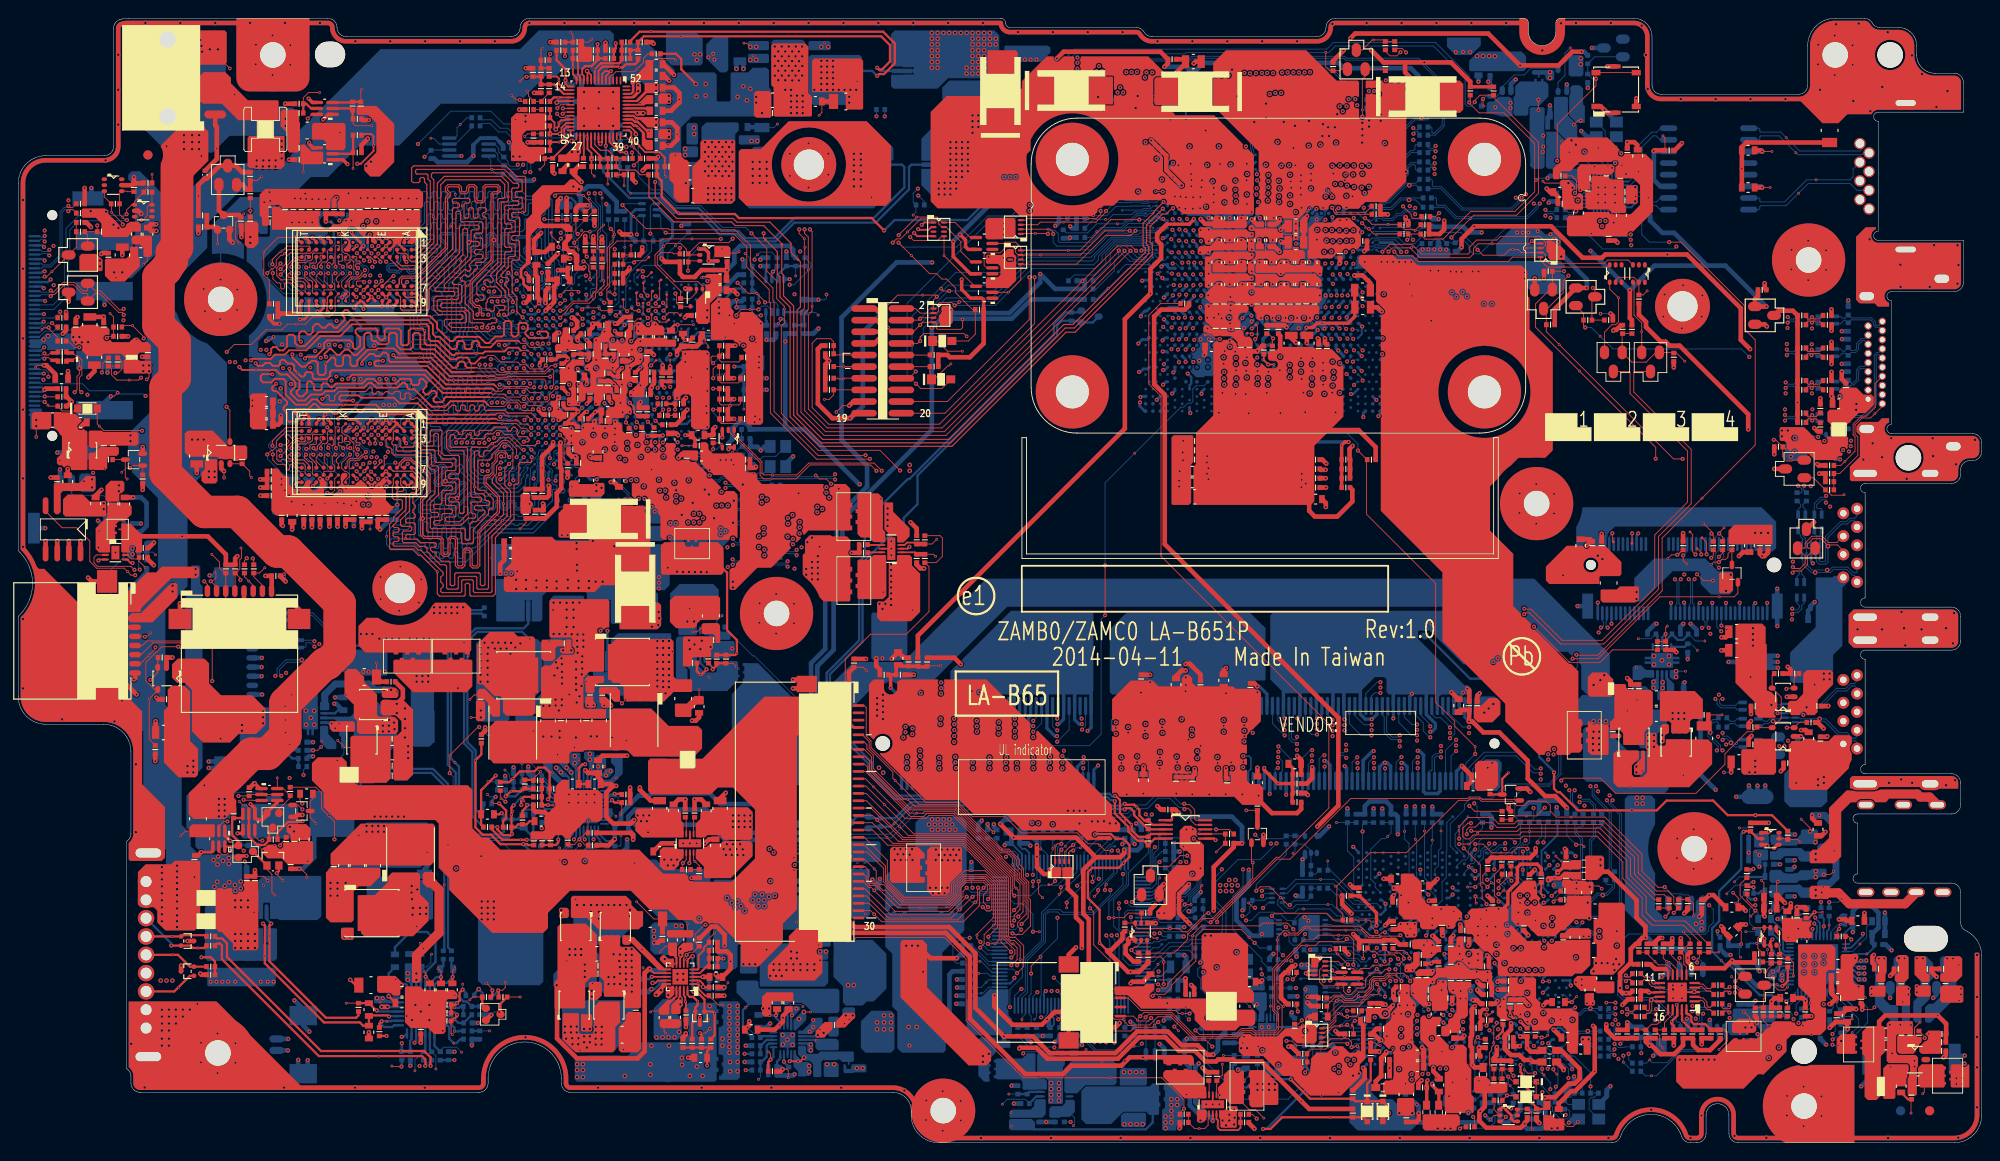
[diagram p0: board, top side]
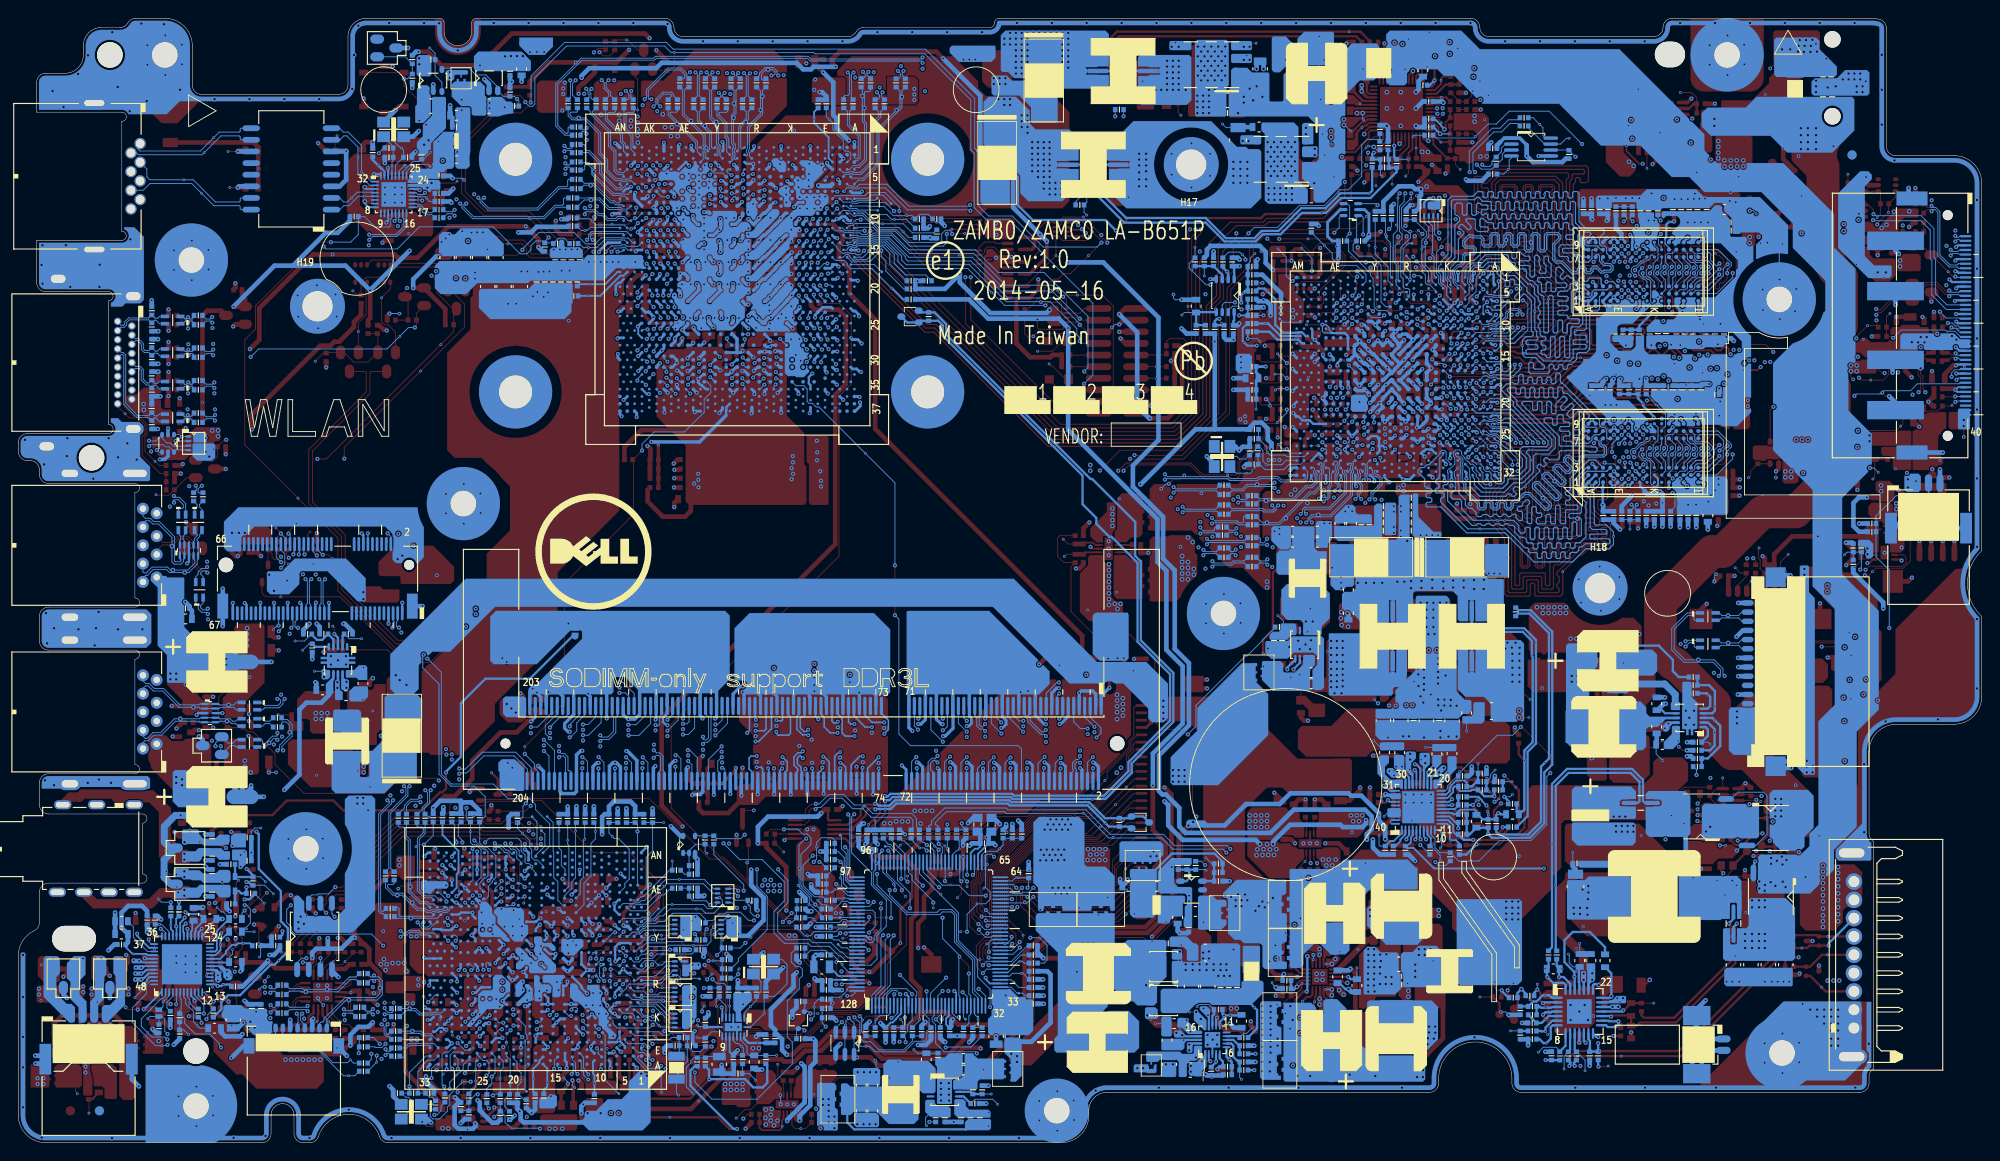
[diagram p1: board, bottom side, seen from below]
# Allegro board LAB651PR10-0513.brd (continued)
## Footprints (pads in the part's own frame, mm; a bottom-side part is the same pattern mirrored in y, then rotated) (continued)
ALLTO_C144LS-109A9-L_9P-T
  round 1.803 hole 1.194: 1(0,0) 2(2,0) 3(4,0) 4(6,0) 5(8,0) 6(10,0) 7(12,0) 8(14,0) 9(16,0)
  oval 1.6x3.404 hole 0.991x2.794: 10(19.125,0.25) 11(-3.125,0.25)
AO4407AL_SO8
  oval 0.635x1.854 smd: 1(0,0) 2(1.27,0) 3(2.54,0) 4(3.81,0) 5(3.81,5.165) 6(2.54,5.165) 7(1.27,5.165) 8(0,5.165)
AOZ1336_DFN8_2X2
  oval 0.254x0.787 smd: 1(0,0) 2(0.5,0) 3(1,0) 4(1.5,0) 5(1.5,2.2) 6(1,2.2) 7(0.5,2.2) 8(0,2.2)
  rect 1.499x0.889 smd: 9(0.75,1.1)
APL3512ABI-TRG_SOT23-5
  oval 0.61x1.041 smd: 1(0,0) 2(0.95,0) 3(1.9,0) 4(1.9,2.7) 5(0,2.7)
AZ5125-02SPR7G_SOT23-3
  oval 1.016x1.524 smd: 1(0,0) 2(0.965,2.083) 3(-0.965,2.083)
BAT54C-7-F_SOT23-3
  oval 1.016x1.524 smd: 1(0,0) 2(0.965,2.083) 3(-0.965,2.083)
BELLW_80001-1021_204P
  round 1.092 hole 1.092 unplated: (-65.05,-4.1)
  round 1.6 hole 1.6 unplated: (1.75,-4.1)
  oval 0.356x2.007 smd: 1(0,0) 2(-0.3,-8.2) 3(-0.6,0) 4(-0.9,-8.2) 5(-1.2,0) 6(-1.5,-8.2) 7(-1.8,0) 8(-2.1,-8.2) 9(-2.4,0) 10(-2.7,-8.2) 11(-3,0) 12(-3.3,-8.2) 13(-3.6,0) 14(-3.9,-8.2) 15(-4.2,0) 16(-4.5,-8.2) 17(-4.8,0) 18(-5.1,-8.2) 19(-5.4,0) 20(-5.7,-8.2) 21(-6,0) 22(-6.3,-8.2) 23(-6.6,0) 24(-6.9,-8.2) 25(-7.2,0) 26(-7.5,-8.2) 27(-7.8,0) 28(-8.1,-8.2) 29(-8.4,0) 30(-8.7,-8.2) 31(-9,0) 32(-9.3,-8.2) 33(-9.6,0) 34(-9.9,-8.2) 35(-10.2,0) 36(-10.5,-8.2) 37(-10.8,0) 38(-11.1,-8.2) 39(-11.4,0) 40(-11.7,-8.2) 41(-12,0) 42(-12.3,-8.2) 43(-12.6,0) 44(-12.9,-8.2) 45(-13.2,0) 46(-13.5,-8.2) 47(-13.8,0) 48(-14.1,-8.2) 49(-14.4,0) 50(-14.7,-8.2) 51(-15,0) 52(-15.3,-8.2) 53(-15.6,0) 54(-15.9,-8.2) 55(-16.2,0) 56(-16.5,-8.2) 57(-16.8,0) 58(-17.1,-8.2) 59(-17.4,0) 60(-17.7,-8.2) 61(-18,0) 62(-18.3,-8.2) 63(-18.6,0) 64(-18.9,-8.2) 65(-19.2,0) 66(-19.5,-8.2) 67(-19.8,0) 68(-20.1,-8.2) 69(-20.4,0) 70(-20.7,-8.2) 71(-21,0) 72(-21.3,-8.2) 73(-24,0) 74(-24.3,-8.2) 75(-24.6,0) 76(-24.9,-8.2) 77(-25.2,0) 78(-25.5,-8.2) 79(-25.8,0) 80(-26.1,-8.2) 81(-26.4,0) 82(-26.7,-8.2) 83(-27,0) 84(-27.3,-8.2) 85(-27.6,0) 86(-27.9,-8.2) 87(-28.2,0) 88(-28.5,-8.2) 89(-28.8,0) 90(-29.1,-8.2) 91(-29.4,0) 92(-29.7,-8.2) 93(-30,0) 94(-30.3,-8.2) 95(-30.6,0) 96(-30.9,-8.2) 97(-31.2,0) 98(-31.5,-8.2) 99(-31.8,0) 100(-32.1,-8.2) 101(-32.4,0) 102(-32.7,-8.2) 103(-33,0) 104(-33.3,-8.2) 105(-33.6,0) 106(-33.9,-8.2) 107(-34.2,0) 108(-34.5,-8.2) 109(-34.8,0) 110(-35.1,-8.2) 111(-35.4,0) 112(-35.7,-8.2) 113(-36,0) 114(-36.3,-8.2) 115(-36.6,0) 116(-36.9,-8.2) 117(-37.2,0) 118(-37.5,-8.2) 119(-37.8,0) 120(-38.1,-8.2) 121(-38.4,0) 122(-38.7,-8.2) 123(-39,0) 124(-39.3,-8.2) 125(-39.6,0) 126(-39.9,-8.2) 127(-40.2,0) 128(-40.5,-8.2) 129(-40.8,0) 130(-41.1,-8.2) 131(-41.4,0) 132(-41.7,-8.2) 133(-42,0) 134(-42.3,-8.2) 135(-42.6,0) 136(-42.9,-8.2) 137(-43.2,0) 138(-43.5,-8.2) 139(-43.8,0) 140(-44.1,-8.2) 141(-44.4,0) 142(-44.7,-8.2) 143(-45,0) 144(-45.3,-8.2) 145(-45.6,0) 146(-45.9,-8.2) 147(-46.2,0) 148(-46.5,-8.2) 149(-46.8,0) 150(-47.1,-8.2) 151(-47.4,0) 152(-47.7,-8.2) 153(-48,0) 154(-48.3,-8.2) 155(-48.6,0) 156(-48.9,-8.2) 157(-49.2,0) 158(-49.5,-8.2) 159(-49.8,0) 160(-50.1,-8.2) 161(-50.4,0) 162(-50.7,-8.2) 163(-51,0) 164(-51.3,-8.2) 165(-51.6,0) 166(-51.9,-8.2) 167(-52.2,0) 168(-52.5,-8.2) 169(-52.8,0) 170(-53.1,-8.2) 171(-53.4,0) 172(-53.7,-8.2) 173(-54,0) 174(-54.3,-8.2) 175(-54.6,0) 176(-54.9,-8.2) 177(-55.2,0) 178(-55.5,-8.2) 179(-55.8,0) 180(-56.1,-8.2) 181(-56.4,0) 182(-56.7,-8.2) 183(-57,0) 184(-57.3,-8.2) 185(-57.6,0) 186(-57.9,-8.2) 187(-58.2,0) 188(-58.5,-8.2) 189(-58.8,0) 190(-59.1,-8.2) 191(-59.4,0) 192(-59.7,-8.2) 193(-60,0) 194(-60.3,-8.2) 195(-60.6,0) 196(-60.9,-8.2) 197(-61.2,0) 198(-61.5,-8.2) 199(-61.8,0) 200(-62.1,-8.2) 201(-62.4,0) 202(-62.7,-8.2) 203(-63,0) 204(-63.3,-8.2)
  rect 3.505x4.597 smd: 205(1.15,7.9) 206(-64.45,7.9)
BQ24745RHDR_QFN28_5X5
  oval 0.254x1.194 smd: 1(0,0) 2(0.5,0) 3(1,0) 4(1.5,0) 5(2.001,0) 6(2.501,0) 7(3.001,0) 15(3.001,4.8) 16(2.501,4.8) 17(2.001,4.8) 18(1.5,4.8) 19(1,4.8) 20(0.5,4.8) 21(0,4.8)
  oval 1.194x0.254 smd: 8(3.9,0.9) 9(3.9,1.4) 10(3.9,1.9) 11(3.9,2.4) 12(3.9,2.9) 13(3.9,3.4) 14(3.9,3.9) 22(-0.9,3.9) 23(-0.9,3.4) 24(-0.9,2.9) 25(-0.9,2.4) 26(-0.9,1.9) 27(-0.9,1.4) 28(-0.9,0.9)
  rect 2.692x2.692 smd: 29(1.5,2.4)
BSH111_SOT23-3
  oval 1.016x1.524 smd: 1(0,0) 2(0.965,2.083) 3(-0.965,2.083)
C_0402
  rect 0.508x0.559 smd: 1(0,0) 2(0.914,0)
C_0603
  rect 0.635x0.889 smd: 1(0,0) 2(1.397,0)
C_0805
  rect 0.813x1.397 smd: 1(0,0) 2(1.702,0)
C_1206
  rect 1.016x1.651 smd: 1(0,0) 2(2.667,0)
C_D2
  rect 2.388x2.794 smd: 1(0,0) 2(6.4,0)
C_D3
  rect 2.388x2.794 smd: 1(0,0) 2(6.4,0)
C_ECST250ADA101MF611
  oval 3.505x1.6 smd: 1(0,0) 2(-5.4,0)
C_MP6VLPS220MC4R2
  oval 3.505x1.6 smd: 1(0,0) 2(-5.6,0)
C_MP6VU330MC6
  oval 3.505x1.6 smd: 1(0,0) 2(5.6,0)
CHENG_MBK1608221YZF_2P
  rect 0.991x0.787 smd: 1(0,0) 2(1.6,0)
CONCR_099ATAC19NBLCNF_19P
  round 0.813 hole 0.559: 1(0,0) 2(0.5,1.55) 3(1,0) 4(1.5,1.55) 5(2,0) 6(2.5,1.55) 7(3,0) 8(3.5,1.55) 9(4,0) 10(4.5,1.55) 11(5,0) 12(5.5,1.55) 13(6,0) 14(6.5,1.55) 15(7,0) 16(7.5,1.55) 17(8,0) 18(8.5,1.55) 19(9,0)
  oval 1.499x2.21 hole 0.889x1.6: 20(-2.75,1.7) 21(-4.65,-6.5) 22(11.75,1.7) 23(13.65,-7.75)
CSD86350Q5D_SON8
  oval 2.032x0.889 smd: 1(0,0)
  oval 0.711x0.889 smd: 2(1.98,0) 3(3.3,0) 4(3.3,5.39) 5(1.98,5.39) 6(0.66,5.39) 7(-0.66,5.39)
  custom 0.883x0.883 smd: 8(1.32,2.695)
CYNTE_PCMB104T-100MS_2P
  rect 4.089x4.089 smd: 1(0,0) 2(9.5,0)
CYNTE_PCMC042T-R47MN_2P
  rect 1.499x2.489 smd: 1(0,0) 2(3.7,0)
DB2J31400L_SOD323-2
  rect 0.991x1.092 smd: 1(0,0)
  rect 0.991x0.889 smd: 2(2.1,0)
DMN66D0LDW-7_SOT363-6
  oval 0.432x0.61 smd: 1(0,0) 2(0.65,0) 3(1.3,0) 4(1.3,1.9) 5(0.65,1.9) 6(0,1.9)
DTA144EUA_SC70-3
  rect 0.813x0.914 smd: 1(0,0) 2(0.65,1.6) 3(-0.65,1.6)
DTC115EUA_SC70-3
  oval 0.813x0.914 smd: 1(0,0) 2(0.65,1.6) 3(-0.65,1.6)
E-T_4260K-F10N-00L_10P
  oval 0.508x0.991 smd: 1(0,0) 2(-0.8,0) 3(-1.6,0) 4(-2.4,0) 5(-3.2,0) 6(-4,0) 7(-4.8,0) 8(-5.6,0) 9(-6.4,0) 10(-7.2,0)
  rect 1.194x1.702 smd: 11(1.3,-1.95) 12(-8.5,-1.95)
EMC1403-2-AIZL-TR_MSOP10
  oval 0.254x1.626 smd: 1(0,0) 2(0.5,0) 3(1,0) 4(1.5,0) 5(2,0) 6(2,4.3) 7(1.5,4.3) 8(1,4.3) 9(0.5,4.3) 10(0,4.3)
F_1206L150PR
  rect 0.991x1.803 smd: 1(0,0) 2(2.8,0)
F_1812L075-24DR
  rect 0.889x3.15 smd: 1(0,0) 2(4.35,0)
FDV301N_NL_SOT23-3
  oval 1.016x1.524 smd: 1(0,0) 2(0.965,2.083) 3(-0.965,2.083)
FIDUCIAL_C40M80
  round 1.016 smd: 1(0,0)
G993P1UF_SOP8
  oval 0.635x1.854 smd: 1(0,0) 2(1.27,0) 3(2.54,0) 4(3.81,0) 5(3.81,5.165) 6(2.54,5.165) 7(1.27,5.165) 8(0,5.165)
H_2P8
  round 3.302 hole 2.794: 1(0,0)
H_2P8N
  round 2.794 hole 2.794 unplated: (0,0)
H_2P8X3P3N
  oval 2.794x3.302 hole 2.794x3.302 unplated: (0,0)
H_2P8X4P8N
  oval 2.794x4.801 hole 2.794x4.801 unplated: (0,0)
H_3P3
  round 3.81 hole 3.302: 1(0,0)
H_3P6
  round 4.115 hole 3.607: 1(0,0)
HB_A823020-SBHR21_30P
  oval 0.305x1.295 smd: 1(0,0) 2(0.8,0) 3(1.6,0) 4(2.4,0) 5(3.2,0) 6(4,0) 7(4.8,0) 8(5.6,0) 9(6.4,0) 10(7.2,0) 11(8,0) 12(8.8,0) 13(9.6,0) 14(10.4,0) 15(11.2,0) 16(12,0) 17(12.8,0) 18(13.6,0) 19(14.4,0) 20(15.2,0) 21(16,0) 22(16.8,0) 23(17.6,0) 24(18.4,0) 25(19.2,0) 26(20,0) 27(20.8,0) 28(21.6,0) 29(22.4,0) 30(23.2,0)
  rect 1.803x2.21 smd: 31(25.55,-5.65) 32(-2.35,-5.65)
IP4292CZ10-TBR_XSON10_2P5X1
  oval 0.254x0.889 smd: 1(0,0)
  oval 0.254x0.838 smd: 2(0.5,-0.025) 3(1,-0.025) 4(1.5,-0.025) 5(2,-0.025) 6(2,1.125) 7(1.5,1.125) 8(1,1.125) 9(0.5,1.125) 10(0,1.125)
ISL62771HRTZ-T_TQFN40_5X5
  oval 0.203x1.016 smd: 1(0,0) 2(0.4,0) 3(0.8,0) 4(1.2,0) 5(1.6,0) 6(2,0) 7(2.4,0) 8(2.8,0) 9(3.2,0) 10(3.6,0) 21(3.6,4.975) 22(3.2,4.975) 23(2.8,4.975) 24(2.4,4.975) 25(2,4.975) 26(1.6,4.975) 27(1.2,4.975) 28(0.8,4.975) 29(0.4,4.975) 30(0,4.975)
  oval 1.016x0.203 smd: 11(4.288,0.688) 12(4.288,1.088) 13(4.288,1.488) 14(4.288,1.888) 15(4.288,2.288) 16(4.288,2.688) 17(4.288,3.088) 18(4.288,3.488) 19(4.288,3.888) 20(4.288,4.288) 31(-0.688,4.288) 32(-0.688,3.888) 33(-0.688,3.488) 34(-0.688,3.088) 35(-0.688,2.688) 36(-0.688,2.288) 37(-0.688,1.888) 38(-0.688,1.488) 39(-0.688,1.088) 40(-0.688,0.688)
  rect 3.505x3.505 smd: 41(1.8,2.488)
J-L_TNBNRAC80015008_8P
  round 1.245 hole 0.94: 1(0,0) 2(1.02,-1) 3(2.04,0) 4(3.06,-1) 5(4.08,0) 6(5.1,-1) 7(6.12,0) 8(7.14,-1)
  oval 1.372x2.972 hole 0.61x2.21: 9(-4.43,-5) 10(11.57,-5)
JUMP_43X39
  custom 0.191x0.191 smd: 1(0,0) 2(0.914,0)
JUMP_43X79
  custom 0.188x0.188 smd: 1(0,0) 2(1.1,0)
JUMP_43X118
  custom 0.187x0.187 smd: 1(0,0) 2(1.1,0)
K4W1G1646E-HC12_FBGA_96P-A39
  round 0.445 smd: A1(0,0) A2(0.8,0) A3(1.6,0) A7(4.801,0) A8(5.601,0) A9(6.401,0) B1(0,-0.8) B2(0.8,-0.8) B3(1.6,-0.8) B7(4.801,-0.8) B8(5.601,-0.8) B9(6.401,-0.8) C1(0,-1.6) C2(0.8,-1.6) C3(1.6,-1.6) C7(4.801,-1.6) C8(5.601,-1.6) C9(6.401,-1.6) D1(0,-2.4) D2(0.8,-2.4) D3(1.6,-2.4) D7(4.801,-2.4) D8(5.601,-2.4) D9(6.401,-2.4) E1(0,-3.2) E2(0.8,-3.2) E3(1.6,-3.2) E7(4.801,-3.2) E8(5.601,-3.2) E9(6.401,-3.2) M1(0,-8.801) M2(0.8,-8.801) M3(1.6,-8.801) M7(4.801,-8.801) M8(5.601,-8.801) M9(6.401,-8.801) N1(0,-9.601) N2(0.8,-9.601) N3(1.6,-9.601) N7(4.801,-9.601) N8(5.601,-9.601) N9(6.401,-9.601) P1(0,-10.401) P2(0.8,-10.401) P3(1.6,-10.401) P7(4.801,-10.401) P8(5.601,-10.401) P9(6.401,-10.401) R1(0,-11.201) R2(0.8,-11.201) R3(1.6,-11.201) R7(4.801,-11.201) R8(5.601,-11.201) R9(6.401,-11.201) T1(0,-12.002) T2(0.8,-12.002) T3(1.6,-12.002) T7(4.801,-12.002) T8(5.601,-12.002) T9(6.401,-12.002)
  round 0.343 smd: F1(0,-4) F2(0.8,-4) F3(1.6,-4) F7(4.801,-4) F8(5.601,-4) F9(6.401,-4) G1(0,-4.801) G2(0.8,-4.801) G3(1.6,-4.801) G7(4.801,-4.801) G8(5.601,-4.801) G9(6.401,-4.801) H1(0,-5.601) H2(0.8,-5.601) H3(1.6,-5.601) H7(4.801,-5.601) H8(5.601,-5.601) H9(6.401,-5.601) J1(0,-6.401) J2(0.8,-6.401) J3(1.6,-6.401) J7(4.801,-6.401) J8(5.601,-6.401) J9(6.401,-6.401) K1(0,-7.201) K2(0.8,-7.201) K3(1.6,-7.201) K7(4.801,-7.201) K8(5.601,-7.201) K9(6.401,-7.201) L1(0,-8.001) L2(0.8,-8.001) L3(1.6,-8.001) L7(4.801,-8.001) L8(5.601,-8.001) L9(6.401,-8.001)
KAVERI-FP3-2P7G_BGA_854P
  round 0.406 smd: A1(0,0) A2(0.8,0) A3(1.6,0) A35(27.2,0) A36(28,0) A37(28.8,0) AA10(7.2,-15.8) AA11(8.4,-15.8) AA13(9.6,-15.8) AA14(10.8,-15.8) AA16(12,-15.8) AA17(13.2,-15.8) AA19(14.4,-15.8) AA21(15.6,-15.8) AA22(16.8,-15.8) AA24(18,-15.8) AA25(19.2,-15.8) AA27(20.4,-15.8) AA28(21.6,-15.8) AB5(3.2,-16.4) AB6(4,-16.4) AB7(4.8,-16.4) AB8(5.6,-16.4) AB9(6.4,-16.4) AB29(22.4,-16.4) AB30(23.2,-16.4) AB31(24,-16.4) AB32(24.8,-16.4) AB33(25.6,-16.4) AC5(3.2,-17.6) AC6(4,-17.6) AC7(4.8,-17.6) AC8(5.6,-17.6) AC9(6.4,-17.6) AC10(7.2,-17) AC11(8.4,-17) AC13(9.6,-17) AC14(10.8,-17) AC16(12,-17) AC17(13.2,-17) AC19(14.4,-17) AC21(15.6,-17) AC22(16.8,-17) AC24(18,-17) AC25(19.2,-17) AC27(20.4,-17) AC28(21.6,-17) AC29(22.4,-17.6) AC30(23.2,-17.6) AC31(24,-17.6) AC32(24.8,-17.6) AC33(25.6,-17.6) AD10(7.2,-18.2) AD11(8.4,-18.2) AD13(9.6,-18.2) AD14(10.8,-18.2) AD16(12,-18.2) AD17(13.2,-18.2) AD19(14.4,-18.2) AD21(15.6,-18.2) AD22(16.8,-18.2) AD24(18,-18.2) AD25(19.2,-18.2) AD27(20.4,-18.2) AD28(21.6,-18.2) AE5(3.2,-18.8) AE6(4,-18.8) AE7(4.8,-18.8) AE8(5.6,-18.8) AE10(7.2,-19.2) AE11(8.4,-19.2) AE13(9.6,-19.2) AE14(10.8,-19.2) AE16(12,-19.2) AE17(13.2,-19.2) AE19(14.4,-19.2) AE21(15.6,-19.2) AE22(16.8,-19.2) AE24(18,-19.2) AE25(19.2,-19.2) AE27(20.4,-19.2) AE28(21.6,-19.2) AE30(23.2,-18.8) AE31(24,-18.8) AE32(24.8,-18.8) AE33(25.6,-18.8) AF5(3.2,-20) AF6(4,-20) AF7(4.8,-20) AF8(6,-20) AF10(7.2,-20) AF11(8.4,-20) AF13(9.6,-20) AF14(10.8,-20) AF16(12,-20) AF17(13.2,-20) AF19(14.4,-20) AF21(15.6,-20) AF22(16.8,-20) AF24(18,-20) AF25(19.2,-20) AF27(20.4,-20) AF28(21.6,-20) AF30(22.8,-20) AF31(24,-20) AF32(24.8,-20) AF33(25.6,-20) AG7(4.8,-20.8) AG8(6,-20.8) AG10(7.2,-20.8) AG11(8.4,-20.8) AG13(9.6,-20.8) AG14(10.8,-20.8) AG16(12,-20.8) AG17(13.2,-20.8) AG19(14.4,-20.8) AG21(15.6,-20.8) AG22(16.8,-20.8) AG24(18,-20.8) AG25(19.2,-20.8) AG27(20.4,-20.8) AG28(21.6,-20.8) AG30(22.8,-20.8) AG31(24,-20.8) AH5(3.2,-21.2) AH7(4.8,-21.6) AH8(6,-21.6) AH10(7.2,-21.6) AH11(8.4,-21.6) AH13(9.6,-21.6) AH14(10.8,-21.6) AH16(12,-21.6) AH17(13.2,-21.6) AH19(14.4,-21.6) AH21(15.6,-21.6) AH22(16.8,-21.6) AH24(18,-21.6) AH25(19.2,-21.6) AH27(20.4,-21.6) AH28(21.6,-21.6) AH30(22.8,-21.6) AH31(24,-21.6) AH33(25.6,-21.2) AJ5(3.6,-22.4) AJ7(4.8,-22.4) AJ8(6,-22.4) AJ10(7.2,-22.4) AJ11(8.4,-22.4) AJ13(9.6,-22.4) AJ14(10.8,-22.4) AJ16(12,-22.4) AJ17(13.2,-22.4) AJ19(14.4,-22.4) AJ21(15.6,-22.4) AJ22(16.8,-22.4) AJ24(18,-22.4) AJ25(19.2,-22.4) AJ27(20.4,-22.4) AJ28(21.6,-22.4) AJ30(22.8,-22.4) AJ31(24,-22.4) AJ33(25.2,-22.4) AL1(0,-24) AL37(28.8,-24) AM1(0,-24.8) AM2(0.8,-24.8) AM36(28,-24.8) AM37(28.8,-24.8) AN1(0,-25.6) AN2(0.8,-25.6) AN3(1.6,-25.6) AN35(27.2,-25.6) AN36(28,-25.6) AN37(28.8,-25.6) B1(0,-0.8) B2(0.8,-0.8) B36(28,-0.8) B37(28.8,-0.8) C1(0,-1.6) C37(28.8,-1.6) E5(3.6,-3.2) E7(4.8,-3.2) E8(6,-3.2) E10(7.2,-3.2) E11(8.4,-3.2) E13(9.6,-3.2) E14(10.8,-3.2) E16(12,-3.2) E17(13.2,-3.2) E19(14.4,-3.2) E21(15.6,-3.2) E22(16.8,-3.2) E24(18,-3.2) E25(19.2,-3.2) E27(20.4,-3.2) E28(21.6,-3.2) E30(22.8,-3.2) E31(24,-3.2) E33(25.2,-3.2) F5(3.2,-4.4) F7(4.8,-4) F8(6,-4) F10(7.2,-4) F11(8.4,-4) F13(9.6,-4) F14(10.8,-4) F16(12,-4) F17(13.2,-4) F19(14.4,-4) F21(15.6,-4) F22(16.8,-4) F24(18,-4) F25(19.2,-4) F27(20.4,-4) F28(21.6,-4) F30(22.8,-4) F31(24,-4) F33(25.6,-4.4) G7(4.8,-4.8) G8(6,-4.8) G10(7.2,-4.8) G11(8.4,-4.8) G13(9.6,-4.8) G14(10.8,-4.8) G16(12,-4.8) G17(13.2,-4.8) G19(14.4,-4.8) G21(15.6,-4.8) G22(16.8,-4.8) G24(18,-4.8) G25(19.2,-4.8) G27(20.4,-4.8) G28(21.6,-4.8) G30(22.8,-4.8) G31(24,-4.8) H5(3.2,-5.6) H6(4,-5.6) H7(4.8,-5.6) H8(6,-5.6) H10(7.2,-5.6) H11(8.4,-5.6) H13(9.6,-5.6) H14(10.8,-5.6) H16(12,-5.6) H17(13.2,-5.6) H19(14.4,-5.6) H21(15.6,-5.6) H22(16.8,-5.6) H24(18,-5.6) H25(19.2,-5.6) H27(20.4,-5.6) H28(21.6,-5.6) H30(22.8,-5.6) H31(24,-5.6) H32(24.8,-5.6) H33(25.6,-5.6) J5(3.2,-6.8) J6(4,-6.8) J7(4.8,-6.8) J8(5.6,-6.8) J10(7.2,-6.4) J11(8.4,-6.4) J13(9.6,-6.4) J14(10.8,-6.4) J16(12,-6.4) J17(13.2,-6.4) J19(14.4,-6.4) J21(15.6,-6.4) J22(16.8,-6.4) J24(18,-6.4) J25(19.2,-6.4) J27(20.4,-6.4) J28(21.6,-6.4) J30(23.2,-6.8) J31(24,-6.8) J32(24.8,-6.8) J33(25.6,-6.8) K10(7.2,-7.4) K11(8.4,-7.4) K13(9.6,-7.4) K14(10.8,-7.4) K16(12,-7.4) K17(13.2,-7.4) K19(14.4,-7.4) K21(15.6,-7.4) K22(16.8,-7.4) K24(18,-7.4) K25(19.2,-7.4) K27(20.4,-7.4) K28(21.6,-7.4) L5(3.2,-8) L6(4,-8) L7(4.8,-8) L8(5.6,-8) L9(6.4,-8) L10(7.2,-8.6) L11(8.4,-8.6) L13(9.6,-8.6) L14(10.8,-8.6) L16(12,-8.6) L17(13.2,-8.6) L19(14.4,-8.6) L21(15.6,-8.6) L22(16.8,-8.6) L24(18,-8.6) L25(19.2,-8.6) L27(20.4,-8.6) L28(21.6,-8.6) L29(22.4,-8) L30(23.2,-8) L31(24,-8) L32(24.8,-8) L33(25.6,-8) M5(3.2,-9.2) M6(4,-9.2) M7(4.8,-9.2) M8(5.6,-9.2) M9(6.4,-9.2) M29(22.4,-9.2) M30(23.2,-9.2) M31(24,-9.2) M32(24.8,-9.2) M33(25.6,-9.2) N10(7.2,-9.8) N11(8.4,-9.8) N13(9.6,-9.8) N14(10.8,-9.8) N16(12,-9.8) N17(13.2,-9.8) N19(14.4,-9.8) N21(15.6,-9.8) N22(16.8,-9.8) N24(18,-9.8) N25(19.2,-9.8) N27(20.4,-9.8) N28(21.6,-9.8) P5(3.2,-10.4) P6(4,-10.4) P7(4.8,-10.4) P8(5.6,-10.4) P9(6.4,-10.4) P10(7.2,-11) P11(8.4,-11) P13(9.6,-11) P14(10.8,-11) P16(12,-11) P17(13.2,-11) P19(14.4,-11) P21(15.6,-11) P22(16.8,-11) P24(18,-11) P25(19.2,-11) P27(20.4,-11) P28(21.6,-11) P29(22.4,-10.4) P30(23.2,-10.4) P31(24,-10.4) P32(24.8,-10.4) P33(25.6,-10.4) R5(3.2,-11.6) R6(4,-11.6) R7(4.8,-11.6) R8(5.6,-11.6) R9(6.4,-11.6) R29(22.4,-11.6) R30(23.2,-11.6) R31(24,-11.6) R32(24.8,-11.6) R33(25.6,-11.6) T10(7.2,-12.2) T11(8.4,-12.2) T13(9.6,-12.2) T14(10.8,-12.2) T16(12,-12.2) T17(13.2,-12.2) T19(14.4,-12.2) T21(15.6,-12.2) T22(16.8,-12.2) T24(18,-12.2) T25(19.2,-12.2) T27(20.4,-12.2) T28(21.6,-12.2) U5(3.2,-12.8) U6(4,-12.8) U7(4.8,-12.8) U8(5.6,-12.8) U9(6.4,-12.8) U29(22.4,-12.8) U30(23.2,-12.8) U31(24,-12.8) U32(24.8,-12.8) U33(25.6,-12.8) V10(7.2,-13.4) V11(8.4,-13.4) V13(9.6,-13.4) V14(10.8,-13.4) V16(12,-13.4) V17(13.2,-13.4) V19(14.4,-13.4) V21(15.6,-13.4) V22(16.8,-13.4) V24(18,-13.4) V25(19.2,-13.4) V27(20.4,-13.4) V28(21.6,-13.4) W5(3.2,-14) W6(4,-14) W7(4.8,-14) W8(5.6,-14) W9(6.4,-14) W29(22.4,-14) W30(23.2,-14) W31(24,-14) W32(24.8,-14) W33(25.6,-14) Y5(3.2,-15.2) Y6(4,-15.2) Y7(4.8,-15.2) Y8(5.6,-15.2) Y9(6.4,-15.2) Y10(7.2,-14.6) Y11(8.4,-14.6) Y13(9.6,-14.6) Y14(10.8,-14.6) Y16(12,-14.6) Y17(13.2,-14.6) Y19(14.4,-14.6) Y21(15.6,-14.6) Y22(16.8,-14.6) Y24(18,-14.6) Y25(19.2,-14.6) Y27(20.4,-14.6) Y28(21.6,-14.6) Y29(22.4,-15.2) Y30(23.2,-15.2) Y31(24,-15.2) Y32(24.8,-15.2) Y33(25.6,-15.2)
  round 0.305 smd: A4(2.4,0) A5(3.2,-0.4) A6(4,0) A7(4.8,-0.4) A8(5.6,0) A9(6.4,-0.4) A10(7.2,0) A11(8,-0.4) A12(8.8,0) A13(9.6,-0.4) A14(10.4,0) A15(11.2,-0.4) A16(12,0) A17(12.8,-0.4) A18(13.6,0) A19(14.4,-0.4) A20(15.2,0) A21(16,-0.4) A22(16.8,0) A23(17.6,-0.4) A24(18.4,0) A25(19.2,-0.4) A26(20,0) A27(20.8,-0.4) A28(21.6,0) A29(22.4,-0.4) A30(23.2,0) A31(24,-0.4) A32(24.8,0) A33(25.6,-0.4) A34(26.4,0) AA1(0.4,-16) AA2(1.2,-16) AA4(2.4,-16) AA34(26.4,-16) AA36(27.6,-16) AA37(28.4,-16) AB1(0,-16.8) AB2(0.8,-16.8) AB3(1.6,-16.8) AB4(2.4,-16.8) AB34(26.4,-16.8) AB35(27.2,-16.8) AB36(28,-16.8) AB37(28.8,-16.8) AC1(0.4,-17.6) AC2(1.2,-17.6) AC4(2.4,-17.6) AC34(26.4,-17.6) AC36(27.6,-17.6) AC37(28.4,-17.6) AD1(0,-18.4) AD2(0.8,-18.4) AD3(1.6,-18.4) AD4(2.4,-18.4) AD34(26.4,-18.4) AD35(27.2,-18.4) AD36(28,-18.4) AD37(28.8,-18.4) AE1(0.4,-19.2) AE2(1.2,-19.2) AE4(2.4,-19.2) AE34(26.4,-19.2) AE36(27.6,-19.2) AE37(28.4,-19.2) AF1(0,-20) AF2(0.8,-20) AF3(1.6,-20) AF4(2.4,-20) AF34(26.4,-20) AF35(27.2,-20) AF36(28,-20) AF37(28.8,-20) AG1(0.4,-20.8) AG2(1.2,-20.8) AG4(2.4,-20.8) AG34(26.4,-20.8) AG36(27.6,-20.8) AG37(28.4,-20.8) AH1(0,-21.6) AH2(0.8,-21.6) AH3(1.6,-21.6) AH4(2.4,-21.6) AH34(26.4,-21.6) AH35(27.2,-21.6) AH36(28,-21.6) AH37(28.8,-21.6) AJ1(0.4,-22.4) AJ2(1.2,-22.4) AJ4(2.4,-22.4) AJ34(26.4,-22.4) AJ36(27.6,-22.4) AJ37(28.4,-22.4) AK1(0,-23.2) AK2(0.8,-23.2) AK3(1.6,-23.2) AK4(2.4,-23.2) AK5(3.2,-23.2) AK6(4,-23.2) AK7(4.8,-23.2) AK8(5.6,-23.2) AK9(6.4,-23.2) AK10(7.2,-23.2) AK11(8,-23.2) AK12(8.8,-23.2) AK13(9.6,-23.2) AK14(10.4,-23.2) AK15(11.2,-23.2) AK16(12,-23.2) AK17(12.8,-23.2) AK18(13.6,-23.2) AK19(14.4,-23.2) AK20(15.2,-23.2) AK21(16,-23.2) AK22(16.8,-23.2) AK23(17.6,-23.2) AK24(18.4,-23.2) AK25(19.2,-23.2) AK26(20,-23.2) AK27(20.8,-23.2) AK28(21.6,-23.2) AK29(22.4,-23.2) AK30(23.2,-23.2) AK31(24,-23.2) AK32(24.8,-23.2) AK33(25.6,-23.2) AK34(26.4,-23.2) AK35(27.2,-23.2) AK36(28,-23.2) AK37(28.8,-23.2) AL2(0.8,-24) AL3(1.6,-24) AL4(2.4,-24) AL6(4,-24) AL8(5.6,-24) AL10(7.2,-24) AL12(8.8,-24) AL14(10.4,-24) AL16(12,-24) AL18(13.6,-24) AL20(15.2,-24) AL22(16.8,-24) AL24(18.4,-24) AL26(20,-24) AL28(21.6,-24) AL30(23.2,-24) AL32(24.8,-24) AL34(26.4,-24) AL35(27.2,-24) AL36(28,-24) AM3(1.6,-24.8) AM4(2.4,-24.8) AM5(3.2,-24.4) AM6(4,-24.8) AM7(4.8,-24.4) AM8(5.6,-24.8) AM9(6.4,-24.4) AM10(7.2,-24.8) AM11(8,-24.4) AM12(8.8,-24.8) AM13(9.6,-24.4) AM14(10.4,-24.8) AM15(11.2,-24.4) AM16(12,-24.8) AM17(12.8,-24.4) AM18(13.6,-24.8) AM19(14.4,-24.4) AM20(15.2,-24.8) AM21(16,-24.4) AM22(16.8,-24.8) AM23(17.6,-24.4) AM24(18.4,-24.8) AM25(19.2,-24.4) AM26(20,-24.8) AM27(20.8,-24.4) AM28(21.6,-24.8) AM29(22.4,-24.4) AM30(23.2,-24.8) AM31(24,-24.4) AM32(24.8,-24.8) AM33(25.6,-24.4) AM34(26.4,-24.8) AM35(27.2,-24.8) AN4(2.4,-25.6) AN5(3.2,-25.2) AN6(4,-25.6) AN7(4.8,-25.2) AN8(5.6,-25.6) AN9(6.4,-25.2) AN10(7.2,-25.6) AN11(8,-25.2) AN12(8.8,-25.6) AN13(9.6,-25.2) AN14(10.4,-25.6) AN15(11.2,-25.2) AN16(12,-25.6) AN17(12.8,-25.2) AN18(13.6,-25.6) AN19(14.4,-25.2) AN20(15.2,-25.6) AN21(16,-25.2) AN22(16.8,-25.6) AN23(17.6,-25.2) AN24(18.4,-25.6) AN25(19.2,-25.2) AN26(20,-25.6) AN27(20.8,-25.2) AN28(21.6,-25.6) AN29(22.4,-25.2) AN30(23.2,-25.6) AN31(24,-25.2) AN32(24.8,-25.6) AN33(25.6,-25.2) AN34(26.4,-25.6) B3(1.6,-0.8) B4(2.4,-0.8) B5(3.2,-1.2) B6(4,-0.8) B7(4.8,-1.2) B8(5.6,-0.8) B9(6.4,-1.2) B10(7.2,-0.8) B11(8,-1.2) B12(8.8,-0.8) B13(9.6,-1.2) B14(10.4,-0.8) B15(11.2,-1.2) B16(12,-0.8) B17(12.8,-1.2) B18(13.6,-0.8) B19(14.4,-1.2) B20(15.2,-0.8) B21(16,-1.2) B22(16.8,-0.8) B23(17.6,-1.2) B24(18.4,-0.8) B25(19.2,-1.2) B26(20,-0.8) B27(20.8,-1.2) B28(21.6,-0.8) B29(22.4,-1.2) B30(23.2,-0.8) B31(24,-1.2) B32(24.8,-0.8) B33(25.6,-1.2) B34(26.4,-0.8) B35(27.2,-0.8) C2(0.8,-1.6) C3(1.6,-1.6) C4(2.4,-1.6) C6(4,-1.6) C8(5.6,-1.6) C10(7.2,-1.6) C12(8.8,-1.6) C14(10.4,-1.6) C16(12,-1.6) C18(13.6,-1.6) C20(15.2,-1.6) C22(16.8,-1.6) C24(18.4,-1.6) C26(20,-1.6) C28(21.6,-1.6) C30(23.2,-1.6) C32(24.8,-1.6) C34(26.4,-1.6) C35(27.2,-1.6) C36(28,-1.6) D1(0,-2.4) D2(0.8,-2.4) D3(1.6,-2.4) D4(2.4,-2.4) D5(3.2,-2.4) D6(4,-2.4) D7(4.8,-2.4) D8(5.6,-2.4) D9(6.4,-2.4) D10(7.2,-2.4) D11(8,-2.4) D12(8.8,-2.4) D13(9.6,-2.4) D14(10.4,-2.4) D15(11.2,-2.4) D16(12,-2.4) D17(12.8,-2.4) D18(13.6,-2.4) D19(14.4,-2.4) D20(15.2,-2.4) D21(16,-2.4) D22(16.8,-2.4) D23(17.6,-2.4) D24(18.4,-2.4) D25(19.2,-2.4) D26(20,-2.4) D27(20.8,-2.4) D28(21.6,-2.4) D29(22.4,-2.4) D30(23.2,-2.4) D31(24,-2.4) D32(24.8,-2.4) D33(25.6,-2.4) D34(26.4,-2.4) D35(27.2,-2.4) D36(28,-2.4) D37(28.8,-2.4) E1(0.4,-3.2) E2(1.2,-3.2) E4(2.4,-3.2) E34(26.4,-3.2) E36(27.6,-3.2) E37(28.4,-3.2) F1(0,-4) F2(0.8,-4) F3(1.6,-4) F4(2.4,-4) F34(26.4,-4) F35(27.2,-4) F36(28,-4) F37(28.8,-4) G1(0.4,-4.8) G2(1.2,-4.8) G4(2.4,-4.8) G34(26.4,-4.8) G36(27.6,-4.8) G37(28.4,-4.8) H1(0,-5.6) H2(0.8,-5.6) H3(1.6,-5.6) H4(2.4,-5.6) H34(26.4,-5.6) H35(27.2,-5.6) H36(28,-5.6) H37(28.8,-5.6) J1(0.4,-6.4) J2(1.2,-6.4) J4(2.4,-6.4) J34(26.4,-6.4) J36(27.6,-6.4) J37(28.4,-6.4) K1(0,-7.2) K2(0.8,-7.2) K3(1.6,-7.2) K4(2.4,-7.2) K34(26.4,-7.2) K35(27.2,-7.2) K36(28,-7.2) K37(28.8,-7.2) L1(0.4,-8) L2(1.2,-8) L4(2.4,-8) L34(26.4,-8) L36(27.6,-8) L37(28.4,-8) M1(0,-8.8) M2(0.8,-8.8) M3(1.6,-8.8) M4(2.4,-8.8) M34(26.4,-8.8) M35(27.2,-8.8) M36(28,-8.8) M37(28.8,-8.8) N1(0.4,-9.6) N2(1.2,-9.6) N4(2.4,-9.6) N34(26.4,-9.6) N36(27.6,-9.6) N37(28.4,-9.6) P1(0,-10.4) P2(0.8,-10.4) P3(1.6,-10.4) P4(2.4,-10.4) P34(26.4,-10.4) P35(27.2,-10.4) P36(28,-10.4) P37(28.8,-10.4) R1(0.4,-11.2) R2(1.2,-11.2) R4(2.4,-11.2) R34(26.4,-11.2) R36(27.6,-11.2) R37(28.4,-11.2) T1(0,-12) T2(0.8,-12) T3(1.6,-12) T4(2.4,-12) T34(26.4,-12) T35(27.2,-12) T36(28,-12) T37(28.8,-12) U1(0.4,-12.8) U2(1.2,-12.8) U4(2.4,-12.8) U34(26.4,-12.8) U36(27.6,-12.8) U37(28.4,-12.8) V1(0,-13.6) V2(0.8,-13.6) V3(1.6,-13.6) V4(2.4,-13.6) V34(26.4,-13.6) V35(27.2,-13.6) V36(28,-13.6) V37(28.8,-13.6) W1(0.4,-14.4) W2(1.2,-14.4) W4(2.4,-14.4) W34(26.4,-14.4) W36(27.6,-14.4) W37(28.4,-14.4) Y1(0,-15.2) Y2(0.8,-15.2) Y3(1.6,-15.2) Y4(2.4,-15.2) Y34(26.4,-15.2) Y35(27.2,-15.2) Y36(28,-15.2) Y37(28.8,-15.2)
KB9012QF-A2_LQFP128_14X14
  oval 0.203x1.753 smd: 1(0,0) 2(0.4,0) 3(0.8,0) 4(1.2,0) 5(1.6,0) 6(2,0) 7(2.4,0) 8(2.8,0) 9(3.2,0) 10(3.6,0) 11(4,0) 12(4.4,0) 13(4.8,0) 14(5.2,0) 15(5.6,0) 16(6,0) 17(6.4,0) 18(6.8,0) 19(7.2,0) 20(7.6,0) 21(8,0) 22(8.4,0) 23(8.8,0) 24(9.2,0) 25(9.6,0) 26(10,0) 27(10.4,0) 28(10.8,0) 29(11.2,0) 30(11.6,0) 31(12,0) 32(12.4,0) 65(12.4,15.654) 66(12,15.654) 67(11.6,15.654) 68(11.2,15.654) 69(10.8,15.654) 70(10.4,15.654) 71(10,15.654) 72(9.6,15.654) 73(9.2,15.654) 74(8.8,15.654) 75(8.4,15.654) 76(8,15.654) 77(7.6,15.654) 78(7.2,15.654) 79(6.8,15.654) 80(6.4,15.654) 81(6,15.654) 82(5.6,15.654) 83(5.2,15.654) 84(4.8,15.654) 85(4.4,15.654) 86(4,15.654) 87(3.6,15.654) 88(3.2,15.654) 89(2.8,15.654) 90(2.4,15.654) 91(2,15.654) 92(1.6,15.654) 93(1.2,15.654) 94(0.8,15.654) 95(0.4,15.654) 96(0,15.654)
  oval 1.753x0.203 smd: 33(14.027,1.627) 34(14.027,2.027) 35(14.027,2.427) 36(14.027,2.827) 37(14.027,3.227) 38(14.027,3.627) 39(14.027,4.027) 40(14.027,4.427) 41(14.027,4.827) 42(14.027,5.227) 43(14.027,5.627) 44(14.027,6.027) 45(14.027,6.427) 46(14.027,6.827) 47(14.027,7.227) 48(14.027,7.627) 49(14.027,8.027) 50(14.027,8.427) 51(14.027,8.827) 52(14.027,9.227) 53(14.027,9.627) 54(14.027,10.027) 55(14.027,10.427) 56(14.027,10.827) 57(14.027,11.227) 58(14.027,11.627) 59(14.027,12.027) 60(14.027,12.427) 61(14.027,12.827) 62(14.027,13.227) 63(14.027,13.627) 64(14.027,14.027) 97(-1.627,14.027) 98(-1.627,13.627) 99(-1.627,13.227) 100(-1.627,12.827) 101(-1.627,12.427) 102(-1.627,12.027) 103(-1.627,11.627) 104(-1.627,11.227) 105(-1.627,10.827) 106(-1.627,10.427) 107(-1.627,10.027) 108(-1.627,9.627) 109(-1.627,9.227) 110(-1.627,8.827) 111(-1.627,8.427) 112(-1.627,8.027) 113(-1.627,7.627) 114(-1.627,7.227) 115(-1.627,6.827) 116(-1.627,6.427) 117(-1.627,6.027) 118(-1.627,5.627) 119(-1.627,5.227) 120(-1.627,4.827) 121(-1.627,4.427) 122(-1.627,4.027) 123(-1.627,3.627) 124(-1.627,3.227) 125(-1.627,2.827) 126(-1.627,2.427) 127(-1.627,2.027) 128(-1.627,1.627)
KC_FBMA-L11-160808-800LMT_2P
  rect 0.889x1.092 smd: 1(0,0) 2(1.5,0)
KC_FBMA-L11-201209-221LMA30_2P
  rect 0.838x1.397 smd: 1(0,0) 2(1.65,0)
KC_WCM-2012HS-900T_4P
  rect 0.889x0.406 smd: 1(0,0) 2(1.7,0) 3(1.7,-0.8) 4(0,-0.8)
L03ESDL5V0CC3-2_SOT23-3
  oval 1.016x1.524 smd: 1(0,0) 2(0.965,2.083) 3(-0.965,2.083)
L30ESDL5V0C3-2_SOT23-3
  oval 1.016x1.524 smd: 1(0,0) 2(0.965,2.083) 3(-0.965,2.083)
L_4X4X2_F_2P
  rect 1.194x3.708 smd: 1(0,0) 2(2.8,0)
L_5X5X3_M_2P
  rect 2.159x2.794 smd: 1(0,0) 2(4.35,0)
L_7X7X3_M_2P
  rect 2.362x3.505 smd: 1(0,0) 2(6.05,0)
L_1812-1806
  oval 1.016x3.708 smd: 1(0,0) 2(4.013,0)
LANKO_LF-H1201P-2_16P
  oval 0.635x1.905 smd: 1(0,0) 2(1.27,0) 3(2.54,0) 4(3.81,0) 5(5.08,0) 6(6.35,0) 7(7.62,0) 8(8.89,0) 9(8.89,8.763) 10(7.62,8.763) 11(6.35,8.763) 12(5.08,8.763) 13(3.81,8.763) 14(2.54,8.763) 15(1.27,8.763) 16(0,8.763)
LOTES_APCI0019-P009A_67P
  round 1.092 hole 1.092 unplated: (-0.75,-5.275)
  round 1.6 hole 1.6 unplated: (19.25,-5.275)
  oval 0.305x1.549 smd: 1(0,0) 2(0.25,-7.55) 3(0.5,0) 4(0.75,-7.55) 5(1,0) 6(1.25,-7.55) 7(1.5,0) 8(1.75,-7.55) 9(2,0) 10(2.25,-7.55) 11(2.5,0) 12(2.75,-7.55) 13(3,0) 14(3.25,-7.55) 15(3.5,0) 16(3.75,-7.55) 17(4,0) 18(4.25,-7.55) 19(4.5,0) 20(4.75,-7.55) 21(5,0) 22(5.25,-7.55) 23(5.5,0) 24(7.75,-7.55) 25(8,0) 26(8.25,-7.55) 27(8.5,0) 28(8.75,-7.55) 29(9,0) 30(9.25,-7.55) 31(9.5,0) 32(9.75,-7.55) 33(10,0) 34(10.25,-7.55) 35(10.5,0) 36(10.75,-7.55) 37(11,0) 38(11.25,-7.55) 39(11.5,0) 40(11.75,-7.55) 41(12,0) 42(12.25,-7.55) 43(12.5,0) 44(12.75,-7.55) 45(13,0) 46(13.25,-7.55) 47(13.5,0) 48(13.75,-7.55) 49(14,0) 50(14.25,-7.55) 51(14.5,0) 52(14.75,-7.55) 53(15,0) 54(15.25,-7.55) 55(15.5,0) 56(15.75,-7.55) 57(16,0) 58(16.25,-7.55) 59(16.5,0) 60(16.75,-7.55) 61(17,0) 62(17.25,-7.55) 63(17.5,0) 64(17.75,-7.55) 65(18,0) 66(18.25,-7.55) 67(18.5,0)
  rect 1.194x2.743 smd: 68(-1.1,-0.775) 69(19.6,-0.775)
MC74VHC1G08DFT2G_SC70-5
  oval 0.381x0.711 smd: 1(0,0) 2(0.65,0) 3(1.3,0) 4(1.3,1.9) 5(0,1.9)
MC74VHC1G09DFT2G_SC70-5
  oval 0.406x0.508 smd: 1(0,0) 2(0.65,0) 3(1.3,0) 4(1.3,1.9) 5(0,1.9)
MDU1516URH_POWERDFN56-8-5
  oval 0.61x1.27 smd: 1(0,0) 2(1.27,0) 3(2.54,0) 4(3.81,0)
  custom 1.105x1.105 smd: 5(1.905,3.715)
MMBT3904_NL_SOT23-3
  oval 1.016x1.524 smd: 1(0,0) 2(0.965,2.083) 3(-0.965,2.083)
MMBT3904_SOT23-3
  oval 1.016x1.524 smd: 1(0,0) 2(0.965,2.083) 3(-0.965,2.083)
MMST3904-7-F_SOT323-3
  oval 0.711x0.889 smd: 1(0,0) 2(0.65,1.9) 3(-0.65,1.9)
MURAT_BLM15AG102SN1D_2P
  rect 0.457x0.508 smd: 1(0,0) 2(0.85,0)
MURAT_BLM15BB221SN1D_2P
  rect 0.508x0.762 smd: 1(0,0) 2(0.75,0)
MURAT_BLM15BD601SN1D_2P
  rect 0.508x0.762 smd: 1(0,0) 2(0.75,0)
MURAT_BLM18AG601SN1D_L0603_2P
  rect 0.66x1.041 smd: 1(0,0) 2(1.2,0)
MURAT_DLW21SN670HQ2L_4P
  rect 0.889x0.406 smd: 1(0,0) 2(1.7,0) 3(1.7,0.8) 4(0,0.8)
MURAT_LQM2MPN2R2NG0L_2P
  rect 0.787x1.803 smd: 1(0,0) 2(1.6,0)
NC7SZ08P5X_NL_SC70-5
  oval 0.457x0.711 smd: 1(-0.65,-0.925) 2(0,-0.925) 3(0.65,-0.925) 4(0.65,0.925) 5(-0.65,0.925)
NCP6151S52MNR2G_QFN52_6X6
  oval 0.203x0.889 smd: 1(0,0) 2(0.4,0) 3(0.8,0) 4(1.2,0) 5(1.6,0) 6(2,0) 7(2.4,0) 8(2.8,0) 9(3.2,0) 10(3.6,0) 11(4,0) 12(4.4,0) 13(4.8,0) 27(4.8,6.102) 28(4.4,6.102) 29(4,6.102) 30(3.6,6.102) 31(3.2,6.102) 32(2.8,6.102) 33(2.4,6.102) 34(2,6.102) 35(1.6,6.102) 36(1.2,6.102) 37(0.8,6.102) 38(0.4,6.102) 39(0,6.102)
  oval 0.889x0.203 smd: 14(5.451,0.651) 15(5.451,1.051) 16(5.451,1.451) 17(5.451,1.851) 18(5.451,2.251) 19(5.451,2.651) 20(5.451,3.051) 21(5.451,3.451) 22(5.451,3.851) 23(5.451,4.251) 24(5.451,4.651) 25(5.451,5.051) 26(5.451,5.451) 40(-0.651,5.451) 41(-0.651,5.051) 42(-0.651,4.651) 43(-0.651,4.251) 44(-0.651,3.851) 45(-0.651,3.451) 46(-0.651,3.051) 47(-0.651,2.651) 48(-0.651,2.251) 49(-0.651,1.851) 50(-0.651,1.451) 51(-0.651,1.051) 52(-0.651,0.651)
  rect 4.699x4.699 smd: 53(2.4,3.051)
PANAS_ETQP4LR15AFM_4P
  custom 0.686x0.686 smd: 1(0,0) 4(8.357,0)
  rect 2.21x0.508 smd: 2(1.448,0) 3(6.909,0)
PESD5V0U2BT_SOT23-3
  oval 1.016x1.524 smd: 1(0,0) 2(0.965,2.083) 3(-0.965,2.083)
PS8520BTQFN20GTR2_TQFN20_4X4
  oval 0.254x1.194 smd: 1(0,0) 2(0.5,0) 3(1,0) 4(1.5,0) 5(2,0) 11(2,3.8) 12(1.5,3.8) 13(1,3.8) 14(0.5,3.8) 15(0,3.8)
  oval 1.194x0.254 smd: 6(2.9,0.9) 7(2.9,1.4) 8(2.9,1.9) 9(2.9,2.4) 10(2.9,2.9) 16(-0.9,2.9) 17(-0.9,2.4) 18(-0.9,1.9) 19(-0.9,1.4) 20(-0.9,0.9)
  rect 2.108x2.108 smd: 21(1,1.9)
R0402_0OHM
  rect 0.508x0.559 smd: 1(0,0) 2(0.914,0)
R0603_0OHM
  rect 0.635x0.889 smd: 1(0,0) 2(1.397,0)
R0805_0OHM
  rect 0.813x1.397 smd: 1(0,0) 2(1.702,0)
R1206_0OHM
  rect 1.016x1.651 smd: 1(0,0) 2(2.667,0)
R_0402
  rect 0.508x0.559 smd: 1(0,0) 2(0.914,0)
R_0603
  rect 0.635x0.889 smd: 1(0,0) 2(1.397,0)
R_0805
  rect 0.813x1.397 smd: 1(0,0) 2(1.702,0)
R_1206
  rect 1.016x1.651 smd: 1(0,0) 2(2.667,0)
R_1206_4P-D
  custom 0.445x0.445 smd: 1(0,0) 4(5.004,0)
  custom 0.114x0.114 smd: 2(1.194,0) 3(3.81,0)
RB751V40_SC76-2
  rect 0.61x0.61 smd: 1(0,0) 2(2.2,0)
RB751V-40_SOD323-2
  rect 0.787x0.889 smd: 1(0,0) 2(2.14,0)
RHU002N06_SOT323-3
  oval 0.813x0.914 smd: 1(0,0) 2(0.65,1.6) 3(-0.65,1.6)
RP_0804_8P4R
  oval 0.66x0.254 smd: 1(0,0) 2(0,-0.5) 3(0,-1) 4(0,-1.5) 5(1.15,-1.5) 6(1.15,-1) 7(1.15,-0.5) 8(1.15,0)
RT8207MZQW_WQFN20_3X3
  oval 0.203x0.889 smd: 1(0,0) 2(0.4,0) 3(0.8,0) 4(1.2,0) 5(1.6,0) 11(1.6,3.1) 12(1.2,3.1) 13(0.8,3.1) 14(0.4,3.1) 15(0,3.1)
  oval 0.889x0.203 smd: 6(2.35,0.75) 7(2.35,1.15) 8(2.35,1.55) 9(2.35,1.95) 10(2.35,2.35) 16(-0.75,2.35) 17(-0.75,1.95) 18(-0.75,1.55) 19(-0.75,1.15) 20(-0.75,0.75)
  rect 1.702x1.702 smd: 21(0.8,1.55)
RTL8106EUS-CG_QFN32_4X4
  oval 0.203x0.889 smd: 1(0,0) 2(0.4,0) 3(0.8,0) 4(1.2,0) 5(1.6,0) 6(2,0) 7(2.4,0) 8(2.8,0) 17(2.8,4.1) 18(2.4,4.1) 19(2,4.1) 20(1.6,4.1) 21(1.2,4.1) 22(0.8,4.1) 23(0.4,4.1) 24(0,4.1)
  oval 0.889x0.203 smd: 9(3.45,0.65) 10(3.45,1.05) 11(3.45,1.45) 12(3.45,1.85) 13(3.45,2.25) 14(3.45,2.65) 15(3.45,3.05) 16(3.45,3.45) 25(-0.65,3.45) 26(-0.65,3.05) 27(-0.65,2.65) 28(-0.65,2.25) 29(-0.65,1.85) 30(-0.65,1.45) 31(-0.65,1.05) 32(-0.65,0.65)
  rect 2.692x2.692 smd: 33(1.4,2.05)
SAMTE_ASP-136446-07-B_20P-T
  oval 0.737x2.794 smd: 1(0,0) 2(0,4.07) 3(1.27,0) 4(1.27,4.07) 5(2.54,0) 6(2.54,4.07) 7(3.81,0) 8(3.81,4.07) 9(5.08,0) 10(5.08,4.07) 11(6.35,0) 12(6.35,4.07) 13(7.62,0) 14(7.62,4.07) 15(8.89,0) 16(8.89,4.07) 17(10.16,0) 18(10.16,4.07) 19(11.43,0) 20(11.43,4.07)
SHORTPADS
  custom 0.19x0.19 smd: 1(-0.483,0) 2(0.483,0)
SI3456BDV-T1-E3_TSOP6
  oval 0.508x1.448 smd: 1(0,0) 2(1,0) 3(2,0) 4(2,2.425) 5(1,2.425) 6(0,2.425)
SI3457CDV-T1-GE3_TSOP6
  oval 0.508x1.422 smd: 1(0,0) 2(0.95,0) 3(1.9,0) 4(1.9,2.44) 5(0.95,2.44) 6(0,2.44)
SI4459ADY-T1-GE3_SO8
  oval 0.635x1.727 smd: 1(0,0) 2(1.27,0) 3(2.54,0) 4(3.81,0) 5(3.81,5.285) 6(2.54,5.285) 7(1.27,5.285) 8(0,5.285)
SINGA_2SJ3080-001111F_6P
  oval 0.991x1.905 hole 0.61x1.499: 1(0,0) 2(-9.55,5.5) 3(0,7.8) 4(-9.55,8.4) 5(-9.55,0) 6(-9.55,2.75) 7(0,4.1)
SIR472DP-T1-GE3_POWERPAK8-5
  oval 0.61x1.27 smd: 1(0,0) 2(1.27,0) 3(2.54,0) 4(3.81,0)
  custom 1.105x1.105 smd: 5(1.905,3.36)
SIS412DN-T1-GE3_POWERPAK8-5
  oval 0.406x0.991 smd: 1(0,0) 2(0.66,0) 3(1.32,0) 4(1.98,0)
  custom 0.559x0.559 smd: 5(0.99,2.247)
SLG3NB274VTR_TQFN16_2X3
  oval 0.203x0.914 smd: 1(0,-0.013) 2(0.4,-0.013) 3(0.8,-0.013) 4(1.2,-0.013) 5(1.6,-0.013) 6(2,-0.013) 7(2.4,-0.013) 9(2.4,2.063) 10(2,2.063) 11(1.6,2.063) 12(1.2,2.063) 13(0.8,2.063) 14(0.4,2.063) 15(0,2.063)
  oval 0.914x0.203 smd: 8(2.738,1.025) 16(-0.338,1.025)
  rect 1.905x0.889 smd: 17(1.2,1.025)
SN74LVC2T45DCTR_SM8
  oval 0.381x0.914 smd: 1(0,0) 2(0.65,0) 3(1.3,0) 4(1.95,0) 5(1.95,3.6) 6(1.3,3.6) 7(0.65,3.6) 8(0,3.6)
SSM3K7002FU_SC70-3
  oval 0.508x0.991 smd: 1(0,0) 2(0.65,1.9) 3(-0.65,1.9)
STARC_107K40-000001-G2_40P
  round 1.092 hole 1.092 unplated: (-2.3,-1.95) (21.8,-1.95)
  oval 0.254x1.295 smd: 1(0,0) 2(0.5,0) 3(1,0) 4(1.5,0) 5(2,0) 6(2.5,0) 7(3,0) 8(3.5,0) 9(4,0) 10(4.5,0) 11(5,0) 12(5.5,0) 13(6,0) 14(6.5,0) 15(7,0) 16(7.5,0) 17(8,0) 18(8.5,0) 19(9,0) 20(9.5,0) 21(10,0) 22(10.5,0) 23(11,0) 24(11.5,0) 25(12,0) 26(12.5,0) 27(13,0) 28(13.5,0) 29(14,0) 30(14.5,0) 31(15,0) 32(15.5,0) 33(16,0) 34(16.5,0) 35(17,0) 36(17.5,0) 37(18,0) 38(18.5,0) 39(19,0) 40(19.5,0)
  rect 1.549x3.404 smd: 41(-4.125,-5.85) 42(23.625,-5.85)
  rect 2.007x6.198 smd: 43(0.5,-7.65) 44(6,-7.65) 45(13.5,-7.65) 46(19,-7.65)
SW_SMT1-05-A_4P
  rect 0.61x0.991 smd: 1(0,0) 2(0,-4.4) 3(3.7,0) 4(3.7,-4.4)
  rect 0.457x0.991 smd: 5(-0.675,-2.2) 6(4.375,-2.2)
SY6288C20AAC_SOT23-5
  oval 0.559x0.787 smd: 1(0,0) 2(0.95,0) 3(1.9,0) 4(1.9,2.4) 5(0,2.4)
SY6288D20AAC_SOT23-5
  oval 0.559x0.787 smd: 1(0,0) 2(0.95,0) 3(1.9,0) 4(1.9,2.4) 5(0,2.4)
SY8032ABC_SOT23-6
  oval 0.61x0.991 smd: 1(0,0) 2(0.95,0) 3(1.9,0) 4(1.9,2.4) 5(0.95,2.4) 6(0,2.4)
SY8036DBC_DFN10_3X3
  oval 0.254x0.889 smd: 1(0,0) 2(0.5,0) 3(1,0) 4(1.5,0) 5(2,0) 6(2,3.1) 7(1.5,3.1) 8(1,3.1) 9(0.5,3.1) 10(0,3.1)
  rect 2.388x1.575 smd: 11(1,1.55)
SY8036LDBC_DFN10_3X3
  oval 0.254x0.889 smd: 1(0,0) 2(0.5,0) 3(1,0) 4(1.5,0) 5(2,0) 6(2,3.1) 7(1.5,3.1) 8(1,3.1) 9(0.5,3.1) 10(0,3.1)
  rect 2.388x1.575 smd: 11(1,1.55)
TAI-T_HCB2012KF-121T50_2P
  rect 0.991x0.991 smd: 1(0,0) 2(2,0)
TAITW_PUBAU6-09FLBS1NN4H0_9P
  round 1.295 hole 0.711: 1(0,0) 2(-2.5,0) 3(-4.5,0) 4(-7,0) 5(-7.5,-1.5) 6(-5.5,-1.5) 7(-3.5,-1.5) 8(-1.5,-1.5) 9(0.5,-1.5)
  oval 1.397x3.2 hole 0.787x2.591: 10(4.35,-2.38) 12(-11.35,-2.38)
  oval 1.397x2.388 hole 0.787x1.803: 11(4.35,-9.48) 13(-11.35,-9.48)
TAIYO_FBMJ4516HS720NT_2P
  rect 1.549x1.854 smd: 1(0,0) 2(3.95,0)
TOKO_1239AS-H-1R0M-P2_2P
  rect 0.787x2.007 smd: 1(0,0) 2(2,0)
TPC12
  round 0.305 smd: 1(0,0)
TPS22966DPUR_SON14_2X3
  oval 0.203x0.762 smd: 1(0,0) 2(0.4,0) 3(0.8,0) 4(1.2,0) 5(1.6,0) 6(2,0) 7(2.4,0) 8(2.4,2.05) 9(2,2.05) 10(1.6,2.05) 11(1.2,2.05) 12(0.8,2.05) 13(0.4,2.05) 14(0,2.05)
  rect 2.489x0.889 smd: 15(1.2,1.025)
TPS51212DSCR_SON10_3X3
  oval 0.279x0.838 smd: 1(0,0) 2(0.5,0) 3(1,0) 4(1.5,0) 5(2,0) 6(2,2.95) 7(1.5,2.95) 8(1,2.95) 9(0.5,2.95) 10(0,2.95)
  custom 0.412x0.412 smd: 11(1,1.475)
TPS51285BRUKR_QFN20_3X3
  oval 0.203x1.016 smd: 1(0,0) 2(0.4,0) 3(0.8,0) 4(1.2,0) 5(1.6,0) 11(1.6,2.975) 12(1.2,2.975) 13(0.8,2.975) 14(0.4,2.975) 15(0,2.975)
  oval 1.016x0.203 smd: 6(2.288,0.688) 7(2.288,1.088) 8(2.288,1.488) 9(2.288,1.888) 10(2.288,2.288) 16(-0.688,2.288) 17(-0.688,1.888) 18(-0.688,1.488) 19(-0.688,1.088) 20(-0.688,0.688)
  rect 1.702x1.702 smd: 21(0.8,1.488)
TVNST52302AB0_SOT523-3
  oval 0.508x0.559 smd: 1(0,0) 2(-0.5,-1.4) 3(0.5,-1.4)
W25Q64FVSSIG_SO8
  oval 0.635x1.676 smd: 1(0,0) 2(1.27,0) 3(2.54,0) 4(3.81,0) 5(3.81,7.25) 6(2.54,7.25) 7(1.27,7.25) 8(0,7.25)
Y_7V27000011_4P
  rect 1.397x1.194 smd: 1(0,0) 2(2.2,0) 3(2.2,1.7) 4(0,1.7)
Y_9H03200019_2P
  rect 0.991x1.803 smd: 1(0,0) 2(2.5,0)
Y_FSX3M-25PM20FDO_4P
  rect 1.397x1.194 smd: 1(0,0) 2(2.2,0) 3(2.2,1.6) 4(0,1.6)

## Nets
1.1VALWP_ON: PR404.1 RE40.1 RE46.1
1.1VS_ON: C987.2 R437.2 U15.5
1.8VGS_ON: C986.2 R436.2 U16.5
1.35V_B+: PC201.1 PC206.1 PC208.1 PC212.1 PC215.1 PL201.2 PQ200.5 PR208.1
1.35V_ON: C1014.2 R435.2 U16.3
3/5V_B+: PC105.1 PC112.1 PC113.1 PC114.1 PC115.1 PC118.1 PC119.1 PL102.2 PQ101.5 PQ103.5 PU100.12
3V_EN: PD101.2 PR100.1 PU100.6
3VGS_ON: C983.2 R438.2 U15.3
5V_EN: PD101.3 PR101.1 PU100.20
+0.675VS: C119.2 C120.1 C121.1 JDIMM1.203 JDIMM1.204 PJP203.1 RZ24.1
+0.675VSP: PC205.1 PC211.1 PJP203.2 PU200.2 PU200.20
+1.1VALW: LH9.1 LH11.1 LH12.2 LH15.2 PJP401.2 RH109.2 U15.6 U15.7
+1.1VALWP: PC402.1 PC403.1 PC405.1 PC406.1 PC407.1 PJP401.1 PL400.2 PR403.1
+1.1VALWP_ON: PC408.1 PR404.2 PU400.5
+1.1VS: J15.2 RH98.2 RH100.2 RH103.2 RH106.2
+1.1VS_CKVDD: CH29.1 CH39.1 CH40.1 CH41.1 CH42.1 RH7.1 RH100.1 U2.H26 U2.J25 U2.K24 U2.L22 U2.M22 U2.N21 U2.N22 U2.P22
+1.1VS_OUT: J15.1 U15.8 U15.9
+1.5V_D: QZ15.1 RZ27.2
+1.5VS: PJP302.2 PR1025.1 R36.1 R37.1 R54.2 R121.2 R122.2 RA8.1 U64.5 U67.5 U68.5
+1.05VS: C57.1 C58.1 C59.1 C60.1 C61.1 C62.1 C63.1 C64.1 C65.1 C66.1 C68.1 C69.1 C70.1 C71.1 C72.1 C73.1 PJP300.2 R1.1 R23.2 UC1.AK16 UC1.AK17 UC1.AL16 UC1.AM16 UC1.AM17 UC1.AN16 UC1.AN17
+1.5VSP: PC311.1 PC312.1 PC313.1 PJP302.1 PL302.2 PR309.1
+1.05VSP: PC300.1 PJP300.1 PL300.2 PR306.2
+1.05VSP_B+: PC301.1 PC302.1 PC303.1 PC304.1 PC316.1 PL301.1 PQ301.5
+1.5VSP_ON: PC314.1 PR311.2 PR312.1 PU301.1
+1.8VGS: C6.1 CV38.1 CV39.1 CV46.1 CV170.2 J13.2 LV2.1 LV3.1 LV6.1 LV7.1 PR1022.1 RV8.1 RV11.1 RV15.1 RV27.1 RV28.1 RV81.2 RV82.2 RV84.2 RV87.2 RV152.2 U1.8 UG1.11 UV1.AM30
+1.8VGS_OUT: J13.1 U16.8 U16.9
+1.8VS: C74.1 C75.1 C76.1 PJP403.2 U16.6 U16.7 UC1.AH11 UC1.AJ11
+1.8VSP: PC412.1 PC413.1 PC414.1 PJP403.1 PL401.2 PR407.1
+1.8VSP_ON: PC415.1 PR408.2 PR409.1 PU401.1
+1.35V: C82.1 C83.1 C84.1 C85.1 C88.1 C89.1 C90.1 C93.1 C94.1 C95.1 C96.1 C99.1 C100.1 C103.1 C104.1 C105.1 C106.1 C107.1 C108.1 C109.2 C110.2 C111.2 C112.1 C113.1 C114.1 C115.1 C116.1 C117.1 C118.1 J16.1 JDIMM1.75 JDIMM1.76 JDIMM1.81 JDIMM1.82 JDIMM1.87 JDIMM1.88 JDIMM1.93 JDIMM1.94 JDIMM1.99 JDIMM1.100 JDIMM1.105 JDIMM1.106 JDIMM1.111 JDIMM1.112 JDIMM1.117 JDIMM1.118 JDIMM1.123 JDIMM1.124 JHDT1.1 JHDT1.19 PC513.2 PJP200.2 PJP201.2 PU500.18 Q3.2 R3.1 R5.2 R6.1 R26.2 R28.2 R29.2 R30.2 R35.1 R38.1 R39.1 R40.1 R55.2 R57.2 R65.1 R120.1 R620.1 R622.2 RP1.5 RP1.6 RP1.7 RP1.8 RP2.1 RP2.2 RP2.3 RP2.4 RZ27.1 UC1.AA34 UC1.AB29 UC1.AB32 UC1.AB37 UC1.AC29 UC1.AC31 UC1.AC34 UC1.AC37 UC1.AE32 UC1.AE34 UC1.AF30 UC1.AF31 UC1.AG34 UC1.AG37 UC1.L29 UC1.L31 UC1.L34 UC1.L37 UC1.M29 UC1.M32 UC1.N27 UC1.N34 UC1.P29 UC1.P31 UC1.R29 UC1.R32 UC1.R34 UC1.R37 UC1.U29 UC1.U31 UC1.U34 UC1.V27 UC1.V34 UC1.W29 UC1.W32 UC1.W37 UC1.Y31
+1.35V_MEM_GFX: CV40.1 CV41.1 CV42.1 CV43.1 CV44.1 CV45.1 CV47.1 CV48.1 CV49.1 CV50.1 CV51.1 CV52.1 CV53.1 CV103.1 CV104.1 CV105.1 CV106.1 CV107.1 CV108.1 CV109.1 CV110.1 CV111.1 CV112.1 CV113.1 CV114.1 CV115.1 CV116.1 CV117.1 CV118.1 CV119.1 CV120.1 CV121.1 CV122.1 CV123.1 CV124.1 CV125.1 CV126.1 CV127.1 CV128.1 CV129.1 CV130.1 CV131.1 CV132.1 CV136.1 CV137.1 CV138.1 CV139.1 CV140.1 CV141.1 CV142.1 CV143.1 CV144.1 CV145.1 CV146.1 CV147.1 CV148.1 CV149.1 CV150.1 CV151.1 CV152.1 CV153.1 CV154.1 CV155.1 CV156.1 CV157.1 CV158.1 CV159.1 CV160.1 CV161.1 CV162.1 CV163.1 CV164.1 CV165.1 CV171.1 CV172.1 CV173.1 CV174.1 CV175.1 CV176.1 CV177.1 CV178.1 CV179.1 CV180.1 CV181.1 CV182.1 CV183.1 J14.2 PJP1100.2 PJP1101.2 RV32.1 RV33.1 RV42.1 RV43.1 RV50.1 RV51.1 UV1.H13 UV1.H16 UV1.H19 UV1.J9 UV1.J10 UV1.J23 UV1.J24 UV1.K9 UV1.K10 UV1.K23 UV1.K24 UV1.L11 UV1.L12 UV1.L13 UV1.L20 UV1.L21 UV1.L22 UV5.A1 UV5.A8 UV5.B2 UV5.C1 UV5.C9 UV5.D2 UV5.D9 UV5.E9 UV5.F1 UV5.G7 UV5.H2 UV5.H9 UV5.K2 UV5.K8 UV5.N1 UV5.N9 UV5.R1 UV5.R9 UV6.A1 UV6.A8 UV6.B2 UV6.C1 UV6.C9 UV6.D2 UV6.D9 UV6.E9 UV6.F1 UV6.G7 UV6.H2 UV6.H9 UV6.K2 UV6.K8 UV6.N1 UV6.N9 UV6.R1 UV6.R9 UV7.A1 UV7.A8 UV7.B2 UV7.C1 UV7.C9 UV7.D2 UV7.D9 UV7.E9 UV7.F1 UV7.G7 UV7.H2 UV7.H9 UV7.K2 UV7.K8 UV7.N1 UV7.N9 UV7.R1 UV7.R9 UV8.A1 UV8.A8 UV8.B2 UV8.C1 UV8.C9 UV8.D2 UV8.D9 UV8.E9 UV8.F1 UV8.G7 UV8.H2 UV8.H9 UV8.K2 UV8.K8 UV8.N1 UV8.N9 UV8.R1 UV8.R9
+1.35VGPUP: PC1108.1 PJP1100.1 PJP1101.1 PL1101.2 PR1107.2
+1.35VGPUP_B+: PC1100.1 PC1101.1 PC1102.1 PC1109.1 PL1100.1 PQ1100.5
+1.35VP: PC213.1 PC214.2 PJP200.1 PJP201.1 PL200.1 PR207.2 PU200.5 PU200.19
+1.35VS_MEM_GFX_OUT: J14.1 U16.13 U16.14
+3VALW: C7.1 C9.1 CE61.2 CH14.1 CH466.1 CL38.1 CL39.1 CZ1.1 JP3.2 LH5.1 LH6.1 LH7.2 PJP100.2 PJP102.2 PJP301.1 PJP400.1 PJP402.1 PJP1301.2 PR3.2 PR25.2 PR28.1 PR115.1 R791.1 RA10.1 RE1.1 RE3.2 RE8.2 RE16.1 RE21.1 RE62.1 RE63.1 RE70.1 RE71.1 RE330.1 RE332.2 RH53.1 RH57.1 RH60.1 RH61.1 RH73.1 RH81.1 RH85.1 RH86.1 RH88.1 RH89.1 RH107.2 RH110.2 RH117.1 RH118.1 RH119.1 RH120.1 RL40.1 RPE1.1 RPE1.2 RPH1.8 RPH4.1 RPH4.2 RPH4.3 RPH4.4 RPH5.1 RPH5.2 RPH6.1 RPH6.2 RPH6.3 RPH6.4 RV94.1 U6.1 U6.2 UG1.2 UG1.3 UH1.5 UL2.4 UL2.5 UL3.5 USPI1.8
+3VALW_15: R791.2 R793.2 UG1.15
+3VALW_EC: CE1.1 CE2.1 CE3.1 CE4.1 CE5.2 CE6.2 JLED.3 LE1.1 PR16.2 RE1.2 RE2.2 UE1.9 UE1.22 UE1.33 UE1.96 UE1.125
+3VALWP: PC101.1 PC102.1 PJP100.1 PJP102.1 PL100.2 PR109.1
+3VGS: CV10.1 CV166.2 J11.2 LV4.1 QV1.2 QV1.5 RP34.1 RP34.2 RP34.3 RV5.1 RV6.1 RV58.2 RV71.2 RV72.2 RV79.2 RV91.2 RV93.1 RV146.1 RV147.1 RV148.1 RV154.1 RV162.1 U1.1 UV2.5 UV3.1
+3VGS_OUT: J11.1 U15.13 U15.14
+3VLP: DH2.2 PC109.1 PU100.3 R32.2 R793.1 RE2.1 RE4.2 RE30.1 RE49.2 RE333.2
+3VS: C128.1 C129.1 C2498.1 CA57.1 CA58.1 CA59.1 CA60.1 CS27.1 CS42.1 CX1.1 CX7.1 CZ3.1 CZ4.1 JDIMM1.199 JEDP.34 JEDP.35 JIO.6 LH1.1 LH13.1 LH14.1 PR541.1 PR1020.1 PR1030.1 PR1110.1 QH31.2 QH31.5 QM1.2 QX3.2 QX4.2 QX4.5 QX5.1 R384.1 R537.1 R617.1 R2448.1 RA1.1 RA2.1 RA7.1 RA9.1 RA155.2 RC13.1 RE12.1 RE32.1 RE34.1 RE38.1 RE50.1 RE68.2 RE331.1 RH39.1 RH41.1 RH78.1 RH79.1 RH80.1 RH82.1 RH83.1 RH84.1 RH87.1 RH96.1 RH112.2 RH114.1 RH115.1 RH116.1 RH133.1 RH134.1 RH135.1 RL33.1 RL37.2 RM7.1 RP16.1 RP16.2 RP16.4 RP60.7 RP60.8 RPE1.3 RPE1.4 RPH5.3 RPH5.4 RS19.1 RS20.1 RS25.1 RS26.1 RS27.1 RS28.1 RS29.1 RS30.1 RS33.2 RS34.2 RS38.2 RX10.1 RX12.1 RX13.1 RX27.1 RX30.1 U6.13 U6.14 U15.1 U15.2 U2407.1 UA1.1 UA1.9 UA1.36 UX4.5
+3VS_CAM: JEDP.29 RX27.2
+3VS_TOUCH: CE58.1 CE59.1 J519.2 JTP.8 RC78.2 RE329.1 UE4.7 UE4.8
+3VS_WLAN_NGFF: CM4.1 CM5.1 CM6.1 CM7.1 CM9.1 CM10.1 JNGFF.2 JNGFF.4 JNGFF.64 JNGFF.66 RM7.2 RM8.1
+5V_HDD: CS5.1 CS6.1 CS7.1 JHDD.9 JHDD.10 JP13.1
+5V_PVDD: CA53.1 CA54.1 CA55.1 CA56.1 RA1110.2 UA1.41 UA1.46
+5V_USB_PWR1: CI1.1 CI2.1 CI5.1 CI40.1 JUSB1.1 UI5.1
+5V_USB_PWR2: CI8.1 CI9.1 CI16.1 CI43.1 JUSB2.1 UI6.1
+5V_USB_PWR3: JIO.1 JIO.2 JIO.3 JIO.4 UI7.1
+5VA: CA51.1 CA71.1 RA1111.2 UA1.26
+5VALW: CI6.1 CI7.1 CI12.1 CI14.1 CI18.1 CI44.1 CI45.1 CZ2.1 JLED.1 PC307.1 PC715.1 PC1021.1 PC1105.1 PJP101.2 PJP103.2 PR8.1 PR206.1 PR210.2 PR1024.2 PU300.7 PU700.11 PU1000.26 PU1000.31 PU1100.7 RE504.2 RZ10.2 RZ19.2 U6.4 U6.6 U6.7 U15.4 U16.4 UI5.5 UI6.5 UI7.5
+5VALWP: PC107.1 PC108.2 PJP101.1 PJP103.1 PL101.2 PR104.2 PU100.14
+5VS: CE25.1 CE56.1 CZ13.1 CZ14.1 FE1.2 FX1.2 JLED.2 JP13.2 PR520.2 PR521.2 PU500.41 Q20.2 R18.1 RA1110.1 RA1111.1 RE13.1 RE59.1 RE60.1 RX29.1 U6.8 U6.9 UE3.1 UE3.2
+5VS_KBL: CE57.1 FE1.1 JKBBL.1 RE59.2
+AVDD_SATA: CH50.1 CH51.1 CH52.1 CH53.1 RH38.2 RH106.1 U2.AA18 U2.AA20 U2.AA21 U2.AB20 U2.AB21 U2.AB22 U2.AC19 U2.AC21 U2.AC22 U2.Y20
+V18R: CE16.1 UE1.124
+VCC_VDDCR_11: CH26.1 CH32.1 CH33.1 CH34.1 CH35.1 RH98.1 U2.T14 U2.T17 U2.T20 U2.U16 U2.U18 U2.V14 U2.V17 U2.V20 U2.Y17
+VCCP_D: QZ13.1 RZ24.2
+VDD_CT: CV61.1 CV62.1 CV63.1 LV3.2 UV1.AA20 UV1.AA21 UV1.AB20 UV1.AB21
+VDD_TOUCH: CX49.1 CX50.1 JEDP.11 JEDP.26 QX6.5 QX7.2 RX28.2 RX35.1 RX39.1 RX40.1
+VDDAN_11_PCIE: CH44.1 CH45.1 CH46.1 RH2.1 RH103.1 U2.AA22 U2.AB23 U2.AB24 U2.AD24 U2.AE25 U2.AF26 U2.AG27 U2.Y21
+VDDAN_11_SSUSB: CH80.1 CH81.1 CH82.1 RH111.2 U2.M14 U2.N14 U2.P13 U2.P14 U2.P16
+VDDAN_11_USB_S: CH67.1 CH68.1 CH69.1 LH9.2 U2.U12 U2.U13
+VDDAN_33_HWM: CH83.1 CH84.1 RH110.1 U2.M8
+VDDAN_33_USB: CH59.1 CH60.1 CH61.1 CH62.1 CH63.1 LH5.2 LH10.1 U2.G7 U2.H8 U2.J8 U2.K8 U2.K9 U2.M9 U2.M10 U2.M11 U2.M12 U2.N9 U2.N10 U2.N12
+VDDBT_RTC: CH13.1 RH22.1 U2.E6
+VDDCI: CV87.1 CV88.1 CV89.1 CV90.1 LV25.1 LV26.1 UV1.M13 UV1.M15 UV1.M16 UV1.M17 UV1.M18 UV1.M20 UV1.M21 UV1.N20
+VDDCR_1.1V: CH70.1 CH71.1 RH109.1 U2.M20 U2.N20
+VDDCR_11_SSUSB: CH87.1 CH88.1 CH89.1 CH90.1 RH113.2 U2.M17 U2.N16 U2.N17 U2.P17
+VDDCR_11_USB: CH74.1 CH75.1 CH76.1 LH11.2 U2.T12 U2.T13
+VDDIO_33_PCIGP: CH27.1 CH30.1 CH36.1 CH37.1 RH96.2 U2.AB12 U2.AB13 U2.AB14 U2.AB16 U2.AB17 U2.AB18 U2.AC13 U2.AD10 U2.AE9 U2.AG7
+VDDIO_33_S: CH56.1 CH57.1 CH58.1 RH107.1 U2.L19 U2.M18 U2.N18 U2.V12 U2.V13 U2.W11 U2.Y12 U2.Y13
+VDDIO_AZ: CH85.1 RH112.1 U2.AA4
+VDDPL_11_SYS_S: CH77.1 CH78.1 LH12.1 U2.J24
+VDDPL_33_PCIE: CH79.1 LH13.2 U2.AH29
+VDDPL_33_SATA: CH86.1 LH14.2 U2.AG28
+VDDPL_33_SSUSB_S: CH64.1 CH65.1 LH6.2 RH97.1 U2.L18
+VDDPL_33_SYS: CH25.1 CH31.1 LH1.2 U2.H24
+VDDPL_33_USB_S: CH72.1 CH73.1 LH10.2 U2.D7
+VDDR3: CV64.1 CV65.1 CV66.1 LV4.2 UV1.AA17 UV1.AA18 UV1.AB17 UV1.AB18
+VDDXL_3.3V: CH66.1 LH7.1 U2.G24
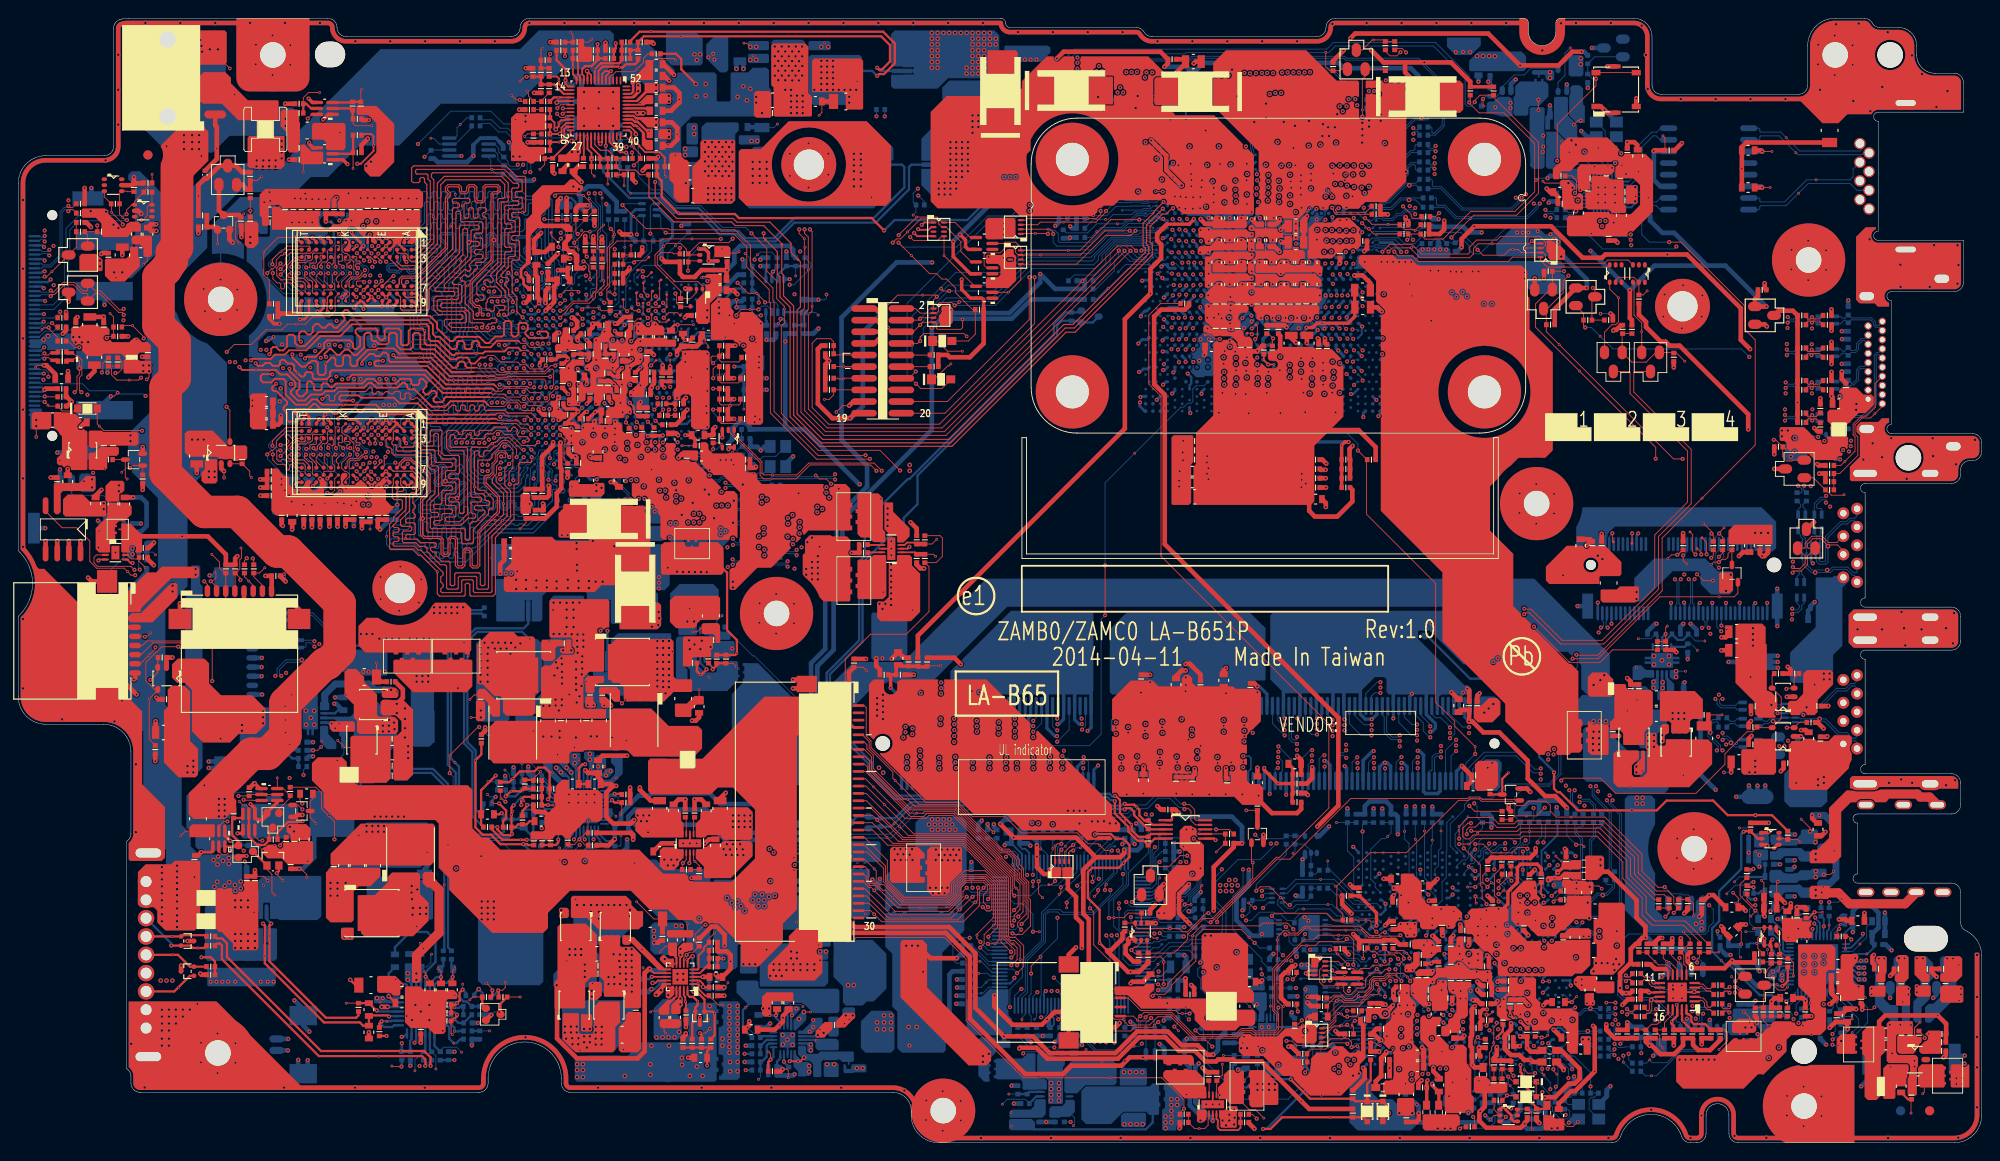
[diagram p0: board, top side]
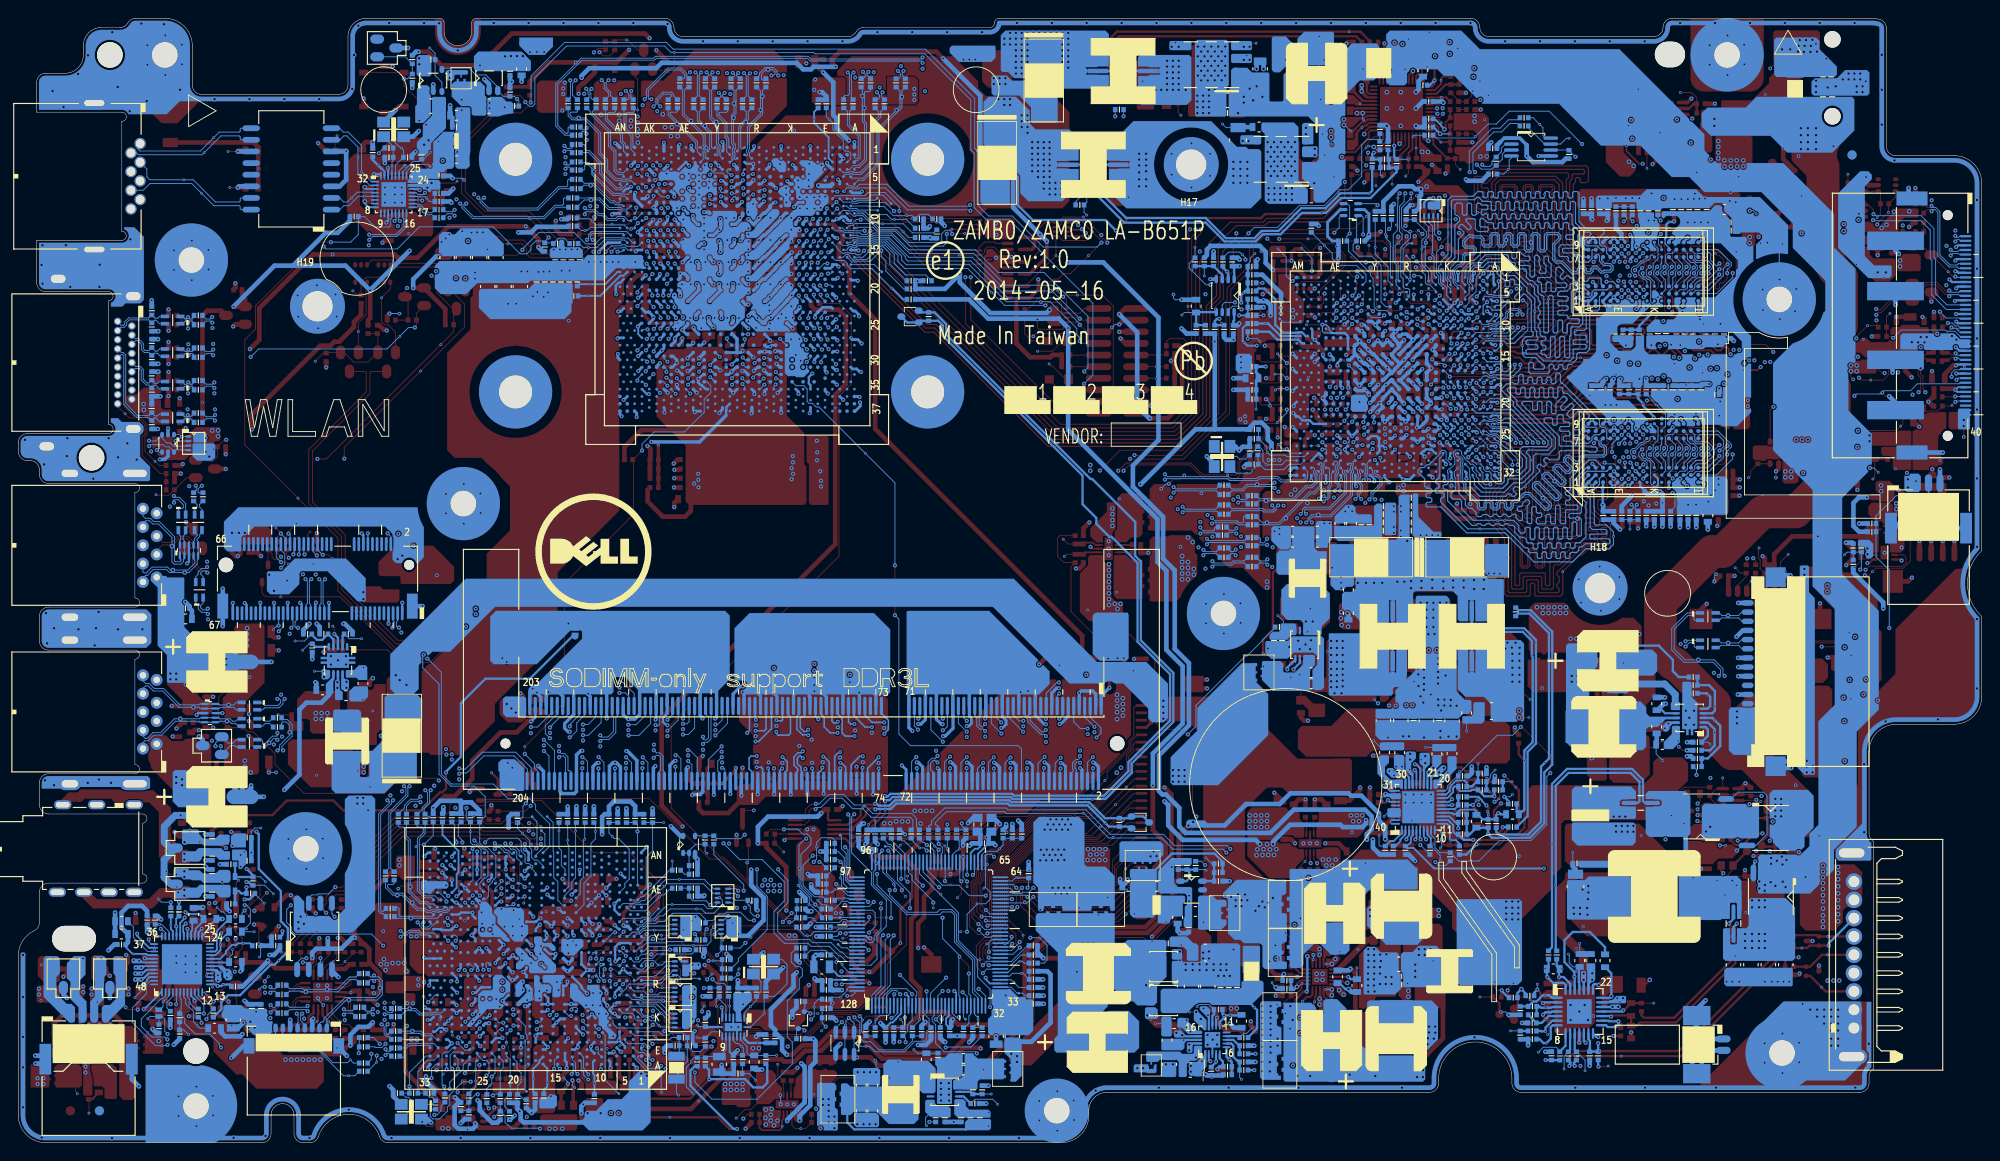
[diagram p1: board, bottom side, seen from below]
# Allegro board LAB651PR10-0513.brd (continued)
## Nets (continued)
GND: C5.1 C6.2 C7.2 C8.2 C9.2 C10.2 C11.2 C12.2 C14.2 C15.2 C29.2 C30.1 C53.2 C54.2 C55.2 C57.2 C58.2 C59.2 C60.2 C61.2 C62.2 C63.2 C64.2 C65.2 C66.2 C68.2 C69.2 C70.2 C71.2 C72.2 C73.2 C74.2 C75.2 C76.2 C77.2 C78.2 C79.2 C80.2 C81.2 C82.2 C83.2 C84.2 C85.2 C88.2 C89.2 C90.2 C93.2 C94.2 C95.2 C96.2 C99.2 C100.2 C103.2 C104.2 C105.2 C106.2 C107.2 C108.2 C109.1 C110.1 C111.1 C112.2 C113.2 C114.2 C115.2 C116.2 C117.2 C118.2 C119.1 C120.2 C121.2 C122.2 C123.2 C124.2 C125.2 C126.2 C127.2 C128.2 C129.2 C343.1 C344.1 C348.1 C349.1 C935.2 C936.2 C983.1 C986.1 C987.1 C1014.1 C2498.2 CA21.2 CA22.2 CA25.1 CA29.2 CA30.2 CA31.2 CA32.2 CA53.2 CA54.2 CA55.2 CA56.2 CA57.2 CA58.2 CA59.2 CA60.2 CA64.1 CA69.2 CE1.2 CE2.2 CE3.2 CE4.2 CE5.1 CE6.1 CE8.2 CE10.2 CE11.2 CE14.2 CE15.2 CE16.2 CE17.1 CE18.1 CE20.2 CE22.2 CE23.2 CE24.2 CE25.2 CE26.2 CE27.2 CE29.2 CE56.2 CE57.2 CE58.2 CE59.2 CE60.2 CE61.1 CH6.1 CH10.1 CH11.1 CH12.1 CH13.2 CH14.2 CH15.1 CH16.2 CH17.2 CH20.1 CH23.2 CH25.2 CH26.2 CH27.2 CH29.2 CH30.2 CH31.2 CH32.2 CH33.2 CH34.2 CH35.2 CH36.2 CH37.2 CH39.2 CH40.2 CH41.2 CH42.2 CH43.1 CH44.2 CH45.2 CH46.2 CH50.2 CH51.2 CH52.2 CH53.2 CH56.2 CH57.2 CH58.2 CH59.2 CH60.2 CH61.2 CH62.2 CH63.2 CH64.2 CH65.2 CH66.2 CH67.2 CH68.2 CH69.2 CH70.2 CH71.2 CH72.2 CH73.2 CH74.2 CH75.2 CH76.2 CH77.2 CH78.2 CH79.2 CH80.2 CH81.2 CH82.2 CH83.2 CH84.2 CH85.2 CH86.2 CH87.2 CH88.2 CH89.2 CH90.2 CH91.2 CH92.2 CH466.2 CI1.2 CI2.2 CI5.2 CI6.2 CI7.2 CI8.2 CI9.2 CI12.2 CI13.2 CI14.2 CI15.2 CI16.2 CI17.2 CI18.2 CI26.2 CI40.2 CI43.2 CI44.2 CI45.2 CI46.2 CI47.2 CL3.2 CL4.2 CL5.2 CL6.2 CL7.2 CL8.2 CL9.2 CL10.2 CL12.2 CL13.2 CL14.2 CL15.2 CL16.1 CL17.2 CL19.2 CL33.2 CL36.1 CL37.1 CL38.2 CL39.2 CL41.1 CLRP1.2 CM4.2 CM5.2 CM6.2 CM7.2 CM9.2 CM10.2 CS5.2 CS6.2 CS7.2 CS27.2 CS42.2 CV10.2 CV11.2 CV15.2 CV17.2 CV18.2 CV19.2 CV20.2 CV21.2 CV22.2 CV26.2 CV27.2 CV28.2 CV29.2 CV33.2 CV34.2 CV38.2 CV39.2 CV40.2 CV41.2 CV42.2 CV43.2 CV44.2 CV45.2 CV46.2 CV47.2 CV48.2 CV49.2 CV50.2 CV51.2 CV52.2 CV53.2 CV54.2 CV55.2 CV56.2 CV57.2 CV58.2 CV59.2 CV60.2 CV61.2 CV62.2 CV63.2 CV64.2 CV65.2 CV66.2 CV67.2 CV68.2 CV69.2 CV70.2 CV71.2 CV72.2 CV73.2 CV74.2 CV75.2 CV76.2 CV77.2 CV78.2 CV79.2 CV80.2 CV81.2 CV82.2 CV83.2 CV84.2 CV85.2 CV86.2 CV87.2 CV88.2 CV89.2 CV90.2 CV91.2 CV92.2 CV93.2 CV94.2 CV95.2 CV96.2 CV97.2 CV100.2 CV101.2 CV102.2 CV103.2 CV104.2 CV105.2 CV106.2 CV107.2 CV108.2 CV109.2 CV110.2 CV111.2 CV112.2 CV113.2 CV114.2 CV115.2 CV116.2 CV117.2 CV118.2 CV119.2 CV120.2 CV121.2 CV122.2 CV123.2 CV124.2 CV125.2 CV126.2 CV127.2 CV128.2 CV129.2 CV130.2 CV131.2 CV132.2 CV133.2 CV134.2 CV135.2 CV136.2 CV137.2 CV138.2 CV139.2 CV140.2 CV141.2 CV142.2 CV143.2 CV144.2 CV145.2 CV146.2 CV147.2 CV148.2 CV149.2 CV150.2 CV151.2 CV152.2 CV153.2 CV154.2 CV155.2 CV156.2 CV157.2 CV158.2 CV159.2 CV160.2 CV161.2 CV162.2 CV163.2 CV164.2 CV165.2 CV166.1 CV167.1 CV168.2 CV169.1 CV170.1 CV171.2 CV172.2 CV173.2 CV174.2 CV175.2 CV176.2 CV177.2 CV178.2 CV179.2 CV180.2 CV181.2 CV182.2 CV183.2 CV357.2 CV358.2 CV359.2 CV360.2 CV361.2 CV362.2 CV363.2 CV364.2 CVT90.1 CX1.2 CX2.2 CX3.2 CX5.2 CX7.2 CX8.2 CX11.2 CX20.2 CX21.2 CX22.2 CX23.2 CX24.2 CX25.2 CX26.2 CX27.2 CX28.2 CX29.2 CX30.2 CX31.2 CX49.2 CX50.2 CZ1.2 CZ2.2 CZ3.2 CZ4.2 CZ5.2 CZ9.2 CZ13.2 CZ14.2 CZ15.2 DA10.1 DA12.1 DA13.1 DA14.1 DE2.1 DI1.3 DI1.8 DI2.1 DI4.3 DI4.8 DI5.1 DX2.1 H2.1(TP-1) H3.1(TP-1) H4.1(TP-1) H5.1(TP-1) H6.1(TP-1) H7.1(TP-1) H8.1(TP-1) H9.1(TP-1) H11.1(TP-1) H12.1(TP-1) H13.1(TP-1) H14.1(TP-1) H15.1(TP-1) H16.1(TP-1) H17.1(TP-1) H18.1(TP-1) H19.1(TP-1) HE1.2 JDIMM1.2 JDIMM1.3 JDIMM1.8 JDIMM1.9 JDIMM1.13 JDIMM1.14 JDIMM1.19 JDIMM1.20 JDIMM1.25 JDIMM1.26 JDIMM1.31 JDIMM1.32 JDIMM1.37 JDIMM1.38 JDIMM1.43 JDIMM1.44 JDIMM1.48 JDIMM1.49 JDIMM1.54 JDIMM1.55 JDIMM1.60 JDIMM1.61 JDIMM1.65 JDIMM1.66 JDIMM1.71 JDIMM1.72 JDIMM1.127 JDIMM1.128 JDIMM1.133 JDIMM1.134 JDIMM1.138 JDIMM1.139 JDIMM1.144 JDIMM1.145 JDIMM1.150 JDIMM1.151 JDIMM1.155 JDIMM1.156 JDIMM1.161 JDIMM1.162 JDIMM1.167 JDIMM1.168 JDIMM1.172 JDIMM1.173 JDIMM1.178 JDIMM1.179 JDIMM1.184 JDIMM1.185 JDIMM1.189 JDIMM1.190 JDIMM1.195 JDIMM1.196 JDIMM1.197 JDIMM1.201 JDIMM1.205 JDIMM1.206 JEDP.3 JEDP.6 JEDP.9 JEDP.12 JEDP.15 JEDP.18 JEDP.20 JEDP.31 JEDP.41 JEDP.42 JEDP.43 JEDP.44 JEDP.45 JEDP.46 JFAN.3 JFAN.4 JFAN.5 JHDD.3 JHDD.6 JHDD.11 JHDD.12 JHDMI.2 JHDMI.5 JHDMI.8 JHDMI.11 JHDMI.17 JHDMI.20 JHDMI.21 JHDMI.22 JHDMI.23 JHDT1.3 JHDT1.5 JHDT1.7 JHDT1.17 JIO.8 JIO.9 JIO.10 JIO.13 JIO.16 JIO.17 JIO.18 JKB.31 JKB.32 JKBBL.5 JKBBL.6 JLAN.9 JLAN.10 JLED.8 JLED.9 JLED.10 JNGFF.1 JNGFF.7 JNGFF.18 JNGFF.25 JNGFF.31 JNGFF.37 JNGFF.43 JNGFF.49 JNGFF.55 JNGFF.61 JNGFF.67 JNGFF.68 JNGFF.69 JRTC.2 JRTC.3 JRTC.4 JSPK.5 JSPK.6 JTP.5 JTP.9 JTP.10 JUSB1.4 JUSB1.7 JUSB1.10 JUSB1.11 JUSB1.12 JUSB1.13 JUSB2.4 JUSB2.7 JUSB2.10 JUSB2.11 JUSB2.12 JUSB2.13 LE2.1 PBATT.1 PBATT.2 PBATT.4 PBATT.10 PBATT.11 PC1.2 PC2.2 PC3.2 PC4.2 PC5.2 PC7.2 PC8.2 PC9.2 PC13.1 PC100.2 PC101.2 PC103.2 PC105.2 PC106.2 PC107.2 PC109.2 PC111.2 PC112.2 PC113.2 PC114.2 PC115.2 PC118.2 PC119.2 PC201.2 PC202.2 PC203.2 PC204.1 PC205.2 PC206.2 PC208.2 PC209.2 PC210.2 PC211.2 PC212.2 PC213.2 PC215.2 PC300.2 PC301.2 PC302.2 PC303.2 PC304.2 PC306.2 PC307.2 PC309.2 PC310.1 PC312.2 PC313.2 PC314.2 PC315.2 PC316.2 PC400.2 PC401.2 PC403.2 PC404.2 PC405.2 PC406.2 PC407.2 PC408.2 PC409.2 PC410.2 PC411.1 PC413.2 PC414.2 PC415.2 PC416.2 PC500.1 PC501.1 PC502.2 PC503.2 PC504.2 PC505.2 PC511.2 PC512.2 PC513.1 PC514.2 PC515.2 PC518.2 PC519.2 PC520.2 PC521.2 PC522.2 PC523.2 PC526.2 PC527.2 PC528.2 PC532.2 PC533.1 PC534.1 PC535.2 PC702.2 PC703.2 PC704.2 PC705.2 PC706.2 PC707.2 PC708.2 PC710.2 PC711.2 PC712.1 PC714.2 PC715.2 PC716.2 PC717.2 PC718.2 PC719.2 PC720.2 PC721.2 PC723.2 PC725.1 PC726.2 PC727.2 PC836.2 PC837.2 PC838.2 PC839.2 PC840.2 PC841.2 PC842.2 PC843.2 PC844.2 PC845.2 PC846.2 PC847.2 PC848.2 PC849.2 PC850.2 PC851.2 PC852.2 PC853.2 PC854.2 PC855.2 PC856.2 PC857.2 PC858.2 PC859.2 PC860.2 PC869.2 PC871.2 PC872.2 PC901.2 PC902.2 PC903.2 PC904.2 PC905.2 PC906.2 PC907.2 PC908.2 PC909.2 PC910.2 PC911.2 PC912.2 PC913.2 PC914.2 PC915.2 PC916.2 PC917.2 PC918.2 PC919.2 PC920.2 PC921.2 PC922.2 PC923.2 PC924.2 PC931.2 PC932.2 PC933.2 PC934.2 PC935.2 PC936.2 PC937.2 PC938.2 PC939.2 PC940.2 PC941.2 PC942.2 PC943.2 PC944.2 PC945.2 PC946.2 PC947.2 PC948.2 PC949.2 PC950.2 PC951.2 PC952.2 PC1019.2 PC1020.2 PC1021.2 PC1022.1 PC1023.2 PC1024.2 PC1025.2 PC1029.2 PC1030.2 PC1034.2 PC1035.2 PC1040.2 PC1041.2 PC1042.2 PC1044.2 PC1045.2 PC1046.2 PC1047.2 PC1048.2 PC1049.2 PC1052.2 PC1100.2 PC1101.2 PC1102.2 PC1104.2 PC1105.2 PC1106.2 PC1108.2 PC1109.2 PC1300.2 PC1301.2 PC1302.2 PC1303.2 PC1304.2 PC1305.2 PC1307.2 PC1308.2 PC1309.2 PD1.1 PD2.1 PD101.1 PH1002.1 PL4.2 PQ1.1 PQ1.4 PQ2.1 PQ2.4 PQ5.3 PQ102.1 PQ102.2 PQ102.3 PQ104.1 PQ104.2 PQ104.3 PQ201.1 PQ201.2 PQ201.3 PQ303.1 PQ303.2 PQ303.3 PQ500.8 PQ501.8 PQ703.1 PQ703.2 PQ703.3 PQ708.3 PQ709.1 PQ709.4 PQ710.1 PQ710.4 PQ711.3 PQ712.3 PQ713.1 PQ713.4 PQ714.3 PQ1004.1 PQ1004.2 PQ1004.3 PQ1006.1 PQ1006.2 PQ1006.3 PQ1101.1 PQ1101.2 PQ1101.3 PR9.1 PR10.1 PR26.1 PR29.2 PR33.1 PR105.2 PR106.2 PR107.1 PR108.2 PR110.2 PR114.2 PR203.2 PR204.2 PR301.1 PR304.2 PR307.2 PR312.2 PR313.2 PR405.2 PR409.2 PR410.2 PR500.1 PR528.1 PR529.1 PR540.1 PR553.1 PR559.1 PR567.1 PR571.1 PR715.1 PR716.2 PR728.1 PR729.1 PR1029.1 PR1031.1 PR1032.1 PR1033.1 PR1035.1 PR1038.2 PR1056.1 PR1102.1 PR1105.2 PR1108.2 PR1301.2 PR1304.2 PU100.21 PU200.1 PU200.3 PU200.14 PU200.21 PU300.11 PU301.2 PU400.11 PU401.2 PU500.53 PU700.12 PU700.14 PU700.19 PU700.29 PU1000.41 PU1100.11 PU1300.11 Q52.1 Q52.4 QC1.3 QE4.3 QE5.4 QE30.3 QH2.1 QH2.4 QV7.3 QV8.1 QV8.4 QX3.3 QZ13.3 QZ15.3 R8.1 R13.2 R14.2 R15.2 R16.2 R17.2 R22.2 R25.2 R27.2 R31.2 R34.2 R47.1 R48.1 R50.1 R56.1 R59.1 R365.2 R538.2 R616.2 RA19.2 RA29.2 RA30.2 RA31.2 RA32.2 RA81.1 RA1113.1 RC8.1 RC9.1 RE5.1 RE45.2 RE46.2 RE47.2 RE58.2 RH1.2 RH5.1 RH24.2 RH26.1 RH37.2 RH40.1 RH54.2 RH58.2 RH72.2 RH75.2 RH90.1 RH91.1 RH92.2 RH93.2 RH94.1 RH95.1 RH97.2 RH108.1 RH121.2 RH122.2 RH123.2 RH124.2 RH125.2 RH126.2 RH127.2 RH128.2 RH129.2 RH130.2 RH131.2 RH132.2 RL27.1 RL31.1 RL35.1 RM11.2 RP15.1 RP15.2 RP15.4 RP34.4 RPC1.5 RPC1.6 RPC1.7 RPC1.8 RPH1.5 RPH1.6 RPH1.7 RPH2.5 RPH2.6 RPH2.7 RPH2.8 RPH3.5 RPH3.6 RPH3.7 RPH3.8 RPH7.1 RPH7.2 RPH7.3 RPH7.4 RS18.2 RS21.2 RS22.1 RS23.2 RS24.2 RS31.2 RS35.2 RS36.2 RS37.2 RV2.1 RV4.2 RV9.2 RV12.2 RV13.2 RV16.2 RV17.1 RV21.1 RV29.1 RV34.2 RV35.2 RV38.2 RV39.1 RV40.1 RV41.1 RV44.2 RV45.2 RV46.2 RV47.2 RV52.2 RV53.2 RV56.2 RV57.2 RV59.1 RV73.1 RV74.1 RV83.2 RV88.1 RV89.1 RV151.1 RV160.2 RV163.2 RX4.2 RX9.2 RX13.2 RX14.2 RX24.1 RX26.2 RX34.2 RX36.2 RZ21.2 RZ591.2 SW1.1 SW1.2 SW1.5 SW1.6 U1.4 U2.A3 U2.A33 U2.AA6 U2.AA12 U2.AA13 U2.AA14 U2.AA16 U2.AA17 U2.AA25 U2.AA28 U2.AA30 U2.AA32 U2.AB25 U2.AC6 U2.AC18 U2.AC28 U2.AD27 U2.AE6 U2.AE15 U2.AE21 U2.AE28 U2.AF8 U2.AF12 U2.AF16 U2.AF33 U2.AG30 U2.AG32 U2.AH5 U2.AH11 U2.AH18 U2.AH19 U2.AH21 U2.AH23 U2.AH25 U2.AH27 U2.AJ18 U2.AJ28 U2.AJ29 U2.AK21 U2.AK25 U2.AL18 U2.AM21 U2.AM25 U2.AN1 U2.AN18 U2.AN28 U2.AN33 U2.B7 U2.B13 U2.D9 U2.D13 U2.E5 U2.E12 U2.E16 U2.E29 U2.F7 U2.F9 U2.F11 U2.F13 U2.F16 U2.F17 U2.F19 U2.F23 U2.F25 U2.F29 U2.G6 U2.G16 U2.G32 U2.H12 U2.H15 U2.H25 U2.H29 U2.J6 U2.J9 U2.J10 U2.J13 U2.J28 U2.J32 U2.K7 U2.K16 U2.K25 U2.K27 U2.K28 U2.K33 U2.L6 U2.L12 U2.L13 U2.L15 U2.L16 U2.L21 U2.L28 U2.M13 U2.M16 U2.M21 U2.M25 U2.N6 U2.N8 U2.N11 U2.N13 U2.N23 U2.N24 U2.N28 U2.P12 U2.P18 U2.P20 U2.P21 U2.P31 U2.P33 U2.R4 U2.R6 U2.R11 U2.R25 U2.R28 U2.T11 U2.T16 U2.T18 U2.T21 U2.T22 U2.T25 U2.T27 U2.U6 U2.U14 U2.U17 U2.U20 U2.U21 U2.U22 U2.U30 U2.U32 U2.V11 U2.V16 U2.V18 U2.V21 U2.V22 U2.V23 U2.V24 U2.V25 U2.W4 U2.W6 U2.W25 U2.W28 U2.Y14 U2.Y16 U2.Y18 U2.Y22 U6.11 U6.15 U15.11 U15.15 U16.11 U16.15 U64.3 U67.3 U68.3 U2407.6 UA1.49 UC1.A1 UC1.A7 UC1.A11 UC1.A15 UC1.A19 UC1.A23 UC1.A27 UC1.A31 UC1.A35 UC1.A37 UC1.AA10 UC1.AA13 UC1.AA16 UC1.AA19 UC1.AA22 UC1.AA25 UC1.AC1 UC1.AC7 UC1.AC14 UC1.AC17 UC1.AC21 UC1.AC24 UC1.AC28 UC1.AD3 UC1.AD10 UC1.AD13 UC1.AD16 UC1.AD19 UC1.AD22 UC1.AD25 UC1.AD27 UC1.AD28 UC1.AE1 UC1.AE4 UC1.AE11 UC1.AE14 UC1.AE19 UC1.AE21 UC1.AE27 UC1.AE28 UC1.AF7 UC1.AF24 UC1.AF28 UC1.AG1 UC1.AG4 UC1.AG14 UC1.AG17 UC1.AG21 UC1.AG25 UC1.AG27 UC1.AG28 UC1.AH13 UC1.AH16 UC1.AH19 UC1.AH22 UC1.AH30 UC1.AH31 UC1.AJ4 UC1.AJ24 UC1.AJ25 UC1.AK9 UC1.AK12 UC1.AK13 UC1.AK15 UC1.AK19 UC1.AK21 UC1.AK23 UC1.AK25 UC1.AK27 UC1.AK29 UC1.AK31 UC1.AK34 UC1.AL3 UC1.AL8 UC1.AL37 UC1.AM35 UC1.AN1 UC1.AN7 UC1.AN10 UC1.AN14 UC1.AN19 UC1.AN23 UC1.AN27 UC1.AN30 UC1.AN37 UC1.C2 UC1.C3 UC1.C6 UC1.C35 UC1.D4 UC1.D11 UC1.D13 UC1.D15 UC1.D17 UC1.D19 UC1.D21 UC1.D23 UC1.D25 UC1.D27 UC1.D29 UC1.D31 UC1.D33 UC1.E17 UC1.E31 UC1.E34 UC1.F11 UC1.F21 UC1.F24 UC1.F27 UC1.F30 UC1.G1 UC1.G13 UC1.G16 UC1.G19 UC1.G22 UC1.G25 UC1.G28 UC1.G34 UC1.G37 UC1.H8 UC1.H14 UC1.H17 UC1.H30 UC1.H32 UC1.J4 UC1.J6 UC1.J11 UC1.J16 UC1.J21 UC1.J24 UC1.J27 UC1.J28 UC1.J32 UC1.J34 UC1.K10 UC1.K13 UC1.K16 UC1.K19 UC1.K22 UC1.K25 UC1.K27 UC1.L1 UC1.L11 UC1.L14 UC1.L17 UC1.L21 UC1.L24 UC1.L28 UC1.M6 UC1.M9 UC1.N4 UC1.N10 UC1.N13 UC1.N16 UC1.N19 UC1.N22 UC1.N25 UC1.N28 UC1.P6 UC1.P9 UC1.P11 UC1.P14 UC1.P17 UC1.P21 UC1.P24 UC1.R1 UC1.T10 UC1.T13 UC1.T16 UC1.T19 UC1.T22 UC1.T25 UC1.U4 UC1.U6 UC1.U9 UC1.V11 UC1.V14 UC1.V17 UC1.V21 UC1.V25 UC1.W1 UC1.W4 UC1.W6 UC1.W9 UC1.Y3 UC1.Y11 UC1.Y14 UC1.Y17 UC1.Y21 UC1.Y24 UE1.11 UE1.24 UE1.35 UE1.94 UE1.113 UE3.5 UE3.6 UE3.7 UE3.8 UE4.5 UE4.9 UG1.4 UG1.7 UG1.13 UG1.17 UH1.3 UI5.2 UI6.2 UI7.2 UL1.33 UL2.2 UL3.2 US2.3 US2.21 USPI1.4 UV1.A3 UV1.A30 UV1.AA11 UV1.AA13 UV1.AA16 UV1.AA27 UV1.AB6 UV1.AB10 UV1.AB15 UV1.AB24 UV1.AB32 UV1.AC9 UV1.AC17 UV1.AC24 UV1.AC26 UV1.AC27 UV1.AD6 UV1.AD8 UV1.AD25 UV1.AD32 UV1.AE7 UV1.AE14 UV1.AE27 UV1.AF32 UV1.AG12 UV1.AG27 UV1.AH10 UV1.AH28 UV1.AH32 UV1.B6 UV1.B8 UV1.B10 UV1.B12 UV1.B14 UV1.B16 UV1.B18 UV1.B20 UV1.B22 UV1.B24 UV1.B26 UV1.C1 UV1.C32 UV1.E28 UV1.F2 UV1.F6 UV1.F8 UV1.F10 UV1.F12 UV1.F14 UV1.F16 UV1.F18 UV1.F20 UV1.F22 UV1.F24 UV1.F26 UV1.G8 UV1.G10 UV1.G27 UV1.G31 UV1.H2 UV1.H6 UV1.H14 UV1.H17 UV1.H20 UV1.J7 UV1.J27 UV1.J31 UV1.K2 UV1.K6 UV1.K11 UV1.K22 UV1.K28 UV1.K32 UV1.L27 UV1.M6 UV1.M12 UV1.M32 UV1.N11 UV1.N13 UV1.N16 UV1.N18 UV1.N21 UV1.N25 UV1.N27 UV1.P6 UV1.P9 UV1.P25 UV1.P32 UV1.R11 UV1.R12 UV1.R15 UV1.R17 UV1.R20 UV1.R27 UV1.T6 UV1.T11 UV1.T13 UV1.T16 UV1.T18 UV1.T21 UV1.T25 UV1.T32 UV1.U9 UV1.U15 UV1.U17 UV1.U20 UV1.U25 UV1.U27 UV1.V11 UV1.V13 UV1.V16 UV1.V18 UV1.V32 UV1.W25 UV1.W26 UV1.W27 UV1.Y10 UV1.Y15 UV1.Y17 UV1.Y20 UV1.Y25 UV1.Y32 UV2.3 UV3.5 UV4.3 UV5.A9 UV5.B1 UV5.B3 UV5.B9 UV5.D1 UV5.D8 UV5.E1 UV5.E2 UV5.E8 UV5.F9 UV5.G1 UV5.G8 UV5.G9 UV5.J2 UV5.J8 UV5.M1 UV5.M9 UV5.P1 UV5.P9 UV5.T1 UV5.T9 UV6.A9 UV6.B1 UV6.B3 UV6.B9 UV6.D1 UV6.D8 UV6.E1 UV6.E2 UV6.E8 UV6.F9 UV6.G1 UV6.G8 UV6.G9 UV6.J2 UV6.J8 UV6.M1 UV6.M9 UV6.P1 UV6.P9 UV6.T1 UV6.T9 UV7.A9 UV7.B1 UV7.B3 UV7.B9 UV7.D1 UV7.D8 UV7.E1 UV7.E2 UV7.E8 UV7.F9 UV7.G1 UV7.G8 UV7.G9 UV7.J2 UV7.J8 UV7.M1 UV7.M9 UV7.P1 UV7.P9 UV7.T1 UV7.T9 UV8.A9 UV8.B1 UV8.B3 UV8.B9 UV8.D1 UV8.D8 UV8.E1 UV8.E2 UV8.E8 UV8.F9 UV8.G1 UV8.G8 UV8.G9 UV8.J2 UV8.J8 UV8.M1 UV8.M9 UV8.P1 UV8.P9 UV8.T1 UV8.T9 UX4.2 X1.2 X1.4 Y1.2 Y1.4 YL2.2 YL2.4 YV1.2 YV1.4
GNDA: CA1.2 CA2.2 CA23.1 CA33.2 CA38.2 CA39.2 CA40.2 CA51.2 CA61.2 CA62.1 CA63.1 CA71.2 CA74.2 JHP.6 JHP.7 QA5.1 QA5.4 QA6.1 QA6.4 RA12.1 RA29.1 RA30.1 RA31.1 RA32.1 RA83.2 RA84.2 UA1.25 UA1.38
PVCC: PC515.1 PR520.1 PU500.50
V1: PQ708.2 PQ709.6 PQ713.6 PR702.2 PR714.2
VCC: PC514.1 PR521.1 PR555.2 PR561.2 PR569.2 PR573.2 PU500.5 PU500.6 PU500.9 PU500.10 PU500.28 PU500.33 PU500.34
VCCSENSE_VGA: PR1049.2 RV159.2 RV161.1
VDD_1.35V: PC209.1 PR205.1 PR206.2 PU200.11
VDDIO: PC1019.1 PR1022.2 PR1025.2 PU1000.6
VDDP_CAP: C79.1 C80.1 UC1.AC11
VDDP_LDO: PC714.1 PR709.1 PR710.1 PU700.21
VDDR4: UV1.U12 UV1.V12 UV1.Y12
VDDR_CAP: C77.1 C78.1 UC1.AC27
VIN: PC3.1 PC4.1 PL1.2 PQ704.5 PQ704.6 PQ704.7 PQ704.8 PR5.1 PR7.2 PR31.2 PR702.1 PR706.2 PR707.1 PR711.2 PR730.1
VSS_MECH: UV1.A32 UV1.AM1 UV1.AM32
VSSSENSE_VGA: PR1050.2 RV158.2 RV160.1
25M_X1: CH12.2 RH21.2 RH23.1 U2.C31 X1.1
25M_X2: CH15.2 RH23.2 U2.C33 X1.3
32K_X1: CH10.2 RH4.1 RH6.2 U2.G2 Y2.1
32K_X2: CH11.2 RH4.2 U2.G4 Y2.2
65W#/90W: T110.1(TP-1) UE1.117
#ECAD5: T104.1(TP-1) UE1.76
+A_VCC: RA10.2 RA11.2 RA28.2
+A_VCC_R: RA28.1 UA1.20
+APU_CORE: PC500.2 PC901.1 PC902.1 PC903.1 PC904.1 PC905.1 PC906.1 PC907.1 PC908.1 PC909.1 PC910.1 PC911.1 PC912.1 PC913.1 PC914.1 PC915.1 PC916.1 PC917.1 PC918.1 PC919.1 PC920.1 PC921.1 PC922.1 PC923.1 PC924.1 PL501.1 PR502.2 UC1.AA4 UC1.AA11 UC1.AA14 UC1.AA17 UC1.AA21 UC1.AA24 UC1.AB7 UC1.AC4 UC1.AC10 UC1.AC13 UC1.AC16 UC1.AC19 UC1.AC22 UC1.AC25 UC1.AD4 UC1.AD11 UC1.AD14 UC1.AD17 UC1.AD21 UC1.AD24 UC1.AE6 UC1.AE22 UC1.AE25 UC1.AF5 UC1.AF8 UC1.AG11 UC1.AH5 UC1.AH8 UC1.AH10 UC1.AK8 UC1.T11 UC1.T14 UC1.T17 UC1.T21 UC1.T24 UC1.V10 UC1.V13 UC1.V16 UC1.V19 UC1.V22 UC1.V24 UC1.Y7 UC1.Y10 UC1.Y13 UC1.Y16 UC1.Y19 UC1.Y22 UC1.Y25
+APU_CORE_NB: PC534.2 PC931.1 PC932.1 PC933.1 PC934.1 PC935.1 PC936.1 PC937.1 PC938.1 PC939.1 PC940.1 PC941.1 PC942.1 PC943.1 PC944.1 PC945.1 PC946.1 PC947.1 PC948.1 PC949.1 PC950.1 PC951.1 PC952.1 PL500.1 PR565.2 UC1.E8 UC1.F4 UC1.F5 UC1.G4 UC1.G8 UC1.G10 UC1.H3 UC1.H6 UC1.H10 UC1.J10 UC1.J13 UC1.J22 UC1.J25 UC1.K11 UC1.K14 UC1.K17 UC1.K21 UC1.K24 UC1.L4 UC1.L7 UC1.L10 UC1.L13 UC1.L16 UC1.L19 UC1.L22 UC1.L25 UC1.M3 UC1.N11 UC1.N14 UC1.N17 UC1.N21 UC1.N24 UC1.P10 UC1.P13 UC1.P16 UC1.P19 UC1.P22 UC1.P25 UC1.R4 UC1.R6 UC1.R9 UC1.T3
+BIF_VDDC: CV168.1 RV31.1 UV1.R21 UV1.U21
+CODEC_AVDD2: CA61.1 RA8.2 RA9.2 UA1.40
+DP_VDDC: CV33.1 CV34.1 RV30.2 UV1.AD14
+DP_VDDR: CV26.1 CV27.1 RV27.2 UV1.AF14
+EC_VCCA: CE7.1 LE1.2 PR24.2 UE1.67
+FAN_POWER: CE22.1 CE23.1 JFAN.1 UE3.3
+FBA_VREF0: CV100.1 RV42.2 RV44.1 UV5.H1 UV5.M8
+FBA_VREF1: CV101.1 RV43.2 RV45.1 UV6.H1 UV6.M8
+FBA_VREF2: CV133.1 RV50.2 RV52.1 UV7.H1 UV7.M8
+FBA_VREF3: CV134.1 RV51.2 RV53.1 UV8.H1 UV8.M8
+FCH_VDD_11_SSUSB_S: LH15.1 RH59.2 RH111.1 RH113.1
+INV_PWR_SRC: JEDP.39 JEDP.40 RX5.2
+INV_PWR_SRC_R: CX5.1 QX2.1 QX2.2 QX2.5 QX2.6 RX5.1
+LAN_IO: C8.1 UG1.8
+LAN_REGOUT: CL3.1 LL1.1 RL1.2 UL1.24
+LAN_VDD10: CL4.1 CL5.1 CL6.1 CL7.1 CL8.1 CL9.1 CL10.1 LL1.2 RL1.1 UL1.3 UL1.8 UL1.22 UL1.30
+LAN_VDD33: CL12.1 CL13.1 CL14.1 CL15.1 CL19.1 RL2.1 RL3.1 RL6.1 RL34.1 RL38.2 RL39.1 UL1.11 UL1.32
+LAN_VDD33_UL2: JP3.1 RL2.2 UL2.1
+LAN_VDD33_UL3: RL3.2 UL3.1
+LAN_VDDREG: CL16.2 CL17.1 RL6.2 UL1.23
+LCDVDD: LX1.1 UX4.1
+LCDVDD_CONN: CX2.1 CX3.1 CX8.1 CX11.1 CX31.1 JEDP.24 JEDP.25 LX1.2
+MA_VREF_DQ: C125.1 C126.1 C127.1 JDIMM1.1 R57.1 R58.1 R59.2
+MA_VREFDQ: R58.2 UC1.H11
+MEM_VREF: C29.1 C30.2 R5.1 R8.2 UC1.V36
+MIC2-VREFO: RA53.2 RA1109.2 UA1.29
+MPLL_PVDD: CV81.1 CV82.1 CV83.1 LV6.2 UV1.L8
+MVREFDA: CV94.1 RV33.2 RV34.1 UV1.K26
+MVREFSA: CV95.1 RV32.2 RV35.1 UV1.J26
+RTCBATT: JRTC.1 RH19.1
+SPLL_PVDD: CV84.1 CV85.1 CV86.1 LV7.2 UV1.H7
+SPLL_VDDC: CV91.1 CV92.1 CV93.1 LV8.2 UV1.H8
+TSVDD: CV19.1 CV20.1 CV21.1 LV2.2 UV1.AD17
+V_EC: RE9.1 RE10.1 RE12.2 RE13.2
+V_TP: J519.1 RE330.2 RE331.2 UE4.1 UE4.2 UE4.4
+V_UV4: CV22.1 RV93.2 RV94.2 UV4.5
+VCOIN: DH1.2 R796.1 RH19.2
+VCOIN_RTC: CLRP1.1 DH1.1 DH2.1 R787.1 R790.1 RA5.1 RA11.1 RH22.2 RH24.1
+VDISPLAY_VCC: CX21.1 CX22.1 FX1.1 JHDMI.18 RP60.5 RP60.6
+VGA_CORE: CV67.1 CV68.1 CV69.1 CV70.1 CV71.1 CV72.1 CV73.1 CV74.1 CV75.1 CV76.1 CV77.1 CV78.1 CV79.1 CV80.1 LV25.2 LV26.2 PC836.1 PC837.1 PC838.1 PC839.1 PC840.1 PC841.1 PC842.1 PC843.1 PC844.1 PC845.1 PC846.1 PC847.1 PC848.1 PC849.1 PC850.1 PC851.1 PC852.1 PC853.1 PC854.1 PC855.1 PC856.1 PC857.1 PC858.1 PC859.1 PC860.1 PC869.1 PC871.1 PC872.1 PL1002.4 PL1003.4 RV60.2 RV161.2 UV1.AA12 UV1.AA15 UV1.AB11 UV1.AB12 UV1.AB13 UV1.AC14 UV1.M11 UV1.N12 UV1.N15 UV1.N17 UV1.R13 UV1.R16 UV1.R18 UV1.T10 UV1.T12 UV1.T15 UV1.T17 UV1.T20 UV1.U10 UV1.U11 UV1.U13 UV1.U16 UV1.U18 UV1.V15 UV1.V17 UV1.V20 UV1.V21 UV1.W9 UV1.W10 UV1.Y9 UV1.Y13 UV1.Y16 UV1.Y18 UV1.Y21
+VGA_PCIE: CV54.1 CV55.1 CV56.1 CV57.1 CV58.1 CV59.1 CV60.1 LV8.1 PJP1300.1 RV1.2 RV3.2 RV30.1 RV31.2 UV1.L23 UV1.L24 UV1.L25 UV1.L26 UV1.M22 UV1.N22 UV1.N23 UV1.N24 UV1.R22 UV1.T22 UV1.U22 UV1.V22
+VGA_PCIEP: PC1300.1 PC1303.1 PC1305.1 PC1306.1 PC1308.1 PJP1300.2 PL1300.2 PR1302.1
+VREF_CA: C122.1 C123.1 C124.1 JDIMM1.126 R55.1 R56.2
A_RST#: RH3.2 U2.AD5
ACIN: CE18.2 PR1.1 PR710.2 PR712.1 PR716.1 PU700.13 RV149.1 UE1.110 UV4.1
ACIN_65W: QV8.2 RE80.2 RV92.2 RV149.2 UV4.2
ACOFF: PQ713.5 PR718.1 UE1.27
ACSETIN: PC712.2 PR711.1 PR715.2 PU700.2
AD_BID0: CE8.1 RE3.1 RE5.2 UE1.66
ADP_I: PC725.2 PR23.2 PR722.1 UE1.65
ADPIN: PC1.1 PC2.1 PJPDC.4 PJPDC.5 PL1.1
ALLOW_STOP: Q3.3 R24.2 U2.G25
APU_ALERT#: RP2.6 T126.1(TP-1) UC1.AN15
APU_ALERT#_EC: T128.1(TP-1) UE1.99
APU_ALERT#_FCH: RPH1.4 T127.1(TP-1) U2.M6
APU_ALLOW_STOP: C53.1 Q3.1 R24.1 RP2.5 UC1.AM15
APU_COREYYPE: R32.1 UC1.D16
APU_DBRDY: JHDT1.14 UC1.A13
APU_DBREQ#: JHDT1.16 RP1.1 UC1.B13
APU_DP2_N0: CV185.2 CX18.1
APU_DP2_N1: CV187.2 CX16.1
APU_DP2_N2: CV189.2 CX14.1
APU_DP2_N3: CV191.2 CX12.1
APU_DP2_P0: CV184.2 CX19.1
APU_DP2_P1: CV186.2 CX17.1
APU_DP2_P2: CV188.2 CX15.1
APU_DP2_P3: CV190.2 CX13.1
APU_EDP0_AUXN: C4322.2 RC9.2 UC1.AG10
APU_EDP0_AUXP: C4321.2 RC8.2 UC1.AG8
APU_EDP0_TXN0: C4311.1 UC1.AM5
APU_EDP0_TXN1: C4313.1 UC1.AM4
APU_EDP0_TXP0: C4312.1 UC1.AL6
APU_EDP0_TXP1: C4314.1 UC1.AN5
APU_ENVDD: RP16.8 RX7.2 U67.4
APU_HDMI_CLK: QX4.1 RP60.1 UC1.B6
APU_HDMI_DATA: QX4.4 RP60.2 UC1.B7
APU_INVT_PWM: JEDP.36 RP16.5 RX26.1 U68.4
APU_PCIE_RST#: RH27.1 RH28.2 UH1.4 UV2.1
APU_PCIE_RST#_C: RH25.1 U2.AE2
APU_PROCHOT#: PC728.1 PQ2.6 PR539.1 QC1.1 R29.1 R33.1 RH18.2 UC1.AL10
APU_PROCHOT#_R: RH18.1 U2.E28
APU_PWRGD: C54.1 D29.2 PU500.19 R37.2 R40.2 R446.1 U2.E26
APU_PWRGD_BUF: D29.1 JHDT1.10 R121.1
APU_PWRGD_R: R446.2 UC1.AL12
APU_RST#: C55.1 D30.2 R36.2 R39.2 R445.1 U2.F26
APU_RST#_BUF: D30.1 JHDT1.12 R122.1
APU_RST#_R: R445.2 UC1.AM14
APU_RSVD_1: T12.1(TP-1) UC1.A17
APU_RSVD_2: T13.1(TP-1) UC1.K28
APU_RSVD_15: R27.1 R28.1 UC1.AK10
APU_SIC: Q78.3 RP2.7 UC1.AL14
APU_SIC_R: Q10.3 Q78.4
APU_SID: Q2507.6 RP2.8 UC1.AK14
APU_SID_R: Q9.3 Q2507.1
APU_SVC: PU500.20 R65.2 UC1.B16
APU_SVD: PU500.21 R120.2 UC1.C16
APU_SVT: PU500.22 R35.2 UC1.A16
APU_TCK: JHDT1.2 RP1.2 UC1.B15
APU_TDI: JHDT1.6 RP1.4 UC1.A14
APU_TDO: JHDT1.8 UC1.C14
APU_TEST4: T10.1(TP-1) UC1.T27
APU_TEST5: T11.1(TP-1) UC1.T28
APU_TEST14: R15.1 UC1.C10
APU_TEST15: T3.1(TP-1) UC1.B9
APU_TEST16: R16.1 UC1.A10
APU_TEST17: R17.1 UC1.B10
APU_TEST18: JHDT1.20 RPC1.2 UC1.A12
APU_TEST19: JHDT1.18 RPC1.1 UC1.B12
APU_TEST20: RPC1.3 UC1.C8
APU_TEST24: RPC1.4 UC1.D8
APU_TEST25_H: R22.1 UC1.AM12
APU_TEST25_L: R23.1 UC1.AN12
APU_TEST28_H: T4.1(TP-1) UC1.A8
APU_TEST28_L: T5.1(TP-1) UC1.B8
APU_TEST31: R25.1 R26.1 UC1.V28
APU_THERMTRIP#: Q12.3 R622.1 UC1.AK11
APU_TMS: JHDT1.4 RP1.3 UC1.B14
APU_TRST#: C936.1 JHDT1.9 R38.2 UC1.D14
APU_VDD_SEN_H: PC506.2 PC509.1 PR502.1 PR511.1 PU500.11 T131.1(TP-1) UC1.D9
APU_VDD_SEN_L: PC506.1 PC531.1 PR500.2 PU500.14 T130.1(TP-1) UC1.E10
APU_VDDNB_SEN_H: PC530.1 PC531.2 PR552.1 PR565.1 PU500.32 T132.1(TP-1) UC1.D10
AUD_HP_OUT_L_CN: CA39.1 DA10.3 JHP.1 LA8.1
AUD_HP_OUT_R_CN: CA33.1 DA10.2 JHP.2 LA9.1
B+: CX4.1 PC502.1 PL102.1 PL201.1 PL301.2 PL502.2 PL701.1 PL1000.2 PL1100.2 PQ706.1 PQ706.2 PQ706.3 PR700.4 QX2.4 RX2.1
BAT_ALERT: PBATT.3 PD1.2
BATT+: PC7.1 PC9.1 PC717.1 PC718.1 PC719.1 PC720.1 PL3.1 PL5.1 PQ706.5 PQ706.6 PQ706.7 PQ706.8 PR720.4 PR726.2
BATT++: PBATT.8 PBATT.9 PC8.1 PL3.2 PL5.2
BATT_CHG_LED#: JLED.6 UE1.92
BATT_LOW_LED#: JLED.5 UE1.93
BATT_PRS: PBATT.5 PD1.3 PR15.1
BATT_TEMP: CE9.2 PC708.1 PQ710.2 PQ710.5 PQ713.2 PQ714.2 PR15.2 PR16.1 UE1.63
BEEP#: DA8.2 UE1.23
BKOFF#: DX1.2 UE1.105
BOOT1: PR1034.1 PU1000.21
BOOT2: PR1055.1 PU1000.30
BOOT_1.35V: PR200.2 PU200.18
BOOT_APU1: PR542.1 PU500.46
BOOT_APU1-1: PC524.1 PR542.2
BOOT_NB1: PR510.1 PU500.42
BOOT_NB1-1: PC507.1 PR510.2
BP_0: RV82.1 UV1.U1
BP_1: RV81.1 UV1.U3
BST: PR713.2 PU700.25
BST_1.35V: PC200.1 PR200.1
BST_3V: PR103.2 PU100.9
BST_5V: PR111.1 PU100.17
BST_+1.05VSP: PR302.1 PU300.10
BST_+1.35VGPUP: PR1101.1 PU1100.10
BST_CHGA: PC713.1 PR713.1
BT_LED_EC: RE38.2 T112.1(TP-1) UE1.36
BT_ON#: JNGFF.46 RH41.2 U2.AJ16
CAPS_LED: JKB.1 UE1.91
CHG: PL700.2 PR720.1
CHG_B+: PC702.1 PC703.1 PC704.1 PC705.1 PL701.2 PQ701.5
CLK_APU: U2.T24 UC1.AM13
CLK_APU#: U2.T23 UC1.AN13
CLK_APU_DISP: U2.R26 UC1.AM11
CLK_APU_DISP#: U2.T26 UC1.AN11
CLK_CALRN: RH7.2 U2.F27
CLK_EC33M: RH14.1 U2.B25
CLK_LAN_25M: RH17.2 RH20.1 RL21.2
CLK_LAN_25M_R: RH20.2 U2.J26
CLK_PCI_EC: RE6.1 RH14.2 RH117.2 RH129.1 UE1.12
CLK_PCIE_LAN: RH15.1 UL1.15
CLK_PCIE_LAN#: RH16.1 UL1.16
CLK_PCIE_LAN#_R: RH16.2 U2.E31
CLK_PCIE_LAN_R: RH15.2 U2.E33
CLK_PCIE_MINI1: JNGFF.39 RH12.1
CLK_PCIE_MINI1#: JNGFF.41 RH13.1
CLK_PCIE_MINI1#_R: RH13.2 U2.F31
CLK_PCIE_MINI1_R: RH12.2 U2.F33
CLK_PCIE_VGA#_R: RH11.2 U2.K29
CLK_PCIE_VGA_R: RH10.2 U2.J30
CLK_PEG_VGA: RH10.1 UV1.AK30
CLK_PEG_VGA#: RH11.1 UV1.AK32
CLK_SMB: PBATT.7 PD2.3 PR18.1
CLK_USB30_48M: T98.1(TP-1) U2.G8
CLK_X1: C11.1 UG1.1 Y1.1
CLK_X2: C12.1 UG1.16 Y1.3
COMP: PC510.2 PR513.2 PU500.13
COMPA: PC529.2 PR550.2 PU500.30
CPU_B+: PC503.1 PC504.1 PC505.1 PC518.1 PC519.1 PC520.1 PC521.1 PC522.1 PC523.1 PL502.1 PQ500.1 PQ501.1 PR514.2 PR530.2
CPU_DPB_CTRLCLK_R: JHDMI.15 QX4.6 RP60.4
CPU_DPB_CTRLDAT_R: JHDMI.16 QX4.3 RP60.3
CS1: PR105.1 PU100.1
CS2: PR108.1 PU100.5
CS_1.35V: PR205.2 PU200.13
CSIN: PR700.3 PR705.1
CSIP: PR700.2 PR704.1
DAT_SMB: PBATT.6 PD2.2 PR20.1
DBC_EN: RX23.1 UE1.25
DBC_EN_R: JEDP.23 RX23.2 RX36.1
DCIN: PC711.1 PR707.2 PU700.22
DDRA_CKE0: JDIMM1.73 UC1.L33
DDRA_CKE1: JDIMM1.74 UC1.L30
DDRA_CLK0: JDIMM1.101 UC1.Y30
DDRA_CLK0#: JDIMM1.103 UC1.Y29
DDRA_CLK1: JDIMM1.102 UC1.Y32
DDRA_CLK1#: JDIMM1.104 UC1.Y33
DDRA_ODT0: JDIMM1.116 UC1.AH34
DDRA_ODT1: JDIMM1.120 UC1.AH33
DDRA_SBS0#: JDIMM1.109 UC1.AC33
DDRA_SBS1#: JDIMM1.108 UC1.AB30
DDRA_SBS2#: JDIMM1.79 UC1.M34
DDRA_SCAS#: JDIMM1.115 UC1.AF34
DDRA_SCS0#: JDIMM1.114 UC1.AE31
DDRA_SCS1#: JDIMM1.121 UC1.AG31
DDRA_SDM0: JDIMM1.11 UC1.E13
DDRA_SDM1: JDIMM1.28 UC1.D18
DDRA_SDM2: JDIMM1.46 UC1.H22
DDRA_SDM3: JDIMM1.63 UC1.H27
DDRA_SDM4: JDIMM1.136 UC1.AG30
DDRA_SDM5: JDIMM1.153 UC1.AK26
DDRA_SDM6: JDIMM1.170 UC1.AK20
DDRA_SDM7: JDIMM1.187 UC1.AF14
DDRA_SDQ0: JDIMM1.5 UC1.H13
DDRA_SDQ1: JDIMM1.7 UC1.F13
DDRA_SDQ2: JDIMM1.15 UC1.H16
DDRA_SDQ3: JDIMM1.17 UC1.F16
DDRA_SDQ4: JDIMM1.4 UC1.G11
DDRA_SDQ5: JDIMM1.6 UC1.E11
DDRA_SDQ6: JDIMM1.16 UC1.E14
DDRA_SDQ7: JDIMM1.18 UC1.J14
DDRA_SDQ8: JDIMM1.21 UC1.J17
DDRA_SDQ9: JDIMM1.23 UC1.F17
DDRA_SDQ10: JDIMM1.33 UC1.H21
DDRA_SDQ11: JDIMM1.35 UC1.E21
DDRA_SDQ12: JDIMM1.22 UC1.E16
DDRA_SDQ13: JDIMM1.24 UC1.G17
DDRA_SDQ14: JDIMM1.34 UC1.F19
DDRA_SDQ15: JDIMM1.36 UC1.D20
DDRA_SDQ16: JDIMM1.39 UC1.D22
DDRA_SDQ17: JDIMM1.41 UC1.E22
DDRA_SDQ18: JDIMM1.51 UC1.D26
DDRA_SDQ19: JDIMM1.53 UC1.E25
DDRA_SDQ20: JDIMM1.40 UC1.G21
DDRA_SDQ21: JDIMM1.42 UC1.F22
DDRA_SDQ22: JDIMM1.50 UC1.G24
DDRA_SDQ23: JDIMM1.52 UC1.H24
DDRA_SDQ24: JDIMM1.57 UC1.E27
DDRA_SDQ25: JDIMM1.59 UC1.G27
DDRA_SDQ26: JDIMM1.67 UC1.E30
DDRA_SDQ27: JDIMM1.69 UC1.G30
DDRA_SDQ28: JDIMM1.56 UC1.F25
DDRA_SDQ29: JDIMM1.58 UC1.H25
DDRA_SDQ30: JDIMM1.68 UC1.D30
DDRA_SDQ31: JDIMM1.70 UC1.H28
DDRA_SDQ32: JDIMM1.129 UC1.AJ31
DDRA_SDQ33: JDIMM1.131 UC1.AK32
DDRA_SDQ34: JDIMM1.141 UC1.AK28
DDRA_SDQ35: JDIMM1.143 UC1.AF27
DDRA_SDQ36: JDIMM1.130 UC1.AJ33
DDRA_SDQ37: JDIMM1.132 UC1.AK33
DDRA_SDQ38: JDIMM1.140 UC1.AH28
DDRA_SDQ39: JDIMM1.142 UC1.AJ28
DDRA_SDQ40: JDIMM1.147 UC1.AF25
DDRA_SDQ41: JDIMM1.149 UC1.AH25
DDRA_SDQ42: JDIMM1.157 UC1.AG22
DDRA_SDQ43: JDIMM1.159 UC1.AJ22
DDRA_SDQ44: JDIMM1.146 UC1.AH27
DDRA_SDQ45: JDIMM1.148 UC1.AJ27
DDRA_SDQ46: JDIMM1.158 UC1.AE24
DDRA_SDQ47: JDIMM1.160 UC1.AF22
DDRA_SDQ48: JDIMM1.163 UC1.AH21
DDRA_SDQ49: JDIMM1.165 UC1.AJ21
DDRA_SDQ50: JDIMM1.175 UC1.AF17
DDRA_SDQ51: JDIMM1.177 UC1.AJ17
DDRA_SDQ52: JDIMM1.164 UC1.AK22
DDRA_SDQ53: JDIMM1.166 UC1.AF21
DDRA_SDQ54: JDIMM1.174 UC1.AJ19
DDRA_SDQ55: JDIMM1.176 UC1.AE17
DDRA_SDQ56: JDIMM1.181 UC1.AF16
DDRA_SDQ57: JDIMM1.183 UC1.AJ16
DDRA_SDQ58: JDIMM1.191 UC1.AF13
DDRA_SDQ59: JDIMM1.193 UC1.AE13
DDRA_SDQ60: JDIMM1.180 UC1.AH17
DDRA_SDQ61: JDIMM1.182 UC1.AE16
DDRA_SDQ62: JDIMM1.192 UC1.AJ13
DDRA_SDQ63: JDIMM1.194 UC1.AG13
DDRA_SDQS0: JDIMM1.12 UC1.F14
DDRA_SDQS0#: JDIMM1.10 UC1.G14
DDRA_SDQS1: JDIMM1.29 UC1.H19
DDRA_SDQS1#: JDIMM1.27 UC1.J19
DDRA_SDQS2: JDIMM1.47 UC1.D24
DDRA_SDQS2#: JDIMM1.45 UC1.E24
DDRA_SDQS3: JDIMM1.64 UC1.F28
DDRA_SDQS3#: JDIMM1.62 UC1.E28
DDRA_SDQS4: JDIMM1.137 UC1.AJ30
DDRA_SDQS4#: JDIMM1.135 UC1.AK30
DDRA_SDQS5: JDIMM1.154 UC1.AH24
DDRA_SDQS5#: JDIMM1.152 UC1.AG24
DDRA_SDQS6: JDIMM1.171 UC1.AG19
DDRA_SDQS6#: JDIMM1.169 UC1.AF19
DDRA_SDQS7: JDIMM1.188 UC1.AH14
DDRA_SDQS7#: JDIMM1.186 UC1.AJ14
DDRA_SMA0: JDIMM1.98 UC1.AB31
DDRA_SMA1: JDIMM1.97 UC1.U33
DDRA_SMA2: JDIMM1.96 UC1.U32
DDRA_SMA3: JDIMM1.95 UC1.R30
DDRA_SMA4: JDIMM1.92 UC1.T34
DDRA_SMA5: JDIMM1.91 UC1.R31
DDRA_SMA6: JDIMM1.90 UC1.R33
DDRA_SMA7: JDIMM1.86 UC1.P33
DDRA_SMA8: JDIMM1.89 UC1.P32
DDRA_SMA9: JDIMM1.85 UC1.P30
DDRA_SMA10: JDIMM1.107 UC1.AD34
DDRA_SMA11: JDIMM1.84 UC1.P34
DDRA_SMA12: JDIMM1.83 UC1.M30
DDRA_SMA13: JDIMM1.119 UC1.AF33
DDRA_SMA14: JDIMM1.80 UC1.M31
DDRA_SMA15: JDIMM1.78 UC1.L32
DDRA_SRAS#: JDIMM1.110 UC1.AC32
DDRA_SWE#: JDIMM1.113 UC1.AE33
DEVSLP0: RH135.2 RS8.1 U2.AE26
DEW1: RS34.1 RS36.1 US2.16
DEW2: RS33.1 RS35.1 US2.6
DH_1.35V: PR209.2 PU200.17
DH_CHG: PQ701.4 PU700.24
DIR: CV167.2 CV169.2 RV79.1 U1.5
DISPOFF#: DX1.1 JEDP.37 RX9.1
DL_1.35V: PQ201.4 PU200.15
DL_CHG: PQ703.4 PU700.20
DP0_HPD: Q20.3 R384.2 R407.1 UC1.AH7
DP1_HPD: R14.1 UC1.B3
DP2_HPD: QX5.3 RX14.1 UC1.D7
DP2_TXN0_R: CV185.1 UC1.A3
DP2_TXN1_R: CV187.1 UC1.A4
DP2_TXN2_R: CV189.1 UC1.B5
DP2_TXN3_R: CV191.1 UC1.A6
DP2_TXP0_R: CV184.1 UC1.A2
DP2_TXP1_R: CV186.1 UC1.B4
DP2_TXP2_R: CV188.1 UC1.C4
DP2_TXP3_R: CV190.1 UC1.A5
DP_AUX_ZVSS: R13.1 UC1.D3
DP_ENBKL: RP15.7 U64.2 UC1.D12
DP_ENVDD: RP15.8 U67.2 UC1.B11
DP_INT_PWM: RP15.5 U68.2 UC1.C12
DP_STEREOSYNC: R30.1 R31.1 UC1.A9
DP_VSSR: UV1.AF19 UV1.AF20 UV1.AF23 UV1.AG14 UV1.AG23 UV1.AH14 UV1.AM14 UV1.AM16 UV1.AM18 UV1.AM20 UV1.AM22 UV1.AM24
DRAM_RST: CV97.1 RV37.1 RV38.1 UV1.L10
DRAM_RST#: RV36.1 UV5.T2 UV6.T2 UV7.T2 UV8.T2
EC_CRY2: CE17.2 RE43.2 RE45.1 UE1.123
EC_ENVDD: RX8.2 UE1.71
EC_LID_OUT#: CE27.1 RH73.2 U2.R2 UE1.101
EC_MUTE#: UA1.47 UE1.83
EC_ON: PR102.1 UE1.112
EC_PME#: RE21.2 RE61.2 UE1.29
EC_PWM2: RH119.2 RH131.1 U2.J22
EC_RSMRST#: CE26.1 RE47.1 RH90.2 U2.U2 UE1.100
EC_RST#: CE11.1 RE8.1 UE1.37
EC_RX: JNGFF.32 UE1.31
EC_SCI#: CH91.1 CH92.1 RE32.2 U2.R9 UE1.20
EC_SMB_CK1: PR18.2 PR717.1 RE26.1
EC_SMB_CK1_R: RE26.2 RPE1.8 UE1.77
EC_SMB_CK2: Q10.1 QV1.6 RE28.1 U2407.10
EC_SMB_CK2_R: RE28.2 RPE1.6 UE1.79
EC_SMB_DA1: PR20.2 PR719.1 RE27.1
EC_SMB_DA1_R: RE27.2 RPE1.7 UE1.78
EC_SMB_DA2: Q9.1 QV1.3 RE29.1 U2407.9
EC_SMB_DA2_R: RE29.2 RPE1.5 UE1.80
EC_SMI#: RE16.2 U2.C26 UE1.15
EC_SPI_CLK: RH70.1 UE1.126
EC_SPI_CS1#: RH65.1 UE1.128
EC_SPI_MISO: RH67.1 UE1.119
EC_SPI_MOSI: RH69.1 UE1.120
EC_TX: JNGFF.30 RM11.1 UE1.30
ECAGND: CE7.2 CE9.1 LE2.2 PH1.2 UE1.69
ECPWM1: T103.1(TP-1) UE1.26
EDP0_AUXN_C: C4322.1 JEDP.8 R617.2
EDP0_AUXP_C: C4321.1 JEDP.7 R616.1
EDP0_TXN0_C: C4311.2 JEDP.2
EDP0_TXN1_C: C4313.2 JEDP.5
EDP0_TXP0_C: C4312.2 JEDP.1
EDP0_TXP1_C: C4314.2 JEDP.4
EDP_HPD: JEDP.10 Q20.1 R365.1 R407.2
EN_0.675VSP: PC203.1 PR202.2 PU200.7
EN_1.35V: PC202.1 PR201.2 PU200.8
EN_+1.05VSP: PC306.1 PR303.2 PU300.3
EN_+1.35VGPUP: PC1104.1 PR1103.2 PU1100.3
EN_DFAN1: UE1.70 UE3.4
EN_INVPWR: QV7.2 RX4.1 UE1.68
EN_PCIE: PC1307.1 PR1300.2 PR1304.1 PU1300.5
ENABLE: PR1027.2 PU1000.8
ENBKL: RP16.7 U64.4 UE1.97
ENVDD_R: RX7.1 RX8.1 UX4.4
F_192-: QH2.5 QH2.6 RH81.2
FAN_SPEED1: CE24.1 CE29.1 JFAN.2 RE50.2 UE1.28
FB: PC509.2 PC510.1 PR508.2 PR511.2 PR513.1 PU500.12
FB_1.1V: PC402.2 PR403.2 PR405.1 PU400.6
FB_1.5V: PC311.2 PR309.2 PR313.1 PU301.6
FB_1.8V: PC412.2 PR407.2 PR410.1 PU401.6
FB_1.35V: PC214.1 PR204.1 PR207.1 PU200.6
FB_3V: PC102.2 PR107.2 PR109.2 PU100.4
FB_5V: PC108.1 PR104.1 PR106.1 PU100.2
FB_+1.05VSP: PR306.1 PR307.1 PU300.4
FB_+1.35VGPUP: PR1107.1 PR1108.1 PU1100.4
FB_GND: RV158.1 UV1.AD20
FB_PCIE: PC1306.2 PR1301.1 PR1302.2 PU1300.6
FB_VDDC: RV159.1 UV1.AC20
FB_VDDCI: T222.1(TP-1) UV1.W1
FBA: PC529.1 PC530.2 PR550.1 PR552.2 PR557.2 PU500.31
FCH_GPIO191: D7.2 RH74.1 U2.D23
FCH_GPIO192: D6.2 RH76.1 RH77.2 U2.C22
FCH_GPIO192_R: QH2.2 RH77.1
FCH_PCIE_WAKE#: RE61.1 RH66.2 RH88.2 RL34.2 UL1.21
FCH_PCIE_WAKE#_R: RH66.1 U2.K1
FCH_POK: RH52.1 UE1.32
FCH_PWRGD: CH23.1 RH51.2 RH52.2 U2.N7
FCH_RTCX1: RH6.1 UG1.9
FCH_SCLK0: JDIMM1.202 RH79.2 U2.AD26
FCH_SCLK1: QH31.6 RPH5.8 U2.T7
FCH_SCLK1_TP: QH31.1 RE337.1 RPH5.6
FCH_SCLK1_TP_R: JTP.6 RE337.2
FCH_SCLK4: QX6.3 RX38.1 U2.G22
FCH_SCLK4_R: JEDP.17 QX6.4 RX38.2 RX39.2
FCH_SDATA0: JDIMM1.200 RH80.2 U2.AD25
FCH_SDATA1: QH31.3 RPH5.7 U2.R7
FCH_SDATA1_TP: QH31.4 RE336.1 RPH5.5
FCH_SDATA1_TP_R: JTP.7 RE336.2
FCH_SDATA4: QX7.6 RX37.1 U2.G21
FCH_SDATA4_R: JEDP.16 QX7.1 RX37.2 RX40.2
FCH_SPI_CLK: RH29.1 RH70.2 U2.V3 USPI1.6
FCH_SPI_CS1#: RH65.2 RPH6.8 U2.T6 USPI1.1
FCH_SPI_HOLD#: RH64.2 RPH6.5 USPI1.7
FCH_SPI_HOLD#_R: RH64.1 U2.Y6
FCH_SPI_MISO: RH34.2 RH67.2 USPI1.2
FCH_SPI_MISO_R: RH34.1 U2.V6
FCH_SPI_MOSI: RH35.1 RH69.2 USPI1.5
FCH_SPI_MOSI_R: RH35.2 U2.V5
FCH_SPI_WP#: RPH6.6 U2.V1 USPI1.3
FCH_SPKR: DA8.3 U2.AF24
GATEA20: U2.AE22 UE1.1
GBE_PHY_INTR: RPH6.7 U2.W9
GPIO19_CTF: RV151.2 RV152.1 UV1.M2
GPIO28: RV21.2 UV1.R5
GPIO168: RPH7.6 U2.Y5
GPIO169: RPH7.7 U2.Y3
GPIO170: RPH7.8 U2.Y1
GPIO172: RPH3.3 U2.K5
GPIO173: RPH3.4 U2.K3
GPIO175: RPH2.1 U2.N2
GPIO176: RPH2.4 U2.M3
GPIO177: RPH3.2 U2.L2
GPIO178: RPH2.2 U2.N4
GPIO179: RPH1.3 U2.P1
GPIO180: RPH1.2 U2.P3
GPIO181: RPH2.3 U2.M1
GPIO182: RPH3.1 U2.M5
GPIO189: RH86.2 RH93.1 U2.D21
GPIO190: RH85.2 RH92.1 U2.C20
GPU_AC_LIGHT: RE80.1 T106.1(TP-1) UE1.108
GPU_B+: PC1023.1 PC1024.1 PC1025.1 PC1041.1 PC1042.1 PC1045.1 PC1046.1 PC1047.1 PC1048.1 PC1049.1 PC1052.1 PL1000.1 PQ1003.5 PQ1005.5
GPU_VID1: RV76.1 UV1.P8
GPU_VID1_GPIO_20: RV72.1 RV74.2 RV76.2 U1.3
GPU_VID3: RV75.1 UV1.N1
GPU_VID3_GPIO_15: RV71.1 RV73.2 RV75.2 U1.2
H_PROCHOT#_EC: QC1.2 QE30.1 R33.2 RC13.2 RE44.2
H_THERMTRIP#: R623.2 RH89.2 U2.R10
HDA_BITCLK: RPH10.7 U2.AB3
HDA_BITCLK_AUDIO: RA1112.1 RH91.2 RPH10.2 UA1.6
HDA_RST#: RPH10.5 U2.AE4
HDA_RST_AUDIO#: RA6.1 RPH10.4 UA1.11
HDA_SDIN0: RA130.1 RH94.2 U2.AA2
HDA_SDOUT: RPH10.8 U2.AB1
HDA_SDOUT_AUDIO: RPH10.1 UA1.5
HDA_SYNC: RPH10.6 U2.AD6
HDA_SYNC_AUDIO: RPH10.3 UA1.10
HDD_A0_PRE0: RS24.1 RS27.2 US2.9
HDD_A0_PRE1: RS23.1 RS30.2 US2.19
HDD_B0_EQ: RS37.1 RS38.1 US2.13
HDD_B0_PRE0: RS21.1 RS28.2 US2.8
HDD_B0_PRE1: RS18.1 RS29.2 US2.17
HDD_DET#: RS9.1 U2.AH17
HDD_DET#_R: JHDD.8 RS9.2
HDD_LED#: JLED.7 RH39.2 U2.AD22
HDD_REXT_SATA0: RS26.2 RS31.1 US2.20
HDMI_HPLUG: CX20.1 JHDMI.19 RX15.2 RX34.1
HPOUT-L: RA55.1 UA1.32
HPOUT-R: RA56.1 UA1.33
IBIAS: PR540.2 PU500.29
IMON: PR526.1 PU500.15
IMON_GPU: PC1022.2 PR1029.2 PU1000.10
IMONA: PR527.1 PU500.17
INT-SPK-L+: LA6.1 UA1.42
INT-SPK-L-: LA5.1 UA1.43
INT-SPK-R+: LA4.1 UA1.45
INT-SPK-R-: LA3.1 UA1.44
ISEN1: PC1051.2 PR1058.1 PU1000.13
ISEN1N: PR558.1 PU500.7
ISEN1N-1: PC525.1 PC532.1 PL501.2 PR549.2 PR558.2
ISEN1P: PC525.2 PR545.2 PR549.1 PU500.8
ISEN2: PC1050.2 PR1059.1 PU1000.12
ISENA1N: PR519.1 PU500.35
ISENA1N-1: PC508.1 PC512.1 PL500.2 PR518.2 PR519.2
ISENA1P: PC508.2 PR515.2 PR518.1 PU500.36
ISL88731_ICREF: PR727.1 PR729.2 PU700.1
ISL88731_VREF: PR725.2 PR727.2 PU700.3
ISOLATEB: RL33.2 RL35.2 UL1.20
JACK_PLUG#: JHP.5 RA1.2 RA3.1 RA4.1
JACK_SENSE#: QA5.3 RA4.2 RA34.2
JHDD_P10: JHDD.7 RS8.2
JTAG_TCK: RP34.5 UV1.L3
JTAG_TDI: RP34.7 UV1.L5
JTAG_TDO: T86.1(TP-1) UV1.K4
JTAG_TMS: RP34.6 UV1.L1
JTAG_TRSTB: RP34.8 UV1.L6
KB_BL_PWM: JKBBL.4 QE5.1 QE5.2 QE5.5 QE5.6
KB_CAPS_PWR: JKB.4 RE60.2
KB_DET#: QE4.1 RE68.1 U2.W8
KB_LED_PWM: QE5.3 UE1.21
KB_RST#: U2.AG19 UE1.2
KSI0: JKB.22 UE1.55
KSI1: JKB.24 UE1.56
KSI2: JKB.26 UE1.57
KSI3: JKB.23 UE1.58
KSI4: JKB.27 UE1.59
KSI5: JKB.25 UE1.60
KSI6: JKB.28 UE1.61
KSI7: JKB.29 UE1.62
KSO0: JKB.13 UE1.39
KSO1: JKB.15 RE62.2 UE1.40
KSO2: JKB.14 RE63.2 UE1.41
KSO3: JKB.16 UE1.42
KSO4: JKB.20 UE1.43
KSO5: JKB.21 UE1.44
KSO6: JKB.18 UE1.45
KSO7: JKB.19 UE1.46
KSO8: JKB.17 UE1.47
KSO9: JKB.7 UE1.48
KSO10: JKB.5 UE1.49
KSO11: JKB.6 UE1.50
KSO12: JKB.12 UE1.51
KSO13: JKB.9 UE1.52
KSO14: JKB.8 UE1.53
KSO15: JKB.10 UE1.54
KSO16: JKB.11 UE1.81
LAN_CLKREQ#: RH87.2 RL37.1 U2.AE24 UL1.12
LAN_X1: C14.1 R782.2 RH17.1
LAN_X1_R: R782.1 UG1.6
LCD_TEST: JEDP.33 UE1.72
LG_3V: PQ102.4 PU100.11
LG_5V: PQ104.4 PU100.15
LG_+1.05VSP: PQ303.4 PU300.6
LG_+1.35VGPUP: PQ1101.4 PU1100.6
LGATE1: PR1061.1 PU1000.24
LGATE2: PR1063.1 PU1000.27
LGATE_APU1: PQ501.4 PU500.49
LGATE_NB1: PQ500.4 PU500.45
LID_SW#: JLED.4 RE71.2 UE1.115
LINE1-L: CA67.1 UA1.22
LINE1-R: CA68.1 UA1.21
LINE1-VREFO-L: RA165.1 UA1.31
LINE1-VREFO-R: RA166.1 UA1.30
LINE-IN-L: LA8.2 RA55.2 RA80.2 RA83.1 RA165.2
LINE-IN-R: LA9.2 RA56.2 RA82.2 RA84.1 RA166.2
LPC_AD0: U2.D27 UE1.10
LPC_AD1: U2.C28 UE1.8
LPC_AD2: U2.A26 UE1.7
LPC_AD3: U2.A29 UE1.5
LPC_CLK1: CH17.1 RH118.2 RH130.1 U2.D25
LPC_FRAME#: U2.A31 UE1.4
LX_1.1V: PL400.1 PR402.1 PU400.1 PU400.2 PU400.3
LX_1.5V: PL302.1 PR310.1 PU301.3
LX_1.8V: PL401.1 PR406.1 PU401.3
LX_3V: PC104.1 PL100.1 PQ101.1 PQ101.2 PQ101.3 PQ102.5 PR113.1 PU100.8
LX_5V: PC110.2 PL101.1 PQ103.1 PQ103.2 PQ103.3 PQ104.5 PR112.1 PU100.18
LX_CHG: PC713.2 PL700.1 PQ701.1 PQ701.2 PQ701.3 PQ703.5 PR721.1 PU700.23
LX_PCIE: PL1300.1 PR1303.1 PU1300.1 PU1300.2 PU1300.3
M_BA0: UV1.J16 UV5.M2 UV6.M2 UV7.M2 UV8.M2
M_BA1: UV1.L15 UV5.N8 UV6.N8 UV7.N8 UV8.N8
M_BA2: UV1.G11 UV5.M3 UV6.M3 UV7.M3 UV8.M3
M_CAS#0: UV1.G19 UV5.K3 UV6.K3
M_CAS#1: UV1.G16 UV7.K3 UV8.K3
M_CKE0: UV1.K20 UV5.K9 UV6.K9
M_CKE1: UV1.J17 UV7.K9 UV8.K9
M_CLK0: RV48.1 UV1.H26 UV5.J7 UV6.J7
M_CLK1: RV54.1 UV1.G9 UV7.J7 UV8.J7
M_CLK#0: RV49.1 UV1.H25 UV5.K7 UV6.K7
M_CLK#1: RV55.1 UV1.H9 UV7.K7 UV8.K7
M_CS#0: UV1.H22 UV5.L2 UV6.L2
M_CS#1: UV1.G13 UV7.L2 UV8.L2
M_DA0: UV1.K27 UV5.A2
M_DA1: UV1.J29 UV5.C2
M_DA2: UV1.H30 UV5.A3
M_DA3: UV1.H32 UV5.C3
M_DA4: UV1.G29 UV5.C8
M_DA5: UV1.F28 UV5.D7
M_DA6: UV1.F32 UV5.A7
M_DA7: UV1.F30 UV5.B8
M_DA8: UV1.C30 UV6.D7
M_DA9: UV1.F27 UV6.C8
M_DA10: UV1.A28 UV6.A7
M_DA11: UV1.C28 UV6.B8
M_DA12: UV1.E27 UV6.C2
M_DA13: UV1.G26 UV6.A3
M_DA14: UV1.D26 UV6.C3
M_DA15: UV1.F25 UV6.A2
M_DA16: UV1.A25 UV5.G2
M_DA17: UV1.C25 UV5.E3
M_DA18: UV1.E25 UV5.H3
M_DA19: UV1.D24 UV5.H8
M_DA20: UV1.E23 UV5.H7
M_DA21: UV1.F23 UV5.F2
M_DA22: UV1.D22 UV5.F8
M_DA23: UV1.F21 UV5.F7
M_DA24: UV1.E21 UV6.F8
M_DA25: UV1.D20 UV6.H7
M_DA26: UV1.F19 UV6.H8
M_DA27: UV1.A19 UV6.F7
M_DA28: UV1.D18 UV6.G2
M_DA29: UV1.F17 UV6.H3
M_DA30: UV1.A17 UV6.E3
M_DA31: UV1.C17 UV6.F2
M_DA32: UV1.E17 UV7.H8
M_DA33: UV1.D16 UV7.H7
M_DA34: UV1.F15 UV7.G2
M_DA35: UV1.A15 UV7.F8
M_DA36: UV1.D14 UV7.F7
M_DA37: UV1.F13 UV7.F2
M_DA38: UV1.A13 UV7.E3
M_DA39: UV1.C13 UV7.H3
M_DA40: UV1.E11 UV7.B8
M_DA41: UV1.A11 UV7.D7
M_DA42: UV1.C11 UV7.A7
M_DA43: UV1.F11 UV7.C8
M_DA44: UV1.A9 UV7.C3
M_DA45: UV1.C9 UV7.C2
M_DA46: UV1.F9 UV7.A2
M_DA47: UV1.D8 UV7.A3
M_DA48: UV1.E7 UV8.G2
M_DA49: UV1.A7 UV8.E3
M_DA50: UV1.C7 UV8.H3
M_DA51: UV1.F7 UV8.F2
M_DA52: UV1.A5 UV8.H7
M_DA53: UV1.E5 UV8.F7
M_DA54: UV1.C3 UV8.F8
M_DA55: UV1.E1 UV8.H8
M_DA56: UV1.G7 UV8.C2
M_DA57: UV1.G6 UV8.A2
M_DA58: UV1.G1 UV8.A3
M_DA59: UV1.G3 UV8.C3
M_DA60: UV1.J6 UV8.D7
M_DA61: UV1.J1 UV8.B8
M_DA62: UV1.J3 UV8.A7
M_DA63: UV1.J5 UV8.C8
M_DQM0: UV1.E32 UV5.D3
M_DQM1: UV1.E30 UV6.D3
M_DQM2: UV1.A21 UV5.E7
M_DQM3: UV1.C21 UV6.E7
M_DQM4: UV1.E13 UV7.E7
M_DQM5: UV1.D12 UV7.D3
M_DQM6: UV1.E3 UV8.E7
M_DQM7: UV1.F4 UV8.D3
M_DQS0: UV1.H28 UV5.C7
M_DQS1: UV1.C27 UV6.C7
M_DQS2: UV1.A23 UV5.F3
M_DQS3: UV1.E19 UV6.F3
M_DQS4: UV1.E15 UV7.F3
M_DQS5: UV1.D10 UV7.C7
M_DQS6: UV1.D6 UV8.F3
M_DQS7: UV1.G5 UV8.C7
M_DQS#0: UV1.H27 UV5.B7
M_DQS#1: UV1.A27 UV6.B7
M_DQS#2: UV1.C23 UV5.G3
M_DQS#3: UV1.C19 UV6.G3
M_DQS#4: UV1.C15 UV7.G3
M_DQS#5: UV1.E9 UV7.B7
M_DQS#6: UV1.C5 UV8.G3
M_DQS#7: UV1.H4 UV8.B7
M_MA0: UV1.K17 UV5.N3 UV6.N3 UV7.N3 UV8.N3
M_MA1: UV1.J20 UV5.P7 UV6.P7 UV7.P7 UV8.P7
M_MA2: UV1.H23 UV5.P3 UV6.P3 UV7.P3 UV8.P3
M_MA3: UV1.G23 UV5.N2 UV6.N2 UV7.N2 UV8.N2
M_MA4: UV1.G24 UV5.P8 UV6.P8 UV7.P8 UV8.P8
M_MA5: UV1.H24 UV5.P2 UV6.P2 UV7.P2 UV8.P2
M_MA6: UV1.J19 UV5.R8 UV6.R8 UV7.R8 UV8.R8
M_MA7: UV1.K19 UV5.R2 UV6.R2 UV7.R2 UV8.R2
M_MA8: UV1.J14 UV5.T8 UV6.T8 UV7.T8 UV8.T8
M_MA9: UV1.K14 UV5.R3 UV6.R3 UV7.R3 UV8.R3
M_MA10: UV1.J11 UV5.L7 UV6.L7 UV7.L7 UV8.L7
M_MA11: UV1.J13 UV5.R7 UV6.R7 UV7.R7 UV8.R7
M_MA12: UV1.H11 UV5.N7 UV6.N7 UV7.N7 UV8.N7
M_MA13: UV1.G20 UV5.T3 UV6.T3 UV7.T3 UV8.T3
M_MA14: UV1.G14 UV5.T7 UV6.T7 UV7.T7 UV8.T7
M_MA15: UV1.L17 UV5.M7 UV6.M7 UV7.M7 UV8.M7
M_RAS#0: UV1.G22 UV5.J3 UV6.J3
M_RAS#1: UV1.G17 UV7.J3 UV8.J3
M_WE#0: UV1.G25 UV5.L3 UV6.L3
M_WE#1: UV1.H10 UV7.L3 UV8.L3
MA_ZVDDIO: R3.2 UC1.U30
MCT0: RL19.1 TL2.14
MCT1: RL20.1 TL2.11
MDI0+: TL2.8 UL1.1
MDI0-: TL2.7 UL1.2
MDI1+: TL2.2 UL1.4
MDI1-: TL2.1 UL1.5
MDO0+: JLAN.1 TL2.9
MDO0-: JLAN.2 TL2.10
MDO1+: JLAN.3 TL2.15
MDO1-: JLAN.6 TL2.16
MEM_MA_EVENT#: JDIMM1.198 R6.2 UC1.AB33
MEM_MA_RST#: JDIMM1.30 UC1.J33
MIC1-L: CA74.1 UA1.19
MIC_CLK: CA22.1 JEDP.30 LA1.2
MIC_CLK_C: LA1.1 UA1.3
MIC_DATA: JEDP.32 UA1.2
MIC_IN: LA7.2 QA6.3 RA53.1 UA1.18
MIC_IN_R: CA38.1 DA12.3 JHP.4 LA7.1
OCP_L: PR1020.2 PU1000.4 RV90.2
ODD_EN: RH40.2 T129.1(TP-1) U2.K6
OFS: PR528.2 PR554.2 PR555.1 PU500.23
OFSA: PR529.2 PR560.2 PR561.1 PU500.24
ON/OFF: CE20.1 DE2.3 RE49.1 SW1.3 SW1.4 UE1.114
P2: PC700.1 PQ704.1 PQ704.2 PQ704.3 PQ705.1 PQ705.2 PQ705.3 PQ707.3 PR701.1
P3: PC701.2 PQ705.5 PQ705.6 PQ705.7 PQ705.8 PR700.1
P_ZVDDP: R1.2 UC1.AN18
P_ZVSS: R34.1 UC1.AM18
PACIN#: QV8.5 QV8.6 RV147.2
PBTN_OUT#: U2.J4 UE1.106
PC_BEEP: DA8.1 RA19.1 RA79.2
PCC_GPIO_6: CVT90.2 RV90.1 RV91.1 UV1.T8
PCH_X1: R783.2 RH21.1
PCH_X1_R: R783.1 UG1.5
PCI_AD23: RH125.1 U2.AE12
PCI_AD24: RH124.1 U2.AC12
PCI_AD25: RH123.1 U2.AE13
PCI_AD26: RH122.1 U2.AF13
PCI_AD27: RH121.1 U2.AH13
PCI_CLK1: RH114.2 RH126.1 U2.AF1
PCI_CLK3: RH115.2 RH127.1 U2.AG2
PCI_CLK4: RH116.2 RH128.1 U2.AF6
PCIE_B+: PC1301.1 PC1309.1 PJP1301.1 PU1300.8 PU1300.9 PU1300.10
PCIE_CALRN: RH2.2 U2.AF31
PCIE_CALRP: RH5.2 U2.AF29
PCIE_PRX_DTX_N0: CL31.1 UC1.AH3
PCIE_PRX_DTX_N0_C: CL31.2 UL1.18
PCIE_PRX_DTX_N1: JNGFF.35 UC1.AF6
PCIE_PRX_DTX_P0: CL30.1 UC1.AH4
PCIE_PRX_DTX_P0_C: CL30.2 UL1.17
PCIE_PRX_DTX_P1: JNGFF.33 UC1.AG7
PCIE_PTX_C_DRX_N0: C18.2 UL1.14
PCIE_PTX_C_DRX_N1: C20.2 JNGFF.29
PCIE_PTX_C_DRX_P0: C17.2 UL1.13
PCIE_PTX_C_DRX_P1: C19.2 JNGFF.27
PCIE_PTX_DRX_N0: C18.1 UC1.AM1
PCIE_PTX_DRX_N1: C20.1 UC1.AL1
PCIE_PTX_DRX_P0: C17.1 UC1.AM2
PCIE_PTX_DRX_P1: C19.1 UC1.AL2
PECI_KB930: RE69.1 UE1.74
PEG_CLKREQ#: RH56.2 RV153.1
PEG_CLKREQ#_G: RV153.2 UV1.N7
PEG_CLKREQ#_R: RH56.1 RH95.2 U2.AF25
PEG_GTX_C_HRX_N0: CV2.1 UC1.Y9
PEG_GTX_C_HRX_N1: CV4.1 UC1.W5
PEG_GTX_C_HRX_N2: CV6.1 UC1.W8
PEG_GTX_C_HRX_N3: CV8.1 UC1.V4
PEG_GTX_C_HRX_N4: CV16.1 UC1.U8
PEG_GTX_C_HRX_N5: CV30.1 UC1.R5
PEG_GTX_C_HRX_N6: CV14.1 UC1.R8
PEG_GTX_C_HRX_N7: CV32.1 UC1.P7
PEG_GTX_C_HRX_P0: CV1.1 UC1.Y8
PEG_GTX_C_HRX_P1: CV3.1 UC1.Y4
PEG_GTX_C_HRX_P2: CV5.1 UC1.W7
PEG_GTX_C_HRX_P3: CV7.1 UC1.U5
PEG_GTX_C_HRX_P4: CV13.1 UC1.U7
PEG_GTX_C_HRX_P5: CV35.1 UC1.T4
PEG_GTX_C_HRX_P6: CV12.1 UC1.R7
PEG_GTX_C_HRX_P7: CV31.1 UC1.P8
PEG_GTX_HRX_N0: CV2.2 UV1.AG31
PEG_GTX_HRX_N1: CV4.2 UV1.AF28
PEG_GTX_HRX_N2: CV6.2 UV1.AF26
PEG_GTX_HRX_N3: CV8.2 UV1.AD26
PEG_GTX_HRX_N4: CV16.2 UV1.AB25
PEG_GTX_HRX_N5: CV30.2 UV1.Y24
PEG_GTX_HRX_N6: CV14.2 UV1.AB26
PEG_GTX_HRX_N7: CV32.2 UV1.Y26
PEG_GTX_HRX_P0: CV1.2 UV1.AH30
PEG_GTX_HRX_P1: CV3.2 UV1.AG29
PEG_GTX_HRX_P2: CV5.2 UV1.AF27
PEG_GTX_HRX_P3: CV7.2 UV1.AD27
PEG_GTX_HRX_P4: CV13.2 UV1.AC25
PEG_GTX_HRX_P5: CV35.2 UV1.Y23
PEG_GTX_HRX_P6: CV12.2 UV1.AB27
PEG_GTX_HRX_P7: CV31.2 UV1.Y27
PEG_HTX_C_GRX_N0: C164.2 UV1.AE31
PEG_HTX_C_GRX_N1: C151.2 UV1.AD28
PEG_HTX_C_GRX_N2: C152.2 UV1.AC31
PEG_HTX_C_GRX_N3: C156.2 UV1.AB28
PEG_HTX_C_GRX_N4: C165.2 UV1.AA31
PEG_HTX_C_GRX_N5: C160.2 UV1.Y28
PEG_HTX_C_GRX_N6: C159.2 UV1.W31
PEG_HTX_C_GRX_N7: C158.2 UV1.V28
PEG_HTX_C_GRX_P0: C153.2 UV1.AF30
PEG_HTX_C_GRX_P1: C154.2 UV1.AE29
PEG_HTX_C_GRX_P2: C155.2 UV1.AD30
PEG_HTX_C_GRX_P3: C157.2 UV1.AC29
PEG_HTX_C_GRX_P4: C161.2 UV1.AB30
PEG_HTX_C_GRX_P5: C163.2 UV1.AA29
PEG_HTX_C_GRX_P6: C166.2 UV1.Y30
PEG_HTX_C_GRX_P7: C162.2 UV1.W29
PEG_HTX_GRX_N0: C164.1 UC1.AB1
PEG_HTX_GRX_N1: C151.1 UC1.AA2
PEG_HTX_GRX_N2: C152.1 UC1.Y1
PEG_HTX_GRX_N3: C156.1 UC1.W2
PEG_HTX_GRX_N4: C165.1 UC1.V1
PEG_HTX_GRX_N5: C160.1 UC1.U2
PEG_HTX_GRX_N6: C159.1 UC1.T1
PEG_HTX_GRX_N7: C158.1 UC1.R2
PEG_HTX_GRX_P0: C153.1 UC1.AB2
PEG_HTX_GRX_P1: C154.1 UC1.AB3
PEG_HTX_GRX_P2: C155.1 UC1.AA1
PEG_HTX_GRX_P3: C157.1 UC1.Y2
PEG_HTX_GRX_P4: C161.1 UC1.V2
PEG_HTX_GRX_P5: C163.1 UC1.V3
PEG_HTX_GRX_P6: C166.1 UC1.U1
PEG_HTX_GRX_P7: C162.1 UC1.T2
PHASE1: PC1026.2 PL1002.1 PQ1003.1 PQ1003.2 PQ1003.3 PQ1004.5 PR1036.1 PU1000.23
PHASE2: PC1043.2 PL1003.1 PQ1005.1 PQ1005.2 PQ1005.3 PQ1006.5 PR1054.1 PU1000.28
PHASE_APU1: PC524.2 PQ501.3 PU500.48
PHASE_NB1: PC507.2 PQ500.3 PU500.44
PLL_ANALOG_IN: T221.1(TP-1) UV1.AA1
PLL_ANALOG_OUT: RV83.1 UV1.AA3
PLT_RST#: CH6.2 RH1.1 RH3.1 RH27.2 RM6.2 UE1.13 UL1.19
PLT_RST#_R: JNGFF.44 RM6.1
PLT_RST_VGA#: RV4.1 UV1.AL27 UV2.4
PM_SLP_S3#: CE15.1 RE31.1 U2.T3
PM_SLP_S3#_R: RE31.2 UE1.6
PM_SLP_S5#: CE14.1 RE33.1 U2.W2
PM_SLP_S5#_R: RE33.2 UE1.14
POK: PR115.2 PU100.7 UE1.18
PS_0: CV29.1 RV8.2 RV9.1 UV1.AC19
PS_1: CV28.1 RV11.2 RV12.1 UV1.AD19
PS_2: CV11.1 RV13.1 RV28.2 UV1.AE17
PS_3: CV15.1 RV15.2 RV16.1 UV1.AE20
PS_ID: PR3.1 PR4.2 UE1.16
PSID: PJPDC.1 PL2.2
PSID-1: PQ5.2 PR6.1 PR9.2
PSID-2: PQ5.1 PQ6.2 PR8.2
PSID-3: PQ6.3 PR4.1 PR11.2
PWR_PWM_LED#: T120.1(TP-1) UE1.90
PWR_SRC_ON: CX4.2 QX2.3 RX2.2 RX3.1
PX_EN: T218.1(TP-1) UV1.AB16
PXS_PWREN: PR1027.1 PR1103.1 PR1300.1 QH2.3 R435.1 R436.1 R438.1 RH76.2 RH78.2 RH99.1
PXS_PWREN_EC: RH99.2 UE1.89
PXS_RST#: RH74.2 UV2.2
REMOTE1+: C2500.1 C2502.1 Q2407.1 Q2407.2 U2407.2
REMOTE1-: C2500.2 C2502.2 Q2407.3 U2407.3
REMOTE2+: C2504.1 C2505.1 Q2408.1 Q2408.2 U2407.4
REMOTE2-: C2504.2 C2505.2 Q2408.3 U2407.5
RF_+1.05VSP: PR304.1 PU300.5
RF_+1.35VGPUP: PR1105.1 PU1100.5
RING2: LA10.2 RA1109.1 UA1.17
RING2_R: CA40.1 DA12.2 JHP.3 LA10.1
RTC_CLK: RE43.1 RH120.2 RH132.1 U2.F1
SATA_CALRN: RH38.1 U2.AF27
SATA_CALRP: RH37.1 U2.AF28
SATA_PRX_DTX_N0: CS31.2 CS41.2 JHDD.2
SATA_PRX_DTX_N0_C: CS33.1 RS44.1 U2.AL20
SATA_PRX_DTX_N0_R: CS31.1 US2.12
SATA_PRX_DTX_N0_RC: CS33.2 US2.4
SATA_PRX_DTX_P0: CS34.2 CS40.2 JHDD.1
SATA_PRX_DTX_P0_C: CS35.1 RS42.1 U2.AN20
SATA_PRX_DTX_P0_R: CS34.1 US2.11
SATA_PRX_DTX_P0_RC: CS35.2 US2.5
SATA_PTX_DRX_N0: CS32.2 CS39.2 JHDD.4
SATA_PTX_DRX_N0_C: CS36.1 RS41.1 U2.AM19
SATA_PTX_DRX_N0_R: CS36.2 US2.2
SATA_PTX_DRX_N0_RC: CS32.1 US2.14
SATA_PTX_DRX_P0: CS30.2 CS38.2 JHDD.5
SATA_PTX_DRX_P0_C: CS37.1 RS43.1 U2.AK19
SATA_PTX_DRX_P0_R: CS37.2 US2.1
SATA_PTX_DRX_P0_RC: CS30.1 US2.15
SATA_RX_N0: CS41.1 RS44.2
SATA_RX_P0: CS40.1 RS42.2
SATA_TX_N0: CS39.1 RS41.2
SATA_TX_P0: CS38.1 RS43.2
SERIRQ: U2.AE19 UE1.3
SET1: PR567.2 PR569.1 PU500.25
SET2: PR571.2 PR573.1 PU500.26
SID_G: Q78.5 Q2507.2 R18.2
SNB_APU: PC528.1 PR546.2
SNB_APU_NB: PC511.1 PR516.2
SNB_CHG: PC716.1 PR721.2
SNUB_PCIE: PC1304.1 PR1303.2
SPK_L1-_CONN: CA30.1 DA13.3 JSPK.3 LA5.2
SPK_L2+_CONN: CA29.1 DA13.2 JSPK.4 LA6.2
SPK_R1-_CONN: CA32.1 DA14.3 JSPK.1 LA3.2
SPK_R2+_CONN: CA31.1 DA14.2 JSPK.2 LA4.2
SUSCLK: RM5.2 UE1.86
SUSCLK_R: JNGFF.42 RM5.1
SUSP: Q52.6 QZ13.2 RZ10.1
SUSP#: PR202.1 PR311.1 PR408.1 Q52.2 R437.1 RZ25.1 RZ591.1 U6.3 UE1.116
SUSP#_C: CZ5.1 RZ25.2 U6.5
SVI2_SVC: PU1000.3 RV78.2 RV84.1 RV89.2 RV157.2
SVI2_SVD: PU1000.5 RV77.2 RV87.1 RV88.2 RV155.2
SVI2_SVT: PU1000.7 RV156.2
SW_1.35V: PC200.2 PC207.1 PL200.2 PQ200.1 PQ200.2 PQ200.3 PQ201.5 PU200.16
SW_+1.05VSP: PC305.2 PL300.1 PQ301.1 PQ301.2 PQ301.3 PQ303.5 PR305.1 PU300.8
SW_+1.35VGPUP: PC1103.2 PL1101.1 PQ1100.1 PQ1100.2 PQ1100.3 PQ1101.5 PR1104.1 PU1100.8
SYS_RESET#: RH53.2 U2.U4
SYSON: PR201.1 Q52.5 RZ21.1 UE1.95
SYSON#: Q52.3 QZ15.2 RZ19.1
TEST0: RH57.2 U2.T9
TEST1: RH60.2 U2.T10
TEST2: RH61.2 U2.V9
TESTEN: RV17.2 RV154.2 UV1.K7
THM_ALERT#: RV146.2 UV1.R6 UV3.6
TMDS_L_TX0N: CX25.1 JHDMI.9 LX3.2
TMDS_L_TX0P: CX26.1 JHDMI.7 LX3.3
TMDS_L_TX1N: CX27.1 JHDMI.6 LX4.2
TMDS_L_TX1P: CX28.1 JHDMI.4 LX4.3
TMDS_L_TX2N: CX29.1 JHDMI.3 LX5.2
TMDS_L_TX2P: CX30.1 JHDMI.1 LX5.3
TMDS_L_TXCN: CX23.1 JHDMI.12 LX2.2
TMDS_L_TXCP: CX24.1 JHDMI.10 LX2.3
TMDS_TX0N: CV362.1 CX14.2 LX3.1 RX181.1
TMDS_TX0P: CV363.1 CX15.2 LX3.4 RX182.1
TMDS_TX1N: CV359.1 CX16.2 LX4.1 RX183.1
TMDS_TX1P: CV357.1 CX17.2 LX4.4 RX184.1
TMDS_TX2N: CV361.1 CX18.2 LX5.1 RX185.1
TMDS_TX2P: CV364.1 CX19.2 LX5.4 RX186.1
TMDS_TXCN: CV358.1 CX12.2 LX2.1 RX179.1
TMDS_TXCP: CV360.1 CX13.2 LX2.4 RX180.1
TON_1.35V: PR208.2 PU200.9
TONSET: PR514.1 PU500.4
TP_CLK: JTP.1 RE9.2 UE1.87
TP_DATA: JTP.2 RE10.2 UE1.88
TP_EN: UE1.82 UE4.3
TP_INT#: JTP.4 RE329.2 RH68.2 RH133.2
TP_INT#_R: RH68.1 U2.AF22
TP_WAKE: JTP.3 RC78.1 RE11.2
TP_WAKE_R: RE11.1 UE1.38
TRIP_+1.05VSP: PR301.2 PU300.2
TRIP_+1.35VGPUP: PR1102.2 PU1100.2
TS_EN: RX25.1 UE1.19
TS_EN_R: JEDP.22 RX25.2
TS_INT#: JEDP.21 RH83.2 RX35.2 U2.P6
TS_RST#: JEDP.19 RH134.2 RX24.2 U2.R8
UG_3V: PQ101.4 PU100.10
UG_5V: PQ103.4 PU100.16
UG_+1.05VSP: PQ301.4 PU300.9
UG_+1.35VGPUP: PQ1100.4 PU1100.9
UGATE1: PR1060.1 PU1000.22
UGATE2: PR1062.1 PU1000.29
UGATE_APU1: PR531.1 PU500.47
UGATE_NB1: PR507.1 PU500.43
UMI_ATX_C_FRX_N0: CC85.2 U2.AB31
UMI_ATX_C_FRX_N1: CC87.2 U2.AB29
UMI_ATX_C_FRX_N2: CC89.2 U2.Y31
UMI_ATX_C_FRX_N3: CC91.2 U2.Y29
UMI_ATX_C_FRX_P0: CC84.2 U2.AB33
UMI_ATX_C_FRX_P1: CC86.2 U2.AB28
UMI_ATX_C_FRX_P2: CC88.2 U2.Y33
UMI_ATX_C_FRX_P3: CC90.2 U2.Y28
UMI_ATX_FRX_N0: CC85.1 UC1.AM10
UMI_ATX_FRX_N1: CC87.1 UC1.AN9
UMI_ATX_FRX_N2: CC89.1 UC1.AM8
UMI_ATX_FRX_N3: CC91.1 UC1.AM6
UMI_ATX_FRX_P0: CC84.1 UC1.AM9
UMI_ATX_FRX_P1: CC86.1 UC1.AN8
UMI_ATX_FRX_P2: CC88.1 UC1.AM7
UMI_ATX_FRX_P3: CC90.1 UC1.AN6
UMI_FTX_ARX_N0: CH1.2 U2.AE32
UMI_FTX_ARX_N1: CH2.2 U2.AD31
UMI_FTX_ARX_N2: CH3.2 U2.AD29
UMI_FTX_ARX_N3: CH5.2 U2.AC32
UMI_FTX_ARX_P0: CH7.2 U2.AE30
UMI_FTX_ARX_P1: CH8.2 U2.AD33
UMI_FTX_ARX_P2: CH9.2 U2.AD28
UMI_FTX_ARX_P3: CH4.2 U2.AC30
UMI_FTX_C_ARX_N0: CH1.1 UC1.AJ8
UMI_FTX_C_ARX_N1: CH2.1 UC1.AK7
UMI_FTX_C_ARX_N2: CH3.1 UC1.AJ5
UMI_FTX_C_ARX_N3: CH5.1 UC1.AK4
UMI_FTX_C_ARX_P0: CH7.1 UC1.AJ7
UMI_FTX_C_ARX_P1: CH8.1 UC1.AK6
UMI_FTX_C_ARX_P2: CH9.1 UC1.AK5
UMI_FTX_C_ARX_P3: CH4.1 UC1.AL4
USB2P0_N3: LI7.1 U2.E3
USB2P0_P3: LI7.4 U2.E1
USB2P10_N2: LI5.1 U2.K13
USB2P10_N2_R: DI5.2 JUSB2.2 LI5.2
USB2P10_P2: LI5.4 U2.K12
USB2P10_P2_R: DI5.3 JUSB2.3 LI5.3
USB2P13_N1: LI2.4 U2.G10
USB2P13_N1_R: DI2.3 JUSB1.2 LI2.3
USB2P13_P1: LI2.1 U2.H10
USB2P13_P1_R: DI2.2 JUSB1.3 LI2.2
USB3P0RN2: LI4.1 U2.K15
USB3P0RN2_R: DI4.1 DI4.10 JUSB2.5 LI4.2
USB3P0RP2: LI4.4 U2.J15
USB3P0RP2_R: DI4.2 DI4.9 JUSB2.6 LI4.3
USB3P0TN2: CI10.2 U2.H16
USB3P0TN2_C: CI10.1 LI6.1
USB3P0TN2_R: DI4.4 DI4.7 JUSB2.8 LI6.2
USB3P0TP2: CI11.2 U2.J16
USB3P0TP2_C: CI11.1 LI6.4
USB3P0TP2_R: DI4.5 DI4.6 JUSB2.9 LI6.3
USB3P3RN1: LI1.1 U2.A12
USB3P3RN1_R: DI1.1 DI1.10 JUSB1.5 LI1.2
USB3P3RP1: LI1.4 U2.C12
USB3P3RP1_R: DI1.2 DI1.9 JUSB1.6 LI1.3
USB3P3TN1: CI3.2 U2.C14
USB3P3TN1_C: CI3.1 LI3.1
USB3P3TN1_R: DI1.4 DI1.7 JUSB1.8 LI3.2
USB3P3TP1: CI4.2 U2.A14
USB3P3TP1_C: CI4.1 LI3.4
USB3P3TP1_R: DI1.5 DI1.6 JUSB1.9 LI3.3
USB20_CAM_N7_R: JEDP.28 LX6.2 RX21.2
USB20_CAM_P7_R: JEDP.27 LX6.3 RX22.2
USB20_CR_N6_R: JIO.12 LI8.2
USB20_CR_P6_R: JIO.11 LI8.3
USB20_JUSB3_N2_R: JIO.15 LI7.2
USB20_JUSB3_P2_R: JIO.14 LI7.3
USB20_MINI_N1: JNGFF.5 U2.C3
USB20_MINI_P1: JNGFF.3 U2.C1
USB20_N6: LI8.1 U2.G9
USB20_N9: LX6.1 RX21.1 U2.D11
USB20_P6: LI8.4 U2.H9
USB20_P9: LX6.4 RX22.1 U2.B11
USB20_TOUCH_N5: DX2.3 JEDP.13 U2.C8
USB20_TOUCH_P5: DX2.2 JEDP.14 U2.A8
USB_EN#: CI13.1 CI26.1 CI46.1 RE504.1 UE1.84 UI5.4 UI6.4 UI7.4
USB_OC0#: CI15.1 RPH4.8 U2.T8 UI5.3
USB_OC1#: RPH4.6 T118.1(TP-1) U2.J7
USB_OC2#: CI17.1 RPH4.7 U2.P5 UI6.3
USB_OC3#: CI47.1 RPH4.5 U2.F5 UI7.3
USB_OC5#: RPH1.1 U2.T1
USB_RCOMP: RH54.1 U2.B9
USBSS_CALRN: RH59.1 U2.A16
USBSS_CALRP: RH58.1 U2.C16
VCIN0_PH: PH1.1 PR24.1 PR25.1 RE15.2
VCIN0_PH2: HE1.1 RE7.1 RE332.1 RE333.1
VCIN1_PH: PC13.2 PR23.1 PR26.2 RE30.2 UE1.102
VCOUT0: RE37.2 UE1.104
VCOUT0_PH#: PC100.1 PR100.2 PR101.2 PR102.2 PR110.1 R621.2 R2450.2 RE37.1
VCOUT1_PH: QE30.2 RE44.1 UE1.103
VFB: PR726.1 PU700.15 PU700.16
VGA_AC__BATT: QV8.3 RV92.1 RV148.2 UV1.T9 UV4.4
VGA_DMINUS: CV9.2 UV1.T2 UV3.3
VGA_DPLUS: CV9.1 UV1.T4 UV3.2
VGA_ON: RE39.2 RE40.2 UE1.127
VGA_ON_FCH: D6.1 D7.1 RE39.1
VGA_PWRGD: PR1030.2 PR1064.1 PU1000.9 PU1000.20 U2.AG26
VGA_PWRGD_EC: PR1064.2 UE1.17
VGA_SMB_CK3: QV1.1 RV6.2 RV164.2 UV1.U7
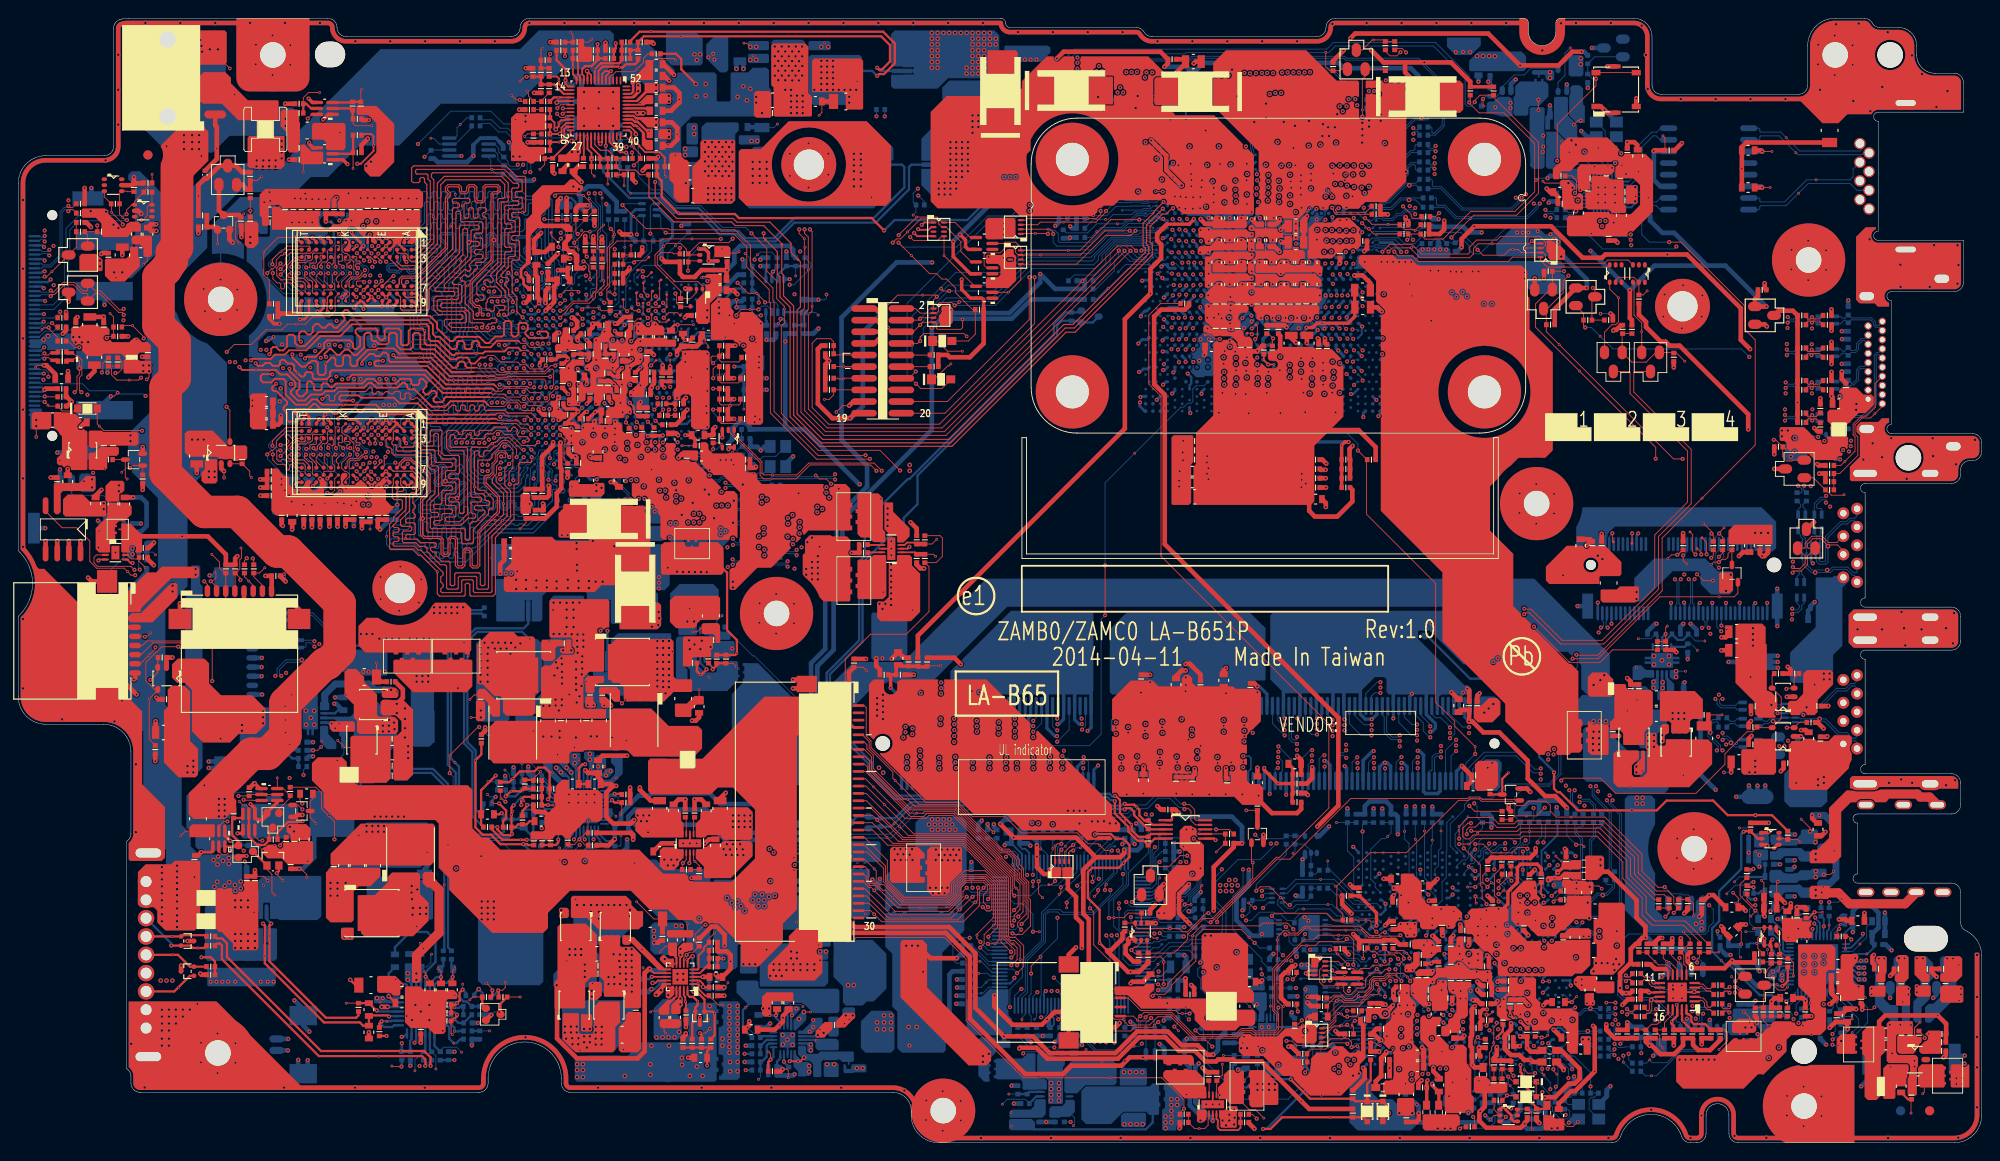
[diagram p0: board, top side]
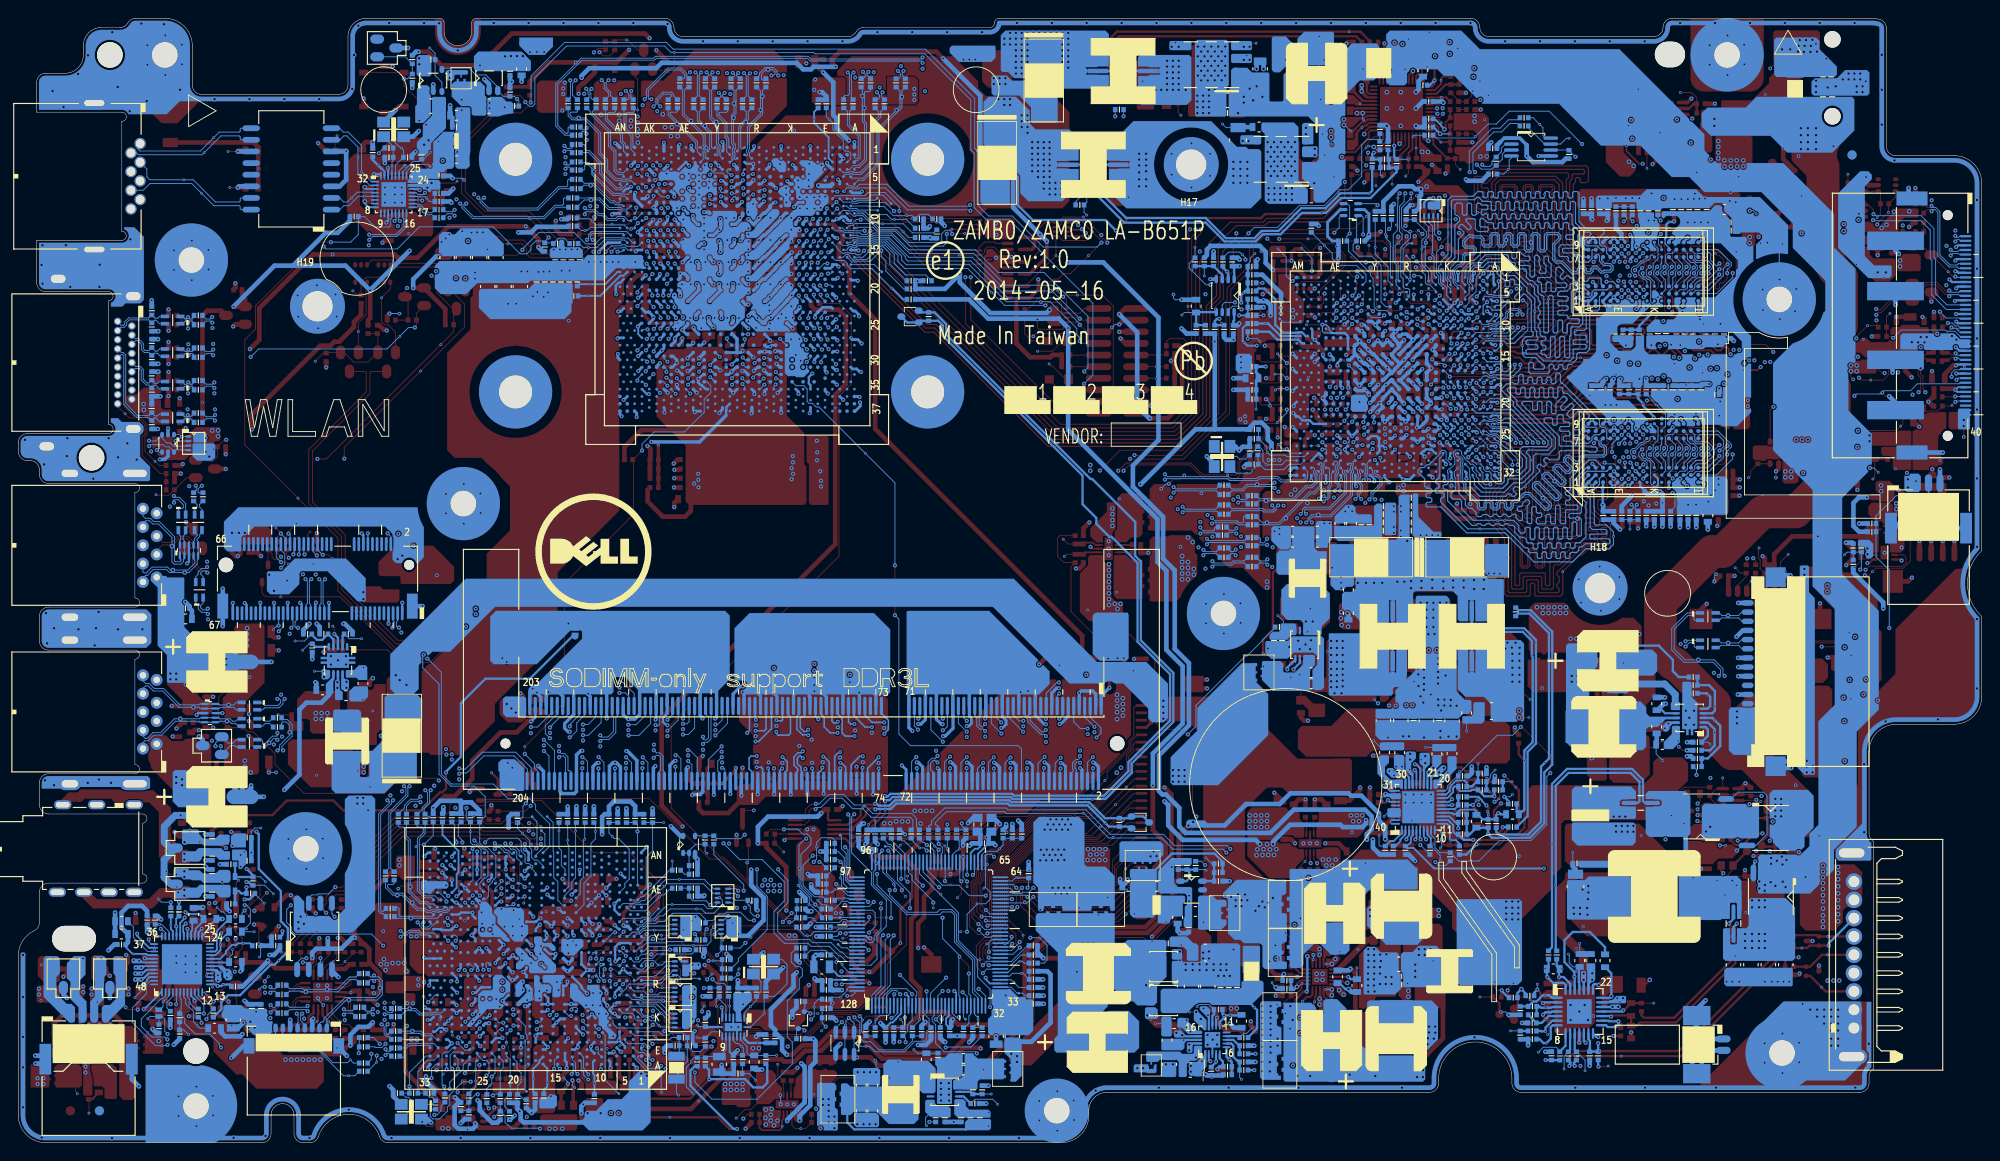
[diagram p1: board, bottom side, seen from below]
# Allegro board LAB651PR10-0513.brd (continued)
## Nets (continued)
VGA_SMB_CK3_R: RV164.1 UV3.8
VGA_SMB_DA3: QV1.4 RV5.2 RV165.2 UV1.U8
VGA_SMB_DA3_R: RV165.1 UV3.7
VGA_X1: C15.1 R785.2
VGA_X1_R: R785.1 UG1.12
VGATE: PR541.2 PU500.39 RH51.1
VL: PC106.1 PU100.13
VR_HOT: PR539.2 PU500.27
VR_ON: PC535.1 PR303.1 PR547.2 UE1.121
VRAM_ODT0: UV1.L18 UV5.K1 UV6.K1
VRAM_ODT1: UV1.K16 UV7.K1 UV8.K1
VREF: PC526.1 PC527.1 PH500.2 PH501.2 PR537.1 PR538.1 PU500.16
VSUM+: PC1031.1 PC1032.1 PR1039.1 PR1042.1 PR1044.1 PR1057.1 PU1000.14
VSUM-: PC1031.2 PC1032.2 PC1035.1 PC1050.1 PC1051.1 PH1003.2 PR1043.1 PR1044.2 PR1046.1 PR1048.1 PR1053.1
VTTREF_1.35V: PC210.1 PU200.4
WAKEB: RV162.2 RV163.1 UV1.AJ27
WD_PWRGD: RH82.2 U2.AF19
WL_OFF#: QM1.3 U2.AN16
WL_OFF#_R: JNGFF.48 QM1.1 RM8.2
WLAN_CLKREQ#: JNGFF.45 RH84.2 U2.AG25
WLAN_LED_EC: RE34.2 T111.1(TP-1) UE1.34
WLAN_WAKE#: JNGFF.47 RE69.2 RE70.2
WOL_EN: RL27.2 RL38.1 UE1.98 UL2.3 UL3.4
XTALIN: CV17.1 RV20.1 UV1.AM28 YV1.1
XTALOUT: CV18.1 RV20.2 UV1.AK28 YV1.3
XTLI: CL36.2 RL21.1 UL1.29 YL2.1
XTLO: CL37.2 UL1.28 YL2.3
N71037: RA130.2 UA1.8
N71249: CA62.2 RA12.2 UA1.27
N71261: CA63.2 UA1.39
N71273: CA64.2 UA1.7
N71383: CA24.1 UA1.37
N71395: CA24.2 UA1.35
N71399: CA25.2 UA1.34
N71447: CA23.2 UA1.28
N71539: CA65.2 CA69.1 RA79.1 RA81.2
N71593: CA65.1 UA1.12
N76526: RA1113.2 UA1.4
N3691692: PC305.1 PR302.2
N3691782: PC309.1 PR305.2
N14128350: PR1110.2 PU1100.1
N16741477: T212.1(TP-1) UV1.AB8
N16741481: T209.1(TP-1) UV1.AC8
N16741485: T205.1(TP-1) UV1.AE8
N16741489: T208.1(TP-1) UV1.AD7
N16741493: T203.1(TP-1) UV1.AE9
N16741497: T201.1(TP-1) UV1.N9
N16741501: T215.1(TP-1) UV1.AB2
N16741505: T214.1(TP-1) UV1.AB4
N16741509: T211.1(TP-1) UV1.AB9
N16741513: T207.1(TP-1) UV1.AC10
N16741517: T206.1(TP-1) UV1.AD9
N16741521: T202.1(TP-1) UV1.L9
N16741525: T216.1(TP-1) UV1.Y8
N16741529: T213.1(TP-1) UV1.AB7
N16741533: T210.1(TP-1) UV1.AC7
N16741553: T204.1(TP-1) UV1.Y11
N16741557: T217.1(TP-1) UV1.Y7
N16741803: RV29.2 UV1.AC22
N16741825: RV59.2 UV1.AB22
N16783218: JHDT1.13 R48.2
N16783220: JHDT1.15 R50.2
N16783234: JHDT1.11 R47.2
N16784339: RV77.1 U1.7
N16784342: RV78.1 U1.6
N16787636: JKBBL.2 QE4.2 RE58.1
N16803422: RV157.1 UV1.AJ11
N16803439: RV155.1 UV1.AK12
N16803454: RV156.1 UV1.AL11
N16814221: RV60.1 UV1.AC11 UV1.AC13
N16828992: C81.1 R54.1 UC1.D6
N16924370: CL41.2 TL2.3 TL2.6
N16924426: RL31.2 UL1.31
N16924463: T94.1(TP-1) UL1.25
N16924465: T95.1(TP-1) UL1.27
N16924703: CL33.1 RL19.2 RL20.2
N16948644: PC1036.2 PR1046.2 PU1000.15
N16948660: PC1036.1 PR1048.2
N16948668: PC1020.1 PR1024.1 PU1000.25
N16955053: PL1002.2 PR1039.2 PR1058.2
N16955054: PL1002.3 PR1043.2
N16955057: PR1052.2 PU1000.11
N16955058: PC1027.1 PC1030.1 PR1040.1 PR1049.1 PU1000.16
N16955061: PC1040.1 PR1050.1 PU1000.17
N16955074: PQ1004.4 PR1061.2
N16955100: PC1029.1 PR1036.2
N16955117: PC1026.1 PR1034.2
N16955158: PH1002.2 PR1031.2 PR1052.1
N16955166: PC1028.1 PR1037.2 PR1040.2 PR1041.1 PR1045.1 PU1000.18
N16955169: PC1027.2 PR1037.1
N16955171: PC1034.1 PR1045.2
N16955173: PC1028.2 PC1033.2 PR1038.1 PU1000.19
N16955176: PC1033.1 PR1041.2
N16955207: PQ1003.4 PR1060.2
N17016554: RV56.1 UV7.L8
N17017096: RV57.1 UV8.L8
N17087794: PU1000.39 PU1000.40
N17087943: PU1000.36 PU1000.37 PU1000.38
N17088417: PR1033.2 PU1000.2
N17089228: PR1035.2 PU1000.34
N17089248: PR1056.2 PU1000.32 PU1000.33
N17112777: PL1003.2 PR1057.2 PR1059.2
N17143063: CE60.1 UE4.6
N17212768: RS19.2 US2.7
N17212771: RS20.2 RS22.2 US2.18
N17212791: RS25.2 US2.10
N17242539: RV58.1 UV3.4
N17283470: PQ200.4 PR209.1
N17283477: PC204.2 PR210.1 PU200.12
N17371703: PR717.2 PU700.10
N17371738: PR719.2 PU700.9
N17438484: CA21.1 RA1112.2
N17493058: JNGFF.36 T4927.1(TP-1)
N17493084: JNGFF.40 T4929.1(TP-1)
N17493086: JNGFF.38 T4928.1(TP-1)
N17493091: JNGFF.6 T3861.1(TP-1)
N17493111: JNGFF.16 T3862.1(TP-1)
N17494823: CA1.1 CA2.1 QA5.2 RA3.2
N17540887: PR1032.2 PU1000.1
N17607025: CH20.2 RH29.2
N17706108: PQ500.2 PR507.2
N17706210: PL500.4 PQ500.5 PQ500.6 PQ500.7 PR516.1
N17706708: PL501.4 PQ501.5 PQ501.6 PQ501.7 PR546.1
N17754863: RL39.2 UL1.26
N17838023: QX3.1 RX179.2 RX180.2 RX181.2 RX182.2 RX183.2 RX184.2 RX185.2 RX186.2
N17847259: T4930.1(TP-1) UV1.AL9
N17874049: Q12.2 R620.2
N17874051: Q12.1 R621.1 R623.1
N17876072: R2448.2 R2450.1 U2407.7
N17877344: T223.1(TP-1) UV1.R1
N17877347: T224.1(TP-1) UV1.R3
N17882994: PH1003.1 PR1042.2
N17883462: RE7.2 UE1.75
N17933206: PL1003.3 PR1053.2
N17933209: PQ1006.4 PR1063.2
N17933219: PC1044.1 PR1054.2
N17933234: PC1043.1 PR1055.2
N17933249: PQ1005.4 PR1062.2
N17933268: PC1302.1 PU1300.7
N17933717: RL40.2 UL3.3
N17965231: T101.1(TP-1) U2.K19
N17983950: C935.1 Q9.2 Q10.2 R537.2 R538.1
N18017446: QX5.2 RX15.1
N18053952: C343.2 U15.12
N18092302: C349.2 U15.10
N18116076: RA34.1 RA155.1 UA1.13
N18296224: PJPDC.2 PJPDC.3 PL4.1
N18386729: PC411.2 PJP402.2 PU401.4
N18386774: PC416.1 PR406.2
N18405073: PC728.2 PQ714.1
N18406275: PC400.1 PC401.1 PJP400.2 PR401.1 PU400.9 PU400.10
N18406334: PC409.1 PR402.2
N18406395: PC410.1 PU400.7
N18406660: PC404.1 PR401.2 PU400.8
N18414408: PC310.2 PJP301.2 PU301.4
N18414459: PC315.1 PR310.2
N18423379: PQ501.2 PR531.2
N18424405: PR526.2 PR535.1 PR537.2
N18424435: PR527.2 PR536.2 PR538.2
N18432502: J16.2 U16.1 U16.2
N18432559: C344.2 U16.12
N18432569: C348.2 U16.10
N18943829: PR720.2 PR724.1
N18944147: PC722.2 PC726.1 PR720.3 PU700.17
N18956218: PC722.1 PR724.2 PU700.18
N18967347: PC727.1 PR723.2
N18967375: PC721.1 PU700.4
N18967379: PR723.1 PU700.6
N18967435: PC723.1 PU700.7
N18967441: PR725.1 PR728.2 PU700.5
N18999155: PC706.1 PC709.1 PR704.2 PU700.28
N19000258: PC707.1 PC709.2 PR705.2 PU700.27
N19021042: PC710.1 PR709.2 PU700.26
N19095003: PR722.2 PU700.8
N19142937: PC700.2 PC701.1 PQ704.4 PQ705.4 PQ707.1 PR701.2 PR703.1
N19197525: RX10.2 UX4.3
N19200597: QV7.1 RX3.2
N19245880: CZ15.1 U6.10
N19245882: CZ9.1 U6.12
N19565438: PQ707.2 PQ708.1
N19565442: PQ709.3 PQ710.3 PR703.2
N19565444: PQ709.2 PQ709.5 PQ712.1 PR712.2
N19565472: PQ711.1 PR708.1
N19605393: RH108.2 U2.AA9 U2.AA10 U2.AA11 U2.AB10 U2.AB11
N19634132: RX28.1 RX29.2 RX30.2
N19636367: QA6.2 RA6.2 RA7.2
N19792312: QA5.5 QA5.6 RA2.2
N19794620: QA6.5 QA6.6 RA5.2
N21178712: PQ1.3 PR5.2
N22376776: PC5.1 PQ1.2 PR1.2
N23700314: PL2.1 PQ6.1 PR6.2 PR11.1
N26541745: CH16.1 RH25.2 RH26.2 RH28.1 UH1.1 UH1.2
N29435472: PR530.1 PU500.40
N29440660: PL501.3 PR545.1
N29446286: PL500.3 PR515.1
N29452663: PR547.1 PU500.37
N29508268: PC501.2 PR508.1
N29585076: PH501.1 PR536.1
N29604543: PH500.1 PR535.2
N29680084: PC533.2 PR557.1
N29794252: PR553.2 PR554.1
N29794938: PR559.2 PR560.1
N29841026: PQ713.3 PR730.2
N29896706: C5.2 R787.2 R796.2 UG1.10
N29896995: C10.1 R790.2 UG1.14
N35316585: CE10.1 RE6.2
N37640332: RV2.2 UV1.N10
N37640410: RV3.1 UV1.AA22
N37817724: RV1.1 UV1.Y22
N38023415: CV96.1 RV36.2 RV37.2
N38028869: CV98.2 UV1.K8
N38028873: CV99.2 UV1.L7
N38028878: CV98.1 RV40.2
N38028880: CV99.1 RV41.2
N38039273: RV46.1 UV5.L8
N38046520: CV102.1 RV48.2 RV49.2
N38049955: RV47.1 UV6.L8
N38097860: CV135.1 RV54.2 RV55.2
N38342282: RV39.2 UV1.K25
N39970373: PQ710.6 PQ712.2 PR718.2
N40470227: T107.1(TP-1) U2.AD13
N40473308: T108.1(TP-1) U2.AD21
N47007806: PC16.1 PQ2.3 PR28.2
N47007810: PC16.2 PQ2.2 PR29.1
N47007850: PQ2.5 PR31.1 PR33.2
N47008006: PQ1.5 PQ1.6 PR7.1 PR10.2
N47415217: PC104.2 PR103.1
N47415258: PC103.1 PR113.2
N47415272: PC111.1 PR112.2
N47415370: PC110.1 PR111.2
N47420895: PC207.2 PR203.1
N47445410: PR114.1 PU100.19
N52907207: PQ706.4 PR706.1 PR708.2
N52907447: PQ711.2 PR714.1
N55201771: JHDMI.13 RX12.2
N59110921: RE4.1 UE1.111
N59110936: RE15.1 UE1.109
N63469524: CA68.2 RA82.1
N63469526: CA67.2 RA80.1
N64564173: PC1103.1 PR1101.2
N64564191: PC1106.1 PR1104.2
N80846772: T99.1(TP-1) U2.AM17
N80928600: T102.1(TP-1) U2.J19
N80957082: RH72.1 U2.H19
N80957084: RH75.1 U2.G19
N81028957: CH43.2 U2.M31
N84425324: T97.1(TP-1) U2.AB6

Pads without a net: DE2 2; FD1 1; FD2 1; FD3 1; FD4 1; JDIMM1 77 122 125; JEDP 38; JHDMI 14; JIO 5 7; JKB 2 3 30; JKBBL 3; JLAN 4 5 7 8; JNGFF 8 9 10 11 12 13 14 15 17 19 20 21 22 23 24 26 28 34 50 51 52 53 54 56 57 58 59 60 62 63 65; PU200 10; PU300 1; PU301 5; PU400 4; PU401 5; PU500 1 2 3 38 51 52; PU1000 35; PU1300 4; Q78 1 2 6; Q2507 3 4 5; QX6 1 2 6; QX7 3 4 5; RP15 3 6; RP16 3 6; RPH7 5; TL2 4 5 12 13; U2 A5 A6 A10 A18 A20 A22 A24 A28 AA7 AA8 AA23 AA24 AA26 AA27 AB5 AB7 AB8 AB9 AB26 AB27 AC2 AC4 AC15 AC16 AD1 AD3 AD7 AD8 AD9 AD12 AD15 AD16 AD18 AD19 AE7 AE8 AE10 AE16 AE18 AE27 AF3 AF5 AF7 AF9 AF10 AF15 AF18 AF21 AG4 AG6 AG8 AG9 AG10 AG12 AG13 AG15 AG16 AG18 AG21 AG22 AG24 AH1 AH3 AH7 AH8 AH9 AH10 AH12 AH14 AH15 AH16 AH20 AH22 AH24 AH26 AH31 AH33 AJ1 AJ3 AJ5 AJ6 AJ8 AJ10 AJ12 AJ14 AJ20 AJ22 AJ24 AJ26 AJ31 AJ33 AK7 AK9 AK11 AK13 AK15 AK17 AK23 AK27 AL1 AL3 AL5 AL6 AL8 AL10 AL12 AL14 AL16 AL22 AL24 AL26 AL28 AL29 AL31 AL33 AM7 AM9 AM11 AM13 AM15 AM23 AM27 AN3 AN5 AN6 AN8 AN10 AN12 AN14 AN22 AN24 AN26 AN29 AN31 B15 B17 B19 B21 B23 B27 C5 C6 C10 C18 C24 C29 D15 D17 D19 E8 E10 E14 E18 E20 E22 E24 F3 F8 F10 F12 F14 F15 F18 F20 F21 F22 F24 G12 G13 G15 G18 G26 G27 G28 G30 H1 H3 H5 H6 H7 H13 H18 H21 H22 H27 H28 H31 H33 J2 J12 J18 J21 J27 K10 K18 K21 K22 K26 K31 L4 L30 L32 M7 M23 M24 M26 M27 M28 M29 M33 N25 N26 N27 N30 N32 P28 P29 R23 R24 R27 R30 R32 T5 T28 T29 T31 T33 U28 V7 V8 V10 V26 V27 V28 V29 V31 V33 W7 W10 W23 W24 W26 W27 W30 W32; U64 1; U67 1; U68 1; U2407 8; UA1 14 15 16 23 24 48; UC1 A18 A20 A21 A22 A24 A25 A26 A28 A29 A30 A32 A33 A34 A36 AA27 AA28 AA36 AA37 AB4 AB5 AB6 AB8 AB9 AB34 AB35 AB36 AC2 AC5 AC6 AC8 AC9 AC30 AC36 AD1 AD2 AD35 AD36 AD37 AE2 AE5 AE7 AE8 AE10 AE30 AE36 AE37 AF1 AF2 AF3 AF4 AF10 AF11 AF32 AF35 AF36 AF37 AG2 AG16 AG36 AH1 AH2 AH35 AH36 AH37 AJ1 AJ2 AJ10 AJ34 AJ36 AJ37 AK1 AK2 AK3 AK18 AK24 AK35 AK36 AK37 AL18 AL20 AL22 AL24 AL26 AL28 AL30 AL32 AL34 AL35 AL36 AM3 AM19 AM20 AM21 AM22 AM23 AM24 AM25 AM26 AM27 AM28 AM29 AM30 AM31 AM32 AM33 AM34 AM36 AM37 AN2 AN3 AN4 AN20 AN21 AN22 AN24 AN25 AN26 AN28 AN29 AN31 AN32 AN33 AN34 AN35 AN36 B1 B2 B17 B18 B19 B20 B21 B22 B23 B24 B25 B26 B27 B28 B29 B30 B31 B32 B33 B34 B35 B36 B37 C1 C18 C20 C22 C24 C26 C28 C30 C32 C34 C36 C37 D1 D2 D5 D28 D32 D34 D35 D36 D37 E1 E2 E4 E5 E7 E19 E33 E36 E37 F1 F2 F3 F7 F8 F10 F31 F33 F34 F35 F36 F37 G2 G7 G31 G36 H1 H2 H4 H5 H7 H31 H33 H34 H35 H36 H37 J1 J2 J5 J7 J8 J30 J31 J36 J37 K1 K2 K3 K4 K34 K35 K36 K37 L2 L5 L6 L8 L9 L27 L36 M1 M2 M4 M5 M7 M8 M33 M35 M36 M37 N1 N2 N36 N37 P1 P2 P3 P4 P5 P27 P28 P35 P36 P37 R36 T35 T36 T37 U36 U37 V35 V37 W30 W31 W33 W34 W36 Y5 Y6 Y27 Y28 Y34 Y35 Y36 Y37; UE1 64 73 85 107 118 122; UL1 6 7 9 10; UV1 AA5 AA6 AB23 AC1 AC3 AC5 AC6 AC16 AC23 AD2 AD4 AD10 AD11 AD13 AD16 AD22 AD23 AD24 AE1 AE3 AE5 AE6 AE10 AE11 AE13 AE16 AE19 AE22 AE23 AE24 AE25 AE26 AF2 AF4 AF6 AF7 AF8 AF9 AF10 AF11 AF13 AF16 AF17 AF22 AF24 AF25 AG1 AG3 AG5 AG6 AG7 AG8 AG9 AG10 AG11 AG13 AG15 AG16 AG17 AG18 AG19 AG20 AG21 AG22 AG24 AG25 AG26 AH1 AH3 AH5 AH6 AH8 AH12 AH16 AH18 AH20 AH22 AH24 AH26 AJ7 AJ9 AJ13 AJ15 AJ17 AJ19 AJ21 AJ23 AJ25 AK1 AK3 AK5 AK6 AK8 AK10 AK14 AK16 AK18 AK20 AK22 AK24 AK26 AL7 AL13 AL15 AL17 AL19 AL21 AL23 AL25 AM3 AM5 AM6 AM8 AM10 AM12 AM26 J8 J22 J25 K13 K30 L16 L29 L31 M4 M27 M28 M30 N3 N5 N6 N8 N26 N29 N31 P2 P4 P7 P10 P23 P24 P26 P27 P28 P30 R29 R31 T7 T23 T24 T26 T27 T28 T30 U5 U6 U23 U24 U26 U29 U31 V2 V4 V6 V27 V30 W3 W5 W6 W7 W8 W23 W24 Y2 Y4 Y6; UV5 J1 J9 L1 L9; UV6 J1 J9 L1 L9; UV7 J1 J9 L1 L9; UV8 J1 J9 L1 L9

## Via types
v1: diameter 0.305, hole 0.152, TOP to BOTTOM, 761 vias
v2: diameter 0.508, hole 0.254, TOP to BOTTOM, 1603 vias
v3: diameter 0.457, hole 0.203, TOP to BOTTOM, 3414 vias
v4: diameter 0.406, hole 0.203, TOP to BOTTOM, 118 vias

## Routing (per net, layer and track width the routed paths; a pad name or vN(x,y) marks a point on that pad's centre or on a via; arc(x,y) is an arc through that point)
1.1VALWP_ON: length 21.7
  TOP w0.102: v1(126.69,12.22) v3(126.23,12.68)
  IN1 w0.114: v3(126.23,12.68) 125.88,12.68 124.89,11.69 121.49,11.69 118.6,8.79 116.97,8.79 114.92,6.74 v3(114.92,2.26)
  BOTTOM w0.102: RE40.1 RE46.1 126.63,13.07 v3(126.23,12.68) ; PR404.1 v3(114.92,2.26)
1.1VS_ON: length 5.8
  TOP w0.203: U15.5 130.84,2.6 130.99,2.44 v1(130.99,1.8) 130.99,1.6 131.22,1.38 133.2,1.38 133.46,1.63 C987.2 R437.2
1.8VGS_ON: length 4.3
  TOP w0.102: R436.2 99.78,65.38 v1(100.3,65.9)
  TOP w0.203: U16.5 96.77,65.28 97.03,65.54 97.95,65.54 C986.2
  TOP w0.508: R436.2 C986.2
1.35V_B+: length 4.6
  BOTTOM w0.254: 79.94,15.3 v1(79.43,14.79) 79.13,14.48 79.13,12.48 PR208.1
1.35V_ON: length 4
  TOP w0.102: v1(100.17,64.04) 99.94,64.27 R435.2
  TOP w0.203: U16.3 97.89,64.48 C1014.2
  TOP w0.508: R435.2 C1014.2
3/5V_B+: length 27.4
  TOP w0.203: PU100.12 69.41,18.51 v3(68.94,18.99)
  TOP w0.508: 59.18,15.04 58.83,14.7 58.83,11.38 61.02,9.2 67.62,9.2 68.4,9.97 68.4,18.52 68.87,18.99 v3(68.94,18.99)
  BOTTOM w0.508: v3(68.94,18.99) 69.1,18.83 PC105.1
  vias: v1(59.9,19.84) v2(58.79,17.2) v2(60.19,21.14) v2(60.19,20.5) v2(60.83,21.14) v2(60.83,20.5) v2(61.46,21.14) v2(61.46,20.5) v2(61.86,19.45) v2(61.86,18.75) v2(61.86,18.11)
3V_EN: length 12
  TOP w0.203: PU100.6 73.07,19.95 73.49,20.36 v2(73.64,20.36)
  TOP w0.254: v3(73.72,16.49) 74.07,16.49 74.93,15.63 PD101.2 75.81,14.32 v1(76.03,14.1) 76.03,11.71 PR100.1
  BOTTOM w0.254: v2(73.64,20.36) 73.64,16.57 v3(73.72,16.49)
3VGS_ON: length 4.8
  TOP w0.102: R438.2 C983.2 128.44,1.54 v1(128.96,1.54) 129.56,1.54 129.93,1.91 129.93,2.57 130.04,2.68 U15.3
5V_EN: length 6.2
  TOP w0.203: PU100.20 73.07,16.17 73.31,15.93
  TOP w0.254: 73.31,15.93 73.69,15.93 v1(74.17,15.45) 74.17,15.02 73.93,14.77 PD101.3 73.93,13.4 73.59,13.06 PR101.1
+0.675VS: length 75
  IN1 w1.016: 125.56,24.64 125.56,22.52 123.12,20.08 117.37,20.08 114.36,17.07 114.36,16.21 113.18,15.03 110.98,15.03 109.08,13.14 103.13,13.14 98.03,8.03 93.2,8.03
  IN2 w1.016: 159.14,40.95 158.07,39.88 132.06,39.88 130.92,38.74 130.92,36.33 129.17,34.57
  vias: v2(91.57,8.13) v2(92.21,8.13) v2(160.08,46.97) v2(160.56,47.43) v2(161.07,47.91) v3(124.54,25.07) v3(125.13,25.07) v3(127.56,34.22) v3(128.25,34.22) v3(160.46,40.95) v3(160.94,41.48) v4(129.09,29.96)
+0.675VSP: length 2.6
  TOP w0.203: v2(85.81,9.3) 85.4,8.89 v4(85.15,8.89) v3(84.23,8.89)
  BOTTOM w0.203: v3(84.23,8.89) 84.4,9.07 PU200.2
+1.1VALW: length 2.5
  TOP w0.102: v4(170.3,2.28) 169.79,1.77 169.13,1.77 168.66,2.24 168.66,2.28 RH109.2
  vias: v2(125.28,2.85) v2(125.28,2.21) v2(125.28,1.58) v2(125.91,4.75) v2(125.91,4.12) v2(125.91,3.48) v2(125.91,2.85) v2(125.91,2.21) v2(126.55,4.75) v2(126.55,4.12) v2(131.5,2.42) v2(131.88,1.88) v2(132.14,3.69) v2(132.24,3.05) v2(132.24,2.42) v2(132.77,3.61) v2(132.82,2.72) v2(132.77,1.99) v2(155,1.53) v2(155.77,1.53) v2(156.4,1.53) v2(167.44,1.55) v2(168.08,1.58)
+1.1VALWP: length 14.7
  BOTTOM w0.254: 110.78,1.6 110.93,1.45 123.12,1.45 123.88,2.21 123.88,3.41
  vias: v1(108.44,1.81)
+1.1VALWP_ON: length 1.5
  BOTTOM w0.102: 114.92,3.14 115.32,2.73 115.32,1.96 v1(115.22,1.86)
+1.1VS:
  vias: v2(135.31,6.41) v2(135.31,5.77) v2(135.95,6.41) v2(135.95,5.77) v2(136.58,6.41) v2(136.58,5.77) v2(137.22,6.41) v2(137.22,5.77) v2(170.85,11.28) v2(171.48,11.28) v2(172.01,18.72) v2(172.27,19.61) v2(172.9,19.61) v2(173.54,19.61) v2(174.17,19.49) v2(174.3,18.85) v2(174.48,20.04) v2(174.81,19.49) v4(174.55,23.11)
+1.1VS_CKVDD:
  vias: v1(168.4,13.45) v3(161.83,14.86) v3(162.21,15.68) v3(164.03,14.02) v3(164.8,13.2)
+1.1VS_OUT: length 4.9
  TOP w0.102: v1(136.01,2.68) 135.1,3.6 134.42,3.6 133.62,4.4 J15.1
+1.5V_D: length 2.9
  TOP w0.102: v4(134.09,36.3) RZ27.2
  TOP w0.508: RZ27.2 QZ15.1
+1.5VS: length 377.4
  TOP w0.381: R37.1 105.42,92.02 105.21,92.23 U68.5 103.97,92.23 103.01,93.19 v3(103.01,94.27) ; U67.5 103.73,97.56 103.44,97.85 103.44,98.58 v3(102.83,99.19) ; U64.5 103.97,94.89 102.09,96.78 v3(102.09,98.43)
  TOP w0.508: PR1025.1 66.89,33.84 67.14,33.58 v3(67.14,33.1) ; v3(113.42,118.42) 114.15,119.16 124.71,119.16 R54.2 125.53,117.89 v3(125.15,117.5) ; R122.2 R121.2 101.47,86.03 101.72,85.78 103.9,85.78 105.42,87.29 R37.1 ; v3(189.11,86.67) 188.09,87.69 188.09,91.13 182.22,97.01 v4(180.08,97.01) 173.3,97.01 172.95,96.65 170.82,96.65 167.39,100.08 v3(158.98,100.08) 157.6,98.69 v3(157.6,97.79)
  IN1 w0.508: v2(199.07,11.1) 200.59,11.1 205.37,15.88 205.37,18.5 204.55,19.31 v3(204.55,21.01) ; v3(102.09,98.43) 99.8,96.14 v3(99.8,96.14)
  IN2 w0.508: v3(158.98,100.08) 158.98,100.33 153.7,105.61 153.7,113.61 153.88,113.79 153.88,114.81 152.89,115.8 v3(152.89,116.31) ; v2(199.07,11.1) 199.07,13.11 198.38,13.8 198.38,15.45 197.36,16.46 195.03,16.46 194.62,16.06 191.06,16.06 187.86,19.26 187.86,21.59 186.61,22.85 186.61,29.13 187.51,30.03 187.51,33.99 188.45,34.93 189.87,34.93 190.56,35.62 191.5,35.62 196.53,40.64 196.53,51.69 197.54,52.71 197.54,68.89 196.65,69.78 196.65,71.81 197.99,73.14 197.99,77.02 197.39,77.61 197.39,82.88 195.22,85.06 190.72,85.06 v3(189.11,86.67)
  IN3 w0.508: v3(103.01,94.27) 103.01,97.5 v3(102.09,98.43)
  BOTTOM w0.508: v3(67.14,33.1) 67.14,33.71 66.6,34.24 66.6,35.64 67.34,36.38 75.11,36.38 77.65,33.84 86.92,33.84 87.62,34.54 87.62,36.57 89.08,38.03 89.46,38.03 89.85,38.41 89.85,42.3 86.57,45.58 86.57,52.38 88.12,53.93 88.12,62.51 89.39,63.78 89.39,68.35 92.69,71.66 92.69,73.94 89.9,76.74 89.9,90.12 95.92,96.14 v3(99.8,96.14) ; R36.1 157.17,97.36 v3(157.6,97.79) ; v3(152.89,116.31) 152.89,116.52 152.06,117.35 144.74,117.35 144.15,117.94 129.41,117.94 128.7,117.23 127.83,117.23 127.55,117.5 v3(125.15,117.5) ; v3(102.09,98.43) 102.09,98.45 v3(102.83,99.19) 105.76,102.13 105.76,105.26 106.66,106.16 108.12,106.16 108.95,106.99 108.95,108.45 109.35,108.86 109.35,114.36 v3(113.42,118.42) ; v3(204.55,21.01) 203.92,21.65 RA8.1
+1.05VS: length 12.3
  IN3 w0.508: v3(159.8,99.42) 160.15,99.42 v3(164.53,95.04)
  BOTTOM w0.508: v3(159.8,99.42) 158.4,99.42 157.79,100.03 154.4,100.03 R23.2
  vias: v3(147.03,96.19) v3(148.86,96.19) v3(149.5,96.19) v3(150.13,96.19) v3(150.79,96.19) v3(151.45,96.19) v3(152.11,96.19) v3(154.21,95.25) v3(155.07,95.23) v3(156.4,95.15) v3(157.03,95.13) v3(157.61,95.1) v3(158.81,95.15) v3(159.45,95.15) v3(164.52,94.37) v4(154.3,89.78)
+1.5VSP: length 11.3
  TOP w0.508: PC311.1 210.48,11.85 PR309.1 210.52,12.99 v1(209.61,13.9) 203.87,13.9 203.21,13.24 203.21,12.01 PC313.1
+1.05VSP: length 21.1
  IN2 w0.508: v2(172.62,42.88) 173.03,42.88 173.77,43.62 173.77,44.43 174.68,45.34 174.68,51.34 177.6,54.26 180.3,54.26 182.61,56.57 v3(182.61,56.67)
  BOTTOM w0.508: PR306.2 183.27,56.01 v3(182.61,56.67)
  vias: v1(176,38.85) v2(172.01,44.89) v2(171.95,44.19) v2(171.95,43.55) v2(171.95,42.85) v2(172.65,44.89) v2(172.62,44.17) v2(172.62,43.51)
+1.05VSP_B+:
  vias: v1(175.7,47.16)
+1.5VSP_ON: length 1.7
  TOP w0.127: v1(207.69,13.17) 207.07,12.55 207.07,11.73
+1.8VGS: length 158.3
  TOP w0.305: LV7.1 55.68,93.27 55.17,93.78 55.17,94.29 54.91,94.56 54.91,95.37 55.68,96.14
  TOP w0.508: v3(90.61,22.51) 88.37,24.75 88.37,28.17 87.69,28.86 87.69,33.56 v2(86.62,34.62) ; PR1022.1 64.47,32.49 v2(65.13,33.15) ; 56.42,100.13 55.68,99.39 55.68,96.14
  IN2 w0.508: v3(90.61,22.51) 101.03,22.51 107.21,16.32 108.4,16.32 110.08,14.65 112.08,14.65 112.96,13.77 112.96,11.82 112.37,11.23 112.37,10.14 112.78,9.73 113.95,9.73 116.44,12.22 124.83,12.22 125.89,13.28 125.89,13.77 127.29,15.17 131.5,15.17 135.85,10.82 v3(135.85,10.09)
  IN3 w1.27: 78.67,59.75 78.67,55.27 79.94,54 79.94,39.86 85.07,34.73
  BOTTOM w0.203: C6.1 136.73,9.93 UG1.11
  BOTTOM w0.254: CV170.2 81.72,89.72 81.63,89.8 U1.8
  BOTTOM w0.305: v3(75.49,73.46) 75.26,73.7 UV1.AM30
  BOTTOM w0.508: 85.45,34.65 82.66,34.65 80.32,36.99 76.66,36.99 75.49,38.16 69.14,38.16 68.89,37.9 67.75,37.9 65.82,35.97 65.82,35.2 65.13,34.51 v2(65.13,33.15) ; RV87.2 79,91.9 78.1,91.9 77.65,91.46 v3(77.65,90.35) ; v3(76.51,91.84) 76.51,92.75 78.56,94.8 RV84.2 ; C6.1 136.33,9.61 v3(135.85,10.09) ; RV81.2 RV82.2 65.33,102.77 63.66,104.45 62.16,104.45 61.86,104.14 v2(61.23,104.14) 61.23,103.47 61.4,103.31 61.4,102.14 61.8,101.73 RV152.2 ; CV170.2 81.26,89.29 v3(81.08,89.46)
  vias: v2(60.61,104.42) v2(76.52,91.2) v2(76.52,90.57) v2(78.03,61.27) v2(78.03,60.63) v2(86.11,35.03) v3(76.68,74.55) v3(77.27,74.57) v3(77.86,74.56) v3(80.4,78.69) v3(80.45,79.33) v3(80.89,85.83) v3(80.88,85.24) v3(80.88,84.64) v3(80.96,79) v4(85.21,70.92)
+1.8VGS_OUT:
  vias: v1(94.18,70.32)
+1.8VS: length 43.3
  IN3 w2.032: 93.4,68 92.13,68 89.59,65.46 89.59,58.86 82.23,51.49 82.23,41.33 82.47,41.08 82.47,40.88 88.19,35.15 88.19,33.79
  BOTTOM w0.305: UC1.AH11 144.7,100.38 v3(144.33,100.74) ; v3(145.07,100.81) 145.07,100.73 UC1.AJ11
  vias: v2(89.72,31.81) v2(90.1,31.3) v2(90.43,31.86) v2(90.76,31.27) v2(94.93,69.27) v2(94.93,68.64) v2(94.93,68) v2(94.93,67.37) v2(97.34,74.02) v2(97.34,73.38) v4(141.8,98.62)
+1.8VSP: length 11.6
  BOTTOM w0.254: PC414.1 90.23,28.57 90.23,29.77 88.42,31.58 83.78,31.58 82.9,30.7 PR407.1 PC412.1
  vias: v1(92.5,24.99)
+1.8VSP_ON: length 5.2
  BOTTOM w0.102: PR408.2 84.78,29.82 v1(84.7,29.75)
  BOTTOM w0.254: PU401.1 86.85,28.57 86.53,28.88 86.53,29.57 PR409.1 ; PR409.1 PR408.2 ; PR409.1 PC415.1
+1.35V: length 369.7
  TOP w0.203: PU500.18 58.95,113.76 v2(58.79,113.6)
  TOP w0.381: R40.1 R39.1
  TOP w0.508: C116.1 131.63,49.33 v3(131.88,49.08) ; R5.2 145.68,71.3 145.68,70.03 144.02,68.38 141.59,68.38 140.96,69 C82.1 ; v3(127.46,49.31) 127.45,49.31 C118.1 ; C115.1 122.87,38.15 v3(122.85,38.13) ; v3(144.74,119.31) 143.57,118.14 R620.1 ; R28.2 151.8,100.28 151.8,100.56 151.49,100.87 v3(151.49,101.1) ; C114.1 126.42,38.16 v3(126.45,38.13) ; 151.44,117.99 R622.2 149.08,117.99 v3(147.71,119.36) ; 151.44,117.99 v4(153.54,117.99) 156.44,117.99 158.55,115.88 R40.1 ; 151.44,117.99 151.44,116.9 152.64,115.7 152.76,115.7 153.22,115.24 v3(153.22,114.56) ; v3(102.93,52.25) 102.22,52.96 R57.2 ; v3(131.85,38.06) 132.01,38.22 C111.2 ; R3.1 135.83,87.02 v3(135.3,86.49) 135.22,86.41 C105.1 ; R38.1 87.69,87.05 87.31,86.67 87.31,80.71 88.89,79.13 v3(90.81,79.13) 91.36,79.67 JHDT1.19 ; C117.1 135.31,38.03 v3(135.44,37.9) 135.31,37.77 RZ27.1 135.67,37.22 136.89,36 139.64,36 140.09,36.44 R55.2 ; C112.1 128.25,49.56 127.82,49.99 v3(127.49,49.99) ; JHDT1.1 93.56,91.1 v3(94.19,90.48) ; R29.2 167.77,91.04 Q3.2 v3(171.28,93.35) ; v3(122.59,49.16) 122.59,49.13 122.61,49.16 C109.2 ; 137.8,86.57 137.8,88.12 137.6,88.32 C106.1 ; C113.1 v3(128.2,38.03) ; C110.2 134.6,49.2 v3(135.31,49.2) ; 142.83,77.83 146.36,77.83 148.22,75.98 R6.1
  IN2 w0.508: v2(58.79,113.6) 59.91,113.6 61.74,111.76 67.52,111.76 68.38,110.9 68.38,107.18 73.37,102.19 77.18,102.19 78.49,100.88 98.89,100.88 99.27,100.5 99.27,98.26 99,98 99,92.78 100.16,91.62 101.12,91.62 v2(101.78,90.96) 101.78,89.48 105.71,85.55 122.59,85.55 124.49,83.65 125.56,83.65 125.91,83.29 130.09,83.29 v3(131.49,81.89) ; v3(153.22,114.56) 153.22,114.02 153.07,113.87 153.07,103.89 153.37,103.59 153.37,101.38 152.66,100.67 ; v3(142.48,85.17) 142.48,85.82 143.82,87.15 147.66,87.15 148.02,86.79 159.85,86.79 161.73,88.67 ; 161.73,88.67 161.73,94.8 160.58,95.94 157.92,95.94 156.9,96.96 156.9,97.59 155.5,98.99 154.34,98.99 152.66,100.67 ; 161.73,88.67 166.6,88.67 v3(171.28,93.35) ; v3(151.49,101.1) 151.92,100.67 152.66,100.67
  IN3 w0.508: v3(113.24,100.13) 113.7,99.67 113.7,96.98 v3(111.59,94.87) ; v2(101.78,90.96) 94.67,90.96 v3(94.19,90.48) ; v3(144.74,119.31) 147.66,119.31 v3(147.71,119.36)
  BOTTOM w0.254: UC1.AE32 142.33,84.33 v3(142.46,84.33) ; v3(140.15,83.42) 140.11,83.42 139.63,83.9 UC1.AB32 ; v3(137.76,84.36) 138.1,84.7 UC1.Y31 ; v3(141.29,84.28) 141.12,84.28 UC1.AC31 ; v3(143.85,79.76) 143.78,79.76 143.85,79.82 143.85,80.25 UC1.AG37 ; UC1.AC37 140.7,80.02 140.52,79.84 v3(140.52,79.79)
  BOTTOM w0.279: v3(140.15,83.42) 140.16,83.4 140.16,83.04 139.86,82.73 139.76,82.73 139.32,82.3 UC1.AA34
  BOTTOM w0.305: v3(143.48,81.92) 143.76,82.2 143.8,82.2 UC1.AG34 ; UC1.L34 131.1,82.28 v3(131.49,81.89) ; JDIMM1.94 v3(126.45,38.13) ; v3(140.52,79.79) 140.4,79.9 UC1.AB37 ; v3(135.31,49.2) 135.29,49.23 133.81,49.23 133.35,48.77 JDIMM1.117 ; UC1.R29 134.67,86.3 v3(134.15,85.78) ; UC1.AC29 141.32,85.68 v3(141.32,85.68) ; v3(132.99,84.36) 132.53,83.9 UC1.M32 ; UC1.AF30 142.91,85.9 142.48,85.48 v3(142.48,85.17) 142.95,84.7 UC1.AF31 ; UC1.AC34 140.7,82.29 v3(140.33,81.92) ; UC1.AE34 142.48,82.48 v3(142.48,82.78) ; v3(132.92,81.78) 132.92,82.08 UC1.N34 ; v3(135.3,86.49) 135.49,86.3 UC1.U29 UC1.W29 ; UC1.U31 136.02,84.7 v3(136.52,84.2) 136.82,83.9 UC1.W32 ; UC1.R34 134.03,82.03 v3(134.03,81.77) ; v3(131.1,79.73) UC1.L37 ; JDIMM1.76 v3(121.05,38.03) ; v3(137.83,79.68) 137.83,79.79 137.5,80.11 UC1.W37 ; v3(132.29,87.56) 132.29,87.69 UC1.N27 ; JDIMM1.82 v3(122.85,38.13) ; UC1.V34 136.7,82.25 v3(136.34,81.89) 136.31,81.89 UC1.U34 ; v3(135.32,84.28) 135.08,84.28 UC1.R32 ; v3(131.61,85.07) 131.25,84.7 UC1.L31 ; UC1.P31 133.68,84.7 v3(134.08,84.31) ; JDIMM1.111 131.55,48.74 v3(131.88,49.08) ; UC1.L29 131.25,86.45 v3(131.74,86.45) ; UC1.P29 133.41,86.39 v3(132.88,86.39) 132.39,86.39 UC1.M29
  BOTTOM w0.356: v3(127.49,49.99) 127.62,49.99 128.02,49.59 128.02,48.74 127.95,48.67 JDIMM1.99 ; v3(135.31,49.2) 135.15,49.04 JDIMM1.123 ; JDIMM1.81 122.55,48.96 122.59,49 v3(122.59,49.16) ; JDIMM1.75 120.75,48.87 122.21,50.32 123.58,50.32 v3(123.6,50.3) 124.35,49.55 JDIMM1.87 ; JDIMM1.105 129.75,48.9 127.82,50.83 v3(127.49,50.83) ; JDIMM1.93 126.16,47.69 126.16,48.69 126.85,49.38 127.44,49.38 127.46,49.36 v3(127.46,49.31) ; v3(124.65,40.87) JDIMM1.88
  BOTTOM w0.381: JDIMM1.118 v3(133.65,38.04) ; UC1.R37 134.3,79.71 v3(134.35,79.66) ; JDIMM1.112 v3(131.85,38.06) ; UC1.V27 136.43,88.3 135.92,87.79 135.92,86.32 UC1.U29 ; UC1.AB29 139.5,86.25 v3(140.07,85.68) ; v3(128.2,38.03) 128.25,38.08 JDIMM1.100 ; JDIMM1.106 v3(130.05,38.03) ; JDIMM1.124 135.45,37.91 v3(135.44,37.9)
  BOTTOM w0.508: v3(171.28,93.35) 171.28,94.29 168.79,96.78 v2(168.48,96.78) ; v3(94.19,90.48) 92.22,88.51 92.22,80.43 90.91,79.13 v3(90.81,79.13) ; PC513.2 58.92,113.72 v2(58.79,113.6) ; v3(113.24,100.13) 113.65,100.54 R30.2 ; v2(101.78,90.96) 102.14,90.61 108.24,90.61 111.59,93.96 v3(111.59,94.87) 113.21,93.25 R65.1 R120.1 R35.1
  vias: v2(99.45,34.76) v2(99.56,27.84) v2(99.78,35.31) v2(99.77,34.19) v2(99.88,27.23) v2(100.08,34.74) v2(100.2,32.01) v2(100.18,30.89) v2(100.2,27.84) v2(100.41,35.31) v2(100.41,34.19) v2(100.51,31.42) v2(100.51,27.23) v2(100.72,34.75) v2(100.83,32.01) v2(100.83,27.84) v2(100.86,30.86) v2(101.05,35.31) v2(101.05,34.19) v2(101.15,31.42) v2(101.15,27.23) v2(101.35,34.75) v2(101.47,32.01) v2(101.53,30.84) v2(101.47,27.84) v2(101.68,35.31) v2(101.69,34.19) v2(101.78,31.42) v2(101.99,34.75) v2(102.1,32.01) v2(102.16,30.83) v2(102.33,34.19) v2(102.42,31.42) v2(102.74,32) v2(102.8,30.83) v3(119.84,45.29) v3(120.45,41.46) v3(121.19,44.78) v3(122.18,41.56) v3(123.02,45.01) v3(124.67,42.07) v3(124.9,45.37) v3(126.55,41.56) v3(127.72,41.48) v3(127.77,44.02) v3(129.11,43.34) v3(129.83,74.99) v3(129.8,74.3) v3(129.8,73.05) v3(129.95,73.66) v3(129.95,72.47) v3(130.97,41.46) v3(131.63,45.52) v3(132.44,41.53) v3(133.76,41.58) v3(133.86,45.6) v3(133.89,44.4) v3(140.14,72.39) v3(140.11,71.58) v3(140.16,73.05) v3(140.6,71.99)
+1.35V_MEM_GFX: length 87.5
  TOP w0.254: v3(36.17,78.1) 35.79,77.72 UV6.K2 ; UV7.N9 33.35,91.16 32.95,90.76 v3(32.67,90.76) ; v3(30.77,89.92) 31.24,89.92 31.75,90.43 UV7.R9 ; UV6.C1 41.38,78.52 42.15,77.75 UV6.B2 ; UV6.C1 UV6.D2 ; UV6.C1 41.34,78.52 v3(40.95,78.91) ; UV6.R9 31.72,72.12 v3(30.64,71.04) ; v3(37.73,93.12) 38.14,93.53 UV7.G7 ; UV7.B2 UV7.C1 UV7.D2 ; v3(35.37,92.34) 35.75,92.72 UV7.K8 ; v3(43.62,98.86) 43.09,98.33 UV7.A1 ; UV6.N1 33.35,79.35 v3(33.53,79.53) ; UV6.H2 37.36,77.72 37.75,78.11 v3(37.75,78.08) ; v3(39.36,78.94) 38.95,78.53 UV6.F1 ; v3(36.66,91.22) 36.66,91.24 37.35,91.93 UV7.H9 37.48,91.93 38.07,91.34 v3(39.71,91.34) 39.75,91.38 UV7.E9 ; UV6.A1 42.95,78.49 v3(43.51,77.92) ; UV6.C9 41.35,71.57 v3(41.39,71.53) ; v3(40.32,91.34) 40.32,91.7 UV7.D9 ; v3(43.16,71.51) 43.41,71.76 43.41,72.46 UV6.A8 ; v3(43.99,92.31) 43.99,92.31 43.99,92.31 44,92.31 43.57,92.73 UV7.A8 ; UV6.N9 33.33,72.12 v3(32.94,72.51) ; v3(32.97,98.85) 33.35,98.47 UV7.N1 ; v3(31.36,98.85) 31.75,98.46 UV7.R1 ; UV6.G7 v3(37.78,73.35)
  TOP w0.305: v3(31.2,79.67) 31.37,79.67 31.75,79.29 UV6.R1 ; v3(37.67,97.94) 37.35,97.62 UV7.H2 ; UV7.C9 41.35,91.74 v3(40.93,91.32) ; UV6.D9 v3(40.16,72.51)
  TOP w0.381: CV160.1 27.39,90.2 27.39,90 27.95,89.44 v3(28.53,89.44) ; v3(56.93,84.91) 56.93,85.2 CV42.1
  TOP w0.508: v3(34.73,103.18) 34.47,102.93 RV51.1 ; v3(28.66,79.41) 28.66,78.7 28.38,78.41 CV43.1 CV44.1 CV45.1
  IN2 w0.508: v3(41.39,71.53) 42.22,72.37 43.01,72.37 43.16,72.22 v3(43.16,71.51)
  IN3 w0.508: v3(35.77,100.72) 35.69,100.79 35.69,101.55 34.73,102.52 v3(34.73,103.18)
  BOTTOM w0.203: UV6.K8 35.35,72.52 35.35,71.84 35.68,71.51 v3(35.8,71.51)
  BOTTOM w0.254: UV1.J9 58,89.7 57.65,90.05 v3(57.6,90.05) ; UV7.N1 33.35,98.47 v3(32.97,98.85) ; v3(43.16,71.51) 43.19,71.53 43.19,71.88 UV5.A1 UV5.B2 ; v3(41.39,69.68) v3(41.39,71.53) 41.35,71.57 UV6.C9 ; UV8.D9 40.55,98.43 v3(40.16,98.81) 40.14,98.81 39.75,98.42 UV8.E9 ; UV7.R1 31.75,98.46 v3(31.36,98.85) ; UV1.K10 58.75,88.9 v3(58.4,89.25) ; UV1.J24 58,77.77 v3(57.64,78.13) 58,78.5 UV1.J23 ; v3(57.6,89.25) 57.65,89.25 58,88.9 UV1.J10 ; v3(58.39,78.1) 58.79,78.5 UV1.K23 ; UV5.G7 38.18,76.92 v3(38.57,77.32) ; UV7.C9 41.35,91.74 v3(40.93,91.32) ; UV1.K9 58.75,89.7 v3(58.4,90.05) ; UV5.D2 40.55,72.91 v3(40.16,72.51) ; UV8.A1 42.79,91.93 42.15,92.57 UV8.B2 ; UV8.A1 43.61,91.93 v3(43.99,92.31) ; UV8.A1 42.95,91.41 42.93,91.4 v3(42.93,91.37) ; UV6.N9 33.33,72.12 v3(32.94,72.51) ; v3(38.36,96.27) 38.36,96.52 UV8.G7 ; UV5.H2 v3(37.78,73.35) ; UV8.H9 37.35,98.26 v3(37.67,97.94) ; UV8.H2 37.37,92.73 37.73,93.09 v3(37.73,93.12) ; v3(30.64,71.04) 31.72,72.12 UV6.R9 ; v3(43.62,98.86) 43.67,98.81 43.67,98.78 43.74,98.71 43.74,97.99 43.28,97.53 42.95,97.53 UV8.A8 ; UV1.H13 56.67,87.23 56.67,87.28 v3(56.7,87.3) ; UV1.K24 v3(58.4,77.3) ; v3(43.51,77.92) 43.31,77.72 UV5.A8 ; v3(39.37,71.64) 39.37,71.7 UV5.F1
  BOTTOM w0.305: UV1.L22 59.6,79.3 59.25,78.95 v3(59,78.95) ; v3(56.8,81.3) 57.2,81.7 UV1.H19 ; UV8.D2 UV7.C9 ; UV6.C1 41.34,78.52 v3(40.95,78.91) 40.56,78.52 UV5.D9 ; UV1.L21 59.6,80.3 59.39,80.09 v3(58.97,80.09) ; v3(56.93,84.91) 56.93,84.61 57.2,84.34 UV1.H16 ; v3(40.93,98.81) 41.35,98.39 UV7.C1
  BOTTOM w0.381: UV1.L20 59.07,81.3 v3(58.98,81.39) ; UV1.L11 60.13,87.57 v3(60.13,87.56) ; UV1.L13 59.6,86.24 v3(59.98,86.62) 59.6,86.99 UV1.L12
  BOTTOM w0.508: v3(37.37,83.42) 37.52,83.27 RV43.1 ; CV122.1 CV107.1 41.33,69.62 v3(41.39,69.68) ; RV42.1 v3(36.63,67.33) ; v3(40.95,100.69) 40.82,100.81 CV162.1 CV161.1 ; v3(36.38,100.72) CV140.1 CV139.1 ; CV180.1 CV158.1 42.6,100.89 v3(42.54,100.83)
  vias: v2(37.39,55.55) v2(38.03,55.55) v2(38.66,55.55) v2(39.43,55.05) v2(40.19,55.05) v2(40.82,55.05) v2(41.59,55.05) v2(42.73,55.05) v2(43.49,55.05) v2(44.25,55.05) v2(44.89,55.05) v2(45.4,58.48) v2(45.4,57.84) v2(46.03,58.48) v2(46.03,57.84) v2(46.67,58.48) v2(46.67,57.84) v2(47.3,58.48) v2(47.3,57.84) v2(47.94,58.48) v2(47.94,57.84) v2(48.57,58.48) v2(86.04,62.67) v2(86.04,62.03) v2(86.16,65.59) v2(86.67,66.1) v2(86.67,63.43) v2(86.67,62.79) v2(86.67,62.16) v2(86.67,61.52) v2(87.31,64.06) v2(87.31,63.43) v2(87.31,62.79) v2(87.31,62.16) v2(87.31,61.52) v3(28.56,80.95) v3(28.74,72.5) v3(28.73,71.86) v3(29.11,71.25) v3(29.57,70.72) v3(29.87,100.5) v3(29.85,70.03) v3(30.66,100.52) v3(31.19,69.69) v3(31.35,100.51) v3(32.09,100.51) v3(32.06,69.67) v3(35.55,69.8) v3(36.38,69.6) v3(36.9,70.05) v3(39.88,80.57) v3(40.49,80.57) v3(41.1,80.57) v3(55.83,69.76) v4(87.5,65.08)
+1.35VGPUP: length 12.9
  BOTTOM w0.254: 42.6,54.03 42.35,54.28 35.26,54.28 33.72,52.75 33.72,51.5 33.08,50.86 PR1107.2
  vias: v2(43.49,50.98) v2(43.49,50.35) v2(44.13,50.98) v2(44.13,50.35) v2(44.76,50.98) v2(44.76,50.35) v4(48,49.65)
+1.35VGPUP_B+: length 3
  TOP w0.102: PQ1100.5 35.65,43.16 v1(34.88,43.93)
+1.35VP: length 32.1
  TOP w0.102: v3(83.47,8.03) 83.93,8.03 84.08,7.88 v1(84.08,7.1)
  TOP w0.508: v3(83.47,8.03) 83.24,7.8 PC214.2
  IN2 w0.254: v3(97.31,10.62) 96.02,9.33 86.57,9.33 85.63,8.39 84.08,8.39 83.72,8.03 v3(83.47,8.03)
  IN2 w1.016: v2(98.1,12.63) v2(97.21,12.63) 94.93,10.34 86.92,10.34 v2(86.54,10.72)
  BOTTOM w0.254: PR207.2 82.86,8.36 82.86,8.87 83.2,9.21 PU200.5
  BOTTOM w0.381: PR207.2 83.19,8.31 v3(83.47,8.03)
  vias: v2(86.54,10.09)
+1.35VS_MEM_GFX_OUT:
  vias: v1(94.46,60.13)
+3VALW: length 314.2
  TOP w0.127: v3(105.85,34.8) 105.85,34.54 v4(106.48,33.9)
  TOP w0.508: 146.57,9.05 146.87,9.35 146.87,12.79 146.57,13.09 RH110.2 ; RH73.1 144.81,21.03 v3(145.28,20.56) ; PR115.1 74.45,22.36 75.7,23.6 76.26,23.6 77.12,22.74 v3(77.12,21.54) ; v2(183.57,24.69) 183.83,24.95 CH466.1 ; 146.54,22.03 146.41,21.9 RH57.1 ; 146.54,22.03 149.05,22.03 149.15,22.13 RH61.1 RH60.1 150.35,22.13 150.83,21.64 RH107.2 ; 146.54,22.03 v3(145.78,22.79) ; v3(111.23,32.47) v4(111.23,31.23) 111.23,30.1 111.99,29.34 v3(112.6,29.34) ; v3(102.47,20.15) 99.6,20.15 v2(98.23,21.52) ; v3(78.52,92.66) 78.07,93.11 RV94.1 ; RH81.1 164.78,2.44 164.5,2.16 v3(164.5,2.06) 164.06,1.63 160.31,1.63 159.54,2.39 159.54,3.33 v3(159.65,3.43) 160.14,3.93 160.14,5.58 ; v3(128.07,17.23) 128.4,16.9 CE61.2 ; v3(166.71,4.96) 167.81,4.96 169.31,6.46 169.96,6.46 170.49,6.99 170.49,8.08 168.48,10.09 LH7.2 ; v3(140.8,15.93) 141.84,15.93 RH89.1
  IN1 w0.508: v2(105.97,9.71) 107.24,10.98 v3(110.57,10.98) 111.84,9.71 113.7,9.71 114.66,10.67 v3(116.16,10.67) ; v3(142.13,20.18) 142.01,20.3 v3(139.58,20.3)
  IN1 w1.016: 11,72.8 10.22,73.59 10.22,80.04 11.61,81.44 11.61,85.91 10.6,86.92 10.6,91.39 12.1,92.89 15.6,92.89 19.95,97.24 24.58,97.24 25.33,97.98 ; 37.52,105.59 37.47,105.54 37.47,104.99 36.14,103.66 36.14,103.05 35.26,102.17 29.52,102.17 26.34,98.99
  IN2 w0.508: v3(111.23,32.47) 111.23,32.77 110.04,33.96 106.43,33.96 105.85,34.55 v3(105.85,34.8) ; v3(142.13,20.18) 144.9,20.18 v3(145.28,20.56) ; v3(135.25,15.11) 135.18,15.11 135.18,15.17 135.39,15.37 139.93,15.37 140.49,15.93 v3(140.8,15.93)
  IN2 w1.016: 39.12,106.3 39.38,106.05 44.02,106.05 46.25,103.83 57.2,103.83 57.98,104.61 59.53,104.61 60.75,105.83 62.81,105.83 64.75,103.89 66.6,103.89 69.49,101.01 70.3,101.01 71.53,99.78 71.53,99.77 72.04,99.27 72.04,99.27 73.01,98.3 75.75,98.3 76.49,97.57 82.3,97.57 85.5,94.37 85.5,93.32 ; 92.51,42.37 92.51,51.16 91.67,52 91.67,54.28 92.14,54.74 92.14,70.95 92.74,71.55 92.74,73.61 85.26,81.09 85.26,91.71 85.25,91.72
  IN3 w0.508: v3(139.58,20.3) 138.74,21.14 137.45,21.14 v3(135.79,22.79) ; v3(78.52,92.66) v3(84.77,92.66) ; v3(135.25,15.11) 135.18,15.11 135.18,15.17 133.86,16.49 128.81,16.49 v3(128.07,17.23) ; v3(145.78,22.79) 145.73,22.74 145.73,21.54 145.28,21.09 v3(145.28,20.56)
  BOTTOM w0.254: RPH5.1 141.97,19.8 142.13,19.95 v3(142.13,20.18)
  BOTTOM w0.508: v3(134.37,29.81) 134.37,28.1 133.03,26.75 133.03,24.29 134.72,22.59 135.6,22.59 v3(135.79,22.79) ; RH86.1 RH85.1 159.89,4.33 159.89,3.68 v3(159.65,3.43) 159.54,3.33 159.54,2.54 159.21,2.21 152.63,2.21 ; PR25.2 128.2,25.28 v2(127.82,25.28) ; RE3.2 v3(105.85,34.8) ; RE1.1 105.58,11.03 103.77,11.03 101.68,13.11 101.68,18.37 102.03,18.72 RE8.2 ; v3(164.5,2.06) 164.47,2.04 164.47,1.81 164.75,1.53 166.35,1.53 166.76,1.93 166.76,3.92 166.27,4.4 166.15,4.4 ; RE16.1 114.74,11.24 115.31,10.67 v3(116.16,10.67) ; RE71.1 v3(127.26,22.53) ; 166.15,4.4 v3(166.71,4.96) ; 166.15,4.4 RH117.1 ; R791.1 133.61,11.82 v3(133.84,11.59) ; RE70.1 111.23,32.95 v3(111.23,32.47) ; v3(143.14,34.55) 142.08,33.49 UH1.5 ; RE63.1 RE62.1 102.83,20.5 v3(102.47,20.15) ; v3(186.98,20.5) 186.49,20.5 185.83,21.16 RA10.1 ; RE21.1 110.17,11.38 v3(110.57,10.98) ; RH53.1 139.48,20.8 139.58,20.71 v3(139.58,20.3)
  vias: v2(11,71.78) v2(10.98,71.15) v2(12.48,64.9) v2(12.48,64.27) v2(25.33,98.91) v2(25.33,98.28) v2(38,106.68) v2(38.51,107.14) v2(70.54,30.92) v2(70.92,30.28) v2(71.3,30.92) v2(71.56,30.28) v2(71.94,30.92) v2(77.4,26.73) v2(77.91,26.22) v2(78.29,25.71) v2(78.54,26.34) v2(78.92,25.84) v2(79.3,25.33) v2(80.19,26.47) v2(80.45,27.11) v2(80.83,26.47) v2(80.83,25.84) v2(81.21,27.11) v2(81.46,26.47) v2(81.46,25.84) v2(81.97,26.85) v2(82.61,26.98) v2(87.05,40.7) v2(87.05,40.06) v2(87.05,39.43) v2(87.69,40.7) v2(87.69,40.06) v2(87.69,39.43) v2(88.32,40.7) v2(88.32,40.06) v2(88.32,39.43) v2(93.99,40.95) v2(94.44,40.42) v2(96.96,21.52) v2(97.59,21.52) v2(105.34,9.45) v2(105.34,8.82) v2(133.53,10.32) v2(134.19,10.32) v2(145.75,7.32) v2(146.39,7.55) v2(150.81,3.22) v2(152.23,3.22) v2(159.29,118.67) v2(159.95,118.67) v2(160.61,118.67) v2(161.25,118.65) v2(167.27,116.92) v2(167.27,116.29) v2(170.63,118.44) v2(170.62,117.78) v2(176.74,37.67) v2(176.74,37.04) v2(177.37,37.67) v2(177.37,37.04) v2(183.22,23.91) v2(183.83,24.08) v2(183.8,23.37) v3(167.06,42.42) v3(167.06,41.84) v3(167.65,42.4) v3(167.7,42.98) v3(211.64,7.04) v3(211.64,6.41) v3(212.3,7.04) v3(212.3,6.41) v4(98.8,18.66)
+3VALW_15: length 3.8
  BOTTOM w0.254: R791.2 v1(133.7,10.9) 134.68,10.9 135.13,11.35 UG1.15
  BOTTOM w0.508: R791.2 R793.2
+3VALW_EC: length 234.8
  TOP w0.508: v3(106.58,16.08) 106.58,14.86 108.57,12.88 111.77,12.88 v3(112.35,13.47) 113.16,14.28 115.74,14.28 115.91,14.11 ; v3(107.22,34.8) v4(108.69,33.33) 115.5,33.33 117.66,31.17 ; 115.91,14.11 115.91,16.85 116.9,17.84 116.9,24.4 116.3,25 116.3,29.81 117.66,31.17 ; 115.91,14.11 117.42,12.6 119.78,12.6 v3(120.25,13.07) ; v3(19.87,18.47) 20,18.34 PR16.2 ; 117.66,31.17 120.33,31.17 120.76,31.6 v3(120.76,31.98) ; v3(12.91,48.95) 11.18,50.68 11.18,55.68 11.8,56.3 JLED.3
  IN1 w0.508: v3(106.58,16.08) 106.58,17.15 97.33,26.4 89.91,26.4 82.99,33.33 76.18,33.33 75.83,33.68 70.47,33.68 66.33,29.54 56.01,29.54 53.08,26.61 53.08,16.27 52.36,15.55 50.5,15.55 48.24,13.29 46.16,13.29 45.12,12.25 41.59,12.25 41.08,11.74 41.08,10.72 40.7,10.34 36.57,10.34 28.47,18.44 19.89,18.44 v3(19.87,18.47) ; v3(124.47,16.67) 123.07,16.67 120.25,13.85 v3(120.25,13.07)
  IN3 w0.508: v3(12.91,48.95) 14.93,46.93 16.1,46.93 19.87,43.16 19.87,39.86 19.26,39.25 19.26,19.87 19.87,19.26 v3(19.87,18.47)
  BOTTOM w0.203: UE1.96 121.19,31.51 120.72,31.98 v3(120.76,31.98) ; CE1.1 112.76,12.58 113.09,12.91 113.09,13.57 112.79,13.86 UE1.22 ; CE4.1 119.13,13.14 118.9,13.14 118.55,13.49 118.55,13.56 117.99,14.11 UE1.9 ; UE1.125 125.63,17.79 CE2.1
  BOTTOM w0.508: v3(120.25,13.07) 119.75,12.58 CE4.1 ; CE2.1 CE3.1 125.41,16.69 125.38,16.67 v3(124.47,16.67) ; CE1.1 112.68,12.58 112.53,12.73 112.53,13.29 v3(112.35,13.47) ; LE1.1 107.89,35.48 v3(107.22,34.8) ; CE5.2 122.64,32.36 122.22,31.94 121.48,31.94 121.37,32.06 120.83,32.06 v3(120.76,31.98)
+3VALWP: length 7.3
  TOP w0.254: PR109.1 PC102.1 v3(77.02,20.11)
  IN1 w0.508: v3(74.38,24.49) 74.38,23.14 75.44,22.08 75.44,21.29 76.62,20.11 v3(77.02,20.11)
  vias: v1(67.3,30.54)
+3VGS: length 203.4
  TOP w0.381: UV2.5 77.75,75.94 v3(77.55,75.75)
  TOP w0.508: v3(77.4,95.31) 74.59,95.31 73.83,94.54 72.62,94.54 72.24,94.92 RV148.1 70.62,96.19 v3(70.24,96.58) ; v3(77.4,95.31) RV147.1 ; v3(77.4,95.31) 77.34,95.24 RV93.1 ; LV4.1 69.02,86.42 v3(69.4,86.03) ; v3(59.24,103.15) 58.91,102.82 58.91,102.42 58.86,102.37 RV154.1 ; RV91.2 v3(62.92,100.13) ; 125.71,9.33 v4(122.8,9.33) 121.37,9.33 120.45,8.41 114.99,8.41 114.08,7.5 109.96,7.5 103.9,13.56 103.9,20.29 101.28,22.92 91.09,22.92 89.74,24.26 89.74,29.72 88.47,30.99 88.47,38.03 v3(89.24,38.79) ; v3(65.64,99.5) 65.94,99.19 v3(66.91,99.19)
  IN1 w0.508: v3(77.4,95.31) 77.83,95.74 v3(81.03,95.74) 81.03,93.86 82.58,92.31 82.58,88.68 v3(83.75,87.51) ; v3(91.88,71.91) 91.88,67.49 90.02,65.64 90.02,62.31 90.63,61.7 90.63,42.65 89.24,41.25 v3(89.24,38.79)
  IN2 w0.508: v3(56.32,105.21) 56.29,105.19 53.93,105.19 53.27,105.85 51.62,105.85 v3(49.69,107.78)
  BOTTOM w0.254: CV166.2 81.63,95.52 U1.1
  BOTTOM w0.305: v3(66.91,99.19) 66.91,101.43 67.39,101.91 QV1.2 ; QV1.5 70.03,101.91 71.43,100.51 71.43,98.99 70.92,98.48 RV5.1
  BOTTOM w0.381: 49.69,108.97 50.44,109.72 UV3.1 52.14,109.72 52.58,109.28
  BOTTOM w0.508: v3(77.4,95.31) 78.19,96.09 78.19,97.3 78.83,97.95 84.21,97.95 84.61,97.54 84.61,96.93 RV72.2 ; v3(56.32,105.21) 56.17,105.06 54.57,105.06 53.85,105.77 RV58.2 ; 83.75,77.92 85.82,77.92 91.83,71.91 v3(91.88,71.91) ; 83.75,77.92 v3(83.75,87.51) RV71.2 RV79.2 ; 83.75,77.92 80.28,77.92 80.27,77.91 RV162.1 79.89,78.13 79.38,78.64 78.62,78.64 77.96,77.98 77.96,76.79 77.55,76.38 v3(77.55,75.75) ; RV6.1 66.91,98.94 v3(66.91,99.19) ; CV166.2 v3(81.03,95.74) ; 52.58,109.28 52.94,108.92 CV10.1 ; RV5.1 v3(70.24,96.58) ; 49.69,108.97 v3(49.69,107.78) 49,107.09 45.8,107.09 45.42,107.47 RV146.1
+3VGS_OUT:
  vias: v1(127.54,5.27)
+3VLP: length 435.5
  TOP w0.203: v3(74.73,18.11) PU100.3
  TOP w0.508: PC109.1 74.87,18.1 74.86,18.11 v3(74.73,18.11) ; v3(90.51,39.02) 90.51,34.14 89.08,32.72 89.08,31.3 90.35,30.03 90.35,24.52 91.32,23.55 101.66,23.55 104.51,20.69 104.51,14.72 v3(107.63,11.61) 110.8,11.61 112.63,9.78 119.82,9.78 122.18,12.15 125.53,12.15 127.03,10.65 128.8,10.65 129.84,9.61 v3(130.49,9.61) ; v3(170.7,119.15) 169.69,119.15 168.2,117.66 v4(163.99,117.66) 160.51,121.14 145.98,121.14 v3(145.47,120.63) ; v3(148.85,3.24) 149.01,3.08 DH2.2 ; v3(127.82,28.22) 126.75,27.16 126.75,25.07 v3(127.9,23.93)
  IN1 w0.508: v3(145.47,120.63) 144.86,120.63 143.49,119.26 118.42,119.26 116.95,117.78 116.95,117.56 115.4,116.01 v3(115.4,114.84)
  IN2 w0.508: v3(127.9,23.93) 128.25,23.58 128.25,19.18 128.81,18.62 v3(129.39,18.62) ; v3(148.85,3.24) 136.49,3.24 135.91,3.81 134.47,3.81 130.49,7.8 v3(130.49,9.61) ; v3(74.73,18.11) 74.35,18.5 74.35,21.7 73.62,22.43 71.79,22.43 70.26,23.96 69.32,23.96 66.17,27.11 45.12,27.11 41.45,30.78 31.97,30.78 26.09,36.66 26.09,38.05 25.15,38.99 25.15,40.7 10.75,55.1 v3(10.75,58.35)
  IN3 w0.508: v3(107.63,11.61) 107.63,9.83 105.9,8.11 94.19,8.11 86.62,15.68 81.77,15.68 81.11,16.34 78.7,16.34 77.37,17.66 75.55,17.66 75.09,18.11 v3(74.73,18.11) ; v3(99.75,88.98) 99.24,88.47 97.34,88.47 95.84,86.97 93.68,86.97 92.77,87.89 92.77,91.47 94.82,93.53 100.45,93.53 100.89,93.97 102.04,93.97 102.48,93.53 104.02,93.53 104.83,94.34 104.83,100.09 109.56,104.81 109.56,107.94 115.45,113.83 115.45,114.79 v3(115.4,114.84)
  BOTTOM w0.508: v3(127.9,23.93) 128.28,23.55 RE4.2 ; RE49.2 170.98,119.15 v3(170.7,119.15) ; R32.2 110.6,92.1 108.49,90 100.77,90 v3(99.75,88.98) 99.75,77.86 90,68.1 90,63.43 89.03,62.46 89.03,53.83 87.26,52.05 87.26,45.76 90.51,42.51 v3(90.51,39.02) ; v3(130.49,9.61) 130.99,10.11 130.99,11.28 131.53,11.82 R793.1 131.76,12.32 132.21,12.78 132.21,14.56 129.75,17.02 129.75,18.27 v3(129.39,18.62) ; RE333.2 14.03,62.29 10.75,59.01 v3(10.75,58.35) ; RE30.1 127.36,27.36 127.82,27.82 v3(127.82,28.22) ; RE2.1 v3(107.63,11.61)
+3VS: length 381.8
  TOP w0.203: v3(98.66,100.23) 98.93,100.5 RP16.1 ; v3(98.25,99.78) 98.33,99.7 99.4,99.7 99.7,100 RP16.2 ; v3(97.82,99.34) 98.16,99 RP16.4
  TOP w0.254: U2407.1 125.82,35.22 125.99,35.39 C2498.1 ; RPH5.3 140.89,18.8 v3(140.59,18.51) 140.79,18.3 RPH5.4
  TOP w0.381: QH31.5 QH31.2 143.49,17.96 v3(143.24,17.72)
  TOP w0.508: LH1.1 168.74,8.07 v3(168.74,7.93) ; RH83.1 138.57,15.14 137.9,15.8 137.9,18.17 138.33,18.6 RH134.1 138.66,18.85 139.07,19.26 139.3,19.26 v3(139.45,19.41) ; RH82.1 160.84,31.12 RH39.1 RH133.1 165.11,31.12 165.69,31.7 v3(165.69,32.16) ; CA58.1 199.21,14.1 CA57.1 199.73,14.62 200.65,14.62 v3(200.69,14.58) ; v3(196.45,74.12) 196.6,73.97 RX12.1 ; RE331.1 v3(12.54,70.48) ; CA60.1 195.14,14.75 195.14,15.49 v3(195.15,15.5) 194.85,15.8 CA59.1 ; v3(145.42,28.2) 145.78,27.84 RH112.2 ; RC13.1 v3(166.6,94.42) ; RS28.1 RS19.1 180.6,21.8 v3(180.6,22.33) ; 172.88,29.6 173.62,29.6 176.71,26.5 176.71,24.59 177.68,23.63 v3(177.68,22.38) 177.35,22.38 176.97,22 RS27.1 176.64,21.72 176.08,21.16 176.08,19.69 ; v2(176.71,60.13) 173.98,60.13 RM7.1 174.11,59.36 v2(176.71,59.36) ; RA2.1 RA1.1 189.54,19.69 187.36,19.69 v3(187.15,19.89) 186.32,19.05 183.01,19.05 182.3,19.77 v3(182.3,20.17) 182.3,20.53 182.56,20.78 RS33.2 ; RS26.1 185.86,11.23 184.74,10.11 183.44,10.11 182.89,10.67 182.89,11.33 RS30.1 RS20.1 181.79,10.65 180.82,9.67 179.32,9.67 178.36,10.62 v3(178.14,10.62) 177.73,11.03 RS34.2 RS29.1 ; v3(116.13,21.26) 116.13,23.97 115.5,24.6 115.5,26.85 114.61,27.74 114.61,28.76 ; 176.08,19.69 176.08,19.66 174.91,18.5 174.91,16.62 175.19,16.34 v3(175.57,16.34) 176.03,16.34 RS38.2 ; 176.08,19.69 176.28,19.49 RS25.1 ; C128.1 157.53,47.27 C129.1 158.43,46.03 v3(158.4,46) 158.78,46 159.98,44.81 161.73,44.81 164.83,41.71 164.83,39.76 166.73,37.85 167.82,37.85 v3(169.09,36.58) ; v3(175.98,93.1) 175.98,90.07 176.21,89.84 R537.1 ; RH96.1 v3(149.09,28.82) ; v3(175.7,13.14) CS27.1 CS42.1 ; RA7.1 v3(191.14,34.93) ; RX13.1 189.97,92.46 189.64,92.13 QX3.2 v3(190.89,91.32) ; QX5.1 v3(191.75,73.59) ; QM1.2 v2(186.48,60.27) ; RX27.1 v3(5.43,84.27) ; v3(126.73,36) 126.35,36.38 C2498.1 ; v3(69.87,107.67) 69.69,107.5 PR541.1 ; v3(133.64,32.69) R2448.1 132.72,32.29 130.54,30.1 v3(130.54,25.35) ; v3(2.88,82.22) 3,82.35 CX1.1
  IN1 w0.508: v3(166.6,94.42) 166.96,94.06 169.58,94.06 171.68,96.17 v3(171.68,97.41) 171.68,98.48 167.49,102.67 v3(167.11,102.67) ; v3(191.14,34.93) 188.35,34.93 187.34,33.93 187.34,29.84 186.59,29.09 186.59,22.86 187.76,21.7 187.76,20.2 187.46,19.89 v3(187.15,19.89) ; v3(178.14,10.62) 177.88,10.37 177.88,9.55 176.37,8.05 171.92,8.05 171.25,8.72 169.33,8.72 168.74,8.12 v3(168.74,7.93) 168.74,7.44 168.16,6.86 166.87,6.86 164.68,4.68 164.29,4.68 v3(164.24,4.63) ; v3(195.15,15.5) 196.45,16.79 198.38,16.79 198.43,16.84 ; v3(85.38,97.34) 96.89,97.34 98.43,98.88 98.43,99.6 v3(98.25,99.78) ; 198.43,16.84 v3(200.69,14.58) ; 198.43,16.84 198.43,21.59 199.83,22.99 v3(200.34,22.99) ; v3(127.59,11.35) 127.12,11.82 127.12,13.17 125.69,14.61 125.69,17.55 125.66,17.58 124.54,18.7 v3(124.52,18.7)
  IN2 w0.508: v3(195.15,15.5) 194.39,14.74 191.14,14.74 190.68,15.19 190.68,15.54 187.15,19.07 v3(187.15,19.89) ; v3(121.9,32.62) 123.01,32.62 126.38,36 v3(126.73,36)
  IN3 w0.508: v3(12.54,70.48) 12.54,72.18 11.56,73.16 v3(8.16,73.16) ; v3(113.19,11) 112.96,11.23 112.96,15.57 112.83,15.7 v3(112.83,16.57) ; v3(175.7,13.14) 176.31,13.75 176.31,15.6 v3(175.57,16.34)
  BOTTOM w0.203: JEDP.34 2.6,82.5 v3(2.88,82.22) 2.65,82 JEDP.35 ; UA1.1 198.79,16.44 200.64,14.58 v3(200.69,14.58) ; UA1.36 199.09,22.54 200.34,23.78 ; UA1.9 195.53,16.02 195.15,15.65 v3(195.15,15.5)
  BOTTOM w0.305: JDIMM1.199 157.95,46.46 v3(158.4,46)
  BOTTOM w0.381: v3(198.94,74.63) 198.41,74.63 198.05,74.99 QX4.5 ; QX4.2 v3(198.05,78.01)
  BOTTOM w0.508: v3(61.86,30.76) 62.58,31.47 PR1020.1 ; v3(180.6,22.33) 180.6,21.31 180.47,21.19 ; RE34.1 v3(102.44,16.06) ; v3(150.65,33.68) 150.65,35.6 150.36,35.88 RH116.1 149.9,36.73 149.36,37.27 147.55,37.27 147.04,36.75 RH115.1 RH114.1 ; RH78.1 162.1,2.19 162.67,2.19 164.01,3.54 164.01,4.4 v3(164.24,4.63) ; v3(55.68,41.08) 55.68,40.36 55.99,40.06 PR1030.1 ; 184.41,95.79 180.83,99.37 179.53,99.37 178.19,100.72 RL37.2 ; 184.41,95.79 186.42,95.79 v3(190.89,91.32) ; 184.41,95.79 178.67,95.79 v3(175.98,93.1) 175.98,93.12 v3(171.68,97.41) ; v3(175.7,13.14) 176.18,12.65 177.25,12.65 178.14,11.76 v3(178.14,10.62) ; JIO.6 v3(26.63,48.95) ; RE38.1 v3(102.5,16.95) ; v3(113.19,11) 113.29,11 113.72,11.43 RE32.1 ; 180.47,21.19 179.13,21.19 177.93,22.38 v3(177.68,22.38) ; 180.47,21.19 181.87,21.19 182.3,20.76 v3(182.3,20.17) ; RH84.1 RH87.1 164.01,36.25 164.93,37.16 165.89,37.16 ; v3(121.9,32.62) 121.72,32.8 RE12.1 ; v3(133.64,32.69) 133.64,34.5 132.52,35.62 127.11,35.62 v3(126.73,36) ; RA155.2 189.89,17.07 187.15,19.81 v3(187.15,19.89) ; RH79.1 RH80.1 166.07,35.97 166.07,36.99 165.89,37.16 ; v3(200.34,22.99) RA9.1 ; RE68.2 128.49,11.35 v3(127.59,11.35) 127.36,11.12 127.36,8.82 127.92,8.26 127.92,4.09 129.09,2.93 v2(129.09,2.42) ; v3(167.11,102.67) 167.24,102.8 RL33.1 ; RH135.1 v3(169.09,36.58) 168.33,37.34 166.07,37.34 165.89,37.16 ; v3(12.54,70.48) 13.4,70.48 14,69.88 14,67.34 13.39,66.73 RE50.1 ; RH41.1 160.56,35.88 160.86,35.58 v3(160.86,34.42) ; v3(32.19,43.74) PR1110.1
  vias: v2(7.91,101.73) v2(9.58,101.68) v2(10.39,100.26) v2(10.93,99.9) v2(18.98,76.79) v2(19.61,76.79) v2(20.25,76.79) v2(67.62,35.74) v2(68,35.11) v2(68.26,35.74) v2(68.64,35.11) v2(68.89,35.74) v2(172.78,30.92) v2(172.78,30.28) v2(187,62.03) v2(193.99,76.97) v4(68.76,33.9)
+3VS_CAM: length 4.2
  TOP w0.102: v1(1.9,84.69) 2.11,84.9 v3(2.8,84.9)
  TOP w0.508: v3(2.8,84.9) 3.08,84.9 4.03,83.95 RX27.2
  BOTTOM w0.254: JEDP.29 2.7,85 v3(2.8,84.9)
+3VS_TOUCH: length 20
  TOP w0.508: v3(26.98,61.9) CE58.1 27.67,60.27 JTP.8 ; 13.14,66.37 13.29,66.22 v4(17.89,66.22) 20.69,66.22 22.66,64.25 RC78.2 RE329.1 23.68,63.82 v3(23.92,64.06)
  IN2 w0.508: v3(23.92,64.06) 23.92,63.86 25.87,61.9 v3(26.98,61.9)
+3VS_WLAN_NGFF:
  vias: v2(172.47,64.11) v2(172.98,63.73) v2(189.67,66.6) v2(190.3,66.6) v2(191.06,66.6) v4(168.69,61.97)
+5V_HDD: length 1.4
  TOP w0.102: v4(188.44,14.31) 189.06,13.69 v2(189.06,13.21)
  vias: v2(188.6,12.58) v2(189.26,12.58)
+5V_PVDD: length 4.4
  BOTTOM w0.102: v3(200.97,17.05) 200.97,16.87 201.01,16.83 201.01,16.53 v1(201.68,15.85)
  BOTTOM w0.203: v3(200.59,20.15) 200.53,20.09 UA1.41 ; UA1.46 200.08,18.09 200.34,17.84 200.34,17.71 200.97,17.07 v3(200.97,17.05)
+5V_USB_PWR1:
  vias: v2(197.16,51.24) v2(197.16,50.6) v2(197.8,51.24) v2(197.8,50.6) v4(196.14,50.03)
+5V_USB_PWR2:
  vias: v2(196.53,39.68) v2(196.53,39.04) v2(197.16,39.93) v2(197.16,39.3) v4(194.14,39.29)
+5V_USB_PWR3:
  vias: v2(24.42,45.62) v2(24.42,44.99) v2(26.73,47.1) v2(26.73,46.46) v2(26.73,45.8) v4(22.09,44.12)
+5VA: length 1
  BOTTOM w0.203: v3(194.37,23.37) 194.37,23.32 194.73,22.96 UA1.26
  vias: v1(193.25,22.41)
+5VALW: length 224.1
  TOP w0.203: U6.4 73.34,30.6 v3(73.27,30.54) ; U15.4 v3(130.44,2.37) ; U16.4 97.11,64.88 v3(97.31,65.08)
  TOP w0.254: 118.9,20.98 v4(118.08,21.81) 118.08,25.44 116.8,26.73 116.8,29.54 117.28,30.03 120.17,30.03 v4(120.69,30.55) 121.34,31.2 121.34,32.52 120.66,33.2 119.82,33.2 119.31,33.71 117.61,33.71 v3(117.56,33.66)
  TOP w0.508: 64.93,38.97 64.22,38.26 64.22,35.59 64.95,34.85 66.86,34.85 v3(67.24,35.23) ; 64.93,38.97 64.73,39.17 PR1024.2 63.62,39.62 63.3,39.93 PC1021.1 62.22,40.38 v3(61.91,40.7) ; 64.93,38.97 v3(65.28,38.97) ; PR8.1 24.36,100.13 v3(24.36,98.91) ; v3(43.94,10.93) 43.95,10.94 PC715.1 ; PR210.2 79.81,12.82 v3(79.81,13.26) ; RZ10.2 120.58,22.84 120.58,22.28 119.28,20.98 118.9,20.98 118.9,20.93 121.19,18.65 v3(121.47,18.65) 122.38,18.65 123.37,19.64 RZ19.2
  IN1 w0.508: v3(118.17,11.03) 118.17,11.84 118.4,12.07 118.4,14.52 120.73,16.85 120.73,17.76 121.47,18.5 v3(121.47,18.65) ; v3(61.91,40.7) 63.63,38.97 v3(65.28,38.97)
  IN2 w0.508: v3(24.36,98.91) 24.36,98.35 23.4,97.39 22.46,97.39 19.11,94.04 19.11,82.71 17.96,81.57 17.96,64.06 v2(19.36,62.67) 24.06,62.67 25.2,61.52 25.2,51.41 26.4,50.22 26.85,50.22 29.14,47.93 v3(34.5,47.93)
  IN3 w0.508: v3(97.31,65.08) 97.31,65.1 96.07,66.34 94.37,66.34 91.5,63.47 91.5,58.48 83.88,50.86 83.88,41.58 88.18,37.28 v3(89.24,37.28)
  BOTTOM w0.203: v3(61.91,40.7) 61.73,40.51 PU1000.26 ; v3(65.28,38.97) 65.16,38.97 64.62,38.43 PU1000.31
  BOTTOM w0.254: v3(117.56,33.66) 118.07,34.17 RE504.2 ; 35.41,47.24 34.92,47.24 34.58,46.89 PU1100.7 ; PU700.11 v3(43.94,10.93)
  BOTTOM w0.508: PC1105.1 35.41,47.24 34.72,47.93 v3(34.5,47.93) ; v3(128.91,8.67) 128.53,8.28 128.53,4.4 130.44,2.49 v3(130.44,2.37) ; PC307.1 180.46,48.91 181.31,48.06 182.94,48.06 183.7,47.3 183.7,40.19 v3(185.35,38.54) ; v2(78.81,32.6) 79.29,33.08 87.26,33.08 88.83,34.65 88.83,36.87 v3(89.24,37.28) ; v3(82.1,13.01) 81.65,12.56 PR206.1 ; v2(77.37,32.6) 77.37,32.87 75.52,34.73 70.03,34.73 69.78,34.47 67.62,34.47 67.24,34.85 v3(67.24,35.23)
  vias: v2(15.55,17.71) v2(16.19,17.71) v2(16.82,17.71) v2(18.47,41.13) v2(18.47,40.44) v2(19.11,41.71) v2(19.11,41.08) v2(19.11,40.44) v2(19.36,62.03) v2(76.89,11.36) v2(76.89,10.6) v2(77.02,32.06) v2(77.27,31.42) v2(77.72,32.03) v2(77.65,14.91) v2(77.65,14.28) v2(77.65,13.64) v2(77.65,13.01) v2(77.65,12.37) v2(77.65,11.74) v2(77.65,11.1) v2(77.65,10.47) v2(77.65,9.83) v2(77.73,8.81) v2(77.73,7.79) v2(77.91,31.42) v2(78.03,32.59) v2(78.42,32.06) v2(78.54,31.42) v2(78.54,14.91) v2(78.54,14.28) v2(78.54,13.64) v2(78.54,13.01) v2(78.54,12.37) v2(78.54,11.74) v2(78.54,11.1) v2(78.54,10.47) v2(78.54,9.83) v2(78.54,8.82) v2(78.54,7.8) v2(79.1,32.03) v2(79.18,31.4) v2(189.03,40.44) v2(189.41,56.19) v2(189.41,55.55) v2(189.41,54.92) v2(189.41,54.28) v2(189.67,41.71) v2(189.67,41.08) v2(189.67,40.44) v4(189.16,50.86)
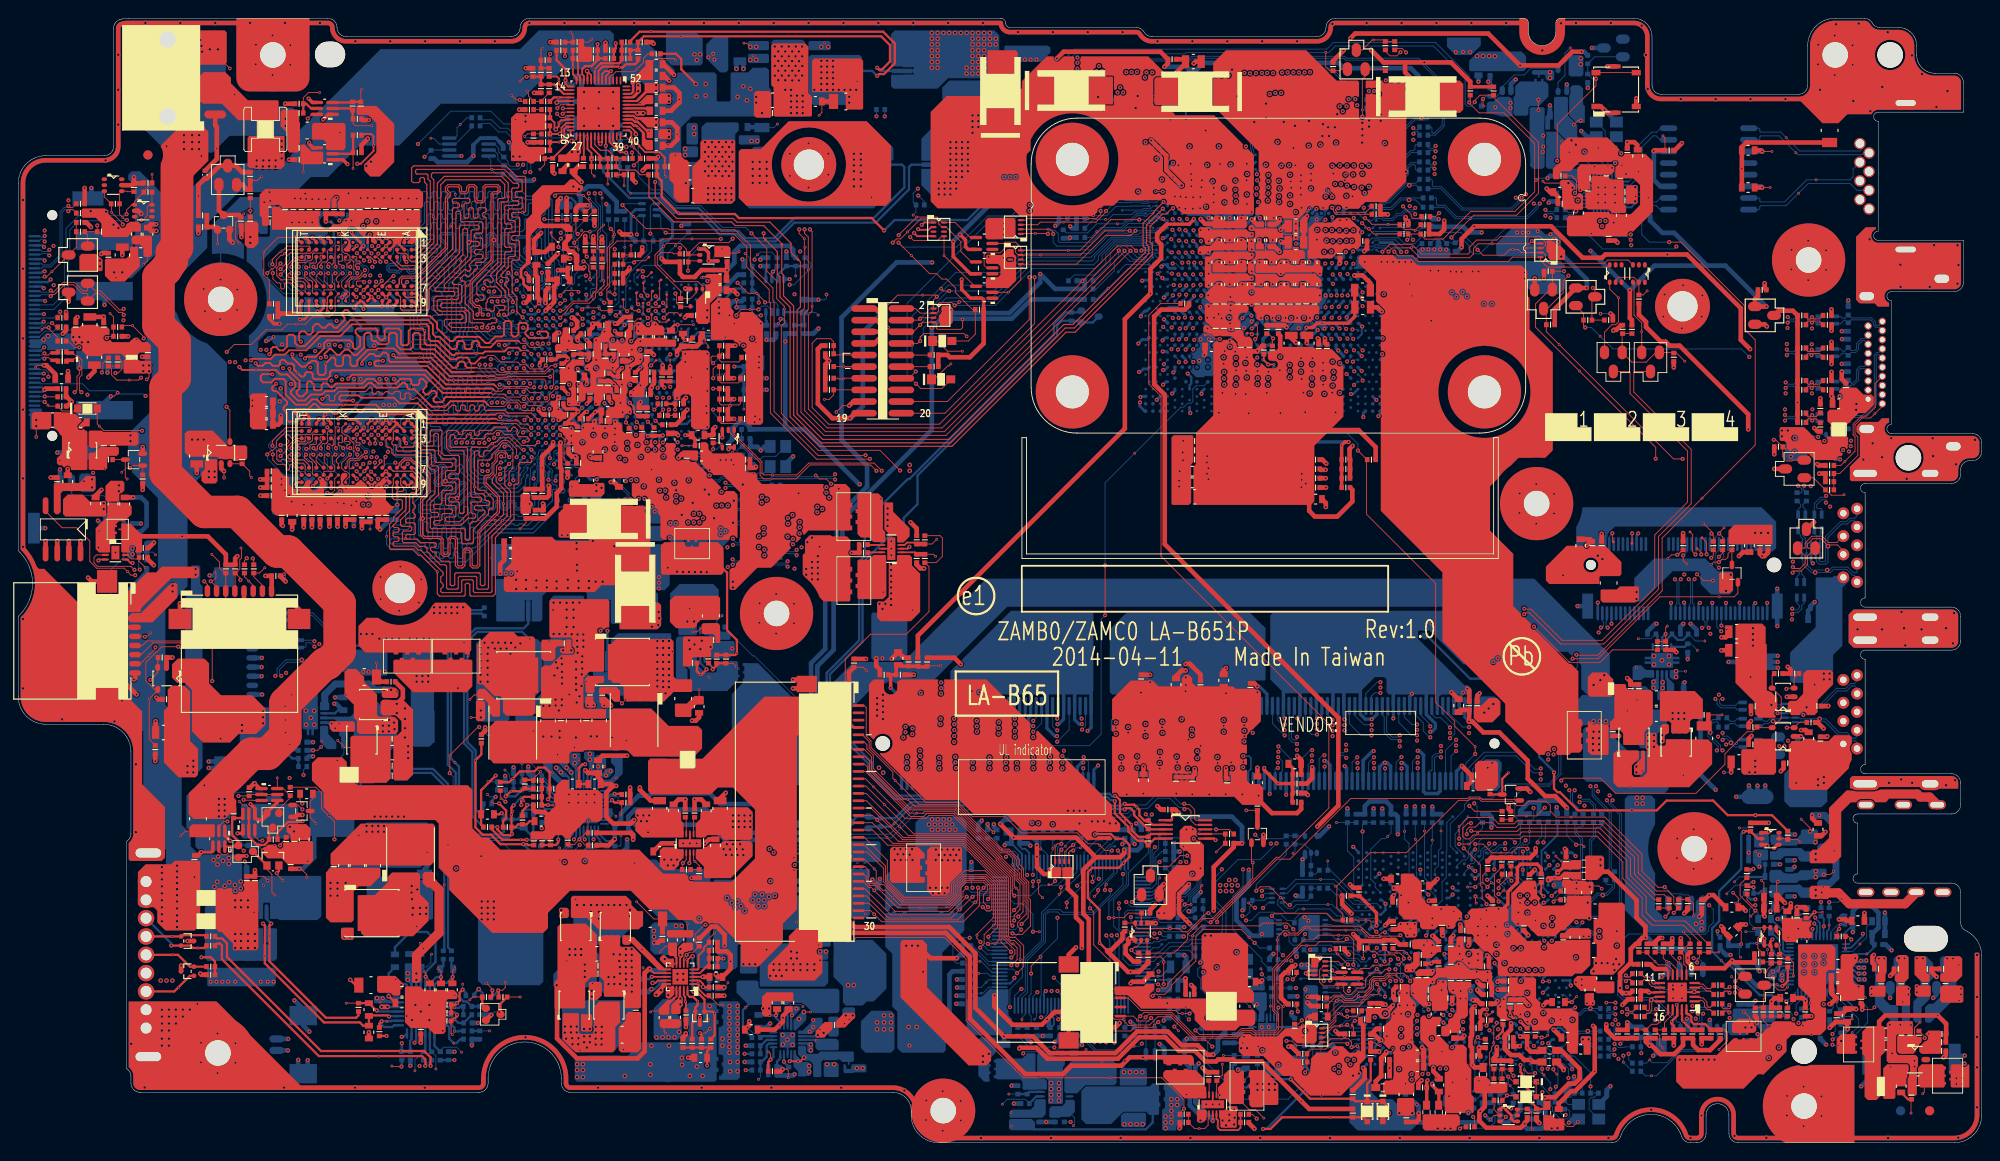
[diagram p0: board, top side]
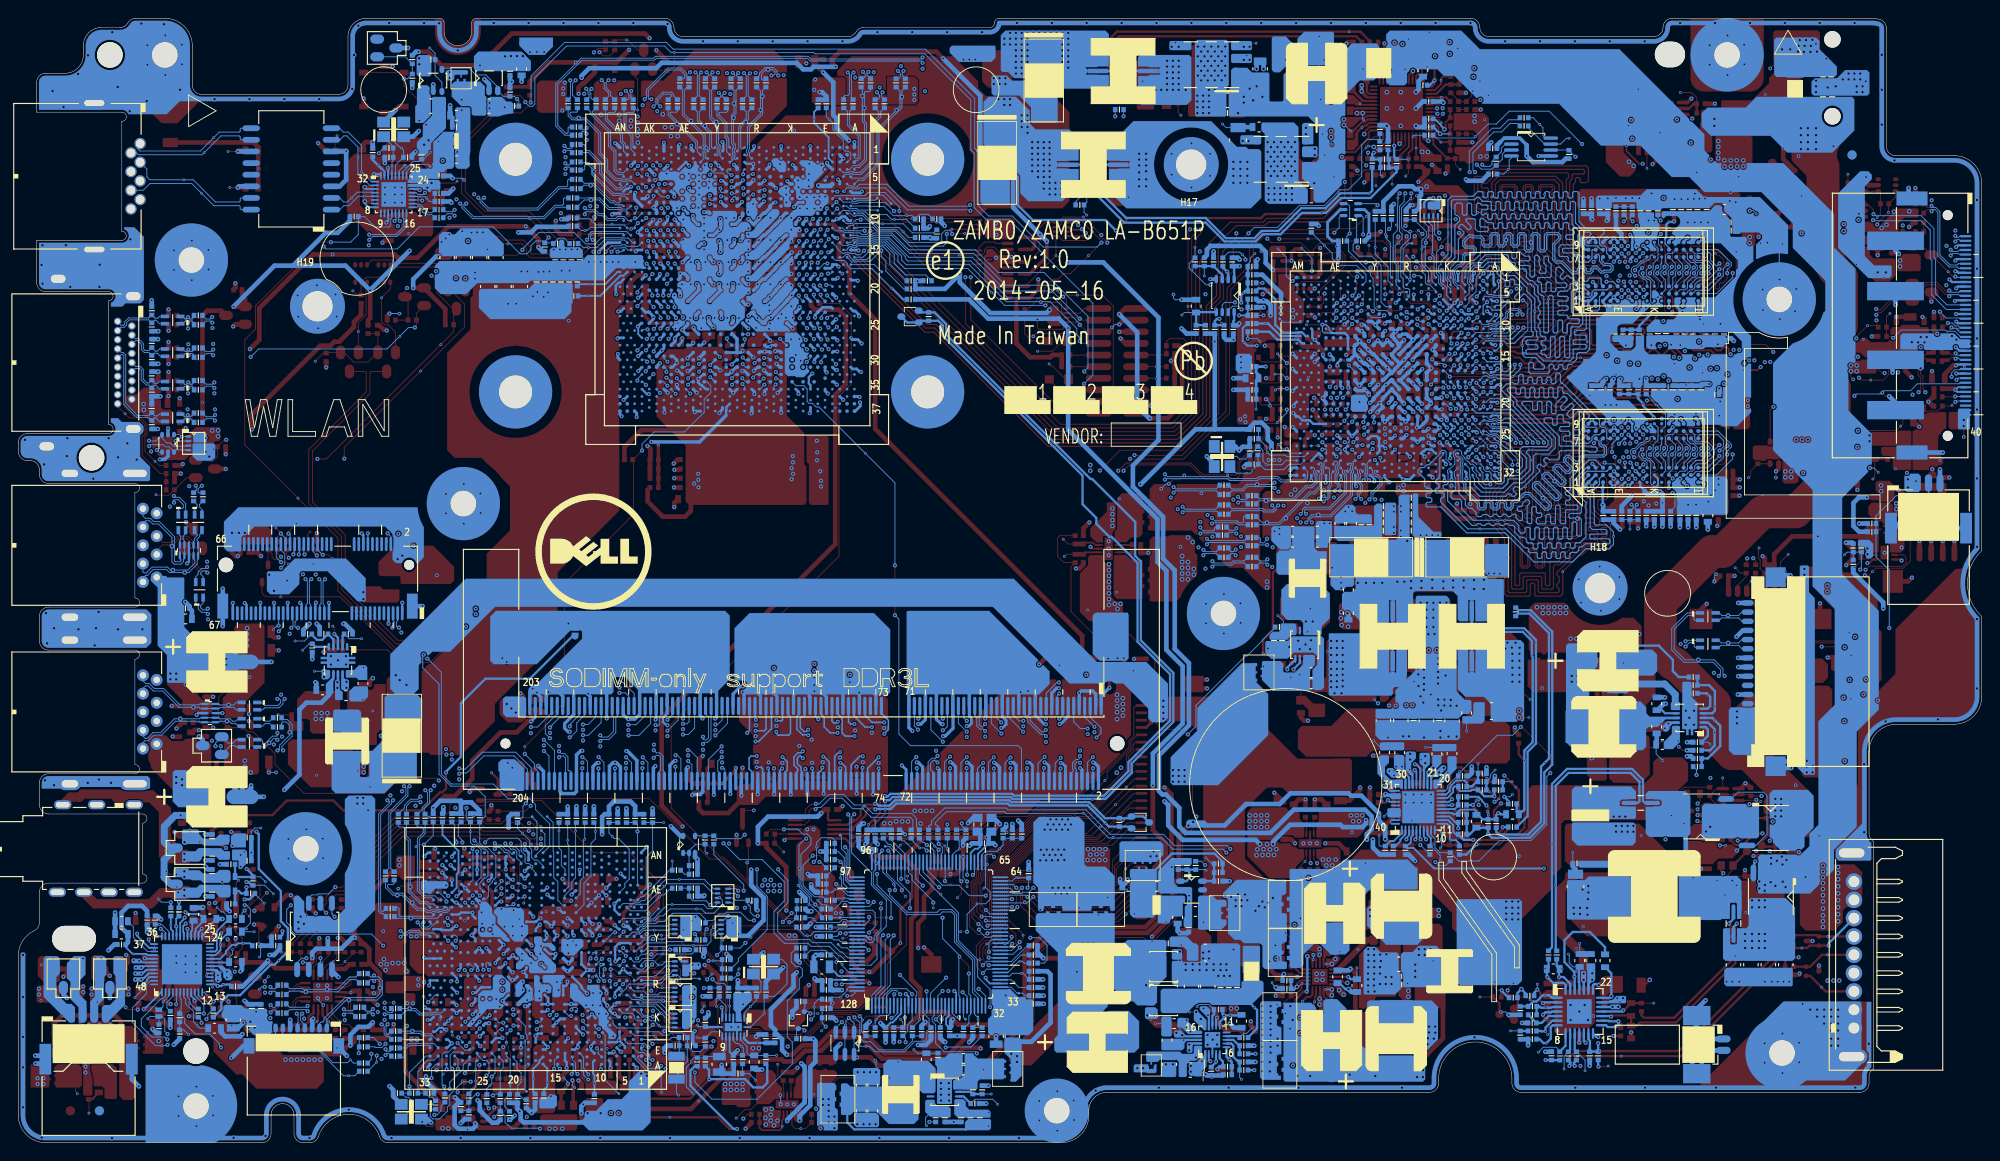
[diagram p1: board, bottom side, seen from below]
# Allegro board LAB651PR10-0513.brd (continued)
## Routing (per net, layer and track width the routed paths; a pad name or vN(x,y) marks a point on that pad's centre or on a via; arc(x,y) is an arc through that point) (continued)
+5VALWP: length 27.5
  TOP w0.203: PU100.14 69.85,17.71 69.59,17.45 v2(69.27,17.45)
  TOP w0.508: PR104.2 77.04,17 v2(77.08,16.96)
  IN1 w0.254: v2(77.08,16.96) 76.43,16.31 74.48,16.31 73.62,15.45 73.62,9.09 73.04,8.51 v2(72.47,8.51)
  IN3 w0.508: v2(72.45,9.28) 72.45,10.22 73.62,11.39 73.62,15.41 72.56,16.46 72.15,16.46 71.23,17.38 69.35,17.38 v2(69.27,17.45)
  BOTTOM w0.102: v2(77.08,16.96) 77.49,17.37 v1(77.49,17.48)
  BOTTOM w0.508: PC108.2 76.94,16.82 v2(77.08,16.96)
  vias: v2(61.02,8.56) v2(61.02,7.93) v2(61.02,7.17) v2(61.65,8.56) v2(61.65,7.93) v2(61.65,7.17) v2(66.22,7.29) v2(69.02,8.56) v2(69.02,7.42) v2(69.14,10.6) v2(71.05,10.6) v2(73.34,7.29) v2(74.1,8.31) v2(74.73,7.29) v2(75.24,13.39) v2(75.49,14.91)
+5VS: length 28.2
  TOP w0.203: PU500.41 66.83,110.96 67.43,110.35 v2(67.43,110.14)
  TOP w0.508: v3(15.07,100.31) 14.48,100.31 14.15,99.98 RX29.1 14.52,99.57 v2(15.07,99.57) ; v3(188.91,77.91) 188.91,79.56 181.41,87.05 180.32,87.05 179.89,87.48 179.36,87.48 177.74,89.09 177.74,89.65 176.97,90.43 R18.1 ; PR521.2 59.4,106.07 59.4,106.21 59.98,106.79 v3(60.03,106.79) ; v3(71.61,116.62) 70.44,117.78 PR520.2 ; RE60.1 v3(92.56,52.84)
  BOTTOM w0.508: v3(120.55,32.61) 120.83,32.88 RE13.1
  vias: v2(8.92,96.35) v2(8.92,95.71) v2(9.33,69.83) v2(9.33,69.19) v2(16.85,60.84) v2(16.85,60.2) v2(78.03,35.74) v2(78.03,35.11) v2(78.03,34.47) v2(78.67,35.74) v2(78.67,35.11) v2(78.67,34.47) v2(79.3,35.74) v2(79.3,35.11) v2(79.3,34.47) v2(79.94,35.74) v2(79.94,35.11) v2(79.94,34.47) v2(93.78,48.54) v2(93.78,47.91) v2(93.78,47.27) v2(93.78,46.64) v2(94.42,48.92) v2(94.42,48.29) v2(94.42,47.65) v2(94.42,47.02) v2(94.42,46.26) v2(114.61,36.25) v2(115.25,36.25) v2(115.88,36.25) v2(115.88,34.85) v2(116.52,36.25) v2(117.25,35.08) v2(117.89,35.08) v2(118.55,35.11) v2(119.18,34.88) v2(119.84,34.88) v2(129.6,22.61) v2(130.23,22.61) v2(131.25,28.12) v2(131.25,27.49) v2(131.88,28.12) v2(131.88,27.49) v2(132.23,28.69) v2(132.52,28.12) v2(132.52,27.49) v2(132.9,28.69) v2(133.15,28.1) v2(181.41,9.07) v2(182.05,9.07) v2(182.68,9.07) v2(183.32,9.07) v2(183.95,9.07) v2(184.59,9.07) v2(185.22,9.07) v2(192.59,77.78) v2(192.59,77.14) v2(193.22,77.78) v4(104.13,49.33)
+5VS_KBL:
  vias: v4(125.47,15.23)
+AVDD_SATA: length 9.2
  TOP w0.381: v3(161.65,25.53) 162.13,25.53 162.66,26.07 162.66,27.41 163.69,28.43 163.69,30.05 164.06,30.42 165.85,30.42 166.3,29.97 RH38.2
  vias: v1(159.7,24.41) v3(159.4,23.62) v3(159.4,22.62) v3(160.31,25.39) v3(160.4,23.62) v3(160.4,22.62) v3(161.31,23.58)
+V18R: length 3.4
  BOTTOM w0.203: CE16.1 124.81,18.19 v1(124.47,18.19) UE1.124
+VCC_VDDCR_11:
  vias: v1(157.71,20.03) v3(157.32,21.48) v3(157.4,20.62) v3(158.4,19.62) v3(159.4,20.62) v3(159.39,19.93) v3(170.09,17.52) v3(170.73,17.83) v3(170.73,17.2)
+VCCP_D: length 4
  TOP w0.254: RZ24.2 160.76,38.03 QZ13.1 162.05,39.73 v1(162.72,40.4)
+VDD_CT: length 11.4
  TOP w0.102: v1(72.5,76.13) LV3.2
  TOP w0.381: v3(72.83,77.27) CV61.1 73.53,77.25 73.89,76.88 LV3.2
  TOP w0.508: v3(67.94,80.9) 67.79,80.74 CV62.1 CV63.1
  IN2 w0.381: v3(72.83,77.27) 72.83,77.3 71.3,78.82 70.49,78.82 69.81,79.51 69.2,79.51 68.6,80.1 68.6,80.24 v3(67.94,80.9)
+VDD_TOUCH: length 8
  TOP w0.508: QX7.2 13.09,101.78 v3(13.42,101.45) ; QX6.5 12.43,104.58 RX39.1 ; RX35.1 5.21,88.7 v3(4.86,88.35) ; RX39.1 13.65,104.78 RX40.1 ; RX39.1 v3(12.63,105.47)
  BOTTOM w0.254: JEDP.11 3.25,94 v3(3.52,94.28) ; v3(2.83,86.87) 2.45,86.5 JEDP.26
  vias: v1(10.67,94.48) v2(10.47,95.05) v2(11.36,95.05)
+VDDAN_11_PCIE: length 1.1
  BOTTOM w0.254: U2.AG27 v3(165.6,27.82)
  BOTTOM w0.305: U2.AF26 v3(165.6,27.82)
  vias: v1(165.68,24.27) v3(162.57,23.8) v3(162.62,22.79) v3(163.81,25.15) v3(163.76,23.91) v3(163.99,26.19)
+VDDAN_11_SSUSB: length 3.1
  TOP w0.508: CH82.1 CH80.1 CH81.1 155.66,16.37 155.41,16.62 v3(155.41,16.66)
  vias: v1(155.07,17.59) v3(155.58,17.56)
+VDDAN_11_USB_S: length 23.6
  TOP w0.381: LH9.2 153.8,4.12 CH67.1 153.8,6.72 v3(153.89,6.81) ; CH68.1 154.49,19.75 v3(154.32,19.58) 154.29,19.55 CH69.1
  IN1 w0.254: v3(154.32,19.58) 153.57,18.84 153.57,16.93 154.61,15.89 154.61,12.54 155.53,11.62 155.53,10.22 156.83,8.92 156.83,7.64 156.37,7.19 154.4,7.19 154.02,6.81 v3(153.89,6.81)
  BOTTOM w0.102: v1(153.64,5.99) 153.89,6.24 v3(153.89,6.81)
  BOTTOM w0.381: U2.U12 153.9,20.01 v3(154.32,19.58) 154.86,20.12 U2.U13
+VDDAN_33_HWM: length 0.9
  BOTTOM w0.254: U2.M8 150.5,15.46 150.1,15.07 v3(150.1,14.99)
  vias: v1(149.62,14.61)
+VDDAN_33_USB:
  vias: v1(152.1,11.23) v3(149.44,11.63) v3(150.2,14.07) v3(150.85,16.34) v3(150.85,14.98) v3(151,14.08) v3(151.64,16.34) v3(151.68,15.02) v3(152.39,15.01)
+VDDBT_RTC: length 3.7
  TOP w0.102: v1(148.72,10.61) 148.46,10.61 148.17,10.9 CH13.1
  TOP w0.508: CH13.1 RH22.1 148.55,9.97 v3(148.6,9.92)
  BOTTOM w0.254: U2.E6 v3(148.6,9.92)
+VDDCI: length 7.1
  TOP w0.102: v3(61.12,80.69) 61.55,80.26 v4(61.55,80.23)
  BOTTOM w0.381: UV1.M21 60.56,80.3 v3(60.14,80.72) 60.14,80.9 60.54,81.3 UV1.M20 UV1.M18 ; UV1.M13 UV1.M15 60.6,85.09 v3(60.1,84.59) 60.59,84.1 UV1.M16 UV1.M17 ; UV1.N20 61.6,81.16 v3(61.12,80.69)
+VDDCR_1.1V: length 28.6
  TOP w0.508: CH71.1 159.82,16.18 159.44,16.57 159.43,16.57 v3(159.31,16.68) ; RH109.1 168.2,4.26 169.59,5.64 170.01,5.64 v1(172.14,7.78) 172.14,12.58 v3(171.96,12.76) ; CH70.1 159.76,17.13 v3(159.31,17.58)
  IN3 w0.508: v3(159.31,16.68) 160.79,15.21 160.79,15.04 161.57,14.25 162.08,14.25 162.44,14.61 163.51,15.68 166.83,15.68 168.46,14.05 170.01,14.05 170.57,13.49 171.68,13.49 171.96,13.21 v3(171.96,12.76)
+VDDCR_11_SSUSB: length 2.4
  TOP w0.508: CH88.1 156.44,16.88 v3(156.68,16.64) ; v3(157.5,16.56) 157.39,16.67 CH90.1 CH89.1
  vias: v1(158.07,15.74) v3(157.48,15.74)
+VDDCR_11_USB: length 20.9
  TOP w0.381: v3(154.39,6.44) 154.39,6.27 155.07,5.58 CH74.1 155.12,4.11 LH11.2
  IN1 w0.254: v3(154.44,18.76) 153.94,18.26 153.94,17.08 154.98,16.04 154.98,12.69 155.9,11.78 155.9,10.37 157.19,9.07 157.19,7.8 157.19,7.49 156.53,6.82 154.77,6.82 v3(154.39,6.44)
  BOTTOM w0.102: v1(154.83,7.08) 154.45,6.7 154.45,6.51 v3(154.39,6.44)
  BOTTOM w0.381: U2.T12 154.26,18.76 v3(154.44,18.76) 154.54,18.76 U2.T13
+VDDIO_33_PCIGP: length 7
  BOTTOM w0.254: v3(154.41,24.5) 154.28,24.5 U2.AB12 ; U2.AB13 154.52,23.74 v3(154.41,23.74) ; U2.AB14 155.9,23.92 v3(156.18,23.63) 156.67,24.12 U2.AB16 ; v3(155.37,25.52) 154.97,25.12 U2.AC13 ; v3(157.39,24.5) 157.48,24.5 157.86,24.12 U2.AB17 U2.AB18 ; U2.AD10 v3(151.8,26.22) ; U2.AG7 v3(150.2,27.82) ; U2.AE9 v3(151,27.02)
  vias: v1(156.76,25.24)
+VDDIO_33_S: length 1.2
  TOP w0.508: v3(158.83,15.57) 159.26,15.57 159.67,15.17 CH56.1
  vias: v1(153.84,22.02) v3(153.49,21.58) v3(154.32,20.7) v3(154.42,21.58) v3(158.61,16.59)
+VDDIO_AZ: length 5.9
  TOP w0.381: CH85.1 146.38,26.96 RH112.1 146.48,26.93 v1(147.53,25.87) 148.32,25.09 v3(148.32,23.73)
  BOTTOM w0.381: v3(148.32,23.73) 148.22,23.63 147.86,23.63 U2.AA4
+VDDPL_11_SYS_S: length 15.4
  TOP w0.254: v1(163.51,13.63) 163.21,13.63 v3(162.92,13.92) 162.92,13.93 CH78.1 ; v3(164.04,8.49) 164.04,7.7 164.19,7.55 164.19,6.51 165.06,5.64 165.06,4.58 165.79,3.84 CH77.1 166.54,3.69 LH12.1
  IN1 w0.254: v3(162.92,13.92) 162.92,13.82 162.52,13.42 162.52,10.73 164.04,9.21 v3(164.04,8.49)
  BOTTOM w0.254: U2.J24 163.22,13.62 v3(162.92,13.92)
+VDDPL_33_PCIE: length 2.3
  TOP w0.102: v1(167.9,31.3) 168.93,30.27 CH79.1
  BOTTOM w0.254: v3(168.12,29.49) 167.65,29.02 U2.AH29
+VDDPL_33_SATA: length 0.6
  BOTTOM w0.254: v3(167.05,28.69) U2.AG28
  vias: v1(167.79,28.88)
+VDDPL_33_SSUSB_S: length 8.6
  TOP w0.508: LH6.2 159.02,8.22 v1(158.78,8.46) 158.73,8.51 RH97.1 158.73,10.39 158.58,10.55 158.58,11.51 158.73,11.66 CH64.1 CH65.1 158.73,14.58 v3(159.06,14.91)
  BOTTOM w0.305: v3(159.06,14.91) 158.75,14.91 U2.L18
+VDDPL_33_SYS: length 8.5
  TOP w0.508: LH1.2 165.37,8.82 v1(165.16,9.03) 164.46,9.03 163.91,9.58 162.98,9.58 162.33,10.23 CH25.1 CH31.1 162.33,11.71 163,12.38 v3(163,13.06)
  BOTTOM w0.33: v3(163,13.06) 163,13.05 163.39,13.05 163.6,12.83 U2.H24
+VDDPL_33_USB_S: length 6
  TOP w0.102: v3(149.38,9.93) 149.93,9.93 150.09,10.1 v1(150.09,10.3)
  TOP w0.508: LH10.2 148.23,6.7 CH72.1 CH73.1 148.82,9.25 149.38,9.8 v3(149.38,9.93)
  BOTTOM w0.254: v3(149.38,9.93) 149.54,9.77 U2.D7
+VDDR3: length 3.6
  BOTTOM w0.381: v3(66.9,81.67) 66.9,81.8 UV1.AA18 67.56,82.14 68.24,82.14 UV1.AB18 ; UV1.AB17 68.4,83.17 v3(67.94,82.71) 67.41,83.24 67.41,83.29 UV1.AA17
  vias: v1(67.16,82.16)
+VDDXL_3.3V: length 4.5
  TOP w0.508: LH7.1 166.24,9.94 165.16,9.94 v1(164.76,10.34) CH66.1 164.02,11.6 v3(164,11.62)
  BOTTOM w0.254: v3(164,11.62) 163.6,12.01 U2.G24
GND: length 2673.3
  TOP w0.102: v3(78.42,91.24) v4(78.42,92.07) ; v3(159.09,29.67) 158.85,29.67 v4(158.36,30.15) ; v4(27.23,28.63) 26.78,29.09 PC9.2 ; v3(32.19,42.85) 32.7,42.85 v4(33.08,43.24) ; v4(173.41,15.3) v3(174.4,15.3) ; v3(166.49,17.61) v4(167.18,17.61) ; v3(10.1,81.53) 10.47,81.53 v4(10.85,81.91) ; v4(27.87,88) 27.43,87.56 v3(27.06,87.56) ; v3(201.35,14.53) 202.43,14.53 v4(202.69,14.79) ; v3(183.32,62.08) 184.02,61.38 v4(185.05,61.38) ; v4(22.47,72.64) 22.46,72.65 v3(22.46,73.33) ; v4(172.9,27.74) 172.6,28.04 CH46.2 ; v3(88.75,71.96) 88.23,72.48 87.47,72.48 v4(87.08,72.88) ; v3(124.93,94.44) 124.89,94.44 v4(124.4,94.92) ; v4(89.33,79.8) 90.02,80.5 v3(90.73,80.5)
  TOP w0.203: UE4.5 11.88,63.69 12.26,63.31 v3(12.48,63.31) ; U16.11 v3(95.33,64.88) ; v3(66.78,80.8) 67.23,80.35 67.23,79.75 67.62,79.37 CV62.2 ; 181.16,16.44 US2.3 ; U15.11 v3(130.44,4.2) ; U6.11 v3(73.34,32.69)
  TOP w0.254: v3(36.91,92.36) 36.86,92.36 36.55,92.67 UV7.J8 ; UV7.E8 39.76,92.73 v3(40.16,92.33) 40.55,92.72 UV7.D8 ; v3(42.37,96.19) 42.15,96.42 UV7.B3 ; v3(36.96,97.95) 36.55,97.53 UV7.J2 ; UV6.G9 38.2,72.12 v3(38.57,71.75) UV6.F9 ; v3(42.15,91.37) 42.22,91.44 42.22,91.86 UV7.B9 ; UV7.P1 32.55,98.4 v3(32.11,98.84) ; UV7.F9 38.95,91.97 v3(38.56,92.36) ; v3(38.56,92.36) 38.15,91.94 UV7.G9 ; v3(38.56,92.36) 38.19,92.73 UV7.G8 ; UV7.T9 30.79,91.78 v3(30.79,90.56) ; UV6.M9 34.17,72.1 v3(34.17,71.52) ; v3(42.35,76.4) 42.15,76.6 UV6.B3 ; U2407.6 130.57,33.22 v3(130.74,33.05) ; UV7.B1 42.15,98.56 v3(42.42,98.84) ; v3(39.35,98.81) 39.75,98.41 UV7.E1 ; v3(32.67,91.39) 32.55,91.51 UV7.P9 ; v3(36.96,78.11) 36.92,78.07 36.92,78.06 36.59,77.72 UV6.J2 ; UV7.M9 v3(34.15,91.24) ; UV6.G8 38.16,72.92 38.51,72.57 38.51,72.52 v3(38.56,72.47) ; UV6.P9 32.55,72.09 v3(32.17,71.72) ; UV6.A9 42.95,72.11 42.54,71.7 ; UV6.B1 42.15,78.53 v3(42.56,78.94) ; UV7.E2 v3(40.14,97.93) UV7.D1 ; UV6.J8 36.55,72.92 v3(36.96,72.52) ; UV6.B9 42.54,71.73 42.54,71.7 ; v3(38.39,99.17) 38.15,98.93 UV7.G1 ; UV6.P1 32.55,78.62 32.85,78.92 v3(32.85,79.02) ; v3(40.15,78.12) 39.75,77.72 UV6.E2 ; UV6.D8 40.55,72.93 v3(40.15,73.33) 39.75,72.93 UV6.E8 ; v3(161.53,11.43) 161.53,11.59 162.11,12.17 CH29.2 ; 42.54,71.7 v3(42.54,71.7) ; v3(43.57,91.37) 43.57,91.41 43.05,91.93 UV7.A9 ; UV7.T1 30.86,98.33 v3(30.51,98.68) ; UV6.T9 30.53,72.12 v3(30.32,71.91) ; UV6.D1 40.55,78.57 v3(40.17,78.94) 39.75,78.52 UV6.E1 ; v3(31.21,79.08) 30.95,78.82 UV6.T1 ; v3(33.81,98.84) 34.15,98.5 UV7.M1 ; UV6.G1 v3(38.57,78.94)
  TOP w0.305: QH2.1 162.02,3.85 v3(162.42,3.85) 162.42,3.6 163.02,3 163.02,2.62 163.32,2.33 QH2.4 ; CH66.2 164.74,12.51 v3(164.03,13.23) ; v3(33.82,78.99) 33.83,78.99 33.83,78.97 33.8,78.97 34.15,78.63 UV6.M1 ; v3(19.97,31.73) 21.09,31.73 21.25,31.89 PQ713.4
  TOP w0.381: CV74.2 CV87.2 60.69,86.14 CV51.2 ; PC851.2 67.39,84.13 v3(67.91,84.65) ; v3(60.04,81.77) 59.44,82.36 CV89.2 ; v3(33.28,111.74) 33.85,112.31 PQ2.1 ; v3(65.14,88.65) 65.5,88.29 PC871.2 ; CV27.2 72.57,87.91 v3(72.82,87.66) 73.39,87.66 CV26.2 ; v3(23.93,33.79) 24.38,33.79 24.53,33.94 PQ709.1 ; v3(70.38,77.25) 70.35,77.22 69.45,77.22 RV59.1 68.79,77.19 v3(68.75,77.16) ; PQ2.4 32.12,113.61 v3(31.69,114.04) ; CV67.2 66.77,85.39 v3(66.96,85.58) ; CV72.2 64.67,84.03 65,83.7 CV78.2 65.51,84.21 v3(65.93,84.63) ; 26.55,35.23 26.14,35.23 25.83,35.55 PQ709.4 25.83,36.5 v3(25.36,36.97) ; v3(160.38,14.56) 159.92,14.56 CH65.2 159.65,13.62 RH72.2 ; CV76.2 65.33,82.51 v3(65.05,82.8) 64.67,83.18 CV75.2 ; CV79.2 64.56,81.31 64.56,80.99 v3(64.76,80.79) ; v3(25.81,39.25) 26.38,38.68 PQ710.1 ; QV8.1 74.97,97.61 75.37,97.21 v3(75.37,96.32) 75.38,96.31 QV8.4 ; PQ712.3 27.15,36.04 28.28,37.17 PQ710.4 ; v3(62.08,82.87) 62.08,83.41 CV88.2 ; CV33.2 CV34.2 70.29,82.73 v3(70.54,82.48) ; CV90.2 59.57,85.09 v3(60.02,85.54) 60.02,85.69 59.8,85.91 CV40.2 58.63,85.53 CV42.2 ; CV41.2 59.52,80.45 59.82,80.14 60.88,80.14 61.11,79.92 v3(61.11,79.81) 61.07,79.81 60.77,79.51 CV47.2 60.46,79.23 CV60.2 60.69,78.54 CV57.2 ; v3(31.77,109.22) 31.77,109.08 32.2,108.66 PQ1.4 ; PQ708.3 24.02,31.16 24.19,31.32 v3(24.92,31.32) ; UV2.3 v3(76.88,77.03) ; v3(35.95,106.86) 35.45,107.36 PQ1.1 ; PQ713.1 22.55,33.57 v3(23.15,32.97) ; v3(55.43,94.96) 55.43,94.92 55.78,94.57 CV85.2 ; CV53.2 57.23,79.53 56.8,79.96 v3(56.8,80.1) ; CV80.2 63.63,79.82 CV70.2 63.65,79.88 63.08,79.88 v3(62.98,79.78) 62.58,79.38 62.56,79.38 CV168.2 ; CV71.2 64.09,86.97 CV77.2 PC840.2 65.03,86.09 65.03,85.66 v3(64.87,85.5) ; v3(62.07,80.7) 62.41,81.05 CV73.2
  TOP w0.406: PD101.1 v3(74.43,13.67)
  TOP w0.457: CV66.2 CV64.2 69.42,82.88 69.17,82.63 v3(69.17,82.46) ; v3(62.08,87.65) 62.39,87.34 CV52.2 ; CV74.2 62.3,86.13 62.3,85.66 v3(62.12,85.48)
  TOP w0.508: v3(98.91,62.72) 98.53,62.72 98.48,62.77 98.46,62.77 98.1,63.12 C1014.1 ; v3(137.86,99.72) 138.24,100.1 C80.2 ; CV62.2 CV63.2 ; C82.2 142.78,69.87 v3(142.78,69.42) ; PC872.2 66.15,90.17 65.44,89.46 v3(65.16,89.46) ; PC1044.2 74.34,46.45 73.98,46.09 v3(73.56,46.09) ; v3(73.51,28.91) 73.54,28.93 CZ5.2 ; v3(166.1,2.14) 165.79,2.44 CH77.2 ; UE3.8 v3(6.79,65.71) ; CH40.2 162.24,16.72 v3(161.55,16.72) ; PC526.2 v3(55.4,117.35) ; RV9.2 CV29.2 v3(78.16,83.49) ; CV120.2 v3(31.17,67.21) ; CH52.2 157.51,23.76 v3(157.44,23.83) ; v3(193.22,51.97) 193.53,51.67 CI15.2 CI13.2 ; PC841.2 62.36,88.7 62.71,89.05 v3(62.71,89.43) 63.31,89.43 PC842.2 ; RC9.1 RC8.1 149.52,101.4 v3(149.55,101.37) ; JHDT1.17 91.18,80.94 v3(90.73,80.5) ; v3(26.41,72.45) CV123.2 ; CV123.2 CV119.2 v3(26.42,71.56) ; CV123.2 CV179.2 ; v2(175.7,50.73) 176.08,50.35 PC302.2 PC301.2 ; CH45.2 165.07,29.28 v3(165.6,29.81) ; CH60.2 CH59.2 153.45,10.21 153.3,10.37 v3(153.3,10.42) ; RA81.1 CA69.2 v3(191.45,15.42) 191.83,15.8 CA59.2 ; v3(115.5,21.33) 114.7,20.53 JKBBL.5 ; v3(209.48,18.11) 209.45,18.11 208.92,18.65 CA31.2 CA32.2 ; v3(197.14,45.24) 196.48,45.9 CI17.2 ; JHDT1.5 v3(94.18,88.56) ; v3(157.64,41.15) C120.2 158.68,39.47 C121.2 ; PR10.1 v3(29.57,107.37) ; v3(160.44,17.76) 160.9,17.3 CH70.2 CH71.2 ; v3(171.25,65.21) 171.71,65.66 CM9.2 171.65,65.9 CM4.2 ; RZ21.2 123.58,25.4 v3(124.14,25.96) ; C118.2 126.42,50.96 127.03,51.57 v3(127.49,51.57) ; CV59.2 60.94,74.83 v3(60.84,74.94) 60.43,74.94 60.1,75.26 CV58.2 ; v3(16.82,52.99) CI47.2 16.17,52.42 16.2,52.39 UI7.2 ; 26.55,35.23 27.15,35.83 PQ712.3 ; v3(55.62,109.26) PR559.1 57.12,109.26 PR567.1 ; v3(31.02,35.79) 30.49,35.79 30.27,35.58 PQ714.3 ; Q52.1 121.72,22.33 v3(121.37,22.33) 121.21,22.18 121.21,21.77 120.91,21.47 120.91,20.65 121.77,19.79 RZ591.2 ; v2(41.33,47.93) 41.99,48.59 41.99,49.51 PC1106.2 ; JHDT1.3 93.72,89.83 v3(94.17,89.38) ; PC501.1 v3(58.1,120.2) ; RV57.2 CV160.2 28.66,90.56 v3(30.79,90.56) ; v3(156.7,22.61) 156.44,22.35 CH26.2 ; RS18.2 RS22.1 v3(180.78,10.62) ; CH31.2 CH25.2 163.32,10.54 v3(163.97,10.54) ; CH42.2 168.5,11.5 v3(167.65,12.35) ; C127.2 94.09,51.67 93.68,52.07 v3(93.68,52.91) ; PR553.1 v3(54.69,112.83) ; v3(196.09,67.77) 195.33,67.01 DI2.1 ; v3(131.88,40.9) 131.88,39.89 C111.1 ; CV157.2 v3(39.93,103.18) ; CZ15.2 v3(73.84,37.48) 73.84,37.49 74.57,37.49 CZ14.2 ; CZ1.2 70.22,32.69 v3(71.68,32.69) ; CVT90.1 60.89,102.04 61.25,102.39 v3(62.16,102.39) ; CX5.2 7.3,78.67 v3(6.81,78.19) ; RA30.2 185.1,27.04 v3(184.65,27.04) 184.16,26.55 CH466.2 ; v3(18.47,22.03) PD2.1 ; v3(199.75,12.4) 199.7,12.45 CA57.2 199.69,13.19 CA58.2 198.43,13.19 v3(197.8,12.55) ; CV131.2 v3(34.85,67.29) ; JTP.9 30.65,58.24 v3(30.03,58.86) ; v3(196.65,73.08) CX20.2 RX34.2 ; v2(76.19,18.42) 76.19,18.33 76.42,18.1 PC109.2 77.78,19 v4(77.78,19.8) 77.78,20.5 77.39,20.9 76.45,20.9 PR107.1 PR108.2 ; v3(157.9,11.67) 157.65,11.42 CH87.2 ; v3(68.18,106.18) 68.61,106.61 PC534.1 ; v3(77.1,16.06) PR105.2 ; v3(196.12,78.06) 196.48,77.7 CV362.2 ; v3(66.73,95.56) 66.73,95.41 66.25,94.92 RV38.2 CV97.2 ; v3(131.88,51.85) 131.63,51.59 C116.2 ; v3(148.89,90.78) 148.43,91.24 C77.2 ; v3(195.89,35.74) 195.89,35.41 196.39,34.92 RA29.2 ; CZ9.2 v3(72.83,37.48) 72.83,37.49 72.1,37.49 CZ4.2 ; CL15.2 174.4,98.53 v3(174.63,98.3) ; CV46.2 CV39.2 80.45,73.72 v3(80.55,73.82) ; CI12.2 186.78,55.54 186.44,55.2 v3(185.98,55.2) ; CE59.2 14.23,64.95 v3(14.81,65.54) ; CH44.2 164.39,23.15 v3(164.88,22.66) ; CV180.2 v3(43.49,103.1) ; v3(198.81,24.39) 199.52,24.39 199.68,24.24 RA31.2 ; v3(129.5,86.03) 129.59,86.13 C83.2 ; CH27.2 v3(154.03,26.42) ; PC726.2 v3(38.28,12.07) ; v3(115.35,13.19) 114.7,12.54 JKBBL.6 ; CV93.2 57.59,93.07 CV92.2 57.59,91.75 v3(57.55,91.71) ; CA60.2 v3(195.79,13.82) ; CH41.2 161.6,17.66 v3(161.52,17.58) ; CA29.2 202.67,19.44 202.47,19.64 202.47,20.35 v3(202.62,20.5) ; CV82.2 59.98,95.43 ; 59.98,95.43 59.98,94.49 60.22,94.25 CV91.2 ; 59.98,95.43 59.84,95.3 v3(58.93,95.3) ; v3(185.96,23.63) 186.2,23.39 186.2,23.11 RA32.2 ; C123.2 140.08,40.25 C122.2 140.08,41.82 v3(139.66,42.24) ; SW1.1 172.82,113.17 v3(173.21,112.78) 173.52,112.47 174.45,112.47 SW1.5 ; v3(189.21,46.05) 188.96,45.8 CI26.2 ; UE3.7 v3(5.52,65.71) ; CV86.2 55.78,92.1 55.41,91.73 v3(55.17,91.73) ; 9.58,48.29 v3(11.32,48.29) ; CV11.2 RV13.2 v3(78.29,87.05) ; v3(66.81,38.79) PR1056.1 PR1035.1 ; C79.2 137.99,98.33 v3(137.86,98.45) ; RM11.2 v3(181.79,66.58) ; CH58.2 154.51,22.57 v3(154.41,22.57) ; PC712.1 46.36,15.05 PR715.1 46.36,13.31 PC721.2 v3(46.35,12.22) ; v3(142.83,74.17) 142.4,74.6 C95.2 ; v3(63.71,98.94) 63.73,98.91 RV40.1 ; v3(152.92,3.22) 152.92,2.5 152.69,2.26 CH14.2 ; CI9.2 197.49,44.33 v3(197.54,44.38) ; v3(197.77,15.14) 197.9,15.14 CA56.2 197.99,16.32 CA55.2 CA53.2 ; RX4.2 v3(13.58,71.3) ; CI14.2 v3(189.21,46.82) ; v3(61.5,104.93) 60.64,105.8 PC514.2 61.13,106.6 PR540.1 ; v3(141.9,87.84) 142,87.74 C107.2 ; v3(38.16,109.66) 38.16,109.63 37.47,108.94 PC5.2 ; CV358.2 v3(198,81.54) 198.11,81.42 CX22.2 ; v3(64.7,72.15) 65.06,72.15 CV54.2 ; v3(57.9,71.77) 57.97,71.7 57.97,70.69 57.74,70.46 CV95.2 RV35.2 ; v3(158.35,21.55) 158.42,21.62 CH33.2 ; CH78.2 CH39.2 164.32,15.62 v3(164.9,15.04) ; v3(173.41,12.93) 173.41,12.32 174.33,11.41 CS42.2 CS27.2 RS36.2 ; v3(210.24,9.33) 210.48,9.57 PR313.2 ; CH81.2 v3(156.58,15.14) ; CV96.2 68.13,97.26 v3(68.13,97.79) ; v3(161.45,10.44) 161.45,9.55 161.14,9.24 RH131.2 RH130.2 162.94,8.96 CH17.2 ; v3(121.47,17.4) 121.65,17.58 122.8,17.58 CE57.2 ; CX31.2 v3(13.52,85.83) ; v3(22.46,73.33) 22.15,73.64 UX4.2 ; CV55.2 62.58,74.79 v3(62.44,74.94) ; QZ15.3 v3(135.96,33.62) ; CI18.2 v3(185.96,53.78) ; CE58.2 v3(29.18,61.3) ; v3(7.61,61.71) 8.03,61.3 JLED.10 ; CI5.2 197.63,47.68 v3(197.65,47.7) ; C935.2 v3(180.78,84.66) ; CA30.2 204.83,18.65 v3(204.4,18.22) ; RS37.2 175.8,15.68 v3(175.16,15.04) ; v3(155.56,22.61) 155.49,22.68 CH36.2 ; R8.1 C29.2 C30.1 145.37,74.65 145.37,75.77 v3(145.7,76.1) ; PC7.2 PC9.2 v3(25.84,29.77) ; QC1.3 v3(165.59,94.39) ; v3(77.25,38.22) 76.64,37.61 CZ13.2 ; RA19.2 189.85,13.64 v3(189.85,13.09) ; v3(158.22,49.59) 158.43,49.38 C129.2 ; v3(72.8,90.12) 73.03,90.35 CV22.2 ; v3(9.05,97.06) 9.15,97.16 CX50.2 ; CE61.1 127.46,16.21 127.46,17.91 v3(127.44,17.94) ; RV17.1 v3(59.87,103.18) ; R56.1 140.58,38.2 v3(140.81,37.97) ; PQ711.3 51.07,13.37 v3(51.64,13.95) ; C90.2 v3(140.71,87.33) ; v3(84.59,49.61) 85.62,49.61 JKB.32 86.1,50.11 85.63,50.58 v3(84.59,50.58) ; v3(52.62,62.15) 52.62,63.17 53.07,63.62 PC854.2 53.07,65.55 PC857.2 ; CH79.2 169.01,31.97 v3(168.89,32.1) ; C110.1 134.96,50.17 v3(135.29,49.84) ; v3(23.4,98.3) 23.06,98.64 PQ5.3 ; v3(187.89,64.06) 188.33,64.51 CM6.2 ; v3(149.26,23.74) 149.72,24.2 RH108.1 ; JTP.5 24.65,58.72 v3(24.28,58.35) ; PC532.2 69.21,120.2 v3(69.37,120.03) ; v2(69.44,21.85) 69.86,21.85 70.08,22.08 PC103.2 ; CV129.2 v3(32.06,67.21) ; C117.2 v3(135.31,40.95) ; C78.2 147.64,93.89 146.8,94.72 v3(145.89,94.72) ; v3(19.97,31.73) 19.61,31.37 PC8.2 ; CE56.2 135.67,17.58 v3(135.82,17.73) ; CM7.2 190.18,64.32 v3(190.43,64.06) 190.68,64.06 191.06,64.44 CM10.2 ; v3(60.43,90.1) 60.59,90.1 61.02,89.67 61.02,89.09 CV50.2 ; v3(12.63,50.6) 12.75,50.72 JLED.8 ; RV2.1 v3(61.91,99.01) ; RH75.2 159.52,10.39 v3(159.5,10.37) 159.5,9.6 RH97.2 ; v3(7.93,100) 7.42,100.51 R365.2 ; QV7.3 v3(13.58,75.99) ; CH83.2 CH84.2 148.83,15.23 148.97,15.09 v3(149.28,15.09) ; v3(139.51,87.38) 139,87.89 C89.2 ; v3(129.12,100.89) 129.12,100.84 129.61,100.36 130.76,100.36 ; CE23.2 v3(3.54,72.65) ; v3(6.46,90.17) 6.28,90 CX2.2 ; C119.1 159.32,48.83 v3(159.57,49.08) ; v3(57.07,99.35) 57.06,99.35 56.32,98.61 56.32,97.53 CV84.2 57.52,97.27 58.1,97.85 CV81.2 ; CZ2.2 75.43,33.14 v3(74.99,32.69) ; C987.1 134.37,2.14 v3(134.98,1.53) ; v3(7.65,83.6) 8.31,84.26 CX8.2 ; v3(161.53,15.48) 161.21,15.17 CH56.2 ; CL19.2 v3(175.7,109.28) 176.46,109.28 176.78,108.96 176.78,108.51 CL14.2 ; PR33.1 v3(29.14,113.47) ; R538.2 175.01,89.29 174.5,88.78 174.25,88.78 v3(174.17,88.7) ; v3(91,64.43) C344.1 C348.1 ; v3(127.46,52.28) 127.49,52.3 127.92,52.3 129.09,51.13 C112.2 ; CV127.2 v3(32.95,67.21) ; v3(183.83,10.75) RS23.2 RS31.2 ; v3(57.28,69.8) 57.33,69.75 RV34.2 CV94.2 ; v3(38.28,111.69) 37.62,111.69 37.5,111.82 PR29.2 ; v3(166.91,104.2) 167.29,103.81 CL17.2 168.13,103.32 CL16.1 ; PC527.2 v3(56.32,114.66) ; v3(135.53,98.58) 135.53,97.93 PC905.2 ; v3(28.89,67.37) 28.76,67.49 CV130.2 ; v3(160.39,20.47) 160.58,20.28 CH34.2 ; CH92.2 141.15,14.91 v3(140.77,15.3) ; CE60.2 14.1,63.76 v3(14.79,63.07) ; v3(124.21,23.96) 124.18,23.99 Q52.4 ; 47.4,16.01 PC706.2 PC707.2 PC710.2 ; v3(97.44,67.75) 98.1,67.09 C986.1 ; CH74.2 155.09,7.23 154.52,7.79 v3(154.52,8.18) ; v3(137.73,100.87) 137.73,100.71 137.32,100.3 PC906.2 ; CI46.2 v3(14.95,41.67) ; CV173.2 v3(33.97,67.29) ; CV49.2 58.53,88.19 58.78,88.45 v3(59.06,88.45) ; CV75.2 PC852.2 ; RX24.1 v3(5.21,90.73) ; v3(134.69,100.87) 135.26,100.3 PC907.2 ; RH24.2 147.02,7.01 147.02,8 v3(146.85,8.17) ; v3(124.39,36.76) 124.77,36.38 C2498.2 ; v3(37.39,103.15) 37.27,103.03 CV155.2 ; v3(144.26,96.02) 144.33,96.08 C76.2 ; UV4.3 72.88,93.24 v3(72.83,93.3) ; C114.2 C113.2 128.45,40.26 v3(128.45,40.82) ; CL41.1 180.88,108.39 v3(181.67,109.17) ; RH40.1 144.18,11.87 v3(143.84,12.21) ; v3(166.54,15.01) 166.88,15.36 CH43.1 ; CM5.2 v3(172.9,66.5) ; v3(140.78,13.52) 141.04,13.77 CH91.2 ; v3(142.69,87.84) 142.69,87.37 142.86,87.2 C108.2 ; C126.2 v3(97.78,51.11) ; PC500.1 v3(64.12,120.13) ; v3(67.87,38.79) 67.87,38.54 69.06,37.36 CZ3.2 ; v3(148.83,11.2) 148.68,11.2 148.07,11.81 CH13.2 148.3,12.44 CH61.2 ; C109.1 v3(123.6,51.11) ; PR571.1 58.35,106.05 v3(58.55,105.85) ; v3(160.44,26.98) 160.99,26.43 CH51.2 ; v3(145.58,25.02) 144.56,26.04 CH85.2 ; v3(59.95,72.65) 60,72.7 RV39.1 ; C128.2 157.27,48.43 v3(156.5,49.2) ; CI43.2 195.42,44.82 195.18,45.06 v3(194.67,45.06) ; v3(73.06,80.07) 72.65,79.66 RV160.2 72.65,79.25 71.81,78.41 RV29.1 ; JHDT1.7 93.49,87.29 v3(94.04,87.84) ; CX11.2 v3(9.33,90.2) 9.32,90.19 CX3.2 ; v3(128.35,117.89) 128.36,117.89 128.56,118.08 C81.2 ; RH132.2 139.02,10.49 v3(138.69,10.49) ; CV61.2 75.8,77.27 RV4.2 75.88,77.93 v3(76.1,78.16) ; PC1021.2 63.8,42.27 v3(66.48,42.27) ; CV126.2 v3(26.45,70.67) ; CV159.2 CV165.2 ; PR110.2 72.57,11.5 72.88,11.8 v3(72.88,11.94) ; CH67.2 152.89,6.47 153.22,6.8 v3(153.22,6.81) ; v3(181.06,53.57) 180.8,53.83 PC306.2 ; v3(146.98,97.36) 147.28,97.66 C75.2 ; v3(35.74,67.29) CV121.2 CV125.2 ; CX49.2 v3(11.36,96.93) ; CH37.2 150.08,26.9 v3(150.2,27.02) ; CE25.2 8.44,70.67 v3(9.07,71.3) ; R50.1 R48.1 R47.1 88.12,84.99 v3(88.53,85.4) 88.12,85.81 C936.2 ; CH73.2 v3(149.74,8.16) CH72.2 ; RS35.2 v3(181.54,22.33) ; SW1.6 v3(173.52,117.55) ; v3(198,84.18) CV360.2 ; C124.2 140.7,39.22 141.28,39.8 v3(141.28,41.02) ; QZ13.3 164.74,38.68 v3(165.11,38.31) ; v3(173.87,90.56) 174.12,90.3 C53.2 ; v3(78.16,81.21) RV12.2 CV28.2 ; CX21.2 199.57,82.99 199.12,83.44 v3(199.12,84.21) ; CX1.2 RX26.2 5.29,81.46 v3(5.82,80.93) 5.34,80.45 RX9.2 ; CI7.2 188.96,44.12 v3(189.26,44.43) ; RX14.2 v3(191.75,75.19) ; PC100.2 v3(73.13,9.29) ; v3(154.96,28.81) 154.21,28.06 CH30.2 ; C349.1 C343.1 129.8,7.7 v3(129.32,8.18) ; R59.1 96.69,52.96 C125.2 96.07,53.55 v3(95.38,52.86) ; v3(155.71,100.69) 155.71,99.75 155.2,99.24 C54.2 R27.2 ; v3(201.35,14.53) 201.35,15.09 CA54.2 ; v2(40.32,14.83) v2(39.68,14.83) ; v3(15.08,48.61) 15.26,48.43 CI45.2 ; v3(71.08,115.98) 70.54,116.51 PC515.2 ; v3(72.9,12.63) PR114.2 ; CV161.2 v3(41.71,103.1) ; SW1.2 v3(176.68,114.05) ; RX13.2 190.7,93.33 v3(190.7,93.86) ; CH64.2 159.65,13.16 RH72.2 ; CV118.2 v3(29.9,66.97) ; CH63.2 150.17,16.72 v3(150.17,16.33) 150.17,15.83 CH62.2 ; CV56.2 72.47,75.21 v3(72.09,74.83) ; PC533.1 67.06,105.24 v3(67.42,104.88) ; CV357.2 v3(198,87.46) ; C115.2 v3(122.87,41.08) ; CE22.2 v3(5.39,73.59) ; v3(190.94,89.15) 190.7,89.39 QX3.3 ; DX2.1 v3(5.49,91.85) ; v3(125.1,28.25) 124.59,27.74 QE30.3 ; RS24.2 RS21.2 178.75,21.92 179.18,22.36 v3(179.51,22.36) ; CI44.2 v3(14.99,46.04) ; CV363.2 v3(196.78,81.31) ; RX36.2 v3(11.99,88.07) ; CI16.2 192.77,40.87 v3(192.46,40.57) ; C94.2 v3(142.8,71.56) ; C93.2 142.22,73.49 v3(142.75,73.49) ; PD1.1 v3(17.77,19.33) ; CV162.2 v3(40.82,103.13) ; v3(25.81,39.25) 25.76,39.25 25.3,38.78 PC708.2 ; v3(78.16,79.05) RV16.2 CV15.2 ; CV65.2 69.04,82.34 v3(69.17,82.46) ; CV158.2 v3(42.6,103.13) ; RV41.1 v3(62.79,98.99) ; R25.2 C106.2 138.26,89.29 v3(138.5,89.05) ; v3(181.92,25.05) 182.3,25.43 CH20.1 ; CV83.2 59.59,96.58 v3(60.25,96.58) ; v3(50.98,45.35) 50.98,44.97 PH1002.1 ; CV153.2 v3(38.16,103.18) ; R616.2 v3(7.25,104.27) ; CI6.2 v3(187.04,40.44) ; UI5.2 v3(193.12,48.7) ; v3(162.75,36.86) 162.75,36.43 RH95.1 ; v3(126.8,1.58) 126.85,1.63 C983.1 ; UI6.2 v3(194.67,44.38) ; CV122.2 CV128.2 39.25,68 39.25,67.24 v3(39.5,66.98) ; PC904.2 137.16,97.88 v3(137.73,97.31) ; v3(38.87,103.15) 39.05,102.98 CV154.2 ; v3(37.52,67.1) CV132.2 CV124.2 ; PC1035.2 57.78,35.81 57.46,36.12 56.47,36.12 56.24,36.35 PC1030.2 ; JTP.10 v3(17.65,58.91) ; UE3.5 v3(2.98,65.71) ; PR9.1 v3(19.67,99.32) ; CV364.2 v3(198,91.01) ; CV359.2 v3(198,85.04) ; UE3.6 v3(4.25,65.71) ; C99.2 v3(142.78,72.57) ; CX7.2 v3(19.49,73.13) ; CV361.2 v3(198,88.68) ; PC316.2 v3(174.81,44.43)
  GND1 w0.203: 193.17,4 H5.1 ; H5.1 196.34,2.66 ; H5.1 193.66,2.66 ; H5.1 196.83,4 ; H5.1 196.34,5.34 ; H5.1 195,2.17 ; H5.1 193.66,5.34 ; H5.1 195,5.83 ; H8.1 84.14,59.14 ; H8.1 84.63,57.8 ; H8.1 82.8,59.63 ; H8.1 82.8,55.97 ; H8.1 81.46,59.14 ; H8.1 80.97,57.8 ; H8.1 81.46,56.46 ; H8.1 84.14,56.46 ; 181.66,30.76 H4.1 ; H4.1 184.34,30.76 ; H4.1 184.34,33.44 ; H4.1 183,33.93 ; H4.1 183,30.27 ; H4.1 184.83,32.1 ; H4.1 181.66,33.44 ; H4.1 181.17,32.1 ; 207.4,55.77 JUSB2.13 ; JUSB2.13 207.4,54.9 ; JUSB2.13 208.77,55.77 ; JUSB2.13 210.14,55.77 ; JUSB2.13 210.14,54.9 ; 202.97,84.7 JHDMI.11 ; JHDMI.11 204.01,85.16 ; JHDMI.11 203.09,85.16 ; JHDMI.11 203.09,84.24 ; JHDMI.11 204.01,84.24 ; JHDMI.11 204.13,84.7 ; H6.1 102.34,2.16 ; H6.1 99.66,2.16 ; H6.1 101,1.67 ; H6.1 99.66,4.84 ; H6.1 101,5.33 ; H6.1 99.17,3.5 ; H6.1 102.34,4.84 ; H6.1 102.83,3.5 ; H3.1 195.5,98.23 ; H3.1 194.16,95.06 ; H3.1 196.84,97.74 ; H3.1 195.5,94.57 ; H3.1 193.67,96.4 ; H3.1 197.33,96.4 ; H3.1 194.16,97.74 ; H3.1 196.84,95.06 ; H2.1 199.74,120.14 ; H2.1 198.4,120.63 ; H2.1 199.74,117.46 ; H2.1 196.57,118.8 ; H2.1 197.06,120.14 ; H2.1 200.23,118.8 ; H2.1 198.4,116.97 ; H2.1 197.06,117.46 ; JHDMI.20 203.13,92.45 ; JHDMI.20 201.85,91.52 ; JHDMI.20 203.13,91.52 ; JHDMI.20 200.57,91.52 ; JHDMI.20 200.57,92.45 ; JHDMI.20 200.57,93.38 ; JHDMI.20 201.85,93.38 ; JHDMI.20 203.13,93.38 ; JUSB2.4 199.29,51.37 ; JUSB2.4 199.92,49.91 ; JUSB2.4 198.46,50.55 ; JUSB2.4 198.65,51.18 ; JUSB2.4 198.65,49.91 ; JUSB2.4 199.29,49.72 ; 21.8,7.97 H7.1 ; H7.1 23.63,9.8 ; H7.1 20.46,11.14 ; H7.1 23.14,11.14 ; H7.1 23.14,8.46 ; H7.1 19.97,9.8 ; H7.1 20.46,8.46 ; H7.1 21.8,11.63 ; 84.81,105.31 H17.1 ; H17.1 86.33,108.91 ; H17.1 87.85,105.31 ; H17.1 88.41,106.83 ; H17.1 84.25,106.83 ; H17.1 87.85,108.35 ; H17.1 84.81,108.35 ; H17.1 86.33,104.75 ; 203.09,82.16 JHDMI.17 ; JHDMI.17 204.01,81.24 ; JHDMI.17 202.97,81.7 ; JHDMI.17 204.13,81.7 ; JHDMI.17 204.01,82.16 ; JHDMI.17 203.09,81.24 ; 207.4,57.4 JUSB1.11 ; JUSB1.11 210.14,56.52 ; JUSB1.11 207.4,56.52 ; JUSB1.11 208.77,56.52 ; JUSB1.11 210.14,57.4 ; H19.1 183.81,91.35 ; H19.1 181.73,93.43 ; H19.1 183.25,89.83 ; H19.1 181.73,89.27 ; H19.1 180.21,89.83 ; H19.1 179.65,91.35 ; H19.1 183.25,92.87 ; H19.1 180.21,92.87 ; 210.02,75.12 JHDMI.23 ; JHDMI.23 211.3,76.98 ; JHDMI.23 212.58,76.05 ; JHDMI.23 210.02,76.05 ; JHDMI.23 212.58,76.98 ; JHDMI.23 212.58,75.12 ; JHDMI.23 210.02,76.98 ; JHDMI.23 211.3,75.12 ; 26.46,117.46 H9.1 ; H9.1 25.97,118.8 ; H9.1 27.8,120.63 ; H9.1 29.63,118.8 ; H9.1 29.14,117.46 ; H9.1 27.8,116.97 ; H9.1 26.46,120.14 ; H9.1 29.14,120.14 ; H18.1 43.75,60.57 ; H18.1 40.15,59.05 ; H18.1 41.67,58.49 ; H18.1 43.19,59.05 ; H18.1 40.15,62.09 ; H18.1 39.59,60.57 ; H18.1 41.67,62.65 ; H18.1 43.19,62.09 ; 12.87,14.52 PBATT.2 ; PBATT.2 13.14,15.33 ; PBATT.2 14.76,13.71 ; PBATT.2 13.14,13.71 ; PBATT.2 15.03,14.52 ; PBATT.2 14.76,15.33 ; 158.47,80.37 H13.1 ; H13.1 160.1,84.24 ; H13.1 162.34,82 ; H13.1 160.1,79.76 ; H13.1 157.86,82 ; H13.1 161.73,80.37 ; H13.1 161.73,83.63 ; H13.1 158.47,83.63 ; 201.85,77.02 JHDMI.22 ; JHDMI.22 203.13,77.02 ; JHDMI.22 201.85,78.88 ; JHDMI.22 200.57,77.02 ; JHDMI.22 203.13,78.88 ; JHDMI.22 200.57,78.88 ; JHDMI.22 203.13,77.95 ; JHDMI.22 200.57,77.95 ; 20.76,93.44 H11.1 ; H11.1 23.93,92.1 ; H11.1 22.1,93.93 ; H11.1 23.44,93.44 ; H11.1 20.27,92.1 ; H11.1 22.1,90.27 ; H11.1 20.76,90.76 ; H11.1 23.44,90.76 ; PBATT.4 14.76,17.71 ; PBATT.4 12.87,18.52 ; PBATT.4 13.14,17.71 ; PBATT.4 15.03,18.52 ; PBATT.4 13.14,19.33 ; PBATT.4 14.76,19.33 ; 14.2,8.42 PBATT.11 ; PBATT.11 16.08,9.4 ; PBATT.11 14.2,10.37 ; PBATT.11 16.08,8.42 ; PBATT.11 12.32,9.4 ; PBATT.11 12.32,8.42 ; PBATT.11 16.08,10.37 ; PBATT.11 12.32,10.37 ; 113.47,109.03 H14.1 ; H14.1 115.1,105.16 ; H14.1 116.73,105.77 ; H14.1 113.47,105.77 ; H14.1 116.73,109.03 ; H14.1 117.34,107.4 ; H14.1 112.86,107.4 ; H14.1 115.1,109.64 ; 198.65,69.38 JUSB1.4 ; JUSB1.4 199.29,69.57 ; JUSB1.4 198.46,68.75 ; JUSB1.4 198.65,68.11 ; JUSB1.4 199.29,67.92 ; JUSB1.4 199.92,68.11 ; JHDMI.2 202.46,88.74 ; JHDMI.2 201.54,89.66 ; JHDMI.2 201.54,88.74 ; JHDMI.2 202.58,89.2 ; JHDMI.2 202,89.78 ; JHDMI.2 201.42,89.2 ; JHDMI.2 202.46,89.66 ; JUSB1.12 203.45,73.1 ; JUSB1.12 201.67,73.97 ; JUSB1.12 199.89,73.1 ; JUSB1.12 203.45,73.97 ; JUSB1.12 199.89,72.22 ; JUSB1.12 199.89,73.97 ; JHDMI.21 211.33,94.35 ; JHDMI.21 208.77,93.42 ; JHDMI.21 210.05,93.42 ; JHDMI.21 208.77,95.28 ; JHDMI.21 210.05,95.28 ; JHDMI.21 211.33,93.42 ; JHDMI.21 208.77,94.35 ; JHDMI.21 211.33,95.28 ; PBATT.10 14.2,32.62 ; PBATT.10 12.32,31.65 ; PBATT.10 16.08,30.67 ; PBATT.10 16.08,32.62 ; PBATT.10 14.2,30.67 ; PBATT.10 16.08,31.65 ; PBATT.10 12.32,30.67 ; PBATT.10 12.32,32.62 ; 158.47,105.77 H16.1 ; H16.1 158.47,109.03 ; H16.1 160.1,105.16 ; H16.1 161.73,105.77 ; H16.1 157.86,107.4 ; H16.1 161.73,109.03 ; H16.1 162.34,107.4 ; H16.1 160.1,109.64 ; JUSB1.13 208.77,73.97 ; JUSB1.13 207.4,73.1 ; JUSB1.13 210.14,73.1 ; JUSB1.13 210.14,73.97 ; 199.89,39.2 JUSB2.10 ; JUSB2.10 203.45,39.2 ; JUSB2.10 199.89,40.07 ; 113.47,80.37 H15.1 ; H15.1 113.47,83.63 ; H15.1 115.1,79.76 ; H15.1 117.34,82 ; H15.1 112.86,82 ; H15.1 116.73,83.63 ; H15.1 116.73,80.37 ; H15.1 115.1,84.24 ; JUSB2.12 203.45,55.77 ; JUSB2.12 199.89,55.77 ; JUSB2.12 199.89,54.9 ; JUSB2.12 201.67,55.77 ; JUSB2.12 199.89,54.02 ; JUSB2.12 203.45,54.9 ; 164.46,71.14 H12.1 ; H12.1 163.97,69.8 ; H12.1 165.8,67.97 ; H12.1 165.8,71.63 ; H12.1 164.46,68.46 ; H12.1 167.14,71.14 ; H12.1 167.63,69.8 ; H12.1 167.14,68.46 ; 13.14,13.33 PBATT.1 ; PBATT.1 15.03,12.52 ; PBATT.1 12.87,12.52 ; PBATT.1 13.95,11.44 ; PBATT.1 13.14,11.71 ; PBATT.1 14.76,11.71 ; PBATT.1 14.76,13.33 ; JHDMI.5 204.01,87.24 ; JHDMI.5 204.13,87.7 ; JHDMI.5 202.97,87.7 ; JHDMI.5 203.09,88.16 ; JHDMI.5 203.09,87.24 ; JHDMI.5 204.01,88.16 ; JLAN.9 206.1,114.41 ; JLAN.9 204.44,114.41 ; JLAN.9 204.44,113.55 ; JLAN.9 207.76,114.41 ; JLAN.9 207.76,113.55 ; JUSB2.11 210.14,39.2 ; JUSB2.11 207.4,38.76 ; JUSB2.11 207.4,39.2 ; JLAN.10 207.76,96.69 ; JLAN.10 204.44,96.69 ; JLAN.10 204.44,97.55 ; JLAN.10 207.76,97.55 ; JLAN.10 206.1,96.69 ; 199.96,65.25 JUSB1.7 ; JUSB1.7 200.79,66.07 ; JUSB1.7 200.79,64.42 ; JUSB1.7 200.16,64.61 ; JUSB1.7 200.16,65.88 ; 200.79,46.22 JUSB2.7 ; JUSB2.7 200.79,47.87 ; JUSB2.7 199.96,47.05 ; JUSB2.7 200.16,47.68 ; JUSB2.7 200.16,46.41 ; 201.67,56.52 JUSB1.10 ; JUSB1.10 203.45,57.4 ; JUSB1.10 203.45,56.52 ; JUSB1.10 199.89,58.27 ; JUSB1.10 199.89,57.4 ; JUSB1.10 199.89,56.52 ; 201.42,86.2 JHDMI.8 ; JHDMI.8 202.46,86.66 ; JHDMI.8 202.46,85.74 ; JHDMI.8 202.58,86.2 ; JHDMI.8 201.54,85.74 ; JHDMI.8 201.54,86.66
  VCC w0.203: 204.44,96.69 JLAN.10 ; JLAN.10 204.44,97.55 ; JLAN.10 207.76,97.55 ; JLAN.10 207.76,96.69 ; JLAN.10 206.1,96.69 ; JUSB2.13 210.14,55.77 ; JUSB2.13 207.4,55.77 ; JUSB2.13 207.4,54.9 ; JUSB2.13 210.14,54.9 ; JUSB2.13 208.77,55.77 ; 115.1,79.76 H15.1 ; H15.1 115.1,84.24 ; H15.1 112.86,82 ; H15.1 117.34,82 ; H15.1 113.47,80.37 ; H15.1 116.73,80.37 ; H15.1 113.47,83.63 ; H15.1 116.73,83.63 ; 199.89,55.77 JUSB2.12 ; JUSB2.12 199.89,54.02 ; JUSB2.12 203.45,54.9 ; JUSB2.12 201.67,55.77 ; JUSB2.12 203.45,55.77 ; JUSB2.12 199.89,54.9 ; JLAN.9 207.76,113.55 ; JLAN.9 206.1,114.41 ; JLAN.9 204.44,113.55 ; JLAN.9 207.76,114.41 ; JLAN.9 204.44,114.41 ; 163.97,69.8 H12.1 ; H12.1 164.46,71.14 ; H12.1 167.14,71.14 ; H12.1 165.8,67.97 ; H12.1 164.46,68.46 ; H12.1 167.63,69.8 ; H12.1 165.8,71.63 ; H12.1 167.14,68.46 ; JHDMI.20 203.13,92.45 ; JHDMI.20 200.57,91.52 ; JHDMI.20 200.57,93.38 ; JHDMI.20 203.13,93.38 ; JHDMI.20 201.85,93.38 ; JHDMI.20 201.85,91.52 ; JHDMI.20 200.57,92.45 ; JHDMI.20 203.13,91.52 ; 197.06,120.14 H2.1 ; H2.1 196.57,118.8 ; H2.1 198.4,120.63 ; H2.1 200.23,118.8 ; H2.1 199.74,117.46 ; H2.1 197.06,117.46 ; H2.1 199.74,120.14 ; H2.1 198.4,116.97 ; JHDMI.23 212.58,76.98 ; JHDMI.23 210.02,75.12 ; JHDMI.23 212.58,76.05 ; JHDMI.23 211.3,76.98 ; JHDMI.23 212.58,75.12 ; JHDMI.23 210.02,76.05 ; JHDMI.23 210.02,76.98 ; JHDMI.23 211.3,75.12 ; 198.65,69.38 JUSB1.4 ; JUSB1.4 198.46,68.75 ; JUSB1.4 199.29,69.57 ; JUSB1.4 198.65,68.11 ; JUSB1.4 199.92,68.11 ; JUSB1.4 199.29,67.92 ; JHDMI.8 202.46,86.66 ; JHDMI.8 201.54,85.74 ; JHDMI.8 201.42,86.2 ; JHDMI.8 201.54,86.66 ; JHDMI.8 202.58,86.2 ; JHDMI.8 202.46,85.74 ; JUSB1.13 210.14,73.97 ; JUSB1.13 208.77,73.97 ; JUSB1.13 210.14,73.1 ; JUSB1.13 207.4,73.1 ; JUSB2.4 199.29,51.37 ; JUSB2.4 198.46,50.55 ; JUSB2.4 198.65,49.91 ; JUSB2.4 198.65,51.18 ; JUSB2.4 199.29,49.72 ; JUSB2.4 199.92,49.91 ; 199.96,65.25 JUSB1.7 ; JUSB1.7 200.79,64.42 ; JUSB1.7 200.79,66.07 ; JUSB1.7 200.16,65.88 ; JUSB1.7 200.16,64.61 ; 200.57,77.95 JHDMI.22 ; JHDMI.22 201.85,77.02 ; JHDMI.22 200.57,78.88 ; JHDMI.22 201.85,78.88 ; JHDMI.22 203.13,77.02 ; JHDMI.22 203.13,77.95 ; JHDMI.22 200.57,77.02 ; JHDMI.22 203.13,78.88 ; 199.89,39.2 JUSB2.10 ; JUSB2.10 199.89,40.07 ; JUSB2.10 203.45,39.2 ; 200.79,46.22 JUSB2.7 ; JUSB2.7 199.96,47.05 ; JUSB2.7 200.16,47.68 ; JUSB2.7 200.79,47.87 ; JUSB2.7 200.16,46.41 ; 199.89,73.1 JUSB1.12 ; JUSB1.12 203.45,73.1 ; JUSB1.12 203.45,73.97 ; JUSB1.12 201.67,73.97 ; JUSB1.12 199.89,72.22 ; JUSB1.12 199.89,73.97 ; 208.77,94.35 JHDMI.21 ; JHDMI.21 208.77,95.28 ; JHDMI.21 210.05,95.28 ; JHDMI.21 208.77,93.42 ; JHDMI.21 210.05,93.42 ; JHDMI.21 211.33,94.35 ; JHDMI.21 211.33,93.42 ; JHDMI.21 211.33,95.28 ; JHDMI.17 204.01,81.24 ; JHDMI.17 204.13,81.7 ; JHDMI.17 203.09,81.24 ; JHDMI.17 204.01,82.16 ; JHDMI.17 202.97,81.7 ; JHDMI.17 203.09,82.16 ; 158.47,80.37 H13.1 ; H13.1 160.1,84.24 ; H13.1 162.34,82 ; H13.1 158.47,83.63 ; H13.1 157.86,82 ; H13.1 160.1,79.76 ; H13.1 161.73,83.63 ; H13.1 161.73,80.37 ; 199.89,58.27 JUSB1.10 ; JUSB1.10 199.89,57.4 ; JUSB1.10 203.45,56.52 ; JUSB1.10 201.67,56.52 ; JUSB1.10 203.45,57.4 ; JUSB1.10 199.89,56.52 ; JHDMI.11 204.01,85.16 ; JHDMI.11 204.01,84.24 ; JHDMI.11 204.13,84.7 ; JHDMI.11 203.09,84.24 ; JHDMI.11 203.09,85.16 ; JHDMI.11 202.97,84.7 ; 194.16,97.74 H3.1 ; H3.1 193.67,96.4 ; H3.1 195.5,94.57 ; H3.1 197.33,96.4 ; H3.1 194.16,95.06 ; H3.1 196.84,97.74 ; H3.1 195.5,98.23 ; H3.1 196.84,95.06 ; 202.97,87.7 JHDMI.5 ; JHDMI.5 203.09,87.24 ; JHDMI.5 204.13,87.7 ; JHDMI.5 204.01,87.24 ; JHDMI.5 203.09,88.16 ; JHDMI.5 204.01,88.16 ; 201.42,89.2 JHDMI.2 ; JHDMI.2 201.54,88.74 ; JHDMI.2 201.54,89.66 ; JHDMI.2 202.46,88.74 ; JHDMI.2 202.46,89.66 ; JHDMI.2 202,89.78 ; JHDMI.2 202.58,89.2 ; v2(210.5,39.04) 210.34,39.2 JUSB2.11 207.25,39.2 207.22,39.22 ; 208.77,56.52 JUSB1.11 ; JUSB1.11 210.14,57.4 ; JUSB1.11 207.4,57.4 ; JUSB1.11 210.14,56.52 ; JUSB1.11 207.4,56.52
  IN3 w0.508: PBATT.2 v2(15.68,14.52)
  GND2 w0.203: H16.1 162.34,107.4 ; H16.1 158.47,109.03 ; H16.1 160.1,105.16 ; H16.1 161.73,109.03 ; H16.1 157.86,107.4 ; H16.1 158.47,105.77 ; H16.1 160.1,109.64 ; H16.1 161.73,105.77 ; 198.65,49.91 JUSB2.4 ; JUSB2.4 199.29,49.72 ; JUSB2.4 199.92,49.91 ; JUSB2.4 199.29,51.37 ; JUSB2.4 198.65,51.18 ; JUSB2.4 198.46,50.55 ; 19.97,9.8 H7.1 ; H7.1 23.14,11.14 ; H7.1 20.46,8.46 ; H7.1 23.63,9.8 ; H7.1 21.8,11.63 ; H7.1 23.14,8.46 ; H7.1 21.8,7.97 ; H7.1 20.46,11.14 ; JLAN.9 206.1,114.41 ; JLAN.9 207.76,113.55 ; JLAN.9 204.44,114.41 ; JLAN.9 204.44,113.55 ; JLAN.9 207.76,114.41 ; 99.66,4.84 H6.1 ; H6.1 101,1.67 ; H6.1 102.83,3.5 ; H6.1 102.34,4.84 ; H6.1 102.34,2.16 ; H6.1 99.66,2.16 ; H6.1 101,5.33 ; H6.1 99.17,3.5 ; 199.89,55.77 JUSB2.12 ; JUSB2.12 203.45,54.9 ; JUSB2.12 203.45,55.77 ; JUSB2.12 199.89,54.02 ; JUSB2.12 201.67,55.77 ; JUSB2.12 199.89,54.9 ; 84.81,105.31 H17.1 ; H17.1 87.85,105.31 ; H17.1 86.33,104.75 ; H17.1 88.41,106.83 ; H17.1 87.85,108.35 ; H17.1 84.81,108.35 ; H17.1 84.25,106.83 ; H17.1 86.33,108.91 ; H15.1 115.1,84.24 ; H15.1 117.34,82 ; H15.1 116.73,80.37 ; H15.1 112.86,82 ; H15.1 113.47,80.37 ; H15.1 115.1,79.76 ; H15.1 116.73,83.63 ; H15.1 113.47,83.63 ; H12.1 167.14,71.14 ; H12.1 163.97,69.8 ; H12.1 167.14,68.46 ; H12.1 165.8,67.97 ; H12.1 164.46,71.14 ; H12.1 165.8,71.63 ; H12.1 167.63,69.8 ; H12.1 164.46,68.46 ; 112.86,107.4 H14.1 ; H14.1 116.73,109.03 ; H14.1 116.73,105.77 ; H14.1 117.34,107.4 ; H14.1 115.1,109.64 ; H14.1 113.47,109.03 ; H14.1 115.1,105.16 ; H14.1 113.47,105.77 ; 13.95,11.44 PBATT.1 ; PBATT.1 13.14,13.33 ; PBATT.1 14.76,13.33 ; PBATT.1 15.03,12.52 ; PBATT.1 12.87,12.52 ; PBATT.1 13.14,11.71 ; PBATT.1 14.76,11.71 ; JHDMI.2 202,89.78 ; JHDMI.2 201.54,88.74 ; JHDMI.2 202.46,88.74 ; JHDMI.2 202.46,89.66 ; JHDMI.2 201.54,89.66 ; JHDMI.2 202.58,89.2 ; JHDMI.2 201.42,89.2 ; H4.1 184.83,32.1 ; H4.1 183,30.27 ; H4.1 184.34,30.76 ; H4.1 183,33.93 ; H4.1 181.66,30.76 ; H4.1 181.17,32.1 ; H4.1 184.34,33.44 ; H4.1 181.66,33.44 ; 193.17,4 H5.1 ; H5.1 193.66,2.66 ; H5.1 193.66,5.34 ; H5.1 195,5.83 ; H5.1 196.34,2.66 ; H5.1 196.83,4 ; H5.1 196.34,5.34 ; H5.1 195,2.17 ; JLAN.10 207.76,96.69 ; JLAN.10 207.76,97.55 ; JLAN.10 204.44,96.69 ; JLAN.10 206.1,96.69 ; JLAN.10 204.44,97.55 ; 202.97,87.7 JHDMI.5 ; JHDMI.5 203.09,87.24 ; JHDMI.5 204.01,87.24 ; JHDMI.5 204.01,88.16 ; JHDMI.5 203.09,88.16 ; JHDMI.5 204.13,87.7 ; JUSB2.13 208.77,55.77 ; JUSB2.13 210.14,54.9 ; JUSB2.13 210.14,55.77 ; JUSB2.13 207.4,54.9 ; JUSB2.13 207.4,55.77 ; 200.16,64.61 JUSB1.7 ; JUSB1.7 200.79,66.07 ; JUSB1.7 200.16,65.88 ; JUSB1.7 199.96,65.25 ; JUSB1.7 200.79,64.42 ; H9.1 27.8,120.63 ; H9.1 26.46,117.46 ; H9.1 29.14,117.46 ; H9.1 27.8,116.97 ; H9.1 29.63,118.8 ; H9.1 29.14,120.14 ; H9.1 26.46,120.14 ; H9.1 25.97,118.8 ; 199.29,67.92 JUSB1.4 ; JUSB1.4 198.65,68.11 ; JUSB1.4 198.65,69.38 ; JUSB1.4 199.92,68.11 ; JUSB1.4 199.29,69.57 ; JUSB1.4 198.46,68.75 ; 201.85,91.52 JHDMI.20 ; JHDMI.20 203.13,91.52 ; JHDMI.20 203.13,93.38 ; JHDMI.20 200.57,93.38 ; JHDMI.20 201.85,93.38 ; JHDMI.20 200.57,92.45 ; JHDMI.20 203.13,92.45 ; JHDMI.20 200.57,91.52 ; PBATT.4 15.03,18.52 ; PBATT.4 14.76,19.33 ; PBATT.4 12.87,18.52 ; PBATT.4 13.14,19.33 ; PBATT.4 13.14,17.71 ; PBATT.4 14.76,17.71 ; JUSB1.10 203.45,57.4 ; JUSB1.10 203.45,56.52 ; JUSB1.10 199.89,56.52 ; JUSB1.10 199.89,57.4 ; JUSB1.10 199.89,58.27 ; JUSB1.10 201.67,56.52 ; H8.1 84.63,57.8 ; H8.1 82.8,59.63 ; H8.1 80.97,57.8 ; H8.1 81.46,56.46 ; H8.1 84.14,56.46 ; H8.1 84.14,59.14 ; H8.1 82.8,55.97 ; H8.1 81.46,59.14 ; PBATT.2 14.76,13.71 ; PBATT.2 13.14,13.71 ; PBATT.2 13.14,15.33 ; PBATT.2 14.76,15.33 ; PBATT.2 15.03,14.52 ; PBATT.2 12.87,14.52 ; JHDMI.23 212.58,76.98 ; JHDMI.23 210.02,75.12 ; JHDMI.23 212.58,75.12 ; JHDMI.23 212.58,76.05 ; JHDMI.23 211.3,76.98 ; JHDMI.23 210.02,76.05 ; JHDMI.23 210.02,76.98 ; JHDMI.23 211.3,75.12 ; H19.1 183.25,92.87 ; H19.1 183.25,89.83 ; H19.1 180.21,89.83 ; H19.1 183.81,91.35 ; H19.1 179.65,91.35 ; H19.1 181.73,93.43 ; H19.1 180.21,92.87 ; H19.1 181.73,89.27 ; H3.1 196.84,95.06 ; H3.1 193.67,96.4 ; H3.1 196.84,97.74 ; H3.1 197.33,96.4 ; H3.1 195.5,98.23 ; H3.1 194.16,97.74 ; H3.1 194.16,95.06 ; H3.1 195.5,94.57 ; JUSB1.13 210.14,73.97 ; JUSB1.13 208.77,73.97 ; JUSB1.13 210.14,73.1 ; JUSB1.13 207.4,73.1 ; 199.96,47.05 JUSB2.7 ; JUSB2.7 200.16,46.41 ; JUSB2.7 200.79,46.22 ; JUSB2.7 200.16,47.68 ; JUSB2.7 200.79,47.87 ; JHDMI.8 202.46,85.74 ; JHDMI.8 201.54,85.74 ; JHDMI.8 202.46,86.66 ; JHDMI.8 201.54,86.66 ; JHDMI.8 201.42,86.2 ; JHDMI.8 202.58,86.2 ; H2.1 199.74,120.14 ; H2.1 199.74,117.46 ; H2.1 196.57,118.8 ; H2.1 197.06,117.46 ; H2.1 198.4,116.97 ; H2.1 197.06,120.14 ; H2.1 198.4,120.63 ; H2.1 200.23,118.8 ; JHDMI.22 203.13,78.88 ; JHDMI.22 201.85,77.02 ; JHDMI.22 200.57,77.95 ; JHDMI.22 200.57,77.02 ; JHDMI.22 203.13,77.95 ; JHDMI.22 200.57,78.88 ; JHDMI.22 201.85,78.88 ; JHDMI.22 203.13,77.02 ; JHDMI.17 204.13,81.7 ; JHDMI.17 203.09,82.16 ; JHDMI.17 202.97,81.7 ; JHDMI.17 204.01,81.24 ; JHDMI.17 204.01,82.16 ; JHDMI.17 203.09,81.24 ; 39.59,60.57 H18.1 ; H18.1 43.19,62.09 ; H18.1 40.15,62.09 ; H18.1 41.67,58.49 ; H18.1 43.19,59.05 ; H18.1 43.75,60.57 ; H18.1 41.67,62.65 ; H18.1 40.15,59.05 ; JUSB2.11 210.14,39.2 ; JUSB2.11 207.4,39.2 ; JUSB2.11 207.4,38.76 ; 12.32,31.65 PBATT.10 ; PBATT.10 12.32,32.62 ; PBATT.10 16.08,32.62 ; PBATT.10 16.08,30.67 ; PBATT.10 12.32,30.67 ; PBATT.10 16.08,31.65 ; PBATT.10 14.2,32.62 ; PBATT.10 14.2,30.67 ; JUSB1.12 203.45,73.97 ; JUSB1.12 201.67,73.97 ; JUSB1.12 203.45,73.1 ; JUSB1.12 199.89,73.97 ; JUSB1.12 199.89,73.1 ; JUSB1.12 199.89,72.22 ; 158.47,83.63 H13.1 ; H13.1 160.1,79.76 ; H13.1 161.73,80.37 ; H13.1 157.86,82 ; H13.1 162.34,82 ; H13.1 160.1,84.24 ; H13.1 161.73,83.63 ; H13.1 158.47,80.37 ; 202.97,84.7 JHDMI.11 ; JHDMI.11 203.09,84.24 ; JHDMI.11 204.01,85.16 ; JHDMI.11 203.09,85.16 ; JHDMI.11 204.01,84.24 ; JHDMI.11 204.13,84.7 ; 210.05,93.42 JHDMI.21 ; JHDMI.21 208.77,93.42 ; JHDMI.21 211.33,94.35 ; JHDMI.21 208.77,95.28 ; JHDMI.21 210.05,95.28 ; JHDMI.21 211.33,95.28 ; JHDMI.21 211.33,93.42 ; JHDMI.21 208.77,94.35 ; 20.27,92.1 H11.1 ; H11.1 23.93,92.1 ; H11.1 23.44,93.44 ; H11.1 20.76,90.76 ; H11.1 22.1,93.93 ; H11.1 23.44,90.76 ; H11.1 20.76,93.44 ; H11.1 22.1,90.27 ; JUSB2.10 203.45,39.2 ; JUSB2.10 199.89,40.07 ; JUSB2.10 199.89,39.2 ; 207.4,56.52 JUSB1.11 ; JUSB1.11 210.14,56.52 ; JUSB1.11 210.14,57.4 ; JUSB1.11 208.77,56.52 ; JUSB1.11 207.4,57.4 ; PBATT.11 16.08,10.37 ; PBATT.11 14.2,10.37 ; PBATT.11 12.32,8.42 ; PBATT.11 12.32,10.37 ; PBATT.11 16.08,9.4 ; PBATT.11 16.08,8.42 ; PBATT.11 12.32,9.4 ; PBATT.11 14.2,8.42
  BOTTOM w0.102: v3(187.04,40.44) v4(186.25,40.44) ; v4(94.99,89.02) 94.63,89.38 v3(94.17,89.38) ; v2(120.73,7.7) 120.73,8.84 v4(120.83,8.95) ; v3(78.16,81.21) 77.72,80.76 v4(77.72,80.5) ; v3(131.15,4.2) 131.15,5.16 v4(131.18,5.2) ; v3(181.67,15.78) 181.67,15.61 v4(181.1,15.04) ; PU200.21 83.98,11.28 v2(83.98,11.26) ; v4(52.51,14.28) 51.97,14.28 v3(51.64,13.95) ; v4(89.59,71.43) 89.08,71.94 88.78,71.94 v3(88.75,71.96) ; v4(88.26,92.64) 88.26,92.26 88.07,92.07 v3(87.37,92.07) ; v3(173.87,90.56) 172.79,90.56 v4(172.78,90.54) ; v4(165.73,105.15) 165.92,105.34 v3(166.99,105.34) ; v3(29.18,61.3) 29.18,61.92 v4(29.01,62.09)
  BOTTOM w0.203: UV1.K2 58.78,94.12 58.78,95.15 v3(58.93,95.3) ; UV6.G1 38.18,78.49 38.18,77.76 UV5.G8 ; UC1.AK27 146.7,88.3 146.7,89.06 146.75,89.11 v3(146.75,89.13) ; UE1.94 120.39,31.49 120.07,31.81 v3(120.07,31.91) ; v3(52.48,89.05) 52.63,88.9 UV1.B10 ; v3(121.37,22.33) 121.57,22.33 121.83,22.59 UE1.113 ; v3(112.2,16.57) 111.99,16.36 UE1.24 ; v3(136.54,12.63) 136.33,12.84 UG1.4 ; UV1.B24 52.69,77.7 v3(52.38,77.39) ; UE1.11 117.19,15.95 v3(117.48,16.23) ; v3(137.6,14.76) 137.53,14.69 UG1.7 ; UV1.B20 53,80.9 52.89,80.79 v3(52.89,80.83) ; v3(52.63,79.28) 52.63,79.19 52.87,79.43 53.47,79.43 UV1.B22 ; UE1.35 108.3,17.39 108.77,17.86 v3(108.77,18.01) ; UV1.B16 53.55,84.15 53.25,84.15 52.87,84.53 v3(52.87,84.52) ; PU200.21 PU200.3 ; UG1.13 135.93,12.48 v3(135.78,12.63)
  BOTTOM w0.254: JEDP.15 2.85,92 v3(2.93,91.93) ; v3(69.6,92.45) 69.95,92.1 UV1.AD6 ; PC105.2 70.14,17.43 69.48,16.77 v2(69.14,16.77) ; v3(164.24,18.85) 164.24,19.21 U2.T25 ; U2.F23 162.24,11.43 v3(161.53,11.43) ; U2.AE15 156.24,26.72 v3(156.63,27.1) ; UC1.AK34 145.77,81.77 v3(145.53,81.77) ; v3(161.2,19.61) 161.2,19.56 161.65,19.12 U2.T22 ; UV1.G10 UV1.F10 55.23,88.9 v3(55.12,89.01) ; UV1.H6 57.2,92.06 v3(57.55,91.71) 57.96,91.3 UV1.J7 ; U2.L16 156.6,15.12 v3(156.58,15.14) ; UV7.J2 36.96,97.95 v3(36.96,97.95) ; UV1.AE27 70.8,75.27 v3(70.45,74.93) ; U2.W28 166.6,21.27 v3(166.6,21.34) ; U2.AH21 161.1,29.19 160.63,28.71 v3(160.4,28.71) ; UC1.Y3 138.3,107.07 v3(137.94,106.71) 137.53,106.3 UC1.W4 ; JNGFF.37 183.48,58.84 183.6,58.96 v3(183.62,58.96) ; v3(58.04,74.76) 58.04,74.76 58.04,75.26 UV1.J27 ; v3(169.53,17.17) 169.45,17.26 U2.P33 U2.P31 ; v3(55.24,87.7) 55.6,87.34 UV1.F12 ; UV1.F18 55.6,82.45 v3(55.17,82.02) ; v3(38.39,99.17) 38.15,98.93 UV7.G1 38.18,98.3 38.18,98.14 38.17,98.13 38.17,97.77 38.17,97.76 38.17,97.74 38.18,97.73 38.18,97.57 UV8.G8 ; U2.N23 U2.N24 163.86,16.97 164.47,16.36 v3(164.75,16.36) ; U2.J32 169.36,13.41 v3(169.71,13.41) ; UV1.B12 53.45,87.15 53.16,87.15 v3(53.12,87.1) ; U2.AF8 v3(150.2,27.02) ; v3(164.07,17.68) 164.07,17.79 164.27,17.99 164.28,17.99 164.5,18.21 U2.R25 ; U2.AH25 v3(164.3,29.8) U2.AK25 U2.AM25 v3(164.3,31.8) ; UV6.G1 v3(38.57,78.94) 38.95,78.57 UV5.F9 ; UV1.G27 56.4,75.32 56.02,75.69 ; v3(156.58,15.14) 156.57,15.14 156.54,15.17 156.54,15.76 U2.M16 ; v3(156.58,15.14) 156.57,15.15 156.03,15.15 156,15.13 U2.L15 ; UV1.F14 55.6,85.76 55.24,86.13 55.23,86.13 v3(55.23,86.12) ; v3(55.22,84.59) 55.6,84.2 UV1.F16 ; U2.F29 167.49,11.27 v3(167.07,10.85) 167.55,10.37 U2.E29 ; U2.T16 156.91,19.12 v3(157.3,19.51) ; v3(150.17,16.33) 150.17,16.63 U2.N8 ; UV1.C32 54,72.41 v3(54.06,72.35) ; UV7.B9 v3(42.15,91.37) ; UC1.AK21 146.3,92.65 146.67,92.28 v3(146.72,92.28) ; U2.AN28 166.75,31.63 167.05,31.33 v3(167.05,31.23) ; U2.P18 158.9,18.3 v3(159.25,18.66) 158.9,19.01 U2.T18 ; U2.F16 157.09,10.97 v3(156.55,10.44) 156.82,10.17 U2.E16 ; v3(166.55,23.68) 166.69,23.68 U2.AA28 167.15,23.22 168.15,23.22 U2.AA30 U2.AA32 ; 166.57,26.18 166.71,26.18 U2.AE28 ; 166.57,26.18 v3(166.57,26.21) ; 166.57,26.18 166.46,26.18 166.1,25.82 U2.AD27 ; v3(62.02,92.61) 62.04,92.59 62.04,92.14 UV1.P6 ; UV8.D8 40.54,97.53 v3(40.14,97.93) UV7.E2 ; UV1.W26 65.77,76.07 65.77,75.52 65.99,75.3 UV1.W27 ; UV1.W26 UV1.W25 66.07,77.17 66.67,77.17 66.94,76.9 UV1.Y25 ; UV1.W26 65.38,76.1 v3(65.11,75.84) ; v3(143.52,45.6) 143.64,45.6 144,45.95 144,46.41 143.55,46.86 JDIMM1.151 ; UV1.AB6 v3(68,92.5) ; RP34.4 60.88,102.68 60.38,103.18 v3(59.87,103.18) ; UV1.G31 56.27,73.17 v3(56.27,72.52) ; U2.J9 151.4,13.67 v3(151.76,14.03) 152.16,13.62 U2.J10 ; U2.R28 166.49,17.95 v3(166.49,17.61) ; v3(55.19,74.87) 54.81,74.5 UV1.E28 ; v3(73.21,72.34) 73.21,72.44 73.2,72.45 UV1.AH32 ; v3(39.35,98.81) 38.95,98.41 UV8.F9 ; U2.M21 160.9,16.11 v3(161.53,15.48) 161.16,15.12 U2.L21 ; U2.L13 154.74,15.11 154.12,15.11 154.01,15.22 154.01,15.19 v3(154.03,15.17) 154.01,15.17 153.94,15.11 153.51,15.11 U2.L12 ; UV1.B6 53.41,91.91 52.92,91.91 52.9,91.89 52.87,91.89 52.85,91.91 v3(52.94,91.91) ; v3(158.17,24.69) 158.17,24.74 U2.AC18 ; U2.J28 167.45,13.32 v3(167.45,13.31) 167.45,13.31 167.84,12.92 U2.H29 ; U2.H12 153.5,12.58 v3(152.74,11.82) ; UV1.B14 v3(52.99,85.7) ; DI1.8 DI1.3 195.76,63.48 v3(195.97,63.28) ; U2.L28 166.84,15.32 v3(166.54,15.01) ; JEDP.6 2.72,96.5 v3(2.88,96.35) ; U2.Y14 155.9,22.27 v3(155.56,22.61) 155.9,22.95 U2.AA14 ; 56.02,75.69 55.62,76.1 UV1.F26 ; 56.02,75.69 v3(56.02,75.69) ; v3(32.11,98.84) 32.55,98.4 UV7.P1 ; UV8.B3 42.15,93.7 v3(42.45,94) ; U2.D13 U2.B13 154.52,8.79 v3(154.52,8.18) ; v3(167.65,12.35) 167.87,12.35 168.08,12.55 168.43,12.55 168.87,12.12 U2.G32 ; U2.V21 161.4,20.62 v3(161.4,20.62) ; U2.F25 164.3,10.95 163.97,10.62 v3(163.97,10.54) ; v2(40.32,14.83) 40.32,14.85 40.34,14.83 PU700.19 ; UC1.D11 125.22,100.7 v3(125.02,100.89) ; U2.H25 164.4,12.82 164,13.22 164.03,13.22 v3(164.03,13.23) ; v3(136.52,104.35) 136.25,104.35 UC1.U6 135.68,104.7 v3(135.27,105.11) ; v3(68.3,71.68) 68.39,71.77 68.39,72.89 UV1.AB32 ; v3(36.91,92.36) 36.89,92.36 36.55,92.7 UV7.J8 ; UV1.J31 57.89,73.19 v3(57.89,72.4) ; U2.W25 164.5,22.27 v3(164.88,22.66) 164.5,23.04 U2.AA25 ; v3(189.67,58.93) 189.48,58.74 JNGFF.61 ; v3(132.3,86.92) 132.12,87.1 UC1.L28 ; U2.AE6 148.87,26.52 v3(149.3,26.09) 149.3,25.41 148.8,24.92 U2.AC6 ; v3(71.65,72.07) 71.64,72.07 71.6,72.11 UV1.AF32 ; v3(149.74,8.16) 149.76,8.18 149.76,8.83 U2.B7 ; v3(148.83,11.2) 148.83,11.2 149.06,10.97 U2.F7 ; v3(148.83,11.2) 148.15,10.52 U2.E5 ; v3(148.83,11.2) 148.75,11.29 U2.G6 ; U2.Y18 158.9,22.1 v3(158.35,21.55) ; U2.AH19 159.5,29.26 v3(159.09,28.86) 158.7,29.25 U2.AH18 ; JNGFF.49 v3(186.48,58.96) ; v3(34.17,71.52) 34.17,72.1 UV6.M9 ; UV5.E1 39.75,72.1 v3(40.19,71.66) 40.55,72.02 UV5.D1 ; UV1.F6 55.58,92.1 55.21,91.73 v3(55.17,91.73) ; JNGFF.67 v3(190.98,58.96) ; U2.V16 156.4,20.62 v3(155.72,20.62) 155.74,20.6 155.74,20.35 155.9,20.19 U2.U14 ; UV5.A9 42.95,78.55 v3(42.56,78.94) 42.15,78.53 UV6.B1 ; v3(170.05,31.3) 169.68,31.67 U2.AN33 ; v3(161.18,29.85) 161.18,30.39 U2.AK21 161.2,30.57 161.2,31.16 U2.AM21 ; UV8.D1 40.55,91.95 v3(40.16,92.33) ; U2.F9 151.87,10.6 v3(151.87,10.49) 151.87,10.14 151.5,9.77 U2.D9 ; v3(64.06,75.7) 64.4,75.37 UV1.U27 ; v3(141.9,87.84) 141.9,87.5 UC1.AE28 ; UC1.W6 137.46,105.06 v3(137.66,105.06) ; v3(36.96,78.11) 36.58,77.72 UV6.J2 ; U2.K28 166.9,14.52 v3(166.54,14.15) 166.27,14.42 U2.K27 ; v3(64.7,72.15) 65.2,72.65 UV1.V32 ; v3(69.96,72.4) 69.96,72.89 69.97,72.9 UV1.AD32 ; UV1.AH10 73.1,88.8 73.1,87.95 v3(72.82,87.66) 72.46,87.3 UV1.AG12 ; UV1.F24 55.25,77.7 v3(55.12,77.57) ; UV1.J7 58.06,91.24 58.43,90.87 v3(58.43,90.86) ; UV1.J7 UV1.K6 ; UV7.T9 30.95,90.86 30.79,90.71 v3(30.79,90.56) ; U2.N28 166.52,16.39 v3(166.49,16.39) ; v3(147.49,104.4) 147.59,104.4 147.82,104.17 148.03,104.17 UC1.AN7 ; UV7.G9 38.15,91.94 v3(38.56,92.36) ; v3(43.26,10.93) 43.44,11.11 PU700.12 ; UV1.AC26 69.23,76.1 69.54,75.79 v3(69.54,75.71) 69.54,75.59 69.25,75.3 UV1.AC27 ; v3(69.59,89.38) 69.56,89.38 69.23,89.7 UV1.AC9 ; U2.M25 164.5,15.44 v3(164.9,15.04) ; v3(32.85,79.02) 32.85,78.97 32.55,78.67 UV6.P1 ; U2.V18 v3(158.4,20.62) U2.U17 ; v3(59.95,72.65) 60.2,72.9 UV1.M32 ; v3(40.16,92.33) 39.76,91.93 UV8.E1 ; v3(40.16,92.33) 39.76,92.73 UV7.E8 ; U2.AC28 166.28,24.92 166.06,25.14 v3(164.8,25.14) 164.8,24.82 U2.AB25 ; U2.P21 160.9,18.09 160.57,17.76 v3(160.44,17.76) 160.26,17.76 U2.P20 ; U2.AH5 148.21,28.97 v3(148.63,29.39) ; UV1.H2 57.17,94.13 v3(57.17,95.03) ; UV5.D8 40.54,77.72 v3(40.15,78.12) 39.75,77.72 UV6.E2 ; v3(165.6,29.81) 165.9,29.51 U2.AH27 ; U2.K16 156.77,14.32 v3(156.58,14.51) ; U2.U6 148.78,20.12 149.09,19.8 v3(149.19,19.8) 149.23,19.84 149.23,21.37 148.88,21.72 U2.W6 148.67,21.8 147.63,21.8 U2.W4 ; UC1.G34 127.9,82.74 128.08,82.92 128.08,83.61 v3(127.69,84) ; JEDP.20 2.61,89.5 v3(2.77,89.67) ; U2.Y16 156.7,22.32 v3(156.7,22.61) 156.7,22.92 U2.AA16 ; UV1.L27 59.66,75.3 60.07,75.72 60.7,75.72 60.9,75.52 60.98,75.52 UV1.N27 v3(60.84,74.94) ; U2.J6 148.9,13.72 v3(149.27,14.09) 149.47,14.09 U2.K7 149.8,14.57 v3(149.28,15.09) 149.05,15.32 U2.L6 ; U2.E12 153.63,10.17 153.45,10.34 153.37,10.34 v3(153.3,10.42) 153.32,10.44 153.32,10.75 U2.F11 ; UV1.Y32 66.78,72.88 66.73,72.88 66.33,72.48 v3(66.33,72.25) ; v3(2.88,95.18) 2.7,95.18 2.52,95 JEDP.9 ; UV1.AA27 67.6,75.27 v3(67.99,74.89) ; UV1.F20 55.6,80.83 55.21,80.44 v3(55.21,80.41) ; U2.U30 U2.U32 169.96,20.12 v3(170.09,20.25) ; U2.A3 v3(146.85,8.17) ; v3(137.51,109.3) 137.42,109.21 137.42,108.38 UC1.W1 ; U2.AJ29 v3(168.1,30.32) ; U2.R4 147.88,18.52 148.33,18.97 v3(148.35,18.97) 148.75,18.57 U2.R6 ; v3(55.27,78.92) 55.6,79.25 UV1.F22 ; v3(152.3,16.32) 152.9,16.92 U2.N11 152.9,17.12 U2.P12 ; PU700.14 42.05,11.54 41.89,11.54 v3(41.87,11.56) ; v3(2.8,97.82) 2.62,98 JEDP.3 ; v3(132.9,105.08) 133.28,104.7 UC1.P6 ; U2.V11 U2.T11 152.86,19.47 v3(152.26,18.87) 152.9,18.23 U2.R11 ; v3(56.81,90.85) 56.46,90.5 UV1.G8 56.37,90.47 55.63,90.47 UV1.F8 ; v3(160.44,26.98) 160.7,26.72 U2.AE21 ; UV1.B18 53.58,82.48 53.22,82.48 52.91,82.79 v3(52.57,82.79) ; U2.T27 166.1,19.08 v3(166.33,18.85) ; U2.T21 160.9,19.08 v3(160.44,18.62) ; v3(163.05,28.62) 162.7,28.97 U2.AH23 ; U2.U20 160.03,20.12 v3(160.39,20.47) 160.74,20.12 U2.U21 ; DI4.8 v3(192.11,46.92) ; UV1.AH28 UV1.AG27 ; v3(55.43,94.96) 55.56,94.83 55.56,94.14 UV1.F2 ; v3(69.6,90.82) 69.92,90.5 UV1.AD8 ; JEDP.18 v3(2.8,90.5) ; v3(70.41,91.72) 70.41,91.72 70.8,91.33 UV1.AE7 ; JNGFF.25 v3(180.48,58.96) ; U2.AA12 153.9,22.79 v3(153.73,22.62) ; UV1.A3 53.3,93.8 53.3,94.8 v3(53.5,95) UV1.C1 ; v3(36.96,72.52) 36.55,72.92 UV6.J8 ; U2.AN1 146.35,31.73 v3(145.77,32.31) ; v3(154.41,22.57) 154.9,23.06 U2.AA13 ; UV1.B8 53.67,90.5 54.01,90.83 v3(54.01,90.81) ; v3(32.67,91.39) 32.59,91.47 32.59,91.89 UV7.P9 ; v3(149.26,23.74) 148.84,23.32 U2.AA6 ; U2.AA17 157.9,23.36 v3(157.44,23.83) ; JEDP.12 2.6,93.5 v3(2.77,93.32) ; v3(63.99,91.73) 63.97,91.73 UV1.T6 ; JNGFF.1 v3(172.48,58.98) ; U2.U22 162.31,19.71 v3(162.31,19.61) ; U2.M13 U2.N13 154.65,17.12 154.44,17.32 v3(154.44,17.58) ; U2.AJ18 158.7,30.06 v3(159.09,29.67) ; v3(53.09,76.03) 53.17,76.1 UV1.B26 ; v3(170,14.76) 169.86,14.62 169.55,14.62 U2.K33 ; v3(176.89,66.55) 176.73,66.39 JNGFF.18 ; U2.AF12 153.56,27.52 v3(153.99,27.09) ; UV1.H17 57.2,82.72 v3(56.99,82.51) ; v3(134.05,108.82) 134.05,108.55 UC1.R1 ; U2.K25 164.4,14.39 v3(164.77,14.02) ; v3(58.5,74.1) 58.5,74.12 58.53,74.15 58.53,74.22 58.8,74.5 UV1.K28 ; JNGFF.31 181.98,58.9 v3(181.9,58.98) ; v3(40.15,73.33) 39.75,72.93 UV6.E8 ; UC1.AN19 148.69,93.91 148.87,93.91 149.15,93.62 149.15,92.71 v3(149.1,92.66) ; U2.F19 v3(159.5,10.37) ; UV6.B9 42.15,72.09 v3(42.54,71.7) ; UV1.K32 58.66,72.76 v3(58.66,72.29) ; UV7.T1 30.86,98.33 v3(30.51,98.68) ; UV6.T1 30.95,78.82 v3(31.21,79.08) ; v3(60.42,92.67) 60.4,92.65 UV1.M6 ; v3(42.53,74.14) 42.53,74.14 42.15,73.76 UV5.B3 ; v3(63.18,72.45) 63.6,72.87 UV1.T32 ; JNGFF.55 v3(187.98,58.97) ; v3(161.4,21.62) 161.9,21.12 U2.V22 ; JNGFF.43 v3(184.98,58.96) ; v3(156.63,27.87) 156.98,27.52 U2.AF16 ; UV1.R27 v3(62.44,74.94) ; U2.F13 154.7,11.06 v3(154.36,11.4) ; v3(38.57,71.75) 38.47,71.75 38.15,72.07 UV6.G9 ; v3(141.14,106.71) 141.5,107.07 UC1.AD3 UC1.AE4 ; UV8.A9 42.45,98.84 v3(42.42,98.84) 42.15,98.56 UV7.B1 ; U2.AL18 158.68,30.89 158.68,31.65 U2.AN18 158.7,31.69 158.95,31.94 159,31.94 v3(159.09,32.03) ; U2.N6 148.75,16.92 149.25,16.41 v3(149.25,15.95) ; UV1.A30 52.68,73.7 v3(52.61,73.63) ; v3(194.93,46.71) 194.93,46.76 194.77,46.92 DI4.3 ; UV6.T9 30.53,72.12 v3(30.32,71.91) ; UV7.M1 34.15,98.5 v3(33.81,98.84) ; v3(32.17,71.72) 32.55,72.09 UV6.P9 ; U2.G16 157.66,11.92 v3(157.9,11.67) 157.9,10.97 U2.F17 ; UV7.M9 v3(34.15,91.24) ; U2.AJ28 v3(167.2,30.32) ; JEDP.31 v3(2.77,84) ; v3(153.1,29.82) U2.AH11 ; JNGFF.7 v3(173.98,56.67)
  BOTTOM w0.3: v3(100.56,41.46) 100.41,41.46 100.05,41.09 JDIMM1.14 ; v3(104.22,41.53) 103.97,41.53 103.65,41.22 JDIMM1.26 ; v3(102.19,45.7) 102.36,45.7 103.35,46.68 JDIMM1.25 ; JDIMM1.20 101.85,41.14 102.27,41.56 102.32,41.56 v3(102.34,41.53)
  BOTTOM w0.305: UC1.AK12 146.3,99.9 v3(146.75,99.44) 146.41,99.1 UC1.AK13 ; v3(141.9,88.75) 141.45,88.3 UC1.AD27 ; v3(139.51,87.38) 139.79,87.1 UC1.AC28 ; v3(122.38,84.18) 122.44,84.24 122.58,84.24 122.85,84.51 123.31,84.51 UC1.A31 ; v3(107.07,45.29) 106.94,45.29 106.53,45.7 106.53,46.12 106.95,46.54 JDIMM1.37 ; v3(127.55,93.63) 127.55,93.51 127.14,93.1 UC1.F21 ; v3(148.98,87.84) 148.92,87.9 UC1.AN27 ; v3(146.87,79.25) 146.87,79.67 UC1.AL37 ; v3(144.19,91.29) 144.19,91.39 UC1.AH22 ; UC1.A15 123.47,97.52 123.44,97.49 122.7,97.49 v3(122.65,97.44) ; UC1.AK29 146.69,85.91 v3(146.7,85.91) ; v3(127.47,97.21) 127.9,96.78 UC1.G16 ; v3(127.47,85.27) 127.47,85.53 UC1.F30 ; UC1.J27 129.5,88.16 v3(129.1,87.76) ; v3(124.97,98.78) 125.02,98.84 125.24,98.84 UC1.D13 ; UC1.N28 132.72,86.92 v3(132.3,86.92) ; v3(144.81,46.21) 144.81,46.23 144.75,46.29 JDIMM1.155 ; UC1.F11 127.1,100.61 v3(126.81,100.89) ; v3(124.83,95.69) 125.05,95.9 UC1.D17 125.5,95.7 125.7,95.5 UC1.E17 ; v3(141.75,101.98) 141.3,101.54 UC1.AD10 ; UC1.AG27 143.9,88.2 v3(144.31,87.79) ; UC1.D27 125.23,87.9 v3(124.96,87.63) ; UV1.AC17 69.17,83.07 v3(69.17,82.46) ; v3(125.95,97.23) 125.77,97.23 UC1.D15 ; v3(169.68,8.03) 169.68,8.28 169.45,8.51 U2.A33 ; v3(127.42,94.85) 127.9,94.37 UC1.G19 ; UC1.G22 128.39,92.39 v3(128.39,92.48) ; UC1.AJ25 145.05,89.95 v3(145.05,90.15) 145.05,90.25 UC1.AJ24 145.9,90.7 UC1.AK23 ; v3(64.06,77.23) 64.39,76.9 UV1.U25 ; UC1.J16 129.5,96.78 v3(129.05,97.23) ; UC1.AK19 145.89,94.71 v3(145.89,94.72) ; UV1.H20 56.8,80.3 v3(56.8,80.1) ; UV1.H14 57.2,85.51 56.8,85.91 56.8,86.1 v3(56.8,86.1) ; UC1.AD28 140.94,87.1 v3(140.71,87.33) ; UC1.AG17 143.9,95.65 v3(144.26,96.02) ; UC1.A11 123.72,100.7 123.87,100.84 123.87,100.88 124.12,101.13 124.48,101.13 124.54,101.07 124.56,101.07 124.73,100.89 v3(125.02,100.89) ; UC1.D29 125.38,86.42 v3(124.97,86.42) ; v3(141.85,99.7) 141.3,99.15 UC1.AD13 ; v3(100.69,45.72) 100.56,45.72 99.75,46.54 JDIMM1.13 ; UC1.D31 125.18,84.38 v3(125.01,84.38) ; v3(122.48,80.85) 122.46,80.83 122.46,80.45 123.01,79.9 UC1.A37 ; UC1.G13 127.9,99.2 v3(127.45,99.65) ; v3(126.74,87.74) 127.1,88.1 UC1.F27 ; UC1.AE27 142.69,87.91 v3(142.69,87.84) 142.69,87.51 UC1.AF28 ; UC1.AF24 142.59,90.19 v3(142.59,90.07) ; v3(148.29,81.12) 148.28,81.12 UC1.AM35 ; v3(71.2,86.1) 70.8,85.7 UV1.AE14 ; v3(129.2,81.79) 129.2,82 UC1.J34 ; UC1.AG25 143.9,89.32 v3(144.29,88.93) ; v3(129.5,86.03) UC1.J28 ; UC1.C35 124.69,81.5 v3(124.32,81.13) ; v3(126.13,84.13) 126.3,84.3 UC1.E31 ; UC1.AN14 150.05,98.3 150.99,97.35 v3(150.99,97.29) ; JDIMM1.49 110.55,46.59 110.32,46.36 110.32,45.8 110.62,45.5 v3(110.83,45.5) ; UC1.K27 130.5,88.25 v3(130.01,87.76) ; UC1.P9 133.46,102.3 v3(132.96,102.8) ; JDIMM1.72 117.45,40.74 v3(117.91,41.2) ; UC1.AH16 144.7,97.01 v3(144.97,97.29) ; v3(148.93,86.14) 148.93,85.73 UC1.AN30 ; v3(141.81,46.33) 141.81,46.28 141.75,46.35 JDIMM1.145 ; UC1.M9 131.9,102.7 v3(131.72,102.7) ; v3(124.88,105.18) 124.7,105 UC1.C6 ; v3(128.96,85.4) 128.73,85.63 128.73,85.87 UC1.H30 128.7,85.76 ; v3(72.09,74.83) 72.09,75.01 72.38,75.3 UV1.AG27 ; v3(127.4,90.12) 127.4,90.4 UC1.F24 126.56,91.24 125.64,91.24 UC1.D23 ; UC1.AG21 143.97,93.03 v3(143.97,92.54) ; v3(124.3,107.47) 124.67,107.1 UC1.C3 ; UV1.AC24 69.2,77.61 v3(68.75,77.16) 68.21,77.7 UV1.AB24 ; UC1.A7 123.5,103.9 123.33,103.74 122.43,103.74 v3(122.28,103.89) ; v3(129.71,102.21) 129.22,102.7 UC1.H8 ; U2.V24 163.7,20.86 v3(164.08,21.24) 164.5,20.82 U2.V25 ; UC1.G1 127.91,108.31 v3(127.91,108.82) ; UV1.P32 62.45,72.45 v3(63.18,72.45) ; v3(146.75,89.13) 146.38,89.5 UC1.AK25 ; UC1.W9 137.24,102.3 v3(137.68,102.75) ; v3(122.31,87.28) 122.31,87.3 122.72,87.71 123.31,87.71 UC1.A27 ; UC1.AN10 149.42,101.5 v3(149.55,101.37) ; UV1.AD25 70.03,76.9 v3(70.38,77.25) ; U2.J13 155.23,13.52 v3(155.63,13.12) 156,12.75 U2.H15 ; v3(145,99.6) 144.7,99.3 UC1.AH13 ; v3(127.47,86.62) 127.47,86.67 127.9,87.1 UC1.G28 ; UV1.U9 64.92,89.7 v3(65.16,89.46) ; v3(128.29,98.48) 128.7,98.07 UC1.H14 ; UC1.D19 125.07,94.3 v3(124.93,94.44) ; v3(127.47,88.95) 127.9,89.38 UC1.G25 ; v3(131.1,108.82) UC1.L1 ; v3(129.12,100.89) 129.5,100.52 UC1.J11 ; UV1.Y10 67.44,89.34 v3(67.72,89.34) ; UV1.P9 62.26,89.7 62.52,89.43 v3(62.71,89.43) ; v3(148.52,79.35) 148.7,79.53 UC1.AN37 ; v3(122.54,81.44) 122.6,81.5 UC1.A35 ; UC1.AG28 143.9,86.75 v3(144.14,86.52) ; v3(127.98,79.68) 127.9,79.76 UC1.G37 ; v3(122.72,94.14) 122.79,94.2 123.4,94.2 UC1.A19 ; UC1.A23 123.23,90.83 123.02,90.83 122.59,90.4 122.59,90.33 122.61,90.3 122.61,90.28 v3(122.59,90.25) ; U2.Y22 v3(161.4,21.62) ; UC1.AG14 143.9,98.05 v3(144.3,98.45) ; v3(125.01,82.78) 125.33,83.1 UC1.D33 ; v3(146.7,84.28) 146.3,84.68 UC1.AK31 ; v3(126,81.82) 126.3,82.12 UC1.E34 ; U2.V23 162.9,20.86 v3(163.28,21.24) ; UC1.AN23 148.62,90.78 v3(148.89,90.78) ; v3(142.74,100.82) 142.3,100.38 UC1.AE11 ; v3(146.98,97.36) 146.84,97.5 UC1.AK15 ; v3(144.34,94.87) 144.34,94.66 UC1.AH19 ; UV6.M1 34.15,78.63 33.8,78.97 33.83,78.97 33.83,78.99 v3(33.82,78.99) ; UC1.H17 128.41,95.79 v3(128.41,96.12) ; UC1.U9 135.82,102.3 v3(135.37,102.75) ; JDIMM1.173 v3(150.15,46.33)
  BOTTOM w0.35: JDIMM1.48 110.25,41.08 110.7,41.53 110.8,41.53 v3(110.83,41.51)
  BOTTOM w0.356: UC1.AH30 144.7,85.95 v3(144.14,86.52) ; v3(143.5,106.71) 143.53,106.68 143.53,106.67 UC1.AG4 ; v3(124.3,107.47) 124.53,107.7 124.53,107.7 124.7,107.88 UC1.C2 ; v3(97.03,41.53) 96.92,41.53 96.45,41.06 JDIMM1.2 ; UC1.AH31 144.7,84.77 v3(144.33,85.15) ; JDIMM1.179 151.95,48.72 152.18,48.95 v3(152.18,49.03) ; v3(112.63,41.56) 112.63,41.53 112.6,41.56 112.53,41.56 112.05,41.08 JDIMM1.54 ; v3(147.49,106.71) 147.1,107.1 UC1.AL3 ; JDIMM1.185 153.75,46.77 154.74,45.78 154.74,45.27 154.36,44.89 v3(154.18,44.89) ; JDIMM1.31 105.15,48.99 v3(104.94,49.2) ; v3(147.01,103.75) 147.1,103.66 UC1.AL8 UC1.AK9 ; JDIMM1.150 143.25,41.23 142.77,41.71 v3(142.63,41.71) ; JDIMM1.197 157.35,48.69 157.77,49.1 v3(157.77,49.15) ; JDIMM1.167 148.35,46.77 147.83,46.25 v3(147.78,46.25) 147.09,46.25 146.56,46.78 146.56,47.44 146.55,47.45 JDIMM1.161 ; JDIMM1.66 115.65,41.05 116.13,41.53 v3(116.29,41.53) ; v3(129.84,106.79) 129.5,106.45 UC1.J4 ; v3(142.76,103.33) 142.76,103.61 143.05,103.9 UC1.AF7 ; JDIMM1.60 113.85,40.73 v3(114.02,40.89) ; UC1.D4 126.08,106.88 v3(126.08,107.01) ; v3(123.09,109.28) 123.1,109.27 UC1.A1 ; v3(140.91,108.89) 140.91,108.51 UC1.AC1 ; v3(135.29,49.84) 135.52,49.84 136.35,49 JDIMM1.127 ; v3(158.22,49.59) 158.55,49.26 JDIMM1.201 ; v3(116.14,45.72) 115.83,45.72 115.35,46.2 JDIMM1.65 ; UC1.AC7 140.92,103.9 141.16,104.14 v3(141.16,104.22) ; v3(113.42,44.4) 113.19,44.4 112.33,45.26 112.33,46.64 112.35,46.66 112.35,46.66 JDIMM1.55 ; v3(108.82,46.33) 108.75,46.4 JDIMM1.43 ; v3(113.47,45.7) 113.59,45.7 114.15,46.25 JDIMM1.61 ; v3(131.66,104.25) 132.12,104.7 UC1.M6 ; UC1.N4 132.38,106.62 v3(132.38,106.84) ; v3(144.92,105.72) 145.5,106.3 UC1.AJ4 ; v3(98.46,40.9) 98.43,40.9 98.25,40.72 JDIMM1.8 ; v3(143.9,109.22) UC1.AG1 ; UC1.AE1 142.3,108.9 v3(142.18,109.02) ; JDIMM1.19 101.55,49.11 101.02,49.64 v3(100.77,49.64) ; v3(107.85,41.51) 107.75,41.51 107.25,41 JDIMM1.38 ; v3(156.5,49.2) 156.46,49.17 155.37,49.17 154.95,48.74 JDIMM1.189 ; v3(98.55,49.13) JDIMM1.9 ; JDIMM1.178 151.65,41.07 151.24,41.48 v3(151.03,41.48) ; v3(125.1,89.93) 125.5,89.53 UC1.D25 ; JDIMM1.139 139.95,46.68 139.71,46.44 139.71,46.36 v3(139.68,46.33) ; v3(116.77,44.96) 117.15,45.34 JDIMM1.71 ; JDIMM1.32 105.45,41.24 105.75,41.53 106,41.53 v3(106.05,41.48) ; UC1.J6 130.11,104.7 v3(130.42,105.01) ; v3(138.3,46.32) 138.15,46.47 JDIMM1.133 ; v3(109.05,40.87) JDIMM1.44
  BOTTOM w0.381: v3(64.76,80.79) 64.77,80.79 64.4,81.16 UV1.U20 ; 103.31,49.33 103.35,49.29 JDIMM1.25 ; JDIMM1.65 115.35,49.69 115.37,49.71 ; v3(58.4,78.9) 58.4,79.1 UV1.K22 ; UC1.N22 132.81,91.9 v3(132.35,92.36) 131.7,93.01 UC1.L21 131.13,93.67 v3(131.13,93.76) 130.59,94.3 UC1.K19 ; UC1.AN1 149.17,109.17 v3(149.23,109.17) ; UC1.K13 130.61,99.1 v3(131.13,98.58) 131.7,98.01 UC1.L14 UC1.N16 133.01,96.7 v3(133.54,96.17) 133.54,96.12 133.92,95.74 133.92,95.67 UC1.P17 ; UV3.5 v3(48.39,107.77) ; UV1.AA13 67.42,86.1 v3(67.93,86.61) ; UV1.R20 62.6,81.23 v3(62.07,80.7) ; JDIMM1.43 108.75,49.44 108.77,49.46 ; v3(140.53,12.19) 140.76,11.96 140.76,10.91 CH10.1 ; v3(134.69,88.93) 134.73,88.93 UC1.T25 ; UC1.AE21 142.13,92.93 v3(142.13,92.54) ; v3(141.85,96.17) 141.32,96.7 UC1.AD16 ; UV1.V16 65.4,84.1 v3(65.93,84.63) ; v3(62.08,87.65) 62.54,88.1 UV1.R11 62.81,88.31 63.27,88.31 63.48,88.1 UV1.T11 ; v3(62.08,87.65) 61.63,88.1 UV1.N11 ; v3(62.08,87.65) 62.6,87.13 UV1.R12 UV1.T13 ; v3(136.34,90.07) 136.34,89.66 UC1.V25 ; JDIMM1.144 141.45,40.85 v3(141.28,41.02) ; v3(129.94,97.23) 129.97,97.23 UC1.K16 131.03,96.17 v3(131.13,96.17) 131.7,95.6 UC1.L17 UC1.N19 133.13,94.3 v3(133.67,93.75) 133.67,93.53 UC1.P21 ; v3(65.14,88.65) 65.4,88.4 UV1.V11 ; UC1.V17 136.21,95.79 v3(136.21,96.17) ; v3(134.69,100.87) 134.12,100.3 UC1.P11 133.54,100.86 v3(133.54,100.99) 133.04,101.5 UC1.N10 132.3,102.1 UC1.M9 ; UC1.J24 129.07,91.13 v3(129.07,91.27) ; v3(152.26,18.87) 151.63,18.87 v3(151.61,18.85) ; JDIMM1.185 153.75,49.69 153.73,49.71 ; v3(135.53,96.17) 135.3,96.39 UC1.T16 ; UC1.T19 135.3,94.16 134.89,93.75 v3(134.69,93.75) ; v3(136.21,98.58) 136.21,98.19 UC1.V14 ; UC1.Y24 137.61,90.61 v3(137.61,90.07) ; v3(139.51,101.63) 139.03,101.63 UC1.AA10 ; JDIMM1.145 141.75,49.67 141.79,49.71 ; UV1.N18 61.6,82.39 v3(62.08,82.87) 62.32,83.11 62.32,83.11 62.52,83.3 UV1.R17 ; v3(125.09,92.31) 125.48,92.7 UC1.D21 ; 146.49,49.84 146.55,49.78 JDIMM1.161 ; v3(157.64,41.15) 157.05,40.56 JDIMM1.196 ; UC1.K10 130.62,101.5 v3(131.13,100.99) 131.13,100.87 UC1.L11 UC1.N13 133.02,99.1 v3(133.54,98.58) 133.54,98.46 UC1.P14 ; JDIMM1.61 114.15,49.16 113.98,49.33 ; v3(137.73,100.87) 137.7,100.83 UC1.Y11 137.7,99.89 v3(137.86,99.72) 138.49,99.1 UC1.AA13 ; UC1.AA16 138.9,96.57 v3(138.5,96.17) ; UC1.AE14 142.3,97.96 v3(142.87,98.53) ; v3(140.81,37.97) 140.75,38.03 139.93,38.03 139.65,38.31 JDIMM1.138 ; UV1.AA16 67.4,84.14 v3(67.91,84.65) 68.36,85.1 UV1.AB15 ; v3(135.53,98.58) 135.3,98.81 UC1.T13 ; JDIMM1.168 148.65,41.05 149.1,41.51 v3(149.23,41.51) 149.46,41.51 149.85,41.12 JDIMM1.172 ; JDIMM1.133 138.15,49.5 138.49,49.84 ; UV1.R15 62.6,85.1 v3(63.09,84.6) 63.59,84.1 UV1.T16 ; 112.32,49.46 112.35,49.43 JDIMM1.55 ; 144.96,49.97 144.75,49.75 JDIMM1.155 ; v3(156.5,49.2) 156.75,48.95 JDIMM1.195 ; v3(66.81,82.76) 66.4,83.17 UV1.Y17 ; UV1.U15 64.47,85.1 v3(64.87,85.5) 65.4,86.03 UV1.V13 ; v3(137.86,93.75) 137.86,93.26 UC1.Y21 UC1.AA22 ; v3(152.81,42.8) 152.99,42.8 153.45,42.34 JDIMM1.184 153.45,38.36 153.68,38.13 155,38.13 155.25,38.38 JDIMM1.190 ; UV1.N25 61.2,76.9 v3(61.6,76.5) 62,76.9 UV1.P25 ; 150.04,49.84 150.15,49.73 JDIMM1.173 ; UC1.T10 135.3,101.27 v3(135.58,100.99) 135.58,100.82 136.09,100.3 UC1.V11 ; UV1.Y15 66.48,85.1 v3(66.96,85.58) ; JDIMM1.71 117.15,49.58 117.15,49.59 ; UV1.T18 63.6,82.39 64.4,83.19 UV1.U17 64.46,83.3 64.96,82.8 v3(65.05,82.8) 65.4,82.45 UV1.V18 65.93,81.77 UV1.Y20 66.4,81.17 66.77,80.8 66.77,80.8 v3(66.78,80.8) ; 106.99,49.59 106.95,49.54 JDIMM1.37 ; v3(139,90.07) 139,89.6 UC1.AA25 138.9,89.45 v3(138.5,89.05) ; UC1.AE19 142.13,94.47 v3(142.13,94.92) 141.65,94.92 141.3,94.58 UC1.AD19 ; UC1.U4 135.9,106.47 v3(136.24,106.81) ; UV1.T25 63.2,76.9 v3(62.8,77.3) ; UC1.T22 135.3,91.85 134.99,91.55 v3(134.69,91.55) ; JDIMM1.156 145.05,40.91 v3(144.84,41.13) ; 143.57,49.59 143.55,49.57 JDIMM1.151 ; UC1.AD22 UC1.AC21 140.1,93.58 v3(140.27,93.75) ; v3(141.9,88.75) 141.3,89.35 UC1.AD25 ; v3(136.34,93.75) 136.34,93.26 UC1.V21 ; v3(98.55,49.13) 98.35,49.33 97.08,49.33 96.75,49 JDIMM1.3 ; 139.88,49.71 139.95,49.65 JDIMM1.139 ; UC1.J21 129.94,92.66 v3(129.94,92.54) 130.5,91.97 UC1.K22 UC1.L24 131.7,90.65 v3(132.22,90.12) 132.47,90.12 132.9,89.69 UC1.N25 133.1,89.5 v3(133.67,90.07) 134.1,90.5 UC1.P24 134.29,90.7 v3(134.66,90.33) ; UV1.N21 v3(61.11,79.81) ; v3(160.18,2.98) 160.64,2.52 RH93.2 ; v3(129.86,88.93) 130.43,89.5 UC1.K25 ; UC1.AC17 140.1,95.99 v3(140.27,96.17) ; v3(140.4,90.07) 140.4,90.4 UC1.AC24 ; UV1.T21 63.58,80.3 63.06,79.78 v3(62.98,79.78) ; v3(138.5,93.75) 138.9,94.16 UC1.AA19 ; v3(59.06,88.45) 58.8,88.19 UV1.K11 ; 110.55,49.46 110.55,49.46 JDIMM1.49 ; v2(76.19,18.42) 76.33,18.28 PR106.2 ; v3(148.01,42.78) 147.88,42.78 146.85,41.74 JDIMM1.162 ; UV1.N16 61.49,84.1 v3(61.09,84.5) ; UV1.M12 UV1.N13 61.6,86.09 62.12,85.57 v3(62.12,85.48) ; UC1.AC14 139.8,98.2 v3(139.51,98.2) ; U1.4 v3(84.23,94.31) ; v3(137.73,97.31) 137.7,97.35 UC1.Y14 137.7,98.29 v3(137.86,98.45) ; JDIMM1.134 v3(138.45,37.99) ; v3(137.86,96.04) 137.7,95.88 UC1.Y17 137.7,95.06 v3(137.86,94.9) ; JDIMM1.128 v3(136.65,38.09) ; UV1.AA11 67.4,88.36 v3(67.69,88.65) 67.9,88.65 68.16,88.9 UV1.AB10
  BOTTOM w0.457: v3(62.16,102.39) 62.41,102.39 62.79,102.01 62.79,101.99 62.85,101.93 RV151.1
  BOTTOM w0.508: v3(49.53,10.63) PC723.2 49.54,11.3 PC727.2 ; v3(81.03,96.45) 81.24,96.65 CV166.1 ; CV10.2 53.85,108.97 v3(53.56,109.26) ; v3(94.09,28.81) 94.09,28.45 93.85,28.21 93.85,28.02 ; PC535.2 65.03,111.13 v2(64.95,111.05) 64.83,110.93 PC512.2 ; PC106.2 68.81,16.46 69.12,16.77 v2(69.14,16.77) ; CH16.2 RH26.1 v3(140.23,30.94) 140.5,31.21 UH1.3 ; v3(189.85,13.09) 190.39,12.54 CS7.2 ; v3(30.16,15.55) 31.11,14.59 JRTC.4 31.11,12.79 v3(31.78,12.12) ; v3(84.77,7.47) 84.74,7.47 84.61,7.34 PC210.2 82.89,7.34 PR204.2 ; JFAN.4 9.51,67.12 v3(8.69,67.94) ; RH54.2 152.54,4.36 v4(152.71,4.18) 152.92,3.97 v3(152.92,3.22) ; CI1.2 190.55,51.87 v3(192.16,51.87) ; CI1.2 v3(186.75,52.51) ; CI1.2 190.58,53.17 v3(192.13,53.17) ; CI1.2 v3(192.13,52.51) ; v3(133.18,7.98) 133.9,7.98 C10.2 ; PR1038.2 v3(54.08,41) ; v3(169.32,2.19) 169.72,2.58 X1.4 ; JHDD.6 v3(184.71,13.42) ; CV129.2 v3(32.06,67.21) ; v3(137.6,8.51) 137.6,7.97 C5.1 137.69,7.55 C15.2 136.28,8.56 C6.2 ; v3(115.35,13.19) 115.75,12.78 CE14.2 ; v3(36.67,83.42) 36.63,83.39 RV46.2 CV117.2 CV116.2 ; v3(32.19,42.85) PR1102.1 ; RV88.1 v3(78.42,91.24) ; v3(173.87,6.18) 173.46,5.77 CH15.1 173.46,5.06 X1.2 ; v3(181.82,56.67) 181.49,56.34 PR307.2 ; v3(64.19,102.52) 64.45,102.26 RV21.1 ; UL2.2 163,115.63 v3(163.51,116.13) ; JIO.8 v3(26.57,50.95) ; RA1113.1 v3(197.8,12.55) ; CV173.2 v3(33.97,67.29) ; v3(166.99,105.34) 167.24,105.59 CL3.2 ; JEDP.41 7.62,103.13 7.98,103.49 v3(7.98,104.27) ; v3(182.2,13.55) 182.31,13.44 JHDD.3 ; RH121.2 RH122.2 v3(154.41,36.71) ; CV161.2 v3(41.71,103.1) ; v3(72.4,100.13) 72.6,100.33 RV83.2 ; JSPK.6 202,6.93 v3(201.22,6.15) ; HE1.2 14.15,65.54 v3(14.81,65.54) ; PR729.1 51.62,13.97 v3(51.64,13.95) ; PC410.2 v3(108.71,4.28) ; v3(139.68,15.98) C14.2 ; v3(171.02,108.23) 171.43,107.83 CL37.1 ; v3(179.46,18.09) 180.14,18.77 USPI1.4 ; UL3.2 v3(169.09,115.57) ; RV89.1 79.23,96.32 v3(79.08,96.47) ; v3(139.05,14.23) 139.05,13.92 C8.2 ; v3(41.03,83.42) 41.41,83.04 41.41,82.86 CV112.2 CV113.2 ; v3(47.64,9.94) 46.98,9.94 PC725.1 ; CE16.2 127.53,20.29 v3(127.34,20.48) 127.31,20.5 CE17.1 ; v3(66.48,33.13) 66.48,32.24 65.72,31.47 PR1032.1 PR1033.1 ; v3(121.44,13.21) 121.85,12.81 CE15.2 ; RE5.1 104.83,34.8 v3(105.21,35.18) ; v3(93.26,28.74) 93.26,28.6 93.85,28.02 ; PC13.1 PR26.1 127.97,29.14 v3(128.2,29.37) ; PR728.1 v3(50.2,13.08) ; 22.49,41.12 22.29,40.92 v3(20.78,40.92) ; 22.49,41.12 JIO.17 ; 22.49,41.12 21.98,41.63 v3(20.78,41.63) ; v3(39.35,98.81) 39.35,99.27 39.93,99.85 CV135.2 ; v3(198.81,24.39) 199.19,24.77 CA25.1 ; v3(178.9,56.67) 178.75,56.67 177.91,55.83 PR301.1 ; R17.2 114.81,98.86 v3(114.84,98.84) 114.79,98.78 R16.2 ; CH23.2 136.63,20.2 v3(137.06,20.63) ; CL36.1 v3(174.38,106.99) ; R13.2 R14.2 126.17,114.28 126.63,114.74 v3(126.89,114.74) ; v3(110.7,34.9) 110.13,35.48 LE2.1 ; CX28.2 v3(199.14,87.76) ; v3(178.52,9.48) 179.41,10.37 179.41,10.58 JHDD.11 ; v3(189.92,11.87) 190.18,11.61 191.83,11.61 192.27,12.06 CA64.1 ; CV101.2 RV45.2 39.55,83.31 v3(39.44,83.42) ; v3(189.69,15.5) 189.31,15.12 CS5.2 CS6.2 ; CE1.2 v3(111.87,11.66) CE29.2 ; CL38.2 v3(159.44,115.88) ; RH128.2 v3(148.95,36.5) ; v2(61.78,112.96) 61.02,113.72 PC513.1 ; PC858.2 69.16,57.74 v2(69.25,57.83) ; v3(26.59,58.95) JIO.16 ; CE27.2 CE26.2 ; CE26.2 v3(126.83,31.81) ; CE26.2 RE47.2 ; CX30.2 v3(199.83,92) ; RH58.2 157.96,3.63 v3(158.35,3.24) 158.9,3.79 RH92.2 ; RH127.2 v3(147.99,36.51) ; CV19.2 v3(81.72,83.49) ; CI8.2 v3(189.92,38.99) ; CI8.2 188.98,38.71 v3(188.98,39.02) ; CI8.2 190.76,38.62 v3(190.76,39.02) ; CI8.2 v3(187.59,37.77) ; v3(169.88,7.24) 169.88,6.68 169.02,5.82 CH12.1 ; v3(209.1,15.8) 209.48,16.18 DA14.1 ; CV162.2 v3(40.82,103.13) ; JEDP.43 9.41,97.42 v3(9.05,97.06) ; v3(133.69,25.38) 133.81,25.51 133.81,26.45 RH91.1 ; RH90.1 v3(141.06,21.07) ; PR716.2 v3(42.81,8.39) ; CV121.2 v3(35.74,67.29) ; v3(114.86,100.08) 115.07,99.88 R15.2 R31.2 ; v3(80.55,73.82) 80.27,74.1 CV18.2 ; CV120.2 v3(31.17,67.21) ; RV74.1 v3(83.88,97.34) ; PC1104.2 31.73,42.19 v3(32.19,42.19) ; JEDP.46 9.41,80.83 v3(10.1,81.53) ; CV167.1 86.82,88.37 v3(87.38,88.93) ; RL35.1 167.42,103.69 v3(166.91,104.2) ; CE6.1 v3(102.42,15.17) ; RV73.1 82.73,87.94 82.48,87.69 v3(81.69,87.69) 81.72,87.71 CV170.1 ; v3(31.6,9.02) 31.6,8.03 31.11,7.54 JRTC.3 30.56,8.08 v3(30.56,9.05) ; v3(135.82,17.73) C7.2 C9.2 C11.2 ; v2(61.78,111.05) 61.65,110.93 PR529.1 PR528.1 ; CE20.2 v3(171.38,115.19) ; RE46.2 125.38,13.64 v3(125.08,13.34) ; CA21.2 196.78,11.33 v3(197.41,10.7) ; v3(106.53,34.78) 106.53,34.5 CE8.2 ; QE5.4 125.14,10.28 v3(124.63,10.79) ; v3(34.58,48.63) PC1105.2 ; v3(196.17,59.06) 195.69,58.58 CI2.2 195.45,58.11 CI40.2 ; v3(143.82,9.83) 143.82,10.34 143.57,10.6 CH11.1 ; CV127.2 v3(32.95,67.21) ; v3(40.19,83.42) 40.34,83.27 40.34,82.91 CV115.2 ; CV118.2 v3(29.9,66.97) ; CE11.2 v3(102.5,17.84) ; v3(192.08,56.42) JNGFF.69 v3(192.08,60.51) ; YL2.4 174.51,111.48 v3(173.21,112.78) ; v3(122.07,34.87) 122.26,34.87 122.64,34.48 CE5.1 ; CX29.2 v3(199.12,88.62) ; CV114.2 CV111.2 CV110.2 CV109.2 30.49,82.86 v3(29.75,82.86) ; PC408.2 v3(112.25,2.26) PR405.2 ; PR410.2 v3(82.12,28.57) ; v3(81.72,82.22) CV21.2 CV20.2 ; DI5.1 194.27,43.97 v3(194.67,44.38) ; CL5.2 167.01,111.95 CL4.2 v3(167.25,113.3) ; JFAN.3 v3(4.55,73.54) ; CV102.2 39.3,69.54 v3(38.22,70.62) ; CE18.1 v3(127.31,23.55) ; CX27.2 v3(199.12,85.07) ; CX26.2 CX23.2 v3(198.89,81.51) ; RH126.2 v3(145.14,36.51) ; v3(26.78,55.25) 26.08,55.95 JIO.13 ; v3(139.48,27) 139.56,26.93 RH1.2 CH6.1 ; CE4.2 v3(119.69,10.95) ; CV176.2 27.36,87.86 v3(27.06,87.56) ; C12.2 132.77,17.59 Y1.2 131.59,18.43 v3(130.87,19.16) ; JRTC.2 v3(29.44,10.08) ; v2(61.78,114.74) 61.47,115.04 PR500.1 61.47,115.93 PC502.2 ; YV1.4 81.51,76.04 v3(81.08,75.62) 80.7,76 CV17.2 79.94,76.84 RV163.2 ; CV180.2 v3(43.49,103.1) ; RE58.2 129.42,14.76 QE4.3 v3(129.87,13.64) ; RH37.2 167.98,36.04 v3(167.98,36.66) ; v2(79.18,117.28) 79.18,117.75 PC519.2 78.42,117.75 v2(78.42,117.28) ; CV158.2 v3(42.6,103.13) ; Y1.4 133.8,20.03 v3(133.03,20.81) ; 93.85,28.02 PC413.2 ; JIO.18 22.32,61.95 v3(20.88,61.95) ; PC307.2 181.86,50.18 v3(181.96,50.28) ; CE10.2 v3(118.8,10.98) ; v3(212.53,8.64) 211.94,8.64 JSPK.5 211.45,9.14 211.82,9.5 v3(212.55,9.5) ; RH123.2 v3(153.45,36.74) ; CX25.2 v3(199.17,77.96) ; v3(39.5,66.98) 40.19,67.67 CV122.2 CV107.2 ; v3(191.14,9.25) 189.82,10.57 JHDD.12 ; v3(4.25,75.38) JEDP.42 ; CL19.2 v3(175.7,109.28) ; CX24.2 v3(199.12,84.21) ; R22.2 154.45,100.87 v3(155.11,100.87) ; JNGFF.68 v3(170.26,58.6) ; 159.44,120.2 158.86,120.2 ; v3(9.73,84.1) 9.73,85.17 9.41,85.5 JEDP.45 ; RH129.2 165.65,2.58 v3(166.1,2.14) ; PC404.2 v3(108.46,6.23) ; DE2.1 v3(171.84,119.56) ; CL39.2 160.71,116.08 v3(160.51,115.88) 160.71,115.68 RL27.1 ; PC202.2 v3(79.43,10.6) ; JIO.9 v3(26.57,51.95) ; CA22.2 199.35,11.99 v3(199.75,12.4) ; DA13.1 v3(204.4,15.8) ; RE45.2 129.42,20.02 v3(129.06,19.66) ; PC203.2 v3(79.3,8.82) ; CE3.2 CE2.2 127.21,17.71 v3(127.44,17.94) ; JIO.10 v3(26.6,52.95) ; PR304.2 v3(182.3,52.81) ; v3(53.17,40.06) 53.17,39.5 53.23,39.44 PC1034.2 ; JEDP.44 v3(9.41,91.49) ; YV1.2 83.8,74.14 v3(84.61,74.96) ; JFAN.5 v3(2.95,67.12) ; RH124.2 v3(151.55,36.74) ; CV169.1 v3(87.37,92.07) ; RH125.2 v3(152.5,36.73) ; CE24.2 v3(13.39,67.62) ; CV108.2 28.68,81.92 28.63,81.97 28.63,82.35 v3(28.66,82.38) ; CV131.2 v3(34.85,67.29) ; v3(170.67,110.49) 171.29,109.87 YL2.2
  BOTTOM w0.762: DA10.1 197.75,28.25 198.48,28.99 198.48,30.89 DA12.1 197.82,32.19 198.46,32.82 198.46,34.55 197.26,35.74 v3(196.68,35.74)
  vias: v2(0.51,102.96) v2(0.51,95.45) v2(0.51,87.84) v2(0.51,80.06) v2(0.51,72.55) v2(0.51,65.08) v2(0.51,57.2) v2(0.51,49.61) v2(4.78,46.23) v2(9.52,107.28) v2(10.5,46) v2(10.91,118.81) v2(10.91,115) v2(10.91,111.19) v2(12.33,10.8) v2(12.83,41.33) v2(12.83,33.91) v2(13.01,115.37) v2(13.01,114.74) v2(13.26,116.77) v2(13.26,116.13) v2(13.65,115.37) v2(13.65,114.74) v2(13.8,6.02) v2(13.88,122.29) v2(13.9,116.77) v2(13.9,116.13) v2(14.53,116.77) v2(14.53,116.13) v2(15.17,116.13) v2(15.68,13.77) v2(15.68,13.01) v2(15.68,12.25) v2(15.68,11.36) v2(15.68,10.6) v2(15.93,115.37) v2(16.44,14.53) v2(16.44,13.77) v2(16.44,13.01) v2(16.44,12.25) v2(16.44,11.36) v2(16.44,10.6) v2(16.82,115.24) v2(17.2,14.53) v2(17.2,13.77) v2(17.2,13.01) v2(17.69,122.29) v2(17.96,14.53) v2(17.96,13.77) v2(18.09,116.01) v2(18.09,115.37) v2(18.09,114.74) v2(18.73,14.53) v2(21.5,122.29) v2(25.31,122.29) v2(26.03,107.28) v2(26.02,106.63) v2(26.7,106.62) v2(26.75,107.28) v2(27.4,107.28) v2(27.39,106.63) v2(28.1,107.28) v2(28.09,106.61) v2(28.76,109.4) v2(28.76,108.77) v2(28.76,108.13) v2(28.76,107.5) v2(29.01,6.01) v2(29.12,122.29) v2(31.4,47.17) v2(31.43,45.65) v2(31.93,46.41) v2(32.31,47.17) v2(32.31,45.65) v2(32.93,122.29) v2(34.09,28.38) v2(34.09,27.74) v2(34.09,26.98) v2(34.85,28.38) v2(34.85,27.74) v2(34.85,26.98) v2(35.74,28.38) v2(35.74,27.74) v2(36.8,120.29) v2(36.76,6.01) v2(40.61,120.29) v2(41.33,46.92) v2(42.22,47.43) v2(42.22,46.28) v2(42.22,45.27) v2(42.22,44.25) v2(42.58,43.3) v2(42.56,42.64) v2(42.58,42) v2(42.98,13.39) v2(43.36,15.04) v2(43.94,14.33) v2(44.42,120.29) v2(44.38,6.01) v2(44.89,15.04) v2(44.89,13.39) v2(48.23,120.29) v2(52.04,120.29) v2(55.38,11.51) v2(55.82,122.29) v2(57.33,47.72) v2(57.98,48.37) v2(58.01,47.72) v2(58.45,58.98) v2(58.45,55.55) v2(58.54,51.02) v2(58.71,52.47) v2(58.67,48.39) v2(58.68,47.74) v2(58.87,51.83) v2(59.02,47.2) v2(59.09,55.55) v2(59.16,58.98) v2(59.32,52.9) v2(59.34,47.77) v2(59.35,52.26) v2(59.37,51.43) v2(59.37,50.79) v2(59.37,50.14) v2(59.35,48.4) v2(59.63,122.29) v2(59.75,55.55) v2(59.87,58.96) v2(59.87,58.22) v2(59.87,57.33) v2(59.87,56.32) v2(60.43,55.53) v2(60.56,58.98) v2(60.64,58.22) v2(60.64,57.33) v2(60.64,56.32) v2(60.89,52.54) v2(60.92,51.69) v2(60.89,50.78) v2(60.9,50.11) v2(60.92,49.46) v2(61.02,54.82) v2(61.04,54.16) v2(60.98,48.07) v2(61.07,55.5) v2(61.08,53.51) v2(61.27,58.98) v2(61.28,48.75) v2(61.52,51.15) v2(61.5,49.88) v2(61.59,53.12) v2(61.55,52.48) v2(61.59,51.78) v2(61.7,55.5) v2(61.7,54.84) v2(61.7,54.17) v2(63.31,6.01) v2(63.44,122.29) v2(63.43,114.74) v2(63.35,112.96) v2(63.43,111.05) v2(64.45,18.09) v2(64.45,17.33) v2(64.95,114.74) v2(64.95,112.96) v2(65,20.58) v2(65.08,18.09) v2(65.08,17.33) v2(65.61,19.84) v2(65.69,20.55) v2(65.7,19.17) v2(65.7,18.47) v2(65.72,17.33) v2(66.33,19.84) v2(66.34,19.17) v2(66.34,18.47) v2(66.3,16.51) v2(66.35,21.14) v2(66.35,20.5) v2(66.36,17.84) v2(66.36,17.17) v2(66.99,21.14) v2(66.99,20.5) v2(66.96,19.87) v2(66.99,19.16) v2(67.01,18.47) v2(67.01,17.84) v2(67,17.17) v2(66.99,16.49) v2(67.25,122.29) v2(69.18,56.35) v2(69.4,23.14) v2(69.42,22.48) v2(69.68,11.49) v2(69.93,57.95) v2(69.88,56.53) v2(69.98,57.28) v2(70.36,11.51) v2(71,11.51) v2(71.06,122.29) v2(71.66,11.51) v2(71.81,23.68) v2(71.98,18.44) v2(71.98,17.8) v2(72.17,12.09) v2(72.45,23.68) v2(72.61,18.44) v2(72.61,17.8) v2(73.23,54.87) v2(73.34,53.9) v2(73.83,118.86) v2(73.84,54.41) v2(74.1,118.24) v2(74.47,118.86) v2(74.48,53.9) v2(74.63,54.82) v2(74.62,6.01) v2(74.87,122.29) v2(74.99,109.28) v2(74.99,108.21) v2(74.99,107.17) v2(74.99,106.1) v2(75.33,104.25) v2(75.33,103.61) v2(75.33,102.98) v2(75.37,108.74) v2(75.37,107.7) v2(75.37,106.64) v2(75.37,105.6) v2(75.6,54.13) v2(75.75,109.28) v2(75.75,108.21) v2(75.75,107.17) v2(75.75,106.1) v2(75.96,104.25) v2(75.96,103.61) v2(75.96,102.98) v2(76.13,108.74) v2(76.13,107.7) v2(76.13,106.64) v2(76.13,105.6) v2(76.51,109.28) v2(76.51,108.21) v2(76.51,107.17) v2(76.51,106.1) v2(76.6,104.25) v2(76.6,103.61) v2(76.6,102.98) v2(76.89,108.74) v2(76.88,107.69) v2(76.89,106.64) v2(76.89,105.57) v2(77.25,108.21) v2(77.23,104.25) v2(77.23,103.61) v2(77.23,102.98) v2(77.27,109.28) v2(77.25,107.16) v2(77.25,106.1) v2(77.61,108.74) v2(77.63,107.67) v2(77.61,106.63) v2(77.61,105.58) v2(77.87,104.25) v2(77.87,103.61) v2(77.87,102.98) v2(77.97,109.28) v2(77.98,108.21) v2(77.99,107.15) v2(77.97,106.1) v2(78.68,122.29) v2(81.34,14.66) v2(81.97,14.66) v2(82.1,18.22) v2(82.24,6.01) v2(82.49,122.29) v2(82.48,19.49) v2(82.48,18.85) v2(82.61,119.71) v2(82.61,118.65) v2(82.61,117.61) v2(82.61,116.54) v2(82.73,18.22) v2(82.99,119.18) v2(82.99,118.14) v2(82.99,117.08) v2(82.99,116.04) v2(83.11,19.49) v2(83.11,18.85) v2(83.37,119.71) v2(83.37,118.65) v2(83.37,117.61) v2(83.37,116.54) v2(83.37,18.22) v2(83.47,11.76) v2(83.5,10.72) v2(83.75,119.18) v2(83.75,118.14) v2(83.75,114.99) v2(83.75,117.08) v2(83.75,116.04) v2(83.88,19.49) v2(83.88,18.85) v2(84.13,119.71) v2(84.13,118.65) v2(84.13,117.61) v2(84.13,116.54) v2(84.38,114.99) v2(84.38,114.36) v2(84.38,113.72) v2(84.38,113.09) v2(84.38,112.45) v2(84.38,20.88) v2(84.38,20.12) v2(84.51,119.18) v2(84.5,118.13) v2(84.51,117.08) v2(84.51,116.01) v2(84.54,11.76) v2(84.54,10.7) v2(84.64,19.49) v2(84.64,18.85) v2(84.89,119.71) v2(84.87,118.65) v2(84.87,117.6) v2(84.87,116.54) v2(85.02,114.36) v2(85.02,113.72) v2(85.02,113.09) v2(85.02,112.45) v2(85.02,20.76) v2(85.02,20.12) v2(85.23,119.18) v2(85.23,117.07) v2(85.23,116.02) v2(85.25,118.11) v2(85.4,19.49) v2(85.4,18.85) v2(85.59,119.71) v2(85.6,118.65) v2(85.61,117.59) v2(85.59,116.54) v2(85.65,114.36) v2(85.65,113.72) v2(85.65,113.09) v2(85.65,112.45) v2(86.16,19.49) v2(86.16,18.85) v2(86.3,122.29) v2(86.37,8.39) v2(86.37,7.75) v2(86.92,19.49) v2(86.92,18.85) v2(88.32,8.56) v2(89.08,8.56) v2(89.86,6.01) v2(90.11,122.29) v2(93.78,13.14) v2(93.78,12.37) v2(93.92,122.29) v2(94.54,13.9) v2(94.54,13.14) v2(94.54,12.37) v2(95.31,13.9) v2(95.31,13.14) v2(95.31,12.37) v2(96.75,5.69) v2(97.73,122.29) v2(101.54,122.29) v2(105.14,0.51) v2(105.35,122.29) v2(106.61,116.26) v2(106.61,115.63) v2(107.24,116.26) v2(107.24,115.63) v2(107.88,116.26) v2(107.88,115.63) v2(109.16,121.29) v2(112.78,6.51) v2(112.78,5.87) v2(112.78,5.24) v2(112.76,4.6) v2(112.76,0.51) v2(112.97,121.29) v2(113.65,6.51) v2(113.65,5.87) v2(113.65,5.24) v2(113.65,4.6) v2(116.78,121.29) v2(120.38,0.51) v2(120.59,121.29) v2(120.78,2.01) v2(121.39,7.7) v2(121.44,2.01) v2(122.05,7.7) v2(122.1,2.01) v2(122.74,7.7) v2(122.79,2.01) v2(124.4,120.29) v2(128,0.51) v2(128.21,120.29) v2(132.02,120.29) v2(135.62,0.51) v2(135.83,120.29) v2(139.64,120.29) v2(143.24,0.51) v2(143.5,122.19) v2(147.24,122.29) v2(150.86,0.51) v2(151.05,122.29) v2(154.86,122.29) v2(158.48,0.51) v2(158.67,122.29) v2(162.48,122.29) v2(166.1,0.51) v2(166.42,119.29) v2(168.46,122.25) v2(170.09,122.29) v2(172.01,46.03) v2(172.7,46.03) v2(173.36,46.03) v2(173.64,0.51) v2(173.9,122.29) v2(177.27,122) v2(177.73,118.8) v2(177.93,115.09) v2(178.31,3.61) v2(178.62,53.14) v2(178.62,52.23) v2(179.49,52.68) v2(180.27,53.14) v2(180.27,52.23) v2(180.65,46.92) v2(180.65,46.28) v2(181.29,46.92) v2(181.29,46.28) v2(181.54,113.97) v2(181.92,46.92) v2(181.92,46.28) v2(182.61,0.51) v2(185.35,113.97) v2(187.41,0.74) v2(189.16,113.97) v2(190.89,0.54) v2(192.97,113.97) v2(196.75,115) v2(198.51,122.15) v2(200.38,113.77) v2(200.84,56.06) v2(200.97,122.23) v2(201.48,74.6) v2(202.24,112.65) v2(202.17,98.66) v2(202.49,76.38) v2(203.54,115.3) v2(203.51,74.86) v2(203.51,56.06) v2(204.15,121.29) v2(204.18,0.51) v2(204.27,39.3) v2(204.53,76.94) v2(205.52,95.89) v2(205.55,93.47) v2(205.64,57.97) v2(205.61,39.67) v2(205.92,56.19) v2(206.06,54.31) v2(206.21,72.51) v2(206.79,118.75) v2(206.81,39.3) v2(207.83,56.06) v2(207.88,116.72) v2(208.72,93.46) v2(209.04,76.93) v2(209.1,74.99) v2(209.21,98.03) v2(209.45,113.11) v2(210.5,56.19) v2(210.66,114.86) v2(211.26,54.54) v2(211.38,57.84) v2(211.5,39.58) v2(211.59,74.09) v2(211.75,98.01) v2(211.75,93.82) v2(211.84,0.55) v2(211.87,95.86) v2(213.67,76.76) v2(213.89,20.5) v2(213.89,15.91) v2(213.89,11.56) v2(213.89,8.23) v2(213.89,3.86) v3(2.88,99.62) v3(3.84,97.95) v3(3.87,93.65) v3(5.47,102.93) v3(7.55,81.69) v3(10.6,64.44) v3(11.49,89.82) v3(19.95,10.91) v3(19.92,8.78) v3(20.25,93.25) v3(20.38,90.81) v3(21.01,17.58) v3(21.65,17.58) v3(21.75,11.93) v3(21.75,7.61) v3(22.03,89.95) v3(22.08,94.26) v3(22.28,17.58) v3(22.92,17.58) v3(23.68,17.58) v3(23.71,10.86) v3(23.71,8.73) v3(23.91,93.17) v3(23.88,90.94) v3(25.56,81.08) v3(25.56,80.45) v3(25.95,119.91) v3(25.92,117.78) v3(26.47,17.58) v3(26.85,102.72) v3(27.08,86.59) v3(27.23,17.58) v3(27.51,102.85) v3(27.75,120.93) v3(27.75,116.61) v3(27.87,17.58) v3(28.81,87.2) v3(29.24,51.31) v3(29.71,119.86) v3(29.71,117.73) v3(30.21,103.13) v3(30.82,103.1) v3(30.84,86.06) v3(31.43,103.08) v3(32.09,103.05) v3(32.8,103.05) v3(32.9,87.1) v3(32.87,54.46) v3(33.02,85.72) v3(33.53,103.05) v3(33.92,87.15) v3(34.19,83.24) v3(36.07,87.11) v3(37.65,51.41) v3(37.67,100.13) v3(38.23,51.41) v3(38.44,94.72) v3(38.56,74.88) v3(38.66,95.66) v3(38.84,87.08) v3(38.77,75.49) v3(39.15,74.86) v3(39.5,94.7) v3(39.55,61.78) v3(39.55,59.36) v3(40.01,51.44) v3(41.59,58.09) v3(41.71,62.92) v3(43.74,58.98) v3(43.82,8.39) v3(44,61.52) v3(50.78,93.27) v3(51.31,90.43) v3(51.39,76.79) v3(53.23,62.17) v3(53.83,62.17) v3(59.37,66.35) v3(60,66.35) v3(60.13,38.03) v3(60.13,37.14) v3(60.64,66.35) v3(61.14,38.03) v3(61.14,37.14) v3(61.27,66.35) v3(62.03,38.03) v3(62.03,37.14) v3(62.92,38.03) v3(62.92,37.14) v3(64.19,69.52) v3(64.19,68.91) v3(64.19,67.24) v3(64.19,66.6) v3(65.54,70.21) v3(67.31,69.88) v3(68.75,68.98) v3(69.13,69.44) v3(69.5,68.94) v3(69.94,60.55) v3(69.97,61.78) v3(69.96,61.15) v3(70.74,70.47) v3(71.14,66.06) v3(71.2,67.64) v3(71.79,67.64) v3(72.38,70.35) v3(72.6,32.69) v3(74.07,32.69) v3(74.38,67.75) v3(74.76,68.2) v3(75.37,118.55) v3(75.88,118.93) v3(76,118.29) v3(76.23,69.57) v3(76.69,67.06) v3(76.69,66.45) v3(76.79,71.1) v3(77.22,66.78) v3(77.43,65.03) v3(77.48,62.87) v3(77.96,53.98) v3(80.88,66.22) v3(80.88,65.05) v3(80.95,58.91) v3(80.92,56.78) v3(81.72,70.24) v3(82.75,59.93) v3(82.75,55.61) v3(84,66.2) v3(84.26,108.01) v3(84.26,105.59) v3(84.54,68.56) v3(84.49,13.92) v3(84.71,58.86) v3(84.71,56.73) v3(84.77,62.69) v3(84.97,14.66) v3(85.32,67.8) v3(85.53,65.03) v3(86.29,109.15) v3(86.29,104.32) v3(86.54,26.98) v3(86.54,26.37) v3(87.79,69.19) v3(88.45,108.01) v3(88.45,105.72) v3(88.45,30.1) v3(88.55,70.46) v3(94.37,52.91) v3(95.33,65.69) v3(95.33,64.16) v3(96.88,44.84) v3(97.62,44.63) v3(98.46,42.83) v3(99.15,4.61) v3(99.12,2.48) v3(100.95,5.63) v3(100.95,1.31) v3(102.19,43.77) v3(102.91,4.56) v3(102.91,2.43) v3(104.65,45.47) v3(105.95,96.75) v3(107.63,99.78) v3(107.6,99.17) v3(107.63,96.65) v3(107.65,105.45) v3(107.65,100.39) v3(108.29,105.45) v3(108.82,44.35) v3(108.92,105.47) v3(109.91,118.29) v3(110.55,118.29) v3(110.83,44.3) v3(111.18,118.29) v3(114.18,42.8) v3(115.65,117.3) v3(116.57,115.09) v3(116.57,114.48) v3(116.57,113.9) v3(118.01,117.58) v3(120.33,115.24) v3(120.99,116.92) v3(123.02,116.34) v3(126.83,73.33) v3(126.75,72.29) v3(126.75,71.66) v3(127.21,76.66) v3(127.16,75.39) v3(127.18,74.53) v3(127.39,116.12) v3(127.49,114.99) v3(129.72,4.2) v3(130.82,116.59) v3(133.89,116.84) v3(135.22,104.25) v3(136.66,114.53) v3(137.01,116.82) v3(137.55,41.53) v3(137.6,42.7) v3(138,116.87) v3(138.28,45.06) v3(139.63,42.9) v3(140.12,19.43) v3(140.44,24.64) v3(140.54,16.74) v3(140.75,19.43) v3(140.87,24.24) v3(141.05,116.92) v3(141.26,42.3) v3(141.81,45.17) v3(143.52,44.4) v3(143.72,8.06) v3(144.63,112.65) v3(144.81,45.04) v3(144.99,43.46) v3(145.47,8.56) v3(146.21,113.31) v3(146.23,41.48) v3(147.78,45.06) v3(148.04,41.48) v3(148.6,114.53) v3(148.75,49.71) v3(149.33,116.03) v3(150.86,43.29) v3(151.59,97.31) v3(151.95,102.29) v3(152.33,109.53) v3(152.61,114.56) v3(152.74,45.09) v3(152.74,43.92) v3(152.81,41.51) v3(152.79,13.95) v3(153.36,97.56) v3(153.99,97.56) v3(154.34,56.7) v3(154.64,107.62) v3(154.63,97.56) v3(154.72,115.78) v3(154.67,105.8) v3(154.9,115.14) v3(154.9,114.53) v3(155,112.73) v3(155.26,97.56) v3(155.35,43.34) v3(155.94,97.54) v3(156.34,44.76) v3(156.55,92.87) v3(156.98,119.1) v3(157.03,92.38) v3(157,43.39) v3(157.71,92.92) v3(157.77,119.13) v3(158.2,92.43) v3(158.43,44.73) v3(158.53,119.1) v3(160.03,91.62) v3(160.9,91.62) v3(161.07,52.51) v3(161.55,52.91) v3(163.67,99.42) v3(163.95,70.91) v3(163.92,68.78) v3(164.3,99.42) v3(164.62,103.59) v3(164.9,99.39) v3(165.75,71.93) v3(165.75,67.61) v3(166.25,39.68) v3(166.55,103.03) v3(167.32,101.02) v3(167.33,99.22) v3(167.74,98.76) v3(167.71,70.86) v3(167.71,68.73) v3(167.68,28.12) v3(168.18,98.38) v3(168.99,38.99) v3(170.14,27.75) v3(170.17,28.37) v3(170.92,22.53) v3(171.02,36.81) v3(171.3,15.23) v3(171.51,22.53) v3(171.93,15.23) v3(172.52,104.32) v3(172.52,103.56) v3(172.52,102.67) v3(172.5,38.38) v3(172.57,55.73) v3(172.95,100.11) v3(173.28,104.32) v3(173.28,103.56) v3(173.28,102.67) v3(173.77,37.93) v3(174.36,104.32) v3(174.36,103.56) v3(174.36,102.67) v3(174.4,13.42) v3(174.73,9.15) v3(175.14,14.28) v3(175.67,17) v3(176.13,98.02) v3(178.75,13.39) v3(179.63,90.23) v3(179.76,92.64) v3(180.68,17.19) v3(180.7,15.78) v3(181.15,33.21) v3(181.12,31.08) v3(181.64,17.17) v3(181.67,88.96) v3(181.79,93.65) v3(181.92,62.06) v3(182.95,34.23) v3(182.95,29.91) v3(183.18,13.54) v3(183.83,90.23) v3(183.81,2.97) v3(183.9,92.54) v3(184.77,55.58) v3(184.91,33.16) v3(184.91,31.03) v3(185.6,44.35) v3(185.71,48.92) v3(186.49,43.49) v3(186.87,13.62) v3(187.46,16.39) v3(192.92,80.09) v3(193,81.84) v3(193.12,87.23) v3(193.15,5.11) v3(193.12,2.98) v3(193.2,88.98) v3(193.25,43.9) v3(193.65,97.51) v3(193.62,95.38) v3(193.68,57.15) v3(193.78,63.45) v3(195,20.38) v3(195,19.49) v3(195,18.6) v3(194.95,6.13) v3(194.95,1.81) v3(195.45,98.53) v3(195.45,94.21) v3(195.74,71.71) v3(195.84,87.2) v3(195.87,88.93) v3(195.87,81.84) v3(195.92,80.09) v3(196.14,20.38) v3(196.14,19.49) v3(196.14,18.6) v3(196.55,119.91) v3(196.52,117.78) v3(196.91,5.06) v3(196.91,2.93) v3(197.14,19.64) v3(197.16,20.38) v3(197.41,97.46) v3(197.41,95.33) v3(197.85,69.47) v3(198.35,120.93) v3(198.35,116.61) v3(199.9,75.49) v3(200.31,119.86) v3(200.31,117.73) v3(204.37,12.88) v3(204.63,9.76) v3(205.52,12.88) v3(206.69,12.86) v3(207.07,8.95) v3(207.07,8.31) v3(207.07,7.68) v4(12.66,115.93) v4(19.55,15.17) v4(27.43,103.81) v4(31.32,103.66) v4(36.05,103.69) v4(42.41,13.83) v4(58.4,58.18) v4(60.15,48.95) v4(81.71,21.09) v4(87.56,19.93) v4(165.92,99.56)
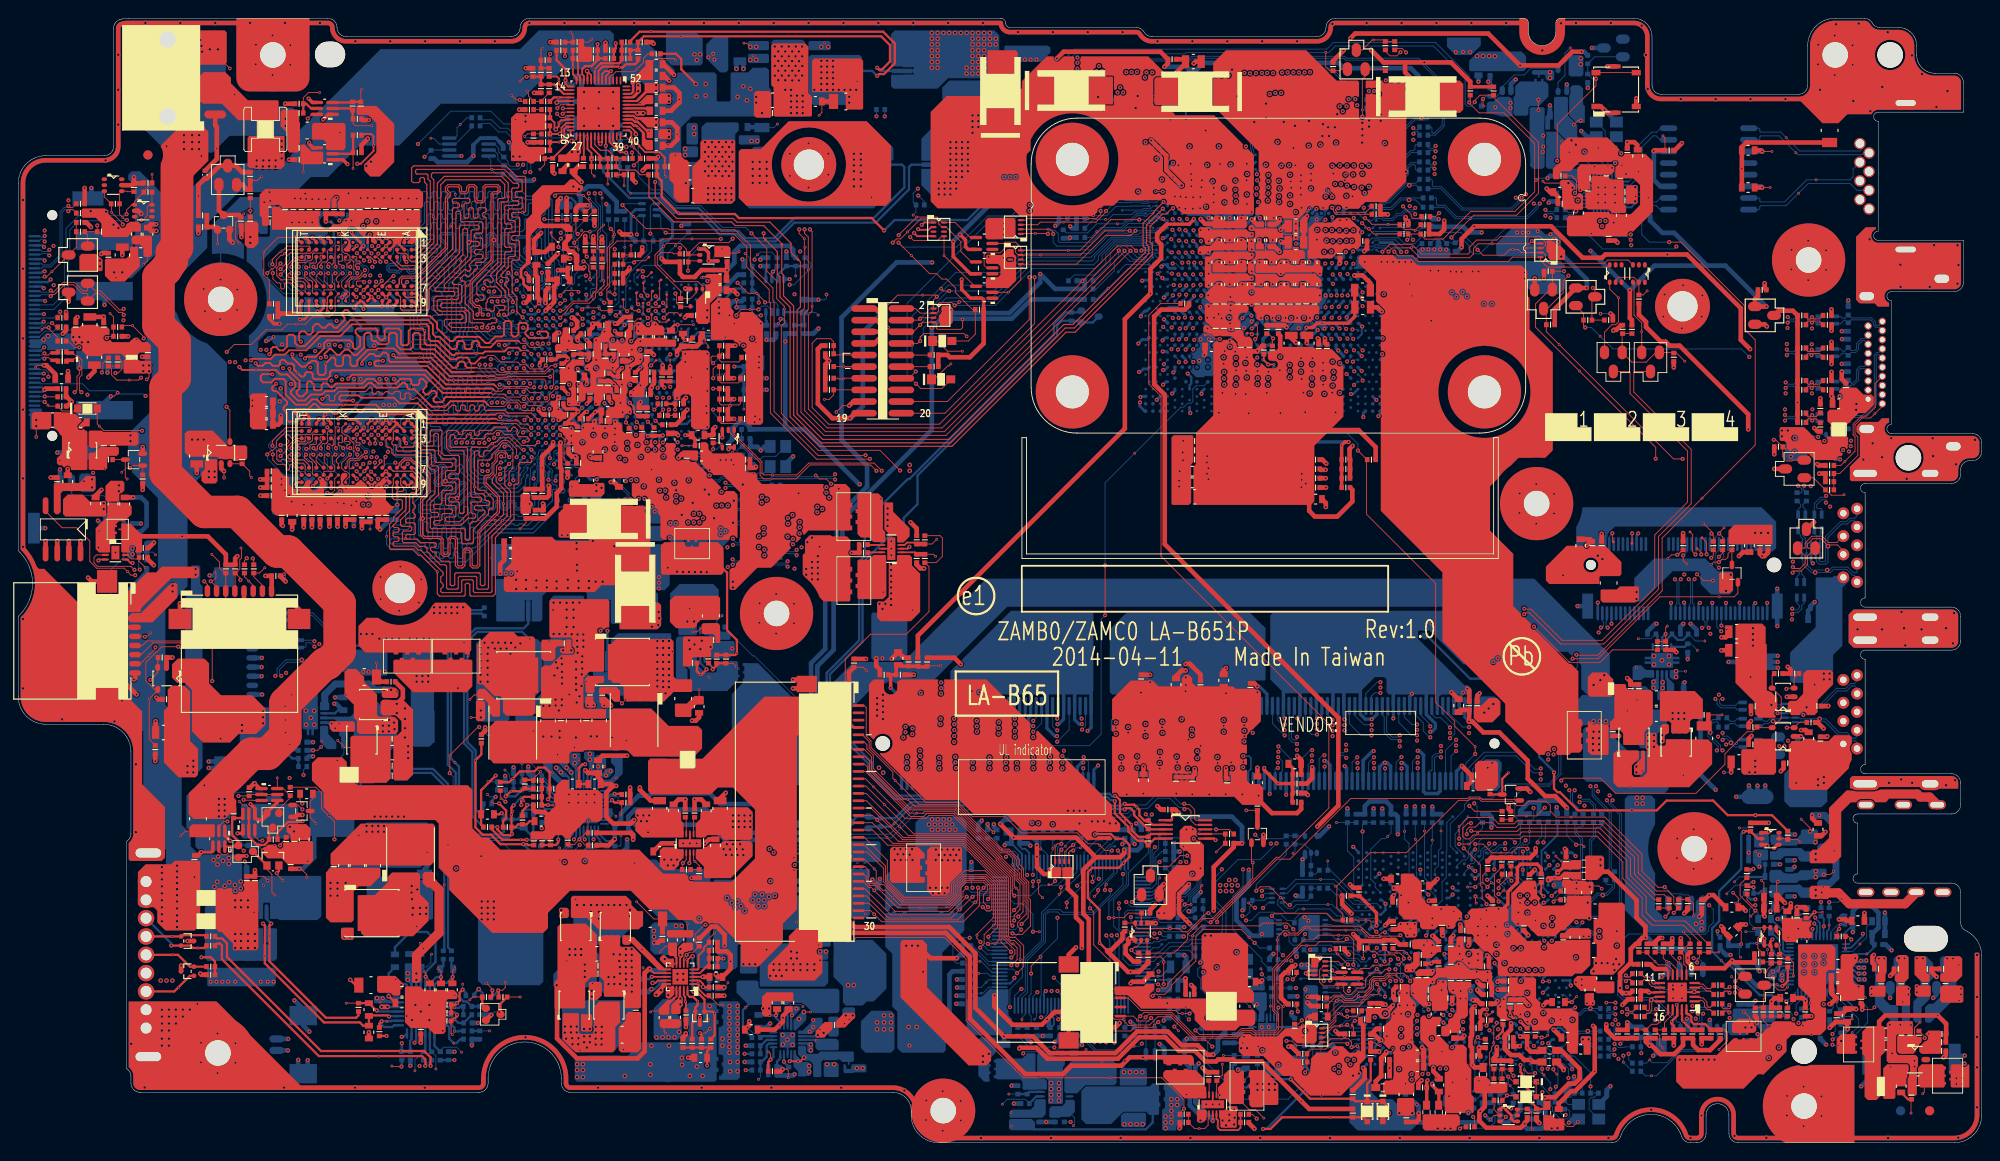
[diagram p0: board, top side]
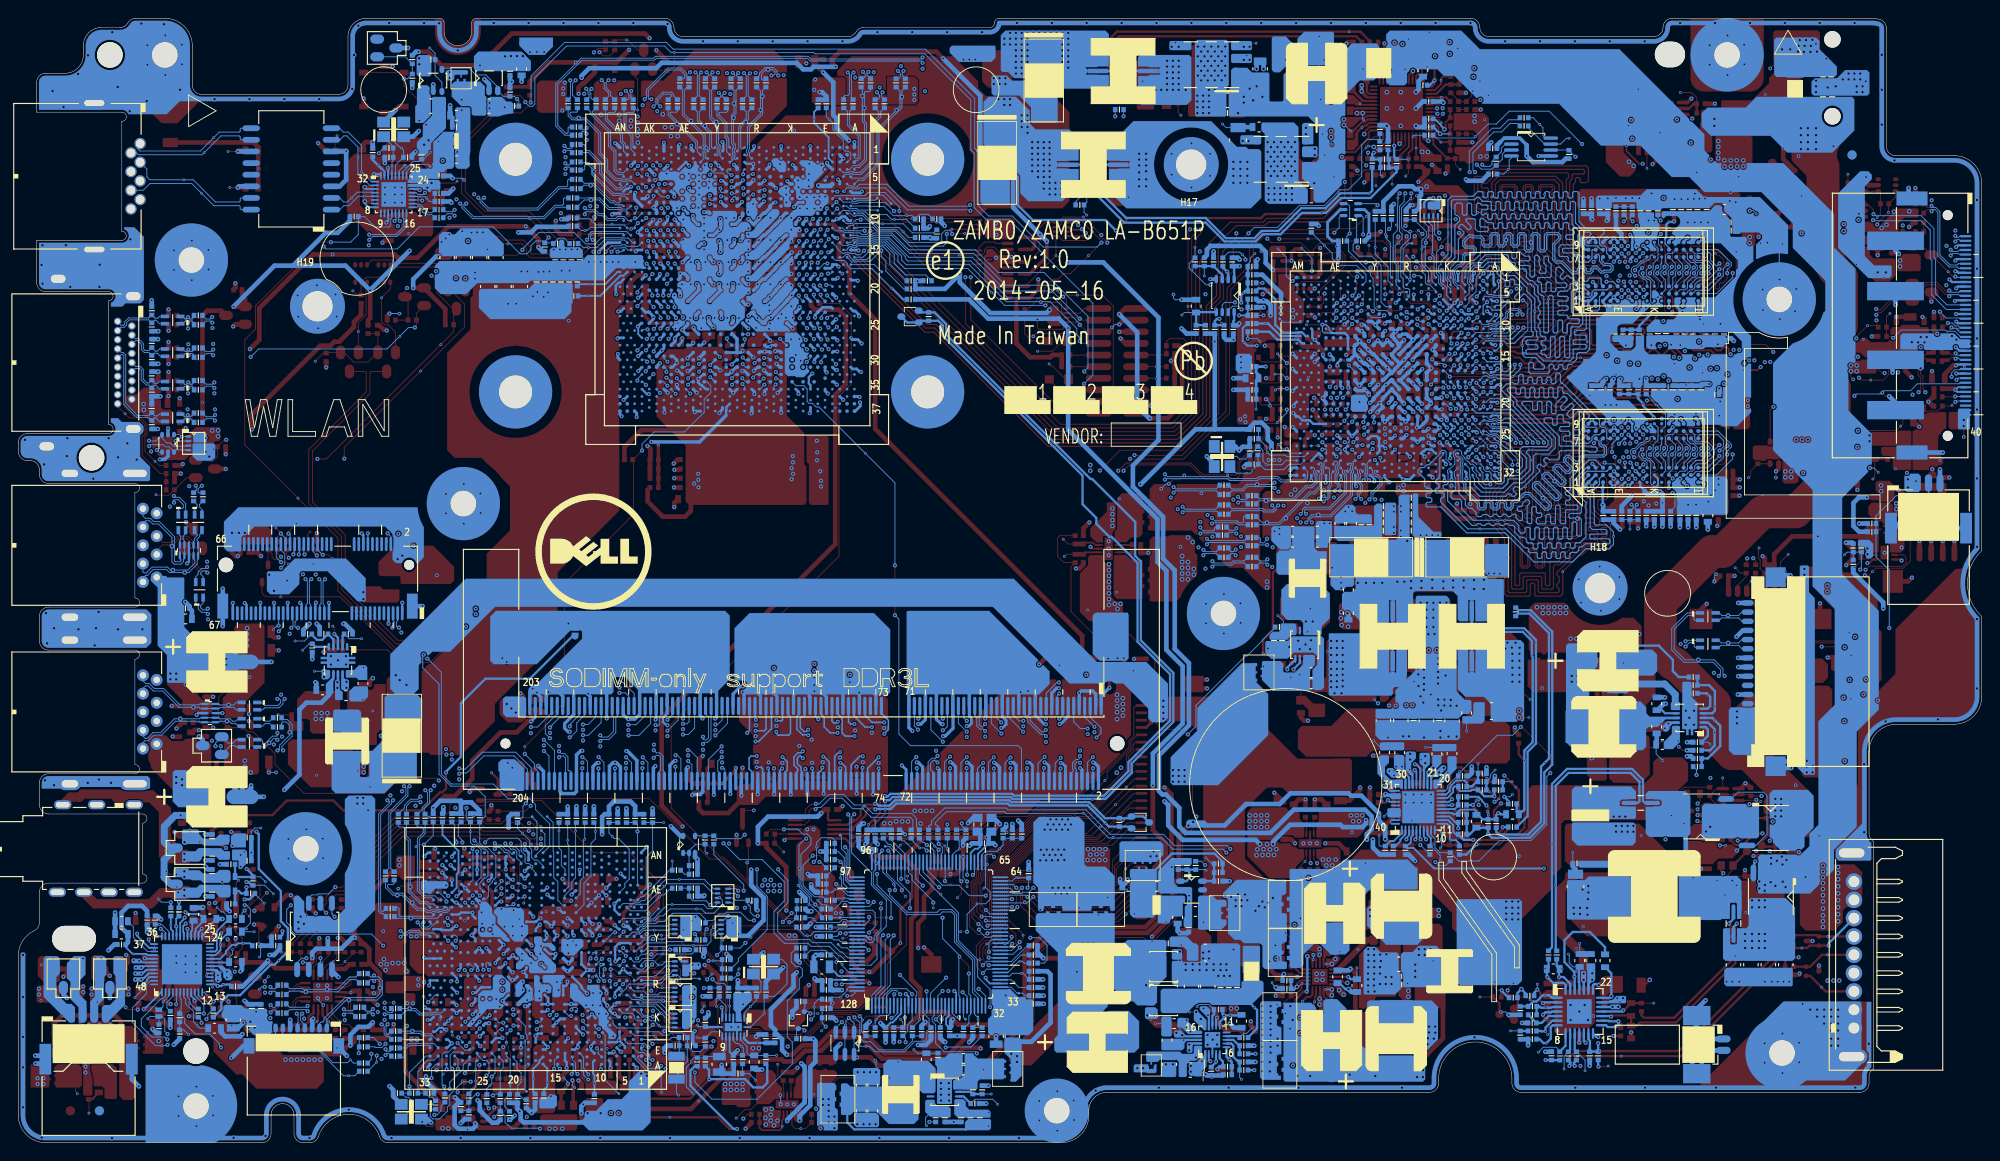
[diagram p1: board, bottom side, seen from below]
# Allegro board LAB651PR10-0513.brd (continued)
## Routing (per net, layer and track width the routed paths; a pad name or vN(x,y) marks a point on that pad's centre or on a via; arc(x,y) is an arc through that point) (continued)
GNDA: length 61.8
  TOP w0.102: RA32.1 188.14,23.14 v4(188.14,21.7) ; v4(192.14,28.5) 192.02,28.38 CA1.2 ; RA30.1 187.83,26.73 v4(187.25,27.3)
  TOP w0.381: v3(192.26,22.86) 191.97,23.15 QA5.4 ; v3(191.73,32.19) 192.09,32.55 QA6.4 ; QA6.1 191.05,33.85 v3(191.16,33.95) ; QA5.1 v3(190.67,22.28)
  TOP w0.508: CA71.2 193.17,25.28 193.55,25.66 v3(193.55,26.14) ; RA32.1 188.04,23.83 v3(188.65,23.83) ; RA31.1 v3(201.59,25.09) ; RA30.1 188.25,25.71 v3(188.63,25.33) ; RA29.1 196.92,33.52 v3(197.34,33.94) ; RA12.1 195.23,25.59 195.09,25.73 v3(194.22,25.73) CA51.2 ; CA2.2 CA1.2 192.26,26.85 v3(192.92,26.19)
  GND1 w0.203: 204.49,26.69 JHP.6 ; JHP.6 203.36,26.69 ; JHP.6 205.63,27.36 ; JHP.6 203.36,27.36 ; JHP.6 205.63,26.69 ; 204.71,37.58 JHP.7 ; JHP.7 206.98,37.58 ; JHP.7 206.98,36.91 ; JHP.7 205.84,37.58 ; JHP.7 204.71,36.91
  VCC w0.203: 204.71,37.58 JHP.7 ; JHP.7 206.98,37.58 ; JHP.7 205.84,37.58 ; JHP.6 205.63,26.69 ; JHP.6 204.49,26.69 ; JHP.6 203.36,26.69
  GND2 w0.203: JHP.7 205.84,37.58 ; JHP.7 206.98,37.58 ; JHP.7 204.71,37.58 ; JHP.7 206.98,36.91 ; JHP.7 204.71,36.91 ; 203.36,27.36 JHP.6 ; JHP.6 204.49,26.69 ; JHP.6 205.63,27.36 ; JHP.6 203.36,26.69 ; JHP.6 205.63,26.69
  BOTTOM w0.203: UA1.38 200.12,21.29 201.43,22.6 v3(201.43,22.81) ; CA62.1 193.35,23.87 193.35,23.51 UA1.25
  BOTTOM w0.508: RA83.2 v3(192.39,30.41) ; v3(190.15,18.72) 189.99,18.89 CA74.2 ; CA33.2 v3(193.99,26.9) ; RA84.2 191.65,25.61 v3(191.32,25.28) ; CA39.2 193.68,29.85 v3(193.96,30.13) ; v3(194.22,25.73) 194.3,25.65 CA23.1 ; CA62.1 v3(192.11,24.44) ; CA40.2 v3(193.99,30.84) ; v3(203.83,25.14) CA63.1 CA61.2 ; CA38.2 v3(194.01,33.66)
PVCC: length 3.1
  TOP w0.102: v1(71.79,118.24) 71.62,118.41 69.55,118.41 68.95,117.81
V1: length 45.9
  TOP w0.102: PQ708.2 24.04,32.46 v3(24.62,31.88) ; v1(51.14,17.4) 51.77,16.77 v3(51.77,16.64)
  TOP w0.254: v3(51.77,16.64) 51.77,16.11 PR714.2 ; PQ709.6 24.53,35.67 24.31,35.46 PR702.2 23.35,35.29 23.35,33.57 24.02,32.9 PQ708.2 23.91,32.34 PQ713.6
  IN1 w0.114: v3(24.62,31.88) 25.08,32.34 27.9,32.34 28.3,31.93 41.97,31.93 51.77,22.13 v3(51.77,16.64)
VCC: length 7.1
  TOP w0.203: PU500.9 62.55,116.6 62.15,117 ; PU500.33 63.35,109.3 v2(63.56,109.1) 63.75,109.29 PU500.34 ; v2(62.11,117.05) 62.15,117 ; 62.15,117 PU500.10 ; PU500.6 63.75,116.7 64.08,117.03 v3(64.71,117.03) 64.15,116.48 PU500.5
  vias: v1(54.27,111.73) v2(54.04,107.71) v2(54.74,107.7) v2(55.38,112.16) v2(55.38,111.52) v2(60.46,108.2) v2(61.09,108.21)
VCCSENSE_VGA: length 85.3
  TOP w0.254: v3(54.92,36.89) v1(54.92,37.47) 55.23,37.77 PR1049.2 ; RV159.2 RV161.1 71.74,80.09 v3(71.71,80.07)
  IN2 w0.127: v3(71.71,80.07) 72.78,79 76.97,79 79.23,76.74 79.23,72.76 80.06,71.94 83.14,71.94 88.04,67.03 88.04,51.49 74.3,37.75 74.3,37.26 74.1,37.06 70.93,37.06 70.34,36.47 64.43,36.47 62.05,34.09 58.73,34.09 57.59,35.23 56.06,35.23 55.05,36.25 55.05,36.76 v3(54.92,36.89)
VDD_1.35V: length 4.7
  TOP w0.254: PC209.1 82.73,14.47 v3(82.73,13.9)
  BOTTOM w0.254: PR205.1 82.91,14.08 v3(82.73,13.9) ; v3(82.73,13.9) 82.73,13.64 83.2,13.17 PU200.11 ; v3(82.73,13.9) v1(82.05,13.9) 80.89,13.9 PR206.2
VDDIO: length 6.3
  TOP w0.102: v1(62.25,35.15) 62.21,35.11 PR1025.2 61.98,33.84 v3(61.27,33.13) ; PC1019.1 60.72,32.58 v3(61.27,33.13) ; PR1022.2 61.91,32.49 v3(61.27,33.13)
  BOTTOM w0.203: v3(61.27,33.13) 61.27,33.14 61.32,33.19 PU1000.6
VDDP_CAP: length 5.2
  TOP w0.102: v1(141.01,102.01) 140.73,101.73 v3(140.73,101.2)
  TOP w0.508: v3(140.73,101.2) 140.36,100.83 C80.1 C79.1
  BOTTOM w0.305: UC1.AC11 140.24,100.3 140.73,100.79 v3(140.73,101.2)
VDDP_LDO: length 15.7
  TOP w0.102: v3(41.84,8.31) 40.85,8.31 v1(40.79,8.37)
  TOP w0.254: PC714.1 41.17,15.27 v2(40.44,15.99)
  IN2 w0.254: v3(41.84,8.31) 41.2,8.95 41.2,15.23 v2(40.44,15.99)
  BOTTOM w0.254: PR710.1 41.88,8.35 v3(41.84,8.31) ; PU700.21 40.61,15.83 v2(40.44,15.99) 40.44,18.49 PR709.1
VDDR4: length 3.1
  BOTTOM w0.381: UV1.U12 64.4,87.15 v3(64.92,87.67) 64.92,87.54 65.37,87.1 UV1.V12 65.4,87.1 v3(65.94,87.64) 66.4,87.18 UV1.Y12
VDDR_CAP: length 9.6
  TOP w0.381: C78.1 145.93,91.26 C77.1 145.95,90.24 145.21,89.5 v1(142.37,89.5) 141.81,89.5 141.34,89.03 v3(140.66,89.03)
  BOTTOM w0.305: UC1.AC27 140.66,88.86 v3(140.66,89.03)
VIN: length 128.7
  TOP w0.254: v2(36.25,17.78) 36.83,17.21 PR707.1
  TOP w3.556: 17.33,106.43 17.33,97.78 16.77,97.22 16.77,96.36 16.12,95.36 15.31,94.55 15.31,89.28 16.87,87.71 16.88,87.7 16.99,87.59 17.07,87.51 17.07,83.49 16.08,82.5 16.08,73.13 20.33,68.89 23.93,68.89 28.25,64.57 29.44,64.57 35.08,58.93 35.08,53.65 33.76,52.33 33.5,52.33 33.22,52.05 33.2,52.05 29.17,48.01 29.17,44.4 27.23,42.47 25.46,42.47 22.92,39.93
  IN3 w0.254: v2(22.54,35.64) 22.54,35.54 22.33,35.34 22.33,34.52 24.14,32.72 24.14,30.56 24.92,29.77 24.92,27.36 34.5,17.78 v2(36.25,17.78) 37.52,19.05 47.99,19.05 v2(50.27,16.77)
  BOTTOM w0.254: PR711.2 49.79,16.29 v2(50.27,16.77) 50.7,16.34 PR706.2
  vias: v2(18.09,110.8) v2(18.09,110.04) v2(18.09,109.28) v2(18.09,108.51) v2(18.98,110.8) v2(18.98,110.04) v2(18.98,109.28) v2(18.98,108.51) v2(19.74,110.8) v2(19.74,110.04) v2(19.74,109.28) v2(19.74,108.51) v2(21.9,37.55) v2(21.9,36.91) v2(21.9,36.28) v2(21.9,35.64) v2(22.54,37.55) v2(22.54,36.91) v2(22.54,36.28) v2(29.19,111.82) v2(29.19,111.05) v4(16.19,108.83) v4(20,107.75) v4(20.31,39.04)
VSS_MECH: length 68.6
  IN2 w0.127: v3(75.25,94.1) 75.25,93.79 75.93,93.12 75.93,87.86 73.79,85.73 73.79,84.15 71.51,81.88 71.51,81.22 71.09,80.79 70.48,80.79 69.93,80.25 69.93,79.94 70.62,79.25 71.58,79.25 76.03,74.81 76.03,73.31 75.6,72.88 v3(75.49,72.88) 75.47,72.88 74.81,73.54 74.81,74.22 73.77,75.26 71.81,75.26 71.53,75.54 71.53,77.13 70.99,77.66 70.05,77.66 69.97,77.58 68.39,77.58 67.67,76.86 67.27,76.86 67,77.13 67,78.68 66.43,79.25 60.51,79.25 59.86,78.6 59.86,76.08 60.25,75.68 60.25,73.87 59.62,73.23 53.42,73.23 52.64,72.45 v3(52.63,72.45)
  BOTTOM w0.102: v1(76.84,97.62) 75.95,96.73 75.95,94.68 75.37,94.1 v3(75.25,94.1) 74.85,94.5 UV1.AM1
  BOTTOM w0.254: UV1.AM32 75.47,72.9 v3(75.49,72.88) ; v3(52.63,72.45) 52.76,72.45 53.2,72.89 UV1.A32
VSSSENSE_VGA: length 86.5
  TOP w0.102: RV160.1 RV158.2 70.92,79.94 v3(71.05,80.07) ; PR1050.2 52.63,37.8 v3(53.19,37.24)
  IN2 w0.127: v3(71.05,80.07) 71.53,79.58 71.81,79.58 72.65,78.74 76.86,78.74 78.97,76.63 78.97,72.66 79.95,71.68 83.03,71.68 87.79,66.93 87.79,51.59 74.1,37.9 71.41,37.9 70.24,36.73 64.33,36.73 61.95,34.35 58.84,34.35 56.7,36.48 56.7,36.68 56.06,37.32 53.27,37.32 v3(53.19,37.24)
  BOTTOM w0.102: v3(53.19,37.24) 53.04,37.24 v1(52.71,37.57)
25M_X1: length 9.4
  BOTTOM w0.102: U2.C31 169.01,9.01 169.71,9.01 170.29,8.43 170.29,8.23 170.77,7.75 RH23.1 CH12.2 169.47,4.96 169.22,4.96 RH21.2 169.23,4.18 X1.1
25M_X2: length 10
  BOTTOM w0.102: X1.3 171.53,3.63 171.53,4.7 171.79,4.96 172.09,4.96 CH15.2 RH23.2 v3(171.68,6.15) 171.68,7.67 169.88,9.47 U2.C33
32K_X1: length 15.3
  BOTTOM w0.102: CH10.2 140.72,9.96 139.88,9.96 139.38,10.47 RH6.2 ; CH10.2 141.33,10.62 RH4.1 141.84,11.99 143.19,11.99 143.44,11.74 144.07,11.74 144.45,12.12 U2.G2 ; CH10.2 141.36,8.89 142.37,7.88 142.37,7.11 Y2.1 142.53,5.41 v1(142.31,5.19)
32K_X2: length 8
  BOTTOM w0.102: Y2.2 142.22,9.76 CH11.2 142.25,10.62 RH4.2 143.06,11.49 143.31,11.23 144.51,11.23 v1(144.84,11.57) 144.96,11.69 147.12,11.69 U2.G4
65W#/90W: length 2.3
  BOTTOM w0.102: T110.1 124.5,21.28 123.9,21.28 123.61,20.99 UE1.117
#ECAD5: length 2.9
  TOP w0.102: T104.1 112.82,28.19 v3(113.21,28.58)
  BOTTOM w0.102: UE1.76 113.19,28.6 v3(113.21,28.58)
+A_VCC: length 3.4
  BOTTOM w0.102: v1(188.07,20.26) 187.94,20.39 RA28.2
  BOTTOM w0.508: RA11.2 RA10.2 RA28.2
+A_VCC_R: length 5.6
  BOTTOM w0.203: UA1.20 192.34,20.09 191.74,20.69 191.74,20.91 191.05,21.61 190.57,21.61 190.4,21.77 v1(189.83,21.77) 189.11,21.77 RA28.1
+APU_CORE: length 73.1
  TOP w0.254: PR502.2 PC500.2 65.23,119.51 v3(65.23,120.07)
  IN1 w0.254: v3(65.23,120.07) 66.39,118.91 66.39,111.8 67.14,111.05 67.82,111.05 71.7,107.18 71.7,103.85 74.07,101.48 100.71,101.48 105.47,106.24 v2(105.47,116.77)
  BOTTOM w0.254: UC1.AE25 142.3,89.24 v3(142.64,88.9)
  BOTTOM w0.305: UC1.AG11 143.5,100.7 v3(143.5,101.1)
  BOTTOM w0.356: UC1.AK8 145.94,103.1 v3(145.69,103.36) ; v3(145.04,102.14) 144.7,102.47 UC1.AH8 ; v3(142.48,102.09) 143.1,102.7 UC1.AF8
  BOTTOM w0.381: UC1.AH10 144.7,101.8 v3(145.04,102.14)
  vias: v2(99.75,121.21) v2(99.75,120.58) v2(99.75,119.94) v2(99.75,119.31) v2(99.75,118.67) v2(99.75,118.04) v2(99.75,117.4) v2(100.39,121.21) v2(100.39,120.58) v2(100.39,119.94) v2(100.39,119.31) v2(100.39,118.67) v2(100.39,118.04) v2(100.39,117.4) v2(101.02,121.21) v2(101.66,121.21) v2(102.29,121.21) v2(102.93,121.21) v2(103.55,117.4) v2(103.54,116.77) v2(103.56,121.21) v2(104.2,121.21) v2(104.2,120.58) v2(104.2,119.94) v2(104.2,119.31) v2(104.2,118.67) v2(104.2,118.04) v2(104.2,117.4) v2(104.2,116.77) v2(104.83,121.21) v2(104.83,120.58) v2(104.83,119.94) v2(104.83,119.31) v2(104.83,118.67) v2(104.83,118.04) v2(104.83,117.4) v2(104.83,116.77) v2(105.47,121.21) v2(105.47,120.58) v2(105.47,119.94) v2(105.47,119.31) v2(105.47,118.67) v2(105.47,118.04) v2(105.47,117.4) v2(106.1,121.21) v2(106.1,120.58) v2(106.1,119.94) v2(106.74,120.58) v2(106.74,119.94) v2(142.4,109.94) v2(143.03,110.9) v2(143.14,109.94) v2(143.77,110.9) v2(144.02,112.32) v2(146.74,109.22) v2(146.77,111.38) v2(146.77,110.7) v2(146.77,110.01) v2(147.5,111.64) v2(147.5,110.98) v2(148.77,112.27) v2(148.77,111.61) v2(150.76,112.27) v3(134.64,98.45) v3(134.69,99.85) v3(134.69,97.56) v3(134.69,95.15) v3(134.69,92.87) v3(134.76,96.12) v3(135.7,93.75) v3(135.7,90.07) v3(136.21,100.99) v3(136.85,96.17) v3(136.97,98.58) v3(136.97,93.75) v3(136.97,90.07) v3(137.1,100.99) v3(138.37,90.07) v3(138.95,104.98) v3(139,104.3) v3(139.39,96.17) v3(139.46,106.73) v3(139.51,100.99) v3(139.51,100.36) v3(139.51,99.6) v3(139.51,98.83) v3(139.51,97.56) v3(139.51,93.75) v3(139.64,90.07) v3(139.82,88.95) v3(140.02,104.27) v3(140.07,105.67) v3(140.06,105.01) v3(140.06,103.53) v3(140.12,102.11) v3(140.96,96.17) v3(140.96,93.75) v3(141.04,90.07) v3(141.16,105.82) v3(141.16,105.11) v3(141.77,100.84) v3(141.93,93.75) v3(142.75,92.54) v3(143.6,105.85) v3(144.86,105.13) v4(139.25,108.64)
+APU_CORE_NB: length 55.2
  TOP w0.254: PC534.2 PR565.2 69.73,105.58 70.26,105.05 70.26,103.28 72.12,101.43 78.25,101.43 78.7,100.98 93.19,100.98 v3(94.54,99.62)
  BOTTOM w0.254: UC1.T3 134.91,106.91 v3(134.15,106.91) 134.15,106.45 UC1.R4 ; 107.58,109.99 107.58,107.79 105.25,105.47 105.25,102.39 103.63,100.77 95.69,100.77 v3(94.54,99.62)
  BOTTOM w0.381: UC1.R6 134.53,104.7 v3(134.12,105.11) ; UC1.G10 127.9,101.65 v3(128.26,102.01) ; UC1.N14 UC1.P16 134.46,96.7 v3(134.69,96.93)
  vias: v2(100.51,104.83) v2(100.51,104.2) v2(100.51,103.56) v2(101.15,104.83) v2(101.15,104.2) v2(101.15,103.56) v2(101.78,109.28) v2(101.78,108.64) v2(101.78,108.01) v2(101.78,107.37) v2(101.78,106.74) v2(101.78,106.1) v2(101.78,105.47) v2(101.78,104.83) v2(101.78,104.2) v2(101.78,103.56) v2(102.42,109.28) v2(102.42,108.64) v2(102.42,108.01) v2(102.42,107.37) v2(102.42,106.74) v2(102.42,106.1) v2(102.42,105.47) v2(102.42,104.83) v2(102.42,104.2) v2(103.05,109.28) v2(103.05,108.64) v2(103.05,108.01) v2(103.05,107.37) v2(103.05,106.74) v2(103.05,106.1) v2(103.05,105.47) v2(103.69,109.28) v2(103.69,108.64) v2(103.69,108.01) v2(103.69,107.37) v2(103.69,106.74) v2(103.69,106.1) v2(104.2,112.2) v2(104.2,111.56) v2(104.2,110.93) v2(104.2,110.29) v2(104.83,112.2) v2(104.83,111.56) v2(104.83,110.93) v2(106.1,113.97) v2(106.1,113.34) v2(106.74,113.97) v2(106.74,113.34) v2(107.37,113.97) v3(126.29,103.33) v3(126.69,106.76) v3(126.79,102.11) v3(126.9,103.33) v3(127.45,102.01) v3(127.5,103.25) v3(128.03,106.91) v3(128.06,105.79) v3(128.11,105.13) v3(128.08,104.45) v3(128.29,103.25) v3(129.05,102.06) v3(129.07,103.28) v3(129.1,99.67) v3(129.2,104.35) v3(129.25,105.11) v3(129.84,90.1) v3(129.99,100.99) v3(129.99,99.72) v3(129.99,98.45) v3(129.99,96.04) v3(129.99,94.9) v3(129.99,93.63) v3(129.99,91.34) v3(130.55,104.27) v3(130.55,103.56) v3(130.52,102.7) v3(130.57,90.1) v3(131.07,90.5) v3(131.23,106.89) v3(131.4,90.02) v3(132.27,100.99) v3(132.27,98.58) v3(132.27,96.17) v3(132.27,93.75) v3(132.31,89.49) v3(132.4,91.47) v3(132.37,90.89) v3(132.42,88.88) v3(133.84,88.98) v3(134.16,102.53) v3(134.69,101.63) v3(134.69,99.22) v3(134.69,94.39) v3(134.69,89.69) v4(129.66,110.55)
+BIF_VDDC: length 2.6
  TOP w0.381: CV168.1 61.32,79.23 61.91,79.81 v3(62.08,79.81)
  BOTTOM w0.381: UV1.U21 64.4,80.34 64.03,80.71 64.03,80.74 v3(64.01,80.77) ; UV1.R21 62.47,80.3 62.08,79.91 v3(62.08,79.81)
  vias: v1(60.45,71.65) v2(63.13,71.82) v2(63.13,71.18) v2(63.68,71.52)
+CODEC_AVDD2: length 11.5
  BOTTOM w0.203: UA1.40 200.27,20.49 200.4,20.62 v1(201.86,20.62) 201.92,20.62 202.67,21.37 RA8.2
  BOTTOM w0.508: RA8.2 202.43,21.89 CA61.1 203.13,23.49 203.13,25.12 202.39,25.86 200.89,25.86 200.34,25.3 RA9.2
+DP_VDDC: length 16.8
  TOP w0.102: v3(71.18,84.76) v1(71.18,85.49)
  TOP w0.508: v3(71.18,84.76) CV33.1 CV34.1 70.36,84.15 v3(70.36,84.89) ; v3(72.04,77.27) 71.85,77.46 RV30.2
  IN2 w0.508: 67.39,80.09 68.14,79.35 68.14,78.36 68.47,78.02 69.78,78.02 69.87,78.11 71.18,78.11 72.02,77.27 v3(72.04,77.27) ; 67.39,81.31 68.18,82.1 68.2,82.1 68.55,82.46 68.55,82.9 69.72,84.07 70.48,84.07 v3(71.18,84.76)
  BOTTOM w0.254: v3(70.36,84.89) 70.36,85.14 70,85.5 UV1.AD14
+DP_VDDR: length 6.5
  TOP w0.102: RV27.2 75.01,87.85 75.01,87.41 75.33,87.09 v1(75.33,86.87)
  TOP w0.508: RV27.2 74.48,88 74.48,87.37 74.09,86.97 CV26.1 CV27.1 72.45,86.97 71.94,86.46 v3(71.94,86.05)
  BOTTOM w0.254: UV1.AF14 71.94,85.84 v3(71.94,86.05)
+EC_VCCA: length 32.3
  TOP w0.102: v1(129.24,28.1) 129.13,27.98 v3(129.13,27.37)
  IN2 w0.508: v3(107.7,32.49) 108.57,32.49 109.89,31.17 113.21,31.17 114.8,29.58 114.8,27.87 116.45,26.22 119.93,26.22 121.18,27.46 129.04,27.46 v3(129.13,27.37)
  BOTTOM w0.203: UE1.67 109.59,31.54 CE7.1
  BOTTOM w0.508: v3(107.7,32.49) 107.91,32.69 CE7.1 108.44,33.67 LE1.2 ; v3(129.13,27.37) 128.45,26.7 PR24.2
+FAN_POWER: length 7
  TOP w0.635: UE3.3 CE23.1 5.15,71.73 CE22.1 7.99,71.49 v2(8.06,71.56) v2(8.06,72.45)
  vias: v4(7.17,72.25)
+FBA_VREF0: length 29.2
  IN1 w0.381: v3(35.14,71.13) 35.14,71.17 34.92,71.4 34.92,72.94 33.46,74.4 26.78,74.4 26.17,75.01 26.17,76.43 26.96,77.22 33.2,77.22 33.74,77.76 v3(33.74,78.13)
  BOTTOM w0.254: UV5.M8 34.15,77.72 v3(33.74,78.13) ; 36.8,71.19 37.27,71.66 37.27,72.04 UV5.H1
  BOTTOM w0.508: RV42.2 RV44.1 CV100.1 34.85,68.97 v1(34.85,69.89) 34.85,70.84 v3(35.14,71.13) 35.41,70.87 36.54,70.87 36.8,71.12 36.8,71.19
+FBA_VREF1: length 32.9
  TOP w0.254: v3(35.82,79.18) 36.06,78.94 36.9,78.94 37.32,78.52 UV6.H1 ; UV6.M8 34.13,72.92 v3(33.75,72.54)
  IN1 w0.381: v3(33.75,72.54) 32.8,73.49 26.4,73.49 25.25,74.63 25.25,76.81 26.58,78.13 31.73,78.13 32.14,78.54 32.14,79.2 33.03,80.09 33.86,80.09 34.4,79.56 34.4,78.8 34.67,78.52 34.67,78.52 34.67,78.52 35.11,78.52 35.78,79.18 v3(35.82,79.18)
  BOTTOM w0.254: RV45.1 CV101.1 RV43.2 37.52,81.28 v1(36.98,80.74) 36.98,80.48 35.82,79.33 v3(35.82,79.18)
+FBA_VREF2: length 34
  TOP w0.152: v3(33.79,90.71) 33.71,90.78 33.71,91.73 33.75,91.77 33.75,92.33 UV7.M8
  TOP w0.254: UV7.H1 36.4,99.28 v3(36.4,99.45)
  IN1 w0.381: v3(33.79,90.71) 33.33,91.16 33.33,91.6 32.77,92.16 29.98,92.16 29.37,91.55 27.39,91.55 25.94,92.99 25.94,94.92 27.59,96.58 33.28,96.58 36.15,99.45 v3(36.4,99.45)
  BOTTOM w0.254: CV133.1 RV52.1 RV50.2 37.39,89.21 v1(36.76,89.84) 36.02,90.58 33.92,90.58 v3(33.79,90.71)
+FBA_VREF3: length 35.8
  TOP w0.508: RV53.1 RV51.2 CV134.1 v3(33.58,100.61)
  IN1 w0.381: v3(37.7,91.06) 37.29,90.66 34.55,90.66 33.99,90.1 32.54,90.1 31.48,91.16 30.28,91.16 29.75,90.63 27.01,90.63 25.03,92.61 25.03,95.3 29.57,99.85 33.05,99.85 33.58,100.39 v3(33.58,100.61)
  BOTTOM w0.152: UV8.M8 34.15,97.75 34.58,98.18 34.58,98.73
  BOTTOM w0.254: v3(37.7,91.06) 37.62,91.06 37.35,91.34 UV8.H1 ; v3(33.58,100.61) 33.64,100.56 v1(34.16,100.56) 34.45,100.27 34.45,98.86 34.58,98.73
+FCH_VDD_11_SSUSB_S:
  vias: v1(155.45,9.96) v3(156.24,5.08)
+INV_PWR_SRC: length 1.2
  TOP w0.102: v2(1.96,78.26) v4(1.96,77.08)
  vias: v2(1.96,78.92)
+INV_PWR_SRC_R:
  vias: v1(4.55,74.5)
+LAN_IO: length 2.5
  BOTTOM w0.127: C8.1 140.09,12.68 v1(140.26,12.86)
  BOTTOM w0.254: C8.1 139.33,12.63 UG1.8
+LAN_REGOUT:
  vias: v1(168.54,109.36)
+LAN_VDD10: length 4.4
  BOTTOM w0.203: UL1.30 174.01,106.42 v3(174.05,106.46) ; UL1.22 170.68,104.16 v3(170.57,104.04) ; UL1.3 176.37,104.16 v2(176.57,104.36) ; v2(176.56,102.81) 176.56,102.58 176.14,102.16 UL1.8
  vias: v1(172.13,106.63) v3(166.53,109.99) v3(166.53,108.79) v3(166.48,108.21)
+LAN_VDD33: length 2.6
  TOP w0.508: CL12.1 v3(175.57,105.8)
  BOTTOM w0.203: v3(174.22,100.49) 174.01,100.7 UL1.11 ; v3(175.57,105.8) 175,105.8 UL1.32
  vias: v1(171.76,99.29) v2(169.6,109.48) v2(170.08,109) v3(161.3,113.09) v3(162.95,113.57) v3(162.95,112.98)
+LAN_VDD33_UL2: length 1.1
  TOP w0.102: v3(165.98,113.91) v4(165.98,112.77)
+LAN_VDD33_UL3: length 0.9
  TOP w0.102: v3(170.62,111.62) 170.3,111.62 v4(169.86,111.18)
+LAN_VDDREG: length 2.9
  TOP w0.102: v1(166.49,105.01) 166.69,104.8 v2(169.27,104.8)
  vias: v2(169.73,104.3)
+LCDVDD: length 1
  TOP w0.102: v2(14.28,84.26) 14.28,83.62 v4(14.03,83.37)
  vias: v2(13.65,84.89) v2(13.65,84.26) v2(14.28,84.89) v2(20.81,73.31) v2(20.81,72.67) v2(21.44,73.31) v2(21.44,72.67)
+LCDVDD_CONN:
  vias: v1(12.95,87.74) v2(2.76,87.7) v2(3.25,88.11) v2(6,87.99) v2(6.25,87.41) v2(6.66,87.99) v2(6.94,87.41) v2(7.63,87.43)
+MA_VREF_DQ: length 10.7
  TOP w0.102: v1(100.72,52.13) 100.67,52.07 99.27,52.07 R57.1
  TOP w0.381: v3(95.26,49.69) 95.26,50.86 C127.1 C126.1 95.87,51.99 C125.1 96.42,52.19 96.56,52.05 R59.2 R58.1 98.3,51.97 99.17,51.97 R57.1
  BOTTOM w0.356: JDIMM1.1 96.15,48.79 v3(95.26,49.69)
+MA_VREFDQ: length 62.9
  TOP w0.381: 125.42,100.3 125.44,100.32 127.86,100.32 128.36,100.82 v3(128.36,100.89)
  TOP w0.508: R58.2 98.23,55.38 120.83,77.98 120.83,89.95 v1(123.63,92.74) 123.63,95.43 124.8,96.6 124.8,98.1 124.36,98.53 124.36,99.24 125.42,100.3
  BOTTOM w0.381: UC1.H11 128.7,100.44 128.36,100.77 v3(128.36,100.89)
+MEM_VREF: length 16.3
  TOP w0.381: R5.1 R8.2 C29.1 C30.2 v1(144.51,76.18) 144.86,76.53 v3(145.27,76.53)
  BOTTOM w0.254: 137.12,79.43 137.12,79.91 137.09,79.94 137.09,80.32 136.71,80.7 UC1.V36
  BOTTOM w0.381: 137.12,79.43 140.01,76.53 v3(145.27,76.53)
+MIC2-VREFO: length 21.6
  IN3 w0.508: v3(195.93,23.35) 195.71,23.35 195.03,24.03 192.97,24.03 192.46,23.52 190.56,23.52 189.59,24.49 188.47,24.49 187.74,25.23 187.74,28.33 188.96,29.54 188.96,29.58 188.88,29.66 188.88,30.14 188.96,30.22 v3(188.96,31.68)
  BOTTOM w0.102: v1(187.93,34.37) 188.59,34.37 188.96,34 RA53.2
  BOTTOM w0.203: UA1.29 v3(195.93,23.35)
  BOTTOM w0.508: RA53.2 v3(188.96,31.68) RA1109.2
+MPLL_PVDD: length 12.8
  TOP w0.102: CV81.1 v1(60.97,97.85)
  TOP w0.508: v3(61.8,95.61) 61.69,95.51 CV82.1 CV83.1 60.97,96.88 60.51,97.34 60.19,97.34 CV81.1 59.68,98.29 60.13,98.73 LV6.2
  IN3 w0.508: v3(61.8,95.61) 61.53,95.61 61.07,95.15 61.07,92.24 60.45,91.62 v3(60.45,90.9)
  BOTTOM w0.254: UV1.L8 60.05,90.5 v3(60.45,90.9)
+MVREFDA: length 13.1
  TOP w0.102: v1(54.78,67.03) 55.43,67.68 RV33.2
  TOP w0.508: RV33.2 CV94.1 RV34.1 57.51,68.18 58.79,69.46 58.79,70.96 59.29,71.45 59.29,73.61 59.19,73.71 59.19,76.45 v3(59.2,76.46)
  BOTTOM w0.254: UV1.K26 59.16,76.46 v3(59.2,76.46)
+MVREFSA: length 8
  TOP w0.508: RV32.2 RV35.1 CV95.1 v1(57.21,73.7) 57.21,74.93 58.4,76.13 v3(58.4,76.5)
  BOTTOM w0.254: v3(58.4,76.5) 58.39,76.5 58,76.11 UV1.J26
+RTCBATT: length 144.9
  TOP w0.508: RH19.1 140.96,3.69 v1(140.11,4.54) 135.78,8.87 132.91,8.87 132.68,9.1 131.02,9.1 130.79,8.87 129.66,8.87 128.49,10.04 126.74,10.04 125.27,11.51 122.41,11.51 120.07,9.17 112.38,9.17 111.18,10.37 109.38,10.37 v3(109.3,10.29)
  IN3 w0.508: v3(29.47,11.33) 36.1,11.33 37.22,10.22 46.56,10.22 48.39,12.04 50.65,12.04 54.27,15.66 54.27,25.25 55.76,26.73 66.62,26.73 68.61,24.74 73.2,24.74 76,21.94 76,20.15 79.18,16.98 81.37,16.98 82.03,16.32 86.92,16.32 91.62,11.61 106.1,11.61 106.99,12.5 108.77,12.5 109.28,11.99 109.28,10.32 v3(109.3,10.29)
  BOTTOM w0.508: JRTC.1 v3(29.47,11.33)
+SPLL_PVDD: length 5.5
  TOP w0.127: v1(56.44,91.27) 56.86,91.69 v3(56.86,91.69)
  TOP w0.508: v3(56.86,91.69) 56.86,92.17 56.7,92.33 CV86.1 56.7,93.25 LV7.2 56.72,94.14 CV85.1 56.7,94.54 56.47,94.77 56.47,95.78 CV84.1
  BOTTOM w0.254: UV1.H7 57.2,91.35 v3(56.86,91.69)
+SPLL_VDDC: length 6.3
  TOP w0.508: 57.87,94.26 58.74,94.26 CV91.1 58.82,93.82 58.5,93.5 CV92.1 58.5,91.81 v1(58.12,91.43) 57.6,90.9 v3(57.6,90.85) ; 57.87,94.26 57.87,95.08 LV8.2 ; 57.87,94.26 CV93.1
  BOTTOM w0.254: v3(57.6,90.85) 57.25,90.5 UV1.H8
+TSVDD: length 16.8
  IN1 w0.254: v3(78.19,84.76) 77.3,85.65 75.32,85.65 73.87,84.21 71.37,84.21 69.82,82.65 v3(69.82,82.43)
  BOTTOM w0.102: CV20.1 v1(79.23,80.12)
  BOTTOM w0.305: v3(78.19,84.76) LV2.2 79.23,84.13 78.99,83.89 CV19.1 79.23,83.25 CV21.1 CV20.1 ; UV1.AD17 70,82.61 v3(69.82,82.43)
+V_EC: length 3.7
  BOTTOM w0.102: RE13.2 v1(120.83,35.17)
  BOTTOM w0.508: RE12.2 RE13.2 RE10.1 RE9.1
+V_TP: length 2.2
  TOP w0.203: UE4.4 8.86,63.69 v3(8.74,63.58)
  IN3 w0.508: v3(8.74,63.58) v3(8.74,65)
  vias: v1(8.83,66.81)
+V_UV4: length 0.6
  TOP w0.102: 75.13,94.61 74.75,94.61 v1(74.62,94.48)
  vias: v2(75.24,90.91) v2(75.22,90.12)
+VCOIN: length 21.7
  TOP w0.254: DH1.2 146.84,2.77 RH19.2 v1(143.26,2.77) 138,2.77 136.73,1.5 v3(135.92,1.5)
  BOTTOM w0.254: R796.1 140.52,8.36 141,7.88 141,6.21 136.29,1.5 v3(135.92,1.5)
+VCOIN_RTC: length 155.5
  TOP w0.254: DH1.1 DH2.1 149.43,4.09 149.43,3.48 v3(149.69,3.23) ; DH1.1 146.01,4.52 RH24.1 141.05,4.8 v3(138.94,6.91) ; DH1.1 147.3,6.43 147.68,6.81 RH22.2 ; RA5.1 191.5,35.77 v3(189.69,35.77) 186.67,35.77 185.07,37.37 179.99,37.37 178.92,36.3 v4(176.21,36.3) 170.32,36.3 168.33,38.28 168.08,38.28 167.7,38.66 v3(167.7,40.44)
  IN2 w0.254: v3(189.69,35.77) 188.57,35.77 187,34.2 187,30.24 186.1,29.34 186.1,24.58 185.43,23.91 185.43,23.22 v3(185.55,23.09) 185.48,23.02 185.48,21.46 186.07,20.86 186.07,16.18 186.56,15.7 187.01,15.7 187.67,15.04 187.67,7.98 187.02,7.33 171.75,7.33 170.74,6.33 169.94,6.33 166.43,2.82 164.23,2.82 163.35,1.95 158.5,1.95 157.49,2.96 153.44,2.96 153.03,2.56 150.31,2.56 149.69,3.18 v3(149.69,3.23)
  BOTTOM w0.254: RA11.1 185.55,22.74 v3(185.55,23.09) ; R787.1 138.97,7.95 138.97,6.94 v3(138.94,6.91) 138.92,6.94 135.03,6.94 134.13,6.04 133.11,6.04 132.62,6.53 132.62,8.46 R790.1 ; CLRP1.1 153.88,55.33 158.53,50.68 163.38,50.68 166.07,47.98 166.07,42.14 167.7,40.52 v3(167.7,40.44)
+VDISPLAY_VCC:
  vias: v1(193.05,75.73) v2(193.55,74.93) v2(193.96,75.44) v2(200.72,80.67) v2(200.69,80.04)
+VGA_CORE: length 41.8
  TOP w0.508: PC841.1 61.44,88.35 61.07,87.98 v3(61.07,87.64) ; RV161.2 72.65,81.11 v3(72.9,81.36)
  BOTTOM w0.254: v3(65.75,80.8) 65.4,81.15 UV1.V20 ; v3(65.75,80.8) 66.25,80.3 UV1.Y21 ; v3(65.75,80.8) 65.4,80.45 UV1.V21
  BOTTOM w0.381: UV1.V20 UV1.U18 64.4,82.24 63.6,81.44 UV1.T20 63.6,81.26 63.07,80.73 v3(63.07,80.72) ; UV1.T12 63.79,87.29 63.79,87.39 64.12,87.72 64.12,87.82 UV1.U11 64.4,88.19 v3(64.01,88.57) ; UV1.T12 63.6,87.14 v3(63.09,87.65) ; UV1.T12 63.6,86.95 64.4,86.15 UV1.U13 64.4,85.95 63.6,85.15 UV1.T15 ; UV1.Y9 66.59,89.7 66.2,89.3 v3(66.2,89.3) ; UV1.N17 61.6,83.24 v3(61.2,82.83) ; UV1.V17 65.31,83.3 64.51,84.1 UV1.U16 ; UV1.U16 64.4,84.12 v3(64.91,84.63) 65.38,85.1 UV1.V15 UV1.Y13 66.49,86.1 v3(67,86.61) 67,86.63 67.4,87.02 UV1.AA12 67.49,87.1 v3(67.93,87.54) ; UV1.U16 64.1,84.4 64.1,84.48 63.6,84.98 UV1.T15 ; UV1.Y18 v3(65.9,82.8) ; UV1.Y21 66.4,80.19 66.77,79.83 v3(66.77,79.81) ; UV1.W9 65.86,89.7 66.17,89.39 66.17,89.32 v3(66.2,89.3) ; v3(64.01,88.57) 63.69,88.9 UV1.T10 ; v3(64.01,88.57) 64.34,88.9 UV1.U10 ; UV1.W10 65.81,88.9 66.2,89.29 v3(66.2,89.3) ; UV1.AB11 68.4,88.01 v3(67.93,87.54) ; v3(67.93,87.54) 68.36,87.1 UV1.AB12 68.51,86.99 68.51,86.21 UV1.AB13 ; UV1.AC14 69,85.5 UV1.AB13 ; UV1.M11 60.61,88.1 v3(61.07,87.64) 61.6,87.11 UV1.N12 UV1.R13 62.6,85.98 v3(63.1,85.49) 63.48,85.1 UV1.T15 ; UV1.AB13 67.93,85.63 v3(67.93,85.55) 67.47,85.1 UV1.AA15 67.26,85.1 v3(66.79,84.63) 66.4,84.24 UV1.Y16 ; UV1.N15 v3(62.13,84.57) UV1.R16 62.65,84.1 63.45,83.3 63.57,83.3 ; UV1.R18 62.6,82.33 63.57,83.3 ; 63.57,83.3 UV1.T17 ; v3(66,79.76) 65.46,80.3 UV1.V21
  vias: v2(54.35,61.49) v2(54.37,60.47) v2(55.44,61.45) v2(55.43,60.47) v2(56.57,61.4) v2(56.57,60.63) v2(57.71,61.4) v2(57.71,60.63) v2(58.78,61.31) v2(58.78,60.55) v2(60,61.49) v2(60,60.57) v2(60.97,65.49) v2(60.97,64.84) v2(61,63.12) v2(61,62.49) v2(61.18,61.36) v2(61.18,60.6) v2(62.31,61.33) v2(62.31,60.57) v2(62.73,65.73) v2(63.05,61.27) v2(63.81,61.27) v2(65.08,65.14) v2(65.46,61.14) v2(66.35,61.9) v2(66.35,61.14) v2(67.24,61.9) v2(67.24,61.14) v2(68.13,61.9) v2(68.13,61.14) v3(63.43,69.52) v3(63.43,68.91) v3(63.43,66.86) v3(63.43,66.17) v4(54.48,62.41)
+VGA_PCIE: length 49.6
  TOP w0.508: v3(58.86,97.08) 58.86,97.03 LV8.1
  IN3 w0.203: 61.75,83.37 61.58,83.54 61.58,84.74 61.19,85.12 61.19,86.54 60.64,87.1 59.34,87.1 59.21,86.97 ; 61.08,82.22 60.61,82.7 60.61,85.68 60.18,86.11 59.72,86.11
  IN3 w0.254: 61.75,83.37 63.68,83.37 65.49,81.56 65.74,81.56 66.24,81.06 66.24,80.61 66.23,80.6 66.23,80.6 65.95,80.32 65.94,80.32 65.92,80.29 65.81,80.29 65.33,79.81 65.33,78.89 v3(65.18,78.73) ; 61.08,82.22 61.6,82.22 61.98,81.84 64.45,81.84 65.24,81.05 65.24,81 65.25,80.99 65.25,80.49 64.7,79.94 64.7,78.97 ; 59.26,86.44 59.39,86.44 59.72,86.11
  IN3 w0.508: 59.26,86.44 59.21,86.49 59.21,87.69 59.8,88.27 59.8,93.22 58.21,94.81 58.21,96.44 v3(58.86,97.08)
  BOTTOM w0.254: v3(60.4,76.42) 60.08,76.1 UV1.L26
  BOTTOM w0.305: UV1.N23 61.4,78.1 v3(61.68,78.1) 61.6,78.18 UV1.N22 ; v3(60.39,77.2) 60.09,76.9 UV1.L25 ; v3(60.4,77.99) 60.69,77.7 UV1.N24 ; UV1.L23 59.59,78.5 v3(59.19,78.1) 59.59,77.7 UV1.L24
  BOTTOM w0.381: UV1.R22 62.6,79.02 62.86,78.76 v3(62.89,78.76) 63.2,79.07 63.37,79.07 UV1.T22 ; UV1.V22 65.4,78.95 v3(65.18,78.73) 65.15,78.73 64.58,79.3 UV1.U22 ; UV1.N23 60.6,78.9 UV1.M22
  vias: v1(69.14,73.51) v2(71.84,71.25) v2(73.64,69.88) v2(74.96,71.33) v2(75.42,70.79) v3(62.79,78.03) v3(64.06,78.03) v3(65.14,77.35) v3(65.14,76.53) v3(65.17,78.01)
+VGA_PCIEP: length 12.7
  TOP w0.254: 76.8,63.14 76.8,62.86 77.4,62.26 77.4,55.96 78.47,54.89 v1(78.47,53.45) 78.29,53.27 PC1306.1 PR1302.1
  vias: v2(71.93,62.36) v2(72.59,62.33) v2(73.25,62.34) v2(73.88,62.32) v2(74.54,62.33) v2(75.18,62.31) v4(70.92,62.79)
+VREF_CA: length 9.8
  TOP w0.381: C122.1 139.18,40.88 C123.1 C124.1 ; v3(136.05,40.93) 136.05,40.72 v1(137.55,39.22) C124.1 ; C124.1 R56.2 139.1,38.12 139.1,37.27 R55.1
  BOTTOM w0.254: JDIMM1.126 v3(136.05,40.93)
A_RST#: length 6.1
  BOTTOM w0.102: RH3.2 143.16,27.79 143.88,27.07 144.16,27.07 v1(144.39,26.84) 145.9,25.33 147.56,25.33 U2.AD5
ACIN: length 324
  TOP w0.102: v3(72.24,97.72) RV149.1 71.56,97.08 71.43,97.21 70.16,97.21 69.78,96.83 69.78,95.94 71.68,94.04 74.22,94.04 74.7,93.56 UV4.1
  TOP w0.203: PR1.1 37.6,110.16 38.54,110.16 38.79,109.91 v1(38.79,108.91) 38.79,108.31 37.39,106.91 v3(37.01,106.91)
  TOP w0.254: PR712.1 28.3,33.88 29.44,35.03 30.94,35.03 v3(31.04,35.13)
  IN1 w0.254: v3(41.88,10.86) 41.88,10.38 41.08,9.58 35.11,9.58 29.14,15.55 21.34,15.55 19.17,17.72 19.17,20.95 19.87,21.65 19.87,30.92 23.6,34.65 28.89,34.65 29.37,35.13 v3(31.04,35.13)
  IN2 w0.127: v3(121.49,24.64) 120.4,23.55 111.39,23.55 109.07,25.86 107.93,25.86 106.94,24.87 100,24.87 87.13,37.74 77.13,37.74 74.94,35.54 71.57,35.54 67.6,31.58 59.09,31.58 56.49,28.97 45.83,28.97 42.06,32.74 36.28,32.74 33.89,35.13 v3(31.04,35.13) 30.05,36.12 30.05,40.65 23.2,47.51 23.2,49.05 18.79,53.46 17.09,53.46 16.86,53.69 14.29,53.69 12.55,55.43 12.55,59.24 11.77,60.03 11.77,72.21 11.28,72.7 11.28,88.49 12.73,89.94 12.73,90.86 23.22,101.35 26.98,101.35 31.83,106.2 36.3,106.2 v3(37.01,106.91) 37.01,106.51 38.26,105.26 39.75,105.26 40.49,104.53 44.16,104.53 46.04,102.65 57.11,102.65 58.32,103.86 58.96,103.86 59.11,103.71 60.2,103.71 60.86,103.05 66.4,103.05 71.74,97.72 v3(72.24,97.72)
  BOTTOM w0.102: CE18.2 123.96,23.55 123.72,23.79 UE1.110 121.97,23.79 121.49,24.26 v3(121.49,24.64)
  BOTTOM w0.254: PU700.13 42.94,11.29 42.78,11.13 42.78,10.37 42.81,10.34 PR716.1 PR710.2 v3(41.88,10.86)
ACIN_65W: length 137.5
  TOP w0.102: RV149.2 73.29,96.96 QV8.2 ; RV149.2 72.95,97.29 72.95,97.59 72.32,98.23 70.8,98.23 v1(70.45,97.88) 69.53,96.96 69.53,95.81 72.32,93.02 RV92.2 73.41,92.21 74.05,92.84 UV4.2 ; RV149.2 74.38,98.3 77.58,98.3 v3(78.01,98.73)
  IN2 w0.127: v3(128.35,33.2) 128.25,33.3 124.45,33.3 123.28,32.14 121.66,32.14 120.66,33.14 116.45,33.14 112.01,37.58 112.01,37.67 98.3,37.67 95.97,40.01 95.97,44.92 96.07,45.02 96.07,53.24 93.09,56.22 93.09,70.26 95,72.17 95,73.78 86.85,81.94 86.85,94.37 84.72,96.5 84.72,97.52 83.42,98.81 78.09,98.81 v3(78.01,98.73)
  BOTTOM w0.102: RE80.2 126.63,24.73 127.35,25.46 127.39,25.46 127.64,25.71 127.64,25.71 128.02,26.09 128.02,26.84 129.14,27.96 129.14,32.52 128.35,33.3 v3(128.35,33.2)
ACOFF: length 115.8
  TOP w0.102: PQ713.5 21.9,31.81 22.26,31.45 22.74,31.45 v3(23.15,31.86) ; PR718.1 32.49,38.82 33.1,38.21 33.1,36.5 v1(33.88,35.72) 34.52,35.08 v3(34.52,33.13)
  IN1 w0.114: v3(34.52,33.13) 27.64,33.13 27.08,32.57 23.86,32.57 v3(23.15,31.86)
  IN2 w0.127: v3(111.28,16.44) 110.52,16.44 109.68,17.28 107.68,17.28 101.15,23.8 96.1,23.8 85.93,33.97 85.27,33.97 82.54,36.71 77.56,36.71 75.35,34.5 71.99,34.5 65.57,28.08 45.5,28.08 41.6,31.98 35.67,31.98 v3(34.52,33.13)
  BOTTOM w0.102: v3(111.28,16.44) 110.79,15.95 UE1.27
ACSETIN: length 6.3
  TOP w0.254: v3(48.52,16.72) 48.19,16.39 48.19,15.52 v3(47.91,15.24) 47.72,15.06 PC712.2 47.27,15.05 PR715.2
  BOTTOM w0.102: v3(48.52,16.72) v1(48.52,17.31)
  BOTTOM w0.254: v3(48.52,16.72) 48.88,16.36 PR711.1 ; PU700.2 47.83,15.33 v3(47.91,15.24)
AD_BID0: length 6.4
  BOTTOM w0.102: UE1.66 109.19,31.43 108.79,31.83 107.52,31.83 v1(107.26,32.09) 106.86,32.49 CE8.1 RE3.1 RE5.2
ADP_I: length 129.5
  TOP w0.102: v3(110.8,23.04) v1(111.5,23.04)
  IN1 w0.114: v3(47.62,9.03) 47.62,9.3 53.5,15.19 53.5,26.28 55.42,28.2 65.61,28.2 70.67,33.25 75.22,33.25 75.6,32.87 75.6,32.17 76.82,30.94 79.83,30.94 81.73,32.84 82.88,32.84 89.74,25.98 96.06,25.98 106.38,15.65 107.6,15.65 109.28,17.33 110.06,17.33 111.05,18.32 111.05,22.79 v3(110.8,23.04)
  IN3 w0.135: v3(107.86,31.22) 107.88,31.2 107.88,31.2 108.29,30.79 121.3,30.79 121.68,31.17 125.81,31.17 126.32,30.66 v3(126.93,30.66)
  BOTTOM w0.102: v3(126.93,30.66) 126.8,30.66 PR23.2 ; v3(110.8,23.04) 110.8,24.95 109.66,26.09 108.77,26.09 108.26,26.6 108.26,27.36 108.79,27.89 UE1.65 108.79,31.39 108.66,31.51 108.15,31.51 v3(107.86,31.22)
  BOTTOM w0.254: PR722.1 46.91,9.02 PC725.2 v3(47.62,9.03)
ADPIN: length 0.8
  TOP w0.102: 22.6,117.87 22.6,117.82 v4(23.09,117.33)
  vias: v2(17.99,119.16) v2(18.5,120.45) v2(18.65,119.79) v2(18.7,119.13) v2(19.18,120.43) v2(19.34,119.79) v2(19.41,119.13) v2(19.87,120.43) v2(20,119.79) v2(20.07,119.16) v2(20.91,119.41) v2(21.8,119.41) v4(16.95,118.41) v4(18.1,120.02)
ALLOW_STOP: length 153.5
  TOP w0.102: v3(171.1,89.03) 170.92,89.21 R24.2 170.92,90.58 Q3.3
  IN2 w0.127: v3(164,12.47) 165.51,12.47 166.05,13.01 166.05,16.82 166.3,17.07 166.68,17.07 167.24,17.63 167.24,18.06 169.86,20.68 171.23,20.68 171.38,20.53 175.21,20.53 176.33,19.4 176.33,9.06 177.52,7.88 186.67,7.88 187.13,8.34 187.13,12.7 185.58,14.25 185.58,20.53 184.82,21.29 184.82,24 185.6,24.78 185.6,29.71 186.37,30.47 186.37,34.27 188.73,36.63 191.51,36.63 195.89,41.01 195.89,52.19 196.72,53.02 196.72,68.79 193.93,71.57 193.93,73.16 195.13,74.35 195.13,77.92 194.95,78.1 194.95,81.72 192.26,84.41 190.43,84.41 v3(189.02,85.82)
  BOTTOM w0.102: v3(189.02,85.82) 188.15,86.69 174.12,86.69 v1(172.74,88.08) 171.79,89.03 v3(171.1,89.03) ; U2.G25 164.4,12.08 v3(164,12.47)
APU_ALERT#: length 23.3
  TOP w0.102: T126.1 164.67,97.72 166.23,97.72 RP2.6 166.45,97.71 166.76,98.02 166.76,98.38 166.15,98.99 161.85,98.99 161.45,98.58 159.25,98.58 158.5,97.83 158.5,97.25 158.31,97.06 153.23,97.06 152.16,98.12 149.78,98.12 v3(148.96,97.31)
  BOTTOM w0.102: v3(148.96,97.31) 148.49,97.31 UC1.AN15
APU_ALERT#_EC: length 6.7
  BOTTOM w0.102: T128.1 124.52,33.46 124.52,32.11 124.01,31.6 124.01,29.43 124.09,29.35 124.09,28.68 123.59,28.19 UE1.99
APU_ALERT#_FCH: length 9.9
  BOTTOM w0.102: T127.1 140.08,17.95 142.04,17.95 142.39,18.3 RPH1.4 142.88,18.14 143.5,18.14 144.21,17.43 146.07,17.43 146.18,17.33 147.67,17.33 147.96,17.04 147.96,16.91 U2.M6
APU_ALLOW_STOP: length 34.8
  TOP w0.102: C53.1 R24.1 171.84,92.05 Q3.1 172.17,93.12 v3(171.94,93.35) ; RP2.5 165.55,98.21 v3(165.28,98.48) 164.98,98.17 v1(160.94,98.17) 159.42,98.17 158.91,97.67 158.91,97.08 158.48,96.65 153.06,96.65 151.99,97.72 150.03,97.72 v3(149.62,97.31)
  IN3 w0.102: v3(171.94,93.35) 169.53,95.76 168,95.76 v3(165.28,98.48)
  BOTTOM w0.102: UC1.AM15 147.87,97.5 148.17,97.8 148.43,97.8 148.51,97.72 149.22,97.72 v3(149.62,97.31)
APU_COREYYPE: length 10.2
  BOTTOM w0.102: UC1.D16 125.15,96.35 124.17,96.35 123.89,96.06 123.89,95.84 123.51,95.46 121.16,95.46 v1(119.03,93.32)
  BOTTOM w0.203: v1(119.03,93.32) 118.98,93.32 117.76,92.1 R32.1
APU_DBRDY: length 37.9
  TOP w0.102: v3(98,84.23) 97.25,83.48 JHDT1.14
  BOTTOM w0.102: v3(98,84.23) 97.59,84.64 v1(97.59,87.09) 97.59,90.26 102.39,95.05 107.42,95.05 109.88,97.51 117.17,97.51 119,99.34 121.04,99.34 121.19,99.19 121.42,99.19 121.62,98.99 122.62,98.99 122.73,99.1 UC1.A13
APU_DBREQ#: length 45.2
  TOP w0.102: RP1.1 99.94,92.03 v3(100.3,92.39) 100.12,92.57 v1(98.76,92.57) 96.03,92.57 94.82,91.37 94.82,82.53 95.14,82.21 JHDT1.16
  BOTTOM w0.102: UC1.B13 124,98.8 123.37,98.8 123.31,98.86 122.78,98.86 122.71,98.78 121.54,98.78 121.33,98.99 121.11,98.99 120.98,99.11 119.06,99.11 117.06,97.11 110.05,97.11 106.6,93.65 101.56,93.65 v3(100.3,92.39)
APU_DP2_N0: length 111.4
  IN1 w0.114: v3(193.22,89.56) 193.02,89.77 189.87,89.77 179.15,100.49 179.15,111.79 177.22,113.72 177.22,114.1 174.81,116.51 173.41,116.51 172.8,117.12 168.17,117.12 167.87,117.43 165.86,117.43 162.1,121.19 147.72,121.19 144.82,118.29 144.29,118.29 144.17,118.18 144.17,117.59 143.92,117.34 143.54,117.34 143.31,117.58 143.31,118.18 143.2,118.29 142.97,118.29 142.85,118.18 142.85,117.58 142.62,117.34 142.22,117.34 141.99,117.58 141.99,118.18 141.87,118.29 141.65,118.29 141.53,118.18 141.53,117.58 141.3,117.34 140.9,117.34 140.67,117.58 140.67,118.18 140.55,118.29 140.33,118.29 140.21,118.18 140.21,117.58 139.98,117.34 139.58,117.34 139.35,117.58 139.35,118.18 139.23,118.29 139,118.29 138.89,118.18 138.89,117.58 138.66,117.34 138.26,117.34 138.03,117.58 138.03,118.18 137.91,118.29 137.68,118.29 137.57,118.18 137.57,117.58 137.34,117.34 136.94,117.34 136.71,117.58 136.71,118.18 136.59,118.29 136.36,118.29 136.25,118.18 136.25,117.58 136.02,117.34 135.62,117.34 135.39,117.58 135.39,118.18 135.27,118.29 135.04,118.29 134.93,118.18 134.93,117.58 134.69,117.34 134.3,117.34 134.06,117.58 134.06,118.18 133.95,118.29 133.72,118.29 133.61,118.18 133.61,117.15 133.36,116.9 132.96,116.9 132.74,117.12 132.74,118.18 132.63,118.29 132.14,118.29 132.03,118.18 132.03,117.78 131.74,117.49 129.5,117.49 129.12,117.11 127.76,117.11 126.86,116.21 123.7,116.21 123.42,116.49 123.42,116.67 v3(123.2,116.9)
  BOTTOM w0.102: v3(123.2,116.9) 123.42,116.67 123.42,114.1 CV185.2 ; v3(193.22,89.56) 193.4,89.74 193.89,89.74 CX18.1
APU_DP2_N1: length 110
  IN1 w0.114: v3(121.57,116.95) 121.72,116.79 121.72,116.12 122.43,115.42 127.76,115.42 128.35,114.83 134,114.83 135.18,116.01 141.42,116.01 142.03,116.62 144.24,116.62 148.02,120.4 161.82,120.4 166.59,115.64 167.87,115.64 168.24,116.01 171.47,116.01 172.06,115.42 174.42,115.42 177.88,111.96 177.88,107.78 178.42,107.24 178.42,99.21 179.48,98.14 179.48,97.98 178.3,96.81 178.3,96.48 178.59,96.2 178.92,96.2 180.09,97.37 180.25,97.37 180.41,97.21 180.41,97.05 179.24,95.87 179.24,95.54 179.52,95.26 179.85,95.26 181.03,96.44 181.19,96.44 181.35,96.28 181.35,96.11 180.17,94.94 180.17,94.61 180.46,94.33 180.79,94.33 181.96,95.5 182.12,95.5 191.41,86.21 192.92,86.21 v3(193.12,86.01)
  BOTTOM w0.102: CX16.1 193.89,86.18 193.29,86.18 v3(193.12,86.01) ; v3(121.57,116.95) 121.71,116.81 121.71,116.58 CV187.2
APU_DP2_N2: length 108.1
  IN1 w0.114: v3(120.03,114.71) 120.2,114.55 120.2,114.12 121.14,113.17 143.45,113.17 148.72,118.44 158.39,118.44 158.85,117.99 160.31,117.99 165.66,112.63 168.23,112.63 168.84,113.24 174.53,113.24 176.26,111.51 176.26,105.42 175.88,105.04 175.88,102.42 176.59,101.71 176.59,90.12 187.61,79.1 192.69,79.1 v3(192.92,78.87)
  BOTTOM w0.102: CV189.2 120.15,114.25 120.15,114.6 v3(120.03,114.71) ; v3(192.92,78.87) 193.12,79.07 193.89,79.07 CX14.1
APU_DP2_N3: length 109.7
  IN1 w0.114: v3(117.74,117.05) 117.89,116.9 117.89,116.46 118.36,115.98 120.39,115.98 122.35,114.02 134.51,114.02 135.7,115.22 141.69,115.22 142.14,114.76 144,114.76 148.8,119.56 161.41,119.56 166.49,114.48 174.32,114.48 177.15,111.65 177.15,107.41 177.53,107.03 177.53,96.28 177.32,96.08 177.32,90.81 185.5,82.63 192.79,82.63 v3(193,82.43)
  BOTTOM w0.102: CV191.2 117.86,116.54 117.86,116.92 v3(117.74,117.05) ; CX12.1 193.89,82.62 193.19,82.62 v3(193,82.43)
APU_DP2_P0: length 111.4
  IN1 w0.114: v3(193.22,90.17) 193.02,89.97 189.96,89.97 179.36,100.57 179.36,111.87 177.43,113.8 177.43,114.19 174.89,116.72 173.5,116.72 172.89,117.33 168.26,117.33 167.95,117.63 165.94,117.63 162.19,121.39 147.63,121.39 144.74,118.5 144.2,118.5 143.97,118.26 143.97,117.68 143.84,117.55 143.63,117.55 143.51,117.66 143.51,118.26 143.28,118.5 142.88,118.5 142.65,118.26 142.65,117.66 142.54,117.55 142.31,117.55 142.19,117.66 142.19,118.26 141.96,118.5 141.56,118.5 141.33,118.26 141.33,117.66 141.21,117.55 140.99,117.55 140.87,117.66 140.87,118.26 140.64,118.5 140.24,118.5 140.01,118.26 140.01,117.66 139.89,117.55 139.66,117.55 139.55,117.66 139.55,118.26 139.32,118.5 138.92,118.5 138.69,118.26 138.69,117.66 138.57,117.55 138.34,117.55 138.23,117.66 138.23,118.26 138,118.5 137.6,118.5 137.37,118.26 137.37,117.66 137.25,117.55 137.02,117.55 136.91,117.66 136.91,118.26 136.68,118.5 136.28,118.5 136.05,118.26 136.05,117.66 135.93,117.55 135.7,117.55 135.59,117.66 135.59,118.26 135.36,118.5 134.96,118.5 134.72,118.26 134.72,117.66 134.61,117.55 134.38,117.55 134.27,117.66 134.27,118.26 134.03,118.5 133.64,118.5 133.4,118.26 133.4,117.23 133.27,117.1 133.05,117.1 132.95,117.2 132.95,118.26 132.71,118.5 132.05,118.5 131.83,118.27 131.83,117.86 131.66,117.7 129.42,117.7 129.04,117.31 127.68,117.31 126.78,116.41 123.79,116.41 123.63,116.57 123.63,116.69 v3(123.83,116.9)
  BOTTOM w0.102: v3(123.83,116.9) 123.64,116.7 123.64,114.55 123.81,114.38 124.11,114.38 124.26,114.23 CV184.2 ; CX19.1 193.89,89.95 193.45,89.95 v3(193.22,90.17)
APU_DP2_P1: length 110
  IN1 w0.114: v3(193.12,86.62) 192.92,86.42 191.5,86.42 182.21,95.71 181.88,95.71 180.7,94.53 180.54,94.53 180.38,94.69 180.38,94.85 181.55,96.03 181.55,96.36 181.27,96.64 180.94,96.64 179.77,95.47 179.6,95.47 179.44,95.63 179.44,95.79 180.62,96.96 180.62,97.29 180.34,97.58 180.01,97.58 178.83,96.4 178.67,96.4 178.51,96.56 178.51,96.72 179.68,97.9 179.68,98.23 178.62,99.29 178.62,107.33 178.09,107.86 178.09,112.04 174.5,115.63 172.14,115.63 171.55,116.21 168.16,116.21 167.78,115.84 166.67,115.84 161.91,120.6 147.94,120.6 144.15,116.82 141.94,116.82 141.33,116.21 135.1,116.21 133.92,115.03 128.44,115.03 127.84,115.63 122.51,115.63 121.93,116.21 121.93,116.72 v3(122.17,116.96)
  BOTTOM w0.102: CX17.1 193.89,86.4 193.34,86.4 v3(193.12,86.62) ; CV186.2 122.13,116.21 121.93,116.41 121.93,116.74 122.14,116.96 v3(122.17,116.96)
APU_DP2_P2: length 108.1
  IN1 w0.114: v3(120.65,114.71) 120.61,114.71 120.4,114.51 120.4,114.2 121.23,113.38 143.37,113.38 148.64,118.65 158.48,118.65 158.93,118.19 160.39,118.19 165.75,112.83 168.15,112.83 168.76,113.44 174.61,113.44 176.46,111.59 176.46,105.34 176.08,104.96 176.08,102.5 176.79,101.79 176.79,90.21 187.69,79.3 192.74,79.3 v3(192.92,79.48)
  BOTTOM w0.102: CX15.1 193.89,79.28 193.12,79.28 v3(192.92,79.48) ; CV188.2 120.55,113.92 120.35,114.13 120.35,114.42 v3(120.65,114.71)
APU_DP2_P3: length 109.7
  IN1 w0.114: v3(193,83.04) 192.79,82.83 185.59,82.83 177.53,90.89 177.53,95.99 177.73,96.19 177.73,107.12 177.35,107.5 177.35,111.74 174.4,114.69 166.58,114.69 161.5,119.77 148.71,119.77 143.91,114.96 142.23,114.96 141.77,115.42 135.62,115.42 134.42,114.23 122.43,114.23 120.48,116.18 118.45,116.18 118.09,116.54 118.09,116.82 118.32,117.05 v3(118.35,117.05)
  BOTTOM w0.102: CV190.2 118.29,116.21 118.08,116.43 118.08,116.81 118.32,117.05 v3(118.35,117.05) ; v3(193,83.04) 193.19,82.84 193.89,82.84 CX13.1
APU_EDP0_AUXN: length 26.6
  TOP w0.102: RC9.2 147.14,101.62 144.01,101.62 143.83,101.79 143.83,101.92 143.97,102.06 v3(144.18,102.06)
  IN3 w0.135: v3(152.33,110.82) 152.49,110.66 152.86,110.66 153.18,110.34 153.18,109.07 152.32,108.21 144.2,108.21 142.21,106.22 142.21,103.2 142.54,102.87 143.63,102.87 143.99,102.52 143.99,102.25 v3(144.18,102.06)
  BOTTOM w0.102: v3(152.33,110.82) 152.53,110.62 152.79,110.62 153.02,110.85 C4322.2 ; UC1.AG10 143.9,101.78 v3(144.18,102.06)
APU_EDP0_AUXP: length 26.5
  TOP w0.102: v3(143.47,102.11) 143.62,101.96 143.62,101.71 143.92,101.4 RC8.2
  IN3 w0.135: v3(143.47,102.11) 143.62,102.11 143.74,102.24 143.74,102.42 143.53,102.63 142.44,102.63 141.97,103.1 141.97,106.32 144.1,108.45 152.22,108.45 152.94,109.17 152.94,110.24 152.76,110.42 152.48,110.42 152.36,110.29 v3(152.36,110.2)
  BOTTOM w0.102: C4321.2 153.02,110.24 152.84,110.42 152.51,110.42 152.36,110.27 v3(152.36,110.2) ; UC1.AG8 143.9,102.37 143.64,102.11 v3(143.47,102.11)
APU_EDP0_TXN0: length 13.2
  BOTTOM w0.102: C4311.1 153.35,112.63 153.42,112.55 154.03,112.55 154.15,112.44 154.15,112.23 153.83,111.92 v2(153.21,111.92) 152.43,111.92 150.81,110.29 150.81,108.11 150.04,107.34 150.04,106.2 149.13,105.29 148.54,105.29 148.43,105.17 148.18,105.17 148.1,105.25 147.59,105.25 147.5,105.34 UC1.AM5
APU_EDP0_TXN1: length 9.5
  BOTTOM w0.102: C4313.1 151.72,112.6 151.72,112.48 149.74,110.49 149.74,108.92 149.14,108.32 149.14,106.24 148.85,105.95 148.29,105.95 147.94,106.3 UC1.AM4
APU_EDP0_TXP0: length 13.2
  BOTTOM w0.102: C4312.1 154.36,112.14 153.93,111.71 153.53,111.71 153.5,111.69 152.91,111.69 152.88,111.71 152.53,111.71 151.02,110.2 151.02,108.02 150.26,107.26 150.26,106.11 149.22,105.07 148.63,105.07 148.52,104.96 148.09,104.96 148.01,105.03 147.43,105.03 UC1.AL6
APU_EDP0_TXP1: length 9.5
  BOTTOM w0.102: C4314.1 151.94,112.62 151.94,112.39 149.95,110.4 149.95,108.83 149.36,108.23 149.36,106.15 148.94,105.73 148.36,105.73 148.3,105.67 UC1.AN5
APU_ENVDD: length 117
  TOP w0.102: v3(10.6,84.05) 10.88,84.05 11.31,84.48 11.31,85.35 10.93,85.73 RX7.2 ; v3(96.14,99.12) 96.14,99.14 v1(98.1,101.1) 100.31,101.1 100.91,100.5 RP16.8 102.3,100.5 103.94,98.86 U67.4
  IN2 w0.127: v3(96.14,99.12) 95.08,100.18 78.2,100.18 76.89,101.49 72.71,101.49 72.04,102.16 69.53,102.16 66.76,104.93 66.2,104.93 64.6,106.53 60.46,106.53 59.28,105.35 57.21,105.35 56.6,104.74 53.75,104.74 53.09,105.4 51.43,105.4 50.71,106.13 45.04,106.13 43.31,107.85 37.8,107.85 37.37,107.42 31.38,107.42 27.41,103.46 24.57,103.46 15.02,93.91 13.74,93.91 10.6,90.77 v3(10.6,84.05)
APU_HDMI_CLK: length 145.7
  IN3 w0.135: v3(196.54,77.09) 196.5,77.05 195.4,77.05 194.98,77.47 194.98,90.15 192.54,92.59 190.3,92.59 182.6,100.29 179.94,100.29 178.39,101.84 178.39,106.98 177.64,107.73 177.64,112.44 172.95,117.12 168.56,117.12 167.82,117.86 159.96,117.86 156.18,114.08 147.31,114.08 145.98,115.4 145.31,115.4 142.89,117.82 129.32,117.82 128.91,117.42 127.87,117.42 127.48,117.81 126.12,117.81 125.34,117.03 124.85,117.03 121.03,113.22 115.77,113.22 110.74,108.19 110.74,102.7 v3(110.46,102.42)
  BOTTOM w0.102: RP60.1 196.36,77.13 196.41,77.09 v3(196.54,77.09) 196.78,77.33 QX4.1 ; v3(110.46,102.42) 110.58,102.29 117.16,102.29 119.54,104.68 122.51,104.68 122.82,104.37 123.22,104.37 123.35,104.5 123.7,104.5 UC1.B6
APU_HDMI_DATA: length 149.8
  IN3 w0.135: v3(199.27,75.65) 199.17,75.75 198.17,75.75 197.26,76.65 v3(197.22,76.65) 197.26,76.61 195.22,76.61 194.54,77.29 194.54,89.97 192.36,92.15 190.12,92.15 182.42,99.85 179.76,99.85 177.95,101.66 177.95,106.79 177.2,107.55 177.2,112.26 172.77,116.68 168.38,116.68 167.64,117.42 160.15,117.42 156.36,113.64 147.13,113.64 145.8,114.96 145.13,114.96 142.71,117.38 129.5,117.38 129.09,116.98 127.69,116.98 127.29,117.37 126.3,117.37 125.52,116.6 125.03,116.6 121.21,112.78 115.96,112.78 111.18,108.01 111.18,102.52 110.44,101.78 v3(110.43,101.78)
  BOTTOM w0.102: v3(199.27,75.65) 199.06,75.43 QX4.4 ; v3(197.22,76.65) 197.24,76.63 RP60.2 ; UC1.B7 123.9,104.3 123.45,104.3 123.32,104.17 122.61,104.17 122.51,104.27 119.69,104.27 117.3,101.88 110.53,101.88 v3(110.43,101.78)
APU_INVT_PWM: length 136.3
  TOP w0.102: U68.4 104.45,93.53 v1(101.09,96.89) RP16.5 100.83,99 100.36,98.53 97.77,98.53 v3(97.39,98.91) ; RX26.1 2.93,81.46 v3(2.89,81.5)
  IN2 w0.127: v3(2.89,81.5) 2.53,81.5 1.99,82.05 1.99,95.46 2.37,95.84 6.46,95.84 8.34,97.72 17.28,97.72 23.6,104.04 27.26,104.04 31.18,107.95 37.17,107.95 39.12,109.91 57.18,109.91 57.74,109.35 59.3,109.35 59.86,109.91 66.57,109.91 67.68,108.79 67.68,105.76 71.03,102.42 72.15,102.42 72.82,101.74 77,101.74 78.31,100.44 95.87,100.44 v3(97.39,98.91)
  BOTTOM w0.102: JEDP.36 v3(2.89,81.5)
APU_PCIE_RST#: length 103.4
  TOP w0.102: UV2.1 78.18,77.39 81.21,74.36 81.21,73.12 81.39,72.94 v1(82.34,72.94) 85.03,72.94 86.32,74.22 93.45,74.22 v3(94.29,73.38)
  IN1 w0.102: v3(135.08,33.63) 135.08,35.21 132.85,37.44 128.05,37.44 126.63,38.87 124.91,38.87 123.96,39.81 96.08,39.81 93.25,42.64 93.25,66.2 93.94,66.88 93.94,73 94.32,73.38 v3(94.29,73.38)
  BOTTOM w0.102: UH1.4 140.48,33.52 RH28.2 RH27.1 138.14,33.2 135.52,33.2 v3(135.08,33.63)
APU_PCIE_RST#_C: length 6.1
  BOTTOM w0.102: U2.AE2 146.37,26.9 146.13,26.9 143.28,29.76 RH25.1 v1(142.99,30.76)
APU_PROCHOT#: length 488.1
  TOP w0.102: v3(31.02,37.04) 30.77,37.29 PC728.1 ; v3(169.27,94.7) 168.69,94.11 168.69,92.81 166.96,91.09 QC1.1 166.86,90.78 R29.1 166.86,88.57 v1(168.27,87.16) 180.75,74.68 v3(181.74,74.68) ; v3(151.21,102.26) 152.1,101.38 152.1,101.17 152.32,100.95 153.04,100.95 R33.1 ; PQ2.6 32.06,112.31 v3(31.6,111.85)
  IN1 w0.102: v3(31.02,37.04) 29.95,38.1 27.62,38.1 9.56,56.16 9.56,57.94 11.23,59.61 11.23,69.07 9.58,70.72 9.58,71.71 9.12,72.17 9.12,80.37 8.71,80.78 8.71,91.39 11.13,93.81 13.49,93.81 20.07,100.39 22.48,100.39 25.79,103.69 33.43,103.69 36.46,106.71 36.46,107.22 37.99,108.75 43.32,108.75 v3(43.64,109.07) ; v3(168.97,3.04) 168.97,4.47 169.6,5.1 176.95,5.1 178.71,6.87 187.45,6.87 192.8,12.22 195.46,12.22 198.18,14.94 198.18,15.35 197.9,15.63 197.08,15.63 196.23,14.77 194.77,14.77 194.59,14.95 194.41,14.95 193.4,15.96 191.05,15.96 188.1,18.91 187.2,18.91 186.52,19.59 186.52,21.14 184.99,22.67 184.99,24.57 185.98,25.56 185.98,29.95 186.54,30.51 186.54,35.67 188.04,37.16 188.04,41.28 190.68,43.92 190.68,48.06 196.81,54.18 196.81,65.59 198.25,67.03 198.25,72.19 196.78,73.66 193.54,73.66 193.08,74.12 182.3,74.12 v3(181.74,74.68) ; v3(169.27,94.7) 169.27,95.33 167.35,97.25 163.85,97.25 158.41,102.7 151.64,102.7 v3(151.21,102.26) 147.07,102.26 v3(146.92,102.11)
  IN3 w0.102: v3(31.02,37.04) 32.35,38.37 45.48,38.37 45.59,38.26 45.59,34.18 52.42,27.34 66.88,27.34 68.85,25.38 74.49,25.38 77.36,22.51 88.48,22.51 88.89,22.92 96.39,22.92 96.84,22.47 100.38,22.47 101.83,21.01 101.83,20.17 108.02,13.99 109.18,13.99 111.03,12.14 111.03,10.58 112.92,8.69 120.01,8.69 120.31,8.4 124.63,8.4 125.72,7.31 126.96,7.31 128.22,6.05 129.38,6.05 130.76,4.67 132.46,4.67 134.1,3.04 136.66,3.04 137.03,2.67 145.39,2.67 145.97,3.26 147.96,3.26 148.43,2.79 153.12,2.79 153.56,3.23 156.82,3.23 157.54,3.95 161.69,3.95 162.34,3.3 164.2,3.3 164.24,3.34 168.67,3.34 v3(168.97,3.04) ; v3(43.64,109.07) 41.74,109.07 40.54,110.27 33.98,110.27 32.39,111.85 v3(31.6,111.85)
  BOTTOM w0.102: UC1.AL10 146.92,101.68 v3(146.92,102.11) ; v3(168.97,3.04) 168.67,3.04 168.23,3.48 168.23,4.02 RH18.2 ; v3(43.64,109.07) 47.22,112.65 51.59,112.65 52.99,111.26 53.9,111.26 55.43,109.73 59.62,109.73 PR539.1
APU_PROCHOT#_R: length 6.1
  BOTTOM w0.102: U2.E28 166.95,10.37 167.42,9.9 167.81,9.9 168.12,9.58 168.12,6.34 v3(167.9,6.11) 167.82,6.04 RH18.1
APU_PWRGD: length 320.7
  TOP w0.102: R446.1 C54.1 153.14,99.17 153.63,98.68 155.58,98.68 158.6,101.71 163.43,101.71 165.59,103.86 165.59,109.11 162.22,112.48 159.52,112.48 158.44,113.56 v3(158.44,113.61) 158.55,113.72 R40.2 ; v3(96.12,98.3) v1(97.54,96.89) 99.51,94.91 100.27,94.91 100.86,94.32 101.37,94.32 102.36,93.34 102.36,92.83 104.2,90.99 R37.2 104.5,88.31 103.75,87.56 D29.2 ; PU500.19 59.54,113.36 59.53,113.36 59.24,113.36 v3(58.86,112.98)
  IN1 w0.102: v3(96.12,98.3) 95.69,98.73 91.57,98.73 89.31,100.99 73.87,100.99 71.21,103.65 71.21,106.98 67.62,110.57 66.94,110.57 65.87,111.64 62.48,111.64 60.62,113.49 59.37,113.49 v3(58.86,112.98)
  IN3 w0.102: v3(166.43,10.88) 166.43,10.72 166.99,10.16 170.48,10.16 171.93,8.72 175.62,8.72 176.36,9.45 176.36,10.12 179.58,13.34 179.58,14.79 179.03,15.34 179.03,22.78 179.36,23.11 179.36,34.39 186.05,41.08 186.62,41.08 187.89,42.35 187.89,52.38 187.38,52.89 187.38,58.2 187,58.58 187,61.22 186.42,61.8 186.42,65.24 187.15,65.98 187.15,91.17 181.09,97.24 180.17,97.24 176.08,101.32 176.08,106.1 174.55,107.62 169.78,107.62 169.17,108.23 167.67,108.23 163.71,112.2 159.85,112.2 v3(158.44,113.61)
  BOTTOM w0.102: v3(166.43,10.88) 166.4,10.88 165.64,10.11 165.16,10.11 U2.E26 ; v3(96.12,98.3) 96.6,97.82 102.47,97.82 105.86,101.21 108.44,101.21 109.57,102.34 109.57,108.21 109.96,108.6 109.96,114.05 115.35,119.44 142.88,119.44 143.62,120.17 154.74,120.17 158.41,116.5 158.41,113.63 v3(158.44,113.61)
APU_PWRGD_BUF: length 8.5
  TOP w0.102: JHDT1.10 99.54,86.02 R121.1 99.84,86.33 D29.1 100.35,87.56 101.47,86.44 v1(103.09,86.44)
APU_PWRGD_R: length 5.3
  TOP w0.102: v3(146.74,100.44) 147.33,99.85 147.43,99.85 v4(147.48,99.8) 148.04,99.24 R446.2
  BOTTOM w0.102: UC1.AL12 147.1,100.06 146.74,100.42 v3(146.74,100.44)
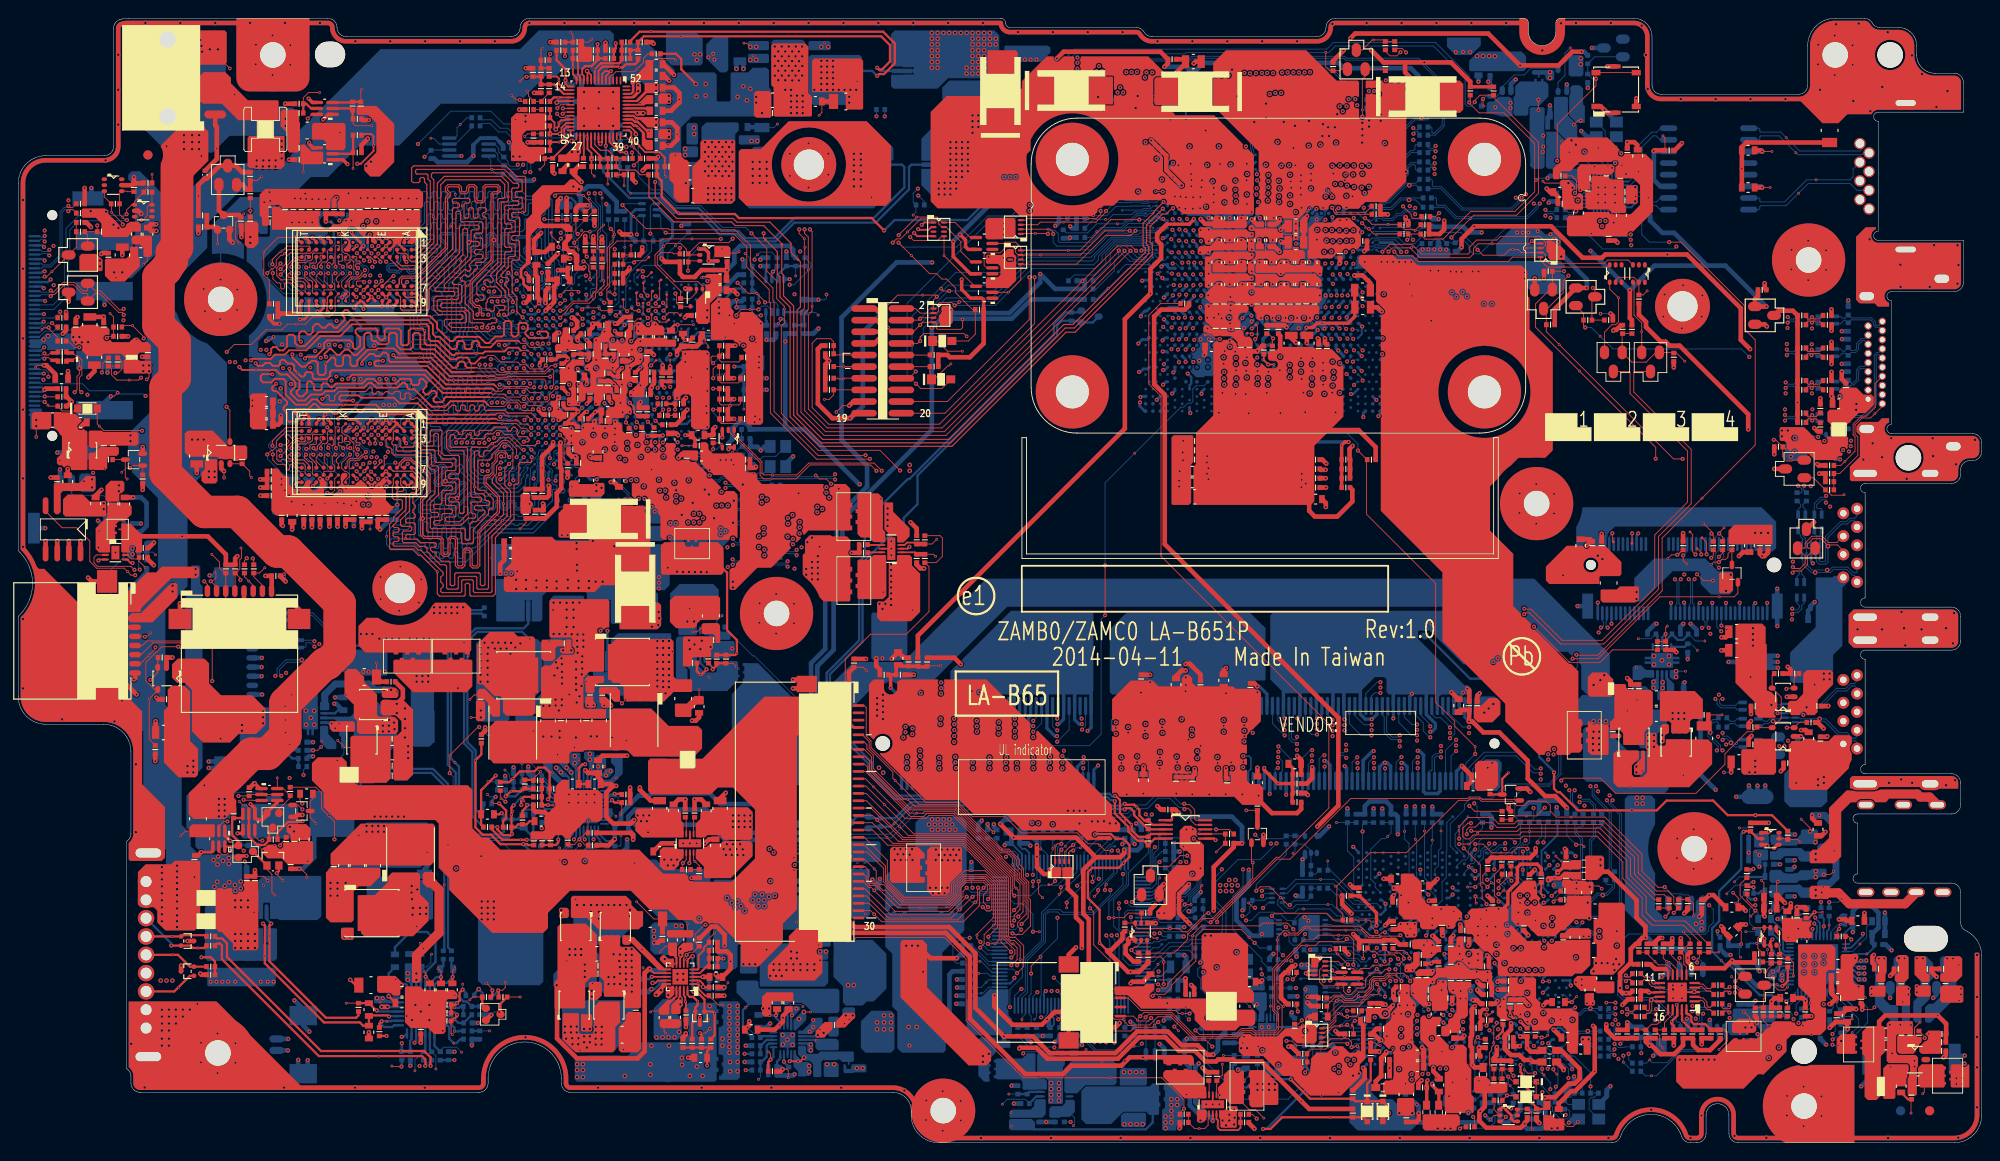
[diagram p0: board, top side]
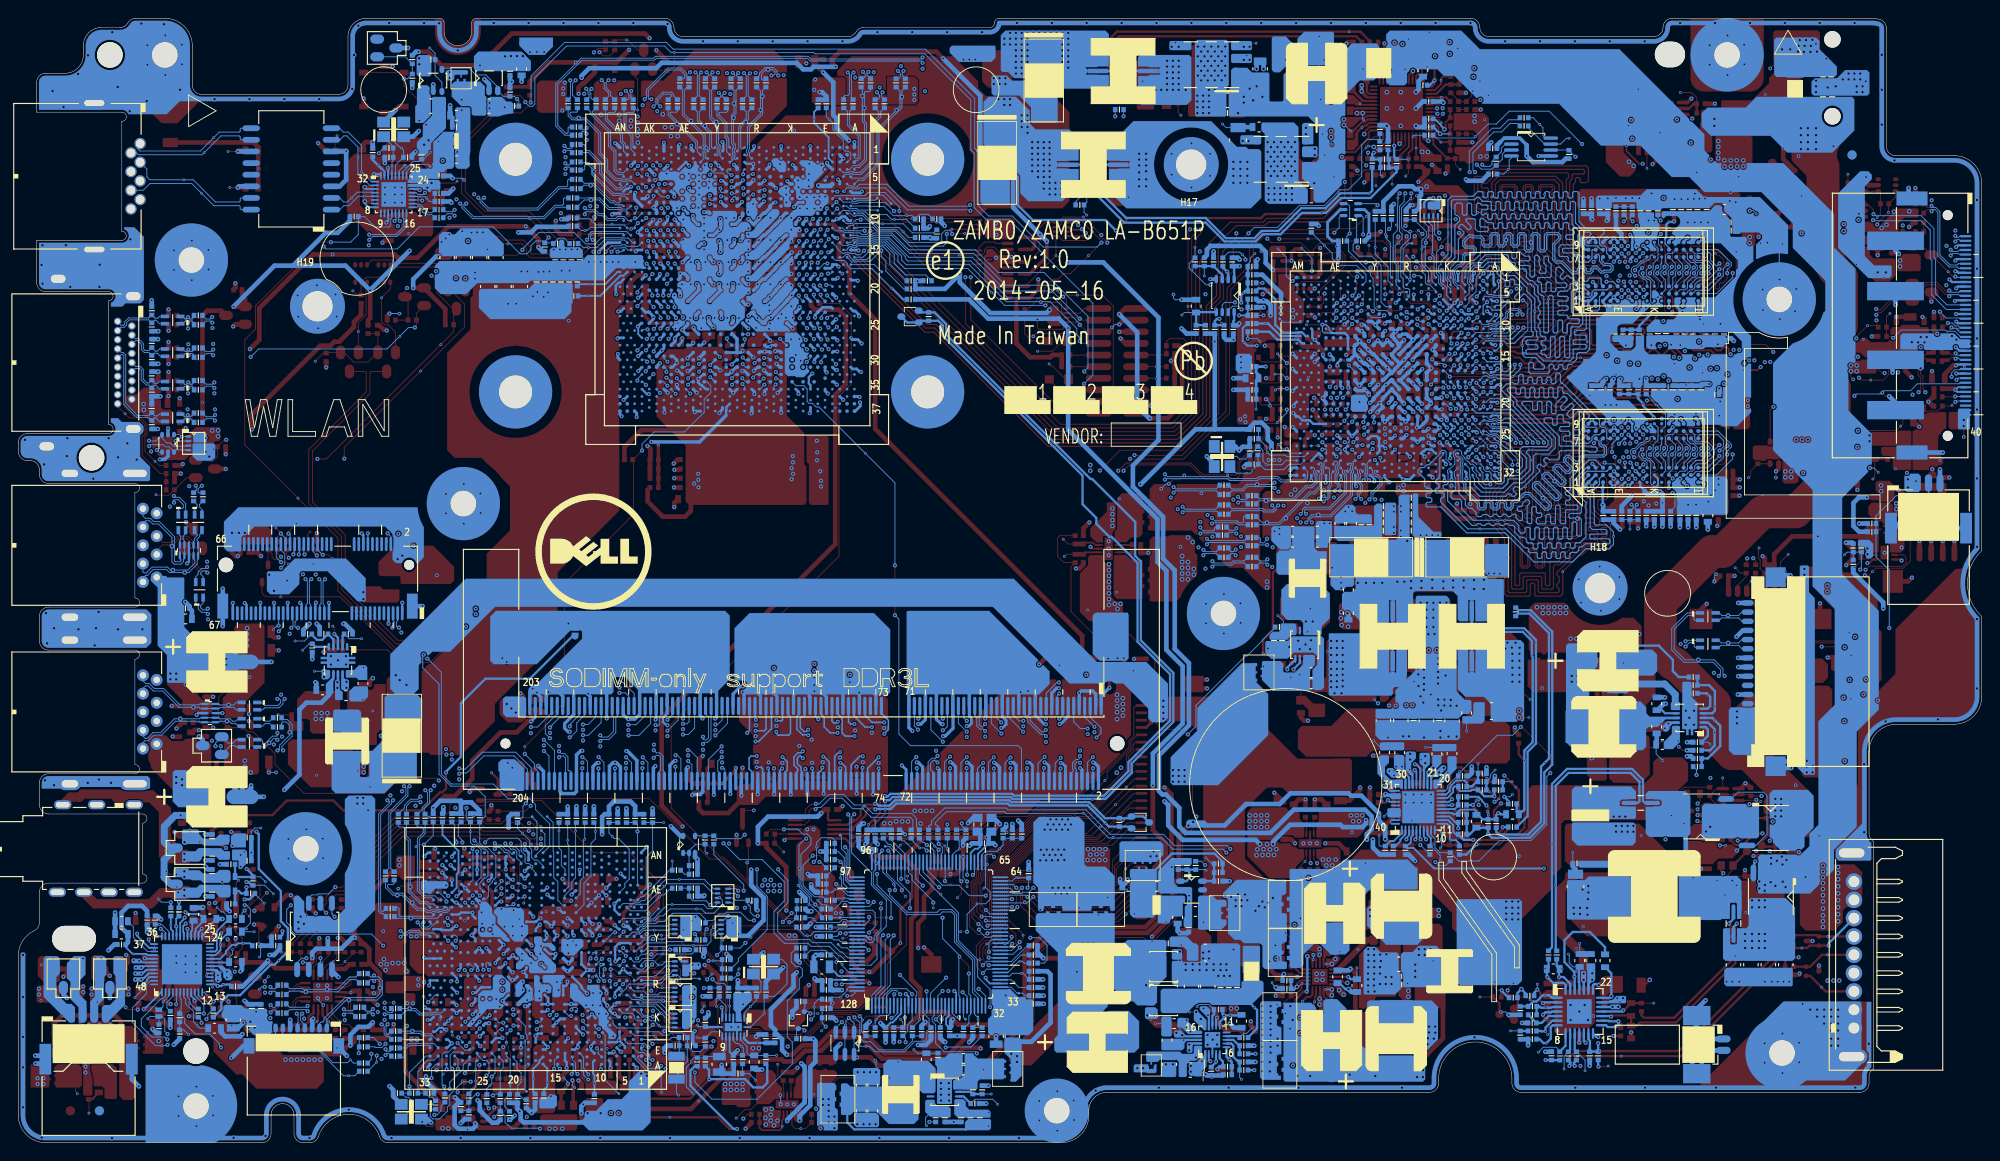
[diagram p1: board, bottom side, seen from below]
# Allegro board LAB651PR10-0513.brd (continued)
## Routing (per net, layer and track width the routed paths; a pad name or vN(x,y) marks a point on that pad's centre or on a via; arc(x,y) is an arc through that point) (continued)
APU_RST#: length 268.2
  TOP w0.102: D30.2 101.82,83.32 100.87,82.38 98.53,82.38 v3(98.02,82.88) ; v3(156.5,98.86) v1(158.55,100.91) 158.93,101.3 163.61,101.3 166,103.69 166,109.28 161.09,114.18 R39.2 159.62,114.41 159.04,113.82 v3(159.04,113.64)
  IN3 w0.102: v3(181.06,97.87) 181.06,97.85 187.56,91.34 187.56,65.81 187.13,65.38 187.13,63.3 187.51,62.92 187.51,58.64 187.79,58.36 187.79,53.06 188.3,52.55 188.3,41.07 187.07,39.85 185.44,39.85 179.79,34.19 179.79,28.58 180.35,28.02 180.35,23.37 179.99,23.02 179.99,17.96 179.65,17.62 179.65,15.39 179.99,15.04 179.99,13.17 176.79,9.97 176.79,9.3 175.8,8.31 171.76,8.31 170.31,9.76 166.3,9.76 v3(165.5,10.56)
  BOTTOM w0.102: v3(181.06,97.87) 180.8,97.62 173.01,97.62 170.59,100.03 162.55,100.03 159.6,97.08 158.87,97.08 158.41,97.54 158.41,97.96 157.89,98.48 157.12,98.48 R36.2 ; R445.1 154.78,98.78 155.4,98.78 155.97,98.22 C55.1 156.05,98.28 R36.2 ; v3(156.5,98.86) 156.91,98.44 R36.2 ; U2.F26 165.5,10.57 v3(165.5,10.56) ; v3(98.02,82.88) 97.06,83.85 97.06,91.67 106.19,100.8 108.69,100.8 110.03,102.14 110.03,108.07 110.38,108.42 110.38,113.89 115.41,118.93 127.41,118.93 127.54,119.05 143.11,119.05 143.82,119.77 154.54,119.77 157.99,116.31 157.99,113.44 158.25,113.19 158.6,113.19 159.04,113.62 v3(159.04,113.64)
APU_RST#_BUF: length 7.4
  TOP w0.102: JHDT1.12 99.54,84.75 R122.1 99.55,83.54 D30.1 100.02,83.37 101.49,84.84 101.62,84.84 v1(101.83,85.06)
APU_RST#_R: length 6
  BOTTOM w0.102: R445.2 153.14,98.2 152.71,97.77 v1(152.15,97.77) 151.22,97.77 150.39,98.6 148.57,98.6 148.55,98.58 148.18,98.58 UC1.AM14
APU_RSVD_1: length 3.7
  BOTTOM w0.102: UC1.A17 120.91,95.9 T12.1
APU_RSVD_2: length 2.8
  TOP w0.102: v3(131.21,87.79) 130.62,87.79 130.19,88.22 T13.1
  BOTTOM w0.102: UC1.K28 130.55,87.1 131.21,87.76 v3(131.21,87.79)
APU_RSVD_15: length 7.8
  TOP w0.102: R27.1 152.61,99.72 151.39,99.72 R28.1 150.81,100.31 v1(149.57,100.31) 147.81,100.31 147.15,100.97 v3(147.06,100.97)
  BOTTOM w0.102: UC1.AK10 146.83,100.97 v3(147.06,100.97)
APU_SIC: length 32.9
  TOP w0.102: v3(159.35,97.51) 159.93,96.93 162.25,96.93 162.88,97.56 v1(163.18,97.56) 163.78,97.56 164.12,97.21 RP2.7 166.5,97.21 166.76,96.96 166.76,96.42 167.14,96.04 173.2,96.04 173.55,96.4 175.79,96.4 Q78.3
  BOTTOM w0.102: UC1.AL14 147.33,98.3 147.82,98.8 148.43,98.8 148.47,98.83 150.73,98.83 151.39,98.18 152.46,98.18 153.7,99.42 157.54,99.42 159.35,97.61 v3(159.35,97.51)
APU_SIC_R: length 8.1
  TOP w0.102: Q78.4 176.43,93.86 176.43,90.38 177.27,89.54 v1(177.27,88.59) Q10.3
APU_SID: length 29.4
  TOP w0.102: Q2507.6 173.54,95.64 166.96,95.64 166.23,96.36 RP2.8 163.17,96.71 162.7,96.24 152.89,96.24 v1(152.64,96.49) 152.28,96.85 150.71,96.85 v3(150.26,97.31)
  BOTTOM w0.102: v3(150.26,97.31) 149.62,97.95 148.62,97.95 148.5,98.07 148.15,98.07 147.97,97.89 146.71,97.89 UC1.AK14
APU_SID_R: length 8.9
  TOP w0.102: Q2507.1 173.78,93.24 v1(174.73,92.28) 174.73,89.64 174.43,89.34 174.02,89.34 173.21,88.52 Q9.3
APU_SVC: length 107.8
  TOP w0.102: v3(86.44,99.75) 86.68,99.51 v1(86.68,91.34) 86.68,90.81 86.28,90.41 86.28,80.12 88.33,78.07 100.88,78.07 120.17,97.36 v3(120.17,97.44) ; PU500.20 v3(59.47,112.96)
  IN1 w0.102: v3(86.44,99.75) 86.44,99.87 85.72,100.59 73.7,100.59 70.8,103.49 70.8,106.11 66.44,110.47 61.7,110.47 59.91,112.26 59.91,112.51 v3(59.47,112.96)
  BOTTOM w0.102: UC1.B16 123.39,96.19 122.89,96.19 122.81,96.27 121.34,96.27 v3(120.17,97.44) 120.17,96.83 119.67,96.32 119.67,95.2 117.71,93.25 R65.2
APU_SVD: length 109.2
  TOP w0.102: v3(59.44,112.37) 59.63,112.56 PU500.21 ; v3(120.79,97.41) 120.79,97.32 101.12,77.65 88.16,77.65 85.87,79.94 85.87,90.58 86.26,90.98 v1(86.26,95.32) 86.26,98.91 85.86,99.32 v3(85.86,99.75)
  IN1 w0.102: v3(85.86,99.75) 85.86,99.88 85.55,100.18 73.53,100.18 70.38,103.34 70.38,105.95 66.27,110.06 61.52,110.06 59.44,112.15 v3(59.44,112.37)
  BOTTOM w0.102: UC1.C16 124.33,96.7 124.03,97 123.77,97 123.6,96.83 123.6,96.76 123.24,96.41 123.24,96.41 123.23,96.4 122.97,96.4 122.9,96.47 121.73,96.47 v3(120.79,97.41) 120.36,97.85 119.93,97.85 119.23,97.15 119.23,95.97 117.4,94.14 R120.2
APU_SVT: length 112
  TOP w0.102: v3(58.83,112.37) 58.83,112.32 59.19,111.97 59.62,111.97 59.81,112.16 PU500.22 ; v3(121.45,97.41) 121.45,97.4 101.29,77.25 87.99,77.25 85.46,79.77 85.46,90.75 85.83,91.12 v1(85.83,98.73) 85.27,99.29 v3(85.27,99.75)
  IN1 w0.102: v3(85.27,99.75) 85.25,99.78 73.36,99.78 69.97,103.17 69.97,105.78 66.1,109.66 61.33,109.66 58.83,112.16 v3(58.83,112.37)
  BOTTOM w0.102: R35.2 115.31,94.77 117.47,94.77 118.75,96.06 118.75,97.03 119.77,98.05 120.61,98.05 120.68,97.97 120.89,97.97 v3(121.45,97.41) 122.16,96.7 UC1.A16
APU_TCK: length 33.4
  TOP w0.102: JHDT1.2 97.98,91.1 98.49,90.6 RP1.2 100.26,90.6 100.49,90.83 100.49,91.65 100.61,91.77 101.91,91.77 v3(102.24,91.44) 102.37,91.44 v4(102.74,91.81)
  BOTTOM w0.102: v3(102.24,91.44) 106.69,91.44 110.72,95.48 117.6,95.48 118.34,96.23 118.34,96.93 119.69,98.28 120.67,98.28 120.77,98.18 121,98.18 121.2,97.97 122.71,97.97 122.89,97.79 123.31,97.79 123.36,97.84 123.64,97.84 123.98,97.5 UC1.B15
APU_TDI: length 37.5
  TOP w0.102: JHDT1.6 97.74,88.56 v3(98.48,89.31) 98.77,89.6 RP1.4 100.12,89.6 100.26,89.46 100.26,88.96 100.39,88.83 102.93,88.83 103.12,89.02 v4(103.12,89.91)
  BOTTOM w0.102: UC1.A14 123.02,98.38 121.37,98.38 121.16,98.58 120.94,98.58 120.84,98.68 119.44,98.68 117.53,96.78 117.53,96.56 117.26,96.3 110.39,96.3 106.35,92.26 101.33,92.26 98.48,89.41 v3(98.48,89.31)
APU_TDO: length 40
  TOP w0.102: JHDT1.8 98.22,87.29 v3(98.48,87.56) 98.48,88 98.86,88.38 103.24,88.38 v4(103.56,88.07)
  BOTTOM w0.102: UC1.C14 124.4,98 123.77,98 123.67,98.1 123.45,98.1 123.45,98.1 123.33,98.1 123.23,98 122.97,98 122.79,98.17 121.28,98.17 121.08,98.38 120.85,98.38 120.75,98.48 119.59,98.48 117.94,96.83 117.94,96.39 117.43,95.89 110.56,95.89 106.52,91.85 101.73,91.85 98.81,88.93 98.81,88.22 98.48,87.89 v3(98.48,87.56)
APU_TEST4: length 1.1
  TOP w0.102: v3(134.71,88.29) 134.58,88.42 T10.1
  BOTTOM w0.102: v3(134.71,88.29) 134.72,88.3 UC1.T27
APU_TEST5: length 2.5
  TOP w0.102: T11.1 135.31,89.16 135.31,88 v3(135.07,87.76)
  BOTTOM w0.102: v3(135.07,87.76) 135.07,87.33 UC1.T28
APU_TEST14: length 9.2
  BOTTOM w0.102: UC1.C10 124.4,101.8 123.77,101.8 123.72,101.76 123.28,101.76 123.23,101.8 122.92,101.8 122.77,101.66 121.88,101.66 121.58,101.36 119.55,101.36 119.03,100.84 v1(118.73,100.84) 117.43,100.84 R15.1
APU_TEST15: length 4
  BOTTOM w0.102: UC1.B9 123.93,102.3 123.63,102 123.37,102 123.33,102.04 122.86,102.04 122.68,101.86 120.58,101.86 T3.1
APU_TEST16: length 10
  BOTTOM w0.102: R16.1 114.43,99.37 116.77,99.37 117.76,100.36 v1(120.02,100.36) 120.58,100.36 121.08,100.86 121.5,100.86 122.1,101.45 123.05,101.45 UC1.A10
APU_TEST17: length 8.6
  BOTTOM w0.102: R17.1 117.14,98.86 v1(117.77,99.49) 118.23,99.95 120.46,99.95 121.16,100.65 121.58,100.65 122.18,101.25 122.92,101.25 122.97,101.2 123.23,101.2 123.53,101.5 UC1.B10
APU_TEST18: length 45.2
  TOP w0.102: v3(113.01,99.24) 113.01,99.45 112.69,99.77 v1(112.45,99.77) 109.48,99.77 RPC1.2 ; v3(110.98,94.52) 110.98,89.45 101.2,79.67 JHDT1.20
  IN3 w0.102: v3(113.01,99.24) 113.01,97.41 110.98,95.38 v3(110.98,94.52)
  BOTTOM w0.102: v3(113.01,99.24) 113.01,98.3 113.39,97.92 117.02,97.92 118.65,99.55 120.63,99.55 121.06,99.98 122.69,99.98 122.76,99.9 UC1.A12
APU_TEST19: length 44.6
  TOP w0.102: v3(110.39,94.52) 110.39,89.89 101.44,80.94 JHDT1.18 ; RPC1.1 109.52,99.31 v1(111.07,99.31) 112.38,99.31 v3(112.43,99.26)
  IN3 w0.102: v3(110.39,94.52) 110.39,95.58 112.43,97.62 v3(112.43,99.26)
  BOTTOM w0.102: v3(112.43,99.26) 112.43,99.37 112.71,99.65 113.18,99.65 113.57,99.26 113.57,98.51 113.75,98.33 117.14,98.33 118.57,99.75 120.55,99.75 121.18,100.39 123.05,100.39 123.24,100.19 123.61,100.19 UC1.B12
APU_TEST20: length 16.6
  TOP w0.102: v3(118.78,101.76) 118.78,101.66 117.66,100.54 v1(114.13,100.54) 111.6,100.54 111.31,100.25 RPC1.3
  BOTTOM w0.102: UC1.C8 124.32,102.72 123.44,102.72 123.31,102.59 122.77,102.59 122.64,102.72 121.45,102.72 121.4,102.67 119.69,102.67 v3(118.78,101.76)
APU_TEST24: length 18
  TOP w0.102: v3(118.19,101.76) 118.19,101.4 117.72,100.93 v1(116.78,100.93) 110.14,100.93 109.96,100.75 RPC1.4
  BOTTOM w0.102: v3(118.19,101.76) 118.19,102.2 119.77,103.78 121.61,103.78 121.95,103.43 125.17,103.43 UC1.D8
APU_TEST25_H: length 6
  BOTTOM w0.102: UC1.AM12 148.23,100.23 151.3,100.23 v1(151.68,100.61) 151.96,100.89 153.31,100.89 R22.1
APU_TEST25_L: length 5.2
  BOTTOM w0.102: R23.1 152.92,99.62 v1(152.53,99.62) 152.29,99.62 151.96,99.95 148.65,99.95 UC1.AN12
APU_TEST28_H: length 4.6
  BOTTOM w0.102: UC1.A8 123.07,103.13 121.63,103.13 121.27,103.5 120,103.5 T4.1
APU_TEST28_L: length 3.6
  BOTTOM w0.102: T5.1 120.83,102.93 122.79,102.93 122.92,102.8 123.23,102.8 123.53,103.1 UC1.B8
APU_TEST31: length 2.7
  TOP w0.102: R25.1 136.49,88.37 v3(137.02,87.84) 136.95,87.76 R26.1
  BOTTOM w0.102: v3(137.02,87.84) 137.02,87.62 UC1.V28
APU_THERMTRIP#: length 26.7
  TOP w0.102: R622.1 149.1,117.25 Q12.3 147.07,116.46 146.77,116.16 v1(146.77,112.79) v3(146.77,112.07)
  IN3 w0.102: v3(146.77,112.07) 144.51,109.81 143.66,109.81 140.52,106.66 140.52,103.64 140.95,103.2 140.95,102.16 141.56,101.55 145.27,101.55 v3(145.83,100.99)
  BOTTOM w0.102: v3(145.83,100.99) 146.12,100.7 UC1.AK11
APU_TMS: length 34
  TOP w0.102: v4(100.77,93.27) 101.02,93.02 v3(101.66,93.02) ; JHDT1.4 98.32,89.83 v3(98.48,90) 98.59,90.1 RP1.3
  BOTTOM w0.102: UC1.B14 123.53,98.3 123.23,98.6 122.95,98.6 122.93,98.58 121.45,98.58 121.25,98.78 121.02,98.78 120.92,98.89 119.33,98.89 117.15,96.7 110.22,96.7 106.54,93.02 v3(101.66,93.02) 101.5,93.02 v3(98.48,90)
APU_TRST#: length 63.2
  TOP w0.102: JHDT1.9 92.35,86.03 89.03,86.03 C936.1 R38.2 89.03,87.48 88.7,87.81 87.18,87.81 86.68,87.32 86.68,80.29 88.5,78.47 100.57,78.47 v4(116.2,94.1) 120.04,97.94 121.53,97.94 v3(122.05,97.41)
  BOTTOM w0.102: v3(122.05,97.41) 122.49,96.98 122.9,96.98 123.04,97.12 123.6,97.12 123.69,97.21 124.11,97.21 124.19,97.13 124.43,97.13 125.03,97.74 125.03,97.83 UC1.D14
APU_VDD_SEN_H: length 121.5
  TOP w0.127: v3(125.06,102.74) 124.01,101.69 124.01,101.57 123.25,100.81 123.22,100.81 122.83,100.42 122.83,97.93 123.07,97.69 123.07,97.26 115.17,89.36 114.17,89.36 101.63,76.81 87.83,76.81 85.05,79.6 85.05,90.93 85.4,91.28 85.4,96.19 T131.1 84.38,97.21 84.38,98.23 82.07,100.54 78.47,100.54 78.06,100.94 71.89,100.94 69.54,103.29 v3(69.54,104.93)
  TOP w0.203: 61.65,117.33 61.58,117.25 61.58,116.67 61.75,116.49 PU500.11
  TOP w0.254: PC509.1 PR502.1 ; PC509.1 PR511.1 v3(63.25,119.99) ; PC509.1 63.25,118.24 62.59,117.58 61.91,117.58 61.65,117.33 ; PC506.2 v3(59.7,118.67)
  IN1 w0.127: v3(59.7,118.67) 61.93,118.67 v3(63.25,119.99)
  IN3 w0.127: v3(69.54,104.93) 69.54,106.68 66.57,109.66 65.72,109.66 64.42,110.96 64.42,114.43 63.25,115.6 v3(63.25,119.99)
  BOTTOM w0.127: UC1.D9 125.5,102.31 v3(125.06,102.74)
APU_VDD_SEN_L: length 117.9
  TOP w0.127: v3(81.39,99.32) 81.39,98.81 T130.1 82.89,97.31 82.89,94.85 83.18,94.56 83.18,92.34 84.28,91.24 84.28,79.28 87.52,76.05 101.94,76.05 114.41,88.52 115.41,88.52 123.83,96.95 123.83,98.1 123.59,98.34 123.59,100.08 124.01,100.5 124.94,101.43 125.36,101.43 125.99,102.06 v3(126.1,102.06) ; PC531.1 67.06,108.08 v3(67.01,108.13)
  TOP w0.203: PU500.14 60.05,115.36 59.75,115.66
  TOP w0.254: PC506.1 58.78,118.23 59.75,117.26 v3(59.75,116.03) 59.75,115.66
  IN1 w0.127: v3(81.39,99.32) 80.91,98.84 79.23,98.84 78.75,99.32 72.57,99.32 71.9,99.99 71.9,100.63 69.11,103.42 69.11,106.04 v3(67.01,108.13)
  IN3 w0.127: v3(67.01,108.13) 66.45,107.57 64.42,107.57 60.84,111.15 60.84,114.94 v3(59.75,116.03)
  BOTTOM w0.127: v3(126.1,102.06) 126.1,101.82 126.3,101.62 UC1.E10
  BOTTOM w0.254: v3(59.75,116.03) 60.28,115.5 PR500.2
APU_VDDNB_SEN_H: length 102.9
  TOP w0.127: PC531.2 PC530.1 ; PC530.1 PR552.1 65.67,106.23 67.39,106.23 67.9,105.72 PR565.1 68.87,105.67 68.87,103.31 71.61,100.56 77.88,100.56 78.29,100.16 81.4,100.16 83.37,98.19 T132.1 83.37,94.95 83.56,94.76 83.56,92.5 84.66,91.39 84.66,79.44 87.67,76.43 101.78,76.43 114.33,88.98 115.33,88.98 123.45,97.1 123.45,97.85 123.21,98.09 123.21,100.24 123.63,100.65 v3(124.98,102.01) ; PC530.1 64.4,108.39 63.56,108.39 62.95,108.99 PU500.32
  BOTTOM w0.102: v3(124.98,102.01) 125.49,101.5 UC1.D10
AUD_HP_OUT_L_CN: length 12.9
  TOP w0.102: v3(197.16,29.29) 197.88,29.29 v1(198.23,29.63)
  IN3 w1.016: JHP.1 201.17,36.91 200.54,37.55 199.52,37.55 198.43,36.45 198.43,33.38 197.16,32.11 v3(197.16,29.29)
  vias: v2(196.27,29.65) v2(196.27,29.01)
AUD_HP_OUT_R_CN: length 10.5
  TOP w1.016: 197.8,27.28 198.76,27.28 199.95,26.09 206.03,26.09 207.24,27.31 JHP.2
  vias: v1(197.1,27.93) v2(196.27,27.61) v2(196.27,26.98) v3(196.93,27.33)
B+:
  vias: v2(12.25,77.25) v2(12.25,76.61) v2(21.32,30.87) v2(21.42,27.92) v2(21.75,30.38) v2(21.72,28.5) v2(21.82,31.25) v2(22.36,30.79) v2(22.54,28.05) v2(22.99,31.09) v2(22.99,30.46) v2(23.04,28.45) v2(23.65,28.15) v2(23.7,27.51) v2(24.29,28.53) v2(24.29,27.77) v2(38.92,35.62) v2(39.55,35.62) v2(40.19,35.62) v2(40.82,35.62) v2(41.48,35.62) v2(42.12,35.62) v2(50.6,26.34) v2(50.6,25.66) v2(50.6,25.02) v2(50.6,24.39) v2(51.26,26.34) v2(51.26,25.66) v2(51.26,25.02) v2(51.26,24.39) v2(51.92,26.34) v2(51.92,25.66) v2(51.92,25.02) v2(51.92,24.39) v2(79.18,19.49) v2(79.84,19.49) v2(80.47,19.49) v2(89.36,48.26) v2(89.37,47.6) v2(89.36,46.94) v2(89.36,46.31) v2(172.01,49.99) v2(172.75,50.52) v2(173.18,51.06) v4(50.54,31.3)
BAT_ALERT: length 5.9
  TOP w0.254: PD1.2 18.73,18.22 v1(17.48,16.97) 17.03,16.52 PBATT.3
BATT+: length 19.2
  TOP w0.254: PR726.2 v3(40.21,11.66)
  IN1 w0.254: v3(40.21,11.66) 40.14,11.59 36.91,11.59 27.23,21.26 v2(25.84,21.26)
  vias: v1(25.76,25.16) v2(23.68,26.47) v2(23.68,25.71) v2(23.68,22.79) v2(23.68,22.03) v2(23.68,21.26) v2(24.31,26.47) v2(24.31,25.71) v2(24.31,22.79) v2(24.31,22.03) v2(24.31,21.26) v2(25.08,26.47) v2(25.08,25.71) v2(25.08,22.79) v2(25.08,22.03) v2(25.08,21.26) v2(25.84,22.79) v2(25.84,22.03)
BATT++:
  vias: v2(15.68,30.1) v2(15.68,29.47) v2(15.68,28.76) v2(15.68,28) v2(15.68,27.23) v2(15.68,26.47) v2(15.68,25.71) v2(15.68,24.95) v2(15.68,24.19) v2(17.33,30.26) v2(17.33,29.62) v2(17.33,28.99) v2(17.33,28.35) v2(17.33,27.69) v2(17.33,27.03) v2(17.33,26.34) v2(17.33,25.58) v2(17.33,24.82) v2(17.33,24.19) v2(17.33,23.55) v4(19.23,29.01)
BATT_CHG_LED#: length 133.2
  TOP w0.102: JLED.6 13.4,53.3 14.69,54.59 19.93,54.59 v3(21.01,55.67) ; v1(117.51,26.9) 117.91,27.31 v3(117.91,27.59)
  IN1 w0.114: v3(21.01,55.67) 32.88,55.67 35,53.55 44.15,53.55 47.43,50.27 47.43,44.96 50.79,41.6 50.79,35.38 52.13,34.04 52.86,34.04 53.5,34.68 55.11,34.68 55.34,34.9 58.81,34.9 59.32,34.4 62.99,34.4 64.29,35.69 65.53,35.69 66.65,36.81 71.28,36.81 71.91,36.18 74.74,36.18 76.36,37.8 85.73,37.8 88.01,35.52 96.25,35.52 98.46,33.3 99.41,33.3 103.61,33.3 106.86,30.05 112.81,30.05 114.1,28.76 116.13,28.76 117.3,27.59 v3(117.91,27.59)
  BOTTOM w0.102: UE1.92 119.59,29.45 117.91,27.77 v3(117.91,27.59)
BATT_LOW_LED#: length 133.9
  TOP w0.102: JLED.5 13.56,54.3 14.05,54.79 19.55,54.79 v3(21.01,56.25) ; v3(118.66,27.59) 118.66,28.06 v1(118.81,28.21)
  IN1 w0.114: v3(118.66,27.59) 118.67,27.59 118.67,27.49 118.17,28 118.09,28 118.08,28 117.74,28 117.74,28 117.22,28 116.23,28.99 114.2,28.99 112.9,30.28 106.96,30.28 103.71,33.53 100.05,33.53 100.04,33.53 99.5,33.53 98.56,33.53 96.34,35.75 88.1,35.75 84.93,38.92 77.16,38.92 74.65,36.41 72,36.41 71.37,37.04 66.56,37.04 65.44,35.92 64.19,35.92 62.9,34.62 59.42,34.62 58.91,35.13 55.24,35.13 55.01,34.9 51.94,34.9 51.02,35.83 51.02,41.7 47.71,45 47.71,50.37 44.3,53.78 35.1,53.78 32.97,55.9 21.43,55.9 21.08,56.25 v3(21.01,56.25)
  BOTTOM w0.102: UE1.93 119.99,29.57 118.67,28.25 118.67,27.6 v3(118.66,27.59)
BATT_PRS: length 7.1
  TOP w0.254: PBATT.5 v1(16.85,20.52) 17.44,20.52 18.73,19.22 PD1.3 20.55,19.22 PR15.1
BATT_TEMP: length 127.7
  TOP w0.102: v3(24.04,37.87) PC708.1 25.36,38.03 PQ710.2 PQ710.5 ; v3(22.84,35.08) 22.43,35.08 21.9,34.55 PQ713.2 ; v3(31.02,36.4) 30.54,36.88 PQ714.2
  TOP w0.254: PR16.1 PR15.2 21.47,19.79 21.01,20.25 v3(20,20.25)
  IN1 w0.114: v3(24.04,37.87) 25.55,37.87 25.98,37.44 29.98,37.44 v3(31.02,36.4)
  IN2 w0.127: v3(22.84,35.08) 22.99,35.08 23.65,35.74 23.65,37.48 v3(24.04,37.87) ; v3(31.02,36.4) 32.98,36.4 36.39,33 42.17,33 45.94,29.23 56.39,29.23 58.99,31.83 67.5,31.83 71.46,35.79 74.82,35.79 75.67,36.64 75.67,37.24 77.08,38.65 77.45,38.65 78.11,37.99 87.24,37.99 98.5,26.73 101.66,26.73 102.34,27.41 103.77,27.41 v3(104.2,27.84)
  IN2 w0.254: v3(22.84,35.08) 22.92,35.01 22.92,33.94 19.74,30.76 19.74,20.5 v3(20,20.25)
  BOTTOM w0.102: v3(104.2,27.84) 104.07,27.97 CE9.2 v1(105.23,28.93) 105.5,28.93 105.85,28.59 UE1.63
BEEP#: length 101
  TOP w0.102: v3(187.48,17.61) 188.04,18.17 DA8.2
  IN2 w0.127: v3(187.48,17.61) 187.56,17.61 187.99,17.17 187.99,7.85 187.15,7.01 178.13,7.01 176.61,5.49 169.55,5.49 167.6,3.54 167.6,2.98 166.25,1.63 158.33,1.63 157.31,2.65 153.57,2.65 153.16,2.24 148.07,2.24 147.54,2.77 136.19,2.77 135.63,3.33 134.29,3.33 131.94,5.68 130.93,5.68 126.8,9.81 115.17,9.81 114.61,9.25 112.63,9.25 111.41,10.47 111.41,12.55 111.69,12.83 v3(111.69,13.69)
  BOTTOM w0.102: v3(111.69,13.69) 111.97,13.69 112.39,14.12 UE1.23 ; v1(187.08,18.14) 187.48,17.73 v3(187.48,17.61)
BKOFF#: length 198.8
  TOP w0.102: v3(13.52,77.75) 13.49,77.78 9.33,77.78 v1(8.85,78.26) 8.62,78.49 DX1.2
  IN2 w0.127: v3(13.52,77.75) 12.43,78.85 12.43,88.92 13.24,89.73 13.24,90.63 16.51,93.89 16.52,93.89 23.46,100.84 27.23,100.84 30.15,103.76 43.85,103.76 45.73,101.88 61.22,101.88 61.39,101.71 67.03,101.71 68.5,100.24 68.5,99.2 69.35,98.35 69.83,98.35 71.4,96.78 75.65,96.78 76.43,95.99 77.38,95.99 79.66,93.7 82.1,93.7 83.93,91.87 83.93,88.6 83.32,87.99 83.32,86.69 83.83,86.18 83.83,80.78 90.91,73.7 90.91,71.43 90.33,70.85 90.33,51.52 91.61,50.24 91.61,41.47 98.31,34.77 98.31,34.77 99.37,33.71 99.37,33.5 99.37,30.66 100.06,29.98 113.77,29.98 114.36,29.39 114.36,27.36 116.6,25.11 120.41,25.11 120.99,25.69 v3(120.99,26.29)
  BOTTOM w0.102: v3(120.99,26.29) 121.49,25.79 UE1.105
BOOT1:
  vias: v1(58.3,40.42)
BOOT2:
  vias: v1(65.33,39.83)
BOOT_1.35V:
  vias: v1(87.14,11.19)
BOOT_APU1: length 2.7
  TOP w0.203: PR542.1 68.7,112.96 PU500.46
BOOT_APU1-1: length 5.3
  TOP w0.508: PC524.1 71.58,115.24 72.19,114.63 v1(72.19,113.94) 72.19,113.62 71.28,112.7 PR542.2
BOOT_NB1: length 4
  TOP w0.203: PU500.42 66.93,111.36 67.21,111.08 67.47,111.08 v1(67.68,110.87) 68.21,110.34 68.21,109.64 PR510.1
BOOT_NB1-1: length 5
  TOP w0.508: PC507.1 71.35,111.43 71.96,110.82 v1(71.96,110.14) 71.96,109.57 71.29,108.89 PR510.2
BP_0: length 6.7
  BOTTOM w0.102: RV82.1 65.11,100.59 v1(65.11,99.19) 65.11,98.84 64.57,98.3 64.57,94.67 UV1.U1
BP_1: length 7.9
  BOTTOM w0.102: UV1.U3 64.83,94.13 64.83,95.66 66.22,97.06 v1(66.22,97.79) RV81.1
BST: length 4.9
  BOTTOM w0.102: v1(45.13,20.59) 45.04,20.5 45.04,19.64 44.61,19.2 PR713.2
  BOTTOM w0.254: PR713.2 44,19.1 44,17.53 43.94,17.47 PU700.25
BST_1.35V: length 1.3
  BOTTOM w0.102: PC200.1 v1(90.23,13.01)
BST_3V: length 3.6
  TOP w0.102: PR103.2 70.68,21.45 v1(70.07,20.85)
  TOP w0.203: PU100.9 71.88,19.6 71.88,20.18
  TOP w0.254: PR103.2 71.73,21.15 71.73,20.33 71.88,20.18
BST_5V: length 2.6
  TOP w0.102: v1(69.06,14.28) 69.16,14.38 PR111.1
  TOP w0.203: PU100.17 71.87,15.99 71.56,15.68
BST_+1.05VSP:
  vias: v1(176.69,51.9)
BST_+1.35VGPUP:
  vias: v1(33.13,43.87)
BST_CHGA: length 2.4
  BOTTOM w0.102: v1(43.9,21.77) PR713.1
  BOTTOM w0.635: PR713.1 PC713.1
BT_LED_EC: length 3.5
  BOTTOM w0.102: RE38.2 105.12,16.95 T112.1 105.97,17.79 UE1.36
BT_ON#: length 50.5
  IN2 w0.127: v3(185.71,62.79) 185.6,62.79 184.89,62.08 184.89,61.98 183.39,60.48 180.93,60.48 169.45,49 169.45,46.51 160.49,37.55 159.47,37.55 v3(158.98,37.06)
  BOTTOM w0.102: U2.AJ16 157.1,30.25 157.71,30.87 158.04,30.87 158.35,31.17 158.35,32.03 158.55,32.24 158.55,33 v1(159.36,33.81) 159.89,34.33 RH41.2 159.29,35.56 159.29,36.76 v3(158.98,37.06) ; v3(185.71,62.79) 185.3,63.2 185.3,64.32 185.73,64.74 JNGFF.46
CAPS_LED: length 37.9
  TOP w0.102: v3(119.41,31.9) 119.4,31.91 118.67,31.91 v1(118.09,32.49) 117.94,32.64 116.82,32.64 115.63,33.84 109.53,33.84 107.75,35.62 104.18,35.62 102.63,37.16 99.11,37.16 93.11,43.16 93.11,43.89 92.59,44.41 92.59,47.53 92.37,47.75 JKB.1
  BOTTOM w0.102: UE1.91 119.19,31.69 119.39,31.9 v3(119.41,31.9)
CHG:
  vias: v1(26.78,28.1)
CHG_B+:
  vias: v1(37.18,33.55) v2(38.03,34.6) v2(38.03,33.96) v2(38.66,34.6) v2(38.66,33.96) v2(39.3,34.6) v2(39.3,33.96) v2(39.93,34.6) v2(39.93,33.96)
CLK_APU: length 94.4
  IN3 w0.135: v3(152.3,98.61) 152.14,98.44 152.14,98.05 153.37,96.82 153.37,93.53 156.42,90.48 156.42,80.19 161.02,75.59 161.02,65.84 166.45,60.41 166.45,56.12 165.49,55.16 165.49,41.77 164.64,40.92 164.64,34.96 164.17,34.48 164.17,32.48 163.76,32.07 163.76,28.25 163.32,27.81 163.32,23.3 164.88,21.74 164.88,20.87 163.6,19.59 v3(163.6,18.87)
  BOTTOM w0.102: v3(152.3,98.61) 152.13,98.78 152.13,99.17 151.78,99.52 147.97,99.52 147.55,99.1 UC1.AM13 ; v3(163.6,18.87) 163.7,18.97 U2.T24
CLK_APU#: length 94.4
  IN3 w0.135: v3(162.99,18.87) 163.36,19.24 163.36,19.69 164.63,20.97 164.63,21.63 163.07,23.19 163.07,27.91 163.52,28.35 163.52,32.17 163.92,32.58 163.92,34.58 164.39,35.06 164.39,41.03 165.24,41.87 165.24,55.26 166.21,56.22 166.21,60.3 160.77,65.74 160.77,75.49 156.18,80.09 156.18,90.38 153.13,93.43 153.13,96.72 151.9,97.95 151.9,98.46 151.76,98.61 v3(151.67,98.61)
  BOTTOM w0.102: U2.T23 162.9,19.57 163.02,19.69 163.2,19.69 163.33,19.56 163.33,19.18 163.02,18.87 v3(162.99,18.87) ; v3(151.67,98.61) 151.77,98.61 151.92,98.76 151.92,99.09 151.71,99.3 148.38,99.3 148.3,99.23 UC1.AN13
CLK_APU_DISP: length 101.8
  IN3 w0.135: v3(152.53,102.09) 152.7,101.92 153.18,101.92 155.18,99.92 156.81,99.92 158.39,98.34 158.39,97.7 169.02,87.08 169.02,60.77 167.41,59.16 167.41,55.68 166.27,54.55 166.27,41.98 167.23,41.02 167.23,39.3 168.65,37.88 168.65,33.33 168.35,33.02 168.35,31.58 168.83,31.09 168.83,26.54 167.81,25.52 167.58,25.52 166.02,23.96 166.02,20.12 165.65,19.75 v3(165.65,18.85)
  BOTTOM w0.102: UC1.AM11 147.79,100.7 148.25,101.16 148.95,101.16 149.16,100.94 150,100.94 150.52,101.46 150.97,101.46 151.39,101.88 152.33,101.88 v3(152.53,102.09) ; U2.R26 165.3,18.5 v3(165.65,18.85)
CLK_APU_DISP#: length 101.7
  IN3 w0.135: v3(152.53,101.4) 152.53,101.55 152.66,101.68 153.08,101.68 155.08,99.67 156.71,99.67 158.15,98.24 158.15,97.6 168.77,86.97 168.77,60.87 167.16,59.26 167.16,55.78 166.03,54.65 166.03,41.88 166.99,40.92 166.99,39.2 168.41,37.77 168.41,33.43 168.1,33.13 168.1,31.47 168.59,30.99 168.59,26.64 167.71,25.76 167.48,25.76 165.78,24.06 165.78,20.22 165.4,19.85 165.4,19.22 165.03,18.85 v3(164.95,18.85)
  BOTTOM w0.102: v3(152.53,101.4) 152.53,101.59 152.46,101.67 151.48,101.67 151.06,101.25 150.61,101.25 150.09,100.73 149.08,100.73 148.86,100.94 148.32,100.94 148.24,100.86 148.24,100.76 UC1.AN11 ; v3(164.95,18.85) 164.78,18.85 164.67,18.95 164.67,19.13 165.11,19.56 165.21,19.56 U2.T26
CLK_CALRN: length 2.2
  TOP w0.102: v1(167.01,11.75) 166.76,11.5 v3(166.35,11.5) 166.25,11.6 RH7.2
  BOTTOM w0.102: U2.F27 165.9,11.05 v3(166.35,11.5)
CLK_EC33M: length 4
  BOTTOM w0.102: RH14.1 164.45,6.09 v1(164.45,6.74) 164.45,8.82 U2.B25
CLK_LAN_25M: length 115.2
  IN3 w0.135: v3(175.04,108.06) 177.04,106.05 177.04,101.1 179.36,98.78 180.75,98.78 187.99,91.55 187.99,71.61 188.77,70.83 188.77,40.95 187.24,39.42 185.62,39.42 180.21,34.02 180.21,29.02 181.46,27.77 181.46,25 181.06,24.59 181.06,22.03 180.41,21.38 180.41,17.79 180.07,17.44 180.07,15.57 180.52,15.12 180.52,12.06 178.45,9.99 177.43,9.99 v3(177.22,9.78)
  BOTTOM w0.102: RH20.1 RH17.2 177.22,10.42 v3(177.22,9.78) ; v3(175.04,108.06) 174.45,108.64 RL21.2
CLK_LAN_25M_R: length 12.5
  IN3 w0.135: v3(174.94,10.8) 174.45,11.28 172.19,11.28 171.61,11.87 166.93,11.87 v3(165.59,13.21)
  BOTTOM w0.102: RH20.2 175.62,11.49 v3(174.94,10.8) ; U2.J26 165.2,13.6 v3(165.59,13.21)
CLK_PCI_EC: length 58.3
  IN3 w0.135: v3(117.51,10.98) 118.07,10.42 120.47,10.42 121.25,9.63 125.14,9.63 126,8.77 127.25,8.77 128.73,7.29 129.89,7.29 131.27,5.91 132.98,5.91 134.61,4.28 137.17,4.28 137.54,3.91 144.84,3.91 145.43,4.49 156.33,4.49 157.55,5.71 162.91,5.71 163.35,5.26 164.21,5.26 v3(164.24,5.29)
  BOTTOM w0.102: v3(117.51,10.98) 117.51,11.36 RE6.1 117.29,12.18 117.29,12.84 116.79,13.34 UE1.12 ; RH117.2 166.06,3.49 RH129.1 RH14.2 165.2,4.53 164.45,5.29 v3(164.24,5.29)
CLK_PCIE_LAN: length 107.3
  IN3 w0.135: v3(174.3,9.57) 174.47,9.74 174.87,9.74 175.06,9.94 175.29,9.94 178.3,12.95 178.3,21.67 178.39,21.76 178.39,23.03 178.74,23.37 178.74,34.65 186,41.91 186.49,41.91 187.25,42.68 187.25,51.24 185.49,53 185.49,58.07 185.67,58.25 185.67,61.09 182.52,64.24 182.52,66.88 178.09,71.32 178.09,97.81 176.83,99.06 176.21,99.06 v3(176.08,99.19)
  BOTTOM w0.102: v3(174.3,9.57) 174.11,9.75 173.96,9.75 RH15.1 ; v3(176.08,99.19) 173.16,99.19 172.31,100.04 172.31,100.94 172.41,101.05 UL1.15
CLK_PCIE_LAN#: length 107.3
  IN3 w0.135: v3(176.08,98.61) 176.29,98.82 176.73,98.82 177.84,97.71 177.84,71.22 182.28,66.78 182.28,64.14 185.43,60.99 185.43,58.35 185.25,58.17 185.25,52.9 187.01,51.14 187.01,42.78 186.39,42.16 185.9,42.16 178.49,34.75 178.49,23.47 178.15,23.13 178.15,21.86 178.06,21.77 178.06,13.05 175.19,10.18 174.96,10.18 174.77,9.99 174.45,9.99 174.3,10.14 v3(174.3,10.2)
  BOTTOM w0.102: RH16.1 173.66,10.12 173.79,9.99 174.17,9.99 174.3,10.11 v3(174.3,10.2) ; UL1.16 172.01,101.05 172.09,100.97 172.09,99.95 173.07,98.98 175.71,98.98 v3(176.08,98.61)
CLK_PCIE_LAN#_R: length 4.6
  BOTTOM w0.102: RH16.2 172.74,10.34 172.25,10.34 171.77,10.82 169.01,10.82 U2.E31
CLK_PCIE_LAN_R: length 4.6
  BOTTOM w0.102: U2.E33 169.37,10.45 169.37,10.52 169.47,10.62 171.68,10.62 172.27,10.04 172.27,9.4 172.37,9.3 172.6,9.3 RH15.2
CLK_PCIE_MINI1: length 54.6
  IN3 w0.135: v3(183.85,56.23) 183.96,56.23 184.08,56.11 184.08,52.52 184.65,51.95 184.65,42.18 177.6,35.13 177.6,23.96 176.99,23.35 176.99,21.78 177.15,21.63 177.15,13.39 175.93,12.17 174.75,12.17 174.48,12.44 174.48,12.81 174.61,12.93 v3(174.73,12.93)
  BOTTOM w0.102: v3(174.73,12.93) 174.66,12.93 174.45,12.73 174.45,11.87 174.2,11.61 173.98,11.61 RH12.1 ; JNGFF.39 183.98,57.11 184.18,56.9 184.18,56.34 184.07,56.23 v3(183.85,56.23)
CLK_PCIE_MINI1#: length 54.6
  IN3 w0.135: v3(184.6,56.23) 184.32,55.96 184.32,52.62 184.89,52.05 184.89,42.08 177.85,35.03 177.85,23.86 177.24,23.25 177.24,21.88 177.39,21.73 177.39,13.29 176.03,11.93 174.65,11.93 174.23,12.34 174.23,12.77 v3(174.07,12.93)
  BOTTOM w0.102: v3(174.07,12.93) 174.25,12.76 174.25,11.95 174.11,11.82 174.03,11.82 RH13.1 ; v3(184.6,56.23) 184.4,56.43 184.4,56.96 184.48,57.04 JNGFF.41
CLK_PCIE_MINI1#_R: length 4.6
  BOTTOM w0.102: U2.F31 168.73,11.27 169.35,11.89 170.14,11.89 170.43,12.18 v2(171.38,12.18) RH13.2
CLK_PCIE_MINI1_R: length 4.6
  BOTTOM w0.102: U2.F33 169.31,11.27 169.25,11.33 169.25,11.48 169.44,11.68 170.22,11.68 170.49,11.94 172.09,11.94 172.22,11.82 172.22,11.43 172.36,11.29 RH12.2
CLK_PCIE_VGA#_R: length 5.3
  BOTTOM w0.102: RH11.2 v2(171.67,14.66) 171.01,14.66 170.52,14.16 169.35,14.16 169.27,14.25 168.83,14.25 168.83,14.25 168.77,14.19 168.18,14.19 U2.K29
CLK_PCIE_VGA_R: length 5.2
  BOTTOM w0.102: U2.J30 168.25,13.88 168.35,13.98 168.86,13.98 168.92,14.04 169.18,14.04 169.28,13.95 170.61,13.95 171.08,14.42 172.1,14.42 RH10.2
CLK_PEG_VGA: length 167.1
  IN3 w0.135: v3(89.19,72.42) 89.31,72.55 95.5,72.55 103.19,64.85 103.19,55.91 95.83,48.54 95.83,41.07 97.98,38.91 97.98,34.12 99.29,32.81 107.36,32.81 108.5,33.96 116.06,33.96 116.2,34.1 123.31,34.1 123.91,34.7 133.26,34.7 134.16,35.6 150.51,35.6 150.92,36.01 159.98,36.01 161.65,34.33 161.65,31.45 162.17,30.94 162.17,24.9 161.84,24.57 161.84,20.32 161.64,20.11 161.64,18.9 163.62,16.92 166.78,16.92 167.67,16.03 169.61,16.03 170.25,15.4 170.25,15.28 171,14.53 172.93,14.53 173.3,14.16 174.25,14.16 v3(174.39,14.02)
  BOTTOM w0.102: v3(89.19,72.42) 89.08,72.52 82.35,72.52 82.15,72.32 79.08,72.32 78.87,72.52 76.89,72.52 76.54,72.17 73.97,72.17 73.62,72.52 73.62,73.32 UV1.AK30 ; v3(174.39,14.02) 173.91,14.02 RH10.1
CLK_PEG_VGA#: length 167.1
  IN3 w0.135: v3(89.19,73) 89.4,72.79 95.6,72.79 103.43,64.95 103.43,55.81 96.07,48.44 96.07,41.17 98.23,39.01 98.23,34.22 99.39,33.06 107.25,33.06 108.4,34.21 115.96,34.21 116.09,34.35 123.21,34.35 123.81,34.94 133.16,34.94 134.06,35.84 150.41,35.84 150.82,36.25 160.08,36.25 161.9,34.43 161.9,31.55 162.41,31.04 162.41,24.79 162.08,24.46 162.08,20.22 161.88,20.01 161.88,19 163.72,17.16 166.88,17.16 167.77,16.28 169.71,16.28 170.49,15.5 170.49,15.39 171.1,14.78 173.03,14.78 173.4,14.41 174.2,14.41 174.39,14.6 v3(174.39,14.71)
  BOTTOM w0.102: v3(89.19,73) 88.92,72.74 82.26,72.74 82.06,72.53 79.17,72.53 78.96,72.74 76.8,72.74 76.45,72.38 74.04,72.38 73.82,72.61 73.82,72.85 73.87,72.9 UV1.AK32 ; v3(174.39,14.71) 174.39,14.6 174.02,14.23 173.57,14.23 173.44,14.36 173.44,14.53 173.56,14.66 RH11.1
CLK_SMB: length 8.2
  TOP w0.254: v3(16.69,21.53) PD2.3 18.79,21.53 19.06,21.26 v1(19.64,21.26) 20.3,21.26 PR18.1
  BOTTOM w0.254: PBATT.7 16.69,21.78 v3(16.69,21.53)
CLK_USB30_48M: length 7.4
  BOTTOM w0.102: T98.1 150.32,6.85 150.32,11.74 U2.G8
CLK_X1: length 5.9
  BOTTOM w0.102: 134.45,14.88 135.13,14.21 UG1.1 ; 134.45,14.88 v1(134.45,14.88) ; 134.45,14.88 133.79,15.55 C11.1 133.31,16.46 133.31,17.61 Y1.1
CLK_X2: length 11.1
  BOTTOM w0.102: Y1.3 131.02,20.03 130.46,19.47 130.46,17.34 131.82,15.98 C12.1 132.95,15.8 v1(132.95,14.12) 134.44,12.63 UG1.16
COMP: length 3.5
  TOP w0.203: PU500.13 60.95,116.3 60.56,116.69 v1(60.56,117.47) PC510.2 PR513.2
COMPA: length 4.6
  TOP w0.102: v1(62.9,105.57) 62.59,105.87 PR550.2
  TOP w0.203: PU500.30 62.15,108.52 62.59,108.08 PC529.2 PR550.2
CPU_B+: length 5.9
  TOP w0.254: v2(73.98,115.64) 72.4,117.23 72.4,118.36 71.82,118.93 PR514.2
  vias: v1(71.75,107.85) v2(72.89,104.79) v2(74.05,114.27) v2(75.06,115.64) v2(75.05,114.37) v2(78.54,114.23) v2(79.18,115.37) v2(79.56,113.85) v2(79.94,115.12) v2(80.57,114.23) v2(80.57,113.59) v2(81.21,112.45)
CPU_DPB_CTRLCLK_R: length 13.6
  IN3 w0.135: JHDMI.15 202.85,82 202.85,80.65 200.51,78.3 200.51,77.58 201.02,77.07 201.02,76.48 200.66,76.12 200.15,76.12 v3(200.11,76.08)
  BOTTOM w0.102: RP60.4 196.18,75.63 196.22,75.67 197.16,75.67 QX4.6 197.4,75.46 197.94,76 198.33,76 198.56,76.23 199.95,76.23 v3(200.11,76.08)
CPU_DPB_CTRLDAT_R: length 12.5
  IN3 w0.135: v3(200.13,76.66) 200.23,76.56 200.48,76.56 200.58,76.67 200.58,76.89 200.07,77.4 200.07,78.49 201.33,79.74 201.33,81.53 JHDMI.16
  BOTTOM w0.102: v3(200.13,76.66) 200.11,76.64 199.4,76.64 QX4.3 198.7,76.95 198.16,76.41 197.78,76.41 197.45,76.08 196.22,76.08 196.17,76.13 RP60.3
CS1: length 4.4
  TOP w0.102: v1(76.94,15.07) 76.41,15.07 PR105.1
  TOP w0.203: PR105.1 75.01,16.06 74.3,16.77 74.3,17.21 74.2,17.31 PU100.1
CS2: length 5.2
  TOP w0.102: PR108.1 75.43,22.31 v1(76.03,22.9)
  TOP w0.203: PU100.5 74.2,18.91 74.27,18.99 74.27,20.45 74.86,21.04 74.86,21.31 PR108.1
CS_1.35V: length 4
  BOTTOM w0.102: PR205.2 84.38,15.09 85.45,15.09 v1(85.68,14.86)
  BOTTOM w0.254: PU200.13 84,13.85 83.83,14.03 PR205.2
CSIN: length 31.6
  BOTTOM w0.254: PR700.3 37.55,37.11 37.37,37.29 37.37,39.42 38.34,40.39 45.12,40.39 46.51,38.99 v1(46.51,28.17) 46.51,21.06 PR705.1
CSIP: length 33
  BOTTOM w0.254: PR700.2 36.78,37.11 36.99,37.32 36.99,39.63 38.18,40.82 45.28,40.82 46.92,39.18 v1(46.92,32.53) 46.92,21.34 PR704.1
DAT_SMB: length 6.7
  TOP w0.254: PBATT.6 13.96,22.53 v1(16.8,22.53) PD2.2 17.91,22.66 20.43,22.66 PR20.1
DBC_EN: length 180.1
  TOP w0.102: RX23.1 11.47,89.25 v1(12.46,89.25) 13.7,88.02 v3(13.7,87.84)
  IN2 w0.127: v3(13.7,87.84) 13.7,89.11 14,89.41 14,89.94 23.89,99.83 27.65,99.83 29.43,101.6 43.85,101.6 45.27,100.18 59.52,100.18 59.7,100 62.5,100 62.5,99.96 62.75,99.71 63.1,99.71 63.34,99.96 63.34,100 63.69,100 64.91,98.78 65.72,98.78 68.79,95.71 73.51,95.71 74.24,94.97 75.67,94.97 76.21,94.44 76.21,93.86 77.91,92.16 80.02,92.16 80.41,92.55 81.78,92.55 82.25,92.08 82.25,86.31 82.71,85.85 82.71,80.43 89.46,73.68 89.46,73.68 89.86,73.28 89.86,73.28 89.89,73.25 89.89,71.85 89.31,71.27 89.31,51.4 90.8,49.92 90.8,41.04 98.35,33.49 98.35,30.43 99.83,28.96 108.42,28.96 112.81,24.57 v3(113.47,24.57)
  BOTTOM w0.102: v3(113.47,24.57) 113.47,22.31 111.69,20.53 111.69,16.06 111.59,15.96 UE1.25
DBC_EN_R: length 12
  TOP w0.102: v3(9.66,87.89) 9.84,88.07 RX36.1 RX23.2 10.39,90.19 v1(10.01,90.57)
  BOTTOM w0.102: JEDP.23 2.29,88 2.92,88.62 3.84,88.62 3.97,88.75 8.79,88.75 v3(9.66,87.89)
DCIN: length 1.2
  BOTTOM w0.254: PU700.22 42.44,17.19 42.3,17.33 41.94,17.33 v2(41.82,17.2)
  vias: v1(41.22,17.85)
DDRA_CKE0: length 54.1
  IN1 w0.183: v3(131.66,83.47) 131.25,83.47 129.67,81.89 129.67,81.48 128.65,80.46 128.65,79.66 128.17,79.18 127.7,79.18 127.19,78.67 127.19,77.39 127.69,76.89 127.69,74.21 127.35,73.87 127.35,73.17 127.06,72.88 126.04,72.88 124.06,70.89 124.06,69.57 120.11,65.62 120.11,47.86 119.19,46.94 119.19,43.88 119.68,43.39 120.53,43.39 120.68,43.54 120.68,43.87 120.53,44.02 120.02,44.02 119.87,44.17 119.87,44.63 v3(119.84,44.66)
  BOTTOM w0.102: UC1.L33 131.47,83.47 v3(131.66,83.47)
  BOTTOM w0.17: JDIMM1.73 120.15,46.89 119.39,46.13 119.39,45.11 v3(119.84,44.66)
DDRA_CKE1: length 54
  IN1 w0.183: v3(131.61,85.78) 130.69,85.78 128.05,83.14 128.05,81.26 126.96,80.17 126.96,79.84 126.21,79.09 126.21,74.43 123.08,71.3 123.08,69.97 119.14,66.03 119.14,48.27 118.21,47.34 118.21,43.48 119.89,41.8 119.89,41.28 120.3,40.87 v3(120.45,40.87)
  BOTTOM w0.102: v3(131.61,85.78) 131.38,85.78 UC1.L30
  BOTTOM w0.17: JDIMM1.74 120.45,40.87 v3(120.45,40.87)
DDRA_CLK0: length 57.4
  IN1 w0.17: v3(138.84,84.94) 138.84,85.2 138.72,85.32 137.95,85.32 137.24,84.61 137.24,81.79 136.58,81.13 136.58,79.55 136.38,79.35 136.38,68.81 134.39,66.83 133.86,66.83 133.51,66.48 133.51,65.95 133,65.44 132.47,65.44 131.18,64.15 131.18,63.91 131.58,63.5 131.58,62.71 131.29,62.41 130.89,62.41 130.29,63.01 130.04,63.01 129.79,62.76 129.79,62.51 130.89,61.41 130.89,60.93 130.48,60.52 130,60.52 128.89,61.62 128.65,61.62 128.23,61.19 128.23,60.96 128.45,60.74 128.45,60.26 128.23,60.04 128.23,46.05 127.54,45.37 127.54,45.11 127.74,44.91 127.97,44.91 128.15,45.09 v3(128.15,45.11)
  BOTTOM w0.165: UC1.Y30 138.84,84.96 v3(138.84,84.94) ; v3(128.15,45.11) 128.35,44.91 128.61,44.91 129.01,45.32 129.01,46.41 128.9,46.52 128.67,46.52 128.55,46.64 JDIMM1.101
DDRA_CLK0#: length 57.4
  IN1 w0.17: v3(137.8,85.83) 137.82,85.81 137.82,85.58 136.96,84.73 136.96,81.91 136.3,81.25 136.3,79.67 136.1,79.46 136.1,68.93 134.28,67.11 133.74,67.11 133.23,66.6 133.23,66.06 132.89,65.72 132.35,65.72 130.9,64.26 130.9,63.79 131.31,63.38 131.31,62.82 131.17,62.69 131,62.69 130.4,63.29 129.93,63.29 129.51,62.87 129.51,62.4 130.61,61.29 130.61,61.04 130.37,60.8 130.12,60.8 129.01,61.9 128.54,61.9 127.95,61.31 127.95,60.85 128.17,60.62 128.17,60.38 127.95,60.15 127.95,46.17 127.26,45.48 127.26,45 127.63,44.63 128.02,44.63 v3(128.15,44.51)
  BOTTOM w0.165: v3(137.8,85.83) 138.27,86.3 UC1.Y29 ; JDIMM1.103 129.15,46.79 129.38,46.56 129.38,45.17 128.76,44.54 128.19,44.54 v3(128.15,44.51)
DDRA_CLK1: length 55.9
  IN1 w0.17: v3(128.73,41.99) 128.58,42.14 128.1,42.14 127.68,42.56 127.68,43.11 128.91,44.34 128.91,59.59 129.19,59.87 129.75,59.87 130.14,59.49 130.46,59.49 132.42,61.45 132.42,61.61 132.13,61.9 132.13,62.3 132.57,62.74 132.92,62.74 133.1,62.92 133.1,63.33 132.92,63.5 132.73,63.5 132.34,63.9 132.34,64.33 132.73,64.72 133.27,64.72 133.6,65.06 134.07,65.06 134.31,64.82 134.55,64.82 134.79,65.06 134.79,65.3 134.55,65.54 134.55,66.01 137.09,68.55 137.09,80.94 137.85,81.7 137.85,83.66 138.29,84.1 138.64,84.1 v3(138.84,84.31)
  BOTTOM w0.165: UC1.Y32 138.71,84.31 v3(138.84,84.31) ; v3(128.73,41.99) 128.96,42.22 129.1,42.22 129.33,41.99 129.33,41.39 128.91,40.97 128.91,40.64 128.85,40.58 JDIMM1.102
DDRA_CLK1#: length 55.8
  IN1 w0.17: v3(128.73,42.75) 128.73,42.57 128.58,42.42 128.21,42.42 127.96,42.68 127.96,42.99 129.19,44.23 129.19,59.48 129.31,59.59 129.63,59.59 130.02,59.21 130.57,59.21 132.7,61.33 132.7,61.73 132.41,62.01 132.41,62.19 132.68,62.46 133.04,62.46 133.38,62.8 133.38,63.44 133.04,63.78 132.85,63.78 132.62,64.01 132.62,64.22 132.85,64.44 133.38,64.44 133.71,64.78 133.95,64.78 134.19,64.54 134.67,64.54 135.07,64.94 135.07,65.41 134.83,65.65 134.83,65.89 137.37,68.43 137.37,80.83 138.13,81.59 138.13,83.54 138.41,83.82 138.61,83.82 v3(138.84,83.6)
  BOTTOM w0.165: JDIMM1.104 129.45,40.44 129.3,40.59 129.3,40.84 129.7,41.24 129.7,42.14 129.25,42.59 128.9,42.59 v3(128.73,42.75) ; UC1.Y33 138.8,83.6 v3(138.84,83.6)
DDRA_ODT0: length 53.2
  IN1 w0.183: v3(133.76,41) 133.43,41 133.23,40.8 133.23,39.96 133.43,39.76 134.58,39.76 134.78,39.96 134.78,41.05 135.16,41.43 135.64,41.43 135.79,41.58 135.79,48.06 136.41,48.67 136.41,56.45 145.72,65.76 145.72,74.73 144.31,76.13 v3(144.31,81.89)
  BOTTOM w0.102: v3(144.31,81.89) 144.7,82.28 UC1.AH34
  BOTTOM w0.17: v3(133.76,41) 133.27,41 133.13,40.86 133.13,40.49 133.05,40.41 JDIMM1.116
DDRA_ODT1: length 52.9
  IN1 w0.102: v3(143.53,82.68) 143.91,82.3 143.91,81.74 143.8,81.63
  IN1 w0.183: v3(133.76,42.22) 134.07,42.22 134.27,42.02 134.27,41.63 134.38,41.52 134.56,41.52 134.96,41.92 135.13,41.92 135.31,42.09 135.31,42.27 135.01,42.57 135.01,42.85 135.31,43.15 135.31,48.26 135.92,48.88 135.92,56.65 145.23,65.96 145.23,74.53 143.83,75.93 143.83,79.02 143.39,79.46 143.39,80.09 143.72,80.42 143.72,81.55 143.8,81.63
  BOTTOM w0.102: UC1.AH33 143.95,83.1 v3(143.53,82.68)
  BOTTOM w0.17: JDIMM1.120 134.25,40.47 134.6,40.82 134.6,42.02 134.4,42.22 v3(133.76,42.22)
DDRA_SBS0#: length 54.2
  IN1 w0.102: v3(141.27,82.78) 140.81,82.32 140.16,82.32 139.88,82.04 139.88,81.3
  IN1 w0.183: v3(131.63,46.16) 131.38,46.41 131.38,54.27 131.55,54.44 132.33,54.44 132.49,54.6 132.49,54.84 132.33,55 131.55,55 131.38,55.17 131.38,55.4 131.55,55.57 132.33,55.57 132.49,55.73 132.49,55.97 132.33,56.13 131.55,56.13 131.38,56.3 131.38,56.95 135.53,61.1 135.53,62.36 137.22,64.05 137.22,65.24 137.44,65.46 137.67,65.46 138.03,65.11 138.26,65.11 138.42,65.27 138.42,65.5 138.07,65.86 138.07,66.09 138.23,66.26 138.47,66.26 138.82,65.9 139.06,65.9 139.22,66.07 139.22,66.3 138.87,66.66 138.87,66.89 139.61,67.63 139.61,69.17 139.77,69.33 140.58,69.33 140.75,69.5 140.75,69.73 140.58,69.9 139.77,69.9 139.61,70.06 139.61,70.29 139.77,70.46 140.58,70.46 140.75,70.62 140.75,70.86 140.58,71.02 139.77,71.02 139.61,71.19 139.61,80.88 139.88,81.15 139.88,81.3
  BOTTOM w0.102: v3(141.27,82.78) 140.95,83.1 UC1.AC33
  BOTTOM w0.17: v3(131.63,46.16) 131.55,46.08 131.04,46.08 130.95,46.17 JDIMM1.109
DDRA_SBS1#: length 53.2
  IN1 w0.102: 138.63,79.49 138.63,80.99 139.22,81.58 139.22,82.63 139.57,82.98 140.28,82.98 140.55,83.25 140.55,84.56 v3(140.07,85.04)
  IN1 w0.183: 138.63,79.49 138.63,68.04 136.24,65.65 136.24,64.45 134.56,62.76 134.56,61.5 130.38,57.33 130.38,42.93 129.93,42.47 129.93,41.81 130.1,41.63 130.46,41.63 v3(130.94,42.12)
  BOTTOM w0.102: UC1.AB30 139.96,85.04 v3(140.07,85.04)
  BOTTOM w0.17: JDIMM1.108 130.65,40.48 130.44,40.7 130.44,41.61 v3(130.94,42.12)
DDRA_SBS2#: length 53.8
  IN1 w0.183: v3(131.69,82.81) 131.25,82.81 130.23,81.79 130.23,81.35 129.14,80.26 129.14,78.8 128.99,78.64 127.87,78.64 127.72,78.49 127.72,78.24 127.87,78.08 128.99,78.08 129.14,77.93 129.14,77.7 128.99,77.55 128.33,77.55 128.18,77.4 128.18,74.01 127.84,73.67 127.84,72.97 127.31,72.44 127.31,71.44 127.07,71.2 126.5,71.2 126.24,71.45 126.24,71.86 126.09,72.02 125.88,72.02 125.47,71.61 125.47,71.38 125.89,70.96 125.89,70.72 125.73,70.56 125.5,70.56 125.08,70.97 124.83,70.97 124.67,70.81 124.67,70.57 125.1,70.13 125.1,69.92 120.6,65.42 120.6,47.66 120.41,47.47 120.41,47.22 120.6,47.02 120.6,46.66 120.46,46.52 120.22,46.52 120.07,46.66 119.83,46.66 119.68,46.51 119.68,46.07 v3(119.84,45.9)
  BOTTOM w0.102: v3(131.69,82.81) 131.9,82.6 UC1.M34
  BOTTOM w0.17: JDIMM1.79 121.95,46.69 121.16,45.9 v3(119.84,45.9)
DDRA_SCAS#: length 53.7
  IN1 w0.183: v3(142.62,81.78) 142.62,81.04 142.41,80.83 142.41,75.97 142.05,75.6 142.05,75.36 142.28,75.13 143.25,75.13 144.25,74.13 144.25,67.59 144.07,67.41 143.16,67.41 143.01,67.26 143.01,67.03 143.44,66.6 143.67,66.6 143.85,66.78 144.05,66.78 144.23,66.6 144.23,66.34 142.96,65.08 142.75,65.08 142.11,65.71 141.84,65.71 141.66,65.54 141.66,65.21 142.22,64.65 142.22,64.34 141.91,64.03 141.6,64.03 141.29,64.33 141.06,64.33 140.89,64.17 140.89,63.93 141.2,63.63 141.2,63.4 141.03,63.23 140.8,63.23 140.49,63.54 140.26,63.54 137.97,61.25 137.97,60.09 134.94,57.06 134.94,50.85 134.32,50.23 134.32,45.11 134.19,44.99 v3(133.89,44.99)
  BOTTOM w0.102: v3(142.62,81.78) 143.1,82.25 UC1.AF34
  BOTTOM w0.17: JDIMM1.115 132.75,45.17 132.75,45.17 132.93,44.99 v3(133.89,44.99)
DDRA_SCS0#: length 53.5
  IN1 w0.102: v3(141.28,85.01) 141.7,84.59 141.7,82.57 141.44,82.32 141.44,81.61 141.31,81.48 141.31,81.23 140.95,80.88 140.95,80.78
  IN1 w0.183: 140.95,80.78 140.95,79.14 140.58,78.77 140.58,74.45 141.79,73.25 141.79,68.79 140.6,67.6 140.6,67.25 140.2,66.84 140.2,65.54 136.51,61.85 136.51,60.69 133.48,57.67 133.48,53.7 133.15,53.36 132.53,53.36 132.37,53.19 132.37,52.95 132.53,52.79 133.28,52.79 133.48,52.58 133.48,51.46 132.85,50.83 132.85,44.99 132.28,44.42 132.28,42.38 132.92,41.74 132.92,41.28 v3(132.54,40.9)
  BOTTOM w0.102: v3(141.28,85.01) 141.59,84.7 UC1.AE31
  BOTTOM w0.17: v3(132.54,40.9) 132.54,40.91 132.45,40.81 JDIMM1.114
DDRA_SCS1#: length 53.7
  IN1 w0.102: v3(143.63,84.18) 144.05,83.76 144.05,83.37 143.79,83.11 143.41,83.11 143.09,82.79 143.09,82.35 143.04,82.3 143.04,81.66
  IN1 w0.183: v3(134.8,44.76) 134.8,50.02 135.43,50.65 135.43,56.86 138.77,60.2 138.77,60.43 138.46,60.75 138.46,60.99 138.62,61.15 138.86,61.15 139.17,60.83 139.41,60.83 139.57,61 139.57,61.23 139.25,61.55 139.25,61.78 139.42,61.95 139.65,61.95 139.97,61.63 140.2,61.63 140.37,61.8 140.37,62.03 140.05,62.35 140.05,62.58 140.22,62.75 140.45,62.75 140.77,62.43 141,62.43 144.74,66.17 144.74,66.83 144.55,67.02 144.55,67.2 144.74,67.39 144.74,74.33 143.45,75.62 143.11,75.62 142.9,75.83 142.9,76.22 143.07,76.38 143.15,76.38 143.31,76.55 143.31,76.78 143.15,76.95 143.07,76.95 142.9,77.11 142.9,77.35 143.07,77.51 143.15,77.51 143.31,77.68 143.31,77.91 143.15,78.08 143.07,78.08 142.9,78.24 142.9,80.34 143.21,80.65 143.21,81.49 143.04,81.66
  BOTTOM w0.102: v3(143.63,84.18) 143.63,84.43 UC1.AG31
  BOTTOM w0.17: v3(134.8,44.76) 134.55,45.01 JDIMM1.121
DDRA_SDM0: length 87.3
  IN1 w0.102: v3(126.03,99.7) 125.72,100 123.88,100
  IN1 w0.114: v3(97.64,45.24) 97.52,45.24 97.37,45.39 97.37,50.02 97.67,50.32 97.67,50.52 97.37,50.82 97.37,51.76 97.67,52.07 97.67,64.25 98.32,64.9 98.88,64.9 98.99,65.01 98.99,65.28 98.88,65.39 98.22,65.39 98.11,65.51 98.11,65.75 98.25,65.89 98.88,65.89 98.99,66 98.99,66.27 98.88,66.38 97.79,66.38 97.67,66.5 97.67,66.78 97.8,66.91 99.93,66.91 100.14,67.12 100.14,67.36 99.9,67.59 99.9,67.92 100.14,68.15 100.14,80.39 100.25,80.5 100.64,80.5 100.77,80.63 100.77,80.8 100.64,80.93 100.25,80.93 100.14,81.04 100.14,81.24 100.25,81.35 101.07,81.35 101.2,81.48 101.2,81.72 101.09,81.84 100.33,81.84 100.21,81.96 100.21,82.14 100.33,82.26 101.09,82.26 101.2,82.38 101.2,87.16 110.23,96.19 110.61,96.19 110.77,96.35 111.07,96.35 111.23,96.19 111.53,96.19 111.68,96.35 111.99,96.35 112.14,96.19 112.44,96.19 112.6,96.35 112.9,96.35 113.06,96.19 113.36,96.19 113.51,96.35 113.81,96.35 113.97,96.19 114.27,96.19 114.43,96.35 114.73,96.35 114.88,96.19 115.24,96.19 118.69,99.64 120.82,99.64 121.21,100.03 121.97,100.03 121.99,100 123.88,100
  BOTTOM w0.102: UC1.E13 126.3,99.42 v3(126.03,99.7) ; v3(97.64,45.24) 98.43,45.24 99.15,45.96 JDIMM1.11
DDRA_SDM1: length 76.6
  IN1 w0.102: v3(125.98,94.92) 125.9,94.85 124.44,94.85 123.73,94.14 123.45,94.14 123.04,93.73
  IN1 w0.114: 123.04,93.73 122.28,93.73 122.19,93.63 121.22,93.63 120.03,92.43 119.31,92.43 116.72,89.84 111.82,89.84 106.94,84.97 106.94,64.41 106.81,64.28 106.22,64.28 106.02,64.09 106.02,52.97 103.59,50.53 103.59,44.1 103.46,43.97 102.75,43.97 102.62,43.85 102.62,43.67 102.75,43.55 103.9,43.55 104.02,43.44 104.02,43.21 103.89,43.08 103.23,43.08 103.1,42.96 103.1,42.77 103.22,42.66 103.89,42.66 104.02,42.53 104.02,42.36 103.89,42.23 103.41,42.23 103.28,42.1 103.28,41.93 103.41,41.8 103.61,41.8 103.74,41.67 103.74,41.48 103.61,41.36 103.43,41.36 103.31,41.23 103.31,41.05 103.43,40.92 104.23,40.92 v3(104.25,40.9)
  BOTTOM w0.102: v3(125.98,94.92) 125.97,94.92 125.68,94.92 UC1.D18 ; v3(104.25,40.9) JDIMM1.28
DDRA_SDM2: length 68.3
  IN1 w0.102: v3(129.18,92.51) 127.88,91.22 124.77,91.22 123.83,90.28
  IN1 w0.114: 123.83,90.28 122.95,89.4 122.33,89.4 121.42,88.5 121.16,88.5 118.57,85.91 113.44,85.91 110.91,83.37 110.91,52.18 109.02,50.3 109.02,47.2 108.36,46.54 108.36,43.07 108.76,42.67 108.76,41.76 v3(109.04,41.48)
  BOTTOM w0.102: UC1.H22 129.18,92.37 v3(129.18,92.51) ; JDIMM1.46 109.65,40.87 v3(109.04,41.48)
DDRA_SDM3: length 60.2
  IN1 w0.102: 123.75,83.58 123.75,85.15 124.58,85.97 124.58,86.63 124.77,86.82 125.46,86.82 125.71,87.07 127.8,87.07 v3(128.41,87.68)
  IN1 w0.114: 123.75,83.58 122.79,82.61 122.79,82.05 122.64,81.89 122.31,81.89 122.05,81.64 122.05,80.55 122.18,80.42 122.62,80.42 122.75,80.29 122.75,80.08 122.64,79.97 122.17,79.97 122.05,79.85 122.05,79.65 122.17,79.54 122.64,79.54 122.75,79.42 122.75,79.23 122.64,79.11 122.17,79.11 122.05,79 122.05,78.8 122.17,78.69 122.64,78.69 122.75,78.57 122.75,77.5 119.64,74.38 119.64,73.34 115.66,69.36 115.66,49.82 113.93,48.09 113.93,44.28 v3(113.44,43.79)
  BOTTOM w0.102: UC1.H27 128.7,87.97 v3(128.41,87.68) ; v3(113.44,43.79) 114.75,45.1 JDIMM1.63
DDRA_SDM4: length 55.7
  IN1 w0.102: 146.26,81.31 146.26,82.99 145.64,83.61 145.64,83.91 144.91,84.64 144.18,84.64 v3(143.52,85.3)
  IN1 w0.114: v3(137.6,43.29) 137.57,43.31 137.57,47.26 138.21,47.89 138.21,55.76 140.88,58.43 141.04,58.43 141.48,57.99 141.64,57.99 141.83,58.18 141.83,58.34 141.39,58.78 141.39,58.94 141.53,59.08 142.74,59.08 147.55,63.9 147.55,76.2 146.06,77.69 146.06,81.11 146.26,81.31
  BOTTOM w0.102: UC1.AG30 143.9,85.68 v3(143.52,85.3) ; v3(137.6,43.29) 139.05,41.83 JDIMM1.136
DDRA_SDM5: length 65.6
  IN1 w0.102: 148.8,86.75 148.59,86.75 147.29,88.04 146.47,88.04 v3(145.69,88.83)
  IN1 w0.114: v3(144.81,45.62) 145.14,45.62 145.24,45.72 145.24,46.49 145.12,46.61 144.91,46.61 144.79,46.74 144.79,46.98 144.9,47.09 145.13,47.09 145.24,47.21 145.24,47.4 145.13,47.52 144.9,47.52 144.79,47.63 144.79,47.83 144.9,47.95 145.13,47.95 145.24,48.06 145.24,48.26 145.13,48.37 144.9,48.37 144.79,48.49 144.79,48.68 144.9,48.8 145.13,48.8 145.24,48.91 145.24,49.11 145.13,49.23 144.9,49.23 144.79,49.34 144.79,49.54 144.9,49.65 145.13,49.65 145.24,49.77 145.24,49.97 145.13,50.08 144.9,50.08 144.79,50.19 144.79,50.39 144.9,50.51 145.13,50.51 145.24,50.62 145.24,50.82 145.13,50.93 144.9,50.93 144.79,51.05 144.79,51.25 144.9,51.36 145.19,51.36 145.32,51.48 145.32,51.66 145.19,51.79 144.9,51.79 144.79,51.9 144.79,52.05 145,52.26 145,52.49 144.79,52.71 144.79,52.91 144.91,53.04 145.09,53.04 145.88,52.25 146.06,52.25 146.18,52.38 146.18,52.56 145.35,53.39 145.35,53.56 145.48,53.68 145.65,53.68 146.49,52.84 146.64,52.84 147.2,53.4 147.2,53.56 147.16,53.6 147.16,53.77 147.3,53.91 147.46,53.91 147.5,53.86 147.67,53.86 147.81,54 147.81,54.16 147.76,54.21 147.76,54.37 147.9,54.51 148.06,54.51 148.11,54.47 148.27,54.47 148.41,54.61 148.41,54.77 148.37,54.81 148.37,54.97 148.51,55.11 148.67,55.11 148.71,55.07 148.87,55.07 149.01,55.21 149.01,55.37 148.97,55.41 148.97,55.58 149.11,55.72 149.27,55.72 149.32,55.67 149.48,55.67 149.62,55.81 149.62,55.97 149.57,56.02 149.57,56.18 149.71,56.32 149.88,56.32 149.92,56.28 150.08,56.28 150.22,56.42 150.22,56.58 150.18,56.62 150.18,56.78 150.32,56.92 150.48,56.92 150.52,56.88 150.68,56.88 150.82,57.02 150.82,57.18 150.78,57.23 150.78,57.39 153.23,59.84 153.23,67.12 153.9,67.79 153.9,77.96 152.81,79.05 152.81,82.66 149.33,86.14 149.33,86.47 149.05,86.75 148.8,86.75
  BOTTOM w0.102: v3(144.81,45.62) 144.71,45.52 144.53,45.52 144.41,45.65 144.41,46.54 144.15,46.79 JDIMM1.153 ; UC1.AK26 146.17,88.83 v3(145.69,88.83)
DDRA_SDM6: length 78.3
  IN1 w0.114: v3(149.25,40.87) 149.69,41.31 149.69,41.81 149.54,41.97 149.54,47.92 150.42,48.81 150.42,49.72 156.58,55.88 156.58,56.61 157.91,57.94 157.91,61.62 158.37,62.09 159.21,62.09 159.34,62.21 159.34,62.45 159.21,62.58 159,62.58 158.88,62.7 158.88,62.96 159,63.08 159.54,63.08 159.65,63.19 159.65,63.46 159.54,63.57 159,63.57 158.88,63.69 158.88,63.95 159,64.07 159.54,64.07 159.65,64.18 159.65,64.45 159.54,64.56 159,64.56 158.88,64.68 158.88,64.94 159,65.06 159.54,65.06 159.65,65.17 159.65,65.44 159.54,65.55 159,65.55 158.88,65.67 158.88,65.93 159,66.05 159.54,66.05 159.65,66.16 159.65,66.43 159.54,66.54 159,66.54 158.88,66.66 158.88,66.92 159,67.04 159.54,67.04 159.65,67.15 159.65,72.45 163.72,76.52 163.72,83.41 161.55,85.59 158.89,85.59 158.61,85.31 158.03,85.31 151.9,91.44 149.61,91.44 149.49,91.57 148.29,91.57 147.66,92.21 147.45,92.21 v3(146.79,92.87)
  BOTTOM w0.102: v3(146.79,92.87) 146.72,92.94 146.72,93.08 UC1.AK20 ; JDIMM1.170 v3(149.25,40.87)
DDRA_SDM7: length 87.8
  IN1 w0.102: v3(143.53,98.45) 143.98,98.91 145.84,98.91 146.4,98.35 147.61,98.35
  IN1 w0.114: v3(156.34,45.34) 156.59,45.59 156.59,47.37 158.78,49.56 158.78,49.72 158.61,49.89 158.61,50.05 158.75,50.19 158.91,50.19 159.08,50.02 159.24,50.02 159.38,50.16 159.38,50.32 159.21,50.49 159.21,50.65 159.35,50.79 159.52,50.79 159.68,50.62 159.85,50.62 159.99,50.76 159.99,50.93 159.82,51.09 159.82,51.26 159.96,51.4 160.12,51.4 160.29,51.23 160.45,51.23 160.59,51.37 160.59,51.53 160.42,51.7 160.42,51.86 160.56,52 160.72,52 160.89,51.83 161.05,51.83 162.17,52.95 162.17,53.11 162.02,53.27 162.02,53.48 162.21,53.67 162.37,53.67 162.54,53.51 162.7,53.51 162.84,53.65 162.84,53.81 162.68,53.97 162.68,54.14 162.82,54.28 162.98,54.28 163.14,54.11 163.31,54.11 163.45,54.25 163.45,54.41 163.28,54.58 163.28,54.74 163.42,54.88 163.58,54.88 163.75,54.71 163.91,54.71 164.05,54.85 164.05,55.01 163.88,55.18 163.88,55.34 164.02,55.48 164.18,55.48 164.35,55.32 164.51,55.32 164.65,55.46 164.65,55.62 164.49,55.78 164.49,55.95 166.13,57.59 166.13,63.87 170.35,68.09 170.35,84.86 162.37,92.84 160.54,92.84 157.71,95.66 156.34,95.66 154.96,97.05 153.01,97.05 152.31,97.74 148.54,97.74 148.09,98.2 147.76,98.2 147.61,98.35
  BOTTOM w0.102: UC1.AF14 143.1,98.03 v3(143.53,98.45) ; JDIMM1.187 154.35,46.8 154.74,46.41 155.33,46.41 156.13,45.61 156.13,45.56 v3(156.34,45.34)
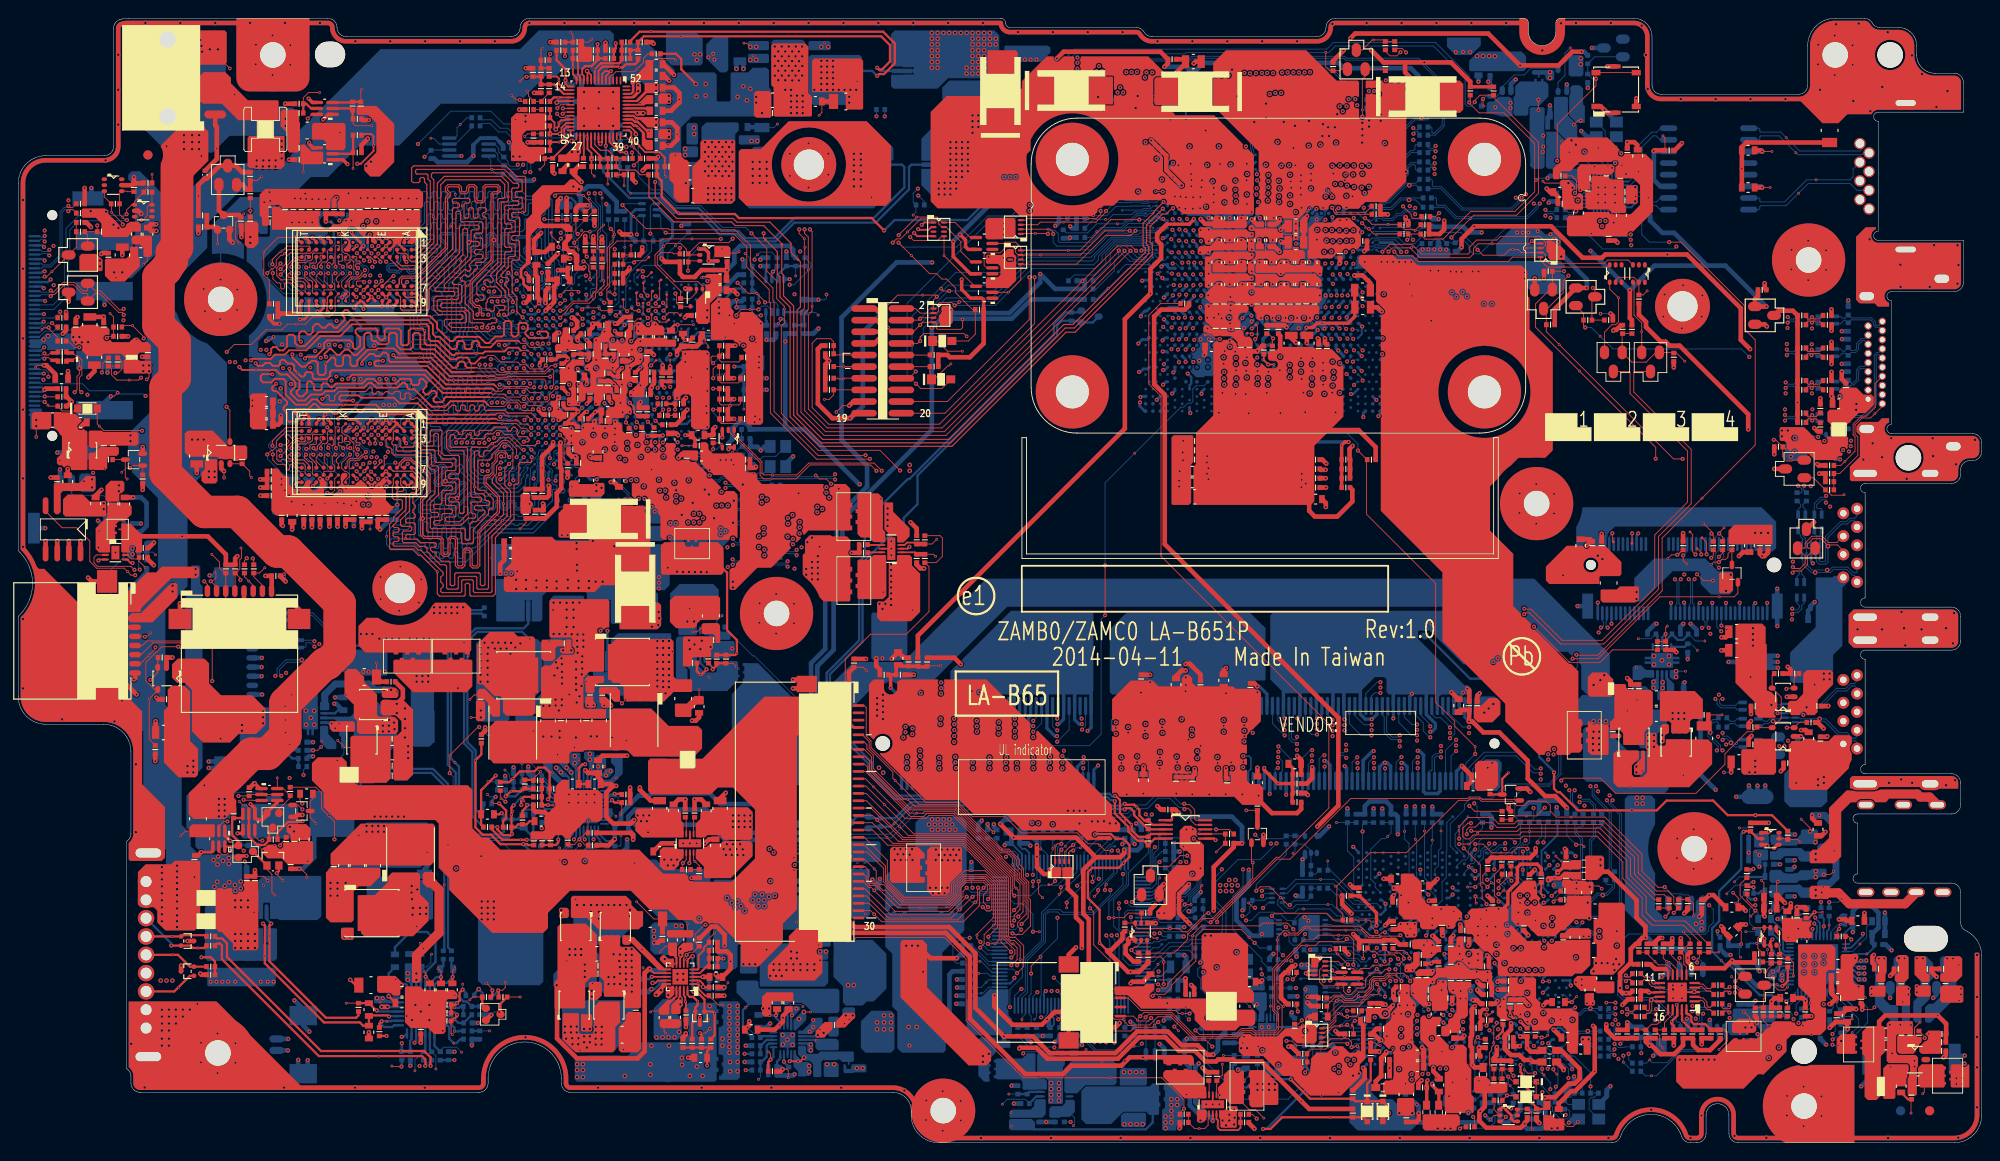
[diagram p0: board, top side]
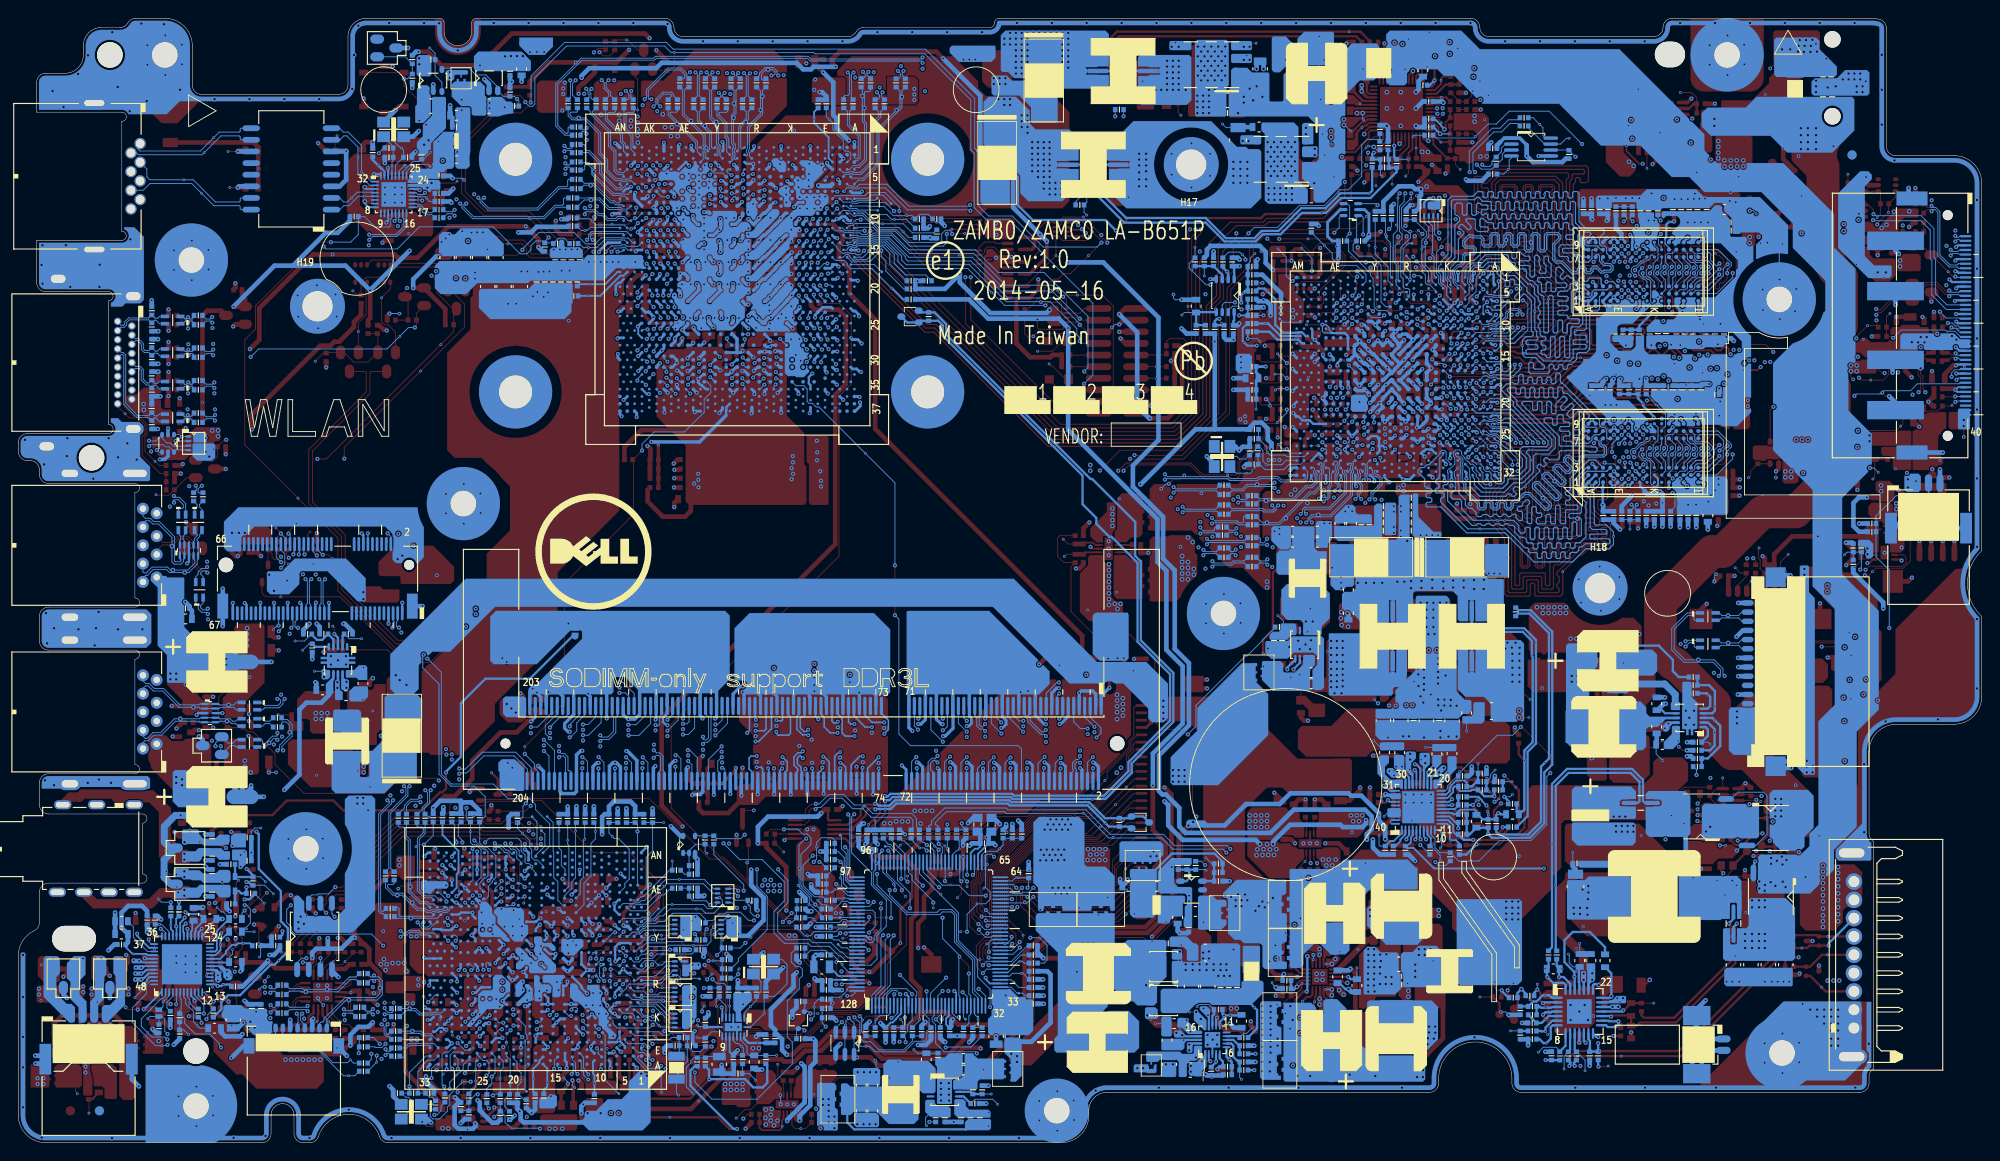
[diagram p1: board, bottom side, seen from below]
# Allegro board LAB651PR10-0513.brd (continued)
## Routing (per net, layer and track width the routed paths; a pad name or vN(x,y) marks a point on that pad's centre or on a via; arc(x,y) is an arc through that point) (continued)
DDRA_SDQ0: length 87.4
  IN1 w0.102: v3(128.34,99.65) 127.52,100.46 124.29,100.46
  IN1 w0.114: v3(96.65,44.25) 96.2,44.71 96.2,45.6 96.53,45.93 96.53,52.11 96.84,52.41 96.84,67.8 99.3,70.26 99.3,84.79 99.41,84.9 100.2,84.9 100.31,85.01 100.31,85.21 100.2,85.33 99.41,85.33 99.3,85.44 99.3,85.64 99.41,85.75 100.19,85.75 100.31,85.88 100.31,86.05 100.19,86.18 99.76,86.18 99.6,86.34 99.6,86.77 110.04,97.21 115.08,97.21 118.34,100.47 120.47,100.47 120.93,100.93 121.49,100.93 121.79,101.22 123.53,101.22 124.29,100.46
  BOTTOM w0.102: v3(128.34,99.65) 128.34,99.46 UC1.H13 ; JDIMM1.5 97.35,46.47 96.17,45.29 96.17,44.73 v3(96.65,44.25)
DDRA_SDQ1: length 87.3
  IN1 w0.102: v3(126.79,99.75) 126.3,100.23 124.08,100.23
  IN1 w0.114: v3(96.88,45.42) 96.95,45.49 96.95,51.93 97.26,52.24 97.26,64.42 97.75,64.91 97.75,65.28 97.26,65.77 97.26,67.15 97.43,67.33 99.35,67.33 99.47,67.45 99.47,67.68 99.35,67.8 98.02,67.8 97.9,67.93 97.9,68.17 98.02,68.3 99.39,68.3 99.72,68.63 99.72,82.59 99.83,82.71 100.63,82.71 100.74,82.82 100.74,83.02 100.63,83.14 99.83,83.14 99.72,83.25 99.72,83.45 99.83,83.56 100.63,83.56 100.74,83.68 100.74,83.87 100.63,83.99 99.83,83.99 99.72,84.1 99.72,84.3 99.83,84.42 100.63,84.42 100.74,84.53 100.74,87.3 110.22,96.78 115.24,96.78 118.51,100.05 120.65,100.05 121.1,100.51 122.08,100.51 122.21,100.39 123.93,100.39 124.08,100.23
  BOTTOM w0.102: JDIMM1.7 97.95,46.49 v3(96.88,45.42) ; v3(126.79,99.75) 127.1,99.44 UC1.F13
DDRA_SDQ2: length 87.2
  IN1 w0.102: 123.8,97.64 125.32,97.64 125.65,97.97 126.27,97.97 126.59,97.64 127.83,97.64 v3(128.21,97.26)
  IN1 w0.114: 123.8,97.64 123.39,97.64 122.76,97.01 119.74,97.01 118.78,96.04 118.15,96.04 115.36,93.26 110.35,93.26 103.41,86.31 103.41,79.23 103.3,79.12 102.47,79.12 102.36,79.01 102.36,78.81 102.47,78.69 103.3,78.69 103.41,78.58 103.41,78.38 103.3,78.27 102.47,78.27 102.36,78.15 102.36,61.65 102.24,61.53 100.84,61.53 100.72,61.4 100.72,61.16 100.84,61.04 102.24,61.04 102.36,60.92 102.36,60.66 102.24,60.54 99.98,60.54 99.85,60.41 99.85,60.17 99.98,60.05 102.24,60.05 102.36,59.93 102.36,59.57 102.24,59.46 100.84,59.46 100.72,59.33 100.72,59.02 100.6,58.91 100.4,58.91 100.29,59.02 100.29,59.33 100.16,59.46 99.97,59.46 99.83,59.31 99.83,48.57 99.94,48.46 100.32,48.46 100.44,48.35 100.44,48.08 100.32,47.96 99.94,47.96 99.83,47.85 99.83,47.38 100.72,46.49 v3(100.72,46.31)
  BOTTOM w0.102: UC1.H16 128.7,96.77 v3(128.21,97.26) ; v3(100.72,46.31) 100.35,46.68 JDIMM1.15
DDRA_SDQ3: length 87
  IN1 w0.102: v3(126.71,97.23) 126.58,97.23 126.2,97.62 125.75,97.62 125.44,97.31 124.1,97.31
  IN1 w0.114: 124.1,97.31 123.47,97.31 122.75,96.59 119.92,96.59 118.94,95.61 118.31,95.61 115.53,92.84 110.54,92.84 103.89,86.19 103.89,77.86 103.78,77.74 102.89,77.74 102.77,77.63 102.77,77.43 102.89,77.32 103.78,77.32 103.89,77.2 103.89,77 103.78,76.89 102.89,76.89 102.77,76.78 102.77,59.15 102.66,59.04 101.25,59.04 101.12,58.91 101.12,58.67 101.25,58.54 102.9,58.54 103.03,58.42 103.03,58.18 102.9,58.05 100.37,58.05 100.26,57.94 100.26,57.67 100.37,57.55 102.66,57.55 102.77,57.44 102.77,57.21 102.65,57.08 100.39,57.08 100.26,56.95 100.26,56.66 100.37,56.54 102.62,56.54 102.75,56.42 102.75,56.18 102.62,56.05 100.37,56.05 100.26,55.94 100.26,55.58 100.37,55.46 101.01,55.46 101.12,55.35 101.12,55.08 101.01,54.97 100.37,54.97 100.26,54.86 100.26,49.53 v3(100.74,49.05)
  BOTTOM w0.102: v3(100.74,49.05) 100.74,49.08 100.95,48.87 JDIMM1.17 ; v3(126.71,97.23) 127.1,96.85 UC1.F16
DDRA_SDQ4: length 86
  IN1 w0.114: v3(127.63,100.89) 126.94,101.58 124.64,101.58 124.16,102.06 121.44,102.06 121.15,101.77 120.58,101.77 120.14,101.32 118.01,101.32 114.79,98.11 109.74,98.11 98.46,86.84 98.46,70.61 96,68.15 96,52.76 95.69,52.46 95.69,46.28 95.36,45.94 95.36,44.3 95.54,44.12 95.54,42.37 96.98,40.92 97.02,40.92 v3(97.05,40.9)
  BOTTOM w0.102: v3(127.63,100.89) 127.9,100.62 UC1.G11 ; v3(97.05,40.9) JDIMM1.4
DDRA_SDQ5: length 85.8
  IN1 w0.114: v3(126.05,100.87) 125.62,101.3 123.98,101.3 123.64,101.64 121.61,101.64 121.32,101.35 120.76,101.35 120.3,100.89 118.17,100.89 114.97,97.69 109.91,97.69 98.88,86.66 98.88,70.44 96.42,67.97 96.42,52.59 96.11,52.28 96.11,46.11 95.78,45.77 95.78,44.52 95.99,44.3 95.99,43.72 96.11,43.61 96.92,43.61 97.03,43.49 97.03,43.23 96.92,43.11 96.11,43.11 95.99,43 95.99,42.55 96.42,42.12 v3(97.06,42.12)
  BOTTOM w0.102: JDIMM1.6 97.65,41.53 v3(97.06,42.12) ; UC1.E11 126.3,100.62 v3(126.05,100.87)
DDRA_SDQ6: length 85.6
  IN1 w0.114: v3(125.9,98.68) 125.46,98.68 125.16,98.38 122.92,98.38 122.84,98.3 119.18,98.3 114.97,94.09 109.97,94.09 102.57,86.69 102.57,80.51 101.52,79.45 101.52,63.62 101.4,63.51 99.19,63.51 99.09,63.4 99.09,63.16 99.24,63.01 101.38,63.01 101.5,62.88 101.5,62.64 101.38,62.51 99.29,62.51 98.99,62.21 98.99,46.11 99.14,45.95 99.14,42.1 99.26,41.98 99.41,41.98 99.52,41.87 99.52,41.64 99.41,41.53 99.26,41.53 99.14,41.41 99.14,41.1 99.37,40.87 v3(100.59,40.87)
  BOTTOM w0.102: v3(100.59,40.87) 100.65,40.81 JDIMM1.16 ; v3(125.9,98.68) 125.9,98.66 126.3,98.26 UC1.E14
DDRA_SDQ7: length 85.5
  IN1 w0.102: 125.28,98.05 125.48,98.25 126.45,98.25 126.65,98.05 128.67,98.05 129.1,98.48 v3(129.15,98.48)
  IN1 w0.114: v3(100.56,42.04) 100.29,42.04 99.68,42.65 99.68,44.44 99.79,44.55 100.56,44.55 100.69,44.68 100.69,44.92 100.56,45.05 99.79,45.05 99.68,45.16 99.68,46.05 99.41,46.32 99.41,60.87 99.52,60.99 99.9,60.99 100.03,61.11 100.03,61.37 99.9,61.5 99.54,61.5 99.41,61.62 99.41,61.93 99.54,62.06 101.81,62.06 101.94,62.18 101.94,79.28 102.99,80.33 102.99,86.5 110.16,93.67 115.16,93.67 119.36,97.87 123.04,97.87 123.14,97.96 125.2,97.96 125.28,98.05
  BOTTOM w0.102: v3(100.56,42.04) 101.17,41.43 101.17,40.62 101.25,40.54 JDIMM1.18 ; UC1.J14 129.15,98.25 v3(129.15,98.48)
DDRA_SDQ8: length 78.1
  IN1 w0.102: v3(129.12,96.09) 128.43,96.78 127.33,96.78 127.28,96.83 125.56,96.83 125.41,96.98 123.5,96.98 122.73,96.21 121.44,96.21
  IN1 w0.114: v3(100.77,50.27) 100.77,52.76 101.25,53.25 101.25,53.41 100.82,53.84 100.82,54 101.01,54.19 101.17,54.19 101.6,53.76 101.77,53.76 101.95,53.95 101.95,54.11 101.52,54.54 101.52,54.71 101.71,54.89 101.87,54.89 102.3,54.46 102.47,54.46 102.66,54.65 102.66,54.81 102.22,55.24 102.22,55.41 102.41,55.59 102.57,55.59 103.01,55.16 103.17,55.16 103.48,55.47 103.48,73.85 104.37,74.74 104.37,74.94 104.25,75.05 103.63,75.05 103.51,75.17 103.51,75.36 103.63,75.48 104.25,75.48 104.37,75.59 104.37,75.79 104.25,75.9 103.63,75.9 103.51,76.02 103.51,76.22 103.63,76.33 104.25,76.33 104.37,76.45 104.37,86.05 110.74,92.42 115.71,92.42 118.37,95.08 119,95.08 120.09,96.17 121.15,96.17 121.19,96.21 121.44,96.21
  BOTTOM w0.102: UC1.J17 129.12,95.88 v3(129.12,96.09) ; JDIMM1.21 102.15,49.09 100.97,50.27 v3(100.77,50.27)
DDRA_SDQ9: length 78.1
  IN1 w0.102: 122.08,95.19 122.7,95.19 123.61,96.09 125.97,96.09 v3(126.05,96.02)
  IN1 w0.114: 122.08,95.19 121.81,95.19 121.53,94.91 120.61,94.91 119.48,93.78 118.85,93.78 116.23,91.16 111.31,91.16 105.62,85.47 105.62,73.54 105.51,73.43 104.87,73.43 104.76,73.31 104.76,73.12 104.87,73 105.51,73 105.62,72.89 105.62,72.69 105.51,72.58 104.87,72.58 104.76,72.46 104.76,72.26 104.87,72.15 105.51,72.15 105.62,72.03 105.62,71.84 105.51,71.72 104.87,71.72 104.76,71.61 104.76,71.41 104.87,71.3 105.51,71.3 105.62,71.18 105.62,70.98 105.51,70.87 104.87,70.87 104.76,70.75 104.76,70.56 104.87,70.44 105.51,70.44 105.62,70.33 105.62,70.09 105.52,69.99 104.89,69.99 104.74,69.83 104.74,53.51 104.33,53.1 104.17,53.1 103.63,53.64 103.47,53.64 103.33,53.49 103.33,53.33 103.87,52.8 103.87,52.64 103.69,52.46 103.53,52.46 103,52.99 102.77,52.99 102.29,52.51 102.29,52.25 102.67,51.87 102.67,51.52 102.29,51.13 102.29,46.38 v3(102.19,46.28)
  BOTTOM w0.102: v3(126.05,96.02) 126.42,96.02 126.93,95.5 UC1.F17 ; JDIMM1.23 102.75,46.74 102.19,46.18 v3(102.19,46.28)
DDRA_SDQ10: length 77.9
  IN1 w0.102: v3(129.1,93.7) 128.57,94.24 126.54,94.24 126.49,94.29 125.79,94.29 125.25,93.76 124.1,93.76 123.57,93.23
  IN1 w0.114: 123.57,93.23 123.29,92.94 122.68,92.94 122.53,92.8 121.57,92.8 120.35,91.57 119.67,91.57 117.07,88.98 112.22,88.98 107.78,84.54 107.78,63.57 107.65,63.45 107.01,63.45 106.89,63.32 106.89,63.14 107.01,63.02 107.65,63.02 107.78,62.89 107.78,62.73 107.65,62.6 106.98,62.6 106.86,62.49 106.86,62.29 106.98,62.18 107.65,62.18 107.78,62.05 107.78,61.88 107.65,61.75 106.98,61.75 106.86,61.63 106.86,61.44 106.98,61.32 107.65,61.32 107.78,61.19 107.78,61.02 107.65,60.9 106.98,60.9 106.86,60.78 106.86,60.58 106.98,60.47 107.65,60.47 107.78,60.34 107.78,60.17 107.65,60.04 106.98,60.04 106.86,59.93 106.86,59.73 106.98,59.62 107.65,59.62 107.78,59.49 107.78,59.29 107.7,59.21 106.96,59.21 106.86,59.11 106.86,52.6 104.93,50.68 104.93,49.73 104.82,49.61 104.58,49.61 104.45,49.48 104.45,48.86 104.58,48.73 104.82,48.73 104.93,48.61 104.93,48.42 104.82,48.3 104.58,48.3 104.45,48.17 104.45,48 104.58,47.88 104.82,47.88 104.93,47.76 104.93,46.35 v3(104.66,46.08)
  BOTTOM w0.102: v3(104.66,46.08) 105.11,46.08 105.75,46.72 JDIMM1.33 ; v3(129.1,93.7) 129.1,93.5 UC1.H21
DDRA_SDQ11: length 77.9
  IN1 w0.102: v3(126.86,93.63) 126.41,94.09 126.01,94.09 125.45,93.53 124.26,93.53 123.32,92.59
  IN1 w0.114: 123.32,92.59 123.11,92.38 121.75,92.38 120.48,91.11 119.82,91.11 117.25,88.55 112.4,88.55 108.21,84.36 108.21,58.92 108.08,58.79 107.42,58.79 107.3,58.66 107.3,58.49 107.42,58.36 108.08,58.36 108.21,58.23 108.21,58.06 108.08,57.93 107.42,57.93 107.3,57.81 107.3,57.63 107.42,57.51 108.08,57.51 108.21,57.38 108.21,57.21 108.08,57.08 107.42,57.08 107.3,56.95 107.3,56.78 107.42,56.65 108.08,56.65 108.21,56.53 108.21,56.34 108.08,56.21 107.4,56.21 107.28,56.09 107.28,52.43 105.37,50.52 105.37,42.65 105.24,42.52 105.01,42.52 104.88,42.65 104.88,44.68 v3(104.68,44.89)
  BOTTOM w0.102: UC1.E21 126.34,93.1 v3(126.86,93.63) ; JDIMM1.35 106.35,46.56 v3(104.68,44.89)
DDRA_SDQ12: length 76.6
  IN1 w0.102: v3(127.1,96.1) 127.1,96.14 126.81,96.42 125.62,96.42 123.61,96.42 122.75,95.56 121.59,95.56
  IN1 w0.114: 121.59,95.56 121.36,95.33 120.44,95.33 119.32,94.21 118.69,94.21 116.05,91.58 111.12,91.58 105.21,85.66 105.21,74.39 104.32,73.5 104.32,54.58 103.92,54.18 103.38,54.18 101.87,52.68 101.87,46.69 101.63,46.45 101.63,43.4 101.78,43.25 102.4,43.25 102.63,43.02 102.63,42.59 102.85,42.37 102.85,41.38 v3(102.39,40.92)
  BOTTOM w0.102: v3(102.39,40.92) 102.45,40.87 JDIMM1.22 ; UC1.E16 126.5,96.7 v3(127.1,96.1)
DDRA_SDQ13: length 77
  IN1 w0.102: 121.77,95.92 122.78,95.92 123.56,96.7 125.23,96.7 125.31,96.63 127.19,96.63 127.24,96.58 127.33,96.58 v3(127.78,96.14)
  IN1 w0.114: v3(102.32,42.14) 102.29,42.14 101.2,43.24 101.2,47.25 101.36,47.41 101.36,52.76 103.9,55.3 103.9,73.68 104.79,74.57 104.79,85.85 110.93,92 115.88,92 118.53,94.64 119.16,94.64 120.26,95.75 121.2,95.75 121.37,95.92 121.77,95.92
  BOTTOM w0.102: UC1.G17 127.9,96.01 v3(127.78,96.14) ; JDIMM1.24 103.05,41.41 v3(102.32,42.14)
DDRA_SDQ14: length 76.6
  IN1 w0.102: 123.28,93.46 123.66,93.84 123.79,93.84 123.98,94.03 125.18,94.03 125.63,94.49 126.36,94.49 v3(126.69,94.82)
  IN1 w0.114: 123.28,93.46 123.13,93.31 122.46,93.31 122.36,93.21 121.4,93.21 120.19,92 119.49,92 116.9,89.41 112.05,89.41 107.36,84.73 107.36,64 107.23,63.87 106.55,63.87 106.44,63.76 106.44,52.79 104.03,50.39 104.03,47.58 104.16,47.45 104.39,47.45 104.5,47.34 104.5,47.14 104.39,47.02 104.16,47.02 104.03,46.9 104.03,44.11 104.44,43.71 104.44,42 104.68,41.76 104.68,40.75 104.81,40.62 105.04,40.62 105.16,40.75 105.16,41.97 105.29,42.09 105.47,42.09 105.59,41.97 105.59,40.75 105.72,40.62 105.92,40.62 106.05,40.75 v3(106.05,40.9)
  BOTTOM w0.102: JDIMM1.34 v3(106.05,40.9) ; UC1.F19 127.1,94.41 v3(126.69,94.82)
DDRA_SDQ15: length 76.8
  IN1 w0.102: 123.16,92.09 123.26,92.09 124.47,93.3 125.72,93.3 126.05,93.63 126.13,93.63 v3(126.18,93.68)
  IN1 w0.114: v3(106.05,42.07) 106.05,42.22 106.18,42.35 106.7,42.35 106.83,42.47 106.83,42.73 106.71,42.84 105.95,42.84 105.8,42.99 105.8,50.36 106.69,51.25 107.01,51.25 108.26,52.5 108.26,52.73 108.16,52.84 107.83,52.84 107.7,52.97 107.7,53.12 107.82,53.24 108.67,53.24 108.79,53.36 108.79,53.54 108.67,53.66 107.82,53.66 107.7,53.77 107.7,53.97 107.82,54.08 108.67,54.08 108.79,54.21 108.79,54.39 108.67,54.51 107.82,54.51 107.7,54.63 107.7,54.82 107.82,54.94 108.64,54.94 108.77,55.06 108.77,55.24 108.64,55.36 107.82,55.36 107.7,55.48 107.7,55.68 107.82,55.79 108.53,55.79 108.64,55.91 108.64,84.18 112.58,88.12 117.48,88.12 120.05,90.68 120.64,90.68 121.92,91.96 123.02,91.96 123.16,92.09
  BOTTOM w0.102: v3(126.18,93.68) 125.68,93.68 UC1.D20 ; v3(106.05,42.07) 106.65,41.47 JDIMM1.36
DDRA_SDQ16: length 69.7
  IN1 w0.102: 123.6,91.6 124.72,92.71 125.9,92.71 v3(126.08,92.54)
  IN1 w0.114: v3(107.07,45.9) 106.76,45.9 106.64,46.03 106.64,46.42 106.76,46.55 106.94,46.55 107.07,46.67 107.07,46.85 106.94,46.97 106.75,46.97 106.64,47.09 106.64,47.29 106.75,47.4 107.4,47.4 107.52,47.52 107.52,47.7 107.4,47.83 106.75,47.83 106.64,47.94 106.64,48.14 106.75,48.25 107.63,48.25 107.75,48.38 107.75,48.56 107.63,48.68 106.75,48.68 106.64,48.79 106.64,48.99 106.75,49.11 107.63,49.11 107.75,49.23 107.75,49.41 107.63,49.53 106.75,49.53 106.64,49.65 106.64,50.01 106.97,50.34 107.19,50.34 107.32,50.22 107.32,50.07 107.45,49.94 107.63,49.94 107.75,50.06 107.75,50.8 109.65,52.7 109.65,83.97 112.93,87.25 117.86,87.25 120.43,89.82 120.97,89.82 122.27,91.12 123.12,91.12 123.6,91.6
  BOTTOM w0.102: JDIMM1.39 107.55,46.38 107.07,45.91 v3(107.07,45.9) ; v3(126.08,92.54) 125.5,91.96 UC1.D22
DDRA_SDQ17: length 70.1
  IN1 w0.102: 123.4,91.88 124.52,92.99 126.41,92.99 v3(126.79,92.61)
  IN1 w0.114: 123.4,91.88 123.06,91.54 122.09,91.54 120.8,90.25 120.25,90.25 117.68,87.69 112.76,87.69 109.94,84.87 109.94,84.85 109.23,84.14 109.23,52.88 107.19,50.83 106.86,50.83 106.22,50.18 106.22,43.39 106.34,43.26 106.58,43.26 106.71,43.39 106.71,44.56 106.84,44.68 v3(107.04,44.68)
  BOTTOM w0.102: v3(107.04,44.68) 108.15,45.79 JDIMM1.41 ; v3(126.79,92.61) 126.79,92.39 UC1.E22
DDRA_SDQ18: length 69.7
  IN1 w0.102: 125,89.08 124.52,89.08 123.02,87.58 123.02,87 122.73,86.71
  IN1 w0.114: 125,89.08 125,89.09 v3(125.02,89.09) ; 122.73,86.71 122.45,86.43 121.57,86.43 118.67,83.53 118.67,83.04 118.79,82.92 118.97,82.92 119.08,82.81 119.08,82.54 118.97,82.43 118.79,82.43 118.67,82.31 118.67,82.05 118.79,81.93 118.97,81.93 119.08,81.82 119.08,81.55 118.97,81.44 118.79,81.44 118.67,81.32 118.67,81.11 118.8,80.98 118.99,80.98 119.12,80.85 119.12,80.4 118.96,80.24 118.8,80.24 118.7,80.34 118.54,80.34 118.4,80.2 118.4,80.04 118.5,79.94 118.5,79.78 117.94,79.22 117.48,79.22 114.43,76.17 114.43,75.96 115.63,74.76 115.63,74.58 115.51,74.46 115.33,74.46 114.08,75.7 113.91,75.7 113.78,75.58 113.78,75.4 115.03,74.16 115.03,73.98 114.9,73.85 114.73,73.85 113.48,75.1 113.3,75.1 113.18,74.98 113.18,74.8 114.42,73.55 114.42,73.38 114.3,73.25 114.12,73.25 113.02,74.36 112.86,74.36 112.72,74.22 112.72,74.03 113.8,72.95 113.8,72.78 113.67,72.65 113.49,72.65 112.91,73.24 112.73,73.24 112.61,73.11 112.61,72.94 113.22,72.34 113.22,72.16 113.09,72.03 112.92,72.03 112.87,72.08 112.69,72.08 112.6,71.99 112.6,71.78 112.72,71.66 112.72,51.04 112.55,50.86 112.38,50.86 112.3,50.95 112.12,50.95 112,50.82 112,50.64 112.08,50.56 112.08,50.4 111.94,50.26 111.78,50.26 111.68,50.36 111.51,50.36 111.38,50.23 111.38,50.05 111.48,49.96 111.48,49.79 111.34,49.65 111.18,49.65 111.11,49.73 110.94,49.73 110.84,49.62 110.84,46.09 v3(110.83,46.08)
  BOTTOM w0.102: v3(125.02,89.09) 125,89.09 125,89.07 125.08,89.07 125.12,89.03 125.45,88.7 UC1.D26 ; JDIMM1.51 111.15,46.4 v3(110.83,46.08)
DDRA_SDQ19: length 70
  IN1 w0.102: v3(125.94,89.03) 125.59,88.68 124.47,88.68 123.3,87.51 123.3,86.82 123.17,86.69
  IN1 w0.114: v3(110.83,44.89) 111.26,45.32 111.26,48.98 113.14,50.87 113.14,71.48 116.25,74.59 116.25,74.75 115.01,75.99 115.01,76.15 115.15,76.29 115.31,76.29 116.55,75.05 116.71,75.05 116.85,75.19 116.85,75.36 115.62,76.59 115.62,76.75 115.76,76.89 115.92,76.89 117.15,75.66 117.32,75.66 117.46,75.8 117.46,75.96 116.22,77.19 116.22,77.36 116.36,77.5 116.52,77.5 117.75,76.27 117.93,76.27 118.05,76.39 118.05,76.57 116.83,77.79 116.83,77.97 116.98,78.12 117.16,78.12 117.82,77.46 118,77.46 118.13,77.59 118.13,77.77 117.49,78.4 117.49,78.65 117.65,78.8 118.12,78.8 119.54,80.23 119.54,82.94 119.21,83.27 119.21,83.47 121.74,86.01 122.48,86.01 123.17,86.69
  BOTTOM w0.102: v3(110.83,44.89) 111.75,45.81 JDIMM1.53 ; v3(125.94,89.03) 126.3,89.39 UC1.E25
DDRA_SDQ20: length 68.7
  IN1 w0.102: 123.45,90.43 124.59,91.57 127.06,91.57 127.98,92.49 127.98,93.32 v3(128.31,93.65)
  IN1 w0.114: 123.45,90.43 122.84,89.82 122.15,89.82 121.26,88.93 120.94,88.93 118.4,86.39 113.32,86.39 110.49,83.56 110.49,52.35 108.6,50.47 108.6,47.37 107.93,46.7 107.93,42.9 108.34,42.5 108.34,41.33 v3(107.88,40.87)
  BOTTOM w0.102: v3(128.31,93.65) 128.31,93.51 UC1.G21 ; JDIMM1.40 107.85,40.84 v3(107.88,40.87)
DDRA_SDQ21: length 68.2
  IN1 w0.102: 123.55,91.06 124.34,91.85 126.76,91.85 v3(127.52,92.61)
  IN1 w0.114: 123.55,91.06 123.17,90.68 122.42,90.68 121.1,89.36 120.58,89.36 118.04,86.82 113.11,86.82 110.07,83.78 110.07,52.53 108.18,50.64 108.18,47.54 107.5,46.86 107.5,42.98 107.24,42.73 107.24,42.22 107.37,42.09 v3(107.88,42.09)
  BOTTOM w0.102: v3(127.52,92.61) 127.52,92.32 UC1.F22 ; v3(107.88,42.09) 108.45,41.52 JDIMM1.42
DDRA_SDQ22: length 68.4
  IN1 w0.102: v3(128.13,90.07) 127.92,90.07 127.44,89.59 125.84,89.59 125.77,89.53 124.63,89.53 122.69,87.58 122.69,87.1 122.43,86.85 122.13,86.85
  IN1 w0.114: 122.13,86.85 121.4,86.85 118.24,83.69 118.24,80.65 112.19,74.59 112.19,51.63 110.37,49.81 110.37,44.45 110.24,44.32 109.43,44.32 109.3,44.19 109.3,44 109.43,43.87 110.95,43.87 111.08,43.74 111.08,43.57 110.95,43.44 109.3,43.44 109.18,43.31 109.18,42.24 109.3,42.12 110.24,42.12 110.37,41.99 110.37,41.71 110.24,41.58 109.71,41.58 109.58,41.46 109.58,40.87 109.71,40.75 110.72,40.75 110.85,40.87 v3(110.85,40.9)
  BOTTOM w0.102: JDIMM1.50 v3(110.85,40.9) ; UC1.G24 128.13,90.47 v3(128.13,90.07)
DDRA_SDQ23: length 68.3
  IN1 w0.102: v3(129.07,90.05) 128.87,90.05 128.21,89.39 126.7,89.39 126.42,89.11 126.42,88.8 126.27,88.65 125.87,88.65 125.7,88.48 124.65,88.48 123.53,87.35 123.53,86.54
  IN1 w0.114: 123.53,86.54 122.56,85.58 121.91,85.58 119.96,83.63 119.96,80.05 118.56,78.65 118.56,76.28 113.56,71.29 113.56,50.69 111.68,48.81 111.68,44.99 111.56,44.87 111.42,44.87 111.31,44.76 111.31,44.56 111.42,44.45 111.56,44.45 111.68,44.33 111.68,43.12 111.56,43 109.73,43 109.61,42.88 109.61,42.7 109.73,42.57 111.56,42.57 111.68,42.46 111.68,41.07 111.55,40.95 111.39,40.95 111.26,41.08 111.26,41.99 111.13,42.11 v3(110.83,42.11)
  BOTTOM w0.102: v3(129.07,90.05) 129.07,90.33 UC1.H24 ; JDIMM1.52 111.45,41.49 v3(110.83,42.11)
DDRA_SDQ24: length 60
  IN1 w0.102: v3(126.03,87.71) 125.71,87.71 125.23,87.23 124.54,87.23 124.16,86.85 124.16,86.16 123.32,85.32 123.32,84.69 122.87,84.23 122.87,83.88
  IN1 w0.114: v3(113.45,45.04) 113.24,44.84 113.06,44.84 112.93,44.96 112.93,48.29 114.82,50.17 114.82,70.75 121.25,77.18 121.25,77.34 121.13,77.46 120.97,77.46 120.12,76.61 119.94,76.61 119.82,76.74 119.82,76.92 121.19,78.29 121.19,78.47 121.06,78.59 120.88,78.59 120.15,77.86 119.97,77.86 119.84,77.98 119.84,78.16 121.21,79.53 121.21,82.24 121.33,82.35 121.56,82.35 121.67,82.47 121.67,82.66 121.56,82.78 121.33,82.78 121.21,82.89 121.21,83 121.45,83.24 121.87,83.24 122.18,83.56 122.55,83.56 122.87,83.88
  BOTTOM w0.102: v3(113.45,45.04) 113.37,45.04 112.95,45.45 JDIMM1.57 ; v3(126.03,87.71) 126.3,87.98 UC1.E27
DDRA_SDQ25: length 59.8
  IN1 w0.102: 123.4,83.82 123.4,84.23 123.53,84.36 123.53,85.22 124.36,86.06 124.36,86.76 124.63,87.02 125.37,87.02 125.63,87.28 126.99,87.28 127.47,87.76 v3(127.52,87.76)
  IN1 w0.114: v3(113.45,46.31) 113.35,46.4 113.35,46.74 113.51,46.89 113.51,47.11 113.35,47.26 113.35,47.43 113.51,47.58 113.51,47.77 113.35,47.92 113.35,48.11 115.24,50 115.24,69.53 115.54,69.83 115.54,69.99 115.26,70.27 115.26,70.43 115.4,70.57 115.56,70.57 115.84,70.29 116,70.29 116.14,70.43 116.14,70.59 115.81,70.92 115.81,71.1 115.93,71.23 116.11,71.23 116.44,70.89 116.6,70.89 116.74,71.03 116.74,71.2 116.4,71.54 116.4,71.72 116.52,71.84 116.7,71.84 117.04,71.5 117.21,71.5 117.35,71.64 117.35,71.8 117,72.14 117,72.32 117.13,72.45 117.3,72.45 117.65,72.1 117.81,72.1 117.95,72.24 117.95,72.4 117.6,72.75 117.6,72.92 117.73,73.05 117.91,73.05 118.25,72.7 118.41,72.7 118.55,72.84 118.55,73.01 118.21,73.35 118.21,73.53 118.33,73.65 118.51,73.65 118.86,73.31 119.02,73.31 119.21,73.5 119.21,73.67 118.91,73.97 118.91,74.25 121.82,77.15 121.82,77.33 121.63,77.51 121.63,77.7 121.76,77.82 122.22,77.82 122.33,77.94 122.33,78.14 122.22,78.25 121.76,78.25 121.63,78.38 121.63,81.81 122.13,82.31 122.26,82.31 122.37,82.43 122.37,82.64 122.21,82.81 122.21,82.99 122.36,83.14 122.72,83.14 123.4,83.82
  BOTTOM w0.102: v3(127.52,87.76) 127.9,88.14 UC1.G27 ; JDIMM1.59 113.55,46.41 v3(113.45,46.31)
DDRA_SDQ26: length 59.9
  IN1 w0.114: v3(116.11,46.31) 116.13,46.31 116.59,45.85 116.77,45.85 116.88,45.96 116.88,46.72 116.77,46.84 116.24,46.84 116.11,46.96 116.11,47.2 116.24,47.33 116.77,47.33 116.88,47.45 116.88,47.89 117.81,48.82 117.81,66.64 121.75,70.58 121.75,71 121.62,71.12 120.83,71.12 120.73,71.23 120.73,71.42 121.16,71.86 121.34,71.86 121.47,71.73 121.63,71.73 121.77,71.87 121.77,72.03 121.67,72.14 121.67,72.31 121.79,72.44 121.97,72.44 122.08,72.33 122.24,72.33 122.41,72.51 122.41,72.67 122.18,72.9 121.9,72.9 121.77,73.03 121.77,73.46 121.91,73.61 122.08,73.61 122.72,72.97 122.88,72.97 123.02,73.11 123.02,73.27 122.38,73.91 122.38,74.07 122.52,74.21 122.68,74.21 123.32,73.57 123.48,73.57 123.62,73.71 123.62,73.87 122.98,74.51 122.98,74.67 123.12,74.81 123.29,74.81 123.92,74.18 124.08,74.18 124.22,74.32 124.22,74.48 123.59,75.11 123.59,75.28 123.73,75.42 123.89,75.42 124.53,74.78 124.69,74.78 124.82,74.91 124.82,75.09 124.19,75.72 124.19,75.88 124.31,76 124.52,76 124.64,75.87 124.81,75.87 124.88,75.95 124.88,79.77 125.61,80.5 125.61,80.8 126.68,81.87 126.68,84.23 126.5,84.41 126.5,84.54 126.63,84.66 126.88,84.66 127.01,84.79 127.01,84.98 v3(126.74,85.25)
  BOTTOM w0.102: JDIMM1.67 115.95,46.44 116.11,46.28 v3(116.11,46.31) ; v3(126.74,85.25) 126.74,85.46 UC1.E30
DDRA_SDQ27: length 59.7
  IN1 w0.114: v3(128.31,85.27) 127.11,84.07 127.11,81.71 126.03,80.63 126.03,80.32 125.3,79.6 125.3,74.8 122.17,71.67 122.17,70.41 118.23,66.47 118.23,48.65 117.3,47.72 117.3,43.1 118.9,41.5 118.9,40.92 118.7,40.72 117.51,40.72 117.4,40.82 117.4,42.27 116.8,42.88 116.8,44.4 116.67,44.53 116.34,44.53 116.16,44.71 v3(116.16,45.11)
  BOTTOM w0.102: UC1.G30 127.9,85.68 v3(128.31,85.27) ; v3(116.16,45.11) 116.55,45.5 JDIMM1.69
DDRA_SDQ28: length 58.2
  IN1 w0.102: 122.87,85.3 122.87,85.53 123.75,86.42 123.75,87.29 124.73,88.27 125.78,88.27 125.96,88.45 126.38,88.45 v3(126.84,88.9)
  IN1 w0.114: v3(112.65,40.89) 112.65,40.87 112.52,40.75 112.22,40.75 112.1,40.87 112.1,48.63 113.98,50.52 113.98,71.11 118.98,76.11 118.98,78.48 120.38,79.88 120.38,83.46 122.08,85.16 122.73,85.16 122.87,85.3
  BOTTOM w0.102: v3(112.65,40.89) JDIMM1.56 ; UC1.F25 127.1,89.17 v3(126.84,88.9)
DDRA_SDQ29: length 58.8
  IN1 w0.102: v3(128.26,88.95) 127.55,88.24 126.04,88.24 125.87,88.07 124.82,88.07 123.96,87.21 123.96,86.26 123.09,85.4 123.09,85.04
  IN1 w0.114: v3(112.66,42.17) 112.52,42.31 112.52,48.46 114.4,50.34 114.4,70.94 119.39,75.93 119.39,78.3 120.8,79.71 120.8,83.18 122.36,84.74 122.79,84.74 123.09,85.04
  BOTTOM w0.102: JDIMM1.58 113.25,41.57 v3(112.66,42.17) ; UC1.H25 128.7,89.39 v3(128.26,88.95)
DDRA_SDQ30: length 58.3
  IN1 w0.102: v3(125.1,85.02) 125.46,84.66 125.46,84.15
  IN1 w0.114: v3(116.29,40.9) 114.66,40.9 114.53,41.03 114.53,41.39 114.66,41.52 115.64,41.52 115.75,41.63 115.75,41.9 115.64,42.02 114.69,42.02 114.56,42.14 114.56,42.42 114.69,42.55 115.09,42.55 115.26,42.71 115.26,47.62 116.97,49.33 116.97,67.65 117.22,67.9 117.42,67.9 117.56,67.76 117.72,67.76 117.86,67.9 117.86,68.06 117.81,68.11 117.81,68.27 117.95,68.41 118.11,68.41 118.16,68.36 118.32,68.36 118.46,68.5 118.46,68.66 118.41,68.71 118.41,68.88 118.55,69.02 118.71,69.02 118.77,68.96 118.93,68.96 119.07,69.1 119.07,69.27 118.97,69.36 118.97,69.54 119.1,69.66 119.28,69.66 119.37,69.57 119.53,69.57 119.67,69.71 119.67,69.87 119.62,69.92 119.62,70.08 119.89,70.35 119.89,71.13 119.63,71.39 119.63,71.52 120.93,72.82 120.93,73.81 124.05,76.92 124.05,80.25 124.75,80.95 124.75,81.13 125.02,81.41 125.02,81.67 124.92,81.77 124.52,81.77 124.39,81.89 124.39,82.07 124.52,82.2 125.02,82.2 125.74,82.91 125.74,83.09 125.61,83.21 125.43,83.21 125.3,83.34 125.3,84 125.46,84.15
  BOTTOM w0.102: v3(125.1,85.02) 125.1,85.02 125.1,85.02 125.1,85.02 125.1,85.02 125.1,85.05 125.5,85.45 UC1.D30 ; JDIMM1.68 116.25,40.86 v3(116.29,40.9)
DDRA_SDQ31: length 58.2
  IN1 w0.102: 125.74,83.77 125.74,84.87 126.52,85.65 127.25,85.65 128.24,86.64 v3(128.29,86.64)
  IN1 w0.114: 125.74,83.77 125.94,83.57 126.12,83.57 126.24,83.44 126.24,82.79 125.55,82.1 125.55,81.34 125.18,80.96 125.18,80.75 124.46,80.04 124.46,76.75 121.35,73.63 121.35,72.65 120.31,71.6 120.31,70.79 120.39,70.71 120.79,70.71 120.91,70.58 120.91,70.41 120.79,70.29 120.44,70.29 120.32,70.17 120.32,69.75 117.39,66.81 117.39,49.15 116.46,48.23 116.46,47.88 116.33,47.75 115.99,47.75 115.68,47.44 115.68,44.23 115.8,44.1 116.24,44.1 116.36,43.97 116.36,43.79 116.24,43.67 115.83,43.67 115.7,43.54 115.7,43.34 115.83,43.21 116.26,43.21 116.38,43.1 116.38,42.71 116.98,42.1 116.98,41.92 116.85,41.79 116.67,41.79 v3(116.34,42.12)
  BOTTOM w0.102: v3(116.34,42.12) 116.36,42.12 116.85,41.63 JDIMM1.70 ; v3(128.29,86.64) 128.7,87.06 UC1.H28
DDRA_SDQ32: length 57
  IN1 w0.102: v3(145.89,84.26) 146.46,83.68 146.93,83.68 147.22,83.4 147.22,82.89 146.93,82.6 146.93,81.36
  IN1 w0.114: 146.93,81.36 146.99,81.3 146.99,79.72 147.28,79.43 147.28,77.7 148.96,76.01 148.96,73.65 148.85,73.54 148.51,73.54 148.39,73.42 148.39,73.16 148.51,73.04 148.85,73.04 148.96,72.93 148.96,72.66 148.85,72.55 148.51,72.55 148.39,72.43 148.39,72.17 148.51,72.05 148.85,72.05 148.96,71.94 148.96,71.67 148.85,71.56 148.51,71.56 148.39,71.44 148.39,71.18 148.51,71.06 148.85,71.06 148.96,70.95 148.96,70.68 148.85,70.57 148.51,70.57 148.39,70.45 148.39,70.18 148.51,70.07 148.85,70.07 148.96,69.96 148.96,69.69 148.85,69.58 148.51,69.58 148.39,69.46 148.39,63.48 139.69,54.77 139.69,53.94 139.05,53.3 139.05,46.99 139.25,46.79 139.25,46.11 139.55,45.8 139.55,45.01 139.1,44.56 139.1,43.44 138.97,43.31 138.64,43.31 138.51,43.44 138.51,44.25 v3(138.28,44.48)
  BOTTOM w0.102: v3(138.28,44.48) 138.26,44.48 136.95,45.79 JDIMM1.129 ; v3(145.89,84.26) 145.89,84.31 UC1.AJ31
DDRA_SDQ33: length 57
  IN1 w0.102: v3(146.8,83.24) 146.57,83.01 146.57,81
  IN1 w0.114: 146.57,81 146.48,80.92 146.48,77.89 147.97,76.39 147.97,75.64 148.09,75.53 148.43,75.53 148.55,75.41 148.55,75.14 148.43,75.03 148.09,75.03 147.97,74.92 147.97,74.65 148.09,74.54 148.43,74.54 148.55,74.42 148.55,74.15 148.43,74.04 148.09,74.04 147.97,73.93 147.97,63.67 141.66,57.35 141.49,57.35 141.05,57.8 140.88,57.8 140.74,57.66 140.74,57.5 141.19,57.05 141.19,56.89 141.05,56.75 140.89,56.75 140.44,57.2 140.28,57.2 140.14,57.06 140.14,56.89 140.59,56.45 140.59,56.28 140.45,56.14 140.29,56.14 139.84,56.59 139.68,56.59 139.54,56.45 139.54,56.29 139.99,55.84 139.99,55.68 139.85,55.54 139.68,55.54 139.24,55.99 139.07,55.99 138.93,55.85 138.93,55.69 139.38,55.24 139.38,55.08 139.24,54.93 139.08,54.93 138.94,55.07 138.75,55.07 138.63,54.94 138.63,54.61 138.74,54.5 139.13,54.5 139.25,54.38 139.25,54.18 139.13,54.07 138.74,54.07 138.63,53.95 138.63,47.45 138.5,47.32 138.31,47.32 138.18,47.2 138.18,46.87 138.31,46.74 138.65,46.74 138.83,46.56 138.83,45.93 139.13,45.63 139.13,45.32 138.96,45.14 138.82,45.14 v3(138.28,45.67)
  BOTTOM w0.102: JDIMM1.131 137.55,46.15 138.06,45.65 138.26,45.65 138.28,45.62 v3(138.28,45.67) ; v3(146.8,83.24) 146.7,83.34 146.7,83.5 UC1.AK32
DDRA_SDQ34: length 56.9
  IN1 w0.102: v3(146.8,86.53) 146.8,86.41 147.1,86.11 147.1,85.61 147.94,84.77 147.94,84.41 148.25,84.09 148.25,83.47 148.35,83.38
  IN1 w0.114: 148.35,83.38 150.03,81.69 150.03,78.15 151.2,76.98 151.2,68.9 150.52,68.23 150.52,62.51 142.25,54.23 142.25,52.5 142.13,52.39 141.93,52.39 141.81,52.27 141.81,52.08 141.93,51.96 142.13,51.96 142.25,51.85 142.25,51.65 142.13,51.53 141.93,51.53 141.81,51.42 141.81,51.22 141.93,51.11 142.13,51.11 142.25,50.99 142.25,50.8 142.13,50.68 141.93,50.68 141.81,50.57 141.81,50.37 141.93,50.25 142.13,50.25 142.25,50.14 142.25,49.94 142.13,49.83 141.93,49.83 141.81,49.71 141.81,49.52 141.93,49.4 142.13,49.4 142.25,49.29 142.25,49.09 142.13,48.97 141.93,48.97 141.81,48.86 141.81,48.66 141.93,48.55 142.13,48.55 142.25,48.43 142.25,48.24 142.13,48.12 141.93,48.12 141.81,48.01 141.81,47.81 141.93,47.69 142.13,47.69 142.25,47.58 142.25,47.38 142.13,47.27 141.93,47.27 141.81,47.15 141.81,46.95 141.93,46.84 142.13,46.84 142.25,46.73 142.25,44.69 142.04,44.49 141.88,44.49 141.81,44.56 v3(141.81,44.58)
  BOTTOM w0.102: JDIMM1.141 140.55,45.26 141.23,44.58 v3(141.81,44.58) ; UC1.AK28 146.3,87.04 v3(146.8,86.53)
DDRA_SDQ35: length 56.9
  IN1 w0.102: v3(143.39,87.79) 143.39,87.43 143.9,86.92 144.3,86.92 144.42,86.81 145.31,86.81 145.45,86.67 145.45,86.34 145.75,86.03 146,86.03 146.7,85.33 147.08,85.33 147.73,84.69 147.73,84.31 148.05,83.99 148.05,83.08 148.18,82.95
  IN1 w0.114: 148.18,82.95 148.74,82.4 148.74,82.24 148.64,82.14 148.64,81.98 148.78,81.84 148.94,81.84 149.04,81.93 149.2,81.93 149.41,81.72 149.41,81.54 149.33,81.46 149.26,81.46 149.13,81.34 149.13,81.13 149.26,81 149.49,81 149.61,80.88 149.61,80.67 149.49,80.55 149.1,80.55 148.98,80.42 148.98,80.22 149.1,80.09 149.46,80.09 149.61,79.94 149.61,79.84 149.38,79.61 149.38,79.46 149.61,79.23 149.61,79.02 149.51,78.92 149.32,78.92 149.09,78.7 149.09,78.48 150.78,76.79 150.78,69.08 150.1,68.4 150.1,62.68 141.83,54.41 141.83,53.74 141.71,53.62 141.48,53.62 141.38,53.52 141.38,53.29 141.51,53.17 141.7,53.17 141.81,53.06 141.81,52.86 141.7,52.74 141.49,52.74 141.38,52.63 141.38,45.88 141.51,45.75 v3(141.81,45.75)
  BOTTOM w0.102: v3(141.81,45.75) 141.38,45.75 141.15,45.98 JDIMM1.143 ; UC1.AF27 143.1,88.08 v3(143.39,87.79)
DDRA_SDQ36: length 55.6
  IN1 w0.114: v3(137.55,40.94) 137.55,40.52 137.42,40.39 136.89,40.39 136.73,40.54 136.73,47.6 137.37,48.24 137.37,56.12 144.52,63.27 144.68,63.27 145.1,62.84 145.27,62.84 145.45,63.03 145.45,63.19 145.03,63.62 145.03,63.78 145.22,63.97 145.38,63.97 145.8,63.54 145.97,63.54 146.16,63.73 146.16,63.89 145.73,64.32 145.73,64.48 145.92,64.67 146.08,64.67 146.34,64.4 146.52,64.4 146.69,64.57 146.69,64.75 146.43,65.02 146.43,65.18 146.72,65.47 146.72,75.85 145.22,77.34 145.22,81.08 145.14,81.16 145.14,83.86 v3(145.05,83.95)
  BOTTOM w0.102: v3(137.55,40.94) 137.38,40.94 137.25,40.8 JDIMM1.130 ; UC1.AJ33 v3(145.05,83.95)
DDRA_SDQ37: length 55.9
  IN1 w0.114: v3(145.86,82.76) 145.98,82.64 145.98,81.61 145.64,81.28 145.64,77.51 147.14,76.02 147.14,64.08 145.25,62.19 145.08,62.19 144.64,62.63 144.47,62.63 144.29,62.44 144.29,62.28 144.73,61.84 144.73,61.67 144.54,61.49 144.38,61.49 143.94,61.93 143.77,61.93 143.58,61.74 143.58,61.58 144.03,61.14 144.03,60.97 143.84,60.78 143.68,60.78 143.23,61.23 143.07,61.23 142.88,61.04 142.88,60.88 143.33,60.43 143.33,60.27 143.14,60.08 142.98,60.08 142.53,60.53 142.37,60.53 142.18,60.34 142.18,60.18 142.5,59.87 142.5,59.69 142.33,59.52 142.15,59.52 141.83,59.83 141.67,59.83 137.79,55.95 137.79,48.07 137.15,47.43 137.15,42.28 137.32,42.12 v3(137.57,42.12)
  BOTTOM w0.102: v3(137.57,42.12) 138.03,41.66 138.03,40.59 137.85,40.41 JDIMM1.132 ; UC1.AK33 146.21,83.1 v3(145.86,82.76)
DDRA_SDQ38: length 55.5
  IN1 w0.102: 147.96,82.12 147.85,82.24 147.85,83.86 147.53,84.18 147.53,84.6 147,85.13 146.56,85.13 145.96,85.73 145.7,85.73 v3(145.01,86.42)
  IN1 w0.114: v3(141.28,42.88) 140.96,43.2 140.96,54.14 149.68,62.86 149.68,68.58 150.36,69.25 150.36,76.6 148.67,78.29 148.67,78.9 148.95,79.18 148.95,79.53 148.65,79.84 148.65,79.94 148.32,80.27 148.32,80.5 148.7,80.88 148.7,81.28 147.96,82.02 147.96,82.12
  BOTTOM w0.102: UC1.AH28 144.7,86.89 145.01,86.58 v3(145.01,86.42) ; JDIMM1.140 140.25,42.05 141.08,42.88 v3(141.28,42.88)
DDRA_SDQ39: length 55.9
  IN1 w0.102: 148.67,83.65 148.46,83.86 148.46,84.19 148.14,84.51 148.14,84.86 147.33,85.67 147.33,86.57 146.95,86.95 146.64,86.95 146.34,86.64 145.89,86.64 145.85,86.6 v3(145.85,86.54)
  IN1 w0.114: 148.67,83.65 150.45,81.87 150.45,78.34 151.62,77.17 151.62,68.73 150.94,68.05 150.94,62.33 142.68,54.07 142.68,44.53 141.78,43.63 141.78,42.12 141.34,41.68 v3(141.26,41.68)
  BOTTOM w0.102: v3(141.26,41.68) 140.85,41.27 JDIMM1.142 ; UC1.AJ28 145.5,86.93 145.85,86.58 v3(145.85,86.54)
DDRA_SDQ40: length 65.6
  IN1 w0.102: 149,83.93 149,84.1 148.43,84.68 148.43,84.85 147.53,85.75 147.53,86.65 147.01,87.18 144.35,87.18 143.86,87.67 143.86,88.27 143.5,88.62 v3(143.5,88.9)
  IN1 w0.114: v3(143.52,44.99) 143.2,44.99 143.1,45.09 143.1,53.9 148.47,59.28 148.64,59.28 149.32,58.59 149.48,58.59 149.62,58.73 149.62,58.9 148.94,59.58 148.94,59.74 149.08,59.88 149.24,59.88 149.92,59.2 150.08,59.2 150.22,59.34 150.22,59.5 149.54,60.18 149.54,60.34 149.68,60.48 149.84,60.48 150.52,59.8 150.68,59.8 150.82,59.94 150.82,60.1 150.14,60.78 150.14,60.95 150.28,61.09 150.45,61.09 151.13,60.41 151.29,60.41 151.43,60.55 151.43,60.71 150.75,61.39 150.75,61.55 151.56,62.36 151.56,67.81 152.17,68.43 152.17,77.21 150.88,78.5 150.88,82.05 149,83.93
  BOTTOM w0.102: UC1.AF25 143.1,89.3 v3(143.5,88.9) ; JDIMM1.147 142.35,46.15 v3(143.52,44.99)
DDRA_SDQ41: length 65.7
  IN1 w0.102: 148.68,84.89 147.76,85.81 147.76,86.71 147.09,87.38 145,87.38 144.73,87.65 144.73,88.48 145,88.75 v3(145,88.88)
  IN1 w0.114: v3(143.52,46.18) 143.52,53.57 145.45,55.5 145.62,55.5 146.28,54.85 146.44,54.85 146.58,54.99 146.58,55.15 145.9,55.83 145.9,56.01 146.02,56.13 146.2,56.13 146.88,55.45 147.04,55.45 147.18,55.59 147.18,55.75 146.5,56.43 146.5,56.61 146.63,56.74 146.8,56.74 147.49,56.05 147.65,56.05 147.79,56.19 147.79,56.36 147.11,57.04 147.11,57.21 147.23,57.34 147.41,57.34 148.09,56.66 148.25,56.66 148.39,56.8 148.39,56.96 147.75,57.6 147.75,57.78 147.87,57.9 148.05,57.9 148.69,57.26 148.85,57.26 149,57.4 149,57.56 148.33,58.23 148.33,58.41 148.52,58.61 148.7,58.61 149.38,57.93 149.54,57.93 151.97,60.36 151.97,67.64 152.61,68.27 152.61,77.42 151.36,78.67 151.36,82.16 149.42,84.11 149.42,84.27 148.8,84.89 148.68,84.89
  BOTTOM w0.102: v3(145,88.88) 144.7,89.18 UC1.AH25 ; JDIMM1.149 142.95,46.75 v3(143.52,46.18)
DDRA_SDQ42: length 65.7
  IN1 w0.102: v3(143.42,91.27) 143.59,91.27 144.02,91.7 145.17,91.7 146.31,90.55 147.3,90.55 148.67,89.18
  IN1 w0.114: 148.67,89.18 149.56,89.18 149.66,89.29 150.68,89.29 155.61,84.36 155.61,80.08 156.61,79.07 156.61,66.89 155.79,66.07 155.79,58.79 153.57,56.57 153.57,56.14 147.78,50.35 147.78,46.79 147.91,46.66 148.09,46.66 148.22,46.54 148.22,44.81 147.88,44.48 v3(147.76,44.48)
  BOTTOM w0.102: JDIMM1.157 145.35,45.77 146.64,44.48 v3(147.76,44.48) ; v3(143.42,91.27) 143.42,91.42 UC1.AG22
DDRA_SDQ43: length 65.6
  IN1 w0.102: v3(145.02,91.27) 145.17,91.27 146.08,90.35 147.08,90.35 148.57,88.85
  IN1 w0.114: 148.57,88.85 150.52,88.85 150.9,88.47 150.9,88.31 150.83,88.24 150.83,88.07 150.96,87.94 151.13,87.94 151.2,88.01 151.36,88.01 151.5,87.87 151.5,87.71 151.44,87.65 151.44,87.47 151.56,87.34 151.74,87.34 151.8,87.41 151.97,87.41 152.11,87.27 152.11,87.1 151.84,86.84 151.84,86.68 151.98,86.54 152.14,86.54 152.41,86.8 152.57,86.8 152.71,86.66 152.71,86.5 152.44,86.24 152.44,86.07 152.58,85.93 152.74,85.93 153.01,86.2 153.17,86.2 153.31,86.06 153.31,85.9 153.05,85.63 153.05,85.47 153.19,85.33 153.35,85.33 153.61,85.6 153.78,85.6 153.92,85.46 153.92,85.29 153.65,85.03 153.65,84.87 153.79,84.73 153.95,84.73 154.22,84.99 154.38,84.99 154.52,84.85 154.52,84.69 154.25,84.42 154.25,84.26 154.39,84.12 154.56,84.12 154.82,84.39 154.98,84.39 155.15,84.22 155.15,79.88 156.14,78.89 156.14,67.01 155.37,66.25 155.37,58.96 153.16,56.74 153.16,56.31 147.36,50.52 147.36,45.79 147.5,45.65 v3(147.78,45.65)
  BOTTOM w0.102: v3(147.78,45.65) 146.95,45.65 145.95,46.64 JDIMM1.159 ; UC1.AJ22 145.5,91.74 v3(145.02,91.27)
DDRA_SDQ44: length 64.1
  IN1 w0.102: v3(145.13,87.81) 145.51,88.19 145.98,88.19 146.36,87.81 147.23,87.81 148.29,86.75 148.29,86.72
  IN1 w0.114: v3(142.63,42.32) 142.63,42.3 143.21,41.71 143.21,40.77 143.34,40.64 143.97,40.64 144.1,40.77 144.1,41.41 144.23,41.53 144.24,41.53 144.37,41.66 144.37,53.2 145.43,54.25 145.67,54.25 146.16,53.76 146.56,53.76 152.81,60.01 152.81,67.29 153.47,67.95 153.47,77.78 152.33,78.92 152.33,82.55 149.25,85.63 148.88,85.63 148.29,86.21 148.29,86.72
  BOTTOM w0.102: JDIMM1.146 142.05,41.92 142.45,42.32 v3(142.63,42.32) ; v3(145.13,87.81) 144.7,88.25 UC1.AH27
DDRA_SDQ45: length 64.1
  IN1 w0.102: 148.02,86.52 148.02,86.73 147.17,87.58 145.97,87.58 v3(145.77,87.79)
  IN1 w0.114: 148.02,86.52 148.02,85.97 148.77,85.22 149.06,85.22 151.85,82.44 151.85,78.8 153.04,77.6 153.04,68.11 152.39,67.46 152.39,60.19 146.44,54.23 146.28,54.23 145.63,54.89 145.46,54.89 143.95,53.37 143.95,43.97 143.72,43.74 142.5,43.74 142.37,43.62 142.37,43.41 142.5,43.29 143.82,43.29 143.95,43.16 143.95,42.09 143.82,41.97 143.57,41.97 143.44,42.09 143.44,42.65 143.31,42.78 142.32,42.78 142.2,42.65 142.2,41.53 v3(142.65,41.08)
  BOTTOM w0.102: JDIMM1.148 v3(142.65,41.08) ; v3(145.77,87.79) 145.76,87.79 145.5,88.05 UC1.AJ27
DDRA_SDQ46: length 64.7
  IN1 w0.102: 149.08,88.24 149.08,88.25 148.41,88.25 146.81,89.84 145.93,89.84 145.22,90.55 142.26,90.55 v3(141.82,90.12)
  IN1 w0.114: v3(146.21,42.09) 146.53,42.41 146.53,50.87 152.32,56.66 152.32,57.09 154.53,59.31 154.53,66.59 155.28,67.34 155.28,78.44 154.23,79.48 154.23,83.07 150.81,86.5 150.81,86.87 149.44,88.24 149.08,88.24
  BOTTOM w0.102: v3(146.21,42.09) 145.65,41.53 JDIMM1.158 ; UC1.AE24 141.82,90.22 v3(141.82,90.12)
DDRA_SDQ47: length 64.5
  IN1 w0.102: v3(142.74,91.24) 143.2,90.78 145.36,90.78 146.05,90.1 146.93,90.1 148.56,88.48 149.89,88.48
  IN1 w0.114: 149.89,88.48 150.07,88.48 150.26,88.28 150.26,88.01 151.22,87.05 151.22,86.67 154.69,83.2 154.69,79.63 155.71,78.61 155.71,67.17 154.95,66.42 154.95,59.14 152.74,56.92 152.74,56.49 146.95,50.69 146.95,41.59 v3(146.25,40.9)
  BOTTOM w0.102: JDIMM1.160 v3(146.25,40.9) ; UC1.AF22 142.74,91.54 v3(142.74,91.24)
DDRA_SDQ48: length 80
  IN1 w0.102: 148.7,89.59 147.53,90.76 146.51,90.76 145.15,92.12 144.98,92.12 v3(144.56,92.54)
  IN1 w0.114: v3(148.75,50.3) 148.75,50.72 154.14,56.11 154.44,56.11 154.9,56.57 154.9,56.73 154.79,56.84 154.79,57.2 156.21,58.61 156.21,64.14 156.33,64.26 157.04,64.26 157.16,64.37 157.16,64.57 157.04,64.68 156.33,64.68 156.21,64.8 156.21,65 156.33,65.11 157.04,65.11 157.16,65.22 157.16,65.42 157.04,65.54 156.34,65.54 156.22,65.66 156.22,65.84 156.34,65.97 157,65.97 157.13,66.1 157.13,66.22 156.93,66.43 156.93,66.58 157.13,66.78 157.13,74.16 157.24,74.28 157.79,74.28 157.92,74.41 157.92,74.65 157.79,74.77 157.24,74.77 157.13,74.89 157.13,75.15 157.24,75.27 158.76,75.27 158.88,75.4 158.88,75.64 158.76,75.76 157.24,75.76 157.13,75.88 157.13,76.15 157.24,76.26 159.77,76.26 159.9,76.39 159.9,76.63 159.77,76.75 157.24,76.75 157.13,76.87 157.13,77.14 157.24,77.25 160.74,77.25 160.86,77.38 160.86,77.62 160.74,77.75 160.22,77.75 160.04,77.93 159.73,77.93 159.54,77.75 159.23,77.75 159.05,77.93 158.74,77.93 158.55,77.75 158.26,77.75 158.13,77.87 158.13,78.29 158,78.41 157.76,78.41 157.63,78.29 157.63,77.87 157.51,77.75 157.24,77.75 157.13,77.86 157.13,79.31 156.04,80.4 156.04,83.54 156.53,84.03 156.53,84.24 156.16,84.61 156.04,84.61 150.93,89.72 149.51,89.72 149.38,89.59 148.7,89.59
  BOTTOM w0.102: v3(148.75,50.3) 148.39,50.3 147.15,49.05 JDIMM1.163 ; UC1.AH21 144.62,93.02 144.62,92.6 v3(144.56,92.54)
DDRA_SDQ49: length 80
  IN1 w0.102: 148.69,90 147.72,90.96 146.63,90.96 145.17,92.43 v3(145.17,92.54)
  IN1 w0.114: 148.69,90 149.2,90 149.36,90.15 151.21,90.15 157,84.36 157,83.9 156.5,83.4 156.5,80.55 158.69,78.35 160.77,78.35 161.08,78.05 161.29,78.05 162.02,78.78 162.2,78.78 162.46,78.52 162.46,78.34 157.61,73.49 157.61,73.31 157.75,73.17 157.93,73.17 162.11,77.35 162.29,77.35 162.44,77.2 162.44,77.02 157.59,72.17 157.59,63.96 157.46,63.83 156.76,63.83 156.65,63.72 156.65,63.52 156.76,63.4 157.46,63.4 157.59,63.28 157.59,63.1 157.46,62.98 156.76,62.98 156.65,62.86 156.65,58.46 155.32,57.13 155.32,56.4 154.62,55.69 154.31,55.69 154.1,55.47 154.1,55.21 153.93,55.04 153.66,55.04 153.49,54.87 153.49,54.61 153.32,54.44 153.06,54.44 149.17,50.55 149.17,49.33 148.96,49.13 v3(148.75,49.13)
  BOTTOM w0.102: UC1.AJ21 145.17,92.77 v3(145.17,92.54) ; JDIMM1.165 147.75,48.77 148.11,49.13 v3(148.75,49.13)
DDRA_SDQ50: length 79.9
  IN1 w0.114: v3(143.45,96.07) 143.91,95.61 145.24,95.61 145.52,95.33 145.85,95.33 146.51,94.67 146.97,94.67 147.48,94.16 148.24,94.16 148.77,93.63 152.8,93.63 157.63,88.8 159.87,88.8 160.97,87.71 162.47,87.71 165.86,84.32 165.86,75.66 161.77,71.57 161.77,61.54 160.14,59.91 160.14,56.43 159.97,56.27 159.81,56.27 159.61,56.47 159.45,56.47 159.31,56.33 159.31,56.17 159.51,55.97 159.51,55.81 159.37,55.67 159.21,55.67 159,55.87 158.84,55.87 158.7,55.73 158.7,55.57 158.91,55.37 158.91,55.2 153.03,49.33 153.03,46.74 152.27,45.99 152.27,44.51 152.41,44.38 152.61,44.38 v3(152.74,44.51)
  BOTTOM w0.102: v3(152.74,44.51) 152.13,44.51 150.75,45.88 JDIMM1.175 ; v3(143.45,96.07) 143.45,95.85 UC1.AF17
DDRA_SDQ51: length 79.9
  IN1 w0.114: v3(152.74,45.67) 152.74,45.86 153.45,46.57 153.45,49.15 160.55,56.26 160.55,57.98 160.68,58.11 161.41,58.11 161.52,58.22 161.52,58.42 161.41,58.54 160.68,58.54 160.55,58.66 160.55,58.87 160.67,58.98 162.07,58.98 162.19,59.09 162.19,59.29 162.07,59.41 160.67,59.41 160.55,59.52 160.55,59.74 160.67,59.85 162.06,59.85 162.19,59.97 162.19,60.18 162.06,60.31 161.57,60.31 161.45,60.43 161.45,60.61 161.57,60.73 162.06,60.73 162.19,60.86 162.19,71.4 166.27,75.49 166.27,84.49 161.54,89.22 157.8,89.22 152.98,94.05 148.84,94.05 148.46,94.43 147.62,94.43 147.05,95 146.78,95 v3(145.79,95.99)
  BOTTOM w0.102: UC1.AJ17 145.5,95.7 v3(145.79,95.99) ; JDIMM1.177 151.35,46.5 152.18,45.67 v3(152.74,45.67)
DDRA_SDQ52: length 78.5
  IN1 w0.102: 148.73,90.35 147.72,91.37 v3(146.8,91.37)
  IN1 w0.114: 148.73,90.35 149.03,90.35 149.26,90.58 151.49,90.58 157.66,84.41 157.66,83.98 156.95,83.27 156.95,80.71 158.89,78.77 161.43,78.77 162.59,79.94 162.74,79.94 162.88,79.8 162.88,76.87 158.36,72.34 158.36,72.05 158.25,71.94 158.15,71.94 158.02,71.81 158.02,71.57 158.15,71.44 158.69,71.44 158.81,71.33 158.81,71.06 158.69,70.95 158.13,70.95 158.02,70.83 158.02,70.57 158.13,70.45 158.69,70.45 158.81,70.34 158.81,70.07 158.69,69.96 158.13,69.96 158.02,69.84 158.02,62.92 157.07,61.97 157.07,58.28 155.74,56.96 155.74,56.22 149.59,50.07 149.59,49.15 148.7,48.26 148.7,43.8 148.58,43.68 148.11,43.68 148.04,43.76 148.04,43.92 147.91,44.05 147.53,44.05 147.4,43.92 147.4,43.37 147.52,43.26 148.58,43.26 148.7,43.14 148.7,42.3 148.44,42.05 148.08,42.05 v3(148.04,42.09)
  BOTTOM w0.102: v3(148.04,42.09) 147.45,41.5 JDIMM1.164 ; UC1.AK22 146.3,91.87 v3(146.8,91.37)
DDRA_SDQ53: length 78.2
  IN1 w0.114: v3(143.36,92.54) 143.77,92.94 145.47,92.94 146.63,91.79 147.64,91.79 148.22,91.22 149.26,91.22 149.46,91.01 151.67,91.01 157.79,84.89 158.78,84.89 159.06,85.17 161.37,85.17 163.3,83.24 163.3,76.7 158.78,72.17 158.78,71.95 159.23,71.5 159.23,69.64 159.1,69.52 158.58,69.52 158.45,69.39 158.45,69.15 158.58,69.02 159.09,69.02 159.21,68.89 159.21,68.65 159.09,68.53 158.58,68.53 158.45,68.4 158.45,68.16 158.58,68.03 159.09,68.03 159.21,67.9 159.21,67.66 159.09,67.54 158.58,67.54 158.45,67.41 158.45,62.76 157.49,61.79 157.49,58.11 156.16,56.79 156.16,56.05 150.01,49.89 150.01,48.98 149.12,48.09 149.12,42.13 148.47,41.48 148.47,41.28 148.09,40.9 v3(148.05,40.9)
  BOTTOM w0.102: JDIMM1.166 v3(148.05,40.9) ; UC1.AF21 143.1,92.8 v3(143.36,92.54)
DDRA_SDQ54: length 78.4
  IN1 w0.102: v3(145.15,94.87) 145.15,94.69 145.55,94.29 147,94.29 147.38,93.91 148.02,93.91 148.44,93.5
  IN1 w0.114: 148.44,93.5 148.62,93.31 150.2,93.31 150.3,93.21 152.63,93.21 157.46,88.38 159.7,88.38 160.79,87.29 162.29,87.29 165.44,84.14 165.44,75.84 161.35,71.75 161.35,61.71 159.72,60.08 159.72,57.34 158.28,55.9 158.28,55.17 152.61,49.5 152.61,48.62 152.49,48.5 152.27,48.5 152.15,48.39 152.15,48.19 152.27,48.07 152.49,48.07 152.61,47.96 152.61,47.76 152.49,47.65 152.27,47.65 152.15,47.53 152.15,47.34 152.27,47.22 152.49,47.22 152.61,47.11 152.61,46.92 151.85,46.16 151.85,42.02 151.72,41.89 151.26,41.89 v3(151.03,42.12)
  BOTTOM w0.102: v3(145.15,94.87) 145.5,94.52 UC1.AJ19 ; v3(151.03,42.12) 150.45,41.53 JDIMM1.174
DDRA_SDQ55: length 78.9
  IN1 w0.102: 148.41,93.13 147.91,93.63 147.3,93.63 146.95,93.98 145.37,93.98 144.74,94.62 144.74,95.15 144.53,95.36 143.31,95.36 142.71,95.96 v3(142.71,96.02)
  IN1 w0.114: v3(151.05,40.87) 150.6,41.32 150.6,42.28 151.44,43.11 151.44,47.27 151.72,47.55 151.72,49.2 157.86,55.35 157.86,56.08 159.3,57.51 159.3,60.26 160.93,61.89 160.93,71.92 165,75.99 165,83.99 162.12,86.87 160.62,86.87 159.52,87.96 157.28,87.96 152.46,92.79 150.3,92.79 150.02,93.07 148.47,93.07 148.41,93.13
  BOTTOM w0.102: v3(142.71,96.02) 142.3,95.6 UC1.AE17 ; JDIMM1.176 v3(151.05,40.87)
DDRA_SDQ56: length 87.8
  IN1 w0.102: v3(143.37,97.34) 143.78,97.74 145.9,97.74 146.74,96.9 147.56,96.9
  IN1 w0.114: 147.56,96.9 148.71,95.76 154.34,95.76 154.64,95.46 154.64,94.76 155.79,93.6 156.42,93.6 158.9,91.13 162.25,91.13 168.1,85.27 168.1,81.27 168.22,81.15 168.92,81.15 169.04,81.03 169.04,80.85 168.92,80.73 168.22,80.73 168.1,80.61 168.1,80.41 168.22,80.3 168.92,80.3 169.04,80.17 169.04,68.58 166.95,66.49 164.98,66.49 164.85,66.36 164.85,66.12 164.98,65.99 165.59,65.99 165.72,65.87 165.72,65.61 165.59,65.49 164.45,65.49 163.86,64.9 163.86,57.2 155.14,48.47 155.14,45.23 v3(154.18,44.28)
  BOTTOM w0.102: UC1.AF16 143.37,96.97 v3(143.37,97.34) ; JDIMM1.181 152.55,46.72 153.42,45.85 153.42,44.96 154.11,44.28 v3(154.18,44.28)
DDRA_SDQ57: length 87.6
  IN1 w0.102: v3(145.76,97.34) 146.45,96.65 147.39,96.65
  IN1 w0.114: v3(154.18,45.47) 154.36,45.29 154.57,45.29 154.72,45.44 154.72,48.64 162.1,56.03 162.1,56.19 161.83,56.46 161.83,56.62 161.97,56.76 162.13,56.76 162.4,56.49 162.57,56.49 162.71,56.63 162.71,56.79 162.43,57.06 162.43,57.35 163.44,58.36 163.44,65.81 163.57,65.94 164.01,65.94 164.14,66.06 164.14,66.3 164.01,66.43 163.57,66.43 163.44,66.56 163.44,66.76 163.59,66.91 166.77,66.91 168.62,68.76 168.62,75.72 168.5,75.85 167.82,75.85 167.7,75.98 167.7,76.22 167.82,76.35 168.5,76.35 168.62,76.47 168.62,76.71 168.5,76.84 167.82,76.84 167.7,76.97 167.7,77.21 167.82,77.34 168.5,77.34 168.62,77.46 168.62,77.7 168.5,77.83 167.82,77.83 167.7,77.96 167.7,78.2 167.82,78.33 168.5,78.33 168.62,78.45 168.62,78.69 168.5,78.82 167.82,78.82 167.7,78.95 167.7,79.19 167.82,79.32 168.48,79.32 168.61,79.44 168.61,79.71 168.48,79.84 167.79,79.84 167.68,79.94 167.68,85.1 162.08,90.71 158.1,90.71 153.5,95.31 150.22,95.31 150.07,95.46 148.58,95.46 147.39,96.65
  BOTTOM w0.102: v3(145.76,97.34) 145.5,97.07 UC1.AJ16 ; JDIMM1.183 153.15,46.71 154.04,45.81 154.04,45.61 v3(154.18,45.47)
DDRA_SDQ58: length 87.8
  IN1 w0.102: 146.61,98.63 146.41,98.63 145.87,99.17 143.96,99.17 v3(143.45,99.67)
  IN1 w0.114: v3(156.34,44.17) 157.01,44.84 157.01,47.2 164.79,54.98 164.79,54.99 166.55,56.75 166.55,63.69 170.78,67.92 170.78,85.02 162.48,93.32 162.06,93.32 161.54,93.84 161.38,93.84 160.97,93.42 160.79,93.42 160.67,93.55 160.67,93.72 161.08,94.14 161.08,94.3 160.94,94.44 160.78,94.44 160.43,94.09 160.27,94.09 160.13,94.23 160.13,94.4 160.48,94.74 160.48,94.9 159.29,96.09 158.04,96.09 155.96,98.18 148.82,98.18 148.37,98.63 146.61,98.63
  BOTTOM w0.102: v3(156.34,44.17) 156.85,44.68 156.85,45.55 155.55,46.85 JDIMM1.191 ; UC1.AF13 143.1,99.32 v3(143.45,99.67)
DDRA_SDQ59: length 87.8
  IN1 w0.102: 147.28,100.05 146.42,100.05 146.22,100.26 144.23,100.26 143.31,100.09 v3(142.75,99.67)
  IN1 w0.114: v3(158.43,45.39) 158.92,45.89 158.92,46.53 162.46,50.07 162.46,50.69 162.63,50.86 162.85,50.86 162.97,50.75 163.13,50.75 163.28,50.89 163.28,51.05 163.06,51.26 163.06,51.42 163.2,51.57 163.36,51.57 163.58,51.35 163.74,51.35 163.88,51.49 163.88,51.65 163.66,51.87 163.66,52.03 163.8,52.17 163.96,52.17 164.18,51.95 164.34,51.95 167.81,55.42 167.81,63.17 172.07,67.43 172.07,85.51 162.92,94.66 162.84,94.66 157.58,99.93 147.4,99.93 147.28,100.05
  BOTTOM w0.102: JDIMM1.193 156.15,46.96 157.71,45.39 v3(158.43,45.39) ; UC1.AE13 142.3,99.17 142.75,99.62 v3(142.75,99.67)
DDRA_SDQ60: length 86.1
  IN1 w0.102: 147.76,94.72 147.63,94.72 145.96,96.4 145.3,96.4 v3(145,96.09)
  IN1 w0.114: 147.76,94.72 149.56,94.72 149.82,94.47 153.15,94.47 157.77,89.84 161.75,89.84 166.83,84.76 166.83,74.99 166.96,74.86 167.65,74.86 167.77,74.73 167.77,74.5 167.65,74.37 165.82,74.37 165.64,74.19 165.64,73.94 165.77,73.82 167.65,73.82 167.77,73.69 167.77,73.44 167.65,73.31 164.77,73.31 162.6,71.15 162.6,58.71 161.58,57.69 161.12,57.69 160.97,57.54 160.97,56.09 153.88,48.99 153.88,46.41 153.3,45.83 153.3,42.27 153.14,42.12 v3(152.81,42.12)
  BOTTOM w0.102: UC1.AH17 145,95.8 v3(145,96.09) ; JDIMM1.180 152.25,41.63 152.74,42.12 v3(152.81,42.12)
DDRA_SDQ61: length 86.2
  IN1 w0.102: v3(142.61,97.29) 143.3,96.6 146.04,96.6 146.97,95.66 147.2,95.66 147.78,95.08
  IN1 w0.114: v3(152.81,40.9) 153.44,40.9 153.73,41.19 153.73,41.51 153.84,41.63 154.17,41.63 154.29,41.74 154.29,41.94 154.17,42.05 153.84,42.05 153.73,42.17 153.73,45.66 154.3,46.24 154.3,48.82 161.39,55.91 161.39,57.14 161.52,57.27 161.76,57.27 163.02,58.54 163.02,70.98 164.94,72.89 167.94,72.89 168.2,73.16 168.2,75.21 168.08,75.34 167.39,75.34 167.27,75.47 167.27,84.93 161.9,90.29 157.92,90.29 153.33,94.89 149.95,94.89 149.76,95.08 147.78,95.08
  BOTTOM w0.102: v3(142.61,97.29) 142.61,97.01 UC1.AE16 ; v3(152.81,40.9) 152.85,40.87 JDIMM1.182
DDRA_SDQ62: length 86.3
  IN1 w0.114: v3(145.79,99.65) 146.42,99.01 147.28,99.01 147.33,99.06 155.67,99.06 158.22,96.51 159.46,96.51 162.23,93.74 162.65,93.74 171.23,85.17 171.23,67.78 166.97,63.52 166.97,56.57 161.39,50.98 161.39,50.76 161.6,50.55 161.6,50.39 161.41,50.2 161.25,50.2 161.04,50.41 160.88,50.41 160.69,50.22 160.69,50.06 160.9,49.85 160.9,49.69 160.71,49.5 160.55,49.5 160.34,49.71 160.18,49.71 159.99,49.52 159.99,49.36 160.2,49.15 160.2,48.99 159.72,48.52 159.09,48.52 157.43,46.86 157.43,44.53 157,44.1 v3(157,44)
  BOTTOM w0.102: JDIMM1.192 155.85,42.85 v3(157,44) ; v3(145.79,99.65) 145.73,99.65 145.5,99.42 UC1.AJ13
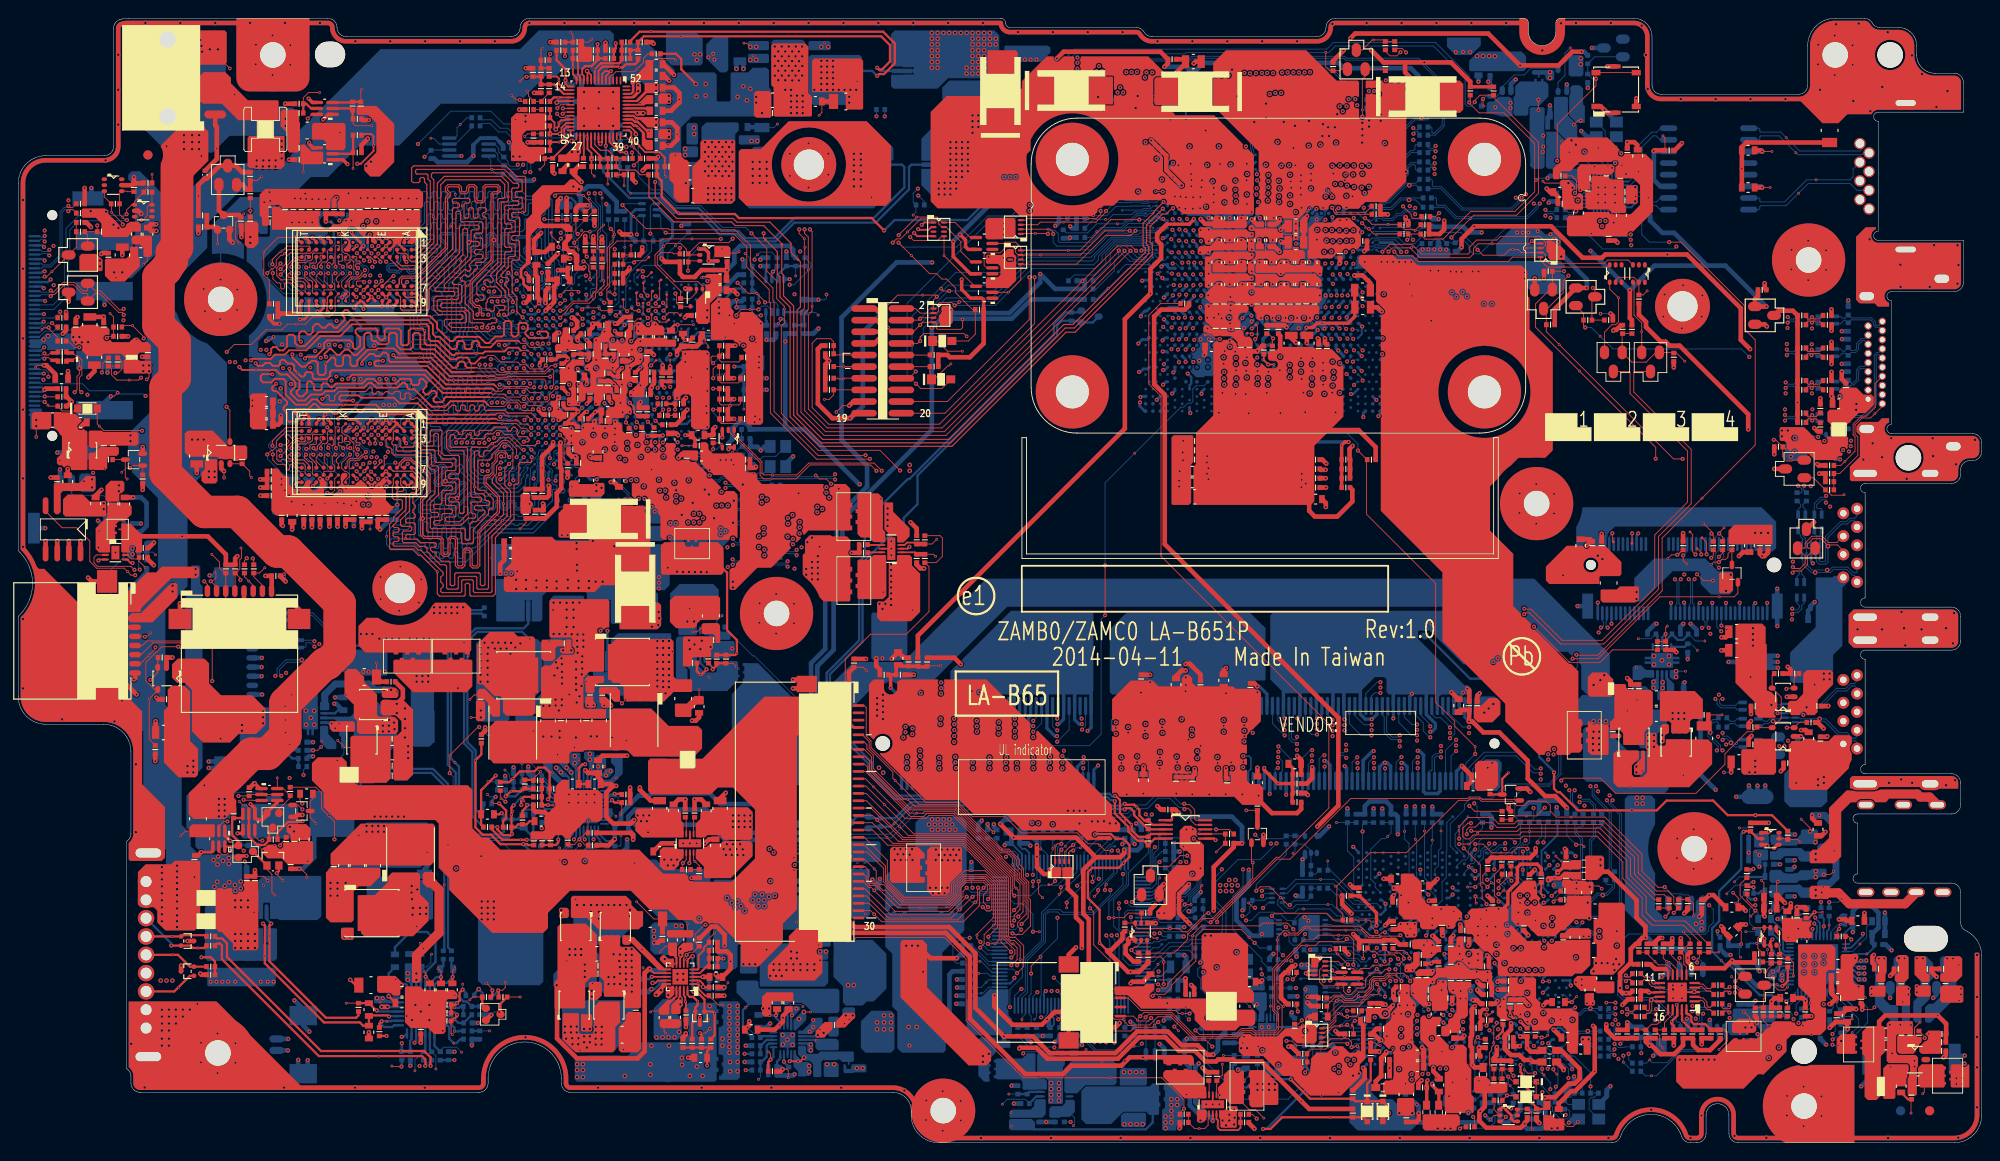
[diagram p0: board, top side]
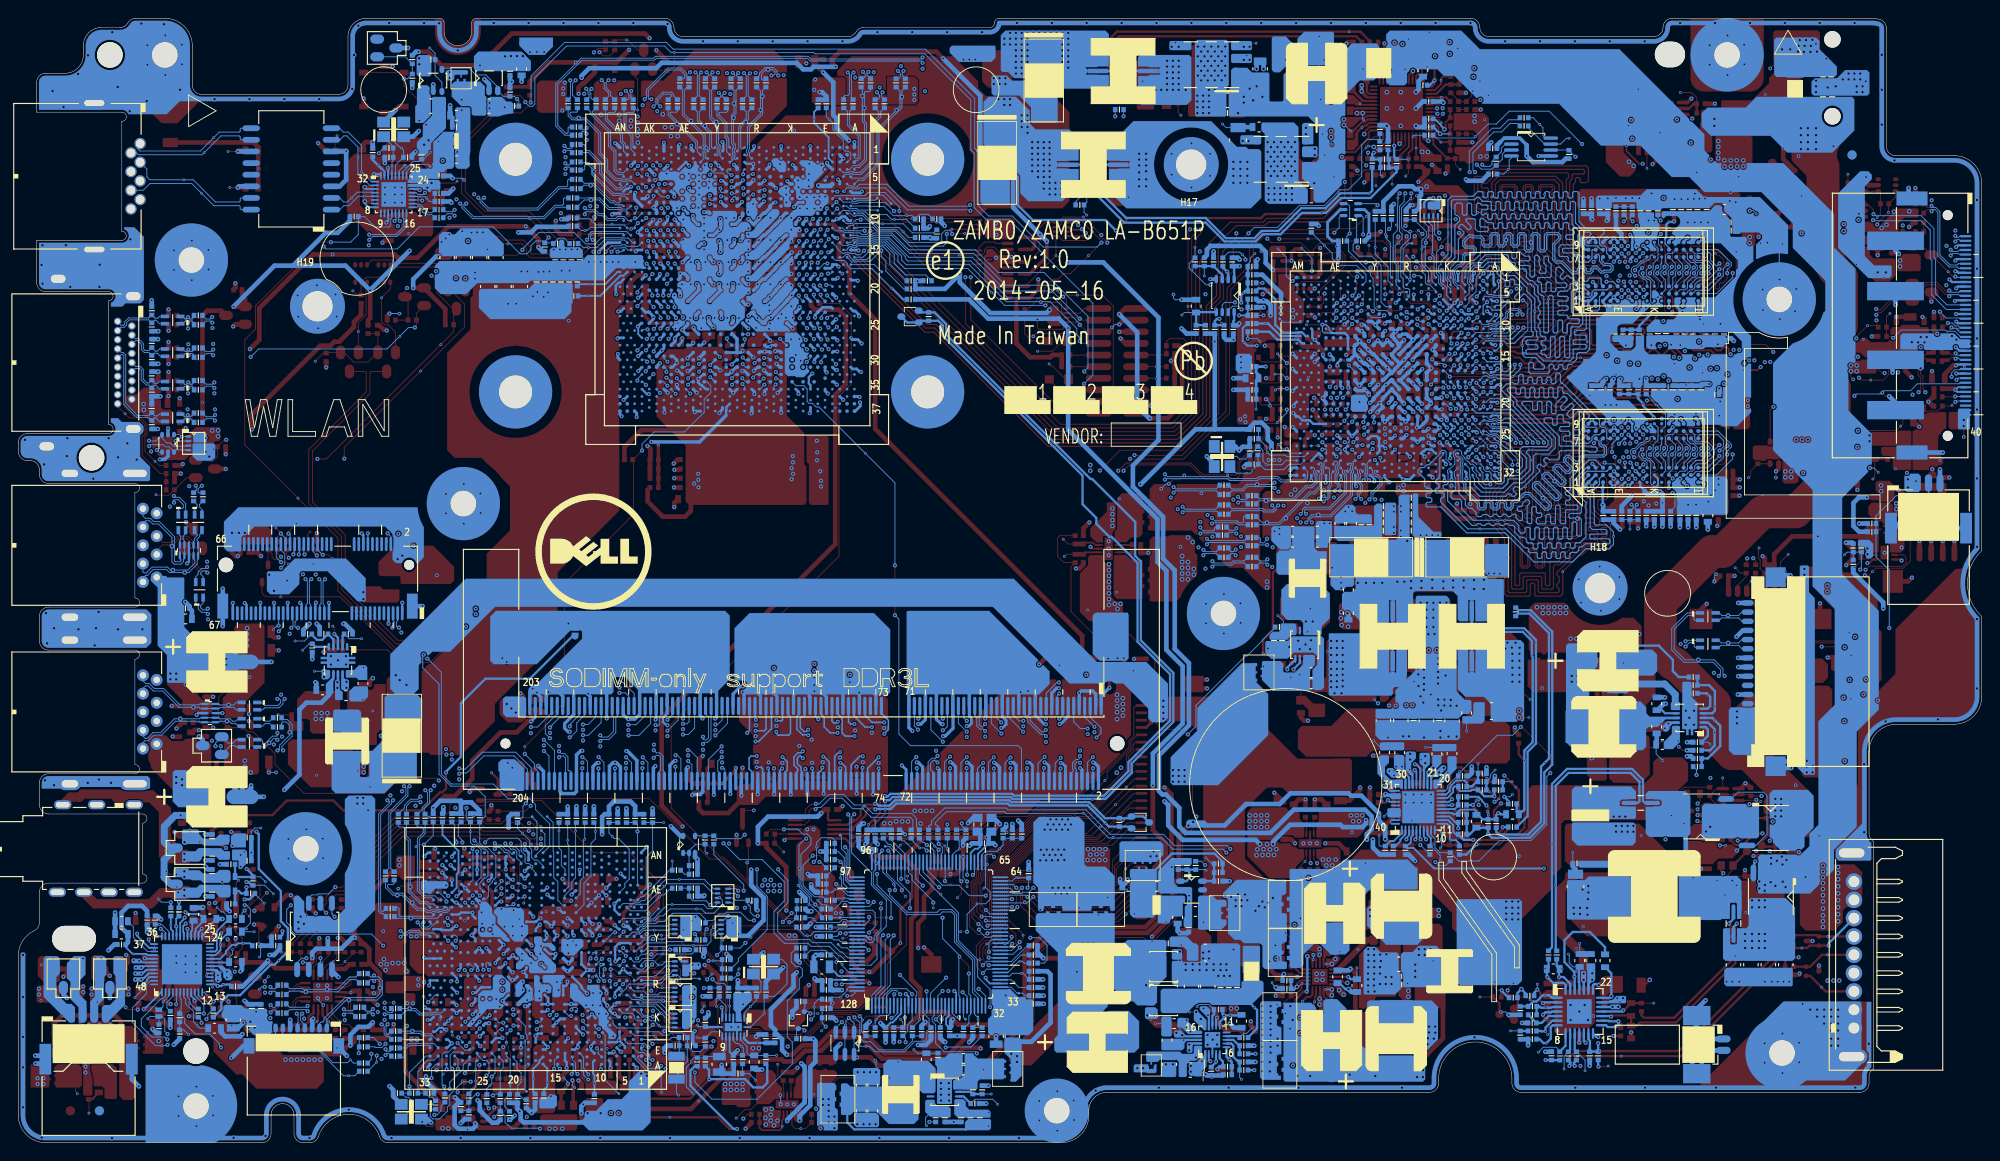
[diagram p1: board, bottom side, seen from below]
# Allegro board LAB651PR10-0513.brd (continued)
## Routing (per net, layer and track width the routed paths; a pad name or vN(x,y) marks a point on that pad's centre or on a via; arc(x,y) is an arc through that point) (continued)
DDRA_SDQ63: length 86.4
  IN1 w0.102: 147.5,99.5 147.38,99.5 147.05,99.83 146.18,99.83 145.96,100.05 144.67,100.05 v3(144.26,99.65)
  IN1 w0.114: 147.5,99.5 156.55,99.5 159.09,96.96 159.61,96.96 162.41,94.16 162.82,94.16 171.65,85.34 171.65,67.6 167.39,63.35 167.39,56.39 162.04,51.04 162.04,50.24 157.85,46.05 157.85,44.38 157.49,43.37 157.42,43.2 v3(157,42.78)
  BOTTOM w0.102: UC1.AG13 143.9,99.29 v3(144.26,99.65) ; v3(157,42.78) 156.45,42.22 JDIMM1.194
DDRA_SDQS0: length 85.7
  IN1 w0.102: v3(126.74,98.53) 126.93,98.72 126.93,98.85 126.69,99.09 125.71,99.09 125.61,99.19 124.11,99.19 124.07,99.15
  IN1 w0.114: v3(98.48,42.23) 98.48,42.06 98.29,41.87 98.02,41.87 97.82,42.07 97.82,43.08 98.41,43.67 98.41,45.65 98.13,45.93 98.13,49.69 98.43,49.99 98.43,63.94 98.56,64.06 100.62,64.06 100.89,64.34 100.89,65.02 100.64,65.27 99.87,65.27 99.76,65.39 99.76,65.78 99.87,65.9 100.64,65.9 100.89,66.15 100.89,79.66 101.99,80.75 101.99,86.85 110.55,95.41 115.55,95.41 118.98,98.84 122.46,98.84 122.53,98.9 123.83,98.9 124.07,99.15
  BOTTOM w0.102: UC1.F14 127.1,98.38 126.95,98.53 v3(126.74,98.53) ; v3(98.48,42.23) 98.48,42.02 98.65,41.85 98.92,41.85 99.28,41.49 99.28,40.81 99.15,40.69 99.15,40.61 99.45,40.31 JDIMM1.12
DDRA_SDQS0#: length 85.8
  IN1 w0.102: v3(127.52,98.45) 127.52,98.55 126.78,99.29 125.8,99.29 125.7,99.39 124.01,99.39 123.95,99.34 123.93,99.34 123.91,99.32
  IN1 w0.114: v3(98.46,41.48) 98.31,41.63 97.92,41.63 97.59,41.97 97.59,43.18 98.17,43.76 98.17,45.55 97.89,45.83 97.89,49.78 98.19,50.09 98.19,64.03 98.46,64.3 100.52,64.3 100.66,64.44 100.66,64.92 100.54,65.04 99.78,65.04 99.52,65.29 99.52,65.88 99.78,66.13 100.54,66.13 100.66,66.25 100.66,79.76 101.75,80.85 101.75,86.94 110.45,95.64 115.45,95.64 118.88,99.07 122.36,99.07 122.43,99.14 123.73,99.14 123.91,99.32
  BOTTOM w0.102: JDIMM1.10 98.85,40.76 99.02,40.92 99.02,41.38 98.81,41.58 98.56,41.58 v3(98.46,41.48) ; v3(127.52,98.45) 127.9,98.08 UC1.G14
DDRA_SDQS1: length 78.2
  IN1 w0.102: 123.27,94.66 123.27,94.69 123.65,95.08 125.39,95.08 125.67,95.36 128.19,95.36 128.41,95.13 128.41,94.94 v3(128.29,94.82)
  IN1 w0.114: 123.27,94.66 123.14,94.53 122.3,94.53 121.92,94.15 121.01,94.15 119.83,92.98 119.12,92.98 116.54,90.4 111.64,90.4 106.38,85.15 106.38,69.48 106.13,69.23 105.61,69.23 105.5,69.11 105.5,68.85 105.61,68.73 106.13,68.73 106.38,68.48 106.38,68.02 106.13,67.77 105.61,67.77 105.5,67.65 105.5,67.38 105.61,67.27 106.13,67.27 106.38,67.02 106.38,66.55 106.13,66.3 105.61,66.3 105.5,66.19 105.5,65.75 105.61,65.64 105.79,65.64 106.06,65.37 106.06,64.94 105.79,64.67 105.61,64.67 105.5,64.56 105.5,53.2 103.05,50.75 103.05,44.99 102.72,44.66 102.44,44.66 v3(102.19,44.41)
  BOTTOM w0.102: UC1.H19 128.7,94.41 v3(128.29,94.82) ; v3(102.19,44.41) 102.19,44.42 102.37,44.61 102.77,44.61 104.17,46.01 104.17,46.25 104.37,46.44 104.37,46.65 104.55,46.83 JDIMM1.29
DDRA_SDQS1#: length 78.2
  IN1 w0.102: v3(129.15,94.85) 128.98,94.85 128.27,95.56 125.59,95.56 125.31,95.28 123.57,95.28 123.13,94.84 123.12,94.84 123.1,94.83
  IN1 w0.114: 123.1,94.83 123.04,94.76 122.2,94.76 121.82,94.39 120.91,94.39 119.74,93.22 119.02,93.22 116.44,90.64 111.54,90.64 106.15,85.24 106.15,69.58 106.03,69.46 105.52,69.46 105.26,69.21 105.26,68.75 105.52,68.5 106.03,68.5 106.15,68.38 106.15,68.12 106.03,68 105.52,68 105.26,67.75 105.26,67.29 105.52,67.03 106.03,67.03 106.15,66.92 106.15,66.65 106.03,66.54 105.52,66.54 105.26,66.29 105.26,65.66 105.52,65.4 105.7,65.4 105.82,65.28 105.82,65.04 105.7,64.91 105.52,64.91 105.26,64.66 105.26,53.3 102.82,50.85 102.82,45.09 102.63,44.89 102.38,44.89 v3(102.2,45.07)
  BOTTOM w0.102: UC1.J19 129.15,94.65 v3(129.15,94.85) ; JDIMM1.27 103.95,46.86 104.1,46.71 104.1,46.55 103.91,46.36 103.91,46.12 102.66,44.87 102.4,44.87 v3(102.2,45.07)
DDRA_SDQS2: length 70
  IN1 w0.102: v3(126.08,90.07) 126.27,90.27 126.27,90.39 126.15,90.5 124.98,90.5 124.14,89.67 124.14,89.64 124.13,89.63
  IN1 w0.114: v3(108.82,44.96) 109.05,45.18 109.48,45.18 109.82,45.52 109.82,50 111.66,51.84 111.66,75.34 111.76,75.43 112.27,75.43 112.54,75.7 112.54,76.21 112.27,76.48 111.78,76.48 111.66,76.59 111.66,76.99 111.78,77.1 113.95,77.1 114.21,77.37 114.21,77.93 113.95,78.2 111.78,78.2 111.66,78.31 111.66,78.7 111.78,78.82 112.75,78.82 113.02,79.08 113.02,79.65 112.75,79.91 111.78,79.91 111.66,80.03 111.66,83.04 113.77,85.15 118.96,85.15 121.54,87.73 121.85,87.73 122.61,88.49 122.99,88.49 124.13,89.63
  BOTTOM w0.102: v3(126.08,90.07) 125.85,90.3 UC1.D24 ; JDIMM1.47 109.95,46.66 109.74,46.46 109.74,45.53 109.37,45.16 109.02,45.16 v3(108.82,44.96)
DDRA_SDQS2#: length 70
  IN1 w0.102: 123.96,89.79 123.98,89.81 124,89.81 124.9,90.71 126.24,90.71 126.47,90.47 126.47,90.31 v3(126.71,90.07)
  IN1 w0.114: 123.96,89.79 122.89,88.73 122.51,88.73 121.75,87.96 121.44,87.96 118.86,85.38 113.67,85.38 111.43,83.13 111.43,79.93 111.68,79.68 112.66,79.68 112.78,79.55 112.78,79.18 112.66,79.05 111.68,79.05 111.43,78.8 111.43,78.21 111.68,77.96 113.85,77.96 113.98,77.83 113.98,77.46 113.85,77.34 111.68,77.34 111.43,77.08 111.43,76.49 111.68,76.24 112.17,76.24 112.3,76.11 112.3,75.8 112.17,75.67 111.66,75.67 111.43,75.43 111.43,51.94 109.58,50.09 109.58,45.62 109.38,45.42 109.13,45.42 v3(108.83,45.72)
  BOTTOM w0.102: UC1.E24 126.71,90.29 v3(126.71,90.07) ; JDIMM1.45 109.35,46.69 109.48,46.57 109.48,45.64 109.26,45.43 109.12,45.43 v3(108.83,45.72)
DDRA_SDQS3: length 58.5
  IN1 w0.102: v3(126.64,86.62) 126.6,86.62 126.4,86.42 126.4,86.13 125.92,85.65 125.16,85.65 124.58,85.08 124.58,83.08 124.2,82.7 124.2,82.67 124.19,82.66
  IN1 w0.114: v3(114.02,42.24) 113.77,41.99 113.68,41.99 113.53,42.14 113.53,42.79 114.71,43.97 114.71,47.81 116.41,49.51 116.41,67.9 116.79,68.27 116.79,68.63 116.48,68.94 116.48,69.1 116.75,69.38 116.92,69.38 117.36,68.94 117.74,68.94 118.14,69.34 118.14,69.71 117.69,70.16 117.69,70.32 117.97,70.6 118.13,70.6 118.56,70.17 118.94,70.17 119.34,70.57 119.34,70.94 118.91,71.37 118.91,71.53 120.41,73.04 120.41,74.02 123.51,77.12 123.51,80.53 123.73,80.75 123.73,82.2 124.19,82.66
  BOTTOM w0.102: JDIMM1.64 115.05,41.58 114.64,41.99 114.27,41.99 v3(114.02,42.24) ; v3(126.64,86.62) 127.1,87.08 UC1.F28
DDRA_SDQS3#: length 58.5
  IN1 w0.102: 124.02,82.82 124.04,82.84 124.06,82.84 124.38,83.16 124.38,85.16 125.07,85.86 125.84,85.86 126.19,86.21 126.19,86.4 v3(125.92,86.67)
  IN1 w0.114: 124.02,82.82 123.49,82.3 123.49,80.85 123.27,80.63 123.27,77.22 120.17,74.12 120.17,73.13 118.67,71.63 118.67,71.27 119.1,70.84 119.1,70.66 118.84,70.4 118.66,70.4 118.23,70.83 117.87,70.83 117.46,70.42 117.46,70.06 117.9,69.61 117.9,69.43 117.64,69.17 117.46,69.17 117.01,69.62 116.66,69.62 116.24,69.2 116.24,68.84 116.55,68.53 116.55,68.37 116.18,68 116.18,49.61 114.48,47.91 114.48,44.07 113.29,42.88 113.29,42.04 113.58,41.75 113.79,41.75 v3(114.02,41.53)
  BOTTOM w0.102: UC1.E28 126.3,87.04 v3(125.92,86.67) ; JDIMM1.62 114.45,40.39 114.78,40.72 114.78,41.47 114.53,41.72 114.21,41.72 v3(114.02,41.53)
DDRA_SDQS4: length 57
  IN1 w0.102: 147.4,81.69 147.4,81.71 147.41,81.72 147.41,82.68 147.44,82.71 147.44,83.65 147.1,83.99 147.1,84.46 146.83,84.73 145.77,84.73 ; 145.7,84.73 v3(145.1,85.32)
  IN1 w0.114: 145.77,84.73 145.7,84.73 ; v3(139.63,44.32) 139.63,44.22 139.85,44 140.04,44 140.21,44.17 140.21,46.99 140.09,47.1 139.83,47.1 139.58,47.36 139.58,47.95 139.83,48.2 140.09,48.2 140.21,48.31 140.21,48.71 140.09,48.82 139.83,48.82 139.58,49.07 139.58,49.66 139.83,49.92 140.09,49.92 140.21,50.03 140.21,50.42 140.09,50.54 139.83,50.54 139.58,50.79 139.58,51.38 139.83,51.63 140.09,51.63 140.21,51.75 140.21,52.14 140.09,52.26 139.83,52.26 139.58,52.51 139.58,53.1 139.83,53.35 140.09,53.35 140.21,53.46 140.21,54.45 148.93,63.17 148.93,68.89 149.56,69.52 149.56,76.23 147.83,77.95 147.83,79.65 147.4,80.09 147.4,81.69
  BOTTOM w0.102: v3(139.63,44.32) 139.63,44.09 139.53,43.99 139.24,43.99 139.03,44.2 139.03,46.5 139.35,46.82 JDIMM1.137 ; UC1.AJ30 145.5,85.72 v3(145.1,85.32)
DDRA_SDQS4#: length 57.1
  IN1 w0.102: 147.64,81.69 147.64,81.7 147.61,81.73 147.61,82.6 147.64,82.63 147.64,83.73 147.3,84.07 147.3,84.54 146.92,84.93 145.85,84.93 145.74,85.04 v3(145.74,85.3)
  IN1 w0.114: 147.64,81.69 147.64,80.18 148.07,79.75 148.07,78.05 149.8,76.32 149.8,69.43 149.16,68.79 149.16,63.07 140.44,54.35 140.44,53.37 140.19,53.11 139.93,53.11 139.82,53 139.82,52.61 139.93,52.49 140.19,52.49 140.44,52.24 140.44,51.65 140.19,51.4 139.93,51.4 139.82,51.28 139.82,50.89 139.93,50.78 140.19,50.78 140.44,50.52 140.44,49.93 140.19,49.68 139.93,49.68 139.82,49.57 139.82,49.17 139.93,49.06 140.19,49.06 140.44,48.81 140.44,48.22 140.19,47.96 139.93,47.96 139.82,47.85 139.82,47.46 139.93,47.34 140.19,47.34 140.44,47.09 140.44,44.07 140.14,43.77 139.86,43.77 v3(139.63,43.54)
  BOTTOM w0.102: v3(139.63,43.54) 139.45,43.72 139.13,43.72 138.76,44.09 138.76,46.56 138.75,46.57 JDIMM1.135 ; v3(145.74,85.3) 145.94,85.5 UC1.AK30
DDRA_SDQS5: length 64.4
  IN1 w0.102: v3(144.26,90.07) 144.12,90.07 143.95,89.89 143.95,89.74 144.15,89.54 145.8,89.54 146.33,89.01 146.33,88.91 146.51,88.73 147.38,88.73 148.7,87.4 149.1,87.4 149.12,87.42 149.13,87.42
  IN1 w0.114: v3(145.01,42.03) 145.01,42.03 145.32,42.35 145.68,42.35 146.01,42.68 146.01,43.74 145.7,44.04 145.39,44.04 145.28,44.15 145.28,44.55 145.39,44.66 145.75,44.66 146.01,44.91 146.01,51.11 151.77,56.87 151.77,57.31 154.01,59.55 154.01,66.81 154.75,67.55 154.75,78.2 153.63,79.32 153.63,82.93 150.18,86.39 150.18,86.74 149.5,87.42 149.13,87.42
  BOTTOM w0.102: UC1.AH24 144.26,90.26 v3(144.26,90.07) ; v3(145.01,42.03) 144.73,42.31 144.46,42.31 144.26,42.1 144.26,40.69 144.45,40.5 JDIMM1.154
DDRA_SDQS5#: length 64.4
  IN1 w0.102: 149.13,87.18 149.1,87.18 149.09,87.2 148.62,87.2 147.29,88.52 146.42,88.52 146.13,88.82 146.13,88.93 145.72,89.34 144.07,89.34 143.74,89.66 143.74,89.92 143.57,90.1 v3(143.42,90.1)
  IN1 w0.114: 149.13,87.18 149.4,87.18 149.94,86.64 149.94,86.29 153.4,82.83 153.4,79.22 154.52,78.1 154.52,67.65 153.78,66.91 153.78,59.65 151.53,57.4 151.53,56.97 145.77,51.21 145.77,45.01 145.65,44.9 145.29,44.9 145.04,44.65 145.04,44.06 145.29,43.8 145.6,43.8 145.77,43.64 145.77,42.77 145.58,42.58 145.31,42.58 145.03,42.87 v3(145.01,42.87)
  BOTTOM w0.102: JDIMM1.152 143.85,40.5 143.99,40.64 143.99,42.21 144.35,42.57 144.71,42.57 v3(145.01,42.87) ; v3(143.42,90.1) 143.42,90.22 UC1.AG24
DDRA_SDQS6: length 80.1
  IN1 w0.114: v3(150.86,44.5) 150.67,44.31 150.45,44.31 150.32,44.43 150.32,45.52 150.45,45.65 150.68,45.65 150.91,45.88 150.91,46.74 150.68,46.97 150.43,46.97 150.31,47.1 150.31,47.43 150.42,47.55 150.9,47.55 151.19,47.84 151.19,49.41 157.34,55.56 157.34,56.29 158.78,57.73 158.78,60.47 160.41,62.1 160.41,72.14 164.48,76.21 164.48,83.77 161.9,86.35 159.79,86.35 159.65,86.49 159.65,87.1 159.32,87.43 158.94,87.43 158.69,87.18 158.69,86.44 158.58,86.32 158.18,86.32 158.07,86.44 158.07,87.18 157.82,87.43 157.02,87.43 152.24,92.21 148.59,92.21 147.64,93.16 147.38,93.16 146.99,93.56 145.01,93.56 144.3,94.26 143.74,94.26 143.54,94.47 v3(143.54,94.82)
  BOTTOM w0.102: v3(143.54,94.82) 143.9,94.46 UC1.AG19 ; v3(150.86,44.5) 150.66,44.3 150.02,44.3 149.42,44.9 149.42,46.55 149.55,46.68 JDIMM1.171
DDRA_SDQS6#: length 80.2
  IN1 w0.114: v3(150.86,43.87) 150.65,44.07 150.35,44.07 150.09,44.33 150.09,45.62 150.36,45.88 150.58,45.88 150.67,45.97 150.67,46.64 150.58,46.73 150.33,46.73 150.07,47 150.07,47.52 150.33,47.78 150.81,47.78 150.96,47.93 150.96,49.51 157.11,55.66 157.11,56.39 158.54,57.83 158.54,60.57 160.17,62.2 160.17,72.23 164.24,76.31 164.24,83.67 161.8,86.11 159.69,86.11 159.41,86.39 159.41,87.01 159.22,87.19 159.04,87.19 158.93,87.08 158.93,86.34 158.67,86.08 158.08,86.08 157.83,86.34 157.83,87.08 157.72,87.19 156.93,87.19 152.14,91.98 148.49,91.98 147.54,92.93 147.29,92.93 146.89,93.32 144.91,93.32 144.21,94.03 143.79,94.03 v3(143.57,93.81)
  BOTTOM w0.102: v3(143.57,93.81) 143.54,93.81 143.1,94.25 UC1.AF19 ; JDIMM1.169 148.95,46.69 149.15,46.49 149.15,44.79 149.91,44.04 150.69,44.04 v3(150.86,43.87)
DDRA_SDQS7: length 86.3
  IN1 w0.102: 147.52,97.61 147.36,97.77 146.28,97.77 146,98.05 145.48,98.05 v3(145.02,98.5)
  IN1 w0.114: v3(155.35,42.09) 155.2,42.24 154.84,42.24 154.51,42.58 154.51,43.71 155.66,44.86 155.66,47.76 157.03,49.13 157.03,49.56 165.25,57.78 165.25,58.43 164.92,58.76 164.69,58.76 164.44,59.02 164.44,59.61 164.69,59.86 165.14,59.86 165.25,59.97 165.25,60.37 165.14,60.48 164.65,60.48 164.39,60.75 164.39,61.31 164.65,61.58 165.14,61.58 165.25,61.69 165.25,64.06 169.58,68.38 169.58,84.56 162.06,92.08 159.21,92.08 156.9,94.39 156.09,94.39 155.61,94.87 155.61,95.32 154.64,96.29 152.69,96.29 152.36,96.62 148.51,96.62 147.52,97.61
  BOTTOM w0.102: v3(155.35,42.09) 155.21,42.23 154.85,42.23 154.65,42.03 JDIMM1.188 ; UC1.AH14 144.7,98.18 v3(145.02,98.5)
DDRA_SDQS7#: length 86.4
  IN1 w0.102: 147.69,97.78 147.68,97.78 147.64,97.78 147.61,97.82 147.6,97.82 147.45,97.97 146.36,97.97 146.08,98.25 145.78,98.25 145.62,98.4 v3(145.62,98.51)
  IN1 w0.114: 147.69,97.78 148.61,96.85 152.46,96.85 152.79,96.52 154.74,96.52 155.84,95.42 155.84,94.97 156.19,94.63 157,94.63 159.31,92.32 162.16,92.32 169.81,84.66 169.81,68.28 165.49,63.96 165.49,61.59 165.23,61.34 164.75,61.34 164.62,61.21 164.62,60.84 164.75,60.72 165.23,60.72 165.49,60.46 165.49,59.87 165.23,59.62 164.79,59.62 164.67,59.51 164.67,59.11 164.79,59 165.01,59 165.49,58.53 165.49,57.68 157.27,49.46 157.27,49.03 155.89,47.66 155.89,44.76 154.74,43.61 154.74,42.68 154.94,42.48 155.09,42.48 v3(155.36,42.75)
  BOTTOM w0.102: JDIMM1.186 154.05,40.51 154.16,40.62 154.3,40.62 154.38,40.7 154.38,42.14 154.74,42.5 155.11,42.5 v3(155.36,42.75) ; UC1.AJ14 145.5,98.38 v3(145.62,98.51)
DDRA_SMA0: length 52.6
  IN1 w0.102: 138.12,79.34 138.26,79.48 138.26,80.98 138.94,81.66 138.94,83.07 v3(140.07,84.2)
  IN1 w0.183: 138.12,79.34 138.12,68.21 135.76,65.85 135.76,64.65 134.07,62.96 134.07,61.7 129.88,57.51 129.88,43.11 129.44,42.68 129.44,40.54 129.11,40.21 128.02,40.21 127.72,40.52 v3(127.72,40.87)
  BOTTOM w0.102: UC1.AB31 139.58,84.7 v3(140.07,84.2)
  BOTTOM w0.17: v3(127.72,40.87) 127.65,40.81 JDIMM1.98
DDRA_SMA1: length 53.8
  IN1 w0.102: v3(136.46,82.78) 135.74,82.06 135.74,80.22 135.36,79.84
  IN1 w0.183: 135.36,79.84 135.36,77.66 135.08,77.38 135.08,77.1 135.36,76.82 135.36,76.53 135.08,76.26 135.08,75.97 135.36,75.69 135.36,75.41 135.08,75.13 135.08,74.84 135.36,74.56 135.36,74.28 135.08,74 135.08,73.72 135.36,73.44 135.36,73.15 135.08,72.87 135.08,72.59 135.36,72.31 135.36,72.02 135.08,71.74 135.08,71.46 135.36,71.18 135.36,70.89 134.99,70.52 134.99,70.28 135.41,69.86 135.41,69.63 135.25,69.46 135.02,69.46 134.59,69.88 134.36,69.88 134.19,69.72 134.19,69.49 134.82,68.86 134.82,68.63 134.66,68.46 134.42,68.46 133.81,69.07 133.56,69.07 133.38,68.89 133.38,68.64 133.67,68.34 133.67,68 133.46,67.8 133.23,67.8 132.88,68.15 132.64,68.15 132.48,67.98 132.48,67.75 132.83,67.4 132.83,67.16 132.67,67 132.43,67 132.08,67.35 131.84,67.35 131.68,67.19 131.68,66.95 132.03,66.6 132.03,66.37 131.87,66.2 131.64,66.2 131.28,66.55 131.05,66.55 130.88,66.39 130.88,66.16 131.24,65.8 131.24,65.57 126.99,61.32 126.99,60.4 127.26,60.13 127.26,59.84 126.99,59.57 126.99,59.28 127.26,59 127.26,58.71 126.99,58.44 126.99,58.15 127.26,57.87 127.26,57.58 126.99,57.31 126.99,57.02 127.26,56.75 127.26,56.46 126.99,56.18 126.99,55.89 127.26,55.62 127.26,55.33 126.99,55.05 126.99,54.77 127.26,54.49 127.26,54.2 126.99,53.93 126.99,53.64 127.26,53.36 127.26,53.07 126.99,52.8 126.99,48.74 127.26,48.47 127.26,48.18 126.99,47.91 126.99,47.62 127.26,47.34 127.26,47.05 126.99,46.78 126.99,46.28 v3(127.03,46.23)
  BOTTOM w0.102: v3(136.46,82.78) 136.15,83.1 UC1.U33
  BOTTOM w0.17: JDIMM1.97 127.35,46.55 v3(127.03,46.23)
DDRA_SMA2: length 52.9
  IN1 w0.102: 134.82,80.03 135.49,80.7 135.49,82.34 135.98,82.83 135.98,82.99 v3(136.49,83.49)
  IN1 w0.183: v3(126.6,40.97) 126.6,40.16 126.78,39.98 127.03,39.98 127.21,40.16 127.21,42.04 126.99,42.26 126.99,42.88 126.87,43.01 126.7,43.01 126.52,43.19 126.52,43.44 126.7,43.62 127.07,43.62 127.23,43.79 127.23,44.02 127.07,44.19 126.66,44.19 126.5,44.35 126.5,61.52 130.39,65.42 130.39,66.61 134.59,70.8 134.59,77.62 134.81,77.85 134.81,80.02 134.82,80.03
  BOTTOM w0.102: UC1.U32 136.08,83.9 v3(136.49,83.49)
  BOTTOM w0.17: JDIMM1.96 127.05,40.35 126.6,40.8 v3(126.6,40.97)
DDRA_SMA3: length 53.7
  IN1 w0.102: v3(135.3,85.75) 134.6,85.06 134.6,83.44 134.43,83.27 134.43,81.55 132.77,79.89 132.77,79.48
  IN1 w0.183: 132.77,79.48 132.77,78.62 132.63,78.48 132.63,71.61 128.81,67.79 127.8,67.79 126.56,66.55 126.56,66.37 126.85,66.07 126.85,65.84 126.69,65.68 126.45,65.68 126.18,65.95 125.97,65.95 125.77,65.75 125.77,65.53 125.99,65.31 125.99,64.98 124.86,63.85 124.86,63.23 125.01,63.09 125.01,62.79 124.55,62.33 124.55,46.71 124.43,46.6 124.43,45.48 124.12,45.17 124.12,44.63 124.31,44.43 124.8,44.43 124.95,44.58 v3(124.95,44.76)
  BOTTOM w0.102: v3(135.3,85.75) 135.27,85.75 135.02,85.5 UC1.R30
  BOTTOM w0.17: v3(124.95,44.76) 125.74,44.76 126.4,45.42 126.4,46.46 126.75,46.81 JDIMM1.95
DDRA_SMA4: length 53.4
  IN1 w0.102: 134.32,79.1 133.94,79.48 133.94,79.84 134.03,79.92 134.03,79.92 135.21,81.1 135.21,82.75 v3(135.32,82.86)
  IN1 w0.183: 134.32,79.1 134.32,78.05 134.1,77.83 134.1,71 129.91,66.81 129.91,65.62 126.01,61.72 126.01,42.6 125.41,41.99 125.41,40.37 125.58,40.19 125.84,40.19 126.02,40.37 126.02,41.69 v3(126.5,42.17)
  BOTTOM w0.102: v3(135.32,82.86) 135.32,82.81 135.1,82.59 UC1.T34
  BOTTOM w0.17: v3(126.5,42.17) 126.45,42.22 126.45,42.19 125.85,41.6 JDIMM1.92
DDRA_SMA5: length 53.9
  IN1 w0.102: v3(135.3,85.02) 135.29,85.02 134.88,84.61 134.88,83.39 134.65,83.16 134.65,81.36 133.23,79.94 133.23,79.05 133.28,79
  IN1 w0.183: v3(124.92,45.98) 125.04,46.09 125.04,62.13 125.7,62.79 125.7,63.09 125.38,63.4 125.38,63.66 125.55,63.83 125.8,63.83 126.15,63.49 126.38,63.49 126.55,63.65 126.55,63.89 126.19,64.24 126.19,64.48 126.36,64.64 126.59,64.64 126.94,64.29 127.18,64.29 127.34,64.45 127.34,64.69 126.99,65.04 126.99,65.27 127.15,65.44 127.39,65.44 127.74,65.08 127.98,65.08 128.14,65.25 128.14,65.48 127.29,66.34 127.29,66.55 127.47,66.74 127.69,66.74 128.54,65.88 128.77,65.88 128.91,66.02 128.91,66.31 128.25,66.97 128.25,67.16 128.39,67.3 129.01,67.3 133.12,71.41 133.12,78.23 133.28,78.39 133.28,79
  BOTTOM w0.102: UC1.R31 134.98,84.7 v3(135.3,85.02)
  BOTTOM w0.17: v3(124.92,45.98) 125.08,45.83 125.33,45.83 125.55,46.05 JDIMM1.91
DDRA_SMA6: length 52.3
  IN1 w0.102: 133.61,79.23 133.61,79.9 134.91,81.19 134.91,83.05 v3(135.35,83.49)
  IN1 w0.183: v3(124.67,42.68) 124.87,42.47 125.2,42.47 125.52,42.8 125.52,43.18 125.34,43.36 124.48,43.36 124.31,43.53 124.31,43.78 124.48,43.95 125.34,43.95 125.52,44.12 125.52,61.92 129.42,65.82 129.42,67.01 133.61,71.2 133.61,78.03 133.77,78.19 133.77,79.07 133.61,79.23
  BOTTOM w0.102: v3(135.35,83.49) 134.95,83.1 UC1.R33
  BOTTOM w0.17: JDIMM1.90 125.25,42.2 124.77,42.68 v3(124.67,42.68)
DDRA_SMA7: length 53.9
  IN1 w0.102: 131.17,79.1 131.5,79.43 131.5,80.42 132.52,81.43 132.52,81.94 132.92,82.35 133.08,82.35 133.34,82.61 133.34,83.09 133.01,83.42 v3(133.01,83.47)
  IN1 w0.183: 131.17,79.1 131.17,72.22 130.46,71.5 130.13,71.5 127.88,69.25 127.19,69.25 122.55,64.61 122.55,49.97 123.08,49.44 123.08,47.8 122.56,47.27 122.56,44.26 123.62,43.2 123.62,42.73 123.78,42.56 123.95,42.56 124.11,42.4 124.11,42.16 123.95,42 123.26,42 123.07,41.8 123.07,41.53 123.26,41.33 124.49,41.33 v3(124.64,41.48)
  BOTTOM w0.102: v3(133.01,83.47) 133.38,83.1 UC1.P33
  BOTTOM w0.17: v3(124.64,41.48) 124.52,41.48 124.05,41.02 JDIMM1.86
DDRA_SMA8: length 53.8
  IN1 w0.102: 132.22,78.8 132.29,78.86 132.29,79.91 133.62,81.24 133.62,81.93 134.15,82.47 134.15,82.85 134.02,82.99 134.02,83.43 v3(134.15,83.57)
  IN1 w0.183: v3(123.09,44.4) 123.48,44.4 123.63,44.56 123.63,45.37 123.93,45.67 123.93,46.79 124.06,46.92 124.06,51.48 123.89,51.65 123.68,51.65 123.53,51.8 123.53,52.06 123.68,52.21 123.89,52.21 124.06,52.38 124.06,52.61 123.89,52.78 123.68,52.78 123.53,52.93 123.53,53.19 123.68,53.34 123.89,53.34 124.06,53.51 124.06,53.74 123.89,53.9 123.68,53.9 123.53,54.06 123.53,54.32 123.68,54.47 123.89,54.47 124.06,54.63 124.06,54.87 123.89,55.03 123.68,55.03 123.53,55.18 123.53,55.44 123.68,55.6 123.89,55.6 124.06,55.76 124.06,56.09 123.89,56.25 123.68,56.25 123.53,56.41 123.53,56.67 123.68,56.82 123.89,56.82 124.06,56.98 124.06,62.53 124.37,62.84 124.37,64.05 125.33,65 125.33,65.28 125.1,65.51 125.1,65.78 127.59,68.27 128.61,68.27 132.15,71.81 132.15,78.72 132.22,78.8
  BOTTOM w0.102: v3(134.15,83.57) 133.82,83.9 UC1.P32
  BOTTOM w0.17: JDIMM1.89 124.95,46.87 124.44,46.36 124.44,44.76 124.09,44.4 v3(123.09,44.4)
DDRA_SMA9: length 53.7
  IN1 w0.102: v3(134,85.14) 133.67,84.81 133.67,82.42 133.32,82.07 133.32,81.58 131.88,80.14 131.88,79.15
  IN1 w0.183: v3(123.09,45.72) 123.07,45.75 123.07,45.9 123.4,46.23 123.4,46.51 123.04,46.87 123.04,47.05 123.57,47.57 123.57,49.64 123.04,50.17 123.04,57.23 123.2,57.39 123.39,57.39 123.55,57.56 123.55,57.79 123.39,57.95 123.2,57.95 123.04,58.11 123.04,58.37 123.2,58.52 123.39,58.52 123.55,58.68 123.55,58.92 123.39,59.08 123.2,59.08 123.04,59.23 123.04,59.49 123.2,59.65 123.39,59.65 123.55,59.81 123.55,60.04 123.39,60.21 123.2,60.21 123.04,60.36 123.04,60.62 123.2,60.77 123.39,60.77 123.55,60.94 123.55,61.17 123.39,61.34 123.28,61.34 123.12,61.5 123.12,61.82 123.28,61.99 123.39,61.99 123.55,62.15 123.55,62.38 123.39,62.55 123.28,62.55 123.12,62.71 123.12,62.95 123.28,63.11 123.7,63.11 123.86,63.27 123.86,63.52 123.7,63.68 123.28,63.68 123.12,63.84 123.12,64.09 123.27,64.24 123.55,64.24 123.7,64.39 123.7,64.57 123.58,64.7 123.58,64.94 123.73,65.09 123.96,65.09 124.21,64.83 124.45,64.83 124.61,65 124.61,65.23 124.35,65.49 124.35,65.72 127.39,68.76 128.41,68.76 131.66,72.01 131.66,78.93 131.88,79.15
  BOTTOM w0.102: v3(134,85.14) 133.65,85.5 UC1.P30
  BOTTOM w0.17: v3(123.09,45.72) 123.5,45.72 123.75,45.97 JDIMM1.85
DDRA_SMA10: length 53.8
  IN1 w0.183: v3(131.63,44.89) 131.64,44.88 132.04,44.88 132.36,45.19 132.36,46.58 132.2,46.74 132.05,46.74 131.88,46.91 131.88,47.14 132.05,47.3 132.2,47.3 132.36,47.47 132.36,47.7 132.2,47.87 132.05,47.87 131.88,48.03 131.88,48.27 132.05,48.43 132.2,48.43 132.36,48.6 132.36,49.29 131.87,49.78 131.87,49.98 132.03,50.14 132.17,50.14 132.34,50.31 132.34,50.54 132.17,50.71 132.03,50.71 131.87,50.87 131.87,51.17 132.04,51.34 132.67,51.34 132.99,51.66 132.99,52.07 132.79,52.28 132.07,52.28 131.87,52.48 131.87,53.67 132.04,53.85 132.8,53.85 132.99,54.05 132.99,56.42 132.8,56.62 132.29,56.62 132.13,56.78 132.13,57.01 136.02,60.9 136.02,62.16 139.71,65.85 139.71,66.5 139.57,66.64 139.57,66.9 140.11,67.45 140.11,68.67 140.29,68.84 141.15,68.84 141.28,68.97 141.28,72.47 141.13,72.62 140.95,72.62 140.8,72.77 140.8,73.55 140.1,74.25 140.1,80.66 140.81,81.37 140.81,81.62 v3(141.01,81.82)
  BOTTOM w0.102: UC1.AD34 141.49,82.3 v3(141.01,81.82)
  BOTTOM w0.17: v3(131.63,44.89) 131.63,44.71 131.43,44.51 130.28,44.51 130.08,44.71 130.08,46.49 130.35,46.76 JDIMM1.107
DDRA_SMA11: length 53.8
  IN1 w0.102: 130.68,79.9 130.68,80.1 132.2,81.62 132.2,82.05 v3(132.93,82.78)
  IN1 w0.183: 130.68,79.9 130.68,75.83 130.51,75.66 130.5,75.66 130.33,75.5 130.33,75.27 130.5,75.1 130.51,75.1 130.68,74.94 130.68,74.7 130.51,74.54 130.5,74.54 130.33,74.37 130.33,74.14 130.5,73.97 130.51,73.97 130.68,73.81 130.68,73.57 130.51,73.41 130.5,73.41 130.33,73.24 130.33,73.01 130.5,72.85 130.51,72.85 130.68,72.68 130.68,72.41 130.26,71.99 129.93,71.99 127.67,69.74 126.99,69.74 122.06,64.81 122.06,48.57 122.24,48.39 122.42,48.39 122.59,48.23 122.59,47.99 122.42,47.83 122.27,47.83 122.07,47.63 122.07,44.06 122.29,43.84 122.29,43.6 121.95,43.26 121.95,43.03 122.12,42.86 122.35,42.86 122.69,43.2 122.93,43.2 123.13,43 123.13,42.59 122.74,42.19 v3(122.18,42.19)
  BOTTOM w0.102: UC1.P34 133.42,82.3 v3(132.93,82.78)
  BOTTOM w0.17: JDIMM1.84 123.45,41.25 122.51,42.19 v3(122.18,42.19)
DDRA_SMA12: length 54
  IN1 w0.102: v3(132.96,85.7) 133.28,85.7 133.39,85.6 133.39,84.19 133.15,83.95 132.79,83.95 132.45,83.61 132.45,82.66 131.88,82.09 131.88,81.71 130.18,80.01 130.18,79.73
  IN1 w0.183: 130.18,79.73 130.12,79.67 130.12,76.69 129.96,76.53 129.32,76.53 129.17,76.38 129.17,76.13 129.32,75.98 129.67,75.98 129.83,75.82 129.83,75.57 129.67,75.42 129.31,75.42 129.15,75.26 129.15,74.87 129.27,74.76 129.27,74.35 129.15,74.24 129.15,73.83 129.27,73.72 129.27,73.48 129.1,73.31 128.99,73.31 128.83,73.16 128.83,72.9 128.99,72.75 129.34,72.75 129.5,72.6 129.5,72.32 129.14,71.96 128.96,71.96 128.75,72.17 128.54,72.17 128.31,71.94 128.31,71.73 128.53,71.51 128.53,71.28 127.47,70.23 126.79,70.23 121.58,65.02 121.58,45.55 121.42,45.39 v3(121.19,45.39)
  BOTTOM w0.102: UC1.M30 132.5,85.7 v3(132.96,85.7)
  BOTTOM w0.17: JDIMM1.83 123.15,46.62 121.93,45.39 v3(121.19,45.39)
DDRA_SMA13: length 53.9
  IN1 w0.102: 141.93,80.77 141.93,80.88 142.18,81.13 142.18,81.91 142.65,82.38 142.65,82.38 142.89,82.61 142.89,83.09 143.35,83.54 v3(143.63,83.54)
  IN1 w0.183: 141.93,80.77 141.93,78.73 141.7,78.5 141.7,78.16 141.93,77.93 141.93,76.17 141.56,75.8 141.56,74.86 141.77,74.64 143.05,74.64 143.77,73.92 143.77,73.73 143.6,73.57 143.4,73.57 143.24,73.4 143.24,73.17 143.4,73 143.6,73 143.77,72.84 143.77,72.6 143.6,72.44 143.4,72.44 143.24,72.27 143.24,72.04 143.4,71.87 143.6,71.87 143.77,71.71 143.77,71.47 143.6,71.31 143.4,71.31 143.24,71.14 143.24,70.91 143.4,70.75 143.6,70.75 143.77,70.58 143.77,70.35 143.6,70.18 143.4,70.18 143.24,70.02 143.24,69.78 143.4,69.62 143.6,69.62 143.77,69.45 143.77,69.22 143.6,69.05 143.4,69.05 143.24,68.89 143.24,68.66 143.4,68.49 143.6,68.49 143.77,68.33 143.77,68.08 143.59,67.9 142.28,67.9 141.98,67.6 141.98,67.37 143.13,66.21 143.13,65.97 142.96,65.8 142.72,65.8 141.79,66.73 141.46,66.73 141.17,66.44 141.17,65.14 137.48,61.45 137.48,60.29 134.46,57.26 134.46,51.06 133.83,50.43 133.83,46.22 v3(133.86,46.18)
  BOTTOM w0.102: v3(143.63,83.54) 143.54,83.54 UC1.AF33
  BOTTOM w0.17: v3(133.86,46.18) 133.95,46.27 JDIMM1.119
DDRA_SMA14: length 54.5
  IN1 w0.102: v3(132.96,85.04) 132.88,85.04 132.11,84.27 132.11,82.66 131.76,82.3 131.32,82.3 130.94,81.92 130.94,81.74
  IN1 w0.183: v3(122.21,40.96) 121.16,40.96 120.96,41.15 120.96,41.44 121.16,41.63 121.37,41.63 121.47,41.74 121.47,43.82 120.61,44.68 120.61,45.62 121.09,46.11 121.09,65.22 126.58,70.71 127.27,70.71 127.8,71.24 127.8,72.24 128.32,72.76 128.32,73.47 128.67,73.81 128.67,76.89 128.82,77.04 129.48,77.04 129.63,77.19 129.63,80.06 130.94,81.37 130.94,81.74
  BOTTOM w0.102: v3(132.96,85.04) 132.86,85.04 132.52,84.7 UC1.M31
  BOTTOM w0.17: v3(122.21,40.96) 122.21,41 122.25,40.96 JDIMM1.80
DDRA_SMA15: length 54.3
  IN1 w0.183: v3(131.69,84.18) 131.56,84.31 129.88,84.31 128.54,82.97 128.54,81.04 127.49,79.99 127.49,79.66 126.7,78.87 126.7,74.22 123.57,71.09 123.57,69.77 119.62,65.82 119.62,48.07 118.7,47.14 118.7,43.68 119.48,42.9 120.63,42.9 120.81,42.73 120.81,42.3 120.61,42.09 v3(120.45,42.09)
  BOTTOM w0.102: v3(131.69,84.18) 131.41,83.9 UC1.L32
  BOTTOM w0.17: v3(120.45,42.09) 121.65,40.9 JDIMM1.78
DDRA_SRAS#: length 52.2
  IN1 w0.102: v3(141.27,83.47) 140.52,82.72 139.82,82.72 139.52,82.43 139.52,81.37 139.41,81.25
  IN1 w0.183: v3(130.99,40.87) 131.2,40.87 131.79,41.46 131.79,41.79 131.48,42.1 131.48,42.47 131.79,42.79 131.79,43.06 131.64,43.21 131.07,43.21 130.89,43.39 130.89,43.62 131.06,43.78 131.57,43.78 131.73,43.95 131.73,44.18 131.57,44.34 131.06,44.34 130.89,44.51 130.89,57.15 135.04,61.3 135.04,62.56 136.73,64.25 136.73,65.45 139.12,67.83 139.12,80.97 139.41,81.25
  BOTTOM w0.102: v3(141.27,83.47) 140.83,83.9 UC1.AC32
  BOTTOM w0.17: v3(130.99,40.87) 131.02,40.87 131.25,40.64 JDIMM1.110
DDRA_SWE#: length 54.6
  IN1 w0.102: 141.44,80.85 141.44,80.86 141.85,81.27 141.85,82.27 142.06,82.47 142.06,83.04 v3(142.5,83.48)
  IN1 w0.183: 141.44,80.85 141.44,78.94 141.07,78.57 141.07,78.06 141.24,77.9 141.27,77.9 141.43,77.73 141.43,77.5 141.27,77.33 141.24,77.33 141.07,77.17 141.07,76.93 141.24,76.77 141.27,76.77 141.43,76.6 141.43,76.37 141.27,76.2 141.24,76.2 141.07,76.04 141.07,74.66 141.57,74.15 142.06,74.15 142.3,73.92 142.3,68.61 141.09,67.4 141.09,67.04 140.69,66.64 140.69,65.34 136.99,61.65 136.99,60.49 133.97,57.47 133.97,51.26 133.34,50.63 133.34,44.79 132.76,44.22 132.76,42.59 132.89,42.46 133.17,42.46 133.89,43.18 v3(133.89,43.82)
  BOTTOM w0.102: v3(142.5,83.48) 142.11,83.1 UC1.AE33
  BOTTOM w0.17: v3(133.89,43.82) 133.56,43.82 132.15,45.23 JDIMM1.113
DEVSLP0: length 59.8
  TOP w0.102: v3(170.11,32.54) 170.76,32.54 v1(170.97,32.33)
  IN1 w0.114: v3(175.85,9.71) 175.85,9.83 177.8,11.78 186.29,11.78 188.47,13.96 188.47,17.85 187.83,18.5 187.03,18.5 185.95,19.57 185.95,21.12 184.54,22.54 184.54,24.76 183.49,25.81 180.11,25.81 174.17,31.75 171.02,31.75 170.24,32.54 v3(170.11,32.54)
  IN2 w0.102: v3(170.11,32.54) 167.76,32.54 166.33,31.11 166.33,29.49 164.78,27.94 v3(164.78,27)
  BOTTOM w0.102: RH135.2 169.09,33.56 v3(170.11,32.54) ; RS8.1 175.85,9.1 v3(175.85,9.71) ; v3(164.78,27) 165.16,26.62 U2.AE26
DEW1: length 4.6
  TOP w0.102: RS36.1 RS34.1 178.34,12.93 178.96,12.93 v1(179.23,13.2) 180.16,14.13 US2.16
DEW2: length 5.7
  TOP w0.102: US2.6 182.16,19.22 181.87,19.51 181.87,20.48 RS35.1 182.45,21.72 RS33.1 182.56,22.29 v1(181.83,23.02)
DH_1.35V:
  vias: v1(87.53,12.37) v2(87.31,11.74) v2(87.94,11.99)
DH_CHG: length 12
  TOP w1.016: 43.49,19.38 43.49,20.47 v1(44.23,21.21) 45.94,22.92 45.94,27.63 PQ701.4
  BOTTOM w0.254: PU700.24 43.44,17.76 v2(43.47,17.78)
  vias: v2(43.47,18.47)
DIR: length 6.3
  BOTTOM w0.102: CV169.2 87.06,90.67 v1(87.34,90.39)
  BOTTOM w0.254: RV79.1 CV167.2 CV169.2 85.74,90.71 U1.5
DISPOFF#: length 5.3
  TOP w0.102: DX1.1 6.2,79.91 4.81,79.91 4.3,80.42 RX9.1 3.33,80.45 v1(3.24,80.54) v3(2.88,80.9)
  BOTTOM w0.102: JEDP.37 2.78,81 v3(2.88,80.9)
DL_1.35V: length 7.4
  TOP w0.102: v2(85.78,14.28) v1(86.52,14.28)
  IN1 w1.016: 88.19,19.94 88.19,16.69 v2(85.78,14.28)
  vias: v2(85.27,13.52) v2(87.56,20.88) v2(88.19,20.88)
DL_CHG: length 6.3
  IN1 w1.016: 38.27,16.03 37.88,16.42 37.88,20.78 36.89,21.77
  vias: v1(39.5,15.36) v2(35.62,22.41) v2(36.25,22.41) v2(39.16,15.79) v3(39.8,15.79)
DP0_HPD: length 166.6
  TOP w0.102: Q20.3 7.58,99.17 R407.1 R384.2 v3(8.62,100.18) ; v3(143.47,103.31) 143.47,103.55 v1(142.97,104.04)
  IN1 w0.114: v3(8.62,100.18) 9.68,99.12 17.46,99.12 19.23,100.89 22.41,100.89 25.62,104.1 32.52,104.1 34.8,106.39 34.8,107.01 37.88,110.09 55.43,110.09 57.84,107.67 63.05,107.67 63.38,107.34 67.24,107.34 67.72,106.86 67.72,105.96 68.71,104.97 68.71,103.26 71.53,100.44 71.53,99.83 73.11,98.25 87.89,98.25 88.32,97.82 96.4,97.82 96.73,98.15 96.73,98.99 98.91,101.18 101.01,101.18 106.5,106.66 106.5,106.9 112.71,113.11 118.47,113.11 119.16,112.42 137.26,112.42 140.23,109.45 140.98,109.45 141.61,108.82 141.61,105.08 143.39,103.31 v3(143.47,103.31)
  BOTTOM w0.102: UC1.AH7 144.7,103.88 144.13,103.31 v3(143.47,103.31)
DP1_HPD: length 7.4
  BOTTOM w0.102: UC1.B3 123.87,107.1 123.5,107.47 123.5,108.06 123.73,108.28 124.09,108.28 124.31,108.51 124.31,109.49 125.45,110.63 125.45,111.35 v1(125.81,111.71) 126.17,112.07 R14.1
DP2_HPD: length 107.3
  TOP w0.102: QX5.3 193.78,74.55 193.68,74.45 193.12,74.45 192.67,74.91 RX14.1 191.9,76.76 v3(191.7,76.76) ; v3(124.97,103.86) v1(124.17,103.86)
  IN3 w0.135: v3(191.7,76.76) 190.18,78.29 190.18,80.12 189.55,80.74 189.55,91.92 182.17,99.29 179.58,99.29 177.5,101.38 177.5,106.61 176.66,107.45 176.66,111.36 172.35,115.68 170.19,115.68 169.83,116.03 168.36,116.03 167.11,114.79 159.01,114.79 157.41,113.19 147.29,113.19 144.54,110.44 140.9,110.44 138.08,107.62 129.6,107.62 128.4,106.43 127.92,106.43 125.36,103.86 v3(124.97,103.86)
  BOTTOM w0.102: UC1.D7 125.01,103.9 v3(124.97,103.86)
DP2_TXN0_R: length 6.9
  BOTTOM w0.102: CV185.1 123.63,112.63 123.63,111.18 122.47,110.03 122.47,107.52 122.75,107.24 122.96,107.24 UC1.A3
DP2_TXN1_R: length 10.4
  BOTTOM w0.102: CV187.1 121.34,114.91 121.44,114.81 121.9,114.81 122,114.71 122,114.02 122.01,114.01 v2(122.01,113.01) 122.01,111.6 121.79,111.37 121.79,107.28 122.56,106.51 122.99,106.51 123.1,106.4 UC1.A4
DP2_TXN2_R: length 10.5
  BOTTOM w0.102: CV189.1 120.22,112.6 120.22,111.99 121.08,111.14 121.08,107.05 122.37,105.76 123.28,105.76 123.35,105.82 123.61,105.82 123.68,105.76 124.15,105.76 124.3,105.61 UC1.B5
DP2_TXN3_R: length 13.3
  BOTTOM w0.102: UC1.A6 122.68,105.12 122.07,105.12 120.41,106.77 120.41,110.56 118.61,112.36 118.59,112.36 118.14,112.81 118.14,112.83 117.91,113.06 v2(117.91,114.22) 117.91,114.91 CV191.1
DP2_TXP0_R: length 6.9
  BOTTOM w0.102: UC1.A2 123.1,107.58 122.99,107.47 122.83,107.47 122.69,107.61 122.69,109.94 123.84,111.09 123.84,112.62 124.24,113.01 CV184.1
DP2_TXP1_R: length 10.4
  BOTTOM w0.102: UC1.B4 123.61,106.3 123.18,106.72 122.65,106.72 122,107.37 122,111.28 122.23,111.51 122.23,112.6 122.26,112.63 122.26,113.31 122.23,113.34 v2(122.23,114.32) 122.23,115.17 CV186.1
DP2_TXP2_R: length 10.5
  BOTTOM w0.102: CV188.1 120.44,112.62 120.44,112.08 121.29,111.23 121.29,107.14 122.46,105.97 123.19,105.97 123.26,106.04 123.7,106.04 123.77,105.97 124.37,105.97 UC1.C4
DP2_TXP3_R: length 13.3
  BOTTOM w0.102: UC1.A5 123.5,105.41 123.42,105.34 122.16,105.34 120.63,106.86 120.63,110.65 v2(118.52,112.76) 118.13,113.15 118.13,113.94 118.14,113.95 118.14,114.48 118.13,114.49 118.13,114.88 CV190.1
DP_AUX_ZVSS: length 6.9
  BOTTOM w0.203: UC1.D3 125.91,107.51 125.91,109.8 127.5,111.38 v1(127.5,111.73) 127.5,112.56 R13.1
DP_ENBKL: length 24.6
  TOP w0.102: v3(121.37,99.6) 118.65,99.6 116,96.95 v1(111.64,96.95) RP15.7 109.18,96.95 108.9,97.24 108.9,97.51 108.6,97.81 107.84,97.81 107.22,97.18 105.7,97.18 105.47,96.96 105.47,95.81 105.74,95.54 U64.2
  BOTTOM w0.102: v3(121.37,99.6) 121.77,99.19 122.32,99.19 122.49,99.37 123.34,99.37 123.37,99.4 123.63,99.4 123.64,99.39 124.16,99.39 124.37,99.6 124.57,99.6 124.57,99.6 125.2,99.6 UC1.D12
DP_ENVDD: length 20.2
  TOP w0.102: U67.2 107.63,98.21 107.77,98.35 108.9,98.35 109.47,97.78 RP15.8 v1(114.67,97.45) 115.93,97.45 119.29,100.81 v3(122.4,100.81)
  BOTTOM w0.102: v3(122.4,100.81) 122.91,100.81 123.32,100.4 124,100.4 UC1.B11
DP_INT_PWM: length 22.3
  TOP w0.102: U68.2 v1(108.12,92.88) 109.47,94.23 RP15.5 115.58,95.95 118.72,99.09 121.48,99.09 v3(121.99,99.6)
  BOTTOM w0.102: UC1.C12 124.38,99.9 124.08,99.6 123.77,99.6 123.76,99.61 123.24,99.61 123.23,99.6 121.99,99.6 v3(121.99,99.6)
DP_STEREOSYNC: length 10
  BOTTOM w0.102: R30.1 114.56,100.92 115.04,101.4 115.96,101.4 R31.1 116.82,101.25 v1(117.39,101.25) 118.85,101.25 119.87,102.26 121.57,102.26 121.61,102.3 UC1.A9
DP_VSSR: length 9.9
  BOTTOM w0.254: UV1.AM18 74.84,82.5 v3(75.24,82.1) ; UV1.AM22 74.57,79.3 74.17,78.89 73.78,78.89 73.77,78.91 73.43,78.91 73.42,78.89 73.38,78.89 72.99,78.5 UV1.AG23 UV1.AF23 ; v3(75.11,80.45) 75.11,80.59 UV1.AM20
  BOTTOM w0.305: UV1.AM16 74.83,84.1 v3(75.24,84.51) ; v3(72.83,86.16) 73.2,85.79 UV1.AH14 ; v3(75.24,78.16) 74.8,77.72 UV1.AM24 ; UV1.AG14 v3(72.83,85.27) ; UV1.AM14 74.8,85.72 v3(75.24,86.16) ; UV1.AM22 74.86,79.36 74.86,79.38 v3(75.16,79.68)
  BOTTOM w0.381: UV1.AF20 71.6,80.87 71.94,81.21 v3(71.94,81.34) 71.6,81.67 UV1.AF19
  vias: v1(73.51,83.6)
DRAM_RST: length 12.1
  TOP w0.102: v1(64.6,92.93) 64.87,92.66 v3(65.13,92.66) CV97.1 RV38.1 RV37.1
  IN3 w0.102: v3(65.13,92.66) 64.8,92.33 64.8,91.74 63.46,90.39 63.46,89.55 62.8,88.89 60.91,88.89 v3(60.41,89.39)
  BOTTOM w0.102: v3(60.41,89.39) 59.91,88.9 UV1.L10
DRAM_RST#: length 90.4
  TOP w0.102: v3(27.18,75.16) 27.64,75.62 27.79,75.62 28.17,76 28.17,76.61 29.29,77.72 UV6.T2 ; RV36.1 v3(65.13,97.59) ; UV7.T2 29.5,97.53 v1(29.09,97.13) 28.89,96.93 28.68,96.93 28.17,96.42 28.17,95.81 27.79,95.43 27.64,95.43 v3(27.18,94.97)
  IN3 w0.135: v3(27.18,75.16) 27.18,75.19 22.31,80.07 22.31,87.63 24.87,90.2 24.87,91.67 26.14,92.94 26.14,93.93 v3(27.18,94.97) 26.9,95.25 26.9,97.18 29.37,99.65 33.86,99.65 34.09,99.88 36.56,99.88 39.27,102.59 57.08,102.59 59.87,99.8 59.87,98.48 60.5,97.85 60.53,97.85 60.79,97.59 v3(65.13,97.59)
  BOTTOM w0.102: v3(27.18,75.16) 27.21,75.14 27.21,74.68 28.97,72.92 UV5.T2 ; UV8.T2 28.97,92.73 27.21,94.49 27.21,94.95 v3(27.18,94.97)
EC_CRY2: length 7.9
  BOTTOM w0.102: RE43.2 RE45.1 127.87,21.01 126.22,21.01 CE17.2 125.46,20.5 v1(124.44,19.49) 124.44,19.36 123.67,18.59 UE1.123
EC_ENVDD: length 152.7
  TOP w0.102: v3(9.12,84.13) 9.23,84.23 9.23,85.12 RX8.2 ; v1(110.8,27.96) v3(110.8,28.53)
  IN1 w0.114: v3(110.8,28.53) 110.55,28.78 109.91,28.78 109.53,29.16 99.77,29.16 98.41,30.52 98.41,32.38 95.95,34.83 87.72,34.83 85.44,37.11 76.65,37.11 75.03,35.49 69.69,35.49 68.69,34.5 64.06,34.5 63.28,33.71 57.88,33.71 57.57,33.41 56.39,33.41 56.29,33.51 54.41,33.51 54.16,33.25 51.89,33.25 49.9,35.24 49.9,40.84 46.31,44.43 46.31,50.05 43.88,52.48 32.31,52.48 31.08,53.71 18.53,53.71 11.64,60.6 11.64,69.24 9.99,70.89 9.99,71.88 9.54,72.34 9.54,80.54 9.12,80.95 v3(9.12,84.13)
  BOTTOM w0.102: v3(110.8,28.53) 111.23,28.96 111.23,29.72 111.19,29.76 UE1.71
EC_LID_OUT#: length 35.7
  TOP w0.102: RH73.2 143.89,20.76 v3(145.19,19.46)
  IN3 w0.135: v3(145.19,19.46) 143.9,19.46 142.29,21.07 141.85,21.07 141.41,21.52 140.6,21.52 139.71,22.41 139.71,23.45 138.84,24.31 135.4,24.31 133.81,25.9 129.11,25.9 124.77,30.23 124.77,30.51 v3(124.62,30.66)
  BOTTOM w0.102: UE1.101 123.86,27.39 124.49,28.02 124.49,28.77 v1(124.63,28.91) 124.63,29.38 124.42,29.59 124.42,30.46 v3(124.62,30.66) 124.87,30.92 CE27.1 ; U2.R2 146.53,18.73 145.92,18.73 v3(145.19,19.46)
EC_MUTE#: length 131.9
  IN2 w0.127: v3(198.1,10.7) 197.59,11.21 196.73,11.21 196.07,11.87 192.61,11.87 187.51,6.76 178.24,6.76 176.71,5.24 169.65,5.24 167.85,3.43 167.85,2.87 166.35,1.38 158.22,1.38 157.21,2.39 153.67,2.39 153.27,1.99 147.96,1.99 147.56,2.39 136.15,2.39 135.46,3.08 134.19,3.08 131.84,5.43 130.78,5.43 126.71,9.49 115.21,9.49 114.72,9 112.52,9 111.16,10.36 111.16,11.94 v3(108.29,14.81)
  BOTTOM w0.102: v3(108.29,14.81) 108.29,16.75 109.64,18.11 109.64,19.99 111.75,22.09 111.75,25.13 115.99,29.38 UE1.83 ; UA1.47 199.95,17.69 200.41,17.23 200.41,16.26 201.94,14.74 201.94,13.11 199.42,10.6 v1(198.71,10.6) 198.2,10.6 v3(198.1,10.7)
EC_ON: length 60.1
  TOP w0.102: v4(75.52,12.45) 75.04,11.97 v3(74.42,11.97)
  TOP w0.254: PR102.1 74.61,11.79 v3(74.42,11.97)
  IN1 w0.114: v3(74.42,11.97) 77.12,9.28 80.22,9.28 80.75,9.81 85.96,9.81 86.14,9.63 86.9,9.63 89.08,11.82 100.29,11.82 102.65,14.18 108.6,14.18 110.24,15.81 110.24,16.3 114.57,20.63 116.25,20.63 117.49,21.87 123.09,21.87 v3(124.06,22.84)
  BOTTOM w0.102: UE1.112 123.91,22.99 v3(124.06,22.84)
EC_PME#: length 3.8
  BOTTOM w0.102: RE61.2 RE21.2 109.59,13.15 v1(109.59,13.47) 109.59,13.64 109.99,14.04 UE1.29
EC_PWM2: length 7.7
  TOP w0.102: RH119.2 RH131.1 160.66,8.52 160.66,9.85 160.9,10.09 160.9,10.47 161.12,10.69 v1(161.12,10.88) 161.12,12.58 161.44,12.9 v3(161.44,13.1)
  BOTTOM w0.102: v3(161.44,13.1) 161.88,13.1 U2.J22
EC_RSMRST#: length 38.5
  IN3 w0.135: v3(143.24,21.07) 142.95,21.07 142.45,21.57 141.76,21.57 141.53,21.8 140.75,21.8 139.99,22.56 139.99,23.6 138.39,25.2 134.89,25.2 133.92,26.17 129.22,26.17 127.18,28.2 127.18,30.31 v3(127.54,30.66)
  BOTTOM w0.102: UE1.100 123.79,27.79 124.29,28.29 124.29,29.43 124.21,29.51 124.21,31.14 124.87,31.81 CE26.1 RE47.1 125.25,33.02 125.53,33.3 126.7,33.3 127.23,32.77 v1(127.23,32.33) 127.23,30.97 v3(127.54,30.66) ; RH90.2 v3(143.24,21.07) 143.33,20.98 145.48,20.98 145.87,20.59 146.34,20.59 146.75,20.18 U2.U2
EC_RST#: length 4.4
  BOTTOM w0.102: RE8.1 CE11.1 104.68,18.5 v1(104.88,18.5) 105.85,18.5 106.16,18.19 UE1.37
EC_RX: length 103.5
  TOP w0.102: v3(181.8,64.14) 181.8,63.6 v1(182.19,63.21)
  IN2 w0.127: v3(181.8,64.14) 181.79,64.14 181.79,63.5 180.4,62.11 180.4,60.84 173.18,53.62 173.18,53.24 169.2,49.25 169.2,46.61 160.41,37.82 158.81,37.82 157.99,37.01 157.99,36.41 154.58,33 141.96,33 140.59,31.63 129.47,31.63 127.82,29.98 123.35,29.98 122.18,28.81 120.47,28.81 v3(119.25,27.59)
  BOTTOM w0.102: UE1.31 109.19,15.82 109.96,16.59 109.96,20.02 111.95,22.01 111.95,24.95 112.46,25.46 113.77,25.46 114.06,25.16 117.33,25.16 119.25,27.08 v3(119.25,27.59) ; JNGFF.32 182.23,64.57 181.79,64.14 v3(181.8,64.14)
EC_SCI#: length 56.2
  TOP w0.102: v3(151.04,17.67) 150.41,18.3 149.54,18.3 149.17,17.94 148.06,17.94 147.77,17.64 147.77,16.84 146.87,15.94 v1(146.34,15.94) 145.91,15.52 144.86,15.52 144.48,15.9 143.8,15.9 142.88,14.99 CH92.1 143,14.8 CH91.1
  IN2 w0.127: v3(114.2,13.47) 115.58,14.84 125.97,14.84 127.07,15.94 133.32,15.94 135.95,13.31 139.38,13.31 139.86,13.8 140.24,13.8 140.42,13.97 141.03,13.97 142.32,15.27 147.66,15.27 149.23,16.84 150.22,16.84 v3(151.04,17.67)
  BOTTOM w0.102: v3(151.04,17.67) 151.04,17.64 151.04,17.64 151.04,17.97 151.3,18.22 U2.R9 ; UE1.20 113.59,14.08 v3(114.2,13.47) 113.72,12.98 RE32.2
EC_SMB_CK1: length 122.8
  TOP w0.254: v3(44.43,8.39) 44.46,8.41 44.46,9.09 44.1,9.45 v1(39.35,9.45) 32.82,9.45 22.23,20.04 22.23,21.54 22.02,21.75 21.7,21.75 PR18.2
  IN1 w0.114: v3(44.43,8.39) 44.51,8.31 44.51,7.9 45.1,7.31 47.45,7.31 54.35,14.21 54.35,25.89 55.82,27.36 66.05,27.36 70.33,31.64 74.94,31.64 76.48,30.1 80.91,30.1 v3(82.48,31.68)
  BOTTOM w0.102: v3(82.48,31.68) 82.86,32.06 88.32,32.06 89.54,33.28 95.32,33.28 97.99,35.95 106.5,35.95 106.7,36.15 113.07,36.15 114.28,34.94 114.28,34.77 114.18,34.67 114.08,34.67 113.98,34.57 RE26.1
  BOTTOM w0.254: v3(44.43,8.39) 44.53,8.49 44.53,8.73 PR717.1
EC_SMB_CK1_R: length 5.4
  TOP w0.102: RPE1.8 v1(113.23,32.41) 113.45,32.64 v3(113.9,32.64)
  BOTTOM w0.102: RE26.2 113.98,32.72 v3(113.9,32.64) 113.47,32.21 113.47,31.68 113.59,31.55 UE1.77
EC_SMB_CK2: length 235.2
  TOP w0.102: U2407.10 128.6,35.22 128.45,35.36 128.45,36.38 127.89,36.94 127.38,36.94 v3(127.31,37.01) ; v3(70.69,99.39) 70.8,99.29 78.09,99.29 79.55,97.83 79.55,95.62 82,93.17 82,91.85 82.12,91.72 82.12,79.69 87.16,74.65 92.97,74.65 v3(93,74.68) ; Q10.1 176.51,84.23 176.41,84.13 176.41,81.99 182.68,75.71 182.68,69.79 179.1,66.21 179.1,60.44 173.12,54.46 168.42,54.46 165.44,57.44 165.11,57.77 165.01,57.87 164.59,57.87 v3(164.45,57.72)
  IN1 w0.114: v3(127.31,37.01) 127.15,36.85 126.84,36.85 126,37.69 124.91,37.69 123.55,39.04 95.18,39.04 91.92,42.31 91.92,66.01 92.93,67.02 92.93,74.62 v3(93,74.68)
  IN3 w0.135: v3(127.31,37.01) 127.44,36.89 132.79,36.89 133.35,37.45 142.75,37.45 144.73,39.43 152.54,39.43 153.07,38.9 160.1,38.9 163.83,42.63 163.83,56.47 164.57,57.21 164.57,57.6 v3(164.45,57.72)
  BOTTOM w0.102: v3(70.69,99.39) 70.16,99.93 70.16,101.02 69.92,101.26 QV1.6 ; RE28.1 116.31,34.47 116.31,35.41 116.85,35.95 121.09,35.95 122.03,36.89 123.12,36.89 124.26,38.03 125.91,38.03 126.93,37.01 v3(127.31,37.01)
EC_SMB_CK2_R: length 5.8
  TOP w0.102: v3(115.2,32.52) 114.99,32.31 114.81,32.31 114.27,31.77 114.27,31.31 114.23,31.26 RPE1.6
  BOTTOM w0.102: RE28.2 116.01,33.15 115.65,32.8 115.47,32.8 v3(115.2,32.52) 115.04,32.52 114.43,31.91 114.43,31.54 114.39,31.5 UE1.79
EC_SMB_DA1: length 123.8
  TOP w0.254: PR20.2 21.7,22.31 22.26,22.31 22.79,21.77 22.79,20.28 33.05,10.01 v1(41.73,10.01) 44.33,10.01 45.01,9.33 45.01,8.4 v3(45.02,8.39)
  IN1 w0.114: v3(45.02,8.39) 44.93,8.3 44.93,8.08 45.28,7.73 47.28,7.73 53.93,14.38 53.93,26.06 55.64,27.78 65.88,27.78 70.16,32.06 75.11,32.06 76.65,30.52 80.73,30.52 82.01,31.8 82.01,32.04 v3(82.05,32.08)
  BOTTOM w0.102: v3(82.05,32.08) 82.4,32.44 88.13,32.44 89.37,33.68 95.15,33.68 97.82,36.35 106.33,36.35 106.53,36.55 113.24,36.55 114.69,35.11 114.69,34.77 114.79,34.67 114.89,34.67 114.99,34.57 RE27.1
  BOTTOM w0.254: PR719.1 44.91,8.79 44.91,8.5 v3(45.02,8.39)
EC_SMB_DA1_R: length 4.5
  TOP w0.102: RPE1.7 113.73,31.83 v3(113.9,32.01)
  BOTTOM w0.102: UE1.78 113.99,31.92 v3(113.9,32.01) 114.27,32.38 v1(114.34,32.38) 114.34,32.45 114.99,33.1 RE27.2
EC_SMB_DA2: length 241.5
  TOP w0.102: v3(92.51,75.09) 92.49,75.06 87.33,75.06 82.53,79.86 82.53,91.89 82.4,92.02 82.4,93.34 79.95,95.79 79.95,98 78.25,99.7 71.08,99.7 70.95,99.83 68.54,99.83 v1(67.2,101.17) v3(65.97,102.39) ; v3(127.34,36.43) 127.44,36.53 127.72,36.53 128.05,36.21 128.05,35.19 128.52,34.72 U2407.9 ; Q9.1 175.9,84.23 176,84.13 176,81.82 182.28,75.54 182.28,69.96 178.7,66.37 178.7,60.61 172.95,54.87 168.59,54.87 165.73,57.73 165.4,58.06 165.18,58.27 164.5,58.27 v3(164.45,58.32)
  IN1 w0.114: v3(127.34,36.43) 126.67,36.43 125.83,37.27 124.74,37.27 123.38,38.63 95.01,38.63 91.5,42.13 91.5,66.18 92.51,67.2 v3(92.51,75.09)
  IN3 w0.135: v3(164.45,58.32) 165,57.76 165,57.03 164.27,56.29 164.27,42.45 160.28,38.46 152.89,38.46 152.36,38.99 144.91,38.99 142.93,37.01 133.53,37.01 132.97,36.45 127.35,36.45 v3(127.34,36.43)
  BOTTOM w0.102: v3(65.97,102.39) 66.14,102.56 QV1.3 ; v3(127.34,36.43) 127.16,36.61 126.76,36.61 125.75,37.62 124.43,37.62 123.29,36.48 122.2,36.48 121.26,35.54 117.01,35.54 116.72,35.24 116.72,34.35 RE29.1
EC_SMB_DA2_R: length 5.5
  TOP w0.102: RPE1.5 114.73,31.26 114.68,31.31 114.68,31.7 114.89,31.91 v3(115.2,31.91)
  BOTTOM w0.102: UE1.80 114.79,31.71 114.99,31.91 v3(115.2,31.91) 115.49,32.2 v1(115.98,32.2) 116.9,33.11 RE29.2
EC_SMI#: length 69.1
  IN2 w0.127: v3(122.69,10.82) 123.21,11.35 126.98,11.35 127.4,10.93 130.61,10.93 131.29,10.25 131.29,8.04 134.78,4.54 136.3,4.54 136.85,3.99 160.61,3.99 162.34,2.26 163.22,2.26 164.3,3.34 165.91,3.34 167.34,4.78 167.34,5.8 v3(167.29,5.85)
  BOTTOM w0.102: UE1.15 115.59,14.17 114.94,13.52 114.94,12.78 RE16.2 114.79,12.58 115.2,12.17 115.2,11.36 115.47,11.08 116.49,11.08 117.63,9.94 120.85,9.94 121.44,10.53 v1(121.84,10.53) 122.4,10.53 v3(122.69,10.82) ; v3(167.29,5.85) 167.29,6.58 165.82,8.06 165.82,8.5 165.1,9.22 U2.C26
EC_SPI_CLK: length 22.8
  TOP w0.102: v3(124.47,17.3) 124.49,17.3 124.9,16.9 125.28,16.9 125.53,17.15 125.53,17.37 128.18,20.01 128.18,22.67 129.19,23.68 135.57,23.68 135.87,23.98 v1(136.4,23.98) 138.58,23.98 139.22,23.34 v3(139.22,23.32)
  BOTTOM w0.102: v3(124.47,17.3) 124.38,17.39 UE1.126 ; RH70.1 139.43,22.18 139.43,23.12 v3(139.22,23.32)
EC_SPI_CS1#: length 19.6
  TOP w0.102: v3(135.01,21.82) v1(134.39,22.44) 133.56,23.27 129.36,23.27 128.59,22.5 128.59,19.85 125.94,17.2 125.94,16.95 125.2,16.21 124.05,16.21 v3(123.88,16.04)
  BOTTOM w0.102: v3(135.01,21.82) 135.57,21.26 RH65.1 ; v3(123.88,16.04) 123.37,16.04 122.82,16.59 UE1.128
EC_SPI_MISO: length 83.4
  TOP w0.102: RH67.1 184.51,21.72 182.02,24.21 178.7,24.21 177.76,25.16 177.76,26.89 175.65,29 175.65,30.81 172.52,33.94 164.19,33.94 163.86,33.61 158.89,33.61 158.46,33.18 158.02,33.18 157.74,33.46 157.74,34.35 158.3,34.9 v3(158.63,34.9)
  IN3 w0.135: v3(158.63,34.9) 158.58,34.95 155.11,34.95 153.38,33.23 136.72,33.23 134.84,31.35 132.77,31.35 131.43,30 v3(131.43,29.86)
  BOTTOM w0.102: UE1.119 123.81,20.19 124.45,20.83 124.64,20.83 125.65,21.85 127.65,21.85 127.98,22.18 130.57,22.18 131.48,23.08 131.48,25.1 130.36,26.22 130.36,28.68 131.43,29.75 v3(131.43,29.86)
EC_SPI_MOSI: length 71.7
  TOP w0.102: v3(158.65,34.07) 158.71,34.01 163.68,34.01 164.01,34.35 172.73,34.35 176.05,31.02 176.05,29.17 178.68,26.55 RH69.1
  IN3 w0.135: v3(137.39,32.69) 137.47,32.77 153.55,32.77 155.02,34.24 158.48,34.24 v3(158.65,34.07)
  BOTTOM w0.102: v3(137.39,32.69) 135.62,30.92 133.17,30.92 130.77,28.51 130.77,26.39 131.88,25.27 131.88,22.92 130.74,21.77 128.15,21.77 127.82,21.44 125.82,21.44 124.81,20.43 124.62,20.43 123.98,19.79 UE1.120
EC_TX: length 104.1
  TOP w0.102: v1(180.12,63.8) 180.53,64.21 v3(181.16,64.21) 181.25,64.21 RM11.1
  IN2 w0.127: v3(120.63,29.34) 122.23,29.34 123.12,30.23 127.72,30.23 129.37,31.88 140.49,31.88 141.86,33.25 154.48,33.25 157.74,36.52 157.74,37.12 158.73,38.1 160.33,38.1 168.94,46.72 168.94,49.36 172.88,53.3 172.88,53.95 179.94,61.02 179.94,62.29 181.16,63.5 v3(181.16,64.21)
  BOTTOM w0.102: JNGFF.30 181.73,64.77 v3(181.16,64.21) ; v3(120.63,29.34) 120.63,28.17 117.37,24.91 113.77,24.91 113.48,25.2 112.49,25.2 112.16,24.86 112.16,21.9 110.19,19.94 110.19,16.4 109.59,15.8 UE1.30
ECAGND: length 117.5
  TOP w0.508: v3(141.87,34.53) 144.15,36.82 144.15,46.41 125.19,65.37 v1(125.19,80.23) 125.19,81.7 124.03,82.85 124.03,90.23 124.8,90.99 127.41,90.99 127.83,91.41 PH1.2
  IN2 w0.508: v3(104.07,30.66) 104.07,31.04 104.96,31.93 106.05,31.93 107.32,33.2 109.76,33.2 v3(110.52,32.44)
  IN3 w0.508: v3(110.52,32.44) 110.52,32.14 111.41,31.25 121.11,31.25 121.49,31.63 125.05,31.63 125.89,32.47 129.24,32.47 129.67,32.03 132.1,32.03 134.6,34.53 v3(141.87,34.53)
  BOTTOM w0.203: UE1.69 110.39,31.66 109.95,32.1 109.62,32.1 109.35,32.36 CE7.2
  BOTTOM w0.508: v3(110.52,32.44) 110.27,32.69 CE7.2 109.35,33.67 LE2.2 ; CE9.1 v3(104.07,30.66)
ECPWM1: length 1.6
  BOTTOM w0.102: T103.1 111.19,13.7 UE1.26
EDP0_AUXN_C: length 186.4
  TOP w0.102: R617.2 5.94,101.92 5.66,101.92 v3(5.47,101.73)
  IN3 w0.135: v3(5.47,101.73) 5.67,101.93 6.53,101.93 8.18,103.59 21.62,103.59 23.84,105.81 30.08,105.81 32.02,107.75 43.47,107.75 46.21,110.49 57.14,110.49 61.3,106.34 62.63,106.34 66.81,102.16 71.2,102.16 73.13,100.23 95.15,100.23 95.28,100.36 96.42,100.36 98.2,102.14 102.18,102.14 105.11,105.07 105.11,108.97 113.67,117.53 114.42,117.53 115.03,118.14 115.45,118.14 v3(115.65,117.94)
  BOTTOM w0.102: C4322.1 154.26,110.93 154.36,110.82 154.36,110.34 154.45,110.25 154.63,110.25 155.49,111.12 155.49,115.59 152.85,118.23 144.93,118.23 144.72,118.43 128.24,118.43 127.95,118.14 115.8,118.14 115.65,117.99 v3(115.65,117.94) ; JEDP.8 2.55,95.5 2.7,95.64 3.54,95.64 4.78,96.88 4.78,101.6 5.1,101.92 5.34,101.92 5.47,101.79 v3(5.47,101.73)
EDP0_AUXP_C: length 186.4
  TOP w0.102: R616.1 5.92,102.14 5.64,102.14 v3(5.47,102.32)
  IN3 w0.135: v3(115.65,118.52) 115.52,118.38 114.93,118.38 114.32,117.77 113.57,117.77 104.87,109.07 104.87,105.17 102.08,102.38 98.1,102.38 96.32,100.6 95.18,100.6 95.05,100.48 73.23,100.48 71.3,102.41 66.91,102.41 62.73,106.58 61.4,106.58 57.24,110.74 46.11,110.74 43.36,107.99 31.92,107.99 29.98,106.05 23.74,106.05 21.52,103.83 8.08,103.83 6.43,102.18 5.6,102.18 v3(5.47,102.32)
  BOTTOM w0.102: v3(115.65,118.52) 115.82,118.36 127.86,118.36 128.15,118.65 144.81,118.65 145.01,118.44 152.94,118.44 155.71,115.68 155.71,111.03 154.72,110.04 C4321.1 ; JEDP.7 2.55,96 2.7,95.86 3.46,95.86 4.57,96.97 4.57,101.69 5.01,102.14 5.29,102.14 v3(5.47,102.32)
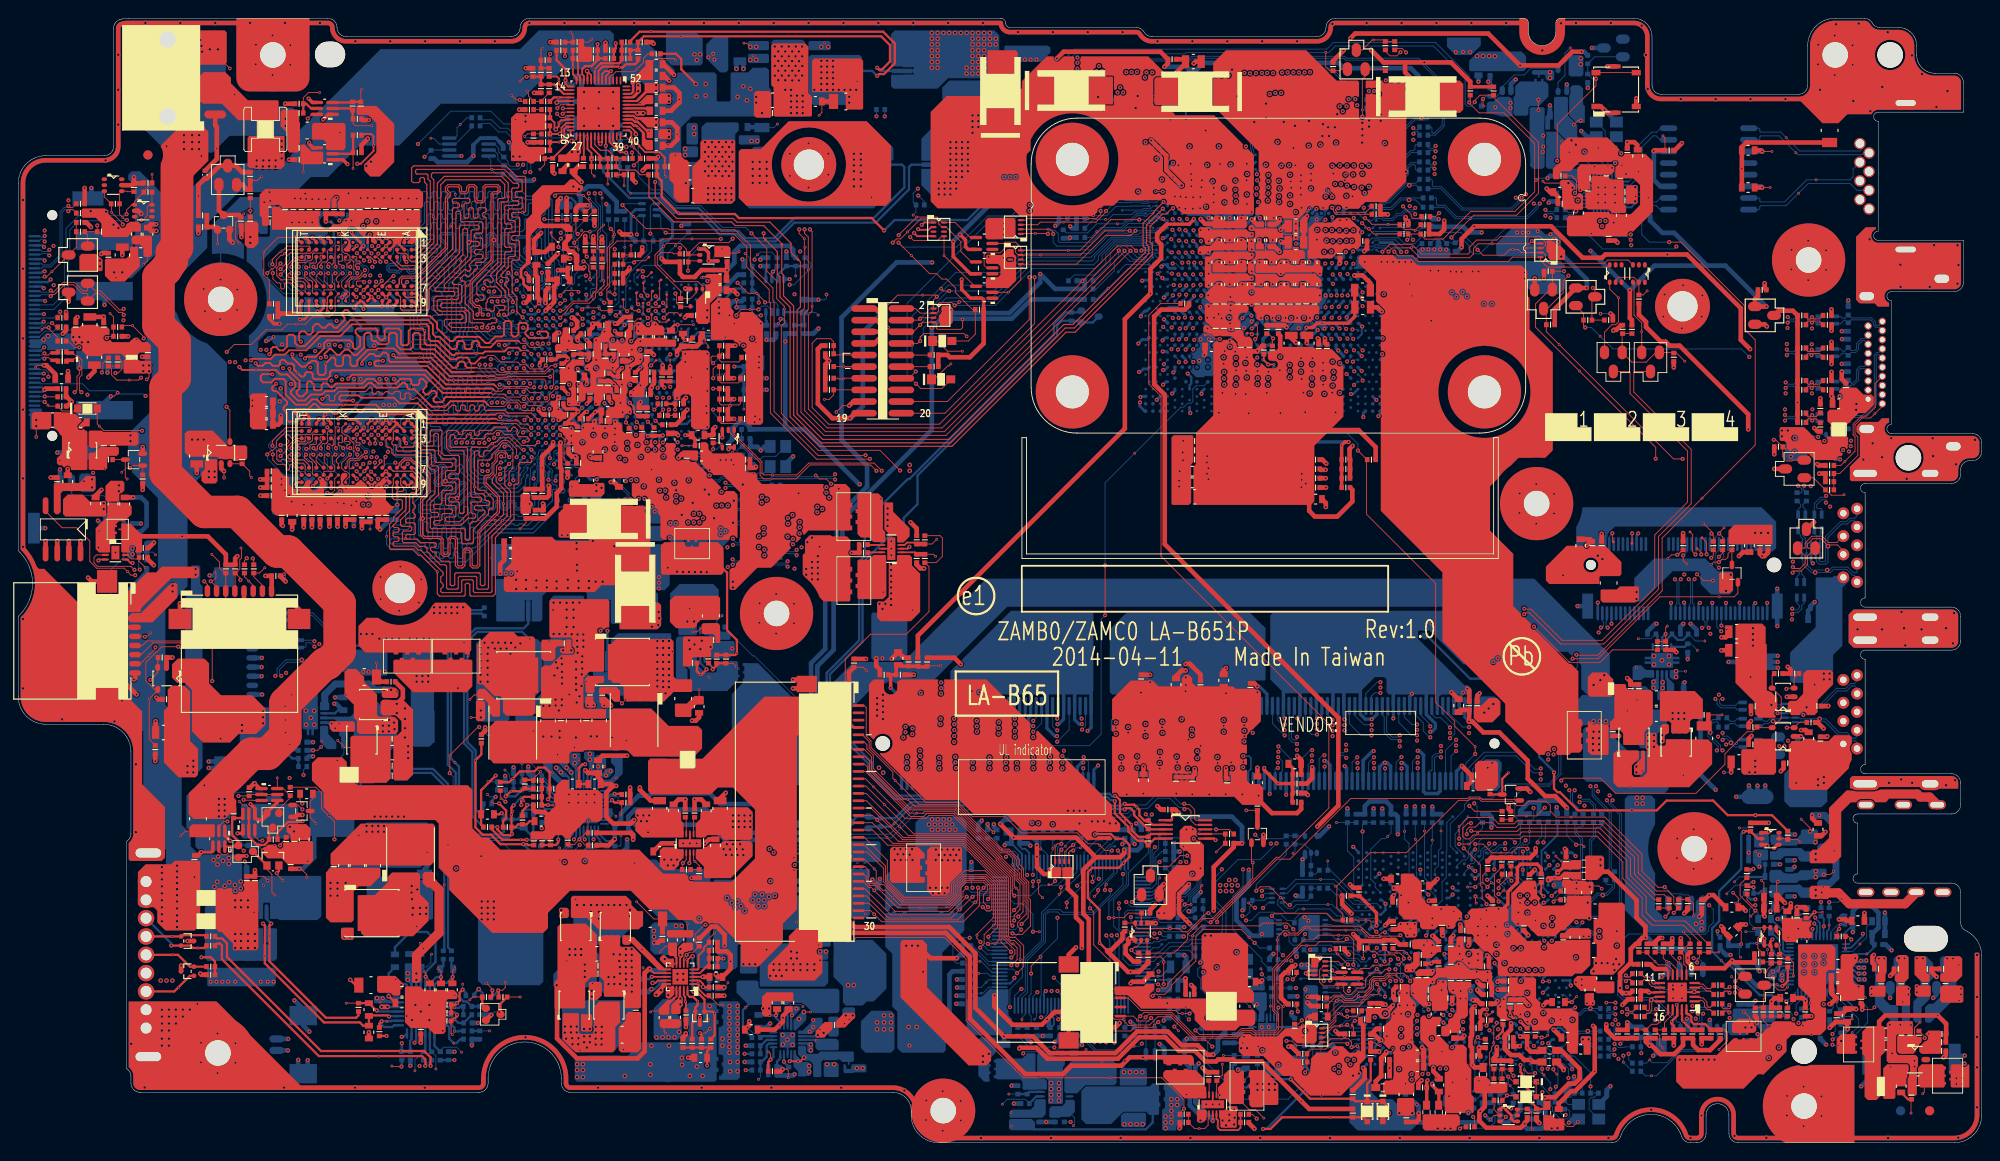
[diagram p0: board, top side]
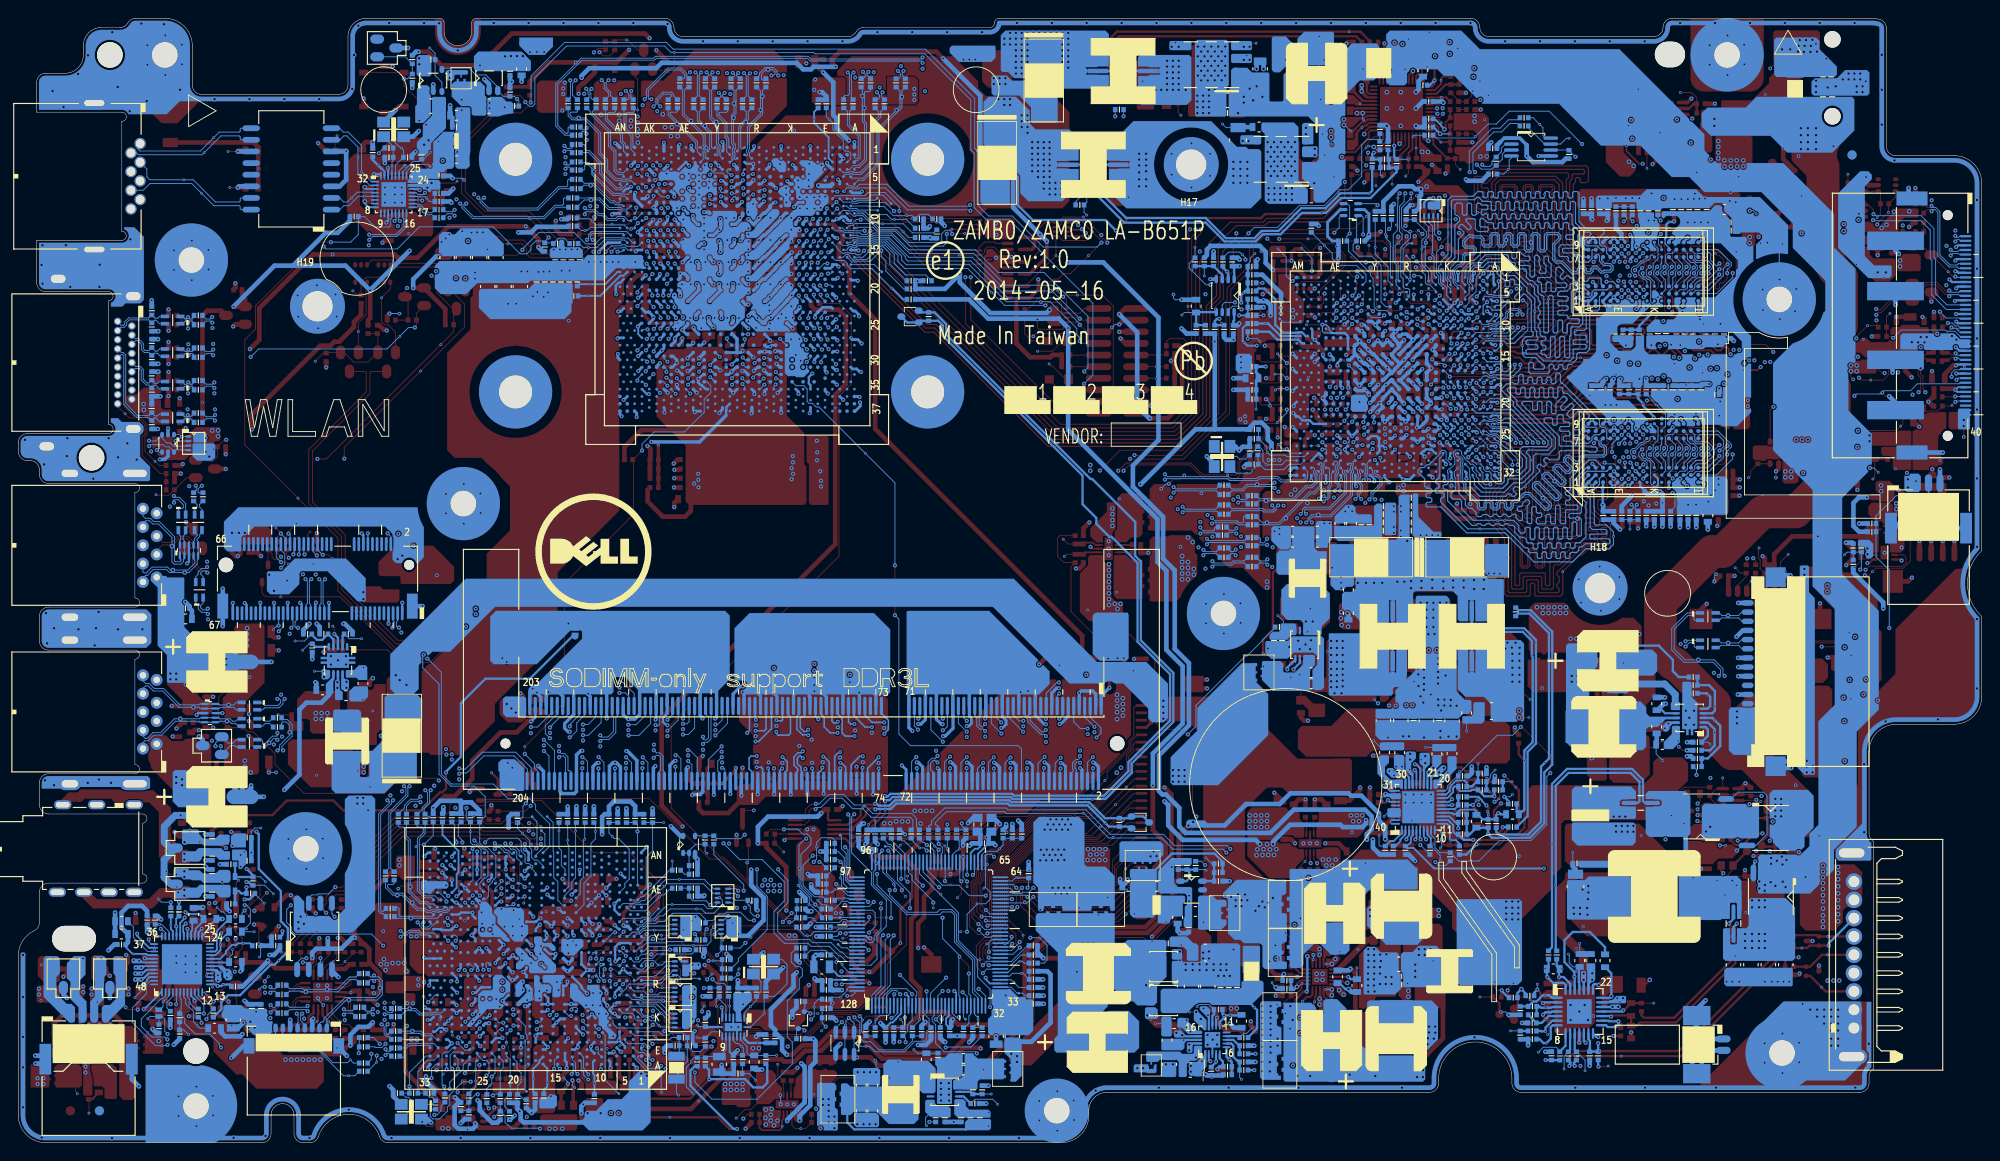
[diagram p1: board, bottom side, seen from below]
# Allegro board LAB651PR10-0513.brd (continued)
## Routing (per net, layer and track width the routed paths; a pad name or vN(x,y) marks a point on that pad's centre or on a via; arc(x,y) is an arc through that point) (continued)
EDP0_TXN0_C: length 176.1
  IN3 w0.135: v3(153.55,116.03) 153.75,116.23 153.75,116.54 152.24,118.05 144.61,118.05 143.48,119.18 118.59,119.18 115.78,116.37 114.72,116.37 106.32,107.97 106.32,105.08 102.59,101.35 98.58,101.35 96.81,99.57 95.61,99.57 94.68,98.64 79.46,98.64 78.94,99.17 72.19,99.17 69.98,101.38 66.01,101.38 65.08,102.3 65.08,102.77 62.34,105.51 59.98,105.51 55.78,109.71 53.37,109.71 49.46,105.8 31.34,105.8 30.49,104.94 24.19,104.94 22.01,102.77 9.96,102.77 5.82,98.63 3,98.63 2.88,98.51 v3(2.88,98.43)
  BOTTOM w0.102: C4311.2 153.4,113.92 153.89,114.42 153.89,115.69 v3(153.55,116.03) ; v3(2.88,98.43) 2.66,98.64 2.47,98.64 2.33,98.5 JEDP.2
EDP0_TXN1_C: length 173.4
  IN3 w0.135: v3(3.38,96.91) 3.56,97.08 6.52,97.08 11.38,101.94 22.32,101.94 24.42,104.04 30.74,104.04 31.68,104.98 50.02,104.98 53.31,108.27 54.94,108.27 59.37,103.84 60.01,103.84 60.93,102.93 62.67,102.93 65.56,100.03 69.07,100.03 70.95,98.15 72.98,98.15 73.29,97.85 94.48,97.85 94.72,97.6 98.25,97.6 101.2,100.55 102.93,100.55 107.21,104.83 107.21,107.72 115.08,115.58 117.99,115.58 120.77,118.37 143.17,118.37 144.71,116.83 150.86,116.83 152.03,115.66 152.03,115.32 v3(151.8,115.1)
  BOTTOM w0.102: v3(3.38,96.91) 3.17,97.12 2.55,97.12 2.43,97 JEDP.5 ; v3(151.8,115.1) 151.84,115.1 151.97,114.96 151.97,114.67 151.87,114.57 151.87,114.1 151.69,113.92 C4313.2
EDP0_TXP0_C: length 176.1
  IN3 w0.135: v3(154.13,116.03) 154,116.17 154,116.64 152.34,118.29 144.71,118.29 143.58,119.42 118.49,119.42 115.68,116.62 114.62,116.62 106.08,108.07 106.08,105.19 102.48,101.59 98.48,101.59 96.7,99.82 95.51,99.82 94.58,98.89 79.56,98.89 79.04,99.41 72.29,99.41 70.08,101.62 66.11,101.62 65.32,102.4 65.32,102.87 62.44,105.76 60.08,105.76 55.89,109.95 53.27,109.95 49.36,106.04 31.24,106.04 30.39,105.19 24.09,105.19 21.91,103.01 9.86,103.01 5.72,98.88 3.04,98.88 v3(2.88,99.04)
  BOTTOM w0.102: JEDP.1 2.38,99 2.52,98.86 2.7,98.86 v3(2.88,99.04) ; v3(154.13,116.03) 154.11,116.01 154.11,114.18 C4312.2
EDP0_TXP1_C: length 173.4
  IN3 w0.135: v3(3.38,97.51) 3.57,97.33 6.42,97.33 11.28,102.19 22.22,102.19 24.31,104.29 30.64,104.29 31.58,105.23 49.92,105.23 53.2,108.51 55.04,108.51 59.47,104.08 60.11,104.08 61.03,103.17 62.77,103.17 65.66,100.27 69.17,100.27 71.05,98.39 73.08,98.39 73.39,98.09 94.58,98.09 94.82,97.85 98.15,97.85 101.1,100.79 102.83,100.79 106.97,104.93 106.97,107.82 114.98,115.83 117.89,115.83 120.67,118.61 143.27,118.61 144.81,117.07 150.96,117.07 152.27,115.76 152.27,115.22 152.27,115.22 v3(152.39,115.1)
  BOTTOM w0.102: C4314.2 152.09,114.16 152.09,114.48 152.19,114.58 152.19,114.9 v3(152.39,115.1) ; JEDP.4 2.43,97.5 2.6,97.34 3.21,97.34 v3(3.38,97.51)
EDP_HPD: length 8.7
  TOP w0.102: R365.1 R407.2 6.33,97.79 Q20.1 v1(3.66,95.13) 3.04,94.5 2.97,94.5 v3(2.88,94.59)
  BOTTOM w0.102: JEDP.10 2.78,94.5 v3(2.88,94.59)
EN_0.675VSP: length 4.9
  BOTTOM w0.102: PR202.2 81.03,7.13 v1(80.83,6.93)
  BOTTOM w0.254: PR202.2 PC203.1 81.16,8.95 81.29,8.95 81.72,9.38 81.72,10.6 81.95,10.83 PU200.7
EN_1.35V: length 2.6
  BOTTOM w0.254: PU200.8 81.72,11.23 81.08,10.6 PC202.1 PR201.2
EN_+1.05VSP: length 4.2
  TOP w0.102: PR303.2 PC306.1 v3(179.89,55.55) 179.89,56.25 v1(180.05,56.42)
  BOTTOM w0.254: PU300.3 179.49,55.16 v3(179.89,55.55)
EN_+1.35VGPUP: length 7.9
  BOTTOM w0.254: PR1103.2 PC1104.1 29.9,41.97 28.56,43.31 28.56,45.55 v1(29.18,46.17) 29.4,46.39 PU1100.3
EN_DFAN1: length 139.4
  TOP w0.102: v3(12.76,61.98) 12.31,61.98 v1(11.93,62.37) 11.55,62.74 8.56,62.74 7.8,63.5 7.8,65.71 6.36,67.16 4.78,67.16 2.98,68.97 UE3.4
  IN1 w0.114: v3(110.79,29.26) 110.22,29.82 99.75,29.82 98.86,30.71 98.86,32.57 96.14,35.29 87.91,35.29 85.63,37.57 76.46,37.57 74.84,35.95 71.81,35.95 71.18,36.58 66.75,36.58 65.63,35.46 64.38,35.46 63.09,34.17 57.69,34.17 57.41,33.89 56.88,33.89 56.38,34.4 53.54,34.4 52.96,33.81 52.03,33.81 50.56,35.29 50.56,41.51 47.2,44.86 47.2,50.18 44.06,53.32 32.39,53.32 31.41,54.3 20.44,54.3 v3(12.76,61.98)
  BOTTOM w0.102: UE1.70 v3(110.79,29.26)
EN_INVPWR: length 141.2
  TOP w0.102: v3(12.2,73.69) 12.46,73.95 QV7.2 RX4.1
  IN1 w0.114: v3(12.2,73.69) 11.87,73.36 11.87,60.7 18.55,54.02 31.18,54.02 32.47,52.73 43.95,52.73 46.54,50.15 46.54,44.53 50.13,40.93 50.13,35.33 51.88,33.58 53.05,33.58 53.64,34.17 56.24,34.17 56.78,33.63 57.48,33.63 57.78,33.94 63.18,33.94 64.48,35.23 65.72,35.23 66.84,36.35 71.09,36.35 71.72,35.72 74.93,35.72 76.55,37.34 85.54,37.34 87.82,35.06 96.04,35.06 98.63,32.47 98.63,30.62 99.66,29.6 109.81,29.6 v3(110.17,29.24)
  BOTTOM w0.102: UE1.68 109.99,29.41 v3(110.17,29.24) ; v3(12.2,73.69) 11.77,73.69 v1(11.3,73.22)
EN_PCIE: length 1.5
  BOTTOM w0.102: v1(76.85,57.56) 76.23,56.94 PR1300.2
ENABLE: length 4
  BOTTOM w0.102: PR1027.2 60.15,32.39 59.14,31.38 v1(59.14,30.87)
  BOTTOM w0.203: PU1000.8 60.52,33.63 60.16,33.27 60.16,32.49 PR1027.2
ENBKL: length 115.5
  TOP w0.102: v3(95.48,98.3) 95.89,98.71 96.35,98.71 v1(97.1,99.46) 98.53,100.89 100.23,100.89 100.51,100.61 100.51,100.33 100.85,100 RP16.7 101.33,100 102.93,98.4 102.93,97.34 104.07,96.19 U64.4
  IN2 w0.127: v3(123.78,35.84) 123.37,35.44 120.76,35.44 118.87,37.33 116.86,37.33 115.65,38.54 97.8,38.54 96.22,40.11 96.22,44.81 96.32,44.91 96.32,53.34 93.35,56.32 93.35,70.15 95.26,72.06 95.26,73.89 89.36,79.78 89.36,92.34 95.32,98.3 v3(95.48,98.3)
  BOTTOM w0.102: v3(123.78,35.84) 123.6,35.67 123.6,29.09 123.5,28.99 UE1.97
ENVDD_R: length 24.9
  TOP w0.102: 9.89,84.81 RX7.1 ; 9.89,84.81 10.17,84.54 10.17,83.88 10.75,83.29 v1(12.11,83.29) 13.14,83.29 v3(13.39,83.54) ; 9.89,84.81 RX8.1 ; UX4.4 23.1,80 v3(22.74,80.37)
  IN1 w0.114: v3(13.39,83.54) 12.73,84.21 12.73,85.68 13.37,86.31 17.13,86.31 22.74,80.7 v3(22.74,80.37)
F_192-: length 4.3
  TOP w0.102: v1(165.35,1.44) 165.26,1.53 165.26,3.31 164.88,3.69 RH81.2 163.76,3.69 QH2.6 QH2.5
FAN_SPEED1: length 149.9
  TOP w0.102: v4(111.63,20.31) 110.6,19.28 v3(110.6,18.47)
  IN1 w0.114: v3(110.6,18.47) 109.68,17.56 107.84,17.56 98.11,27.28 97.41,27.28 92.33,32.36 84.55,32.36 83.16,33.75 76.36,33.75 76,34.11 70.26,34.11 67.33,31.18 59.38,31.18 59.23,31.03 52.63,31.03 52.26,31.03 52.07,31.03 47.08,36.02 47.08,37.94 46.41,38.61 27.69,38.61 v3(10.09,56.21)
  BOTTOM w0.102: v3(10.09,56.21) 10.09,62.54 11.54,63.99 RE50.2 CE24.1 11.54,68.46 9.33,70.67 6.06,70.67 5.8,70.92 JFAN.2 ; v3(110.6,18.47) 110.6,16.23 110.39,16.03 UE1.28 110.39,14.04 110.6,13.83 110.6,13.03 111.05,12.58 CE29.1
FB: length 3.9
  TOP w0.102: v1(62.6,120.53) 62.27,120.2 PR508.2
  TOP w0.203: PU500.12 61.35,116.43 61.12,116.67 61.12,118.06 PC510.1
FB_1.1V:
  vias: v1(108.41,3.29)
FB_1.5V:
  vias: v1(208.59,11.89)
FB_1.8V: length 4.3
  BOTTOM w0.102: PR407.2 84.05,30.47 v1(84.7,31.12)
  BOTTOM w0.254: PU401.6 PR410.1 PC412.2 PR407.2
FB_1.35V: length 5.6
  TOP w0.102: v3(82.15,9.07) 82.15,9.68 v1(81.91,9.92)
  TOP w0.254: v3(82.15,9.07) 81.9,8.82 PC214.1
  BOTTOM w0.254: PR204.1 PR207.1 81.9,8.82 v3(82.15,9.07) 82.45,9.38 PU200.6
FB_3V: length 3.7
  TOP w0.203: PU100.4 74.42,18.51 74.73,18.82
  TOP w0.254: PR107.2 PC102.2 PR109.2 75.13,19.22 74.73,18.82
FB_5V: length 4.7
  TOP w0.203: PU100.2 74.4,17.71 74.78,17.33 v2(74.78,17.02)
  TOP w0.254: PR104.1 74.81,17 v2(74.78,17.02)
  BOTTOM w0.102: v2(74.78,17.02) 74.62,17.02 v1(74.22,17.42)
  BOTTOM w0.254: v2(74.78,17.02) 75.11,16.69 75.42,16.69 PC108.1 PR106.1
FB_+1.05VSP: length 6.1
  BOTTOM w0.102: v1(184.17,54.79) 183.15,54.79 182.39,55.55 PR306.1
  BOTTOM w0.254: PU300.4 179.99,54.97 PR307.1 181.21,54.92 181.79,54.92 182.35,55.48 PR306.1
FB_+1.35VGPUP: length 6.6
  BOTTOM w0.254: PU1100.4 29.42,46.89 29.14,47.17 v1(29.14,47.65) 29.14,49.33 29.77,49.97 PR1108.1 PR1107.1
FB_GND: length 1.6
  TOP w0.102: RV158.1 70.01,79.66 v3(70.41,80.07)
  BOTTOM w0.102: UV1.AD20 70,80.48 v3(70.41,80.07)
FB_PCIE: length 5.5
  TOP w0.102: v1(78.42,52) 78.06,52.35 PC1306.2 ; v3(75.83,51.69) 75.83,51.89 75.58,52.14 PR1301.1
  TOP w0.254: v3(75.83,51.69) 76.26,52.13 PR1302.2 PC1306.2
  BOTTOM w0.254: v3(75.83,51.69) 75.83,51.89 74.95,52.76 PU1300.6
FB_VDDC: length 1.5
  TOP w0.102: RV159.1 69.83,80.45 v3(69.45,80.07)
  BOTTOM w0.102: v3(69.45,80.07) 69.2,80.32 UV1.AC20
FB_VDDCI: length 4.4
  TOP w0.102: v3(67.24,96.14) 67.42,96.32 68.46,96.32 T222.1
  BOTTOM w0.102: v3(67.24,96.14) 66.53,96.14 66,95.61 UV1.W1
FBA: length 7.4
  TOP w0.102: PR557.2 v1(64.37,104.69)
  TOP w0.203: PU500.31 62.55,108.75 63.51,107.8 PC529.1 ; PR550.1 PC529.1 ; PC529.1 PC530.2 PR552.2 PR557.2
FCH_GPIO191: length 6.1
  TOP w0.102: D7.2 163.25,6.66 v3(162.69,7.22)
  BOTTOM w0.102: RH74.1 163.23,5.9 v1(162.91,6.23) 162.69,6.44 v3(162.69,7.22) 162.34,7.57 162.34,9.41 U2.D23
FCH_GPIO192: length 7.1
  TOP w0.102: RH77.2 162.06,4.66 v3(162.57,5.17) 162.58,5.16 163.4,5.16 D6.2
  BOTTOM w0.102: U2.C22 161.46,8.93 161.46,8.18 161.77,7.86 v1(161.77,7.01) RH76.1 161.8,5.3 162.45,5.3 v3(162.57,5.17)
FCH_GPIO192_R: length 3.2
  TOP w0.102: RH77.1 161.14,3.63 QH2.2 161.16,2.98 v1(160.72,2.54)
FCH_PCIE_WAKE#: length 220.2
  TOP w0.102: RL34.2 169.65,105.59 v1(169.87,105.37) 170.16,105.08 170.16,103.91 v3(169.99,103.73) ; v3(145.1,14.4) 145.1,14.41 RH66.2 ; v3(140.16,13.36) 139.76,12.96 RH88.2
  IN2 w0.102: 142.49,14.38 142.52,14.4 v3(145.1,14.4)
  IN2 w0.127: v3(169.99,103.73) 170.13,103.73 171.82,102.04 174.95,102.04 180.28,96.7 183.32,96.7 187.74,92.29 187.74,86.31 193.99,80.06 193.99,77.98 194.7,77.27 194.7,74.53 193.21,73.05 193.21,71.6 195.45,69.36 195.45,41.39 191.19,37.14 188.6,37.14 185.79,34.33 185.79,30.67 185.12,30 185.12,26.61 185.1,26.59 185.1,25.39 184.28,24.58 184.28,20.87 185.13,20.02 185.13,13.96 186.67,12.42 186.67,8.64 186.37,8.34 177.86,8.34 176.79,9.4 176.79,19.74 175.52,21.01 174.43,21.01 174.22,21.21 169.68,21.21 166.61,18.14 161.47,18.14 160.46,17.12 155.17,17.12 153.57,15.52 148.27,15.52 147.15,14.4 v3(145.1,14.4) ; v3(113.14,10.39) 113.29,10.39 117.48,14.58 126.08,14.58 127.18,15.68 133.22,15.68 135.84,13.06 139.86,13.06 v3(140.16,13.36) 140.47,13.06 141.18,13.06 142.49,14.38
  BOTTOM w0.102: v3(169.99,103.73) 170.16,103.56 170.77,103.56 170.97,103.76 UL1.21 ; v3(113.14,10.39) 113.09,10.44 110.37,10.44 RE61.1
FCH_PCIE_WAKE#_R: length 4.4
  TOP w0.102: v1(144.49,14.05) 144.77,13.77 v3(145.12,13.77) 146.08,13.77 146.69,14.38 RH66.1
  BOTTOM w0.102: v3(145.12,13.77) 145.54,13.77 145.69,13.92 146.13,13.92 146.35,14.14 U2.K1
FCH_POK: length 32.5
  IN2 w0.127: v3(135.79,18.39) 135.03,17.63 130.33,17.63 129.4,16.7 127.18,16.7 125.91,17.96 124.26,17.96 123.12,16.82 116.19,16.82 115.3,15.93 110.39,15.93 v3(109.53,16.79)
  BOTTOM w0.102: RH52.1 136.23,17.96 v3(135.79,18.39) 135.79,18.89 v1(135.69,18.99) ; v3(109.53,16.79) 108.79,16.05 UE1.32
FCH_PWRGD: length 18.6
  IN2 w0.102: v3(149.81,17.68) 150.24,18.11 150.25,18.11 150.83,18.7 150.83,19.16 150.6,19.38 147.96,19.38 147.61,19.03 144,19.03 143.64,19.38 141.71,19.38 141.23,19.87 v3(139.02,19.87)
  BOTTOM w0.102: RH52.2 RH51.2 CH23.1 137.67,19.87 v1(138.51,19.87) v3(139.02,19.87) ; U2.N7 149.7,17.57 v3(149.81,17.68)
FCH_RTCX1: length 3.5
  BOTTOM w0.102: v1(140.29,11.5) 140.23,11.43 RH6.1 138.7,12.11 137.7,12.11 137.53,11.94 UG1.9
FCH_SCLK0: length 29.5
  IN3 w0.135: v3(165.6,26.22) 165.6,26.58 166.59,27.57 166.59,32.76 v3(166.55,32.79) 166.55,32.81 166.71,32.96 166.71,33.86 167.55,34.71 167.55,37.54 165.62,39.47 165.62,40.21 165.78,40.36 166.17,40.36 v3(166.25,40.29)
  BOTTOM w0.102: JDIMM1.202 158.85,40.38 158.81,40.42 158.81,40.8 160.25,42.24 163.57,42.24 165.42,40.39 166.15,40.39 v3(166.25,40.29) ; RH79.2 166.76,34.73 166.76,33.29 166.55,33.08 v3(166.55,32.79) ; U2.AD26 v3(165.6,26.22)
FCH_SCLK1: length 8.9
  TOP w0.102: RPH5.8 144.11,19.8 144.91,19 145.82,19 QH31.6 146.62,19.03 147.58,19.03 147.94,19.38 v1(148.84,19.38) 149.41,19.38 149.86,19.84 v3(149.86,19.98)
  BOTTOM w0.102: U2.T7 149.7,19.82 v3(149.86,19.98)
FCH_SCLK1_TP: length 146.6
  TOP w0.102: RPH5.6 143.44,18.8 v3(143.47,18.83) 143.68,18.61 QH31.1 ; RE337.1 24.69,63.58 v3(24.95,63.83)
  IN3 w0.135: v3(143.47,18.83) 142.63,18.83 139.24,22.21 137.91,22.21 136.26,23.86 131.61,23.86 131.4,23.65 129.84,23.65 128.69,24.8 127.49,24.8 125.38,26.91 124.17,26.91 123.91,27.16 111.47,27.16 108.95,29.68 87.89,29.68 86.47,31.1 85.9,31.1 80.37,36.63 70.77,36.63 70.66,36.74 66.88,36.74 66.42,36.28 57.77,36.28 54.59,39.45 54.59,39.88 49.32,45.16 49.32,53.12 45.86,56.58 36.07,56.58 27.63,65.01 25.97,65.01 25.61,65.01 25.1,64.5 25.1,63.99 v3(24.95,63.83)
FCH_SCLK1_TP_R: length 2.4
  TOP w0.102: JTP.6 25.65,60.85 v1(25.16,61.33) 24.69,61.8 RE337.2
FCH_SCLK4: length 219.4
  TOP w0.102: v3(11.41,100.28) 11.41,100.37 v1(10.18,101.6) 10.17,101.62 10.17,102.52 RX38.1 9.39,103.29 QX6.3
  IN3 w0.135: v3(161.59,12.38) 161.46,12.38 161,11.93 161,10.32 160,9.33 155.1,9.33 153.52,10.9 152.3,10.9 151.62,11.59 151.62,12.75 151.36,13 148.85,13 148.65,12.8 147.55,12.8 145.51,14.84 143.83,14.84 143.34,14.35 140.42,14.35 139.76,15.02 138.39,15.02 137.22,16.18 135.08,16.18 134.09,17.17 129.36,17.17 126.18,20.35 123.49,20.35 122.37,21.47 118.56,21.47 117.93,22.09 114.44,22.09 108.25,28.29 97.83,28.29 97.19,27.64 87.79,27.64 86.42,29.01 84.13,29.01 82.48,30.66 82.11,30.66 79.47,33.3 71.2,33.3 70.85,33.66 65.03,33.66 64.16,34.53 58.38,34.53 57.94,34.96 52.54,34.96 51.26,36.25 51.26,41.3 47.96,44.59 47.96,52 46.18,53.78 35.12,53.78 33.48,55.42 30.89,55.42 22.66,63.64 22.66,67.49 17.99,72.17 17.99,92.37 12.32,98.04 12.32,99.38 v3(11.41,100.28)
  BOTTOM w0.102: U2.G22 161.83,12.38 v3(161.59,12.38)
FCH_SCLK4_R: length 23.3
  TOP w0.102: RX39.2 11.92,103.86 11.86,103.93 QX6.4 11.06,103.69 RX38.2 11.06,101.4 v1(11.4,101.05) 11.69,100.77 v3(11.87,100.77)
  BOTTOM w0.102: v3(11.87,100.77) 11.79,100.69 6.63,100.69 5.62,99.68 5.62,96.53 5.44,96.35 5.44,92.57 3.87,91 JEDP.17
FCH_SDATA0: length 31.4
  IN3 w0.135: v3(166.25,40.87) 166.18,40.8 165.6,40.8 165.18,40.39 165.18,39.28 167.11,37.36 167.11,34.89 166.27,34.04 166.27,33.15 v3(165.91,32.79) 166.15,32.56 166.15,27.75 165.16,26.77 165.16,26.58 v3(164.8,26.22)
  BOTTOM w0.102: JDIMM1.200 158.25,40.44 158.4,40.59 158.4,40.97 160.08,42.65 163.73,42.65 165.59,40.8 166.17,40.8 v3(166.25,40.87) ; RH80.2 166.35,34.73 166.35,33.46 165.91,33.02 v3(165.91,32.79) ; U2.AD25 v3(164.8,26.22)
FCH_SDATA1: length 13.1
  TOP w0.102: RPH5.7 142.54,19.3 142.1,18.86 142.1,17.54 142.51,17.12 143.7,17.12 143.88,17.31 QH31.3 144.74,17.06 144.74,16.53 145.1,16.16 145.5,16.16 146.22,16.88 146.91,16.88 147.12,17.1 147.12,17.89 v1(147.61,18.37) 147.78,18.55 148.9,18.55 149.3,18.94 v3(149.71,18.94)
  BOTTOM w0.102: v3(149.71,18.94) 149.7,18.93 U2.R7
FCH_SDATA1_TP: length 149
  TOP w0.102: v3(142.55,17.67) 142.55,18.13 RPH5.5 ; QH31.4 145.62,17.31 145.29,16.98 v3(145.29,16.59) ; RE336.1 25.71,63.71 v3(25.61,63.81)
  IN2 w0.127: v3(145.29,16.59) 144.68,17.2 143.02,17.2 v3(142.55,17.67)
  IN3 w0.135: v3(25.61,63.81) 25.54,63.88 25.54,64.32 25.79,64.57 27.45,64.57 35.88,56.14 45.68,56.14 48.88,52.94 48.88,44.98 54.15,39.7 54.15,39.27 57.58,35.84 66.6,35.84 67.06,36.3 70.48,36.3 70.59,36.19 80.19,36.19 85.72,30.66 86.29,30.66 87.71,29.24 108.77,29.24 111.28,26.73 123.73,26.73 123.99,26.47 125.2,26.47 127.31,24.36 128.5,24.36 129.66,23.21 131.58,23.21 131.79,23.42 136.07,23.42 137.72,21.77 139.06,21.77 142.45,18.38 142.45,17.76 v3(142.55,17.67)
FCH_SDATA1_TP_R: length 3.8
  TOP w0.102: JTP.7 26.65,60.88 25.71,61.82 RE336.2 26.33,62.21 v1(26.92,62.79)
FCH_SDATA4: length 216.9
  TOP w0.102: RX37.1 14.6,103.8 QX7.6 14.32,102.43 14.08,102.19 14.08,101.25 13.62,100.79 v3(13.44,100.79)
  IN3 w0.135: v3(13.44,100.79) 13.44,100.77 12.76,100.08 12.76,98.23 18.43,92.55 18.43,72.35 23.1,67.67 23.1,63.83 31.07,55.86 33.66,55.86 35.3,54.22 46.37,54.22 48.4,52.18 48.4,44.78 51.7,41.48 51.7,36.43 52.73,35.4 58.13,35.4 58.56,34.96 64.35,34.96 65.21,34.1 71.03,34.1 71.38,33.74 79.65,33.74 82.29,31.1 82.66,31.1 84.31,29.45 86.6,29.45 87.97,28.08 97,28.08 97.65,28.73 108.43,28.73 114.62,22.53 118.12,22.53 118.74,21.91 122.55,21.91 123.67,20.79 126.36,20.79 129.54,17.61 134.27,17.61 135.27,16.62 137.4,16.62 138.57,15.46 139.94,15.46 140.61,14.79 143.16,14.79 143.65,15.28 145.69,15.28 147.73,13.24 148.46,13.24 148.67,13.44 151.55,13.44 152.06,12.93 152.06,11.77 152.49,11.34 153.71,11.34 154.49,10.55 154.49,10.55 155.28,9.77 159.82,9.77 160.56,10.51 160.56,12.18 v3(160.65,12.27)
  BOTTOM w0.102: U2.G21 161,11.92 v3(160.65,12.27)
FCH_SDATA4_R: length 23.9
  TOP w0.102: v3(11.82,101.4) 11.82,101.86 12.39,102.43 QX7.1 12.7,102.81 RX37.2 13.7,103.92 RX40.2 v1(14.61,105.77)
  BOTTOM w0.102: v3(11.82,101.4) 11.66,101.25 6.61,101.25 5.21,99.85 5.21,96.7 5.04,96.52 5.04,92.74 3.8,91.5 JEDP.16
FCH_SPI_CLK: length 62.8
  TOP w0.102: v3(157.33,33.2) v1(157.33,34.52) 158.32,35.51 160.97,35.51 161.65,34.83 163.33,34.83 163.66,35.16 173.08,35.16 176.89,31.35 176.89,29.48 178.89,27.49 180.14,27.49 180.78,26.85 180.78,26.14 RH29.1 181.29,25.61 v3(180.78,25.1)
  IN3 w0.135: v3(157.33,33.2) 157.18,33.2 154.64,30.66 148.67,30.66 140.8,22.79 v3(140.52,22.79)
  BOTTOM w0.102: U2.V3 146.94,20.92 146.52,21.34 146.29,21.34 145.81,21.82 143.67,21.82 143.52,21.98 140.49,21.98 RH70.2 140.32,22.58 v3(140.52,22.79) ; v3(180.78,25.1) 181.41,25.73 USPI1.6
FCH_SPI_CS1#: length 84.2
  IN1 w0.114: v3(182.94,20.15) 182.38,19.59 176.27,19.59 174.63,17.95 174.35,17.95 173.08,16.68 173.08,15.2 170.47,12.59 170,12.59 167.41,10 166.73,10 165.11,8.38 165.11,8.27 164.4,7.56 163.66,7.56 163.48,7.74 162.12,7.74 160.54,6.16 157.15,6.16 156.9,5.92 155.85,5.92 155.55,5.61 147.98,5.61 147.34,4.97 142.16,4.97 141.01,6.11 141.01,10.44 141.42,10.85 141.42,16.48 139.4,18.5 139.07,18.5 138.11,19.46 v3(138.11,20.48)
  IN3 w0.135: v3(138.11,20.48) 138.33,20.25 138.33,19.92 139.27,18.98 140.9,18.98 141.84,18.04 141.84,17.68 142.32,17.2 143.68,17.2 145.46,18.98 146.2,18.98 147.06,19.84 v3(148.27,19.84)
  BOTTOM w0.102: U2.T6 148.75,19.36 v3(148.27,19.84) ; v3(182.94,20.15) 183.47,20.15 183.95,19.66 USPI1.1 ; v3(138.11,20.48) 137.55,21.04 RH65.2 137.55,21.49 137.66,21.61 RPH6.8
FCH_SPI_HOLD#: length 62.8
  TOP w0.102: v3(179.79,27.92) 179.81,27.89 179.05,27.89 177.3,29.65 177.3,31.52 173.25,35.56 v1(169.56,35.56) 167.95,35.56 167.29,36.22 167.29,36.86 166.86,37.29 164.93,37.29 164.45,36.81 163.61,36.81 163.12,37.29 159.76,37.29 159.51,37.55 158.51,37.55 158.36,37.39 157.28,37.39 151.57,31.68 147.63,31.68 143.99,28.03 143.99,25.67 144.63,25.02 RH64.2 143.57,24.31 142.82,25.06 137.17,25.06 v3(136.89,24.77)
  BOTTOM w0.102: v3(179.79,27.92) 180.53,27.17 181.62,27.17 181.73,27.07 182.34,27.07 182.68,26.73 USPI1.7 ; v3(136.89,24.77) 137.36,24.3 RPH6.5
FCH_SPI_HOLD#_R: length 4.3
  TOP w0.102: v3(148.29,23.04) 147.71,23.63 147.71,24.16 147.55,24.31 v1(147.15,24.31) RH64.1
  BOTTOM w0.102: v3(148.29,23.04) 148.75,22.58 U2.Y6
FCH_SPI_MISO: length 4.7
  TOP w0.102: v3(183.32,19.69) 183.32,19.99 183.57,20.25 RH34.2 RH67.2 v1(185.67,20.81)
  BOTTOM w0.102: USPI1.2 182.68,19.61 182.76,19.69 v3(183.32,19.69)
FCH_SPI_MISO_R: length 51.4
  TOP w0.102: v3(157.33,32.62) v1(158.39,32.62) 158.5,32.62 159.09,33.2 164.04,33.2 164.32,33.48 172.37,33.48 175.22,30.64 175.22,28.86 177.32,26.75 177.32,24.85 178.42,23.75 181.82,23.75 183.57,22 RH34.1
  IN3 w0.135: v3(148.06,20.4) 147.75,20.7 147.75,23.76 148.72,24.73 149.45,24.73 151.61,26.89 151.61,26.9 v3(157.33,32.62)
  BOTTOM w0.102: v3(148.06,20.4) 148.58,20.92 U2.V6
FCH_SPI_MOSI: length 3.8
  TOP w0.102: v3(179.86,24.69) 180.27,25.09 RH35.1 RH69.2
  BOTTOM w0.102: v3(179.86,24.69) 180.14,24.97 USPI1.5
FCH_SPI_MOSI_R: length 45.5
  TOP w0.102: RH35.2 179.74,27.08 178.72,27.08 176.49,29.31 176.49,31.17 172.9,34.75 163.84,34.75 163.51,34.42 161.48,34.42 160.95,34.95 v1(160,34.95) 159.59,34.95 159.11,34.47 158.45,34.47 158.17,34.19 v3(158.17,33.68)
  IN3 w0.135: v3(158.17,33.68) 158.29,33.57 158.29,32 157.13,30.84 156.37,30.84 152.88,27.35 152.88,26.68 151.9,25.7 151.6,25.7 149.84,23.95 149.84,22.76 v3(148.35,21.27)
  BOTTOM w0.102: v3(148.35,21.27) 148,20.92 U2.V5
FCH_SPI_WP#: length 78.7
  IN1 w0.114: v3(138.41,23.58) 138.79,23.19 138.79,22.25 138.52,21.99 138.52,19.7 139.31,18.91 139.59,18.91 141.84,16.67 141.84,10.67 141.43,10.27 141.43,6.29 142.33,5.39 147.17,5.39 147.81,6.03 155.37,6.03 155.68,6.34 156.73,6.34 156.97,6.58 160.37,6.58 161.95,8.16 163.66,8.16 163.84,7.98 164.22,7.98 164.69,8.44 164.69,8.55 166.55,10.42 167.24,10.42 169.83,13.01 170.3,13.01 172.66,15.37 172.66,16.86 174.17,18.37 174.45,18.37 176.26,20.17 v3(181.41,20.17)
  BOTTOM w0.102: v3(181.41,20.17) USPI1.3 ; RPH6.6 138.19,23.8 v3(138.41,23.58) 138.77,23.22 138.77,21.98 139.17,21.57 143.34,21.57 143.49,21.41 145.59,21.41 146.09,20.92 U2.V1
FCH_SPKR: length 40.9
  TOP w0.102: DA8.3 188.27,16.23 v3(187.48,17.02)
  IN1 w0.114: v3(187.48,17.02) 187.69,17.02 187.99,17.33 187.99,17.68 187.64,18.04 186.84,18.04 185.5,19.38 185.5,20.93 182.37,24.06 178.04,24.06 170.29,31.81 169.81,31.81 168.39,33.23 164.8,33.23 v3(164.6,33.02)
  BOTTOM w0.102: U2.AF24 163.99,27.81 163.99,28.4 163.48,28.91 163.35,28.91 163.12,29.14 163.12,31.8 163.38,32.06 163.62,32.06 164.59,33.02 v3(164.6,33.02) ; v3(187.48,17.02) 187.83,17.02 v1(188.09,16.76)
GATEA20: length 61.2
  TOP w0.102: v3(161.65,27.17) 161.8,27.17 v1(162.22,27.59)
  IN3 w0.135: v3(119.97,22.66) 120.81,23.5 122.03,23.5 123.99,21.54 134.66,21.54 135.36,20.83 135.36,20.07 138.06,17.38 140.76,17.38 141.98,16.16 145.83,16.16 147.59,17.92 149.17,17.92 149.46,18.22 150.27,18.22 151.44,19.38 152.2,19.38 152.68,19.86 152.68,21.8 153.27,22.39 153.27,22.76 153.68,23.17 154.87,23.17 157.28,25.58 159.16,25.58 160.13,26.55 160.69,26.55 161.31,27.17 v3(161.65,27.17)
  BOTTOM w0.102: U2.AE22 162.09,26.72 v3(161.65,27.17) ; v3(119.97,22.66) 120.2,22.43 120.2,17.07 121.19,16.08 UE1.1
GBE_PHY_INTR: length 15.2
  TOP w0.102: v3(150.91,22.66) 150.82,22.56 148.8,22.56 148.67,22.43 147.48,22.43 146.68,23.23 v1(141.78,23.23) 141.24,23.23 141.03,23.45 140.54,23.45 139.78,22.69 138.41,22.69 v3(138.36,22.74)
  BOTTOM w0.102: v3(150.91,22.66) 151.3,22.27 U2.W9 ; v3(138.36,22.74) 138.36,22.84 137.9,23.3 RPH6.7
GPIO19_CTF: length 8.7
  BOTTOM w0.102: RV151.2 RV152.1 60.64,99.5 60.64,99.04 61.14,98.53 v1(61.14,97.57) 61.14,95.97 60.89,95.71 60.89,95.58 60.4,95.09 UV1.M2
GPIO28: length 9.8
  TOP w0.102: v3(64.7,99.8) 64.95,99.55 v1(64.95,98.96) 64.95,98.38 64.32,97.74 64.32,93.62 63.6,92.89 v3(63.6,92.69)
  BOTTOM w0.102: v3(63.6,92.69) 63.39,92.9 UV1.R5 ; v3(64.7,99.8) 64.45,100.05 RV21.2
GPIO168: length 5.8
  BOTTOM w0.102: RPH7.6 143.32,23.83 143.48,23.66 145.73,23.66 146.02,23.37 146.24,23.37 146.62,22.99 147.35,22.99 147.82,22.52 U2.Y5
GPIO169: length 4.8
  BOTTOM w0.102: RPH7.7 143.26,23.33 143.37,23.21 v1(144.96,23.21) 145.89,23.21 145.94,23.17 146.15,23.17 146.53,22.79 146.88,22.79 U2.Y3
GPIO170: length 4.2
  BOTTOM w0.102: U2.Y1 146.19,22.36 145.57,22.36 145.29,22.64 144.87,22.64 144.47,22.23 v1(144.11,22.23) 143.87,22.23 143.28,22.83 RPH7.8
GPIO172: length 6.2
  BOTTOM w0.102: U2.K5 147.56,14.91 144.97,14.91 v1(144.18,14.11) 143.15,13.09 RPH3.3
GPIO173: length 5.2
  BOTTOM w0.102: U2.K3 147.03,14.52 146.23,13.72 145.78,13.72 145.37,13.31 144.95,13.31 v1(144.46,12.82) 144.27,12.63 143.45,12.63 143.41,12.59 RPH3.4
GPIO175: length 4.3
  BOTTOM w0.102: U2.N2 146.09,16.92 145.78,17.22 144.82,17.22 144.52,16.92 v1(144.09,16.92) RPH2.1
GPIO176: length 4.7
  BOTTOM w0.102: U2.M3 146.88,15.85 146.53,15.85 146.48,15.8 146.31,15.8 146.13,15.61 v1(144.14,15.61) 143.9,15.61 143.71,15.42 RPH2.4
GPIO177: length 4.8
  BOTTOM w0.102: RPH3.2 143.14,13.59 144.69,15.14 146.57,15.14 U2.L2
GPIO178: length 5.3
  BOTTOM w0.102: U2.N4 147.2,16.57 146.13,16.57 145.71,16.15 144.57,16.15 144.31,16.41 142.71,16.41 RPH2.2
GPIO179: length 4.1
  BOTTOM w0.102: RPH1.3 142.9,18.8 143.35,18.35 143.7,18.35 144.33,17.72 U2.P1
GPIO180: length 5.1
  BOTTOM w0.102: U2.P3 146.9,17.72 146.47,18.15 v1(144.85,18.15) 143.71,19.3 RPH1.2
GPIO181: length 3.7
  BOTTOM w0.102: U2.M1 146.17,15.94 143.85,15.94 143.83,15.92 RPH2.3
GPIO182: length 6.1
  BOTTOM w0.102: RPH3.1 143.1,14.09 144.38,15.36 146.17,15.36 146.4,15.59 146.57,15.59 146.62,15.64 147.38,15.64 147.86,16.12 U2.M5
GPIO189: length 7
  BOTTOM w0.102: U2.D21 161.1,9.48 160.69,9.07 v1(160.69,6.29) 160.69,5.34 RH86.2 161.27,4.76 161.27,3.94 RH93.1
GPIO190: length 5.8
  BOTTOM w0.102: RH92.1 159.2,4.7 159.77,5.27 RH85.2 159.87,6.22 159.49,6.6 v1(159.49,6.77) 159.49,7.61 159.94,8.06 159.94,8.82 160.3,9.18 U2.C20
GPU_AC_LIGHT: length 2.9
  BOTTOM w0.102: RE80.1 124.68,24.57 T106.1 124.66,24.59 UE1.108
GPU_B+:
  vias: v1(58.88,42.38) v2(57.33,44.35) v2(58.22,44.35) v2(59.11,44.96) v2(59.11,44.25) v2(60.89,44.25) v2(62.54,44.38) v2(63.18,44.38) v3(64.83,44.25)
GPU_VID1: length 31
  IN3 w0.135: v3(62.8,90.72) 63.31,91.24 63.31,91.68 64.98,93.35 70.24,93.35 72.57,95.69 73.62,95.69 73.72,95.58 75.65,95.58 75.8,95.74 80.22,95.74 82.25,93.7 v3(84.23,93.7)
  BOTTOM w0.102: UV1.P8 62.58,90.5 v3(62.8,90.72) ; v3(84.23,93.7) 84.72,93.7 86.54,95.53 86.54,96.02 RV76.1 v1(85.91,97.79)
GPU_VID1_GPIO_20: length 4.9
  BOTTOM w0.102: v1(84.89,94.67) RV72.1
  BOTTOM w0.254: RV76.2 RV72.1 RV74.2 82.93,94.79 U1.3
GPU_VID3: length 23.7
  IN3 w0.135: v3(80.4,96.45) 79.97,96.02 75.67,96.02 75.51,95.85 73.83,95.85 73.69,95.99 72.37,95.99 70.52,94.14 62.53,94.14 v3(61.98,94.68)
  BOTTOM w0.102: RV75.1 82.25,97.26 81.01,97.26 v1(80.71,96.97) 80.4,96.65 v3(80.4,96.45) ; UV1.N1 61.38,94.68 v3(61.98,94.68)
GPU_VID3_GPIO_15: length 9.8
  TOP w0.102: v3(83.24,89.97) 83.24,89.74 82.99,89.49 v1(82.99,89.46)
  IN1 w0.254: v3(83.24,89.97) 83.24,92.69 82.4,93.53 v3(82.4,95.13)
  BOTTOM w0.254: RV75.2 82.86,95.58 v3(82.4,95.13) 82.28,95.01 U1.2 ; RV73.2 RV71.1 83.75,89.72 83.5,89.97 v3(83.24,89.97)
H_PROCHOT#_EC: length 137.7
  TOP w0.102: v3(168.79,95.18) RC13.2 QC1.2 167.24,93.17 165.68,91.61 165.68,89.06 v1(170.48,84.27) 178.81,75.94 v3(178.81,74.71) ; QE30.1 123.63,29.9 123.88,30.15 125.66,30.15 126.85,31.35 v3(127.64,31.35) ; v3(155.15,101.53) 154.77,101.15 R33.2
  IN1 w0.114: v3(168.79,95.18) 167.63,95.18 165.97,96.84 163.68,96.84 159.83,100.69 156.47,100.69 155.63,101.53 v3(155.15,101.53)
  IN2 w0.127: v3(127.64,31.35) 128.28,31.35 129.14,32.21 131.27,32.21 134.17,35.11 155.97,35.11 157.49,36.62 157.49,37.22 158.75,38.49 160.35,38.49 168.69,46.83 168.69,49.48 172.57,53.37 172.57,54.01 178.47,59.9 178.47,74.37 v3(178.81,74.71)
  BOTTOM w0.102: v3(127.64,31.35) 128.71,30.28 128.71,28.1 127.46,26.85 126.55,26.85 RE44.2
H_THERMTRIP#: length 185.4
  TOP w0.102: RH89.2 143.34,15.8 143.64,16.11 144.57,16.11 144.93,15.75 145.68,15.75 146.37,16.45 147.09,16.45 147.56,16.93 147.56,17.73 147.98,18.14 149.09,18.14 149.45,18.51 151.27,18.51 v1(151.68,18.1) 151.99,17.79 v3(151.99,17.64) ; R623.2 149.28,119.21 149.79,118.7 150.53,118.7 v3(150.93,119.1)
  IN2 w0.127: v3(184.64,25.94) 179.86,30.71 179.83,30.71 179.83,33.01 181.79,34.98 186.04,34.98 188.51,37.46 190.94,37.46 195.19,41.71 195.19,45.52 194.49,46.22 194.49,47.05 195.19,47.74 195.19,69.26 192.96,71.49 192.96,73.15 194.44,74.64 194.44,77.14 193.73,77.86 193.73,79.96 187.48,86.2 187.48,92.18 183.22,96.45 180.18,96.45 174.91,101.72 170.85,101.72 168.87,103.7 168.87,104.48 160.38,112.97 160.38,114.23 157.59,117.02 155.15,117.02 152.61,119.56 151.39,119.56 v3(150.93,119.1) ; v3(151.99,17.64) 152.01,17.64 152.63,18.27 158.55,18.27 158.79,18.03 159.89,18.03 160.05,18.19 160.89,18.19 161.09,18.39 166.5,18.39 169.63,21.52 v3(174.55,21.52)
  BOTTOM w0.102: v3(151.99,17.64) 151.99,17.62 152.1,17.73 U2.R10 ; v3(174.55,21.52) 175.82,22.79 178.21,22.79 178.24,22.76 184.18,22.76 184.59,23.17 184.59,23.55 185.1,24.06 185.1,25.48 v3(184.64,25.94)
HDA_BITCLK: length 12.2
  BOTTOM w0.102: RPH10.7 137.78,26.73 137.52,26.47 137.52,25.99 138.44,25.07 139.35,25.07 139.81,25.53 v1(140.34,25.53) 143.22,25.53 143.99,24.77 144.39,24.77 144.95,24.21 145.78,24.21 146.21,23.78 146.81,23.78 U2.AB3
HDA_BITCLK_AUDIO: length 102.2
  IN1 w0.114: v3(192.26,10.39) 192.04,10.18 191.46,10.18 187.56,6.28 178.82,6.28 176.71,4.17 175.85,4.17 173.41,1.73 169.2,1.73 168.84,2.09 167.24,2.09 166.68,2.65 164.33,2.65 163.06,1.38 158.17,1.38 157.58,1.97 154.8,1.97 154.18,1.35 137.98,1.35 135.24,4.09 134.94,4.09 134.29,4.74 133.89,5.14 133.89,8.86 134.94,9.91 134.94,11.46 134.27,12.12 134.27,13.83 129.94,18.16 129.94,20.73 133.41,24.2 133.41,24.52 v3(133.66,24.77)
  BOTTOM w0.102: v3(133.66,24.77) 134.07,24.77 134.47,25.18 134.47,25.79 134.75,26.06 RH91.2 134.76,26.48 136.05,26.48 136.31,26.73 RPH10.2 ; UA1.6 196.73,15.77 196.61,15.66 196.61,14.58 196.78,14.42 RA1112.1 196.23,13.56 196.23,13.02 195.08,11.87 193.48,11.87 192.46,10.85 192.46,10.6 v3(192.26,10.39)
HDA_RST#: length 11.1
  BOTTOM w0.102: RPH10.5 138.46,27.73 139.49,28.76 v1(142.22,28.76) 143.7,28.76 146.01,26.45 146.36,26.45 146.62,26.2 146.88,26.2 147.21,26.52 U2.AE4
HDA_RST_AUDIO#: length 95.5
  IN1 w0.114: v3(135.79,27.51) 134.52,26.24 134.52,21.62 135.36,20.78 135.36,17.53 135.92,16.97 135.92,14 135.18,13.26 135.18,12.5 136.65,11.04 136.65,8.75 134.8,6.91 134.8,5.52 135.32,5.01 135.62,5.01 138.36,2.26 153.81,2.26 154.42,2.88 158,2.88 158.55,2.33 162.72,2.33 163.95,3.56 166.88,3.56 169.34,6.02 169.95,6.02 170.6,6.68 177.34,6.68 178.39,7.73 186.49,7.73 192.26,13.49 v3(193.86,13.49)
  BOTTOM w0.102: UA1.11 194.73,16.06 194.44,15.78 194.21,15.78 193.1,14.66 RA6.1 193.71,14 193.71,13.64 v3(193.86,13.49) ; RPH10.4 136.01,27.73 v3(135.79,27.51)
HDA_SDIN0: length 105.2
  IN1 w0.114: v3(134.07,24.29) 134.07,24.16 130.44,20.53 130.44,18.37 134.77,14.04 134.77,12.33 135.43,11.66 135.43,9.7 134.38,8.65 134.38,5.35 135.14,4.59 135.44,4.59 138.19,1.85 153.98,1.85 154.6,2.47 157.79,2.47 158.39,1.87 162.86,1.87 164.13,3.14 167.05,3.14 169.42,5.52 176.78,5.52 178.54,7.28 186.64,7.28 192.39,13.03 194.34,13.03 v3(194.39,13.09)
  BOTTOM w0.102: v3(194.39,13.09) 194.44,13.14 194.44,13.39 RA130.1 ; U2.AA2 146.49,23.58 146.11,23.58 145.75,23.93 144.79,23.93 144.56,24.16 143.86,24.16 142.97,25.05 140.01,25.05 139.35,24.39 RH94.2 139.08,24.27 138.55,24.27 137.85,24.97 137.27,24.97 137.06,25.18 135.54,25.18 134.65,24.29 v3(134.07,24.29)
HDA_SDOUT: length 9.6
  BOTTOM w0.102: U2.AB1 146.04,24.43 145.05,24.43 143.47,26.01 v1(143.01,26.01) 139.55,26.01 139.1,25.56 138.64,25.56 138.05,26.15 RPH10.8
HDA_SDOUT_AUDIO: length 89.3
  IN1 w0.114: v3(197.16,15.12) 196.4,14.36 194.6,14.36 194.42,14.53 189.64,14.53 186.42,11.31 177.93,11.31 176.64,10.01 176.64,9.84 175.48,8.69 172.58,8.69 171.92,9.34 169.08,9.34 168.05,8.31 168.05,7.62 167.95,7.52 166.63,7.52 164.85,5.74 163.75,5.74 162.69,4.69 157.74,4.69 157.18,4.13 153.91,4.13 153.86,4.08 148.52,4.08 147.95,3.51 141.47,3.51 138.51,6.46 138.51,8.88 137.89,9.5 137.89,11.1 138.26,11.47 138.26,13.12 137.17,14.21 137.17,14.99 137.62,15.44 137.62,17.64 137.26,17.99 137.26,19.39 136.63,20.02 136.63,22.15 136.43,22.36 136.43,25.12 v3(135.92,25.63)
  BOTTOM w0.102: v3(135.92,25.63) 136.52,26.23 RPH10.1 ; v3(197.16,15.12) 197.13,15.15 UA1.5
HDA_SYNC: length 12.3
  BOTTOM w0.102: RPH10.6 138.54,27.23 139.58,28.27 143.59,28.27 v1(143.84,28.02) 145.82,26.04 146.47,26.04 146.48,26.04 146.53,25.99 146.97,25.99 147.09,26.11 148.36,26.11 U2.AD6
HDA_SYNC_AUDIO: length 88.8
  IN1 w0.114: v3(135.82,26.93) 135.49,26.6 135.49,25.35 135.35,25.21 135.35,22.65 136.21,21.78 136.21,19.85 136.84,19.22 136.84,17.82 137.2,17.46 137.2,15.61 136.75,15.16 136.75,14.04 137.84,12.95 137.84,11.65 137.47,11.28 137.47,9.33 138.08,8.72 138.08,6.3 141.29,3.09 148.12,3.09 148.69,3.66 154.03,3.66 154.08,3.71 157.36,3.71 157.92,4.27 163.48,4.27 163.76,3.99 166.71,3.99 169.25,6.53 169.86,6.53 170.43,7.1 177.13,7.1 179.64,9.61 186.95,9.61 189.69,12.35 190.52,12.35 192.22,14.05 194.09,14.05 194.14,14.1 v3(194.14,14.1)
  BOTTOM w0.102: RPH10.3 136.12,27.23 v3(135.82,26.93) ; v3(194.14,14.1) 194.14,14.11 194.14,15.09 195.13,16.08 UA1.10
HDD_A0_PRE0: length 5.1
  TOP w0.102: US2.9 180.66,18.87 180.1,19.42 179.09,19.42 v1(178.72,19.79) 177.86,20.65 RS24.1 RS27.2
HDD_A0_PRE1: length 3.8
  TOP w0.254: US2.19 181.66,14.03 181.68,14.01 181.68,13.36 v1(181.79,13.26) 182.72,12.32 RS30.2
  TOP w0.508: RS30.2 RS23.1
HDD_B0_EQ: length 3.2
  TOP w0.254: US2.13 178.7,16.44 178.66,16.4 178.19,16.4 178.07,16.51 v1(178.07,16.4)
  TOP w0.508: v1(178.07,16.4) 177.91,16.57 RS38.1 RS37.1
HDD_B0_PRE0: length 4.2
  TOP w0.102: RS21.1 RS28.2 179.63,20.15 v1(180,19.78) 180.3,19.78 181.16,18.91 181.16,18.34
HDD_B0_PRE1: length 5.9
  TOP w0.102: US2.17 180.66,14.03 179.76,13.14 RS18.1 RS29.2 178.75,12.23 179.24,11.74 179.24,10.7 v1(179.6,10.34)
HDD_DET#: length 63.3
  IN1 w0.114: v3(175.27,9.5) 175.27,9.71 177.58,12.02 186.21,12.02 188.25,14.05 188.25,17.75 187.73,18.27 186.94,18.27 185.73,19.48 185.73,21.03 184.28,22.47 184.28,24.69 183.39,25.58 180.02,25.58 174.07,31.53 170.9,31.53 170.39,32.03 169.91,32.03 168.48,33.46 164.19,33.46 163.53,32.8 v3(163.43,32.8)
  BOTTOM w0.102: U2.AH17 157.9,29.48 158.35,29.93 158.35,30.23 158.6,30.48 158.91,30.48 159.06,30.64 159.06,31.42 159.49,31.86 159.49,32.9 159.85,33.25 162.97,33.25 v3(163.43,32.8) ; v3(175.27,9.5) v1(175.27,8.79) RS9.1
HDD_DET#_R: length 12.1
  BOTTOM w0.102: JHDD.8 186.31,11.43 184.87,9.99 181.57,9.99 178.89,7.31 v1(178.34,7.31) 177.67,7.31 RS9.2
HDD_LED#: length 184.3
  TOP w0.102: JLED.7 13.31,52.3 v1(14.25,53.24) 14.97,53.95 v3(14.97,54.11) ; v3(161.65,26.34) 161.65,26.55 161.19,27 161.19,29.29 161.98,30.08 RH39.2
  IN2 w0.127: v3(14.97,54.11) 16.85,54.11 17.23,53.73 19.01,53.73 23.49,49.24 23.49,47.58 30.31,40.76 30.31,39.44 36.49,33.25 42.27,33.25 46.04,29.48 56.28,29.48 58.88,32.08 67.39,32.08 71.35,36.05 74.55,36.05 75.37,36.87 75.37,37.36 76.97,38.96 77.53,38.96 78.24,38.24 87.34,38.24 97.21,28.38 108.26,28.38 112.83,23.8 119.82,23.8 121.15,25.14 123.16,25.14 123.68,24.62 128.23,24.62 130.51,26.9 130.51,28.12 131.53,29.14 143.04,29.14 144.56,30.66 159.21,30.66 160.86,29.01 160.86,27.08 161.6,26.34 v3(161.65,26.34)
  BOTTOM w0.254: U2.AD22 161.88,26.34 v3(161.65,26.34)
HDD_REXT_SATA0: length 8.3
  TOP w0.102: v1(185.71,10.18) 186.62,11.09 186.62,12.08 186.38,12.32 RS26.2
  TOP w0.254: US2.20 182.16,14.17 182.3,14.03 182.44,14.03 182.7,13.77 182.7,13.23 182.96,12.96 184.21,12.96 RS31.1
  TOP w0.508: RS26.2 RS31.1
HDMI_HPLUG: length 12.8
  TOP w0.102: JHDMI.19 203.55,80.43 v1(202.74,79.62) 202.27,79.15 201.33,79.15 200.56,78.39 200.56,77.4 200.87,77.09 200.87,75.05 198.9,73.08 CX20.1 RX34.1 RX15.2
HPOUT-L: length 2.4
  BOTTOM w0.203: RA55.1 197.16,24.44 v3(197.16,23.63) 197.13,23.59 UA1.32
HPOUT-R: length 2.3
  BOTTOM w0.203: RA56.1 v1(197.75,23.75) 197.75,23.32 197.53,23.1 UA1.33
IBIAS: length 2.4
  TOP w0.203: PR540.2 61.75,107.55 v1(61.75,108.64) PU500.29
IMON: length 3.3
  TOP w0.203: PU500.15 59.72,114.96 59.04,115.64 v1(59.04,116.03) 59.04,116.22 58.82,116.44 PR526.1
IMON_GPU: length 4.8
  TOP w0.254: PR1029.2 PC1022.2 58.69,32.52 58.96,32.79 v3(58.96,33.1)
  BOTTOM w0.102: v3(58.96,33.1) 58.96,32.35 v1(59.12,32.19)
  BOTTOM w0.203: v3(58.96,33.1) 58.96,33.85 59.25,34.14 PU1000.10
IMONA: length 2.4
  TOP w0.203: PU500.17 59.31,114.16
  TOP w0.254: PR527.1 58.48,114.16 v1(59,114.16) 59.31,114.16
INT-SPK-L+: length 2.1
  IN1 w1.016: 202.49,19.36 203.03,18.83 203.03,17.48
  vias: v3(201.21,19.87) v3(201.8,19.93) v3(202.37,16.82) v3(202.37,16.18)
INT-SPK-L-: length 4.8
  IN2 w1.016: 202.47,19.13 202.49,19.16 205.37,19.16 206.41,18.11 206.41,17.71
  vias: v1(205.77,15.36) v3(200.97,19.11) v3(201.56,19.11) v3(206.41,16.82) v3(206.41,16.18)
INT-SPK-R+: length 3.8
  IN3 w1.016: 203.38,17.2 204.91,17.2 205.42,17.71 206.99,17.71
  vias: v3(200.97,17.84) v3(201.62,17.82) v3(207.32,17.07) v3(207.32,16.44)
INT-SPK-R-: length 8.9
  IN3 w1.016: 204.02,19.23 210.88,19.23 212.15,17.96 212.15,17.68
  vias: v1(211.93,15.54) v3(200.97,18.47) v3(201.61,18.47) v3(212.15,16.82) v3(212.15,16.18)
ISEN1: length 11.9
  IN2 w0.254: v3(52.13,37.77) 51.95,37.6 51.95,36.91 52.38,36.48 53.32,36.48 53.73,36.07 54.39,36.07 56.12,34.35 v3(57.16,34.35)
  BOTTOM w0.102: v3(52.13,37.77) 51.49,37.77 v1(51.24,38.03)
  BOTTOM w0.203: PC1051.2 57.46,34.98 58.11,35.63 PU1000.13
  BOTTOM w0.254: PC1051.2 v3(57.16,34.35) ; PR1058.1 51.7,37.34 v3(52.13,37.77)
ISEN1N: length 6.2
  TOP w0.203: PU500.7 63.35,117.07 63.62,117.34
  TOP w0.254: 63.62,117.34 63.81,117.53 65.55,117.53 v1(65.64,117.44) 66.01,117.44 66.35,117.78 67.37,117.78 67.68,118.1 PR558.1
ISEN1N-1: length 37.3
  TOP w0.254: PC525.1 PR549.2 66.82,119.32 PR558.2 67.67,119.33 PC532.1 68.31,120.83 v1(72.35,120.83) 94.22,120.83 95.19,119.87 95.19,118.08 94.32,117.21 93.97,117.21 v3(93.78,117.4)
  BOTTOM w0.254: PL501.2 94.14,117.05 v3(93.78,117.4)
ISEN1P: length 6.6
  TOP w0.203: 63.62,117.85 63.57,117.85 v1(62.95,117.23) PU500.8
  TOP w0.254: 63.62,117.85 63.66,117.89 65.61,117.89 65.89,118.17 PC525.2 PR549.1 65.89,120.2
ISEN2: length 9.4
  TOP w0.254: v3(55.52,33.08) v1(54.87,33.08) 52.86,33.08 51.7,34.24 PR1059.1
  BOTTOM w0.203: 57.18,33.71 57.46,33.71 57.71,33.96 57.71,34.68 58.27,35.23 PU1000.12
  BOTTOM w0.254: 57.18,33.71 PC1050.2 57.16,33.66 56.57,33.08 v3(55.52,33.08)
ISENA1N: length 3.9
  TOP w0.203: PU500.35 v3(64.15,108.87)
  BOTTOM w0.102: PR519.1 v1(62.63,107.4)
  BOTTOM w0.254: PR519.1 64.15,107.66 v3(64.15,108.87)
ISENA1N-1: length 47.2
  BOTTOM w0.254: PC512.1 64.83,107.47 PC508.1 PR518.2 64.73,106.48 PR519.2 63.89,106.02 66.73,103.18 69.97,103.18 71.6,101.55 v1(72.1,101.55) 74.22,101.55 76.56,99.22 78.49,99.22 79.28,98.43 82.68,98.43 84.74,100.49 93.63,100.49 97.26,104.12 97.26,106.56 97.52,106.81 PL500.2
ISENA1P: length 6.5
  TOP w0.203: v3(66.38,108.13) 66.35,108.16 65.69,108.16 64.55,109.29 PU500.36
  BOTTOM w0.102: PR518.1 65.67,105.71 v1(65.47,105.52)
  BOTTOM w0.254: PR518.1 PC508.2 66.5,107.4 PR515.2 66.55,107.95 v3(66.38,108.13)
ISL88731_ICREF: length 4.7
  BOTTOM w0.254: PR729.2 50.39,14.88 PR727.1 48.98,15.42 48.61,15.42 47.92,16.11 v1(47.67,16.11) 47.21,16.11 46.93,15.83 PU700.1
ISL88731_VREF: length 3.3
  BOTTOM w0.254: PU700.3 46.89,14.83 46.98,14.74 v1(47.63,14.74) 48.13,14.74 48.28,14.88 PR727.2 PR725.2
ISOLATEB: length 3.6
  BOTTOM w0.102: UL1.20 170.88,103.36 170.82,103.31 169.98,103.31 v1(169.84,103.17) 169.47,102.8 RL33.2 RL35.2
JACK_PLUG#: length 19.9
  TOP w0.102: RA3.1 191.37,19.74 RA1.2 ; RA3.1 191.45,19.36 v3(190.76,18.67) ; RA3.1 RA4.1 192.33,18.89 v1(192.17,18.72)
  IN3 w0.135: v3(190.76,18.67) 190.76,18.77 194.39,22.41 196.69,22.41 197.76,23.47 197.76,24.93 199.09,26.27 201.12,26.27 201.74,26.89 JHP.5
JACK_SENSE#: length 4.5
  TOP w0.102: v1(193.85,18.23) 193.85,19.68 193.4,20.12 RA34.2 192.79,20.12 RA4.2 192.33,21.22 QA5.3
JHDD_P10: length 11
  BOTTOM w0.102: RS8.2 177.79,8.69 v1(178.15,9.05) 178.45,8.74 180.03,8.74 181.48,10.19 184.54,10.19 185.51,11.16 JHDD.7
JTAG_TCK: length 10.6
  TOP w0.102: v4(62.41,99.5) 61.79,99.5 61.49,99.19 61.49,99.07 61.25,98.84 61.25,98.84 v3(60.7,98.29)
  BOTTOM w0.102: RP34.5 60.88,100.5 60.38,100 60.38,98.95 60.7,98.63 v3(60.7,98.29) 60.76,98.23 60.76,95.88 60.69,95.8 60.69,95.79 60.04,95.14 60.04,94.13 59.62,93.7 UV1.L3
JTAG_TDI: length 13
  TOP w0.102: v3(61.72,96.25) 61.83,96.25 62.29,95.8 62.29,95.19 62.43,95.05 v4(62.43,94.3)
  IN3 w0.102: v3(61.72,96.25) 61.72,96.31 60.43,97.6 60.37,97.6 v3(59.24,98.73)
  BOTTOM w0.102: UV1.L5 59.6,93.04 60.24,93.68 60.54,93.68 60.75,93.89 60.75,94.76 61.09,95.11 61.09,95.63 v3(61.72,96.25) ; v3(59.24,98.73) 59.75,99.24 59.75,100.51 59.88,100.64 RP34.7
JTAG_TDO: length 7
  TOP w0.102: v3(58.98,97.82) 58.98,98.28 58.18,99.08 T86.1
  BOTTOM w0.102: UV1.K4 58.8,93.36 59.32,93.87 59.32,94.3 59.29,94.33 59.29,94.66 59.53,94.9 59.53,97.28 v3(58.98,97.82)
JTAG_TMS: length 7
  BOTTOM w0.102: UV1.L1 59.6,94.5 59.8,94.7 59.8,96.71 59.98,96.89 v1(59.98,97.02) 59.98,100.11 60.38,100.51 RP34.6
JTAG_TRSTB: length 13
  TOP w0.102: v4(61.18,92.92) 61.02,93.08 59.75,93.08 v3(59.18,92.51)
  IN3 w0.102: v3(59.24,99.37) 57.59,97.72 57.59,94.1 v3(59.18,92.51)
  BOTTOM w0.102: v3(59.24,99.37) 59.38,99.51 RP34.8 ; v3(59.18,92.51) 59.59,92.1 UV1.L6
KB_BL_PWM: length 12.1
  TOP w0.102: JKBBL.4 121.78,13.82 v1(122.21,13.39) 122.31,13.29 123.37,13.29 v3(123.7,13.62)
  BOTTOM w0.102: QE5.5 QE5.2 124.14,12.83 124.03,12.93 124.03,13.29 v3(123.7,13.62) 123.14,13.05 QE5.1 QE5.6
KB_CAPS_PWR: length 9.1
  TOP w0.102: v1(92.64,51.55) 92.27,51.92 RE60.2
  TOP w0.305: JKB.4 91.24,45.35 90.71,45.88
  TOP w0.508: 90.71,45.88 90.71,51.39 RE60.2
KB_DET#: length 36.6
  TOP w0.102: v3(128.54,12.26) 128.99,11.82 132.91,11.82 133.57,12.48 134.79,12.48 135.07,12.2 137.16,12.2 137.42,12.46 137.42,13.99 136.99,14.42 136.99,19.05 137.47,19.54 v1(137.47,22.13) 137.47,22.45 138.18,23.16 138.52,23.16 138.78,22.9 139.71,22.9 140.46,23.65 146.55,23.65 147.56,22.64 148.59,22.64 148.93,22.98 v3(149.24,22.98)
  BOTTOM w0.102: v3(128.54,12.26) 128.75,12.47 QE4.1 129.42,12.26 RE68.1 ; U2.W8 150.36,22.02 149.4,22.98 v3(149.24,22.98)
KB_LED_PWM: length 15.2
  TOP w0.102: v3(124.48,13.17) 124.4,13.17 v1(124.06,12.83) 123.83,12.6 121.89,12.6 121.48,12.2 117.25,12.2 115.58,13.87 113.98,13.87 v3(113.57,13.47)
  BOTTOM w0.102: v3(124.48,13.17) 125.14,12.52 QE5.3 ; UE1.21 113.19,14 113.54,13.64 113.54,13.49 v3(113.57,13.47)
KB_RST#: length 62.3
  TOP w0.102: v3(159.11,27.93) v1(158.25,27.93)
  IN3 w0.102: v3(159.11,27.93) 159.11,27.72 159.62,27.21 159.62,26.67 158.98,26.04 155.25,26.04 153.96,24.74 153.96,24.52 152.91,23.48 152.91,22.53 152.41,22.03 152.41,19.97 152.1,19.66 150.91,19.66 150.78,19.54 149.69,19.54 148.34,18.19 146,18.19 144.22,16.41 142.11,16.41 140.71,17.81 140.28,17.81 139.81,18.28 139.04,18.28 137.71,19.61 137.09,19.61 135.62,21.08 135.62,21.82 135.18,22.25 134.39,22.25 133.94,21.81 124.1,21.81 122.03,23.88 120.53,23.88 119.39,22.74 v3(119.39,22.64)
  BOTTOM w0.102: v3(159.11,27.93) 159.5,28.32 U2.AG19 ; v3(119.39,22.64) 119.39,22.51 119.74,22.15 119.74,17.1 120.79,16.05 UE1.2
KSI0: length 25.1
  TOP w0.102: JKB.22 92.43,30.95 v1(93.47,29.91) 93.68,29.7 93.68,28.56 94.06,28.19 94.51,28.19 96.5,26.19 101.62,26.19 102.52,27.09 102.52,28.04 103.34,28.86 105.56,28.86 106.31,28.11 106.31,25.51 106.1,25.3 105.75,25.3 v3(105.31,25.73)
  BOTTOM w0.102: v3(105.31,25.73) 105.72,25.33 106.13,25.33 106.19,25.39 UE1.55
KSI1: length 21.8
  TOP w0.102: v3(105.9,25.73) 105.39,26.24 105.39,27.06 105.82,27.49 105.82,28.02 105.39,28.45 103.51,28.45 102.93,27.87 102.93,26.92 101.65,25.65 v1(98.55,25.65) 96.02,25.65 93.57,28.1 93,28.1 92.59,28.51 92.59,29.06 92.3,29.35 JKB.24
  BOTTOM w0.102: v3(105.9,25.73) 105.95,25.79 UE1.56
KSI2: length 17.7
  TOP w0.102: JKB.26 92.44,27.75 95.31,24.88 v1(96.45,24.88) 101.59,24.88 v3(103.56,26.85)
  BOTTOM w0.102: v3(103.56,26.85) 104.23,26.19 UE1.57
KSI3: length 21.5
  TOP w0.102: v3(105.9,26.6) 106.1,26.8 106.1,28.03 105.48,28.66 103.43,28.66 102.72,27.95 102.72,27.01 101.71,25.99 96.23,25.99 v1(95.43,26.79) 94.65,27.58 94.38,27.58 93.63,28.33 93.06,28.33 92.79,28.59 92.79,29.82 92.46,30.15 JKB.23
  BOTTOM w0.102: v3(105.9,26.6) 105.91,26.59 UE1.58
KSI4: length 17.5
  TOP w0.102: v3(104.2,26.85) v4(102.8,25.46) 101.89,24.54 95.01,24.54 92.61,26.95 JKB.27
  BOTTOM w0.102: UE1.59 106.31,26.99 106.26,27.03 104.37,27.03 v3(104.2,26.85)
KSI5: length 18.5
  TOP w0.102: JKB.25 92.22,28.55 92.87,27.9 93.12,27.9 v4(93.47,27.55) 95.75,25.26 101.56,25.26 103.16,26.86 103.16,27.44 v3(103.56,27.84)
  BOTTOM w0.102: v3(103.56,27.84) 104.06,27.35 104.72,27.35 104.83,27.23 105.86,27.23 106.02,27.39 UE1.60
KSI6: length 18.7
  TOP w0.102: JKB.28 92.9,26.15 94.71,24.34 102.57,24.34 v4(104.48,26.25) 104.76,26.52 104.76,27.79 v3(104.81,27.84)
  BOTTOM w0.102: v3(104.81,27.84) 105.21,27.44 105.72,27.44 106.07,27.79 UE1.61
KSI7: length 18.5
  TOP w0.102: JKB.29 93.07,25.35 v4(93.47,24.95) 94.28,24.13 103.19,24.13 104.91,25.85 104.91,25.9 104.96,25.95 104.96,27.39 v3(105.42,27.84)
  BOTTOM w0.102: UE1.62 105.76,28.19 v3(105.42,27.84)
KSO0: length 34
  TOP w0.102: v3(109.07,18.52) 109.78,19.23 109.78,21.52 108.9,22.41 108.32,22.41 108.13,22.59 108.13,28.89 103.5,33.53 97.2,33.53 v1(96.23,34.51) 92.59,38.15 JKB.13
  BOTTOM w0.102: v3(109.07,18.52) 108.64,18.95 108.03,18.95 108,18.99 UE1.39
KSO1: length 34.4
  TOP w0.102: v3(108.44,19.38) 108.44,19.36 109.07,20 109.07,21.28 v1(108.64,21.71) 108.44,21.71 107.73,22.42 107.73,28.73 103.33,33.13 96.53,33.13 93.1,36.55 JKB.15
  BOTTOM w0.102: RE62.2 104.9,20.5 106.01,19.39 UE1.40 108.43,19.39 v3(108.44,19.38)
KSO2: length 36.1
  TOP w0.102: JKB.14 92.61,37.35 96.63,33.33 103.41,33.33 107.93,28.81 107.93,22.51 108.35,22.09 108.77,22.09 109.4,21.45 v1(109.4,19.99) 109.4,19.71 v3(109.07,19.38)
  BOTTOM w0.102: RE63.2 104.22,21.52 105.95,19.79 UE1.41 108.03,19.79 108.06,19.82 108.64,19.82 v3(109.07,19.38)
KSO3: length 29.1
  TOP w0.102: v3(108.44,20.22) 108.83,20.61 108.83,21.04 107.52,22.34 107.52,28.62 103.22,32.92 96.09,32.92 v4(93.78,35.23) 93.27,35.75 JKB.16
  BOTTOM w0.102: v3(108.44,20.22) 108.4,20.19 UE1.42
KSO4: length 30.5
  TOP w0.102: v3(105.04,21.31) 105.47,21.75 105.47,22.72 v1(106.51,23.77) 106.71,23.97 106.71,28.28 105.73,29.27 103.17,29.27 102.11,28.21 102.11,27.26 101.45,26.6 96.67,26.6 94.7,28.57 94.7,30.2 92.36,32.55 JKB.20
  BOTTOM w0.102: v3(105.04,21.31) 105.76,20.59 UE1.43
KSO5: length 29.6
  TOP w0.102: v3(105.06,21.92) 104.68,22.31 v1(104.68,22.66) 104.68,22.76 106.51,24.59 106.51,28.2 105.64,29.06 103.26,29.06 102.32,28.12 102.32,27.17 101.54,26.39 96.59,26.39 94.49,28.49 94.49,29.95 92.7,31.75 JKB.21
  BOTTOM w0.102: UE1.44 105.95,20.99 105.06,21.87 v3(105.06,21.92)
KSO6: length 26.9
  TOP w0.102: v3(105.87,21.72) v1(106.67,21.72) 107.12,22.17 107.12,28.45 103.08,32.49 94.94,32.49 93.28,34.15 JKB.18
  BOTTOM w0.102: UE1.45 106.21,21.39 v3(105.87,21.72)
KSO7: length 29.4
  TOP w0.102: JKB.19 92.39,33.35 94.9,30.84 94.9,28.66 96.75,26.8 101.37,26.8 101.91,27.34 101.91,28.29 103.33,29.71 v1(104.01,29.71) 105.57,29.71 106.91,28.37 106.91,23.52 105.92,22.53 v3(105.92,22.48)
  BOTTOM w0.102: UE1.46 106.39,21.79 105.92,22.25 v3(105.92,22.48)
KSO8: length 28.8
  TOP w0.102: v3(108.41,20.83) 107.32,21.92 107.32,28.53 103.16,32.69 95.5,32.69 v1(94.86,33.33) 93.24,34.95 JKB.17
  BOTTOM w0.102: UE1.47 108.07,22.19 108.41,21.85 v3(108.41,20.83)
KSO9: length 34.3
  TOP w0.102: v3(109.51,23.27) 109.12,23.65 109.12,24.03 110.05,24.96 110.05,26.27 109.92,26.39 109.92,28.3 109.35,28.87 109.35,29.44 108.58,30.21 v1(108.58,30.37) 108.58,31.07 108,31.65 107.28,31.65 102.38,36.55 97.36,36.55 93.16,40.76 93.16,42.17 92.38,42.95 JKB.7
  BOTTOM w0.102: UE1.48 108.01,22.59 108.14,22.46 108.79,22.46 109.51,23.17 v3(109.51,23.27)
KSO10: length 35.6
  TOP w0.102: v3(108.57,22.86) 108.69,22.74 109.61,22.74 110.52,23.65 110.52,26.51 110.34,26.69 110.34,28.45 109.76,29.04 109.76,29.96 109.35,30.38 109.35,30.9 108.18,32.06 107.45,32.06 102.55,36.96 98.34,36.96 v1(95.75,39.55) 95.5,39.81 95.5,40.49 92.91,43.08 92.91,43.81 92.17,44.55 JKB.5
  BOTTOM w0.102: v3(108.57,22.86) 108.44,22.99 UE1.49
KSO11: length 34.3
  TOP w0.102: JKB.6 92.39,43.75 92.67,43.48 92.67,43.03 93.36,42.33 93.36,40.86 96.7,37.52 v1(97.08,37.52) 97.85,36.76 102.46,36.76 107.36,31.86 108.08,31.86 108.98,30.96 108.98,30.28 109.56,29.71 109.56,28.95 110.13,28.38 110.13,26.53 110.27,26.39 110.27,24.58 v3(109.56,23.88)
  BOTTOM w0.102: UE1.50 108.19,23.39 108.31,23.27 108.85,23.27 109.45,23.88 v3(109.56,23.88)
KSO12: length 27.5
  TOP w0.102: v3(108.57,23.7) 108.34,23.93 108.34,28.98 103.58,33.74 97.77,33.74 v1(94.58,36.92) 92.56,38.95 JKB.12
  BOTTOM w0.102: UE1.51 108.48,23.79 v3(108.57,23.7)
KSO13: length 29.7
  TOP w0.102: v3(108.74,24.26) 108.74,24.82 109.39,25.46 109.39,28.26 108.95,28.7 108.95,29.23 107.19,30.98 107.19,31.16 102.21,36.15 98.93,36.15 98.77,36 v1(98.1,36) 97.35,36 92.75,40.59 92.75,41.01 92.42,41.35 JKB.9
  BOTTOM w0.102: v3(108.74,24.26) 108.67,24.19 UE1.52
KSO14: length 30.6
  TOP w0.102: v3(109.2,24.69) 109.72,25.21 v1(109.72,26.09) 109.72,28.21 109.15,28.78 109.15,29.32 108.79,29.67 107.4,31.07 107.4,31.25 102.29,36.35 97.28,36.35 92.96,40.67 92.96,41.68 92.49,42.15 JKB.8
  BOTTOM w0.102: UE1.53 108.03,24.59 108.14,24.69 v3(109.2,24.69)
KSO15: length 27.9
  TOP w0.102: v3(108.74,25.4) 109.18,25.84 109.18,27.58 v1(108.96,27.8) 108.74,28.02 108.74,29.15 106.99,30.9 106.99,31.08 102.13,35.95 99.19,35.95 98.88,35.63 97.43,35.63 92.51,40.55 JKB.10
  BOTTOM w0.102: UE1.54 108.33,24.99 v3(108.74,25.4)
KSO16: length 32.2
  TOP w0.102: v3(108.77,26.98) 108.54,27.21 108.54,29.06 106.79,30.82 106.79,31 102.04,35.74 99.43,35.74 99.12,35.42 96.83,35.42 v1(93.4,38.85) 92.51,39.75 JKB.11
  BOTTOM w0.102: v3(108.77,26.98) 110.55,26.98 111.69,28.12 113.49,28.12 115.19,29.82 UE1.81
LAN_CLKREQ#: length 102.9
  TOP w0.102: v3(170.14,53.29) 170.19,53.24 172.48,53.24 179.51,60.27 179.51,66.04 v1(183.86,70.39) 189.67,76.2 189.67,87.69 188.5,88.85 188.5,91.4 182.49,97.41 182.48,97.41 181.54,98.35 v3(180.27,98.35)
  BOTTOM w0.102: v3(170.14,53.29) 170.24,53.19 170.24,51.87 168.46,50.09 168.46,40.24 167.16,38.94 164.58,38.94 163.41,37.77 163.41,35.63 RH87.2 164.01,32.74 163.54,32.26 163.18,32.26 162.26,31.34 162.26,28.97 162.64,28.58 162.64,28.43 163.07,28 163.07,26.9 163.35,26.62 U2.AE24 ; UL1.12 173.61,101 173.74,100.87 173.74,100.18 173.92,100 175.44,100 176.59,101.15 RL37.1 177.27,99.19 178.11,98.35 v3(180.27,98.35)
LAN_X1: length 52.5
  IN1 w0.114: v3(139.53,16.9) 140.19,16.23 140.19,13.97 139.71,13.49 139.71,12.34 140.01,12.03 140.01,6.44 141.9,4.55 147.51,4.55 148.15,5.19 155.73,5.19 156.03,5.5 157.08,5.5 157.32,5.74 160.76,5.74 161.8,6.79 163.43,6.79 163.79,7.14 164.57,7.14 167.01,9.58 167.59,9.58 168.02,10.01 172.21,10.01 173,10.8 v3(174.3,10.8)
  BOTTOM w0.102: RH17.1 175.47,10.47 175.39,10.39 174.71,10.39 v3(174.3,10.8) ; v3(139.53,16.9) C14.1 R782.2
LAN_X1_R: length 3.9
  BOTTOM w0.102: v1(138.16,14.89) 138.19,14.93 138.19,15.71 137.93,15.98 R782.1 137.85,15.68 137.13,14.95 UG1.6
LCD_TEST: length 188.7
  TOP w0.102: v3(111.41,28.55) 111.41,27.19 v1(111.84,26.76)
  IN2 w0.127: v3(111.41,28.55) 111.41,28.35 111.05,28 110.1,28 108.63,29.47 99.8,29.47 98.86,30.41 98.86,33.43 91.1,41.19 91.1,50.03 89.82,51.31 89.82,71.06 90.4,71.64 90.4,73.49 83.27,80.62 83.27,86.01 82.76,86.52 82.76,92.32 81.99,93.1 78.19,93.1 77.4,93.89 77.4,94.34 76.26,95.48 74.45,95.48 73.72,96.22 71.24,96.22 70.43,97.03 68.19,97.03 66.35,98.87 66.35,99.78 65.26,100.87 62.49,100.87 62.31,100.69 58.5,100.69 57.89,101.3 57.13,101.3 56.52,100.69 45.48,100.69 44.06,102.11 29.22,102.11 27.44,100.33 23.68,100.33 13.75,90.41 13.75,89.52 12.93,88.71 12.93,82.53 v3(13.9,81.56)
  BOTTOM w0.102: v3(13.9,81.56) 13.7,81.77 11.11,81.77 10.75,82.12 7.78,82.12 7.02,82.88 2.5,82.88 2.38,83 JEDP.33 ; v3(111.41,28.55) 111.59,28.73 UE1.72
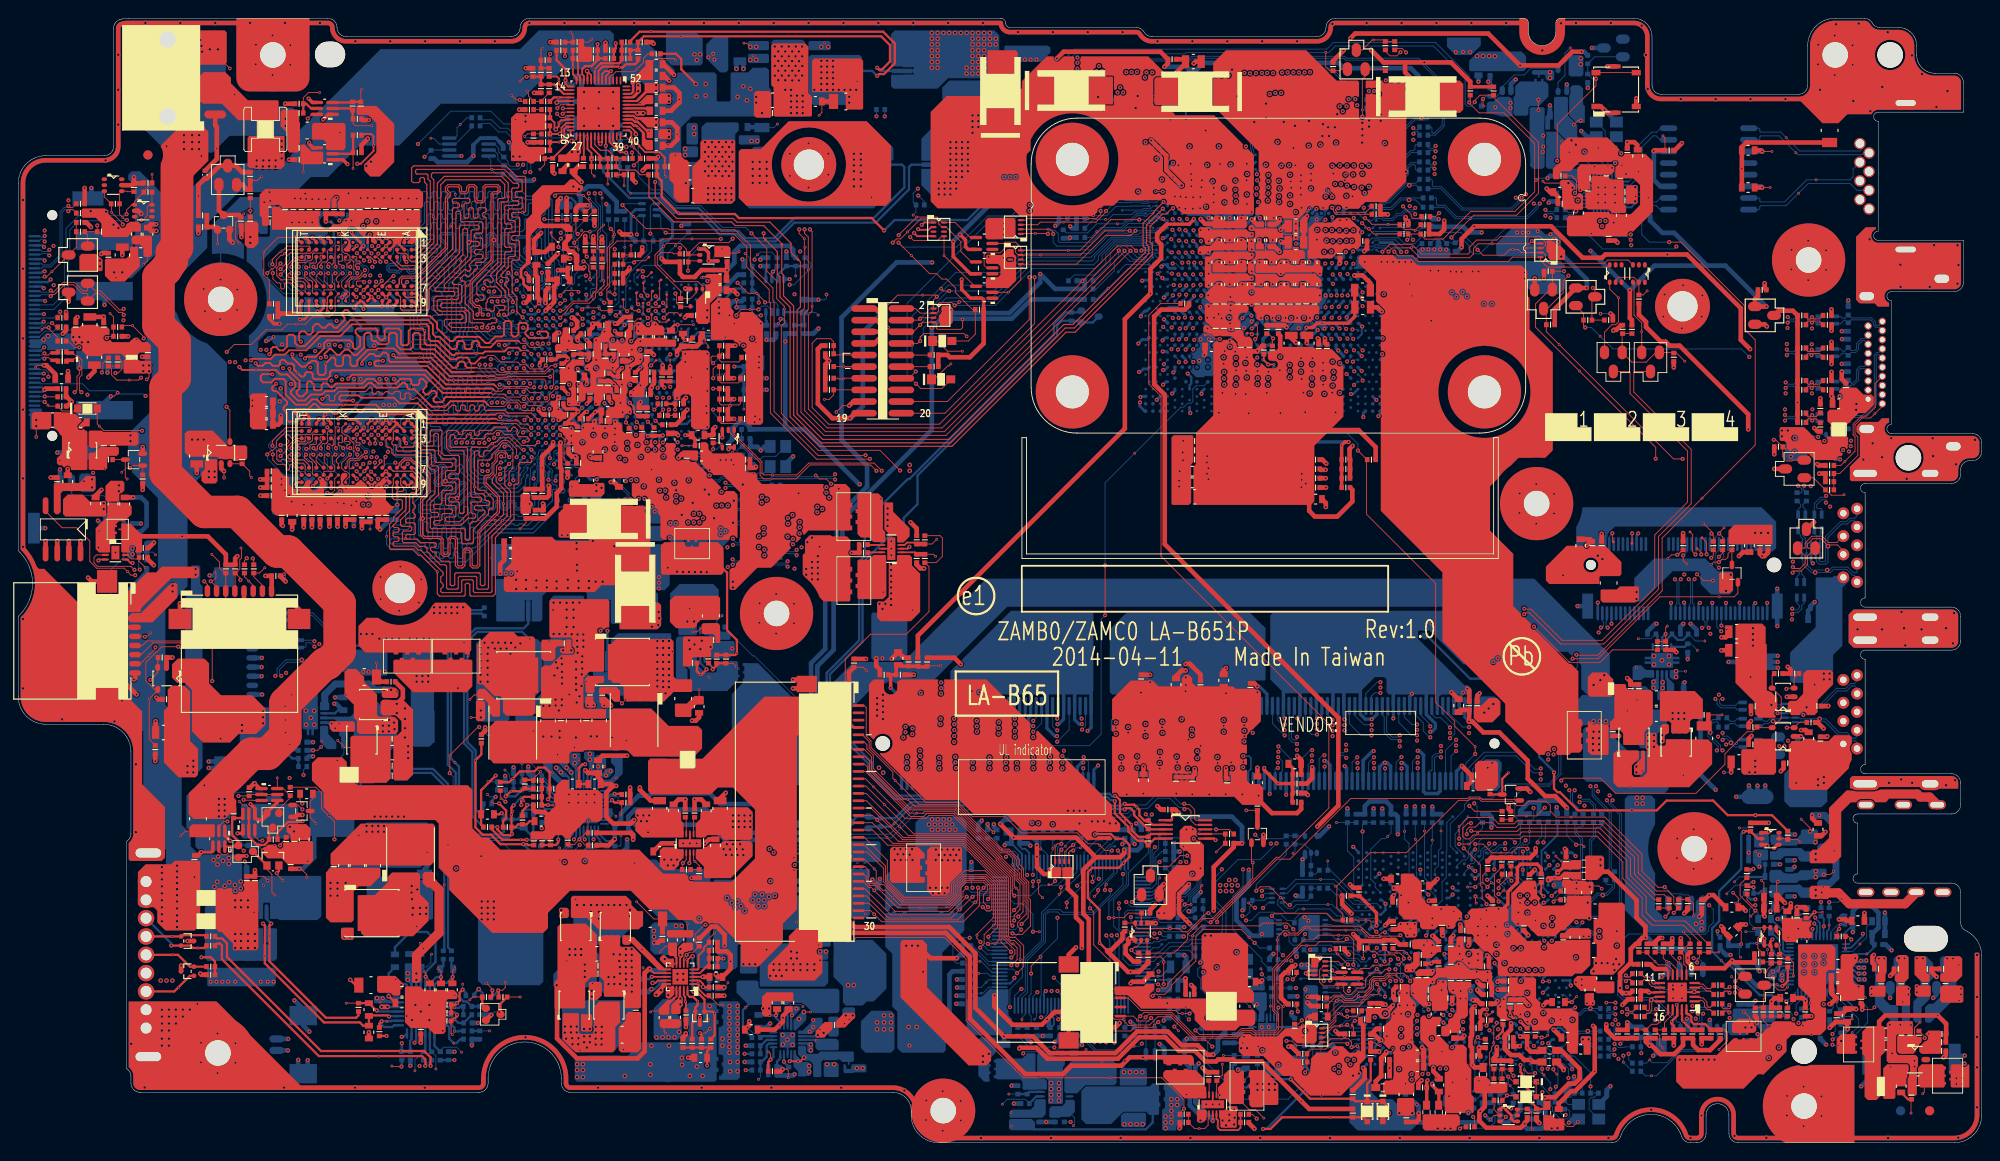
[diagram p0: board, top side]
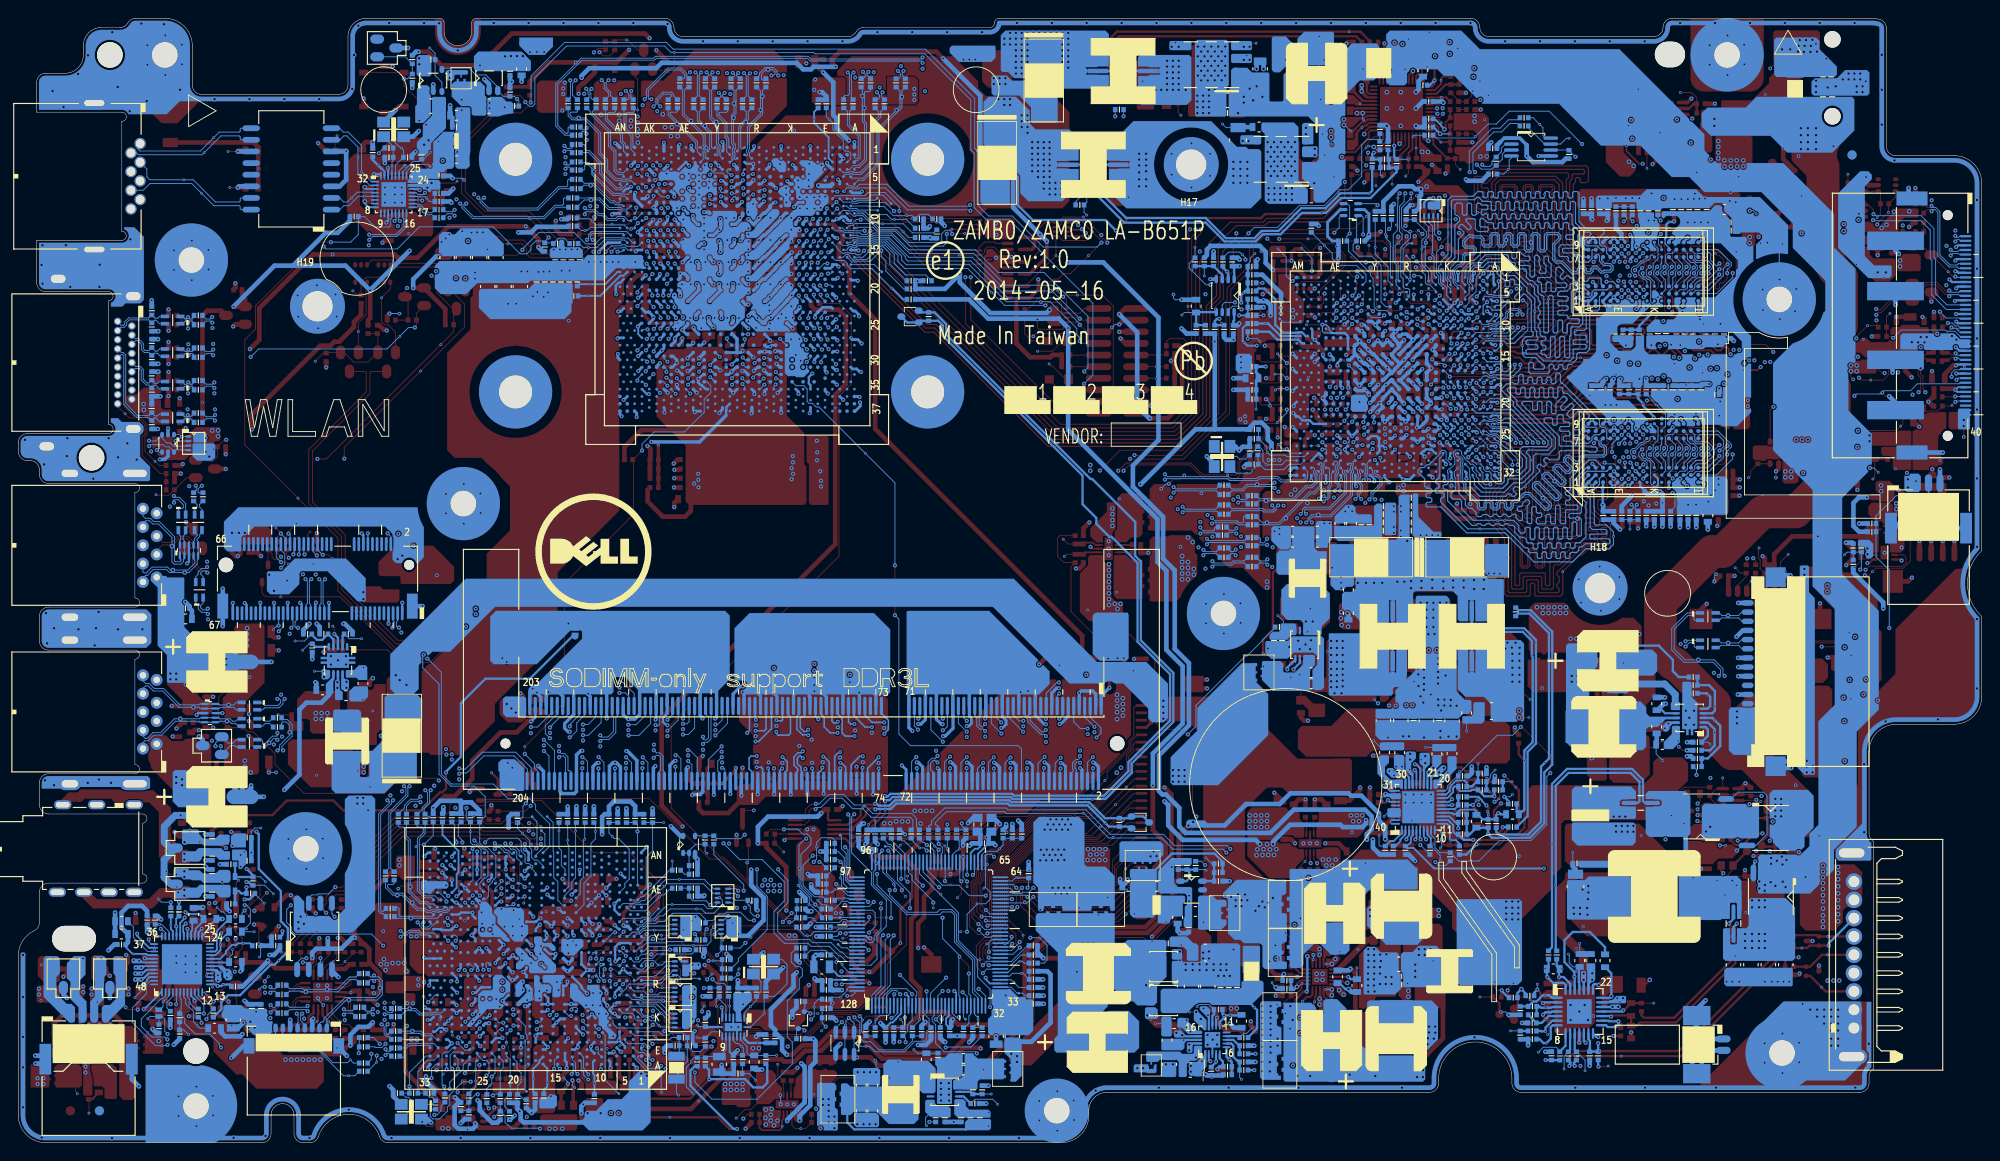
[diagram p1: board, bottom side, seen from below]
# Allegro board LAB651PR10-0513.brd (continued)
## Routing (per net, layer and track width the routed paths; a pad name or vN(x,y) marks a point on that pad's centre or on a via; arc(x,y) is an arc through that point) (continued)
LG_3V: length 3.6
  TOP w0.635: 66.6,22.15 67.07,22.15 v1(68.11,21.12) 69.29,19.93
LG_5V: length 5.8
  IN3 w0.762: 69.12,15.61 68.93,15.42 63.43,15.42
  vias: v1(62.69,17.4) v2(62.62,16.59) v2(62.62,15.96) v2(69.67,16.17) v2(70.16,16.65)
LG_+1.05VSP: length 6
  IN3 w1.016: 181.03,49.84 181.03,48.62 179.66,47.25 179.66,45.44
  BOTTOM w0.102: v2(181.03,51.49) v1(182.06,51.49)
  vias: v2(179.51,44.51) v2(179.51,43.87) v2(181.03,50.86)
LG_+1.35VGPUP: length 9
  BOTTOM w0.762: 33.46,47.93 33.46,48.95 34.6,50.09 38.28,50.09 38.92,49.46 v2(39.93,49.46) v2(40.7,49.46)
  vias: v1(41.34,49.29)
LGATE1: length 11
  IN3 w0.762: 60.13,52.89 60.13,46.16 60,46.03 60,42.98 v2(60.76,42.22)
  vias: v1(61.19,41.83) v2(59.49,53.78) v2(60.38,53.78) v2(60.76,41.46)
LGATE2: length 3.9
  IN3 w0.762: 61.78,46.99 61.78,43.49 62.03,43.24
  vias: v1(62.46,40.77) v2(62.41,42.47) v2(62.41,41.84) v3(62.16,47.78) v3(62.82,47.78)
LGATE_APU1: length 24.3
  TOP w0.203: v2(67.7,114.84) 67.02,114.16 PU500.49
  IN3 w1.016: 67.79,116.56 67.8,116.58 67.8,119.78 68.98,120.96 86.16,120.96
  BOTTOM w0.203: v2(67.7,114.84) v2(67.7,115.47)
  vias: v1(88.06,120.13) v2(87.69,119.69) v2(88.45,119.69)
LGATE_NB1: length 11.1
  IN3 w1.016: 70.34,112.86 70.57,112.63 76.84,112.63 79.43,110.04
  BOTTOM w0.102: v1(67.49,111.7) 67.6,111.8 v2(67.6,112.45)
  vias: v2(68.23,112.45) v2(80.07,109.4) v2(80.7,109.4)
LID_SW#: length 139.6
  TOP w0.102: v1(14.47,55.68) 14.04,55.25 v3(13.82,55.25) 13.77,55.3 JLED.4
  IN1 w0.114: v3(124.64,22.89) 123.98,23.55 120.73,23.55 119.25,25.04 118.52,25.04 117.95,24.46 114.78,24.46 114.04,25.2 110.34,25.2 109.71,25.84 108.19,25.84 107.46,25.1 101.03,25.1 98.39,27.74 97.6,27.74 92.52,32.82 84.74,32.82 81.35,36.21 77.02,36.21 75.37,34.57 70.04,34.57 69.07,33.6 64.86,33.6 62.9,31.64 59.18,31.64 59.02,31.49 52.44,31.49 52.26,31.49 47.57,36.17 47.57,38.2 46.71,39.07 28.54,39.07 21.99,45.62 21.99,47.77 21.98,47.78 21.98,50.48 19.4,53.06 17.89,53.06 15.7,55.25 v3(13.82,55.25)
  BOTTOM w0.102: UE1.115 123.85,21.79 124.01,21.95 124.59,21.95 124.8,22.15 125.33,22.15 RE71.2 125,22.53 v3(124.64,22.89)
LINE1-L: length 6.7
  BOTTOM w0.102: CA67.1 191.38,24.57 192.03,25.21 192.23,25.21 v1(192.69,25.67)
  BOTTOM w0.203: UA1.22 192.89,20.89 192.72,21.06 192.72,23.11 CA67.1
LINE1-R: length 3.8
  BOTTOM w0.203: CA68.1 192.32,22.1 v1(192.32,21.61) 192.32,21.02 192.86,20.49 UA1.21
LINE1-VREFO-L: length 14.1
  IN3 w0.254: v3(196.22,24.59) 196.15,24.66 195.91,24.66 195.39,25.18 193.03,25.18 189.73,28.48 v3(189.49,28.48)
  BOTTOM w0.102: v1(186.56,27.18) 187.5,28.12 RA165.1
  BOTTOM w0.203: UA1.31 196.73,24.01 196.22,24.52 v3(196.22,24.59)
  BOTTOM w0.254: RA165.1 188.93,28.12 189.29,28.48 v3(189.49,28.48)
LINE1-VREFO-R: length 12
  IN3 w0.254: v3(189.69,26.57) 191.09,26.57 192.87,24.79 195.23,24.79 196.09,23.93 v3(196.12,23.93)
  BOTTOM w0.102: 188.58,27.18 v1(187.55,26.15)
  BOTTOM w0.203: v3(196.12,23.93) 196.4,23.65 196.4,23.02 196.33,22.94 UA1.30
  BOTTOM w0.254: RA166.1 188.58,27.16 189.16,26.57 v3(189.69,26.57)
LINE-IN-L: length 16.3
  TOP w0.254: v3(189.46,29.9) 189.41,29.85 RA80.2
  IN3 w0.254: v3(189.46,29.9) 189.87,29.49 192.96,29.49 196.16,26.29 v3(196.86,26.29)
  BOTTOM w0.102: v1(187.41,28.49) 187.95,29.04 RA165.2
  BOTTOM w0.254: v3(189.46,29.9) 188.78,29.21 RA165.2 188.8,29.01 190.67,29.01 LA8.2 RA83.1 ; RA55.2 v3(196.86,26.29)
LINE-IN-R: length 18
  TOP w0.254: v3(189.49,27.89) 189.44,27.94 188.91,27.94 RA82.2
  IN3 w0.254: v3(197.75,26.27) 197.21,25.73 196.07,25.73 192.77,29.04 189.27,29.04 189.01,28.77 189.01,28.17 189.29,27.89 v3(189.49,27.89)
  BOTTOM w0.102: v1(199.13,26.62) 198.77,26.27 v3(197.75,26.27)
  BOTTOM w0.254: v3(189.49,27.89) RA166.2 190.06,27.23 190.32,27.49 LA9.2 RA84.1 ; RA56.2 v3(197.75,26.27)
LPC_AD0: length 58.8
  IN3 w0.135: v3(117.59,13.67) 117.62,13.67 118.37,12.92 118.87,12.92 119.79,11.99 121.09,11.99 121.75,11.33 124.87,11.33 126.12,10.08 128.48,10.08 131.02,7.55 136.87,7.55 139.53,4.89 144.39,4.89 144.97,5.47 155.1,5.47 156.39,6.76 163.89,6.76 164.24,7.12 166.12,7.12 167.01,8.01 v3(167.01,8.08)
  BOTTOM w0.102: U2.D27 165.9,9.77 166.03,9.9 166.92,9.9 167.23,9.58 167.23,8.3 v3(167.01,8.08) ; UE1.10 v3(117.59,13.67)
LPC_AD1: length 56.4
  TOP w0.102: v3(166.4,8.06) 166.4,7.6 v1(166.6,7.4)
  IN3 w0.135: v3(119.06,13.63) 119.17,13.75 120.28,13.75 122.13,11.89 125.09,11.89 126.36,10.62 128.7,10.62 130.6,8.73 136.45,8.73 139.75,5.42 144.16,5.42 144.75,6.01 154.88,6.01 156.26,7.39 157.84,7.39 158.94,8.49 162.91,8.49 163.35,8.05 163.9,8.05 163.99,7.95 165.37,7.95 165.46,8.05 166.39,8.05 v3(166.4,8.06)
  BOTTOM w0.102: U2.C28 166.38,9.1 166.38,8.08 v3(166.4,8.06) ; v3(119.06,13.63) 118.92,13.63 118.39,14.16 UE1.8
LPC_AD2: length 58.3
  TOP w0.102: v3(165.64,7.6) 164.81,7.6 v1(164.45,7.97)
  IN3 w0.135: v3(165.64,7.6) 165.59,7.65 163.91,7.65 163.79,7.78 162.02,7.78 161.36,7.12 156.37,7.12 154.99,5.74 144.86,5.74 144.28,5.16 139.64,5.16 136.34,8.46 130.49,8.46 128.59,10.35 126.23,10.35 124.97,11.61 121.85,11.61 121.19,12.27 119.92,12.27 119.01,13.19 118.82,13.19 118.55,13.45 118.55,16.01 v3(118.75,16.21)
  BOTTOM w0.102: v3(165.64,7.6) 165.28,7.96 165.28,8.39 U2.A26 ; UE1.7 118.79,16.17 v3(118.75,16.21)
LPC_AD3: length 63.3
  TOP w0.102: v3(167.62,8.03) 167.62,7.86 v1(168.01,7.47)
  IN3 w0.135: v3(118.09,16.21) 118.09,16.13 117.1,15.14 117.1,13.49 117.94,12.65 118.72,12.65 119.68,11.69 120.2,11.69 121.55,10.34 125.48,10.34 126.01,9.81 128.37,9.81 131.56,6.62 133.27,6.62 134.78,5.1 137.35,5.1 137.84,4.62 144.55,4.62 145.13,5.2 155.22,5.2 156.47,6.46 163.96,6.46 164.29,6.13 165.21,6.13 165.52,6.44 166.06,6.44 167.62,8.01 v3(167.62,8.03)
  BOTTOM w0.102: v3(167.62,8.03) 167.62,8.54 U2.A29 ; v3(118.09,16.21) 118.5,16.62 119.03,16.62 119.59,16.05 UE1.5
LPC_CLK1: length 6.2
  TOP w0.102: v3(163.28,7.32) 162.99,7.6 162.99,7.97 CH17.1 162.94,8.04 RH130.1 RH118.2
  BOTTOM w0.102: U2.D25 164.3,9.61 163.66,8.97 163.25,8.97 162.99,8.71 162.99,7.6 v3(163.28,7.32)
LPC_FRAME#: length 67.2
  IN3 w0.135: v3(169.27,7.07) 169.12,6.91 166.91,6.91 166.17,6.17 165.63,6.17 165.32,5.86 164.18,5.86 163.86,6.18 156.57,6.18 155.33,4.93 145.25,4.93 144.66,4.35 137.72,4.35 137.24,4.84 134.67,4.84 133.16,6.35 131.45,6.35 130.08,7.73 128.91,7.73 127.43,9.21 126.2,9.21 125.33,10.07 121.43,10.07 120.1,11.41 119.58,11.41 118.61,12.38 117.83,12.38 116.82,13.39 116.82,16.23 v3(116.8,16.21)
  BOTTOM w0.102: v3(116.8,16.21) 117.4,16.82 119.11,16.82 119.99,15.94 UE1.4 ; v3(169.27,7.07) 169.27,8.08 168.78,8.57 U2.A31
LX_1.1V:
  vias: v1(118.32,8.83)
LX_1.5V:
  vias: v1(204.44,8.28)
LX_1.8V:
  vias: v1(89.05,24.1)
LX_3V: length 8.9
  IN1 w0.762: 71.76,21.76 71.76,22.13 69.96,23.93 63.94,23.93
  vias: v1(60.88,26.57) v2(61.02,25.96) v2(61.78,25.96) v2(62.54,25.96) v2(62.52,25.2) v2(62.52,24.49) v2(63.18,25.96) v2(63.4,25.2) v2(63.4,24.46) v2(63.81,25.96) v2(64.45,25.96) v2(65.08,25.96) v2(65.72,25.96) v2(66.41,25.96) v2(66.78,25.43) v2(66.78,24.74) v2(72.3,21.16) v2(72.3,20.53)
LX_5V: length 8.1
  IN1 w0.762: 65.46,12.37 70.97,12.37 72.42,13.82 72.42,14.33
  vias: v1(61.35,10.1) v2(59.68,12.68) v2(59.67,12.02) v2(59.82,11.36) v2(60.34,12.68) v2(60.34,12.04) v2(60.48,11.41) v2(60.51,10.75) v2(60.98,12.68) v2(60.98,12.04) v2(61.14,10.75) v2(61.17,11.41) v2(61.78,11.61) v2(61.78,10.98) v2(62.08,10.39) v2(62.41,11.61) v2(62.41,10.98) v2(63.05,12.65) v2(63.05,12.02) v2(63.05,11.36) v2(63.05,10.72) v2(63.71,12.65) v2(63.71,12.02) v2(63.68,11.36) v2(63.68,10.72) v2(72.3,15.73) v2(72.3,15.09)
LX_CHG: length 5.4
  IN1 w1.016: 42.53,19.71 42.53,23.85
  BOTTOM w0.254: PU700.23 42.94,17.37 v2(42.53,17.78)
  vias: v1(43.5,23.63) v2(42.53,18.5) v2(42.94,27.32) v2(42.96,28.03) v2(42.98,26.6) v2(43.05,24.9) v2(43.08,25.63) v2(43.58,27.65) v2(43.86,25.65) v2(43.87,24.97) v2(44.53,25) v2(44.56,25.66)
LX_PCIE:
  vias: v1(73.31,58.32) v2(73.06,56.93) v2(73.79,56.93)
M_BA0: length 74.3
  TOP w0.102: v3(33.03,75.85) 33.03,76.13 33.28,76.38 33.66,76.38 33.77,76.49 33.77,77.61 33.88,77.72 UV6.M2 ; UV7.M2 33.88,97.53 33.77,97.42 33.77,96.31 33.66,96.19 33.28,96.19 33.03,95.94 33.03,95.7 v3(33.06,95.67) ; 51.01,85.75 51.24,85.98 51.95,85.98 52.69,85.25 54.57,85.25 54.84,84.97 55.45,84.97 55.92,84.51 57.23,84.51 57.6,84.88 v3(57.6,84.9)
  TOP w0.203: 51.01,85.75 50.5,85.75 49.84,85.09 49.47,85.09 49.26,85.3 49.26,85.49 49,85.75 48.01,85.75 47.82,85.57 47.18,85.57 45.64,87.1 44.61,87.1 44.35,87.35 v1(44.35,88.7) 44.13,88.92 42.88,88.92 42.63,88.67 42.63,87.28 42.45,87.1 41.94,87.1 41.79,87.25 41.79,88.65 41.51,88.92 40.21,88.92 40.01,88.72 40.01,87.86 39.81,87.66 39.56,87.66 39.22,88 39.22,88.72 39.02,88.92 37.04,88.92 36.83,88.72 36.83,88.43 37.32,87.94 37.32,87.05 36.95,86.68 36.72,86.68 36.56,86.85 36.56,87.28 36.2,87.63 33.71,87.63 33.38,87.3 33.38,86.75 32.47,85.83 31.48,85.83 v3(31.3,85.65)
  IN3 w0.135: v3(33.06,95.67) 33.43,95.3 33.43,94.8 33.36,94.72 33.36,93.71 31.55,91.9 31.55,85.91 v3(31.3,85.65) 31.33,85.65 31.33,85.65 31.33,80.22 31.59,79.96 31.59,79.76 31.65,79.7 31.65,78.63 33.12,77.16 33.12,75.94 v3(33.03,75.85)
  BOTTOM w0.102: v3(33.06,95.67) 33.06,95.5 33.43,95.13 33.43,94.75 33.73,94.44 33.73,93.37 34.15,92.96 UV8.M2 ; v3(57.6,84.9) 57.89,84.61 57.89,84.41 UV1.J16 ; UV5.M2 34.15,73.14 33.73,73.56 33.73,74.63 33.43,74.94 33.43,75.32 33.03,75.72 v3(33.03,75.85)
M_BA1: length 76.4
  TOP w0.102: v3(34.63,75.15) 34.49,75.15 34.32,74.99 34.32,74.12 34.55,73.9 34.55,73.46 34.41,73.33 33.42,73.33 33.35,73.26 UV6.N8 ; UV7.N8 33.35,93.07 33.42,93.14 34.41,93.14 34.55,93.27 34.55,93.71 34.32,93.93 34.32,94.8 34.49,94.96 v3(34.63,94.96) ; 49.87,84.64 50.09,84.64 50.15,84.59 52.08,84.59 52.53,84.14 53.08,84.14 53.14,84.2 57.46,84.2 58.13,84.87 v3(58.64,84.87)
  TOP w0.203: 49.87,84.64 49.01,84.64 48.81,84.84 48.81,85.09 48.6,85.3 48.2,85.3 47.99,85.09 47.99,84.84 47.79,84.64 47.46,84.64 45.45,86.64 44.1,86.64 43.9,86.85 43.9,88.24 43.69,88.45 43.29,88.45 43.08,88.24 v1(43.08,87.49) 43.08,86.9 42.83,86.64 41.75,86.64 41.33,87.06 41.33,88.24 41.13,88.45 40.67,88.45 40.47,88.24 40.47,87.43 40.24,87.2 39.37,87.2 39.02,87.55 38.77,87.55 38.56,87.76 38.56,88.24 38.36,88.45 37.98,88.45 37.78,88.24 37.78,86.86 36.95,86.03 36.64,86.03 36.06,86.62 35.66,86.62 35.09,86.05 34.8,86.05 34.18,86.67 33.95,86.67 33.44,86.16 33.44,85.98 v3(33.61,85.81)
  IN3 w0.135: v3(34.63,94.96) 34.58,94.91 34.58,94.49 34.42,94.34 34.42,93.34 33.08,91.99 33.08,90.28 32.92,90.12 32.75,90.12 32.62,90 32.62,89.64 32.75,89.51 33.03,89.51 33.15,89.39 33.15,87.79 33.38,87.56 33.38,86.77 33.51,86.64 34.27,86.64 34.37,86.55 34.37,86.36 34.07,86.06 33.86,86.06 v3(33.61,85.81) 33.51,85.7 33.51,85.17 32.6,84.27 32.6,80.18 32.71,80.07 32.71,79.77 33.28,79.2 33.28,78.92 33.61,78.59 33.9,78.59 34.14,78.34 34.14,77.28 34.27,77.15 34.27,75.51 v3(34.63,75.15)
  BOTTOM w0.102: UV8.N8 33.74,97.14 34.29,97.14 34.53,96.9 34.53,96.11 34.25,95.82 34.25,95.51 34.49,95.27 34.49,95.1 v3(34.63,94.96) ; UV1.L15 58.87,85.1 v3(58.64,84.87) ; v3(34.63,75.15) 34.49,75.29 34.49,75.46 34.3,75.65 34.3,76.06 34.53,76.3 34.53,77.09 34.29,77.33 33.74,77.33 UV5.N8
M_BA2: length 64.8
  TOP w0.102: UV6.M3 34.29,76.92 34.4,76.81 34.4,76.23 34.3,76.13 34.19,76.13 34.02,76.31 33.89,76.31 33.74,76.15 33.74,75.99 v3(33.86,75.87) ; UV7.M3 34.29,96.73 34.4,96.63 34.4,96.04 34.3,95.94 34.19,95.94 34.02,96.12 33.89,96.12 33.74,95.97 33.74,95.78 v3(33.85,95.67)
  IN1 w0.102: 51.56,88.03 51.87,88.35 v3(56.06,88.35)
  IN1 w0.216: 51.56,88.03 49.54,88.03 48.58,88.99 35.81,88.99 34.85,88.03 29.47,88.03 29.27,87.82 29.27,87.32 29.47,87.11 30.25,87.11 30.35,87.01 31.21,87.01 31.55,87.35 32.19,87.35 32.37,87.18 32.37,86.51 v3(32.41,86.46)
  IN3 w0.135: v3(33.86,75.87) 33.91,75.93 33.91,77.04 33.81,77.14 33.81,77.43 32.38,78.86 32.38,79.93 32.27,80.04 32.27,84.41 32.33,84.48 32.33,86.39 v3(32.41,86.46) 32.26,86.61 32.26,87.48 32.4,87.61 32.64,87.61 32.77,87.75 32.77,87.99 32.64,88.13 32.4,88.13 32.26,88.26 32.26,88.51 32.4,88.64 32.64,88.64 32.77,88.78 32.77,89.02 32.64,89.16 32.4,89.16 32.26,89.29 32.26,91.66 34.07,93.46 34.07,94.47 34.23,94.63 34.23,95.28 v3(33.85,95.67)
  BOTTOM w0.102: v3(33.85,95.67) 33.85,95.55 34.23,95.17 34.23,94.78 34.15,94.7 UV8.M3 ; UV5.M3 34.15,74.88 34.23,74.97 34.23,75.36 33.86,75.73 v3(33.86,75.87) ; UV1.G11 56.4,88.01 v3(56.06,88.35)
M_CAS#0: length 49.1
  TOP w0.102: v3(36.25,75.86) 36.19,75.8 35.95,75.8 35.87,75.87 35.87,76.13 36.02,76.28 36.15,76.28 36.23,76.36 36.23,76.46 36.1,76.59 35.69,76.59 35.62,76.66 35.62,76.79 UV6.K3
  IN1 w0.102: v3(56.08,81.3) 55.77,81.62 54.87,81.62 54.77,81.51 53.45,81.51 53.13,81.83
  IN1 w0.216: v3(35.36,83.37) 35.36,83.14 35.57,82.94 37.7,82.94 37.9,83.14 37.9,83.28 38.08,83.46 38.63,83.46 38.84,83.24 38.84,83.11 39.02,82.94 41.49,82.94 41.7,83.15 41.7,83.21 41.91,83.42 42.21,83.42 42.43,83.21 42.43,83.15 42.64,82.94 42.94,82.94 43.15,83.15 43.15,83.21 43.36,83.42 43.66,83.42 43.87,83.21 43.87,83.15 44.09,82.94 50.94,82.94 52.05,81.83 53.13,81.83
  IN3 w0.102: 35.36,80.32 36.23,79.46 36.23,78.9 35.77,78.44 35.77,77.96 36.22,77.5 36.22,75.88 v3(36.25,75.86)
  IN3 w0.254: 35.36,80.32 35.36,81.89 35.72,82.25 41.38,82.25 41.59,82.45 41.59,82.73 41.38,82.94 35.62,82.94 35.36,83.19 v3(35.36,83.37)
  BOTTOM w0.102: UV1.G19 56.4,81.62 v3(56.08,81.3) ; UV5.K3 35.75,74.2 36.27,74.72 36.38,74.72 36.62,74.96 36.62,75.49 v3(36.25,75.86)
M_CAS#1: length 49.1
  TOP w0.102: UV7.K3 35.62,96.6 35.62,96.47 35.69,96.4 36.1,96.4 36.23,96.27 36.23,96.17 36.15,96.09 36.02,96.09 35.87,95.94 35.87,95.69 35.95,95.61 36.19,95.61 v3(36.25,95.67)
  IN1 w0.102: v3(56.11,84.9) 56.04,84.97 54.68,84.97 54.5,85.15 54.43,85.15
  IN1 w0.216: v3(38.41,85.09) 38.59,84.92 41.72,84.92 41.93,85.13 41.93,85.45 42.13,85.65 42.45,85.65 42.65,85.45 42.65,85.13 42.87,84.92 43.17,84.92 43.38,85.13 43.38,85.45 43.58,85.65 43.9,85.65 44.1,85.45 44.1,85.13 44.31,84.92 44.61,84.92 44.83,85.13 44.83,85.42 45.03,85.63 45.35,85.63 45.55,85.42 45.55,84.56 45.75,84.36 46.07,84.36 46.27,84.56 46.27,85.31 46.49,85.53 46.79,85.53 47,85.31 47,84.61 47.2,84.41 47.52,84.41 47.72,84.61 47.72,85.31 47.93,85.53 48.23,85.53 48.44,85.31 48.44,84.54 48.64,84.35 48.99,84.35 49.21,84.56 49.21,85.45 49.41,85.65 49.71,85.65 49.92,85.45 49.92,84.57 50.15,84.35 51.82,84.35 52.03,84.55 52.03,85.44 52.17,85.58 52.43,85.58 52.86,85.15 54.43,85.15
  IN3 w0.102: v3(36.25,95.67) 36.27,95.67 36.61,95.33 36.61,94.14 36.12,93.65 36.12,91.9 35.87,91.65 35.87,90.43
  IN3 w0.254: v3(38.41,85.09) 37.9,85.6 37.29,85.6 37.12,85.43 36.83,85.43 36.51,85.75 36.51,86.04 36.87,86.4 38.01,86.4 38.33,86.72 38.33,87.96 35.87,90.43
  BOTTOM w0.102: v3(36.25,95.67) 36.62,95.3 36.62,94.77 36.38,94.53 36.27,94.53 35.75,94.01 UV8.K3 ; UV1.G16 56.4,84.32 56.11,84.61 v3(56.11,84.9)
M_CKE0: length 53.1
  TOP w0.102: v3(36.22,75.14) 36.22,75.13 35.31,74.22 35.31,73.67 35.67,73.32 35.84,73.32 36.18,72.98 36.18,72.77 35.75,72.34 UV6.K9
  IN1 w0.102: 53.02,81.36 53.55,80.83 57.31,80.83 v3(57.99,80.14)
  IN1 w0.216: v3(34.73,83.7) 34.7,83.72 31.21,83.72 30.51,84.43 30.22,84.43 30.01,84.21 30.01,83.92 31.15,82.78 33.7,82.78 34.01,82.47 50.75,82.47 51.85,81.36 53.02,81.36
  IN3 w0.102: 35.34,79.61 35.34,79.07 35.46,78.95 35.46,77.83 35.87,77.43 35.87,75.5 v3(36.22,75.14)
  IN3 w0.254: v3(34.73,83.7) 34.73,80.22 35.34,79.61
  BOTTOM w0.102: UV5.K9 35.34,78.11 35.34,76.74 35.87,76.21 35.87,75.62 36.22,75.26 v3(36.22,75.14) ; v3(57.99,80.14) 58.55,80.7 UV1.K20
M_CKE1: length 54.6
  TOP w0.102: 52.15,83.27 52.36,83.27 52.48,83.39 57.38,83.39 57.6,83.18 v3(57.6,82.5) ; UV7.K9 35.75,92.15 36.18,92.58 36.18,92.79 35.84,93.13 35.67,93.13 35.31,93.48 35.31,94.03 36.22,94.94 v3(36.22,94.96)
  TOP w0.203: v3(37.52,85.07) 37.52,85.31 38.36,86.15 38.79,86.15 39.03,85.91 39.45,85.91 39.83,86.29 40.14,86.29 40.43,86 40.43,85.47 40.62,85.27 44.89,85.27 46.89,83.27 52.15,83.27
  IN3 w0.102: v3(36.22,94.96) 36.22,94.18 35.82,93.78 35.82,92.18 35.36,91.72 35.36,91.44
  IN3 w0.254: v3(37.52,85.07) 37.75,84.84 37.75,84.59 37.6,84.43 36.12,84.43 35.66,83.98 35.13,83.98 34.93,84.18 34.7,84.18 34.54,84.35 34.54,85.16 34.73,85.35 35.01,85.35 35.34,85.02 35.69,85.02 35.95,85.27 35.95,85.5 35.44,86.01 35.44,86.31 35.65,86.53 36.19,86.53 36.57,86.91 37.62,86.91 37.83,87.11 37.83,87.46 37.62,87.66 36.53,87.66 36.33,87.86 36.33,88.09 36.68,88.45 36.68,88.9 36.52,89.06 36.2,89.06 35.72,88.58 35.36,88.58 35.16,88.78 35.16,89.16 35.64,89.64 35.64,89.94 35.36,90.22 35.36,90.64 35.36,91.44
  BOTTOM w0.102: UV1.J17 57.95,83.05 57.95,83.04 57.6,82.69 v3(57.6,82.5) ; UV8.K9 35.72,98.31 35.72,98.03 35.34,97.65 35.34,96.55 35.87,96.02 35.87,95.43 36.22,95.08 v3(36.22,94.96)
M_CLK0: length 59.9
  TOP w0.102: v3(37.95,74.86) 37.91,74.9 37.6,74.9 37.23,74.53 36.29,74.53 36.12,74.37 36.12,73.72 36.23,73.61 36.44,73.61 UV6.J7
  IN1 w0.102: 36.22,78.62 36.2,78.6 36.06,78.6 35.67,78.2 35.67,77.61 36.74,76.53 37.15,76.53 37.66,76.03 37.95,76.03 38.36,75.62 38.36,75.27 v3(37.95,74.86) 37.61,74.86 37.28,74.53 36.71,74.53 36.46,74.27 36.46,74.11 ; v3(57.61,76.43) 57.61,76.41 57.26,76.05 57.26,75.65 57.28,75.62 57.28,75.59
  IN1 w0.14: 36.22,78.62 36.62,79.01 36.96,79.35 39.12,79.35 39.63,79.86 40.87,79.86 41.28,79.46 48.58,79.46 50.13,77.91 51.95,77.91 52.02,77.83 52.71,77.83 53,77.54 53,77.08 51.92,76 51.92,71.58 52.51,71 55.61,71 55.89,71.27 55.89,71.99 55.61,72.27 54.9,72.27 54.74,72.42 54.74,72.91 54.14,73.51 54.14,73.69 54.51,74.07 54.69,74.07 55.65,73.11 56.22,73.11 57.28,74.17 57.28,75.59 ; v3(38.24,69.69) 38.06,69.88 38.06,70.11 37.01,71.15 37.01,71.68 36.46,72.24 36.46,74.11
  BOTTOM w0.102: UV1.H26 57.2,76.1 57.54,76.43 v3(57.61,76.43) ; UV5.J7 36.98,76.49 37.2,76.49 37.86,75.82 38.11,75.82 38.33,75.6 38.33,75.24 37.95,74.85 v3(37.95,74.86)
  BOTTOM w0.112: v3(38.24,69.69) 38.07,69.51 38.07,69.31 RV48.1
M_CLK1: length 61.8
  TOP w0.102: v3(37.85,94.7) 37.61,94.7 37.26,94.35 36.39,94.35 36.1,94.05 36.1,93.53 36.23,93.4 36.41,93.4 UV7.J7
  IN1 w0.102: 37.18,96.24 37.19,96.24 37.23,96.21 37.27,96.21 37.29,96.19 37.3,96.19 37.56,95.94 37.85,95.94 38.23,95.56 38.23,95.08 v3(37.85,94.7) 37.61,94.7 37.08,94.16 36.46,94.16 36.43,94.14 36.4,94.14 ; 54.36,89.59 54.59,89.59 54.67,89.67 55.56,89.67 55.64,89.59 56.21,89.59 56.42,89.8 56.42,90.18 56.3,90.3 56.13,90.3 56.01,90.18 v3(56.01,90.01)
  IN1 w0.14: 36.4,94.14 27.31,94.14 27.18,94.01 27.18,93.58 28.05,92.71 28.91,92.71 29.64,93.45 33.16,93.45 33.92,92.69 34.34,92.69 34.52,92.87 34.52,93.17 34.8,93.45 35.9,93.45 36.18,93.17 36.18,92.21 36.46,91.93 38.21,91.93 39.27,90.86 48.9,90.86 49.94,89.82 52.97,89.82 53.19,89.59 54.36,89.59 ; 37.18,96.24 36.86,96.24 36.53,96.58 36.53,98.12 37.6,99.19 37.8,99.19 38.69,100.08 38.69,100.32 38.99,100.62 v3(39.08,100.62)
  BOTTOM w0.102: UV1.G9 56.4,89.89 56.28,90.01 v3(56.01,90.01) ; v3(37.85,94.7) 38.26,95.1 38.26,95.46 37.98,95.74 37.76,95.74 37.2,96.3 36.98,96.3 UV8.J7
  BOTTOM w0.112: RV54.1 38.77,101.05 38.77,100.84 38.99,100.62 v3(39.08,100.62)
M_CLK#0: length 60.4
  TOP w0.102: UV6.K7 35.92,73.9 35.92,74.45 36.21,74.74 37.15,74.74 37.51,75.1 37.62,75.1 v3(37.95,75.44)
  IN1 w0.102: 36.2,74.11 36.2,74.12 36.23,74.15 36.23,74.2 36.25,74.22 36.25,74.36 36.62,74.73 37.19,74.73 37.52,75.06 37.57,75.06 v3(37.95,75.44) 37.98,75.46 37.98,75.72 37.87,75.82 37.57,75.82 37.06,76.33 36.66,76.33 35.46,77.53 35.46,78.29 35.98,78.8 36.04,78.8 36.06,78.82 ; v3(57.63,77.26) 57.18,76.81 57.18,76.26 57.05,76.14 57.05,75.65 57.03,75.62 57.03,75.59
  IN1 w0.14: v3(37.66,69.69) 37.8,69.83 37.8,70 36.76,71.04 36.76,71.58 36.2,72.14 36.2,74.11 ; 57.03,75.59 57.03,74.28 56.11,73.36 55.76,73.36 54.8,74.32 54.41,74.32 53.88,73.8 53.88,73.41 54.49,72.8 54.49,72.32 54.79,72.01 55.51,72.01 55.63,71.89 55.63,71.38 55.51,71.25 52.61,71.25 52.18,71.69 52.18,75.9 53.26,76.97 53.26,77.64 52.81,78.08 52.13,78.08 52.05,78.16 50.23,78.16 48.69,79.71 41.39,79.71 40.98,80.12 39.52,80.12 39.02,79.61 36.85,79.61 36.06,78.82
  BOTTOM w0.102: v3(37.95,75.44) 37.11,76.28 36.9,76.28 36.62,76.56 36.43,76.56 36.21,76.78 36.21,77.03 36.12,77.12 35.82,77.12 35.75,77.05 UV5.K7
  BOTTOM w0.112: v3(37.66,69.69) 37.85,69.5 37.85,69.3 RV49.1 ; v3(57.63,77.26) 57.27,76.9 UV1.H25
M_CLK#1: length 61.4
  TOP w0.102: UV7.K7 35.9,93.68 35.9,94.14 36.31,94.55 37.17,94.55 37.47,94.84 37.47,94.91 37.85,95.29 v3(37.85,95.29)
  IN1 w0.102: 54.36,89.34 54.37,89.34 54.41,89.37 54.45,89.37 54.47,89.39 54.68,89.39 54.75,89.46 55.48,89.46 55.56,89.39 56.29,89.39 56.7,89.79 56.7,89.87 v3(56.81,89.99) ; 37.18,95.99 37.22,95.99 37.47,95.74 37.77,95.74 37.95,95.56 37.95,95.39 v3(37.85,95.29) 37.84,95.29 37.42,94.87 37.42,94.79 37,94.37 36.46,94.37 36.43,94.39 36.4,94.39
  IN1 w0.14: 54.36,89.34 53.09,89.34 52.86,89.56 49.84,89.56 48.8,90.61 39.17,90.61 38.1,91.67 36.35,91.67 35.92,92.1 35.92,93.07 35.79,93.2 34.91,93.2 34.78,93.07 34.78,92.77 34.45,92.43 33.81,92.43 33.05,93.2 29.75,93.2 29.01,92.46 27.94,92.46 26.93,93.47 26.93,94.12 27.21,94.39 36.4,94.39 ; 37.18,95.99 36.76,95.99 36.28,96.47 36.28,98.23 37.49,99.45 37.7,99.45 38.44,100.19 38.44,100.32 38.13,100.62 v3(38.11,100.62)
  BOTTOM w0.102: v3(56.81,89.99) 57.1,89.7 UV1.H9 ; UV8.K7 35.97,96.96 36.1,96.96 36.2,96.85 36.2,96.55 36.35,96.4 36.6,96.4 36.9,96.1 37.11,96.1 37.85,95.36 v3(37.85,95.29)
  BOTTOM w0.112: v3(38.11,100.62) 38.12,100.62 38.39,100.89 38.39,101.1 RV55.1
M_CS#0: length 56.2
  TOP w0.102: v3(34.69,75.85) 34.6,75.93 34.6,78.11 34.68,78.19 34.96,78.19 35.06,78.08 35.06,77.83 UV6.L2
  TOP w0.127: v3(56.8,78.9) 56.02,79.68 53.45,79.68 53.16,79.97 51.03,79.97 50.91,80.09 50.91,80.38 50.73,80.56 50.45,80.56 50.32,80.43 50.32,80.05 50.2,79.93 49.94,79.93 49.82,80.05 49.82,80.43 49.69,80.56 49.44,80.56 49.31,80.43 49.31,80.05 49.18,79.93 48.93,79.93 48.8,80.05 48.8,80.43 48.67,80.56 48.42,80.56 48.29,80.43 48.29,80.05 48.17,79.93 47.91,79.93 47.78,80.05 47.78,80.43 47.66,80.56 47.37,80.56 46.78,79.97 44.98,79.97 43.59,81.36 43.36,81.36 43.17,81.17 42.91,81.17 42.78,81.3 v1(42.78,81.59) 42.78,81.74 42.65,81.87 42.36,81.87 42.23,81.74 42.23,81.34 42.11,81.21 41.85,81.21 41.72,81.34 41.72,81.91 41.6,82.03 41.14,82.03 40.89,81.78 40.63,81.78 40.38,82.03 40.12,82.03 39.87,81.78 39.62,81.78 39.36,82.03 39.21,82.03 38.96,81.78 38.77,81.78 38.64,81.91 38.64,82.33 38.52,82.45 38.33,82.45 37.91,82.03 35.04,82.03 34.55,81.55 34.55,81.13 34.43,81.02 34.08,81.02 33.97,81.13 33.97,81.53 33.84,81.65 33.69,81.65 33.28,81.23 v3(33.2,81.23)
  IN3 w0.102: v3(34.69,75.85) 34.65,75.89 34.65,77.23 34.47,77.41 34.47,78.48 34.2,78.74 34.2,79.47 33.87,79.81 33.87,80.12 33.75,80.24 33.53,80.24 33.43,80.14 33.43,79.99 33.33,79.89 33.11,79.89 33.04,79.96 33.04,80.28 32.95,80.37 32.95,80.65 33.08,80.78 33.71,80.78 33.87,80.94 33.87,81.49 33.75,81.61 33.46,81.61 33.33,81.74 33.33,82 33.46,82.12 33.71,82.12 33.84,82.25 33.84,82.4 33.44,82.8 33.44,83.86 33.64,84.06 33.64,84.55 33.54,84.65 33.45,84.65 32.92,84.13 32.92,81.41 33.1,81.23 v3(33.2,81.23)
  BOTTOM w0.102: v3(56.8,78.9) 57.2,79.3 UV1.H22 ; UV5.L2 34.55,73.32 34.55,74.43 35.03,74.91 35.03,75.31 34.69,75.65 v3(34.69,75.85)
M_CS#1: length 50.4
  TOP w0.102: UV7.L2 35.06,97.64 35.06,97.9 34.96,98 34.68,98 34.6,97.92 34.6,95.71 v3(34.65,95.67)
  IN1 w0.102: v3(56.11,87.25) 56.07,87.3 54.98,87.3 54.68,87.6
  IN1 w0.14: v3(34.57,87.15) 34.32,86.9 34.32,86.66 34.48,86.5 36.56,86.5 36.7,86.64 36.7,87.46 36.84,87.6 37.08,87.6 37.22,87.46 37.22,86.64 37.36,86.5 37.6,86.5 37.74,86.64 37.74,87.46 37.88,87.6 38.12,87.6 38.26,87.46 38.26,86.64 38.4,86.5 38.98,86.5 39.4,86.93 39.4,87.48 39.52,87.6 39.82,87.6 39.96,87.46 39.96,86.91 40.09,86.78 40.28,86.78 40.62,87.13 40.89,87.13 41.03,87.27 41.03,87.46 41.17,87.6 41.41,87.6 41.55,87.46 41.55,87.27 41.69,87.13 41.93,87.13 42.07,87.27 42.07,87.46 42.21,87.6 42.45,87.6 42.59,87.46 42.59,87.27 42.73,87.13 42.97,87.13 43.11,87.27 43.11,87.46 43.25,87.6 43.49,87.6 43.63,87.46 43.63,87.27 43.77,87.13 44.01,87.13 44.15,87.27 44.15,87.46 44.29,87.6 44.53,87.6 44.67,87.46 44.67,87.27 44.81,87.13 45.05,87.13 45.19,87.27 45.19,87.46 45.33,87.6 45.57,87.6 45.71,87.46 45.71,87.27 45.85,87.13 46.09,87.13 46.23,87.27 46.23,87.46 46.37,87.6 46.61,87.6 46.75,87.46 46.75,87.27 46.89,87.13 47.13,87.13 47.27,87.27 47.27,87.46 47.41,87.6 47.66,87.6 47.79,87.46 47.79,87.27 47.93,87.13 48.18,87.13 48.32,87.27 48.32,87.46 48.46,87.6 48.7,87.6 48.84,87.46 48.84,87.27 48.98,87.13 51.81,87.13 52.28,87.6 54.68,87.6
  IN3 w0.102: v3(34.65,95.67) 35.03,95.29 35.03,94.79 34.9,94.66 34.9,94.36 34.75,94.22 34.75,93.22 33.41,91.87 33.41,90.5 33.55,90.36 33.55,87.85 33.81,87.58 34.13,87.58 v3(34.57,87.15)
  BOTTOM w0.102: UV1.G13 56.4,86.98 56.11,87.27 v3(56.11,87.25) ; v3(34.65,95.67) 34.65,95.5 35.03,95.12 35.03,94.72 34.55,94.24 34.55,93.13 UV8.L2
M_DA0: length 46.6
  BOTTOM w0.102: UV1.K27 58.82,75.28 58.82,75.1 59.18,74.74 59.18,72.93
  BOTTOM w0.127: 59.18,72.93 59.24,72.87 59.24,72.62 59.37,72.49 59.49,72.49 59.62,72.36 59.62,72.11 59.49,71.98 59.37,71.98 59.24,71.85 59.24,71.6 59.37,71.47 59.54,71.47 59.67,71.35 59.67,71.09 59.54,70.97 58.85,70.97 58.71,70.82 58.71,70.57 58.81,70.46 58.93,70.46 59.09,70.31 59.09,70.01 56.11,67.03 51.92,67.03 49.87,64.98 49.61,64.98 49.49,64.85 49.49,64.6 49.33,64.44 48.63,64.44 48.53,64.34 48.53,63.94 48.4,63.81 48.14,63.81 48.02,63.94 48.02,64.37 47.87,64.52 47.61,64.52 47.51,64.42 47.51,63.94 47.38,63.81 47.13,63.81 47,63.94 47,64.37 46.85,64.52 46.6,64.52 46.49,64.42 46.49,63.94 46.37,63.81 46.11,63.81 45.99,63.94 45.99,64.37 45.83,64.52 45.58,64.52 45.48,64.42 45.48,63.94 45.35,63.81 45.1,63.81 44.97,63.94 44.97,64.34 44.84,64.47 44.23,64.47 44.02,64.67 44.02,64.9 43.87,65.05 43.64,65.05 43.29,65.41 40.72,65.41 40.6,65.54 40.6,65.82 40.74,65.96 v1(42.23,65.96) 42.68,65.96 42.81,66.09 42.81,66.34 42.68,66.47 41.03,66.47 40.93,66.57 40.93,66.83 41.08,66.98 42.53,66.98 42.75,67.21 42.75,70.31 43.69,71.25 43.69,72.06 42.95,72.81 UV5.A2
M_DA1: length 45.3
  BOTTOM w0.102: UV1.J29 58,74.18 58.49,74.66 58.49,75.45 58.65,75.62 58.96,75.62 59.14,75.44 59.14,75.26 59.63,74.77
  BOTTOM w0.127: UV5.C2 41.74,72.53 41.74,71.9 42.35,71.29 42.35,69.45 42.3,69.4 42.3,67.59 42.17,67.47 40.98,67.47 40.21,66.7 v1(40.21,66.22) 40.21,65.33 40.67,64.88 43.24,64.88 44.68,63.43 48.88,63.43 52.05,66.6 56.24,66.6 59.07,69.43 60.55,69.43 60.67,69.56 60.67,69.81 60.55,69.94 60.18,69.94 60.05,70.06 60.05,70.32 60.18,70.45 60.55,70.45 60.67,70.57 60.67,70.83 60.55,70.95 60.18,70.95 60.05,71.08 60.05,71.33 60.18,71.46 60.59,71.46 60.83,71.7 60.83,72.51 61.27,72.95 61.35,72.95 61.55,73.16 61.55,73.44 61.25,73.74 60.86,73.74 60.56,74.05 60.36,74.05 59.63,74.77
M_DA2: length 45.2
  BOTTOM w0.102: 57.49,71.61 57.49,72.63 57.59,72.72 57.59,73.31 UV1.H30
  BOTTOM w0.127: 57.49,71.61 57.49,71.55 57.49,71.54 57.49,71.25 57.64,71.1 57.84,71.1 57.94,71 57.94,70.51 57.71,70.29 57.03,70.29 56.8,70.06 56.8,69.24 55.53,67.97 v1(52.08,67.97) 51.11,67.97 50.55,67.42 50.55,66.83 50.3,66.58 49.99,66.58 49.87,66.7 49.87,67.06 49.71,67.21 49.43,67.21 49.31,67.09 49.31,66.04 49.18,65.92 48.93,65.92 48.8,66.04 48.8,67.09 48.67,67.21 48.42,67.21 48.29,67.09 48.29,66.04 48.16,65.92 47.91,65.92 47.78,66.04 47.78,67.09 47.66,67.21 47.4,67.21 47.28,67.09 47.28,66.04 47.15,65.92 46.89,65.92 46.77,66.04 46.77,67.09 46.64,67.21 46.39,67.21 46.26,67.09 46.26,66.04 46.13,65.92 45.88,65.92 45.75,66.04 45.75,67.09 45.62,67.21 45.37,67.21 45.24,67.09 45.24,66.04 45.12,65.92 44.86,65.92 44.74,66.04 44.74,67.67 44.61,67.8 44.35,67.8 44.23,67.67 44.23,66.37 44.1,66.25 43.85,66.25 43.72,66.37 43.72,68.06 43.87,68.22 44.94,68.22 45.07,68.34 45.07,68.6 44.94,68.72 43.87,68.72 43.72,68.88 43.72,69.65 44.56,70.49 44.56,72.32 43.12,73.75 42.98,73.75 UV5.A3
M_DA3: length 44.8
  BOTTOM w0.102: 57.08,71.84 57.16,71.92 57.16,72.86 UV1.H32
  BOTTOM w0.127: UV5.C3 42.18,74.55 42.91,74.55 44.94,72.52 44.94,71.31 45.07,71.18 45.32,71.18 45.45,71.06 45.45,70.8 45.32,70.67 45.07,70.67 44.94,70.55 44.94,70.29 45.07,70.17 45.32,70.17 45.45,70.04 45.45,69.76 45.32,69.64 44.25,69.64 44.1,69.49 44.1,69.23 44.2,69.13 45.32,69.13 45.45,69 45.45,67.72 45.55,67.62 45.9,67.62 46.03,67.75 46.03,69.5 46.16,69.63 46.41,69.63 46.54,69.5 46.54,67.7 46.64,67.59 46.95,67.59 47.08,67.72 47.08,68.48 47.2,68.61 47.46,68.61 47.59,68.48 47.59,67.67 47.66,67.59 48.47,67.59 48.63,67.75 48.63,68.15 48.5,68.27 48.19,68.27 48.04,68.43 48.04,68.68 48.14,68.78 48.5,68.78 48.63,68.91 48.63,69.35 48.75,69.47 49.01,69.47 49.13,69.35 v1(49.13,68.75) 49.13,67.7 49.21,67.62 49.52,67.62 49.64,67.75 49.64,69.55 49.36,69.83 49.36,70.03 49.54,70.21 49.75,70.21 50.15,69.8 50.15,69.59 50.28,69.46 50.58,69.46 50.7,69.34 50.7,69.08 50.58,68.95 50.28,68.95 50.15,68.83 50.15,68.05 50.25,67.95 50.5,67.95 50.83,68.28 50.83,68.48 50.98,68.64 51.21,68.64 51.46,68.38 51.72,68.38 51.97,68.64 52.23,68.64 52.48,68.38 52.73,68.38 52.99,68.64 53.24,68.64 53.5,68.38 53.75,68.38 53.98,68.61 54.41,68.61 54.64,68.38 55,68.38 55.23,68.61 55.23,68.84 55.67,69.28 56.03,69.28 56.38,69.64 56.38,70.22 57.08,70.92 57.08,71.84
M_DA4: length 45.4
  BOTTOM w0.102: UV1.G29 55.92,73.62 55.92,72.75 55.86,72.7 55.86,72.5
  BOTTOM w0.127: 55.86,72.5 55.86,71.66 54.79,70.59 51.97,70.59 51.69,70.88 51.51,70.88 51.23,70.6 51.03,70.6 50.85,70.78 50.85,70.93 51.15,71.23 51.15,71.41 50.93,71.63 50.65,71.63 50.43,71.4 50.2,71.4 48.29,73.31 48.29,73.49 48.53,73.73 48.53,73.91 48.35,74.09 48.17,74.09 47.93,73.85 47.75,73.85 47.57,74.03 47.57,74.21 47.81,74.45 47.81,74.63 47.63,74.81 47.45,74.81 47.21,74.57 46.27,74.57 46.13,74.71 46.13,75.44 46.01,75.57 43.01,75.57 42.86,75.42 42.17,75.42 41.99,75.59 41.99,75.8 42.19,76 42.55,76 42.63,76.08 46.01,76.08 46.13,76.2 46.13,77.14 47.78,78.8 47.78,79.02 47.63,79.18 46.99,79.18 46.87,79.05 46.87,78.49 46.74,78.36 46.48,78.36 46.36,78.49 46.36,79.31 46.16,79.51 45.85,79.51 45.7,79.35 45.7,78.85 v1(45.57,78.72) 45.14,78.72 44.99,78.57 44.99,78.31 45.09,78.21 45.95,78.21 46.08,78.08 46.08,77.83 45.95,77.7 45.12,77.7 44.96,77.55 44.96,77.3 45.07,77.2 45.57,77.2 45.7,77.07 45.7,76.74 45.57,76.61 44.84,76.61 44.61,76.38 42.93,76.38 42.55,76.76 42.55,77.07 42.3,77.32 41.75,77.32 UV5.C8
M_DA5: length 45
  BOTTOM w0.102: UV1.F28 55.58,74.5 55.2,74.12 54.71,74.12 54.41,73.82 54.41,73.59 54.12,73.3 53.83,73.3 53.83,73.3 53.79,73.3 53.56,73.07 53.56,72.56 53.45,72.45
  BOTTOM w0.127: 53.45,72.45 52.97,71.96 52.38,71.96 52.13,72.22 52.13,72.83 51.87,73.08 51.59,73.08 51.39,72.88 50.53,72.88 49.69,73.72 49.69,74.76 50.4,75.47 50.4,75.75 50.12,76.03 47.55,76.03 47.35,76.23 47.35,76.66 51.14,80.45 51.14,80.9 52.41,82.17 52.41,82.35 51.87,82.88 51.59,82.88 51.44,83.04 51.21,83.04 51.06,82.88 50.72,82.88 50.57,83.04 50.57,83.76 50.42,83.91 50.17,83.91 50.06,83.81 50.06,83.04 49.94,82.91 49.68,82.91 49.56,83.04 49.56,83.48 49.43,83.6 49.17,83.6 49.05,83.48 49.05,83.04 48.92,82.91 48.67,82.91 48.54,83.04 48.54,83.48 48.41,83.6 48.16,83.6 48.03,83.48 48.03,83.04 47.9,82.91 47.65,82.91 47.52,83.04 v1(47.52,83.25) 47.52,83.48 47.4,83.6 47.14,83.6 47.02,83.48 47.02,83.04 46.89,82.91 46.63,82.91 46.51,83.04 46.51,83.96 46.41,84.06 46.15,84.06 46,83.91 46,83.06 45.87,82.94 45.75,82.94 41.74,78.92 41.74,78.36 41.51,78.13 41.2,78.13 40.95,77.88 40.95,77.02 40.77,76.84 40.63,76.84 UV5.D7
M_DA6: length 44.5
  BOTTOM w0.102: 55.39,72.48 55.53,72.62 55.53,72.83 UV1.F32
  BOTTOM w0.127: UV5.A7 42.95,77.06 43.08,77.19 43.24,77.19 43.67,76.76 44.35,76.76 44.56,76.97 44.56,77.17 44.46,77.27 44.02,77.27 43.85,77.45 43.85,77.68 44.02,77.86 44.41,77.86 44.58,78.03 44.58,78.36 44.46,78.49 44.23,78.49 43.44,79.28 43.44,79.46 43.9,79.91 44.08,79.91 44.76,79.23 45.01,79.23 45.27,79.48 45.27,79.66 44.55,80.38 44.55,80.54 44.74,80.73 44.92,80.73 45.61,80.04 45.8,80.04 45.98,80.22 45.98,80.41 45.28,81.11 45.28,81.27 45.47,81.46 45.75,81.46 46.49,80.73 v1(46.49,80.42) 46.49,79.76 46.62,79.63 46.87,79.63 47,79.76 47,80.83 47.12,80.95 47.38,80.95 47.5,80.83 47.5,79.76 47.63,79.63 47.89,79.63 48.01,79.76 48.01,80.83 48.14,80.95 48.39,80.95 48.52,80.83 48.52,80.12 48.65,79.99 48.9,79.99 49.03,80.12 49.03,80.83 49.16,80.95 50.04,80.95 50.21,80.79 50.21,80.66 46.56,77.02 46.56,75.87 47.22,75.21 48.7,75.21 48.93,74.99 48.93,73.23 50.09,72.06 51.11,72.06 52.13,71.05 54.59,71.05 55.39,71.85 55.39,72.48
M_DA7: length 45
  BOTTOM w0.102: 54.95,72.53 55.2,72.78 55.2,73.02 55.6,73.42 UV1.F30
  BOTTOM w0.127: 54.95,72.53 54.92,72.5 54.92,72.01 54.39,71.48 52.28,71.48 51.75,72.01 51.75,72.37 51.62,72.5 50.27,72.5 49.31,73.46 49.31,74.92 49.69,75.3 49.69,75.49 49.54,75.65 47.38,75.65 46.95,76.08 46.95,76.81 50.76,80.62 50.76,81.08 51.77,82.1 51.77,82.33 51.59,82.5 50.98,82.5 50.86,82.38 50.86,81.87 50.73,81.74 50.48,81.74 50.35,81.87 50.35,82.38 50.22,82.5 49.97,82.5 49.84,82.38 49.84,81.49 49.71,81.36 49.46,81.36 49.33,81.49 49.33,82.38 49.21,82.5 48.95,82.5 48.82,82.38 v1(48.82,82.11) 48.82,81.49 48.7,81.36 48.44,81.36 48.32,81.49 48.32,82.38 48.19,82.5 47.94,82.5 47.81,82.38 47.81,81.49 47.68,81.36 47.43,81.36 47.3,81.49 47.3,82.38 47.17,82.5 46.92,82.5 46.79,82.38 46.79,81.49 46.67,81.36 46.41,81.36 46.28,81.49 46.28,82.38 46.16,82.5 45.9,82.5 45.75,82.35 45.75,82.02 45.57,81.84 45.24,81.84 42.86,79.46 42.86,79.28 43.41,78.72 43.41,78.41 43.14,78.13 42.17,78.13 42.04,78.01 42.04,77.83 UV5.B8
M_DA8: length 45
  TOP w0.102: v3(52.62,73.03) 52.23,72.64 52.23,72.17 52.74,71.66
  TOP w0.127: UV6.D7 40.94,73.33 43.08,73.33 43.85,72.57 43.85,71.51 43.34,71 42.98,71 42.7,70.72 42.7,68.97 41.74,68 41.74,67.47 41.89,67.31 42.83,67.31 42.96,67.19 42.96,66.93 42.83,66.81 42.07,66.81 41.94,66.68 41.94,65.66 42.07,65.54 43.4,65.54 43.81,65.13 44.48,65.13 44.63,64.98 44.63,64.56 46.07,63.12 46.59,63.12 46.77,62.95 46.77,60.61 46.92,60.46 47.91,60.46 48.04,60.58 48.04,61.73 48.16,61.85 49.94,61.85 50.07,61.73 50.07,60.58 50.2,60.46 51.21,60.46 51.34,60.58 51.34,66.41 v1(52.88,67.95) 53.37,68.44 53.37,71.03 52.74,71.66
  BOTTOM w0.102: v3(52.62,73.03) 52.89,73.31 53.32,73.31 53.71,73.7 UV1.C30
M_DA9: length 45.5
  TOP w0.127: UV6.C8 40.95,72.52 40.95,71.84 40.85,71.73 40.85,70.44 41.05,70.24 41.81,70.24 41.94,70.11 41.94,69.29 40.98,68.32 40.98,68 40.54,67.57 40.54,64.9 40.67,64.77 43.08,64.77 43.72,64.14 43.97,64.14 v1(45.75,62.36) 45.75,59.95 46.01,59.69 48.67,59.69 48.8,59.82 48.8,60.96 48.93,61.09 49.18,61.09 49.31,60.96 49.31,59.82 49.43,59.69 51.85,59.69 52.1,59.95 52.1,66.1 54.13,68.13 54.13,71.78 54.26,71.91 54.51,71.91 54.65,72.05 54.65,74.19 54.77,74.3 55.94,74.3 56.06,74.43 v3(56.06,74.87)
  BOTTOM w0.124: UV1.F27 55.64,75.3 v3(56.06,74.87)
M_DA10: length 44
  TOP w0.102: 51.9,72.65 51.9,72.72 52.21,73.04 52.21,73.88 52.62,74.29 v3(52.7,74.29)
  TOP w0.127: 51.9,72.65 51.77,72.52 51.77,72.09 52.99,70.87 v1(52.99,69.78) 52.99,68.6 50.96,66.57 50.96,60.96 50.83,60.84 50.58,60.84 50.45,60.96 50.45,62.11 50.32,62.23 47.78,62.23 47.66,62.11 47.66,60.96 47.53,60.84 47.28,60.84 47.15,60.96 47.15,63.38 47.02,63.5 46.23,63.5 45.62,64.11 45.62,64.39 45.5,64.52 45.24,64.52 45.01,64.75 45.01,64.93 45.12,65.03 45.5,65.03 45.62,65.16 45.62,65.41 45.5,65.54 43.94,65.54 43.56,65.92 42.45,65.92 42.32,66.04 42.32,66.3 42.45,66.43 43.21,66.43 43.34,66.55 43.34,67.57 43.21,67.7 42.42,67.7 42.3,67.82 42.3,68 42.5,68.2 43.21,68.2 43.34,68.33 43.34,68.58 43.08,68.84 43.08,69.09 43.34,69.35 43.34,69.6 43.08,69.85 43.08,70.49 43.21,70.62 43.5,70.62 44.23,71.35 44.23,72.67 43.21,73.69 42.98,73.69 UV6.A7
  BOTTOM w0.102: UV1.A28 53,74.3 52.71,74.3 v3(52.7,74.29)
M_DA11: length 45
  TOP w0.127: v3(53.6,74.14) 53.13,73.66 53.13,71.82 53.75,71.19 53.75,68.29 51.72,66.25 v1(51.72,63.87) 51.72,60.2 51.59,60.08 49.82,60.08 49.69,60.2 49.69,61.35 49.56,61.47 48.55,61.47 48.42,61.35 48.42,60.2 48.29,60.08 46.26,60.08 46.13,60.2 46.13,60.48 46.39,60.74 46.39,60.99 46.13,61.24 46.13,61.78 46.39,62.03 46.39,62.27 43.93,64.72 43.67,64.72 43.24,65.16 41.05,65.16 40.93,65.28 40.93,65.54 41.05,65.66 41.43,65.66 41.56,65.79 41.56,66.04 41.43,66.17 41.05,66.17 40.93,66.3 40.93,66.55 41.05,66.68 41.43,66.68 41.56,66.81 41.56,67.06 41.43,67.19 41.05,67.19 40.93,67.31 40.93,67.41 41.36,67.84 41.36,68.16 42.32,69.13 42.32,70.49 42.2,70.62 41.43,70.62 41.31,70.74 41.31,71 41.43,71.12 41.95,71.12 42.08,71.26 42.08,71.54 41.76,71.86 41.76,72.53 UV6.B8
  BOTTOM w0.124: v3(53.6,74.14) 53.96,74.5 UV1.C28
M_DA12: length 45
  TOP w0.102: v3(54.41,74.87) 54.41,75.75 53.47,76.69 52.86,76.69 52.25,76.08 52.1,76.08
  TOP w0.127: UV6.C2 41.09,77.72 40.96,77.6 40.96,76.75 40.8,76.59 40.8,76.33 40.93,76.2 41.18,76.2 41.31,76.08 41.31,75.67 41.43,75.54 43.54,75.54 43.77,75.32 44.99,75.32 45.12,75.19 45.12,74.06 45.25,73.92 45.75,73.92 45.88,73.79 45.88,70.76 44.99,69.87 44.99,68.97 45.12,68.84 45.75,68.84 45.88,68.71 45.88,68.46 45.75,68.33 45.12,68.33 44.99,68.2 44.99,67.19 45.12,67.06 48.67,67.06 48.8,66.93 48.8,65.92 48.93,65.79 49.18,65.79 49.31,65.92 49.31,67.57 49.56,67.82 49.98,67.82 50.96,68.8 50.96,68.97 50.83,69.09 49.94,69.09 49.82,69.22 49.82,69.47 49.94,69.6 51.34,69.6 51.47,69.73 51.47,69.98 51.34,70.11 51.09,70.11 50.96,70.24 50.96,70.62 50.7,70.87 49.94,70.87 49.82,71 v1(49.82,71.62) 49.82,75.44 49.94,75.57 50.2,75.57 50.32,75.44 50.32,75.06 50.45,74.93 50.7,74.93 50.83,75.06 50.83,75.44 50.96,75.57 51.47,75.57 51.97,76.08 52.1,76.08
  BOTTOM w0.127: UV1.E27 54.8,75.26 v3(54.41,74.87)
M_DA13: length 46.6
  TOP w0.102: 51.9,77.47 52.2,77.78 52.69,77.78 53.12,77.35 53.78,77.35 54.98,76.14 56.41,76.14 v3(56.78,76.51)
  TOP w0.127: 51.9,77.47 51.84,77.42 51.09,77.42 50.96,77.29 50.96,77.02 50.83,76.89 49.56,76.89 49.43,77.02 49.43,77.27 49.31,77.4 49.05,77.4 48.93,77.27 48.93,77.02 48.8,76.89 47.78,76.89 47.66,77.02 47.66,77.22 47.53,77.35 47.28,77.35 47.15,77.22 47.15,76.08 47.28,75.95 48.93,75.95 49.05,75.82 v1(49.05,74.54) 49.05,68.68 48.2,67.82 46.77,67.82 46.64,67.95 46.64,68.2 46.77,68.33 47.66,68.33 47.78,68.46 47.78,69.46 47.64,69.6 46.77,69.6 46.64,69.73 46.64,70.74 46.77,70.87 47.66,70.87 47.78,71 47.78,72.01 47.66,72.14 46.77,72.14 46.64,72.27 46.64,73.28 46.77,73.41 47.66,73.41 47.78,73.54 47.78,74.55 47.66,74.68 46.36,74.68 45.88,75.16 45.88,77.35 45.75,77.47 45.5,77.47 45.37,77.35 45.37,76.2 45.24,76.08 44.35,76.08 44.1,76.33 44.1,76.84 43.97,76.97 42.99,76.97 UV6.A3
  BOTTOM w0.127: v3(56.78,76.51) 56.78,76.49 56.4,76.12 UV1.G26
M_DA14: length 45.9
  TOP w0.102: 52.86,76.99 53.63,76.99 54.95,75.67 v3(55.2,75.67)
  TOP w0.127: UV6.C3 41.6,76.92 41.69,76.84 41.69,76.08 41.81,75.95 43.1,75.95 43.21,76.06 43.21,76.46 43.34,76.59 43.59,76.59 43.72,76.46 43.72,75.99 44.01,75.7 45.37,75.7 45.5,75.57 45.5,74.43 45.62,74.3 47.28,74.3 47.4,74.17 47.4,73.92 47.28,73.79 46.39,73.79 46.26,73.66 46.26,71.89 46.39,71.76 47.28,71.76 47.4,71.63 47.4,71.38 47.28,71.25 46.39,71.25 46.26,71.12 46.26,69.85 46.13,69.73 45.5,69.73 45.37,69.6 45.37,69.35 45.5,69.22 47.28,69.22 47.4,69.09 47.4,68.84 47.28,68.71 46.39,68.71 46.26,68.58 46.26,68.08 46.13,67.95 45.5,67.95 45.37,67.82 45.37,67.57 45.5,67.44 48.35,67.44 49.12,68.2 49.82,68.2 49.94,68.33 49.94,68.58 49.82,68.71 49.56,68.71 49.43,68.84 49.43,69.85 49.56,69.98 50.45,69.98 50.58,70.11 50.58,70.36 50.45,70.49 49.56,70.49 49.43,70.62 49.43,75.82 49.56,75.95 51.21,75.95 51.72,76.46 52.1,76.46 52.63,76.99 52.86,76.99
  BOTTOM w0.124: v3(55.2,75.67) 54.76,76.1 UV1.D26
M_DA15: length 46
  TOP w0.127: v3(55.2,76.55) 55.66,76.55 55.78,76.68 55.78,76.84 55.52,77.1 54.65,77.1 54.51,77.24 v1(54.51,77.53) 54.51,77.86 54.21,78.16 54.06,78.16 53.88,77.98 53.88,77.86 53.75,77.73 53.5,77.73 53.37,77.86 53.37,78.03 53.24,78.16 52.03,78.16 51.66,77.8 50.45,77.8 50.32,77.67 50.32,77.4 50.2,77.27 49.94,77.27 49.82,77.4 49.82,77.73 49.75,77.8 48.67,77.8 48.55,77.67 48.55,77.47 48.42,77.35 48.16,77.35 48.04,77.47 48.04,77.6 47.84,77.8 46.96,77.8 46.77,77.6 46.77,75.92 47.12,75.57 48.55,75.57 48.67,75.44 48.67,68.84 48.55,68.71 48.29,68.71 48.16,68.84 48.16,69.85 48.04,69.98 47.15,69.98 47.02,70.11 47.02,70.36 47.15,70.49 48.04,70.49 48.16,70.62 48.16,72.39 48.04,72.52 47.15,72.52 47.02,72.65 47.02,72.9 47.15,73.03 48.04,73.03 48.16,73.16 48.16,74.93 48.04,75.06 46.51,75.06 46.26,75.32 46.26,77.73 46.13,77.86 45.12,77.86 44.99,77.73 44.99,76.59 44.86,76.46 44.61,76.46 44.48,76.59 44.48,77.98 44.35,78.11 44.1,78.11 43.97,77.98 43.97,77.47 43.81,77.31 43.12,77.31 42.95,77.48 UV6.A2
  BOTTOM w0.127: UV1.F25 55.55,76.9 v3(55.2,76.55)
M_DA16: length 40.8
  IN1 w0.102: 40.35,72.9 38.1,72.9 37.82,72.62 v3(37.82,72.52)
  IN1 w0.14: v3(50.66,74.05) 50.53,74.05 50.22,73.74 50.22,70.92 52.61,68.53 52.61,68.15 52.43,67.97 52.43,67.75 52.61,67.57 52.61,67.26 52.38,67.03 52.38,66.78 52.61,66.55 52.61,65.89 51.34,64.62 41.74,64.62 41.46,64.9 41.01,64.9 40.87,64.77 40.68,64.77 40.48,64.97 40.48,65.16 40.74,65.42 40.74,65.62 40.54,65.82 40.34,65.82 40.08,65.56 39.89,65.56 39.69,65.76 39.69,65.95 40.01,66.28 40.01,67.38 39.9,67.5 39.6,67.5 39.46,67.64 39.46,67.92 39.6,68.06 39.9,68.06 40.01,68.17 40.01,68.43 39.83,68.61 39.83,68.89 40.01,69.07 40.01,70.64 40.8,71.43 40.8,72.45 40.35,72.9
  BOTTOM w0.102: UV1.A25 52.96,76.66 52.8,76.66 52.02,75.87 51.9,75.87 50.66,74.64 v3(50.66,74.05) ; v3(37.82,72.52) 38.15,72.84 UV5.G2
M_DA17: length 40.6
  IN1 w0.14: v3(41.18,74.27) 41.18,73.05 41.89,72.34 41.89,71.35 40.6,70.06 40.6,66.5 41.97,65.13 49.82,65.13 50.25,65.56 50.44,65.56 50.93,65.07 51.13,65.07 51.33,65.27 51.33,65.47 50.84,65.96 50.84,66.15 51.04,66.35 51.23,66.35 51.67,65.91 51.87,65.91 52.07,66.11 52.07,66.31 51.63,66.75 51.63,66.94 51.85,67.16 51.85,67.4 51.61,67.64 51.61,67.92 51.75,68.06 51.86,68.06 52,68.2 52,68.48 49.74,70.74 49.74,73.88 50.41,74.55 51.11,74.55 51.25,74.42 v3(51.25,74.01)
  BOTTOM w0.102: v3(51.25,74.01) 51.25,74.54 52.62,75.91 52.62,76.19 52.89,76.46 53.56,76.46 UV1.C25 ; UV5.E3 40.17,74.14 41.05,74.14 v3(41.18,74.27)
M_DA18: length 41.6
  IN1 w0.102: v3(36.95,74.07) 37.37,73.65 37.37,73.16 37.39,73.13 37.39,72.32 37.48,72.23
  IN1 w0.14: 37.48,72.23 38.92,70.79 38.92,69.42 38.49,68.99 38.49,64.93 39.76,63.66 51.95,63.66 53.55,65.26 53.55,68.97 51.26,71.25 v3(51.26,73.35)
  BOTTOM w0.102: UV5.H3 37.3,73.72 v3(36.95,74.07) ; v3(51.26,73.35) 52.3,74.4 52.3,75.06 52.86,75.62 53.69,75.62 53.99,75.92 53.99,76.22 54.68,76.9 UV1.E25
M_DA19: length 40.1
  IN1 w0.102: v3(36.96,77.34) 36.96,77.19 37.01,77.14 37.27,77.14 37.37,77.25 37.37,78.34 37.17,78.54 37.12,78.54 36.99,78.67 36.99,78.85 37.19,79.05 37.85,79.05 37.98,78.92 37.98,78.67 38.13,78.52 40.21,78.52
  IN1 w0.14: 40.21,78.52 40.42,78.52 40.57,78.36 40.57,78.21 40.85,77.93 41.15,77.93 41.46,78.24 41.46,78.66 41.6,78.8 41.88,78.8 42.02,78.66 42.02,78.35 42.16,78.21 42.67,78.21 42.81,78.35 42.81,78.48 43.12,78.8 43.97,78.8 44.12,78.64 44.12,76.34 44.26,76.2 44.54,76.2 44.68,76.34 44.68,78.69 44.79,78.81 45.07,78.81 45.24,78.64 45.24,75.97 45.1,75.83 44.7,75.83 44.58,75.72 44.58,75.44 44.75,75.27 45.1,75.27 45.24,75.13 45.24,74.79 45.55,74.48 45.55,74.48 45.8,74.22 46.03,74.22 46.18,74.38 46.18,75.24 45.8,75.63 45.8,77.36 45.99,77.55 46.15,77.55 46.39,77.79 46.39,78.01 46.28,78.11 45.99,78.11 45.8,78.3 45.8,78.64 45.94,78.78 46.96,78.78 47.1,78.64 47.1,78.44 47.24,78.3 47.52,78.3 47.66,78.44 47.66,78.64 47.8,78.78 48.33,78.78 48.65,78.46 48.65,78.29 49.82,77.12 50.88,77.12 50.98,77.22 51.77,77.22 51.95,77.04 v3(51.95,76.99)
  BOTTOM w0.102: UV1.D24 54.08,77.7 53.75,77.37 53.51,77.37 53.46,77.42 52.95,77.42 52.52,76.99 v3(51.95,76.99) ; UV5.H8 37.34,77.72 36.96,77.35 v3(36.96,77.34)
M_DA20: length 41.6
  IN1 w0.102: 40.34,77.73 38.15,77.73 v3(37.76,77.34)
  IN1 w0.14: v3(49.64,76.46) 49.64,76.6 48.39,77.86 47.12,77.86 46.28,77.02 46.28,75.82 46.72,75.39 46.72,69.17 46.79,69.09 47.15,69.09 47.38,68.86 47.38,68.53 47.17,68.33 46.39,68.33 46.21,68.51 46.21,69.02 46.09,69.14 45.36,69.14 45.22,69.28 45.22,69.56 45.36,69.7 45.87,69.7 46.01,69.84 46.01,70.86 46.15,71 46.31,71 46.45,71.14 46.45,71.42 46.31,71.56 46.15,71.56 46.01,71.7 46.01,71.98 46.15,72.11 46.31,72.11 46.45,72.25 46.45,72.53 46.31,72.67 46.15,72.67 46.01,72.81 46.01,73.09 46.15,73.23 46.31,73.23 46.45,73.37 46.45,73.65 46.34,73.77 45.57,73.77 44.13,75.21 44.13,75.65 43.64,76.13 43.64,77.17 43.06,77.75 41.64,77.75 41.2,77.32 40.8,77.32 40.39,77.73 40.34,77.73
  BOTTOM w0.102: v3(37.76,77.34) 37.35,76.93 UV5.H7 ; UV1.E23 54.8,78.51 54.49,78.82 53.89,78.82 53.84,78.77 53.36,78.77 53.26,78.87 53.09,78.87 52.86,78.64 52.25,78.64
  BOTTOM w0.127: 52.25,78.64 51.68,78.64 49.64,76.6 v3(49.64,76.46)
M_DA21: length 41.8
  IN1 w0.102: 39.55,71.2 39.78,71.43 39.78,71.84 39.3,72.32 v3(39.3,72.5)
  IN1 w0.14: v3(50.68,73.35) 50.68,71.1 53.07,68.71 53.07,65.51 51.67,64.11 40.01,64.11 39.78,64.35 39.78,64.55 39.96,64.73 39.96,64.9 39.76,65.1 39.54,65.1 39.38,64.94 39.18,64.94 39,65.13 39,68.74 39.55,69.3 39.55,71.2
  BOTTOM w0.102: v3(50.68,73.35) 50.15,73.88 50.15,74.68 v1(51.8,76.33) 52.03,76.56 52.38,76.56 53.04,77.22 53.35,77.22 53.4,77.17 53.84,77.17 53.99,77.32 54.46,77.32 54.72,77.58 54.72,77.74 55.48,78.5 UV1.F23 ; UV5.F2 38.95,72.85 v3(39.3,72.5)
M_DA22: length 41
  IN1 w0.14: v3(39.32,77.29) 39.95,76.66 41.18,76.66 41.81,77.3 42.83,77.3 43.19,76.94 43.19,75.95 43.67,75.47 43.67,74.99 44.19,74.46 44.19,74.27 44.16,74.24 44.16,74.01 44.36,73.81 44.53,73.81 44.59,73.87 44.78,73.87 44.99,73.66 44.99,73.33 45.14,73.18 45.35,73.18 45.55,72.98 45.55,70.54 44.53,69.52 44.53,67.78 44.67,67.64 44.95,67.64 45.09,67.78 45.09,68.5 45.23,68.64 45.51,68.64 45.65,68.5 45.65,67.78 45.79,67.64 46.06,67.64 46.3,67.89 46.62,67.89 46.86,67.64 47.96,67.64 48.06,67.75 48.06,68.86 47.17,69.75 47.17,75.04 47.25,75.11 47.25,75.49 46.84,75.9 46.84,76.84 47.39,77.39 48.23,77.39 49.02,76.6 v3(49.02,76.46)
  BOTTOM w0.102: UV1.D22 54.05,79.3 53.73,78.97 53.45,78.97 53.37,79.05 53.37,79.05 53.34,79.07 52.99,79.07 52.81,78.9 52.3,78.9 52.05,79.15 51.64,79.15 51.62,79.13
  BOTTOM w0.124: 49.36,76.86 v1(51.1,78.61) 51.62,79.13
  BOTTOM w0.127: v3(49.02,76.46) 49.02,76.52 49.36,76.86 ; UV5.F8 38.95,77.67 v3(39.32,77.29)
M_DA23: length 42.3
  IN1 w0.102: v3(39.6,76.33) 39.78,76.15 41.31,76.15 41.99,76.84 42.5,76.84 42.75,76.59 42.75,75.75 42.8,75.7
  IN1 w0.14: 42.8,75.7 43.21,75.29 43.21,74.76 43.54,74.43 43.54,73.99 45.04,72.5 45.04,70.67 44.06,69.69 44.06,69.61 43.92,69.47 43.38,69.47 43.24,69.33 43.24,69.05 43.38,68.91 43.92,68.91 44.06,68.77 44.06,68.49 43.92,68.35 43.38,68.35 43.24,68.21 43.24,67.93 43.38,67.79 43.92,67.79 44.06,67.65 44.06,67.5 44.38,67.19 48.22,67.19 48.57,67.54 48.57,69.04 47.68,69.93 47.68,74.76 47.89,74.96 47.89,75.49 47.33,76.05 47.33,76.69 47.58,76.94 47.94,76.94 v3(48.42,76.46)
  BOTTOM w0.124: v3(48.42,76.46) 48.42,76.49 v1(49.36,77.43) 51.62,79.7 55.2,79.7 UV1.F21
  BOTTOM w0.127: UV5.F7 39.01,76.92 v3(39.6,76.33)
M_DA24: length 39.8
  TOP w0.102: v3(38.51,73.28) 38.54,73.28 38.9,72.92 UV6.F8
  IN3 w0.102: v3(38.51,73.28) 38.87,72.93 39.43,72.93 39.68,72.67 39.68,72.29 39.45,72.06 39.25,72.06 38.97,71.78 38.97,71.23 39.25,70.95 39.25,70.84
  IN3 w0.165: 39.25,70.84 39.25,69.75 41.84,67.16 51.97,67.16 52.71,67.9 52.71,69.12 52.91,69.32 54.1,69.32 54.26,69.48 54.26,69.81 54.1,69.98 52.88,69.98 52.69,70.17 52.69,70.5 52.83,70.64 54.17,70.64 54.39,70.85 54.39,71.18 54.27,71.3 53.28,71.3 53.12,71.46 53.12,72.55 53.14,72.57 53.14,74.74 53.16,74.76 53.16,75.12 53.14,75.14 53.14,75.14 54.11,76.1 54.11,79.11 53.97,79.25 53.77,79.25 53.6,79.42 53.6,79.71 54.25,80.36 54.36,80.36 v3(54.4,80.4)
  BOTTOM w0.124: UV1.E21 54.7,80.1 v3(54.4,80.4)
M_DA25: length 39.1
  TOP w0.102: UV6.H7 37.35,73.82 37.65,74.13 v3(37.67,74.13)
  IN3 w0.102: 39.76,70.57 39.76,71.78 40.01,72.04 40.24,72.04 40.54,72.34 40.54,72.67 40.29,72.93 39.99,72.93 39.22,73.69 38.11,73.69 v3(37.67,74.13)
  IN3 w0.165: 39.76,70.57 39.76,69.96 41.94,67.77 51.85,67.77 52.17,68.09 52.17,68.6 52,68.77 51.28,68.77 51.11,68.93 51.11,69.26 51.28,69.43 52,69.43 52.17,69.59 52.17,70.91 52.33,71.07 52.48,71.07 52.65,71.24 52.65,71.57 52.48,71.73 52.33,71.73 52.17,71.9 52.17,73.73 52.17,73.73 52.17,75.82 53.42,77.07 53.42,78.93 53.13,79.22 53.13,79.32 53.09,79.35 53.09,79.91 52.29,80.71 v3(52.29,80.84)
  BOTTOM w0.102: UV1.D20 54.09,80.9 53.73,81.26 52.71,81.26 v3(52.29,80.84)
M_DA26: length 40.4
  TOP w0.102: v3(36.95,73.33) 37.35,72.93 UV6.H8
  IN3 w0.102: 37.39,72.14 37.39,72.88 36.95,73.32 v3(36.95,73.33)
  IN3 w0.165: v3(55.22,81.22) 55.68,80.75 55.68,80.07 54.77,79.15 54.77,78.34 54.64,78.21 54.64,77.42 55,77.07 55.35,77.07 56.67,75.75 56.67,74.1 56.05,73.47 55.82,73.47 55.27,74.01 55.04,74.01 54.81,73.78 54.81,73.55 55.35,73 55.35,72.77 54.87,72.29 54.87,69.22 52.2,66.55 41.71,66.55 38.77,69.5 38.77,70.77 37.39,72.14
  BOTTOM w0.124: v3(55.22,81.22) 55.22,81.27 55.6,81.66 UV1.F19
M_DA27: length 39.2
  TOP w0.127: UV6.F7 39,73.72 39.55,74.27 v3(39.55,74.43)
  IN3 w0.102: 40.57,70.9 40.57,71.84 40.93,72.19 40.93,73.11 39.6,74.43 v3(39.55,74.43)
  IN3 w0.165: v3(51.7,80.83) 51.82,80.7 51.82,80.52 52.18,80.16 52.18,78.87 52.84,78.21 52.84,77.22 51.7,76.08 51.7,72.98 51.53,72.82 50.22,72.82 50.06,72.65 50.06,72.32 50.22,72.16 51.53,72.16 51.7,71.99 51.7,71.66 51.53,71.5 50.22,71.5 50.06,71.33 50.06,71 50.22,70.84 51.53,70.84 51.7,70.67 51.7,70.23 51.53,70.06 50.26,70.06 50.09,69.9 50.09,69.57 50.53,69.13 50.53,68.84 50.12,68.43 41.99,68.43 40.57,69.85 40.57,70.9
  BOTTOM w0.102: v3(51.7,80.83) 51.72,80.85 51.72,80.87 52.55,81.7 UV1.A19
M_DA28: length 40
  TOP w0.102: v3(38.61,78.11) 38.23,77.72 UV6.G2
  IN3 w0.102: 40.32,78.54 38.69,78.54 38.54,78.39 38.54,78.19 v3(38.61,78.11) ; v3(55.18,82.99) 55.18,82.64 55.05,82.5 54.9,82.5 54.77,82.63 54.77,83.39 54.52,83.64 52.13,83.64 51.81,83.96 51.67,83.96
  IN3 w0.165: 40.32,78.54 40.9,77.96 40.9,77.58 41.64,76.84 42.3,76.84 42.75,77.3 42.75,78.03 43.19,78.46 43.74,78.46 43.99,78.71 43.99,79.97 44.18,80.16 44.51,80.16 44.65,80.02 44.65,78.71 44.89,78.46 45.19,78.46 46.02,79.29 46.02,79.88 45.1,80.79 45.1,81.04 45.3,81.23 45.6,81.23 46.69,80.14 46.92,80.14 47.16,80.38 47.16,80.61 46.12,81.65 46.12,81.93 46.28,82.1 46.6,82.1 47.62,81.08 47.86,81.08 48.04,81.26 48.04,81.6 46.93,82.71 46.93,82.92 47.16,83.15 47.42,83.15 48.36,82.22 48.59,82.22 48.82,82.45 48.82,82.68 47.96,83.54 47.96,83.75 48.2,83.98 48.46,83.98 49.29,83.15 49.52,83.15 49.76,83.39 49.76,83.8 50,84.03 51.61,84.03 51.67,83.96
  BOTTOM w0.124: UV1.D18 54.69,82.5 v3(55.18,82.99)
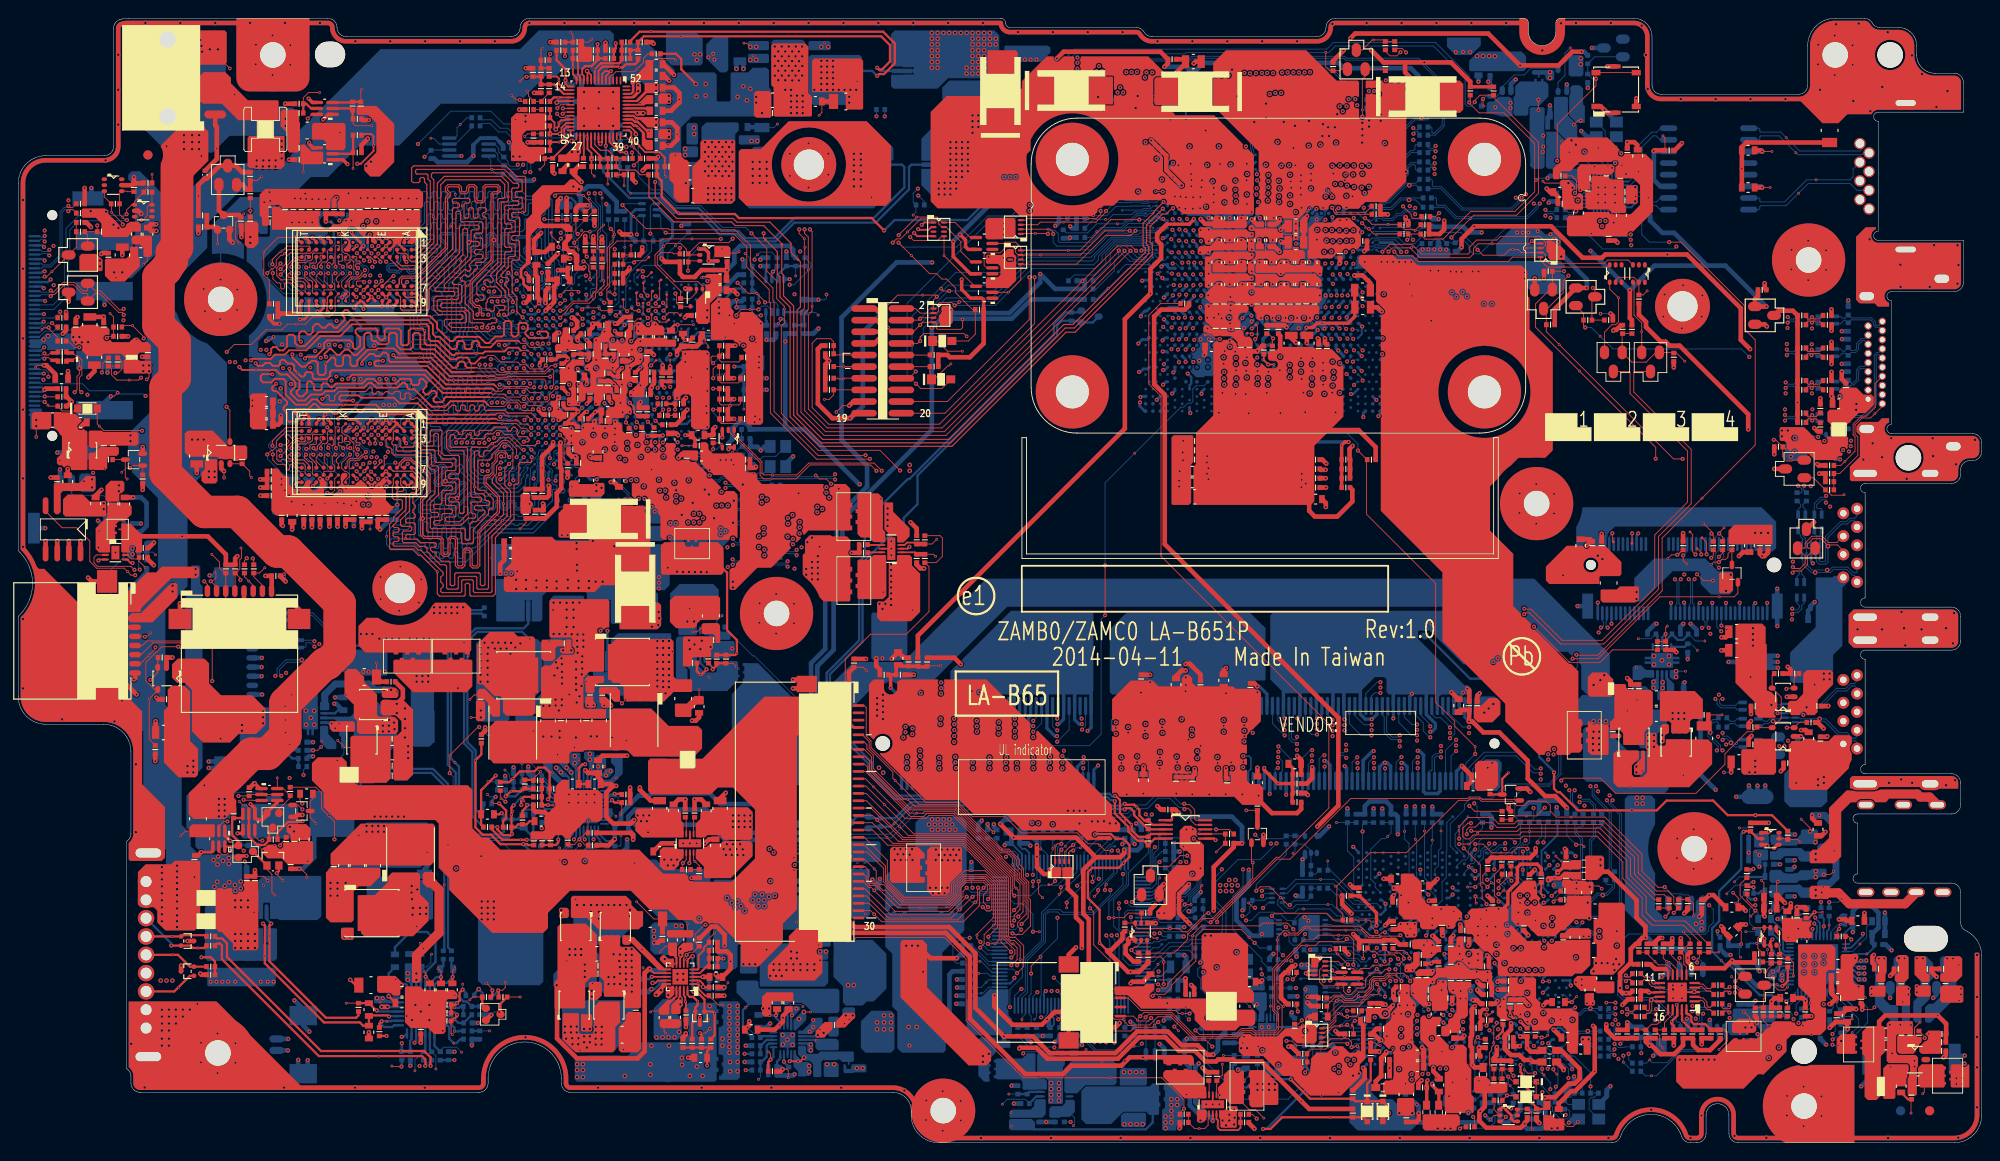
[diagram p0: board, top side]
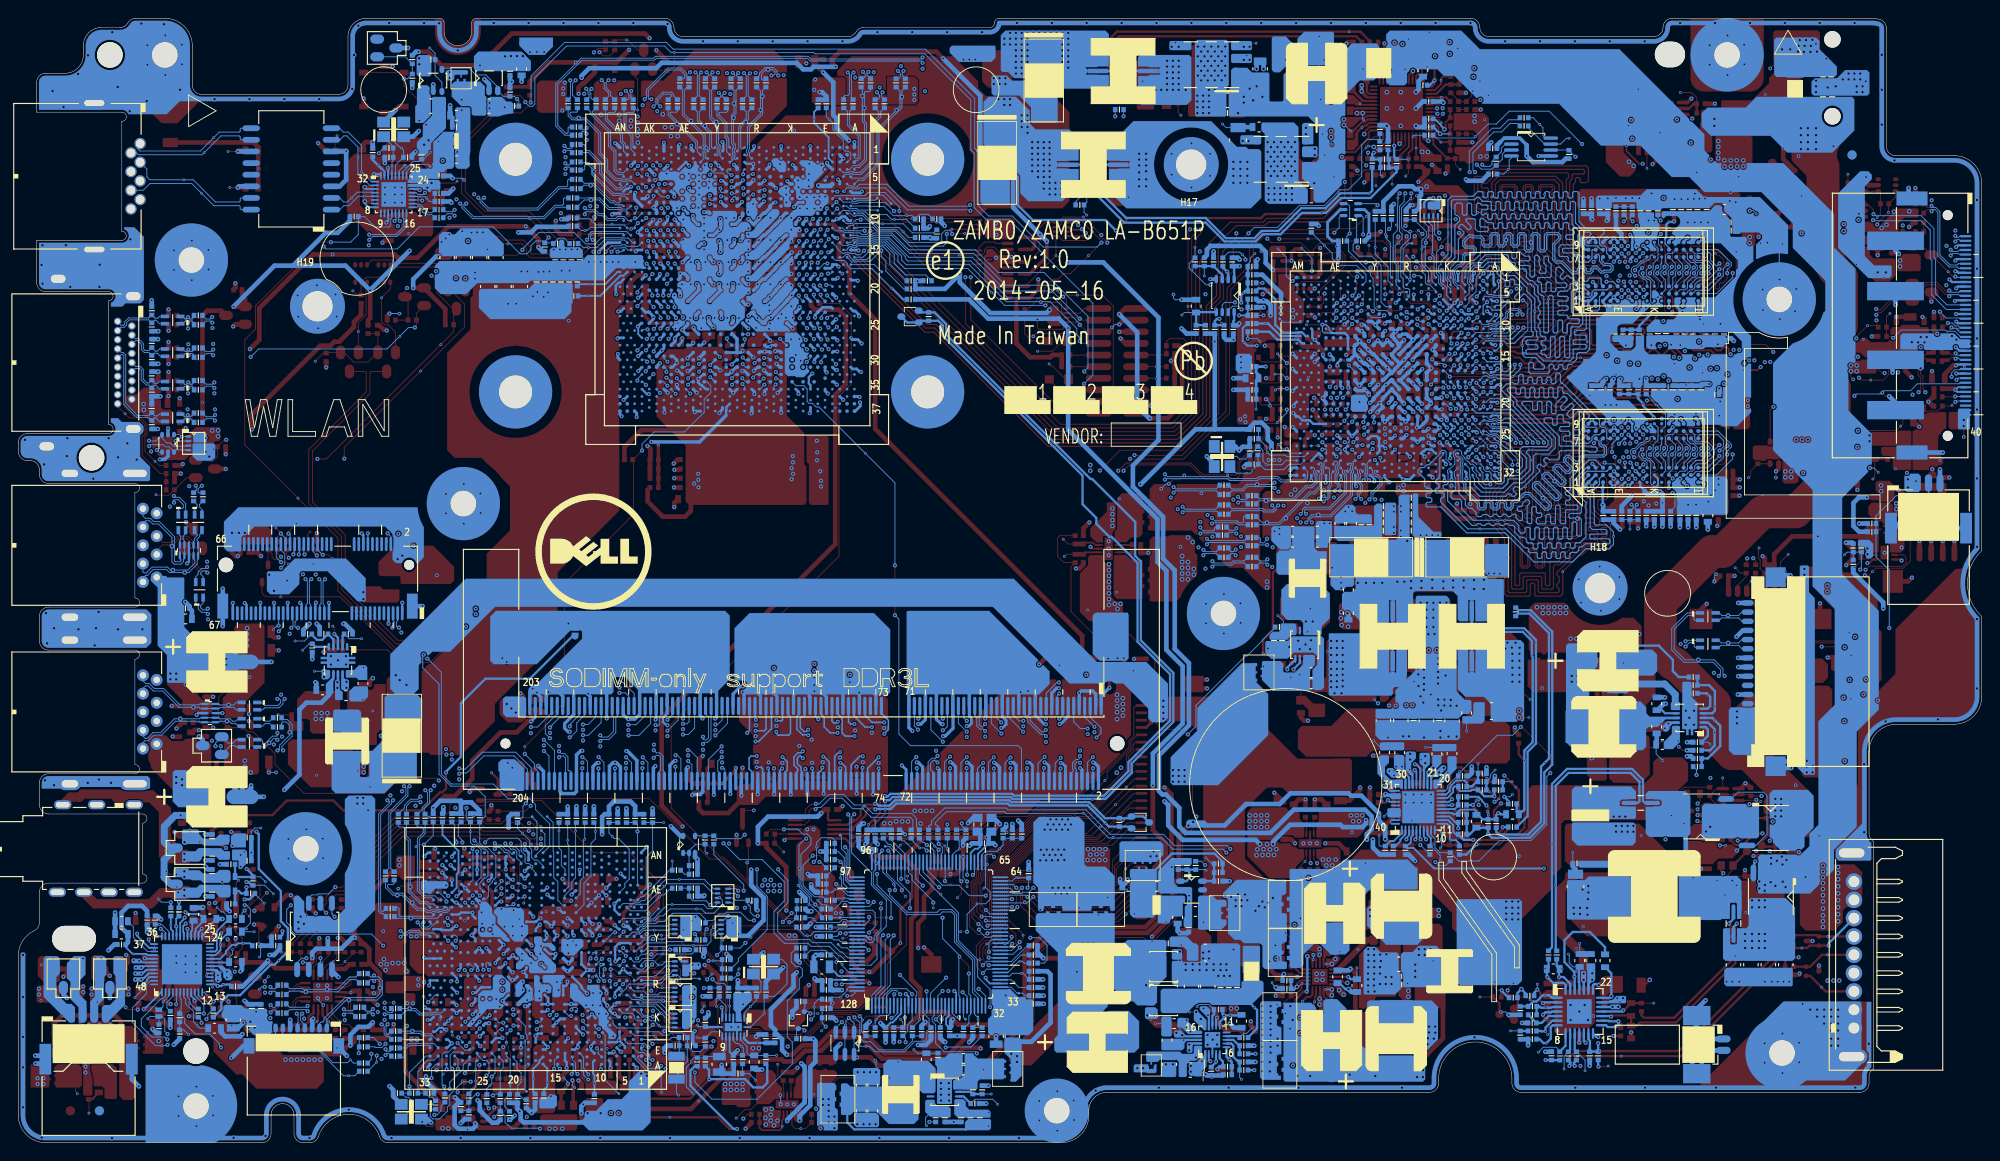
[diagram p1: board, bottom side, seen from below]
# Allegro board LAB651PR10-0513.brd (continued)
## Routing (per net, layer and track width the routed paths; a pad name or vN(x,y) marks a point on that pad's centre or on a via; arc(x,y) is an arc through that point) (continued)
M_DA29: length 39.7
  TOP w0.127: UV6.H3 37.35,76.92 v3(37.72,76.55)
  IN3 w0.102: v3(55.89,82.9) 55.89,82.91 54.92,83.88 52.4,83.88 51.77,84.51 ; v3(37.72,76.55) 37.73,76.55 37.73,76.54 37.71,76.54 37.75,76.58 37.75,76.74 38.17,77.15 38.17,77.48 38.18,77.5 38.18,78.31
  IN3 w0.165: 38.18,78.31 37.88,78.62 37.88,79.05 38.56,79.73 39.12,79.73 39.48,79.38 39.74,79.38 39.91,79.54 39.91,79.61 40.07,79.78 40.4,79.78 40.57,79.61 40.57,79.54 40.73,79.38 41.18,79.38 41.38,79.18 41.38,77.78 41.54,77.63 41.94,77.63 42.12,77.8 42.12,79.38 42.27,79.53 42.78,79.53 44.33,81.08 44.33,81.63 44.57,81.87 45.12,81.87 45.31,82.06 45.31,82.3 44.16,83.45 44.16,83.48 44,83.64 44,83.84 44.24,84.07 44.47,84.07 45.78,82.76 46.01,82.76 46.35,83.1 46.35,83.33 45.23,84.45 45.23,84.73 45.46,84.97 45.65,84.97 46.99,83.62 47.22,83.62 47.46,83.85 47.46,84.09 46.52,85.03 46.52,85.26 46.75,85.49 46.99,85.49 47.93,84.56 47.95,84.56 47.99,84.52 48.13,84.52 48.11,84.51 51.77,84.51
  BOTTOM w0.124: UV1.F17 55.6,83.19 v3(55.89,82.9)
M_DA30: length 39.7
  TOP w0.102: UV6.E3 39.75,76.92 40.15,77.31 v3(40.16,77.31)
  IN3 w0.102: 42.2,75.32 41.84,75.32 40.82,76.33 40.54,76.33 40.06,76.81 40.06,77.22 v3(40.16,77.31) ; 52.1,82.88 52.39,83.17 52.78,83.17 53.12,82.83 53.42,82.83 v3(53.57,82.99)
  IN3 w0.14: 52.1,82.88 50.7,82.88
  IN3 w0.165: 42.2,75.32 42.58,75.32 42.98,74.91 42.98,73.77 42.83,73.61 42.83,72.39 43.29,71.94 43.63,71.94 43.8,72.1 43.8,73.02 43.96,73.18 44.29,73.18 44.46,73.02 44.46,71.98 44.6,71.84 44.93,71.84 45.12,72.03 45.12,73.02 45.28,73.18 45.61,73.18 45.78,73.02 45.78,71.98 45.92,71.84 46.25,71.84 46.44,72.03 46.44,73.52 46.58,73.66 46.91,73.66 47.1,73.47 47.1,71.98 47.24,71.84 47.66,71.84 47.86,72.04 47.86,73.99 47.61,74.25 46.67,74.25 46.46,74.45 46.46,74.91 45.76,75.61 45.76,76.95 45.76,76.95 45.76,77.31 47.11,78.67 49.08,78.67 49.43,79.02 49.43,81.61 50.7,82.88
  BOTTOM w0.124: UV1.A17 53.27,83.3 v3(53.57,82.99)
M_DA31: length 39.6
  TOP w0.102: UV6.F2 38.95,77.73 v3(39.34,78.12)
  IN3 w0.102: 51.55,83.49 51.64,83.4 53.85,83.4 53.96,83.29 53.96,82.81 54.29,82.48 54.44,82.48 54.54,82.58 54.54,82.83 v3(54.37,82.99) ; v3(39.34,78.12) 39.57,78.12 39.99,77.7 40.34,77.7 40.6,77.45 40.6,77.17 41.45,76.32 41.67,76.32 41.89,76.1
  IN3 w0.165: 51.55,83.49 50.58,83.49 48.95,81.87 48.95,79.35 48.8,79.2 48.38,79.2 48.24,79.34 48.24,80.2 48.1,80.34 47.77,80.34 47.58,80.15 47.58,79.34 47.44,79.2 46.98,79.2 45.24,77.46 44.86,77.46 44.63,77.69 44.63,77.92 44.47,78.08 44.1,78.08 43.97,77.96 43.97,77.63 43.8,77.46 43.43,77.46 43.24,77.27 43.24,76.94 43.38,76.8 43.83,76.8 44,76.63 44,75.66 44.16,75.49 44.49,75.49 44.66,75.66 44.66,76.63 44.83,76.8 45.17,76.8 45.29,76.68 45.29,75.42 45.83,74.88 45.83,73.89 45.65,73.72 45.18,73.72 45.01,73.88 45.01,74.72 44.82,74.91 44.49,74.91 44.35,74.77 44.35,73.88 44.19,73.72 43.72,73.72 43.59,73.84 43.59,75.34 43.08,75.85 42.14,75.85 41.89,76.1
  BOTTOM w0.124: UV1.C17 54.07,83.3 v3(54.37,82.99)
M_DA32: length 41.8
  TOP w0.102: v3(37.73,92.36) 37.35,92.73 UV7.H8
  IN3 w0.165: v3(50.37,84.97) 50.22,85.12 49.74,85.12 49.61,84.99 48.18,84.99 47.19,85.98 46.79,85.98 46.54,86.24 46.54,86.64 45.22,87.96 45.22,92.4 45.05,92.56 44.72,92.56 44.53,92.37 44.53,88.59 44.37,88.42 44.09,88.42 43.87,88.64 43.87,90.59 43.71,90.76 43.38,90.76 43.21,90.59 43.21,88.59 43.05,88.42 42.77,88.42 42.55,88.64 42.55,90.59 42.39,90.76 42.06,90.76 41.89,90.59 41.89,88.59 41.73,88.42 41.45,88.42 41.23,88.64 41.23,90.09 41.07,90.25 40.73,90.25 40.57,90.09 40.57,89.63 40.38,89.44 39.55,89.44 39.35,89.64 39.35,90.23 38.69,90.89 38.69,91.24 38.49,91.44 37.93,91.44 37.78,91.6 37.78,92.31 v3(37.73,92.36)
  BOTTOM w0.102: 52.74,83.44 52.86,83.44 53.04,83.62 53.32,83.62 53.4,83.54 53.8,83.54 54.01,83.75 54.35,83.75 UV1.E17
  BOTTOM w0.127: 52.74,83.44 51.44,83.44 v1(51.19,83.69) 50.37,84.51 v3(50.37,84.97)
M_DA33: length 41.5
  TOP w0.102: v3(37.76,93.98) 37.63,94.11 37.01,94.11 36.91,94.01 36.91,93.7 37.08,93.53 UV7.H7
  IN3 w0.102: 38.33,91.93 38.16,92.1 38.16,92.51 38.28,92.64 38.28,92.84 38.16,92.97 38.16,93.22 38.33,93.4 38.33,93.5 37.85,93.98 v3(37.76,93.98)
  IN3 w0.165: v3(50.98,84.97) 50.27,85.68 49.33,85.68 49.13,85.48 48.36,85.48 45.71,88.13 45.71,92.03 46.92,93.24 46.92,94.19 46.79,94.31 46.39,94.31 46.21,94.14 46.21,93.32 45.98,93.1 45.67,93.1 45.43,93.34 45.43,94.66 45.24,94.85 44.91,94.85 44.77,94.71 44.77,93.21 44.58,93.02 44.25,93.02 44.11,93.16 44.11,94.33 43.97,94.47 43.64,94.47 43.45,94.28 43.45,93.64 43.31,93.51 42.87,93.06 42.87,92.83 43.4,92.29 43.4,92.06 43.17,91.83 42.93,91.83 42.3,92.46 42.07,92.46 41.85,92.24 41.85,91.74 41.54,91.42 41.54,91.16 41.23,90.86 40.67,90.86 40.21,90.4 39.91,90.4 39.25,91.06 39.25,91.8 39.12,91.93 38.33,91.93
  BOTTOM w0.102: 52.97,83.85 53.4,83.85 53.47,83.77 53.73,83.77 54.05,84.1 UV1.D16
  BOTTOM w0.127: 52.97,83.85 51.62,83.85 50.98,84.48 v3(50.98,84.97)
M_DA34: length 40.7
  TOP w0.102: v3(38.57,97.13) 38.17,97.53 UV7.G2
  IN3 w0.102: 54.6,86.76 54.84,86.52 54.84,85.68 v3(55.17,85.36) ; v3(38.57,97.13) 38.96,97.51 39.5,97.51 39.73,97.74 39.73,98.18 39.76,98.2 39.76,99.06
  IN3 w0.165: 39.76,99.06 39.63,99.19 39.63,99.75 40.14,100.26 40.14,100.84 40.62,101.32 54.77,101.32 55.4,100.69 55.4,96.45 54.9,95.94 54.59,95.94 53.96,95.31 53.96,92.41 53.5,91.95 53.5,91.7 53.27,91.47 52.51,91.47 52.38,91.34 52.38,91.06 52.51,90.94 53.4,90.94 53.57,90.76 53.57,90.63 53.82,90.37 53.96,90.37 54.16,90.17 54.16,87.2 54.6,86.76
  BOTTOM w0.124: UV1.F15 55.6,84.92 55.17,85.35 v3(55.17,85.36)
M_DA35: length 40.6
  TOP w0.124: v3(39.33,93.12) 38.95,92.74 UV7.F8
  IN3 w0.102: 51.09,85.45 51.52,85.01 51.53,85.01 v3(51.58,84.97)
  IN3 w0.165: v3(39.33,93.12) 39.12,93.12 39,93.25 39,93.43 39.2,93.63 39.73,93.63 39.93,93.43 39.93,92.97 40.1,92.8 40.43,92.8 40.62,92.61 40.62,91.93 40.77,91.77 41.18,91.77 41.33,91.93 41.33,92.46 42.4,93.53 42.63,93.53 42.91,93.81 42.91,94.42 44.12,95.63 44.12,96.01 44.35,96.24 44.56,96.24 46.01,94.78 46.3,94.78 46.53,95.02 46.53,95.2 45.5,96.23 45.5,96.5 45.9,96.91 46.23,96.91 46.46,96.68 46.46,96.11 46.63,95.94 46.96,95.94 47.12,96.11 47.12,96.61 47.31,96.8 47.94,96.8 48.16,96.58 48.16,96.24 47.43,95.51 47.43,92.92 46.53,92.02 46.53,88.7 46.28,88.46 46.28,88.22 46.51,87.99 46.75,87.99 46.99,88.24 47.23,88.24 47.46,88 47.46,87.77 47.21,87.52 47.21,87.29 47.45,87.06 47.68,87.06 47.93,87.3 48.16,87.3 48.39,87.07 48.39,86.84 48.15,86.59 48.15,86.36 48.35,86.15 50.39,86.15 51.09,85.45
  BOTTOM w0.127: v3(51.58,84.97) 51.42,84.8 51.42,84.66 51.85,84.23 52.25,84.23 52.36,84.33 52.36,84.84 52.56,85.04 53.06,85.04 UV1.A15
M_DA36: length 40.2
  TOP w0.127: v3(39.68,94.14) 39.68,94.09 39.13,93.53 UV7.F7
  IN3 w0.165: v3(39.68,94.14) 39.68,94.24 39.99,94.54 40.39,94.54 40.51,94.43 40.51,94.11 40.42,94.02 40.42,93.48 40.67,93.22 41.38,93.22 41.56,93.4 41.56,93.93 42.09,94.47 42.27,94.47 43.47,95.66 43.47,96.22 44,96.75 44.99,96.75 45.68,97.44 45.68,97.79 45.93,98.05 46.57,98.05 46.74,97.88 46.74,97.45 46.9,97.29 47.23,97.29 47.4,97.45 47.4,97.88 47.56,98.05 47.89,98.05 48.06,97.88 48.06,97.45 48.22,97.29 48.55,97.29 48.72,97.45 48.72,97.88 48.88,98.05 49.21,98.05 49.38,97.88 49.38,97.45 49.54,97.29 49.87,97.29 50.04,97.45 50.04,97.88 50.2,98.05 50.78,98.05 50.91,97.92 50.91,97.44 50.04,96.58 50.04,96.24 49.66,95.86 48.49,95.86 48.06,95.43 48.06,92.56 47.33,91.83 47.33,88.8 48.9,87.23 48.9,86.82 49.1,86.62 50.56,86.62 v3(51.61,85.57)
  BOTTOM w0.127: v3(51.61,85.57) 52.06,85.57 52.34,85.3 54,85.3 UV1.D14
M_DA37: length 40.9
  TOP w0.127: v3(39.34,97.93) 39.34,97.92 UV7.F2
  IN3 w0.165: v3(39.34,97.93) 38.87,98.4 37.99,98.4 37.65,98.73 37.65,99.45 38.36,100.16 39.27,100.16 39.53,100.41 39.53,101.58 39.76,101.81 55.1,101.81 55.89,101.02 55.89,95.84 55.56,95.51 55.25,95.51 54.92,95.18 54.92,94.51 55.09,94.35 55.81,94.35 55.98,94.18 55.98,93.85 55.81,93.69 55.09,93.69 54.92,93.52 54.92,92.97 54.63,92.68 54.63,87.5 v3(55.24,86.9)
  BOTTOM w0.124: v3(55.24,86.9) 55.6,86.54 UV1.F13
M_DA38: length 39.8
  TOP w0.127: v3(40.15,97.13) 39.75,96.73 UV7.E3
  IN3 w0.165: v3(40.15,97.13) 40.36,96.92 40.69,96.92 41.97,98.2 41.97,99.6 42.27,99.9 43.39,99.9 43.77,100.28 53.88,100.28 54.24,99.93 54.24,97.44 52.28,95.48 52.28,94.29 51.75,93.76 50.55,93.76 50.27,93.48 50.27,92.97 50.7,92.54 50.7,91.34 50.35,90.99 49.74,90.99 49.49,90.73 49.49,89.74 49.71,89.51 50.25,89.51 50.41,89.68 50.41,89.83 50.58,90 50.91,90 51.07,89.83 51.07,89.68 51.24,89.51 52.82,89.51 53.22,89.11 53.22,88.73 53.09,88.6 52.41,88.6 52.27,88.46 52.27,88.1 52.46,87.91 52.84,87.91 52.97,87.79 52.97,87.63 v3(52.48,87.15)
  BOTTOM w0.124: v3(52.48,87.15) 52.57,87.07 52.57,86.97 53.03,86.5 UV1.A13
M_DA39: length 40.4
  TOP w0.102: UV7.H3 37.38,96.73 v3(37.75,96.36)
  IN3 w0.102: 40.37,97.54 39.93,97.54 39.76,97.36 39.76,96.88 39.55,96.68 38.08,96.68 37.77,96.36 v3(37.75,96.36)
  IN3 w0.165: v3(53.6,86.21) 53.69,86.31 53.69,89.32 53.04,89.97 53.03,89.97 53.01,89.98 52.22,89.98 51.85,90.35 51.85,90.78 51.2,91.43 51.2,92.07 51.52,92.38 53.09,92.38 53.47,92.77 53.47,94.31 52.97,94.82 52.97,95.38 54.13,96.55 54.68,96.55 54.84,96.71 54.84,100.39 54.46,100.77 43.08,100.77 42.97,100.66 42.97,100.65 42.72,100.39 42.71,100.39 42.7,100.39 41.59,100.39 41.31,100.11 41.31,99.06 41.41,98.96 41.41,98.58 40.37,97.54
  BOTTOM w0.124: v3(53.6,86.21) 53.63,86.24 53.63,86.26 53.87,86.5 UV1.C13
M_DA40: length 46.6
  TOP w0.127: v3(50.03,89.02) 50.02,89.03 47.31,89.03 47.02,89.32 47.02,89.41 47.15,89.54 48.8,89.54 48.93,89.67 48.93,90.46 48.58,90.81 46.04,90.81 45.75,91.09 45.75,91.95 45.88,92.08 47.91,92.08 48.04,92.21 48.04,93.22 47.91,93.35 46.64,93.35 46.51,93.48 46.51,93.7 49.43,96.62 49.43,97.79 49.56,97.92 50.2,97.92 50.32,98.05 50.32,98.3 50.2,98.43 49.56,98.43 49.43,98.56 49.43,99.57 49.56,99.7 50.2,99.7 50.32,99.83 50.32,100.08 50.2,100.21 48.29,100.21 48.16,100.08 48.16,97.13 44.48,93.45 44.48,91.44 44.35,91.32 44.1,91.32 43.97,91.44 43.97,91.77 43.41,92.33 42.32,92.33 42.15,92.51 UV7.B8
  BOTTOM w0.102: 51.26,87.79 53.35,87.79 53.42,87.86 53.78,87.86 53.85,87.79 54.49,87.79 UV1.E11
  BOTTOM w0.127: 51.26,87.79 51.24,87.79 50.03,88.99 v3(50.03,89.02)
M_DA41: length 45.3
  TOP w0.127: UV7.D7 40.28,93.53 40.16,93.41 40.16,93.25 40.28,93.13 43.5,93.13 47.78,97.41 47.78,101.6 47.91,101.73 48.16,101.73 48.29,101.6 48.29,100.72 48.42,100.59 50.58,100.59 50.7,100.46 50.7,99.45 50.58,99.32 49.94,99.32 49.82,99.19 49.82,98.94 49.94,98.81 50.58,98.81 50.7,98.68 50.7,97.67 50.58,97.54 49.94,97.54 49.82,97.41 49.82,97.16 49.94,97.03 50.58,97.03 50.7,96.91 50.7,96.65 50.58,96.52 49.88,96.52 49.24,95.89 49.24,95.71 49.41,95.54 49.41,95.36 49.23,95.18 49.05,95.18 48.88,95.35 48.7,95.35 47.4,94.05 47.4,93.86 47.53,93.73 48.29,93.73 48.42,93.6 48.42,91.83 48.29,91.7 v1(47.43,91.7) 46.26,91.7 46.13,91.57 46.13,91.32 46.26,91.19 48.73,91.19 49.31,90.62 49.31,89.67 49.43,89.54 50.7,89.54 50.83,89.41 50.83,89.24 v3(50.63,89.03)
  BOTTOM w0.102: UV1.A11 51.56,88.1 51.49,88.17
  BOTTOM w0.127: 51.49,88.17 v3(50.63,89.03)
M_DA42: length 45.6
  TOP w0.127: UV7.A7 43.35,93.53 47.4,97.59 47.4,101.99 47.53,102.11 48.04,102.11 48.16,102.24 48.16,102.49 48.04,102.62 47.53,102.62 47.4,102.75 47.4,103 47.53,103.13 49.18,103.13 49.31,103 49.31,102.75 49.18,102.62 48.8,102.62 48.67,102.49 48.67,101.1 48.8,100.97 49.05,100.97 49.18,101.1 49.18,101.99 49.31,102.11 49.56,102.11 49.69,101.99 49.69,101.1 49.82,100.97 50.07,100.97 50.2,101.1 50.2,101.99 50.32,102.11 50.96,102.11 51.09,101.99 51.09,101.73 50.96,101.6 50.83,101.6 50.7,101.48 50.7,101.22 50.83,101.1 50.97,101.1 51.09,100.98 51.09,96.48 50.75,96.14 50.04,96.14 49.93,96.03 49.93,95.91 50.13,95.7 50.13,95.52 v1(49.88,95.27) 49.23,94.62 49.05,94.62 48.91,94.76 48.66,94.76 48.27,94.38 48.27,94.26 48.42,94.11 48.67,94.11 48.8,93.98 48.8,91.66 49.69,90.78 49.69,90.05 49.82,89.92 51.47,89.92 51.59,90.05 52.1,90.05 52.23,89.92 52.23,89.67 52.1,89.54 51.72,89.54 51.59,89.41 51.34,89.41 51.23,89.3 v3(51.23,89.03)
  BOTTOM w0.102: v3(51.23,89.03) 51.83,88.42 53.35,88.42 53.67,88.1 UV1.C11
M_DA43: length 46.4
  TOP w0.127: UV7.C8 41.35,92.72 41.74,92.33 41.74,91.11 41.92,90.94 44.74,90.94 44.86,91.06 44.86,93.29 48.55,96.97 48.55,99.7 48.67,99.83 48.93,99.83 49.05,99.7 49.05,96.78 45.5,93.22 45.5,93.1 45.62,92.97 47.53,92.97 47.66,92.84 47.66,92.59 47.53,92.46 45.62,92.46 45.37,92.21 45.37,90.94 45.88,90.43 48.42,90.43 48.55,90.3 48.55,90.05 48.42,89.92 46.64,89.92 46.51,89.79 46.51,89.29 47.21,88.59 51.4,88.59 v3(51.85,89.03)
  BOTTOM w0.102: v3(51.85,89.03) 52.25,88.62 53.45,88.62 53.6,88.47 55.23,88.47 UV1.F11
M_DA44: length 45
  TOP w0.127: UV7.C3 41.35,96.23 41.79,95.79 43.39,95.79 45.75,98.14 45.75,104.78 46.51,105.54 52.77,105.54 53.5,104.81 v1(53.5,103.31) 53.5,102.87 53.37,102.75 52.86,102.75 52.74,102.62 52.74,95.97 51.59,94.83 51.59,94.62 51.85,94.37 51.85,94.11 51.72,93.98 51.47,93.98 51.23,94.22 50.98,94.22 50.83,94.07 50.83,93.86 51.21,93.48 52.2,93.48 52.74,92.94 52.74,92.46 52.61,92.33 51.47,92.33 51.21,92.08 51.21,91.83 51.09,91.7 51.09,91.06 51.21,90.94 51.47,90.94 51.59,90.81 51.85,90.81 51.97,90.94 51.97,91.32 52.1,91.44 52.99,91.44 53.12,91.32 53.12,91.06 52.99,90.94 52.61,90.94 52.46,90.78 v3(52.46,90.43)
  BOTTOM w0.127: UV1.A9 52.5,90.4 52.48,90.4 v3(52.46,90.43)
M_DA45: length 45.4
  TOP w0.127: v3(53.04,90.43) 53.17,90.3 53.37,90.3 53.5,90.43 53.5,92.05 53.17,92.38 53.17,93.04 52.23,93.98 52.23,94.93 53.12,95.82 53.12,97.16 53.24,97.29 53.75,97.29 53.88,97.41 53.88,97.67 53.75,97.79 53.24,97.79 53.12,97.92 53.12,99.7 53.24,99.83 53.75,99.83 53.88,99.95 53.88,100.21 53.75,100.33 53.24,100.33 53.12,100.46 53.12,102.24 53.24,102.37 54.51,102.37 54.64,102.49 54.64,102.75 54.51,102.87 54.01,102.87 53.88,103 53.88,104.14 54.01,104.27 54.51,104.27 54.64,104.4 54.64,104.65 54.51,104.78 54.07,104.78 52.93,105.92 45.24,105.92 45.12,105.8 45.12,105.41 45.37,105.16 45.37,98.3 43.34,96.27 42.86,96.27 42.56,96.57 42.56,96.87 42.3,97.13 41.5,97.13 41.35,97.29 UV7.C2
  BOTTOM w0.127: UV1.C9 53.77,89.7 v3(53.04,90.43)
M_DA46: length 46
  TOP w0.127: UV7.A2 43.51,97.53 44.61,98.63 44.61,104.65 44.35,104.91 44.35,105.29 44.23,105.41 43.97,105.41 43.85,105.29 43.85,104.98 43.72,104.86 43.12,104.86 42.95,105.03 42.95,106.47 43.17,106.68 53.24,106.68 54.39,105.54 55.28,105.54 55.4,105.41 55.4,101.73 55.28,101.6 v1(55.05,101.6) 54.01,101.6 53.88,101.48 53.88,101.22 54.01,101.1 54.64,101.1 54.73,101.01 54.73,99.15 54.64,99.06 54.01,99.06 53.88,98.94 53.88,98.68 54.01,98.56 54.6,98.56 54.73,98.43 54.73,96.52 54.6,96.4 54.01,96.4 53.88,96.27 53.88,95.31 53.93,95.25 53.93,92.89 54.44,92.38 54.44,90.77 v3(55.07,90.14)
  BOTTOM w0.127: UV1.F9 55.51,89.7 v3(55.07,90.14)
M_DA47: length 45.4
  TOP w0.127: v3(54.01,91.8) 54.03,91.83 54.03,92.08 53.55,92.56 53.55,93.2 53.12,93.63 53.12,93.86 53.24,93.98 53.37,93.98 53.55,94.16 53.55,94.31 53.37,94.49 52.86,94.49 52.74,94.62 52.74,94.84 53.5,95.6 53.5,96.65 53.63,96.78 54.13,96.78 54.26,96.91 54.26,98.05 54.13,98.18 53.63,98.18 53.5,98.3 53.5,99.32 53.63,99.45 54.13,99.45 54.26,99.57 54.26,100.59 54.13,100.72 53.63,100.72 53.5,100.84 53.5,101.86 53.63,101.99 54.9,101.99 55.02,102.11 55.02,103.13 54.9,103.26 54.39,103.26 54.26,103.38 54.26,103.76 54.39,103.89 54.9,103.89 55.02,104.02 55.02,105.03 54.9,105.16 54.23,105.16 53.09,106.3 43.5,106.3 43.38,106.18 43.38,105.93 43.51,105.8 44.61,105.8 44.74,105.67 44.74,105.26 44.99,105 44.99,98.46 43.26,96.73 UV7.A3
  BOTTOM w0.127: UV1.D8 54.44,90.54 54.44,91.39 54.01,91.82 v3(54.01,91.8)
M_DA48: length 41.3
  IN1 w0.102: 39.15,91.85 39.1,91.85 38.94,92 38.94,92.74 v3(38.59,93.1)
  IN1 w0.14: 39.15,91.85 42.73,91.85 42.87,91.99 42.87,92.47 43.01,92.61 43.29,92.61 43.43,92.47 43.43,91.99 43.57,91.85 43.77,91.85 44.08,91.55 44.7,91.55 44.84,91.69 44.84,92.62 44.7,92.76 43.96,92.76 43.82,92.9 43.82,93.18 43.96,93.32 44.7,93.32 44.84,93.46 44.84,93.92 44.98,94.06 45.26,94.06 45.4,93.92 45.4,91.69 45.54,91.55 45.81,91.55 45.95,91.69 45.95,93.92 46.09,94.06 46.37,94.06 46.51,93.92 46.51,91.69 46.65,91.55 46.93,91.55 47.07,91.69 47.07,93.92 47.21,94.06 47.49,94.06 47.63,93.92 47.63,91.69 47.77,91.55 48.05,91.55 48.19,91.69 48.19,93.92 48.33,94.06 48.61,94.06 48.75,93.92 48.75,91.69 48.89,91.55 49.28,91.55 49.89,90.94 53.22,90.94 53.78,90.38 54.46,90.38 54.88,90.79 v3(55.2,90.79)
  BOTTOM w0.124: UV1.E7 54.8,91.19 v3(55.2,90.79) ; v3(38.59,93.1) 38.27,92.77 38.19,92.77 UV8.G2
M_DA49: length 41.6
  IN1 w0.14: v3(52.33,91.9) 52.33,91.93 51.95,92.31 51.11,92.31 50.32,93.1 50.32,93.83 50.58,94.09 50.58,94.39 50.32,94.65 50.32,94.95 50.58,95.21 50.58,95.51 50.32,95.77 50.32,96.07 50.58,96.33 50.58,96.63 50.32,96.89 50.32,97.18 50.46,97.33 51.15,97.33 51.29,97.47 51.29,97.74 51.14,97.9 49.96,97.9 49.82,98.04 49.82,98.32 49.96,98.45 51.15,98.45 51.29,98.59 51.29,98.87 51.15,99.01 49.96,99.01 49.82,99.15 49.82,99.43 49.96,99.57 51.11,99.57 51.24,99.7 51.24,100.94 51.11,101.07 50.6,101.07 50.48,100.96 50.48,100.16 50.34,100.02 50.06,100.02 49.92,100.16 49.92,100.96 49.78,101.1 49.5,101.1 49.36,100.96 49.36,100.23 49.22,100.09 48.94,100.09 48.81,100.23 48.81,100.96 48.67,101.1 48.39,101.1 48.25,100.96 48.25,100.23 48.11,100.09 47.83,100.09 47.69,100.23 47.69,100.96 47.55,101.1 47.27,101.1 47.13,100.96 47.13,100.23 46.99,100.09 46.71,100.09 46.57,100.23 46.57,100.96 46.43,101.1 46.11,101.1 45.98,100.97 45.98,99.83 45.24,99.09 45.24,97.97 43.97,96.7 43.97,95.84 42.6,94.47 41.41,94.47 v3(40.98,94.04)
  BOTTOM w0.124: UV8.E3 40.25,94.04 v3(40.98,94.04)
  BOTTOM w0.127: v3(52.33,91.9) 52.33,91.77 52.66,91.44 53.06,91.44 UV1.A7
M_DA50: length 41.8
  IN1 w0.102: 39.66,93.53 37.34,93.53 36.96,93.15 36.96,93.15 v3(36.91,93.15)
  IN1 w0.14: v3(51.71,91.88) 51.68,91.85 50.88,91.85 49.88,92.85 49.88,96.84 49.34,97.38 46.4,97.38 46.28,97.5 46.28,97.78 46.45,97.94 49.26,97.94 49.37,98.05 49.37,98.33 49.21,98.5 46.4,98.5 46.28,98.61 46.28,98.89 46.45,99.06 49.26,99.06 49.37,99.17 49.37,99.48 49.21,99.65 46.46,99.65 45.8,98.99 45.8,97.69 44.53,96.42 44.53,95.46 42.6,93.53 42.11,93.53 41.97,93.67 41.97,93.82 41.83,93.96 41.55,93.96 41.41,93.82 41.41,93.67 41.27,93.53 40.85,93.53 40.37,94.01 40.14,94.01 39.66,93.53
  BOTTOM w0.102: v3(36.91,93.15) 36.96,93.15 UV8.H3
  BOTTOM w0.127: v3(51.71,91.88) 51.71,91.81 52.58,90.94 53.4,90.94 53.76,91.3 UV1.C7
M_DA51: length 41.1
  IN1 w0.14: v3(56,90.95) 55.8,90.95 55.48,91.27 53.85,91.27 53.74,91.38 50.08,91.38 49.43,92.02 49.43,94.33 49.24,94.52 48.18,94.52 48.04,94.66 48.04,94.94 48.18,95.08 49.29,95.08 49.43,95.22 49.43,95.5 49.29,95.64 48.18,95.64 48.04,95.78 48.04,96.05 48.18,96.19 49.29,96.19 49.43,96.33 49.43,96.61 49.25,96.8 46.04,96.8 45.88,96.63 45.88,96.35 45.99,96.24 47.52,96.24 47.66,96.1 47.66,95.82 47.52,95.68 45.36,95.68 45.19,95.51 45.19,95.24 45.31,95.12 47.52,95.12 47.66,94.98 47.66,94.67 47.5,94.52 44.49,94.52 43.03,93.06 42.48,93.06 42.34,92.92 42.34,92.45 42.2,92.31 41.92,92.31 41.78,92.45 41.78,92.92 41.64,93.06 41.36,93.06 41.22,92.92 41.22,92.45 41.08,92.31 40.8,92.31 40.66,92.45 40.66,92.92 40.52,93.06 40.04,93.06 v3(39.34,92.35)
  BOTTOM w0.127: UV8.F2 39.33,92.35 v3(39.34,92.35) ; UV1.F7 55.65,91.3 v3(56,90.95)
M_DA52: length 40.5
  IN1 w0.14: v3(52.74,94.09) 52.71,94.09 52.61,94.19 52.61,95.46 54.44,97.29 54.44,102.67 53.63,103.48 52.64,103.48 52.5,103.62 52.5,104.28 52.36,104.42 52.08,104.42 51.94,104.28 51.94,104.08 51.8,103.94 51.52,103.94 51.38,104.08 51.38,104.28 51.24,104.42 50.96,104.42 50.83,104.28 50.83,104.08 50.69,103.94 50.41,103.94 50.27,104.08 50.27,104.28 50.13,104.42 49.85,104.42 49.71,104.28 49.71,104.08 49.57,103.94 49.28,103.94 49.14,104.08 49.14,104.31 49,104.45 48.72,104.45 48.58,104.31 48.58,104.08 48.45,103.94 48.17,103.94 48.03,104.08 48.03,104.31 47.89,104.45 47.61,104.45 47.47,104.31 47.47,104.08 47.33,103.94 47.05,103.94 46.91,104.08 46.91,104.31 46.77,104.45 46.49,104.45 46.35,104.31 46.35,104.08 46.21,103.94 45.19,103.94 44.41,103.15 44.41,102.98 44.1,102.67 41.94,102.67 41.7,102.43 41.7,102.16 41.84,102.02 42.31,102.02 42.45,101.88 42.45,101.6 41.92,101.07 41.92,100.59 42.11,100.4 42.11,99.65 41.92,99.46 41.92,98.33 40.27,96.68 38.33,96.68 38.23,96.78 37.57,96.78 37.2,97.15 v3(36.97,97.15)
  BOTTOM w0.127: UV1.A5 52.76,93.34 52.76,94.06 v3(52.74,94.09) ; UV8.H7 37.35,96.78 v3(36.97,97.15)
M_DA53: length 41.1
  IN1 w0.102: v3(39.32,97.11) 39.32,97.15 39.71,97.54 40.36,97.54
  IN1 w0.14: 40.36,97.54 41.41,98.58 41.41,100.89 41.26,101.05 41.26,104.27 41.43,104.45 41.77,104.45 41.88,104.33 41.88,103.85 42.05,103.69 42.33,103.69 42.44,103.8 42.44,104.33 42.58,104.47 42.86,104.47 43,104.33 43,103.85 43.14,103.71 43.42,103.71 43.56,103.85 43.56,104.33 43.68,104.45 44.02,104.45 44.16,104.32 44.16,104.05 44.27,103.93 44.55,103.93 44.71,104.1 44.71,104.33 44.85,104.47 45.26,104.47 45.35,104.39 45.69,104.39 45.83,104.53 45.83,104.89 45.97,105.03 52.74,105.03 55.05,102.72 55.05,97.24 53.05,95.24 53.05,94.71 54.08,93.68 55.2,93.68 55.53,93.35 55.53,92.8 v3(55.15,92.41)
  BOTTOM w0.102: UV8.F7 v3(39.32,97.11)
  BOTTOM w0.124: UV1.E5 54.8,92.76 v3(55.15,92.41)
M_DA54: length 40.4
  IN1 w0.102: v3(38.63,97.93) 39.07,98.38 39.53,98.38 39.76,98.61 39.76,99.22
  IN1 w0.14: 39.76,99.22 40.39,99.85 40.39,101.68 40.53,101.82 40.63,101.82 40.77,101.96 40.77,102.24 40.63,102.38 40.53,102.38 40.39,102.52 40.39,103.38 40.72,103.71 40.72,105.44 40.85,105.57 41.21,105.57 41.35,105.43 41.35,105.07 41.51,104.91 41.79,104.91 41.91,105.02 41.91,105.43 42.05,105.57 42.31,105.57 42.45,105.43 42.45,105.06 42.59,104.92 42.87,104.92 43.01,105.06 43.01,105.43 43.15,105.57 43.43,105.57 43.57,105.43 43.57,105.06 43.71,104.92 43.99,104.92 44.13,105.06 44.13,105.43 44.27,105.57 44.55,105.57 44.69,105.43 44.69,105.06 44.83,104.92 45.11,104.92 45.25,105.06 45.25,105.76 45.39,105.9 45.93,105.9 46.32,105.5 52.98,105.5 55.68,102.8 55.68,97.06 53.93,95.31 53.93,94.64 v3(54.44,94.14)
  BOTTOM w0.127: UV8.F8 38.95,97.61 v3(38.63,97.93) ; UV1.C3 54.44,94.14 v3(54.44,94.14)
M_DA55: length 40.5
  IN1 w0.102: 38.11,97.51 v3(37.77,97.18)
  IN1 w0.14: 38.11,97.51 38.11,98.2 39.68,99.78 39.68,102.42 39.4,102.7 39.4,103.62 39.52,103.74 40.1,103.74 40.24,103.88 40.24,104.16 40.1,104.3 39.69,104.3 39.58,104.41 39.58,104.69 39.74,104.86 40.1,104.86 40.24,105 40.24,105.27 40.1,105.41 39.52,105.41 39.43,105.5 39.43,105.9 39.55,106.02 44.71,106.02 45.04,106.35 46.16,106.35 46.56,105.95 53.16,105.95 56.42,102.69 56.42,96.96 v3(54.39,94.94)
  BOTTOM w0.124: UV1.E1 54.8,94.53 v3(54.39,94.94)
  BOTTOM w0.127: v3(37.77,97.18) 37.42,97.53 UV8.H8
M_DA56: length 47.2
  BOTTOM w0.102: UV1.G7 55.99,91.71 55.99,92.21 55.61,92.59 55.58,92.59 55.2,92.97 55.2,94.57 54.81,94.96 54.81,95.09 54.54,95.36 54.16,95.36
  BOTTOM w0.127: UV8.C2 41.39,92.73 41.74,92.38 41.74,91.06 41.97,90.83 42.63,90.83 42.81,90.66 42.81,86.65 43.16,86.3 44.04,86.3 44.23,86.11 44.23,85.57 44.8,84.99 45.08,84.99 45.21,84.87 45.21,84.59 45.34,84.46 45.59,84.46 45.72,84.59 45.72,84.87 45.84,84.99 46.1,84.99 46.23,84.87 46.23,84.59 46.35,84.46 46.61,84.46 46.73,84.59 46.73,84.87 46.86,84.99 47.11,84.99 47.24,84.87 47.24,84.1 47.36,83.98 49.28,83.98 49.45,84.16 49.45,85.09 49.33,85.22 49.07,85.22 48.95,85.09 48.95,84.64 48.79,84.49 47.88,84.49 47.75,84.62 47.75,84.87 47.88,84.99 47.99,84.99 48.75,85.75 49.82,85.75 50.15,86.08 v1(50.15,87.06) 50.15,87.65 49.75,88.04 49.16,88.04 48.98,88.22 48.98,88.49 49.18,88.69 49.18,91.98 49.89,92.69 50.02,92.69 50.65,92.06 50.83,92.06 51.01,92.24 51.01,92.42 50.25,93.18 50.25,93.39 50.56,93.7 50.91,93.7 51.03,93.83 51.03,94.18 51.17,94.31 51.41,94.31 51.53,94.19 51.53,93.6 51.66,93.48 51.91,93.48 52.04,93.6 52.04,94.19 52.17,94.31 52.3,94.31 52.91,94.92 52.91,95.18 52.69,95.4 52.69,95.58 52.89,95.79 53.04,95.79 53.22,95.61 53.4,95.61 53.57,95.79 53.73,95.79 54.16,95.36
M_DA57: length 46.3
  BOTTOM w0.102: 54.97,95.84 55.43,95.84 56.09,95.18 56.09,94.37 56.17,94.29 56.17,93.91 55.96,93.7 55.96,92.79 56.4,92.35 UV1.G6
  BOTTOM w0.127: UV8.A2 42.95,92.91 43.36,93.32 44.41,93.32 44.79,92.95 44.79,90.73 44.58,90.53 43.8,90.53 43.57,90.3 43.57,89.45 43.92,89.1 44.71,89.1 44.86,88.96 44.86,88.22 44.99,88.09 44.99,85.88 45.12,85.75 45.42,85.75 45.55,85.88 45.55,87.94 45.68,88.07 45.95,88.07 46.07,87.94 46.07,85.88 46.2,85.75 46.45,85.75 46.58,85.88 46.58,87.94 46.71,88.07 46.96,88.07 47.09,87.94 47.09,85.88 47.22,85.75 47.47,85.75 47.6,85.88 47.6,85.94 47.72,86.07 47.99,86.07 48.11,86.19 48.11,86.45 47.99,86.57 47.72,86.57 47.6,86.7 47.6,86.96 47.72,87.08 47.99,87.08 48.11,87.21 48.11,87.46 47.99,87.59 47.72,87.59 47.6,87.72 47.6,87.94 47.72,88.07 48.04,88.07 48.22,88.24 48.22,88.8 48.42,89.01 48.42,89.31 48.22,89.52 48.22,89.82 48.42,90.02 48.42,90.33 48.22,90.53 48.22,90.84 48.42,91.04 48.42,91.34 48.22,91.55 48.22,91.85 48.42,92.06 48.42,92.29 48.85,92.73 48.85,93.39 v1(49.05,93.59) 49.24,93.78 49.56,93.78 51.08,95.3 51.26,95.3 51.46,95.1 51.74,95.1 51.87,95.23 51.87,95.41 51.62,95.66 51.62,95.84 52.33,96.55 54.08,96.55 54.79,95.84 54.97,95.84
M_DA58: length 45.5
  BOTTOM w0.102: UV1.G1 56.4,95.3 55.61,96.09 55.07,96.09
  BOTTOM w0.127: UV8.A3 43.12,93.7 44.53,93.7 44.66,93.83 44.84,93.83 44.94,93.73 44.94,93.35 45.28,93 46.02,93 46.29,92.73 46.29,92.55 46.17,92.43 45.29,92.43 45.17,92.3 45.17,92.05 45.29,91.92 46.17,91.92 46.29,91.79 46.29,91.54 46.17,91.41 45.29,91.41 45.17,91.28 45.17,91.03 45.29,90.9 46.17,90.9 46.29,90.78 46.29,90.53 46.14,90.38 45.32,90.38 45.19,90.25 45.19,90.12 45.07,89.99 44.08,89.99 43.95,89.87 43.95,89.61 44.08,89.48 45.12,89.48 45.24,89.36 45.24,88.57 45.37,88.45 45.65,88.45 45.78,88.57 45.78,89.74 45.88,89.84 46.18,89.84 46.28,89.74 46.28,88.6 46.44,88.45 46.69,88.45 46.8,88.56 46.8,92.41 46.93,92.54 47.18,92.54 47.31,92.41 v1(47.31,92.14) 47.31,88.57 47.44,88.45 47.71,88.45 47.82,88.56 47.82,92.41 47.94,92.54 48.11,92.54 48.47,92.89 48.47,93.55 49.08,94.16 49.33,94.16 49.71,94.54 49.71,95.28 49.86,95.43 50.6,95.43 50.93,95.76 50.93,96.04 51.03,96.14 51.31,96.14 51.68,96.51 51.68,96.82 51.85,96.98 54.18,96.98 55.07,96.09
M_DA59: length 46
  BOTTOM w0.102: UV1.G3 56.41,93.7 56.75,94.04 56.75,95.29 55.7,96.35
  BOTTOM w0.127: 55.7,96.35 55.43,96.35 54.74,97.03 54.74,97.26 54.64,97.36 51.43,97.36 51.3,97.24 51.3,96.68 51.18,96.55 50.92,96.55 50.79,96.68 50.79,97.24 50.67,97.36 50.45,97.36 49.92,96.83 49.45,96.83 49.33,96.7 49.33,96.44 49.45,96.32 50.43,96.32 50.55,96.19 50.55,95.93 50.43,95.81 49.45,95.81 49.33,95.68 49.33,94.7 49.17,94.54 48.95,94.54 48.82,94.68 48.82,96.8 48.69,96.93 48.52,96.93 48.31,96.72 v1(48.31,96.33) 48.31,95.81 48.16,95.66 48.16,95.41 48.31,95.26 48.31,95.07 48.19,94.95 47.71,94.95 47.58,95.08 47.58,95.79 47.8,96.01 47.8,96.7 47.68,96.83 47.43,96.83 47.3,96.7 47.3,96.24 47.01,95.95 47.01,94.63 47.15,94.49 48.37,94.49 48.49,94.37 48.49,94.11 48.37,93.98 48.2,93.98 48.07,93.86 48.07,93.04 47.95,92.92 47.69,92.92 47.57,93.04 47.57,93.86 47.44,93.98 47.17,93.98 47.02,93.83 47.02,93.07 46.89,92.94 46.64,92.94 46.51,93.08 46.51,93.26 46.38,93.39 45.45,93.39 45.32,93.51 45.32,93.77 45.45,93.89 46.38,93.89 46.51,94.02 46.51,95.46 46.35,95.61 46.09,95.61 45.69,95.21 45.69,95.03 46.01,94.72 46.01,94.48 45.86,94.34 45.66,94.34 45.33,94.67 45.15,94.67 44.92,94.44 44.63,94.44 44.5,94.31 44.5,94.21 44.37,94.09 44.12,94.09 43.99,94.21 43.99,94.31 43.86,94.44 43.61,94.44 43.48,94.31 43.48,94.21 43.36,94.09 43.1,94.09 42.98,94.21 42.98,94.31 42.85,94.44 41.66,94.44 41.54,94.31 41.54,93.72 UV8.C3
M_DA60: length 47.6
  BOTTOM w0.102: 59.04,96.27 59.04,95.94 59.32,95.66 59.32,95.05 59.09,94.82 59.09,94.24 59.11,94.22 59.11,93.96 58.91,93.76 58.81,93.76 58.43,93.37 58.43,92.54 58,92.12 UV1.J6
  BOTTOM w0.127: 59.04,96.27 58.29,97.02 58.29,102.96 57.88,103.37 55.54,103.37 55.04,103.87 54.59,103.87 54.46,103.74 54.46,103.33 54.33,103.2 54.08,103.2 53.95,103.33 53.95,103.74 53.82,103.87 53.43,103.87 53.31,103.75 53.31,103.31 53.18,103.18 52.93,103.18 52.8,103.31 52.8,103.75 52.67,103.88 52.42,103.88 52.29,103.75 52.29,103.31 52.16,103.18 51.91,103.18 51.78,103.31 51.78,103.75 51.66,103.88 51.4,103.88 51.28,103.75 51.28,103.31 51.15,103.18 50.89,103.18 50.77,103.31 50.77,103.75 50.64,103.88 50.39,103.88 50.26,103.75 50.26,103.31 50.13,103.18 49.88,103.18 49.75,103.31 49.75,103.75 49.62,103.88 49.37,103.88 49.24,103.75 49.24,103.31 49.12,103.18 48.86,103.18 48.74,103.31 48.74,103.75 48.61,103.88 48.35,103.88 48.23,103.75 48.23,103.31 48.1,103.18 47.85,103.18 47.72,103.31 v1(47.72,103.57) 47.72,103.75 47.59,103.88 47.34,103.88 47.21,103.75 47.21,103.31 47.08,103.18 46.83,103.18 46.7,103.31 46.7,103.75 46.58,103.88 46.32,103.88 46.2,103.75 46.2,103.31 46.07,103.18 45.81,103.18 45.69,103.31 45.69,103.75 45.56,103.88 45.31,103.88 45.18,103.75 45.18,103.31 45.05,103.18 44.8,103.18 44.67,103.31 44.67,103.75 44.54,103.88 44.16,103.88 43.97,103.69 43.97,100.61 43.19,99.83 41.46,99.83 41.23,99.6 41.23,99.34 41.74,98.84 41.74,98.18 41.5,97.94 41.2,97.94 40.96,97.7 40.96,97.15 UV8.D7
M_DA61: length 46.2
  BOTTOM w0.102: UV1.J1 58.02,94.52 58.02,95.56 57.23,96.35
  BOTTOM w0.127: UV8.B8 42.47,97.53 42.56,97.45 42.56,96.56 42.96,96.17 43.95,96.17 44.1,96.32 44.1,96.63 44.27,96.79 44.51,96.79 44.64,96.67 44.64,96.32 44.77,96.19 45.02,96.19 45.15,96.32 45.15,96.67 45.27,96.79 46.04,96.79 46.16,96.91 46.16,97.82 45.92,98.06 44.65,98.06 44.48,98.23 44.48,98.53 44.61,98.65 45.29,98.65 45.42,98.78 45.42,99.03 45.29,99.16 44.61,99.16 44.48,99.29 44.48,99.5 44.68,99.7 44.96,99.7 45.12,99.85 45.12,100.36 45.24,100.49 45.56,100.49 45.69,100.36 45.69,99.9 45.82,99.78 45.98,99.78 46.2,99.99 46.2,100.36 46.33,100.49 46.58,100.49 46.71,100.36 46.71,99.98 46.83,99.85 47.09,99.85 47.21,99.98 v1(47.21,100.11) 47.21,100.36 47.34,100.49 47.6,100.49 47.72,100.36 47.72,99.98 47.85,99.85 48.1,99.85 48.23,99.98 48.23,100.36 48.36,100.49 48.61,100.49 48.74,100.36 48.74,99.98 48.87,99.85 49.12,99.85 49.25,99.98 49.25,100.36 49.37,100.49 49.63,100.49 49.75,100.36 49.75,99.98 49.88,99.85 50.14,99.85 50.26,99.98 50.26,100.36 50.39,100.49 50.64,100.49 50.77,100.36 50.77,99.98 50.9,99.85 51.15,99.85 51.28,99.98 51.28,100.36 51.41,100.49 51.66,100.49 51.79,100.36 51.79,99.98 51.91,99.85 52.17,99.85 52.29,99.98 52.29,100.36 52.42,100.49 52.68,100.49 52.8,100.36 52.8,99.98 52.93,99.85 53.18,99.85 53.31,99.98 53.31,100.36 53.44,100.49 53.97,100.49 54.41,100.92 54.67,100.92 54.8,100.79 54.8,100.14 54.68,100.02 54.03,100.02 53.88,99.86 53.88,99.65 54.02,99.51 55.01,99.51 55.31,99.81 55.31,100.79 55.43,100.92 56.22,100.92 56.32,100.82 56.32,100.65 55.77,100.1 55.77,99.92 55.95,99.74 56.13,99.74 56.67,100.28 56.89,100.28 57.11,100.07 57.11,99.89 56.99,99.77 56.85,99.77 56.55,99.47 56.55,99.28 57.14,98.68 57.14,96.44 57.23,96.35
M_DA62: length 46.4
  BOTTOM w0.102: 58.2,95.97 58.27,95.89 58.27,94.66 58.32,94.61 58.32,94.37 58,94.04 UV1.J3
  BOTTOM w0.127: 58.2,95.97 57.52,96.64 57.52,100.19 57.02,100.69 57.02,101.04 57.26,101.29 57.37,101.29 57.52,101.44 57.52,102.4 57.32,102.61 56.83,102.61 56.71,102.48 56.71,101.43 56.58,101.3 56.32,101.3 56.2,101.43 56.2,102.48 56.07,102.61 55.82,102.61 55.69,102.48 55.69,101.43 55.56,101.3 55.31,101.3 55.18,101.43 55.18,102.48 55.05,102.61 54.81,102.61 54.62,102.42 54.06,102.42 53.93,102.29 53.93,102.01 54.06,101.88 54.54,101.88 54.64,101.78 54.64,101.43 54.54,101.32 54.39,101.32 54.26,101.45 54.07,101.45 53.94,101.32 53.94,100.99 53.82,100.87 53.56,100.87 53.44,100.99 53.44,101.32 53.31,101.45 53.05,101.45 52.93,101.32 52.93,100.99 52.8,100.87 52.55,100.87 52.42,100.99 52.42,101.32 52.29,101.45 52.04,101.45 51.91,101.32 51.91,100.99 51.78,100.87 51.53,100.87 51.4,100.99 51.4,101.32 51.28,101.45 51.02,101.45 50.9,101.32 50.9,100.99 50.77,100.87 50.51,100.87 50.39,100.99 50.39,101.32 50.26,101.45 50.01,101.45 49.88,101.32 49.88,100.99 49.75,100.87 49.5,100.87 49.37,100.99 49.37,101.32 49.24,101.45 48.99,101.45 48.86,101.32 48.86,100.99 48.74,100.87 48.48,100.87 48.36,100.99 48.36,101.32 48.23,101.45 47.97,101.45 47.85,101.32 47.85,100.99 47.72,100.87 47.47,100.87 47.34,100.99 47.34,101.32 47.21,101.45 46.96,101.45 46.83,101.32 46.83,100.99 46.7,100.87 46.45,100.87 46.32,100.99 46.32,101.32 46.2,101.45 45.94,101.45 45.82,101.32 45.82,100.99 45.69,100.87 45.43,100.87 45.31,100.99 v1(45.31,101.15) 45.31,101.32 45.18,101.45 44.86,101.45 44.74,101.32 44.74,100.3 43.92,99.48 43.92,99.3 44.1,99.12 44.1,97.95 44.37,97.68 45.65,97.68 45.78,97.55 45.78,97.3 45.65,97.17 44.11,97.17 43.67,96.73 UV8.A7
M_DA63: length 47.1
  BOTTOM w0.102: UV1.J5 58,93.25 58.32,93.58 58.32,94.06 58.53,94.26 58.53,96.22
  BOTTOM w0.127: UV8.C8 41.58,97.53 41.99,97.95 43.14,97.95 43.36,98.18 43.36,98.48 42.69,99.15 42.69,99.31 42.83,99.45 43.34,99.45 44.35,100.46 44.35,102.62 44.53,102.8 44.79,102.8 44.92,102.67 44.92,101.96 45.04,101.83 45.3,101.83 45.42,101.96 45.42,102.67 45.55,102.8 45.81,102.8 45.93,102.67 45.93,101.96 46.06,101.83 46.31,101.83 46.44,101.96 46.44,102.67 46.57,102.8 46.82,102.8 46.95,102.67 46.95,101.96 47.08,101.83 47.33,101.83 47.46,101.96 47.46,102.67 47.58,102.8 47.84,102.8 47.96,102.67 47.96,101.96 48.09,101.83 48.35,101.83 48.47,101.96 v1(48.47,102.3) 48.47,102.67 48.6,102.8 48.85,102.8 48.98,102.67 48.98,101.96 49.11,101.83 49.36,101.83 49.49,101.96 49.49,102.67 49.62,102.8 49.87,102.8 50,102.67 50,101.96 50.12,101.83 50.38,101.83 50.5,101.96 50.5,102.67 50.63,102.8 50.89,102.8 51.01,102.67 51.01,101.96 51.14,101.83 51.39,101.83 51.52,101.96 51.52,102.67 51.65,102.8 51.9,102.8 52.03,102.67 52.03,101.96 52.16,101.83 52.41,101.83 52.54,101.96 52.54,102.67 52.66,102.8 52.92,102.8 53.04,102.67 53.04,101.96 53.17,101.83 53.43,101.83 53.55,101.96 53.55,102.67 53.68,102.8 54.46,102.8 54.92,103.26 55.12,103.26 55.38,102.99 57.72,102.99 57.91,102.81 57.91,96.84 58.53,96.22
M_DQM0: length 44.9
  BOTTOM w0.102: UV1.E32 54.8,73.04 55.21,73.46 55.21,73.75 55.56,74.1 55.83,74.1 56.44,74.72 56.44,74.81 56.8,75.16 56.8,75.47 56.98,75.65 57.46,75.65 57.69,75.42 57.69,74.93 57.54,74.78 57.54,74.12 58.05,73.61 58.15,73.61 58.32,73.44 58.32,73.19 58.27,73.14 58.27,72.03 58.32,71.98
  BOTTOM w0.127: UV5.D3 40.94,73.33 43.14,73.33 44.13,72.34 44.13,70.84 43.21,69.93 43.21,66.15 43.85,65.51 44.28,65.51 44.41,65.38 44.41,65.03 44.53,64.9 44.79,64.9 44.91,65.03 44.91,65.38 45.04,65.51 45.29,65.51 45.42,65.38 45.42,65.03 45.55,64.9 45.8,64.9 45.93,65.03 45.93,65.38 46.06,65.51 46.31,65.51 46.44,65.38 46.44,65.03 46.56,64.9 46.82,64.9 46.95,65.03 46.95,65.38 47.07,65.51 47.33,65.51 47.45,65.38 47.45,65.03 47.58,64.9 47.83,64.9 47.96,65.03 47.96,65.38 48.09,65.51 48.34,65.51 48.47,65.38 48.47,64.98 48.62,64.83 48.85,64.83 48.98,64.95 48.98,65.38 49.1,65.51 49.54,65.51 49.71,65.69 49.71,65.87 49.96,66.11 v1(50.41,66.11) 50.98,66.68 50.98,67.24 51.16,67.42 51.52,67.42 51.7,67.59 52.03,67.59 52.2,67.42 52.53,67.42 52.71,67.59 53.04,67.59 53.22,67.42 53.55,67.42 53.73,67.59 54.06,67.59 54.24,67.42 54.57,67.42 54.74,67.59 55.07,67.59 55.25,67.42 55.63,67.42 58.32,70.11 58.32,71.25 58.43,71.35 58.68,71.35 58.81,71.48 58.81,71.73 58.68,71.86 58.43,71.86 58.32,71.96 58.32,71.98
M_DQM1: length 44.3
  TOP w0.102: 51.8,75.24 52.66,76.1 52.66,76.15 52.91,76.41 53.27,76.41 54.01,75.67 54.01,73.66 53.6,73.26 53.6,71.97 v3(53.66,71.9)
  TOP w0.127: 51.8,75.24 51.72,75.16 51.72,74.81 51.47,74.55 50.32,74.55 50.2,74.43 50.2,71.38 50.32,71.25 50.9,71.25 v1(51.43,70.73) 51.85,70.31 51.85,69.35 51.72,69.22 51.47,69.22 51.34,69.09 51.34,68.64 49.69,66.99 49.69,65.54 49.56,65.41 48.55,65.41 48.42,65.54 48.42,66.55 48.29,66.68 44.77,66.68 44.61,66.84 44.61,70.03 45.5,70.92 45.5,73.41 45.37,73.54 45.12,73.54 45.11,73.53 44.74,73.9 44.74,74.81 44.61,74.93 43.51,74.93 43.33,75.11 41,75.11 40.8,75.32 40.8,75.7 40.54,75.95 40.29,75.95 40.16,76.08 40.16,76.8 40.29,76.92 UV6.D3
  BOTTOM w0.102: v3(53.66,71.9) 53.67,71.9 54.23,71.9 54.46,72.14 54.46,73.19 54.8,73.52 UV1.E30
M_DQM2: length 42
  IN1 w0.102: 42.75,74.93 41.94,75.75 40.67,75.75 v3(40.37,75.44)
  IN1 w0.14: 42.75,74.93 42.75,74.55 43.01,74.3 43.01,73.69 44.53,72.17 44.53,70.9 43.74,70.11 43.11,70.11 42.78,69.78 42.78,68.87 42.64,68.73 42.38,68.73 42.24,68.59 42.24,68.31 42.38,68.17 42.64,68.17 42.78,68.03 42.78,67.64 42.65,67.52 42.42,67.52 42.32,67.42 42.32,67.11 42.73,66.7 43.08,66.7 43.41,67.03 43.8,67.03 44.13,66.7 48.98,66.7 49.18,66.91 49.18,67.38 49.32,67.52 49.9,67.52 50.04,67.66 50.04,67.93 49.9,68.07 49.32,68.07 49.18,68.21 49.18,69.07 48.14,70.11 48.14,74.5 48.9,75.26 48.9,75.54 48.6,75.85 48.22,75.85 47.81,76.26 v3(47.81,76.46)
  BOTTOM w0.124: v3(47.81,76.46) 47.81,76.57 50.58,79.34
  BOTTOM w0.127: UV5.E7 39.75,76.92 40.37,76.31 v3(40.37,75.44) ; 50.58,79.34 51.34,80.1 UV1.A21
M_DQM3: length 39.8
  TOP w0.127: v3(40.09,74.91) 39.96,74.78 39.96,73.93 UV6.E7
  IN3 w0.102: 41.08,70.97 40.98,71.08 40.98,71.73 41.26,72.01 41.26,73.31 40.09,74.48 v3(40.09,74.91)
  IN3 w0.165: v3(53.6,80.39) 53.55,80.45 53.55,80.8 53.07,81.28 51.44,81.28 51.11,80.95 51.11,79.98 51.28,79.82 51.53,79.82 51.7,79.65 51.7,79.32 51.53,79.15 51.28,79.15 51.11,78.99 51.11,78.66 51.28,78.49 51.53,78.49 51.7,78.33 51.7,78 51.53,77.83 51.28,77.83 51.11,77.67 51.11,77.65 50.48,77.02 47.74,77.02 47.37,76.65 47.37,76.28 47.78,75.87 50.78,75.87 51.21,75.44 51.21,75.01 50.88,74.68 49.74,74.68 49.59,74.53 49.59,69.97 48.68,69.07 42.83,69.07 41.08,70.82 41.08,70.97
  BOTTOM w0.127: UV1.C21 53.89,80.1 v3(53.6,80.39)
M_DQM4: length 40.2
  TOP w0.124: UV7.E7 40.26,94.04
  TOP w0.127: 40.26,94.04 40.88,94.67 v3(40.98,94.67)
  IN3 w0.102: v3(54.43,86.19) 54.39,86.19 54.03,85.83 54.03,85.6 54.82,84.81 54.82,84.41 54.52,84.11 52.68,84.11 52.43,84.36 52.43,84.86 52.03,85.26 52.03,85.86 51.77,86.11
  IN3 w0.165: 51.77,86.11 50.62,87.27 49.55,87.27 47.81,89.01 47.81,91.5 48.57,92.26 48.57,95.2 48.75,95.38 50.32,95.38 50.6,95.66 50.6,96.42 52.15,97.97 52.15,98.44 51.99,98.61 45.29,98.61 45.07,98.38 45.07,97.72 44.68,97.34 43.57,97.34 42.96,96.73 42.96,95.94 42.68,95.66 42.47,95.66 41.48,94.67 v3(40.98,94.67)
  BOTTOM w0.124: UV1.E13 54.73,86.5 54.43,86.19 v3(54.43,86.19)
M_DQM5: length 46.1
  TOP w0.127: v3(50.09,92) 50.7,92 50.83,92.13 50.83,92.46 50.7,92.59 50.2,92.59 50.07,92.71 50.07,93.85 52.36,96.13 52.36,103 52.48,103.13 52.99,103.13 53.12,103.25 53.12,104.66 52.61,105.16 46.67,105.16 46.13,104.62 46.13,97.99 43.55,95.41 41.7,95.41 40.58,96.52 40.58,96.7 UV7.D3
  BOTTOM w0.102: v3(50.09,92) 49.99,92 49.56,91.57 49.56,88.75 51.01,87.3 51.87,87.3 52.13,87.56 53.43,87.56 53.5,87.63 53.7,87.63 53.78,87.56 54.14,87.56 UV1.D12
M_DQM6: length 41.1
  IN1 w0.14: v3(40.16,96.22) 40.54,96.22 42.4,98.07 42.42,98.07 43.03,98.68 43.03,98.99 42.55,99.47 42.55,100.21 43.03,100.69 43.03,100.88 43.22,101.07 44.14,101.07 44.3,101.24 44.3,101.52 44.19,101.63 43.13,101.63 42.98,101.78 42.98,102.07 43.12,102.21 44.66,102.21 44.91,102.47 44.91,102.93 45.47,103.48 51.9,103.48 52.36,103.03 53.42,103.03 53.63,102.82 53.63,102.55 53.38,102.31 53.38,101.93 53.52,101.79 53.82,101.79 53.96,101.65 53.96,101.37 53.82,101.23 53.57,101.23 53.43,101.09 53.43,100.81 53.57,100.67 53.82,100.67 53.96,100.53 53.96,100.25 53.82,100.11 53.75,100.11 53.61,99.97 53.61,99.69 53.75,99.55 53.82,99.55 53.96,99.41 53.96,98.96 53.82,98.82 53.6,98.82 53.46,98.68 53.46,98.4 53.6,98.26 53.82,98.26 53.96,98.12 53.96,97.51 52.16,95.72 52.16,93.97 52.63,93.5 52.63,92.51 52.79,92.36 53.1,92.36 53.24,92.5 53.24,93.18 53.38,93.32 53.66,93.32 53.8,93.18 53.8,92.5 53.94,92.36 54.51,92.36 54.67,92.51 54.67,92.94 v3(54.41,93.2)
  BOTTOM w0.127: UV1.E3 54.8,93.67 54.41,93.28 v3(54.41,93.2) ; v3(40.16,96.22) 39.75,96.63 UV8.E7
M_DQM7: length 46.1
  BOTTOM w0.102: UV1.F4 55.6,93.65 55.94,93.98 55.94,94.19 55.86,94.27 55.86,95.08 55.34,95.6 54.77,95.6
  BOTTOM w0.127: UV8.D3 40.94,93.15 42.3,93.15 42.55,92.89 42.55,92.58 42.8,92.33 43.39,92.33 43.59,92.54 43.59,92.79 43.74,92.94 44.25,92.94 44.41,92.79 44.41,91.09 44.25,90.94 43.66,90.94 43.19,90.46 43.19,88.93 43.39,88.72 44.33,88.72 44.48,88.57 44.48,88.32 44.37,88.2 43.31,88.2 43.19,88.08 43.19,87.82 43.31,87.7 44.51,87.7 44.61,87.6 44.61,87.29 44.51,87.19 43.31,87.19 43.19,87.06 43.19,86.81 43.31,86.68 44.51,86.68 44.61,86.58 44.61,85.72 44.96,85.37 47.83,85.37 48.6,86.14 49.66,86.14 49.76,86.24 49.76,86.52 49.64,86.64 48.6,86.64 48.47,86.77 48.47,87.02 48.6,87.15 49.64,87.15 49.76,87.28 49.76,87.48 49.59,87.66 48.6,87.66 48.47,87.79 48.47,87.94 48.6,88.07 48.6,88.65 48.8,88.85 v1(48.8,90.77) 48.8,92.14 49.68,93.01 49.68,93.36 51.02,94.7 52.1,94.7 52.31,94.9 52.31,95.97 52.51,96.17 53.92,96.17 54.49,95.6 54.77,95.6
M_DQS0: length 45.8
  BOTTOM w0.102: UV1.H28 57.2,74.54 57.05,74.68 56.94,74.68 56.85,74.6 56.85,74.38 56.93,74.3 56.93,73.89 56.85,73.82 56.85,73.59 56.93,73.51 56.93,73.08 56.88,73.03 56.88,72.26 56.55,71.93 56.55,71.91
  BOTTOM w0.127: UV5.C7 41.51,76.76 41.56,76.71 41.56,76.33 41.43,76.2 41.2,76.2 40.98,75.98 40.98,75.17 41.26,74.88 43.55,74.88 43.67,74.76 43.67,74.53 44,74.2 44.43,74.2 45.09,74.86 45.24,74.86 45.42,74.68 45.42,74.47 44.71,73.76 44.71,73.42 45.03,73.11 45.42,73.11 46.18,73.86 46.41,73.86 46.59,73.68 46.59,73.55 45.4,72.36 45.4,71.99 45.71,71.68 46.08,71.68 v2(46.64,72.24) 47.4,73 47.61,73 47.79,72.82 47.79,72.66 45.93,70.81 45.93,70.44 46.25,70.13 46.62,70.13 48.47,71.98 48.65,71.98 48.83,71.8 48.83,71.65 47,69.82 47,69.43 47.34,69.09 47.73,69.09 49.43,70.79 49.85,70.79 50.74,69.91 51.03,69.91 51.16,69.78 51.16,69.36 51.42,69.1 51.87,69.1 52.13,69.36 52.13,69.78 52.25,69.91 52.51,69.91 52.63,69.78 52.63,69.36 52.9,69.1 53.34,69.1 53.6,69.36 53.6,69.78 53.73,69.91 53.98,69.91 54.11,69.78 54.11,69.36 54.37,69.1 54.81,69.1 55.07,69.36 55.07,69.78 56.55,71.25 56.55,71.91
M_DQS1: length 44.9
  TOP w0.102: 51.34,72.9 51.34,72.9 51.43,72.9 51.73,73.2 51.73,74.19 52.08,74.54 52.08,75.2 52.45,75.57 53.12,75.57 53.42,75.26 53.42,75.06 v3(53.61,74.87)
  TOP w0.127: UV6.C7 41.59,73.96 41.59,74.22 42.14,74.78 42.86,74.78 43.27,74.37 43.62,74.37 44.98,73.01 44.98,71.04 44.15,70.22 v2(44.15,68.17) 44.15,66.44 44.37,66.22 46.08,66.22 46.39,65.92 46.39,64.39 46.51,64.27 46.79,64.27 46.92,64.39 46.92,65.96 47.18,66.22 47.7,66.22 47.96,65.96 47.96,63.12 48.08,63 48.42,63 48.55,63.12 48.55,64.69 48.81,64.95 49.3,64.95 49.56,64.69 49.56,63.12 49.69,63 50.04,63 50.17,63.12 50.17,66.77 52.3,68.91 52.3,70.5 50.86,71.94 50.86,72.67 51.09,72.9 51.34,72.9
  BOTTOM w0.124: UV1.C27 54,75.26 v3(53.61,74.87)
M_DQS2: length 40.4
  IN1 w0.152: v3(50.32,76.43) 50.53,76.23 50.53,75.6 50.4,75.47 50.04,75.47 48.82,74.25 48.82,70.36 50.7,68.48 50.7,67.34 49.41,66.04 42.45,66.04 41.56,66.94 41.56,68.83 42.12,69.39 42.12,70.13 42.8,70.81 43.48,70.81 43.85,71.17 43.85,71.89 42.09,73.64 42.09,74.65 41.66,75.09 40.98,75.09 40.42,74.53 40.14,74.25 40.03,74.25 39.63,73.84 38.9,73.84 38.77,73.97 38.77,74.12 38.92,74.27 v3(38.95,74.27)
  BOTTOM w0.102: v3(50.32,76.43) 50.68,76.79 50.68,76.97 51.9,78.19 53.36,78.19 53.55,78.37 53.55,78.49 53.47,78.57 53.27,78.57 UV1.A23
  BOTTOM w0.127: UV5.F3 v3(38.95,74.27)
M_DQS3: length 39.2
  TOP w0.127: UV6.F3 38.98,76.89 v3(38.98,76.37)
  IN3 w0.102: v3(54.4,81.99) 54.38,81.97 54.18,81.97 54.03,82.12 54.03,82.41 53.84,82.61 53.19,82.61 52.81,82.22 52.61,82.22 ; 42.13,71.16 42.1,71.19 42.1,74.19 40.95,75.34 40.95,75.7 40.62,76.03 39.95,76.03 39.88,75.95 39.3,75.95 39.2,76.05 39.03,76.05 38.89,76.19 38.89,76.27 38.88,76.27 v3(38.98,76.37)
  IN3 w0.165: 42.13,71.16 43.16,70.13 43.8,70.13 44.01,70.35 44.01,70.84 44.33,71.16 44.88,71.16 45.2,70.84 45.2,70.26 45.37,70.1 45.7,70.1 45.86,70.26 45.86,70.84 46.18,71.16 46.74,71.16 47.06,70.84 47.06,70.26 47.22,70.1 48.38,70.1 48.57,70.28 48.57,74.8 48.44,74.93 47.39,74.93 46.43,75.89 46.43,76.67 46.43,77.03 47.35,77.96 49.44,77.96 49.57,78.09 49.65,78.17 49.72,78.24 49.8,78.32 49.88,78.4 49.88,78.4 50.11,78.63 50.11,81.32 51.01,82.22 52.61,82.22
  BOTTOM w0.102: UV1.E19 54.76,81.7 54.45,82.01 54.42,82.01 v3(54.4,81.99)
M_DQS4: length 40
  TOP w0.127: v3(39.54,96.21) 39.54,96.36 39.17,96.73 UV7.F3
  IN3 w0.102: v3(54.41,84.59) 54.18,84.59 54.06,84.71 54.06,84.98 53.74,85.3 52.77,85.3 52.58,85.48 52.58,86.44 51.75,87.28 51.75,87.32 51.73,87.34
  IN3 w0.165: v3(39.54,96.21) 39.38,96.05 39.38,95.61 39.49,95.5 40.48,95.5 40.62,95.64 41.11,95.64 41.24,95.77 41.24,96.49 41.79,97.03 41.84,97.03 43.16,98.35 43.92,98.35 44.08,98.51 44.08,99.19 44.46,99.57 53.09,99.57 53.5,99.17 53.5,97.7 51.59,95.79 51.59,94.82 51.21,94.44 49.97,94.44 49.54,94.01 49.54,91.83 48.77,91.06 48.77,89.43 49.96,88.24 51.21,88.24 51.67,87.79 51.67,87.4 51.73,87.34
  BOTTOM w0.102: UV1.E15 54.75,84.9 54.44,84.59 v3(54.41,84.59)
M_DQS5: length 46.2
  TOP w0.127: UV7.C7 41.62,93.81 41.62,94.38 41.89,94.64 43.49,94.64 46.64,97.79 46.64,103.22 46.92,103.5 46.92,103.67 46.64,103.95 46.64,104.37 46.9,104.63 48.13,104.63 48.39,104.37 48.39,103.99 48.51,103.86 48.82,103.86 48.95,103.99 48.95,104.37 49.21,104.63 49.81,104.63 50.07,104.37 50.07,103 50.2,102.87 50.6,102.87 50.73,103 50.73,104.37 50.99,104.63 52.38,104.63 52.61,104.4 52.61,103.89 52.36,103.64 51.97,103.64 51.85,103.51 51.85,96.27 49.56,93.98 49.56,91.88 49.99,91.44 50.32,91.44 50.55,91.22 50.55,90.61 v3(50.72,90.44)
  BOTTOM w0.102: v3(50.72,90.44) 50.5,90.66 50.5,90.75 50.66,90.91 51.43,90.91 51.77,90.57 51.77,90.14 52.47,89.44 52.7,89.44 52.96,89.18 53.42,89.18 53.47,89.23 53.74,89.23 53.85,89.13 54.29,89.13 54.4,89.02 UV1.D10
M_DQS6: length 41
  IN1 w0.102: 39.45,95.2 39.44,95.2 39.41,95.23 39.33,95.23 39.07,94.97 39.07,94.52 38.84,94.29 38.84,94.12 38.92,94.04 v3(39.07,94.04)
  IN1 w0.152: 39.45,95.2 40.83,95.2 41.16,95.53 41.48,95.53 41.81,95.2 42.37,95.2 43.19,96.02 43.19,97 44.53,98.35 44.53,99.22 44.2,99.55 43.89,99.55 43.74,99.7 43.74,100 43.89,100.16 44.91,100.16 45.22,100.46 45.22,101.43 45.85,102.06 45.85,102.39 46,102.54 46.31,102.54 46.46,102.39 46.46,102.06 46.76,101.76 47.28,101.76 47.58,102.06 47.58,102.39 47.73,102.54 48.03,102.54 48.19,102.39 48.19,102.06 48.49,101.76 49,101.76 49.3,102.06 49.3,102.39 49.46,102.54 49.76,102.54 49.91,102.39 49.91,102.06 50.21,101.76 50.73,101.76 51.03,102.06 51.03,102.39 51.18,102.54 51.49,102.54 51.64,102.39 51.64,102.06 51.94,101.76 52.3,101.76 52.5,101.55 52.5,101.14 51.95,100.59 51.95,100.05 52.25,99.75 52.55,99.75 52.7,99.59 52.7,99.29 52.55,99.14 52.25,99.14 51.95,98.84 51.95,98.32 52.25,98.02 52.55,98.02 52.7,97.87 52.7,97.56 52.55,97.41 52.25,97.41 51.95,97.11 51.95,96.88 51.24,96.17 51.24,93.6 51.57,93.27 51.57,93.16 v3(51.38,92.97)
  BOTTOM w0.102: v3(39.07,94.04) 38.95,93.91 UV8.F3 ; UV1.D6 54.44,92.14 54.44,92.23 54.24,92.43 53.46,92.43 53.35,92.33 51.79,92.33 51.54,92.58 51.54,92.81 v3(51.38,92.97)
M_DQS7: length 46.3
  BOTTOM w0.102: 56.61,95.95 56.88,95.69 57.12,95.69 57.59,95.22 57.59,94.88 57.49,94.77 57.49,94.26 57.51,94.23 57.51,93.96 57.18,93.63 57.01,93.63 56.4,93.02 UV1.G5
  BOTTOM w0.127: 56.61,95.95 56.44,96.12 56.44,96.84 56.32,96.96 55.46,96.96 55.2,97.23 55.2,97.67 55.46,97.93 56.32,97.93 56.44,98.06 56.44,98.4 55.94,98.91 55.66,98.91 55.56,98.81 54.74,98.81 54.59,98.66 54.59,98.07 54.34,97.82 53.73,97.82 53.47,98.07 53.47,99.02 53.33,99.17 53.03,99.17 52.9,99.04 52.9,98.08 52.64,97.82 52.2,97.82 51.94,98.08 v2(51.94,98.58) 51.94,99.04 51.81,99.17 51.56,99.17 51.43,99.04 51.43,98.08 51.17,97.82 50.72,97.82 50.46,98.08 50.46,99.04 50.34,99.17 50.08,99.17 49.96,99.04 49.96,97.55 49.69,97.29 49.25,97.29 48.98,97.56 48.98,99.05 48.86,99.17 48.61,99.17 48.48,99.04 48.48,97.55 48.22,97.29 47.78,97.29 47.52,97.55 47.52,99.04 47.39,99.17 46.36,99.17 46.18,98.99 46.18,98.81 46.84,98.15 46.84,96.43 46.48,96.07 45.9,96.07 44.73,94.9 44.18,94.9 43.92,95.16 43.92,95.38 43.79,95.51 43.54,95.51 43.41,95.38 43.41,95.16 43.15,94.9 42.7,94.9 42.44,95.16 42.44,95.38 42.32,95.51 42.12,95.51 41.59,94.97 41.26,94.97 41.15,95.08 40.49,95.08 40.24,95.33 40.24,95.73 40.53,96.02 41.15,96.02 41.51,96.37 41.51,96.57 UV8.C7
M_DQS#0: length 46.2
  BOTTOM w0.102: UV1.H27 57.22,75.32 57.39,75.32 57.46,75.25 57.46,75.09 57.26,74.88 56.85,74.88 56.65,74.68 56.65,74.29 56.72,74.21 56.72,73.98 56.65,73.9 56.65,73.5 56.72,73.43 56.72,73.16 56.67,73.11 56.67,72.34 56.33,72 56.33,71.94 56.32,71.92 56.32,71.91
  BOTTOM w0.127: UV5.B7 42.13,76.92 41.79,76.59 41.79,76.24 41.53,75.98 41.3,75.98 41.2,75.88 41.2,75.26 41.36,75.11 43.64,75.11 43.9,74.86 43.9,74.62 44.09,74.43 44.33,74.43 44.99,75.08 45.33,75.08 45.65,74.77 45.65,74.38 44.94,73.67 44.94,73.51 45.12,73.33 45.33,73.33 46.09,74.09 46.5,74.09 46.82,73.78 46.82,73.46 45.63,72.27 45.63,72.09 45.81,71.91 45.97,71.91 47.28,73.23 47.7,73.23 48.01,72.91 48.01,72.57 46.16,70.72 46.16,70.54 46.34,70.36 46.52,70.36 48.37,72.21 48.74,72.21 49.06,71.9 49.06,71.53 v2(47.91,70.38) 47.22,69.69 47.22,69.53 47.43,69.32 47.63,69.32 49.33,71.02 49.94,71.02 50.83,70.13 51.13,70.13 51.39,69.87 51.39,69.46 51.52,69.33 51.77,69.33 51.9,69.46 51.9,69.87 52.16,70.13 52.6,70.13 52.86,69.87 52.86,69.46 52.99,69.33 53.24,69.33 53.37,69.46 53.37,69.87 53.63,70.13 54.08,70.13 54.34,69.87 54.34,69.46 54.46,69.33 54.72,69.33 54.84,69.46 54.84,69.87 56.32,71.35 56.32,71.91
M_DQS#1: length 44.9
  TOP w0.102: v3(52.72,74.94) 52.85,74.81 53.14,74.81 53.22,74.88 53.22,75.18 53.03,75.37 52.53,75.37 52.28,75.11 52.28,74.45 51.94,74.11 51.94,73.12 51.49,72.67 51.34,72.67
  TOP w0.127: 51.34,72.67 51.19,72.67 51.09,72.57 51.09,72.04 52.53,70.59 52.53,68.81 50.4,66.68 50.4,63.03 50.14,62.77 49.59,62.77 49.33,63.03 49.33,64.6 49.21,64.72 48.9,64.72 48.77,64.6 48.77,63.03 48.51,62.77 47.99,62.77 47.73,63.03 47.73,64.14 47.68,64.19 47.68,64.75 47.73,64.79 47.73,65.87 47.6,65.99 47.28,65.99 47.15,65.87 47.15,64.3 46.89,64.04 46.42,64.04 46.16,64.3 46.16,65.82 45.99,65.99 44.28,65.99 43.92,66.35 43.92,67.88 43.91,67.9 43.91,68.43 43.92,68.45 43.92,70.31 44.75,71.14 44.75,72.92 43.53,74.14 43.18,74.14 42.76,74.55 42.24,74.55 41.81,74.13 41.81,73.82 41.91,73.72 UV6.B7
  BOTTOM w0.127: v3(52.72,74.94) 53.09,75.3 UV1.A27
M_DQS#2: length 40.9
  IN1 w0.152: v3(50.91,76.43) 50.78,76.31 50.78,75.49 50.5,75.21 50.15,75.21 49.08,74.15 49.08,70.46 50.96,68.58 50.96,67.24 49.51,65.79 42.35,65.79 41.31,66.83 41.31,68.94 41.87,69.5 41.87,70.24 42.69,71.06 43.38,71.06 43.59,71.28 43.59,71.78 41.84,73.54 41.84,74.55 41.56,74.83 41.08,74.83 40.6,74.35 40.24,73.99 40.14,73.99 39.73,73.59 38.79,73.59 38.51,73.87 38.51,74.12 v3(38.36,74.27)
  BOTTOM w0.102: UV1.C23 53.97,78.5 53.45,77.98 51.98,77.98 50.88,76.88 50.88,76.46 v3(50.91,76.43)
  BOTTOM w0.127: UV5.G3 38.15,74.09 38.36,74.3 v3(38.36,74.27)
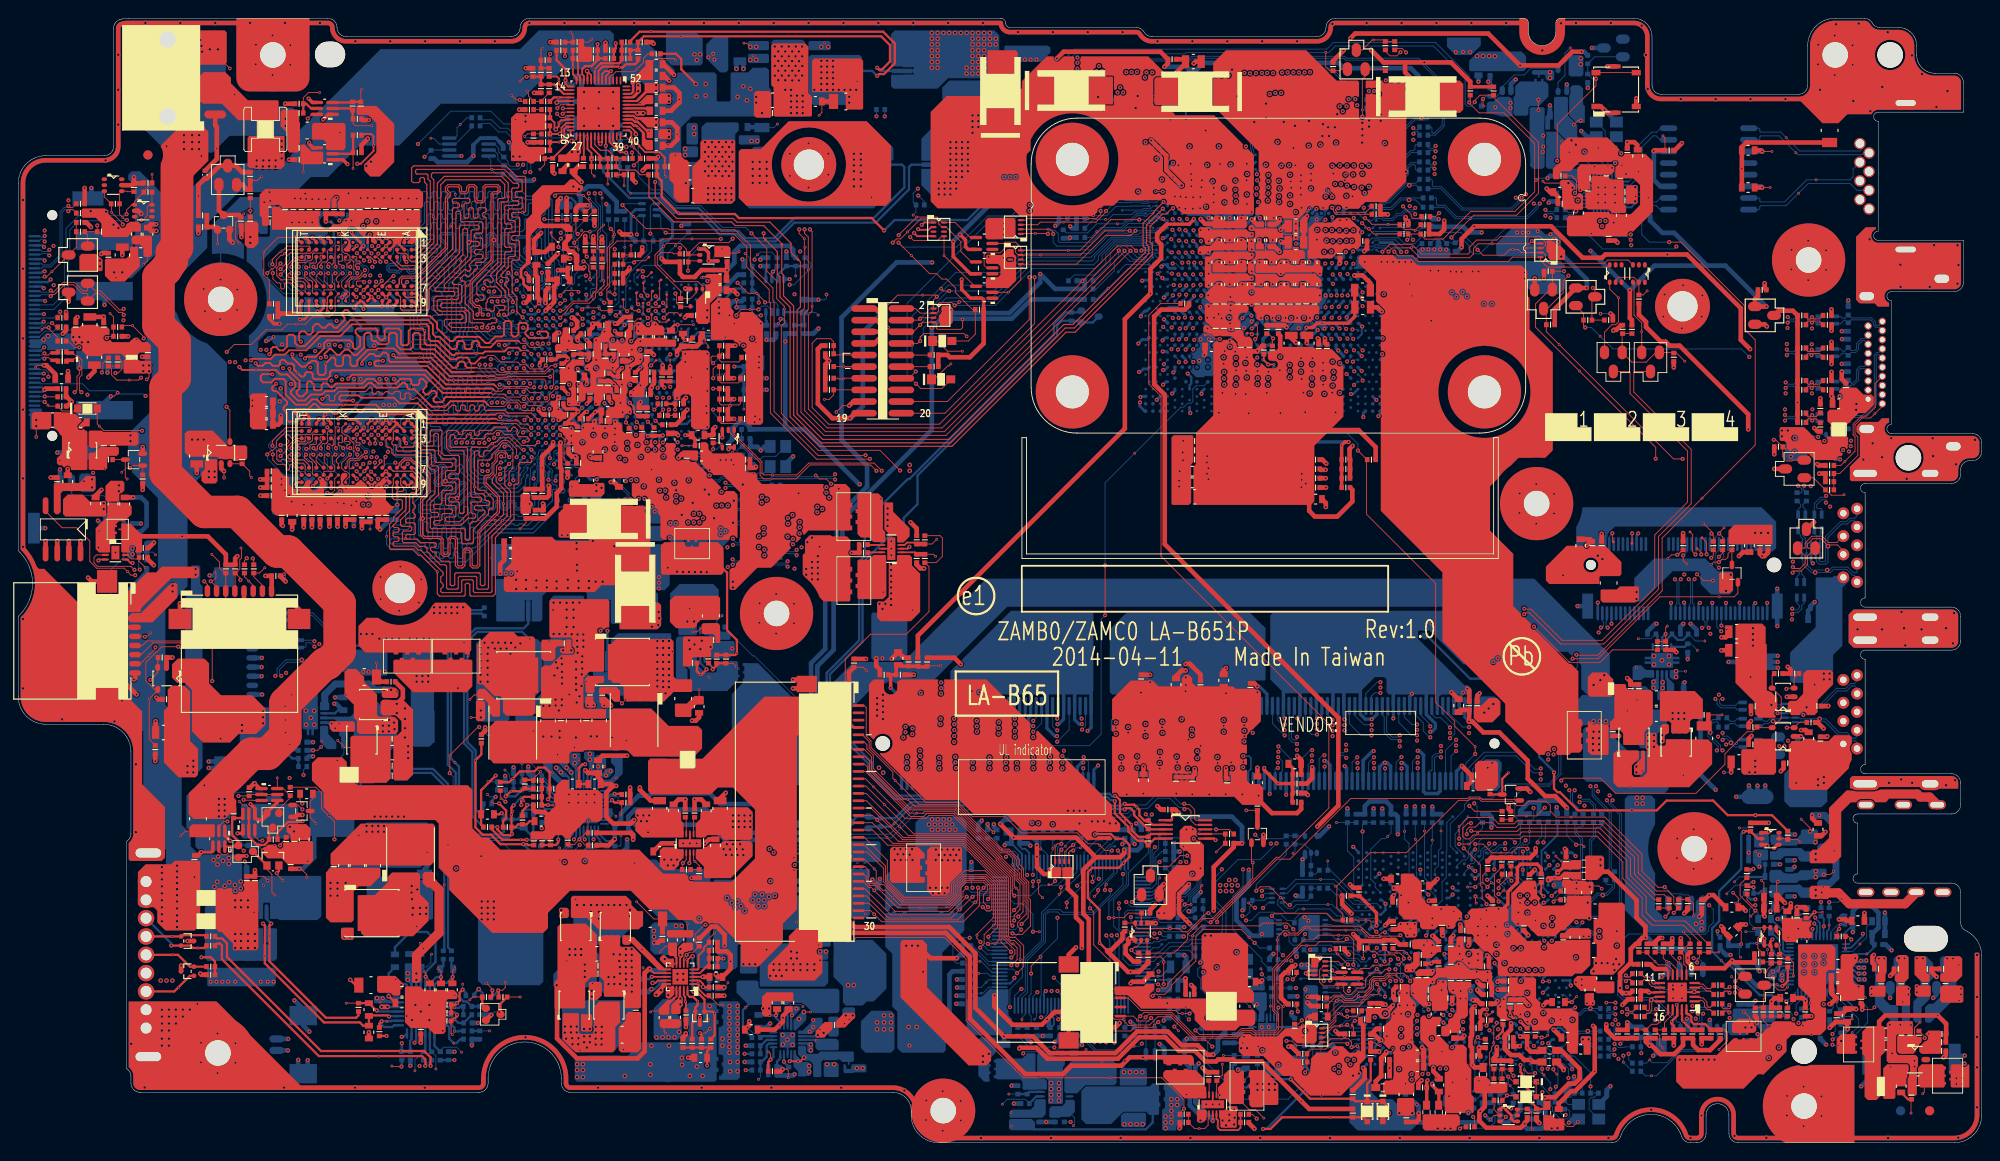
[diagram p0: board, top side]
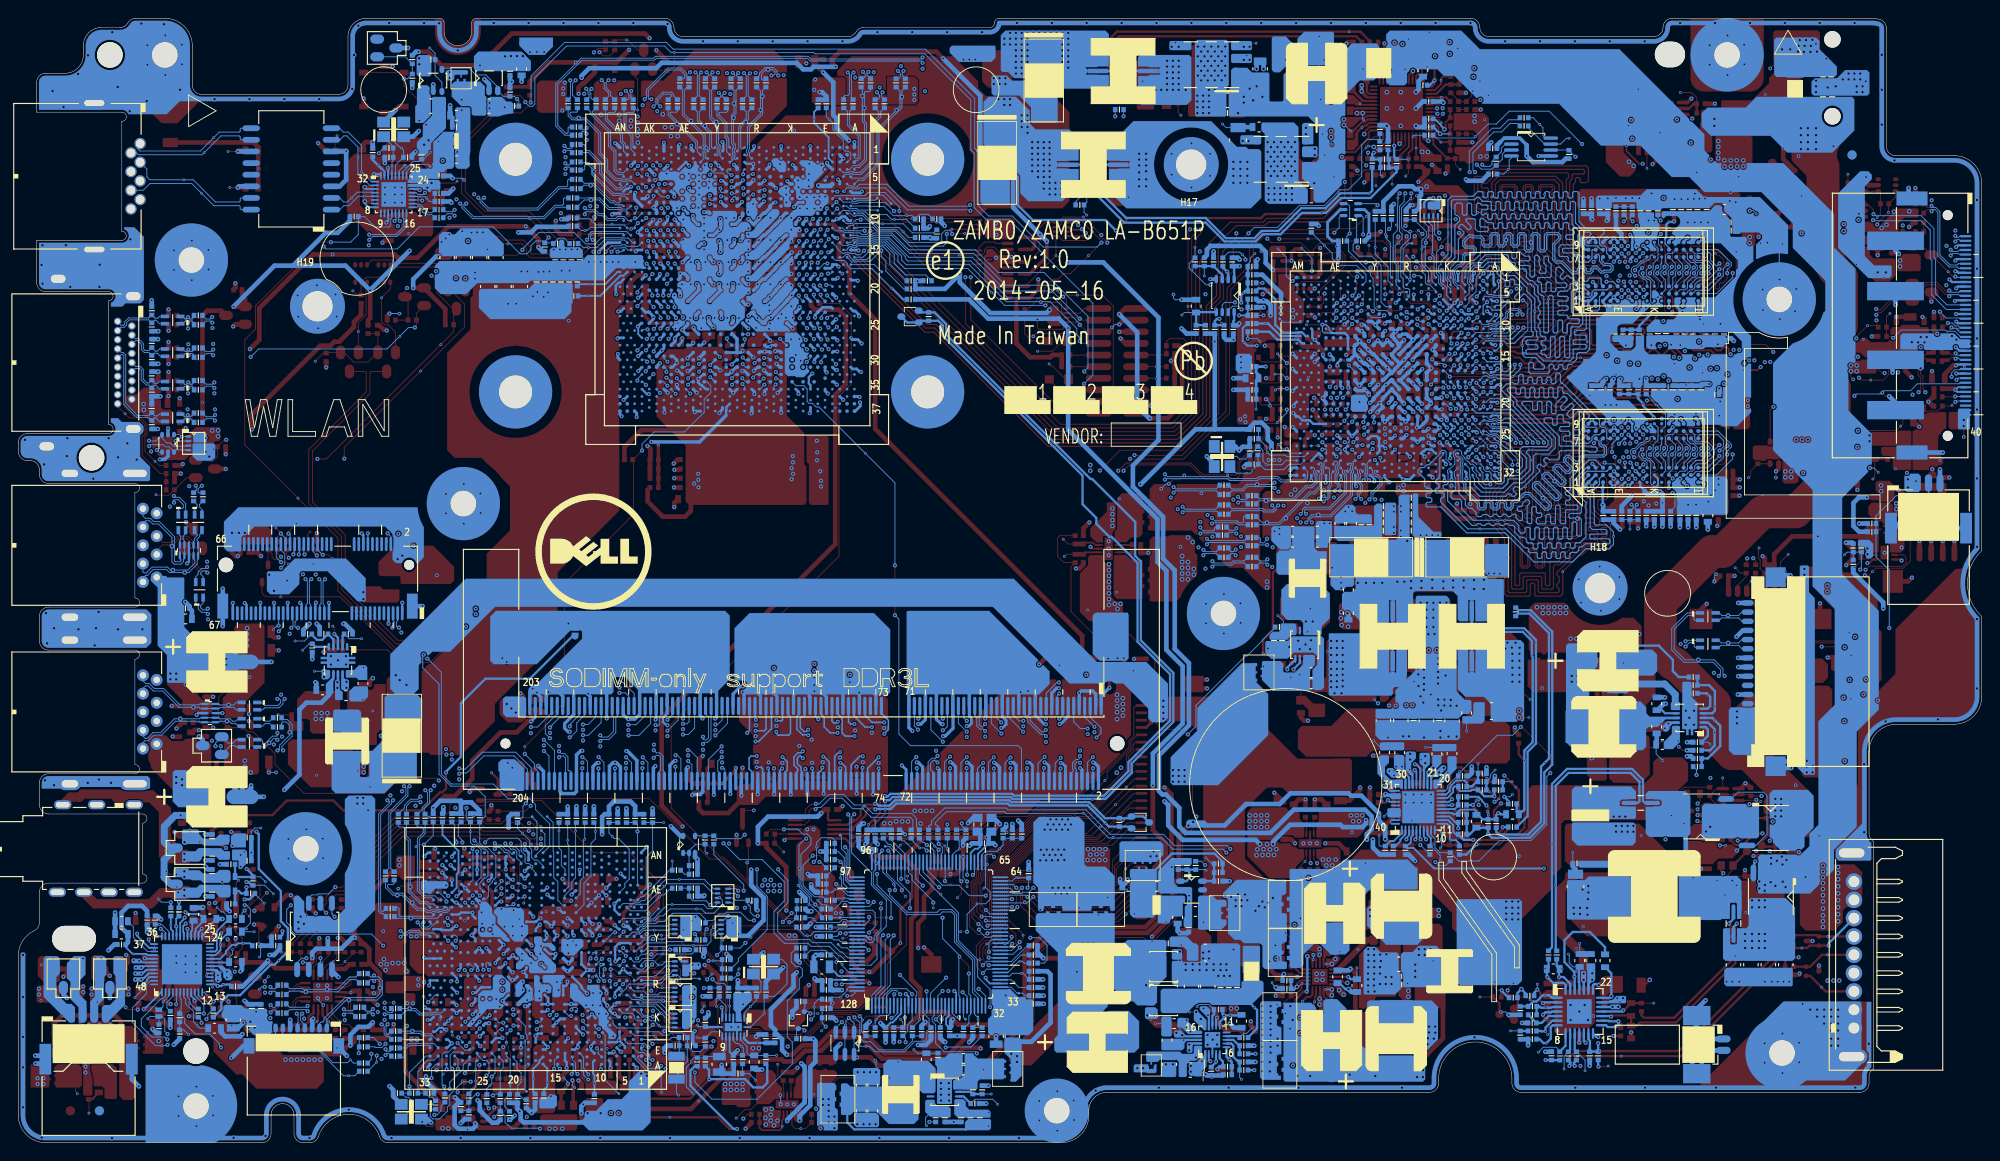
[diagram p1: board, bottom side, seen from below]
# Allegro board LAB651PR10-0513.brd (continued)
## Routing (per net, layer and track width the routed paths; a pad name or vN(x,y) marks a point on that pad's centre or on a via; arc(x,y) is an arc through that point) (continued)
M_DQS#3: length 39.3
  TOP w0.127: v3(38.39,76.36) 38.39,76.68 UV6.G3
  IN3 w0.102: 41.94,70.97 41.93,70.98 41.93,71.03 41.89,71.06 41.89,71.1 41.89,74.11 40.75,75.26 40.75,75.61 40.54,75.82 40.04,75.82 39.96,75.75 39.22,75.75 39.11,75.85 38.94,75.85 38.44,76.36 v3(38.39,76.36) ; 52.61,81.96 52.62,81.96 52.65,81.99 52.7,81.99 52.74,82.02 52.89,82.02 53.27,82.4 53.75,82.4 53.83,82.33 53.83,82.21 v3(53.6,81.99)
  IN3 w0.165: 41.94,70.97 43.05,69.87 43.91,69.87 44.28,70.24 44.28,70.73 44.44,70.9 44.77,70.9 44.94,70.73 44.94,70.15 45.26,69.83 45.81,69.83 46.13,70.15 46.13,70.73 46.29,70.9 46.62,70.9 46.79,70.73 46.79,70.15 47.11,69.83 48.49,69.83 48.84,70.17 48.84,74.91 48.55,75.2 47.5,75.2 46.7,76 46.7,76.56 46.7,76.92 47.46,77.69 49.55,77.69 49.6,77.74 49.68,77.82 49.76,77.9 49.83,77.98 49.84,77.98 49.91,78.05 49.99,78.13 50.07,78.21 50.23,78.37 50.23,78.37 50.37,78.52 50.37,78.74 50.37,81.21 51.12,81.96 52.61,81.96
  BOTTOM w0.102: UV1.C19 53.93,81.7 53.62,82.01 53.6,81.99 v3(53.6,81.99)
M_DQS#4: length 40
  TOP w0.127: v3(38.94,96.2) 38.94,96.25 38.45,96.73 UV7.G3
  IN3 w0.102: v3(53.6,84.59) 53.65,84.59 53.85,84.79 53.85,84.89 53.65,85.09 52.69,85.09 52.38,85.4 52.38,86.36 51.61,87.13 51.56,87.13 51.54,87.15
  IN3 w0.165: v3(38.94,96.2) 39.11,96.03 39.11,95.5 39.38,95.23 40.6,95.23 40.73,95.37 41.22,95.37 41.51,95.66 41.51,96.38 41.9,96.77 41.95,96.77 43.27,98.09 44.03,98.09 44.34,98.4 44.34,99.08 44.57,99.31 52.98,99.31 53.23,99.06 53.23,97.81 51.33,95.9 51.33,94.93 51.1,94.71 49.86,94.71 49.27,94.12 49.27,91.94 48.51,91.17 48.51,89.31 49.84,87.98 51.1,87.98 51.4,87.68 51.4,87.29 51.54,87.15
  BOTTOM w0.102: v3(53.6,84.59) 53.7,84.59 54,84.88 UV1.C15
M_DQS#5: length 46.1
  TOP w0.127: v3(50.13,90.44) 50.32,90.64 50.32,91.12 50.23,91.22 49.9,91.22 49.33,91.78 49.33,94.08 51.62,96.37 51.62,103.6 51.88,103.86 52.26,103.86 52.38,103.99 52.38,104.3 52.29,104.4 51.09,104.4 50.96,104.27 50.96,102.91 50.7,102.65 50.1,102.65 49.84,102.91 49.84,104.27 49.71,104.4 49.31,104.4 49.18,104.27 49.18,103.9 48.92,103.64 48.42,103.64 48.16,103.89 48.16,104.27 48.04,104.4 47,104.4 46.87,104.27 46.87,104.04 47.15,103.76 47.15,103.41 46.87,103.13 46.87,97.7 43.59,94.42 41.99,94.42 41.85,94.28 41.85,93.83 UV7.B7
  BOTTOM w0.102: UV1.E9 54.44,89.34 53.93,89.34 53.83,89.44 53.39,89.44 53.34,89.39 53.04,89.39 52.79,89.64 52.56,89.64 51.97,90.23 51.97,90.66 51.52,91.11 50.58,91.11 50.3,90.83 50.3,90.61 v3(50.13,90.44)
M_DQS#6: length 40.9
  IN1 w0.102: 39.45,95.46 39.27,95.46 38.87,95.06 38.87,94.6 38.6,94.33 38.6,94.27 v3(38.36,94.04)
  IN1 w0.152: 39.45,95.46 40.72,95.46 41.05,95.79 41.59,95.79 41.92,95.46 42.27,95.46 42.93,96.12 42.93,97.11 44.28,98.45 44.28,99.11 44.1,99.29 43.79,99.29 43.48,99.59 43.48,100.11 43.79,100.41 44.81,100.41 44.96,100.57 44.96,101.53 45.6,102.16 45.6,102.5 45.9,102.8 46.41,102.8 46.71,102.5 46.71,102.16 46.87,102.01 47.17,102.01 47.32,102.16 47.32,102.5 47.62,102.8 48.14,102.8 48.44,102.5 48.44,102.16 48.59,102.01 48.9,102.01 49.05,102.16 49.05,102.5 49.35,102.8 49.87,102.8 50.17,102.5 50.17,102.16 50.32,102.01 50.62,102.01 50.78,102.16 50.78,102.5 51.08,102.8 51.59,102.8 51.89,102.5 51.89,102.16 52.05,102.01 52.41,102.01 52.76,101.66 52.76,101.04 52.2,100.48 52.2,100.15 52.36,100 52.66,100 52.96,99.7 52.96,99.18 52.66,98.88 52.36,98.88 52.2,98.73 52.2,98.42 52.36,98.27 52.66,98.27 52.96,97.97 52.96,97.46 52.66,97.16 52.36,97.16 52.2,97 52.2,96.78 51.49,96.07 51.49,93.71 51.82,93.38 51.82,93.11 v3(51.96,92.97)
  BOTTOM w0.102: UV8.G3 38.36,93.75 v3(38.36,94.04) ; v3(51.96,92.97) 51.96,92.97 51.75,92.75 51.75,92.66 51.87,92.54 53.27,92.54 53.37,92.64 53.88,92.64 54.01,92.77 54.01,92.89 UV1.C5
M_DQS#7: length 46.3
  BOTTOM w0.102: 56.77,96.11 57,95.89 57.21,95.89 57.79,95.31 57.79,94.79 57.69,94.69 57.69,94.34 57.71,94.31 57.71,93.87 57.27,93.43 57.2,93.43 UV1.H4
  BOTTOM w0.127: 56.77,96.11 56.67,96.21 56.67,96.93 56.41,97.19 55.56,97.19 55.43,97.32 55.43,97.57 55.56,97.7 56.41,97.7 56.67,97.96 56.67,98.5 56.03,99.14 55.56,99.14 55.46,99.04 54.65,99.04 54.36,98.75 54.36,98.17 54.24,98.05 53.82,98.05 53.7,98.17 53.7,99.12 53.42,99.39 52.93,99.39 52.67,99.13 52.67,98.18 52.55,98.05 52.29,98.05 52.18,98.16 52.18,99.12 51.9,99.39 51.46,99.39 51.2,99.13 51.2,98.18 51.07,98.05 50.82,98.05 50.69,98.18 50.69,99.13 50.43,99.39 49.99,99.39 49.73,99.13 49.73,97.64 49.6,97.51 49.35,97.51 49.22,97.64 v2(49.22,98.32) 49.22,99.13 48.96,99.39 48.51,99.39 48.25,99.13 48.25,97.64 48.13,97.51 47.87,97.51 47.75,97.64 47.75,99.13 47.48,99.39 46.27,99.39 45.95,99.08 45.95,98.72 46.62,98.06 46.62,96.52 46.39,96.3 45.8,96.3 44.63,95.13 44.27,95.13 44.15,95.25 44.15,95.48 43.88,95.74 43.44,95.74 43.18,95.48 43.18,95.25 43.05,95.13 42.8,95.13 42.67,95.25 42.67,95.48 42.41,95.74 42.02,95.74 41.49,95.2 41.35,95.2 41.25,95.31 40.59,95.31 40.47,95.43 40.47,95.64 40.62,95.79 41.25,95.79 41.74,96.28 41.74,96.88 41.84,96.98 42.09,96.98 42.15,96.93 UV8.B7
M_MA0: length 73.2
  TOP w0.102: v3(32.23,75.86) 32.44,75.65 32.54,75.65 32.65,75.75 32.65,76.04 33.1,76.5 33.1,76.59 32.95,76.74 32.95,77.04 33.03,77.12 33.25,77.12 33.35,77.03 UV6.N3 ; UV7.N3 33.35,96.84 33.25,96.93 33.03,96.93 32.95,96.85 32.95,96.55 33.1,96.4 33.1,96.31 32.65,95.86 32.65,95.56 32.54,95.46 32.44,95.46 v3(32.23,95.67) ; 49.71,84.18 51.96,84.18 52.27,83.88 53.19,83.88 53.3,83.98 57.55,83.98 58.06,84.49 58.34,84.49 58.46,84.37 58.46,82.76 v3(58.2,82.49)
  TOP w0.203: v3(29.93,86.08) 29.93,85.75 30.92,84.76 31.32,84.76 31.71,85.15 31.81,85.15 32.04,85.37 32.47,85.37 32.7,85.15 32.7,84.05 32.9,83.85 33.35,83.85 33.56,84.05 v1(33.56,85.09) 34.22,85.75 34.45,85.75 34.63,85.58 34.63,84.97 34.78,84.81 35.26,84.81 35.46,85.02 35.46,85.78 35.67,85.98 36.05,85.98 36.25,85.78 36.25,85.02 36.46,84.81 36.84,84.81 37.01,84.99 37.01,85.45 38.17,86.6 39.11,86.6 39.25,86.75 41,86.75 41.56,86.19 45.26,86.19 47.27,84.18 49.71,84.18
  IN3 w0.135: v3(32.23,75.86) 32.23,77 30.43,78.81 30.43,81.88 30.56,82.02 30.56,85.25 29.93,85.89 v3(29.93,86.08) 29.93,86.26 30.39,86.72 30.39,87.07 30.28,87.18 30.18,87.18 30.08,87.28 30.08,90.12 30.37,90.41 30.37,90.72 30.84,91.19 30.84,92.15 32.62,93.93 32.62,95.28 v3(32.23,95.67)
  BOTTOM w0.102: UV8.N3 33.35,93.91 32.64,94.62 32.64,95.13 32.23,95.54 v3(32.23,95.67) ; v3(58.2,82.49) 58.5,82.8 58.5,82.8 UV1.K17 ; v3(32.23,75.86) 32.23,75.73 32.64,75.32 32.64,74.8 33.35,74.1 UV5.N3
M_MA1: length 72.8
  TOP w0.102: v3(32.22,94.96) 32.15,95.03 31.93,95.03 31.83,94.92 31.83,94.64 32.55,93.93 UV7.P7 ; v3(32.22,75.14) 32.15,75.21 31.93,75.21 31.83,75.11 31.83,74.83 32.55,74.12 UV6.P7 ; 51.44,81.44 51.47,81.41 52.97,81.41 53.27,81.11 54.63,81.11 54.91,80.83 55.35,80.83 55.68,80.5 57.05,80.5 v3(57.4,80.15)
  TOP w0.203: v3(29.61,84.53) 29.61,84.31 30.71,83.2 30.71,82.39 30.39,82.06 30.39,81.82 30.7,81.51 31.04,81.51 31.53,81.99 31.53,82.96 31.71,83.14 31.92,83.14 v1(32.3,82.76) 32.3,82.32 32.44,82.17 32.98,82.17 33.13,82.33 33.13,82.76 33.31,82.94 33.69,82.94 34.09,82.53 34.29,82.53 34.67,82.91 37.55,82.91 38.06,83.43 38.78,83.43 39.3,82.91 41.2,82.91 41.72,83.43 42.75,83.43 42.91,83.27 42.91,82.92 43.08,82.74 43.61,82.74 43.8,82.94 43.8,83.27 43.95,83.43 44.15,83.43 44.56,83.01 44.56,82.61 44.22,82.27 44.22,81.98 44.48,81.72 44.76,81.72 45.16,82.12 45.45,82.12 45.67,81.9 45.67,81.61 45.36,81.3 45.36,81.01 45.49,80.88 46.26,80.88 46.46,81.08 46.46,81.23 46.67,81.44 51.44,81.44
  IN3 w0.135: v3(32.22,75.14) 32.22,75.21 31.83,75.59 31.83,76.34 31.4,76.77 31.4,77.36 30.09,78.67 30.09,82.18 30.18,82.27 30.18,85.15 30.01,85.32 29.8,85.32 29.61,85.13 v3(29.61,84.53) 29.22,84.91 29.22,86.53 29.7,87 29.7,90.23 30.03,90.56 30.03,90.86 30.49,91.32 30.49,92.27 32.19,93.97 32.19,94.92 v3(32.22,94.96)
  BOTTOM w0.102: v3(57.4,80.15) 57.95,80.7 UV1.J20 ; UV8.P7 32.55,96.52 31.83,95.81 31.83,95.51 32.04,95.31 32.04,95.14 v3(32.22,94.96) ; UV5.P7 32.55,76.71 31.83,76 31.83,75.7 32.04,75.49 32.04,75.33 v3(32.22,75.14)
M_MA2: length 65.6
  TOP w0.102: UV6.P3 32.55,76.36 32.45,76.26 31.91,76.26 31.83,76.18 31.83,75.85 31.76,75.77 31.44,75.77 v3(31.43,75.78) ; UV7.P3 32.55,96.17 32.45,96.07 31.91,96.07 31.83,95.99 31.83,95.66 31.76,95.58 31.44,95.58 v3(31.43,95.59)
  IN1 w0.216: v3(57.56,78.9) 57.56,78.94 56.97,79.53 53.83,79.53 53.02,80.34 51.44,80.34 49.79,82 33.82,82 33.5,82.31 30.96,82.31 28.91,84.36 v3(28.91,84.59)
  IN3 w0.135: v3(31.43,75.78) 31.37,75.84 31.37,76.32 31.07,76.63 31.07,77.22 29.75,78.53 29.75,82.22 29.17,82.81 28.76,82.81 28.63,82.94 28.63,83.14 28.76,83.27 29.34,83.27 29.47,83.39 29.47,83.57 29.34,83.7 28.63,83.7 28.5,83.82 28.5,84.03 28.63,84.15 28.96,84.15 29.06,84.26 29.06,84.46 28.94,84.59 v3(28.91,84.59) 28.89,84.61 28.89,86.67 29.34,87.13 29.34,90.4 29.69,90.75 29.69,91 30.13,91.44 30.13,92.39 31.82,94.09 31.82,95.2 v3(31.43,95.59)
  BOTTOM w0.102: UV5.P3 32.51,73.76 32.51,74.26 31.81,74.96 31.81,75.34 31.43,75.71 v3(31.43,75.78) ; v3(31.43,95.59) 31.43,95.53 31.81,95.15 31.81,94.77 32.51,94.07 32.51,93.58 UV8.P3
  BOTTOM w0.203: UV1.H23 57.2,78.53 v3(57.56,78.9)
M_MA3: length 79.8
  TOP w0.102: UV6.N2 33.35,77.47 33.22,77.34 32.22,77.34 32.12,77.24 32.12,76.72 31.92,76.52 31.62,76.52 31.4,76.31 30.64,76.31 30.54,76.2 30.54,75.95 v3(30.63,75.86) ; 52.15,79.05 52.28,79.05 52.43,78.9 54.35,78.9 v1(54.35,78.92) 54.37,78.9 54.55,78.9 54.97,78.48 55.59,78.48 v3(56.01,78.06) ; UV7.N2 33.35,97.28 33.22,97.15 32.22,97.15 32.12,97.05 32.12,96.53 31.92,96.33 31.62,96.33 31.4,96.12 30.64,96.12 30.54,96.02 30.54,95.77 v3(30.63,95.67)
  TOP w0.203: v3(27.74,83.91) 27.71,83.94 26.68,83.94 26.47,83.73 26.47,83.29 26.73,83.04 27.62,83.04 28,83.42 28.96,83.42 29.19,83.19 29.19,81.73 30.32,80.6 31.49,80.6 32.07,81.18 32.59,81.18 33.18,80.6 39.07,80.6 39.66,80.01 43.69,80.01 44.66,79.05 52.15,79.05
  IN3 w0.135: v3(30.63,75.86) 30.63,76.1 30.39,76.35 30.39,76.94 28.29,79.04 28.29,79.14 27.57,79.86 27.57,80.37 27.72,80.52 28.94,80.52 29.07,80.66 29.07,81.41 28.88,81.61 28.3,81.61 28.15,81.45 28.15,81.16 28.02,81.03 27.72,81.03 27.57,81.18 27.57,83.73 v3(27.74,83.91) 27.74,85.63 28.01,85.91 28.01,88.42 28.07,88.48 28.07,90.37 29.42,91.72 29.42,92.64 31.02,94.24 31.02,95.28 30.82,95.48 30.82,95.49 v3(30.63,95.67)
  BOTTOM w0.102: UV8.N2 32.93,93.15 32.39,93.15 32.12,93.42 32.12,93.98 31.58,94.52 31.31,94.52 31.04,94.79 31.04,95.08 30.63,95.49 v3(30.63,95.67) ; UV1.G23 56.01,78.11 v3(56.01,78.06) ; UV5.N2 32.93,73.33 32.39,73.33 32.12,73.6 32.12,74.17 31.58,74.71 31.31,74.71 31.04,74.98 31.04,75.27 30.63,75.67 v3(30.63,75.86)
M_MA4: length 74.6
  TOP w0.102: UV6.P8 32.22,72.92 32.13,73.01 32.13,74.23 31.98,74.38 31.71,74.38 31.25,74.83 31.25,74.97 v3(31.42,75.14) ; 52.15,78.59 52.23,78.59 52.28,78.54 v1(52.83,78.54) 54.41,78.54 54.92,78.02 55.46,78.02 56,77.49 v3(56,77.3) ; UV7.P8 32.22,92.73 32.13,92.82 32.13,94.04 31.98,94.19 31.71,94.19 31.25,94.64 31.25,94.78 v3(31.42,94.96)
  TOP w0.203: v3(28.15,82.88) 28.11,82.88 27.72,82.49 27.72,82.27 27.9,82.1 28.17,82.1 29.34,80.93 29.34,80.67 28.96,80.29 28.96,80.07 29.34,79.68 29.34,78.95 29.55,78.74 30.33,78.74 30.56,78.97 30.56,79.28 30.16,79.68 30.16,79.94 30.36,80.14 31.68,80.14 32.21,80.68 32.45,80.68 32.99,80.14 33.89,80.14 34.42,79.61 34.82,79.61 35.35,80.14 36.91,80.14 37.21,79.84 37.52,79.84 37.82,80.14 38.88,80.14 39.47,79.56 43.5,79.56 44.47,78.59 52.15,78.59
  IN3 w0.135: v3(31.42,94.96) 31.38,94.91 31.38,94.12 29.77,92.51 29.77,91.6 29.34,91.16 29.34,90.94 28.99,90.58 28.99,87.99 28.35,87.35 28.35,84.79 28.15,84.59 v3(28.15,82.88) 28.02,82.76 28.02,82.07 28.15,81.94 29.21,81.94 29.41,81.74 29.41,80.34 29.26,80.18 28.96,80.18 28.84,80.06 28.84,79.81 28.99,79.66 29.29,79.66 29.41,79.54 29.41,79.4 29.06,79.05 29.06,78.74 30.73,77.08 30.73,76.49 31.04,76.18 31.04,75.53 v3(31.42,75.14)
  BOTTOM w0.102: v3(56,77.3) 56,77.49 56.21,77.7 UV1.G24 ; v3(31.42,94.96) 31.42,95.06 31.05,95.42 31.05,95.75 31.24,95.94 31.26,95.94 31.47,96.14 31.76,96.14 32.15,96.53 32.15,97.13 UV8.P8 ; v3(31.42,75.14) 31.42,75.24 31.05,75.61 31.05,75.94 31.24,76.13 31.26,76.13 31.47,76.33 31.76,76.33 32.15,76.72 32.15,77.32 UV5.P8
M_MA5: length 80.5
  TOP w0.102: UV6.P2 32.31,77.72 31.92,77.33 30.34,77.33 29.97,76.96 29.83,76.96 29.47,77.31 29.31,77.31 29.19,77.19 29.19,77.02 29.54,76.67 29.54,76.53 29.22,76.2 v3(28.63,76.2) ; v3(28.63,95.41) 29.19,95.96 29.19,96.67 29.65,97.14 31.92,97.14 32.31,97.53 UV7.P2
  IN1 w0.102: 55.61,78.44 55.66,78.49 56.42,78.49 56.8,78.11 v3(56.8,78.08)
  IN1 w0.216: 55.61,78.44 55.07,78.44 54.46,79.05 53.65,79.05 52.82,79.87 51.24,79.87 49.59,81.53 33.62,81.53 33.31,81.84 28.2,81.84 24.82,85.22 v3(24.82,85.45)
  IN3 w0.135: v3(28.63,76.2) 28.63,76.31 24.67,80.27 24.67,85.29 v3(24.82,85.45) 24.82,87.76 26.35,89.29 26.35,91.19 27.57,92.41 27.57,93.17 29.06,94.66 29.06,94.98 v3(28.63,95.41)
  BOTTOM w0.102: UV8.P2 32.3,92.73 31.89,93.14 31.61,93.14 31.33,93.42 31.33,93.69 30.82,94.21 29.93,94.21 28.76,95.38 28.66,95.38 v3(28.63,95.41) ; v3(28.63,76.2) 29.18,75.66 29.18,75.15 30.18,74.15 31.07,74.15 31.33,73.88 31.33,73.6 31.61,73.33 31.89,73.33 32.3,72.92 UV5.P2 ; UV1.H24 57.2,77.71 56.8,78.11 v3(56.8,78.08)
M_MA6: length 77.9
  TOP w0.102: v3(57.6,81.3) 56.98,81.92 55.88,81.92 55.4,82.4 53.09,82.4 52.76,82.07 52.08,82.07 51.97,82.17 ; v3(29.82,75.14) 29.53,75.14 29.44,75.06 29.44,74.76 29.52,74.68 29.98,74.68 30.44,74.22 31.12,74.22 31.32,74.02 31.32,73.08 31.48,72.92 UV6.R8 ; UV7.R8 31.48,92.73 31.32,92.89 31.32,93.83 31.12,94.04 30.44,94.04 29.98,94.49 29.52,94.49 29.44,94.57 29.44,94.85 29.55,94.96 v3(29.82,94.96)
  TOP w0.203: v3(25.91,85.12) 25.91,85.1 26.17,84.85 26.67,84.85 26.97,85.15 27.49,85.15 27.78,84.85 28.39,84.85 28.58,85.04 28.58,85.33 28.76,85.51 29.04,85.51 29.44,85.09 29.93,85.09 30.13,84.89 30.13,84.43 v1(30.48,84.08) 30.88,83.68 31.16,83.68 31.32,83.85 31.32,84 31.48,84.15 31.95,84.15 32.14,83.97 32.14,83.57 32.31,83.39 33.69,83.39 34.04,83.75 34.04,84.18 34.22,84.36 44.51,84.36 46.51,82.35 51.8,82.35 51.97,82.17
  IN3 w0.135: v3(29.82,75.14) 29.38,75.59 29.38,76.52 26.09,79.8 26.09,84.94 v3(25.91,85.12) 25.96,85.17 25.96,87.86 27.06,88.96 27.06,90.94 28.3,92.18 28.3,92.95 29.85,94.5 29.85,94.93 v3(29.82,94.96)
  BOTTOM w0.102: v3(57.6,81.3) 57.82,81.52 57.82,81.72 UV1.J19 ; UV8.R8 31.32,97.11 31.32,96.58 31.1,96.36 29.92,96.36 29.39,95.83 29.39,95.56 29.82,95.13 v3(29.82,94.96) ; UV5.R8 31.32,77.3 31.32,76.77 31.1,76.55 29.92,76.55 29.39,76.02 29.39,75.75 29.82,75.32 v3(29.82,75.14)
M_MA7: length 84.7
  TOP w0.102: UV7.R2 31.86,97.64 31.86,97.82 31.76,97.92 29.38,97.92 28.72,97.26 28.55,97.26 27.76,96.48 27.76,95.96 v3(27.74,95.94) ; UV6.R2 31.9,77.72 32.01,77.84 32.01,78 31.9,78.11 29.21,78.11 27.76,76.66 27.76,76.15 v3(27.74,76.13)
  IN1 w0.102: v3(58.38,81.52) 58.03,81.87 56.06,81.87 55.48,82.45 54.72,82.45
  IN1 w0.216: 54.72,82.45 53.22,82.45 53.07,82.3 52.24,82.3 51.14,83.41 44.34,83.41 43.82,83.93 37.25,83.93 36.98,84.19 31.41,84.19 30.53,85.07 26.65,85.07 25.79,85.93 24.69,85.93 24.47,85.79 v3(23.68,85.25)
  IN3 w0.135: v3(27.74,95.94) 27.74,95.89 28.23,95.4 28.23,94.79 26.85,93.42 26.85,92.69 25.61,91.44 25.61,89.72 23.68,87.79 v3(23.68,85.25) 23.7,85.22 23.7,84.73 23.53,84.56 23.53,84.27 23.7,84.1 23.7,83.97 23.53,83.8 23.53,83.54 23.7,83.37 23.7,83.21 23.53,83.04 23.53,82.83 23.7,82.66 23.7,82.45 23.53,82.27 23.53,82.06 23.7,81.89 23.7,80.28 27.74,76.24 v3(27.74,76.13)
  BOTTOM w0.102: v3(27.74,95.94) 28.23,95.46 28.23,94.67 29.79,93.11 31.2,93.11 31.57,92.73 UV8.R2 ; v3(58.38,81.52) 58.76,81.9 UV1.K19 ; v3(27.74,76.13) 28.23,75.65 28.23,74.86 29.79,73.3 31.2,73.3 31.57,72.92 UV5.R2
M_MA8: length 83.2
  TOP w0.102: v3(27.79,75.16) 27.79,74.55 28.26,74.09 29.11,74.09 29.24,73.96 29.24,73.57 29.35,73.46 29.51,73.46 29.62,73.57 29.62,73.96 29.75,74.09 29.91,74.09 30.95,73.05 UV6.T8 ; UV7.T8 29.78,93.9 29.16,93.9 29.06,93.8 29.06,93.37 28.94,93.25 28.77,93.25 28.66,93.37 28.66,93.8 28.55,93.9 28.26,93.9 27.79,94.37 v3(27.79,94.97)
  IN1 w0.102: 52.69,86.14 53.12,86.14 53.51,85.74 55.39,85.74 55.41,85.72 57.02,85.72 v3(57.5,86.2)
  IN1 w0.216: v3(23.09,85.27) 23.09,85.37 24.14,86.42 25.97,86.42 26.81,85.58 30.69,85.58 31.13,85.13 33.65,85.13 34.12,85.6 39.35,85.6 39.63,85.88 40.11,85.88 40.52,85.48 41.13,85.48 41.79,86.14 52.69,86.14
  IN3 w0.135: v3(27.79,75.16) 27.23,75.73 27.23,76.28 23.2,80.31 23.2,85.17 v3(23.09,85.27) 23.2,85.37 23.2,87.94 25.25,90 25.25,91.57 26.5,92.82 26.5,93.54 27.79,94.83 v3(27.79,94.97)
  BOTTOM w0.102: UV1.J14 58,85.7 v3(57.5,86.2) ; v3(27.79,94.97) 27.79,95.33 27.34,95.79 27.34,96.09 28.78,97.53 UV8.T8 ; UV5.T8 28.78,77.72 27.34,76.28 27.34,75.98 27.79,75.52 v3(27.79,75.16)
M_MA9: length 70.7
  TOP w0.102: v3(29.83,75.86) 29.83,76.16 30.38,76.71 30.59,76.71 30.77,76.53 31.22,76.53 31.32,76.64 31.32,77.02 31.4,77.09 31.58,77.09 UV6.R3 ; v3(29.83,95.67) 29.83,95.97 30.38,96.52 30.59,96.52 30.77,96.35 31.22,96.35 31.32,96.45 31.32,96.83 31.4,96.91 31.58,96.91 UV7.R3
  IN1 w0.102: 52.38,86.69 52.41,86.67 54.67,86.67 54.82,86.52 55.53,86.52 55.71,86.69 57.58,86.69 v3(58.12,86.16)
  IN1 w0.216: 52.38,86.69 40.8,86.69 40.46,86.35 39.44,86.35 39.16,86.07 34.3,86.07 34.05,86.31 32.95,86.31 32.62,85.98 32.01,85.98 31.45,86.54 30.16,86.54 30.05,86.64 28.23,86.64 27.79,87.08 26.83,87.08 26.47,86.72 v3(26.47,86.59)
  IN3 w0.135: v3(29.83,95.67) 30.22,95.28 30.22,94.39 28.68,92.86 28.68,91.95 27.39,90.66 27.39,88.82 27.28,88.7 27.28,88.16 27.13,88.02 26.6,88.02 26.3,87.72 26.3,87.35 26.4,87.25 26.73,87.25 26.85,87.13 26.85,86.97 v3(26.47,86.59) 26.47,85.42 26.65,85.25 26.65,79.72 29.71,76.66 29.71,75.98 v3(29.83,75.86)
  BOTTOM w0.102: UV8.R3 31.75,93.76 30.99,94.52 30.38,94.52 30.21,94.7 30.21,95.13 29.83,95.5 v3(29.83,95.67) ; v3(29.83,75.86) 29.83,75.69 30.21,75.32 30.21,74.88 30.58,74.51 31.19,74.51 31.75,73.95 UV5.R3 ; v3(58.12,86.16) 58.77,85.5 UV1.K14
M_MA10: length 66.3
  TOP w0.102: v3(35.42,75.14) 35.22,75.14 34.75,74.68 34.75,74.32 34.95,74.13 UV6.L7 ; v3(35.42,94.96) 35.22,94.96 34.75,94.49 34.75,94.14 34.95,93.94 UV7.L7
  IN1 w0.102: 51.62,87.56 51.64,87.56 52.2,88.12 55.61,88.12 55.81,87.91 57.27,87.91 v3(57.9,87.28)
  IN1 w0.216: v3(35.16,86.97) 35.03,87.1 35.03,87.55 35.2,87.72 35.38,87.72 35.58,87.52 35.83,87.52 36.01,87.7 36.01,87.95 35.91,88.06 35.91,88.33 36.1,88.52 36.37,88.52 36.55,88.35 36.55,88.2 36.72,88.03 36.97,88.03 37.14,88.2 37.14,88.35 37.32,88.52 37.57,88.52 37.74,88.35 37.74,88.2 37.91,88.03 38.16,88.03 38.34,88.2 38.34,88.35 38.51,88.52 38.85,88.52 39.03,88.35 39.03,88.2 39.2,88.03 39.45,88.03 39.63,88.2 39.63,88.35 39.8,88.52 40.05,88.52 40.22,88.35 40.22,88.2 40.4,88.03 40.65,88.03 40.82,88.2 40.82,88.35 40.99,88.52 41.34,88.52 41.51,88.35 41.51,88.2 41.69,88.03 41.93,88.03 42.11,88.2 42.11,88.35 42.28,88.52 42.53,88.52 42.71,88.35 42.71,88.2 42.88,88.03 43.13,88.03 43.3,88.2 43.3,88.35 43.48,88.52 43.73,88.52 43.9,88.35 43.9,88.2 44.07,88.03 44.32,88.03 44.5,88.2 44.5,88.35 44.67,88.52 44.92,88.52 45.09,88.35 45.09,88.2 45.27,88.03 45.52,88.03 45.69,88.2 45.69,88.35 45.87,88.52 46.11,88.52 46.29,88.35 46.29,88.2 46.46,88.03 46.71,88.03 46.88,88.2 46.88,88.35 47.06,88.52 47.38,88.52 47.53,88.37 47.53,88.19 47.68,88.04 47.99,88.04 48.27,88.32 48.59,88.32 49.35,87.56 51.62,87.56
  IN3 w0.135: v3(35.42,94.96) 35.35,94.88 35.35,94.66 35.22,94.53 35.22,94.23 35.08,94.09 35.08,93.09 33.97,91.98 33.97,91.77 34.1,91.65 34.42,91.65 34.55,91.52 34.55,91.06 34.22,90.73 34.22,90.61 34.55,90.28 34.55,90.12 34.42,90 34.02,90 33.89,89.87 33.89,89.56 34.02,89.43 34.5,89.43 34.63,89.31 34.63,89.04 34.5,88.92 34,88.92 33.87,88.78 33.87,88.04 34,87.91 34.25,87.91 34.37,88.04 34.37,88.32 34.5,88.45 34.73,88.45 34.85,88.32 34.85,87.76 34.98,87.63 35.46,87.63 35.57,87.53 35.57,87.08 35.46,86.97 v3(35.16,86.97) 35.16,86.67 33.97,85.48 33.97,83.93 33.76,83.72 33.76,82.94 34.19,82.5 34.19,79.94 34.52,79.61 34.52,78.87 34.79,78.61 34.79,77.57 35.08,77.27 35.08,75.48 v3(35.42,75.14)
  BOTTOM w0.102: v3(57.9,87.28) 58.02,87.4 58.02,87.88 UV1.J11 ; v3(35.42,94.96) 35.42,95.09 35.03,95.48 35.03,96 34.95,96.08 UV8.L7 ; UV5.L7 34.95,76.27 35.08,76.14 35.08,75.62 35.42,75.28 v3(35.42,75.14)
M_MA11: length 74.7
  TOP w0.102: 54.69,87.48 54.87,87.3 55.43,87.3 55.89,86.85 56.85,86.85 v3(57.28,87.28) ; UV7.R7 31.75,93.83 31.18,94.4 30.38,94.4 30.21,94.57 30.21,94.85 30.33,94.97 30.6,94.97 v3(30.62,94.96) ; v3(30.62,75.14) 30.6,75.16 30.33,75.16 30.21,75.04 30.21,74.76 30.38,74.59 31.18,74.59 31.75,74.02 UV6.R7
  TOP w0.203: 54.69,87.48 54.59,87.58 52.28,87.58 51.57,86.87 50.52,86.87 50.34,87.05 50.34,87.35 50.14,87.56 49.73,87.56 49.53,87.35 49.53,86.87 49.32,86.67 48.92,86.67 48.72,86.87 48.72,87.35 48.51,87.56 48.11,87.56 47.9,87.35 47.9,86.87 47.7,86.67 47.37,86.67 46.02,88.02 45.57,88.02 45.27,88.32 45.27,89.34 44.77,89.84 36.26,89.84 34.97,88.55 32.81,88.55 31.26,87 v1(30.56,87) 30.21,87.35 30.21,88.04 30,88.24 29.55,88.24 29.34,88.04 29.34,86.95 28.92,86.53 28.52,86.53 28.15,86.9 27.82,86.9 27.62,86.69 27.62,86.31 v3(27.41,86.11)
  IN3 w0.135: v3(30.62,75.14) 30.23,75.53 30.23,76.03 30.05,76.21 30.05,76.8 27.16,79.69 27.16,85.53 27.41,85.78 v3(27.41,86.11) 27.62,86.31 27.62,86.75 27.39,86.97 27.39,87.25 27.62,87.48 27.62,88.56 27.73,88.68 27.73,90.52 29.06,91.85 29.06,92.76 30.62,94.32 v3(30.62,94.96)
  BOTTOM w0.102: UV1.J13 57.86,86.7 v3(57.28,87.28) ; UV8.R7 31.75,96.71 31.18,96.14 30.5,96.14 30.23,95.87 30.23,95.46 30.42,95.27 30.42,95.15 v3(30.62,94.96) ; UV5.R7 31.75,76.9 31.18,76.33 30.5,76.33 30.23,76.06 30.23,75.65 30.42,75.45 30.42,75.34 v3(30.62,75.14)
M_MA12: length 74.8
  TOP w0.102: v3(33.03,94.96) 32.8,94.96 32.52,94.67 32.52,94.26 33.25,93.53 UV7.N7 ; v3(33.03,75.14) 32.8,75.14 32.52,74.86 32.52,74.45 33.25,73.72 UV6.N7
  TOP w0.203: v3(30.86,87.49) 30.66,87.68 30.66,88.37 30.9,88.61 31.26,88.61 31.6,88.27 31.89,88.27 32.16,88.55 32.16,89.11 32.47,89.41 32.77,89.41 33.18,89.01 33.51,89.01 33.89,89.39 34.14,89.39 34.52,89.01 34.78,89.01 35.62,89.84 35.62,90.12 35.38,90.36 35.38,90.65 35.66,90.93 35.95,90.93 36.58,90.3 44.96,90.3 45.73,89.53 45.73,88.96 47.13,87.56 47.46,87.56 47.92,88.02 50.35,88.02 51.03,87.33 51.38,87.33 52.09,88.04 52.83,88.04 53.03,88.24 53.03,89.54 53.24,89.74 53.64,89.74 53.85,89.54 53.85,88.24 54.05,88.04 54.36,88.04 54.62,88.29 54.62,89.36 54.79,89.54 55.4,89.54 55.63,89.31 55.63,88.8 55.38,88.55 55.38,88.32 55.81,87.89 57.66,87.89 57.87,88.09 57.87,88.4 57.66,88.6 56.95,88.6 v3(56.8,88.45)
  IN3 w0.135: v3(33.03,75.14) 32.63,75.55 32.63,77.08 30.79,78.92 30.79,81.67 30.97,81.84 30.97,85.32 30.41,85.88 30.41,86.26 30.73,86.58 30.73,87.36 v3(30.86,87.49) 30.86,87.74 30.74,87.86 30.56,87.86 30.44,87.99 30.44,88.27 30.56,88.4 31.07,88.4 31.2,88.52 31.2,88.76 30.99,88.97 30.55,88.97 30.42,89.1 30.42,89.37 30.55,89.5 30.99,89.5 31.2,89.71 31.2,92.03 33.01,93.84 33.01,94.94 v3(33.03,94.96)
  BOTTOM w0.102: v3(33.03,75.14) 33.03,75.23 32.65,75.62 32.65,76.14 33.35,76.84 UV5.N7 ; v3(33.03,94.96) 33.03,95.04 32.65,95.43 32.65,95.95 33.35,96.65 UV8.N7
  BOTTOM w0.203: v3(56.8,88.45) 57.2,88.05 UV1.H11
M_MA13: length 75.6
  TOP w0.102: 51.31,80.57 51.48,80.4 53.05,80.4 53.45,80.8 54.53,80.8 54.8,80.53 54.8,80.23 55.06,79.97 56.07,79.97 v3(56.19,80.09) ; v3(28.65,94.82) 29.42,95.6 29.42,95.86 29.61,96.05 29.61,96.05 30.29,96.73 UV7.T3 ; UV6.T3 30.29,76.92 29.61,76.24 29.61,76.24 29.42,76.05 29.42,75.78 v3(28.65,75.01)
  TOP w0.203: 51.31,80.57 50.9,80.98 47.2,80.98 46.61,80.39 45.15,80.39 43.25,82.29 42.65,82.29 42.45,82.49 42.45,82.73 42.21,82.97 41.91,82.97 41.39,82.45 39.11,82.45 38.59,82.97 38.25,82.97 37.74,82.45 34.86,82.45 34.48,82.07 33.52,82.07 33.16,81.72 31.96,81.72 31.3,81.05 30.51,81.05 29.77,81.8 29.77,82.09 30.26,82.58 30.26,83.01 29.37,83.9 28.6,83.9 28.11,84.39 v1(25.96,84.39) 24.46,84.39 v3(24.14,84.71)
  IN3 w0.135: v3(28.65,94.82) 28.58,94.76 28.58,94.67 27.21,93.29 27.21,92.54 25.96,91.29 25.96,89.51 24.14,87.69 v3(24.14,84.71) 24.14,80.32 28.17,76.29 28.17,75.39 28.56,75.01 v3(28.65,75.01)
  BOTTOM w0.102: UV1.G20 56.39,80.7 56.19,80.5 v3(56.19,80.09) ; v3(28.65,75.01) 28.65,75 29.92,73.72 UV5.T3 ; v3(28.65,94.82) 28.65,94.81 30.03,93.43 30.36,93.43 30.44,93.5 30.44,93.7 30.51,93.78 30.82,93.78 30.95,93.65 UV8.T3
M_MA14: length 79.2
  TOP w0.102: UV7.T7 30.56,93.53 29.85,94.24 28.68,94.24 28.23,94.7 28.23,95.56 28.63,95.97 v3(28.63,96.02) ; v3(56.03,86.15) 55.66,86.52 54.9,86.52 ; v3(28.63,75.59) 28.3,75.59 28.23,75.52 28.23,74.6 28.4,74.43 28.61,74.43 28.78,74.6 29.11,74.6 29.29,74.43 29.9,74.43 30.61,73.72 UV6.T7
  TOP w0.203: 54.9,86.52 54.59,86.82 53.47,86.82 53.07,86.42 50.96,86.42 50.76,86.21 v1(49.97,86.21) 47.82,86.21 47.63,86.02 47.37,86.02 45.83,87.56 45.04,87.56 44.81,87.79 44.81,89.15 44.58,89.38 36.45,89.38 35.16,88.09 33,88.09 31.45,86.54 29.58,86.54 29.11,86.07 28.03,86.07 27.57,85.6 25.56,85.6 v3(25.41,85.45)
  IN3 w0.135: v3(28.63,75.59) 29.04,76 29.04,76.38 25.08,80.34 25.08,82.12 25.74,82.78 25.74,84.23 25.41,84.56 v3(25.41,85.45) 25.43,85.47 25.43,87.81 26.7,89.08 26.7,91.06 27.95,92.31 27.95,93.07 29.39,94.52 29.39,95.43 28.81,96.02 v3(28.63,96.02)
  BOTTOM w0.102: v3(56.03,86.15) 56.03,85.94 56.4,85.57 UV1.G14 ; v3(28.63,96.02) 28.86,95.79 29.01,95.79 29.59,96.37 29.59,97.1 29.72,97.24 29.87,97.24 30,97.11 30,96.8 30.13,96.68 30.31,96.68 30.44,96.8 30.44,97.06 30.51,97.13 30.99,97.13 31.07,97.06 31.07,96.86 UV8.T7 ; v3(28.63,75.59) 28.2,76.03 28.2,76.74 28.78,77.32 30.79,77.32 30.95,77.17 UV5.T7
M_MA15: length 68.2
  TOP w0.102: v3(33.83,75.14) 33.52,75.14 33.41,75.04 33.41,74.3 33.98,73.72 UV6.M7 ; UV7.M7 33.98,93.53 33.41,94.11 33.41,94.85 33.52,94.96 v3(33.83,94.96)
  IN1 w0.216: v3(31.9,84.66) 33.84,84.66 34.31,85.13 36.71,85.13 37.39,84.45 43.97,84.45 44.54,83.88 51.33,83.88 51.92,83.29 52.25,83.29 52.46,83.49 52.46,83.85 52.66,84.05 53.09,84.05 53.3,83.85 53.3,83.7 53.5,83.49 53.96,83.49 54.16,83.7 54.16,83.9 54.36,84.1 54.82,84.1 55.03,83.9 55.03,83.67 55.23,83.47 55.69,83.47 55.89,83.67 55.89,84.18 56.09,84.38 56.55,84.38 56.75,84.18 56.75,83.21 56.96,83.01 57.41,83.01 57.61,83.21 57.61,84.18 57.82,84.38 59.59,84.38 59.8,84.18 59.8,83.8 59.59,83.6 59.11,83.6 58.91,83.39 58.91,83.06 59.11,82.86 60.09,82.86 v3(60.14,82.81)
  IN3 w0.135: v3(33.83,75.14) 33.46,75.52 33.46,77.3 32.04,78.72 32.04,79.79 31.93,79.9 31.93,80.1 31.67,80.36 31.67,80.77 31.93,81.02 31.93,81.31 31.67,81.56 31.67,81.84 31.93,82.1 31.93,82.38 31.67,82.64 31.67,84.44 v3(31.9,84.66) 31.9,91.77 33.71,93.59 33.71,94.59 33.83,94.72 v3(33.83,94.96)
  BOTTOM w0.102: v3(33.83,94.96) 33.83,95.03 33.46,95.41 33.46,96.04 UV8.M7 ; v3(33.83,75.14) 33.83,75.22 33.43,75.62 33.43,76.21 UV5.M7 ; v3(60.14,82.81) 59.65,83.3 UV1.L17
M_RAS#0: length 54.3
  TOP w0.102: 52.13,79.51 52.3,79.68 52.93,79.68 53.24,79.37 55.59,79.37 56,78.96 v3(56,78.9) ; UV6.J3 36.59,76.97 36.89,76.97 36.96,76.89 36.96,76.76 36.86,76.66 36.86,76.56 36.94,76.48 37.24,76.48 37.32,76.41 37.32,76.26 37.24,76.18 36.94,76.18 36.83,76.07 36.83,75.88 36.98,75.73 v3(37.09,75.73)
  TOP w0.203: v3(36.56,81.06) 36.55,81.05 35.22,81.05 35.06,81.22 35.06,81.45 35.22,81.61 37.17,81.61 37.42,81.36 41.03,81.36 41.64,80.75 43.6,80.75 44.84,79.51 52.13,79.51
  IN3 w0.102: 37.37,79.15 37.14,79.15 36.99,79 36.99,78.67 37.37,78.29 37.37,76.92 37.09,76.63 v3(37.09,75.73)
  IN3 w0.254: 37.37,79.15 37.47,79.25 37.47,79.48 36.99,79.96 36.99,80.27 37.24,80.52 37.57,80.52 38.08,80.01 38.33,80.01 38.84,80.52 39.15,80.52 39.58,80.09 42.35,80.09 43.64,81.39 43.64,83.27 43.44,83.47 42.78,83.47 42.6,83.29 42.6,81.73 42.1,81.23 36.73,81.23 v3(36.56,81.06)
  BOTTOM w0.102: v3(56,78.9) 56.4,79.3 UV1.G22 ; UV5.J3 36.55,74.23 36.8,74.48 36.94,74.48 37.44,74.98 37.44,75.37 v3(37.09,75.73)
M_RAS#1: length 52
  TOP w0.102: v3(37.09,95.54) 36.98,95.54 36.83,95.69 36.83,95.89 36.94,95.99 37.24,95.99 37.32,96.07 37.32,96.22 37.24,96.3 36.94,96.3 36.86,96.37 36.86,96.47 36.96,96.58 36.96,96.7 36.89,96.78 36.59,96.78 UV7.J3 ; 52.16,82.59 52.38,82.38 52.76,82.38 52.99,82.6 55.61,82.6 55.78,82.43 56.25,82.43 v3(56.32,82.49)
  TOP w0.203: 52.16,82.59 51.95,82.81 46.7,82.81 44.7,84.81 39.06,84.81 38.89,84.99 38.89,85.23 39.06,85.4 v3(39.81,85.4)
  IN3 w0.102: 37.17,91.47 37.32,91.62 37.32,94.42 37.45,94.54 37.45,95.23 37.13,95.54 v3(37.09,95.54)
  IN3 w0.254: v3(39.81,85.4) 39.56,85.4 39.29,85.67 39.29,86.07 40.02,86.8 43.91,86.8 45.18,85.52 45.47,85.52 46.01,86.07 46.01,86.36 44.53,87.84 40.54,87.84 40.34,88.04 40.34,88.51 39.94,88.9 39.53,88.9 39.37,88.74 39.08,88.74 38.63,89.2 38.63,89.48 38.82,89.67 38.82,90.03 38.46,90.39 38.1,90.39 37.9,90.19 37.54,90.19 37.17,90.57 37.17,91.47
  BOTTOM w0.102: UV1.G17 56.39,83.09 56.39,82.57 v3(56.32,82.49) ; UV8.J3 36.55,94.04 36.8,94.3 36.94,94.3 37.44,94.79 37.44,95.19 v3(37.09,95.54)
M_WE#0: length 49.7
  TOP w0.102: UV6.L3 34.95,77.08 35.08,77.22 35.29,77.22 35.41,77.09 35.41,76.56 35.31,76.46 35.01,76.46 34.93,76.38 34.93,76.2 35.03,76.1 35.24,76.1 v3(35.49,75.85)
  IN1 w0.216: v3(34.93,79.07) 35.52,79.66 35.52,80.12 35.35,80.28 34.72,80.28 34.47,80.52 34.47,80.84 34.69,81.06 35.67,81.06 35.93,80.79 35.93,80.52 36.14,80.32 36.84,80.32 37.04,80.52 37.04,80.85 37.24,81.06 37.85,81.06 38.06,80.85 38.06,80.52 38.28,80.29 38.73,80.29 38.94,80.51 38.94,80.85 39.15,81.06 41.57,81.06 41.79,80.84 41.79,80.6 41.99,80.4 42.45,80.4 42.65,80.6 42.65,80.84 42.87,81.06 43.3,81.06 43.52,80.84 43.52,80.6 43.72,80.4 44.18,80.4 44.38,80.6 44.38,80.84 44.6,81.06 45.03,81.06 45.24,80.84 45.24,80.6 45.45,80.4 45.9,80.4 46.11,80.6 46.11,80.84 46.32,81.06 46.75,81.06 46.97,80.84 46.97,80.6 47.17,80.4 47.63,80.4 47.83,80.6 47.83,80.84 48.05,81.06 48.7,81.06 48.88,80.88 48.88,80.49 49.41,79.96 49.76,79.96 49.95,80.15 50.24,80.15 50.57,79.81 50.57,79.53 50.36,79.31 50.36,79.01 50.52,78.85 51.16,78.85 51.29,78.97 51.29,79.2 51.49,79.4 51.95,79.4 52.15,79.2 52.15,79 52.36,78.8 53.24,78.8 53.45,78.58 54.27,78.58 54.51,78.33 54.51,78.08 53.94,77.51 53.94,76.57 53.57,76.2 53.57,75.54 53.78,75.34 54.51,75.34 54.72,75.54 54.72,76.86 54.92,77.07 55.48,77.07 55.68,76.86 55.68,76.62 55.87,76.43 56.13,76.43 56.32,76.62 56.32,76.93 v3(56.79,77.41)
  IN3 w0.102: v3(35.49,75.85) 35.49,77.34 35.16,77.67 35.16,78.73 35.05,78.85 35.05,78.96 v3(34.93,79.07)
  BOTTOM w0.102: UV5.L3 34.95,74.11 35.82,74.99 35.82,75.35 35.6,75.56 35.6,75.74 v3(35.49,75.85) ; UV1.G25 56.4,76.94 56.79,77.33 v3(56.79,77.41)
M_WE#1: length 51.1
  TOP w0.102: UV7.L3 34.95,96.9 35.08,97.03 35.29,97.03 35.41,96.91 35.41,96.37 35.31,96.27 35.01,96.27 34.93,96.19 34.93,96.02 35.03,95.91 35.19,95.91 35.43,95.67 v3(35.44,95.67)
  IN1 w0.102: 51.36,88.5 51.47,88.6 55.45,88.6 55.58,88.73 56.24,88.73 56.76,89.25 v3(56.8,89.25)
  IN1 w0.216: 51.36,88.5 49.74,88.5 48.77,89.46 35.62,89.46 34.65,88.5 29.28,88.5 28.3,87.53 28.03,87.53 27.83,87.72 27.83,88 28.99,89.16 34.55,89.16 34.75,89.36 v3(34.75,89.74)
  IN3 w0.102: v3(34.75,89.74) 34.88,89.87 34.88,92.43 35.52,93.07 35.52,94.04 35.82,94.34 35.82,95.28 v3(35.44,95.67)
  BOTTOM w0.102: v3(35.44,95.67) 35.6,95.5 35.6,95.38 35.82,95.16 35.82,94.8 34.95,93.92 UV8.L3 ; v3(56.8,89.25) 57.15,88.9 UV1.H10
MA_ZVDDIO: length 2.8
  TOP w0.203: v1(137.13,84.99) v3(136.49,84.99) 136.01,85.47 R3.2
  BOTTOM w0.203: UC1.U30 135.98,85.5 v3(136.49,84.99)
MCT0: length 3.2
  TOP w0.102: v3(190.43,104.32) v1(191.31,104.32)
  TOP w0.508: RL19.1 v3(190.43,104.32)
  BOTTOM w0.508: v3(190.43,104.32) 190.3,104.45 TL2.14
MCT1: length 3.4
  TOP w0.102: v3(190.43,108.26) v1(191.5,108.26)
  TOP w0.508: v3(190.43,108.26) 190.3,108.39 RL20.1
  BOTTOM w0.508: TL2.11 v3(190.43,108.26)
MDI0+: length 8.8
  BOTTOM w0.102: TL2.8 179.33,110.8 178.9,110.37 178.36,110.37 176.92,108.92 v1(176.92,106.04) 175.89,105.01 175.51,105.01 UL1.1
MDI0-: length 8.8
  BOTTOM w0.102: 180.21,109.53 179.28,109.53 178.85,109.96 178.53,109.96 177.32,108.75 v1(177.32,107.62) 177.32,105.87 176.01,104.56 UL1.2
MDI1+: length 5.4
  BOTTOM w0.102: UL1.4 175.76,103.76 175.81,103.81 177.39,103.81 177.72,103.48 v1(178,103.2) 178.45,102.75 178.87,102.75 179.3,103.18 TL2.2
MDI1-: length 5.3
  BOTTOM w0.102: UL1.5 v1(176.61,103.36) 177.27,103.36 177.71,102.91 178.29,102.34 178.85,102.34 179.28,101.91 TL2.1
MDO0+: length 14.4
  BOTTOM w0.102: TL2.9 190.07,110.8 190.17,110.7 190.17,110.47 190.27,110.37 192.46,110.37 v1(193.06,109.77) 194.52,108.31 201.13,108.31 201.4,108.58 201.4,108.82 JLAN.1
MDO0-: length 14.4
  BOTTOM w0.102: 188.97,109.53 190.07,109.53 190.17,109.63 190.17,109.86 190.27,109.96 192.27,109.96 v1(194.11,108.12) 194.33,107.9 201.3,107.9 201.5,108.1 JLAN.2
MDO1+: length 14.7
  BOTTOM w0.102: TL2.15 190.07,103.18 190.17,103.08 190.17,102.85 190.27,102.75 192.88,102.75 195.29,105.16 v1(196.32,105.16) 200.03,105.16 200.36,105.49 200.36,106.34 JLAN.3
MDO1-: length 14.7
  BOTTOM w0.102: JLAN.6 200.76,104.02 200.03,104.76 195.46,104.76 v1(194.41,103.71) 193.05,102.34 190.27,102.34 190.17,102.24 190.17,102.01 190.07,101.91 TL2.16
MEM_MA_EVENT#: length 55.1
  TOP w0.102: v3(159.09,42.44) v1(159.09,43.26) 156.85,45.5 156.85,46.03 154.77,48.11 154.77,61.09 147.22,68.63 147.22,74.53 R6.2 147.28,74.6 v3(146.28,75.59)
  BOTTOM w0.102: v3(146.28,75.59) 146.28,76.31 144.96,77.63 141.66,77.63 139.5,79.79 139.5,81.19 138.78,81.92 138.78,82.68 139.2,83.1 UC1.AB33 ; JDIMM1.198 157.65,40.52 158.05,40.92 158.05,41.4 v3(159.09,42.44)
MEM_MA_RST#: length 61.8
  TOP w0.102: v3(118.67,63.05) v3(118.67,57.61)
  BOTTOM w0.102: v3(118.67,57.61) 118.24,57.18 118.24,44.63 116.97,43.36 105.21,43.36 104.85,43 JDIMM1.30 ; v3(118.67,63.05) 118.67,72.06 v1(121.91,75.3) 126.95,80.34 127.27,80.34 127.68,80.75 128.06,80.75 128.26,80.95 128.26,82.32 128.62,82.68 129.48,82.68 UC1.J33
MIC1-L: length 3.6
  BOTTOM w0.102: v1(191.01,21.1) 191.01,20.59 191.38,20.22 CA74.1
  BOTTOM w0.203: CA74.1 191.44,19.69 UA1.19
MIC_CLK: length 256.8
  IN3 w0.102: v3(198.1,11.87) 197.95,11.87 196.96,10.88 196.96,9.2 195.89,8.13 187.76,8.13 186.09,6.46 177.11,6.46 176.28,5.62 168.5,5.62 167.05,4.17 163.79,4.17 163.2,4.76 157.2,4.76 156.51,4.07 145.6,4.07 145.02,3.49 137.37,3.49 137,3.85 134.43,3.85 132.8,5.49 131.1,5.49 129.72,6.86 128.55,6.86 127.25,8.17 126,8.17 124.96,9.21 120.97,9.21 120.45,9.73 113.03,9.73 112.32,10.43 112.32,11.99 101.04,23.28 97.17,23.28 96.72,23.73 88.55,23.73 88.14,23.32 77.72,23.32 74.72,26.32 69.06,26.32 66.99,28.39 52.85,28.39 46.63,34.61 46.63,38.7 45.91,39.41 31.29,39.41 29.34,41.36 25.34,41.36 14.36,52.35 14.36,54.55 14.69,54.88 14.69,61.43 14.22,61.9 14.22,65.97 14.85,66.6 14.85,73.32 6.74,81.44 5.49,81.44 v3(3.28,83.65)
  BOTTOM w0.102: LA1.2 198.67,13.78 198.41,13.52 198.41,12.17 v3(198.1,11.87) ; LA1.2 200.01,13.78 v1(200.26,13.53) ; LA1.2 199.04,13.75 CA22.1 ; v3(3.28,83.65) 3.28,84.08 2.95,84.41 2.42,84.41 2.33,84.5 JEDP.30
MIC_CLK_C: length 2.5
  BOTTOM w0.102: UA1.3 197.93,16.04 v1(198.58,15.38) 198.58,14.86 198.92,14.53 LA1.1
MIC_DATA: length 260.4
  IN3 w0.102: v3(198.13,11.28) 198.51,10.9 198.51,9.71 196.52,7.72 187.93,7.72 186.26,6.05 177.28,6.05 176.44,5.21 168.67,5.21 167.2,3.75 163.64,3.75 163.03,4.36 157.37,4.36 156.68,3.66 145.8,3.66 145.22,3.08 137.2,3.08 136.83,3.45 134.26,3.45 132.63,5.08 130.93,5.08 129.55,6.46 128.39,6.46 127.13,7.71 125.89,7.71 124.79,8.8 120.58,8.8 120.21,9.17 113.01,9.17 111.44,10.75 111.44,12.31 100.87,22.87 97,22.87 96.55,23.32 88.72,23.32 88.31,22.92 77.54,22.92 74.64,25.81 68.99,25.81 66.98,27.83 52.62,27.83 46.07,34.38 46.07,38.46 45.68,38.85 31.28,38.85 29.17,40.96 24.96,40.96 13.9,52.02 13.9,54.74 14.27,55.11 14.27,61.09 13.77,61.59 13.77,66.16 14.34,66.73 14.34,73.04 7.68,79.71 6.36,79.71 v3(2.75,83.32)
  BOTTOM w0.102: v3(198.13,11.28) 198.38,11.54 199.79,11.54 v1(200.26,12.01) 200.97,12.72 200.97,13.52 199.9,14.58 199.9,14.63 198.82,15.71 198.6,15.71 198.33,15.98 UA1.2 ; JEDP.32 2.57,83.5 v3(2.75,83.32)
MIC_IN: length 13.4
  TOP w0.381: QA6.3 190.88,32.55 v3(191.01,32.41)
  IN1 w1.016: 190.99,30.69 191.55,30.13 191.55,26.29 193.22,24.62 193.22,21.95 191.62,20.35 191.62,19.59
  vias: v1(191.17,18.33) v3(191.62,18.67) v3(191.62,18.04)
MIC_IN_R: length 19.8
  TOP w0.102: v1(194.68,35.34) 195.66,34.36 v2(195.66,33.99)
  IN1 w1.016: JHP.4 209,26.22 199.93,26.22 198.23,27.92 198.23,31.63 197.35,32.5
  vias: v2(196.25,32.82)
OCP_L: length 158
  TOP w0.102: v3(58.6,103.43) 58.81,103.64 60.97,103.64 61.09,103.51 61.65,103.51 v1(61.71,103.45) 62.34,102.82 62.34,102.82 62.59,102.57 62.59,102.23 62.1,101.73 RV90.2
  IN2 w0.127: v3(58.6,103.43) 57.56,102.39 45.94,102.39 44.06,104.27 40.34,104.27 39.63,104.98 30.99,104.98 27.11,101.1 23.35,101.1 12.99,90.73 12.99,89.84 11.54,88.39 11.54,72.8 12.02,72.32 12.02,61.14 23.76,49.41 23.76,47.91 30.56,41.1 30.56,39.54 36.6,33.51 42.38,33.51 45.93,29.95 v3(47.81,29.95)
  BOTTOM w0.203: PU1000.4 62.13,33.54 62.34,33.33 62.34,32.81 62.76,32.39 PR1020.2 62.72,32.19 62.03,32.19 59.8,29.95 v3(47.81,29.95)
ODD_EN: length 5.1
  TOP w0.102: v3(145.95,13.31) 145.89,13.31 145.64,13.06 T129.1 145.8,12.64 RH40.2
  BOTTOM w0.102: U2.K6 148.38,14.15 147.4,14.15 147.12,13.87 147.12,13.59 146.84,13.31 v3(145.95,13.31)
OFS: length 6.5
  TOP w0.203: PU500.23 59.79,111.76 59.71,111.68 59.29,111.68 v1(59.01,111.4) 59.01,111 v2(58.69,110.67) 58.55,110.81 58.55,111.41 58.05,111.92 PR555.1 PR554.2
  BOTTOM w0.203: PR528.2 59.75,111.82 58.69,110.76 v2(58.69,110.67)
OFSA: length 6
  TOP w0.203: PR561.1 PR560.2 59.11,110.16 v2(59.14,110.19) 59.32,110.37 59.32,110.85 59.82,111.36 PU500.24
  BOTTOM w0.102: v2(59.14,110.19) v1(58.13,110.19)
  BOTTOM w0.203: v2(59.14,110.19) 59.87,110.93 PR529.2
ON/OFF: length 148.2
  TOP w0.102: v3(168.05,107.24) 168.05,111.21 172.28,115.43 v3(172.28,116.2) SW1.3 SW1.4 ; v3(120.2,25.58) v4(120.2,26.17)
  IN1 w0.102: v3(120.2,25.58) 121.87,25.58 123.93,27.64 128.05,27.64 128.75,26.94 132.83,26.94 139.5,33.61 139.61,33.61 144.24,38.23 145.77,38.23 147.19,39.64 153.92,39.64 155.68,41.41 156.52,41.41 157.11,41.99 157.41,41.99 159.11,43.69 159.11,44.21 160.75,45.85 160.75,46.83 168.79,54.87 168.79,61.62 173.34,66.17 173.34,99.9 173.74,100.31 173.74,101.27 172.94,102.07 172.26,102.07 171.56,102.77 171.56,103.76 170.15,105.17 169.84,105.17 168.05,106.96 v3(168.05,107.24)
  BOTTOM w0.102: v3(120.2,25.58) 120.2,23.36 120.94,22.62 120.94,22.08 121.16,21.85 121.62,21.85 121.96,22.19 UE1.114 ; v3(172.28,116.2) 171.9,116.2 CE20.1 RE49.1 172.14,118.6 DE2.3
P2: length 7.3
  TOP w0.102: v1(28.9,28.63) 28.23,29.3 v3(28.23,29.44)
  TOP w0.254: PQ707.3 28.45,29.67 v3(28.23,29.44)
  IN3 w0.254: v2(30.11,33.99) 30.11,31.32 v3(28.23,29.44)
  vias: v2(29.65,34.5)
P3: length 7.8
  TOP w0.102: v1(31.5,28.95) 31.5,29.28 30.86,29.92 v3(30.68,29.92)
  TOP w0.508: PC701.2 v3(30.68,29.92)
  BOTTOM w0.508: v3(30.68,29.92) 31.06,29.92 32.31,31.17 32.31,33.46 32.59,33.73 PQ705.8
P_ZVDDP: length 5.3
  BOTTOM w0.203: R1.2 153.14,93.77 v1(151.94,93.77) 150.29,93.77 148.96,95.1 UC1.AN18
P_ZVSS: length 6.5
  BOTTOM w0.203: UC1.AM18 148.3,94.7 148.65,94.7 150.86,92.49 v1(152.19,92.49) 153.28,92.49 R34.1
PACIN#: length 1.4
  TOP w0.102: RV147.2 78.54,97.16 v1(78.71,97.32)
PBTN_OUT#: length 39.3
  TOP w0.102: v3(121.49,22.94) 123.35,22.94 123.96,22.33 v1(124.36,22.33)
  IN3 w0.102: v3(148.14,13.69) 148.14,13.85 146.18,15.8 141.98,15.8 141.44,16.34 140.16,16.34 140.01,16.49 138.56,16.49 135.11,19.94 135.11,20.71 134.54,21.27 123.88,21.27 122.21,22.94 v3(121.49,22.94)
  BOTTOM w0.102: v3(148.14,13.69) 148.11,13.72 U2.J4 ; UE1.106 121.12,25.39 120.83,25.1 120.83,23.6 v3(121.49,22.94)
PC_BEEP: length 6.3
  TOP w0.102: RA19.1 RA79.2 190.56,15.69 190.65,15.78 DA8.1 191.66,17.2 192.2,16.67 192.88,16.67 v1(193.2,16.98)
PCC_GPIO_6: length 15.4
  TOP w0.102: v3(61.08,99.24) 60.89,99.43 CVT90.2 RV90.1 62.82,101.73 RV91.1
  IN1 w0.114: v3(61.08,99.24) 61.27,99.05 61.27,98.33 62.5,97.1 62.5,92.09 62.34,91.93 62.34,90.55 v3(62.79,90.1)
  BOTTOM w0.102: UV1.T8 63.2,90.5 v3(62.79,90.1) ; v3(61.08,99.24) 61.13,99.24 v1(61.52,99.64)
PCH_X1: length 50
  IN1 w0.114: v3(138.59,17.86) 138.59,14.1 139.19,13.5 139.19,12.12 139.38,11.93 139.38,6.34 141.68,4.03 147.73,4.03 148.3,4.6 153.64,4.6 153.69,4.65 156.97,4.65 157.53,5.22 161,5.22 162.05,6.27 164.61,6.27 v3(165,6.66)
  BOTTOM w0.102: v3(165,6.66) v1(165.89,6.66) 167.04,5.52 167.04,5.49 167.34,5.19 167.34,4.09 167.54,3.89 167.54,3.43 168.38,2.6 169.13,2.6 169.41,2.87 169.41,3.43 169.18,3.66 RH21.1 ; R783.2 136.86,16.9 137.37,17.4 138.13,17.4 v3(138.59,17.86)
PCH_X1_R: length 2.4
  BOTTOM w0.102: R783.1 136.73,15.87 v1(136.73,14.91) UG1.5
PCI_AD23: length 8.7
  BOTTOM w0.102: RH125.1 152.55,34.91 v1(152.55,33.14) 152.7,32.99 152.7,30.29 152.66,30.26 152.66,29.54 152.7,29.51 152.7,28.98 153.04,28.64 153.04,27.18 U2.AE12
PCI_AD24: length 10.8
  BOTTOM w0.102: U2.AC12 152.63,25.98 152.63,28.35 151.87,29.12 151.87,32.68 151.38,33.16 v1(151.38,34) 151.38,34.8 RH124.1
PCI_AD25: length 8.8
  BOTTOM w0.102: U2.AE13 154.74,26.73 154.74,26.98 153.96,27.76 153.96,28.5 153.55,28.91 v1(153.55,34.04) 153.55,34.87 RH123.1
PCI_AD26: length 7.7
  BOTTOM w0.102: RH122.1 v1(154.41,33.04) 154.41,32.6 154.28,32.47 154.28,27.99 U2.AF13
PCI_AD27: length 6
  BOTTOM w0.102: RH121.1 v1(155.36,34.05) 155.36,32.18 155.1,31.92 155.1,30.27 154.7,29.87 U2.AH13
PCI_CLK1: length 10.3
  BOTTOM w0.102: RH126.1 145.14,31.87 145.83,31.17 145.83,27.83 U2.AF1 ; RH126.1 v1(143.94,34.97) ; RH126.1 RH114.2
PCI_CLK3: length 7.9
  BOTTOM w0.102: RH127.1 RH115.2 146.79,34.71 v3(146.79,33.99) 146.79,28.16 U2.AG2
PCI_CLK4: length 10.2
  BOTTOM w0.102: RH128.1 RH116.2 149.9,33.81 v1(149.54,33.45) 149.32,33.23 148.87,33.23 147.69,32.05 147.69,28.78 148.17,28.3 148.17,27.9 U2.AF6
PCIE_B+:
  vias: v1(75.44,50.83)
PCIE_CALRN: length 2.4
  TOP w0.102: RH2.2 167.85,26.53 v3(167.65,26.33)
  BOTTOM w0.102: U2.AF31 168.42,27.32 167.65,26.55 v3(167.65,26.33)
PCIE_CALRP: length 1.8
  TOP w0.102: RH5.2 167.98,27.49 v3(167.45,26.95)
  BOTTOM w0.102: U2.AF29 167.82,27.32 v3(167.45,26.95)
PCIE_PRX_DTX_N0: length 28.4
  IN1 w0.114: v3(144.3,106.74) 144.53,106.96 144.53,107.56 145.49,108.51 150.42,108.51 154.11,104.83 156.83,104.83 157.64,104.02 161.7,104.02 164.01,101.71 166.58,101.71 v3(166.76,101.88)
  BOTTOM w0.102: v3(166.76,101.88) 166.96,101.68 167.77,101.68 CL31.1 ; UC1.AH3 144.67,107.1 v3(144.3,106.74)
PCIE_PRX_DTX_N0_C: length 3
  BOTTOM w0.102: CL31.2 169.25,101.57 169.61,101.57 170.49,102.46 170.83,102.46 170.94,102.56 UL1.18
PCIE_PRX_DTX_N1: length 100.7
  IN1 w0.114: v3(183.04,61.55) 182.86,61.73 182.86,63.94 182.71,64.09 182.71,67.47 181.18,69 181.18,82.97 175.67,88.48 175.67,91.71 175.44,91.94 175.44,99.28 175.75,99.59 175.75,101.64 175.19,102.2 175.19,105.21 175.11,105.29 175.11,107.2 173.47,108.84 171.3,108.84 168.46,111.69 165.7,111.69 160.42,116.97 158.96,116.97 158.12,117.81 148.98,117.81 146.64,115.47 146.64,113.11 145.95,112.42 145.95,110.34 142.86,107.24 142.86,105.71 143.36,105.21 143.76,105.21 143.92,105.05 143.92,104.82 v3(143.81,104.7)
  BOTTOM w0.102: v3(143.81,104.7) 143.8,104.7 UC1.AF6 ; v3(183.04,61.55) 182.83,61.34 182.83,58.89 182.98,58.75 JNGFF.35
PCIE_PRX_DTX_P0: length 28.4
  IN1 w0.114: v3(166.76,101.24) 166.76,101.3 166.55,101.5 163.93,101.5 161.62,103.81 157.55,103.81 156.74,104.63 154.02,104.63 150.34,108.31 145.57,108.31 144.74,107.47 144.74,106.96 144.96,106.74 v3(145.09,106.74)
  BOTTOM w0.102: UC1.AH4 144.7,106.34 v3(145.09,106.74) ; v3(166.76,101.24) 166.98,101.46 167.56,101.46 CL30.1
PCIE_PRX_DTX_P0_C: length 3
  BOTTOM w0.102: UL1.17 170.9,102.16 170.82,102.24 170.6,102.24 v2(170.1,101.74) 169.71,101.36 169.25,101.36 CL30.2
PCIE_PRX_DTX_P1: length 100.7
  IN1 w0.114: v3(182.41,61.55) 182.51,61.55 182.66,61.7 182.66,63.85 182.51,64 182.51,67.39 180.98,68.91 180.98,82.88 175.47,88.4 175.47,91.62 175.24,91.85 175.24,99.37 175.55,99.67 175.55,101.55 174.99,102.11 174.99,105.13 174.91,105.2 174.91,107.12 173.39,108.64 171.22,108.64 168.37,111.48 165.61,111.48 160.33,116.77 158.87,116.77 158.04,117.61 149.06,117.61 146.84,115.39 146.84,113.03 146.16,112.34 146.16,110.26 143.06,107.16 143.06,105.8 143.44,105.41 143.85,105.41 144.13,105.13 144.13,104.98 144.41,104.7 v3(144.44,104.7)
  BOTTOM w0.102: JNGFF.33 182.48,58.75 182.62,58.89 182.62,61.42 182.49,61.55 v3(182.41,61.55) ; UC1.AG7 144.08,103.9 144.44,104.26 v3(144.44,104.7)
PCIE_PTX_C_DRX_N0: length 34.2
  IN1 w0.114: v3(149.94,116.04) 150.2,115.79 150.2,115.13 151.59,113.75 155.58,113.75 156.65,112.68 160.7,112.68 168.46,104.92 168.46,103.83 170.86,101.43 172.46,101.43 172.88,101.01 172.88,100.82 172.88,100.82 v3(172.73,100.66)
  BOTTOM w0.102: C18.2 149.71,114.36 149.71,114.71 150.21,115.21 150.21,115.78 v3(149.94,116.04) ; UL1.14 172.81,101.06 172.9,100.97 172.9,100.84 v3(172.73,100.66)
PCIE_PTX_C_DRX_N1: length 84.6
  IN1 w0.114: v3(147.48,114.86) 147.63,115.02 147.63,115.29 149.31,116.97 154.47,116.97 156.4,115.04 160.21,115.04 165.75,109.5 166.71,109.5 170.21,106 173.12,106 173.95,105.17 173.95,102.22 174.86,101.31 174.86,100.2 174.2,99.54 174.2,91.58 174.83,90.94 174.83,87.74 179.69,82.89 179.69,65.06 181.36,63.39 181.36,61.72 v3(181.54,61.54)
  BOTTOM w0.102: v3(147.48,114.86) 147.5,114.84 147.5,114.18 C20.2 ; v3(181.54,61.54) 181.34,61.33 181.34,58.89 181.48,58.75 JNGFF.29
PCIE_PTX_C_DRX_P0: length 34.2
  IN1 w0.114: v3(150.69,116.04) 150.4,115.75 150.4,115.22 151.67,113.95 155.67,113.95 156.73,112.88 160.79,112.88 168.66,105.01 168.66,103.92 170.95,101.63 172.55,101.63 173.08,101.1 173.08,100.91 v3(173.32,100.66)
  BOTTOM w0.102: UL1.13 173.21,101.05 173.12,100.96 173.12,100.87 v3(173.32,100.66) ; C17.2 149.93,114.29 149.93,114.62 150.42,115.12 150.42,115.78 v3(150.69,116.04)
PCIE_PTX_C_DRX_P1: length 84.6
  IN1 w0.114: v3(180.91,61.54) 181,61.54 181.16,61.7 181.16,63.3 179.48,64.98 179.48,82.81 174.63,87.66 174.63,90.86 174,91.5 174,99.62 174.66,100.28 174.66,101.22 173.74,102.14 173.74,105.08 173.03,105.8 170.13,105.8 166.62,109.3 165.66,109.3 160.13,114.84 156.32,114.84 154.39,116.77 149.39,116.77 147.83,115.21 147.83,115.09 v3(148.06,114.86)
  BOTTOM w0.102: JNGFF.27 180.98,58.67 181.12,58.82 181.12,61.37 180.95,61.54 v3(180.91,61.54) ; v3(148.06,114.86) 147.72,114.52 147.72,114.01 147.81,113.92 C19.2
PCIE_PTX_DRX_N0: length 6.1
  BOTTOM w0.102: UC1.AM1 148.02,108.7 148.11,108.79 148.11,109.1 148.42,109.4 148.42,110.14 150.08,111.8 150.08,112.39 149.96,112.51 149.3,112.51 149.18,112.63 149.18,112.91 C18.1
PCIE_PTX_DRX_N1: length 5.6
  BOTTOM w0.102: UC1.AL1 147.22,108.7 147.29,108.76 147.29,110.05 148.05,110.81 148.05,112.39 147.93,112.51 147.25,112.51 147.15,112.6 147.15,112.91 C20.1
PCIE_PTX_DRX_P0: length 6.1
  BOTTOM w0.102: C17.1 150.3,111.71 148.63,110.05 148.63,109.31 148.32,108.99 148.32,108.32 UC1.AM2
PCIE_PTX_DRX_P1: length 5.6
  BOTTOM w0.102: UC1.AL2 147.1,108.09 147.5,108.49 147.5,109.96 148.27,110.72 C19.1
PECI_KB930: length 3.1
  BOTTOM w0.102: UE1.74 112.39,31.46 111.96,31.89 111.84,31.89 v1(111.65,32.08) 111.65,32.96 RE69.1
PEG_CLKREQ#: length 169.4
  TOP w0.102: RV153.1 64.27,92.15 64.27,93.21 64.57,93.51 64.57,97.67 65.39,98.48 70.16,98.48 70.39,98.71 v1(73.56,98.71) v3(76.71,98.71) ; RH56.2 159.04,36.2 v3(158.45,36.79)
  IN2 w0.127: v3(158.45,36.79) 158.45,36.5 154.69,32.74 142.07,32.74 140.7,31.37 129.58,31.37 127.93,29.72 123.53,29.72 122.26,28.45 120.82,28.45 119.54,27.17 117.45,27.17 116.39,28.23 116.39,32.49 112.4,36.48 99.07,36.48 95.71,39.83 95.71,45.02 95.81,45.12 95.81,53.13 92.84,56.11 92.84,70.36 94.75,72.27 94.75,73.68 86.59,81.83 86.59,94.26 84.46,96.39 84.46,97.41 83.57,98.3 77.12,98.3 v3(76.71,98.71)
PEG_CLKREQ#_G: length 3.9
  TOP w0.102: RV153.2 63.65,90.87 v1(63.44,91.08) 63.34,91.18 61.74,91.18 v3(61.58,91.01)
  BOTTOM w0.102: UV1.N7 61.29,91.3 v3(61.58,91.01)
PEG_CLKREQ#_R: length 16.5
  TOP w0.102: v3(166.68,36.58) 165.79,35.69 v1(164.67,35.69) 163.39,35.69 RH95.2 RH56.1
  IN3 w0.135: v3(166.68,36.58) 166.66,36.55 166.66,35.18 165.23,33.76 165.23,31.12 164.78,30.66 164.78,27.77 v3(163.99,26.98)
  BOTTOM w0.102: U2.AF25 164.4,27.39 v3(163.99,26.98)
PEG_GTX_C_HRX_N0: length 96.7
  IN1 w0.114: v3(81.18,69.91) 81.01,70.08 80.75,70.08 80.44,70.4 80.44,70.9 82.09,72.55 84.38,72.55 85.05,73.22 85.05,84.61 106.91,106.48 106.91,106.71 112.88,112.68 118.25,112.68 118.94,111.99 137.1,111.99 140.72,108.37 140.72,103.27 140.15,102.7 139.06,102.7 v3(138.88,102.52)
  BOTTOM w0.102: v3(138.88,102.52) 138.52,102.52 UC1.Y9 ; CV2.1 80.4,70.03 81.06,70.03 v3(81.18,69.91)
PEG_GTX_C_HRX_N1: length 95.3
  IN1 w0.114: v3(84.05,67.62) 83.95,67.72 83.42,67.72 83.14,68 83.14,70.4 85.68,72.94 85.68,74.26 86.26,74.84 86.26,84.81 92,90.56 92,90.69 107.65,106.34 107.65,106.51 113.19,112.04 117.95,112.04 118.63,111.36 136.82,111.36 140.09,108.09 140.09,106.48 139.55,105.95 139.11,105.95 v3(138.88,105.72)
  BOTTOM w0.102: v3(138.88,105.72) 138.7,105.9 137.5,105.9 UC1.W5 ; CV4.1 81.18,67.49 81.39,67.7 83.98,67.7 v3(84.05,67.62)
PEG_GTX_C_HRX_N2: length 92.2
  IN1 w0.114: v3(137.66,103.35) 137.89,103.59 138.15,103.59 138.46,103.9 138.46,105.6 137.52,106.54 137.52,108.27 135.07,110.72 118.35,110.72 117.67,111.41 113.47,111.41 110.42,108.36 110.42,106.34 109.09,105.01 107.38,105.01 92.77,90.4 92.77,89.04 87.13,83.4 87.13,74.82 86.32,74 86.32,72.48 84.99,71.16 84.99,68.36 84.59,67.95 84.59,66.93 84.83,66.68 85.17,66.68 v3(85.32,66.53)
  BOTTOM w0.102: CV6.1 83.63,66.6 85.25,66.6 v3(85.32,66.53) ; UC1.W8 137.35,103.35 v3(137.66,103.35)
PEG_GTX_C_HRX_N3: length 92.2
  IN1 w0.114: v3(136.52,105.69) 136.52,105.51 136.61,105.41 136.83,105.41 136.94,105.52 136.94,105.91 136.68,106.17 136.68,107.9 134.69,109.88 118.01,109.88 117.33,110.57 113.81,110.57 111.26,108.02 111.26,105.94 109.5,104.18 107.92,104.18 104.86,101.12 104.86,99.78 94.9,89.82 93.96,89.82 93.61,89.46 93.61,88.27 88.07,82.73 88.07,73.66 87.15,72.75 87.15,71.96 86.06,70.87 86.06,66.21 85.44,65.59 84.83,65.59 v3(84.6,65.36)
  BOTTOM w0.102: v3(136.52,105.69) 136.66,105.69 137.01,106.05 137.01,106.23 136.91,106.33 136.73,106.33 UC1.V4 ; v3(84.6,65.36) 84.6,65.41 84.46,65.55 80.49,65.55 CV8.1
PEG_GTX_C_HRX_N4: length 84.9
  IN1 w0.114: v3(136.44,102.9) 136.44,103.17 136.28,103.33 136,103.33 135.77,103.56 135.77,106.24 135.62,106.39 135.62,108.08 134.45,109.25 124.49,109.25 121.88,106.63 121.01,106.63 119.01,104.63 117.25,104.63 116.13,103.51 108.34,103.51 105.72,100.89 105.72,99.75 94.9,88.93 94.9,87.79 88.73,81.61 88.73,72.97 87.81,72.06 87.81,71.27 86.77,70.23 86.77,69.35 86.88,69.24 87.05,69.24 v3(87.26,69.45)
  BOTTOM w0.102: UC1.U8 136.13,103.33 136.28,103.33 136.44,103.17 v3(136.44,102.9) ; v3(87.26,69.45) 87.26,69.45 86.99,69.18 83.66,69.18 CV16.1
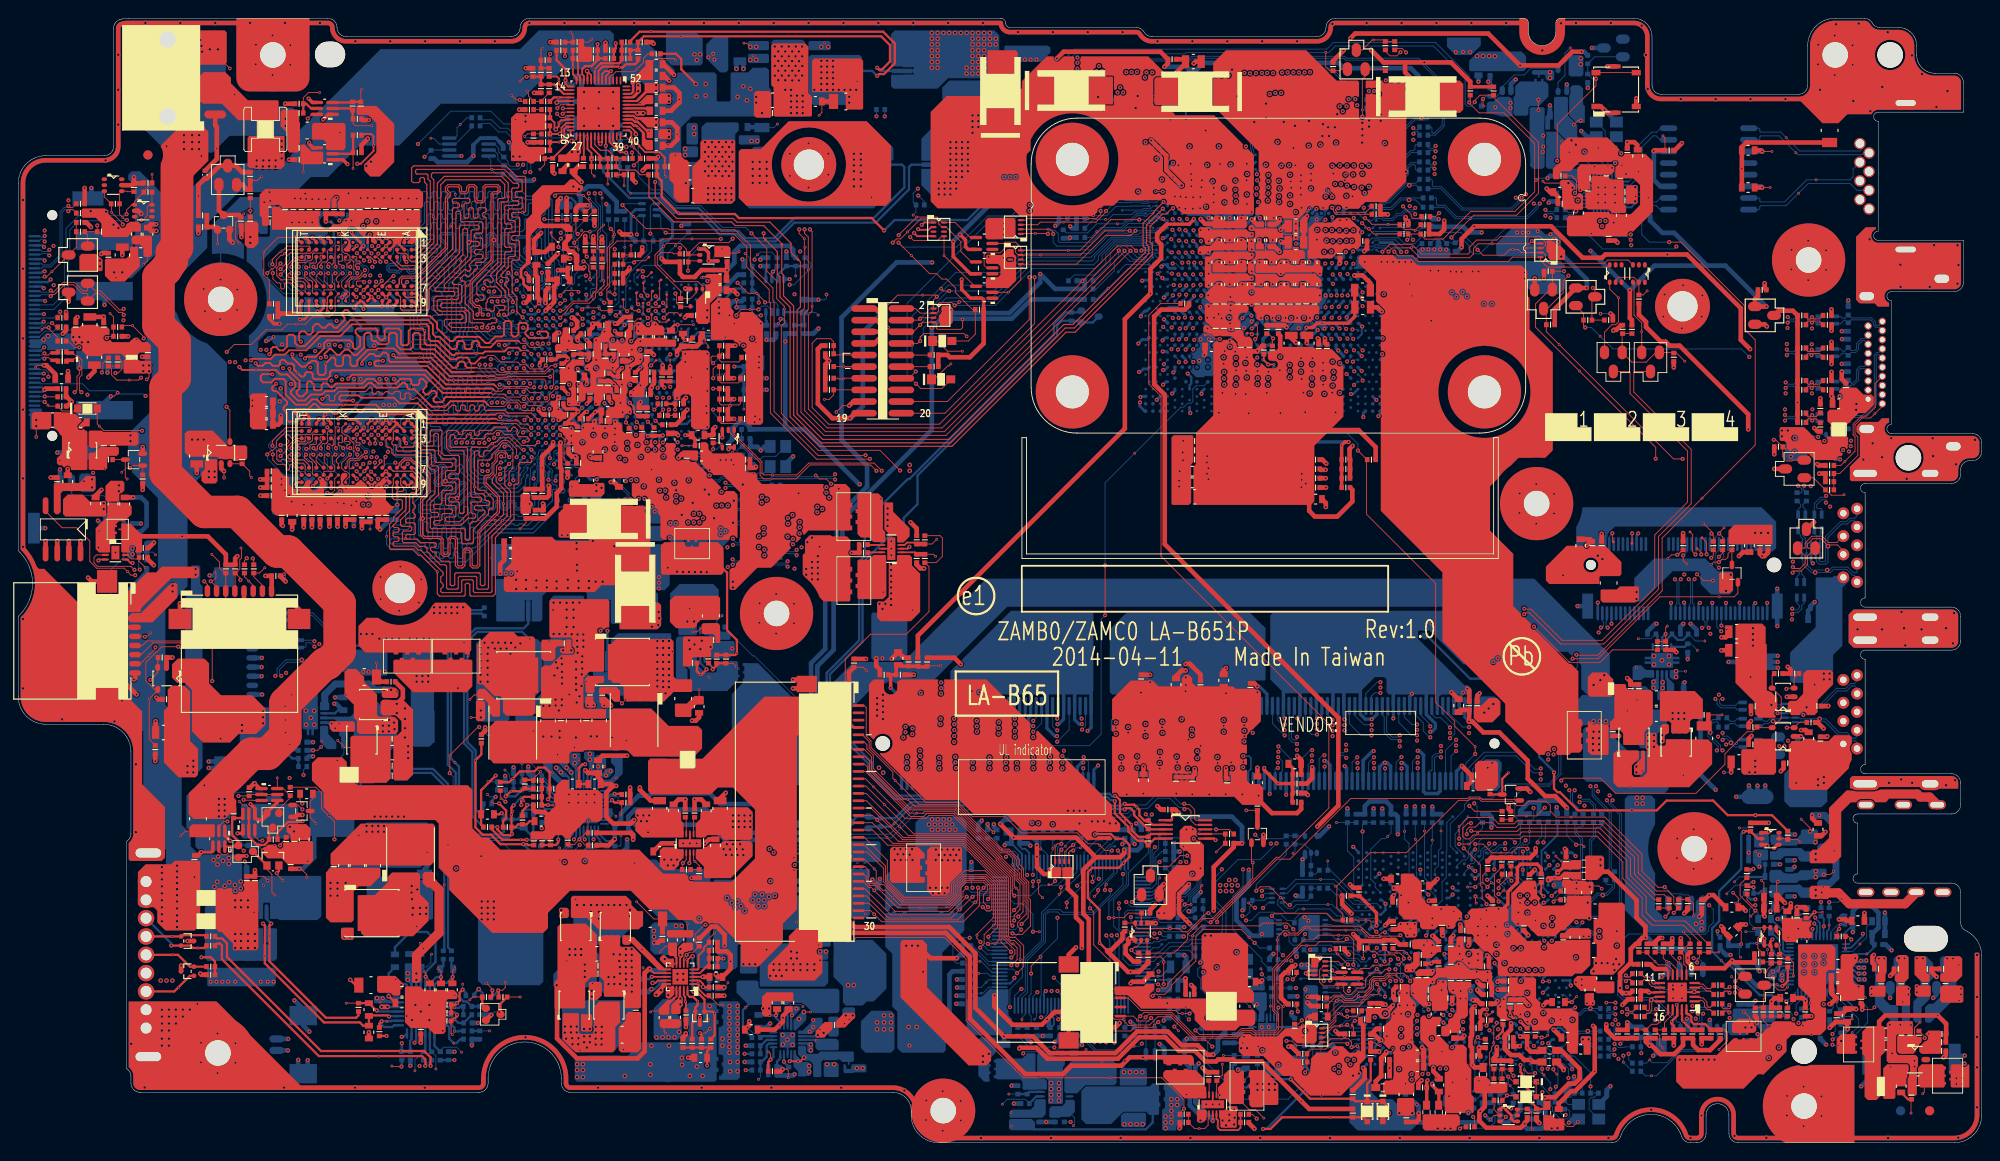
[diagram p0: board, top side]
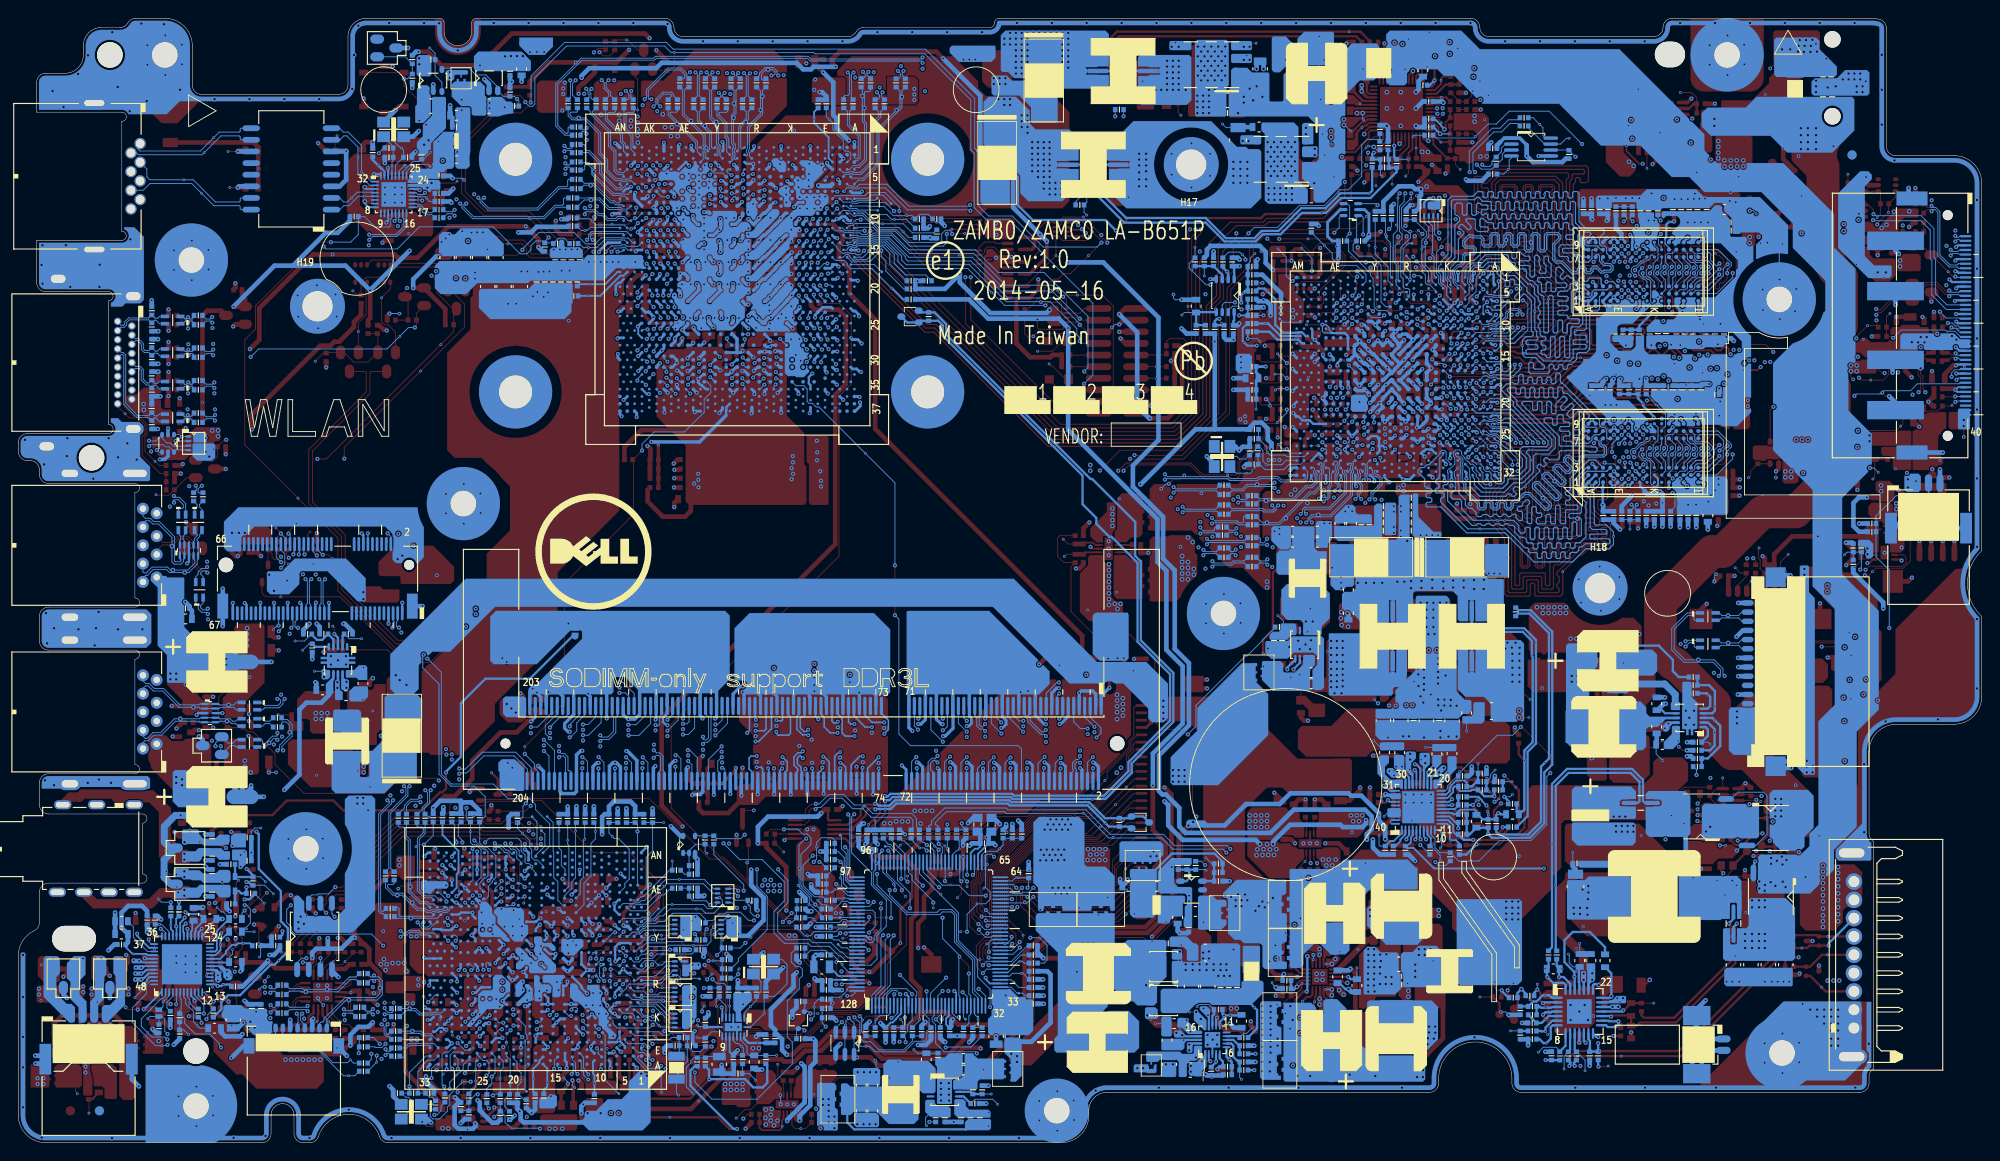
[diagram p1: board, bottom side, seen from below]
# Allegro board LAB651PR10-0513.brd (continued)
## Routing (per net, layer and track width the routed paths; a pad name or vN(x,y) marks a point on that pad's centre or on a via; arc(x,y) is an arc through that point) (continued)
PEG_GTX_C_HRX_N5: length 77.2
  IN1 w0.114: v3(88.25,71) 88.25,71.02 88.47,71.25 89.02,71.25 89.82,72.06 89.82,81.82 95.59,87.58 95.59,88.68 106.38,99.47 106.38,100.66 108.59,102.87 116.44,102.87 117.56,103.99 119.39,103.99 121.34,105.95 122.13,105.95 124.34,108.16 133.89,108.16 134.73,107.32 134.73,106 134.52,105.79 v3(134.18,105.79)
  BOTTOM w0.102: v3(134.18,105.79) 134.41,105.79 UC1.R5 ; CV30.1 83.59,71.19 88.05,71.19 v3(88.25,71)
PEG_GTX_C_HRX_N6: length 83
  IN1 w0.114: v3(134.15,103.56) 134.47,103.56 134.63,103.71 134.63,104.02 134.22,104.42 133.81,104.42 133.41,104.83 133.41,106.51 132.42,107.5 125.63,107.5 123.42,105.29 121.67,105.29 119.74,103.36 117.89,103.36 115.91,101.38 112.43,101.38 111.89,100.84 107.47,100.84 107.02,100.39 107.02,99.22 101.1,93.3 101.1,92.31 100.29,91.5 99.29,91.5 96.22,88.42 96.22,87.32 92.03,83.13 92.03,78.74 90.53,77.25 90.53,69.03 85.87,64.37 85.2,64.37 v3(84.99,64.16)
  BOTTOM w0.102: UC1.R8 134.7,103.18 134.32,103.56 v3(134.15,103.56) ; CV14.1 83.59,64.34 84.82,64.34 v3(84.99,64.16)
PEG_GTX_C_HRX_N7: length 80.9
  IN1 w0.114: v3(84,63.5) 84.18,63.33 85.58,63.33 90.96,68.71 90.96,76.71 92.68,78.43 92.68,83.18 95.74,86.24 96.02,86.24 99.24,89.46 99.24,89.8 103.78,94.34 104.37,94.34 109.38,99.34 111.03,99.34 112.5,100.82 115.97,100.82 118.08,102.93 119.91,102.93 121.64,104.65 125.4,104.65 127.2,106.46 128.56,106.46 128.97,106.05 130.77,106.05 132.29,104.53 132.29,103.97 132.44,103.81 132.65,103.81 v3(132.91,104.07)
  BOTTOM w0.102: UC1.P7 133.31,104.09 132.93,104.09 v3(132.91,104.07) ; CV32.1 80.54,63.54 81.74,63.54 81.97,63.3 83.8,63.3 v3(84,63.5)
PEG_GTX_C_HRX_P0: length 96.7
  IN1 w0.114: v3(81.21,70.54) 81.21,70.49 81.01,70.29 80.84,70.29 80.64,70.48 80.64,70.81 82.18,72.34 84.46,72.34 85.25,73.13 85.25,84.53 107.12,106.4 107.12,106.63 112.97,112.48 118.17,112.48 118.85,111.79 137.01,111.79 140.52,108.28 140.52,103.36 140.06,102.9 139.05,102.9 138.88,103.07 v3(138.88,103.46)
  BOTTOM w0.102: v3(81.21,70.54) 81.21,70.51 80.94,70.25 80.28,70.25 80.14,70.39 CV1.1 ; UC1.Y8 138.47,102.93 138.74,102.93 138.97,103.15 138.97,103.37 v3(138.88,103.46)
PEG_GTX_C_HRX_P1: length 95.2
  IN1 w0.114: v3(138.78,106.76) 138.51,106.76 138.33,106.58 138.33,106.33 138.51,106.15 139.47,106.15 139.88,106.57 139.88,108.01 136.73,111.15 118.55,111.15 117.86,111.84 113.27,111.84 107.85,106.42 107.85,106.25 92.21,90.61 92.21,90.47 86.47,84.73 86.47,74.76 85.88,74.17 85.88,72.85 83.34,70.31 83.34,68.08 83.5,67.92 83.78,67.92 84.05,68.2 v3(84.05,68.23)
  BOTTOM w0.102: v3(84.05,68.23) 83.74,67.91 81.3,67.91 81.09,67.71 80.71,67.71 80.61,67.81 80.61,68.32 80.47,68.46 80.22,68.46 CV3.1 ; UC1.Y4 138.3,106.19 138.39,106.1 138.63,106.1 138.72,106.18 138.72,106.7 v3(138.78,106.76)
PEG_GTX_C_HRX_P2: length 92.2
  IN1 w0.114: v3(85.32,67.21) 85.32,67.11 85.1,66.88 84.92,66.88 84.79,67.01 84.79,67.86 85.2,68.27 85.2,71.07 86.52,72.39 86.52,73.92 87.33,74.73 87.33,83.32 92.97,88.96 92.97,90.31 107.46,104.8 109.17,104.8 110.62,106.26 110.62,108.28 113.55,111.21 117.58,111.21 118.27,110.52 134.98,110.52 137.32,108.18 137.32,106.46 138.26,105.52 138.26,103.98 138.06,103.79 137.67,103.79 137.57,103.89 137.57,104.06 v3(137.73,104.22)
  BOTTOM w0.102: v3(85.32,67.21) 85.32,67.11 85.03,66.82 83.9,66.82 83.78,66.95 83.78,67.11 83.65,67.24 CV5.1 ; v3(137.73,104.22) 137.73,103.9 137.6,103.76 137.24,103.76 UC1.W7
PEG_GTX_C_HRX_P3: length 92.3
  IN1 w0.114: v3(136.52,105.01) 136.72,105.21 136.91,105.21 137.14,105.44 137.14,106 136.89,106.25 136.89,107.98 134.78,110.09 118.1,110.09 117.41,110.77 113.72,110.77 111.05,108.11 111.05,106.02 109.42,104.39 107.83,104.39 104.65,101.21 104.65,99.86 94.82,90.02 93.88,90.02 93.4,89.55 93.4,88.35 87.86,82.82 87.86,73.75 86.95,72.83 86.95,72.05 85.86,70.95 85.86,66.29 85.35,65.79 84.75,65.79 v3(84.6,65.94)
  BOTTOM w0.102: CV7.1 80.47,65.76 84.42,65.76 v3(84.6,65.94) ; UC1.U5 136.02,105.5 v3(136.52,105.01)
PEG_GTX_C_HRX_P4: length 84.9
  IN1 w0.114: v3(136.49,103.69) 136.34,103.53 136.08,103.53 135.97,103.64 135.97,106.32 135.82,106.47 135.82,108.17 134.53,109.45 124.41,109.45 121.79,106.84 120.93,106.84 118.92,104.83 117.17,104.83 116.05,103.71 108.25,103.71 105.52,100.98 105.52,99.83 94.7,89.01 94.7,87.87 88.53,81.7 88.53,73.05 87.61,72.14 87.61,71.35 86.57,70.31 86.57,69.27 86.8,69.04 87.07,69.04 v3(87.26,68.86)
  BOTTOM w0.102: v3(136.49,103.69) 136.11,103.69 UC1.U7 ; CV13.1 83.52,68.97 87.15,68.97 v3(87.26,68.86)
PEG_GTX_C_HRX_P5: length 77.2
  IN1 w0.114: v3(88.25,71.61) 88.4,71.45 88.93,71.45 89.62,72.14 89.62,81.9 95.38,87.67 95.38,88.76 106.18,99.56 106.18,100.75 108.51,103.08 116.36,103.08 117.47,104.2 119.3,104.2 121.26,106.15 122.04,106.15 124.25,108.36 133.97,108.36 134.93,107.4 134.93,106 135.16,105.77 v3(135.25,105.77)
  BOTTOM w0.102: CV35.1 83.59,71.41 88.05,71.41 v3(88.25,71.61) ; v3(135.25,105.77) 135.25,106.15 UC1.T4
PEG_GTX_C_HRX_P6: length 83
  IN1 w0.114: v3(84.99,64.75) 85.17,64.57 85.78,64.57 90.33,69.12 90.33,77.33 91.83,78.83 91.83,83.21 96.02,87.41 96.02,88.51 99.21,91.7 100.2,91.7 100.89,92.39 100.89,93.38 106.81,99.3 106.81,100.47 107.39,101.05 111.81,101.05 112.34,101.58 115.82,101.58 117.8,103.56 119.66,103.56 121.59,105.49 123.34,105.49 125.55,107.7 132.5,107.7 133.61,106.59 133.61,104.91 133.9,104.63 134.3,104.63 134.83,104.1 134.83,103.84 135.11,103.56 v3(135.19,103.56)
  BOTTOM w0.102: UC1.R7 135.04,103.56 v3(135.19,103.56) ; CV12.1 83.59,64.55 84.8,64.55 v3(84.99,64.75)
PEG_GTX_C_HRX_P7: length 80.9
  IN1 w0.114: v3(132.93,103.43) 132.76,103.61 132.36,103.61 132.09,103.88 132.09,104.45 130.69,105.85 128.89,105.85 128.48,106.25 127.29,106.25 125.48,104.45 121.72,104.45 120,102.72 118.17,102.72 116.06,100.61 112.59,100.61 111.11,99.14 109.46,99.14 104.46,94.14 103.87,94.14 99.45,89.72 99.45,89.38 96.1,86.03 95.82,86.03 92.88,83.09 92.88,78.34 91.17,76.63 91.17,68.63 85.66,63.12 84.21,63.12 v3(84,62.92)
  BOTTOM w0.102: UC1.P8 133.27,103.1 v3(132.93,103.43) ; CV31.1 80.54,63.32 81.65,63.32 81.88,63.09 83.84,63.09 v3(84,62.92)
PEG_GTX_HRX_N0: length 9.3
  BOTTOM w0.102: UV1.AG31 72.51,73.41 72.65,73.41 72.75,73.31 72.75,73.21 72.57,73.03 72.57,72.09 73.13,71.53 73.72,71.53 75.13,70.11 v2(78.14,70.11) 78.89,70.11 CV2.2
PEG_GTX_HRX_N1: length 12
  BOTTOM w0.102: UV1.AF28 71.8,74.3 71.8,73.95 71.94,73.81 71.94,73.56 71.86,73.48 71.86,73.1 72.07,72.89 72.07,71.63 72.83,70.87 73.31,70.87 v2(75.98,68.2) 76.69,67.49 77.74,67.49 77.76,67.48 78.31,67.48 78.33,67.49 CV4.2
PEG_GTX_HRX_N2: length 18.5
  IN1 w0.114: v3(72,76.5) 72,76.42 71.86,76.28 71.52,76.28 71.15,75.91 71.15,74.77 71.93,73.99 72.14,73.99 73.63,72.51 73.63,71.71 74.81,70.53 74.81,70.1 78.26,66.65 81.26,66.65 v3(81.39,66.53)
  BOTTOM w0.102: UV1.AF26 v3(72,76.5) ; CV6.2 82.14,66.67 81.53,66.67 v3(81.39,66.53)
PEG_GTX_HRX_N3: length 17.2
  IN1 w0.114: v3(70.39,76.48) 69.96,76.05 69.96,75.53 69.81,75.38 69.81,74.52 74.15,70.18 74.15,69.77 75.67,68.25 75.67,66.59 76.78,65.49 77.83,65.49 v3(78.03,65.28)
  BOTTOM w0.102: v3(70.39,76.48) 70.38,76.48 UV1.AD26 ; v3(78.03,65.28) 79.15,65.28 CV8.2
PEG_GTX_HRX_N4: length 21.5
  IN1 w0.114: v3(77.48,69.6) 77.25,69.83 77.25,70.01 74.86,72.4 74.86,74.58 73.84,75.59 73.84,77.13 73.04,77.93 70.18,77.93 68.76,76.51 v3(68.61,76.51)
  BOTTOM w0.102: v3(68.61,76.51) 68.59,76.51 UV1.AB25 ; CV16.2 81.88,69.25 78.47,69.25 78.33,69.11 77.36,69.11 77.26,69.21 77.26,69.38 v3(77.48,69.6)
PEG_GTX_HRX_N5: length 21.3
  IN1 w0.114: v3(67.44,77.32) 67.77,77.65 68.59,77.65 69.14,78.21 69.85,78.21 70.03,78.39 73.56,78.39 74.4,77.55 74.4,75.79 76.16,74.04 76.16,72.08 76.53,71.71 77.02,71.71 v3(77.22,71.51)
  BOTTOM w0.102: v3(77.22,71.51) 77.39,71.67 78.84,71.67 78.85,71.66 79.38,71.66 79.39,71.67 80.17,71.67 80.65,71.19 81.88,71.19 CV30.2 ; UV1.Y24 67.06,77.7 v3(67.44,77.32)
PEG_GTX_HRX_N6: length 22.8
  IN1 w0.114: v3(81.46,64.14) 81.26,64.34 75.64,64.34 72.47,67.51 72.47,68.49 71.16,69.8 71.16,71.32 70.64,71.85 70.64,72.41 68.42,74.63 68.42,75.05 67.87,75.59 67.87,75.94 v3(67.61,76.2)
  BOTTOM w0.102: CV14.2 82.28,64.04 81.97,64.34 81.67,64.34 v3(81.46,64.14) ; v3(67.61,76.2) 68.1,76.2 UV1.AB26
PEG_GTX_HRX_N7: length 22
  IN1 w0.114: v3(66.48,76.43) 66.68,76.23 66.94,76.23 67.19,75.98 67.19,74.91 69.27,72.82 69.27,70.43 70.59,69.11 70.59,67.67 74.53,63.73 77.12,63.73 77.35,63.5 77.81,63.5 v3(78.01,63.71)
  BOTTOM w0.102: v3(78.01,63.71) 78.18,63.54 78.83,63.54 CV32.2 ; UV1.Y26 66.67,76.43 v3(66.48,76.43)
PEG_GTX_HRX_P0: length 9.3
  BOTTOM w0.102: UV1.AH30 73.16,73.74 72.96,73.74 72.84,73.62 72.84,73.53 72.97,73.4 72.97,73.12 72.79,72.94 72.79,72.18 73.22,71.75 73.81,71.75 75.22,70.33 77.86,70.33 77.87,70.34 78.4,70.34 78.41,70.33 78.89,70.33 CV1.2
PEG_GTX_HRX_P1: length 12
  BOTTOM w0.102: UV1.AG29 72.25,74.25 72.12,74.25 72.02,74.15 72.02,74.02 72.14,73.89 72.14,73.47 72.07,73.4 72.07,73.18 72.29,72.96 72.29,71.72 72.92,71.08 73.4,71.08 75.94,68.55 75.96,68.55 76.33,68.17 76.33,68.15 76.78,67.71 v2(78.05,67.71) 78.56,67.71 CV3.2
PEG_GTX_HRX_P2: length 18.5
  IN1 w0.114: v3(81.39,67.11) 81.13,66.86 78.34,66.86 75.01,70.18 75.01,70.62 73.83,71.79 73.83,72.59 72.23,74.2 72.02,74.2 71.35,74.86 71.35,75.82 71.61,76.08 71.91,76.08 72,75.99 v3(72,75.7)
  BOTTOM w0.102: CV5.2 82.11,66.88 81.59,66.88 81.39,67.09 v3(81.39,67.11) ; v3(72,75.7) 71.93,75.77 71.66,75.77 71.53,75.65 71.53,75.37 UV1.AF27
PEG_GTX_HRX_P3: length 17.2
  IN1 w0.114: v3(70.38,75.75) 70.29,75.75 70.16,75.62 70.16,75.44 70.01,75.29 70.01,74.6 74.35,70.27 74.35,69.85 75.88,68.33 75.88,66.68 76.87,65.69 77.81,65.69 78.03,65.92 v3(78.03,65.97)
  BOTTOM w0.102: CV7.2 78.87,66.1 78.77,65.99 78.77,65.59 78.7,65.51 78.39,65.51 78.03,65.87 v3(78.03,65.97) ; v3(70.38,75.75) 70.33,75.8 70.14,75.8 69.93,75.59 69.93,75.37 UV1.AD27
PEG_GTX_HRX_P4: length 21.6
  IN1 w0.114: v3(76.82,69.6) 76.89,69.6 77.04,69.75 77.04,69.92 74.65,72.31 74.65,74.5 73.64,75.51 73.64,77.04 72.95,77.73 70.26,77.73 69.32,76.79 69.32,76.64 69.45,76.51 v3(69.55,76.51)
  BOTTOM w0.102: v3(76.82,69.6) 76.89,69.6 77.04,69.45 77.04,69.12 77.27,68.89 78.42,68.89 78.56,69.04 81.88,69.04 CV13.2 ; v3(69.55,76.51) 69.48,76.43 69.2,76.43 69.07,76.56 69.07,76.77 UV1.AC25
PEG_GTX_HRX_P5: length 21.3
  IN1 w0.114: v3(67.42,78.11) 67.67,77.86 68.5,77.86 69.06,78.41 69.77,78.41 69.95,78.59 73.65,78.59 74.61,77.63 74.61,75.87 76.36,74.12 76.36,72.17 76.61,71.91 77.04,71.91 v3(77.22,72.09)
  BOTTOM w0.102: UV1.Y23 67.03,78.5 v3(67.42,78.11) ; CV35.2 81.87,71.4 80.74,71.4 80.26,71.89 v2(79.11,71.89) 77.43,71.89 v3(77.22,72.09)
PEG_GTX_HRX_P6: length 22.8
  IN1 w0.114: v3(68.74,75.69) 68.43,76 68.21,76 68.08,75.87 68.08,75.68 68.62,75.13 68.62,74.72 70.84,72.5 70.84,71.94 71.37,71.41 71.37,69.89 72.68,68.58 72.68,67.59 75.72,64.55 81.24,64.55 v3(81.46,64.77)
  BOTTOM w0.102: v3(81.46,64.77) 81.67,64.57 82.02,64.57 82.28,64.83 CV12.2 ; UV1.AB27 68.4,75.34 v3(68.74,75.69)
PEG_GTX_HRX_P7: length 21.9
  IN1 w0.114: v3(78.01,63.12) 77.83,63.3 77.26,63.3 77.04,63.53 74.45,63.53 70.39,67.59 70.39,69.03 69.07,70.34 69.07,72.74 66.99,74.82 66.99,75.9 66.86,76.03 66.68,76.03 66.5,75.85 v3(66.5,75.77)
  BOTTOM w0.102: v3(66.5,75.77) 66.8,75.48 UV1.Y27 ; v3(78.01,63.12) 78.21,63.32 78.83,63.32 CV31.2
PEG_HTX_C_GRX_N0: length 105.4
  IN3 w0.135: v3(71.85,70.03) 71.68,70.21 71.49,70.21 71.39,70.11 71.39,69.49 72.47,68.41 72.47,67.75 72.93,67.29 74.61,67.29 76.04,68.73 78.3,68.73 81.74,72.17 84.7,72.17 88.61,76.08 96.71,76.08 123.02,102.38 123.02,104.58 125.39,106.95 125.39,107.37 128.76,110.74 138.56,110.74 141.87,114.04 144.51,114.04 144.8,113.75 144.8,113.41 v3(145.04,113.18)
  BOTTOM w0.102: UV1.AE31 71.01,73.09 71.01,71.76 71.18,71.59 71.18,70.49 71.45,70.22 71.66,70.22 v3(71.85,70.03) ; v3(145.04,113.18) 144.77,113.44 144.77,113.99 144.02,114.74 143.08,114.74 142.82,114.48 142.82,114.32 C164.2
PEG_HTX_C_GRX_N1: length 113.7
  IN3 w0.135: v3(146,113.97) 145.77,113.73 145.77,112.7 144.6,111.54 140.72,111.54 138.94,109.76 129.93,109.76 127.44,107.27 127.44,106.57 125.2,104.33 124.77,104.33 124.25,103.81 124.25,100.7 122.21,98.66 120.68,98.66 95.97,73.94 88.41,73.94 85.65,71.19 84.09,71.19 80.48,67.58 76.26,67.58 74.95,66.27 71.54,66.27 70.03,67.78 70.03,71.18 v3(70.06,71.21)
  BOTTOM w0.102: C151.2 141.4,116.45 141.4,116.73 142.03,117.37 143.45,117.37 145.81,115 145.81,114.15 v3(146,113.97) ; v3(70.06,71.21) 70.06,71.89 70.39,72.22 70.39,72.95 70.26,73.08 70.26,73.52 70.38,73.63 70.38,73.78 70.12,74.04 70.12,74.38 UV1.AD28
PEG_HTX_C_GRX_N2: length 102.8
  IN3 w0.135: v3(139.84,116.9) 140.04,116.7 140.04,113.52 137.94,111.42 127.3,111.42 123.32,107.45 123.32,106.15 121.06,103.89 121.06,101.4 96.43,76.76 88.28,76.76 84.37,72.85 81.39,72.85 78.85,70.31 74.92,70.31 73.96,69.35 73.96,68.86 v3(73.77,68.68)
  BOTTOM w0.102: v3(139.84,116.9) 140.03,116.71 140.03,114.32 C152.2 ; UV1.AC31 69.42,73.41 69.55,73.41 69.6,73.36 69.6,73.23 69.35,72.98 69.35,70.96 71.12,69.19 73.82,69.19 73.96,69.05 73.96,68.86 v3(73.77,68.68)
PEG_HTX_C_GRX_N3: length 103.5
  IN3 w0.135: v3(73.15,67.74) 73.34,67.92 73.34,68.09 72.91,68.51 72.91,70.34 74.71,72.13 76.11,72.13 81.44,77.46 96.07,77.46 120.12,101.52 120.12,103.94 122.62,106.44 122.62,107.73 127.02,112.12 137.53,112.12 138.78,113.36 138.78,116.73 v3(138.6,116.9)
  BOTTOM w0.102: UV1.AB28 68.62,74.39 68.64,74.32 68.64,74.21 68.64,74.2 68.64,73.94 68.71,73.87 68.71,73.56 68.61,73.46 68.61,73.14 68.71,73.04 68.71,70.69 71.05,68.36 72.17,68.36 72.18,68.34 72.71,68.34 72.73,68.36 73.08,68.36 73.34,68.1 73.34,67.92 v3(73.15,67.74) ; v3(138.6,116.9) 138.78,116.72 138.78,116.63 C156.2
PEG_HTX_C_GRX_N4: length 96.8
  IN3 w0.135: v3(137.27,114.66) 137.42,114.5 137.42,113.61 136.69,112.87 125.68,112.87 121.94,109.13 121.94,106.75 119.41,104.22 119.41,101.78 95.87,78.24 79.05,78.24 75.32,74.5 74.3,74.5 72.59,72.79 71.13,72.79 70.3,71.96 69.83,71.96 69.03,71.17 68.24,71.17 67.93,70.86 67.93,70.48 v3(67.76,70.31)
  BOTTOM w0.102: C165.2 137.17,113.92 137.47,114.23 137.47,114.46 v3(137.27,114.66) ; UV1.AA31 67.6,73.37 67.73,73.5 67.87,73.5 67.94,73.43 67.94,73.2 67.82,73.08 67.82,72.67 67.89,72.61 67.89,72.13 67.63,71.87 67.63,71.19 67.97,70.85 67.97,70.52 v3(67.76,70.31)
PEG_HTX_C_GRX_N5: length 95.4
  IN3 w0.135: v3(135.79,116.84) 135.93,116.71 135.93,116.18 133.33,113.58 125.12,113.58 120.94,109.4 120.94,106.74 115.3,101.1 112.96,101.1 109.61,97.74 109.61,93.76 97.16,81.31 83.88,81.31 83.57,81 80.79,81 78.32,78.54 77.78,78.54 76.97,77.73 75.95,77.73 71.74,73.51 67.53,73.51 66.99,72.97 66.99,72.43 v3(66.91,72.35)
  BOTTOM w0.102: v3(66.91,72.35) 67.13,72.57 67.13,73.02 67.05,73.09 67.05,73.51 67.11,73.57 67.11,74.2 66.81,74.5 UV1.Y28 ; C160.2 135.62,116.21 135.96,116.55 135.96,116.68 v3(135.79,116.84)
PEG_HTX_C_GRX_N6: length 103.6
  IN3 w0.135: v3(134.5,116.79) 134.7,116.59 134.7,115.94 133.05,114.29 124.54,114.29 120.23,109.99 120.23,107.02 115.03,101.82 112.71,101.82 108.92,98.04 108.92,94.8 100.11,85.98 98.74,85.98 94.85,82.1 83.19,82.1 82.84,81.74 79.42,81.74 76.89,79.22 74.15,79.22 73.26,78.33 71.96,78.33 71.14,77.5 71.14,75.01 70.35,74.22 67.09,74.22 65.62,72.76 65.62,71.96 66.45,71.13 66.45,70.41 66.3,70.26 v3(66.22,70.26)
  BOTTOM w0.102: v3(66.22,70.26) 66.33,70.26 66.48,70.41 66.48,70.86 65.49,71.84 65.49,72.53 65.93,72.97 66.11,72.97 66.33,73.18 66.33,73.37 66.21,73.41 66.11,73.41 UV1.W31 ; C159.2 134.7,114.32 134.7,116.6 v3(134.5,116.79)
PEG_HTX_C_GRX_N7: length 95.6
  IN3 w0.135: v3(65.67,74.79) 65.83,74.63 65.83,74.39 65.59,74.15 65.32,74.15 65.18,74.29 65.18,74.96 66.01,75.79 66.01,76.75 66.2,76.94 66.58,76.94 66.87,76.65 67.73,76.65 68.13,77.04 68.13,77.4 68.59,77.86 69.9,77.86 71.15,79.11 73.08,79.11 75.26,81.28 76.36,81.28 77.81,82.73 94.75,82.73 98.52,86.5 99.98,86.5 108.44,94.96 108.44,98.2 112.5,102.26 114.8,102.26 119.44,106.9 119.44,109.94 124.92,115.42 131.41,115.42 131.67,115.68 131.67,116.07 v3(132.16,116.56)
  BOTTOM w0.102: v3(132.16,116.56) 131.93,116.56 131.77,116.72 131.77,116.95 132.02,117.2 v2(132.53,117.2) 132.76,117.2 133.24,116.72 133.24,116.18 133.1,116.04 132.94,116.04 C158.2 ; UV1.V28 65.34,74.36 65.55,74.36 65.67,74.48 v3(65.67,74.79)
PEG_HTX_C_GRX_P0: length 105.4
  IN3 w0.135: v3(71.85,70.62) 71.69,70.45 71.39,70.45 71.15,70.21 71.15,69.38 72.23,68.31 72.23,67.65 72.83,67.05 74.71,67.05 76.14,68.48 78.41,68.48 81.84,71.92 84.8,71.92 88.71,75.83 96.82,75.83 123.26,102.28 123.26,104.48 125.63,106.85 125.63,107.27 128.86,110.49 138.66,110.49 141.97,113.8 144.41,113.8 144.56,113.64 144.56,113.44 v3(144.3,113.18)
  BOTTOM w0.102: v3(71.85,70.62) 71.66,70.43 71.53,70.43 71.38,70.58 71.38,71.69 71.23,71.85 71.23,73.61 71.31,73.7 UV1.AF30 ; v3(144.3,113.18) 144.56,113.44 144.56,113.9 143.94,114.52 143.17,114.52 143.04,114.39 143.04,114.32 C153.2
PEG_HTX_C_GRX_P1: length 113.7
  IN3 w0.135: v3(70.65,71.21) 70.65,71.18 70.28,70.81 70.28,67.88 71.64,66.52 74.85,66.52 76.16,67.82 80.38,67.82 83.99,71.43 85.55,71.43 88.31,74.19 95.87,74.19 120.58,98.9 122.1,98.9 124.01,100.8 124.01,103.91 124.67,104.58 125.1,104.58 127.19,106.67 127.19,107.37 129.83,110 138.84,110 140.62,111.78 144.5,111.78 145.52,112.81 145.52,113.87 145.43,113.97 v3(145.26,113.97)
  BOTTOM w0.102: v3(70.65,71.21) 70.65,71.25 70.28,71.62 70.28,71.8 70.61,72.13 70.61,73.04 70.48,73.17 70.48,73.43 70.59,73.54 70.59,73.87 70.32,74.14 70.32,74.28 70.47,74.43 70.62,74.43 70.8,74.24 UV1.AE29 ; C154.2 141.74,116.21 141.61,116.34 141.61,116.64 142.12,117.15 143.36,117.15 145.6,114.91 145.6,114.02 145.54,113.97 v3(145.26,113.97)
PEG_HTX_C_GRX_P2: length 102.8
  IN3 w0.135: v3(74.36,68.68) 74.2,68.84 74.2,69.24 75.02,70.07 78.95,70.07 81.49,72.61 84.47,72.61 88.38,76.52 96.53,76.52 96.74,76.73 121.31,101.29 121.31,103.79 123.57,106.05 123.57,107.35 127.4,111.18 138.04,111.18 140.28,113.42 140.28,116.72 v3(140.46,116.9)
  BOTTOM w0.102: v3(74.36,68.68) 74.17,68.86 74.17,69.14 73.91,69.41 71.21,69.41 69.55,71.07 69.55,72.89 69.81,73.15 69.81,73.51 UV1.AD30 ; C155.2 140.25,114.32 140.25,116.68 v3(140.46,116.9)
PEG_HTX_C_GRX_P3: length 103.5
  IN3 w0.135: v3(139.24,116.9) 139.02,116.69 139.02,113.26 137.63,111.88 127.12,111.88 122.87,107.62 122.87,106.34 120.37,103.84 120.37,101.42 96.17,77.22 81.54,77.22 76.21,71.89 74.81,71.89 73.16,70.24 73.16,68.61 73.58,68.19 73.58,67.92 v3(73.76,67.74)
  BOTTOM w0.102: UV1.AC29 68.98,74.21 68.92,74.21 68.85,74.19 68.85,74.16 68.84,74.15 68.84,74.03 68.92,73.95 68.92,73.46 68.83,73.37 68.83,73.23 68.92,73.14 68.92,70.78 71.12,68.57 v2(72.45,68.57) 73.17,68.57 73.55,68.19 73.55,67.91 73.73,67.74 v3(73.76,67.74) ; C157.2 138.99,116.59 138.99,116.66 v3(139.24,116.9)
PEG_HTX_C_GRX_P4: length 96.8
  IN3 w0.135: v3(68.38,70.31) 68.37,70.31 68.17,70.5 68.17,70.76 68.34,70.92 69.13,70.92 69.93,71.72 70.4,71.72 71.23,72.55 72.69,72.55 74.4,74.26 75.42,74.26 79.15,77.99 95.97,77.99 119.66,101.68 119.66,104.12 122.18,106.64 122.18,109.03 125.78,112.63 136.79,112.63 137.67,113.51 137.67,114.42 v3(137.9,114.66)
  BOTTOM w0.102: UV1.AB30 68.4,73.7 68.16,73.46 68.16,73.11 68.04,72.99 68.04,72.76 68.1,72.7 68.1,72.04 67.85,71.78 67.85,71.28 68.18,70.94 68.18,70.51 v3(68.38,70.31) ; v3(137.9,114.66) 137.67,114.43 137.67,114.23 137.98,113.92 C161.2
PEG_HTX_C_GRX_P5: length 95.4
  IN3 w0.135: v3(67.5,72.36) 67.5,72.37 67.23,72.63 67.23,72.87 67.63,73.27 71.84,73.27 76.05,77.48 77.07,77.48 77.88,78.3 78.43,78.3 80.89,80.76 83.67,80.76 83.98,81.07 97.26,81.07 109.85,93.65 109.85,97.64 113.06,100.85 115.4,100.85 121.18,106.63 121.18,109.3 125.22,113.34 133.43,113.34 136.18,116.08 136.18,116.64 v3(136.38,116.84)
  BOTTOM w0.102: v3(136.38,116.84) 136.18,116.64 136.18,116.51 136.48,116.21 C163.2 ; UV1.AA29 67.53,74.17 67.42,74.17 67.33,74.08 67.33,73.48 67.27,73.42 67.27,73.18 67.34,73.11 67.34,72.43 67.42,72.36 v3(67.5,72.36)
PEG_HTX_C_GRX_P6: length 103.6
  IN3 w0.135: v3(135.16,116.82) 134.95,116.61 134.95,115.84 133.15,114.05 124.64,114.05 120.48,109.88 120.48,106.92 115.13,101.58 112.81,101.58 109.17,97.94 109.17,94.7 100.21,85.74 98.84,85.74 94.95,81.85 83.29,81.85 82.94,81.5 79.52,81.5 76.99,78.97 74.25,78.97 73.36,78.08 72.07,78.08 71.38,77.4 71.38,74.91 70.45,73.98 67.19,73.98 65.87,72.66 65.87,72.06 66.7,71.23 66.7,70.42 v3(66.86,70.26)
  BOTTOM w0.102: UV1.Y30 66.69,73.7 66.59,73.59 66.54,73.46 66.54,73.09 66.2,72.75 66.02,72.75 65.71,72.44 65.71,71.93 66.69,70.95 66.69,70.43 v3(66.86,70.26) ; v3(135.16,116.82) 134.91,116.57 134.91,114.32 C166.2
PEG_HTX_C_GRX_P7: length 95.6
  IN3 w0.135: v3(66.26,74.55) 66.26,74.48 65.69,73.91 65.22,73.91 64.94,74.19 64.94,75.06 65.77,75.89 65.77,76.85 66.1,77.18 66.68,77.18 66.98,76.89 67.63,76.89 67.89,77.14 67.89,77.5 68.49,78.1 69.8,78.1 71.05,79.35 72.98,79.35 75.15,81.53 76.26,81.53 77.71,82.98 94.65,82.98 98.42,86.75 99.88,86.75 108.19,95.06 108.19,98.3 112.4,102.51 114.7,102.51 119.19,107 119.19,110.04 124.82,115.66 131.31,115.66 131.41,115.77 131.41,116.55 v3(131.42,116.56)
  BOTTOM w0.102: UV1.W29 66,74.29 v3(66.26,74.55) ; v3(131.42,116.56) 131.55,116.69 131.55,117.03 131.93,117.42 132.22,117.42 132.23,117.43 132.83,117.43 132.84,117.42 132.85,117.42 133.46,116.81 133.46,116.54 C162.2
PEG_HTX_GRX_N0: length 6.6
  BOTTOM w0.102: UC1.AB1 139.93,108.67 140.14,108.67 140.23,108.75 140.23,109.31 142.11,111.2 142.11,111.22 142.49,111.59 142.51,111.59 143.22,112.31 143.22,112.46 143.14,112.55 142.53,112.55 142.42,112.65 C164.1
PEG_HTX_GRX_N1: length 9.5
  BOTTOM w0.102: UC1.AA2 139.13,107.47 139.33,107.47 139.4,107.55 139.4,107.65 139.33,107.72 139.33,108.08 139.43,108.18 139.43,108.44 139.3,108.56 139.3,108.92 139.4,109.02 139.4,110.06 v2(140.93,111.59) 141.67,112.34 141.67,114.98 141.36,115.29 C151.1
PEG_HTX_GRX_N2: length 5.5
  BOTTOM w0.102: UC1.Y1 138.51,108.59 138.65,108.64 138.69,108.73 138.69,110.35 v2(139.41,111.06) 140.04,111.69 140.04,112.6 C152.1
PEG_HTX_GRX_N3: length 8.5
  BOTTOM w0.102: C156.1 138.69,114.96 138.69,111.99 v2(138.18,111.48) 137.94,111.24 137.94,109.14 137.77,108.96 137.77,108.47 137.86,108.37 137.86,108.22 137.77,108.12 137.77,107.77 UC1.W2
PEG_HTX_GRX_N4: length 5.7
  BOTTOM w0.102: C165.1 136.94,112.86 136.94,112.65 137.06,112.53 137.8,112.53 137.89,112.44 137.89,112.23 137,111.35 137,109.9 136.82,109.72 136.82,108.82 UC1.V1
PEG_HTX_GRX_N5: length 8.8
  BOTTOM w0.102: UC1.U2 136.11,107.39 136.25,107.44 136.26,107.47 136.26,107.59 136.15,107.7 136.15,108.11 136.21,108.17 136.21,108.45 136.1,108.56 136.1,109.03 136.29,109.22 136.29,111.68 136.28,111.7 v2(136.28,111.94) 136.28,112.17 136.04,112.41 136.04,113.18 136.02,113.19 136.02,113.79 136.04,113.8 136.04,114.93 135.67,115.29 C160.1
PEG_HTX_GRX_N6: length 5.3
  BOTTOM w0.102: UC1.T1 135.21,108.59 135.39,108.59 135.51,108.71 135.51,110.84 135.51,110.93 v2(134.97,111.47) 134.69,111.75 134.69,112.62 C159.1
PEG_HTX_GRX_N7: length 8.8
  BOTTOM w0.102: UC1.R2 134.56,107.76 134.56,108.12 134.66,108.22 134.66,108.39 134.56,108.49 134.56,110.89 133.14,112.31 133.14,112.47 133.11,112.5 133.11,113.07 133.14,113.09 v2(133.14,114.28) 133.14,114.93 C158.1
PEG_HTX_GRX_P0: length 6.6
  BOTTOM w0.102: UC1.AB2 140.24,108.24 140.24,108.46 140.43,108.65 140.43,109.21 v2(142.46,111.24) 143.44,112.22 C153.1
PEG_HTX_GRX_P1: length 9.6
  BOTTOM w0.102: C154.1 141.89,115.02 141.89,112.25 141.31,111.67 141.31,111.65 140.98,111.32 140.98,111.32 140.91,111.24 140.89,111.24 139.62,109.97 139.62,108.93 139.52,108.83 139.52,108.65 139.64,108.53 139.64,108.09 139.54,107.99 139.54,107.81 139.62,107.74 139.62,107.38 UC1.AB3
PEG_HTX_GRX_P2: length 5.5
  BOTTOM w0.102: C155.1 140.25,112.62 140.25,111.6 139.9,111.24 139.9,111.21 139.39,110.7 139.35,110.7 138.91,110.26 138.91,108.49 UC1.AA1
PEG_HTX_GRX_P3: length 8.5
  BOTTOM w0.102: UC1.Y2 138.2,107.8 138.08,107.8 137.98,107.9 137.98,108.03 138.08,108.13 138.08,108.46 137.98,108.56 137.98,108.87 138.16,109.05 138.16,111.13 138.24,111.21 138.26,111.21 138.57,111.52 138.57,111.55 138.91,111.88 138.91,114.93 139.27,115.29 C157.1
PEG_HTX_GRX_P4: length 5.7
  BOTTOM w0.102: C161.1 138.11,112.14 137.22,111.26 137.22,109.81 137.04,109.63 137.04,108.24 UC1.V2
PEG_HTX_GRX_P5: length 8.8
  BOTTOM w0.102: C163.1 136.25,114.96 v2(136.25,113.49) 136.25,112.5 136.51,112.24 136.51,109.13 136.32,108.94 136.32,108.65 136.43,108.54 136.43,108.08 136.37,108.02 136.37,107.79 136.48,107.67 136.48,107.42 136.44,107.34 136.49,107.21 UC1.V3
PEG_HTX_GRX_P6: length 5.3
  BOTTOM w0.102: UC1.U1 135.73,108.47 135.73,110.75 135.73,111.02 135.41,111.33 135.41,111.35 134.91,111.86 134.91,112.6 C166.1
PEG_HTX_GRX_P7: length 8.7
  BOTTOM w0.102: UC1.T2 135.1,107.87 135.03,107.8 134.88,107.8 134.78,107.9 134.78,108.03 134.88,108.13 134.88,108.48 134.78,108.58 134.78,110.98 133.36,112.4 v2(133.36,112.78) 133.36,113.97 133.37,113.98 133.37,114.58 133.36,114.59 133.36,114.89 133.76,115.29 C162.1
PHASE1: length 12.5
  IN1 w0.762: 59.62,41.84 57.93,43.53 57.04,43.53 52.76,47.81 52.76,48.84 v2(51.25,50.35)
  vias: v1(55.86,55.01) v2(50.45,54.06) v2(50.48,53.4) v2(50.48,52.63) v2(50.48,51.87) v2(50.48,51.11) v2(50.48,50.35) v2(50.91,54.6) v2(51.24,51.11) v2(51.31,54.07) v2(51.25,53.4) v2(51.25,52.63) v2(51.25,51.87) v2(51.78,54.61) v2(52.04,53.97) v2(52.42,54.61) v2(52.67,53.97) v2(53.17,54.6) v2(53.31,53.97) v2(53.74,53.41) v2(53.82,54.59) v2(54.27,54.09) v2(54.82,54.53) v2(59.87,40.95) v2(60.38,40.44)
PHASE2: length 10.6
  IN1 w0.762: 63.68,41.46 64.32,41.46 69.91,47.05 v2(69.91,49.08)
  vias: v1(71.43,53.65) v2(69.78,54.79) v2(69.78,54.03) v2(69.78,53.27) v2(69.78,52.51) v2(69.78,51.74) v2(69.78,51.11) v2(69.78,50.47) v2(69.78,49.84) v2(70.41,54.79) v2(70.41,54.03) v2(70.41,53.27) v2(70.41,52.51) v2(70.41,51.74) v2(70.41,51.06) v2(70.41,50.4) v2(70.41,49.76) v2(70.67,49.08) v2(71.05,54.79) v2(71.05,54.03) v2(71.05,53.27) v2(71.05,52.51) v2(71.05,51.74) v2(71.06,51.06) v2(71.05,50.39) v2(71.05,49.75) v3(63.3,41.08) v3(63.94,41.08)
PHASE_APU1: length 14.8
  TOP w0.102: v2(79.94,119.69) 79.55,120.08 v1(79.24,120.08)
  TOP w0.203: PC524.2 68.95,115.18 67.53,113.76 PU500.48
  IN1 w1.016: 78.92,119.82 73.06,119.82 69.6,116.36
  vias: v2(69.65,115.5) v2(69.65,114.86) v2(80.57,119.69)
PHASE_NB1: length 8.7
  TOP w0.102: v2(69.65,111.76) 69.28,111.76 PC507.2 69.26,111.13 v2(69.65,111.13)
  TOP w0.203: PC507.2 68.52,111.87 67.47,111.87 67.18,112.16 PU500.44
  IN1 w1.016: 73.46,111.66 73.13,111.99 70.49,111.99 70.48,111.98
  BOTTOM w0.102: v1(68.88,110.47) 69.54,111.13 v2(69.65,111.13)
  vias: v2(73.79,110.84) v2(73.8,110.15)
PLL_ANALOG_IN: length 1.6
  TOP w0.102: T221.1 68.08,95.31 v3(68.21,95.18)
  BOTTOM w0.102: UV1.AA1 67.6,94.57 v3(68.21,95.18)
PLL_ANALOG_OUT: length 9.5
  BOTTOM w0.102: RV83.1 v1(71.74,97.95) 70.92,97.13 70.92,96.58 70.16,95.81 68.26,95.81 67.24,94.8 67.24,94.04 67.57,93.7 UV1.AA3
PLT_RST#: length 163.5
  TOP w0.102: RM6.2 186.11,64.39 v3(185.71,63.99) ; v3(135.18,27.51) 135.62,27.94 136.68,27.94 v1(137.84,26.79) 138.66,25.96 v3(138.84,25.96)
  IN1 w0.102: v3(138.84,25.96) 138.84,30.92 145.34,37.42 146.11,37.42 147.52,38.83 154.26,38.83 156.02,40.59 157.77,40.59 158.36,41.19 158.51,41.19 159.92,42.6 159.92,43.87 161.57,45.51 161.57,46.5 171.43,56.36 171.43,59.67 172.37,60.61 177.58,60.61 177.74,60.45 183.34,60.45 185.3,62.41 185.3,63.58 v3(185.71,63.99) ; v3(118.12,18.32) 118.19,18.32 119.28,19.41 123.4,19.41 126.24,22.25 126.24,25.48 127.23,26.47 127.77,26.47 128.33,25.91 133.58,25.91 v3(135.18,27.51)
  IN3 w0.102: v3(185.71,63.99) 185.71,65.1 186.75,66.15 186.75,90.91 180.88,96.78 180.01,96.78 174.75,102.04 171.15,102.04 v3(170.29,102.9)
  BOTTOM w0.102: v3(135.18,27.51) 135.18,28.2 138.46,31.47 RH27.2 ; UE1.13 116.39,16.01 116.29,16.11 116.29,16.49 v3(118.12,18.32) ; UL1.19 170.4,102.96 170.34,102.9 v3(170.29,102.9) ; RH3.1 142.06,27.8 CH6.2 RH1.1 141.15,26.82 140.75,26.42 139.3,26.42 v3(138.84,25.96)
PLT_RST#_R: length 3.2
  TOP w0.102: RM6.1 186.11,66.15 v3(185.73,66.53) 185.73,66.62 v1(186.28,67.16)
  BOTTOM w0.102: v3(185.73,66.53) 185.23,66.02 JNGFF.44
PLT_RST_VGA#: length 4.9
  TOP w0.102: UV2.4 76.88,76.2 76.65,76.43 RV4.1 v3(75.88,75.75)
  BOTTOM w0.102: v1(76.82,76.27) 76.29,75.75 v3(75.88,75.75) 75.88,75.67 75.5,75.3 UV1.AL27
PM_SLP_S3#: length 42
  TOP w0.102: v3(122.51,13.81) 122.93,14.23 125.95,14.23 128.57,11.61 132.99,11.61 133.65,12.27 134.71,12.27 134.99,11.99 137.24,11.99 137.62,12.37 137.62,14.08 137.19,14.51 137.19,18.93 140.42,22.15 141.46,22.15 141.97,22.66 v1(144.18,22.66) 145.27,22.66 145.83,22.1 145.83,19.5 v3(145.78,19.46)
  BOTTOM w0.102: U2.T3 147.12,19.32 146.75,18.95 146.18,18.95 145.78,19.34 v3(145.78,19.46) ; RE31.1 CE15.1 122.31,12.12 122.31,13.61 v3(122.51,13.81)
PM_SLP_S3#_R: length 3.6
  BOTTOM w0.102: RE31.2 120.83,13.35 v1(120.74,13.45) 120.29,13.9 119.41,13.9 119.19,14.12 UE1.6
PM_SLP_S5#: length 45.1
  TOP w0.102: v3(145.07,22.25) 144.77,21.95 142.06,21.95 141.62,21.52 v1(140.68,21.52) 140.09,21.52 137.45,18.88 137.45,15.5 138,14.94 138,12.45 137.34,11.79 134.83,11.79 134.55,12.07 133.74,12.07 133.08,11.41 128.48,11.41 125.86,14.03 123.42,14.03 v3(123.09,13.69)
  BOTTOM w0.102: CE14.1 RE33.1 116.77,11.08 117.71,10.14 120.45,10.14 121.34,11.03 122.1,11.03 122.51,11.43 122.51,13.11 v3(123.09,13.69) ; U2.W2 146.52,21.72 146.11,22.13 145.2,22.13 v3(145.07,22.25)
PM_SLP_S5#_R: length 2.7
  BOTTOM w0.102: RE33.2 115.99,13.36 v1(115.99,13.47) UE1.14
POK: length 58.7
  TOP w0.102: PU100.7 72.67,20.2 v3(72.98,20.5) 73.29,20.81 73.72,20.81 PR115.2 73.89,21.9 73.89,22.76 74.94,23.8 v3(75.04,23.8)
  IN3 w0.135: v3(75.04,23.8) 75.47,23.8 77.23,22.04 100.2,22.04 101.4,20.84 101.4,19.99 107.88,13.52 109.02,13.52 110.04,12.5 110.04,10.06 v3(109.73,9.76)
  BOTTOM w0.102: v3(72.98,20.5) v1(72.98,19.99) ; v3(109.73,9.76) 109.91,9.94 113.29,9.94 114.23,10.88 114.23,12.88 114.61,13.26 114.61,13.64 114.39,13.86 UE1.18
PS_0: length 15.4
  TOP w0.102: v3(75.88,83.49) 75.88,84.51 76.13,84.76 RV9.1 CV29.1 76.56,83.19 76.76,82.99 78.62,82.99 78.85,83.21 RV8.2
  IN1 w0.107: v3(75.88,83.49) 73.34,83.49 71.91,82.07 70.47,82.07 v3(69.76,81.36)
  BOTTOM w0.102: v1(77.18,83.94) 76.38,83.94 75.94,83.49 v3(75.88,83.49) ; UV1.AC19 69.23,81.9 v3(69.76,81.36)
PS_1: length 13.3
  TOP w0.102: v3(75.88,82.35) CV28.1 RV12.1 76.56,80.78 76.76,80.57 78.67,80.57 78.85,80.75 RV11.2
  IN1 w0.107: v3(70.4,81.35) 70.89,81.84 72.01,81.84 72.73,82.56 75.67,82.56 v3(75.88,82.35)
  BOTTOM w0.102: UV1.AD19 70,81.75 v3(70.4,81.35) ; v1(77.12,82.19) 76.96,82.35 v3(75.88,82.35)
PS_2: length 14
  TOP w0.102: CV11.1 76.56,85.48 76.76,85.27 78.67,85.27 78.97,85.58 RV28.2 ; CV11.1 RV13.1 ; CV11.1 75.77,85.91 75.65,85.78 75.65,85.37 v3(75.88,85.15)
  IN1 w0.107: v3(71.18,82.55) 72.52,83.9 73.98,83.9 75.23,85.15 v3(75.88,85.15)
  BOTTOM w0.102: v1(76.89,86.16) 76.89,86.12 75.91,85.15 v3(75.88,85.15) ; UV1.AE17 70.8,82.94 v3(71.18,82.55)
PS_3: length 12.9
  TOP w0.102: v3(75.88,80.07) CV15.1 RV16.1 76.56,78.74 76.76,78.54 78.67,78.54 78.85,78.72 RV15.2
  IN1 w0.107: v3(71.07,81.36) 71.53,80.91 75.29,80.91 75.88,80.32 v3(75.88,80.07)
  BOTTOM w0.102: v3(75.88,80.07) 75.88,79.72 v1(76.93,78.67) ; v3(71.07,81.36) 70.8,81.1 UV1.AE20
PS_ID: length 186.1
  TOP w0.102: PR3.1 v3(25.33,101.78) PR4.2
  IN2 w0.127: v3(25.33,101.78) 23.27,101.78 12.48,90.99 12.48,90.05 11.03,88.6 11.03,72.59 11.51,72.11 11.51,59.93 12.3,59.14 12.3,55.3 28.86,38.74 28.86,36.71 30.87,34.7 33.97,34.7 36.18,32.49 41.96,32.49 45.73,28.72 56.6,28.72 59.2,31.32 67.71,31.32 71.66,35.27 75.04,35.27 77.25,37.48 87.03,37.48 99.91,24.6 106.17,24.6 112.26,18.51 113.35,18.51 115.22,16.64 v3(115.22,16.54)
  BOTTOM w0.102: UE1.16 115.19,16.51 v3(115.22,16.54) ; v3(25.33,101.78) 24.95,101.78 v1(24.62,101.45)
PSID: length 6.8
  TOP w0.508: PL2.2 21.67,107.44 v1(21.67,108.58) 21.67,110.96 21.5,111.13 PJPDC.1
PSID-1: length 4.1
  TOP w0.102: v1(21.76,98.16) PQ5.2
  TOP w0.508: PR6.1 PR9.2 21.47,100 PQ5.2
PSID-2: length 8.8
  TOP w0.102: PR8.2 23.74,100.52 23.74,98.63 v1(24.14,98.24)
  TOP w0.508: PQ6.2 21.9,101.82 PQ5.1 24.1,101.31 PR8.2
PSID-3: length 4.1
  TOP w0.102: v1(26.54,105.5) 26.12,105.08 PR11.2
  TOP w0.508: PR11.2 PR4.1 24.97,104.09 24.44,104.63 PQ6.3
PWR_PWM_LED#: length 2.4
  BOTTOM w0.102: UE1.90 118.79,31.86 119.29,32.36 T120.1
PWR_SRC_ON:
  vias: v1(9.43,73.6)
PX_EN: length 1.9
  TOP w0.102: T218.1 69.64,85.44 v3(69.1,84.9)
  BOTTOM w0.102: UV1.AB16 68.4,84.2 v3(69.1,84.9)
PXS_PWREN: length 230.6
  TOP w0.102: v3(162.44,2.82) 162.44,2.8 161.97,2.33 QH2.3 ; R438.1 126.85,3.28 v3(127.29,3.71) 127.29,4.68 124.87,7.09 v1(119.25,7.09) 109.73,7.09 103.5,13.33 103.5,19.41 103.49,19.41 103.49,20.07 101.15,22.41 91.5,22.41 91.09,22 90.46,22 87.97,24.49 87.97,28 87.28,28.69 87.28,33.23 85.68,34.83 85.68,35.54 v3(85.76,35.62) 86.17,36.03 86.17,44.06 v3(86.7,44.59) 87.25,45.14 89.46,45.14 90.3,45.98 90.3,52.79 93.05,55.53 96.97,55.53 99.45,58.01 99.45,62.89 R435.1 100.22,63.35 100.91,64.04 100.91,66.04 100.65,66.3 R436.1 ; RH99.1 157.62,1.73 v3(157.42,1.54)
  IN1 w0.114: v3(85.76,35.62) 84.49,36.89 76.74,36.89 75.1,35.24 69.76,35.24 68.79,34.27 64.58,34.27 62.83,32.52 v3(61.3,32.52) 59.02,32.52 58.67,32.16 52.54,32.16 48.25,36.45 48.25,38.48 46.88,39.85 31.46,39.85 v3(31.15,40.16)
  IN2 w0.127: v3(127.29,3.71) 127.29,2.85 128.78,1.35 133.61,1.35 134.4,2.14 147.45,2.14 147.86,1.73 153.37,1.73 153.78,2.14 156.81,2.14 157.39,1.56 157.39,1.56 v3(157.42,1.54)
  BOTTOM w0.102: RH78.2 161.75,3.43 161.25,2.93 161.25,2.21 160.97,1.93 160.92,1.93 160.56,1.58 157.45,1.58 157.4,1.54 v3(157.42,1.54) ; RH78.2 162.38,2.82 v3(162.44,2.82) ; RH78.2 RH76.2 ; PR1300.1 78.56,54.91 78.56,54.82 80.21,53.17 80.38,53.17 85.81,47.74 85.81,45.48 v3(86.7,44.59) ; PR1027.1 v3(61.3,32.52) ; PR1103.1 31.15,40.72 v3(31.15,40.16)
PXS_PWREN_EC: length 65.4
  TOP w0.102: v3(117.02,25.61) 117.43,25.2 117.43,21.61 119.49,19.55 119.49,13.71 119.72,13.48 120.53,13.48 121.2,12.81 121.77,12.81 121.82,12.86 123.54,12.86 124.44,13.76 125.82,13.76 128.38,11.21 129.67,11.21 v3(130.38,10.49) ; v3(158.87,2.82) 159.01,2.68 RH99.2
  IN2 w0.127: v3(158.87,2.82) 158.16,2.82 157.26,3.73 136.71,3.73 136.17,4.26 134.7,4.26 131.03,7.93 131.03,9.85 v3(130.38,10.49)
  BOTTOM w0.102: UE1.89 118.39,28.65 117.02,27.28 v3(117.02,25.61)
PXS_RST#: length 158.9
  TOP w0.102: v3(135.05,25.66) 134.88,25.66 v1(134.35,26.19) ; UV2.2 77.53,77.75 81.01,74.27 81.01,72.87 81.38,72.5 84.92,72.5 86.44,74.02 93.07,74.02 v3(93.71,73.38)
  IN1 w0.102: v3(135.05,25.66) 134.94,25.54 134.94,22.48 135.8,21.61 135.8,19.67 136.43,19.05 136.43,17.65 136.79,17.29 136.79,15.79 136.33,15.34 136.33,13.87 137.43,12.78 137.43,11.82 137.06,11.45 137.06,8.09 137.67,7.48 137.67,6.13 137.95,5.85 141.12,2.68 153.63,2.68 154.25,3.3 157.53,3.3 158.07,3.84 160.84,3.84 161.25,3.43 162.72,3.43 v3(163.02,3.74) ; v3(93.71,73.38) 93.69,73.37 93.69,66.95 93.03,66.29 93.03,42.54 95.99,39.58 123.88,39.58 124.82,38.65 126.54,38.65 128.02,37.16 132.62,37.16 134.67,35.12 134.67,33.44 135.13,32.97 136.63,32.97 136.79,32.82 v3(136.79,32.67)
  IN3 w0.102: v3(135.05,25.66) 134.65,26.06 134.65,28.91 136.84,31.09 136.84,32.26 136.79,32.31 v3(136.79,32.67)
  BOTTOM w0.102: RH74.2 163.23,3.95 v3(163.02,3.74)
REMOTE1+: length 37.2
  TOP w0.254: v3(120.83,37.01) 120.94,36.91 121.88,36.91 v1(122.14,36.64) 122.42,36.36 122.42,35.73 122.97,35.18 C2502.1 123.84,34.72 U2407.2
  BOTTOM w0.254: Q2407.1 91.58,35.63 Q2407.2 93.02,35.44 C2500.1 95.72,35.44 97.47,37.19 105.98,37.19 106.19,37.39 118.67,37.39 119.26,36.81 120.45,36.81 120.66,37.01 v3(120.83,37.01)
REMOTE1-: length 35.1
  TOP w0.254: v3(120.81,36.4) 120.94,36.53 121.45,36.53 121.85,36.13 121.85,35.77 123.35,34.27 C2502.2 123.42,34.22 U2407.3
  BOTTOM w0.254: Q2407.3 93.02,34.52 C2500.2 95.31,34.52 95.64,34.85 ; 95.64,34.85 97.62,36.83 106.13,36.83 106.33,37.04 118.52,37.04 119.11,36.45 120.76,36.45 v3(120.81,36.4) ; 95.64,34.85 v1(95.64,34.85)
REMOTE2+: length 102.7
  TOP w0.254: U2407.4 123.69,33.72 C2504.1 122.3,33.41 121.58,34.12 121.58,34.73 v1(121.56,34.75) 120.3,36.01 120.3,37.42 119.84,37.88 v3(119.77,37.88)
  BOTTOM w0.254: Q2408.1 117.32,89.57 Q2408.2 115.88,89.77 C2505.1 113.95,89.77 113.44,89.26 113.44,88.12 98.19,72.86 98.19,69.74 96.68,68.24 96.68,67.6 95.26,66.17 95.02,66.17 92.18,63.34 92.18,54.72 88.63,51.16 88.63,46.11 93.17,41.56 93.17,40.56 95.84,37.9 105.69,37.9 105.89,38.1 119.16,38.1 119.46,37.8 119.69,37.8 v3(119.77,37.88)
REMOTE2-: length 102.1
  TOP w0.254: v3(119.74,37.29) v1(119.74,36.36) 119.74,35.96 121.21,34.48 121.21,33.99 122.23,32.97 122.89,32.97 C2504.2 124.1,33.22 U2407.5
  BOTTOM w0.254: Q2408.3 115.88,90.68 C2505.2 114.36,90.68 113.09,89.41 113.09,88.26 97.31,72.48 97.12,72.48 92.43,67.79 92.43,64.09 91.83,63.48 91.83,54.87 88.27,51.31 88.27,45.96 92.82,41.41 92.82,40.42 95.69,37.55 105.84,37.55 106.04,37.75 118.93,37.75 119.27,37.41 119.62,37.41 v3(119.74,37.29)
RF_+1.05VSP: length 3.3
  BOTTOM w0.102: PR304.1 182.64,54.49 v1(183.36,53.78)
  BOTTOM w0.254: PR304.1 181.97,54.16 PU300.5
RF_+1.35VGPUP: length 3.5
  BOTTOM w0.254: PR1105.1 30.03,49.08 v1(29.86,48.91) 29.65,48.7 29.65,47.68 29.93,47.39 PU1100.5
RING2: length 11.8
  IN2 w1.016: 191.12,30.08 191.73,29.47 191.73,26.14 193.25,24.62 193.25,22.61 192.92,22.28 192.92,19.28
  vias: v1(189.71,31.77) v3(190.13,31.42) v3(190.13,30.15) v3(192.6,18.29) v3(192.61,17.71)
RING2_R: length 6.6
  TOP w1.016: 203.46,38.08 207.37,38.08 207.7,37.75 208.71,37.75 JHP.3
  vias: v1(198.3,31.87) v2(196.27,31.55) v2(196.27,30.92)
RTC_CLK: length 37.1
  TOP w0.102: v3(145.14,10.8) 145.04,10.9 143.44,10.9 142.75,10.22 141.23,10.22 RH132.1 RH120.2 140.72,7.88 v3(140.52,7.68)
  BOTTOM w0.102: U2.F1 145.61,11.27 v3(145.14,10.8) ; RE43.1 130,20.68 130,19.74 129.5,19.23 129.06,19.23 128.78,18.95 128.78,18.22 129.11,17.89 129.11,16.79 130.42,15.49 130.42,11.55 129.88,11 129.88,8.59 133.71,4.75 138.65,4.75 140.52,6.62 v3(140.52,7.68)
SATA_CALRN: length 2.4
  TOP w0.203: RH38.1 166.3,27.68 166.26,27.64 v1(166.26,27.49) 166.26,27.2 v3(166.55,26.92)
  BOTTOM w0.203: U2.AF27 166,27.39 166.48,26.92 v3(166.55,26.92)
SATA_CALRP: length 8.7
  BOTTOM w0.203: U2.AF28 166.54,27.83 166.54,29.33 166.33,29.53 166.33,31.86 168.08,33.61 RH37.1
SATA_PRX_DTX_N0: length 12.7
  TOP w0.102: CS31.2 176.26,17.61 176.03,17.84 175.73,17.84 v3(175.55,17.65)
  BOTTOM w0.102: CS31.2 175.88,17.83 175.72,17.83 v3(175.55,17.65) 175.55,17.68 175.39,17.84 175.16,17.84 174.91,17.58 v2(174.91,16.9) 174.91,16.26 175.32,15.85 178.71,15.85 181.03,13.53 181.03,13.29 181.15,13.17 181.35,13.17 181.51,13.01 JHDD.2
SATA_PRX_DTX_N0_C: length 38
  TOP w0.102: v3(186.87,16.38) 186.69,16.56 186.32,16.56 186.06,16.3 CS33.1
  IN1 w0.114: v3(186.87,16.38) 186.69,16.57 186.23,16.57 184.99,17.81 184.99,18.42 184.64,18.77 184.64,20.58 182.11,23.11 176.84,23.11 168.13,31.82 166.34,31.82 165.66,31.14 163.71,31.14 162.66,32.19 162.46,32.19 v3(162.36,32.08)
  BOTTOM w0.102: U2.AL20 160.76,31.33 160.76,31.4 161.05,31.69 161.26,31.69 161.8,32.24 162.21,32.24 v3(162.36,32.08) ; CS33.1 186.42,16.54 186.71,16.54 v3(186.87,16.38)
SATA_PRX_DTX_N0_R: length 2.8
  TOP w0.102: US2.12 178.73,16.94 178.61,17.05 178.38,17.05 178.09,17.35 178.09,17.71 177.96,17.84 177.55,17.84 CS31.1
SATA_PRX_DTX_N0_RC: length 2.5
  TOP w0.102: CS33.2 184.77,16.56 184.34,16.56 183.84,17.05 183.66,17.05 183.54,16.94 US2.4
SATA_PRX_DTX_P0: length 12.8
  TOP w0.102: CS34.2 176.26,18.34 176.02,18.1 175.71,18.1 v3(175.55,18.27)
  BOTTOM w0.102: JHDD.1 180.71,13.07 180.77,13.13 180.77,13.42 178.59,15.59 v2(178.31,15.59) 175.21,15.59 174.64,16.15 174.64,17.69 175.05,18.1 175.38,18.1 v3(175.55,18.27) 175.72,18.1 175.88,18.1 CS34.2
SATA_PRX_DTX_P0_C: length 38
  TOP w0.102: CS35.1 186.06,17.08 186.32,16.83 186.7,16.83 v3(186.87,17)
  IN1 w0.114: v3(162.36,32.69) 162.36,32.67 162.61,32.42 162.76,32.42 163.81,31.37 165.56,31.37 166.25,32.06 168.23,32.06 176.94,23.35 182.2,23.35 184.87,20.68 184.87,18.87 185.23,18.52 185.23,17.9 186.33,16.8 186.68,16.8 v3(186.87,17)
  BOTTOM w0.102: CS35.1 186.06,17.1 186.34,16.82 186.7,16.82 v3(186.87,17) ; v3(162.36,32.69) 162.17,32.5 161.69,32.5 161.15,31.96 160.94,31.96 160.51,31.53 160.38,31.53 160.3,31.61 U2.AN20
SATA_PRX_DTX_P0_R: length 2.8
  TOP w0.102: US2.11 178.71,17.44 178.59,17.32 178.49,17.32 178.35,17.46 178.35,17.82 178.07,18.1 177.54,18.1 CS34.1
SATA_PRX_DTX_P0_RC: length 2.5
  TOP w0.102: CS35.2 184.77,16.83 184.45,16.83 183.95,17.32 183.63,17.32 183.51,17.44 US2.5
SATA_PTX_DRX_N0: length 14.2
  TOP w0.102: v3(175.67,14.6) 175.93,14.34 176.29,14.34 176.66,14.71 CS32.2
  IN1 w0.114: v3(183.41,14.09) 183.61,13.89 183.61,13.26 183.26,12.91 178.14,12.91 176.68,14.37 175.88,14.37 175.67,14.58 v3(175.67,14.6)
  BOTTOM w0.102: v3(183.41,14.09) 183.51,13.98 183.58,13.91 183.58,13.36 183.11,12.89 JHDD.4 ; CS32.2 176.66,14.6 176.43,14.37 175.9,14.37 v3(175.67,14.6)
SATA_PTX_DRX_N0_C: length 42.3
  TOP w0.102: v3(186.85,15.04) 186.98,14.91 186.98,14.74 186.87,14.63 186.19,14.63 186.06,14.76 CS36.1
  IN1 w0.114: v3(186.85,15.04) 186.72,14.91 186.72,14.79 186.87,14.64 187.26,14.64 187.37,14.75 187.37,15.2 187.03,15.54 185.79,15.54 183.75,17.58 183.75,20.24 182.36,21.64 175.22,21.64 168.08,28.77 167.78,28.77 166.3,30.25 162.65,30.25 160.84,32.06 160.84,32.44 v3(160.61,32.67)
  BOTTOM w0.102: v3(186.85,15.04) 186.58,14.77 186.39,14.77 186.06,15.1 CS36.1 ; v3(160.61,32.67) 160.61,32.44 160.48,32.31 160.11,32.31 159.71,31.92 159.71,31.35 159.63,31.27 U2.AM19
SATA_PTX_DRX_N0_R: length 3
  TOP w0.102: US2.2 183.59,15.94 183.71,15.82 183.96,15.82 184.4,15.38 184.4,14.97 184.58,14.79 184.77,14.79 CS36.2
SATA_PTX_DRX_N0_RC: length 3.2
  TOP w0.102: CS32.1 177.58,14.69 177.86,14.41 177.98,14.41 178.11,14.53 178.11,15.6 178.34,15.82 178.57,15.82 178.68,15.94 US2.14
SATA_PTX_DRX_P0: length 14.1
  TOP w0.102: v3(175.67,14.01) 175.8,14.14 176.29,14.14 CS30.2
  IN1 w0.114: v3(175.67,14.01) 175.79,14.13 176.58,14.13 178.04,12.67 183.35,12.67 183.85,13.16 183.85,13.94 v3(183.99,14.09)
  BOTTOM w0.102: v3(175.67,14.01) 175.82,14.16 176.27,14.16 CS30.2 ; v3(183.99,14.09) 183.85,13.95 183.85,13.12 183.91,13.06 JHDD.5
SATA_PTX_DRX_P0_C: length 42.4
  TOP w0.102: v3(186.85,14.23) 186.72,14.36 186.26,14.36 CS37.1
  IN1 w0.114: v3(186.85,14.23) 187.03,14.41 187.36,14.41 187.61,14.66 187.61,15.3 187.13,15.78 185.88,15.78 183.99,17.68 183.99,20.34 182.45,21.87 175.32,21.87 168.18,29.01 167.87,29.01 166.4,30.48 162.74,30.48 161.08,32.15 161.08,32.52 v3(161.22,32.67)
  BOTTOM w0.102: v3(186.85,14.23) 186.57,14.51 186.34,14.51 186.06,14.23 CS37.1 ; U2.AK19 159.5,30.62 159.98,31.09 159.98,31.81 160.22,32.05 160.59,32.05 161.22,32.67 v3(161.22,32.67)
SATA_PTX_DRX_P0_R: length 3
  TOP w0.102: US2.1 183.59,15.44 183.7,15.55 183.85,15.55 184.13,15.27 184.13,14.86 184.47,14.52 184.78,14.52 CS37.2
SATA_PTX_DRX_P0_RC: length 3.2
  TOP w0.102: US2.15 178.68,15.44 178.56,15.55 178.45,15.55 178.38,15.48 178.38,14.42 178.09,14.14 177.84,14.14 177.58,13.87 CS30.1
SATA_RX_N0: length 8.9
  BOTTOM w0.102: CS41.1 177.55,17.83 178.14,17.83 179.5,16.48 v2(183.01,16.48) 183.38,16.48 183.46,16.55 184.78,16.55 RS44.2
SATA_RX_P0: length 8.9
  BOTTOM w0.102: CS40.1 177.55,18.1 178.25,18.1 179.61,16.74 v2(180.69,16.74) 183.27,16.74 183.35,16.82 184.77,16.82 RS42.2
SATA_TX_N0: length 8.3
  IN1 w0.114: v3(182.81,14.94) 182.64,14.77 181.57,14.77 181.19,14.39 179.04,14.39 v3(178.85,14.58)
  BOTTOM w0.102: v3(182.81,14.94) 182.96,14.79 184.77,14.79 RS41.2 ; CS39.1 177.95,14.41 178.68,14.41 v3(178.85,14.58)
SATA_TX_P0: length 8.3
  IN1 w0.114: v3(178.85,13.99) 179.01,14.15 181.29,14.15 181.66,14.53 182.64,14.53 v3(182.81,14.36)
  BOTTOM w0.102: v3(182.81,14.36) 182.98,14.53 184.77,14.53 RS43.2 ; v3(178.85,13.99) 178.7,14.15 177.95,14.15 CS38.1
SERIRQ: length 60.6
  TOP w0.102: v1(159.2,26.17) 159.12,26.25 v3(159.12,26.9)
  IN3 w0.102: v3(159.12,26.9) 158.61,26.39 155.11,26.39 153.99,25.28 151.77,25.28 150.28,23.79 150.28,21.5 148.75,19.97 148.75,19.66 148.47,19.38 147.23,19.38 146.31,18.47 145.57,18.47 143.82,16.72 142.18,16.72 140.82,18.08 140.35,18.08 139.91,18.52 139.13,18.52 137.81,19.84 137.19,19.84 135.87,21.16 135.87,21.92 135.26,22.53 134.29,22.53 133.83,22.08 124.21,22.08 122.08,24.21 120.22,24.21 118.8,22.79 v3(118.8,22.64)
  BOTTOM w0.102: U2.AE19 159.3,26.72 v3(159.12,26.9) ; v3(118.8,22.64) 118.8,22.53 119.18,22.15 119.18,17.2 120.39,15.99 UE1.3
SET1: length 4.4
  TOP w0.203: PR569.1 PR567.2 v1(59.06,109.28) 59.62,109.83 59.62,110.72 59.86,110.96 PU500.25
SET2: length 6.1
  TOP w0.102: v1(56.95,106.3) 57.47,106.82 PR573.1
  TOP w0.203: PR573.1 57.49,107.51 PR571.2 59.87,109.03 59.87,109.58 60.3,110.01 PU500.26
SID_G: length 5.6
  TOP w0.102: Q2507.2 174.43,94.21 174.73,94.52 176.42,94.52 Q78.5 R18.2 177.43,92.59 v1(177.87,93.03)
SNB_APU: length 2.9
  TOP w0.102: v1(87.45,112.21) 87.75,112.51 PC528.1
  TOP w0.508: PC528.1 PR546.2
SNB_APU_NB: length 3.5
  BOTTOM w0.102: v1(82.9,111.26) 82.51,110.86 PR516.2
  BOTTOM w0.508: PR516.2 81.15,110.93 PC511.1
SNB_CHG: length 2.5
  BOTTOM w0.102: PC716.1 v1(44.65,31.72)
  BOTTOM w0.508: PC716.1 44.65,30.15 44.35,29.86 PR721.2
SNUB_PCIE: length 2.2
  TOP w0.102: PR1303.2 74.52,56.19 74.12,55.8 v1(73.62,55.8)
SPK_L1-_CONN:
  vias: v2(205.34,20.15) v3(205.97,20.15)
SPK_L2+_CONN:
  vias: v3(203.18,20.12) v3(203.76,20.12)
SPK_R1-_CONN:
  vias: v1(211.89,19.42) v3(210.62,20.12) v3(211.26,20.12)
SPK_R2+_CONN:
  vias: v3(207.32,20.12) v3(207.97,20.13)
SUSCLK: length 98.4
  TOP w0.102: RM5.2 185.1,64.11 v3(184.87,63.89) ; v3(114.48,26.22) v1(114.48,25.66)
  IN1 w0.102: v3(184.87,63.89) 183.88,62.89 183.88,61.75 183.04,60.91 178.09,60.91 177.91,61.09 172.07,61.09 171,60.02 171,56.5 161.16,46.66 161.16,45.68 159.52,44.04 159.52,43.52 157.58,41.58 157.27,41.58 156.69,41 155.85,41 154.09,39.24 147.35,39.24 145.94,37.82 144.41,37.82 139.78,33.2 139.66,33.2 133,26.53 128.58,26.53 127.89,27.23 124.09,27.23 121.94,25.07 121.21,25.07 121.09,24.95 120.24,24.95 118.97,26.22 v3(114.48,26.22)
  BOTTOM w0.102: UE1.86 117.19,29.53 116.8,29.14 116.8,28.67 114.48,26.35 v3(114.48,26.22)
SUSCLK_R: length 3.6
  TOP w0.102: v1(184.04,67.61) 184.89,66.76 v3(184.89,66.53) 185.1,66.32 RM5.1
  BOTTOM w0.102: JNGFF.42 184.73,66.36 v3(184.89,66.53)
SUSP: length 50.9
  TOP w0.102: QZ13.2 163.83,37.49 159.85,37.49 159.59,37.75 158.43,37.75 158.27,37.6 145.5,37.6 138.87,30.97 137.44,30.97 130.92,24.44 v3(130.92,24.11) ; v3(129.95,25.07) 129.72,25.07 127.69,23.04 127.12,23.04 126.76,23.4 v4(125.75,23.4) 122.23,23.4 121.96,23.67 Q52.6 120.85,23.99 RZ10.1
  BOTTOM w0.102: v3(129.95,25.07) v3(130.92,24.11)
SUSP#: length 205.7
  TOP w0.102: v3(135.23,2.62) 134.75,3.1 R437.1 ; PR311.1 208.18,11.56 v3(208.18,11.43) ; Q52.2 122.61,21.87 122.1,21.37 121.88,21.37 v3(121.55,21.04) 121.88,20.71 RZ591.1 122.79,20.27 124.77,20.27 125.08,19.97 v4(125.08,19.74) v3(125.08,17.3) ; RZ25.1 72.5,30.46 v3(72.57,30.54) 72.94,30.9 U6.3
  IN1 w0.102: v3(135.23,2.62) 135.23,2.99 126.66,11.56 126.66,13.04 125.08,14.63 v3(125.08,17.3) ; v3(72.57,30.54) 73.21,31.17 73.84,31.17 75.32,29.69 83.72,29.69 84.35,30.32 v3(84.79,30.32) 84.79,26.45 78.67,20.32 78.67,16.95 77.15,15.42 75.24,15.42 73.97,14.15 73.97,11.61 77.3,8.28 79.08,8.28 v3(79.43,7.93) 79.94,8.44 85.58,8.44 86.14,9 86.58,9 89.18,11.59 100.38,11.59 102.74,13.96 108.69,13.96 110.46,15.72 110.46,16.2 114.63,20.38 116.31,20.38 116.97,21.04 v3(121.55,21.04)
  IN3 w0.102: v3(135.23,2.62) 136.5,2.62 136.86,2.27 145.56,2.27 146.14,2.85 147.79,2.85 148.26,2.38 153.29,2.38 153.45,2.55 158,2.55 158.35,2.2 163.66,2.2 164.39,2.93 167.66,2.93 168.97,1.63 173.44,1.63 177.45,5.64 186.42,5.64 188.1,7.32 202.77,7.32 206.89,11.43 v3(208.18,11.43)
  BOTTOM w0.102: PR408.1 85.21,30.74 v3(84.79,30.32) ; v3(121.55,21.04) 121.9,21.39 UE1.116
  BOTTOM w0.254: PR202.1 v3(79.43,7.93)
SUSP#_C: length 3
  TOP w0.102: RZ25.2 73.89,29.84 73.91,29.85 CZ5.1 74.35,30.26 v1(73.89,30.71) 73.74,30.87 U6.5
SVI2_SVC: length 89.7
  IN2 w0.127: v3(62.82,33.13) 63.32,32.62 67.57,32.62 71.25,36.3 74.42,36.3 75.06,36.95 75.06,37.43 88.8,51.17 88.8,69.42 85.53,72.7 80.37,72.7 79.99,73.08 79.99,77.86 79.84,78.01 79.84,85.86 80.6,86.62 80.6,88.12 81.51,89.03 81.51,91.09 v3(80.85,91.75)
  BOTTOM w0.102: v1(79.37,97.11) 79.86,96.61 79.86,96.24 80.14,95.97 RV89.2
  BOTTOM w0.203: PU1000.3 62.52,33.58 62.82,33.29 v3(62.82,33.13)
  BOTTOM w0.254: RV89.2 RV84.1 RV78.2 RV157.2 80.42,93.02 80.85,92.59 v3(80.85,91.75)
SVI2_SVD: length 86.9
  IN2 w0.127: v3(61.86,33.13) 62.44,33.71 68.3,33.71 71.14,36.55 74.31,36.55 74.81,37.05 74.81,37.54 88.55,51.28 88.55,69.32 85.42,72.45 80.27,72.45 79.74,72.97 79.74,77.75 79.58,77.9 79.58,85.96 80.14,86.52 v3(80.14,87.81) 80.14,89.41 v3(81.08,90.35)
  BOTTOM w0.102: v1(78.81,87.52) 79.1,87.81 v3(80.14,87.81)
  BOTTOM w0.203: PU1000.5 61.73,33.26 v3(61.86,33.13) ; v3(81.08,90.35) RV77.2 RV88.2 RV87.1 ; RV155.2 v3(80.14,87.81)
SVI2_SVT: length 81.7
  IN2 w0.127: v3(79.18,87.05) 79.18,77.95 79.48,77.64 79.48,72.87 80.16,72.19 83.24,72.19 88.3,67.14 88.3,51.38 74.56,37.64 74.56,37.16 74.21,36.81 71.04,36.81 70.45,36.22 64.54,36.22 62.16,33.84 61.39,33.84 v3(60.67,33.13)
  BOTTOM w0.203: RV156.2 80.19,89.46 80.7,88.96 80.7,87.56 v1(80.56,87.41) 80.19,87.05 v3(79.18,87.05) ; v3(60.67,33.13) 60.67,33.21 60.92,33.46 PU1000.7
SW_1.35V:
  vias: v1(90.6,21.99) v2(90.61,17.2) v2(91.24,17.2) v3(86.42,12.12) v3(86.8,13.39) v3(86.8,12.63)
SW_+1.05VSP: length 3.7
  IN1 w1.016: 178.62,45.52 178.62,47.68 179.56,48.62 179.56,48.82
  vias: v1(181.82,40.14) v2(177.98,44.51) v2(177.98,43.87) v2(177.98,43.24) v2(178.62,44.51) v2(178.62,43.87) v2(178.62,43.24) v2(179.56,50.3) v2(179.56,49.66)
SW_+1.35VGPUP:
  vias: v1(35.77,48.9) v2(39.81,46.18) v2(39.81,45.55) v2(39.81,44.91) v2(40.47,46.18) v2(40.47,45.55) v2(40.47,44.91) v2(41.03,45.88) v2(41.08,45.17)
SYS_RESET#: length 7.9
  BOTTOM w0.102: RH53.2 140.87,20.6 v1(144.06,20.6) 144.67,20.6 145.14,20.13 146.22,20.13 146.61,19.74 147.17,19.74 U2.U4
SYSON: length 59
  TOP w0.102: v3(119.09,24.54) 119.13,24.58 v1(119.63,24.58) 120.71,24.58 121.21,25.07 RZ21.1 122.66,24.53 122.61,24.48 Q52.5
  IN1 w0.102: v3(79.3,9.71) 79.76,10.16 84.77,10.16 85.83,11.23 88.07,11.23 88.98,12.15 91.04,12.15 93.3,14.41 108.51,14.41 109.91,15.8 109.91,16.32 116.95,23.37 117.89,23.37 119.09,24.57 v3(119.09,24.54)
  BOTTOM w0.102: v3(119.09,24.54) 119.09,26.29 121.04,28.23 121.04,29.57 120.79,29.82 UE1.95
  BOTTOM w0.254: PR201.1 v3(79.3,9.71)
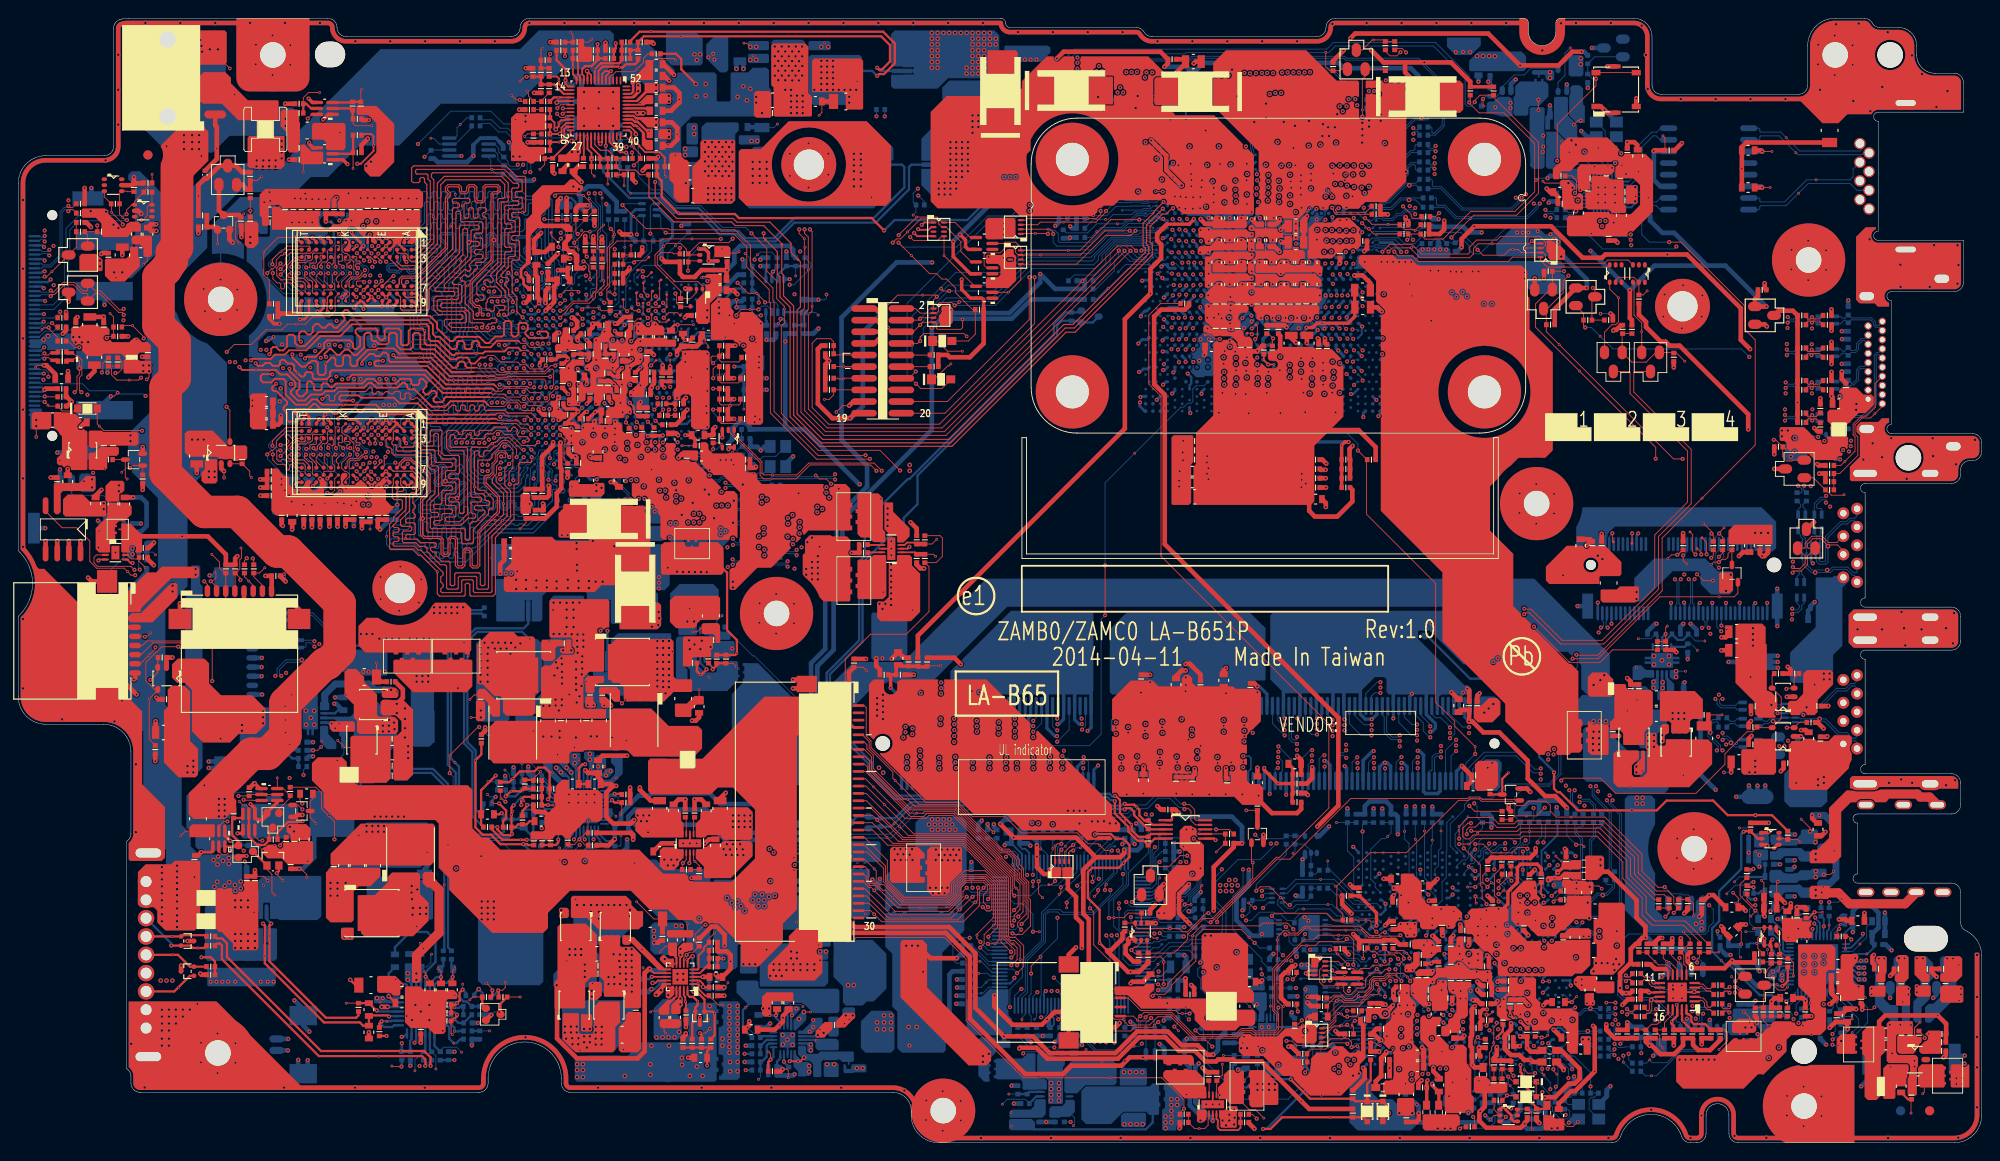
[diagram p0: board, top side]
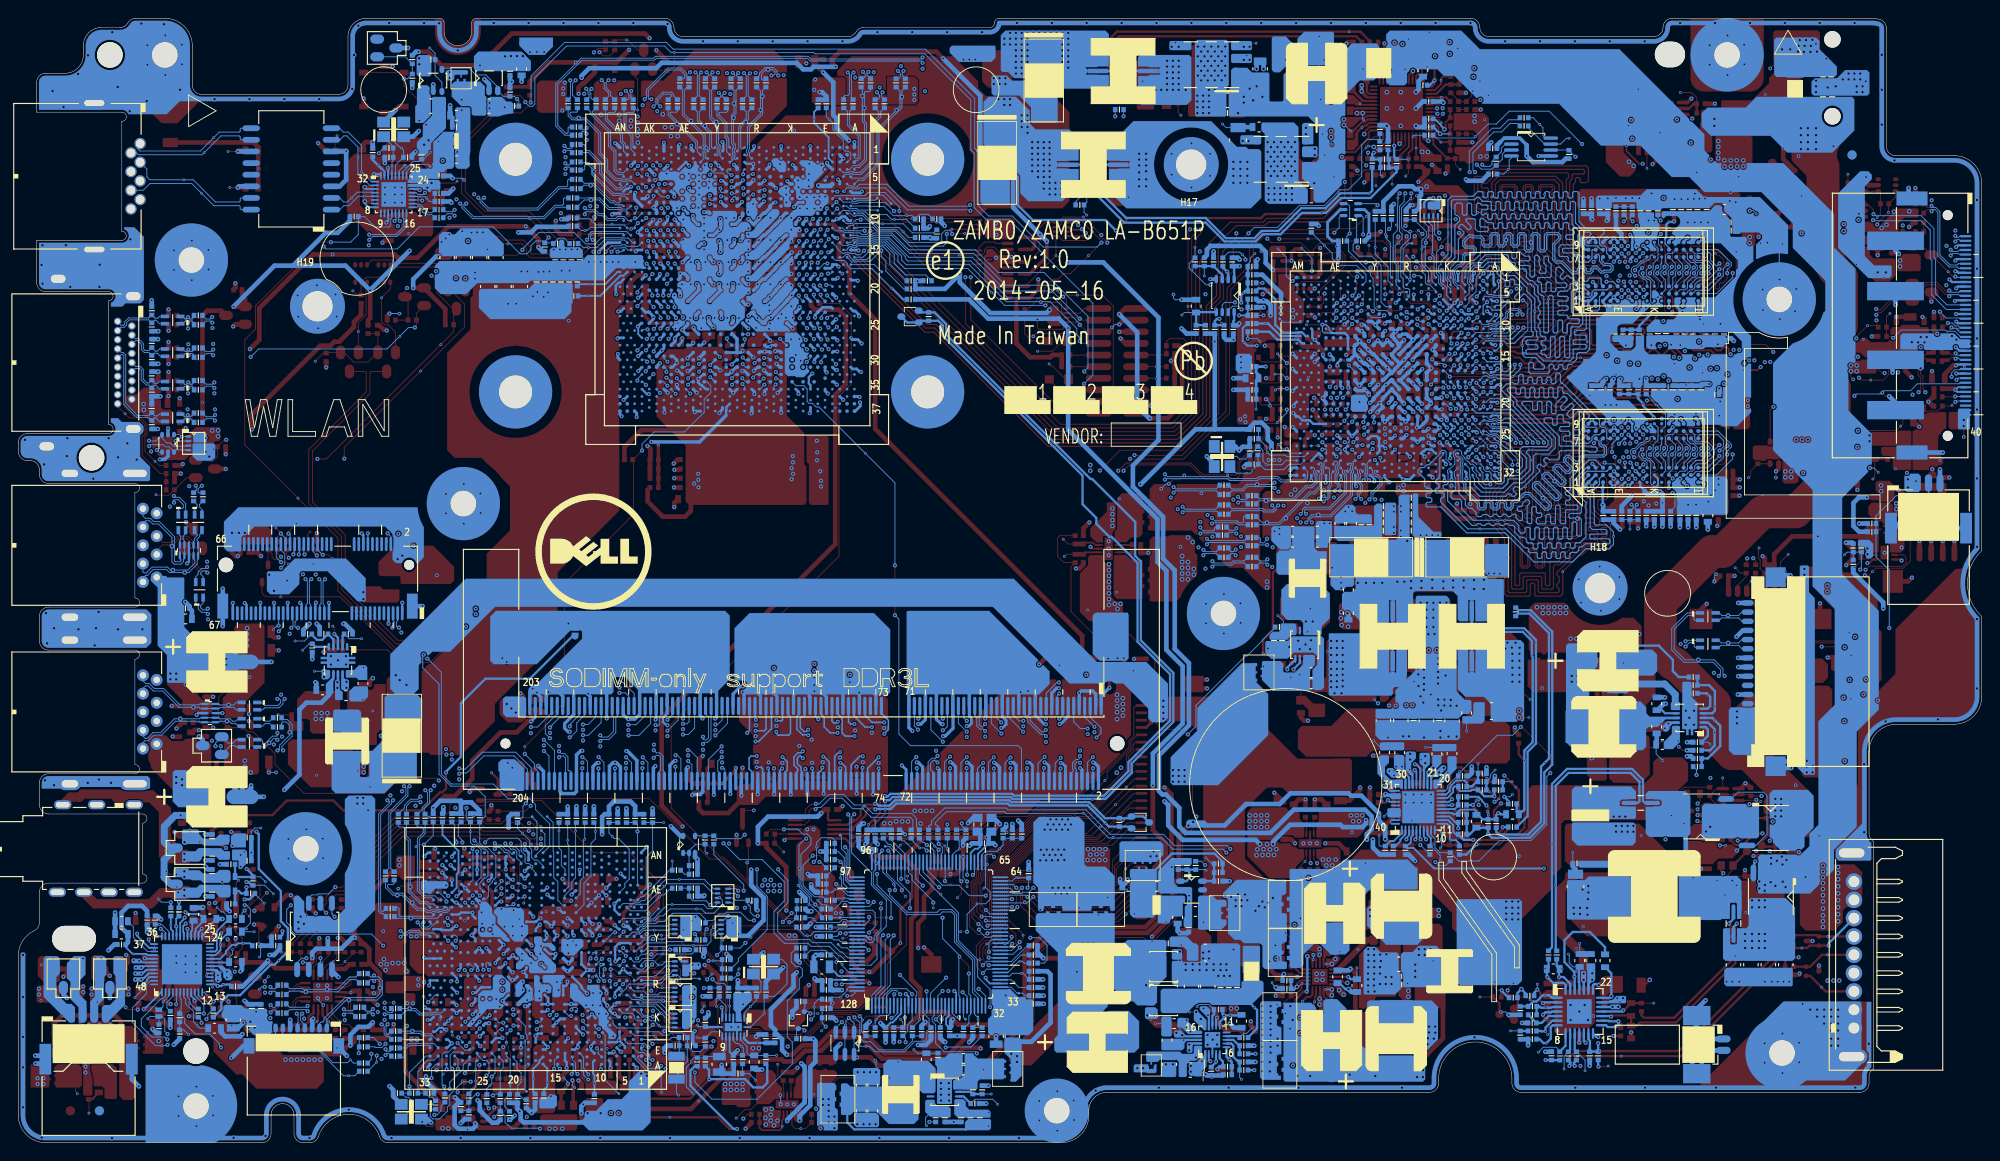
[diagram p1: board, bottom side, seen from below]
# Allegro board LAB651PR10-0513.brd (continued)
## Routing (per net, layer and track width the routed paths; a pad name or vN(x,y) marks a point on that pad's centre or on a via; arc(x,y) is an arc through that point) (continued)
SYSON#: length 20.5
  TOP w0.102: Q52.3 123.26,20.82 RZ19.1 126.19,20.71 127.69,22.2 127.69,22.75 129.43,24.49 130.39,24.49 134.8,28.9 v4(134.8,30.6) 134.66,30.74 QZ15.2
TEST0: length 6.1
  TOP w0.102: v3(150.68,20.08) 150.68,20.1 150.26,20.51 148.53,20.51 148.19,20.86 147.73,20.86 RH57.2 146.87,20.81 v4(146.87,20.12)
  BOTTOM w0.102: U2.T9 151.29,19.47 v3(150.68,20.08)
TEST1: length 3.1
  TOP w0.102: RH60.2 150.33,21 151.31,21 v1(151.61,20.69) 151.91,20.39 v3(151.91,20.13)
  BOTTOM w0.102: v3(151.91,20.13) 152.1,19.94 U2.T10
TEST2: length 4.2
  TOP w0.102: RH61.2 149.68,20.72 150.86,20.72 151.3,20.28 v3(151.3,20.1) 151.3,19.99 v4(150.76,19.45)
  BOTTOM w0.102: v3(151.3,20.1) U2.V9
TESTEN: length 14.2
  TOP w0.102: v3(59.18,91.66) 59.36,91.66 v4(59.71,92) ; v3(57.44,100.87) 57.49,100.82 RV154.2 RV17.2
  IN3 w0.102: v3(59.18,91.66) 59.18,91.75 56.75,94.18 56.75,98.06 57.54,98.85 57.54,100.77 v3(57.44,100.87)
  BOTTOM w0.102: UV1.K7 58.83,91.3 v3(59.18,91.66)
THM_ALERT#: length 37
  IN1 w0.102: v3(44.35,107.67) 44.74,107.29 52.89,107.29 53.78,106.4 57.12,106.4 58.18,105.34 61.79,105.34 62.29,104.84 v3(62.29,103.69)
  BOTTOM w0.102: UV3.6 45.1,108.42 RV146.2 v3(44.35,107.67) ; UV1.R6 62.47,92.43 62.47,93.13 62.62,93.29 62.96,93.29 63.18,93.51 63.18,94.33 63.43,94.58 63.43,97.77 62.38,98.82 62.38,99.19 62.78,99.6 62.96,99.6 63.35,99.99 63.35,102.11 v1(62.35,103.12) 62.29,103.18 v3(62.29,103.69)
TMDS_L_TX0N: length 11.7
  BOTTOM w0.102: JHDMI.9 203.17,86.08 203.03,86.08 202.89,85.95 202.89,80.64 201.45,79.2 200.15,79.2 CX25.1 199.54,79.16 199.37,79.16 198.98,78.78 LX3.2
TMDS_L_TX0P: length 11.7
  BOTTOM w0.102: JHDMI.7 203.15,86.3 202.94,86.3 202.67,86.03 202.67,80.73 201.36,79.41 200.15,79.41 CX26.1 199.47,79.38 199.18,79.38 198.98,79.58 LX3.3
TMDS_L_TX1N: length 5
  BOTTOM w0.102: LX4.2 198.87,85.89 199.21,86.22 199.59,86.22 CX27.1 200.15,86.31 200.65,86.31 200.96,86.62 200.96,87.19 201.37,87.6 201.6,87.6 JHDMI.6
TMDS_L_TX1P: length 5
  BOTTOM w0.102: LX4.3 198.98,86.69 199.23,86.44 199.42,86.44 CX28.1 200.15,86.52 200.56,86.52 200.74,86.71 200.74,87.28 201.28,87.81 201.61,87.81 JHDMI.4
TMDS_L_TX2N: length 6.2
  BOTTOM w0.102: JHDMI.3 203.19,89.06 202.83,89.06 202.58,89.31 202.58,89.56 202.27,89.86 200.15,89.86 CX29.1 199.54,89.83 199.37,89.83 198.98,89.44 LX5.2
TMDS_L_TX2P: length 6.2
  BOTTOM w0.102: JHDMI.1 203.55,89.63 203.19,89.27 202.92,89.27 202.79,89.4 202.79,89.65 202.36,90.08 200.15,90.08 CX30.1 199.47,90.05 199.18,90.05 198.98,90.24 LX5.3
TMDS_L_TXCN: length 5.5
  BOTTOM w0.102: JHDMI.12 201.64,84.56 201.17,84.56 200.97,84.36 200.97,83.29 200.43,82.75 200.15,82.75 CX23.1 199.54,82.72 199.37,82.72 198.98,82.33 LX2.2
TMDS_L_TXCP: length 5.5
  BOTTOM w0.102: LX2.3 198.98,83.13 199.18,82.94 199.47,82.94 CX24.1 200.15,82.97 200.34,82.97 200.75,83.38 200.75,84.45 201.1,84.79 201.59,84.79 JHDMI.10
TMDS_TX0N: length 4.1
  TOP w0.102: RX181.1 195.21,78.82 195.45,79.06 195.7,79.06 v3(195.89,78.87) 196.09,79.07 196.33,79.07 CV362.1
  BOTTOM w0.102: RX181.1 195.61,79.07 195.69,79.07 v3(195.89,78.87) 196.07,79.05 196.22,79.05 196.49,78.78 LX3.1
TMDS_TX0P: length 4.1
  TOP w0.102: RX182.1 195.21,79.51 195.45,79.27 195.69,79.27 v3(195.89,79.47) 196.08,79.28 196.33,79.28 CV363.1
  BOTTOM w0.102: LX3.4 196.52,79.58 196.21,79.27 196.09,79.27 v3(195.89,79.47) 195.71,79.28 195.61,79.28 RX182.1
TMDS_TX1N: length 4.5
  TOP w0.102: CV359.1 196.68,86.18 195.99,86.18 v3(195.81,86.01) 195.64,86.18 195.45,86.18 195.21,85.93 RX183.1
  BOTTOM w0.102: LX4.1 196.44,85.89 196.14,86.19 195.99,86.19 v3(195.81,86.01) 195.64,86.19 195.39,86.19 195.21,86.01 RX183.1
TMDS_TX1P: length 4.5
  TOP w0.102: CV357.1 196.68,86.4 196.04,86.4 v3(195.84,86.59) 195.64,86.4 195.45,86.4 195.21,86.64 RX184.1
  BOTTOM w0.102: RX184.1 195.21,86.62 195.41,86.42 195.66,86.42 v3(195.84,86.59) 196.03,86.4 196.16,86.4 196.44,86.69 LX4.4
TMDS_TX2N: length 4.5
  TOP w0.102: RX185.1 195.21,89.51 195.43,89.74 195.69,89.74 v3(195.87,89.56) 196.05,89.74 196.68,89.74 CV361.1
  BOTTOM w0.102: LX5.1 196.44,89.44 196.14,89.74 196.05,89.74 v3(195.87,89.56) 195.68,89.74 195.43,89.74 195.21,89.51 RX185.1
TMDS_TX2P: length 4.5
  TOP w0.102: CV364.1 196.69,89.96 196.06,89.96 v3(195.87,90.16) 195.66,89.95 195.43,89.95 195.21,90.17 RX186.1
  BOTTOM w0.102: RX186.1 195.21,90.17 195.41,89.97 195.68,89.97 v3(195.87,90.16) 196.06,89.96 196.18,89.96 196.47,90.24 LX5.4
TMDS_TXCN: length 4.5
  TOP w0.102: CV358.1 196.68,82.62 196.04,82.62 v3(195.84,82.43) 195.64,82.62 195.45,82.62 195.21,82.38 RX179.1
  BOTTOM w0.102: LX2.1 196.49,82.33 196.22,82.61 196.02,82.61 v3(195.84,82.43) 195.65,82.62 195.42,82.62 195.21,82.4 RX179.1
TMDS_TXCP: length 4.5
  TOP w0.102: RX180.1 195.21,83.12 195.48,82.84 195.64,82.84 v3(195.84,83.04) 196.04,82.84 196.68,82.84 CV360.1
  BOTTOM w0.102: LX2.4 196.52,83.13 196.2,82.81 196.07,82.81 v3(195.84,83.04) 195.64,82.83 195.41,82.83 195.21,83.04 RX180.1
TON_1.35V: length 3.3
  BOTTOM w0.102: PR208.2 81.03,11.5 80.59,11.94 80.27,11.94 v1(79.64,12.58)
  BOTTOM w0.254: PR208.2 81.18,11.63 PU200.9
TONSET: length 6.3
  TOP w0.102: PU500.4 64.55,116.36 64.84,116.64 64.93,116.64 65.26,116.97 67.27,116.97 v1(67.56,117.27) 68.28,117.99 68.28,118.44 68.76,118.93 PR514.1
TP_CLK: length 131.5
  TOP w0.102: v3(20.3,61.31) 20.65,60.96 JTP.1 ; v3(117.3,28.5) v1(117.3,29.12)
  IN1 w0.102: v3(20.3,61.31) 21.61,60 30.51,60 36.09,54.42 44.57,54.42 48.52,50.47 48.52,45.08 52.74,40.86 52.74,39.36 51.64,38.27 51.64,36.1 52.21,35.53 54.74,35.53 54.97,35.76 59.01,35.76 59.35,36.1 63.39,36.1 63.84,36.55 65.18,36.55 66.3,37.67 71.63,37.67 72.26,37.04 74.39,37.04 76.9,39.55 85.19,39.55 88.29,36.45 112.63,36.45 114.48,34.6 114.48,30.66 115.63,29.52 116.28,29.52 v3(117.3,28.5)
  BOTTOM w0.102: v3(117.3,28.5) 117.59,28.8 UE1.87 117.59,31.58 119.06,33.04 RE9.2
TP_DATA: length 128
  TOP w0.102: v1(21.46,62.35) 21.58,62.22 21.58,61.71 21.19,61.32 v3(21.01,61.32) 21.65,60.68 JTP.2
  IN1 w0.114: v3(117.99,28.82) 117.8,29.01 117.4,29.01 116.48,29.93 116.01,29.93 115.75,30.19 115.75,33.91 112.8,36.87 90.37,36.87 89.46,37.77 87.55,37.77 85.36,39.96 76.73,39.96 74.84,38.08 66.12,38.08 65.01,36.96 63.67,36.96 63.22,36.51 59.18,36.51 58.84,36.17 57.32,36.17 54.37,39.12 54.37,39.82 49.13,45.05 49.13,51.5 44.57,56.06 35.08,56.06 30.66,60.48 21.85,60.48 v3(21.01,61.32)
  BOTTOM w0.102: v3(117.99,28.82) UE1.88 117.99,31.4 119.18,32.59 119.41,32.59 RE10.2
TP_EN: length 205.4
  TOP w0.102: UE4.3 8.52,64.19 8.26,63.94 8.26,63.33 8.64,62.95 12.3,62.95 v3(12.68,62.56) ; v3(113.85,27.9) 113.85,27.31 v1(113.66,27.12)
  IN2 w0.127: v3(12.68,62.56) 12.68,62.92 14,64.24 14,78.24 12.68,79.56 12.68,88.81 13.49,89.63 13.49,90.51 23.57,100.59 27.33,100.59 29.11,102.37 44.17,102.37 45.59,100.94 56.42,100.94 57.03,101.55 58,101.55 58.61,100.94 62.21,100.94 62.38,101.12 65.37,101.12 66.33,100.16 67.19,100.16 69.24,98.1 69.72,98.1 71.35,96.47 73.82,96.47 74.56,95.74 76.37,95.74 77.65,94.45 77.65,93.99 78.3,93.35 82.09,93.35 83.67,91.77 83.67,88.7 83.06,88.1 83.06,86.59 83.57,86.08 83.57,80.68 90.66,73.59 90.66,71.54 90.07,70.96 90.07,51.41 91.35,50.13 91.35,41.36 98.2,34.52 98.21,34.52 99.12,33.6 99.12,30.54 99.93,29.72 111.11,29.72 112.83,28 113.72,28 113.85,27.87 v3(113.85,27.9)
  BOTTOM w0.102: v3(113.85,27.9) 113.85,27.82 115.59,29.56 UE1.82
TP_INT#: length 262.7
  TOP w0.102: JTP.4 23.68,60.28 RE329.2 ; v1(24.31,64.95) 24.38,64.89 24.38,63.87 24.19,63.68 24.19,62.67 23.73,62.21 RE329.2 ; RH133.2 163,29.38 RH68.2 162.95,29.29 161.65,28 v3(161.65,27.79) ; RE329.2 24.25,61.64 v3(24.25,61.46)
  IN2 w0.127: v3(24.25,61.46) 23.68,60.89 18.9,60.89 15.37,64.42 15.37,79.61 18.66,82.9 18.66,94.23 23.86,99.42 27.67,99.42 29.57,101.32 43.77,101.32 45.17,99.93 59.42,99.93 59.59,99.75 62.35,99.75 62.64,99.46 63.2,99.46 63.49,99.75 63.59,99.75 64.81,98.53 65.61,98.53 69.42,94.72 75.57,94.72 75.95,94.34 75.95,93.75 77.84,91.86 80.14,91.86 80.56,92.28 81.67,92.28 81.97,91.98 81.97,91.5 81.77,91.29 81.77,88.4 81.24,87.87 81.24,86.87 82.38,85.73 82.38,80.4 89.36,73.42 89.36,73.42 89.6,73.18 89.6,73.18 89.64,73.14 89.64,71.96 89.06,71.38 89.06,51.3 90.54,49.81 90.54,40.94 98.1,33.38 98.1,30.31 99.7,28.71 108.31,28.71 112.96,24.06 119.71,24.06 121.05,25.39 124.26,25.39 124.43,25.56 125.91,25.56 126.8,26.45 129.7,26.45 130.26,27 130.26,28.22 131.43,29.39 142.93,29.39 144.46,30.92 159.31,30.92 161.12,29.11 161.12,28.33 v3(161.65,27.79)
TP_INT#_R: length 2.3
  TOP w0.102: v3(161.63,28.58) 162.03,28.99 RH68.1
  BOTTOM w0.102: v3(161.63,28.58) 161.63,28.48 162.3,27.8 U2.AF22
TP_WAKE: length 121
  TOP w0.102: v1(21.13,64.25) 21.96,63.42 21.96,62.79 22.55,62.21 RC78.1 22.65,62.2 JTP.3 22.65,56.05 21.18,54.58 v3(21.18,50.42)
  IN1 w0.114: v3(21.18,50.42) 21.7,49.9 21.7,44.94 27.8,38.84 46.54,38.84 47.31,38.07 47.31,36.11 52.17,31.26 52.54,31.26 59.12,31.26 59.28,31.41 67.21,31.41 70.13,34.34 76.1,34.34 76.45,33.98 83.26,33.98 84.65,32.59 92.42,32.59 97.5,27.51 98.2,27.51 102.25,23.47 102.8,23.47 v3(103.89,22.38)
  BOTTOM w0.102: RE11.2 102.39,19.61 102.06,19.94 102.06,21.56 102.89,22.38 v3(103.89,22.38)
TP_WAKE_R: length 3.7
  BOTTOM w0.102: UE1.38 106.35,18.59 105.14,19.8 v1(105,19.8) 104.76,19.8 104.57,19.61 RE11.1
TRIP_+1.05VSP: length 3.6
  BOTTOM w0.102: v1(176.9,55.05) 178.28,55.05 178.78,55.55 PR301.2
  BOTTOM w0.254: PR301.2 178.99,55.38 PU300.2
TRIP_+1.35VGPUP: length 5
  BOTTOM w0.254: PU1100.2 29.89,45.89 29.17,45.17 v1(29.17,44.78) 29.17,43.36 29.67,42.85 PR1102.2
TS_EN: length 163.2
  TOP w0.102: v3(6.66,86.86) 6.15,86.86 5.45,87.56 RX25.1
  IN2 w0.127: v3(6.66,86.86) 6.66,85.96 9.15,83.47 9.15,80.83 10.06,79.92 10.06,70.8 11.26,69.6 11.26,59.82 12.05,59.03 12.05,55.19 28.35,38.89 28.35,36.86 30.76,34.45 33.86,34.45 36.07,32.24 41.7,32.24 45.61,28.33 65.47,28.33 71.88,34.75 75.25,34.75 77.46,36.96 82.64,36.96 85.38,34.23 86.04,34.23 96.21,24.06 101.25,24.06 107.78,17.53 112.5,17.53 v3(113.47,16.57)
  BOTTOM w0.102: v3(113.47,16.57) 113.99,16.04 UE1.19
TS_EN_R: length 4.5
  TOP w0.102: RX25.2 4.3,87.94 3.31,88.93 v3(3.31,89.03) 2.8,89.03 v1(2.58,88.82)
  BOTTOM w0.102: v3(3.31,89.03) 3.21,88.93 2.8,88.93 2.37,88.5 JEDP.22
TS_INT#: length 210.1
  TOP w0.102: v3(139.73,14.33) 139.62,14.43 RH83.2 ; RX35.2 4.12,89.08 v3(3.69,89.51)
  IN2 w0.127: v3(149.19,17.3) 147.42,15.52 142.22,15.52 141.38,14.69 140.08,14.69 v3(139.73,14.33) 139.39,14.66 138.66,14.66 138.11,14.1 135.52,14.1 133.43,16.19 126.97,16.19 125.87,15.09 110.26,15.09 108.59,16.77 107.4,16.77 100.87,23.3 95.89,23.3 85.72,33.47 85.06,33.47 82.33,36.2 77.77,36.2 75.56,33.99 72.2,33.99 65.78,27.57 45.29,27.57 41.41,31.45 31.93,31.45 26.59,36.79 26.59,39.9 11.46,55.02 11.46,58.5 9.4,60.55 9.4,64.93 10.72,66.25 10.72,69.4 9.56,70.57 9.56,79.68 8.64,80.6 8.64,83.24 3.77,88.12 3.77,89.44 v3(3.69,89.51)
  BOTTOM w0.102: JEDP.21 2.36,89 2.57,89.21 2.9,89.21 3.21,89.51 v3(3.69,89.51) ; v1(139.46,14.93) 139.73,14.67 v3(139.73,14.33) ; v3(149.19,17.3) 148.77,17.72 U2.P6
TS_RST#: length 211.2
  TOP w0.102: RH134.2 139.58,18.24 v3(139.17,17.84) ; RX24.2 4.58,90.38 v3(4.58,90.76)
  IN2 w0.127: v3(4.58,90.76) 5.54,89.79 5.54,86.7 8.9,83.35 8.9,80.73 9.81,79.81 9.81,70.69 10.98,69.52 10.98,66.14 9.66,64.82 9.66,60.66 11.74,58.58 11.74,55.12 28.1,38.76 28.1,36.68 33.08,31.7 41.52,31.7 45.4,27.82 65.68,27.82 72.1,34.24 75.46,34.24 77.67,36.45 82.43,36.45 85.16,33.72 85.83,33.72 96,23.55 101,23.55 107.52,17.02 108.69,17.02 110.37,15.35 125.76,15.35 126.86,16.45 129.5,16.45 130.36,17.3 138.64,17.3 v3(139.17,17.84) 141.05,17.84 141.53,18.32 149.84,18.32 150.38,18.85 v3(150.38,18.95)
  BOTTOM w0.102: U2.R8 150.5,18.83 v3(150.38,18.95) ; JEDP.19 2.39,90 2.47,90.07 3.89,90.07 v3(4.58,90.76) ; v3(139.17,17.84) 139.17,17.87 v1(138.63,18.42)
UG_3V: length 12.1
  IN1 w0.762: 69.37,20.83 67.8,22.41 61.65,22.41 60,24.06 59.24,24.06
  BOTTOM w0.102: v2(70.97,19.52) v1(71.6,19.52)
  vias: v2(59.29,25.4) v2(59.29,24.77) v2(70.59,20.06)
UG_5V: length 9.9
  IN1 w0.762: 70.77,15.37 69.78,14.38 63.53,14.38 62.41,13.26
  BOTTOM w0.127: v1(71.65,16.74) 71.65,16.74 v2(70.97,16.74)
  vias: v2(61.78,12.42) v2(62.41,12.42) v2(70.97,16.11)
UG_+1.05VSP: length 8
  IN1 w1.016: 175.91,41.85 175.91,47 177.96,49.05
  vias: v1(177.32,40.61) v2(176.69,41.08) v2(176.69,40.44) v2(178.56,50.34) v2(178.56,49.69)
UG_+1.35VGPUP:
  vias: v1(35.02,45.78) v3(34.22,45.78) v3(34.6,45.27)
UGATE1: length 10.5
  TOP w0.102: v2(50.5,46.44) v1(49.45,46.44)
  IN1 w0.762: 50.7,46.44 51.8,46.44 56.42,41.81 57.87,41.81 58.1,41.58
  vias: v2(50.5,47.2) v2(58.73,40.95) v2(59.24,40.44)
UGATE2: length 7.9
  IN3 w0.762: 65.13,41.18 65.33,41.38 65.33,42.35 63.99,43.69 v3(63.99,47.74) v3(64.73,47.74)
  vias: v1(64.17,40.62) v3(64.17,40.11) v3(64.67,40.59)
UGATE_APU1:
  vias: v1(67.89,113.48)
UGATE_NB1: length 3.2
  TOP w0.203: PU500.43 67.07,111.76 67.37,111.46 67.66,111.46 PR507.1
UMI_ATX_C_FRX_N0: length 105.7
  IN3 w0.135: v3(170.8,24.06) 170.8,27.09 174.9,31.2 174.9,37.93 173.87,38.96 173.87,40 171.22,42.65 171.22,50.6 176.14,55.53 176.14,64.93 174.87,66.2 174.87,89.87 174.54,90.2 174.54,91.24 174.09,91.7 174.09,95.97 171.48,98.57 170.39,98.57 168.38,100.58 166.69,100.58 165.98,101.28 165.98,102.41 v3(166.15,102.57)
  BOTTOM w0.102: v3(166.15,102.57) 165.96,102.38 165.96,102.1 164.78,100.92 156.95,100.92 155.71,102.16 CC85.2 ; v3(170.8,24.06) 170.59,23.85 170.59,23.72 170.22,23.35 169.54,23.35 168.98,23.91 168.86,23.91 U2.AB31
UMI_ATX_C_FRX_N1: length 110.8
  IN3 w0.135: v3(167.47,23.75) 167.76,24.04 168.87,24.04 169.73,23.18 171.35,23.18 175.59,27.41 175.59,38.24 174.58,39.25 174.58,40.48 173.69,41.37 173.69,44.96 174.3,45.57 174.3,51.76 177.57,55.03 177.57,67.31 175.56,69.32 175.56,90.28 175.28,90.55 175.28,91.55 174.77,92.05 174.77,96.3 171.81,99.26 170.69,99.26 168.1,101.85 168.1,103.09 167.49,103.7 165.49,103.7 164.47,102.69 164.11,102.69 163.95,102.85 163.95,102.99 v3(164.17,103.2)
  BOTTOM w0.102: CC87.2 155.33,104.2 157.66,101.86 163.13,101.86 163.98,102.71 163.98,103.01 v3(164.17,103.2) ; v3(167.47,23.75) 167.83,24.12 U2.AB29
UMI_ATX_C_FRX_N2: length 110.3
  IN3 w0.135: v3(172.66,23.13) 172.86,22.93 173.22,22.93 176.03,25.73 176.03,38.5 175.07,39.45 175.07,40.63 174.13,41.57 174.13,44.77 174.78,45.42 174.78,51.36 178.01,54.59 178.01,67.72 176.21,69.52 176.21,91.34 175.27,92.28 175.27,96.45 171.91,99.8 171.1,99.8 168.55,102.36 168.55,103.4 167.32,104.63 163.18,104.63 162.42,103.88 158.21,103.88 155.61,106.48 154.74,106.48 v3(154.64,106.38)
  BOTTOM w0.102: v3(154.64,106.38) 154.46,106.56 154.26,106.56 CC89.2 ; v3(172.66,23.13) 172.42,22.89 172.07,22.89 171.76,23.19 170.69,23.19 170.4,22.9 169.03,22.9 U2.Y31
UMI_ATX_C_FRX_N3: length 124.8
  IN3 w0.135: v3(154.77,108.28) 154.63,108.42 154.12,108.42 153.83,108.72 153.83,109.38 155.48,111.03 162.29,111.03 169.5,103.81 169.5,102.76 170.66,101.6 174.37,101.6 175.43,100.54 175.43,97.82 176.91,96.35 176.91,92.31 177.19,92.03 177.19,70.18 179.04,68.33 179.04,58.78 183.24,54.58 183.24,52.35 184,51.59 184,42.47 176.96,35.43 176.96,24.67 173.96,21.67 171.81,21.67 171.68,21.8 169.09,21.8 168.28,22.61 167.44,22.61 167.28,22.45 167.28,22.23 v3(167.46,22.05)
  BOTTOM w0.102: v3(154.77,108.28) 154.67,108.39 154.18,108.39 CC91.2 ; v3(167.46,22.05) 167.85,22.45 U2.Y29
UMI_ATX_C_FRX_P0: length 105.7
  IN3 w0.135: v3(170.14,24.08) 170.2,24.08 170.55,24.42 170.55,27.19 174.66,31.3 174.66,37.83 173.63,38.86 173.63,39.9 170.97,42.55 170.97,50.7 175.9,55.63 175.9,64.83 174.63,66.1 174.63,89.77 174.3,90.1 174.3,91.14 173.84,91.6 173.84,95.86 171.38,98.33 170.29,98.33 168.28,100.33 166.59,100.33 165.74,101.18 165.74,102.44 165.61,102.57 v3(165.49,102.57)
  BOTTOM w0.102: U2.AB33 169.3,23.97 169.3,23.89 169.64,23.55 170.14,23.55 170.39,23.8 170.39,23.98 170.3,24.08 v3(170.14,24.08) ; CC84.2 154.77,103.18 154.87,103.08 154.87,102.49 154.98,102.38 155.8,102.38 157.04,101.13 164.69,101.13 165.74,102.19 165.74,102.47 165.64,102.57 v3(165.49,102.57)
UMI_ATX_C_FRX_P1: length 110.8
  IN3 w0.135: v3(163.53,103.2) 163.71,103.03 163.71,102.75 164.01,102.44 164.57,102.44 165.59,103.46 167.39,103.46 167.86,102.99 167.86,101.75 170.59,99.01 171.71,99.01 174.53,96.19 174.53,91.95 175.04,91.44 175.04,90.45 175.32,90.17 175.32,69.22 177.32,67.21 177.32,55.13 174.06,51.86 174.06,45.67 173.45,45.06 173.45,41.27 174.34,40.38 174.34,39.15 175.34,38.14 175.34,27.51 171.25,23.42 169.83,23.42 168.97,24.29 167.77,24.29 v3(167.52,24.54)
  BOTTOM w0.102: v3(167.52,24.54) 167.1,24.12 U2.AB28 ; CC86.2 154.31,105.21 154.41,105.11 154.41,104.53 154.53,104.41 155.42,104.41 157.75,102.07 163.04,102.07 163.76,102.8 163.76,103.08 163.63,103.2 v3(163.53,103.2)
UMI_ATX_C_FRX_P2: length 110.3
  IN3 w0.135: v3(154.67,106.96) 154.91,106.72 155.71,106.72 158.31,104.12 162.32,104.12 163.07,104.87 167.42,104.87 168.79,103.5 168.79,102.46 171.2,100.04 172.01,100.04 175.51,96.55 175.51,92.38 176.45,91.44 176.45,69.63 178.25,67.82 178.25,54.49 175.03,51.26 175.03,45.32 174.38,44.67 174.38,41.68 175.32,40.74 175.32,39.55 176.27,38.6 176.27,25.63 173.33,22.69 172.85,22.69 v3(172.66,22.49)
  BOTTOM w0.102: CC88.2 154.27,106.77 154.48,106.77 v3(154.67,106.96) ; v3(172.66,22.49) 172.48,22.67 171.98,22.67 171.67,22.98 170.78,22.98 170.49,22.69 169.62,22.69 U2.Y33
UMI_ATX_C_FRX_P3: length 124.8
  IN3 w0.135: v3(154.77,108.87) 154.57,108.67 154.22,108.67 154.07,108.82 154.07,109.28 155.58,110.78 162.19,110.78 169.26,103.71 169.26,102.66 170.56,101.36 174.27,101.36 175.19,100.44 175.19,97.72 176.66,96.24 176.66,92.21 176.94,91.93 176.94,70.08 178.8,68.23 178.8,58.68 183,54.48 183,52.25 183.76,51.49 183.76,42.57 176.71,35.53 176.71,24.77 173.86,21.91 171.91,21.91 171.79,22.04 169.19,22.04 168.38,22.85 167.34,22.85 167.04,22.55 167.04,22.15 166.94,22.05 v3(166.64,22.05)
  BOTTOM w0.102: U2.Y28 166.91,22.66 166.69,22.66 166.45,22.42 166.45,22.25 v3(166.64,22.05) ; v3(154.77,108.87) 154.5,108.6 154.02,108.6 153.93,108.69 CC90.2
UMI_ATX_FRX_N0: length 6.5
  BOTTOM w0.102: CC85.1 152.6,102.96 v2(151.86,102.96) 151,102.96 149.95,101.92 148.68,101.92 148.52,101.76 147.99,101.76 147.9,101.67 UC1.AM10
UMI_ATX_FRX_N1: length 5.8
  BOTTOM w0.102: CC87.1 152.65,104.56 v2(151.9,104.56) 151.63,104.56 149.73,102.66 149.42,102.66 149.2,102.43 148.43,102.43 UC1.AN9
UMI_ATX_FRX_N2: length 7.5
  BOTTOM w0.102: CC89.1 152.66,106.23 152.56,106.33 152.56,106.7 152.43,106.82 152.16,106.82 151.75,106.4 151.75,106.39 151.77,106.36 151.77,105.76 151.75,105.74 151.75,105.72 149.5,103.47 148.63,103.47 148.53,103.37 148.17,103.37 UC1.AM8
UMI_ATX_FRX_N3: length 7.7
  BOTTOM w0.102: CC91.1 152.13,108.13 150.93,106.94 150.93,105.85 149.16,104.07 148.57,104.07 148.49,104.15 147.94,104.7 UC1.AM6
UMI_ATX_FRX_P0: length 6.6
  BOTTOM w0.102: UC1.AM9 147.84,101.96 148.42,101.96 148.6,102.14 149.87,102.14 150.91,103.18 151.58,103.18 151.59,103.19 152.13,103.19 152.14,103.18 CC84.1
UMI_ATX_FRX_P1: length 5.8
  BOTTOM w0.102: UC1.AN8 148.67,103.07 148.67,102.76 148.79,102.65 149.11,102.65 149.34,102.87 149.64,102.87 151.54,104.78 151.59,104.78 151.6,104.79 152.2,104.79 152.21,104.78 152.58,104.78 CC86.1
UMI_ATX_FRX_P2: length 7.5
  BOTTOM w0.102: CC88.1 152.94,107.04 152.08,107.04 151.54,106.51 v2(151.54,106.06) 151.54,105.82 149.41,103.69 148.54,103.69 148.44,103.59 147.81,103.59 UC1.AM7
UMI_ATX_FRX_P3: length 7.7
  BOTTOM w0.102: CC90.1 152.63,109.02 152.51,108.89 152.51,108.51 152.34,108.35 152.04,108.35 150.72,107.03 150.72,105.94 149.07,104.28 148.66,104.28 148.65,104.3 148.55,104.4 148.55,104.55 UC1.AN6
UMI_FTX_ARX_N0: length 10.4
  BOTTOM w0.102: U2.AE32 169.28,26.75 170.07,26.75 170.82,27.5 170.82,33.22 170.19,33.85 170.19,34.32 170.34,34.48 170.75,34.48 170.87,34.6 CH1.2
UMI_FTX_ARX_N1: length 11.4
  BOTTOM w0.102: CH2.2 172.01,33.48 171.6,33.06 v2(171.6,27.94) 171.6,27.48 170.43,26.31 169.73,26.31 169.49,26.06 169,26.06 U2.AD31
UMI_FTX_ARX_N2: length 9.7
  BOTTOM w0.102: CH3.2 173.36,28.33 173.49,28.2 174,28.2 174.08,28.11 174.08,27.93 173.41,27.26 172.42,27.26 v2(171.38,26.22) 170.77,25.61 169.98,25.61 169.71,25.34 169.38,25.34 169.27,25.45 168.83,25.45 168.83,25.45 168.77,25.39 168.53,25.39 168.47,25.45 168.46,25.45 168.46,25.45 168.04,25.45 168.04,25.45 168.03,25.45 167.93,25.35 167.68,25.35 167.51,25.52 167.51,25.62 167.61,25.72 U2.AD29
UMI_FTX_ARX_N3: length 5.3
  BOTTOM w0.102: CH5.2 173.21,25.71 172.98,25.71 172.83,25.56 172.83,24.85 172.71,24.73 171.82,24.73 171.81,24.74 171.27,24.74 171.26,24.73 169.14,24.73 169.05,24.81 U2.AC32
UMI_FTX_ARX_P0: length 10.4
  BOTTOM w0.102: U2.AE30 168.46,26.52 168.9,26.97 169.98,26.97 170.61,27.59 170.61,33.13 169.98,33.75 CH7.2
UMI_FTX_ARX_P1: length 11.4
  BOTTOM w0.102: U2.AD33 169.82,26.09 170.52,26.09 171.81,27.39 171.81,27.67 171.82,27.68 171.82,28.21 171.81,28.22 171.81,32.97 172.23,33.39 172.23,34.33 172.37,34.48 172.8,34.48 172.9,34.58 CH8.2
UMI_FTX_ARX_P2: length 9.7
  BOTTOM w0.102: CH9.2 174.3,27.84 173.49,27.03 v2(173.02,27.03) 172.5,27.03 171.74,26.27 171.74,26.24 171.34,25.85 171.32,25.85 170.86,25.39 170.07,25.39 169.8,25.12 169.31,25.12 169.18,25.24 168.92,25.24 168.86,25.18 168.44,25.18 168.38,25.24 168.12,25.24 168.02,25.15 167.6,25.15 167.3,25.44 167.3,25.62 167.2,25.72 U2.AD28
UMI_FTX_ARX_P3: length 5.3
  BOTTOM w0.102: U2.AC30 168.66,24.51 v2(171.54,24.51) 173.15,24.51 CH4.2
UMI_FTX_C_ARX_N0: length 91.4
  IN3 w0.135: v3(169.95,38.49) 169.74,38.7 169.74,39.87 168.45,41.16 168.45,55.07 169.02,55.64 169.02,59.43 169.82,60.23 169.82,89.92 167.36,92.38 167.36,94.64 166.07,95.93 165.33,95.93 160.48,100.78 157.16,100.78 154.96,102.98 149.7,102.98 148.61,101.88 147.31,101.88 147.11,101.68 146.64,101.68 145.48,102.84 144.85,102.84 144.58,103.1 144.58,103.73 144.72,103.86 144.9,103.86 145.02,103.72 v3(145.02,103.41)
  BOTTOM w0.102: CH1.1 170.77,35.89 170.3,36.36 170.3,36.59 169.72,37.18 169.72,38.26 v3(169.95,38.49) ; v3(145.02,103.41) 145.02,103.18 UC1.AJ8
UMI_FTX_C_ARX_N1: length 91.1
  IN3 w0.135: v3(146.7,104.3) 146.6,104.4 146.4,104.4 146.29,104.29 146.29,103.73 146.72,103.31 148.42,103.31 148.81,103.7 155.28,103.7 157.51,101.47 160.81,101.47 165.59,96.69 166.35,96.69 168.12,94.92 168.12,92.82 170.58,90.35 170.58,60.95 170.99,60.54 170.99,55.11 169.13,53.26 169.13,41.71 171.23,39.62 171.23,37.62 170.97,37.37 170.67,37.37 v3(170.49,37.19)
  BOTTOM w0.102: CH2.1 172.01,36.76 171.48,37.29 170.59,37.29 v3(170.49,37.19) ; v3(146.7,104.3) 146.7,104.3 UC1.AK7
UMI_FTX_C_ARX_N2: length 101.8
  IN3 w0.135: v3(145.76,105.74) 145.93,105.74 146.09,105.58 146.09,105.44 146.09,105.18 146.34,104.93 148.8,104.93 149.33,104.4 155.23,104.4 157.71,101.91 161.09,101.91 162.68,100.32 164.62,100.32 167.68,97.26 168.84,97.26 172.47,93.63 172.47,92.71 172.23,92.47 172.23,65.78 174.41,63.6 174.41,56.17 169.58,51.34 169.58,41.97 171.86,39.68 171.86,39.12 v3(171.68,38.94)
  BOTTOM w0.102: UC1.AJ5 145.5,105.48 v3(145.76,105.74) ; CH3.1 173.73,29.96 173.73,36.01 171.86,37.87 171.86,38.82 171.74,38.94 v3(171.68,38.94)
UMI_FTX_C_ARX_N3: length 110.8
  IN3 w0.135: v3(173.48,37.4) 173.65,37.23 173.65,36.94 173.42,36.71 173.11,36.71 172.7,37.11 172.7,37.58 173.18,38.06 173.18,39.69 170.51,42.37 170.51,50.95 175.36,55.8 175.36,64.44 173.63,66.17 173.63,89.62 173.4,89.84 173.4,94.24 167.75,99.89 166.38,99.89 165,101.26 163.2,101.26 161.6,102.86 158.12,102.86 155.63,105.35 151.29,105.35 149,107.64 146.71,107.64 146.35,107.28 146.35,106.9 146.18,106.73 v3(145.84,106.73)
  BOTTOM w0.102: CH5.1 174.61,25.23 174.71,25.23 174.83,25.35 174.83,35.84 173.67,37.01 173.67,37.22 v3(173.48,37.4) ; UC1.AK4 146.27,106.3 v3(145.84,106.73)
UMI_FTX_C_ARX_P0: length 91.4
  IN3 w0.135: v3(169.36,38.49) 169.5,38.63 169.5,39.77 168.2,41.06 168.2,55.17 168.77,55.74 168.77,59.53 169.58,60.33 169.58,89.82 167.11,92.28 167.11,94.54 165.97,95.69 165.23,95.69 160.38,100.54 157.05,100.54 154.86,102.73 149.8,102.73 148.71,101.64 147.41,101.64 147.21,101.44 146.54,101.44 145.38,102.59 144.75,102.59 144.34,103 144.34,103.83 144.62,104.11 144.99,104.11 145.1,104.2 v3(145.1,104.52)
  BOTTOM w0.102: UC1.AJ7 145.1,104.3 v3(145.1,104.52) ; CH7.1 170.08,36 170.08,36.5 169.5,37.09 169.5,38.36 v3(169.36,38.49)
UMI_FTX_C_ARX_P1: length 91.1
  IN3 w0.135: v3(170.49,37.8) 170.68,37.61 170.87,37.61 170.98,37.72 170.98,39.52 168.89,41.61 168.89,53.36 170.74,55.21 170.74,60.44 170.34,60.85 170.34,90.25 167.87,92.71 167.87,94.82 166.25,96.45 165.49,96.45 160.71,101.22 157.41,101.22 155.17,103.46 148.92,103.46 148.52,103.06 146.62,103.06 146.05,103.63 146.05,104.18 v3(145.85,104.37)
  BOTTOM w0.102: v3(145.85,104.37) 146.18,104.7 UC1.AK6 ; v3(170.49,37.8) 170.78,37.51 171.57,37.51 172.23,36.85 172.23,36.57 CH8.1
UMI_FTX_C_ARX_P2: length 101.8
  IN3 w0.135: v3(146.78,105.82) 146.51,105.82 146.34,105.64 146.34,105.54 146.34,105.54 146.34,105.28 146.44,105.18 148.9,105.18 149.43,104.64 155.33,104.64 157.82,102.15 161.19,102.15 162.78,100.56 164.73,100.56 167.78,97.5 168.94,97.5 172.72,93.73 172.72,92.61 172.47,92.37 172.47,65.88 174.66,63.7 174.66,56.07 169.82,51.24 169.82,42.07 172.11,39.78 172.11,39.12 v3(172.29,38.94)
  BOTTOM w0.102: CH9.1 173.95,29.95 173.95,36.1 172.08,37.96 172.08,38.73 v3(172.29,38.94) ; v3(146.78,105.82) 146.62,105.82 UC1.AK5
UMI_FTX_C_ARX_P3: length 110.7
  IN3 w0.135: v3(146.73,106.68) 146.72,106.68 146.59,106.81 146.59,107.18 146.81,107.4 148.9,107.4 151.19,105.11 155.53,105.11 158.02,102.62 161.5,102.62 163.1,101.02 164.9,101.02 166.27,99.65 167.65,99.65 173.16,94.14 173.16,89.74 173.39,89.51 173.39,66.07 175.11,64.34 175.11,55.9 170.26,51.05 170.26,42.27 172.94,39.59 172.94,38.17 172.46,37.68 172.46,37.01 173.01,36.46 173.52,36.46 173.89,36.83 173.89,37.2 v3(174.09,37.4)
  BOTTOM w0.102: v3(146.73,106.68) 147.1,106.31 UC1.AL4 ; v3(174.09,37.4) 174.06,37.4 173.88,37.23 173.88,37.1 175.05,35.93 175.05,25.26 174.8,25.01 174.57,25.01 CH4.1
USB2P0_N3: length 158.3
  IN3 w0.135: v3(28.71,50.98) 28.58,50.86 28.58,45.14 32.47,41.25 44.68,41.25 45.51,42.07 46.79,42.07 48.6,40.26 48.6,35.13 53.52,30.21 68.12,30.21 70,28.33 75.11,28.33 75.44,28 78.01,28 80.91,25.1 87.08,25.1 87.36,25.38 97.57,25.38 98.02,24.93 101.85,24.93 103.58,23.2 106.22,23.2 107.87,21.55 110.79,21.55 112.27,20.07 113.28,19.06 119.01,19.06 121.22,16.84 121.93,16.84 123.37,15.4 124.69,15.4 127.05,13.04 131.09,13.04 132.98,11.15 137.39,11.15 138.5,10.04 138.93,10.04 139.49,10.6 144.07,10.6 144.58,10.1 145.26,10.1 145.73,9.62 145.73,9.17 v3(145.85,9.05)
  BOTTOM w0.102: v3(145.85,9.05) 145.71,9.19 145.71,9.47 145.98,9.73 146.1,9.86 146.74,9.86 U2.E3 ; LI7.1 32.17,57.86 33.85,56.18 33.85,53.82 32.5,52.47 29.33,52.47 28.52,51.66 28.52,51.17 v3(28.71,50.98)
USB2P0_P3: length 158.3
  IN3 w0.135: v3(28.07,50.98) 28.29,50.76 28.29,45.02 32.35,40.97 44.8,40.97 45.62,41.79 46.67,41.79 48.31,40.14 48.31,35.01 53.4,29.93 68,29.93 69.88,28.05 74.99,28.05 75.32,27.71 77.89,27.71 80.79,24.81 87.2,24.81 87.48,25.09 97.45,25.09 97.9,24.64 101.73,24.64 103.46,22.92 106.1,22.92 107.75,21.26 110.67,21.26 113.16,18.77 118.89,18.77 121.1,16.56 121.81,16.56 123.25,15.12 124.57,15.12 126.93,12.76 130.97,12.76 132.86,10.87 137.28,10.87 138.39,9.76 139.05,9.76 139.6,10.32 143.95,10.32 144.46,9.81 145.14,9.81 145.45,9.5 145.45,9.17 145.32,9.05 v3(145.14,9.05)
  BOTTOM w0.102: LI7.4 31.31,57.06 31.43,57.19 31.43,57.49 31.53,57.59 32.06,57.59 33.58,56.07 33.58,53.93 32.39,52.73 v2(30.94,52.73) 29.22,52.73 28.25,51.77 28.25,51.16 v3(28.07,50.98) ; v3(145.14,9.05) 145.37,9.05 145.45,9.12 145.45,9.58 145.71,9.85 145.71,9.85 145.99,10.13 146.35,10.13 146.41,10.19 146.41,10.31 U2.E1
USB2P10_N2: length 73.9
  IN1 w0.114: v3(154.04,13.84) 153.89,13.99 153.42,13.99 152.81,14.61 152.81,16.44 152.69,16.57 152.69,22.06 153.02,22.39 153.02,28.1 156.59,31.67 156.59,33.83 158.35,35.59 159.23,35.59 159.82,36.17 160.91,36.17 162.62,37.88 169.21,37.88 170.77,36.33 177.34,36.33 183.01,41.99 183.01,47.85 184.95,49.8 186.32,49.8 187.2,48.91 187.2,44.76 186.62,44.17 186.29,44.17 v3(186.11,44)
  BOTTOM w0.102: v3(154.04,13.84) 154.27,13.84 U2.K13 ; LI5.1 187.46,43.22 v2(187,43.67) 186.53,44.14 186.25,44.14 v3(186.11,44)
USB2P10_N2_R: length 15.4
  IN1 w0.114: JUSB2.2 198.44,46.89 197.04,46.89 196.08,45.93 196.08,42.93 195.36,42.22 192.87,42.22 192.46,42.63 192.46,43.14 v3(192.28,43.31)
  BOTTOM w0.102: v3(192.28,43.31) 192.28,42.5 DI5.2 191.2,43.38 190.77,43.38 190.6,43.22 LI5.2
USB2P10_P2: length 73.8
  IN1 w0.114: v3(154,14.54) 154,14.34 153.88,14.23 153.52,14.23 153.04,14.71 153.04,16.54 152.92,16.66 152.92,21.96 153.25,22.29 153.25,28 156.83,31.57 156.83,33.74 158.44,35.35 159.33,35.35 159.92,35.94 161.01,35.94 162.72,37.65 169.12,37.65 170.67,36.09 177.44,36.09 183.24,41.89 183.24,47.75 185.05,49.56 186.22,49.56 186.97,48.81 186.97,44.85 186.53,44.41 186.16,44.41 186.04,44.53 186.04,44.68 v3(186.11,44.76)
  BOTTOM w0.102: v3(154,14.54) 154,14.67 153.9,14.76 153.47,14.76 153.35,14.63 153.35,14.47 U2.K12 ; LI5.4 187.83,44.02 187.74,43.92 187.74,43.57 187.65,43.48 187.57,43.48 187.19,43.86 186.65,44.4 186.19,44.4 186.04,44.56 186.04,44.68 v3(186.11,44.76)
USB2P10_P2_R: length 15.4
  IN1 w0.114: v3(192.87,43.31) 192.69,43.14 192.69,42.73 192.97,42.46 195.26,42.46 195.84,43.03 195.84,46.03 196.94,47.13 198.49,47.13 199.29,47.93 JUSB2.3
  BOTTOM w0.102: LI5.3 190.6,44.02 190.97,43.65 191.5,43.65 DI5.3 192.87,43.64 v3(192.87,43.31)
USB2P13_N1: length 80.5
  IN1 w0.114: v3(193.71,58.32) 193.56,58.18 192.49,58.18 191.48,57.16 183.86,57.16 182.94,56.24 178.69,56.24 174.11,51.66 174.11,50.69 160.36,36.94 159.49,36.94 158.9,36.35 157.81,36.35 149.3,27.84 149.3,27.08 147.34,25.12 147.34,15.07 149.34,13.08 151.35,13.08 151.75,12.68 152.57,12.68 v3(152.74,12.51)
  BOTTOM w0.102: U2.G10 152.24,12.02 v3(152.74,12.51) ; v3(193.71,58.32) 193.85,58.18 194.25,58.18 194.49,58.42 194.49,58.67 194.22,58.94 LI2.4
USB2P13_N1_R: length 12.4
  TOP w0.102: JUSB1.2 199.29,64.65 198.66,65.28 197.55,65.28 196.86,65.97 195.96,65.97 195.39,65.39 195.39,65.03 195.49,64.93 DI2.3 195.39,64.09 195.39,63.15 194.67,62.44 193.94,62.44 v3(193.76,62.26)
  BOTTOM w0.102: v3(193.76,62.26) 193.94,62.44 194.27,62.44 194.49,62.22 194.49,62.09 194.22,61.82 LI2.3
USB2P13_P1: length 80.5
  IN1 w0.114: v3(152.74,13.31) 152.74,13.11 152.54,12.92 151.84,12.92 151.44,13.31 149.43,13.31 147.58,15.17 147.58,25.02 149.54,26.98 149.54,27.74 157.91,36.12 159,36.12 159.59,36.7 160.45,36.7 174.34,50.59 174.34,51.56 178.79,56 183.04,56 183.96,56.93 191.58,56.93 192.59,57.94 193.51,57.94 v3(193.71,57.74)
  BOTTOM w0.102: LI2.1 195.02,58.94 194.75,58.67 194.75,58.31 194.36,57.92 193.88,57.92 v3(193.71,57.74) ; v3(152.74,13.31) 152.74,13.19 152.37,12.82 U2.H10
USB2P13_P1_R: length 12.4
  TOP w0.102: v3(193.78,62.87) 193.95,62.7 194.56,62.7 195.12,63.26 195.12,64.09 DI2.2 195.02,64.93 195.12,65.03 195.12,65.5 195.85,66.23 196.97,66.23 197.66,65.55 198.59,65.55 JUSB1.3
  BOTTOM w0.102: LI2.2 195.02,61.82 194.75,62.09 194.75,62.33 194.38,62.7 193.95,62.7 v3(193.78,62.87)
USB3P0RN2: length 63.1
  IN1 w0.114: v3(156.37,13.94) 156.13,14.18 156.13,16.02 156.24,16.13 156.24,18.39 155.3,19.33 155.3,21.19 155.1,21.4 155.1,25.07 154.95,25.23 154.95,26.98 155.92,27.95 155.92,29.15 158.65,31.88 158.65,33.13 160.4,34.87 162.41,34.87 163.15,35.62 169.6,35.62 170.27,34.95 178.03,34.95 184.54,41.46 184.54,45.57 185.71,46.75 185.71,48.3 185.88,48.47 v3(186.11,48.47)
  BOTTOM w0.102: v3(156.37,13.94) 156,14.31 U2.K15 ; v3(186.11,48.47) 185.88,48.47 185.77,48.35 185.77,48.03 186.04,47.76 187.52,47.76 187.83,48.08 LI4.1
USB3P0RN2_R: length 12.7
  BOTTOM w0.102: LI4.2 190.6,48.08 190.87,47.81 v2(191.43,47.81) 192.39,47.81 192.5,47.92 DI4.10 DI4.1 194.57,47.92 194.67,47.82 196.75,47.82 198.52,49.6 199.54,49.6 200.1,50.16 200.5,50.16 200.79,50.45 JUSB2.5
USB3P0RP2: length 63.2
  IN1 w0.114: v3(155.61,13.95) 155.9,14.24 155.9,16.12 156.01,16.23 156.01,18.3 155.07,19.24 155.07,21.09 154.86,21.3 154.86,24.98 154.71,25.13 154.71,27.08 155.68,28.05 155.68,29.24 158.42,31.98 158.42,33.22 160.3,35.11 162.31,35.11 163.05,35.85 169.7,35.85 170.37,35.18 177.93,35.18 184.3,41.56 184.3,45.67 185.48,46.85 185.48,48.31 v3(185.32,48.47)
  BOTTOM w0.102: LI4.4 187.72,47.28 187.5,47.5 185.93,47.5 185.5,47.92 185.5,48.28 v3(185.32,48.47) ; U2.J15 156,13.56 v3(155.61,13.95)
USB3P0RP2_R: length 12.7
  BOTTOM w0.102: JUSB2.6 200.79,49.61 200.51,49.89 200.21,49.89 199.65,49.33 198.63,49.33 196.86,47.55 v2(195.28,47.55) 194.67,47.55 194.54,47.42 DI4.2 DI4.9 192.47,47.42 192.34,47.55 190.87,47.55 190.6,47.28 LI4.3
USB3P0TN2: length 61
  IN1 w0.114: v3(157.78,12.39) 157.78,12.43 157.62,12.6 157.29,12.6 157.05,12.83 157.05,13.44 157.94,14.33 157.94,17.88 156.14,19.69 156.14,21.7 155.99,21.85 155.99,22.84 156.67,23.52 156.67,25.78 157.22,26.34 157.22,29.11 159.51,31.39 159.51,32.81 160.66,33.96 162.72,33.96 163.54,34.78 168.99,34.78 169.66,34.12 178.7,34.12 185.62,41.04 185.62,42.71 v3(185.48,42.85)
  BOTTOM w0.102: U2.H16 157.45,12.72 v3(157.78,12.39) ; v3(185.48,42.85) 185.62,42.98 185.62,43.28 184.5,44.39 184.5,45.68 185.04,46.22 185.46,46.22 CI10.2
USB3P0TN2_C: length 2
  BOTTOM w0.102: CI10.1 186.94,46.04 187.45,46.04 187.72,46.3 LI6.1
USB3P0TN2_R: length 12.7
  BOTTOM w0.102: LI6.2 190.39,46.3 190.66,46.04 191,46.04 191.26,46.3 192.37,46.3 192.5,46.42 DI4.7 DI4.4 194.51,46.42 194.63,46.3 v2(196.7,46.3) 197.35,46.3 198.86,44.78 199.7,44.78 200.32,44.16 200.54,44.16 200.79,44.41 JUSB2.8
USB3P0TP2: length 61
  IN1 w0.114: v3(186.09,42.85) 186.03,42.85 185.86,42.68 185.86,40.95 178.79,33.88 169.56,33.88 168.89,34.55 163.64,34.55 162.82,33.73 160.76,33.73 159.75,32.72 159.75,31.29 157.46,29.01 157.46,26.24 156.9,25.68 156.9,23.42 156.22,22.74 156.22,21.95 156.38,21.8 156.38,19.78 158.18,17.98 158.18,14.23 157.28,13.34 157.28,12.93 157.38,12.83 157.64,12.83 157.78,12.97 v3(157.78,13.19)
  BOTTOM w0.102: v3(186.09,42.85) 185.97,42.85 185.88,42.93 185.88,43.39 184.77,44.51 v2(184.77,44.81) 184.77,45.57 185.15,45.95 185.53,45.95 185.65,45.83 CI11.2 ; v3(157.78,13.19) 157.44,13.19 157.25,13.37 U2.J16
USB3P0TP2_C: length 2
  BOTTOM w0.102: CI11.1 186.94,45.77 187.45,45.77 187.72,45.5 LI6.4
USB3P0TP2_R: length 12.7
  BOTTOM w0.102: JUSB2.9 200.79,43.7 200.59,43.9 200.21,43.9 199.59,44.52 198.75,44.52 197.24,46.03 194.65,46.03 194.54,45.92 DI4.5 DI4.6 192.5,45.92 192.39,46.03 v2(191.62,46.03) 191.37,46.03 191.11,45.77 190.66,45.77 190.4,45.5 LI6.3
USB3P3RN1: length 108.1
  IN1 w0.114: v3(153.97,7.5) 153.51,7.95 153.21,7.95 152.43,8.74 150.2,8.74 149.74,9.2 148.42,9.2 145.63,11.99 145.29,11.99 144.56,12.73 144.56,14.71 144.86,15.02 144.86,19 144.56,19.31 144.56,26 146.64,28.08 146.64,29.69 149.56,32.61 151.2,32.61 154.38,35.79 154.51,35.79 157.48,38.76 158.6,38.76 158.68,38.84 159.55,38.84 163.67,42.96 163.67,44.92 165.32,46.57 165.32,47.53 171.55,53.77 173.28,53.77 177.78,58.26 182.14,58.26 183.27,59.39 183.88,59.39 186.5,62.01 186.5,62.19 187.03,62.72 187.03,65.61 193.99,72.57 196.04,72.57 196.68,71.93 196.68,71.04 196.93,70.79 196.93,70.01 197.03,69.91 v3(197.39,69.91)
  BOTTOM w0.102: v3(197.39,69.91) 197.49,70.01 197.49,70.11 197.38,70.22 196.92,70.22 196.39,69.7 196.39,69.35 196.48,69.26 196.86,69.26 196.93,69.19 LI1.1 ; U2.A12 153.82,8.49 153.82,7.65 153.82,7.65 v3(153.97,7.5)
USB3P3RN1_R: length 12.2
  BOTTOM w0.102: JUSB1.5 200.79,68.45 200.53,68.19 199.97,68.19 199.61,67.84 198.98,67.84 197.35,66.21 197.35,63.54 197.26,63.45 196.75,63.45 196.63,63.58 196.63,63.68 196.76,63.82 DI1.1 DI1.10 196.76,65.76 196.66,65.86 196.66,66.25 196.93,66.52 LI1.2
USB3P3RP1: length 108.1
  IN1 w0.114: v3(197.41,70.64) 196.91,71.14 196.91,72.03 196.14,72.81 193.89,72.81 186.79,65.71 186.79,62.81 186.26,62.29 186.26,62.11 183.78,59.63 183.17,59.63 182.04,58.5 177.68,58.5 173.18,54 171.46,54 165.08,47.63 165.08,46.66 163.43,45.01 163.43,43.06 159.45,39.08 158.58,39.08 158.5,38.99 157.38,38.99 154.41,36.02 154.28,36.02 151.11,32.85 149.46,32.85 146.4,29.79 146.4,28.18 144.32,26.09 144.32,19.21 144.63,18.91 144.63,15.11 144.32,14.81 144.32,12.63 145.2,11.76 145.53,11.76 148.32,8.96 149.64,8.96 150.1,8.51 152.33,8.51 v3(153.34,7.5)
  BOTTOM w0.102: v3(197.41,70.64) 197.26,70.49 196.81,70.49 196.13,69.81 LI1.4 ; v3(153.34,7.5) 153.55,7.71 153.55,8.72 153.9,9.07 U2.C12
USB3P3RP1_R: length 12.2
  BOTTOM w0.102: LI1.3 196.13,66.52 196.39,66.25 196.39,65.87 196.26,65.74 DI1.9 DI1.2 196.26,63.82 196.36,63.72 196.36,63.47 196.64,63.19 197.37,63.19 197.62,63.43 v2(197.62,65.14) 197.62,66.1 199.09,67.57 199.72,67.57 200.08,67.92 200.49,67.92 200.79,67.62 JUSB1.6
USB3P3TN1: length 103.1
  IN1 w0.114: v3(155.9,8.09) 155.72,8.27 155.72,8.71 154.61,9.82 150.62,9.82 149.77,10.67 148.67,10.67 148.14,11.2 148.14,12.45 146.44,14.16 146.44,25.61 148.09,27.26 148.09,29.49 149.49,30.89 151.11,30.89 157.89,37.66 159.03,37.66 159.13,37.77 160,37.77 166.53,44.3 166.53,46.94 172.24,52.65 173.91,52.65 178.36,57.1 182.52,57.1 183.55,58.12 191.24,58.12 194.86,61.73 194.86,71.59 v3(195.02,71.75)
  BOTTOM w0.102: v3(155.9,8.09) 155.86,8.12 155.86,9.01 U2.C14 ; CI3.2 194.98,71.28 194.98,71.71 v3(195.02,71.75)
USB3P3TN1_C: length 1.8
  BOTTOM w0.102: LI3.1 195.15,69.16 194.88,69.43 194.88,69.71 CI3.1
USB3P3TN1_R: length 11.2
  BOTTOM w0.102: JUSB1.8 200.79,62.36 200.67,62.23 200.41,62.23 199.79,62.86 198.09,62.86 197.77,62.54 v2(197.53,62.54) 195.89,62.54 195.13,63.3 195.13,63.63 195.26,63.77 DI1.4 DI1.7 195.26,65.66 195.15,65.77 195.15,66.02 194.86,66.31 194.86,66.41 195.15,66.7 LI3.2
USB3P3TP1: length 103
  IN1 w0.114: v3(155.26,8.09) 155.48,8.3 155.48,8.61 154.51,9.58 150.53,9.58 149.68,10.43 148.57,10.43 147.9,11.1 147.9,12.36 146.2,14.06 146.2,25.71 147.85,27.36 147.85,29.59 149.39,31.13 151.02,31.13 157.79,37.9 158.93,37.9 159.03,38 159.9,38 166.29,44.4 166.29,47.04 172.14,52.89 173.81,52.89 178.26,57.33 182.42,57.33 183.45,58.36 191.14,58.36 194.62,61.83 194.62,71.61 194.48,71.75 v3(194.35,71.75)
  BOTTOM w0.102: v3(155.26,8.09) 155.28,8.09 155.59,8.4 155.59,8.48 U2.A14 ; CI4.2 194.29,70.95 194.65,70.95 194.77,71.07 194.77,71.4 194.75,71.42 194.75,71.43 194.43,71.75 v3(194.35,71.75)
USB3P3TP1_C: length 1.8
  BOTTOM w0.102: CI4.1 194.61,69.71 194.61,69.43 194.35,69.16 LI3.4
USB3P3TP1_R: length 11.3
  BOTTOM w0.102: LI3.3 194.35,66.67 194.6,66.43 194.6,66.2 194.88,65.91 194.88,65.79 194.76,65.67 DI1.6 DI1.5 194.76,63.76 194.86,63.66 194.86,63.19 195.78,62.27 v2(196.22,62.27) 197.88,62.27 198.2,62.59 199.68,62.59 200.3,61.97 200.5,61.97 200.79,61.68 JUSB1.9
USB20_CAM_N7_R: length 2.9
  TOP w0.102: RX21.2 4.05,85.35 LX6.2 3.59,85.46 3.3,85.75 2.98,85.75 v3(2.85,85.63)
  BOTTOM w0.102: JEDP.28 2.34,85.5 2.57,85.73 2.75,85.73 v3(2.85,85.63)
USB20_CAM_P7_R: length 2.9
  TOP w0.102: v3(2.85,86.21) 3.04,86.02 3.27,86.02 3.5,86.26 LX6.3 4.05,86.36 RX22.2
  BOTTOM w0.102: v3(2.85,86.21) 2.64,86 JEDP.27
USB20_CR_N6_R: length 3.8
  BOTTOM w0.102: JIO.12 26.18,54.95 26.55,54.58 v2(27.68,54.58) 28.44,54.58 28.74,54.87 LI8.2
USB20_CR_P6_R: length 3.8
  BOTTOM w0.102: LI8.3 28.71,54.07 28.48,54.31 26.55,54.31 26.18,53.95 JIO.11
USB20_JUSB3_N2_R: length 3.8
  BOTTOM w0.102: LI7.2 28.65,57.86 28.37,57.58 v2(27.7,57.58) 26.55,57.58 26.18,57.95 JIO.15
USB20_JUSB3_P2_R: length 3.8
  BOTTOM w0.102: LI7.3 28.65,57.06 28.4,57.31 26.55,57.31 26.18,56.95 JIO.14
USB20_MINI_N1: length 75.2
  IN1 w0.114: v3(144.2,7.73) 144.35,7.88 144.68,7.88 144.91,8.11 144.91,8.64 144.63,8.92 144.63,10.61 143.41,11.83 143.41,16.11 142.12,17.4 142.12,18.39 143.12,19.39 143.12,20.55 142.8,20.86 142.8,27.36 150.93,35.49 150.93,36.71 151.59,37.37 154.46,37.37 156.92,39.82 158.04,39.82 158.12,39.91 158.78,39.91 161.01,42.14 161.29,42.14 162.58,43.43 162.58,46.42 171.08,54.92 172.78,54.92 173.34,55.49 173.34,56.06 v3(173.54,56.26)
  BOTTOM w0.102: v1(144.14,5.47) 144.2,5.53 v3(144.2,7.73) 144.33,7.85 145.75,7.85 147.06,9.16 147.06,9.34 147.19,9.47 U2.C3 ; JNGFF.5 173.48,57.02 173.38,56.93 173.38,56.42 v3(173.54,56.26)
USB20_MINI_P1: length 72.9
  IN1 w0.114: v3(172.83,56.26) 172.98,56.26 173.11,56.14 173.11,55.58 172.68,55.16 170.98,55.16 162.35,46.52 162.35,43.53 161.19,42.37 160.91,42.37 158.68,40.14 158.02,40.14 157.94,40.06 156.82,40.06 154.37,37.6 151.5,37.6 150.7,36.81 150.7,35.59 142.57,27.46 142.57,20.76 142.88,20.45 142.88,19.49 141.88,18.49 141.88,17.31 143.18,16.01 143.18,11.73 144.4,10.52 144.4,8.83 144.68,8.55 144.68,8.2 144.59,8.11 144.35,8.11 144.2,8.26 v3(144.2,8.39)
  BOTTOM w0.102: U2.C1 146.68,9.47 146.79,9.35 146.79,9.27 145.64,8.12 144.32,8.12 144.2,8.23 v3(144.2,8.39) ; JNGFF.3 172.98,57.01 173.12,56.86 173.12,56.39 172.99,56.26 v3(172.83,56.26)
USB20_N6: length 150.5
  IN3 w0.135: v3(32.34,54.77) 32.2,54.62 31.76,54.62 31.37,54.23 31.37,53.4 32.04,52.73 45.88,52.73 47.1,51.52 47.1,44.28 50.42,40.96 50.42,35.34 52.76,33 54.61,33 55.16,33.55 63.21,33.55 64.7,32.06 69.04,32.06 69.68,31.42 75.19,31.42 76.43,30.18 80.27,30.18 81.44,29.01 82.73,29.01 83.75,28 86.16,28 87.38,26.78 98.69,26.78 99.09,26.37 102.93,26.37 104.33,24.96 107.01,24.96 107.91,25.86 109.12,25.86 114.48,20.5 119.74,20.5 119.93,20.32 122.04,20.32 123.2,19.15 125.03,19.15 127,17.18 127,16.73 128.31,15.41 132.98,15.41 135.14,13.26 139.03,13.26 139.66,12.62 143.03,12.62 143.11,12.7 144.02,12.7 144.58,12.15 146.59,12.15 146.95,11.78 148.84,11.78 149.13,12.07 150.15,12.07 150.48,11.73 150.89,11.73 v3(151,11.62)
  BOTTOM w0.102: v3(32.34,54.77) 32.23,54.87 LI8.1 ; v3(151,11.62) U2.G9
USB20_N9: length 202.7
  TOP w0.102: v3(6.15,81.97) 6.41,82.22 6.41,83.69 6.67,83.96 v2(6.67,84.57) 6.67,85.36 6.33,85.7 6.22,85.7 5.97,85.46 LX6.1 5.36,85.46 RX21.1
  IN3 w0.135: v3(152.15,7.47) 152.03,7.35 151.63,7.35 151.11,6.84 144.41,6.84 143.82,6.25 141.05,6.25 137.72,9.58 133.31,9.58 131.22,11.66 128.43,11.66 128.02,12.07 126.12,12.07 125.46,12.73 122.97,12.73 121.5,14.2 121.5,14.73 118.64,17.59 108,17.59 101.5,24.09 97.51,24.09 97.06,24.54 88.21,24.54 87.81,24.13 78.11,24.13 74.78,27.47 69.09,27.47 67.33,29.22 53.21,29.22 47.76,34.68 47.76,38.91 46.28,40.39 31.98,40.39 30.2,42.18 26.45,42.18 15.74,52.89 15.74,74.85 7.84,82.74 6.56,82.74 6.24,82.43 6.24,82.06 v3(6.15,81.97)
  BOTTOM w0.102: v3(152.15,7.47) 152.41,7.73 152.41,7.86 152.67,8.13 152.67,9.34 U2.D11
USB20_P6: length 150.5
  IN3 w0.135: v3(32.34,54.18) 32.19,54.33 31.88,54.33 31.65,54.11 31.65,53.52 32.15,53.02 46,53.02 47.38,51.63 47.38,44.4 50.7,41.08 50.7,35.46 52.88,33.29 54.49,33.29 55.04,33.84 63.33,33.84 64.82,32.35 69.16,32.35 69.8,31.71 75.31,31.71 76.55,30.47 80.39,30.47 81.56,29.3 82.85,29.3 83.87,28.28 86.28,28.28 87.5,27.06 98.8,27.06 99.21,26.66 103.05,26.66 104.45,25.25 106.89,25.25 107.79,26.15 109.24,26.15 114.6,20.79 119.86,20.79 120.05,20.6 122.15,20.6 123.32,19.44 125.15,19.44 127.29,17.3 127.29,16.84 128.43,15.7 133.1,15.7 135.26,13.54 139.15,13.54 139.78,12.91 142.91,12.91 142.99,12.99 144.14,12.99 144.7,12.43 146.71,12.43 147.07,12.07 148.72,12.07 149.01,12.36 150.26,12.36 150.6,12.02 150.86,12.02 151,12.16 v3(151,12.42)
  BOTTOM w0.102: v3(32.34,54.18) 31.91,54.61 31.5,54.61 31.4,54.51 31.4,54.21 31.27,54.07 LI8.4 ; U2.H9 151.4,12.56 151.25,12.42 v3(151,12.42)
USB20_P9: length 202.8
  TOP w0.102: RX22.1 5.36,86.26 LX6.4 5.97,86.26 6.25,85.97 6.44,85.97 6.94,85.47 6.94,83.85 6.67,83.58 6.67,82.19 v3(6.89,81.97)
  IN3 w0.135: v3(152.15,6.89) 152.15,6.94 152.03,7.07 151.75,7.07 151.23,6.55 144.52,6.55 143.94,5.97 140.93,5.97 137.61,9.29 133.19,9.29 131.1,11.38 128.31,11.38 127.9,11.78 126,11.78 125.34,12.44 122.85,12.44 121.21,14.08 121.21,14.61 118.52,17.3 107.88,17.3 101.38,23.8 97.39,23.8 96.94,24.25 88.33,24.25 87.93,23.85 77.99,23.85 74.66,27.18 68.97,27.18 67.21,28.93 53.09,28.93 47.47,34.56 47.47,38.79 46.16,40.1 31.87,40.1 30.08,41.89 26.33,41.89 15.45,52.77 15.45,74.73 7.72,82.46 6.68,82.46 6.53,82.31 6.53,82.18 6.74,81.97 v3(6.89,81.97)
  BOTTOM w0.102: U2.B11 153.01,8.97 152.94,8.89 152.94,8.02 152.69,7.77 152.69,7.42 v3(152.15,6.89)
USB20_TOUCH_N5: length 207.1
  TOP w0.102: v3(11.51,91.06) 11.4,90.95 11.07,90.95 9,93.02 8.41,93.02 DX2.3 7.58,93.13 7.47,93.03 7.09,93.03 6.15,93.96 4.9,93.96 3.84,92.91 3.7,92.91 v3(3.54,93.07)
  IN3 w0.135: v3(151.21,10.32) 150.38,9.49 147.7,9.49 145.59,11.59 139.83,11.59 139.22,12.2 134.97,12.2 132.36,14.82 128.07,14.82 126.43,16.46 126.43,16.96 125.28,18.11 121.16,18.11 119.36,19.92 113.93,19.92 111.45,22.39 108.28,22.39 106.5,24.17 103.91,24.17 102.26,25.82 98.4,25.82 98,26.22 87.01,26.22 86.73,25.94 84.99,25.94 82.84,28.1 79.79,28.1 78.94,28.94 76,28.94 75.29,29.65 69.88,29.65 68.02,31.51 53.47,31.51 49.82,35.16 49.82,40.72 46.55,43.99 46.55,51.13 45.52,52.15 31.6,52.15 21.78,61.97 21.78,65.97 17.1,70.65 17.1,77.14 12.76,81.48 12.76,90.37 12.19,90.94 11.63,90.94 v3(11.51,91.06)
  BOTTOM w0.102: v3(151.21,10.32) 151.09,10.19 151.09,9.75 U2.C8 ; JEDP.13 2.39,93 2.5,92.88 3.35,92.88 v3(3.54,93.07)
USB20_TOUCH_P5: length 207.1
  TOP w0.102: v3(11.51,90.4) 11.51,90.53 11.36,90.68 10.96,90.68 8.89,92.75 8.4,92.75 DX2.2 7.58,92.66 7.47,92.76 6.98,92.76 6.04,93.69 5.01,93.69 3.95,92.64 3.72,92.64 v3(3.54,92.46)
  IN3 w0.135: v3(11.51,90.4) 11.51,90.5 11.66,90.66 12.07,90.66 12.48,90.25 12.48,81.36 16.81,77.02 16.81,70.54 21.49,65.85 21.49,61.85 31.48,51.86 45.4,51.86 46.26,51.01 46.26,43.87 49.53,40.6 49.53,35.04 53.35,31.22 67.9,31.22 69.76,29.36 75.17,29.36 75.88,28.66 78.82,28.66 79.67,27.81 82.72,27.81 84.88,25.65 86.85,25.65 87.13,25.93 97.88,25.93 98.28,25.53 102.14,25.53 103.79,23.88 106.38,23.88 108.16,22.1 111.33,22.1 113.81,19.63 119.24,19.63 121.04,17.83 125.16,17.83 126.14,16.84 126.14,16.34 127.95,14.53 132.24,14.53 134.85,11.92 139.1,11.92 139.71,11.31 145.47,11.31 147.58,9.2 150.53,9.2 150.78,8.95 v3(150.78,8.03)
  BOTTOM w0.102: v3(3.54,92.46) 3.38,92.62 2.51,92.62 2.39,92.5 JEDP.14 ; U2.A8 150.86,8.41 150.86,8.11 v3(150.78,8.03)
USB_EN#: length 232.6
  TOP w0.102: CI46.1 14.29,44.05 v1(14.29,48.47) 15.25,49.42 UI7.4 14.87,49.5 13.93,50.45 13.93,52.44 15.65,54.17 v3(17.47,54.17) ; v3(168.48,39.55) 168.74,39.81 172.78,39.81 174.43,38.16 183.19,38.16 186.37,41.33 186.37,42.47 188.78,44.89 189.36,44.89 CI26.1 189.94,45.33 UI6.4 192.51,46.33 192.51,48.65 UI5.4 191.52,51 CI13.1
  IN1 w0.114: v3(17.47,54.17) 18.27,53.37 19.56,53.37 22.29,50.64 22.29,45.64 27.11,40.82 29.77,40.82 30.98,39.62 46.78,39.62 48.02,38.39 48.02,36.36 52.44,31.93 58.78,31.93 58.93,32.08 62.72,32.08 64.67,34.04 68.88,34.04 69.86,35.01 75.19,35.01 76.84,36.66 81.54,36.66 84.93,33.27 92.7,33.27 97.21,28.76 109.01,28.76 109.98,27.79 110.04,27.79 110.34,27.49 115.04,27.49 v3(115.63,28.07)
  IN2 w0.127: v3(168.48,39.55) 167.9,39.55 166.17,37.82 166.17,36.26 165.72,35.81 158.84,35.81 154.63,31.6 143.95,31.6 142.6,30.26 139.43,30.26 139.4,30.28 130.17,30.28 128.57,28.68 123.21,28.68 122.48,27.94 121.03,27.94 119.75,26.66 117.04,26.66 v3(115.63,28.07)
  BOTTOM w0.102: RE504.1 117.87,32.96 117.65,32.96 116.39,31.71 UE1.84 116.39,28.84 v3(115.63,28.07)
USB_OC0#: length 101
  TOP w0.102: v3(193.07,49.56) 193.16,49.65 UI5.3 193.92,50.71 CI15.1 ; v3(150.42,17.67) 150,18.09 149.61,18.09 149.26,17.73 148.16,17.73 147.97,17.54 147.97,16.76 146.53,15.32 144.72,15.32 144.54,15.5 144,15.5 v4(143.98,15.48) 143.67,15.17 143.67,13.36 142.79,12.49 RPH4.8
  IN3 w0.102: v3(193.07,49.56) 192.59,49.08 192.59,45.27 193.76,44.1 193.76,39.28 191.11,36.63 189.54,36.63 185.73,32.83 185.73,30.92 182.86,28.05 182.86,25.28 182,24.41 182,21.7 180.85,20.55 180.85,18.32 181.21,17.96 181.21,14.33 181.46,14.08 181.46,10.37 180.17,9.07 177.53,9.07 176.36,7.9 171.59,7.9 170.31,9.18 164.67,9.18 163.4,10.44 163.4,11.92 162.19,13.14 162.19,13.36 161.79,13.75 161.12,13.75 160.87,13.5 159.14,13.5 156.66,15.99 153.83,15.99 152.64,17.17 150.78,17.17 150.42,17.54 v3(150.42,17.67)
  BOTTOM w0.102: U2.T8 150.61,19.47 150.93,19.15 150.93,18.15 150.45,17.67 v3(150.42,17.67)
USB_OC1#: length 8.9
  TOP w0.102: v3(145.11,12.88) 144.98,12.76 T118.1 143.69,12.76 142.93,11.99 142.93,11.8 142.62,11.49 RPH4.6
  BOTTOM w0.102: v3(145.11,12.88) 145.47,12.53 148.98,12.53 149.46,13.01 149.46,13.28 U2.J7
USB_OC2#: length 94
  TOP w0.102: v3(148.38,17.32) 148.58,17.11 v4(148.58,16.69) 148.58,16.31 148.43,16.16 147.66,16.16 146.41,14.91 144.41,14.91 143.87,14.38 143.87,13.25 142.61,11.99 RPH4.7 ; v3(193.12,45.33) UI6.3 194.49,45.9 CI17.1
  IN3 w0.102: v3(193.12,45.33) 194.04,44.41 194.04,39.22 191.14,36.33 189.57,36.33 185.97,32.73 185.97,30.82 183.1,27.95 183.1,25.18 182.23,24.32 182.23,21.6 181.9,21.26 181.9,18.83 182.07,18.65 182.07,14.61 181.7,14.23 181.7,10.27 180.27,8.84 177.62,8.84 176.46,7.67 171.49,7.67 170.22,8.95 164.57,8.95 163.17,10.35 163.17,11.82 161.95,13.04 161.95,13.26 161.69,13.52 161.22,13.52 160.97,13.26 159.03,13.26 156.54,15.75 153.73,15.75 152.61,16.87 148.83,16.87 v3(148.38,17.32)
  BOTTOM w0.102: U2.P5 147.98,17.72 v3(148.38,17.32)
USB_OC3#: length 174.3
  TOP w0.102: CI47.1 15.26,52.59 15.22,52.56 UI7.3 15.22,51.36 v3(14.42,50.55) ; v4(146.23,10.54) 146.23,10.53 145.98,10.53 145.88,10.43 v3(145.59,10.43) 145.59,11.01 145.24,11.36 143.32,11.36 142.95,10.99 RPH4.5 142.23,10.99 141.87,10.62 139.6,10.62 139.12,11.1 v3(138.49,11.1)
  IN1 w0.102: v3(138.49,11.1) 138.67,11.29 138.67,13.29 138.03,13.93 138.03,17.81 137.67,18.17 137.67,26.29 135.9,28.07 135.11,28.07 133.17,26.13 128.42,26.13 127.72,26.83 124.26,26.83 123.5,26.06 123.5,24.57 122.71,23.77 120.83,23.77 119.28,25.32 118.19,25.32 117.72,24.85 114.88,24.85 114.27,25.46 111.61,25.46 108.74,28.33 97.33,28.33 92.61,33.04 84.83,33.04 81.44,36.43 76.93,36.43 75.28,34.79 69.95,34.79 68.98,33.82 64.77,33.82 62.81,31.86 59.05,31.86 58.9,31.71 52.35,31.71 47.8,36.27 47.8,38.29 46.69,39.4 30.05,39.4 v3(29.62,39.83)
  IN3 w0.102: v3(29.62,39.83) 28.94,40.52 24.82,40.52 14.79,50.55 v3(14.42,50.55)
  BOTTOM w0.102: v3(145.59,10.43) 145.61,10.43 146,10.82 147.84,10.82 148.15,11.13 U2.F5
USB_OC5#: length 4.3
  BOTTOM w0.102: U2.T1 146.35,19.5 145.96,19.89 145.01,19.89 v1(144.53,19.41) 144.11,19.41 143.72,19.8 RPH1.1
USB_RCOMP: length 3.8
  BOTTOM w0.203: U2.B9 151.64,8.82 151.64,7.55 151.49,7.39 v1(151.49,6.46) RH54.1
USBSS_CALRN: length 3.6
  BOTTOM w0.203: RH59.1 157.01,5.76 156.64,6.14 v1(156.64,6.58) 156.64,8.1 U2.A16
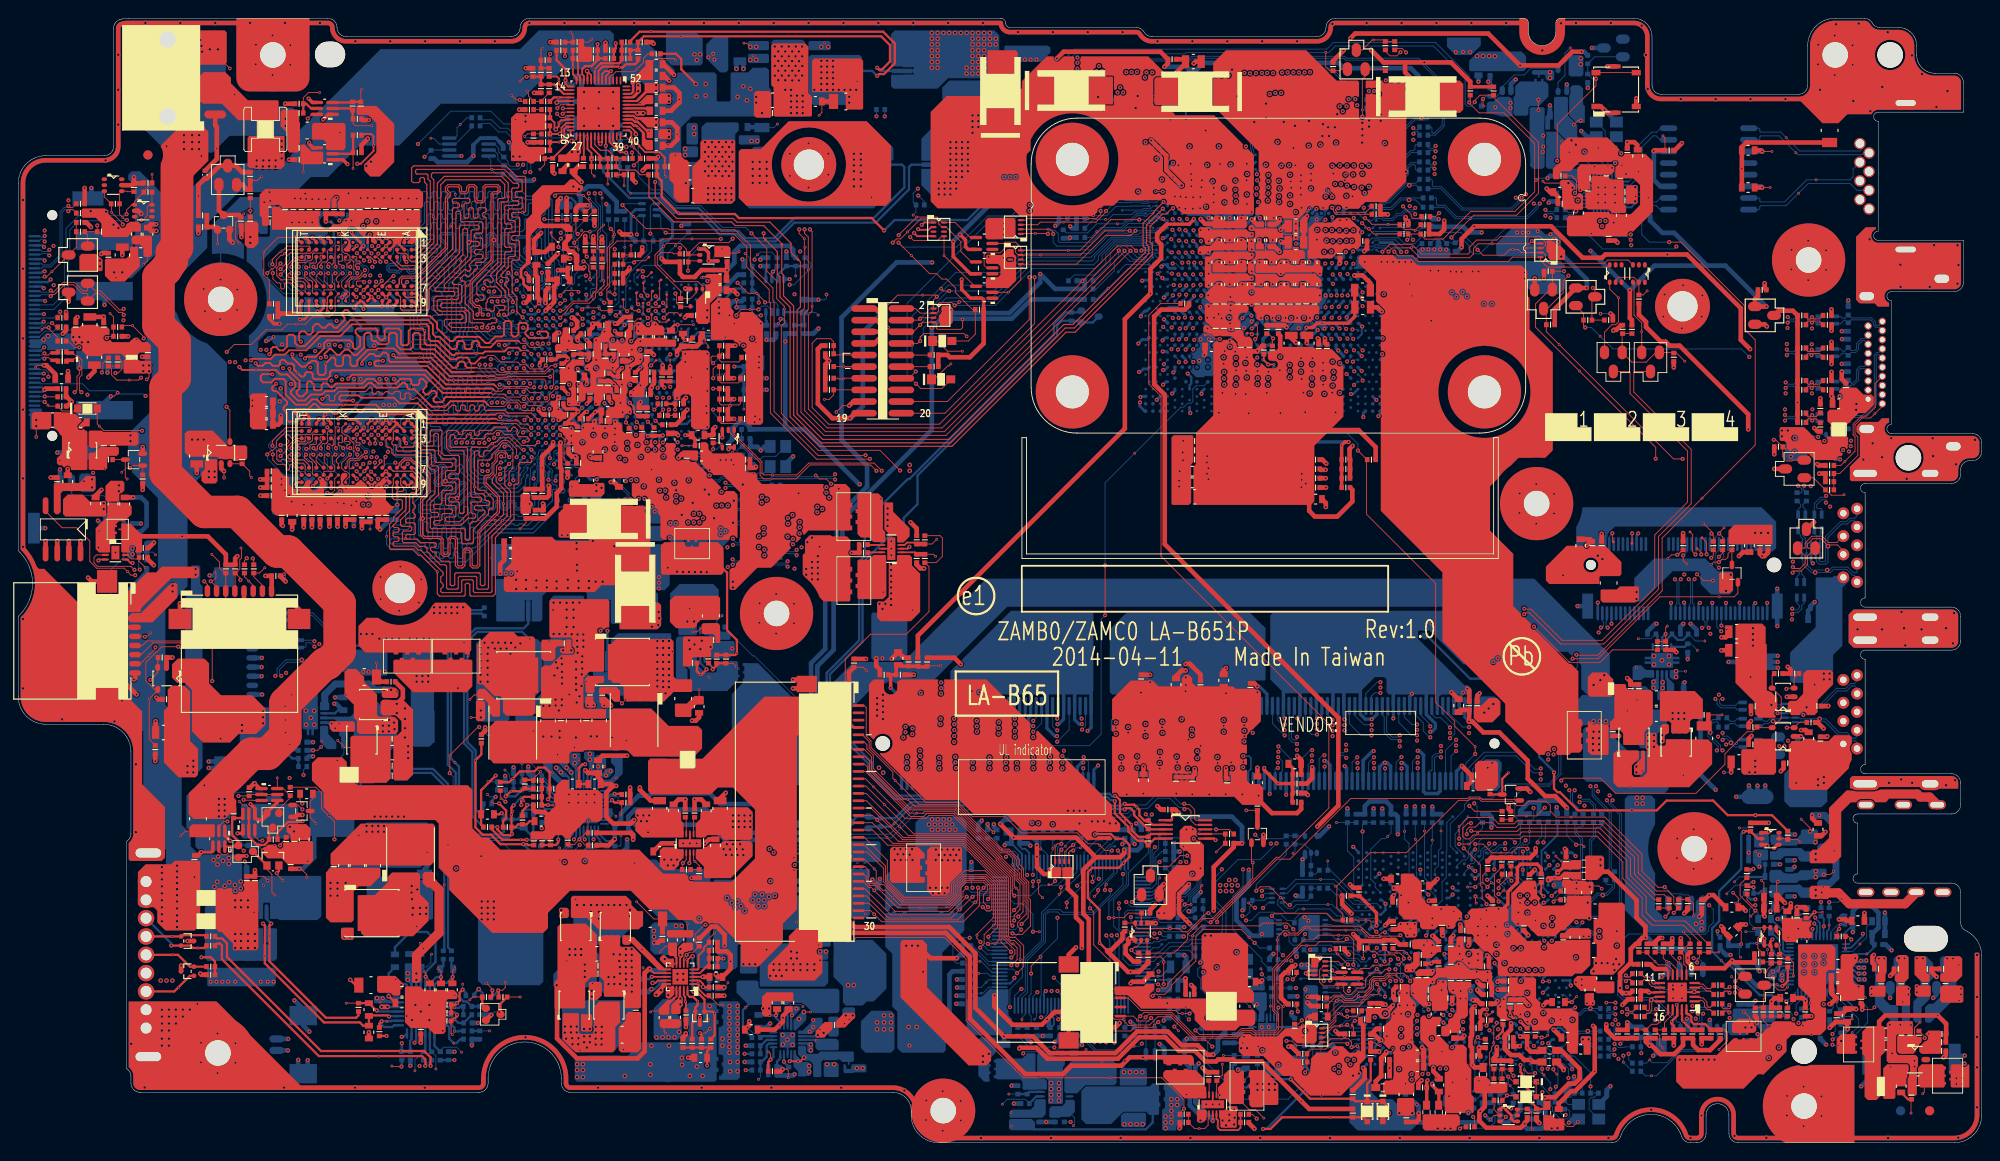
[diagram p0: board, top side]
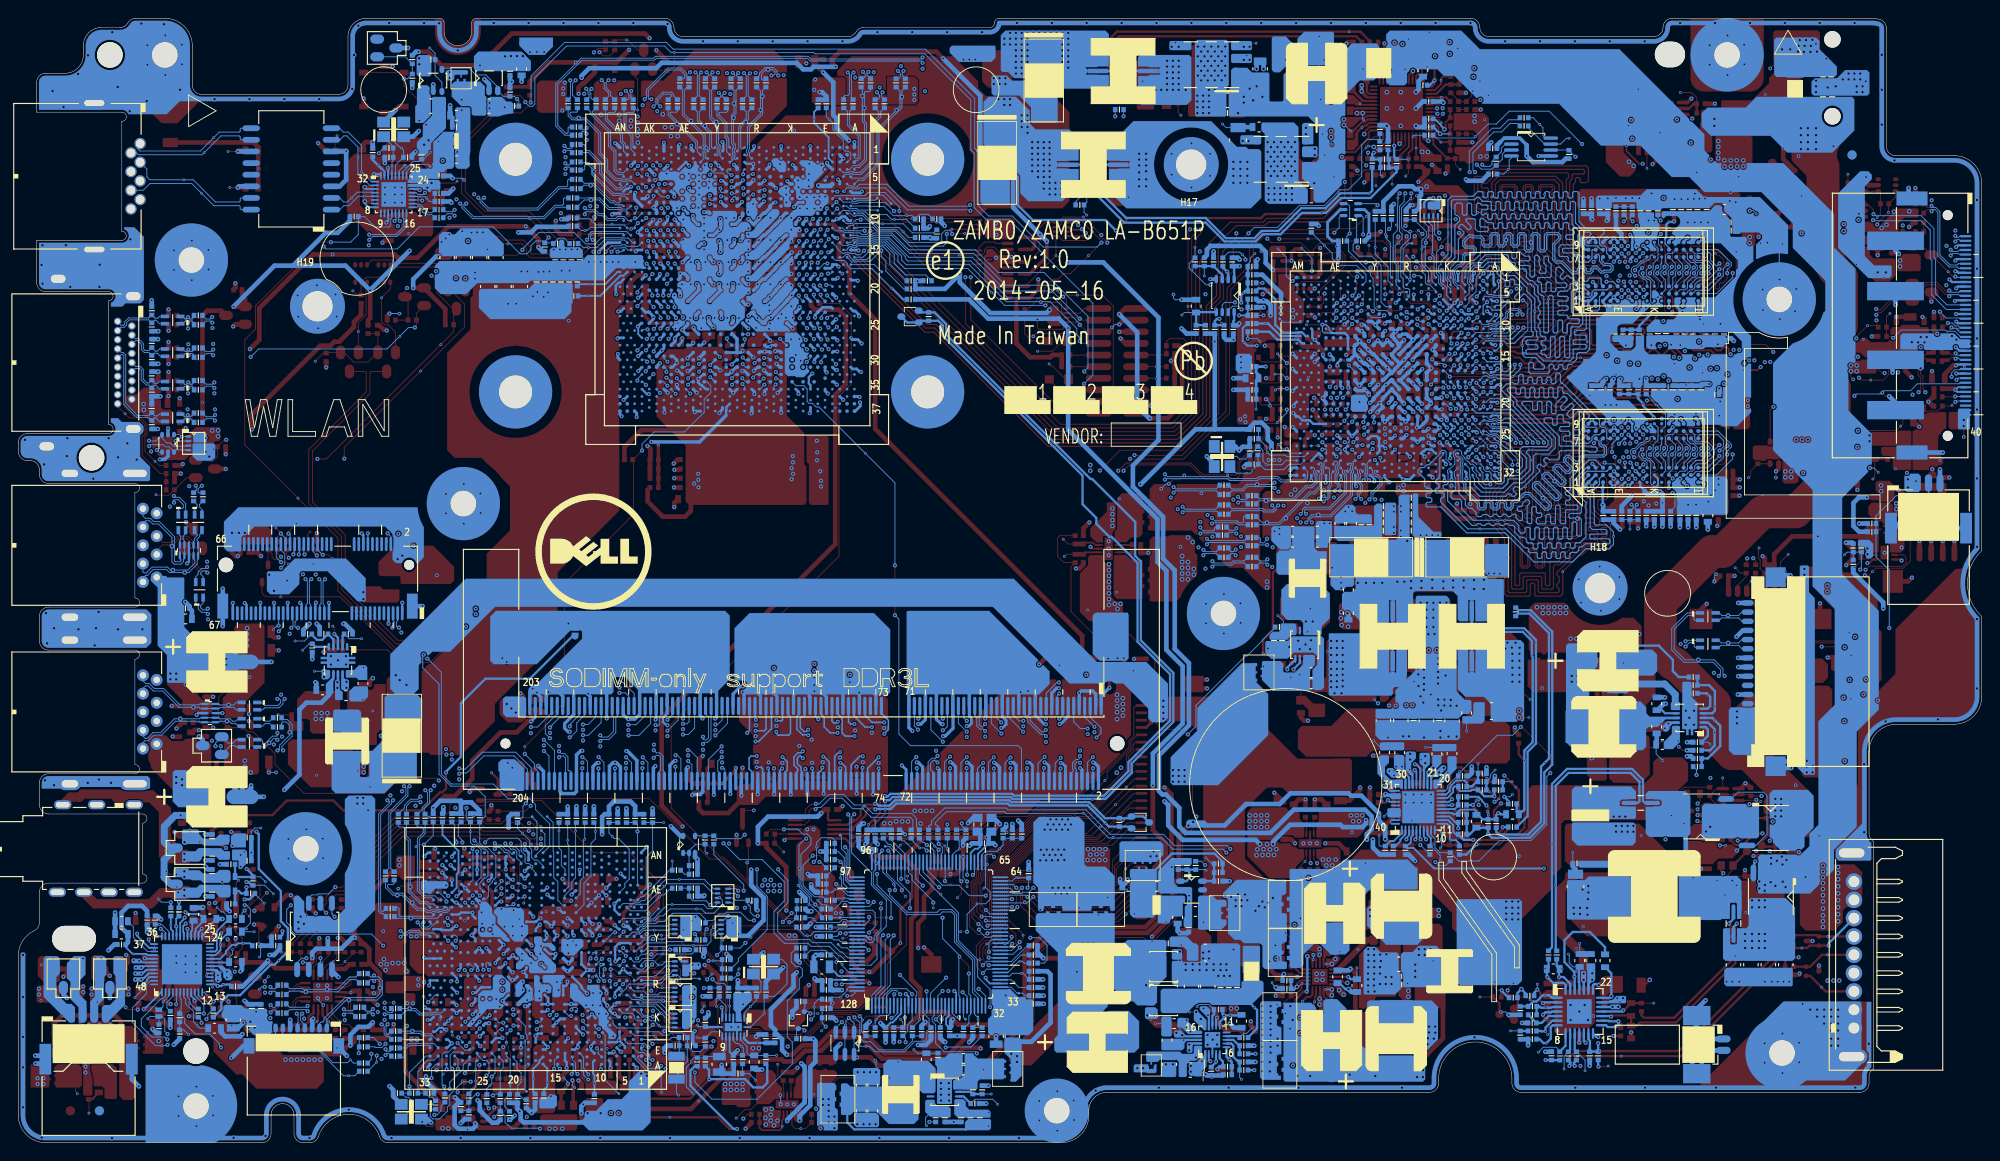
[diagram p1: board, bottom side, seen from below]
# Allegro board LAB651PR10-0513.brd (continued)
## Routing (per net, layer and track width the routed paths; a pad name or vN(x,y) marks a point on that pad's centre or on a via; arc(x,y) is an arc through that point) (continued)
USBSS_CALRP: length 4.6
  BOTTOM w0.203: U2.C16 157.49,8.98 157.49,8.76 158.17,8.08 v1(158.17,6.94) 158.17,5.54 RH58.1
VCIN0_PH: length 86.9
  TOP w0.102: PH1.1 124.73,91.66 123.45,90.38 v1(123.45,87.93) 123.45,82.86 124.78,81.53 124.78,64.07 143.11,45.74 143.11,36.55 137.72,31.17 137.36,31.17 130.27,24.08 v3(130.21,24.08)
  BOTTOM w0.102: v3(130.21,24.08) 129.9,24.08 RE15.2 129.42,25.48 PR25.1 PR24.1
VCIN0_PH2: length 127.9
  IN1 w0.102: v3(112.96,34.78) 111.94,33.75 99.95,33.75 98.65,33.75 96.36,36.05 88.12,36.05 85.02,39.15 77.07,39.15 74.56,36.63 72.09,36.63 71.47,37.26 66.46,37.26 65.35,36.14 64.01,36.14 63.56,35.69 59.52,35.69 59.18,35.35 55.15,35.35 54.92,35.13 52.04,35.13 51.24,35.93 51.24,41.79 48.11,44.91 48.11,50.29 44.39,54 35.93,54 30.34,59.59 16.26,59.59 v3(13.26,62.59)
  BOTTOM w0.102: HE1.1 RE332.1 13.14,62.72 v3(13.26,62.59) ; HE1.1 RE333.1 ; HE1.1 14.7,64.49 v1(14.99,64.2) ; RE7.1 v3(112.96,34.78)
VCIN1_PH: length 6.8
  BOTTOM w0.102: PR23.1 126.14,29.14 PR26.2 PC13.2 RE30.2 125.51,27.36 125.23,27.64 v1(125.22,27.64) 124.45,27.64 123.8,26.99 UE1.102
VCOUT0: length 5.1
  BOTTOM w0.102: v1(127.09,26.46) 126.63,25.99 126.17,25.99 RE37.2 125.25,25.53 124.42,26.37 123.86,26.37 123.68,26.19 UE1.104
VCOUT0_PH#: length 227.8
  TOP w0.102: R2450.2 132.21,34.22 v3(130.79,34.22) ; R621.2 150.45,119.51 151.11,119.51 v3(151.54,119.08) ; v3(127.36,26.01) v1(128.06,26.01)
  TOP w0.254: PR110.1 PR101.2 PR102.2 PR100.2 75.22,9.99 PC100.1 v3(75.22,8.44)
  IN1 w0.114: v3(75.22,8.44) 75.22,8.41 76.31,7.32 83.5,7.32 84.08,7.9 85.53,7.9 86.14,7.29 98.25,7.29 103.33,12.37 109.28,12.37 111.26,14.36 114.31,14.36 117.81,17.86 118.24,17.86 119.57,19.19 123.49,19.19 126.47,22.17 126.47,25.12 v3(127.36,26.01)
  IN2 w0.127: v3(130.79,34.22) 132.19,35.62 155.76,35.62 156.98,36.83 156.98,37.43 158.54,38.99 160.1,38.99 166.53,45.43 166.53,51.11 171.63,56.21 171.63,59.76 177.63,65.76 177.63,77.42 185.98,85.78 185.98,92.97 183.01,95.94 179.97,95.94 174.69,101.21 170.56,101.21 167.06,104.7 167.01,104.7 165.87,105.84 165.87,106.76 159.52,113.11 159.52,114.73 157.69,116.56 155.25,116.56 152.73,119.08 v3(151.54,119.08)
  BOTTOM w0.102: v3(130.79,34.22) 130.77,34.24 129.27,34.24 128.73,33.71 128.28,33.71 127.84,33.28 127.84,32.57 128.94,31.47 128.94,28.05 127.82,26.93 127.82,26.47 v3(127.36,26.01) 126.88,25.53 RE37.1
VCOUT1_PH: length 5.3
  TOP w0.102: v3(121.6,26.29) 122.38,27.08 QE30.2
  BOTTOM w0.102: v3(121.6,26.29) 121.89,26.59 UE1.103 123.68,26.59 123.79,26.7 v1(124.33,26.7) 125.02,26.7 RE44.1
VFB: length 5.1
  TOP w0.254: v3(39.68,13.26) 39.43,13.01 PR726.1
  BOTTOM w0.254: PU700.15 41.02,12.82 40.82,12.63 39.93,12.63 39.68,12.88 v3(39.68,13.26) v1(40.25,13.26) 40.7,13.26 40.76,13.33 PU700.16
VGA_AC__BATT: length 20.9
  TOP w0.102: UV4.4 73.35,91.29 RV92.1 72.29,91.29 71.86,91.72 71.86,92.64 v3(71.76,92.74) ; v3(73.13,95.23) 73.13,96.17 RV148.2 73.27,96.31 QV8.3
  IN3 w0.135: v3(63.91,90.21) 64.18,90.48 64.7,90.48 67.24,93.02 71.28,93.02 71.56,92.74 v3(71.76,92.74) 71.76,92.97 72.5,93.7 72.5,94.59 v3(73.13,95.23)
  BOTTOM w0.102: v1(74.26,97.72) 73.13,96.59 v3(73.13,95.23) ; v3(63.91,90.21) UV1.T9
VGA_DMINUS: length 25.2
  IN1 w0.114: v3(55.12,106.81) 57.03,106.81 57.53,106.3 59.19,106.3 59.93,105.56 61.94,105.56 62.95,104.55 v3(62.95,103.69)
  BOTTOM w0.102: v3(55.12,106.81) 54.64,106.33 53.42,106.33 52.36,107.4 52.36,107.95 51.89,108.42 UV3.3 ; v3(62.95,103.69) 63.06,103.57 63.06,102.76 63.58,102.24 63.58,99.52 63.3,99.24 63.3,98.7 v1(63.72,98.28) 64.05,97.95 64.05,96.33 63.72,96 63.72,94.22 UV1.T2
VGA_DPLUS: length 26.7
  IN1 w0.114: v3(54.54,106.81) 55,107.27 56.89,107.27 57.62,106.54 59.32,106.54 60.07,105.79 62.06,105.79 63.56,104.3 v3(63.56,103.69)
  BOTTOM w0.102: UV3.2 52,109.07 52.46,108.61 52.46,108.21 CV9.1 53.47,107.19 53.47,106.86 53.7,106.63 54.36,106.63 v3(54.54,106.81) ; UV1.T4 63.6,93.36 63.94,93.7 63.94,95.93 64.26,96.24 64.26,99.18 63.81,99.62 63.81,102.3 63.75,102.37 v1(63.75,103.18) 63.75,103.5 v3(63.56,103.69)
VGA_ON: length 4.6
  BOTTOM w0.102: UE1.127 123.69,16.99 123.91,16.77 123.91,16.59 v1(124.62,15.88) 125.51,15.88 RE39.2 RE40.2
VGA_ON_FCH: length 50.8
  TOP w0.102: D7.1 D6.1 165.97,5.01 166.43,5.47 v3(166.43,5.52)
  IN2 w0.127: v3(127.83,13.47) 128.53,13.47 131.54,10.46 131.54,8.14 134.89,4.79 136.45,4.79 137,4.25 161.7,4.25 162.01,4.55 163.33,4.55 163.84,4.04 165.87,4.04 166.17,4.35 166.17,5.26 v3(166.43,5.52)
  BOTTOM w0.102: v3(127.83,13.47) 127.83,13.44 127.49,13.78 v1(127.49,14.8) 127.49,15.19 127.01,15.68 RE39.1
VGA_PWRGD: length 172.1
  TOP w0.102: v3(164.8,32.11) 164.67,32.24 163.71,32.24 163.12,31.65 160.92,31.65 159.95,32.62 v3(159.09,32.62) ; v3(50.32,45.4) 50.2,45.4 v1(47.11,42.31) v3(47.11,40.36)
  IN3 w0.102: v3(50.32,45.4) 56.86,38.87 57.11,38.87 59.27,36.7 66.24,36.7 66.7,37.16 70.84,37.16 70.95,37.05 81.24,37.05 86.7,31.6 87.84,31.6 89.06,30.38 103.15,30.38 104.48,31.71 109.03,31.71 110.37,33.05 125.3,33.05 125.89,33.63 128.7,33.63 129.81,32.52 131.96,32.52 134.42,34.97 150.95,34.97 151.36,35.38 158.78,35.38 159.09,35.08 v3(159.09,32.62)
  BOTTOM w0.102: v3(164.8,32.11) 164.75,32.06 164.75,28.71 165.2,28.26 U2.AG26 ; v3(47.11,40.36) 47.48,40 47.48,34.75 49.23,33 52.66,33 54.9,30.76 57.12,30.76 PR1064.1 59.15,31.68 59.7,32.23 59.7,33.2 60.13,33.63 PU1000.9 ; PU1000.20 58.56,38.43 58.35,38.64 58.35,38.95 57.24,40.06 PR1030.2 57.16,40.25 52.91,44.5 51.23,44.5 v3(50.32,45.4)
VGA_PWRGD_EC: length 70.2
  IN2 w0.127: v3(113.09,18.03) 112.34,18.03 106.01,24.35 99.79,24.35 86.91,37.23 77.36,37.23 75.14,35.01 71.76,35.01 67.82,31.07 62.82,31.07 62.06,30.31 60,30.31 v3(59.66,30.65)
  BOTTOM w0.102: v3(59.66,30.65) 59.28,30.27 58.53,30.27 PR1064.2 ; v3(113.09,18.03) 114.79,16.32 UE1.17
VGA_SMB_CK3: length 40.5
  IN3 w0.135: v3(67.54,99.19) 67.54,99.15 67.13,98.74 65.15,98.74 64.12,99.77 64.12,100.23 63.27,101.08 62.33,101.08 61.37,102.04 58.88,102.04 55.89,105.03 55.89,105.97 v3(55.91,106)
  BOTTOM w0.102: UV1.U7 65.07,91.3 65.59,91.82 65.59,95.81 66.6,96.83 68.04,96.83 68.64,97.43 68.64,98.12 RV6.2 68.26,98.51 68.26,101.09 QV1.1 67.73,101.26 67.54,101.07 v3(67.54,99.19) ; RV164.2 50.65,111.71 51.69,111.71 52.6,110.8 53.44,110.8 55.96,108.28 55.96,106.06 55.91,106.01 v3(55.91,106)
VGA_SMB_CK3_R: length 3.9
  BOTTOM w0.102: UV3.8 47.64,109.72 47.91,109.99 47.91,110.86 v1(48.25,111.21) 48.99,111.94 RV164.1
VGA_SMB_DA3: length 42.1
  IN3 w0.135: v3(69.02,99.29) 68.31,99.29 67.32,98.3 64.97,98.3 63.68,99.59 63.68,100.04 63.09,100.64 62.15,100.64 61.19,101.6 58.7,101.6 55.45,104.85 55.45,105.88 v3(55.33,106)
  BOTTOM w0.102: QV1.4 69.29,102.56 69.02,102.29 v3(69.02,99.29) 69.32,98.99 RV5.2 69.14,98.3 69.14,97.36 66.73,94.95 66.73,94.7 66.45,94.42 66.45,93.55 66.34,93.44 66.34,91.28 65.96,90.9 65,90.9 UV1.U8 ; v3(55.33,106) 55.56,106.23 55.56,108.11 53.27,110.39 52.43,110.39 51.52,111.31 50.68,111.31 RV165.2
VGA_SMB_DA3_R: length 5.7
  BOTTOM w0.102: RV165.1 49.51,110.85 47.73,109.07 UV3.7 45.99,109.07 45.36,109.69 v1(45.05,109.69)
VGA_X1: length 2.9
  BOTTOM w0.102: v1(133.88,6.84) 134.59,7.55 C15.1 135.31,7.6 R785.2
VGA_X1_R: length 2.7
  BOTTOM w0.102: UG1.12 136.33,11.15 136,10.82 135.72,10.82 v1(135.41,10.51) 135.24,10.34 135.24,9.61 R785.1
VGATE: length 254.3
  TOP w0.102: PU500.39 66.32,109.91 67.24,108.98 v1(67.24,108.64) 67.93,107.95 PR541.2 67.93,107.45 v3(67.21,106.74)
  IN1 w0.102: v3(67.21,106.74) 66.83,107.12 63.25,107.12 62.92,107.45 57.75,107.45 56.94,108.27 44.15,108.27 43.13,107.24 39.68,107.24 38.64,106.2 38.64,105.21 36.81,103.38 36.81,102.77 35.53,101.5 29.8,101.5 24.85,96.55 20.28,96.55 12.5,88.78 12.5,81.08 11.61,80.19 11.61,75.11 12.63,74.1 12.63,73.33 12.12,72.83 12.12,66.73 15.11,63.75 19.81,63.75 22.79,60.76 30.7,60.76 35.14,56.32 44.75,56.32 49.36,51.71 49.36,45.14 54.59,39.91 54.59,39.22 57.41,36.4 58.76,36.4 59.09,36.73 63.1,36.73 64.88,38.51 65.74,38.51 65.92,38.33 74.78,38.33 76.64,40.19 85.45,40.19 87.59,38.05 89.64,38.05 90.61,37.09 111.55,37.09 112.67,38.21 118.11,38.21 119.44,36.89 120.07,36.89 120.71,37.52 122.87,37.52 124.14,36.25 125.66,36.25 126.55,35.36 133.03,35.36 134.3,34.09 134.3,30.41 v3(133.74,29.85)
  BOTTOM w0.102: v3(133.74,29.85) 133.74,28.04 132.62,26.92 132.62,23.27 135.77,20.12 135.77,19.79 136.58,18.98 RH51.1
VL: length 3.9
  TOP w0.203: PU100.13 v3(69.17,18.11)
  BOTTOM w0.102: PC106.1 v1(68.23,19.11)
  BOTTOM w0.254: v3(69.17,18.11) 68.92,17.86 PC106.1
VR_HOT: length 3
  TOP w0.102: PU500.27 60.95,109.67 60.7,109.42 v2(60.41,109.42)
  BOTTOM w0.102: v1(62.07,109.88) 61.92,110.04 PR539.2 60.84,109.84 v2(60.41,109.42)
VR_ON: length 224.5
  TOP w0.102: PR303.1 174.1,53.83 172.7,52.43 169.42,52.43 165.51,56.34 v3(165.51,56.37) ; v3(80.07,99.32) 80.07,99.31 81.73,97.64 81.73,95.19 82.81,94.11 82.81,92.19 83.65,91.35 v1(83.65,91.04) 83.65,89.48 83.32,89.15 83.32,79.65 87.35,75.62 94.09,75.62 v3(96.3,73.41)
  IN3 w0.102: v3(165.51,56.37) 165.11,56.37 164.69,55.95 164.69,42.27 159.91,37.49 144.86,37.49 143.84,36.47 133.8,36.47 132.92,35.59 124.89,35.59 124.23,36.25 123.5,36.25 v3(123.12,35.87) 122.87,35.62 108.9,35.62 106.99,33.71 106.57,33.71 106.55,33.68 99.65,33.68 98.86,34.47 98.86,39.55 97.97,40.44 97.97,43.49 98.1,43.62 98.1,49.33 104.07,55.3 104.07,65.64 v3(96.3,73.41)
  BOTTOM w0.102: UE1.121 121.29,19.39 120.63,20.04 120.63,22.64 119.61,23.65 119.61,26.52 121.24,28.15 121.24,29.49 123.4,31.65 123.4,35.59 v3(123.12,35.87) ; PC535.1 PR547.2 65.94,109.58 67.06,109.58 67.7,108.94 67.7,105.54 69.17,104.07 70.06,104.07 71.79,102.34 74.52,102.34 76.9,99.95 79.43,99.95 v3(80.07,99.32)
VRAM_ODT0: length 56
  TOP w0.102: v3(58.79,82.47) 57.99,81.67 57.99,81.15 57.74,80.9 55.94,80.9 55.67,81.18 55.67,81.31 55.36,81.61 54.97,81.61 54.79,81.44 53.35,81.44 53.02,81.77 51.75,81.77 51.62,81.89 51.49,81.89 ; UV6.K1 35.34,78.11 35.34,77.6 35.65,77.29 35.9,77.29 36.2,76.99 36.2,76.79 36.63,76.36 36.63,75.57 36.63,75.57 36.63,75.55 37.01,75.17 37.01,75.14 v3(37.01,75.14)
  TOP w0.203: 51.49,81.89 46.32,81.89 44.34,83.88 v1(39.93,83.88) 36.46,83.88 v3(36.02,83.44)
  IN3 w0.102: 36.58,79.84 36.58,77.02 36.66,76.94 36.66,75.5 v3(37.01,75.14)
  IN3 w0.254: 36.58,79.84 36.02,80.4 36.02,81.34 36.43,81.74 41.89,81.74 42.09,81.94 42.09,83.57 41.74,83.93 36.33,83.93 36.02,83.62 v3(36.02,83.44)
  BOTTOM w0.102: v3(37.01,75.14) 37.01,75.14 37.01,74.86 36.89,74.73 36.71,74.73 36.46,74.48 36.33,74.48 36.15,74.3 36.15,72.01 36.02,71.89 35.9,71.89 35.75,72.03 UV5.K1 ; v3(58.79,82.47) 59.43,82.47 UV1.L18
VRAM_ODT1: length 54.9
  TOP w0.102: 51.97,83.72 52.1,83.6 53.35,83.6 53.43,83.68 58.05,83.68 v3(58.08,83.66) ; v3(37.01,94.96) 37.01,94.96 37.01,94.98 36.63,95.36 36.63,95.38 36.63,95.38 36.63,96.17 36.2,96.6 36.2,96.8 35.9,97.1 35.65,97.1 35.34,97.41 35.34,97.92 UV7.K1
  TOP w0.203: 51.97,83.72 47.08,83.72 45.08,85.73 v1(43.81,85.73) 41.23,85.73 v3(40.95,86.01)
  IN3 w0.102: 36.47,90.55 36.25,90.77 36.25,91.47 36.48,91.7 36.48,93.48 36.91,93.91 36.91,94.86 v3(37.01,94.96)
  IN3 w0.254: 36.47,90.55 39.61,87.4 39.61,87.11 38.51,86.01 38.51,85.73 39.02,85.22 39.02,84.66 39.25,84.43 43.77,84.43 44.27,84.93 44.27,85.72 43.77,86.21 43.34,86.21 43.14,86.01 43.14,85.4 42.93,85.2 42.6,85.2 42.4,85.4 42.4,86.01 42.19,86.21 41.77,86.21 41.59,86.03 41.59,85.55 41.31,85.27 40.52,85.27 40.32,85.48 40.32,86.11 40.49,86.29 40.8,86.29 40.95,86.14 v3(40.95,86.01)
  BOTTOM w0.102: v3(58.08,83.66) 58.08,83.7 58.68,84.3 UV1.K16 ; UV8.K1 35.75,91.85 35.9,91.7 36.02,91.7 36.15,91.82 36.15,94.11 36.33,94.29 36.46,94.29 36.71,94.54 36.89,94.54 37.01,94.67 37.01,94.96 v3(37.01,94.96)
VREF: length 71.5
  TOP w0.102: v1(54.79,115.94) 55.26,116.41 v3(55.51,116.41) 55.53,116.44 PC526.1
  TOP w0.203: PU500.16 59.54,114.56
  TOP w0.254: PC526.1 PR537.1 PC527.1 PR538.1 58.53,115.57 59.54,114.56
  IN3 w0.135: v3(93.71,112.09) 98.74,107.07 98.74,103.89 v3(98.28,103.43) 98.08,103.23 97.8,103.23 95.99,101.41 94.84,101.41 94.72,101.29 73.58,101.29 71.33,103.53 67.41,103.53 60.1,110.84 60.1,113.59 57.28,116.41 v3(55.51,116.41)
  BOTTOM w0.102: v3(98.28,103.43) 98.94,102.77 PH500.2 ; PH501.2 v3(93.71,112.09)
VSUM+: length 10.6
  TOP w0.254: PR1057.1 52.53,35.87 52.66,36 v3(52.79,36)
  BOTTOM w0.102: v1(53.99,36.19) 53.9,36.1 PR1044.1
  BOTTOM w0.203: PC1032.1 55.17,36.15 55.4,36.38 56.95,36.38 57.16,36.17 PC1031.1 57.71,35.87 57.88,36.03 PU1000.14
  BOTTOM w0.254: PR1057.1 52.53,35.87 52.66,36 v3(52.79,36) 53.02,35.77 PR1042.1 PR1044.1 54.49,35.31 54.98,35.81 PC1032.1
VSUM-: length 50.3
  TOP w0.254: PR1053.1 53.85,33.76 v3(53.9,33.71) 53.78,33.58 52.93,33.58 52.3,34.21 v3(52.3,34.47) ; PR1053.1 v1(53.85,35.82) 53.85,36.61 v3(54.08,36.83) ; PR1053.1 54.29,34.47 54.59,34.78 PR1048.1 55.51,34.78 55.85,35.12 PC1035.1
  BOTTOM w0.203: v3(54.08,36.83) 54.57,37.32 54.57,37.39 54.95,37.77 PR1046.1
  BOTTOM w0.254: PH1003.2 50.6,58.16 49.24,58.16 46.89,55.81 46.89,41.3 47.76,40.43 47.76,34.88 49.34,33.3 53.5,33.3 v3(53.9,33.71) PR1044.2 55.16,34.4 PC1032.2 55.9,33.68 PC1050.1 PC1051.1 PC1031.2 ; PR1043.1 v3(52.3,34.47)
VTTREF_1.35V: length 1.6
  BOTTOM w0.254: PU200.4 v3(83.6,8.86) 83.6,8.79 PC210.1
WAKEB: length 7.7
  BOTTOM w0.102: UV1.AJ27 73.97,74.93 75.89,74.93 76.06,75.1 77.71,75.1 v1(77.97,75.37) 78.06,75.46 78.06,75.98 RV163.1 RV162.2
WD_PWRGD: length 3.8
  TOP w0.102: RH82.2 160.46,29.72 159.92,29.19 159.92,28.44 v3(160.44,27.93) 160.44,28 v1(160.85,28.41)
  BOTTOM w0.102: U2.AF19 160.03,27.52 v3(160.44,27.93)
WL_OFF#: length 53.4
  TOP w0.102: v3(169.73,52.86) 172.5,52.86 179.25,59.62 v1(185.74,59.62) 187.38,59.62 187.78,60.01 QM1.3
  BOTTOM w0.102: v3(169.73,52.86) 169.73,52.89 168.2,51.36 168.2,40.27 167.1,39.17 162.52,39.17 160.92,37.57 158.55,37.57 157.92,36.94 157.92,36.38 156.38,34.84 156.38,32.38 157.09,31.67 U2.AN16
WL_OFF#_R: length 6.9
  TOP w0.102: QM1.1 RM8.2 186.7,64.32 186.7,63.96 186.42,63.68 185.98,63.68 v3(185.71,63.4) 185.12,63.4 v1(184.89,63.17)
  BOTTOM w0.102: v3(185.71,63.4) 186.23,63.92 JNGFF.48
WLAN_CLKREQ#: length 52.4
  IN2 w0.127: v3(185.96,55.86) 187.23,54.59 187.23,43.34 182.94,39.04 175.32,39.04 173.28,41.08 167.6,41.08 167.06,40.54 167.06,39.6 165.46,38 v3(165.46,36.55)
  BOTTOM w0.102: v3(185.96,55.86) 185.48,56.34 JNGFF.45 ; U2.AG25 164.4,28.44 163.87,28.97 163.87,32.02 164.39,32.54 164.78,32.54 165.03,32.8 v1(165.03,33.96) RH84.2 165.11,35.03 165.49,35.41 165.49,36.53 v3(165.46,36.55)
WLAN_LED_EC: length 3.5
  BOTTOM w0.102: UE1.34 105.99,16.99 105.33,16.32 T111.1 104.72,16.32 104.45,16.06 RE34.2
WLAN_WAKE#: length 107.2
  IN2 w0.127: v3(185.98,56.48) 187.48,54.97 187.48,43.18 183.09,38.79 175.21,38.79 174.02,39.98 167.95,39.98 165.92,37.95 165.92,36.37 165.62,36.06 158.74,36.06 154.55,31.88 143.74,31.88 142.37,30.51 139.53,30.51 139.51,30.54 130.06,30.54 128.46,28.93 123.11,28.93 122.37,28.2 120.93,28.2 119.64,26.92 117.34,26.92 116.13,28.12 116.13,28.87 112.2,32.81 112.2,34.07 v3(111.39,34.88)
  BOTTOM w0.102: RE69.2 RE70.2 111.39,34.62 v3(111.39,34.88) ; JNGFF.47 v3(185.98,56.48) 186.11,56.48 v1(186.54,56.05)
WOL_EN: length 156.7
  TOP w0.102: v3(159.95,114) 159.95,113.3 v1(160.04,113.21)
  IN2 w0.127: v3(159.95,114) 159.95,113.04 168.61,104.38 168.61,103.58 170.72,101.46 174.8,101.46 180.07,96.19 183.11,96.19 186.29,93.02 186.29,85.45 178.19,77.35 178.19,59.98 172.32,54.11 172.32,53.47 168.43,49.59 168.43,46.93 160.24,38.74 158.64,38.74 157.23,37.33 157.23,36.73 155.87,35.36 132.57,35.36 130.94,33.74 130.28,33.74 129.06,32.52 127.95,32.52 127.9,32.57 124.39,32.57 v3(124.11,32.29)
  BOTTOM w0.102: RL38.1 159.75,113.8 v3(159.95,114) 160.23,114.28 RL27.2 161.42,114.28 UL2.3 162.05,115.31 163.35,116.62 164.45,116.62 165.18,117.35 168,117.35 UL3.4 ; v3(124.11,32.29) 123.81,31.98 123.81,29.34 123.88,29.27 123.88,28.81 123.66,28.59 UE1.98
XTALIN: length 11.9
  BOTTOM w0.102: YV1.1 82.72,74.96 81.34,74.96 81.04,74.67 80.36,74.67 CV17.1 79.05,75.98 RV20.1 78.9,76.03 78.49,75.62 78.49,74.45 v1(78.09,74.05) 76.44,74.05 75.96,74.53 74.83,74.53 UV1.AM28
XTALOUT: length 10.6
  BOTTOM w0.102: YV1.3 81.37,73.12 v1(80.26,73.12) 79.86,73.12 79.69,73.3 79.69,73.41 CV18.1 ; CV18.1 79,74.62 79.05,74.67 RV20.2 ; CV18.1 78.85,74.1 78.26,73.51 76.2,73.51 75.62,74.1 74.35,74.1 74,74.45 UV1.AK28
XTLI: length 4.8
  BOTTOM w0.102: UL1.29 173.61,106.18 173.59,106.2 v1(173.59,106.68) 173.59,107.16 173.46,107.28 CL36.2 RL21.1 173.46,108.82 YL2.1
XTLO: length 7.1
  BOTTOM w0.102: UL1.28 173.21,106.76 CL37.2 172.35,108.44 v1(172.54,108.63) 172.65,108.63 173.28,109.26 173.28,110.5 YL2.3
N71037: length 2.5
  BOTTOM w0.102: UA1.8 195.93,15.91 195.67,15.66 v1(195.67,15.24) 195.04,14.61 RA130.2
N71249: length 6.6
  TOP w0.102: v3(196.14,25.18) v1(197,25.18)
  TOP w0.203: v3(196.14,25.18) 195.53,24.56 RA12.2
  BOTTOM w0.203: UA1.27 195.13,22.99 195.03,23.09 195.03,23.37 194.18,24.22 CA62.2 194.18,24.46 194.68,24.97 195.94,24.97 v3(196.14,25.18)
N71261: length 4.9
  BOTTOM w0.102: CA63.2 201.83,23.59 201.83,22.42 v1(201.11,21.7) 200.3,20.89 UA1.39
N71273: length 5.6
  BOTTOM w0.102: UA1.7 196.33,15.88 196.13,15.69 196.13,15.19 195.26,14.32 195.26,13.19 v1(194.86,12.79) 194.57,12.5 CA64.2
N71383: length 3.1
  TOP w0.102: v1(199.52,21.15) CA24.1 199.83,22.53 v3(200.16,22.2)
  BOTTOM w0.102: UA1.37 199.87,21.69 200.16,21.98 v3(200.16,22.2)
N71395: length 2.5
  TOP w0.102: v1(198.98,23.84) 198.84,23.7 v3(198.84,23.35) 198.61,23.12 CA24.2
  BOTTOM w0.102: UA1.35 198.33,22.94 198.74,23.35 v3(198.84,23.35)
N71399: length 2.4
  BOTTOM w0.102: UA1.34 197.93,23.02 198.76,23.85 CA25.2
N71447: length 1.8
  BOTTOM w0.203: CA23.2 195.41,24.1 195.41,23.22 195.53,23.1 UA1.28
N71539: length 3.9
  TOP w0.102: CA65.2 RA81.2 CA69.1 RA79.1 190.56,13.34 v1(191.09,12.81)
N71593: length 3.3
  TOP w0.102: CA65.1 193.21,15.28 v3(193.07,15.42)
  BOTTOM w0.102: v1(192.41,16.02) 193.01,15.42 v3(193.07,15.42) 194.09,16.44 UA1.12
N76526: length 2.5
  BOTTOM w0.102: RA1113.2 198.18,14.74 198.18,15.32 197.53,15.97 UA1.4
N3691692:
  vias: v1(176.78,48.37)
N3691782: length 2.9
  TOP w0.102: PC309.1 v1(186.05,46.73)
  TOP w0.508: PC309.1 184.54,45.96 PR305.2
N14128350: length 3.3
  BOTTOM w0.102: PR1110.2 29.88,43.74 v1(29.65,43.51)
  BOTTOM w0.254: PU1100.1 30.16,45.39 29.9,45.14 29.9,44.43 PR1110.2
N16741477: length 1.5
  TOP w0.102: v3(67.74,90.86) 67.24,90.86 T212.1
  BOTTOM w0.102: UV1.AB8 68.1,90.5 v3(67.74,90.86)
N16741481: length 2
  TOP w0.102: v3(68.8,90.9) 69.14,91.24 69.91,91.24 T209.1
  BOTTOM w0.102: UV1.AC8 v3(68.8,90.9)
N16741485: length 2.4
  TOP w0.102: T205.1 70.82,92.61 70.82,91.27 70.45,90.9 v3(70.45,90.87)
  BOTTOM w0.102: v3(70.45,90.87) 70.8,90.53 UV1.AE8
N16741489: length 3.4
  TOP w0.102: T208.1 70.03,94.09 70.03,92.26 69.6,91.82 v3(69.6,91.65)
  BOTTOM w0.102: UV1.AD7 69.95,91.3 v3(69.6,91.65)
N16741493: length 2.7
  TOP w0.102: v3(70.48,90.1) 71.02,90.65 71.99,90.65 T203.1
  BOTTOM w0.102: v3(70.48,90.1) 70.8,89.78 UV1.AE9
N16741497: length 1.5
  TOP w0.102: v3(61.63,89.99) 61.23,90.38 T201.1
  BOTTOM w0.102: UV1.N9 61.34,89.7 v3(61.63,89.99)
N16741501: length 1.7
  TOP w0.102: T215.1 68.67,94.58 v3(68.2,94.58)
  BOTTOM w0.102: v3(68.2,94.58) 68.4,94.37 UV1.AB2
N16741505: length 2.5
  TOP w0.102: v3(68.71,92.51) 68.26,92.97 T214.1
  BOTTOM w0.102: v3(68.71,92.51) 68.4,92.82 UV1.AB4
N16741509: length 2.5
  TOP w0.102: v3(68.74,90.07) 68.23,90.58 T211.1
  BOTTOM w0.102: UV1.AB9 68.37,89.7 v3(68.74,90.07)
N16741513: length 1.9
  TOP w0.102: T207.1 69.16,89.81 v3(68.76,89.41)
  BOTTOM w0.102: v3(68.76,89.41) 68.76,89.37 69.2,88.92 UV1.AC10
N16741517: length 2.3
  TOP w0.102: T206.1 70.77,89.62 70.03,89.62 v3(69.6,90.05)
  BOTTOM w0.102: UV1.AD9 69.95,89.7 v3(69.6,90.05)
N16741521: length 1.6
  TOP w0.102: T202.1 59.72,89.87 v3(59.17,89.32)
  BOTTOM w0.102: v3(59.17,89.32) 59.55,89.7 UV1.L9
N16741525: length 2.6
  TOP w0.102: v3(65.24,90.36) 65.34,90.36 T216.1
  BOTTOM w0.102: v3(65.24,90.36) 65.48,90.12 66.62,90.12 UV1.Y8
N16741529: length 1.9
  TOP w0.102: v3(67.69,91.57) 67.69,91.58 67.49,91.77 T213.1
  BOTTOM w0.102: v3(67.69,91.57) 67.96,91.3 UV1.AB7
N16741533: length 2.1
  TOP w0.102: v3(68.8,91.62) 68.8,91.71 69.14,92.05 69.14,92.89 T210.1
  BOTTOM w0.102: v3(68.8,91.62) 69.12,91.3 UV1.AC7
N16741553: length 3.8
  TOP w0.102: T204.1 67.62,89.97 67.32,89.67 67.32,88.85 67.24,88.77 67.24,87.81 66.96,87.54 v3(66.93,87.54)
  BOTTOM w0.102: v3(66.93,87.54) 66.4,88.06 UV1.Y11
N16741557: length 2.2
  TOP w0.102: T217.1 66.07,91.22 v3(66.48,90.81)
  BOTTOM w0.102: UV1.Y7 66.51,90.81 v3(66.48,90.81)
N16741803: length 1.7
  TOP w0.102: RV29.2 70.01,78.41 v3(69.59,78.84)
  BOTTOM w0.102: v3(69.59,78.84) 69.2,79.23 UV1.AC22
N16741825: length 1.6
  TOP w0.102: v3(68.75,78.73) 69.37,78.11 RV59.2
  BOTTOM w0.102: v3(68.75,78.73) 68.4,79.08 UV1.AB22
N16783218: length 3.4
  TOP w0.102: R48.2 89.44,83.49 89.52,83.42 90.07,83.42 v1(90.09,83.43) 90.15,83.49 92.35,83.49 JHDT1.13
N16783220: length 5.1
  TOP w0.102: JHDT1.15 92.35,82.22 R50.2 89.03,81.67 88.55,81.18 v1(88.03,81.18)
N16783234: length 3.3
  TOP w0.102: R47.2 v1(90.14,84.76) 92.35,84.76 JHDT1.11
N16784339: length 5.5
  TOP w0.102: v3(78.42,90.35) 78.42,90.48 78.95,91.01 v1(79.91,91.01) v3(80.83,91.01)
  BOTTOM w0.102: v3(80.83,91.01) 81.18,91.37 81.79,91.37 82.28,90.88 U1.7 ; RV77.1 v3(78.42,90.35)
N16784342: length 6.9
  TOP w0.102: v3(78.54,93.91) 79.69,92.77 v1(80.63,92.77) 81.54,91.85 v3(81.54,91.77)
  BOTTOM w0.102: RV78.1 v3(78.54,93.91) ; v3(81.54,91.77) 82.66,91.77 82.93,91.5 U1.6
N16787636: length 10.2
  TOP w0.102: JKBBL.2 121.19,15.82 122.58,14.43 126.4,14.43 126.72,14.11 v1(127.12,14.11) v3(127.91,14.11)
  BOTTOM w0.102: RE58.1 128.5,14.88 128.57,14.81 QE4.2 128.11,14.31 127.95,14.15 127.95,14.11 v3(127.91,14.11)
N16803422: length 9.6
  BOTTOM w0.254: RV157.1 78.96,93.29 78.3,93.29 v1(78.03,93.02) 77.15,92.13 77.15,89.34 76.27,88.46 74.62,88.46 74.57,88.51 74.23,88.51 73.83,88.1 UV1.AJ11
N16803439: length 5.8
  BOTTOM w0.254: UV1.AK12 74.22,87.3 74.61,87.69 74.61,87.69 74.63,87.71 76.91,87.71 v1(77.2,87.99) 77.78,88.57 RV155.1
N16803454: length 5.4
  BOTTOM w0.254: RV156.1 v1(78.19,89.46) 77.91,89.46 76.54,88.1 UV1.AL11
N16814221: length 9.5
  TOP w0.102: v3(71.99,89.34) v1(73.73,89.34)
  TOP w0.254: RV60.1 71.28,88.93 71.68,89.34 v3(71.99,89.34)
  BOTTOM w0.127: 71.99,88.62 71.79,88.42 71.05,88.42 71.05,88.57 71.26,88.78 71.26,89.04 71.55,89.34 v3(71.99,89.34) 71.99,88.62
  BOTTOM w0.254: 71.05,88.42 69.53,88.42 69.2,88.1 UV1.AC11 UV1.AC13
N16828992: length 19.2
  TOP w0.508: R54.1 127.21,118.33 C81.1 127.46,117.87 126.5,116.91 v3(126.5,116.9) ; v3(123.7,109.45) 125.36,107.8 125.36,106.23 v1(126.11,105.47) v2(127.03,104.55)
  BOTTOM w0.508: v3(126.5,116.9) 125.41,115.8 125.41,112.22 125.05,111.86 125.05,110.8 v3(123.7,109.45) ; UC1.D6 125.7,104.5 126.98,104.5 v2(127.03,104.55)
N16924370: length 9.6
  TOP w0.102: CL41.2 179.81,109.75 v1(179.6,109.96)
  TOP w0.508: v3(178.59,108.31) 178.67,108.39 CL41.2
  BOTTOM w0.508: 178.59,108.26 v3(178.59,108.31) ; 178.59,108.26 178.59,105.16 179.3,104.45 TL2.3 ; 178.59,108.26 TL2.6
N16924426: length 2.6
  BOTTOM w0.203: UL1.31 174.41,106.08 174.68,106.35
  BOTTOM w0.254: 174.68,106.35 174.72,106.35 v1(175.11,106.74) 175.7,107.33 RL31.2
N16924463: length 3.4
  BOTTOM w0.102: UL1.25 172.01,106.04 171.2,106.85 169.64,106.85 T94.1
N16924465: length 1.4
  BOTTOM w0.102: T95.1 172.81,106.14 UL1.27
N16924703: length 14.2
  TOP w0.508: RL19.2 v1(188.21,106.38) RL20.2 188.21,108.74 188.7,109.24 CL33.1
N16948644: length 3
  BOTTOM w0.203: PU1000.15 58.03,36.43 58.03,36.43 57.65,36.43 57.65,36.43 57.53,36.43 57.16,36.81 PC1036.2
  BOTTOM w0.254: PC1036.2 PR1046.2
N16948660: length 2.7
  TOP w0.254: v3(55.56,36.89) 55.56,36.76 55.05,36.25 PR1048.2
  BOTTOM w0.102: v1(55.2,37.34) 55.2,37.24 v3(55.56,36.89)
  BOTTOM w0.254: PC1036.1 v3(55.56,36.89)
N16948668: length 6.2
  TOP w0.254: v3(61.91,41.33) 61.59,41.33 61.19,40.94 v1(61.19,40.7) 61.19,39.18 PC1020.1 PR1024.1
  BOTTOM w0.203: v3(61.91,41.33) 61.78,41.33 61.32,40.88 PU1000.25
N16955053: length 30.7
  BOTTOM w0.254: PL1002.2 55.68,55.12 55.01,55.8 50.11,55.8 49.12,54.8 v1(49.12,53.15) 49.04,53.07 49.04,43.74 49.94,42.83 49.94,36.38 50.46,35.87 PR1039.2 50.78,36.11 PR1058.2
N16955054: length 30.4
  BOTTOM w0.254: PR1043.2 49.59,35.67 49.59,42.68 48.68,43.59 v1(48.68,54.61) 48.68,54.91 49.95,56.18 55.19,56.18 55.68,56.67 PL1002.3
N16955057: length 4
  BOTTOM w0.203: PU1000.11 58.4,34.83 58.07,34.5 58.07,33.08 58.03,33.04 ; PR1052.2 57.03,32.66 57.41,33.04 58.03,33.04 ; 58.03,33.04 v1(58.03,33.02)
N16955058: length 5.1
  TOP w0.102: v1(58.38,36.89) v3(57.84,36.89)
  TOP w0.254: v3(57.84,36.89) PC1030.1 PR1049.1 PR1040.1 PC1027.1
  BOTTOM w0.203: v3(57.84,36.89) 57.9,36.83 PU1000.16
N16955061: length 10.6
  TOP w0.254: PR1050.1 53.6,39.37 v1(54.01,39.78) 54.78,40.56 56.36,40.56 56.78,40.97 57.54,40.97 58.02,40.49 PC1040.1 58.02,37.7 v3(57.84,37.51)
  BOTTOM w0.203: PU1000.17 58.14,37.23 57.86,37.51 v3(57.84,37.51)
N16955074:
  vias: v1(57.96,54.78)
N16955100: length 1.3
  BOTTOM w0.102: PC1029.1 v1(56.24,44.95)
N16955117: length 1.2
  BOTTOM w0.102: PC1026.1 v1(60.74,43.17)
N16955158: length 19
  TOP w0.254: PH1002.2 50.56,42.41 v1(49.92,41.76) 49.92,34.43 50.72,33.63 51.62,33.63 52.66,32.59 v3(55.15,32.59) 55.58,32.59 55.67,32.5 PR1031.2
  BOTTOM w0.254: v3(55.15,32.59) 56.27,31.47 PR1052.1
N16955166: length 11.5
  TOP w0.254: v3(53.22,37.82) 53.78,38.38 v1(53.8,38.38) 54.87,38.38 55.2,38.71 PR1037.2 55.35,38.66 PR1040.2
  BOTTOM w0.203: PU1000.18 58.37,37.63 57.71,38.28 57.71,38.75 57.55,38.92 PC1028.1 57.16,38.61 56.95,38.41 55.81,38.41 55.68,38.54 PR1041.1
  BOTTOM w0.254: PR1041.1 54.29,37.82 v3(53.22,37.82) PR1045.1
N16955169: length 2.3
  TOP w0.102: PC1027.2 56.24,39.74 v1(57.03,40.53)
  TOP w0.254: PC1027.2 56.17,39.63 PR1037.1
N16955171: length 1.9
  BOTTOM w0.102: v1(51.29,39.43) PC1034.1
  BOTTOM w0.254: PC1034.1 PR1045.2
N16955173: length 7.6
  BOTTOM w0.102: v1(55,41.41) PR1038.1
  BOTTOM w0.203: PU1000.19 58.47,38.03 58.1,38.41 58.1,38.84 57.38,39.55 56.44,39.55 56.24,39.35 PC1028.2
  BOTTOM w0.254: PC1028.2 55.66,38.92 55.15,39.43 PC1033.2 PR1038.1
N16955176: length 2.5
  BOTTOM w0.102: v1(53.14,40.7) 53.65,40.19 53.65,39.86 PC1033.1
  BOTTOM w0.254: PC1033.1 PR1041.2
N16955207: length 1.4
  TOP w0.102: PR1060.2 49.79,48.9 v1(49.31,48.42)
N17016554: length 46.7
  TOP w0.102: v3(22.76,86.36) 23.58,87.18 25.43,87.18 27.03,88.78 28.78,88.78 29.4,89.4 v1(30.36,89.4) 31.34,89.4 32.14,90.2 33.94,90.2 34.6,90.86 34.6,92.33 34.95,92.68 UV7.L8
  IN1 w0.114: v3(22.76,86.36) 21.98,86.36 18.01,90.33 18.01,93.86 20.48,96.33 24.94,96.33 29.89,101.27 34.5,101.27 v3(35.06,100.72)
  BOTTOM w0.102: v3(35.06,100.72) 35.36,101.02 RV56.1
N17017096: length 17.2
  TOP w0.102: v3(35.03,99.24) 34.75,99.52 30.74,99.52 30.08,98.86 28.35,98.86 v1(26.8,97.31) 26.8,94.77 27.41,94.16 RV57.1
  BOTTOM w0.102: v3(35.03,99.24) 35.29,98.99 35.29,98.12 34.95,97.79 UV8.L8
N17087794: length 1.4
  BOTTOM w0.102: PU1000.40 64.45,34.83 64.57,34.96 64.57,35.11 64.45,35.23 PU1000.39
N17087943: length 1.4
  BOTTOM w0.102: v1(65.26,35.64) 64.87,36.03 PU1000.37
N17088417: length 2.4
  BOTTOM w0.203: PU1000.2 62.92,33.67 63.47,33.12 63.47,32.93 64.01,32.39 PR1033.2
N17089228: length 3.5
  TOP w0.102: v1(65.79,35.79) 65.89,35.89 PR1035.2
  TOP w0.254: v3(64.84,37.42) 65.12,37.14 PR1035.2
  BOTTOM w0.203: PU1000.34 64.65,37.23 v3(64.84,37.42)
N17089248: length 1.8
  TOP w0.254: v3(65.11,38.1) 65.82,38.1 PR1056.2
  BOTTOM w0.102: v3(65.11,38.1) 65.49,37.72 v1(65.49,37.28)
N17112777: length 66.3
  TOP w0.254: v3(52.13,40.09) v1(50.87,38.83) 50.54,38.5 PR1057.2 50.54,34.71 PR1059.2
  IN2 w0.254: v3(52.13,40.09) 52.13,40.26 48.39,43.99 48.39,55.88 50.86,58.35 50.86,62.56 52.61,64.32 68.33,64.32 69.27,63.38 69.27,60.76 68.51,60 64.53,60 64.17,59.63 64.17,56.07 v3(64.33,55.91)
  BOTTOM w0.254: PL1003.2 64.33,52.6 v3(64.33,55.91)
N17143063: length 3.1
  TOP w0.102: v1(13.85,62.84) 13.19,63.5 CE60.1 13.01,63.76 12.35,63.76 11.91,64.19 UE4.6
N17212768: length 2.9
  TOP w0.102: US2.7 181.66,19.3 v1(181.31,19.65) 180.52,20.44 RS19.2
N17212771: length 3.6
  TOP w0.254: 181.16,14.54 181.16,13.87 v1(180.51,13.23) 180.51,13.01 180.78,12.74 RS22.2
  TOP w0.508: RS22.2 RS20.2
N17212791: length 3
  TOP w0.254: 179.89,18.98 180.16,18.71 US2.10
  TOP w0.508: RS25.2 178.23,19.49 178.73,18.98 179.89,18.98
N17242539: length 3.1
  BOTTOM w0.102: UV3.4 51.36,107.56 51.59,107.32 51.59,106.39 v1(51.7,106.29) 52.19,105.8 RV58.1
N17283470:
  vias: v1(90.73,13.47) v2(90.35,13.9) v2(91.12,13.9)
N17283477: length 5.7
  TOP w0.508: PR210.1 82.61,12.35 v1(83.11,12.86) 83.5,13.24 v3(83.5,13.64) 83.5,13.85 84.13,14.48 PC204.2
  BOTTOM w0.254: v3(83.5,13.64) 83.6,13.54 PU200.12
N17371703: length 4.6
  BOTTOM w0.102: v1(43.31,7.85) 43.31,9.02 44.23,9.93 PR717.2
  BOTTOM w0.254: PU700.10 44.44,10.13 PR717.2
N17371738: length 4.1
  BOTTOM w0.102: PR719.2 45.6,9.47 v1(45.6,8.06)
  BOTTOM w0.254: PU700.9 44.94,10.12 PR719.2
N17438484: length 2.1
  BOTTOM w0.102: v1(195.8,11.8) 196.32,12.32 CA21.1 RA1112.2
N17493058: length 3.9
  TOP w0.102: T4927.1 182.84,66.41 182.84,64.55 v3(183.14,64.24)
  BOTTOM w0.102: JNGFF.36 183.23,64.33 v3(183.14,64.24)
N17493084: length 3.2
  TOP w0.102: v3(184.36,64.26) 184.36,65.57 T4929.1
  BOTTOM w0.102: v3(184.36,64.26) 184.23,64.39 JNGFF.40
N17493086: length 2
  TOP w0.102: v3(183.78,64.24) 183.78,64.43 T4928.1
  BOTTOM w0.102: JNGFF.38 183.73,64.29 v3(183.78,64.24)
N17493091: length 2.3
  TOP w0.102: v3(174.07,66.55) 174.07,65.7 T3861.1
  BOTTOM w0.102: JNGFF.6 173.73,66.21 v3(174.07,66.55)
N17493111: length 2.3
  TOP w0.102: v3(176.23,66.55) 176.23,65.48 T3862.1
  BOTTOM w0.102: JNGFF.16 v3(176.23,66.55)
N17494823: length 8.7
  TOP w0.102: CA1.1 190.62,28.39 v1(190.35,28.66)
  TOP w0.254: RA3.2 191.45,21.46 QA5.2 191.32,21.98 v3(191.55,22.2)
  TOP w0.508: CA1.1 CA2.1 190.62,24.81 v3(190.71,24.72)
  IN2 w0.381: v3(190.71,24.72) 190.71,24.19 191.55,23.35 v3(191.55,22.2)
N17540887: length 4.5
  BOTTOM w0.102: v1(65.8,33.56) 65.8,32.5 65.69,32.39 PR1032.2
  BOTTOM w0.203: PR1032.2 64.57,32.95 64.19,32.95 63.33,33.81 63.33,34.14 PU1000.1
N17607025: length 3.2
  TOP w0.102: v1(182.92,24.77) 182.92,26.08 182.43,26.57 CH20.2 181.81,26.57 181.78,26.55 RH29.2
N17706108: length 4.5
  TOP w0.102: v2(71.05,110.47) 70.66,110.47 PR507.2 70.68,109.83 v2(71.05,109.83)
  IN1 w1.016: 71.34,110.18 71.84,110.18 72.85,109.16
  BOTTOM w0.102: v2(71.05,109.83) 71.05,109.1 v1(70.95,109)
  vias: v2(72.83,108.55) v2(72.83,107.86)
N17706210:
  vias: v1(93.17,103.26) v2(80.19,107.12) v2(80.19,106.35) v2(80.19,105.59) v2(80.19,104.83) v2(80.96,107.12) v2(80.96,106.35) v2(80.96,105.59) v2(80.96,104.83) v2(81.72,107.12) v2(81.72,106.35) v2(81.72,105.59) v2(81.72,104.83) v2(91.24,108.01) v2(91.24,107.37) v2(91.24,106.74) v2(91.24,106.1) v2(91.24,105.21) v2(91.24,104.45) v2(92,108.01) v2(92,107.37) v2(92,106.74) v2(92,105.97) v2(92,105.21) v2(92,104.45)
N17706708:
  vias: v1(91.6,115.93) v2(86.92,114.99) v2(87.69,118.17) v2(87.69,117.53) v2(87.69,116.9) v2(87.69,116.26) v2(87.69,115.63) v2(87.69,114.99) v2(88.32,118.17) v2(88.32,117.53) v2(88.32,116.9) v2(88.32,116.26) v2(88.32,115.63) v2(88.32,114.99) v2(88.96,118.17) v2(88.96,117.53) v2(88.96,116.9) v2(88.96,116.26) v2(88.96,115.63) v2(88.96,114.99) v2(89.59,114.99) v2(90.23,114.99) v2(90.73,114.23) v2(90.73,113.59) v2(90.86,114.99) v2(91.5,114.99)
N17754863: length 4.4
  BOTTOM w0.102: v1(169.37,108.17) 169.5,108.04 169.5,108.03 170.11,107.42 RL39.2 170.62,107.17 171.28,107.17 172.41,106.03 UL1.26
N17838023: length 14.7
  TOP w0.508: RX181.2 RX182.2 v1(194.29,80.84) RX179.2 RX180.2 RX183.2 RX184.2 RX185.2 RX186.2 193.78,90.86 192.23,90.86 QX3.1
N17847259: length 2.4
  BOTTOM w0.102: T4930.1 76.28,89.62 74.48,89.62 UV1.AL9
N17874049: length 4.2
  TOP w0.102: v1(142.77,119.08) 142.77,117.54 143.24,117.07 R620.2 144.28,117.07 144.46,117.25 Q12.2
N17874051: length 4.7
  TOP w0.102: Q12.1 146.74,119.33 147.85,120.44 v1(147.99,120.44) 149.12,120.44 R623.1 R621.1
N17876072: length 4.6
  TOP w0.102: v1(130.82,31.75) 131.76,32.69 R2448.2 R2450.1 131.8,33.72 U2407.7
N17877344: length 4.5
  BOTTOM w0.102: T223.1 62.58,98.23 63.18,97.63 63.18,94.97 62.8,94.6 UV1.R1
N17877347: length 3.5
  BOTTOM w0.102: T224.1 62.41,96.46 62.41,94.09 UV1.R3
N17882994: length 31.6
  BOTTOM w0.254: PR1042.2 53.02,33.96 52.71,33.66 49.51,33.66 48.12,35.05 48.12,41.09 v1(47.68,41.52) 47.25,41.95 47.25,55.66 49.38,57.79 50.62,57.79 PH1003.1
N17883462: length 2.7
  BOTTOM w0.102: UE1.75 112.79,31.7 112.96,31.87 v1(112.96,32.14) RE7.2
N17933206: length 64.4
  TOP w0.102: v1(51.75,37.25) 51.95,37.05 v3(52.5,37.05)
  TOP w0.254: PR1053.2 52.94,35.16 53.27,35.49 53.27,36.28 v3(52.5,37.05)
  IN2 w0.254: v3(52.5,37.05) 52.62,37.18 52.62,40.3 48.79,44.14 48.79,55.64 51.36,58.22 51.36,62.34 52.97,63.94 68.08,63.94 68.76,63.25 68.76,61.02 68.13,60.38 64.38,60.38 63.79,59.79 63.79,56.13 v3(63.57,55.91)
  BOTTOM w0.254: v3(63.57,55.91) 64.33,56.67 64.33,58.03 PL1003.3
N17933209:
  vias: v1(62.01,50.36)
N17933219: length 1.2
  TOP w0.102: PC1044.1 v1(74.34,49.5)
N17933234: length 1.4
  BOTTOM w0.102: PR1055.2 65.77,43.3 v1(66.39,43.92)
N17933249: length 1.4
  TOP w0.102: 65.35,48.56 v3(65.92,47.98)
  BOTTOM w0.102: v3(65.92,47.98) v1(66.33,48.39)
N17933268: length 3.8
  TOP w0.254: v3(75.16,51.69) 74.58,51.11 v1(74.48,51.11) 74.1,51.49 PC1302.1
  BOTTOM w0.254: v3(75.16,51.69) 74.46,52.4 PU1300.7
N17933717: length 5.3
  BOTTOM w0.102: UL3.3 168.14,115.82 168.89,116.56 RL40.2 168.89,118.98 v1(169.47,119.56)
N17965231: length 1.4
  TOP w0.102: v3(160.34,13.97) 160.66,13.97 T101.1
  BOTTOM w0.102: U2.K19 160.14,13.97 v3(160.34,13.97)
N17983950: length 11.2
  TOP w0.102: R537.2 R538.1 175.14,88.32 Q9.2 176.21,85.25 177.76,85.25 178.82,86.31 Q10.2 180.7,86.31 C935.1 181.08,86.24 v1(181.97,85.35)
N18017446: length 5.2
  TOP w0.102: QX5.2 196.02,72.62 RX15.1 197.39,71.3 197.97,70.72 199.32,70.72 v1(199.37,70.77)
N18053952: length 1.6
  TOP w0.102: C343.2 130.04,6.74 U15.12
N18092302: length 3.6
  TOP w0.102: v1(131.48,8.56) 131.48,7.38 C349.2 130.88,6.35 130.84,6.3 U15.10
N18116076: length 4.9
  TOP w0.254: v3(192.64,17.11) 192.68,17.11 193.22,17.66 RA34.1
  BOTTOM w0.203: v3(192.64,17.11) 192.81,17.29 UA1.13
  BOTTOM w0.254: v3(192.64,17.11) 192.22,17.11 v1(192.06,17.28) 191.34,17.28 RA155.1
N18296224:
  vias: v1(23.63,114.47)
N18386729:
  vias: v1(84.98,24.07)
N18386774: length 2.2
  BOTTOM w0.508: PC416.1 86.73,22.89 v1(87.57,22.89) 87.8,23.12 PR406.2
N18405073: length 3.6
  TOP w0.102: PC728.2 32.17,37.58 31.86,37.28 PQ714.1 31.86,35.52 v1(32.52,34.87)
N18406275:
  vias: v1(108.98,7.98)
N18406334: length 2.8
  BOTTOM w0.102: PC409.1 113.99,9.77 PR402.2 116.2,9.77 v1(116.6,10.18)
N18406395: length 5
  BOTTOM w0.102: v1(107.46,4.21) 107.99,4.74 109.94,4.74 PC410.1
  BOTTOM w0.254: PU400.7 111.18,5.05 PC410.1
N18406660: length 3.6
  BOTTOM w0.102: PC404.1 v1(108.16,5.31)
  BOTTOM w0.254: PC404.1 PR401.2 110.41,5.55 PU400.8
N18414408: length 1.5
  TOP w0.102: v1(207.96,5.35) 208.13,5.53 PC310.2
N18414459: length 3
  TOP w0.102: 206.69,4.74 v1(206.69,3.23)
  TOP w0.254: PC315.1 206.36,4.74 PR310.2
N18423379: length 10.1
  TOP w0.102: v2(71.05,113.69) 70.63,113.69 PR531.2 70.68,114.3 71.02,114.3 v2(71.05,114.33)
  IN1 w1.016: 71.51,114.99 73.67,117.15 76.54,117.15 77.68,118.29 78.54,118.29
  vias: v1(80.26,118.72) v2(79.94,118.27) v2(80.57,118.27)
N18424405: length 3.1
  TOP w0.102: PR535.1 57.07,119.37 v1(57.22,119.52)
  TOP w0.203: PR526.2 PR537.2 57.08,118.22 PR535.1
N18424435: length 3.5
  TOP w0.102: v1(55.59,114.84) 55.59,114.7 55.71,114.58 55.71,114.32 56.27,113.76 PR536.2 PR527.2 57.13,113.82 PR538.2
N18432502:
  vias: v1(97.63,58.18) v2(94.04,58.86) v2(94.37,58.3) v2(94.67,58.86) v2(95.31,63.17) v2(95.31,62.54) v2(95.31,61.9) v2(95.31,61.27) v2(95.31,60.63) v2(95.31,60) v2(95.31,59.36) v2(95.31,58.73) v2(95.69,32.06) v2(95.71,30.88) v2(96.02,31.5) v2(96.32,32.06) v2(96.35,30.87) v2(96.65,31.5) v2(96.96,32.06) v2(96.98,30.87) v2(97.34,31.45) v2(97.59,32.06) v2(97.64,30.87)
N18432559: length 1.6
  TOP w0.203: U16.12 92.79,64.48 C344.2
N18432569: length 1.6
  TOP w0.203: C348.2 92.79,65.28 U16.10
N18943829: length 18.5
  TOP w0.254: v3(27.62,23.93) 27.43,23.74 v1(27.43,22.57) 27.43,19.8 33.58,13.64 36.89,13.64 37.15,13.9 PR724.1
  BOTTOM w0.254: v3(27.62,23.93) 27.11,24.44 PR720.2
N18944147: length 24.5
  TOP w0.254: v3(26.73,23.93) 26.92,23.74 v1(26.92,20.39) 26.92,19.59 33.37,13.14 37.29,13.14 37.65,12.78 PC726.1 38.29,12.78 PC722.2 38.34,13.9 40.35,13.9 v3(40.48,13.77)
  BOTTOM w0.254: PR720.3 27.11,23.55 v3(26.73,23.93) ; PU700.17 40.53,13.83 v3(40.48,13.77)
N18956218: length 6.2
  TOP w0.102: v1(35.81,15.24) PR724.2
  TOP w0.254: PR724.2 37.15,15.24 PC722.1 39.12,14.41 39.15,14.44 v3(39.15,14.45)
  BOTTOM w0.254: PU700.18 39.28,14.33 v3(39.15,14.45)
N18967347: length 1.9
  BOTTOM w0.102: PC727.1 v1(51.45,12.21)
  BOTTOM w0.254: PC727.1 50.38,12.2 PR723.2
N18967375: length 4.3
  TOP w0.102: PC721.1 47.26,11.96 v1(47.4,11.82)
  TOP w0.254: v3(47.91,13.97) 47.91,13.82 47.39,13.3 PC721.1
  BOTTOM w0.254: PU700.4 46.92,14.33 47.01,14.24 47.64,14.24 v3(47.91,13.97)
N18967379: length 3
  BOTTOM w0.254: PR723.1 48.13,12.2 48.09,12.16 v1(47.63,12.16) 47.63,12.56 46.87,13.33 PU700.6
N18967435: length 4
  BOTTOM w0.254: PC723.1 48.28,11.31 47.85,10.88 v1(47.54,10.88) 47.06,11.36 47.06,12.6 46.84,12.82 PU700.7
N18967441: length 3.9
  BOTTOM w0.254: PR725.1 PR728.2 48.04,13.08 v1(47.67,13.45) 47.3,13.83 PU700.5
N18999155: length 6.6
  TOP w0.102: v3(47.43,18.09) 47.43,18.77 v1(47.67,19.02)
  TOP w0.254: PC706.1 47.4,18.06 v3(47.43,18.09)
  BOTTOM w0.254: PR704.2 47.3,19.17 PC709.1 47.49,18.15 v3(47.43,18.09) 46.79,17.45 45.65,17.45 45.44,17.25 PU700.28
N19000258: length 6
  TOP w0.102: v1(45.84,19.02) 46.16,18.7 v3(46.16,18.09)
  TOP w0.254: PC707.1 v3(46.16,18.09)
  BOTTOM w0.254: PR705.2 46.41,19.3 PC709.2 46.16,18.91 v3(46.16,18.09) 45.65,18.09 44.94,17.38 PU700.27
N19021042: length 13.7
  TOP w0.102: v1(44.29,18.7) 44.48,18.51 v3(44.48,18.14) 44.94,17.68 PC710.1
  BOTTOM w0.254: PR709.2 41.13,21.35 42.79,23.02 44.65,23.02 45.56,22.1 45.56,19.73 44.48,18.65 v3(44.48,18.14) 44.44,18.1 PU700.26
N19095003: length 5
  BOTTOM w0.102: v1(48.41,9.88) 47.87,10.42 46.45,10.42 46.02,9.99
  BOTTOM w0.254: PU700.8 45.44,10.57 46.02,9.99 46.02,9.99 PR722.2
N19142937: length 13.2
  BOTTOM w0.102: v3(26.73,31.91) 26.17,32.47 PQ704.4 24.67,32.47 23.45,33.68 23.45,37.93 23.81,38.28 26.63,38.28 27.37,37.54 PQ705.4
  vias: v1(31.59,30.74)
N19197525: length 3.3
  TOP w0.102: UX4.3 23.12,74.15 RX10.2 25.27,73.32 25.27,72.83 v1(25.46,72.64)
N19200597: length 3.6
  TOP w0.102: v1(11.88,72.48) 11.68,72.68 QV7.1 RX3.2
N19245880: length 1.9
  TOP w0.102: CZ15.1 73.74,35.43 U6.10
N19245882: length 1.9
  TOP w0.102: CZ9.1 72.94,35.43 U6.12
N19565438: length 5.8
  TOP w0.102: v1(28.02,27.04) 27.69,27.37 27.69,29.3 27.15,29.84 PQ707.2
  TOP w0.254: PQ708.1 27.15,30.28 PQ707.2
N19565442: length 13.3
  TOP w0.102: PQ709.3 25.83,33.45 26.28,33 v3(26.65,33) ; v3(28.58,32.47) 28.58,32.57 29.25,33.23 PR703.2 ; v3(24.61,37.44) 24.64,37.41 25.6,37.41 25.63,37.38 PQ710.3
  IN2 w0.127: v3(24.61,37.44) 24.14,36.97 24.14,35.64 26.65,33.13 v3(26.65,33) 27.18,32.47 v3(28.58,32.47)
  BOTTOM w0.102: v3(28.58,32.47) v1(27.95,32.47)
N19565444: length 8.8
  TOP w0.102: v1(24.12,37.27) 24.5,36.89 24.83,36.89 25.18,36.54 PQ709.5
  TOP w0.254: PQ709.5 PQ709.2 25.18,33.42 26.08,32.52 26.88,32.52 27.38,33.02 PR712.2 27.38,33.99 PQ712.1
N19565472: length 3.6
  TOP w0.102: PR708.1 v1(54.8,15.91)
  TOP w0.254: PR708.1 52.65,15.19 PQ711.1
N19605393: length 3.9
  BOTTOM w0.305: v3(150.96,23.88) 150.96,23.61 U2.AA9 ; v3(151.7,22.64) 151.7,22.87 U2.AA10 ; v3(152.42,22.69) 152.9,23.17 U2.AA11 ; v3(151.7,23.89) 152.1,24.29 U2.AB10 ; U2.AB11 152.9,24.29 v3(152.5,23.89)
  vias: v1(151.99,23.36)
N19634132: length 1.4
  TOP w0.102: RX28.1 14.09,96.33 v1(13.69,95.93)
N19636367: length 28.4
  TOP w0.254: QA6.2 189.92,33.2 189.92,33.25 RA7.2 188.45,34.01 v3(188.4,33.96)
  BOTTOM w0.254: v3(188.4,33.96) 188.14,33.71 188.14,29.9 185.73,27.49 185.73,24.19 184.97,23.42 184.97,20.88 v1(185.97,19.89) 186.4,19.45 186.83,19.45 190.18,16.11 191.48,16.11 192.23,15.36 192.23,14.56 RA6.2
N19792312: length 5.3
  TOP w0.102: QA5.6 190.67,23.07 189.95,22.34 189.95,21.24 190.51,20.68 RA2.2 ; QA5.6 189.61,23.48 v1(189.49,23.36) ; QA5.6 QA5.5
N19794620: length 3.1
  TOP w0.102: QA6.6 QA6.5 193.15,33.2 RA5.2 194.29,33.13 v1(194.58,32.83)
N21178712:
  vias: v1(35.13,110.32)
N22376776: length 5.9
  TOP w0.102: v1(36.56,106.42) PC5.1
  TOP w0.254: PR1.2 PC5.1 36.43,108.01 PQ1.2
N23700314: length 10.1
  TOP w0.508: PR6.2 v1(19.67,103.4) 19.67,104.58 PL2.1 20.59,105.29 22,106.71 PQ6.1 23.73,106.71 24.44,106 PR11.1
N26541745: length 7.5
  BOTTOM w0.102: UH1.2 141.15,31.88 140.43,32.6 RH28.1 139.41,31.81 v1(139.2,31.6) ; UH1.2 141.15,30.27 RH26.2 CH16.1 141.63,29.31 RH25.2 ; UH1.2 UH1.1
N29435472: length 8
  TOP w0.102: PR530.1 70.59,105.63 v1(70.73,105.49)
  TOP w0.203: PU500.40 66.72,110.56 66.95,110.33 66.95,109.77 67.81,108.91 67.81,108.83 68.46,108.18 70.01,108.18 70.59,107.6 PR530.1
N29440660: length 37.6
  TOP w0.254: v3(93.78,116.51) 93.97,116.7 94.53,116.7 95.71,117.88 95.71,120.06 94.43,121.34 v1(69.06,121.34) 67.85,121.34 66.81,120.3 PR545.1
  BOTTOM w0.254: PL501.3 93.25,117.05 v3(93.78,116.51)
N29446286: length 42
  BOTTOM w0.254: PL500.3 96.5,106.81 96.75,106.56 96.75,104.33 93.42,100.99 84.75,100.99 82.54,98.78 79.43,98.78 78.64,99.57 76.8,99.57 74.31,102.06 71.66,102.06 70.03,103.69 v1(66.86,103.69) 66.55,103.99 PR515.1
N29452663: length 3.6
  TOP w0.203: PU500.37 64.95,109.4 65.6,108.75 v2(66.39,108.75)
  BOTTOM w0.102: v1(66.97,108.84) 66.48,108.84 v2(66.39,108.75) 66.07,108.44 PR547.1
N29508268: length 2.1
  TOP w0.102: v1(60.31,121.29) 60.56,121.04 PR508.1
  TOP w0.203: PR508.1 PC501.2
N29585076: length 63.6
  TOP w0.102: v1(53.88,114.37) 54.35,113.9 v3(54.74,113.9) 54.92,113.72 PR536.1
  IN3 w0.135: v3(94.62,112.09) 94.62,111.56 99.12,107.07 99.12,103.59 98.48,102.95 97.91,102.95 96.1,101.14 94.96,101.14 94.83,101.02 73.47,101.02 71.22,103.26 67.23,103.26 56.6,113.9 v3(54.74,113.9)
  BOTTOM w0.102: PH501.1 v3(94.62,112.09)
N29604543: length 55.9
  TOP w0.102: v3(58.08,118.91) 57.98,118.81 PR535.2
  IN3 w0.135: v3(58.08,118.91) 58.08,116.17 60.45,113.81 60.45,110.94 67.58,103.8 71.44,103.8 73.69,101.56 94.61,101.56 94.73,101.68 95.88,101.68 98.23,104.04 v3(98.23,104.2)
  BOTTOM w0.102: v1(97.72,101.31) 98.02,101.62 PH500.1 97.72,102.72 97.72,103.69 v3(98.23,104.2)
N29680084: length 2.1
  TOP w0.102: v1(66.15,104.51) PC533.2
  TOP w0.203: PC533.2 PR557.1
N29794252: length 0.9
  TOP w0.102: PR553.2 PR554.1
N29794938: length 2
  TOP w0.102: v1(55.3,109.88) 55.59,110.18 PR559.2 57.12,110.18 PR560.1
N29841026: length 2.1
  TOP w0.102: PR730.2 18.24,34.03 v1(17.74,33.52)
N29896706: length 9.9
  BOTTOM w0.102: v1(140.72,5.36) 141.45,6.09 141.45,8.22 140.95,8.73 140.95,8.96 140.63,9.28 R796.2 R787.2 139.24,9.42 C5.2 137.13,10.14 UG1.10
N29896995: length 5.4
  BOTTOM w0.102: UG1.14 135.53,11.22 134.83,10.52 134.83,9.81 134.54,9.52 C10.1 132.78,9.52 R790.2 v1(131.6,9.53)
N35316585: length 2
  BOTTOM w0.102: CE10.1 RE6.2 117.81,13.21 v1(118.07,13.47)
N37640332: length 10
  TOP w0.102: RV2.2 61.91,96.94 v3(62.07,96.77)
  IN3 w0.127: v3(61.65,89.34) 61.65,89.35 61.08,89.92 61.08,91.19 61.52,91.62 61.52,94.89 61.75,95.11 62.06,95.11 62.37,95.42 62.37,96.47 v3(62.07,96.77)
  BOTTOM w0.102: v3(61.65,89.34) 61.21,88.9 UV1.N10
N37640410: length 1.5
  TOP w0.102: v3(67.53,78.7) 67.52,78.7 67.52,78.72 68.08,78.17 RV3.1
  BOTTOM w0.102: v3(67.53,78.7) 67.52,78.7 67.52,78.72 67.4,78.85 UV1.AA22
N37817724: length 2.1
  TOP w0.102: RV1.1 66.71,78.31 v3(66.35,78.67) 66.35,79.07 v1(66.54,79.27)
  BOTTOM w0.102: UV1.Y22 66.4,78.72 v3(66.35,78.67)
N38023415: length 2.9
  TOP w0.102: RV37.2 RV36.2 CV96.1 v1(66.91,98)
N38028869: length 9.1
  TOP w0.102: v3(59.17,90.1) 59.17,90.11 59.95,90.89 59.95,91 60.64,91.69 62.38,91.69 63.02,92.33 63.02,92.73 63.94,93.64 v1(63.94,94.12) 63.73,94.33 CV98.2
  BOTTOM w0.102: UV1.K8 58.8,90.47 v3(59.17,90.1)
N38028873: length 8.5
  TOP w0.102: CV99.2 63.16,95.24 63.16,93.16 62.67,92.67 v1(62.67,92.48) 62.11,91.93 60.59,91.93 59.52,90.86 v3(59.18,90.86)
  BOTTOM w0.102: UV1.L7 59.62,91.3 v3(59.18,90.86)
N38028878: length 4.3
  TOP w0.102: v1(63.91,100.22) 63.26,99.57 63.26,97.67 63.54,97.39 RV40.2 CV98.1
N38028880: length 0.9
  TOP w0.102: RV41.2 CV99.1
N38039273: length 5.1
  BOTTOM w0.102: UV5.L8 34.95,77.84 34.52,78.27 34.52,79.58 v1(35.52,80.57) 35.99,81.04 35.99,81.12 RV46.1
N38046520: length 2.8
  BOTTOM w0.102: RV49.2 RV48.2 ; RV48.2 v1(38.41,67.01) ; RV48.2 CV102.1
N38049955: length 5.1
  TOP w0.102: UV6.L8 34.55,72.52 34.55,71.25 34.27,70.97 v3(33.74,70.97)
  BOTTOM w0.102: v3(33.74,70.97) 33.48,70.72 v1(33.48,69.84) 33.48,69.45 RV47.1
N38097860: length 1.8
  BOTTOM w0.102: CV135.1 RV54.2 RV55.2
N38342282: length 4.1
  TOP w0.102: v3(59.14,77.29) 59.15,77.29 59.69,76.75 v1(59.69,76.67) 59.69,76.33 59.59,76.23 59.59,74.58 RV39.2
  BOTTOM w0.102: v3(59.14,77.29) 58.8,76.96 UV1.K25
N39970373: length 5.3
  TOP w0.102: v1(28.28,39.84) PQ710.6 28.92,38.68 PR718.2 29.69,37.67 28.45,36.42 PQ712.2
N40470227: length 10.6
  BOTTOM w0.102: T107.1 155.99,34.96 155.99,31.8 155.93,31.73 155.93,28.95 155.48,28.49 155.48,26.46 154.94,25.92 U2.AD13
N40473308: length 11.6
  TOP w0.102: v3(157.84,32.16) 159.65,30.36 159.65,28.1 159.85,27.89 159.85,26.65 160.32,26.18 v3(160.32,26.05)
  BOTTOM w0.102: U2.AD21 160.45,25.92 v3(160.32,26.05) ; T108.1 157.77,35.08 157.77,32.24 v3(157.84,32.16)
N47007806: length 4.5
  TOP w0.102: v1(37.5,115.07) 37.39,114.96 PR28.2
  TOP w0.254: PR28.2 PC16.1 36.44,113.61 PQ2.3
N47007810: length 5.9
  TOP w0.102: v1(38.6,111.08) 36.79,111.08 36.56,111.31 PR29.1
  TOP w0.254: PQ2.2 36.3,112.96 PC16.2 36.51,111.87 PR29.1
N47007850: length 5.4
  TOP w0.102: PR33.2 31.12,114.13 31.69,114.7 v1(32.9,114.7)
  TOP w0.254: PR31.1 PR33.2 31.45,113.47 31.96,112.96 PQ2.5
N47008006: length 1.4
  TOP w0.102: PR10.2 v1(31.12,105.97)
N47415217: length 1.4
  TOP w0.102: 72.62,22.72 73.06,23.16 v1(73.06,23.91)
N47415258: length 5.1
  TOP w0.102: v1(67.52,26.32) 69.4,24.44 PR113.2
  TOP w0.508: PR113.2 70.35,23.51 70.34,23.5 PC103.1
N47415272:
  vias: v1(66.07,10.16)
N47415370: length 1.1
  TOP w0.102: v1(70.69,11.97) 70.52,12.15 PR111.2
N47420895:
  vias: v1(87.42,21.59)
N47445410: length 2.3
  TOP w0.203: PU100.19 72.67,16.09 72.83,15.93 72.83,15.42 v1(72.85,15.4) 72.9,15.35 PR114.1
N52907207: length 58.7
  TOP w0.102: v1(53.18,17.54) 53.18,16.96 52.86,16.64 v3(52.41,16.64)
  TOP w0.254: v3(52.41,16.64) 52.46,16.58 PR708.2
  IN2 w0.254: v3(24.73,30.72) 24.8,30.65 24.8,27.33 24.47,27 23.45,27 22.79,26.34 22.79,19.87 35.36,7.29 47.81,7.29 52.63,12.12 52.63,16.41 v3(52.41,16.64)
  BOTTOM w0.254: v3(24.73,30.72) 24.83,30.62 24.83,29.56 PQ706.4 ; v3(52.41,16.64) 52.41,16.57 51.68,15.84 PR706.1
N52907447: length 2.9
  TOP w0.102: PR714.1 49.61,15.92 v1(49.31,15.61)
  TOP w0.254: PR714.1 50.66,15.07 PQ711.2
N55201771: length 12.9
  TOP w0.102: JHDMI.13 202.77,82.92 202.77,80.32 201.81,79.35 201.24,79.35 200.36,78.47 200.36,77.31 200.56,77.11 200.56,75.52 v1(199.47,74.42) 199.02,73.97 RX12.2
N59110921: length 7.3
  BOTTOM w0.102: RE4.1 128.47,22.6 v1(128.24,22.6) 127.92,22.6 127.48,23.04 125.1,23.04 124.8,23.35 123.75,23.35 123.7,23.39 UE1.111
N59110936: length 6.1
  BOTTOM w0.102: UE1.109 123.81,24.19 123.98,24.36 124.42,24.36 124.72,24.06 127.21,24.06 v1(127.51,24.36) 127.72,24.57 RE15.1
N63469524: length 6.8
  TOP w0.102: v3(189.67,25.94) 189.34,25.94 188.78,26.5 RA82.1
  BOTTOM w0.102: v1(188.64,23.04) CA68.2 189.06,23.97 189.06,25.51 189.49,25.94 v3(189.67,25.94)
N63469526: length 6.5
  TOP w0.102: RA80.1 188.73,28.93 188.02,28.22 188.02,26.98 189.64,25.35 v3(189.69,25.35) 189.69,25.25 v1(189.19,24.74)
  BOTTOM w0.102: CA67.2 189.99,25.06 v3(189.69,25.35)
N64564173: length 3.3
  BOTTOM w0.102: PR1101.2 35.55,42.46 v1(34.83,41.74)
  BOTTOM w0.508: PR1101.2 35.49,43.55 PC1103.1
N64564191: length 2.9
  TOP w0.102: v1(39.11,52.39) PR1104.2
  TOP w0.508: PC1106.1 39.62,50.35 PR1104.2
N80846772: length 3.4
  BOTTOM w0.102: U2.AM17 157.9,31.39 156.9,32.39 156.9,33.71 T99.1
N80928600: length 8.5
  BOTTOM w0.102: U2.J19 159.04,12.76 159.04,11.93 158.85,11.74 158.85,11.34 159.07,11.13 159.07,5.76 T102.1
N80957082: length 1.4
  TOP w0.102: v3(160.33,12.8) 160.79,13.27 RH72.1
  BOTTOM w0.102: U2.H19 159.91,12.83 160.3,12.83 v3(160.33,12.8)
N80957084: length 2.2
  TOP w0.102: v1(159.11,10.95) 159.11,11.27 v3(159.37,11.53) 159.59,11.31 RH75.1
  BOTTOM w0.102: U2.G19 159.76,11.92 v3(159.37,11.53)
N81028957: length 2.9
  TOP w0.102: v3(169.65,15.36) 169.65,15.44 v1(170.16,15.96)
  TOP w0.254: v3(169.65,15.36) CH43.2
  BOTTOM w0.102: v3(169.65,15.36) 168.88,16.12 U2.M31
N84425324: length 4.9
  BOTTOM w0.102: U2.AB6 148.75,24.13 148.37,24.5 146.41,24.5 146.28,24.63 145.41,24.63 145.05,24.99 145.05,25.01 T97.1

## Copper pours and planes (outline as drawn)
1.35V_B+ on BOTTOM (solid shape): 80.83,17.53 80.83,17 81.01,16.82 89.44,16.82 89.64,16.62 89.64,14.33 89.46,14.15 86.8,14.15 85.91,15.04 85.9,15.04 85.88,15.06 85.79,15.12 85.67,15.14 85.64,15.15 85.53,15.27 84.31,15.27 84.08,15.04 79.76,15.04 78.42,16.39 78.42,17.5 78.62,17.71 80.65,17.71
3/5V_B+ on TOP (solid shape): 63.18,22.72 63.18,18.6 63.19,18.46 63.19,18.13 63.13,18.06 62.54,18.06 61.91,17.43 61.91,14.79 61.78,14.66 58.6,14.66 58.54,14.72 58.54,17.57 58.87,17.9 58.87,23.57 59.21,23.91 61.99,23.91
3/5V_B+ on BOTTOM (solid shape): 62.16,20.82 63.18,20.82 63.43,20.57 63.43,18.72 63.18,18.47 63.18,17.05 63.1,16.97 58.58,16.97 58.41,17.14 58.41,18.41 58.95,18.95 58.95,20.91 59.56,21.52 61.46,21.52
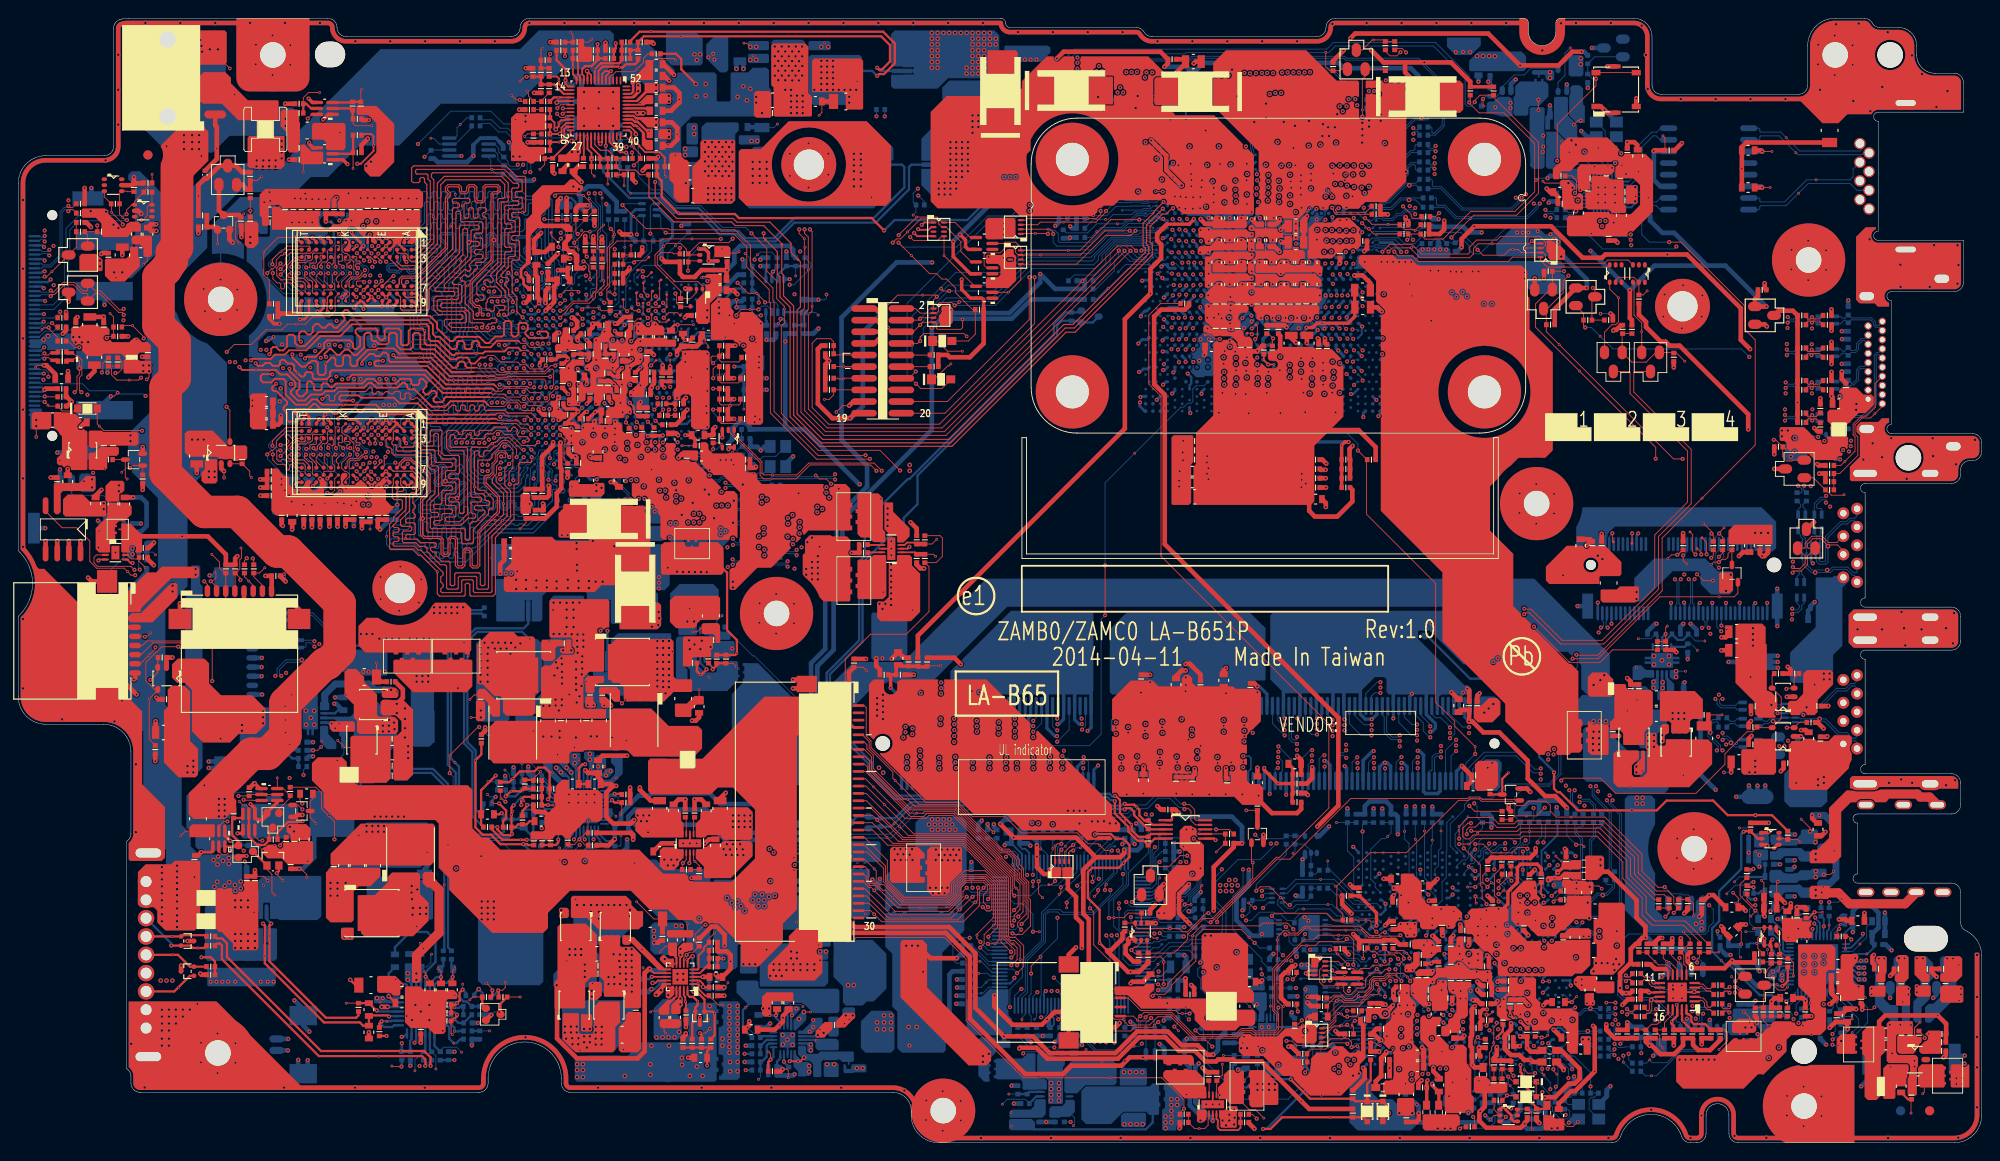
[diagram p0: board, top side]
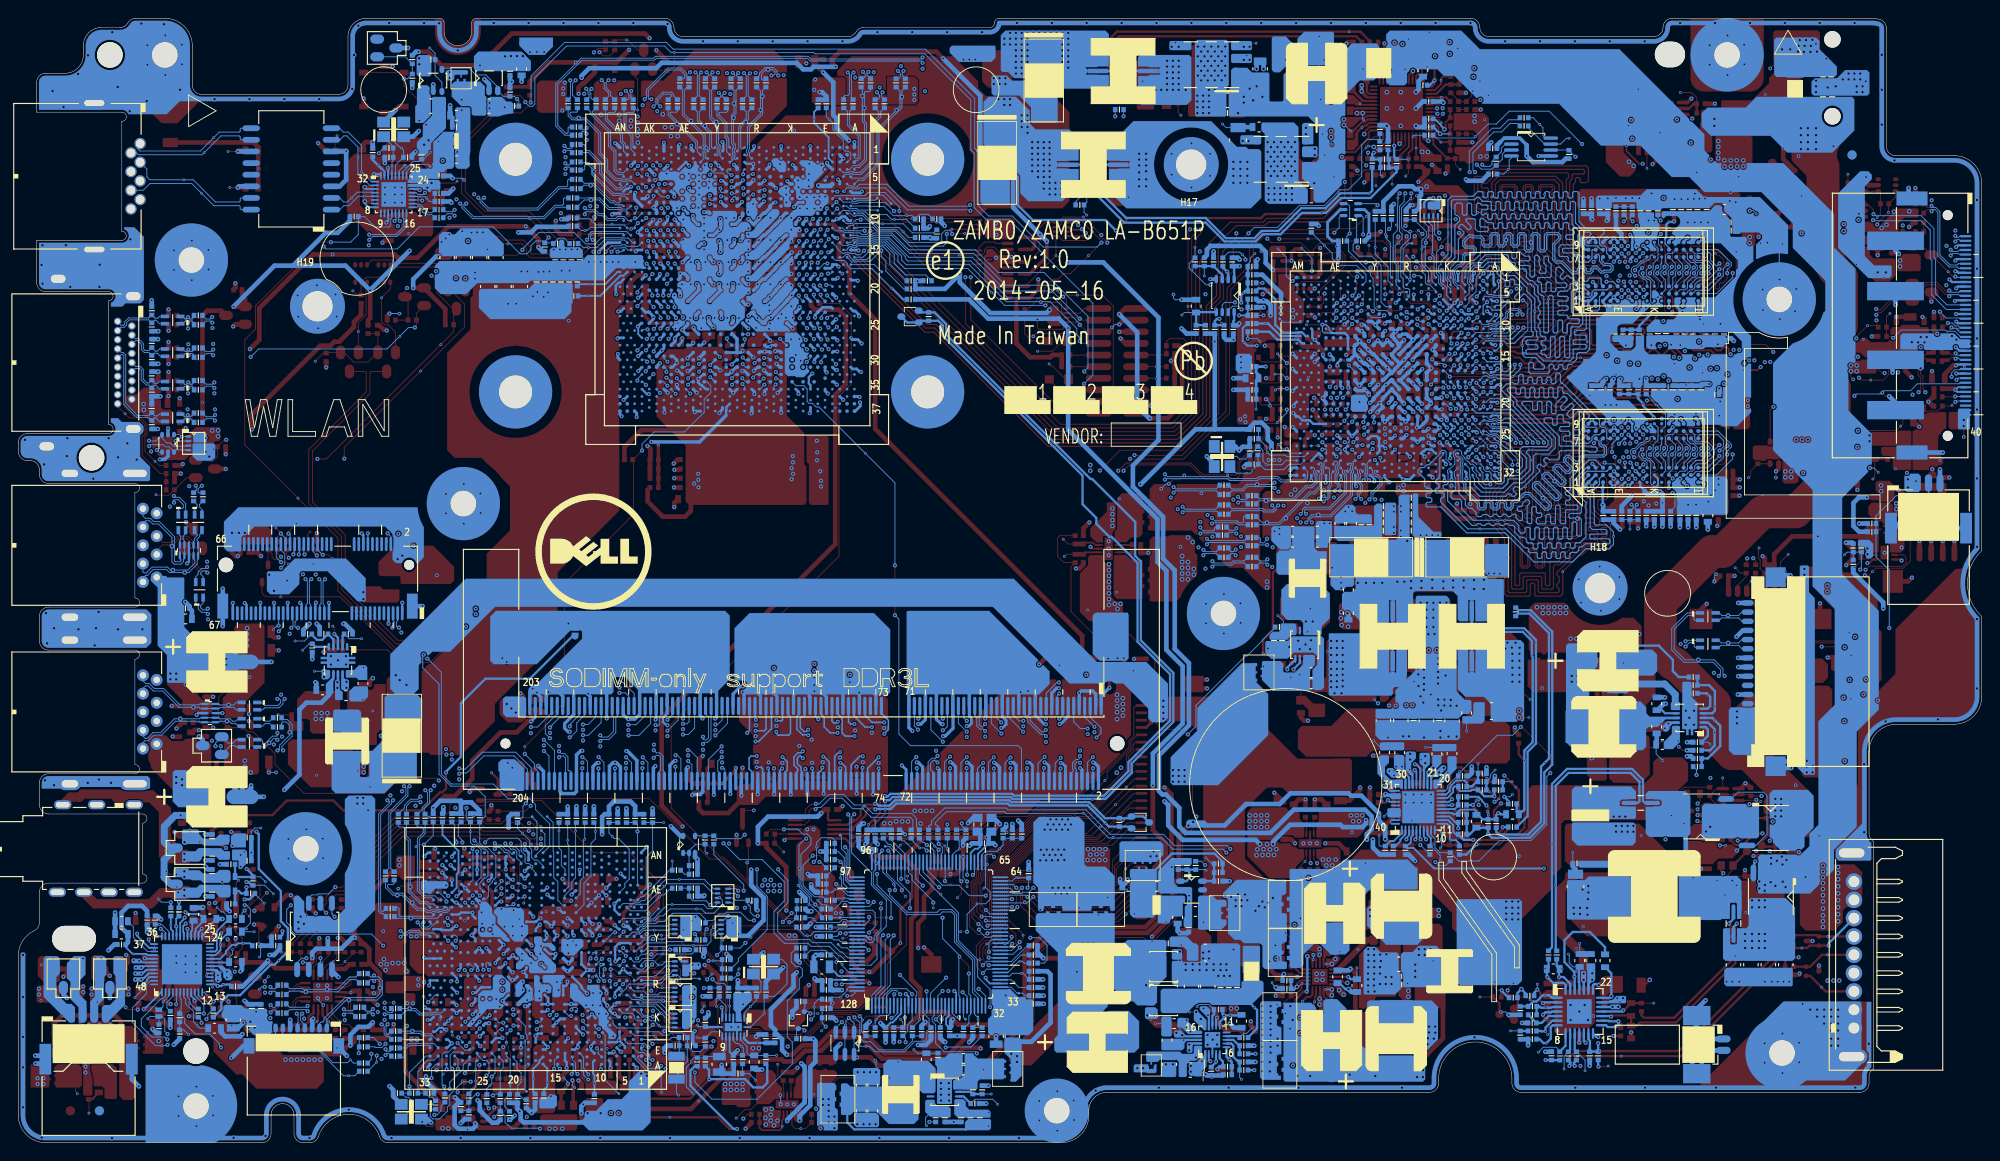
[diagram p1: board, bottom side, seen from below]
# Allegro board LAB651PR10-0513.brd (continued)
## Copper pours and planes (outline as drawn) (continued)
+0.675VS on TOP (solid shape): 161.85,48.19 161.85,46.79 160.97,45.9 159.39,45.9 158.93,46.35 158.93,47.55 159.06,47.68 159.7,47.68 160.58,48.57 161.47,48.57
+0.675VS on TOP (solid shape): 161.6,41.46 161.6,39.04 161.02,38.46 160.3,38.46 160.3,38.41 159.31,38.41 159.06,38.66 159.06,39.7 159.06,39.7 159.06,40.52 159.06,40.52 159.06,41.33 159.44,41.71 161.35,41.71
+0.675VS on TOP (solid shape): outline of 201 points within 124.24,24.36 129.47,34.62
+0.675VS on BOTTOM (solid shape): 161.98,41.5 161.98,40.62 161.86,40.49 161.86,38.84 161.43,38.41 159.26,38.41 159.16,38.51 159.16,40.87 160.18,41.89 161.6,41.89
+0.675VS on BOTTOM (solid shape): 159.45,48.74 159.57,48.72 159.68,48.74 159.69,48.74 161.22,48.74 161.48,48.49 161.48,46.84 161.1,46.46 159.19,46.46 158.94,46.71 158.94,48.49 159.19,48.74 159.45,48.74
+0.675VS on BOTTOM (solid shape): 90.3,8.56 90.34,8.55 90.35,8.51 90.35,8.06 90.99,8.06 90.99,8.51 91,8.55 91.04,8.56 92.46,8.56 92.61,8.41 92.61,7.78 92.51,7.68 90.15,7.68 90.11,7.69 90.1,7.73 90.1,8.51 90.11,8.55 90.15,8.56
+0.675VS on IN1 (solid shape): 93.2,8.89 93.2,7.68 93,7.47 92.69,7.47 92.67,7.45 91.03,7.45 90.81,7.68 90.81,8.87 90.94,9 93.1,9
+0.675VS on IN1 (solid shape): 125.79,25.43 125.79,24.74 125.36,24.31 124.21,24.31 123.96,24.57 123.96,25.46 124.11,25.61 124.13,25.61 124.2,25.61 124.27,25.63 125.58,25.63
+0.675VS on IN2 (solid shape): 161.75,41.66 161.75,41.18 160.66,40.09 159.09,40.09 158.6,40.57 158.6,41.63 159.02,42.05 160.22,42.05 160.23,42.07 161.35,42.07
+0.675VS on IN2 (solid shape): 129.47,34.78 129.47,33.89 129.11,33.53 128.49,33.53 128.48,33.54 128.35,33.56 128.23,33.54 128.22,33.53 127.13,33.53 126.96,33.71 126.96,34.83 127.11,34.98 129.27,34.98
+0.675VS on IN3 (solid shape): outline of 88 points within 159.31,40.06 163,48.44
+0.675VSP on BOTTOM (solid shape): 86.04,10.47 86.04,9.83 86.16,9.71 87.31,9.71 87.56,9.96 91.12,9.96 91.24,9.83 91.24,8.95 91.12,8.82 89.97,8.82 89.72,9.07 87.94,9.07 87.69,8.82 87.69,7.29 87.56,7.17 86.92,7.17 86.8,7.29 86.8,8.56 86.42,8.95 85.83,8.95 85.15,9.63 85.15,10.47 85.27,10.6 85.91,10.6
+1.1VALW on TOP (solid shape): 167.72,2.98 167.72,2.76 167.85,2.63 168.76,2.63 168.84,2.55 168.84,2.54 168.84,1.45 168.71,1.33 166.68,1.33 166.55,1.45 166.55,2.96 166.58,2.99 167.71,2.99
+1.1VALW on TOP (solid shape): 133.15,3.87 133.15,3.51 133.08,3.51 133.08,3.28 133.05,3.26 133.05,1.71 132.98,1.63 131.37,1.63 131.27,1.74 131.27,1.76 131.27,1.83 131.25,1.9 131.25,1.91 131.25,2.6 131.12,2.72 131.15,2.75 131.15,2.76 131.15,3.51 131.18,3.55 131.69,3.55 131.77,3.62 131.81,3.62 131.81,3.66 132.14,3.99 133.03,3.99
+1.1VALW on TOP (solid shape): 157.41,2.85 157.41,1.89 157.37,1.89 157.12,1.73 157.07,1.45 157.05,1.36 156.98,1.33 153.6,1.33 153.35,1.58 153.35,2.98 153.47,3.1 157.16,3.1
+1.1VALW on BOTTOM (solid shape): 127.18,6.41 127.18,4.06 127.15,4.04 126.93,3.71 127.15,3.38 127.18,3.37 127.18,1.94 127.13,1.85 127.02,1.86 126.59,1.87 126.47,1.46 126.45,1.37 126.37,1.33 125.02,1.33 124.9,1.45 124.9,3.55 125.15,3.8 125.22,3.8 125.22,4.51 125.15,4.51 125.15,5 125.22,5 125.22,5.71 125.15,5.71 125.15,6.41 125.28,6.53 127.06,6.53
+1.1VALW on VCC: 124.9,1.27 124.9,4.65 125.33,5.08 126.85,6.48 127.67,7.29 140.92,7.29 142.32,5.9 167.21,5.9 168.59,4.52 168.59,1.27
+1.1VALWP on BOTTOM (solid shape): 111.03,2.24 111.03,1.88 111.03,1.4 110.98,1.35 108.39,1.35 108.17,1.57 108.17,2.46 108.31,2.6 110.67,2.6
+1.1VALWP on BOTTOM (solid shape): 124.57,6.35 124.57,3.13 124.47,3.03 123.5,3.03 123.15,3.38 120.68,3.38 119.34,2.04 116.59,2.04 116.08,2.54 116.08,5.67 116.57,6.15 123.55,6.15 123.88,6.48 124.44,6.48
+1.1VALWP_ON on BOTTOM (solid shape): 115.37,4.55 115.37,3.36 114.84,2.82 113.82,2.82 113.72,2.72 112.71,2.72 112.58,2.85 112.58,3.74 112.83,3.99 113.98,3.99 114.33,4.34 114.33,4.58 114.42,4.68 115.24,4.68
+1.1VS on TOP (solid shape): 171.71,11.59 171.71,9.68 171.63,9.61 170.97,9.61 170.92,9.66 170.92,10.67 170.86,10.74 170.69,10.74 170.62,10.81 170.62,11.54 170.72,11.64 171.66,11.64
+1.1VS on TOP (solid shape): 137.6,6.41 137.6,4.25 137.47,4.12 136.07,4.12 135.82,3.87 134.68,3.87 134.42,4.12 134.42,5.2 134.49,5.2 134.49,5.9 134.42,5.9 134.42,6.4 134.49,6.4 134.49,7.1 134.42,7.1 134.42,7.8 134.55,7.93 136.07,7.93
+1.1VS on TOP (solid shape): outline of 142 points within 171.63,18.34 175.44,26.22
+1.1VS on IN2 (solid shape): outline of 3303 points within 134.93,4.41 175.32,20.25
+1.1VS_CKVDD on TOP (solid shape): outline of 491 points within 161.45,9.71 170.36,18.06
+1.1VS_CKVDD on BOTTOM (solid shape): outline of 270 points within 160.69,12.63 165.39,18.34
+1.1VS_CKVDD on IN2 (solid shape): outline of 435 points within 161.22,12.88 165.79,17.84
+1.1VS_OUT on TOP (solid shape): 132.83,7.89 133.18,7.62 133.52,7.89 133.53,7.93 133.66,7.93 133.84,7.75 133.84,4.32 133.74,4.22 132.34,4.22 131.81,4.75 131.81,4.77 131.11,4.77 131.04,4.83 131.05,4.86 131.06,4.9 131.06,4.94 131.06,5.5 131.05,5.59 130.99,5.66 130.99,6.02 131.63,6.66 131.63,7.32 131.63,7.42 132.14,7.93 132.82,7.93
+1.5VS on TOP (solid shape): 200.59,9.83 200.46,9.71 198.68,9.71 198.56,9.83 198.56,11.36 199.07,11.87 200.59,11.87
+1.05VS on TOP (solid shape): outline of 798 points within 146.36,42.35 170.74,96.96
+1.05VS on BOTTOM (solid shape): outline of 212 points within 145.83,92.67 168.93,96.96
+1.5VSP on TOP (solid shape): 203.89,12.5 203.89,9.96 203.38,9.45 203.38,5.14 202.9,4.65 201.96,4.65 201.61,5.01 201.61,9.45 201.35,9.71 201.35,12.12 201.99,12.76 203.64,12.76
+1.05VSP on TOP (solid shape): 171.64,45.98 171.89,45.67 172.29,45.76 172.36,45.79 172.43,45.76 172.69,45.65 172.96,45.75 173.03,45.78 173.1,45.75 173.3,45.65 173.52,45.68 173.62,45.68 173.67,45.59 173.67,42.47 173.54,42.35 171.76,42.35 171.38,42.73 171.38,46.03 171.63,46.03
+1.05VSP on BOTTOM (solid shape): 174.43,45.14 174.43,44.12 175.77,42.78 180.04,42.78 180.19,42.63 180.19,38.59 179.76,38.16 174.43,38.16 173.16,39.43 171.23,39.43 170.87,39.78 170.87,41.46 176.08,41.46 176.08,40.06 176.21,39.93 176.97,39.93 177.09,40.06 177.09,41.46 176.97,41.58 176.21,41.58 176.08,41.46 170.87,41.46 170.87,45.14 171.13,45.39 174.17,45.39
+1.05VSP_B+ on TOP (solid shape): 175.57,49.97 175.57,49.71 175.82,49.46 178.24,49.46 178.49,49.2 178.49,45.78 177.55,44.83 177.55,43.44 175.31,43.44 175.25,43.5 175.25,44.69 174.85,45.09 173.82,45.09 173.79,45.11 173.79,45.93 174.28,46.41 174.28,48.02 174.28,48.75 174.28,50.07 174.3,50.09 175.44,50.09
+1.5VSP_ON on TOP (solid shape): 207.17,11.78 207.17,11.75 207.35,11.57 207.82,11.57 207.83,11.56 207.83,10.98 207.19,10.34 207.19,9.96 206.94,9.71 205.42,9.71 205.16,9.96 205.16,11.61 205.29,11.74 206.91,11.74 206.97,11.79 207.16,11.79
+1.8VGS on TOP (solid shape): 61.25,104.68 61.38,104.6 61.54,104.58 61.62,104.55 61.65,104.48 61.65,104.07 61.4,103.81 58.48,103.81 58.1,103.43 58.1,102.29 57.08,101.27 57.08,100.64 57.33,100.39 60.13,100.39 60.51,100 60.51,99.5 59.75,99.5 59.37,99.88 56.7,99.88 55.94,99.12 55.94,96.07 55.68,95.81 55.43,95.81 55.43,96.23 55.43,96.23 55.43,98.43 55.43,98.45 55.43,98.86 55.43,98.86 55.43,100.77 56.06,101.4 56.1,101.44 56.1,103.47 57.21,104.58 59.62,104.58 60.25,105.21 60.72,105.21
+1.8VGS on TOP (solid shape): outline of 149 points within 75.62,78.41 81.34,92.27
+1.8VGS on TOP (solid shape): outline of 842 points within 74.48,60.38 90.86,76.51
+1.8VGS on BOTTOM (solid shape): 81.46,85.91 81.46,84.38 81.08,84 80.83,84 80.83,84.07 79.94,84.07 79.94,84 79.81,84 79.69,84.13 79.69,85.91 79.94,86.16 81.21,86.16
+1.8VGS on BOTTOM (solid shape): 86.87,35.03 86.87,34.5 86.77,34.4 85.43,34.4 85.35,34.47 84.64,34.47 84.51,34.6 84.51,34.85 84.87,35.21 85.91,35.21 85.99,35.28 86.62,35.28
+1.8VGS on IN1 (solid shape): 81.84,79.18 81.84,76.51 81.26,75.93 81.21,75.95 81.16,75.97 81.1,75.98 81.05,75.98 80.99,75.97 80.94,75.95 80.89,75.92 80.85,75.89 80.81,75.85 80.78,75.81 80.76,75.76 80.74,75.71 80.73,75.66 80.73,75.6 80.73,75.55 80.75,75.5 80.77,75.44 78.8,73.46 77.15,73.46 76.72,73.89 76.72,74.27 76.26,74.74 76.26,75.62 76.41,75.77 77.2,75.77 77.2,75.72 77.2,75.67 77.22,75.62 77.24,75.57 77.27,75.52 77.31,75.49 77.35,75.45 77.4,75.43 77.45,75.41 77.5,75.39 77.55,75.39 77.61,75.39 77.66,75.41 77.71,75.43 77.75,75.45 77.79,75.49 77.83,75.52 77.86,75.57 77.88,75.62 77.9,75.67 77.91,75.72 77.91,75.77 77.9,75.83 77.88,75.88 77.86,75.93 77.83,75.97 77.79,76.01 77.75,76.04 77.71,76.07 77.66,76.09 77.61,76.1 77.55,76.1 77.5,76.1 77.45,76.09 77.4,76.07 77.35,76.04 77.31,76.01 77.27,75.97 77.24,75.93 77.22,75.88 77.2,75.83 77.2,75.77 76.41,75.77 79.05,78.41 79.05,79.68 79.3,79.94 81.08,79.94
+1.8VGS on IN1 (solid shape): outline of 559 points within 60,89.97 77.91,105.08
+1.8VGS on IN3 (solid shape): 79.43,61.4 79.43,57.71 79.3,57.59 78.16,57.59 77.78,57.97 77.78,61.4 77.91,61.52 79.3,61.52
+1.8VGS on IN3 (solid shape): 85.3,35.72 85.37,35.69 85.4,35.62 85.64,35.28 86.03,35.39 86.11,35.43 86.18,35.4 86.87,34.7 86.87,34.52 86.44,34.09 85.15,34.09 83.75,35.49 83.75,35.62 83.85,35.72
+1.8VGS_OUT on TOP (solid shape): 94.42,70.41 94.42,66.98 94.67,66.73 94.67,65.71 94.54,65.59 93.4,65.59 92.89,66.1 92,66.1 91.62,66.48 91.62,70.79 91.75,70.92 93.91,70.92
+1.8VS on TOP (solid shape): 95.54,69.85 95.54,68.91 97.34,67.11 97.34,66.22 96.68,65.56 96.04,65.56 95.97,65.64 95.97,66.2 95.92,66.25 95.08,66.25 94.93,66.4 94.93,66.65 94.57,67.01 94.57,69.83 94.67,69.93 95.46,69.93
+1.8VS on TOP (solid shape): outline of 601 points within 140.77,96.58 146.61,101.02
+1.8VS on BOTTOM (solid shape): 94.16,32.69 94.16,30.79 94.04,30.66 90.1,30.66 89.34,31.42 89.34,32.57 89.69,32.92 93.94,32.92
+1.8VS on IN1 (solid shape): 97.77,70.9 95.31,68.43 95.31,66.68 95.23,66.6 94.44,66.6 94.16,66.88 94.16,71.96 95.64,73.44 95.94,73.44 95.94,73.38 95.95,73.33 95.97,73.28 95.99,73.23 96.02,73.19 96.05,73.15 96.1,73.12 96.14,73.09 96.19,73.07 96.24,73.06 96.3,73.05 96.35,73.06 96.4,73.07 96.45,73.09 96.5,73.12 96.54,73.15 96.58,73.19 96.61,73.23 96.63,73.28 96.65,73.33 96.65,73.38 96.65,73.44 96.65,73.49 96.63,73.54 96.61,73.59 96.58,73.63 96.54,73.67 96.5,73.7 96.45,73.73 96.4,73.75 96.35,73.76 96.3,73.77 96.24,73.76 96.19,73.75 96.14,73.73 96.1,73.7 96.05,73.67 96.02,73.63 95.99,73.59 95.97,73.54 95.95,73.49 95.94,73.44 95.64,73.44 97.03,74.83 97.77,74.83
+1.8VS on IN3 (solid shape): 95.56,69.8 95.56,67.24 95.31,66.98 92.51,66.98 92.51,67.53 91.66,68.39 91.66,68.87 92.87,70.08 95.28,70.08
+1.8VS on IN3 (solid shape): 89.21,34.98 89.21,34.09 91.24,32.06 91.24,31.17 90.86,30.79 89.46,30.79 87.18,33.08 87.18,34.85 87.69,35.36 88.83,35.36
+1.8VS on IN3 (solid shape): outline of 4684 points within 97.06,72.42 145.52,102.42
+1.8VSP on BOTTOM (solid shape): 93.02,29.77 93.02,29.01 92.94,28.89 92.91,28.74 92.91,28.46 93.02,28.34 93.02,24.95 92.64,24.57 90.48,24.57 90.1,24.95 90.1,29.9 92.89,29.9
+1.35V on TOP (solid shape): 103.05,32.17 103.05,29.65 101.76,28.35 101.76,27.41 101.33,26.98 99.75,26.98 99.24,27.49 99.24,31.95 99.62,32.33 102.9,32.33
+1.35V on TOP (solid shape): 101.99,91.19 102.04,91.15 102.04,89.59 101.63,89.18 100.62,89.18 100.62,89.46 100.59,89.6 100.51,89.71 100.51,90.36 100.84,90.69 100.84,91.42 101.76,91.42
+1.35V on TOP (solid shape): 167.45,98.56 167.57,98.45 167.73,98.41 167.79,98.38 167.83,98.32 168,98.07 168.31,98.05 168.92,97.44 168.92,96.47 168.84,96.4 167.29,96.4 167.11,96.57 167.11,97.1 166.86,97.36 166.86,97.91 166.91,97.96 166.91,98.44 166.88,98.47 166.87,98.52 166.92,98.56
+1.35V on TOP (solid shape): outline of 1478 points within 128.33,69.65 144.71,87.69
+1.35V on TOP (solid shape): outline of 1507 points within 119.44,36.89 135.95,51.11
+1.35V on BOTTOM (solid shape): 103.56,34.98 103.56,28.38 103.05,27.87 103.05,25.46 102.93,25.33 102.42,25.33 102.42,25.84 100.39,25.84 100.39,25.33 97.21,25.33 97.21,25.84 95.18,25.84 95.18,25.33 94.67,25.33 94.67,29.14 95.69,30.15 97.72,30.15 97.97,30.41 97.97,30.67 98.03,30.87 97.97,31.06 97.97,34.98 98.58,35.59 102.95,35.59
+1.35V on BOTTOM (solid shape): outline of 190 points within 119.18,48.95 136.2,57.84
+1.35V on IN3 (solid shape): outline of 4318 points within 98.86,33.84 135.69,52.63
+1.35V on GND1: 125.38,39.55 124.5,40.44 119.92,40.44 119.69,40.67 119.69,41.56 118.04,43.21 118.04,47.57 118.93,48.46 118.93,65.99 122.87,69.93 122.87,71.32 126.04,74.5 126.04,79.2 126.68,79.83 126.68,80.21 127.82,81.36 127.82,83.13 130.87,86.18 130.87,86.69 131.23,87.05 138.25,87.05 138.76,86.54 142.32,86.54 142.68,86.18 142.68,85.29 144.2,83.77 144.2,82.5 144.58,82.12 144.58,76.28 145.98,74.88 145.98,65.69 136.58,56.29 136.58,48.42 135.95,47.79 135.95,40.29 135.21,39.55
+1.35V on VCC: 99.73,26.98 98.86,27.85 98.86,40.06 119.69,40.06 119.69,41.56 118.04,43.21 118.04,47.45 118.93,48.34 118.93,65.99 122.87,69.93 122.87,71.32 126.04,74.5 126.04,79.32 126.68,79.96 126.68,80.21 127.82,81.36 127.82,83.13 130.87,86.18 130.87,86.72 131.2,87.05 141.81,87.05 142.7,86.16 142.7,85.27 144.2,83.77 144.2,82.5 144.58,82.12 144.58,76.28 145.98,74.88 145.98,65.69 136.58,56.29 136.58,48.42 135.95,47.79 135.95,38.13 130.63,32.82 128.09,32.82 126.19,30.92 105.6,30.92 105.49,30.92 105.42,30.84 102.42,27.98 102.42,27.94 101.43,26.98
+1.35V on GND2: 128.18,37.65 126.91,38.92 124.28,38.92 123.14,37.77 120.94,37.77 120.71,38.01 120.71,38.13 119.18,39.66 119.18,48.21 123.61,52.63 133.17,52.63 136.2,49.61 136.2,44.15 136.45,43.89 136.45,39.02 136.22,38.79 133.17,38.79 132.03,37.65
+1.35V_MEM_GFX on TOP (solid shape): 55.89,70.82 55.89,70.18 55.91,70.16 55.91,70.08 55.99,70.08 56.19,69.88 56.19,69.57 56.09,69.47 56.04,69.47 56.04,69.42 55.99,69.37 55.99,68.81 55.81,68.64 54.97,68.64 54.83,68.77 54.83,70.73 55,70.9 55.81,70.9
+1.35V_MEM_GFX on TOP (solid shape): 60.17,88.86 60.17,88.32 60.6,87.89 60.6,87.41 60.75,87.25 61.19,87.25 61.25,87.3 61.7,87.3 61.75,87.25 61.75,86.64 61.68,86.57 61.17,86.57 61.14,86.59 60.31,86.59 60.13,86.42 58.68,86.42 58.6,86.49 58.6,87.05 58.81,87.25 59.14,87.25 59.19,87.3 59.19,88.02 59.33,88.15 59.33,88.21 59.4,88.33 59.42,88.47 59.44,88.5 59.44,88.94 59.54,89.04 59.99,89.04
+1.35V_MEM_GFX on TOP (solid shape): 59.27,81.63 59.27,81.17 59.19,81.09 59.19,81.08 58.98,81.08 58.91,81 58.91,80.42 59.49,79.84 59.8,79.84 59.9,79.73 59.9,79.18 59.75,79.02 59.47,79.02 59.14,78.69 58.88,78.69 58.78,78.8 58.78,79.13 58.65,79.25 58.17,79.25 58.12,79.3 58.12,79.73 58.34,79.96 58.34,79.97 58.37,80 58.37,80.3 58.1,80.58 58.1,80.98 58.15,81.03 58.55,81.03 58.74,81.22 58.74,81.64 58.8,81.7 59.21,81.7
+1.35V_MEM_GFX on TOP (solid shape): 88.83,66.22 90.48,66.22 90.86,65.84 90.86,64.76 90.83,64.75 90.65,64.43 90.83,64.12 90.86,64.1 90.86,59.24 90.73,59.11 87.94,59.11 87.5,59.55 87.5,59.56 86.86,60.75 85.93,61.72 85.91,61.74 85.91,61.78 85.65,62.03 85.65,64.19 85.91,64.44 85.91,65.84 86.42,66.35 88.7,66.35
+1.35V_MEM_GFX on TOP (solid shape): 49.46,58.35 49.46,53.78 49.21,53.52 37.9,53.52 37.14,54.28 37.14,56.44 38.03,57.33 39.29,57.33 39.3,57.32 42.55,56.65 45.19,58.65 45.2,58.66 45.52,58.98 48.82,58.98
+1.35V_MEM_GFX on TOP (solid shape): outline of 412 points within 27.63,68.47 41.06,73.62
+1.35V_MEM_GFX on TOP (solid shape): outline of 440 points within 27.69,97.31 43.91,102.24
+1.35V_MEM_GFX on BOTTOM (solid shape): 28.9,72.77 30.63,72.77 30.7,72.68 30.79,72.61 30.84,72.52 30.79,72.43 30.73,72.4 30.68,72.35 30.44,72.35 30.35,72.26 30.33,72.26 30.02,71.72 30.64,71.76 30.7,71.82 30.78,71.81 31.26,71.96 31.11,72.43 31.05,72.52 31.11,72.61 31.2,72.68 31.26,72.78 31.43,72.78 31.75,72.57 32.06,72.78 32.23,72.78 32.29,72.68 32.39,72.61 32.44,72.52 32.39,72.43 32.25,72.3 32.2,72.12 32.18,72.09 32.15,72.07 31.93,71.45 32.53,71.72 32.54,71.76 32.58,71.77 32.89,72.05 32.71,72.43 32.65,72.52 32.71,72.61 32.8,72.68 32.86,72.78 33.03,72.78 33.16,72.63 33.34,72.57 33.38,72.56 33.39,72.52 33.49,72.3 33.71,72.19 33.77,72.16 33.8,72.09 33.8,72.06 33.81,72.02 33.81,71.57 33.81,71.5 33.61,71.31 33.6,71.3 33.49,71.22 33.41,71.1 33.4,71.09 33.31,71 33.31,70.06 33.2,69.84 33.31,69.63 33.31,68.71 33.18,68.58 27.84,68.58 27.72,68.71 27.72,72.39 28.1,72.78 28.9,72.78
+1.35V_MEM_GFX on BOTTOM (solid shape): outline of 251 points within 35.18,97.41 38.13,101.6
+1.35V_MEM_GFX on BOTTOM (solid shape): outline of 2198 points within 24.92,77.7 45.3,102.37
+1.35V_MEM_GFX on IN2 (solid shape): outline of 2886 points within 34.09,52.76 87.56,72.92
+1.35V_MEM_GFX on IN3 (solid shape): outline of 3229 points within 34.35,57.46 87.56,70.03
+1.35V_MEM_GFX on VCC: 36.61,63.17 33.44,66.35 27.21,66.35 23.93,69.63 23.93,76.74 21.65,79.03 21.65,87.71 24.44,90.5 24.44,96.09 29.25,100.89 37.88,100.89 42.07,105.08 60.38,105.08 60.38,73.69 57.86,71.18 57.23,71.18 56.32,70.26 56.32,69.88 55.7,69.27 55.32,69.27 49.23,63.17
+1.35VGPUP on TOP (solid shape): 49.59,52.63 49.59,49.84 48.95,49.2 43.11,49.2 40.95,51.36 40.95,52.63 41.08,52.76 49.46,52.76
+1.35VGPUP on BOTTOM (solid shape): 45.4,54.28 45.4,43.74 44.89,43.24 43.24,43.24 42.86,43.62 42.86,51.11 41.97,52 41.97,54.16 42.35,54.54 45.14,54.54
+1.35VGPUP_B+ on TOP (solid shape): 40.75,44.38 40.75,43.29 40.66,43.2 40.66,39.77 40.19,39.3 37.14,39.3 36.25,40.19 36.25,44.25 36.46,44.45 40.67,44.45
+1.35VP on BOTTOM (solid shape): 86.8,10.85 86.8,9.96 86.67,9.83 86.29,9.83 86.16,9.96 86.16,10.6 86.04,10.72 85.15,10.72 85.15,10.98 86.67,10.98
+1.35VP on BOTTOM (solid shape): outline of 122 points within 94.67,9.83 103.31,25.07
+1.35VP on IN2 (solid shape): 86.92,11.1 86.92,9.83 86.8,9.71 86.16,9.71 86.04,9.83 86.04,11.1 86.16,11.23 86.8,11.23
+1.35VS_MEM_GFX_OUT on TOP (solid shape): 94.76,64.1 94.76,63.5 94.8,63.5 94.8,59.75 94.42,59.36 91.75,59.36 91.62,59.49 91.62,63.56 91.75,63.68 92.89,63.68 93.4,64.19 94.67,64.19
+3VALW on TOP (solid shape): 152.46,4.75 152.46,3.1 152.33,2.98 150.68,2.98 150.55,3.1 150.55,4.75 150.68,4.88 152.33,4.88
+3VALW on TOP (solid shape): 26.22,100.39 26.22,98.23 25.71,97.72 25.05,97.72 24.72,98.05 24.72,98.9 24.72,98.91 24.72,100.54 24.82,100.64 25.96,100.64
+3VALW on TOP (solid shape): 99.24,21.65 99.24,16.95 106.23,9.96 106.23,8.95 105.72,8.44 103.77,8.44 96.32,15.88 96.32,21.9 96.58,22.15 98.74,22.15
+3VALW on TOP (solid shape): 113.9,29.98 113.9,29.14 113.7,28.93 112.53,28.93 112.4,29.06 112.4,29.95 112.55,30.1 113.77,30.1
+3VALW on TOP (solid shape): 142.38,20.36 142.38,20.08 141.96,19.66 141.96,19.26 141.85,19.14 141.25,19.14 141.18,19.2 141.18,20.22 141.4,20.44 142.3,20.44
+3VALW on TOP (solid shape): 72.02,32.06 72.57,32.06 72.65,31.98 72.65,31.12 72.17,30.64 72.17,30.33 71.58,29.75 70.49,29.75 70.03,30.2 70.03,31.93 70.36,32.26 71.81,32.26
+3VALW on TOP (solid shape): 11.59,72.09 11.59,71.25 11.26,70.92 11.04,70.92 11.04,70.01 9.92,70.01 9.87,69.96 9.71,69.96 9.71,69.97 9.65,70.03 9.6,70.1 9.51,70.18 9.51,71.73 10.06,72.29 11.39,72.29
+3VALW on TOP (solid shape): 41.05,111.28 41.05,107.09 39.48,105.52 38.44,105.52 37.78,106.18 37.78,106.84 39.1,108.16 39.1,111.36 38.6,111.86 38.54,111.94 38.45,112 38.21,112.25 37.09,112.25 36.94,112.4 36.94,113.14 37.04,113.24 39.1,113.24
+3VALW on TOP (solid shape): 160.73,6.77 160.73,6.61 162.54,6.61 162.62,6.53 162.62,5.58 162.6,5.54 162.57,5.53 162.41,5.49 162.29,5.39 159.19,5.39 158.93,5.64 158.93,7.04 159.19,7.29 160.2,7.29
+3VALW on TOP (solid shape): 212.19,8.53 212.53,8.28 212.87,8.53 212.88,8.56 212.96,8.56 213.06,8.46 213.06,6.07 213.01,6.02 211.13,6.02 211,6.15 211,8.44 211.13,8.56 212.18,8.56
+3VALW on TOP (solid shape): outline of 440 points within 133.28,5.14 146.87,12.88
+3VALW on BOTTOM (solid shape): 170.91,118.52 170.91,116.66 170.7,116.45 169.47,116.45 169.29,116.64 169.29,118.62 169.46,118.79 170.64,118.79
+3VALW on BOTTOM (solid shape): 13.52,65.71 13.52,65.21 13.39,65.08 12.76,65.08 12.63,64.95 12.63,63.91 12.5,63.78 12.12,63.78 11.84,64.06 11.84,65.41 12.27,65.84 13.39,65.84
+3VALW on BOTTOM (solid shape): 164.65,118.67 164.65,117.28 164.39,117.02 160.01,117.02 158.87,117.02 158.55,117.02 158.43,117.15 158.43,118.17 159.44,119.18 164.14,119.18
+3VALW on BOTTOM (solid shape): 167.72,117.02 167.72,116.18 167.54,116.01 166.96,116.01 166.78,116.18 166.78,116.51 166.66,116.64 165.41,116.64 165.28,116.77 165.28,117.02 165.41,117.15 167.6,117.15
+3VALW on BOTTOM (solid shape): 85.65,47.5 85.65,45.01 88.58,42.09 88.58,39.3 88.32,39.04 83.37,39.04 77.91,44.51 77.91,49 79.28,50.37 79.28,52.02 79.15,52.15 79.15,52.36 79.16,52.37 80.79,52.37
+3VALW on BOTTOM (solid shape): 106.74,11.36 106.74,9.83 106.09,9.18 106.03,9.18 106.03,8.6 106.1,8.6 106.1,8.31 106.03,8.31 106.03,7.8 106.1,7.8 106.1,7.51 106.03,7.51 106.03,6.93 106.1,6.93 106.1,6.79 105.97,6.66 105.47,6.66 104.83,7.29 104.83,11.23 105.09,11.49 106.61,11.49
+3VALW on BOTTOM (solid shape): 136.55,24.66 136.72,24.46 136.98,24.43 137.01,24.43 137.09,24.35 137.09,22.53 136.96,22.41 135.95,22.41 135.44,22.92 135.44,24.57 135.57,24.69 136.54,24.69
+3VALW on BOTTOM (solid shape): 136.33,16.31 136.33,14.53 136.07,14.28 136.07,13.26 136.01,13.2 135.46,13.2 135.39,13.23 135.36,13.3 135.36,13.39 135.37,13.41 135.46,13.53 135.48,13.67 135.48,14.36 134.3,15.54 134.3,16.31 134.42,16.44 136.2,16.44
+3VALW on BOTTOM (solid shape): 77.37,28.72 81.37,28.72 82.86,27.23 82.86,26.85 82.73,26.73 82.48,26.73 82.3,26.55 82.3,22.86 81.59,22.15 80.96,22.15 80.58,21.77 78.8,21.77 78.54,21.52 78.54,19.23 78.26,18.95 75.97,18.95 75.87,19.05 75.87,19.72 75.93,19.78 76.44,19.78 76.44,20.14 76.66,20.14 76.66,20.08 76.67,20.03 76.69,19.98 76.71,19.93 76.74,19.89 76.78,19.85 76.82,19.81 76.86,19.79 76.91,19.77 76.97,19.76 77.02,19.75 77.07,19.76 77.12,19.77 77.17,19.79 77.22,19.81 77.26,19.85 77.3,19.89 77.33,19.93 77.35,19.98 77.37,20.03 77.37,20.08 77.37,20.14 77.37,20.19 77.35,20.24 77.33,20.29 77.3,20.33 77.26,20.37 77.22,20.4 77.17,20.43 77.12,20.45 77.07,20.46 77.02,20.47 76.97,20.46 76.91,20.45 76.86,20.43 76.82,20.4 76.78,20.37 76.74,20.33 76.71,20.29 76.69,20.24 76.67,20.19 76.66,20.14 76.44,20.14 76.44,21.82 76.38,21.88 76,21.88 75.87,22.01 75.87,24.93 76,25.06 76.44,25.06 76.44,27.09 76.12,27.09 75.93,27.28 75.93,28.63 76.03,28.73 77.36,28.73
+3VALW on BOTTOM (solid shape): 178.75,37.49 178.75,34.76 177.98,32.1 178.75,29.44 178.75,25.56 179.52,24.78 179.51,24.76 179.7,24.37 180.12,24.44 180.45,24.77 180.64,24.77 180.65,24.77 180.78,24.74 180.9,24.77 180.91,24.77 181.7,24.77 181.92,24.69 182.14,24.77 182.76,24.77 183.17,25.18 183.17,26.34 183.8,26.98 184.08,26.98 184.33,26.73 184.33,26.12 184.28,25.94 184.33,25.75 184.33,23.17 184.08,22.92 178.3,22.92 178.28,22.94 177.91,22.94 175.43,25.42 175.43,36.09 175.42,36.1 175.42,37.55 175.8,37.93 178.31,37.93
+3VALW on BOTTOM (solid shape): outline of 110 points within 145.34,1.33 152.84,7.8
+3VALW on IN1 (solid shape): 11.49,72.95 11.49,70.79 11.36,70.67 10.6,70.67 10.47,70.79 10.47,73.08 10.72,73.33 11.11,73.33
+3VALW on IN1 (solid shape): 26.93,99.5 26.93,98.85 25.35,97.26 24.92,97.26 24.47,97.72 24.47,98.57 24.5,98.58 24.72,98.91 24.5,99.24 24.47,99.25 24.47,99.5 24.75,99.78 26.65,99.78
+3VALW on IN1 (solid shape): 39.17,107.37 39.17,106.99 38.03,105.85 38.03,104.96 37.9,104.83 37.01,104.83 36.91,104.93 36.91,106.46 36.94,106.53 37.01,106.56 37.36,106.83 37.18,107.23 37.13,107.3 37.16,107.39 37.6,107.83 38.72,107.83
+3VALW on IN1 (solid shape): outline of 135 points within 69.4,24.69 83.37,31.28
+3VALW on IN1 (solid shape): outline of 173 points within 166.05,36.79 177.6,43.26
+3VALW on IN1 (solid shape): outline of 535 points within 126.17,8.95 134.5,25.58
+3VALW on IN2 (solid shape): 39.68,107.01 39.68,106.25 39.25,105.82 38.13,105.82 37.42,106.53 37.42,107.12 37.99,107.69 39.01,107.69
+3VALW on IN2 (solid shape): 86.06,93.15 86.06,91.85 85.76,91.55 84.77,91.55 84.22,92.09 84.22,93.06 84.56,93.4 85.81,93.4
+3VALW on IN2 (solid shape): 93.02,43.24 93.02,42.73 95.05,40.7 95.05,40.06 94.8,39.81 94.04,39.81 92,41.84 92,43.11 92.26,43.36 92.89,43.36
+3VALW on IN3 (solid shape): 12.18,71.92 12.18,70.48 12.19,70.4 12.22,70.32 12.22,68.84 13.14,67.92 13.14,67.87 13.13,67.86 13.04,67.61 13.14,67.37 13.14,64.06 12.93,63.86 11.79,63.86 11.51,64.14 11.51,67.62 10.01,69.12 10.01,72.14 10.19,72.32 11.79,72.32
+3VALW on IN3 (solid shape): outline of 1385 points within 182.94,5.39 213.14,24.95
+3VALW on VCC: 96.05,21.26 92.36,24.95 77.38,24.95 76.26,26.07 76.26,33.71 80.68,33.71 85.27,38.3 85.27,40.08 86.65,41.46 95.2,41.46 96.6,40.06 98.35,40.06 98.35,27.64 99.52,26.47 101.63,26.47 105.7,30.41 126.4,30.41 128.31,32.31 130.85,32.31 136.45,37.92 136.45,39.43 154.98,39.43 159.31,43.76 159.31,45.54 168.59,54.81 168.59,62.81 172.78,67.01 172.78,85.89 158.02,100.64 152.08,100.64 152.08,121.53 163.63,121.53 163.63,121.3 166.4,118.53 169.17,121.3 169.17,121.53 176.4,121.53 176.92,121.32 177.13,120.8 177.13,115.5 177.23,114.84 177.51,114.24 175.95,112.68 175.95,101.17 177.5,99.62 181.43,99.62 188.78,92.28 188.78,87.28 184.21,82.71 184.21,62.52 179.76,58.07 179.76,54.26 160.73,35.23 160.61,35.23 159.72,34.35 140.54,34.35 132.54,26.34 129.49,26.34 127.95,24.8 127.95,22.64 127.59,22.28 99.77,22.28 98.76,21.26
+3VALW_EC on BOTTOM (solid shape): 106.24,16.82 106.31,16.77 106.39,16.76 107.94,16.76 107.98,16.76 108.01,16.77 108.04,16.78 108.13,16.69 108.13,15.13 107.93,14.81 108.13,14.49 108.13,13.9 108.51,13.52 108.51,11.99 108.26,11.74 107.96,11.74 107.95,11.77 107.63,11.97 107.31,11.77 107.29,11.74 104.07,11.74 103.56,12.25 103.56,15.65 104.4,15.65 104.4,15.9 104.51,15.9 104.54,15.93 105.21,15.93 106.1,16.82
+3VALWP on BOTTOM (solid shape): outline of 107 points within 61.65,19.08 75.57,30.92
+3VGS on TOP (solid shape): 128.33,9.33 128.33,8.69 128.2,8.56 127.83,8.56 127.83,8.58 127.13,8.58 127.13,8.56 126.63,8.56 126.63,8.58 125.93,8.58 125.93,8.56 125.15,8.56 125.02,8.69 125.02,9.45 125.15,9.58 128.07,9.58
+3VGS on BOTTOM (solid shape): 59.49,103.31 59.49,103.05 59.75,102.8 60.38,102.8 60.51,102.67 60.51,102.04 60.38,101.91 59.24,101.91 59.11,102.04 59.11,102.93 58.98,103.05 58.98,103.31 59.11,103.43 59.37,103.43
+3VGS on IN1 (solid shape): outline of 731 points within 55.94,85.78 71.56,105.47
+3VGS_OUT on TOP (solid shape): 129.55,6.96 129.55,6.2 129.72,6.02 129.72,4.88 129.67,4.83 127.35,4.83 125.02,7.15 125.02,7.68 125.28,7.93 128.58,7.93
+3VS on TOP (solid shape): 129.75,3.48 129.75,2.54 129.42,2.21 128.83,2.21 128.71,2.34 128.71,3.48 128.83,3.61 129.62,3.61
+3VS on TOP (solid shape): 173.18,31.13 173.18,29.45 172.42,28.69 171.29,28.69 171.08,28.89 171.08,31.21 171.23,31.36 172.95,31.36
+3VS on TOP (solid shape): 187.25,62.16 187.25,60.38 186.87,60 185.86,60 185.73,60.13 185.73,62.16 185.86,62.29 187.13,62.29
+3VS on TOP (solid shape): 115.14,29.95 115.14,29.06 114.71,28.63 114.43,28.63 114,29.06 114,29.95 114.15,30.1 114.99,30.1
+3VS on TOP (solid shape): 176.97,60.63 176.97,59.38 176.57,58.98 173.03,58.98 172.78,59.24 172.78,60.34 172.85,60.42 174.54,60.42 174.89,60.76 176.84,60.76
+3VS on TOP (solid shape): 71.94,36.5 72.4,36.05 72.4,35.16 72.65,34.9 72.65,33.41 72.57,33.33 68.13,33.33 67.37,34.09 67.37,34.86 67.49,34.98 67.59,35.29 67.4,35.55 67.37,35.57 67.37,36.25 67.62,36.5 70.99,36.5
+3VS on TOP (solid shape): 9.78,101.71 9.78,101.67 9.81,101.65 9.81,101.47 11.05,100.23 11.05,100.14 11.26,99.93 11.56,99.93 11.77,100.14 11.77,100.27 11.77,100.28 11.89,100.41 11.91,100.41 12.06,100.47 12.18,100.59 13.06,100.59 13.39,100.26 13.39,99.62 13.26,99.5 12.5,99.5 11.91,98.9 9.29,98.9 9.07,99.12 9.07,100.39 8.44,101.02 7.04,101.02 6.91,101.15 6.91,101.91 7.04,102.04 9.45,102.04
+3VS on TOP (solid shape): 22.76,76.23 23.05,76.05 23.38,76.15 24.82,76.15 25,75.98 25,74.76 24.77,74.53 24.03,74.53 24.03,74.45 23.7,74.45 23.53,74.63 23.31,74.63 23.1,74.69 22.9,74.63 22.36,74.63 22.18,74.69 22,74.66 21.96,74.64 21.7,74.91 18.65,74.91 18.17,75.39 18.17,77.45 18.5,77.78 21.22,77.78
+3VS on BOTTOM (solid shape): 195.31,77.37 195.31,76.64 195.15,76.48 193.93,76.48 193.81,76.61 193.81,77.37 193.99,77.55 195.13,77.55
+3VS on BOTTOM (solid shape): 181.68,63.81 181.8,63.78 181.93,63.81 181.94,63.81 184.21,63.81 185.39,62.62 185.4,62.62 185.45,62.54 185.53,62.48 185.54,62.48 185.6,62.41 187.13,62.41 187.25,62.29 187.25,60.25 186.87,59.87 184.84,59.87 183.7,61.02 183.7,62.16 183.65,62.2 183.65,62.21 183.46,62.41 183.19,62.42 183.18,62.41 180.65,62.41 177.35,59.11 176.59,59.11 176.46,59.24 176.46,61.65 178.62,63.81 181.67,63.81
+3VS on IN3 (solid shape): 99.27,100.33 99.27,99.9 98.13,98.76 97.82,98.76 97.74,98.84 97.74,98.87 97.68,99.12 97.46,99.26 97.42,99.27 97.42,99.51 98.52,100.61 98.99,100.61
+3VS on VCC: outline of 121 points within 1.27,15.8 199.19,121.53 ; 1 cut-out
+3VS_TOUCH on TOP (solid shape): 13.52,66.35 13.52,64.57 13.39,64.44 12.82,64.44 12.79,64.48 12.77,64.52 12.74,64.58 12.77,64.65 12.48,65.28 12.19,64.65 12.21,64.58 12.19,64.52 12.16,64.48 12.14,64.44 11.96,64.45 11.43,64.45 11.36,64.44 11.23,64.57 11.23,67.62 12.25,67.62
+3VS_WLAN_NGFF on TOP (solid shape): 191.57,65.46 191.45,65.33 186.87,65.33 186.75,65.46 186.75,66.86 187.38,67.49 191.57,67.49
+3VS_WLAN_NGFF on TOP (solid shape): outline of 96 points within 166.81,61.02 175.06,65.21
+3VS_WLAN_NGFF on BOTTOM (solid shape): outline of 167 points within 170.11,63.3 191.95,69.4
+5V_HDD on TOP (solid shape): 189.26,13.49 189.26,13.44 189.31,13.44 189.49,13.26 189.49,13.09 189.56,12.87 189.76,12.74 189.79,12.73 189.79,12.25 189.54,11.99 187.25,11.99 187.13,12.12 187.13,13.01 187.38,13.26 187.51,13.26 187.79,13.54 189.21,13.54
+5V_HDD on BOTTOM (solid shape): 192,14.86 192,14.46 192.21,14.26 192.21,13.77 191.57,13.14 190.3,13.14 190.1,13.34 189.59,13.34 189.59,12.83 189.67,12.76 188.65,11.74 187,11.74 186.64,12.1 186.66,12.13 186.68,12.2 186.69,12.28 186.69,12.77 186.67,12.88 186.62,12.99 186.62,13.19 186.66,13.27 186.76,13.28 187.17,13.42 187.14,13.85 187.12,13.92 187.14,13.98 187.23,14.21 187.16,14.44 187.38,14.66 189.67,14.66 190.05,15.04 191.83,15.04
+5V_PVDD on TOP (solid shape): 200.95,20.43 200.95,20.1 200.87,19.96 200.86,19.8 200.87,19.77 200.39,19.29 200.37,19.03 200.45,18.79 200.36,18.47 200.45,18.15 200.44,17.54 200.97,17.23 201.49,17.23 201.61,17.11 201.61,15.88 201.61,15.68 201.53,15.6 200.68,15.6 200.58,15.5 199.12,15.5 199.07,15.52 199.01,15.52 198.94,15.56 198.91,15.63 198.91,16.18 198.63,16.18 198.56,16.26 198.56,18.85 198.63,18.93 198.91,18.93 198.99,19 198.99,20.41 199.18,20.6 200.77,20.6
+5V_USB_PWR1 on TOP (solid shape): 198.18,51.36 198.18,50.04 196.55,48.42 196.53,48.42 196.5,48.39 196.5,48.09 196.47,48.09 196.47,47.27 196.5,47.27 196.5,47.05 196.14,46.69 195.28,46.69 195.28,46.74 194.93,47.07 194.57,46.74 194.57,46.69 193.63,46.69 193.22,47.1 193.22,48.04 193.45,48.26 194.14,48.26 194.2,48.33 194.21,48.33 194.32,48.41 194.4,48.52 194.4,48.53 194.9,49.03 194.9,51.21 195.31,51.62 197.92,51.62
+5V_USB_PWR1 on BOTTOM (solid shape): 199.95,61.56 199.95,61.4 199.19,60.63 199.19,54.28 198.18,53.27 198.18,50.35 198.05,50.22 193.73,50.22 193.48,50.47 193.48,51.72 193.58,51.97 193.48,52.22 193.48,53.52 196.27,56.32 196.27,58.66 196.42,58.81 196.52,59.13 196.3,59.39 196.27,59.4 196.27,61.65 196.36,61.74 198.11,61.74 198.27,61.9 198.68,61.9 198.84,62.06 199.45,62.06
+5V_USB_PWR2 on TOP (solid shape): 200.21,44.25 200.21,43.56 200.01,43.05 200.21,42.53 200.21,41.8 200.2,41.78 199.99,41.37 199.9,40.92 199.9,40.9 197.54,38.54 193.6,38.54 193.33,38.82 193.33,43.55 193.36,43.56 193.52,43.66 193.6,43.83 193.61,43.87 194.75,43.87 195,44.12 196.14,44.12 196.4,43.87 197.67,43.87 198.3,44.51 199.95,44.51
+5V_USB_PWR2 on BOTTOM (solid shape): 197.54,40.44 197.54,37.27 196.91,36.63 193.48,36.63 192.84,37.27 192.84,40.31 193.22,40.7 197.29,40.7
+5V_USB_PWR3 on TOP (solid shape): 20.83,52.35 20.83,50.52 20.82,50.42 20.83,50.33 20.83,50.17 22.13,48.87 25.53,48.87 26.98,47.43 26.98,45.65 25.96,44.63 24.06,44.63 23.13,43.7 20.19,43.7 18.96,44.93 18.96,49.44 18.18,50.22 17.34,50.22 16.78,50.78 16.78,52.24 17.42,52.87 20.31,52.87
+5V_USB_PWR3 on BOTTOM (solid shape): 25.12,47.52 25.21,47.51 25.89,47.51 25.98,47.52 26.07,47.55 27.36,47.55 27.62,47.3 27.62,42.85 27.11,42.35 24.57,42.35 24.19,42.73 24.19,47.17 24.57,47.55 25.03,47.55
+5VA on TOP (solid shape): 194.82,24.17 195.63,24.17 195.63,24.2 195.69,24.29 195.81,24.27 195.88,24.2 195.85,24.16 195.77,23.98 195.79,23.79 195.8,23.71 195.75,23.66 195.57,23.29 195.85,23 195.89,22.99 195.89,22.37 195.85,22.33 194.34,22.33 194.3,22.29 194.3,21.95 194.25,21.9 192.97,21.9 192.59,22.28 192.59,22.73 192.59,22.74 192.61,22.86 192.59,22.99 192.59,23 192.59,24.44 192.72,24.57 194.82,24.57
+5VALW on TOP (solid shape): 18.76,49.28 18.76,43.87 19.63,43.01 19.63,40.17 19.35,39.9 17.51,39.9 15.89,41.51 15.89,47.18 16.31,47.6 16.31,49.48 16.76,49.93 18.12,49.93
+5VALW on TOP (solid shape): 19.74,62.67 19.74,61.9 19.49,61.65 16.69,61.65 13.39,58.35 13.39,58.09 13.26,57.97 11.61,57.97 11.36,58.22 11.36,59.62 14.03,62.29 15.04,62.29 15.68,62.92 19.49,62.92
+5VALW on TOP (solid shape): 80.19,32.69 80.19,31.3 77.78,28.88 74.99,28.88 74.86,29.01 74.86,30.15 73.97,31.04 73.97,31.93 74.1,32.06 74.66,32.06 74.91,32.31 75.16,32.31 75.55,32.69 76.71,32.69 76.97,32.95 79.94,32.95
+5VALW on TOP (solid shape): 191.95,43.74 191.95,43.44 191.95,43.44 191.93,43.31 191.95,43.19 191.95,43.18 191.95,40.44 191.7,40.19 188.4,40.19 188.14,40.44 188.14,42.85 188.27,42.98 189.41,42.98 189.54,43.11 189.54,44.12 191.57,44.12
+5VALW on TOP (solid shape): 190.81,56.32 190.81,54.54 190.94,54.41 190.94,49.46 191.06,49.33 191.14,49.33 191.16,49.32 191.27,49.26 191.39,49.24 191.41,49.24 192.08,48.57 192.08,47.28 192.04,47.27 191.76,47 191.89,46.64 191.93,46.56 191.9,46.48 191.83,46.41 190.05,46.41 189.67,46.79 189.67,48.06 187.51,50.22 187.51,56.44 187.76,56.7 190.43,56.7
+5VALW on BOTTOM (solid shape): 180.13,50.79 180.83,50.09 180.83,49.03 180.78,48.98 180.14,48.98 179.99,49.13 179.99,50.43 179.85,50.56 179.85,51.46 180.13,51.46
+5VALW on BOTTOM (solid shape): 19.87,62.92 19.87,61.02 20.12,60.76 20.12,40.95 19.36,40.19 18.34,40.19 18.22,40.31 18.22,59.49 18.85,60.13 18.85,62.92 18.98,63.05 19.74,63.05
+5VALW on BOTTOM (solid shape): 78.81,15.23 78.81,7.13 78.54,6.86 76.52,6.86 76.52,7.35 76.9,7.35 76.97,7.41 76.97,9.5 76.97,9.63 76.46,9.63 76.46,9.63 76.46,12.55 76.59,12.68 76.9,12.68 76.97,12.74 76.97,14.71 76.84,14.84 76.46,14.84 76.49,14.86 76.49,15.35 76.59,15.45 78.59,15.45
+5VALW on IN2 (solid shape): 19.49,62.92 20.12,62.92 20.25,62.79 20.25,62.54 19.49,61.78 19.11,61.78 18.85,62.03 18.85,63.3 19.11,63.3
+5VALW on IN2 (solid shape): outline of 2471 points within 72.95,7.29 90.35,33.71
+5VALW on IN3 (solid shape): outline of 827 points within 15.04,17.45 19.48,43.21
+5VALW on VCC: outline of 97 points within 13.07,1.27 213.13,57.33
+5VALWP on BOTTOM (solid shape): outline of 246 points within 60.76,6.66 76.26,15.3
+5VALWP on IN2 (solid shape): outline of 432 points within 60.64,6.79 76,15.3
+5VS on TOP (solid shape): 9.2,96.4 9.2,95.31 9.07,95.18 6.84,95.18 6.66,95.36 6.66,96.83 6.91,97.08 8.52,97.08
+5VS on TOP (solid shape): 17.38,60.96 17.38,59.54 14.66,56.82 12.25,56.82 11.99,57.08 11.99,57.46 12.38,57.84 13.39,57.84 16.69,61.14 17.2,61.14
+5VS on TOP (solid shape): 7.78,70.06 7.87,70.06 7.87,70.03 9.01,70.03 9.01,70.06 9.48,70.06 9.61,69.93 9.61,68.53 9.45,68.38 5.14,68.38 4.88,68.64 4.88,70.29 5.39,70.79 7.04,70.79
+5VS on TOP (solid shape): 80.19,36.12 80.19,33.33 79.94,33.08 77.02,33.08 76.7,33.39 76.7,33.58 75.56,33.58 75.24,33.58 74.99,33.33 74.1,33.33 73.97,33.46 73.97,34.85 74.48,35.36 74.48,36 74.73,36.25 75.62,36.25 76,36.63 79.69,36.63
+5VS on TOP (solid shape): outline of 155 points within 129.22,15.3 134.93,22.91
+5VS on TOP (solid shape): outline of 222 points within 192.33,74.55 199.83,78.16
+5VS on TOP (solid shape): outline of 590 points within 181.03,5.9 198.43,21.65
+5VS on TOP (solid shape): outline of 2342 points within 92.89,33.08 120.34,50.6
+5VS on IN1 (solid shape): outline of 1025 points within 113.85,27.23 133.41,37.9
+5VS on IN2 (solid shape): outline of 8794 points within 128.96,8.56 194.49,78.41
+5VS on VCC: 76.11,34.22 75.49,34.83 75.49,53.67 87.56,65.74 87.56,101.13 86.14,102.54 75.35,102.54 70.92,106.97 70.92,107.69 69.98,108.64 66.88,108.64 66.35,108.11 66.35,105.95 65.99,105.59 41.86,105.59 37.67,101.4 29.03,101.4 23.93,96.3 23.93,90.71 21.14,87.92 21.14,81.72 18.49,81.72 17.71,80.93 17.71,69.16 19.61,67.26 19.61,60.1 18.75,59.24 15.28,59.24 9.07,65.44 9.07,94.9 8.57,95.41 8.57,96.34 22.51,110.29 31.28,110.29 31.93,110.95 31.93,121.53 33.55,121.53 34.29,120.1 35.8,119.53 53.8,119.53 55.31,120.1 56.05,121.53 98.99,121.53 98.99,114.46 97.85,113.32 97.85,103.45 99.75,101.55 99.75,89.06 97.72,87.03 97.72,71.15 94.54,67.98 94.54,52.65 94.67,52.53 94.67,44.15 94.93,43.89 94.93,41.97 86.44,41.97 84.77,40.29 84.77,38.51 80.47,34.22
+5VS_KBL on TOP (solid shape): outline of 98 points within 119.69,12.25 135.06,17.33
+AVDD_SATA on TOP (solid shape): outline of 715 points within 157.92,18.17 171.67,25.79
+AVDD_SATA on BOTTOM (solid shape): 160.17,25.7 160.32,25.67 160.48,25.7 160.49,25.71 160.84,25.71 161.05,25.62 161.26,25.71 162.09,25.71 162.11,25.69 162.47,25.33 162.47,25.07 162.09,24.69 162.09,23.99 160.76,22.66 160.76,22.47 160.25,21.96 159.36,21.96 159.23,22.09 159.23,22.28 158.73,22.79 158.73,23.68 158.85,23.8 159.04,23.8 159.17,23.93 159.17,23.99 159.17,24 159.2,24.12 159.17,24.24 159.17,24.25 159.17,25.33 159.53,25.69 159.57,25.71 159.81,25.62 160.01,25.71 160.16,25.71
+VCC_VDDCR_11 on TOP (solid shape): 172.38,18.11 172.38,17.7 172.46,17.62 174.22,17.62 174.3,17.54 174.3,16.44 174.17,16.31 172.4,16.31 172.14,16.57 170.62,16.57 169.86,17.33 169.86,17.84 170.24,18.22 172.28,18.22
+VCC_VDDCR_11 on TOP (solid shape): 157.83,22.39 157.83,21.66 157.82,21.62 157.81,21.57 157.82,21.51 157.82,21.45 157.84,21.4 157.86,21.35 157.9,21.3 157.93,21.26 157.98,21.22 158,21.21 158.04,21.16 159.62,21.16 159.98,20.81 159.98,19.03 159.92,18.98 159.42,18.98 159.38,19.01 158.49,19.01 158.3,19.2 157.61,19.89 157.61,19.89 157.04,19.89 156.76,19.61 156.19,19.61 156.12,19.67 156.12,20.62 158.02,20.62 158.02,20.56 158.03,20.51 158.05,20.46 158.08,20.41 158.12,20.36 158.16,20.33 158.2,20.29 158.25,20.27 158.3,20.25 158.36,20.24 158.41,20.24 158.47,20.24 158.52,20.26 158.57,20.28 158.62,20.31 158.67,20.34 158.7,20.39 158.73,20.43 158.76,20.48 158.77,20.54 158.78,20.59 158.78,20.65 158.77,20.7 158.76,20.76 158.73,20.81 158.7,20.85 158.67,20.89 158.62,20.93 158.57,20.96 158.52,20.98 158.47,20.99 158.41,21 158.36,21 158.3,20.99 158.25,20.97 158.2,20.95 158.16,20.91 158.12,20.87 158.08,20.83 158.05,20.78 158.03,20.73 158.02,20.67 158.02,20.62 156.12,20.62 156.12,21.33 156.2,21.4 156.83,21.4 157.03,21.6 157.03,22.35 157.18,22.5 157.72,22.5
+VCC_VDDCR_11 on BOTTOM (solid shape): outline of 180 points within 155.68,18.5 160.12,22.53
+VCC_VDDCR_11 on IN1 (solid shape): outline of 1241 points within 157.14,15.93 171,22.15
+VDD_CT on BOTTOM (solid shape): 68.88,81.48 68.88,80.78 68.87,80.7 68.88,80.62 68.88,80.01 68.69,79.82 67.23,79.82 67.09,79.97 67.05,80.03 67.01,80.08 67.01,80.53 67.14,80.8 67.01,81.08 67.01,81.33 67.04,81.34 67.19,81.47 67.26,81.65 67.26,81.7 68.66,81.7
+VDD_TOUCH on TOP (solid shape): 13.11,97.77 13.11,96.72 13.26,96.56 13.26,95.69 11.61,94.04 10.09,94.04 9.45,94.67 9.45,96.42 9.61,96.58 11.79,96.58 12.19,96.97 12.19,97.73 12.33,97.87 13,97.87
+VDD_TOUCH on BOTTOM (solid shape): outline of 141 points within 9.84,94.42 15.68,106.1
+VDD_TOUCH on IN3 (solid shape): outline of 626 points within 1.96,86.29 13.65,96.19
+VDDAN_11_PCIE on TOP (solid shape): outline of 410 points within 163.03,22.53 171.78,28.63
+VDDAN_11_PCIE on BOTTOM (solid shape): outline of 124 points within 160.72,21.95 164.56,26.81
+VDDAN_11_PCIE on IN1 (solid shape): outline of 308 points within 161.98,22.53 166.3,28.25
+VDDAN_11_SSUSB on TOP (solid shape): 156.01,17.64 156.01,16.69 156.14,16.57 156.14,14.66 155.89,14.41 154.49,14.41 154.36,14.53 154.36,14.92 154.36,14.92 154.36,15.04 154.37,15.05 154.39,15.17 154.37,15.29 154.36,15.29 154.36,15.34 154.21,15.48 154.15,15.5 154.11,15.55 154.11,16.95 154.36,17.2 154.73,17.2 154.88,17.35 154.88,17.68 154.98,17.78 155.87,17.78
+VDDAN_11_SSUSB on BOTTOM (solid shape): 157.15,18.16 157.15,17.59 157.02,17.47 156.45,17.47 156.07,17.08 156.07,16 155.94,15.88 155.37,15.88 155.19,16.05 155.2,16.08 155.2,16.15 155.18,16.23 155.18,17.01 155.18,17.02 155.18,17.22 155.05,17.38 155.05,17.72 154.72,18.05 154.72,18.19 154.84,18.32 156.99,18.32
+VDDAN_33_HWM on TOP (solid shape): 150.34,15.1 150.34,14.85 149.84,14.34 149.84,14.17 149.83,14.13 149.82,14.07 149.83,14.01 149.84,13.97 149.84,13.83 149.52,13.52 148.88,13.52 148.34,14.06 148.22,14.06 148.19,14.07 148.14,14.07 148.08,14.07 148.05,14.06 147.91,14.06 147.75,13.9 147.75,13.16 147.67,13.09 147.26,13.09 147.16,13.18 147.16,14.09 148.89,14.09 148.89,14.03 148.9,13.98 148.92,13.93 148.95,13.88 148.98,13.83 149.02,13.8 149.07,13.76 149.12,13.74 149.17,13.72 149.23,13.71 149.28,13.71 149.34,13.71 149.39,13.73 149.44,13.75 149.49,13.78 149.53,13.81 149.57,13.86 149.6,13.9 149.62,13.95 149.64,14.01 149.65,14.06 149.65,14.12 149.64,14.17 149.62,14.23 149.6,14.28 149.57,14.32 149.53,14.36 149.49,14.4 149.44,14.43 149.39,14.45 149.34,14.46 149.28,14.47 149.23,14.47 149.17,14.46 149.12,14.44 149.07,14.41 149.02,14.38 148.98,14.34 148.95,14.3 148.92,14.25 148.9,14.2 148.89,14.14 148.89,14.09 147.16,14.09 147.16,14.63 147.32,14.79 148.74,14.79 148.81,14.71 149.44,14.71 149.53,14.8 149.96,15.23 150.22,15.23
+VDDAN_33_USB on TOP (solid shape): outline of 457 points within 149.03,5.26 153.1,17.33
+VDDAN_33_USB on BOTTOM (solid shape): outline of 84 points within 149.11,11.33 154.15,17.4
+VDDCI on TOP (solid shape): 61.77,85.49 61.77,85.47 61.78,85.4 61.8,85.32 61.8,84.99 61.68,84.87 60.92,84.87 60.74,84.69 60.74,84.5 60.74,84.36 60.84,84.25 60.89,84.21 60.99,84.1 60.99,83.14 60.86,83.01 60.86,82.96 60.86,82.96 60.84,82.83 60.86,82.71 60.86,82.7 60.86,82.53 60.94,82.45 60.94,81.11 61.32,80.73 61.32,80.55 61.25,80.47 60,80.47 59.9,80.57 59.9,81.11 59.87,81.11 59.87,81.28 60,81.41 60.25,81.41 60.36,81.51 60.36,81.61 60.36,81.62 60.4,81.77 60.36,81.92 60.36,81.93 60.36,82.05 60.1,82.3 60.07,82.38 60.11,82.45 60.43,83.02 59.79,82.88 59.79,82.83 59.68,82.83 59.67,82.84 59.37,82.84 59.27,82.96 59.15,83.06 59.15,84.41 59.23,84.52 59.29,84.65 59.58,84.65 59.64,84.71 59.77,84.71 59.77,84.84 60.14,85.21 60.15,85.21 60.27,85.29 60.35,85.41 60.35,85.42 60.48,85.55 61.7,85.55
+VDDCR_1.1V on BOTTOM (solid shape): 160.12,17.23 160.12,16.1 159.95,15.93 159.68,15.93 159.11,16.5 159.11,16.82 159.31,17.03 159.31,17.25 159.09,17.48 159.09,17.73 159.19,17.84 159.52,17.84
+VDDCR_11_SSUSB on TOP (solid shape): 158.68,17.45 158.68,17.04 158.65,16.98 158.59,16.94 158.3,16.76 158.29,16.42 158.3,16.41 158.3,13.9 157.92,13.52 157.89,13.53 157.47,13.37 157.54,12.92 157.54,12.65 157.43,12.45 157.46,12.22 157.48,12.19 157.28,11.99 156.52,11.99 156.39,11.87 156.33,11.87 156.33,11.8 156.14,11.61 155.5,11.61 155.38,11.74 155.38,12.63 155.5,12.76 155.89,12.76 156.14,13.01 156.14,13.39 156.33,13.58 156.36,13.58 156.62,13.69 156.72,13.95 156.72,13.97 157.03,14.28 157.03,15.93 156.96,16 156.96,16.21 156.62,16.21 156.24,16.59 156.24,16.61 156.14,16.71 156.14,17.45 156.27,17.58 158.55,17.58
+VDDCR_11_SSUSB on BOTTOM (solid shape): 157.75,18.28 158.03,18.28 158.09,18.21 158.09,17.01 158.03,16.94 158.03,15.55 157.9,15.42 157.33,15.42 157.2,15.55 157.2,16.3 157.02,16.48 156.74,16.48 156.55,16.29 156.33,16.29 156.19,16.44 156.19,17.01 156.46,17.28 157.22,17.28 157.46,17.52 157.46,18.09 157.65,18.28 157.75,18.28
+VDDCR_11_USB on TOP (solid shape): 154.66,18.85 154.66,18.47 154.41,18.21 152.63,18.21 152.63,18.66 152.95,18.98 154.53,18.98
+VDDIO_33_PCIGP on TOP (solid shape): 153.26,28.37 153.26,26.81 153.64,26.43 153.64,26.41 153.76,26.15 154.02,26.04 154.04,26.04 154.22,25.86 156.92,25.86 157.65,25.14 157.66,25.14 157.66,24.5 157.41,24.25 157.2,24.25 156.95,23.99 156.95,23.61 156.69,23.36 155.99,23.36 155.93,23.42 155.93,23.55 155.89,23.59 155.89,23.66 155.82,23.66 155.8,23.68 155.04,23.68 154.66,23.29 153.33,23.29 153.07,23.55 153.07,23.99 152.69,24.37 151.38,24.37 150.72,25.03 150.72,27.29 150.53,27.49 150.09,27.49 149.96,27.61 149.96,27.93 150.15,28.12 150.66,28.12 150.67,28.13 150.85,28.13 150.97,28.25 150.97,29.31 151.04,29.39 152.25,29.39
+VDDIO_33_S on TOP (solid shape): 154.66,21.77 154.66,21.52 154.72,21.45 155.23,21.45 155.36,21.33 155.36,20.82 154.98,20.82 154.31,20.15 153.4,20.15 153.28,20.27 153.28,20.99 153.14,21.14 152.38,21.14 152.18,21.33 152.18,22.02 152.38,22.21 154.22,22.21
+VDDIO_33_S on BOTTOM (solid shape): 159.1,17.23 159.1,17.01 158.92,16.82 158.92,16.37 159.04,16.25 159.04,16.23 160,15.28 160,14.96 159.95,14.91 159.7,14.91 159.33,15.28 158.8,15.28 158.76,15.33 158.71,15.37 158.66,15.42 158.41,15.42 158.22,15.61 158.22,16.84 158.49,17.12 158.49,17.13 158.68,17.32 159.01,17.32
+VDDIO_33_S on BOTTOM (solid shape): 153.56,22.27 153.73,22.24 153.89,22.27 153.9,22.28 154.17,22.28 154.41,22.19 154.66,22.28 154.98,22.28 155.11,22.15 155.11,20.88 154.66,20.44 153.71,20.44 152.69,21.45 152.69,22.09 152.88,22.28 153.55,22.28
+VDDIO_33_S on IN3 (solid shape): outline of 90 points within 153.21,14.66 159.13,22.15
+VDDPL_33_PCIE on TOP (solid shape): 170.66,30.03 170.47,29.83 168.69,29.83 168.38,29.52 168.38,29.39 168.25,29.26 167.93,29.26 167.81,29.39 167.81,29.77 167.93,29.9 168.25,29.9 168.5,30.15 168.5,30.47 168.69,30.66 169.39,30.66 169.58,30.85 170.66,30.85
+VDDPL_33_SATA on TOP (solid shape): 170.66,28.76 169.65,28.76 169.46,28.95 168.76,28.95 168.62,28.81 168.61,28.81 168.61,28.79 168.44,28.63 167.55,28.63 167.36,28.44 166.92,28.44 166.79,28.56 166.79,28.95 166.98,29.14 167.98,29.14 167.99,29.13 168.12,29.11 168.25,29.13 168.26,29.14 168.31,29.14 168.76,29.58 170.66,29.58
+VDDR3 on TOP (solid shape): 68.94,85.9 68.94,85.22 68.76,84.98 68.82,84.68 68.82,83.75 68.82,83.75 68.82,82.81 68.38,82.38 68.38,81.55 68.25,81.42 66.86,81.42 66.68,81.59 66.68,82.07 66.82,82.21 67,82.21 67.62,82.83 67.79,82.83 67.79,83 67.86,83.07 67.86,84.19 67.97,84.3 67.98,84.3 68.26,84.58 68.1,84.94 68.1,85.11 68.31,85.32 68.31,85.88 68.4,85.97 68.86,85.97
GND on TOP (solid shape): 27.14,81.75 27.14,78.06 26.98,77.91 25.58,77.91 25.29,78.2 25.29,81.58 25.54,81.83 27.06,81.83
GND on TOP (solid shape): 70.2,58.72 70.2,56.47 69.79,56.06 65.73,56.06 65.63,56.16 65.63,58.68 65.94,59 69.92,59
GND on TOP (solid shape): 119.54,116.39 119.54,113.42 119.51,113.39 116.47,113.39 116.13,113.72 116.13,116.03 116.54,116.44 119.49,116.44
GND on TOP (solid shape): 157.79,115.63 157.79,112.83 157.44,112.48 154.84,112.48 154.49,112.83 154.49,115.88 154.62,116.01 157.41,116.01
GND on TOP (solid shape): 109.15,119.05 109.15,115.88 108.51,115.24 106.03,115.24 105.85,115.42 105.85,119.24 105.91,119.31 108.9,119.31
GND on TOP (solid shape): 62.16,69.65 62.16,66.35 61.91,66.1 59.11,66.1 58.98,66.22 58.98,68.76 59.49,69.27 59.49,69.65 59.62,69.78 62.03,69.78
GND on TOP (solid shape): 78.29,109.4 78.29,102.93 77.91,102.54 73.72,102.54 73.59,102.67 73.59,106.61 74.48,107.5 74.48,109.28 74.73,109.53 78.16,109.53
GND on TOP (solid shape): 108.9,100.79 108.9,98.99 108.72,98.81 107.63,98.81 107.47,98.66 105.8,98.66 105.59,98.86 105.59,100.72 105.9,101.02 108.67,101.02
GND on TOP (solid shape): 127.74,116.1 127.74,113.68 127.36,113.3 124.24,113.3 124.05,113.49 124.05,116.13 124.28,116.36 127.48,116.36
GND on TOP (solid shape): 128.33,77.14 128.33,74.35 128.07,74.1 128.07,69.91 127.82,69.65 126.04,69.65 125.91,69.78 125.91,77.02 126.17,77.27 128.2,77.27
GND on TOP (solid shape): 171.76,23.17 171.76,22.41 171.63,22.28 168.46,22.28 168.33,22.41 168.33,22.79 168.46,22.92 168.84,22.92 169.35,23.42 171.51,23.42
GND on TOP (solid shape): 153.01,19.36 152.25,18.6 151.49,18.6 151.36,18.72 151.36,19.29 151.61,19.55 152.06,19.55 152.31,19.8 152.31,20.69 152.44,20.82 153.01,20.82
GND on TOP (solid shape): 172.06,15.61 172.19,15.48 172.19,15.1 172.06,14.98 171.17,14.98 171.04,15.1 171.04,16.18 171.17,16.31 172.06,16.31
GND on TOP (solid shape): 39.55,29.9 39.55,29.11 38.44,28 37.17,28 36.63,27.46 36.63,24.31 36.38,24.06 34.09,24.06 33.58,24.57 33.58,29.52 34.09,30.03 39.43,30.03
GND on TOP (solid shape): 74.22,75.49 74.22,74.6 74.12,74.5 73.49,74.5 73.39,74.6 73.39,74.68 73.31,74.68 73.13,74.86 72.57,74.86 72.45,74.99 72.45,75.49 72.57,75.62 74.1,75.62
GND on TOP (solid shape): 75.88,55.15 75.88,54.03 75.62,53.78 75.62,53.14 75.49,53.01 73.72,53.01 73.59,52.89 73.59,52.25 73.34,52 72.7,52 72.57,52.13 72.57,55.12 72.75,55.3 75.72,55.3
GND on TOP (solid shape): 86.29,119.69 86.29,114.61 86.67,114.23 86.67,112.2 86.54,112.07 82.61,112.07 82.48,112.2 82.48,115.24 82.23,115.5 82.23,119.82 82.48,120.07 85.91,120.07
GND on TOP (solid shape): 44.25,16.69 47.55,16.69 47.94,16.31 47.94,15.8 47.81,15.68 46.92,15.68 46.67,15.42 46.67,12.12 46.41,11.87 45.4,11.87 44.76,12.5 42.86,12.5 42.22,13.14 42.22,16.95 42.35,17.07 43.87,17.07
GND on TOP (solid shape): 29.09,109.88 29.09,106.72 28.71,106.34 25.81,106.34 25.7,106.46 25.24,106.46 25.03,106.67 25.03,109.77 25.2,109.95 29.03,109.95
GND on TOP (solid shape): 84.64,16.31 84.64,15.55 84.51,15.42 82.35,15.42 82.23,15.3 82.23,13.9 82.1,13.77 81.46,13.77 81.21,14.03 81.21,15.93 81.72,16.44 84.51,16.44
GND on TOP (solid shape): 169.56,28.67 169.56,28.61 170.8,28.61 170.8,28.63 171.13,28.63 171.25,28.5 171.89,28.5 172.01,28.38 172.01,27.36 171.76,27.11 169.09,27.11 168.84,27.36 168.84,27.74 168.81,27.77 168.81,27.89 168.69,27.89 168.59,28 168.59,28.63 168.71,28.76 169.47,28.76
GND on TOP (solid shape): 43.11,47.3 43.11,40.19 42.47,39.55 41.12,39.55 40.95,39.72 40.95,44.38 41.03,44.45 41.33,44.45 41.84,44.96 41.84,46.03 41.2,46.66 39.81,46.66 39.55,46.92 39.55,48.14 39.76,48.34 42.07,48.34
GND on TOP (solid shape): 173.92,105.21 174.51,105.21 174.51,105.21 175.19,105.21 175.32,105.08 175.32,102.54 175.57,102.29 175.57,101.66 175.44,101.53 174.05,101.53 173.67,101.91 171.38,101.91 171.13,102.16 171.13,103.56 171.51,103.94 171.63,103.94 171.71,104.02 171.79,104.02 171.79,104.78 171.76,104.78 171.76,105.45 171.91,105.59 173.54,105.59
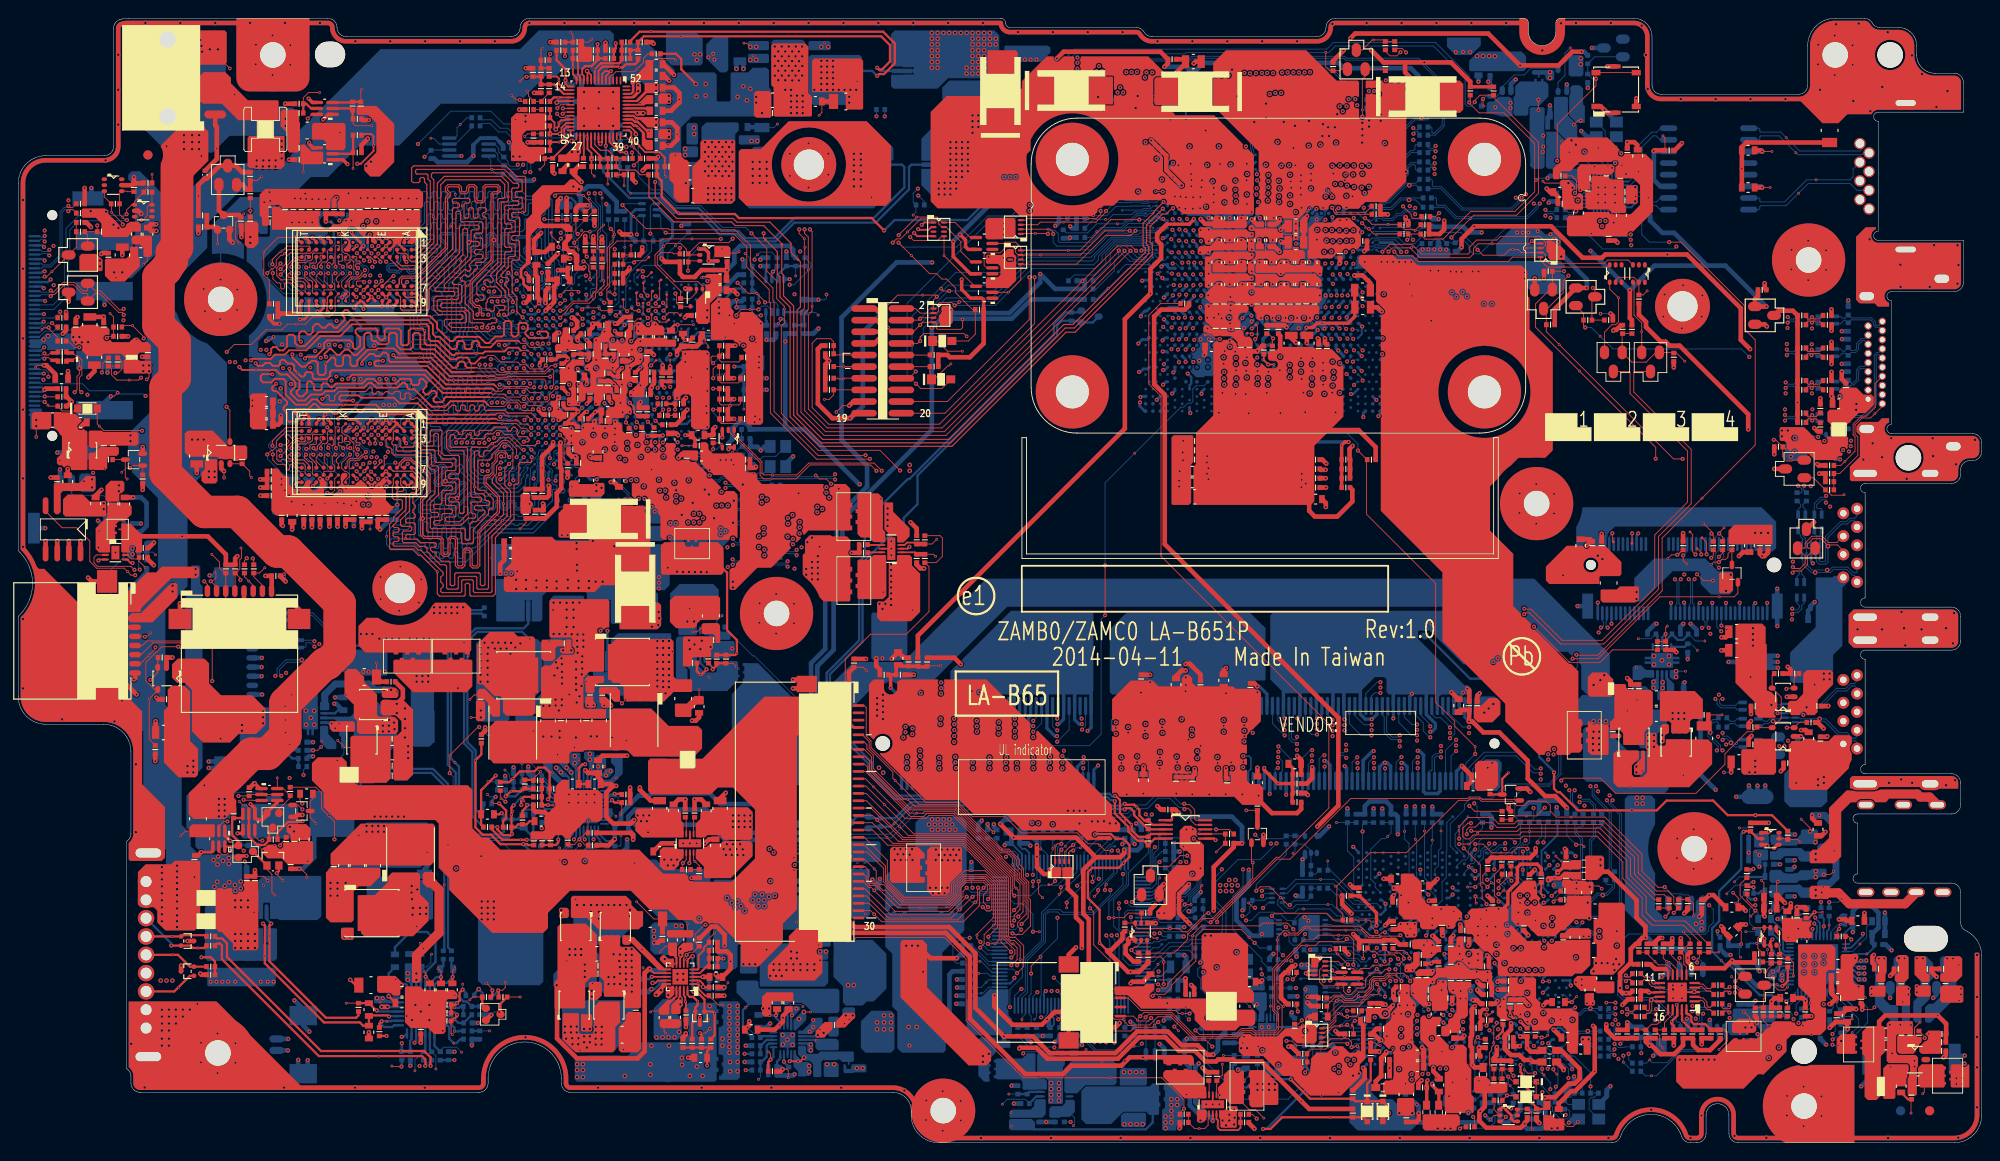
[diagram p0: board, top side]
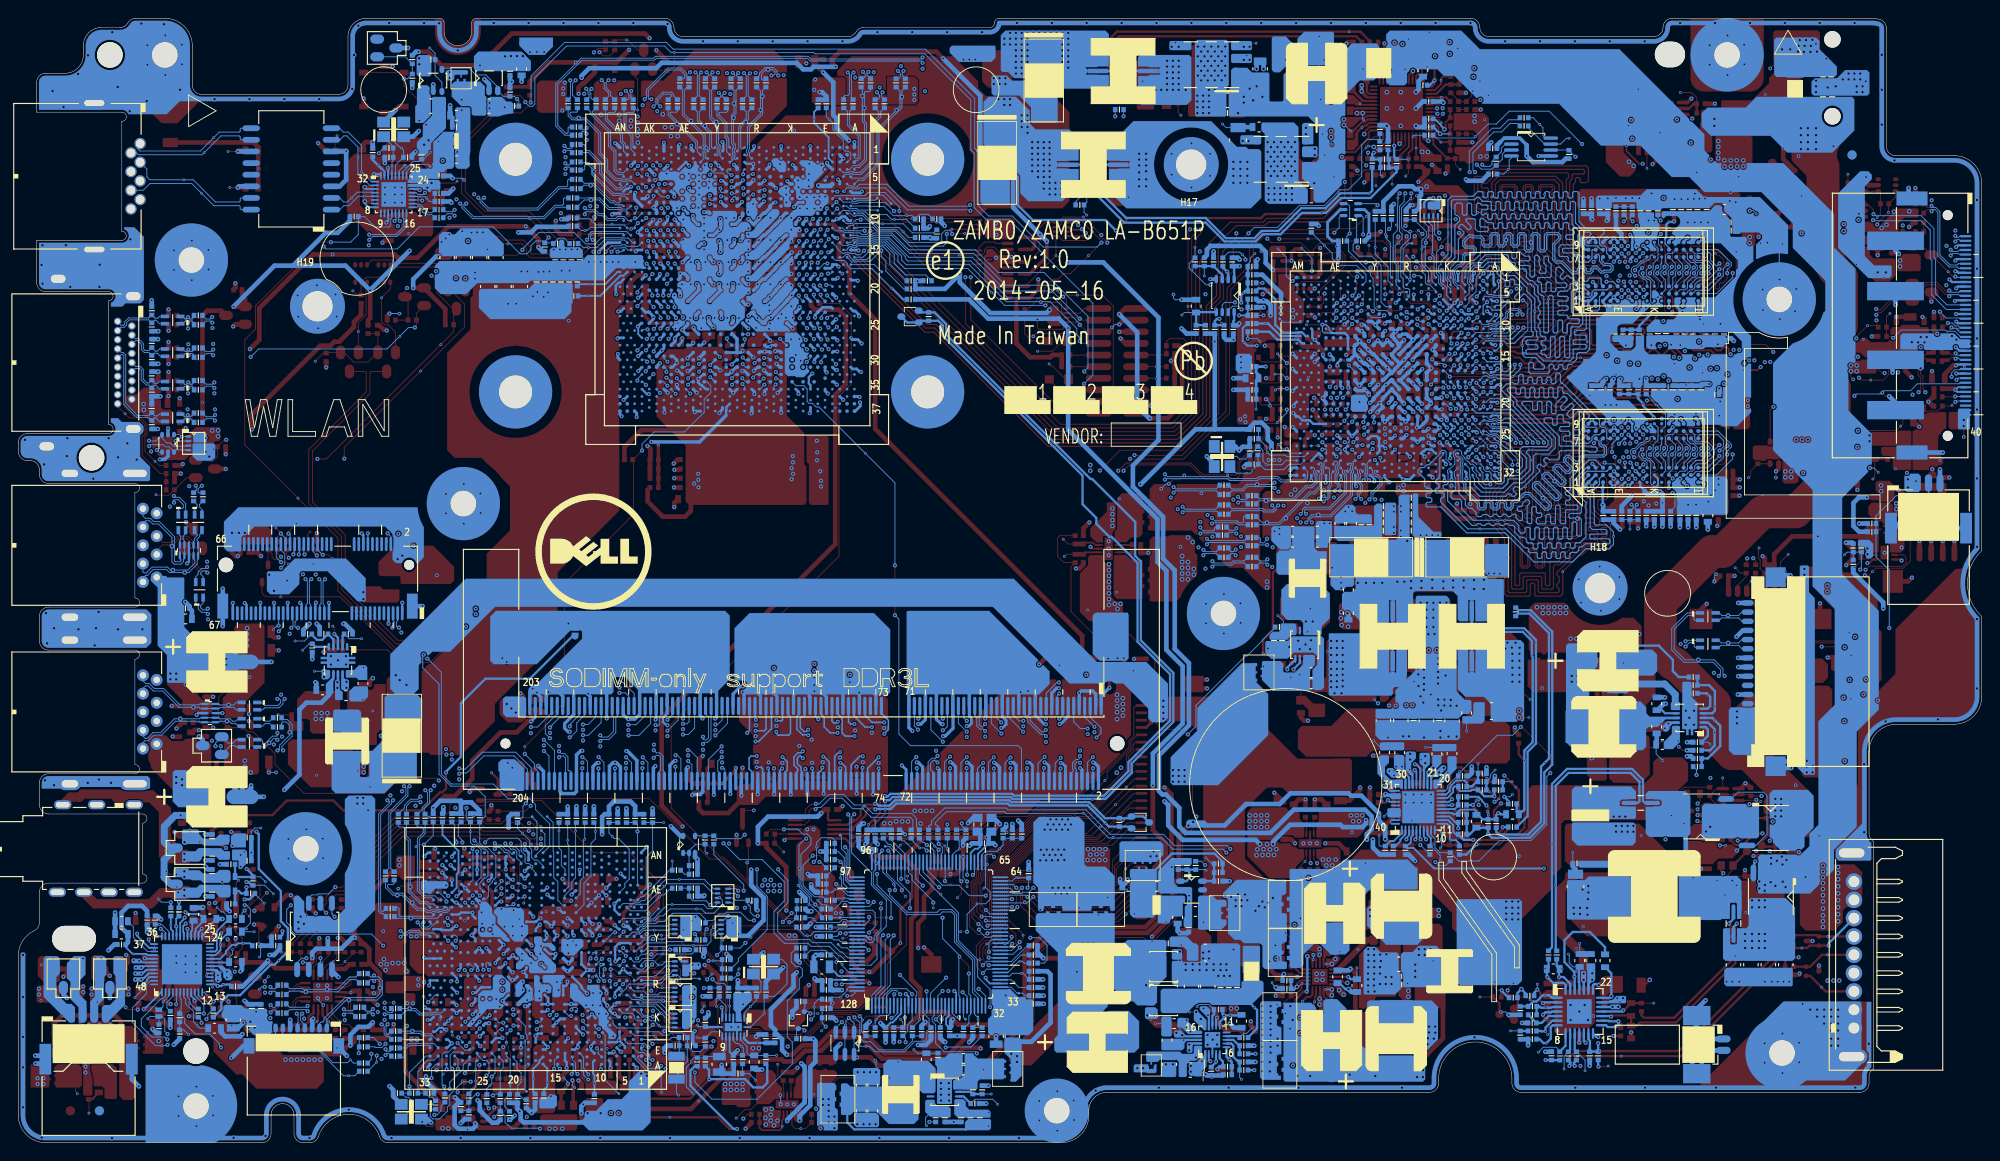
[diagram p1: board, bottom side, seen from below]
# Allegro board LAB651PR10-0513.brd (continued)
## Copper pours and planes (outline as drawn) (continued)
GND on TOP (solid shape): 183.95,48.44 183.95,46.41 183.83,46.28 182.81,46.28 182.56,46.03 182.56,44.96 182.28,44.68 180.66,44.68 180.5,44.84 180.5,45.8 180.27,46.03 179.38,46.03 179.25,46.16 179.25,49.2 179.38,49.33 179.41,49.31 179.58,49.28 179.75,49.33 183.06,49.33
GND on TOP (solid shape): 65.72,22.53 65.72,21.52 65.84,21.39 67.11,21.39 68,20.5 68,14.8 67.87,14.67 66.38,14.67 66.24,14.81 66.24,15.79 66.1,15.93 64.06,15.93 63.95,16.04 63.95,17.67 63.44,18.17 63.44,22.29 63.81,22.66 65.59,22.66
GND on TOP (solid shape): 134.13,96.25 134.13,95.15 134.04,95.06 130.52,95.06 130.47,95.12 130.45,95.12 130.42,95.15 130.42,96 130.83,96.41 131.22,96.41 131.8,95.83 132.1,95.83 132.11,95.82 132.27,95.79 132.43,95.82 132.44,95.83 132.81,95.83 133.4,96.41 133.97,96.41
GND on TOP (solid shape): 131.88,100.64 131.88,100.64 132.14,100.64 132.14,100.63 132.27,100.61 132.4,100.63 132.41,100.64 132.77,100.64 133.37,101.24 134.05,101.24 134.14,101.15 134.14,100.02 134,99.87 130.49,99.87 130.46,99.91 130.41,99.96 130.41,100.6 130.46,100.65 130.46,101.03 130.68,101.24 131.27,101.24
GND on TOP (solid shape): 211.1,40.04 211.63,39.82 211.84,39.3 211.84,38.66 207.83,38.66 207.65,38.84 203.23,38.84 203.05,38.66 200.09,38.66 200.01,38.75 200.01,39.78 200.27,40.04
GND on TOP (solid shape): 134.15,98.46 134.15,97.54 134.06,97.45 130.39,97.45 130.2,97.26 130.2,97.17 130.03,97 128.93,97 128.78,97.15 128.78,97.66 129.06,97.95 130.16,97.95 130.7,98.49 130.7,98.61 130.9,98.8 131.2,98.8 131.79,98.2 132.23,98.2 132.27,98.2 132.67,98.2 133.28,98.82 133.79,98.82
GND on TOP (solid shape): 206.88,13.23 206.88,11.9 206.81,11.84 205.25,11.84 205.06,11.65 205.06,9.92 205.11,9.87 205.11,9.76 205.29,9.58 207.19,9.58 207.45,9.33 207.45,8.33 207.35,8.23 207.35,8.21 207.32,8.18 207.32,5.26 207.19,5.14 206.43,5.14 206.3,5.26 206.3,7.02 206.41,7.12 206.41,7.14 206.43,7.17 206.43,7.66 206.53,7.76 206.53,7.78 206.56,7.8 206.56,8.44 206.53,8.46 206.53,8.48 206.35,8.67 206.33,8.67 206.3,8.69 204.25,8.69 204.02,8.92 204.02,13.01 204.3,13.29 206.81,13.29
GND on TOP (solid shape): 211.1,58.24 211.63,58.02 211.84,57.5 211.84,54.8 211.63,54.27 211.1,54.05 200.42,54.05 199.87,54.59 199.87,57.7 200.41,58.24
GND on TOP (solid shape): 44.2,103.74 44.2,102.26 43.97,102.04 34.88,102.04 34.88,102.75 34.86,102.8 34.98,102.93 34.98,103.43 34.48,103.43 34.12,103.07 34.12,102.75 34.07,102.75 34.07,102.04 28.89,102.04 28.5,102.42 27.62,102.42 27.36,102.16 27.36,100.26 27.23,100.13 26.73,100.13 26.6,100.26 26.6,101.02 26.35,101.27 26.35,103.56 26.96,104.17 43.77,104.17
GND on TOP (solid shape): 69.53,89.7 69.59,89.69 70.02,89.26 70.29,89.26 70.57,88.98 70.57,88.29 70.44,88.17 67.61,88.17 67.42,88.36 67.42,88.73 67.47,88.78 67.47,89.57 67.54,89.64 68.03,89.64 68.46,89.22 68.47,89.2 68.47,89.18 68.49,89.16 68.52,89.15 68.56,89.11 68.93,89.07 69.11,89.39 69.11,89.43 69.11,89.47 69.35,89.71 69.49,89.71
GND on TOP (solid shape): 87.81,23.09 87.81,21.34 87.77,21.26 87.68,21.25 87.18,20.88 87.68,20.52 87.77,20.51 87.81,20.42 87.81,18.55 86.98,17.71 82.23,17.71 81.84,18.09 81.84,19.36 84.13,21.65 84.13,22.56 85.02,23.45 87.46,23.45
GND on TOP (solid shape): 108.71,97.46 108.71,97.08 108.96,96.83 108.96,94.16 108.13,93.34 105.72,93.34 105.66,93.4 105.66,94.35 105.85,94.54 106.99,94.54 107.24,94.8 107.24,95.69 106.93,96 105.78,96 105.66,96.13 105.66,96.47 107.86,96.47 107.86,96.43 107.87,96.39 107.89,96.34 107.91,96.31 107.94,96.27 107.97,96.24 108.01,96.22 108.05,96.21 108.1,96.2 108.12,96.2 108.52,96.2 108.55,96.2 108.59,96.21 108.63,96.22 108.67,96.24 108.7,96.27 108.73,96.31 108.76,96.34 108.77,96.39 108.78,96.43 108.78,96.47 108.77,96.52 108.76,96.56 108.73,96.6 108.7,96.63 108.67,96.66 108.63,96.68 108.59,96.7 108.55,96.71 108.52,96.71 108.12,96.71 108.1,96.71 108.05,96.7 108.01,96.68 107.97,96.66 107.94,96.63 107.91,96.6 107.89,96.56 107.87,96.52 107.86,96.47 105.66,96.47 105.66,96.83 105.78,96.96 107.37,96.96 108.01,97.59 108.58,97.59
GND on TOP (solid shape): 142.19,96.28 142.19,95.84 142.42,95.61 142.42,95.06 142.42,95.05 142.38,94.93 142.4,94.8 142.4,94.77 142.28,94.64 142.07,94.64 141.86,94.84 141.86,94.9 141.81,94.9 141.76,94.95 141.76,94.95 141.66,95.05 138.38,95.05 137.99,94.66 137.73,94.66 137.39,95 135.22,95 135.11,95.1 135.11,95.82 135.18,95.89 135.18,96.16 135.44,96.42 136.4,96.42 136.46,96.36 136.46,95.89 136.56,95.79 136.85,95.79 136.89,95.79 137.31,95.79 137.55,96.03 137.55,96.13 137.84,96.42 138.6,96.42 138.82,96.2 138.82,96 138.97,95.86 139.16,95.86 139.39,95.79 139.61,95.86 139.91,95.86 140.02,95.97 140.02,96.31 140.11,96.4 140.45,96.4 140.54,96.31 140.54,95.97 140.72,95.79 140.96,95.79 141.37,95.79 141.52,95.94 141.52,96.33 141.61,96.42 141.86,96.42 141.86,96.45 142.01,96.45
GND on TOP (solid shape): 202.84,99.76 202.36,98.92 203.1,98.3 212.14,98.3 212.14,93.95 211.93,93.42 211.4,93.21 204.55,93.21 203.81,92.58 204.29,91.74 204.29,91.32 203.05,91.32 202.7,91.67 201.07,91.67 200.69,92.05 200.69,98.94 201.73,99.98 202.25,99.98 202.26,99.99 202.84,99.99
GND on TOP (solid shape): 158.47,18.88 159.26,18.88 159.32,18.83 160.72,18.83 160.94,18.6 160.94,17.59 160.93,17.57 159.86,17.57 159.57,17.87 159.53,17.87 159.52,17.87 159.31,17.94 159.1,17.87 156.1,17.87 155.93,18.04 155.07,18.04 154.76,17.72 154.76,17.41 154.68,17.34 154.23,17.34 153.81,16.92 153.81,15.45 153.92,15.34 154.22,15.34 154.26,15.3 154.26,15.19 154.25,15.19 154.25,14.95 154.15,14.86 154.12,14.87 153.99,14.89 153.85,14.86 153.84,14.86 153.36,14.86 152.05,16.17 152.05,17.29 152.09,17.3 152.33,17.54 152.26,17.87 152.25,17.98 152.34,18.04 154.4,18.04 154.79,18.43 154.79,18.61 154.79,18.62 154.82,18.76 154.79,18.9 154.79,18.91 154.79,19.08 154.83,19.12 155.73,19.12 155.91,19.3 156.7,19.3 157.19,19.78 157.57,19.78
GND on TOP (solid shape): 130.38,88.83 130.41,88.83 131.96,88.83 132.04,88.75 132.04,88.72 132.08,88.62 132.19,88.57 132.24,88.57 132.25,88.56 132.42,88.52 132.58,88.56 132.6,88.57 132.71,88.57 132.81,88.61 132.86,88.71 132.86,88.75 133.26,88.75 133.31,88.8 133.53,88.8 133.62,88.7 133.74,88.64 133.75,88.63 133.81,88.57 133.81,88.19 133.97,88.04 134.45,88.04 134.71,87.78 134.71,87.76 134.74,87.63 134.8,87.52 134.8,87 134.7,86.9 133.32,86.9 133.13,87.09 133.13,87.35 133.13,87.43 132.49,88.07 131.43,88.07 131.21,88.14 130.99,88.07 130.56,88.07 130.25,88.37 129.84,88.37 129.72,88.47 129.56,88.49 129.53,88.49 129.39,88.62 129.39,89.11 129.6,89.31 129.9,89.31
GND on TOP (solid shape): 60.15,39.55 60.15,38.69 60.31,38.54 63.3,38.54 63.81,38.03 63.81,35.44 63.43,35.06 62.63,35.06 62.56,35.08 62.53,35.15 62.25,35.43 61.97,35.15 61.94,35.08 61.87,35.06 61.86,35.06 60.34,33.54 60.34,33.3 60.25,33.2 59.74,33.2 59.37,33.58 58.71,33.58 58.4,33.28 58.4,33.18 58.35,33.13 55.95,33.13 55.92,33.16 55.92,33.86 56.07,34.01 57.03,34.01 57.06,34 57.41,34.09 57.5,34.44 57.48,34.49 57.46,34.53 57.46,35.62 58.47,36.62 58.48,36.62 58.65,36.87 58.5,37.13 58.48,37.15 58.48,38.03 58.68,38.23 58.68,38.94 59.37,39.63 60.08,39.63
GND on TOP (solid shape): 64.53,59.17 64.53,56.31 64.46,56.24 64.43,56.25 64.21,56.24 64.04,56.11 63.95,56.06 63.87,56.11 63.22,55.95 63.81,55.65 63.92,55.66 63.98,55.57 63.98,51.55 63.87,51.44 62.36,51.44 62.03,51.11 62.03,51.1 61.89,50.96 61.89,50.95 61.7,50.77 61.7,47.53 61.86,47.37 63.38,47.37 63.38,47.38 64.19,47.38 64.19,46.44 64.06,46.31 57.28,46.31 57.08,46.51 57.08,51.82 57.38,52.13 58.13,52.13 59.27,53.27 60.56,53.27 60.76,53.47 60.76,53.96 60.51,54.21 60.51,54.97 60.31,55.17 59.82,55.17 59.82,55.17 58.11,55.17 57.98,55.3 57.98,59.17 58.17,59.36 64.33,59.36
GND on TOP (solid shape): outline of 142 points within 129.63,91.31 142.33,94.01
GND on TOP (solid shape): outline of 206 points within 200.01,72.25 214.14,79.13
GND on TOP (solid shape): outline of 89 points within 12.05,0.26 214.14,20.76
GND on TOP (solid shape): outline of 1074 points within 0.26,30.77 212.14,122.55
GND on BOTTOM (solid shape): 159.7,119.82 158.68,118.8 156.9,118.8 156.01,119.69 156.01,120.71 159.7,120.71
GND on BOTTOM (solid shape): 197.03,35.36 195.76,35.36 195.64,35.49 195.64,36 195.76,36.12 197.03,36.12
GND on BOTTOM (solid shape): 28.12,18.85 28.12,17.33 27.87,17.07 20.76,17.07 20.63,17.2 20.63,18.98 20.76,19.11 27.87,19.11
GND on BOTTOM (solid shape): 40.32,53.47 40.32,51.16 40.16,51.01 35.9,51.01 35.44,51.46 35.44,53.32 35.97,53.85 39.93,53.85
GND on BOTTOM (solid shape): 65.21,69.78 65.21,66.48 65.08,66.35 64.06,66.35 63.94,66.48 63.94,69.78 64.06,69.91 65.08,69.91
GND on BOTTOM (solid shape): 72.7,23.8 72.7,22.17 71.08,20.55 69.48,20.55 69.02,21.01 69.02,23.66 69.4,24.05 72.46,24.05
GND on BOTTOM (solid shape): 74.73,120.58 74.73,117.91 74.48,117.66 71.33,117.66 70.72,118.27 70.72,121.19 70.87,121.34 73.97,121.34
GND on BOTTOM (solid shape): 77.53,120.66 77.53,117.15 77.27,116.9 76.64,116.9 75.11,118.42 75.11,119.94 76,120.83 77.36,120.83
GND on BOTTOM (solid shape): 89.59,8.56 89.59,7.29 89.46,7.17 88.07,7.17 87.94,7.29 87.94,8.69 88.07,8.82 89.34,8.82
GND on BOTTOM (solid shape): 95.69,14.03 95.69,10.22 95.31,9.83 92.51,9.83 92,10.34 92,13.26 93.15,14.41 95.31,14.41
GND on BOTTOM (solid shape): 97.08,57.59 97.08,53.4 96.32,52.63 93.4,52.63 93.15,52.89 93.15,57.71 93.27,57.84 96.83,57.84
GND on BOTTOM (solid shape): 109.34,105.54 109.34,102.76 108.97,102.39 106.24,102.39 106.14,102.5 106.14,105.07 106.83,105.76 109.12,105.76
GND on BOTTOM (solid shape): 112.71,119.56 112.71,119.05 111.69,118.04 108.13,118.04 107.68,118.5 107.68,119.71 107.78,119.82 112.45,119.82
GND on BOTTOM (solid shape): 123.15,3.13 123.15,1.93 122.89,1.68 120.58,1.68 120.4,1.86 120.4,2.96 120.72,3.28 122.99,3.28
GND on BOTTOM (solid shape): 123.25,8.01 123.25,6.38 123.12,6.25 120.38,6.25 120.28,6.35 120.28,7.93 120.5,8.16 123.09,8.16
GND on BOTTOM (solid shape): 25.08,11.99 25.08,8.56 23.3,6.79 14.92,6.79 13.14,8.56 13.14,8.57 13.14,15.3 13.26,15.42 21.65,15.42
GND on BOTTOM (solid shape): 32.7,50.22 32.7,45.14 31.17,45.14 31.04,45.27 31.04,48.06 31.68,48.7 31.68,50.22 31.81,50.35 32.57,50.35
GND on BOTTOM (solid shape): 40.32,88.07 40.32,87.56 40.19,87.43 39.68,87.43 39.05,86.8 38.28,86.8 38.03,87.05 38.03,88.07 38.16,88.19 40.19,88.19
GND on BOTTOM (solid shape): 76.62,67.34 77.35,67.34 77.58,67.11 77.58,65.74 76.64,64.8 75.7,64.8 75.39,65.1 75.39,67.21 75.57,67.39 76.57,67.39
GND on BOTTOM (solid shape): 85.4,14.79 85.4,14.53 84.51,13.64 84.51,12.25 84.26,12.25 84.26,14.53 84.64,14.91 85.27,14.91
GND on BOTTOM (solid shape): 85.91,120.2 85.91,112.2 85.78,112.07 82.61,112.07 82.48,112.2 82.48,115.24 82.23,115.5 82.23,120.2 82.48,120.45 85.65,120.45
GND on BOTTOM (solid shape): 15.8,116.26 18.22,116.26 18.6,115.88 18.6,114.61 18.34,114.36 12.48,114.36 12.25,114.58 12.25,116.87 12.53,117.15 14.92,117.15
GND on BOTTOM (solid shape): 40.6,14.95 41.91,14.95 41.95,14.92 41.95,14.78 41.86,14.7 40.55,14.7 40.43,14.58 39.57,14.58 39.43,14.72 39.43,14.94 39.58,15.09 40.46,15.09
GND on BOTTOM (solid shape): 54.23,65.2 54.23,62.21 53.93,61.9 51.71,61.9 51.65,61.96 51.65,65.29 51.75,65.39 54.04,65.39
GND on BOTTOM (solid shape): 62.16,70.79 62.16,66.35 61.91,66.1 59.11,66.1 58.98,66.22 58.98,66.6 59.11,66.73 59.87,66.73 61.52,68.38 61.52,70.79 61.65,70.92 62.03,70.92
GND on BOTTOM (solid shape): 171.21,48.87 173.25,48.87 173.3,48.92 174.12,48.92 174.4,48.65 174.4,46.16 173.84,45.6 170.85,45.6 170.29,46.16 170.29,48.39 170.82,48.92 171.16,48.92
GND on BOTTOM (solid shape): 71.12,65.26 71.12,60.89 70.58,60.34 69.73,60.34 69.35,60.72 68.74,60.72 68.55,60.91 68.55,62.22 68.22,62.55 68.22,65.26 68.32,65.36 71.03,65.36
GND on BOTTOM (solid shape): 78.67,111.31 78.67,110.55 78.29,110.16 78.29,102.93 77.91,102.54 73.72,102.54 73.59,102.67 73.59,104.07 74.61,105.08 74.61,110.93 75.11,111.43 78.54,111.43
GND on BOTTOM (solid shape): 84.89,9.63 85.71,8.82 86.29,8.82 86.54,8.56 86.54,7.42 86.42,7.29 85.2,7.29 85.2,7.75 84.64,8.31 84.64,10.09 84.89,10.09
GND on BOTTOM (solid shape): 141.21,19.45 141.82,19.45 141.9,19.37 141.9,18.24 141.84,18.18 141.24,18.18 141.14,18.29 141.14,18.58 140.82,18.89 140.06,18.89 139.84,19.12 139.84,19.53 139.99,19.69 140.97,19.69
GND on BOTTOM (solid shape): 72.7,67.72 72.7,65.12 72.55,64.97 71.48,64.97 71.39,65.06 71.39,65.44 70.94,65.9 70.94,67.8 71.03,67.9 72.52,67.9
GND on BOTTOM (solid shape): 170.42,28.51 170.42,27.69 169.97,27.23 169.36,27.23 168.85,27.74 167.62,27.74 167.42,27.93 167.42,28.35 167.65,28.57 167.94,28.57 167.95,28.56 169.67,28.56 169.79,28.68 170.26,28.68
GND on BOTTOM (solid shape): 44.08,30.67 44.08,30.22 43.88,30.03 37.39,30.03 36,28.63 36,26.85 35.74,26.6 34.09,26.6 33.84,26.85 33.84,29.9 34.73,30.79 43.96,30.79
GND on BOTTOM (solid shape): 113.24,9.3 114.1,9.3 114.26,9.14 114.26,8.45 114.08,8.27 114.08,4.32 113.98,4.22 112.53,4.22 112.45,4.3 112.45,6.79 112.09,7.15 111.53,7.15 111.26,7.42 111.26,9.66 111.38,9.78 112.76,9.78
GND on BOTTOM (solid shape): 158.69,93.25 163.91,93.25 164.11,93.04 164.11,91.2 162.86,89.94 154.75,89.94 153.99,90.71 153.99,91.6 153.86,91.72 153.86,93.75 153.99,93.88 158.05,93.88
GND on BOTTOM (solid shape): 70.39,15.68 71.66,15.68 71.89,15.45 71.89,14.08 72.46,13.5 72.45,13.49 72.45,11.66 71.99,11.21 69.6,11.21 69.37,11.43 69.37,14.67 70.38,15.68
GND on BOTTOM (solid shape): 70.67,68.38 70.67,67.75 70.54,67.62 66.66,67.62 66.62,67.63 66.6,67.67 66.6,68.51 66.73,68.64 68.13,68.64 68.38,68.89 68.38,69.4 68.67,69.69 69.36,69.69
GND on BOTTOM (solid shape): 85.27,21.52 85.27,19.87 85.4,19.74 87.18,19.74 87.31,19.87 88.32,19.87 88.45,19.74 88.45,17.45 88.04,17.05 81.03,17.05 80.96,17.12 80.96,21.52 81.21,21.77 85.02,21.77
GND on BOTTOM (solid shape): 67.49,21.01 67.49,16.25 67.43,16.18 64.05,16.18 63.43,16.8 63.43,18.42 63.66,18.65 63.66,20.58 63.86,20.78 65.61,20.78 66.22,21.39 67.11,21.39
GND on BOTTOM (solid shape): 108.13,116.43 108.13,114.61 107.88,114.36 105.09,114.36 103.82,113.09 103.82,111.56 103.69,111.43 101.02,111.43 100.89,111.56 100.89,115.24 101.66,116.01 105.91,116.01 106.46,116.55 108.01,116.55
GND on BOTTOM (solid shape): 155.4,98.44 155.4,97.98 155.62,97.76 156.14,97.76 156.38,97.51 156.38,96.8 156.19,96.61 152.8,96.61 152.75,96.66 152.75,97.46 153.08,97.79 153.66,97.79 153.66,97.82 153.81,97.82 153.81,97.79 154.58,97.79 154.58,97.82 154.65,97.82 154.78,97.95 154.78,98.48 154.92,98.62 155.22,98.62
GND on BOTTOM (solid shape): 75.75,54.79 78.09,54.79 78.24,54.64 78.24,53.5 77.6,52.86 75.77,52.86 75.11,53.52 72.95,53.52 72.57,53.14 72.57,52.18 73.08,51.67 73.08,49.64 72.88,49.43 72.09,49.43 71.81,49.71 71.81,55.05 72.07,55.3 75.24,55.3
GND on BOTTOM (solid shape): 162.87,57.46 162.87,52.64 162.49,52.25 157.79,52.25 154.11,55.94 152.96,55.94 152.84,55.81 152.84,55.05 157.92,49.97 158.3,49.97 158.68,49.59 158.68,48.95 149.66,48.95 149.41,49.2 149.41,50.6 149.15,50.86 148.14,50.86 146.36,49.08 138.23,49.08 136.71,50.6 136.71,57.59 137.22,58.09 162.24,58.09
GND on BOTTOM (solid shape): 211.1,40.04 211.63,39.82 211.84,39.3 211.84,38.66 207.83,38.66 207.65,38.84 203.23,38.84 203.05,38.66 200.09,38.66 200.01,38.75 200.01,39.78 200.27,40.04
GND on BOTTOM (solid shape): 89.97,29.6 89.97,27.51 89.67,27.21 87.01,27.21 86.79,26.98 86.79,26.03 87.04,25.77 87.04,24.63 87.15,24.52 87.15,23.63 87.03,23.5 86.29,23.5 86.21,23.58 86.21,27.79 86.35,27.93 87.76,27.93 88.17,28.34 88.17,30.18 88.12,30.23 86.44,30.23 86.26,30.41 86.26,31.04 86.32,31.09 88.47,31.09
GND on BOTTOM (solid shape): 142.12,24.79 142.12,22.33 141.99,22.2 141,22.2 140.85,22.36 140.85,22.65 140.85,22.66 140.88,22.79 140.85,22.91 140.85,22.92 140.85,23.07 140.82,23.09 140.7,23.09 140.69,23.1 140.51,23.14 140.33,23.09 139.91,23.09 139.78,23.22 139.78,24.39 140.26,24.87 142.04,24.87
GND on BOTTOM (solid shape): 211.1,58.24 211.63,58.02 211.84,57.5 211.84,54.8 211.63,54.27 211.1,54.05 200.42,54.05 199.87,54.59 199.87,57.7 200.41,58.24
GND on BOTTOM (solid shape): 117.4,57.97 117.4,49.33 117.02,48.95 102.93,48.95 101.78,50.09 101.78,51.49 102.44,52.14 102.53,52.17 102.6,52.11 103.18,52 103.07,52.58 103.01,52.65 103.04,52.74 108.39,58.09 117.28,58.09
GND on BOTTOM (solid shape): 141.92,17.01 141.92,12.54 141.83,12.45 141.25,12.45 140.49,13.21 140.51,13.27 140.52,13.32 140.52,13.38 140.51,13.43 140.5,13.49 140.47,13.54 140.44,13.59 140.4,13.63 140.36,13.66 140.34,13.68 140.34,15.96 140.44,15.96 140.44,15.9 140.45,15.85 140.47,15.8 140.49,15.75 140.52,15.71 140.56,15.67 140.6,15.64 140.64,15.61 140.69,15.59 140.75,15.58 140.8,15.57 140.85,15.58 140.9,15.59 140.95,15.61 141,15.64 141.04,15.67 141.08,15.71 141.11,15.75 141.13,15.8 141.15,15.85 141.15,15.9 141.15,15.96 141.15,16.01 141.13,16.06 141.11,16.11 141.08,16.15 141.04,16.19 141,16.22 140.95,16.25 140.9,16.27 140.85,16.28 140.8,16.29 140.75,16.28 140.69,16.27 140.64,16.25 140.6,16.22 140.56,16.19 140.52,16.15 140.49,16.11 140.47,16.06 140.45,16.01 140.44,15.96 140.34,15.96 140.34,16.97 140.56,17.2 141.73,17.2
GND on BOTTOM (solid shape): 166.72,99.22 167.07,99.22 167.33,99.47 168.09,99.47 168.47,99.09 168.47,97.18 168.44,97.16 168.41,97.15 168.36,97.14 168.31,97.12 168.26,97.09 168.21,97.05 168.18,97.01 168.15,96.96 168.12,96.9 168.11,96.85 168.11,96.82 168.09,96.8 161.61,96.8 161.38,97.03 161.38,98.17 161.72,98.51 164.93,98.51 164.93,98.45 164.94,98.4 164.95,98.35 164.98,98.3 165.01,98.26 165.04,98.22 165.08,98.19 165.13,98.16 165.18,98.14 165.23,98.13 165.28,98.12 165.34,98.13 165.39,98.14 165.44,98.16 165.48,98.19 165.53,98.22 165.56,98.26 165.59,98.3 165.62,98.35 165.63,98.4 165.64,98.45 165.64,98.51 165.63,98.56 165.62,98.61 165.59,98.66 165.56,98.7 165.53,98.74 165.48,98.77 165.44,98.8 165.39,98.82 165.34,98.83 165.28,98.84 165.23,98.83 165.18,98.82 165.13,98.8 165.08,98.77 165.04,98.74 165.01,98.7 164.98,98.66 164.95,98.61 164.94,98.56 164.93,98.51 161.72,98.51 163.09,99.88 166.06,99.88
GND on BOTTOM (solid shape): 202.84,99.76 202.36,98.92 203.1,98.3 212.14,98.3 212.14,93.95 211.93,93.42 211.4,93.21 204.55,93.21 203.81,92.58 204.29,91.74 204.29,91.32 203.05,91.32 202.7,91.67 201.07,91.67 200.69,92.05 200.69,98.94 201.73,99.98 202.25,99.98 202.26,99.99 202.84,99.99
GND on BOTTOM (solid shape): outline of 137 points within 27.74,86.67 36.63,88.19
GND on BOTTOM (solid shape): outline of 206 points within 200.01,72.25 214.14,79.13
GND on BOTTOM (solid shape): outline of 228 points within 19.36,88.72 42.13,104.13
GND on BOTTOM (solid shape): outline of 230 points within 55.71,46.31 66.2,59.75
GND on BOTTOM (solid shape): outline of 280 points within 128.03,83.59 130.7,88.47
GND on BOTTOM (solid shape): outline of 94 points within 12.05,0.26 214.14,20.76
GND on BOTTOM (solid shape): outline of 1160 points within 0.26,30.82 212.14,122.55
GND on IN1 (solid shape): 67.7,21.06 67.7,16.31 67.37,15.98 64.27,15.98 63.25,17 63.25,21.39 63.28,21.42 67.34,21.42
GND on IN1 (solid shape): 78.29,109.4 78.29,102.93 77.93,102.57 74.35,102.57 73.59,103.33 73.59,109.02 74.1,109.53 78.16,109.53
GND on IN1 (solid shape): 24.06,10.85 24.06,8.31 22.54,6.79 14.92,6.79 13.14,8.56 13.14,8.57 13.14,15.3 13.26,15.42 19.49,15.42
GND on IN1 (solid shape): 85.91,120.2 85.91,112.2 85.78,112.07 82.61,112.07 82.48,112.2 82.48,115.24 82.23,115.5 82.23,120.2 82.48,120.45 85.65,120.45
GND on IN1 (solid shape): 211.1,40.04 211.63,39.82 211.84,39.3 211.84,38.66 200.09,38.66 200.01,38.75 200.01,39.78 200.27,40.04
GND on IN1 (solid shape): 211.1,58.24 211.63,58.02 211.84,57.5 211.84,54.8 211.63,54.27 211.1,54.05 200.42,54.05 199.87,54.59 199.87,57.7 200.41,58.24
GND on IN1 (solid shape): 202.84,99.76 202.36,98.92 203.1,98.3 212.14,98.3 212.14,93.95 211.93,93.42 211.4,93.21 204.55,93.21 203.81,92.58 204.29,91.74 204.29,91.32 203.05,91.32 202.7,91.67 201.07,91.67 200.69,92.05 200.69,98.94 201.73,99.98 202.25,99.98 202.26,99.99 202.84,99.99
GND on IN1 (solid shape): outline of 206 points within 200.01,72.25 214.14,79.13
GND on IN1 (solid shape): outline of 94 points within 12.05,0.26 214.14,20.76
GND on IN1 (solid shape): outline of 1160 points within 0.26,30.82 212.14,122.55
GND on IN2 (solid shape): 78.29,109.4 78.29,102.93 77.91,102.54 73.72,102.54 73.59,102.67 73.59,109.02 74.1,109.53 78.16,109.53
GND on IN2 (solid shape): 25.08,11.99 25.08,8.56 23.3,6.79 14.92,6.79 13.14,8.56 13.14,8.57 13.14,15.3 13.26,15.42 21.65,15.42
GND on IN2 (solid shape): 85.91,120.2 85.91,112.2 85.78,112.07 82.61,112.07 82.48,112.2 82.48,115.24 82.23,115.5 82.23,120.2 82.48,120.45 85.65,120.45
GND on IN2 (solid shape): 67.75,23.3 67.75,14.66 67.37,14.28 63.81,14.28 63.56,14.53 63.56,16.44 62.74,17.25 62.74,21.89 64.41,23.55 67.49,23.55
GND on IN2 (solid shape): 211.1,40.04 211.63,39.82 211.84,39.3 211.84,38.66 200.09,38.66 200.01,38.75 200.01,39.78 200.27,40.04
GND on IN2 (solid shape): 211.1,58.24 211.63,58.02 211.84,57.5 211.84,54.8 211.63,54.27 211.1,54.05 200.42,54.05 199.87,54.59 199.87,57.7 200.41,58.24
GND on IN2 (solid shape): 202.84,99.76 202.36,98.92 203.1,98.3 212.14,98.3 212.14,93.95 211.93,93.42 211.4,93.21 204.55,93.21 203.81,92.58 204.29,91.74 204.29,91.32 203.05,91.32 202.7,91.67 201.07,91.67 200.69,92.05 200.69,98.94 201.73,99.98 202.25,99.98 202.26,99.99 202.84,99.99
GND on IN2 (solid shape): outline of 206 points within 200.01,72.25 214.14,79.13
GND on IN2 (solid shape): outline of 94 points within 12.05,0.26 214.14,20.76
GND on IN2 (solid shape): outline of 1160 points within 0.26,30.82 212.14,122.55
GND on IN2 (solid shape): outline of 4167 points within 110.8,40.7 169.73,84.89
GND on IN3 (solid shape): 25.08,11.99 25.08,8.56 23.3,6.79 14.92,6.79 13.14,8.56 13.14,8.57 13.14,15.3 13.26,15.42 21.65,15.42
GND on IN3 (solid shape): 85.91,119.94 85.91,112.2 85.78,112.07 82.61,112.07 82.48,112.2 82.48,115.24 82.23,115.5 82.23,119.82 82.48,120.07 85.78,120.07
GND on IN3 (solid shape): 78.29,109.4 78.29,103.03 77.93,102.67 74.73,102.67 73.59,103.81 73.59,109.02 74.1,109.53 78.16,109.53
GND on IN3 (solid shape): 211.1,40.04 211.63,39.82 211.84,39.3 211.84,38.66 207.83,38.66 207.65,38.84 203.23,38.84 203.05,38.66 200.09,38.66 200.01,38.75 200.01,39.78 200.27,40.04
GND on IN3 (solid shape): 211.1,58.24 211.63,58.02 211.84,57.5 211.84,54.8 211.63,54.27 211.1,54.05 200.42,54.05 199.87,54.59 199.87,57.7 200.41,58.24
GND on IN3 (solid shape): 202.84,99.76 202.36,98.92 203.1,98.3 212.14,98.3 212.14,93.95 211.93,93.42 211.4,93.21 204.55,93.21 203.81,92.58 204.29,91.74 204.29,91.32 203.05,91.32 202.7,91.67 201.07,91.67 200.69,92.05 200.69,98.94 201.73,99.98 202.25,99.98 202.26,99.99 202.84,99.99
GND on IN3 (solid shape): outline of 206 points within 200.01,72.25 214.14,79.13
GND on IN3 (solid shape): outline of 94 points within 12.05,0.26 214.14,20.76
GND on IN3 (solid shape): outline of 1160 points within 0.26,30.82 212.14,122.55
GND on TOP: 71.42,17.27 71.42,18.96 73.11,18.96 73.11,17.27
GND on GND1: outline of 213 points within 0.26,0.26 214.14,122.55 ; 1 cut-out
GND on VCC: 136.45,39.93 136.45,47.57 137.09,48.21 137.09,56.08 146.49,65.48 146.49,75.09 145.09,76.49 145.09,82.33 144.71,82.71 144.71,83.98 143.21,85.48 143.21,86.37 142.02,87.56 141.66,87.56 141.66,96.85 142.55,97.74 142.55,99.9 143.04,100.39 147.53,100.39 147.78,100.13 157.81,100.13 172.27,85.67 172.27,67.22 168.08,63.03 168.08,55.02 158.81,45.75 158.81,43.98 154.76,39.93
GND on VCC: 96.81,40.57 95.43,41.94 95.43,44.1 95.18,44.36 95.18,52.74 95.05,52.87 95.05,67.77 98.23,70.94 98.23,86.82 100.26,88.85 100.26,101.4 119.67,101.4 120.43,102.16 124.41,102.16 124.79,101.78 127.46,101.78 129.47,99.77 129.47,87.61 130.36,86.72 130.36,86.39 127.31,83.35 127.31,81.57 126.17,80.42 126.17,80.17 125.53,79.54 125.53,74.71 122.36,71.53 122.36,70.14 118.42,66.2 118.42,48.55 117.53,47.66 117.53,43 119.18,41.35 119.18,40.57
GND on VCC: outline of 356 points within 176.46,34.73 214.15,122.55
GND on VCC: 30.03,44.63 30.03,48.32 33.71,48.32 33.71,44.63
GND on GND2: outline of 215 points within 0.26,0.26 214.14,122.55 ; 1 cut-out
GNDA on GND1, GND2: 191.55,16.82 188.65,19.72 188.65,21.88 187.38,23.15 187.38,28.78 188.27,29.67 188.27,33.6 188.88,34.22 197.14,34.22 197.67,34.75 197.67,36.53 199.3,38.16 211.84,38.16 211.84,36.9 211.63,36.37 211.1,36.16 200.85,36.16 200.11,35.53 200.59,34.69 200.59,29.56 200.11,28.72 200.85,28.1 211.1,28.1 211.63,27.88 211.84,27.35 211.84,24.05 212.04,23.38 212.57,22.92 213.46,22.24 214.02,21.26 200.87,21.26 200.23,20.63 199.3,20.63 199.19,20.73 199.19,21.16 199.3,21.26 200.31,21.26 201.22,22.17 201.22,24.93 200.7,25.46 198.71,25.46 198.05,24.8 198.05,23.91 197.41,23.27 197.41,22.26 197.31,22.15 194.26,22.15 193.86,21.75 193.86,17.18 193.5,16.82
GNDA on VCC: 191.55,16.82 188.65,19.72 188.65,21.88 187.38,23.15 187.38,28.78 188.27,29.67 188.27,33.6 188.88,34.22 197.14,34.22 197.67,34.75 197.67,36.53 199.3,38.16 210.83,38.16 210.83,37.17 200.85,37.17 199.22,36.09 199.58,34.17 199.58,30.08 199.22,28.16 200.85,27.08 210.83,27.08 210.83,24.05 211.18,22.84 212.14,22 212.58,21.69 212.92,21.26 200.87,21.26 200.23,20.63 199.3,20.63 199.19,20.73 199.19,21.16 199.3,21.26 200.31,21.26 201.22,22.17 201.22,24.93 200.7,25.46 198.71,25.46 198.05,24.8 198.05,23.91 197.41,23.27 197.41,22.26 197.31,22.15 194.26,22.15 193.86,21.75 193.86,17.18 193.5,16.82
PVCC on TOP (solid shape): 69.32,118.19 69.32,116.11 69.27,116.06 67.72,116.06 67.29,115.63 67.29,114.74 67.01,114.46 66.12,114.46 66.12,114.66 66.83,114.66 66.99,114.81 66.99,115.52 66.83,115.68 66.83,115.96 68.48,117.61 68.48,118.19 68.54,118.24 69.27,118.24
VCC on TOP (solid shape): 61.46,108.06 61.3,107.9 61.3,107.22 61.19,107.12 60.16,107.12 60.09,107.14 60.03,107.14 59.98,107.14 59.91,107.14 59.84,107.12 59.01,107.12 58.96,107.17 58.96,107.83 59.06,107.93 59.8,107.93 61.25,109.38 61.25,110.19 61.46,110.19
VCC on TOP (solid shape): 54.97,112.42 55.73,112.42 55.73,112.45 55.89,112.45 55.89,112.42 56.65,112.42 56.65,112.45 56.8,112.45 56.8,112.42 57.51,112.42 57.51,112.45 57.59,112.45 57.67,112.37 57.66,112.35 57.66,110.55 57.51,110.55 57.51,110.57 56.75,110.57 56.75,110.55 56.61,110.55 56.61,110.56 55.85,110.56 55.85,110.55 55.51,110.55 55.05,110.09 55.05,110 55.04,109.99 55.02,109.88 55.04,109.78 55.05,109.77 55.05,109.4 55.27,109.18 55.28,109.16 55.37,109.01 55.52,108.92 55.53,108.92 55.68,108.77 57.46,108.77 57.59,108.64 57.59,108.13 57.36,107.9 57.09,107.9 57.09,107.26 57,107.17 56.45,107.17 56.22,106.94 55.8,106.94 55.55,107.19 53.88,107.19 53.8,107.27 53.8,109 53.92,109.26 53.8,109.52 53.8,111.92 54.34,112.45 54.97,112.45
VCC on IN2 (solid shape): 63.82,109.5 63.82,109 63.82,108.99 63.8,108.87 63.82,108.74 63.82,108.74 63.82,107.79 63.02,106.99 60.32,106.99 60.03,107.14 59.73,106.99 55.43,106.99 55.19,107.16 54.9,107.09 54.83,107.06 54.77,107.09 54.38,107.13 54.18,106.79 54.19,106.76 54.03,106.61 53.14,106.61 52.89,106.86 52.89,108.26 53.4,108.77 59.37,108.77 59.9,109.3 59.99,109.33 60.06,109.27 60.54,109.06 60.78,109.53 60.79,109.62 60.88,109.66 63.67,109.66
VCC on IN2 (solid shape): outline of 223 points within 53.4,110.8 65.04,117.66
VIN on TOP (solid shape): 30.68,112.67 30.68,111.48 30.75,111.41 30.75,109.2 30.66,109.11 30.66,108.26 30.54,108.13 29.61,108.13 29.42,108.32 29.42,110.21 28.63,111 28.63,112.58 28.89,112.83 30.51,112.83
VIN on TOP (solid shape): 24.82,41.33 24.82,39.43 23.55,38.16 23.55,37.65 23.81,37.39 23.81,36.99 23.8,36.98 23.78,36.86 23.8,36.73 23.81,36.73 23.81,36 23.68,35.87 23.04,35.87 22.54,35.36 19.11,35.36 18.6,35.87 18.6,38.16 22.66,42.22 23.93,42.22
VIN on TOP (solid shape): 20.76,110.42 20.76,107.24 20.01,106.5 20,106.5 20,106.48 19.11,105.59 19.11,101.02 15.68,101.02 15.55,101.15 15.55,107 15.81,107.87 15.56,108.75 15.55,108.76 15.55,108.89 17.84,111.18 20,111.18
VIN on BOTTOM (solid shape): outline of 91 points within 13.9,108.13 30.59,114.23
VIN on BOTTOM (solid shape): 23.17,38.13 23.17,35.48 23.12,35.39 23.02,35.39 22.48,35.08 23.02,34.77 23.12,34.77 23.17,34.69 23.17,33.38 23.16,33.34 23.12,33.33 22.84,33.16 22.82,32.84 22.83,32.81 21.9,31.88 20.29,31.88 20.05,32.08 19.74,32 19.7,31.99 19.67,32 19.34,32.34 19.34,33.35 19.36,33.38 18.34,34.4 18.34,37.9 18.98,38.54 22.76,38.54
+APU_CORE on TOP (solid shape): outline of 211 points within 134.87,89.54 142.08,91.47
+APU_CORE on TOP (solid shape): outline of 3300 points within 130.47,93.44 151.57,119.31
+APU_CORE on BOTTOM (solid shape): 107.12,120.96 107.12,117.12 106.93,116.93 106.32,116.93 105.64,116.26 101.53,116.26 100.39,115.12 95.56,115.12 95.31,115.37 95.31,116.64 97.85,116.64 97.85,117.53 95.43,117.53 95.31,117.66 95.31,121.09 95.69,121.47 106.61,121.47
+APU_CORE on BOTTOM (solid shape): outline of 2706 points within 134.43,88.69 144.47,107.22
+APU_CORE on IN2 (solid shape): outline of 8495 points within 98.86,87.94 154.49,121.47
+APU_CORE on VCC: 130.61,87.18 129.98,87.82 129.98,99.98 127.67,102.29 125,102.29 124.62,102.67 120.22,102.67 119.46,101.91 100.11,101.91 98.35,103.67 98.35,113.11 99.5,114.25 99.5,121.53 106.71,121.53 107.36,120.8 108.3,120.53 121.92,120.53 122.73,119.8 123.8,119.53 141.8,119.53 143.31,120.1 144.05,121.53 151.57,121.53 151.57,100.64 147.99,100.64 147.74,100.89 142.83,100.89 142.04,100.11 142.04,97.95 141.15,97.06 141.15,87.56 130.99,87.56
+APU_CORE_NB on TOP (solid shape): outline of 84 points within 129.56,88.67 134.24,91.78
+APU_CORE_NB on TOP (solid shape): 130.35,99.74 134.05,99.74 134.09,99.76 134.12,99.74 134.39,99.47 134.69,99.47 134.83,99.47 134.86,99.46 134.88,99.42 134.88,98.97 134.8,98.9 134.31,98.9 134.14,98.72 134.1,98.71 134.07,98.72 133.84,98.95 133.65,98.95 133.54,98.96 133.43,98.95 133.23,98.95 132.61,98.33 132.31,98.33 132.23,98.33 131.85,98.33 131.5,98.68 131.5,98.69 131.29,98.93 130.98,98.93 130.97,98.93 130.84,98.93 130.58,98.66 130.58,98.54 130.11,98.07 129.71,98.07 129.56,98.23 129.56,98.37 129.53,98.39 129.53,98.42 129.53,98.43 129.38,98.78 129,98.83 128.9,98.84 128.86,98.92 128.86,99.81 129.02,99.98 130.12,99.98
+APU_CORE_NB on TOP (solid shape): outline of 85 points within 129.56,93.37 134.88,97.36
+APU_CORE_NB on TOP (solid shape): outline of 1977 points within 99.62,101.17 134.93,118.65
+APU_CORE_NB on BOTTOM (solid shape): 109,113.68 109,109.05 108.77,108.82 107.44,108.82 107.31,108.69 107.31,107.92 104.98,105.6 104.98,103.69 104.1,102.81 100.37,102.81 98.61,104.58 98.61,106.35 101.02,106.35 101.02,107.24 98.61,107.24 98.61,109.66 99.62,110.67 103.31,110.67 103.94,111.31 103.94,112.7 105.48,114.24 108.44,114.24
+APU_CORE_NB on BOTTOM (solid shape): 132.16,107.27 132.16,107.12 132.05,106.97 132.02,106.78 132.03,106.75 131.85,106.58 131.84,106.57 131.7,106.5 131.63,106.36 131.62,106.35 131.27,106 130.71,106 130.55,106.17 130.56,106.2 130.58,106.32 130.54,106.44 130.54,106.45 130.54,106.95 130.55,106.98 130.87,107.29 130.91,107.29 130.92,107.28 131.19,107.23 131.37,107.43 131.37,107.45 131.45,107.52 131.91,107.52
+APU_CORE_NB on BOTTOM (solid shape): 132.58,101.4 132.59,101.39 132.67,101.26 132.8,101.18 132.82,101.18 133.25,100.74 133.25,100.73 133.78,100.2 133.79,100.19 133.85,100.09 133.94,100.01 133.94,99.85 134.27,99.52 134.55,99.52 134.56,99.52 134.69,99.49 134.81,99.52 134.82,99.52 134.85,99.52 134.98,99.39 134.98,99.19 134.97,99.1 134.98,98.96 134.83,98.81 133.82,98.81 133.75,98.87 133.66,98.92 133.65,98.92 131.47,101.1 131.47,101.11 131.4,101.23 131.3,101.31 131.3,101.76 131.5,101.96 132.03,101.96
+APU_CORE_NB on BOTTOM (solid shape): 130.81,104.55 130.93,104.42 131.1,104.37 131.12,104.37 131.31,104.18 131.32,104.17 131.36,104.06 131.43,103.98 131.43,103.76 131.09,103.43 131.07,103.43 130.8,103.23 130.84,102.89 130.84,102.51 130.79,102.41 130.77,102.29 130.77,102.27 130.69,102.19 130.1,102.19 130.06,102.23 130.06,102.25 130.04,102.33 130,102.41 130,102.78 130.03,102.8 130.23,103.1 130.03,103.4 130,103.42 130,103.58 130.03,103.6 130.23,103.85 130.12,104.14 130.09,104.21 130.12,104.29 130.41,104.58 130.79,104.58
+APU_CORE_NB on BOTTOM (solid shape): 134.03,103.2 134.08,103.18 134.16,103.18 134.33,103.01 134.33,103 134.52,102.76 134.82,102.74 134.84,102.71 134.84,102.66 134.92,102.59 134.92,101.43 134.84,101.36 134.84,101.32 134.81,101.25 134.73,101.22 134.48,101.16 134.34,100.94 134.34,100.93 134.16,100.76 134.06,100.76 133.89,100.92 133.9,100.95 133.86,101.16 133.69,101.33 133.69,102.03 133.83,102.31 133.67,102.58 133.62,102.67 133.68,102.76 133.82,102.89 133.88,103.08 133.88,103.09 134,103.21
+APU_CORE_NB on BOTTOM (solid shape): outline of 102 points within 129.18,88.58 135.03,92.37
+APU_CORE_NB on BOTTOM (solid shape): outline of 133 points within 129.71,89.91 134.89,96.89
+APU_CORE_NB on BOTTOM (solid shape): outline of 524 points within 125.91,94.06 135.06,107.29
+APU_CORE_NB on IN2 (solid shape): outline of 6608 points within 100.26,86.16 134.8,114.24
+BIF_VDDC on TOP (solid shape): 61.18,72.31 61.18,72.05 61.31,71.92 62.78,71.92 62.93,72.07 63.88,72.07 64.03,71.92 64.03,70.91 63.66,70.54 60.25,70.54 60.13,70.67 60.13,72.14 60.33,72.34 61.14,72.34
+BIF_VDDC on IN3 (solid shape): outline of 861 points within 59.49,70.93 64.32,81.34
+DP_VDDC on IN2 (solid shape): outline of 162 points within 65.94,79.86 67.77,82.05
+FAN_POWER on TOP (solid shape): 8.03,72.82 8.16,72.8 8.29,72.83 8.31,72.83 8.44,72.7 8.44,71.43 8.18,71.18 4.88,71.18 4.63,70.92 4.63,68.89 4.37,68.64 4.12,68.64 3.87,68.89 3.87,71.94 3.99,72.06 6.66,72.06 7.42,72.83 8.03,72.83
+FAN_POWER on BOTTOM (solid shape): 7.82,73.05 8.04,72.82 8.35,72.86 8.39,72.88 8.44,72.83 8.44,71.3 8.18,71.05 6.91,71.05 6.66,71.3 6.66,72.83 6.91,73.08 7.81,73.08
+FCH_VDD_11_SSUSB_S on TOP (solid shape): outline of 232 points within 153.09,3.23 158.93,13.9
+FCH_VDD_11_SSUSB_S on BOTTOM (solid shape): 156.6,5.03 156.6,4.95 156.68,4.95 156.7,4.93 157.36,4.93 157.51,4.78 157.51,3.87 157.38,3.74 155.89,3.74 155.58,4.04 155.58,5.06 155.76,5.24 156.39,5.24
+INV_PWR_SRC on TOP (solid shape): 3.61,79.68 3.61,78.16 3.39,77.93 3.33,77.91 1.58,77.91 1.45,78.03 1.45,79.56 1.71,79.81 3.49,79.81
+INV_PWR_SRC on BOTTOM (solid shape): 2.6,80.07 2.6,78.03 2.47,77.91 1.33,77.91 1.27,77.96 1.27,80.19 2.47,80.19
+INV_PWR_SRC_R on TOP (solid shape): 4.74,79.76 5.96,79.76 5.96,79.62 6.22,79.62 6.91,78.92 6.91,78.79 6.56,78.44 6.56,77.93 7.07,77.93 7.1,77.97 7.3,77.78 7.42,77.78 7.55,77.65 7.55,73.59 7.42,73.46 5.75,73.46 5.75,73.59 5.5,73.93 5.1,73.79 5.03,73.75 4.95,73.78 4.76,73.97 4.76,73.98 4.43,73.98 4.21,74.2 4.21,74.76 4.76,75.3 4.76,77.14 4.48,77.42 4.47,77.43 4.27,77.77 3.94,77.97 3.93,77.97 3.87,78.03 3.87,79.68 3.99,79.81 4.69,79.81
+LAN_REGOUT on BOTTOM (solid shape): outline of 128 points within 166.81,104.8 171.89,110.42
+LAN_VDD10 on TOP (solid shape): 176.84,104.45 176.84,102.67 176.71,102.54 175.7,102.54 175.57,102.67 175.57,104.45 175.7,104.58 176.71,104.58
+LAN_VDD10 on TOP (solid shape): 174.06,106.83 174.13,106.73 174.24,106.66 174.25,106.65 174.3,106.61 174.3,106.1 173.92,105.72 172.47,105.72 172.47,105.75 171.71,105.75 171.71,105.54 171.63,105.47 171.63,104.32 171.25,103.94 170.51,103.94 170.31,104.14 170.31,105.15 170.24,105.22 170.24,106.48 170.62,106.86 174.04,106.86
+LAN_VDD10 on BOTTOM (solid shape): 166.68,112.96 166.68,112.13 166.65,112.1 166.65,111.33 166.63,111.33 166.63,110.52 166.68,110.52 166.68,106.61 166.43,106.35 165.41,106.35 165.07,106.7 165.07,106.72 165.12,107.53 165.03,108.33 165.03,112.96 165.16,113.09 166.55,113.09
+LAN_VDD10 on IN2 (solid shape): outline of 342 points within 165.51,101.91 177.35,110.6
+LAN_VDD33 on TOP (solid shape): outline of 271 points within 167.57,98.99 178.52,109.78
+LAN_VDD33 on BOTTOM (solid shape): 163.18,113.92 163.18,112.28 163.18,112.22 163.02,112.07 161.94,112.07 161.93,112.07 161.14,112.31 160.33,112.41 160.33,113.47 160.58,113.72 161.09,113.72 161.6,114.23 162.87,114.23
+LAN_VDD33 on BOTTOM (solid shape): 169.22,114.1 169.22,112.2 169.25,112.17 169.25,112.15 170.13,111.27 170.15,111.27 170.24,111.18 170.24,109.91 170.87,109.28 170.87,108.56 170.67,108.29 170.77,107.98 170.87,107.88 170.87,107.88 170.8,107.8 169.96,107.8 169.96,107.79 169.65,108.09 169.65,108.11 169.65,108.14 169.59,108.35 169.39,108.45 169.36,108.47 169.35,108.5 169.35,109.15 169.2,109.3 169.2,109.32 167.99,110.52 167.98,110.52 167.7,110.8 167.7,111.62 167.7,111.62 167.7,112.77 167.7,112.77 167.7,114.1 167.82,114.23 169.09,114.23
+LAN_VDD33 on IN2 (solid shape): 165.53,114.1 165.61,114.06 165.63,113.98 165.84,113.58 166.27,113.71 166.35,113.75 166.43,113.72 166.9,113.25 166.9,113.23 167,113.05 167.18,112.95 167.2,112.95 170.74,109.4 170.74,108.64 170.36,108.26 169.3,108.26 165.49,112.07 161.6,112.07 160.97,112.7 160.97,113.97 161.09,114.1
+LAN_VDD33_UL2 on BOTTOM (solid shape): 167.09,115.57 167.09,114.25 166.05,113.21 165.11,113.21 164.9,113.01 164.9,112.35 164.73,112.17 163.43,112.17 163.28,112.32 163.28,112.85 163.28,112.86 163.3,112.98 163.28,113.11 163.28,113.12 163.28,113.43 163.28,113.44 163.3,113.57 163.28,113.69 163.28,113.7 163.28,114.2 163.46,114.38 163.46,115.4 163.96,115.9 166.76,115.9
+LAN_VDD33_UL3 on BOTTOM (solid shape): 170.87,115.12 170.87,113.4 171.06,113.21 171.06,111.43 171,111.37 170.17,111.37 169.35,112.2 169.35,114.37 169.46,114.52 169.5,114.69 169.5,114.92 169.49,115.02 169.46,115.11 169.45,115.12 169.45,115.22 169.73,115.5 170.49,115.5
+LAN_VDDREG on TOP (solid shape): outline of 96 points within 168.38,101.91 170.87,105.16
+LAN_VDDREG on BOTTOM (solid shape): 169.71,105.16 170.17,104.7 171.84,104.7 171.89,104.66 171.89,104.4 171.84,104.35 171.81,104.37 171.76,104.38 171.7,104.39 171.02,104.39 170.97,104.38 170.91,104.36 170.72,104.36 170.71,104.37 170.43,104.37 170.24,104.18 170.23,104.17 170.13,104.06 170.1,104.07 169.84,104.06 169.66,103.87 169.64,103.84 169.4,103.84 169.32,103.92 169.32,103.99 169.3,104.02 169.3,104.09 168.53,104.09 168.53,104.07 168.38,104.07 168.38,104.09 168.36,104.09 168.31,104.14 168.31,104.96 168.51,105.16
+LCDVDD on TOP (solid shape): 13.26,85.4 14.41,85.4 14.53,85.27 14.53,84.13 14.41,84 11.61,84 11.49,84.13 11.49,85.4 11.61,85.53 13.14,85.53
+LCDVDD on TOP (solid shape): 21.75,74.55 21.75,74.3 21.75,74.28 21.75,74.05 21.75,74.04 21.75,72.22 21.52,71.99 20.3,71.99 20,72.29 20,73.21 20.35,73.56 20.35,74.55 20.45,74.65 21.65,74.65
+LCDVDD on IN1 (solid shape): outline of 262 points within 13.26,71.81 21.82,85.15
+LCDVDD_CONN on TOP (solid shape): 8.95,89.08 9.71,89.08 9.96,88.83 9.96,88.22 9.79,88.22 9.78,88.22 9.31,87.8 9.92,87.65 9.94,87.67 10.01,87.67 10.01,87.66 10.04,87.66 10.27,87.43 12.11,87.43 12.36,87.69 12.4,87.69 12.64,87.93 13.05,87.93 13.54,87.43 14.15,87.43 14.47,87.11 14.47,86.48 14.28,86.29 13.26,86.29 12.76,85.78 11.61,85.78 11.23,86.16 9.33,86.16 9.07,85.91 7.55,85.91 6.88,86.58 6.9,87.13 6.35,87.04 5.77,87.62 5.77,88.96 5.9,89.08 6.66,89.08 6.91,89.34 8.69,89.34
+LCDVDD_CONN on BOTTOM (solid shape): 4.45,88.4 4.49,88.38 4.5,88.35 4.86,87.99 5.21,88.35 5.23,88.38 5.26,88.4 8.62,88.4 8.9,88.12 8.9,86.69 8.83,86.63 6.93,86.63 6.66,87.22 6.39,86.63 6.18,86.63 6.18,86.57 3.24,86.57 3.15,86.62 3.14,86.71 2.9,87.22 2.47,86.86 2.47,86.84 2.37,86.74 2.31,86.75 2.28,86.75 1.27,86.75 1.27,87.75 2.28,87.75 2.4,87.77 2.49,87.86 3.03,88.4
+LCDVDD_CONN on IN1 (solid shape): outline of 105 points within 2.47,87.05 8.06,89.08
+V_TP on TOP (solid shape): 12.38,69.52 12.38,68.64 11.61,67.87 10.98,67.87 10.6,67.49 10.6,67.2 10.52,67.2 10.52,66.77 10.6,66.77 10.6,65.84 10.08,65.32 10.03,65.32 10.03,64.51 9.96,64.44 9.81,64.44 9.76,64.45 9.23,64.45 9.18,64.44 8.82,64.44 8.44,64.83 8.44,67.11 9.71,68.38 9.71,68.49 9.71,69.65 9.96,69.91 11.99,69.91
+V_UV4 on TOP (solid shape): 76.83,94.82 76.83,92.96 75.52,91.65 75.52,89.69 75.24,89.41 74.28,89.41 74,89.69 74,91.97 75.01,92.98 75.01,93.08 75.03,93.14 75.03,93.19 75.03,93.29 75.03,93.35 75.01,93.4 75.01,93.78 75.1,93.78 75.61,94.09 75.11,94.43 75.01,94.43 75.01,94.7 75.2,94.88 76.77,94.88
+V_UV4 on IN3 (solid shape): outline of 204 points within 74.61,89.34 78.47,95.51
+VDISPLAY_VCC on TOP (solid shape): 201.48,81.72 201.77,81.72 201.78,81.71 202,81.67 202.22,81.71 202.23,81.72 202.37,81.72 202.62,81.46 202.62,80.57 201.73,79.68 200.97,79.68 199.7,78.41 197.92,78.41 197.54,78.8 197.54,79.81 197.8,80.07 198.56,80.07 198.81,80.32 198.81,81.06 198.84,81.13 198.91,81.16 199.24,81.51 198.91,81.87 198.84,81.9 198.81,81.97 198.81,82.1 199.19,82.48 200.72,82.48
+VDISPLAY_VCC on BOTTOM (solid shape): 194.48,76.38 194.88,76.38 194.93,76.38 195.26,76.38 195.38,76.26 195.37,76.13 195.38,76.06 195.38,75.7 195.37,75.63 195.38,75.56 195.38,74.99 194.87,74.48 193.25,74.48 192.89,74.83 192.89,76.2 193.07,76.38 194.43,76.38
+VDISPLAY_VCC on IN1 (solid shape): outline of 231 points within 193.1,74.1 201.35,81.84
+VGA_CORE on TOP (solid shape): outline of 251 points within 53.02,60.13 69.02,69.65
+VGA_CORE on TOP (solid shape): outline of 520 points within 61.02,78.49 71.84,89.77
+VGA_CORE on BOTTOM (solid shape): 63.68,70.54 63.68,66.1 63.94,65.84 65.21,65.84 65.46,66.1 65.46,69.65 65.59,69.78 66.1,69.78 66.35,69.52 66.35,67.49 66.48,67.37 70.67,67.37 70.72,67.31 70.72,66.15 70.29,65.71 68.23,65.71 68.09,65.57 68.09,62.45 68.38,62.16 68.38,60.54 68.76,60.16 69.61,60.16 69.86,59.92 69.86,58.34 69.85,58.33 69.71,58.27 69.61,58.16 69.55,58.12 69.47,58.14 69.17,58.2 68.92,58.02 67.56,56.66 64.85,56.66 64.7,56.81 64.7,59.28 63.94,59.28 63.94,56.81 63.79,56.66 62.79,56.66 62.08,57.37 62.08,60.01 61.84,60.25 57.78,60.25 57.22,59.69 57.22,57.13 57.02,56.93 56.06,56.93 56.06,59.28 55.3,59.28 55.3,56.93 52.27,56.93 52.18,57.01 52.18,61.49 52.26,61.57 53.86,61.57 54.49,62.2 54.49,65.28 55.05,65.84 62.17,65.84 62.46,66.13 62.46,70.76 62.5,70.79 63.43,70.79
+VGA_CORE on IN1 (solid shape): outline of 4005 points within 51.87,60.13 70.92,89.97
+VGA_CORE on IN2 (solid shape): 68.38,63.3 68.38,61.02 68.13,60.76 65.46,60.76 65.21,61.02 63.43,61.02 62.67,60.25 53.51,60.25 53.15,60.61 53.15,61.71 53.18,61.78 53.25,61.81 53.36,61.84 53.46,61.9 53.53,61.92 53.6,61.9 54.19,62.17 53.6,62.44 53.53,62.42 53.46,62.44 53.36,62.5 53.25,62.53 53.18,62.56 53.15,62.63 53.15,62.97 53.87,63.68 68,63.68
+VGA_CORE on VCC: 52.61,60 49.69,62.92 55.53,68.76 55.92,68.76 56.83,69.67 56.83,70.05 57.44,70.67 58.07,70.67 60.89,73.48 60.89,89.59 79.2,89.59 81.46,87.33 81.46,68.36 73.1,60
+VGA_PCIE on TOP (solid shape): outline of 2069 points within 58.94,65.84 78.54,79.07
+VGA_PCIE on IN2 (solid shape): outline of 1060 points within 60.25,69.65 76.13,78.92
+VGA_PCIE on IN3 (solid shape): 65.74,78.81 65.74,78.3 65.38,77.94 65.38,76.31 65.31,76.23 65.31,76.23 64.52,76.23 64.45,76.31 64.45,78.29 64.19,78.54 64.19,79.05 64.34,79.2 65.35,79.2
+VGA_PCIEP on TOP (solid shape): 72.83,65.08 74.35,65.08 74.35,65.59 76.38,65.59 77.02,64.95 77.02,62.29 76.76,62.03 70.34,62.03 70.16,62.21 70.16,65.21 70.54,65.59 72.83,65.59
+VGA_PCIEP on BOTTOM (solid shape): 75.29,65.06 75.66,64.7 75.67,64.7 75.7,64.67 76.23,64.67 76.26,64.7 76.66,64.7 77.02,64.34 77.02,62.29 76.76,62.03 71.78,62.03 71.51,62.3 71.51,64.55 71.57,64.61 72.51,64.61 72.85,64.95 72.85,67.29 72.87,67.31 75.29,67.31
ADPIN on TOP (solid shape): 22.76,121.26 22.76,117.96 22.54,117.73 18.29,117.73 17.66,118.37 17.66,121.25 17.89,121.49 22.54,121.49
ADPIN on BOTTOM (solid shape): 22.66,120.45 22.66,116.64 22.41,116.39 16.06,116.39 15.8,116.64 15.8,117.53 17.71,119.44 17.71,120.32 18.09,120.71 22.41,120.71
AUD_HP_OUT_L_CN on BOTTOM (solid shape): 197.47,29.8 197.47,29.06 197.39,28.99 196.6,28.99 196.37,28.76 195.51,28.76 195.41,28.66 194.49,28.66 194.21,28.38 191.43,28.38 191.24,28.57 191.24,29.62 191.42,29.8 192.46,29.8 192.82,29.44 193.01,29.44 193.02,29.44 193.12,29.4 193.22,29.39 193.87,29.39 193.92,29.44 194.29,29.44 194.6,29.75 195.71,29.75 195.89,29.93 197.34,29.93
AUD_HP_OUT_L_CN on IN3 (solid shape): 197.8,29.93 197.8,28.66 197.57,28.43 195.84,28.43 195.74,28.53 195.74,29.93 195.89,30.08 197.64,30.08
AUD_HP_OUT_R_CN on TOP (solid shape): 197.82,27.97 197.82,26.83 197.59,26.6 197.04,26.6 196.86,26.65 196.67,26.6 195.79,26.6 195.59,26.8 195.59,27.84 195.81,28.07 197.72,28.07
AUD_HP_OUT_R_CN on BOTTOM (solid shape): 194.9,27.87 196.4,27.87 196.68,27.59 197.21,27.59 197.39,27.41 197.39,26.75 197.31,26.67 196.12,26.67 196.04,26.75 194.67,26.75 194.44,26.99 194.43,27 194.27,27.26 193.99,27.36 193.22,27.36 193.12,27.35 193.02,27.31 193.01,27.31 192.84,27.31 192.74,27.21 192.74,27.13 192.39,26.78 191.38,26.78 191.23,26.93 191.23,28.05 191.36,28.17 194.3,28.17 194.32,28.2 194.57,28.2
B+ on TOP (solid shape): 174.17,50.6 174.17,48.95 173.92,48.7 171.63,48.7 171.38,48.95 171.38,50.86 171.89,51.36 173.41,51.36
B+ on TOP (solid shape): 9.26,77.63 12.91,77.63 13.14,77.4 13.14,76.38 12.88,76.13 8.95,76.13 8.69,75.87 7.93,75.87 7.68,76.13 7.68,77.65 7.8,77.78 9.11,77.78
B+ on TOP (solid shape): outline of 812 points within 32.06,19.23 89.72,48.72
B+ on BOTTOM (solid shape): 57.33,26.42 57.33,17.58 56.95,17.2 52,17.2 51.99,17.21 50.67,17.21 50.2,17.68 50.2,26.32 50.48,26.6 57.16,26.6
B+ on BOTTOM (solid shape): 80.7,21.39 80.7,18.6 80.57,18.47 78.92,18.47 78.8,18.6 78.8,21.39 78.92,21.52 80.57,21.52
B+ on BOTTOM (solid shape): 44.76,38.54 44.76,36.5 43.62,35.36 37.9,35.36 37.75,35.51 37.75,36.71 39.38,36.71 39.55,36.89 39.55,37.27 39.3,37.52 37.75,37.52 37.75,38.38 38.28,38.92 44.38,38.92
B+ on BOTTOM (solid shape): outline of 244 points within 88.86,45.9 173.79,61.6
B+ on BOTTOM (solid shape): outline of 1875 points within 11.23,27.21 65.03,121.47
B+ on VCC: 23.15,19.11 21.01,21.24 21.01,31.81 39.7,31.81 44.78,26.73 52.02,26.73 52.25,26.49 52.25,19.11
BATT+ on TOP (solid shape): 26.22,28.5 26.22,21.26 25.96,21.01 23.55,21.01 23.42,21.14 23.42,21.77 22.15,23.04 21.9,23.04 21.52,23.42 21.52,27.55 21.55,27.56 21.68,27.64 21.77,27.77 21.78,27.8 22.24,27.8 22.54,27.66 22.83,27.8 23.26,27.8 23.34,27.76 23.35,27.66 23.55,27.16 24.05,27.35 24.1,27.4 24.17,27.4 24.63,27.59 24.52,28.07 24.48,28.15 24.52,28.23 24.63,28.36 24.67,28.53 24.7,28.6 24.77,28.63 26.09,28.63
BATT+ on BOTTOM (solid shape): 25.46,26.47 25.46,23.68 25.71,23.42 26.73,23.42 26.73,21.77 26.85,21.65 27.36,21.65 27.49,21.77 27.49,23.42 28.12,23.42 28.25,23.3 28.25,20.12 28,19.87 20.63,19.87 20.38,20.12 20.38,25.71 21.39,26.73 25.2,26.73
BATT++ on TOP (solid shape): 19.87,30.66 19.87,23.8 19.23,23.17 16.06,23.17 15.17,24.06 15.17,25.33 14.79,25.71 13.35,25.71 13.05,26.01 13.05,29.56 13.9,30.41 16.69,30.41 17.07,30.79 19.74,30.79
BATT++ on IN1 (solid shape): 19.36,30.54 19.36,24.19 18.47,23.3 16.06,23.3 15.3,24.06 15.3,24.82 14.41,25.71 13.77,25.71 13.65,25.84 13.65,30.15 13.9,30.41 16.69,30.41 17.07,30.79 19.11,30.79
BOOT1 on BOTTOM (solid shape): 58.35,42.09 58.35,40.7 59.37,39.68 59.75,39.68 59.87,39.55 59.87,38.79 59.75,38.66 59.49,38.66 57.33,40.82 57.33,42.09 57.46,42.22 58.22,42.22
BOOT2 on BOTTOM (solid shape): 66,41.97 66,40.29 64.5,38.79 63.58,38.79 63.4,38.61 63.28,38.61 63.2,38.69 63.2,39.58 63.29,39.67 64.03,39.67 64.04,39.65 64.55,39.65 65.16,40.26 65.16,41.05 64.73,41.48 64.73,42.19 64.85,42.32 65.64,42.32
BOOT_1.35V on BOTTOM (solid shape): 89.59,11.1 89.59,10.22 89.46,10.09 87.31,10.09 87.05,10.34 87.05,10.85 86.8,11.1 85.15,11.1 85.15,11.36 89.34,11.36
BOOT_APU1 on TOP (solid shape): 69.32,113.11 69.32,112.3 69.27,112.25 68.64,112.25 68.61,112.27 68.61,112.68 68.43,112.86 66.25,112.86 66.22,112.88 66.22,113.06 66.25,113.09 68.51,113.09 68.59,113.16 69.27,113.16
BOOT_NB1 on TOP (solid shape): 67.27,111.21 67.52,111.21 68.46,110.27 68.46,109.68 68.61,109.53 69.22,109.53 69.3,109.45 69.3,108.46 69.22,108.39 68.64,108.39 68.08,108.94 68.08,110.32 67.44,110.95 67.19,110.95 66.88,111.26 66.27,111.26 66.27,111.46 67.01,111.46
BST_1.35V on BOTTOM (solid shape): 89.59,13.64 89.59,11.74 89.46,11.61 88.58,11.61 88.45,11.74 88.45,13.64 88.58,13.77 89.46,13.77
BST_3V on TOP (solid shape): 71.92,21.82 71.92,20.43 71.91,20.39 71.87,20.38 71.56,20.38 71.56,20.38 71.16,20.38 70.96,20.58 70.96,21.79 71.03,21.86 71.88,21.86
BST_5V on TOP (solid shape): 71.63,15.93 71.67,15.92 71.68,15.88 71.68,15.68 71.43,15.42 71.43,15.42 71.1,15.09 71.1,14.02 71.05,13.97 70.1,13.97 69.94,14.13 69.94,14.63 70.89,15.58 71.22,15.58 71.57,15.93
BST_+1.05VSP on BOTTOM (solid shape): 177.73,51.63 178.5,51.63 178.63,51.5 178.63,50.87 178.55,50.79 177.5,50.79 177.24,50.52 176.31,50.52 176.28,50.55 176.28,51.93 176.5,52.15 177.21,52.15
BST_+1.35VGPUP on BOTTOM (solid shape): 33.84,45.39 33.84,44.63 34.73,43.74 34.73,43.11 34.6,42.98 33.71,42.98 32.95,43.74 32.95,45.39 33.08,45.52 33.71,45.52
CHG on BOTTOM (solid shape): 28.04,29.14 28.23,29.09 28.41,29.14 32.98,29.14 33.09,29.02 33.09,24.73 32.67,24.31 28.5,24.31 28.38,24.44 27.49,24.44 27.49,26.09 27.36,26.22 26.85,26.22 26.73,26.09 26.73,24.44 26.22,24.44 26.22,28.63 26.73,29.14
CHG_B+ on TOP (solid shape): 45.52,34.6 45.52,30.79 45.01,30.28 34.22,30.28 34.09,30.41 34.09,31.55 37.39,34.85 45.27,34.85
CHG_B+ on BOTTOM (solid shape): 44.76,34.85 44.76,33.08 44.13,32.44 38.16,32.44 37.78,32.82 37.78,34.73 38.03,34.98 44.63,34.98
CPU_B+ on TOP (solid shape): 82.23,114.61 82.23,112.07 82.1,111.94 80.57,111.94 80.32,112.2 80.32,114.61 80.57,114.86 81.97,114.86
CPU_B+ on TOP (solid shape): 72.44,108.01 72.44,107.71 72.79,107.35 72.99,107.35 73.29,107.05 73.29,102.8 73.17,102.68 72.13,102.68 71.55,103.26 71.55,104.71 71.08,105.19 71.08,107.9 71.3,108.13 72.32,108.13
CPU_B+ on BOTTOM (solid shape): outline of 510 points within 65.84,102.67 82.23,120.07
CPU_B+ on IN2 (solid shape): outline of 109 points within 70.41,112.07 81.72,116.01
DCIN on TOP (solid shape): 42.09,17.3 42.09,17.07 41.71,16.69 41.71,16.18 41.59,16.06 40.93,16.06 40.6,16.39 39.35,16.39 39.17,16.57 39.17,18.09 39.3,18.22 41.18,18.22
DH_1.35V on TOP (solid shape): 88.91,13.11 88.91,12.4 87.99,11.49 87.18,11.49 87.05,11.61 87.05,12.18 88.06,13.19 88.83,13.19
DH_1.35V on BOTTOM (solid shape): 88.19,12.12 88.19,11.61 88.07,11.49 85.15,11.49 85.15,11.74 86.92,11.74 87.43,12.25 88.07,12.25
DH_CHG on TOP (solid shape): 44,19.61 44,17.71 43.74,17.45 43.11,17.45 42.98,17.58 42.98,19.61 43.08,19.71 43.9,19.71
DH_CHG on TOP (solid shape): 45.5,29.37 45.5,28.1 45.27,27.87 44.63,27.87 44.15,28.35 44.15,29.34 44.38,29.57 45.29,29.57
